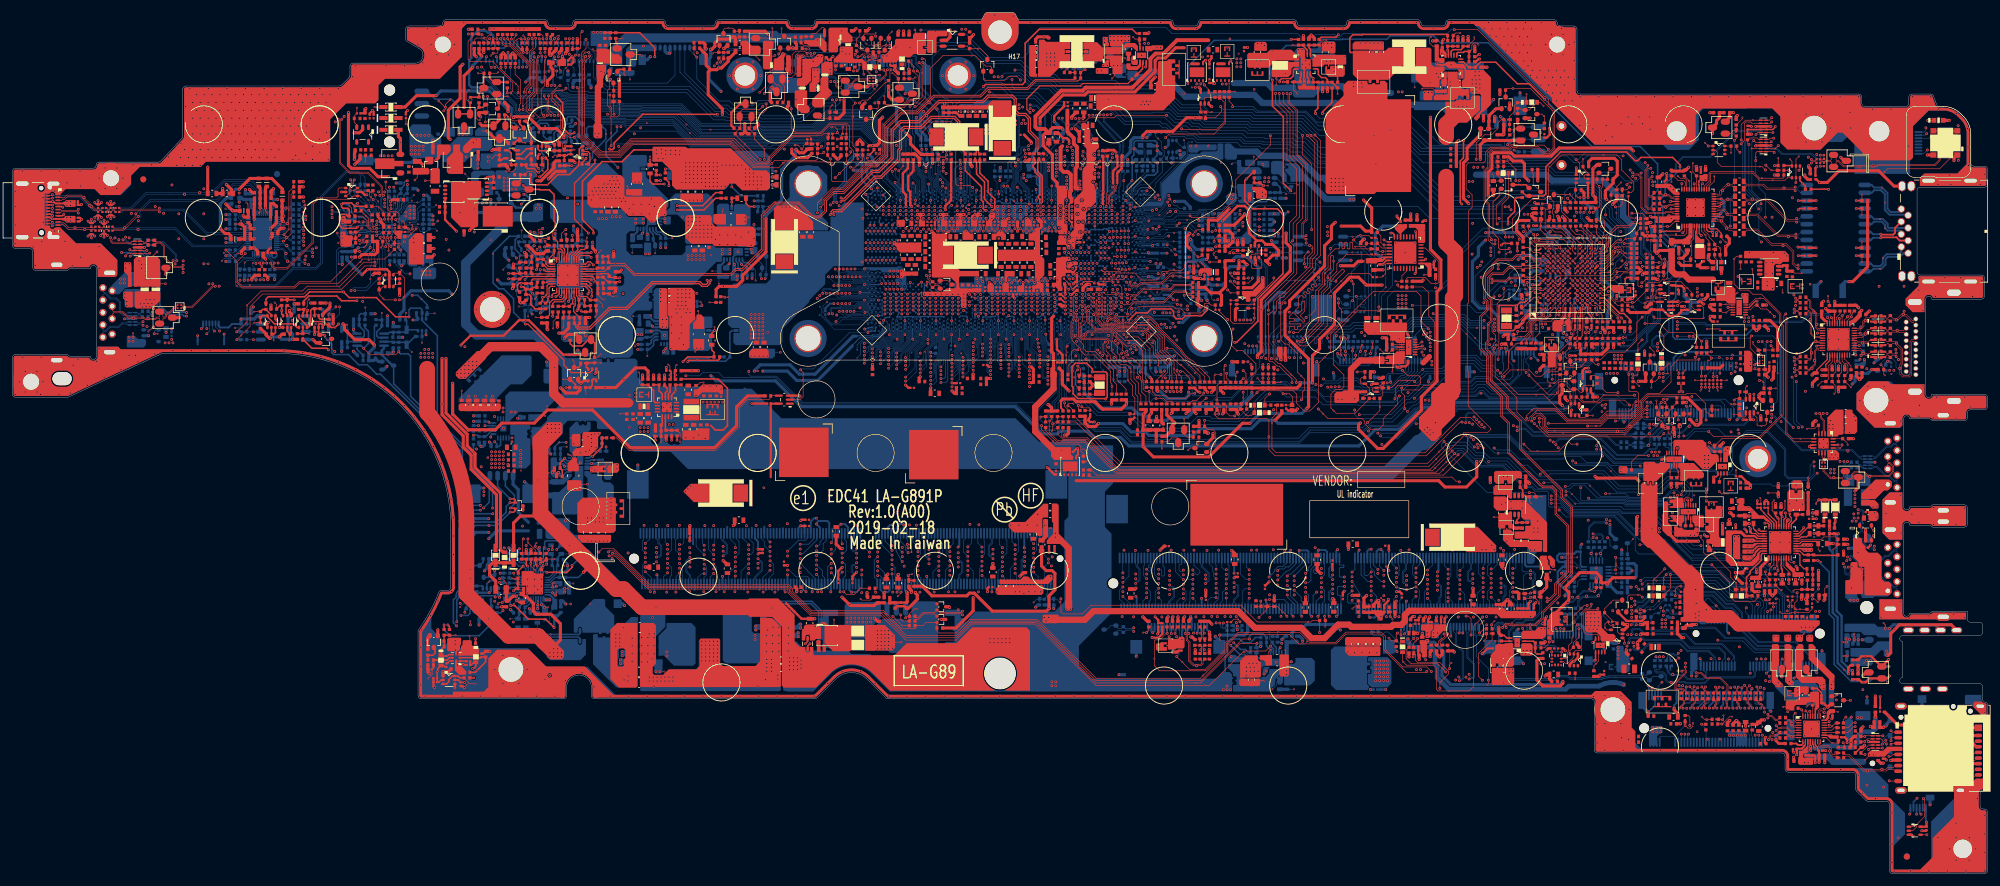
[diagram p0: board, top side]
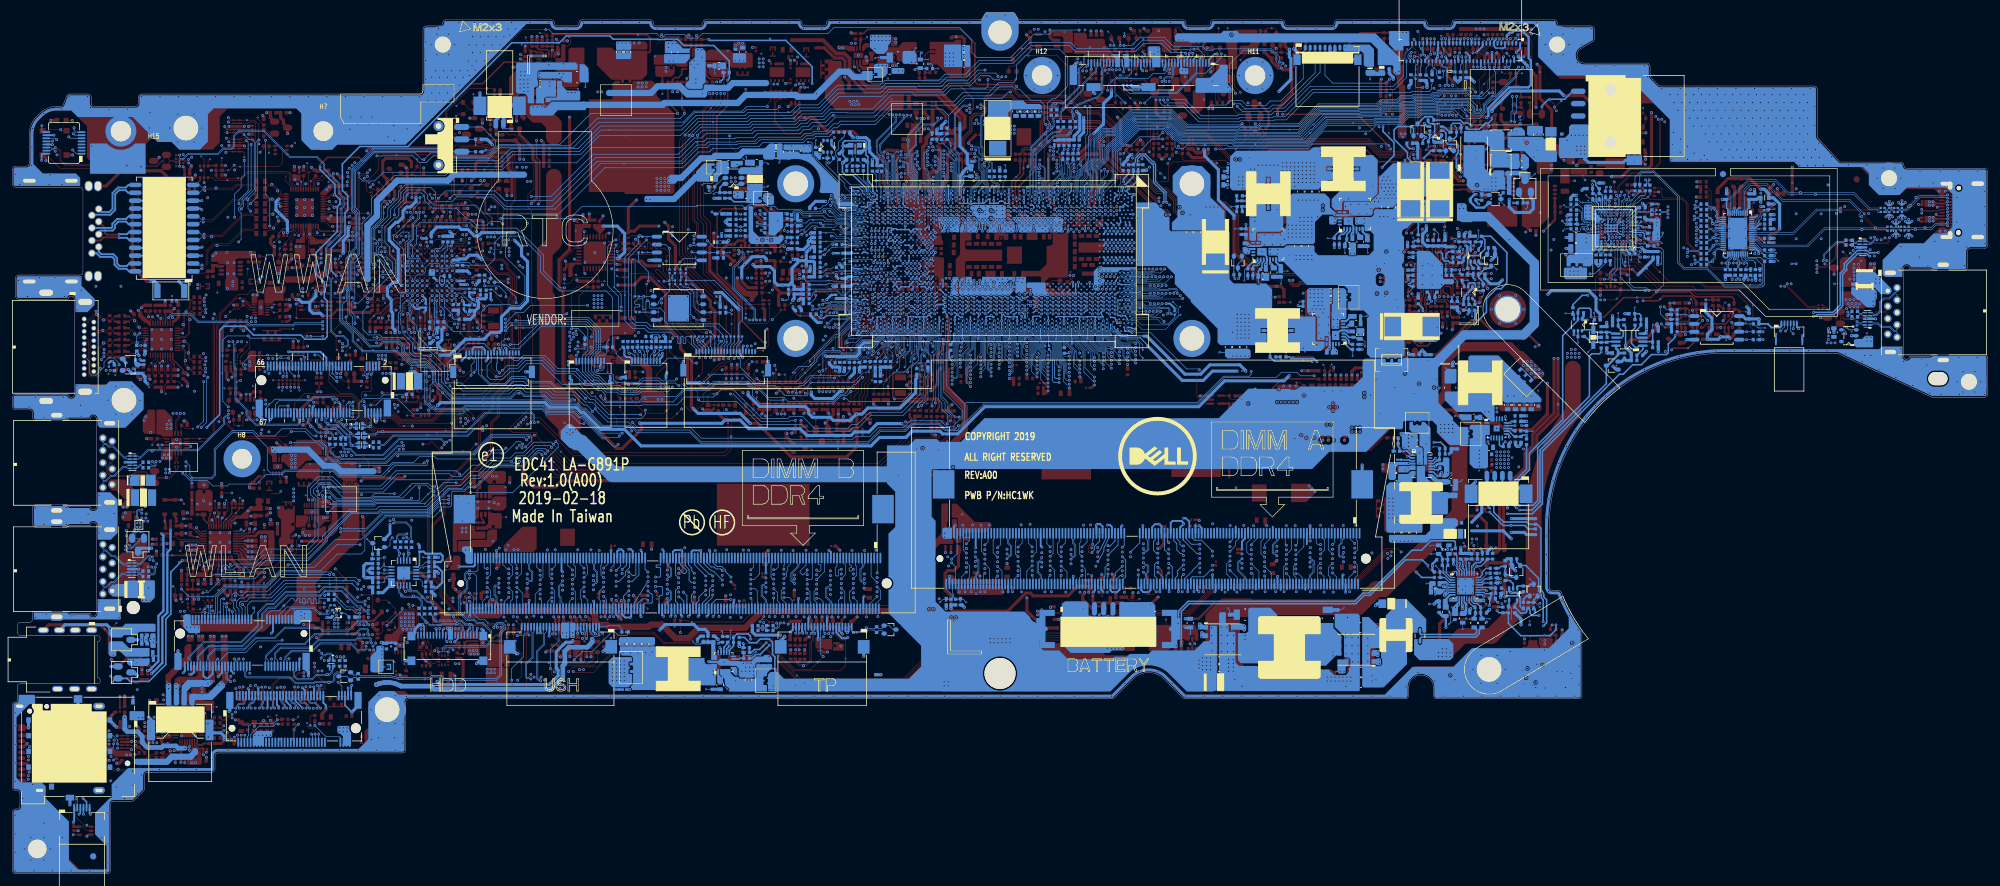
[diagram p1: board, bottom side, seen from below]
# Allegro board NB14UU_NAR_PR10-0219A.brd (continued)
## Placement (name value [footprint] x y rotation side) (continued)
RT73  0_0402_5%  [R0402_0OHM]  61.72 101.81 270 top
RT74  0_0402_5%  [R0402_0OHM]  63.38 104.47 180 top
RT75  0_0402_5%  [R_0402]  66.4 108.19 0 bottom
RT76  10K_0402_1%  [R_0402]  58.05 107.86 180 top
RT81  100K_0402_5%  [R_0402]  55.45 101.96 180 top
RT82  1M_0402_5%  [R_0402]  54.61 103.68 270 top
RT83  0_0402_5%  [R0402_0OHM]  55.44 102.77 90 top
RT84  0_0402_5%  [R_0402]  56.34 107.16 180 top
RT85  0_0402_5%  [R_0402]  58.11 105.56 90 top
RT86  100K_0201_5%  [R_0201]  63.38 103.71 180 top
RT87  0_0402_5%  [R_0402]  58.22 111.3 270 top
RT88  0_0402_5%  [R_0402]  57.46 111.3 270 top
RT89  0_0402_5%  [R0402_0OHM]  56.95 111.28 270 bottom
RT90  0_0402_5%  [R0402_0OHM]  56.19 111.28 270 bottom
RT92  0_0402_5%  [R_0402]  55.3 111.28 270 bottom
RT93  0_0402_5%  [R_0402]  54.54 111.28 270 bottom
RT95  100K_0402_5%  [R_0402]  54.23 107.28 90 bottom
RT96  100K_0402_5%  [R_0402]  54.23 106.54 270 bottom
RT97  0_0402_5%  [R_0402]  67.32 106.5 180 bottom
RT98  0_0402_5%  [R_0402]  66.4 105.74 0 bottom
RT99  0_0402_5%  [R0402_0OHM]  66.4 104.98 0 bottom
RT100  15K_0402_0.1%  [R_0402]  55.32 105.39 180 top
RT101  100K_0402_5%  [R_0402]  59.95 103.59 90 top
RT103  0_0402_5%  [R_0402]  66.4 108.95 0 bottom
RT104  0_0402_5%  [R0402_0OHM]  62.74 108.99 90 bottom
RT105  0_0402_5%  [R0402_0OHM]  63.76 108.99 90 bottom
RT106  10K_0402_5%  [R_0402]  55.32 106.27 180 top
RT107  10K_0402_5%  [R_0402]  59.83 102.18 180 top
RT108  0_0402_5%  [R0402_0OHM]  61.72 109.37 90 bottom
RT109  0_0402_5%  [R0402_0OHM]  60.9 109.37 90 bottom
RT110  0_0402_5%  [R_0402]  66.4 104.21 0 bottom
RT111  100K_0402_5%  [R_0402]  56.14 122.06 180 top
RT120  0_0402_5%  [R0402_0OHM]  22.87 101.61 180 top
RT121  0_0402_5%  [R0402_0OHM]  22.87 102.37 180 top
RT122  0_0402_5%  [R0402_0OHM]  21.95 101.61 0 bottom
RT123  0_0402_5%  [R0402_0OHM]  21.95 102.37 0 bottom
RT130  100K_0402_5%  [R_0402]  40.76 97.62 270 top
RT131  100K_0402_5%  [R_0402]  39.87 97.62 270 top
RT132  0_0402_5%  [R0402_0OHM]  38.29 97.62 270 bottom
RT133  0_0402_5%  [R0402_0OHM]  36.76 97.62 270 bottom
RT135  4.7K_0402_5%  [R_0402]  45.45 111.83 0 top
RT136  4.7K_0402_5%  [R_0402]  45.45 111.01 0 top
RT137  4.7K_0402_5%  [R_0402]  45.45 109.36 0 top
RT138  4.7K_0402_5%  [R_0402]  45.45 110.18 0 top
RT139  4.7K_0402_5%  [R_0402]  36.01 105.74 180 bottom
RT140  4.7K_0402_5%  [R_0402]  36.01 106.5 180 bottom
RT141  4.7K_0402_5%  [R_0402]  36.01 104.98 180 bottom
RT142  4.7K_0402_5%  [R_0402]  36.01 104.21 180 bottom
RT190  2.2_0201_1%  [R_0201]  16.17 103.92 180 top
RT191  2.2_0201_1%  [R_0201]  16.17 104.56 180 top
RT192  2.2_0201_1%  [R_0201]  16.17 103.92 180 bottom
RT193  2.2_0201_1%  [R_0201]  16.17 104.56 180 bottom
RT194  2.2_0201_1%  [R_0201]  17.25 107.58 180 bottom
RT195  2.2_0201_1%  [R_0201]  17.25 106.95 180 bottom
RT196  2.2_0201_1%  [R_0201]  17.25 107.58 180 top
RT197  2.2_0201_1%  [R_0201]  17.25 106.95 180 top
RT219  221K_0201_1%  [R_0201]  12.76 103.93 270 top
RT220  221K_0201_1%  [R_0201]  12.76 104.56 90 top
RT221  221K_0201_1%  [R_0201]  13.84 107.58 90 bottom
RT222  221K_0201_1%  [R_0201]  13.84 106.96 270 bottom
RT246  10K_0402_5%  [R_0402]  35.1 102.69 0 bottom
RT300  4.99K_0402_1%  [R_0402]  36.01 99.88 180 bottom
RT303  0_0402_5%  [R0402_0OHM]  35.43 108.23 270 bottom
RT304  4.7K_0402_5%  [R_0402]  41.59 97.62 270 bottom
RT305  4.7K_0402_5%  [R_0402]  42.35 97.62 270 bottom
RT308  4.7K_0402_5%  [R_0402]  36.01 98.96 180 bottom
RT339  0_0402_5%  [R_0402]  60.84 103.59 90 top
RT377  43K_0402_1%  [R_0402]  59.96 106.53 180 top
RT378  10K_0402_5%  [R_0402]  57.26 102.18 0 top
RT379  10K_0402_5%  [R_0402]  57.26 103.01 0 top
RT380  0_0402_5%  [R0402_0OHM]  35.1 100.8 0 bottom
RT393  100K_0402_5%  [R_0402]  56.95 122.04 90 top
RT397  0_0603_5%  [R_0603]  31.55 109.93 0 top
RT398  0_0603_5%  [R0603_0OHM]  35.36 109.93 180 top
RT399  0_0402_5%  [R_0402]  56.18 116.1 180 top
RT414  2M_0402_5%  [R_0402]  39.05 97.62 270 bottom
RT415  2M_0402_5%  [R_0402]  37.52 97.62 270 bottom
RT420  0_0402_5%  [R_0402]  56.27 116.98 180 top
RT482  0_0402_5%  [R_0402]  54.03 99.63 90 bottom
RT483  0_0402_5%  [R_0402]  53.27 99.63 90 bottom
RT488  221K_0201_1%  [R_0201]  12.76 103.93 270 bottom
RT489  221K_0201_1%  [R_0201]  12.76 104.56 90 bottom
RT490  221K_0201_1%  [R_0201]  13.84 106.96 270 top
RT491  221K_0201_1%  [R_0201]  13.84 107.58 90 top
RV1  4.7K_0402_5%  [R_0402]  136.89 136.22 0 top
RV2  4.7K_0402_5%  [R_0402]  139.96 132.79 180 top
RV3  100K_0402_5%  [R_0402]  154.62 134.26 270 top
RV4  270K_0402_5%  [R_0402]  128.2 135.28 270 top
RV5  47K_0402_5%  [R_0402]  127.39 135.2 180 top
RV6  47K_0402_5%  [R_0402]  116.61 136.15 270 top
RV7  100K_0402_5%  [R_0402]  140.13 131.39 0 top
RV8  10K_0402_5%  [R_0402]  141.52 128.18 270 top
RV10  2.2K_0402_5%  [R_0402]  296.77 90.94 90 top
RV55  20K_0402_5%  [R_0402]  298.97 84.45 90 bottom
RV98  2.2K_0402_5%  [R_0402]  118.98 119.58 0 top
RV99  2.2K_0402_5%  [R_0402]  117.66 119.58 180 top
RV175  4.7K_0402_5%  [R_0402]  294.95 80.52 90 top
RV207  4.7K_0402_5%  [R_0402]  294.95 78.61 90 top
RV208  4.7K_0402_5%  [R_0402]  293.51 90.89 90 top
RV209  4.7K_0402_5%  [R_0402]  295.99 90.93 90 top
RV300  4.7K_0402_5%  [R_0402]  292.92 78.61 90 top
RV302  4.7K_0402_5%  [R_0402]  297.62 84.45 90 bottom
RV303  4.02K_0402_1%  [R_0402]  296.98 81.43 270 top
RV304  4.7K_0402_5%  [R_0402]  293.94 78.61 90 top
RV305  4.7K_0402_5%  [R_0402]  293.94 80.52 90 top
RV307  4.7K_0402_5%  [R_0402]  295.97 80.52 90 top
RV311  100K_0402_5%  [R_0402]  111.01 133.42 180 top
RV319  1K_0402_5%  [R_0402]  111.01 134.31 180 top
RV323  0_0402_5%  [R0402_0OHM]  114.87 131.82 90 top
RV324  0_0402_5%  [R_0402]  114.1 131.82 90 top
RV326  100K_0402_5%  [R_0402]  115.63 131.82 90 top
RV400  0_0402_5%  [R0402_0OHM]  117.44 136.15 270 top
RV623  100K_0402_5%  [R_0402]  144.76 132.23 270 top
RV624  1M_0402_5%  [R_0402]  97.14 125.68 0 top
RV625  47K_0402_5%  [R_0402]  99.7 129.99 180 top
RV626  200K_0402_5%  [R_0402]  95.69 135.91 270 top
RV627  10K_0402_5%  [R_0402]  97.47 135 90 top
RV628  0_0402_5%  [R0402_0OHM]  97.14 124.79 0 top
RV629  200K_0402_5%  [R_0402]  144.84 128.46 90 top
RV630  47K_0402_5%  [R_0402]  140.85 124.61 180 top
RV631  10K_0402_5%  [R_0402]  143.11 128.47 0 top
RV654  150_0402_5%  [R_0402]  303.33 86.26 270 top
RV683  150_0402_5%  [R_0402]  303.33 90.19 270 top
RV684  150_0402_5%  [R_0402]  303.33 87.25 90 top
RV685  150_0402_5%  [R_0402]  303.33 83.44 90 top
RV686  5.6_0402_1%  [R_0402]  300.91 89.13 0 top
RV687  5.6_0402_1%  [R_0402]  300.91 90.15 0 top
RV688  5.6_0402_1%  [R_0402]  300.91 88.24 0 top
RV689  5.6_0402_1%  [R_0402]  300.91 87.23 0 top
RV690  5.6_0402_1%  [R_0402]  300.91 85.32 0 top
RV691  5.6_0402_1%  [R_0402]  300.91 86.34 0 top
RV692  8.2_0402_1%  [R_0402]  300.91 84.43 0 top
RV693  8.2_0402_1%  [R_0402]  300.91 83.42 0 top
RV732  0_0603_5%  [R_0603]  118.2 132.9 180 top
RV733  0_0603_5%  [R0603_0OHM]  118.2 134.17 180 top
RV734  4.7K_0402_5%  [R_0402]  295.97 78.61 90 top
RV735  2.2K_0402_5%  [R_0402]  297.53 90.94 90 top
RV736  10K_0402_5%  [R_0402]  302.27 81.48 180 top
RV737  100K_0402_5%  [R_0402]  295.22 90.93 90 top
RV802  1M_0402_5%  [R_0402]  127.58 133.4 180 top
RZ8  2.2K_0402_5%  [R_0402]  231.82 36 90 top
RZ9  2.2K_0402_5%  [R_0402]  229.16 36.03 90 top
RZ10  100K_0402_5%  [R_0402]  225.59 35.66 90 top
RZ18  4.7K_0402_5%  [R_0402]  193.35 35.58 270 top
RZ19  4.7K_0402_5%  [R_0402]  191.07 35.58 270 top
RZ20  2.2K_0402_5%  [R_0402]  199.53 39.32 180 bottom
RZ21  2.2K_0402_5%  [R_0402]  199.53 40.08 180 bottom
RZ22  0_0402_5%  [R_0402]  192.59 34.67 90 top
RZ23  0_0402_5%  [R_0402]  191.83 34.67 90 top
RZ25  150_0402_5%  [R_0402]  245.47 113.8 0 top
RZ26  0_0402_5%  [R0402_0OHM]  197.11 39.32 180 bottom
RZ28  330_0402_5%  [R_0402]  243.89 109.27 90 top
RZ29  0_0402_5%  [R0402_0OHM]  197.11 40.08 180 bottom
RZ32  1K_0402_1%  [R_0402]  277.6 117.59 0 top
RZ38  100K_0402_5%  [R_0402]  268.36 72.08 180 top
RZ40  100K_0402_5%  [R_0402]  282.71 91.89 180 top
RZ43  10K_0402_5%  [R_0402]  261.54 82.5 180 top
RZ56  0_0201_5%  [R0201_0OHM]  283.84 44.28 270 top
RZ58  49.9_0201_1%  [R_0201]  219.76 96.4 0 top
RZ59  49.9_0201_1%  [R_0201]  219.57 100.09 0 top
RZ60  49.9_0201_1%  [R_0201]  219.57 102.75 0 top
RZ61  0_0402_5%  [R0402_0OHM]  219.57 100.98 0 top
RZ63  33_0402_5%  [R_0402]  219.57 101.86 0 top
RZ64  0_0402_5%  [R0402_0OHM]  226.56 86.45 270 bottom
RZ69  10K_0402_5%  [R_0402]  219.57 103.64 0 top
RZ70  0_0402_5%  [R_0402]  268.12 75.37 180 top
RZ71  0_0402_5%  [R_0402]  265.55 75.37 0 top
RZ76  0_0402_5%  [R_0402]  269.15 79.25 90 top
RZ77  0_0402_5%  [R_0402]  269.91 79.25 90 top
RZ78  0_0201_5%  [R_0201]  286.76 44.78 270 top
RZ79  0_0201_5%  [R_0201]  287.52 44.78 270 top
RZ80  0_0201_5%  [R_0201]  290.7 43.65 270 top
RZ87  0_0402_5%  [R0402_0OHM]  219.69 39.06 0 bottom
RZ89  0_0402_5%  [R_0402]  225.86 105.62 270 top
RZ96  0.01_1206_1%  [R_1206-NPM]  264.6 64.4 270 top
RZ102  0.01_1206_1%  [R_1206-NPM]  239.83 34.95 270 top
RZ112  0_0402_5%  [R0402_0OHM]  225.23 94.83 90 top
RZ114  0_0402_5%  [R0402_0OHM]  226.35 35.66 90 top
RZ116  10K_0402_5%  [R_0402]  191.83 40.79 270 top
RZ117  10K_0402_5%  [R_0402]  192.59 40.79 270 top
RZ119  0_0402_5%  [R_0402]  168.57 66.25 90 top
RZ120  0_0402_5%  [R0402_0OHM]  173.92 65.24 180 top
RZ128  0_0201_5%  [R_0201]  272.83 79.74 270 top
RZ129  0_0201_5%  [R_0201]  274.1 79.74 270 top
RZ130  0_0201_5%  [R_0201]  275.37 79.74 270 top
RZ132  10K_0402_5%  [R_0402]  263.83 79.58 0 top
RZ133  100K_0402_5%  [R_0402]  263.63 83.83 0 top
RZ148  0_0402_5%  [R_0402]  246.9 36.48 180 top
RZ151  0_0603_5%  [R_0603]  193.23 133.17 0 top
RZ320  0_0402_5%  [R_0402]  194.24 125.47 90 top
RZ326  0_0402_5%  [R_0402]  255.41 77.48 180 bottom
RZ334  51_0402_5%  [R_0402]  297.67 20.39 0 top
RZ335  15K_0402_5%  [R_0402]  298.59 23.06 180 top
RZ345  0_0402_5%  [R0402_0OHM]  274.95 69.11 270 top
RZ346  0_0402_5%  [R0402_0OHM]  191.83 37.82 270 top
RZ347  0_0402_5%  [R0402_0OHM]  192.59 37.82 270 top
RZ350  0_0201_5%  [R0201_0OHM]  292.6 115.54 90 top
RZ351  0_0201_5%  [R0201_0OHM]  292.6 114.92 270 top
RZ361  470_0402_1%  [R_0402]  243.09 101.86 180 top
RZ362  10K_0402_5%  [R_0402]  226.12 95.74 270 top
RZ372  0_0201_5%  [R_0201]  274.74 79.74 270 top
RZ373  0_0201_5%  [R_0201]  276.01 79.74 270 top
RZ374  0_0201_5%  [R_0201]  273.47 79.74 270 top
RZ377  100K_0402_5%  [R_0402]  263.76 41.48 0 bottom
RZ379  20K_0402_5%  [R_0402]  269.77 76.13 180 top
RZ380  0_0402_5%  [R0402_0OHM]  278.44 120.14 270 top
RZ388  0_0402_5%  [R0402_0OHM]  132.98 123.07 180 top
RZ400  10K_0402_5%  [R_0402]  264.02 94.31 0 top
RZ401  1K_0402_5%  [R_0402]  264.02 95.07 0 top
RZ518  100K_0402_5%  [R_0402]  270.95 73.4 90 top
RZ603  10K_0402_5%  [R_0402]  261.53 65.28 180 top
RZ752  10K_0402_5%  [R_0402]  289.87 42.73 90 top
RZ827  0_0201_5%  [R_0201]  261.04 110.09 270 top
RZ1381  22_0402_5%  [R_0402]  267.98 44.27 180 bottom
RZ1383  22_0402_5%  [R_0402]  267.98 45.16 180 bottom
RZ1385  0_0201_5%  [R0201_0OHM]  267.06 43.38 0 bottom
RZ1388  0_0201_5%  [R_0201]  292.01 115.45 180 top
RZ1389  0_0201_5%  [R_0201]  292.01 114.88 180 top
RZ1390  0_0402_5%  [R_0402]  276.46 122.98 0 top
RZ1391  0_0402_5%  [R_0402]  275.73 122.98 180 top
RZ1392  100K_0402_5%  [R_0402]  280.26 118.6 90 top
RZ1393  0_0402_5%  [R0402_0OHM]  274.51 74.95 270 top
RZ1394  0_0402_5%  [R0402_0OHM]  279.96 77.86 180 top
RZ1395  0_0402_5%  [R0402_0OHM]  278.99 74.23 90 top
RZ1396  0_0402_5%  [R_0402]  278.99 75.88 90 top
RZ1397  100K_0402_5%  [R_0402]  282.41 73.35 0 top
RZ1398  0_0402_5%  [R0402_0OHM]  283.83 78.43 180 top
RZ1399  10K_0402_5%  [R_0402]  283.83 77.67 180 top
RZ1400  100K_0402_5%  [R_0402]  272.91 81.73 0 top
RZ1401  0_0402_5%  [R0402_0OHM]  283.03 81.48 180 top
RZ1402  0_0402_5%  [R0402_0OHM]  282.11 84.62 0 top
RZ1403  0_0402_5%  [R_0402]  284.55 82.79 270 top
RZ1404  0_0402_5%  [R_0402]  285.14 83.7 90 top
RZ1405  10K_0402_5%  [R_0402]  284.37 83.7 90 top
RZ1406  2.2K_0402_5%  [R_0402]  282.11 80.66 0 top
RZ1407  0_0402_5%  [R_0402]  224.44 94.83 90 top
RZ1408  0_0402_5%  [R0402_0OHM]  218.01 98.97 0 top
RZ1409  0_0402_5%  [R_0402]  224.98 105.62 270 top
RZ1410  0_0402_5%  [R_0402]  229.88 96.78 180 top
RZ1411  0_0402_5%  [R0402_0OHM]  239.02 38.81 180 top
RZ1413  330K_0402_5%  [R_0402]  240.88 114.32 180 top
RZ1414  0_0402_5%  [R_0402]  239.02 39.57 180 top
RZ1415  0_0402_5%  [R0402_0OHM]  239.96 115.09 0 top
RZ1416  0_0402_5%  [R_0402]  196.53 125.47 90 top
RZ1417  0_0402_5%  [R_0402]  195.77 125.47 90 top
RZ1418  0_0402_5%  [R_0402]  173.92 64.42 180 top
RZ1419  0_0402_5%  [R_0402]  172.99 67.46 270 top
RZ1420  0_0402_5%  [R0402_0OHM]  192.72 122.17 90 top
RZ1422  100K_0402_5%  [R_0402]  191.96 123.09 270 top
RZ1423  0_0402_5%  [R0402_0OHM]  195 125.47 90 top
RZ1450  0_0402_5%  [R_0402]  273.68 84.14 90 top
RZ1471  0_0201_5%  [R_0201]  258.42 40.71 180 top
RZ1472  100K_0402_5%  [R_0402]  260.1 40.46 180 top
RZ1473  0_0402_5%  [R_0402]  223.53 36.7 90 top
RZ1474  100K_0402_5%  [R_0402]  257.18 42.17 180 top
RZ1475  0_0201_5%  [R0201_0OHM]  196.82 40.65 180 top
RZ1476  0_0402_5%  [R0402_0OHM]  265.23 70.32 270 bottom
RZ1477  0_0402_5%  [R0402_0OHM]  266 70.32 270 bottom
RZ1480  0_0402_5%  [R_0402]  272.03 84.14 90 top
RZ1481  0_0402_5%  [R_0402]  272.85 84.14 90 top
RZ1482  1M_0402_5%  [R_0402]  240.88 115.85 180 top
RZ1483  20K_0402_5%  [R_0402]  269.77 76.91 180 top
RZ1484  0_0603_5%  [R0603_0OHM]  130.84 126.95 180 top
RZ1485  0_0603_5%  [R0603_0OHM]  127.59 126.26 90 top
RZ1486  0_0603_5%  [R_0603-NPM]  131.22 128.37 90 top
SW1  SS3-CMFTQR9_3P  [SW_SS3-CMFTQR9_3P]  246.47 120.68 270 bottom
SW3  SKRBAAE010_4P  [SW_SKRBAAE010_4P]  314.15 116.15 180 top
T1  PAD~D  [TPC12]  154.11 106.25 0 top
T2  PAD~D  [TPC12]  154 107.63 0 top
T12  PAD~D  [TPC12]  175.13 92.66 0 top
T16  PAD~D  [TPC12]  136.46 84.66 180 bottom
T17  PAD~D  [TPC12]  136.44 83.35 180 bottom
T18  PAD~D  [TPC12]  184.81 84.62 180 bottom
T19  PAD~D  [TPC12]  190.24 82.75 180 bottom
T20  PAD~D  [TPC12]  168.75 85.63 180 bottom
T21  PAD~D  [TPC12]  171.04 99.91 270 top
T50  PAD~D  [TPC12]  143.01 44.84 270 top
T51  PAD~D  [TPC12]  145.21 51.97 270 top
T54  PAD~D  [TPC12]  221.07 44.54 0 top
T55  PAD~D  [TPC12]  221.86 49.67 0 top
T88  PAD~D  [TPC12]  271.05 113.43 0 top
T89  PAD~D  [TPC12]  269.01 112.76 0 top
T315  PAD~D  [TPC12]  274.89 112.72 0 top
T341  PAD~D  [TPC12]  248.47 95.45 180 bottom
T348  PAD~D  [TPC12]  253.26 95.43 180 bottom
T350  PAD~D  [TPC12]  145.25 84.19 180 bottom
T351  PAD~D  [TPC12]  146.36 83.51 180 bottom
T353  PAD~D  [TPC12]  146.83 93.89 0 top
T354  PAD~D  [TPC12]  147.77 91.98 0 top
T355  PAD~D  [TPC12]  158.68 114.5 180 bottom
T360  PAD~D  [TPC12]  190.55 118.23 180 bottom
T361  PAD~D  [TPC12]  170.59 85.68 180 bottom
T363  PAD~D  [TPC12]  170.47 84.25 180 bottom
T364  PAD~D  [TPC12]  130.41 91.63 180 bottom
T365  PAD~D  [TPC12]  130.36 90.31 180 bottom
T368  PAD~D  [TPC12]  147.57 95.06 0 top
T369  PAD~D  [TPC12]  146.26 95.12 0 top
T371  PAD~D  [TPC12]  159.49 112.57 0 top
T372  PAD~D  [TPC12]  164.13 95.67 0 top
T373  PAD~D  [TPC12]  159.3 110.35 0 top
T374  PAD~D  [TPC12]  162.36 95.65 0 top
T375  PAD~D  [TPC12]  175.76 84.99 180 bottom
T376  PAD~D  [TPC12]  174.44 85.41 180 bottom
T377  PAD~D  [TPC12]  173.79 84.11 180 bottom
T378  PAD~D  [TPC12]  178.06 95.15 0 top
T379  PAD~D  [TPC12]  177.6 93.93 0 top
T380  PAD~D  [TPC12]  173.02 85.22 180 bottom
T381  PAD~D  [TPC12]  185.1 82.12 0 top
T383  PAD~D  [TPC12]  183.5 84.58 180 bottom
T384  PAD~D  [TPC12]  183.74 82.12 0 top
T385  PAD~D  [TPC12]  174.94 81.85 180 bottom
T388  PAD~D  [TPC12]  176.32 93.91 0 top
T389  PAD~D  [TPC12]  178.1 91.3 0 top
T395  PAD~D  [TPC12]  174 82.73 180 bottom
T396  PAD~D  [TPC12]  175.08 83.42 180 bottom
T397  PAD~D  [TPC12]  176.14 82.66 180 bottom
T398  PAD~D  [TPC12]  176.18 81.36 180 bottom
T399  PAD~D  [TPC12]  186.47 104.07 180 bottom
T400  PAD~D  [TPC12]  185.35 103.32 180 bottom
T401  PAD~D  [TPC12]  177.44 96.51 0 top
T402  PAD~D  [TPC12]  175.94 97.52 0 top
T406  PAD~D  [TPC12]  184.97 99.26 180 bottom
T407  PAD~D  [TPC12]  177.92 99.77 0 top
T415  PAD~D  [TPC12]  176.2 95.72 0 top
T416  PAD~D  [TPC12]  178.05 97.84 0 top
T418  PAD~D  [TPC12]  302.38 113.42 0 top
T419  PAD~D  [TPC12]  154.91 93.16 0 top
T421  PAD~D  [TPC12]  280.93 117.19 0 top
T422  PAD~D  [TPC12]  284.75 117.18 0 top
T423  PAD~D  [TPC12]  193.02 80.97 180 bottom
TL1  MHPC_NS692417  [MHPC_NS692417_24P]  289.84 97.34 90 bottom
UA1  -  [ALC3204-CG_MQFN40_5X5]  283.73 50.99 90 top
UC1  WHL-U42_BGA1528  [WHL-U42_BGA_1528P-T]  138.21 110.31 270 bottom
UC5  -  [W25Q256JVEIQ_WSON8_8X6]  215.46 93.29 270 bottom
UC6  -  [W25Q128JVSIQ_SO8]  214.95 102.94 270 bottom
UC7  MC74VHC1G08DFT2G SC70  [TC7SH08FU_SSOP5]  220.36 77.87 90 top
UC9  MC74VHC1G32DFT2G_SC70-5~D  [MC74VHC1G32DFT2G_SC70-5]  198.69 92.02 270 top
UD1  -  [74AUP1G07GW_TSSOP5]  125.58 75.96 90 top
UE1  MEC5105_WFBGA169_11X11  [MEC5105_WFBGA_169P]  246.85 91.41 90 top
UE3  MC74VHC1G08DFT2G SC70  [TC7SH08FU_SSOP5]  272.41 91.12 90 top
UE4  -  [74AUP1G07GW_TSSOP5]  267.91 91.12 90 top
UE5  MC74VHC1G08DFT2G SC70  [TC7SH08FU_SSOP5]  253.66 78.24 0 top
UI1  -  [SY6288D20AAC_SOT23-5]  21.21 85.99 90 bottom
UI2  -  [SY6288D20AAC_SOT23-5]  298.38 53.87 0 top
UI3  -  [SLGC55544CVTR_TQFN16_3X3]  293.29 71.09 180 top
UL1  WGI219LM-SLKJ3-A0_QFN48_6X6~D  [WGI219LM-SLKJ3-A0_QFN48_6X6]  269.66 104.69 90 top
UN7  PI3EQX6741STZDEX_TQFN20_4X4  [PI3EQX6741STZDEX_TQFN20_4X4-S]  254.84 50.56 270 bottom
UR1  RTS5242-GR_QFN32_4X4  [RTS5242-GR_QFN32_4X4-S]  288.56 24.78 0 top
UT5  SN1804044ZBHR_NFBGA96  [TPS65982_BGA_96P]  57.83 101.8 0 bottom
UT6  GD25Q80CSIGR_SO8  [W25Q80DVSSIG_SO8]  47.37 90.12 270 bottom
UT7  AP2112K-3.3TRG1_SOT23-5  [AP2112K-3P3TRG1_SOT23-5]  57.52 120.64 180 top
UT8  AP2204R-5.0TRG1_SOT89-3  [AP2204R-5P0TRG1_SOT89-3]  62.67 113.25 90 top
UT9  -  [PS8802QFN52GTRA1_QFN52_6P5X4P5]  38.81 106.75 270 bottom
UV2  -  [AP2330W-7_SC59-3]  298.83 82.27 270 bottom
UV21  -  [PS8407ATQFN40GTR2A1_TQFN40_5X5]  292.4 88.16 270 top
UV24  -  [G524B1T11U_SOT23-5]  150.32 135.64 270 top
UZ3  EM5209VF_SON14_2X3  [TPS22966DPUR_SON14_2X3-S]  226.57 83.9 90 top
UZ5  EM5209VF_SON14_2X3  [TPS22966DPUR_SON14_2X3-S]  271.9 59.52 180 top
UZ8  AOZ1336_DFN8_2X2  [AOZ1336_DFN8_2X2-S]  276.97 66.9 180 top
UZ10  MC74VHC1G08DFT2G SC70  [TC7SH08FU_SSOP5]  306.32 7.58 270 top
UZ12  ST33HTPH2032AHC1_VQFN32_5X5  [ST33HTPH2E32AHB4_VQFN32_5X5]  227.52 98.61 180 top
UZ19  EM5201V DFN3X3  [TPS22961DNYR_WSON8]  190.37 128.18 0 top
UZ21  EM5201V DFN3X3  [TPS22961DNYR_WSON8]  194.56 128.18 0 top
UZ23  AOZ1336_DFN8_2X2  [AOZ1336_DFN8_2X2-S]  244.16 36.57 90 top
UZ27  EM5201V DFN3X3  [TPS22961DNYR_WSON8]  169.88 64.46 0 top
UZ35  MC74VHC1G08DFT2G SC70  [TC7SH08FU_SSOP5]  191.94 124.47 0 top
UZ41  MC74VHC1G08DFT2G SC70  [TC7SH08FU_SSOP5]  266.19 95.08 270 top
UZ43  EM5209VF_SON14_2X3  [TPS22966DPUR_SON14_2X3-S]  279.95 90.31 90 top
UZ47  EM5209VF_DFN14_3X2  [TPS22966DPUR_SON14_2X3]  269.61 68 180 top
UZ51  -  [SN74LVC1G3157DCKR_SC70-6]  281.29 76.68 180 top
UZ52  SN74AUP1T97YZPR_DSBGA6~D  [SN74AUP1T97YZPR_DSBGA_6P]  282.21 83.44 0 top
UZ53  AOZ1336_DFN8_2X2  [AOZ1336_DFN8_2X2-S]  257.22 38 180 top
UZ54  MC74VHC1G32DFT2G_SC70-5~D  [MC74VHC1G32DFT2G_SC70-5]  259.14 38.75 90 top
YC1  24MHZ_12PF_8Y24000034  [Y_8Y24000034_4P]  182.24 117.72 0 bottom
YC2  32.768KHZ_12.5PF_9H03200042  [Y_9H03200042_2P]  175.61 77.71 90 top
YE1  32.768KHZ_9PF_X1A000141000200  [Y_X1A000141000200_2P]  241.33 88.52 90 top
YL1  25MHZ_20PF_XRCGB25M000F2P18R0  [Y_XRCGB25M000F2P18R0_4P]  276.04 98.83 180 top

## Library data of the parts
CA1-CA4 CA9 CA10 CA12 CA13 CA19 CA22-CA25 CA27 CA28 CA31 CA33 CA35 CA41 CA43-CA48 CA51-CA61 CA69 CA73 CA74 CC1479 CD76 CD77 CN95 CZ125-CZ128 = CAP NP: room: CODEC
CA5 CA6 CA62 CA72 CN78 CZ322 = CAP NP: room: CAMERA
CA7 CV1-CV6 CV11 CV13-CV17 CV632-CV634 CV651 CV652 CZ202 CZ203 CZ207 = CAP NP: room: LCD
CA8 CA29 CA76-CA78 CC24 CC25 CC67-CC70 CC76 CC78 CC80 CC83 CC85 CC86 CC96 CC100 CC102-CC104 CC195 CC1455-CC1462 CC1465 CC1467-CC1471 CC1477 CC1478 CC1480 CE14 CE30 CE31 CE63 CI51 CN89 CR15 CR22 CT22 CT74 CT326-CT329 CT634-CT637 CZ19 CZ25 CZ100 CZ102 CZ105 CZ218 = CAP NP
CA63-CA68 CE59 CE60 CI43-CI48 CL29 CL30 CR25-CR28 CT99-CT102 CT189 CT190 CV18-CV25 CZ3 CZ41 CZ57 CZ58 CZ62 CZ63 CZ83-CZ89 CZ317 CZ320 = CAP NP: room: TBT
CA75 CC1481 CV12 CV31 CV757 CZ12 CZ13 CZ27-CZ36 = CAP NP: room: WLAN
CC9 CC10 CC316 CC318-CC320 CC1452 CC1453 CC1476 CE57 CV54 CV55 = CAP NP: room: SPI ROM
CC21-CC23 CC26-CC29 CC31-CC42 CC45 CC46 CC51 CC52 CC65 CC66 CC71 CC73 CC75 CC98 CC234-CC237 CC266 CC279 CC280 CC300-CC305 CC322 CC331-CC333 CC430 CC1454 CC1463 CC1464 CE61 CN92 CV755 CZ17 CZ318 CZ319 = CAP NP: room: CPU
CC72 CD1-CD16 CD18-CD29 CD31-CD48 CD50-CD63 CD66 CD69-CD72 = CAP NP: room: MEMORY
CC77 CC95 = CAP NP: room: SOC
CC84 CZ50-CZ56 CZ75 = CAP NP: room: TPM
CC93 = CAP NP: room: EDP
CC196 CN60 CZ64 CZ66-CZ69 CZ71-CZ73 = CAP NP: room: USH
CC269 CC288 CC299 CC306-CC308 CC326 CC334 = CAP NP: room: CPU XDP
CC340 CZ200 CZ220 = P_CAP NP: room: CAMERA
CD17 CD49 = CAP WP: room: MEMORY
CD73 CD74 CI29 CI30 CV756 CZ10 CZ11 CZ18 CZ21 CZ23 CZ26 CZ198 CZ204-CZ206 CZ315 CZ316 = CAP NP: room: WWAN
CD75 CE3 CE4 CE10-CE13 CE15-CE29 CE32 CE35-CE40 CE46 CE47 CE52-CE54 CE62 CE64-CE69 CN87 CN93 CZ80 CZ81 = CAP NP: room: KBC
CE8 = CAP NP: room: SIO
CI1 CI8 CI14 = CAP WP
CI3 CI10-CI12 CI27 CI28 = CAP NP: room: USB3
CI4-CI7 = CAP NP: room: USB2
CI13 CI16 CI17 CI19 CI31 CI33 CI34 = CAP NP: room: USB1
CI32 CI103 CI104 = CAP WP: room: USB1
CI50 CT625-CT629 CZ24 = CAP NP: room: GPU
CI52 CL1-CL14 CL16-CL22 CL28 = CAP NP: room: LAN
CMOS1 = OPEN: User Part Number: PART#; room: PCH
CN1-CN17 CZ129 CZ130 = CAP NP: room: HDD
CN61-CN72 CN77 CN79-CN82 CN84 CN86 CN91 = CAP NP: room: SATA EXPRESS
CN75 CN88 CN90 CZ311-CZ314 PC103 PC133-PC140 PC143 PC145 PC146 PC202 PC203 PC206-PC214 PC216-PC219 PC221-PC227 PC315 PC318 PC319 PC330 PC420 PC425-PC428 PC530 PC666 PC689 PC690 PC692 PC693 PC738 PC739 PC1096-PC1100 PC1146 PC1147 PC1166-PC1168 PC1170 PC3008-PC3011 = P_CAP NP: room: P_1.2V
CN94 CZ321 PC3 PC102 PC111 PC112 PC114 PC119 PC125 PC126 PC128 PC141 PC142 PC204 PC205 PC302 PC304 PC312-PC314 PC317 PC320 PC333 PC337 PC410 PC507 PC508 PC514 PC517 PC604 PC622 PC655 PC662 PC663 PC667 PC670 PC671 PC678 PC691 PC719 PC725 PC726 PC736 PC743-PC750 PC752 PC753 PC755 = P_CAP NP: room: CHARGER
CR1-CR7 CR11-CR14 CR17-CR21 = CAP NP: room: RTS5242
CT44-CT48 CT610-CT612 CT614-CT618 CV26 CV27 CV300-CV314 CV653 = CAP NP: room: HDMI
CT70 CT82 CT92 = P_CAP NP: room: PD
CT71-CT73 CT75-CT78 CT80 CT81 CT83-CT91 CT93 CT94 = CAP NP: room: PD
CT103-CT119 CT122 = CAP NP: room: PS8740
CV635 = P_CAP NP: room: TOUCH
CZ20 = CAP WP: room: WWAN
CZ37-CZ40 = CAP NP: room: SIM
CZ82 = CAP NP: room: RSMRST
CZ90-CZ92 CZ309 = CAP NP: room: KBTP
CZ93 = CAP NP: room: LED
CZ101 = CAP NP: room: +1.0V_VCCST
CZ106 = CAP NP: room: +1.0V_VCCSTG
CZ109 CZ110 CZ122 CZ310 = CAP NP: room: UZ2
CZ112-CZ115 CZ216 CZ217 = CAP NP: room: UZ3
CZ116-CZ119 CZ124 = CAP NP: room: UZ4
CZ120 CZ121 CZ197 CZ305 CZ306 = CAP NP: room: UZ8
CZ303 = CAP NP: room: +VCC_SFR_OC
DA1-DA3 DA6 DA7 = L03ESDL5V0CC3-2_SOT23-3: room: CODEC
DA4 DA5 DT1-DT3 = P_1N4148WS-7-F_SOD323-2: room: PD
DA8 DC1 DC2 DE2 = RB751S40T1G_SOD523-2: room: KBC
DC4 = P_RB521CM-30T2R_SOD923-2
DE1 = P_BZV55-B5V1_SOD80C2
DE22 = P_CEST523NC5VB_SOT-523-3
DI1 DI4 DI6 DT39-DT42 DZ13 = AZ1045-04F_DFN2510P10E-10-9
DI2 DI3 DV14 DZ10 DZ11 = AZC199-02SPR7G_SOT23-3: room: USB3
DI5 = AZC199-02SPR7G_SOT23-3: room: USB1
DT4 = L30ESD24VC3-2_SOT23-3
DT5 DT6 DT9 DT10 DT13 DT14 DT17 DT18 = ESD8011MUT5G_X3DFN2-2
DV1-DV3 DZ9 = BAT54CW_SOT323-3~D: room: LCD
DV11 = RB751S40T1G_SOD523-2
DV12 = RB751S40T1G_SOD523-2: room: GPU
DV13 = L03ESDL5V0CC3-2_SOT23-3
DZ1 DZ2 = RB751S40T1G_SOD523-2: room: WLAN
DZ5 DZ6 = RB751S40T1_SOD523-2~D: room: WWAN
DZ8 = RB751S40T1_SOD523-2~D: room: USH
DZ12 = RB751S40T1G_SOD523-2: room: PD
FD1-FD4 = FIDUCIAL MARK: room: LED
FV1 FZ1-FZ5 = 1A_65V_T0603FF1000TM
H1-H4 H7 H8 H11-H18 H20-H22 H25-H30 = HOLE: room: LED
JAPS1 = ACES_7: room: CPU
JDB1 = JXT_FP241AH-006GAAM_2: room: PD
JDEG1 = JXT_FP241AH-010GAAM_1
JDIMM1 JDIMM2 = LOTES_ADDR0206-P001A_0
JEDP1 = ACES_50398-04041-001: room: LCD
JESPI = JXT_FP241AH-010GAAM_0
JFAN1 = ACES_50271-0040N-001: room: KBC
JFPBTN1 = FOX_QT510166-L010-7H
JHDMI1 = YUQIU_HD074-F19M1BR-C
JHP1 = SINGA_2SJ3095-136111F~D
JIRTS1 = ACES_6
JKBTP1 = HRS_TF31-20S-0P5SH-800_0
JLED1 = HRS_TF31-6S-0P5SH_0
JLOM1 = SINGA_2RJ3081-1C8211F
JNGFF1 = LOTES_APCI0128-P005A_3
JNGFF2 = BELLW_7
JNGFF3 = LOTES_APCI0079-P005A_1
JRTC1 = TYCO_0
JSATA1 = FOX_GS12206-10100-7H
JSD1 = T-SOL_2
JSIM1 = JAE_SF51S006V4DR1000Q_0
JSPI1 = ACES_50506-02041-P01
JSPK1 = ACES_50278-00401-001: room: CODEC
JTAG1 = OPEN: User Part Number: PART#; room: KBC
JUSB1-JUSB3 = C-K_26230A-8K1A-02~D
JUSBC1 = JAE_DX07SD24JJ2R1300~D_1
JUSH1 = HRS_TF31C-26S-0P5SH-800
JXDP1 = JXT_FP270H-061G1AM
LA5-LA16 = L: room: CODEC
LC1-LC3 LC6-LC12 = L: room: SOC
LC4 LC5 LI12 LI13 LZ3 LZ4 = L
LED3 = LTW-C193DC-C_WHITE: room: LED
LGA1 = LNG2DMTR_LGA12_2: room: HDD
LI3 LI4 LI7 LZ1 = DLM0NSN900HY2D_4P
LI8 LI9 = MCM1012B900F06BP_4P
LI16 LI17 = HCM1012GH900BP_4P
LL1 = L: room: LAN
LT11 = L: room: CRT
LT601-LT605 = L: room: GPU
LV1 = L: room: LCD
LV3 LV6 LV9 LV12 = DLW21SN900HQ2L_0805_4P~D: room: HDMI
PBATT1 = P_DEREN_1
PC1 PC5 PC7 PC11 PC316 PC335 PC336 PC338 PC339 PC802 PC807 PC808 PC810 PC865 PC1171 PC1200 PC1201 = P_CAP NP: room: P_DCIN
PC4 PC6 PC13 PC350 PC603 PC605 PC611 PC618 PC620 PC626 PC627 PC632 PC635 PC637-PC639 PC641 PC642 PC644 PC645 PC647 PC649-PC653 PC659-PC661 PC668 PC669 PC676 PC677 PC685 PC697 PC727 PC740 PC754 PC803 PC814 PC3005 = P_CAP NP: room: CPU_CORE
PC8 PC10 PC12 PC104-PC110 PC113 PC117 PC118 PC120-PC124 PC127 PC129-PC132 PC161-PC164 PC301 PC305-PC311 PC334 PC360 PC401-PC404 PC406-PC409 PC411-PC419 PC421 PC424 PC501 PC504 PC509-PC511 PC513 PC515 PC516 PC601 PC602 PC608 PC612-PC614 PC616 PC617 PC619 PC621 PC624 PC625 PC628-PC631 PC633 PC636 PC640 PC643 PC646 PC654 PC656-PC658 PC664 PC665 PC672-PC675 PC682-PC684 PC686-PC688 PC694 PC707 PC751 PC761 PC811 PC812 PC1000-PC1009 PC1011-PC1020 PC1031-PC1090 PC1101-PC1123 PC1131-PC1141 PC1151-PC1161 PC1169 PC1202 = P_CAP NP
PC100 PC115 PC116 PC303 PC331 PC332 = P_CAP NP: room: 3_5V
PC200 PC201 PC700 PC701 PC737 PC756 PC760 PC800 PC801 PC804 PC805 PC813 PC3002 = P_CAP NP: room: Charger
PC228 PC702-PC704 PC706 PC708-PC710 PC716 PC717 PC720 PC721 PC728-PC735 PC741 PC742 PC3001 PC3003 PC3004 = P_CAP NP: room: PWR_CHARGER
PC503 PC505 PC506 = P_CAP NP: room: 1.8V
PC606 PC607 PC715 PC1091-PC1094 PC1142 PC1143 PC1627 = P_CAP WP
PC806 PC809 = P_CAP NP: room: P_USBA
PD1 PD2 PD4 = TVNST52302AB0_SOT523-3
PD3 = P_BAS40-05W_SC70-3~D
PD5 PD801 = P_PDS5100H-13_POWERDI5-3~D: room: P_Selector
PD700 PD702 = P_SDMK0340L-7-F_SOD323-2~D
PD701 = P_DFLS160-7_POWERDI123-2
PD704 PD3001 PD3002 = RB520SM-30T2R_EMD2-2
PD705 PD800 PD803 PD3000 = BAT54CW_SOT323~D
PD802 = P_SDMK0340L-7-F_SOD323-2~D: room: P_selector
PH601-PH603 PH605 = P_SL2
PH604 = P_10KB_0603_5%_ERTJ1VR103J: room: CPU_CORE
PJP1 = PAD-OPEN: room: +1.0V_VCCST
PJP2 = PAD-OPEN: room: +1.0V_VCCSTG
PJP3 = PAD-OPEN: room: +1.0V_MPHYGT
PJP8 = PAD-OPEN: room: PD
PJP12 = PAD-OPEN: room: LCD
PJP14 = PAD-OPEN: room: RTS5242
PJP15 PJP16 PJP18 = PAD-OPEN: room: CODEC
PJP17 PJP40 PJP41 = PAD-OPEN: room: UZ4
PJP19 PJP36 PJP37 = PAD-OPEN: room: UZ2
PJP20 PJP22 = PAD-OPEN: room: KBC
PJP31 = PAD-OPEN: room: SATA EXPRESS
PJP32-PJP34 = PAD-OPEN: room: HDD
PJP35 = PAD-OPEN: room: KBTP
PJP38 PJP39 = PAD-OPEN: room: UZ3
PJP42 = PAD-OPEN: room: UZ8
PJP100 PJP101 PJP202 PJP301 PJP602 = VCCPAD: room: DDR_VTT_0.75V
PJP102 PJP103 PJP401 PJP402 = P_JUMP_43X118: room: 1.5V
PJP200 = P_JUMP_43X118: room: P_1.2V
PJP201 = P_JUMP_43X39: room: P_1.2V
PJP302 = P_JUMP_43X118
PJP403 PJP404 PJP501-PJP506 PJP603 = PAD-OPEN: room: VGA_CORE
PJP601 PJP700 = PAD-OPEN: room: Charger
PJPDC1 = P_CVILU_CI0805M1HRC-NH_4
PL1-PL4 = P_L: room: P_DCIN
PL100 PL201 PL301 PL402 PL404-PL406 PL501 PL502 PL700 PL701 PL800 PL801 = P_L
PL101 = P_L: room: VDDCI
PL602 = P_L: room: CPU_CORE
PL610 PL612 PL613 = P_L_4P
PL614 = P_0.47UH_MMD05CZR47M_12A_20%
PQ1 PQ10 PQ802 PQ804 PQ806 PQ813 PQ3000 = P_DMN65D8LDW-7_SOT363-6
PQ2 = P_FDV301N_NL_SOT23-3~D: room: P_DCIN
PQ3 = MMST3904-7-F_SOT323~D: room: P_DCIN
PQ4 = P_AON7409_DFN8-5_2
PQ5 PQ11 PQ803 PQ805 = NTR4502PT1G_SOT23-3: room: P_Charger
PQ6-PQ8 PQ12 PQ13 PQ807 PQ812 PQ814 = DMN65D8LW-7_SOT323-3
PQ9 = P_AON7409_DFN8-5_3
PQ614 = P_AON7934_DFN3X3A-8-10_0
PQ700 PQ701 = P_AOE6930_DFN5X6E8-10_0
PQ702 = P_AON7409_DFN8-5_1
PQ703 = P_RHU002N06_SOT323-3~D
PQ800 = P_AON7409_DFN8-5_6
PQ801 = P_AON7409_DFN8-5_5
PQ808-PQ811 = P_DMN66D0LDW-7_SOT363-6: room: P_USBB
PR1-PR8 PR11 PR13 PR14 PR16 PR24 PR27 PR43 PR668 PR675 PR804 PR819 PR821 PR823 PR856 PR860 PR862 = P_R: room: P_DCIN
PR9 PR114 PR308 PR312 PR412 PR422 PR512 PR745 PR746 PR3001 PR3006 RC25-RC27 RC29 RC30 RC33 RC35 RC87 RC137 RC432 RC433 RC520 RC521 RC570-RC576 RC730 RC734 RE300 RE362 RE543 RE546 RE551 RI27-RI30 RI47 RI48 RN100 RN101 RN131 RT86 RT190-RT197 RT219-RT222 RT397 RT399 RT414 RT415 RT420 RT482 RT483 RT488-RT491 RV732 RV802 RZ22 RZ23 RZ58-RZ60 RZ70 RZ89 RZ128-RZ130 RZ334 RZ372-RZ374 RZ1407 RZ1409 RZ1410 = R
PR10 PR15 PR17 PR28 PR33 PR45 PR705 PR706 PR801 PR802 PR806-PR808 PR810-PR813 PR822 PR824 PR825 PR828 PR830 PR833 PR838 PR839 PR846 PR851 PR852 PR855 PR865 = P_R: room: P_Selector
PR12 PR18 PR31 PR32 PR202 PR204 PR206 PR209 PR212 PR313 PR669 PR739 PR744 = P_R: room: P_1.2V
PR19 PR20 PR22 PR25 PR41 PR42 PR44 PR46 PR47 PR49 PR100 PR104 PR105 PR111 PR119 PR120 PR203 PR208 PR210 PR304 PR314 PR315 PR402 PR423 PR427 PR429 PR504 PR513 PR602 PR603 PR606 PR614 PR616 PR620 PR625 PR659 PR662 PR664 PR671 PR679 PR687 PR692 PR709 PR713 PR715 PR719 PR721 PR722 PR727 PR729 PR731 PR736 PR737 PR740 PR741 PR743 PR814 PR816 PR818 PR820 PR826 PR827 PR829 PR834 PR836 PR840 PR844 PR853 PR854 PR857-PR859 PR861 PR866 RA3 RC153 RD10 RD26 RL8 RR20 RT398 RV733 = P_R-SHORT
PR38-PR40 PR102 PR108 PR116 PR117 PR205 PR207 PR302 PR303 PR306 PR311 PR403 PR404 PR406-PR408 PR410 PR411 PR421 PR425 PR428 PR430 PR509-PR511 PR514-PR516 PR601 PR604 PR605 PR608 PR610 PR611 PR613 PR617 PR618 PR621 PR622 PR626 PR629-PR631 PR635 PR639 PR640 PR644 PR651 PR678 PR680 PR688 PR691 PR693 PR701-PR703 PR712 PR717 PR718 PR720 PR725 PR726 PR728 PR733-PR735 PR800 PR809 PR815 PR817 PR831 PR832 PR835 PR842 PR843 PR870 PR892 PR893 PR3002-PR3005 PR3007-PR3013 RC752 RE79 RZ335 RZ1413 RZ1482 = P_R
PR103 = P_R: room: 3_5V
PR106 PR112 = P_R: room: 1.5V
PR107 PR113 PR307 PR310 = P_R: room: 1P5V
PR405 PR409 PR501 PR502 PR505 PR506 = P_R: room: 1.8V
PR413-PR420 PR424 PR708 PR710 PR716 PR724 PR805 = P_R: room: Charger
PR612 PR619 PR623 PR624 PR627 PR628 PR632 PR633 PR636 PR638 PR641-PR643 PR645-PR650 PR652 PR653 PR656-PR658 PR660 PR661 PR663 PR665-PR667 PR670 PR672-PR674 PR676 PR677 = P_R: room: CPU_CORE
PR615 PR634 = P_R: room: GPU_CORE
PR700 PR711 = P_R~D: room: CHARGER
PR704 PR707 PR714 PR723 PR738 = P_R: room: CHARGER
PR803 = P_R: room: P_selector
PR841 PR845 = P_R: room: P_USBB
PU2 = AP2204R-5.0TRG1_SOT89-3
PU3 PU801 = TC7SH08FU_SSOP5~D: room: PCH
PU100 = P_SY8288BRAC_QFN20_0
PU102 = P_SY8288CRAC_QFN20_1
PU200 = P_SY8210AQVC_QFN19_4X3: room: P_1.2V
PU301 = P_SY8288RAC_QFN20_1
PU401 PU402 = P_TLV62130ARGTR_QFN16_0
PU501 = P_RT8097ALGE_SOT23-6
PU502 = P_AP7361C-FGE-7_U-DFN3030-8_1
PU503 = P_AP7361C-FGE-7_U-DFN3030-8_2
PU602 = P_ISL62883CHRTZ-T_TQFN40_1: room: GPU_CORE
PU610 = P_FDMF3035_PQFN31_5
PU612 = P_FDMF3035_PQFN31_7
PU613 = P_FDMF3035_PQFN31_6
PU614 = P_ISL95808HRZ-TS2378_DFN8_2X2
PU700 = P_ISL88738HRTZ-T_TQFN32_4X4
PU701 = SN74AHC1G08DCKR_SC70-5
PU800 = P_LM393DGKR_VSSOP8
PU3000 = P_AZV3002RL-7_U-FLGA8_1P65X1P65
QC2 QC4 QE2 QE21 QL1 QN1 QT10 QZ7 = DMN66D0LDW-7_SOT363-6~D: room: CPU
QC6 QE11 QE12 QE17 QE20 QN6 QZ15 QZ19 QZ22 = L2N7002WT1G_SC-70-3
QC7 QE15 QZ1 QZ18 = LP2301ALT1G_SOT23-3: room: CAMERA
QC8 = L2N7002WT1G_SC-70-3: room: SIO
QE3-QE7 = MMST3904-7-F_SOT323-3: room: KBC
QR1 = L2N7002WT1G_SC-70-3: room: RTS5242
QT1 = DMN66D0LDW-7_SOT363-6~D: room: PD
QV1 = P_AO6405_TSOP6_0: room: LCD
QV2 = L2N7002WT1G_SC-70-3: room: LCD
QV7 = L2N7002WT1G_SC-70-3: room: TOUCH
QV8 = LP2301ALT1G_SOT23-3: room: TOUCH
QV18 QV20 = MMBT3906H_SOT23-3
QV19 QV21 = MMBT3904WT1G_SC70-3~D: room: KBC
QZ3 = LMUN5111T1G_SC70-3
QZ17 = PJE138K_SOT523-3
QZ21 = LMBT3904WT1G_SC70-3
RA5-RA9 RA12-RA14 RA17 RA18 RA44 RA45 RA51 RA52 RA59 RA60 RC59 = R: room: CODEC
RA35-RA37 RA48 RA53 RC28 RC32 RC121 RC128 RC157 RC159 RC165 RC215 RC216 RC221 RC239 RC240 RC243 RC297 RC328 RC337 RC403 RC404 RC425 RC426 RC429 RC430 RC440 RC442 RC445 RC526-RC528 RC531 RC532 RC559 RC566 RC631 RC632 RC727 RC735-RC739 RC845 RC848 RC850-RC853 RC864 RD5 RD7 RD9 RD12 RD21 RD22 RD25 RE30 RE32 RE59 RE90 RE275 RE290 RE318 RE361 RE548 RE552 RE560 RE565 RE600-RE603 RE608 RE703 RL3 RL7 RL20 RL34 RN77 RN78 RN81 RN82 RN99 RN125-RN129 RN227 RR5-RR10 RT54-RT60 RT63 RT69 RT70 RT73 RT74 RT83 RT89 RT90 RT99 RT104 RT105 RT108 RT109 RT120-RT123 RV323 RV400 RV628 RZ26 RZ29 RZ56 RZ61 RZ64 RZ87 RZ112 RZ114 RZ120 RZ345-RZ347 RZ350 RZ351 RZ380 RZ388 RZ1385 RZ1393-RZ1395 RZ1398 RZ1401 RZ1402 RZ1408 RZ1411 RZ1415 RZ1420 RZ1423 RZ1475-RZ1477 RZ1484 RZ1485 = R-SHORT
RA50 RA54 RA57 RA58 = R: room: UZ8
RC2 RC5-RC8 RC10-RC12 RC14 RC15 RC20 RC46-RC51 RC53 RC56-RC58 RC60 RC65-RC69 RC71-RC73 RC75 RC77 RC78 RC82 RC84 RC86 RC92 RC93 RC95 RC96 RC101 RC104 RC106-RC109 RC116 RC125 RC130 RC150 RC151 RC154-RC156 RC160 RC161 RC163 RC164 RC166 RC176 RC178 RC183 RC187 RC189 RC214 RC218-RC220 RC222 RC229-RC234 RC237 RC244 RC248 RC266 RC277-RC279 RC288 RC292 RC298 RC317-RC319 RC323 RC344 RC345 RC347 RC348 RC362 RC363 RC366-RC369 RC397 RC402 RC420 RC436-RC439 RC441 RC443 RC444 RC446 RC451 RC452 RC454 RC502-RC507 RC515 RC518 RC519 RC522 RC523 RC525 RC530 RC536 RC537 RC555 RC558 RC560-RC562 RC567-RC569 RC624 RC640 RC724-RC726 RC731-RC733 RC747-RC749 RC751 RC756-RC761 RC763-RC766 RC829-RC834 RC836-RC844 RC847 RC849 RC862 RC865 RC866 RC868 RE349 RE716-RE718 RL70 RV7 RV55 RV98 RV99 RV311 RV319 RV324 RV326 RV623-RV627 RV629-RV631 RV737 RZ20 RZ21 RZ132 RZ133 RZ603 RZ752 RZ1392 RZ1400 RZ1405 RZ1406 = R: room: CPU
RC19 RC289 RC299 RC564 RC565 RC728 RC729 RE350 RE539 = R: room: SPI ROM
RC24 RC302 RC660 RC867 RZ78-RZ80 RZ1388 RZ1389 RZ1471 = R: room: AR
RC31 RT50-RT53 RT64-RT68 RT71 RT72 RT75 RT76 RT81 RT82 RT84 RT85 RT87 RT88 RT92 RT93 RT95-RT98 RT100 RT101 RT103 RT106 RT107 RT110 RT111 RT377-RT379 RT393 = R: room: PD
RC61 RC62 RC94 = R: room: PD_1
RC63 RC158 RC400 RC401 RC743-RC745 RE31 RE33 RE37 RE43 RE48 RE51 RE55-RE58 RE60 RE63-RE65 RE67-RE75 RE77 RE86 RE280 RE292 RE302-RE304 RE306 RE312-RE314 RE342 RE343 RE526 RE536 RE706-RE709 RE714 RE715 RE719 RE720 RE826 RE828 RE829 RZ43 RZ827 = R: room: KBC
RC120 RC405-RC407 RC409-RC419 = R: room: CPU_XDP
RC122-RC124 RC126 RC129 RC131-RC136 RC138 RC139 RC217 RC235 RC236 RC241 = R: room: CPU XDP
RC173 RC175 RC422 = R: room: Other
RC431 RC710 RC711 RE8 RE10-RE12 RE20 RE21 RE25 RE26 RE35 RE83-RE85 RE91-RE94 RE274 RE288 RE340 RE365 RE505 RE507 RE508 RE532 RE541 RE547 RE549 RE550 RE561 RE605 RE606 RE704 RE721-RE730 RE821 RE822 RE825 = R: room: SIO
RC448 = P_R: room: CPU
RC723 = R: room: AUDIO_CODEC
RD4 RD6 RD8 RD11 RD14-RD20 RD23 RD24 RD27-RD31 RZ32 RZ361 = R: room: MEMORY
RI13 RI14 = R: room: USB1
RL1 RL2 RL4-RL6 RL9 RL11-RL19 RL29 RL71-RL78 RV654 RV683-RV685 = R: room: LAN
RN1-RN21 RN226 RZ102 RZ148 = R: room: HDD
RN37 = R: room: SATA EXPRESS
RR3 RR4 RR19 = R: room: RTS5242
RT130 RT131 RT135-RT142 RT246 RT300 RT304 RT305 RT308 = R: room: PS8740
RT132 RT133 RT303 RT380 = R-SHORT: room: PS8740
RT339 RZ1486 = R: room: TBT
RV1-RV5 = R: room: LCD
RV6 RV8 = R: room: TOUCH
RV10 RV175 RV207-RV209 RV300 RV302-RV305 RV307 RV686-RV693 RV734-RV736 = R: room: HDMI
RZ8-RZ10 RZ1414 RZ1473 = R: room: USH
RZ18 RZ19 RZ116 RZ117 = R: room: KBTP
RZ25 RZ28 = R: room: LED
RZ38 RZ71 RZ1422 = R: room: UZ2
RZ40 RZ1472 RZ1474 = R: room: UZ4
RZ63 RZ69 RZ362 RZ377 RZ379 RZ400 RZ518 RZ1397 RZ1483 = R: room: TPM
RZ76 RZ77 RZ326 RZ1396 RZ1403 RZ1404 RZ1450 RZ1480 RZ1481 = R: room: WWAN
RZ96 = R: room: UZ3
RZ119 RZ1416-RZ1419 = R: room: +VCC_SFR_OC
RZ151 RZ320 = R: room: +1.0V_VCCSTG
RZ401 = R: room: GPU
RZ1381 RZ1383 = R: room: WLAN
RZ1390 RZ1391 = R: room: CAMERA
RZ1399 = R: room: EC
SW1 = SS3-CMFTQR9_3P: room: CPU
SW3 = SKRBAAE010_4P: room: LED
T1 T2 = PAD_5: room: CPU
T12 T341 T348 T375-T379 T383-T385 T388 T389 T395-T402 T406 T407 T415 T416 T418 T421 T422 = PAD_0: room: CPU
T16-T21 T355 T360 T361 T363-T365 T368 T369 T371-T374 T380 T381 T419 T423 = PAD_8: room: CPU
T50 T51 T54 T55 = PAD_9: room: MEMORY
T88 T89 T315 = PAD_0: room: LAN
T350 T351 T353 T354 = PAD_6: room: CPU
TL1 = 350uH_IH-115-F~D: room: LAN
UA1 = ALC3204-CG_MQFN40_5X5
UC1 = WHL-U42_BGA1528
UC5 = W25Q256JVEIQ_WSON8_8X6
UC6 = W25Q128JVSIQ_SO8
UC7 UE3 UE5 = TC7SH08FU_SSOP5~D: room: CPU
UC9 UZ54 = MC74VHC1G32DFT2G_SC70-5~D
UD1 = 74AUP1G07GW_TSSOP5: room: MEMORY
UE1 = MEC5105_WFBGA169_0
UE4 = 74AUP1G07GW_TSSOP5
UI1 = SY6288D20AAC_SOT23-5: room: USB2
UI2 = SY6288D20AAC_SOT23-5: room: USB3
UI3 = SLGC55544CVTR_TQFN16_3X3: room: USB1
UL1 = WGI219LM-SLKJ3-A0_QFN48_6X6~D
UN7 = PI3EQX6741STZDEX_TQFN20_1: room: HDD
UR1 = RTS5242-GR_QFN32_4X4: room: RTS5242
UT5 = TPS65982_BGA96_1: room: PD
UT6 = W25Q80DVSSIG_SO8: room: PD
UT7 = AP2112K-3.3TRG1_SOT23-5: room: PD
UT8 = AP2204R-5.0TRG1_SOT89-3: room: PD
UT9 = PS8802QFN52GTRA1_QFN52_0
UV2 = AP2330W-7_SC59-3: room: HDMI
UV21 = PS8407ATQFN40GTR2A1_TQFN40_0
UV24 = G524B1T11U_SOT23-5: room: LCD
UZ3 = TPS22966DPUR_SON14_1: room: UZ3
UZ5 = TPS22966DPUR_SON14_0: room: CODEC
UZ8 UZ53 = AOZ1336_DFN8_1: room: UZ8
UZ10 = TC7SH08FU_SSOP5~D: room: LED
UZ12 = ST33HTPH2E32AHB4_VQFN32_5X5
UZ19 = TPS22961DNYR_WSON8: room: +1.0V_VCCSTG
UZ21 = TPS22961DNYR_WSON8: room: +1.0V_VCCST
UZ23 = AOZ1336_DFN8_0: room: HDD
UZ27 = TPS22961DNYR_WSON8: room: +VCC_SFR_OC
UZ35 = TC7SH08FU_SSOP5~D: room: +1.0V_VCCSTG
UZ41 = TC7SH08FU_SSOP5~D: room: RSMRST
UZ43 = TPS22966DPUR_SON14_1: room: UZ2
UZ47 = TPS22966DPUR_SON14_1: room: UZ4
UZ51 = SN74LVC1G3157DCKR_SC70-6
UZ52 = SN74AUP1T97YZPR_DSBGA6~D
YC1 = 24MHZ_12PF_8Y24000034
YC2 = 32.768KHZ_12.5PF_9H03220008: room: CPU
YE1 = 32.768KHZ_9PF_X1A000141000200
YL1 = 25MHZ_20PF_XRCGB25M000F2P18R0_0

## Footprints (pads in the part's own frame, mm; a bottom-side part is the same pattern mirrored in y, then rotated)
1N4148WS-7-F_SOD323-2
  rect 1.346x0.66 smd: 1(0,0) 2(2.4,0)
1N4148WS-L_SOD323-2
  rect 0.559x0.813 smd: 1(0,0) 2(2.3,0)
3A_Z120_0603_2P
  rect 0.559x1.041 smd: 1(0,0) 2(1.3,0)
9A_Z80_1812_2P-NPM
  rect 1.803x3.404 smd: 1(0,0) 2(3.8,0)
74AUP1G07GW_TSSOP5
  oval 0.381x1.346 smd: 1(0,0) 2(0.65,0) 3(1.3,0) 4(1.3,1.79) 5(0,1.79)
ACES_50208-01001-P03_10P
  oval 0.508x0.991 smd: 1(0,0) 2(0.8,0) 3(1.6,0) 4(2.4,0) 5(3.2,0) 6(4,0) 7(4.8,0) 8(5.6,0) 9(6.4,0) 10(7.2,0)
  rect 1.194x1.702 smd: 11(-1.3,-1.95) 12(8.5,-1.95)
ACES_50271-0020N-001_2P
  oval 0.787x1.6 smd: 1(0,0) 2(1.25,0)
  rect 2.108x2.997 smd: 3(3.8,-2.9) 4(-2.55,-2.9)
ACES_50271-0040N-001_4P
  oval 0.787x1.6 smd: 1(0,0) 2(-1.25,0) 3(-2.5,0) 4(-3.75,0)
  rect 2.108x2.997 smd: 5(2.55,-2.9) 6(-6.3,-2.9)
ACES_50278-00401-001_4P
  oval 0.787x1.905 smd: 1(0,0) 2(1.25,0) 3(2.5,0) 4(3.75,0)
  rect 1.295x3.353 smd: 5(-2.85,-4.925) 6(6.6,-4.925)
ACES_50398-04041-001_40P
  oval 0.254x1.295 smd: 1(0,0) 2(0.5,0) 3(1,0) 4(1.5,0) 5(2,0) 6(2.5,0) 7(3,0) 8(3.5,0) 9(4,0) 10(4.5,0) 11(5,0) 12(5.5,0) 13(6,0) 14(6.5,0) 15(7,0) 16(7.5,0) 17(8,0) 18(8.5,0) 19(9,0) 20(9.5,0) 21(10,0) 22(10.5,0) 23(11,0) 24(11.5,0) 25(12,0) 26(12.5,0) 27(13,0) 28(13.5,0) 29(14,0) 30(14.5,0) 31(15,0) 32(15.5,0) 33(16,0) 34(16.5,0) 35(17,0) 36(17.5,0) 37(18,0) 38(18.5,0) 39(19,0) 40(19.5,0)
  rect 1.194x3.2 smd: 41(-2.4,1.95) 45(21.9,1.95)
  rect 2.311x1.295 smd: 42(0.85,3.9) 43(9.75,3.9) 44(18.65,3.9)
ACES_50506-01841-P01_18P
  oval 0.305x0.889 smd: 1(0,0) 2(0.5,0) 3(1,0) 4(1.5,0) 5(2,0) 6(2.5,0) 7(3,0) 8(3.5,0) 9(4,0) 10(4.5,0) 11(5,0) 12(5.5,0) 13(6,0) 14(6.5,0) 15(7,0) 16(7.5,0) 17(8,0) 18(8.5,0)
  rect 0.991x2.007 smd: 19(-2.1,-3.05) 20(10.6,-3.05)
ACES_50506-02041-P01_20P
  oval 0.305x0.889 smd: 1(0,0) 2(0.5,0) 3(1,0) 4(1.5,0) 5(2,0) 6(2.5,0) 7(3,0) 8(3.5,0) 9(4,0) 10(4.5,0) 11(5,0) 12(5.5,0) 13(6,0) 14(6.5,0) 15(7,0) 16(7.5,0) 17(8,0) 18(8.5,0) 19(9,0) 20(9.5,0)
  rect 0.991x2.007 smd: 21(-2.1,-3.05) 22(11.6,-3.05)
ALC3204-CG_MQFN40_5X5
  oval 0.889x0.203 smd: 1(0,0) 2(0,-0.4) 3(0,-0.8) 4(0,-1.2) 5(0,-1.6) 6(0,-2) 7(0,-2.4) 8(0,-2.8) 9(0,-3.2) 10(0,-3.6) 21(5.1,-3.6) 22(5.1,-3.2) 23(5.1,-2.8) 24(5.1,-2.4) 25(5.1,-2) 26(5.1,-1.6) 27(5.1,-1.2) 28(5.1,-0.8) 29(5.1,-0.4) 30(5.1,0)
  oval 0.203x0.889 smd: 11(0.75,-4.35) 12(1.15,-4.35) 13(1.55,-4.35) 14(1.95,-4.35) 15(2.35,-4.35) 16(2.75,-4.35) 17(3.15,-4.35) 18(3.55,-4.35) 19(3.95,-4.35) 20(4.35,-4.35) 31(4.35,0.75) 32(3.95,0.75) 33(3.55,0.75) 34(3.15,0.75) 35(2.75,0.75) 36(2.35,0.75) 37(1.95,0.75) 38(1.55,0.75) 39(1.15,0.75) 40(0.75,0.75)
  rect 3.607x3.607 smd: 41(2.55,-1.8)
AO3409_SOT23-3
  oval 1.016x1.524 smd: 1(0,0) 2(0.965,2.083) 3(-0.965,2.083)
AO6405_TSOP6
  oval 0.508x1.473 smd: 1(0,0) 2(0.95,0) 3(1.9,0) 4(1.9,2.35) 5(0.95,2.35) 6(0,2.35)
AOE6930_DFN5X6E8-10
  rect 0.61x0.61 smd: 1(0,0) 2(1.27,0) 3(2.54,0) 4(3.81,0) 5(3.81,5.5) 6(2.54,5.5) 7(1.27,5.5)
  rect 0.61x1.676 smd: 8(0,4.96)
  rect 4.191x1.041 smd: 9(1.905,1.215)
  custom 0.617x0.617 smd: 10(1.905,3.465)
AON7934_DFN3X3A8-10
  oval 0.457x0.508 smd: 1(0,0) 2(0.65,0) 3(1.3,0) 4(1.95,0) 5(1.95,2.76) 6(1.3,2.76) 7(0.65,2.76) 8(0,2.76)
  rect 2.54x1.041 smd: 9(0.975,1.813)
  rect 2.54x0.559 smd: 10(0.975,0.708)
AOZ1336_DFN8_2X2-S
  oval 0.254x0.787 smd: 1(0,0) 2(0.5,0) 3(1,0) 4(1.5,0) 5(1.5,2.2) 6(1,2.2) 7(0.5,2.2) 8(0,2.2)
  rect 1.499x0.889 smd: 9(0.75,1.1)
AP2112K-3P3TRG1_SOT23-5
  oval 0.508x0.965 smd: 1(0,0) 2(0.95,0) 3(1.9,0) 4(1.9,2.375) 5(0,2.375)
AP2204R-5P0TRG1_SOT89-3
  oval 0.889x1.295 smd: 1(0,0) 3(3,0)
  custom 0.433x0.433 smd: 2(1.5,1.775)
AP2330W-7_SC59-3
  oval 0.787x0.991 smd: 1(0,0) 2(-0.95,-2.4) 3(0.95,-2.4)
AP7361C-FGE-7_U-DFN3030-8_3X3
  oval 0.457x0.94 smd: 1(0,0) 2(0.65,0) 3(1.3,0) 4(1.95,0) 5(1.95,3.05) 6(1.3,3.05) 7(0.65,3.05) 8(0,3.05)
  rect 2.261x1.499 smd: 9(0.975,1.525)
AZ1045-04F_DFN2510P10E-10-9
  oval 0.254x0.686 smd: 1(0,0) 2(0.5,0) 4(1.5,0) 5(2,0) 6(2,0.875) 7(1.5,0.875) 8(0.5,0.875) 9(0,0.875)
  oval 0.381x1.549 smd: 3(1,0.437)
AZC199-02SPR7G_SOT23-3
  oval 1.016x1.524 smd: 1(0,0) 2(0.965,2.083) 3(-0.965,2.083)
AZV3002RL-7_U-FLGA8_1P65X1P65
  oval 0.406x0.508 smd: 1(0,0)
  oval 0.305x0.508 smd: 2(0.55,0) 3(1.05,0) 5(1.05,1.22) 6(0.55,1.22) 7(0.05,1.22)
  oval 0.508x0.305 smd: 4(1.15,0.61) 8(-0.05,0.61)
BAT54CW_SOT323-3
  oval 0.711x0.889 smd: 1(0,0) 2(-0.65,-1.9) 3(0.65,-1.9)
BELLW_80149-3221_67P
  round 1.092 hole 1.092 unplated: (-0.75,-5.275)
  round 1.6 hole 1.6 unplated: (19.25,-5.275)
  oval 0.305x1.549 smd: 1(0,0) 2(0.25,-7.55) 3(0.5,0) 4(0.75,-7.55) 5(1,0) 6(1.25,-7.55) 7(1.5,0) 8(1.75,-7.55) 9(2,0) 10(2.25,-7.55) 11(2.5,0) 12(4.75,-7.55) 13(5,0) 14(5.25,-7.55) 15(5.5,0) 16(5.75,-7.55) 17(6,0) 18(6.25,-7.55) 19(6.5,0) 20(6.75,-7.55) 21(7,0) 22(7.25,-7.55) 23(7.5,0) 24(7.75,-7.55) 25(8,0) 26(8.25,-7.55) 27(8.5,0) 28(8.75,-7.55) 29(9,0) 30(9.25,-7.55) 31(9.5,0) 32(9.75,-7.55) 33(10,0) 34(10.25,-7.55) 35(10.5,0) 36(10.75,-7.55) 37(11,0) 38(11.25,-7.55) 39(11.5,0) 40(11.75,-7.55) 41(12,0) 42(12.25,-7.55) 43(12.5,0) 44(12.75,-7.55) 45(13,0) 46(13.25,-7.55) 47(13.5,0) 48(13.75,-7.55) 49(14,0) 50(14.25,-7.55) 51(14.5,0) 52(14.75,-7.55) 53(15,0) 54(15.25,-7.55) 55(15.5,0) 56(15.75,-7.55) 57(16,0) 58(16.25,-7.55) 59(16.5,0) 60(16.75,-7.55) 61(17,0) 62(17.25,-7.55) 63(17.5,0) 64(17.75,-7.55) 65(18,0) 66(18.25,-7.55) 67(18.5,0)
  rect 1.194x2.743 smd: 68(-1.1,-0.775) 69(19.6,-0.775)
BSS138W-7-F_SOT323-3
  oval 0.711x0.889 smd: 1(0,0) 2(-0.65,-1.9) 3(0.65,-1.9)
BZV55-B5V1_SOD80C2
  rect 0.889x1.6 smd: 1(0,0) 2(3.3,0)
C-K_26230A-8K1A-02_9P
  round 1.194 hole 0.711: 1(0,0) 2(-2.5,0) 3(-4.5,0) 4(-7,0) 5(-7.5,-1.5) 6(-5.5,-1.5) 7(-3.5,-1.5) 8(-1.5,-1.5) 9(0.5,-1.5)
  oval 1.295x2.388 hole 0.711x1.803: 10(2.9,-0.4) 11(4.2,-8.95) 12(-11.2,-8.95) 13(-9.9,-0.4)
C_0201
  rect 0.381x0.356 smd: 1(0,0) 2(0.584,0)
C_0402
  rect 0.508x0.584 smd: 1(0,0) 2(0.914,0)
C_0603
  rect 0.635x0.889 smd: 1(0,0) 2(1.397,0)
C_0603-S3
  rect 0.635x0.889 smd: 1(0,0) 2(1.397,0)
C_0805
  rect 0.813x1.397 smd: 1(0,0) 2(1.702,0)
C_1808
  rect 1.041x2.311 smd: 1(0,0) 2(4.35,0)
C_A
  rect 1.626x1.829 smd: 1(0.389,0) 2(2.989,0)
C_B2
  rect 1.346x2.692 smd: 1(0,0) 2(-2.75,0)
C_B2-NPM
  rect 1.346x2.692 smd: 1(0,0) 2(-2.75,0)
C_D
  rect 2.388x2.896 smd: 1(0,0) 2(6.1,0)
C_D2
  rect 2.388x2.794 smd: 1(0,0) 2(6.4,0)
C_D3
  rect 2.388x2.794 smd: 1(0,0) 2(6.4,0)
CEST523NC5VB_SOT-523-3
  oval 0.508x0.61 smd: 1(0,0)
  oval 0.406x0.61 smd: 2(-0.5,-1.24) 3(0.5,-1.24)
CVILU_CI0805M1HRC-NH_5P-T
  round 1.803 hole 1.803 unplated: (-0.2,5.2) (8.2,5.2)
  oval 0.889x2.388 smd: 1(0,0) 2(2,0) 3(4,0) 4(6,0) 5(8,0)
  rect 1.6x2.489 smd: 6(11.15,9.05) 7(-3.15,9.05)
CYNTE_PCMB051H-1R0MS_2P
  rect 2.159x2.794 smd: 1(0,0) 2(4.35,0)
CYNTE_PCMB063T-1R0MS_2P
  rect 2.362x3.505 smd: 1(0,0) 2(6.05,0)
CYNTE_PCMB103T-2R2MS_2P
  rect 3.81x3.988 smd: 1(0,0) 2(9.2,0)
DB3J315E0L_SMINI3-F2-B3
  oval 0.889x0.787 smd: 1(0,0) 2(-0.65,-1.9) 3(0.65,-1.9)
DEREN_40-42251-01001RHF_10P-T
  oval 0.838x2.21 smd: 1(0,0.1) 2(1.5,0.1) 3(3,0.1) 4(4.5,0.1) 5(6,0.1) 6(7.5,0.1) 7(9,0.1) 8(10.5,0.1) 9(12,0.1) 10(13.5,0.1)
  custom 0.75x0.75 smd: 11(-3.4,-3.15) 12(16.9,-3.15)
DMN65D8LDW-7_SOT363-6
  oval 0.432x0.61 smd: 1(0,0) 2(0.65,0) 3(1.3,0) 4(1.3,1.9) 5(0.65,1.9) 6(0,1.9)
DMN65D8LW-7_SOT323-3
  oval 0.711x0.889 smd: 1(0,0) 2(-0.65,-1.9) 3(0.65,-1.9)
DMN66D0LDW-7_SOT363-6
  oval 0.432x0.61 smd: 1(0,0) 2(0.65,0) 3(1.3,0) 4(1.3,1.9) 5(0.65,1.9) 6(0,1.9)
ESD8011MUT5G_X3DFN2-2
  rect 0.33x0.356 smd: 1(0,0) 2(0.43,0)
F_T0603FF1000TM
  rect 0.711x0.991 smd: 1(0,0) 2(1.5,0)
F_T0603FF1000TM-NPM
  rect 0.711x0.991 smd: 1(0,0) 2(1.5,0)
FDMC6679AZ_MLP8-5
  oval 0.432x0.711 smd: 1(0,0) 2(0.65,0) 3(1.3,0) 4(1.95,0)
  custom 0.537x0.537 smd: 5(0.975,2.075)
FDV301N-G_SOT23-3
  oval 1.016x1.524 smd: 1(0,0) 2(0.965,2.083) 3(-0.965,2.083)
FIDUCIAL_C40M80
  round 1.016 smd: 1(0,0)
FOX_ASAA821-H4RB5-7H_260P
  round 1.092 hole 1.092 unplated: (-67.775,-4.1)
  round 1.6 hole 1.6 unplated: (1.025,-4.1)
  oval 0.305x1.753 smd: 1(0,0) 2(-0.25,-8.2) 3(-0.5,0) 4(-0.75,-8.2) 5(-1,0) 6(-1.25,-8.2) 7(-1.5,0) 8(-1.75,-8.2) 9(-2,0) 10(-2.25,-8.2) 11(-2.5,0) 12(-2.75,-8.2) 13(-3,0) 14(-3.25,-8.2) 15(-3.5,0) 16(-3.75,-8.2) 17(-4,0) 18(-4.25,-8.2) 19(-4.5,0) 20(-4.75,-8.2) 21(-5,0) 22(-5.25,-8.2) 23(-5.5,0) 24(-5.75,-8.2) 25(-6,0) 26(-6.25,-8.2) 27(-6.5,0) 28(-6.75,-8.2) 29(-7,0) 30(-7.25,-8.2) 31(-7.5,0) 32(-7.75,-8.2) 33(-8,0) 34(-8.25,-8.2) 35(-8.5,0) 36(-8.75,-8.2) 37(-9,0) 38(-9.25,-8.2) 39(-9.5,0) 40(-9.75,-8.2) 41(-10,0) 42(-10.25,-8.2) 43(-10.5,0) 44(-10.75,-8.2) 45(-11,0) 46(-11.25,-8.2) 47(-11.5,0) 48(-11.75,-8.2) 49(-12,0) 50(-12.25,-8.2) 51(-12.5,0) 52(-12.75,-8.2) 53(-13,0) 54(-13.25,-8.2) 55(-13.5,0) 56(-13.75,-8.2) 57(-14,0) 58(-14.25,-8.2) 59(-14.5,0) 60(-14.75,-8.2) 61(-15,0) 62(-15.25,-8.2) 63(-15.5,0) 64(-15.75,-8.2) 65(-16,0) 66(-16.25,-8.2) 67(-16.5,0) 68(-16.75,-8.2) 69(-17,0) 70(-17.25,-8.2) 71(-17.5,0) 72(-17.75,-8.2) 73(-18,0) 74(-18.25,-8.2) 75(-18.5,0) 76(-18.75,-8.2) 77(-19,0) 78(-19.25,-8.2) 79(-19.5,0) 80(-19.75,-8.2) 81(-20,0) 82(-20.25,-8.2) 83(-20.5,0) 84(-20.75,-8.2) 85(-21,0) 86(-21.25,-8.2) 87(-21.5,0) 88(-21.75,-8.2) 89(-22,0) 90(-22.25,-8.2) 91(-22.5,0) 92(-22.75,-8.2) 93(-23,0) 94(-23.25,-8.2) 95(-23.5,0) 96(-23.75,-8.2) 97(-24,0) 98(-24.25,-8.2) 99(-24.5,0) 100(-24.75,-8.2) 101(-25,0) 102(-25.25,-8.2) 103(-25.5,0) 104(-25.75,-8.2) 105(-26,0) 106(-26.25,-8.2) 107(-26.5,0) 108(-26.75,-8.2) 109(-27,0) 110(-27.25,-8.2) 111(-27.5,0) 112(-27.75,-8.2) 113(-28,0) 114(-28.25,-8.2) 115(-28.5,0) 116(-28.75,-8.2) 117(-29,0) 118(-29.25,-8.2) 119(-29.5,0) 120(-29.75,-8.2) 121(-30,0) 122(-30.25,-8.2) 123(-30.5,0) 124(-30.75,-8.2) 125(-31,0) 126(-31.25,-8.2) 127(-31.5,0) 128(-31.75,-8.2) 129(-32,0) 130(-32.25,-8.2) 131(-32.5,0) 132(-32.75,-8.2) 133(-33,0) 134(-33.25,-8.2) 135(-33.5,0) 136(-33.75,-8.2) 137(-34,0) 138(-34.25,-8.2) 139(-34.5,0) 140(-34.75,-8.2) 141(-35,0) 142(-35.25,-8.2) 143(-35.5,0) 144(-35.75,-8.2) 145(-38,0) 146(-38.25,-8.2) 147(-38.5,0) 148(-38.75,-8.2) 149(-39,0) 150(-39.25,-8.2) 151(-39.5,0) 152(-39.75,-8.2) 153(-40,0) 154(-40.25,-8.2) 155(-40.5,0) 156(-40.75,-8.2) 157(-41,0) 158(-41.25,-8.2) 159(-41.5,0) 160(-41.75,-8.2) 161(-42,0) 162(-42.25,-8.2) 163(-42.5,0) 164(-42.75,-8.2) 165(-43,0) 166(-43.25,-8.2) 167(-43.5,0) 168(-43.75,-8.2) 169(-44,0) 170(-44.25,-8.2) 171(-44.5,0) 172(-44.75,-8.2) 173(-45,0) 174(-45.25,-8.2) 175(-45.5,0) 176(-45.75,-8.2) 177(-46,0) 178(-46.25,-8.2) 179(-46.5,0) 180(-46.75,-8.2) 181(-47,0) 182(-47.25,-8.2) 183(-47.5,0) 184(-47.75,-8.2) 185(-48,0) 186(-48.25,-8.2) 187(-48.5,0) 188(-48.75,-8.2) 189(-49,0) 190(-49.25,-8.2) 191(-49.5,0) 192(-49.75,-8.2) 193(-50,0) 194(-50.25,-8.2) 195(-50.5,0) 196(-50.75,-8.2) 197(-51,0) 198(-51.25,-8.2) 199(-51.5,0) 200(-51.75,-8.2) 201(-52,0) 202(-52.25,-8.2) 203(-52.5,0) 204(-52.75,-8.2) 205(-53,0) 206(-53.25,-8.2) 207(-53.5,0) 208(-53.75,-8.2) 209(-54,0) 210(-54.25,-8.2) 211(-54.5,0) 212(-54.75,-8.2) 213(-55,0) 214(-55.25,-8.2) 215(-55.5,0) 216(-55.75,-8.2) 217(-56,0) 218(-56.25,-8.2) 219(-56.5,0) 220(-56.75,-8.2) 221(-57,0) 222(-57.25,-8.2) 223(-57.5,0) 224(-57.75,-8.2) 225(-58,0) 226(-58.25,-8.2) 227(-58.5,0) 228(-58.75,-8.2) 229(-59,0) 230(-59.25,-8.2) 231(-59.5,0) 232(-59.75,-8.2) 233(-60,0) 234(-60.25,-8.2) 235(-60.5,0) 236(-60.75,-8.2) 237(-61,0) 238(-61.25,-8.2) 239(-61.5,0) 240(-61.75,-8.2) 241(-62,0) 242(-62.25,-8.2) 243(-62.5,0) 244(-62.75,-8.2) 245(-63,0) 246(-63.25,-8.2) 247(-63.5,0) 248(-63.75,-8.2) 249(-64,0) 250(-64.25,-8.2) 251(-64.5,0) 252(-64.75,-8.2) 253(-65,0) 254(-65.25,-8.2) 255(-65.5,0) 256(-65.75,-8.2) 257(-66,0) 258(-66.25,-8.2) 259(-66.5,0) 260(-66.75,-8.2)
  rect 3.505x4.597 smd: 261(-67.175,7.9) 262(0.425,7.9)
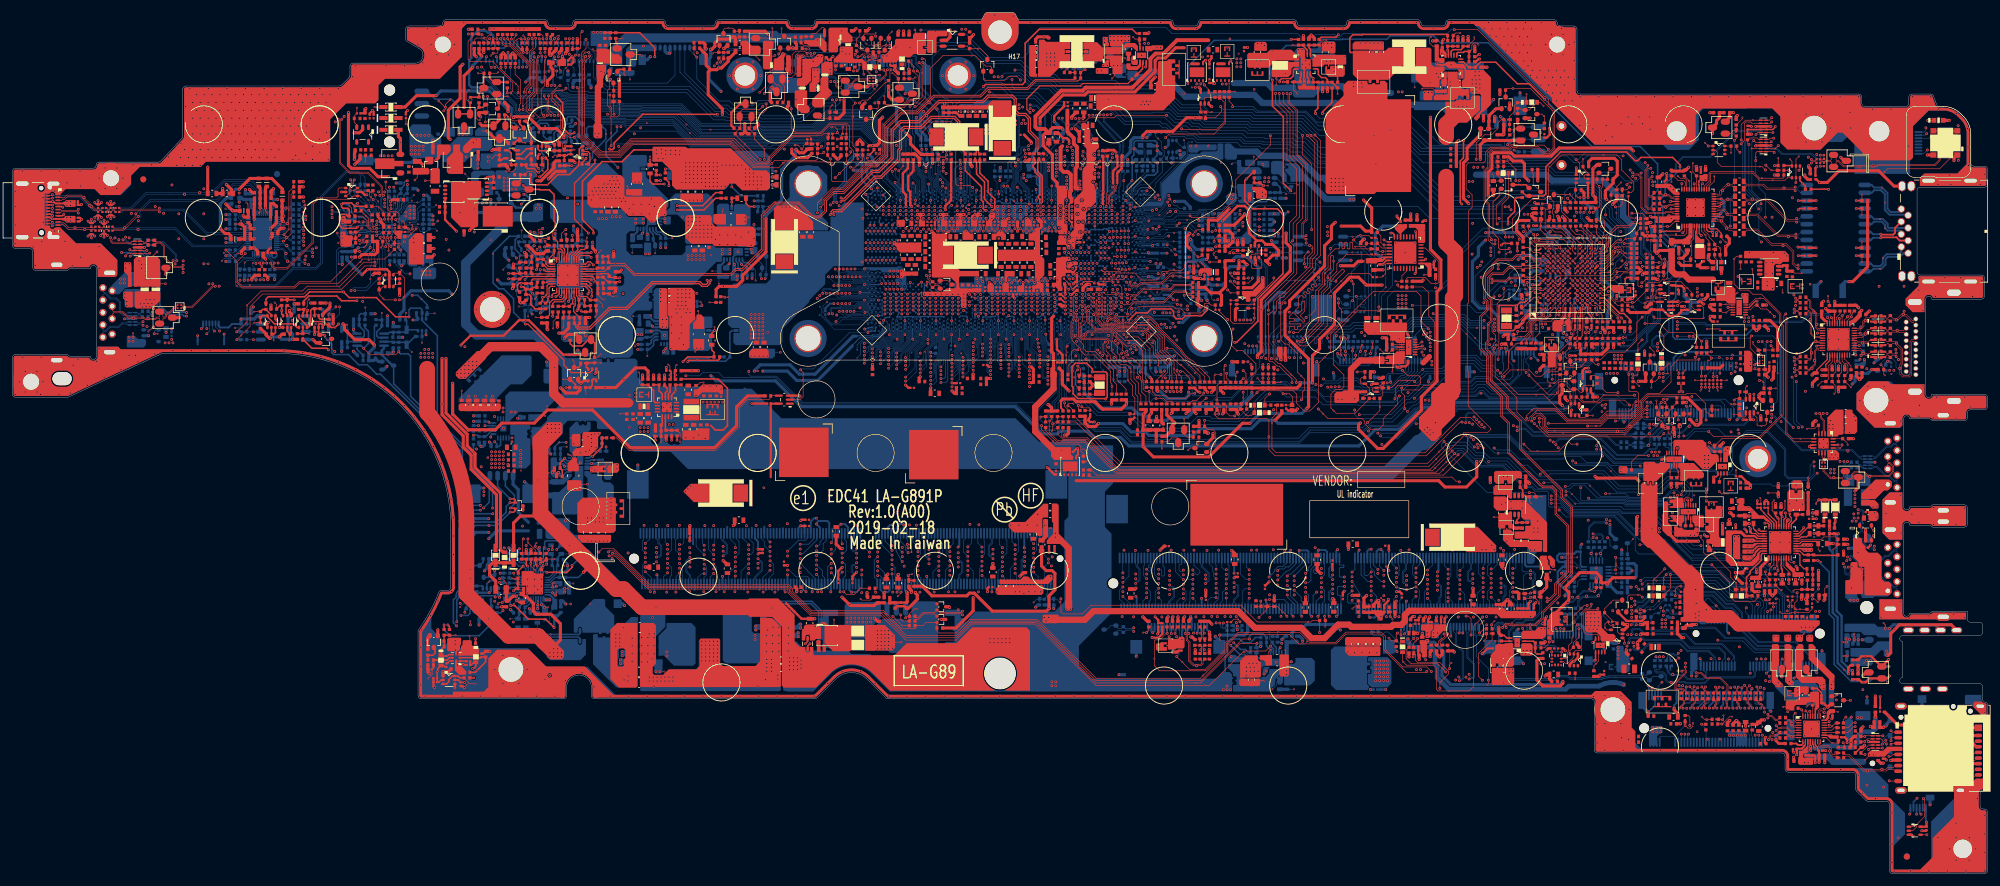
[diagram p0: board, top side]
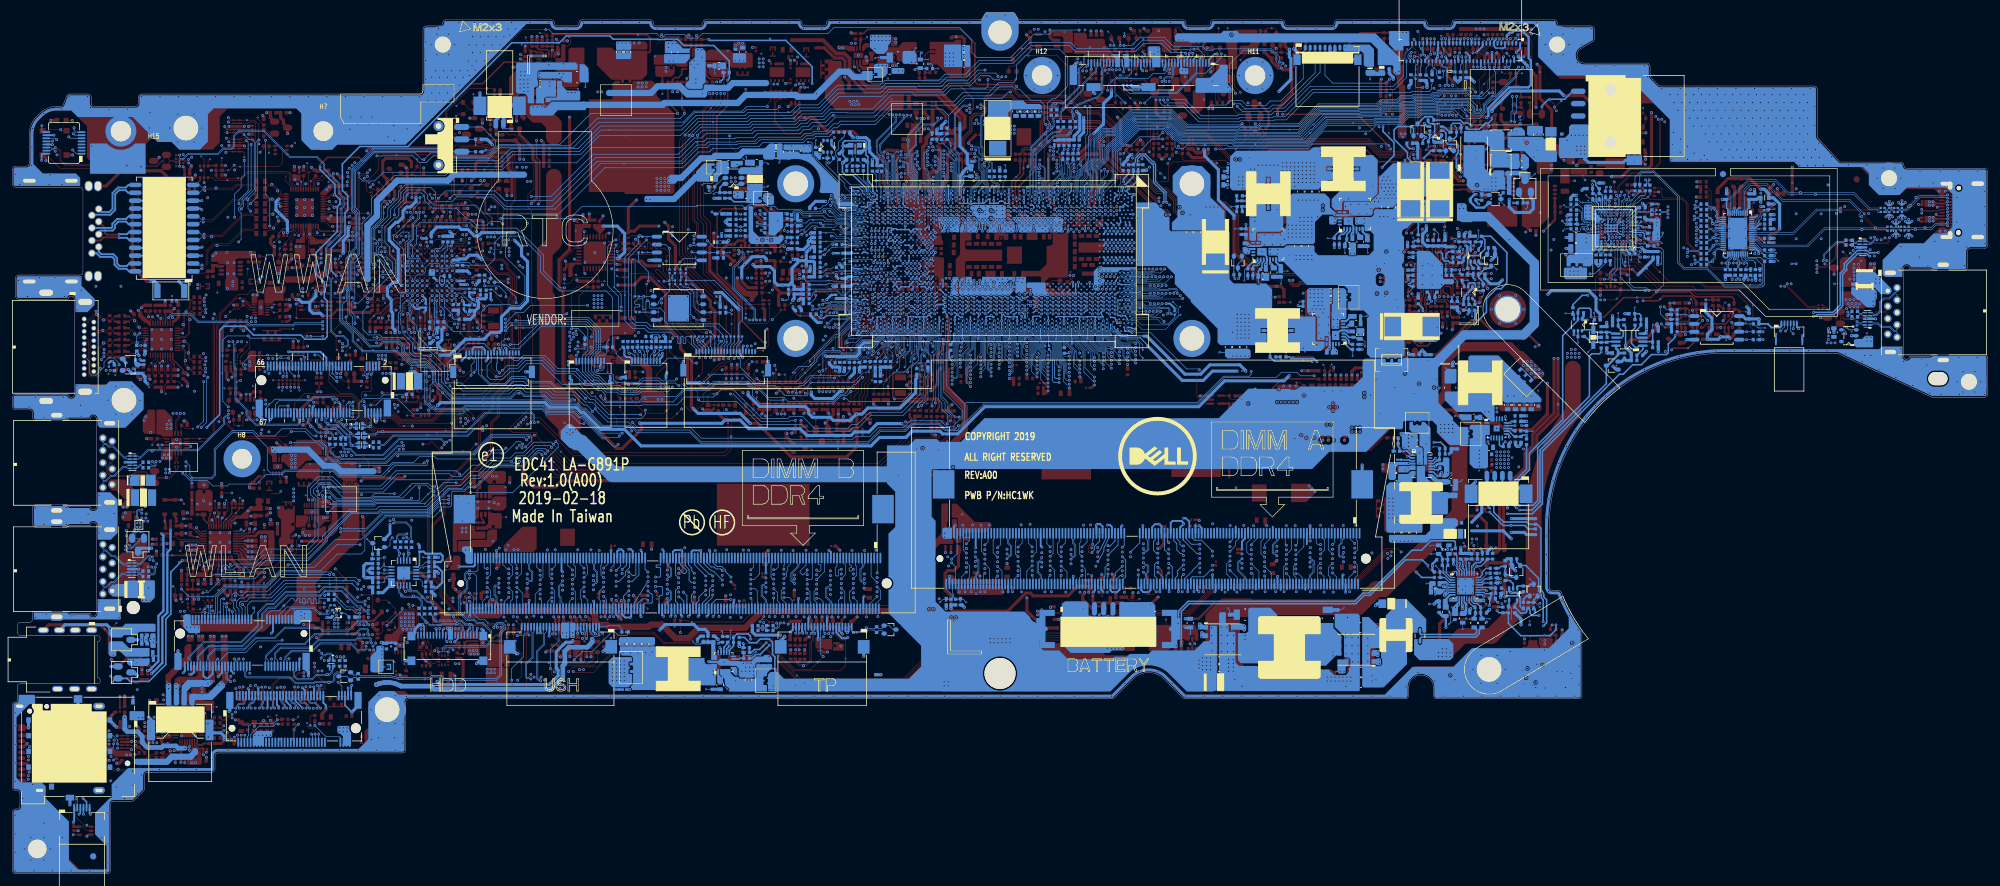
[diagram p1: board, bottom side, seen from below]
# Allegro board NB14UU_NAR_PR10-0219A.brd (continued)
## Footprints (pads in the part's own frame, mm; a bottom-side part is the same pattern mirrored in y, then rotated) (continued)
Y_8Y24000034_4P
  rect 0.889x0.787 smd: 1(0,0) 2(1.4,0) 3(1.4,1.1) 4(0,1.1)
Y_9H03200042_2P
  rect 0.991x1.803 smd: 1(0,0) 2(2.5,0)
Y_X1A000141000200_2P
  rect 0.991x1.803 smd: 1(0,0) 2(2.5,0)
Y_XRCGB25M000F2P18R0_4P
  rect 0.762x0.711 smd: 1(0,0) 2(1.35,0) 3(1.35,1) 4(0,1)
YUQIU_HD074-F19M1BR-C_19P-T
  round 0.787 hole 0.559: 1(0,0) 2(0.5,1.55) 3(1,0) 4(1.5,1.55) 5(2,0) 6(2.5,1.55) 7(3,0) 8(3.5,1.55) 9(4,0) 10(4.5,1.55) 11(5,0) 12(5.5,1.55) 13(6,0) 14(6.5,1.55) 15(7,0) 16(7.5,1.55) 17(8,0) 18(8.5,1.55) 19(9,0)
  oval 1.6x2.794 hole 0.991x2.21: 20(-2.75,0.15) 21(11.75,0.15) 22(-4.25,-6.15) 23(13.25,-6.15)

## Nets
0.6V_DDR_VTT_ON: PR210.1 RD19.1 UD1.4(Y)
0.6V_DDR_VTT_ON_R: PC222.1 PR210.2 PR212.1 PU200.2(S3)
1.0V_PRIM_PWRGD: PC350.1 PR313.1 PR314.1 PR315.2 PU301.9(PG) RE361.2
3.3V_CAM_EN#: RC834.1 RZ388.1 UC1.CC37(GPP_B11/EXT_PWR_GATE#)
3.3V_TS_EN: RE547.1 RV323.1 UE1.J7(GPIO223/SHD_IO0)
3.3V_WWAN_EN: RZ40.2 UE1.C6(GPIO165/32KHZ_IN/CTOUT0) UZ43.3(ON1)
3V5V_EN: PC128.1 PR114.2 PR116.1 PU100.12(EN1) PU102.12(EN1)
+0.6V_DDR_VTT: CD22.1 CD23.1 CD24.1 CD54.1 CD55.1 CD56.1 CD63.1 CD66.1 CD69.1 CD70.1 CD71.1 CD72.1 CD76.1 CD77.1 JDIMM1.258(VTT) JDIMM2.258(VTT) PJP201.2
+0.6VSP: PC219.1 PJP201.1 PU200.5(VTTSNS) PU200.6(VTT)
+0.9V_LAN: CL3.1 CL4.1 CL8.1 CL9.1 CL10.1 CL11.1 CL12.1 LL1.2 UL1.8(VDD0P9_8) UL1.11(VDD0P9_11) UL1.16(VDD0P9_16) UL1.22(VDD0P9_22) UL1.37(VDD0P9_37) UL1.40(VDD0P9_40) UL1.43(VDD0P9_43) UL1.46(VDD0P9_46) UL1.47(VDD0P9_47)
+1.0V_AMPHYPLL: CC69.1 CC80.1 CC102.1 CC104.1 LC3.2 RC173.2 UC1.BV2(VCCAMPHYPLL_1P05)
+1.0V_APLL: CC85.1 CC86.1 LC1.2 RC422.2 UC1.BR14(VCCAPLL_1P05_1) UC1.BR15(VCCAPLL_1P05_2) UC1.BT12(VCCAPLL_1P05_3) UC1.BU14(VCCAPLL_1P05_4)
+1.0V_CLK: CC70.1 CC83.1 CC100.1 CC103.1 LC2.2 RC175.2 UC1.CP5(VCCA_XTAL_1P05)
+1.0V_MPHYGT: CC71.1 LC3.1 PJP3.2 RC173.1 UC1.BV12(VCCPRIM_MPHY_1P05_1) UC1.BV14(VCCPRIM_MPHY_1P05_2) UC1.BW12(VCCPRIM_MPHY_1P05_3) UC1.BW14(VCCPRIM_MPHY_1P05_4) UC1.BY12(VCCPRIM_MPHY_1P05_5) UC1.BY14(VCCPRIM_MPHY_1P05_6)
+1.0V_PRIM: CC67.1 CC68.1 CZ100.1 CZ105.1 LC1.1 LC2.1 PJP3.1 PJP302.2 RC175.1 RC216.1 RC422.1 UC1.BP14(VCCA_BCLK_1P05) UC1.BP20(VCCPRIM_1P05_1) UC1.BP22(VCCPRIM_1P05_2) UC1.BR12(VCCA_19P2_1P05) UC1.BR20(VCCPRIM_1P05_3) UC1.BT18(VCCPRIM_1P05_4) UC1.BT19(VCCPRIM_1P05_5) UC1.BT22(VCCPRIM_1P05_6) UC1.BU12(VCCA_SRC_1P05) UC1.BU18(VCCPRIM_1P05_7) UC1.BU19(VCCPRIM_1P05_8) UC1.BW16(VCCPRIM_1P05_9) UC1.BW18(VCCPRIM_1P05_10) UC1.BW19(VCCPRIM_1P05_11) UC1.BY16(VCCPRIM_1P05_12) UC1.BY20(VCCPRIM_1P05_13) UC1.CA14(VCCPRIM_1P05_14) UC1.CC12(VCCDUSB_1P05) UZ19.1(VIN1) UZ19.2(VIN2) UZ19.7(VIN THERMAL) UZ21.1(VIN1) UZ21.2(VIN2) UZ21.7(VIN THERMAL)
+1.0V_PRIM_CORE: CC66.1 PJP402.2 UC1.BU15(VCCPRIM_CORE1) UC1.BU22(VCCPRIM_CORE2) UC1.BV15(VCCPRIM_CORE3) UC1.BV16(VCCPRIM_CORE4) UC1.BV18(VCCPRIM_CORE5) UC1.BV19(VCCPRIM_CORE6) UC1.BV20(VCCPRIM_CORE7) UC1.BV22(VCCPRIM_CORE8) UC1.BW20(VCCPRIM_CORE9) UC1.BW22(VCCPRIM_CORE10) UC1.CA12(VCCPRIM_CORE11) UC1.CA16(VCCPRIM_CORE12) UC1.CA18(VCCPRIM_CORE13) UC1.CA19(VCCPRIM_CORE14) UC1.CA20(VCCPRIM_CORE15) UC1.CB12(VCCPRIM_CORE16) UC1.CB14(VCCPRIM_CORE17) UC1.CB15(VCCPRIM_CORE18)
+1.0V_PRIM_COREP: PC415.1 PC424.1 PC427.1 PC428.1 PJP402.1 PL404.2 PR423.2 PU402.1(VOS)
+1.0V_PRIM_XDP: CC288.1 CC299.1 JXDP1.43 JXDP1.44 RC125.2 RC138.2 RC216.2
+1.0V_VCCST: CC28.1 CC1481.1 PC602.1 PJP1.1 PR601.1 PR604.1 PR605.1 RC71.2 RC154.1 RC156.1 RC158.1 RC218.1 RC219.1 RC235.2 RC864.2 RE59.1 RE90.1 RZ151.2 UC1.BP2(VCCST2) UC1.BP11(VCCST1)
+1.0V_VCCST_C: CZ101.1 PJP1.2 UZ21.6(VOUT)
+1.0V_VCCST_R: CC31.1 CC96.1 CC1462.1 RC864.1 UC1.BR11(VCCPLL1) UC1.BT11(VCCPLL2)
+1.0V_VCCSTG: CC29.1 PJP2.1 RC87.2 RC130.2 RC131.2 RC134.2 RC135.2 RC153.1 RC436.1 RC558.1 RC568.2 RC569.2 RZ151.1 UC1.BG1(VCCSTG1) UC1.BG2(VCCSTG2)
+1.0V_VCCSTG_C: CZ106.1 PJP2.2 UZ19.6(VOUT)
+1.0V_VCCSTG_R: RC153.2 UC1.BG3(VCCSTG1)
+1.0VS_VCCIO: CC39.1 CC40.1 CC41.1 CC42.1 CC51.1 CC52.1 CC234.1 CC235.1 CC236.1 CC237.1 CC1458.1 CC1459.1 CC1460.1 CC1461.1 PJP401.2 QE11.1(D) RC8.1 RC132.2 RC163.1 UC1.AK24(VCCIO1) UC1.AK26(VCCIO2) UC1.AL24(VCCIO3) UC1.AL25(VCCIO4) UC1.AL26(VCCIO5) UC1.AL27(VCCIO6) UC1.AM25(VCCIO7) UC1.AM27(VCCIO8) UC1.BH24(VCCIO9) UC1.BH25(VCCIO10) UC1.BH26(VCCIO11) UC1.BH27(VCCIO12) UC1.BJ24(VCCIO13) UC1.BJ26(VCCIO14) UC1.BP16(VCCIO15) UC1.BP18(VCCIO16)
+1.2V_DDRP: PC208.1 PC209.1 PC210.1 PC211.1 PC212.1 PC213.1 PC214.1 PC216.1 PC217.1 PC223.1 PC224.1 PC225.1 PJP200.1 PL201.2 PR204.1 PU200.7(VLDOIN) PU200.8(VDDQSNS)
+1.2V_LDO: CR5.1 CR6.1 CR7.1 UR1.10(AV12) UR1.14(DV12S)
+1.2V_MEM: CC32.1 CC33.1 CC34.1 CC35.1 CC36.1 CC37.1 CC38.1 CC45.1 CC46.1 CC195.1 CC1454.1 CC1455.1 CC1456.1 CC1457.1 CC1478.1 CC1479.1 CD1.1 CD2.1 CD3.1 CD4.1 CD5.1 CD6.1 CD7.1 CD8.1 CD9.1 CD10.1 CD11.1 CD12.1 CD13.1 CD14.1 CD15.1 CD16.1 CD17.1 CD32.1 CD33.1 CD34.1 CD35.1 CD36.1 CD37.1 CD38.1 CD39.1 CD40.1 CD41.1 CD42.1 CD43.1 CD44.1 CD45.1 CD46.1 CD47.1 CD48.1 CD49.1 CZ102.1 JDIMM1.12(DM0#/DBI0#) JDIMM1.33(DM1#/DBI1#) JDIMM1.54(DM2#/DBI2#) JDIMM1.75(DM3#/DBI3#) JDIMM1.96(DM8#/DBI8#) JDIMM1.111(VDD1) JDIMM1.112(VDD2) JDIMM1.117(VDD3) JDIMM1.118(VDD4) JDIMM1.123(VDD5) JDIMM1.124(VDD6) JDIMM1.129(VDD7) JDIMM1.130(VDD8) JDIMM1.135(VDD9) JDIMM1.136(VDD10) JDIMM1.141(VDD11) JDIMM1.142(VDD12) JDIMM1.147(VDD13) JDIMM1.148(VDD14) JDIMM1.153(VDD15) JDIMM1.154(VDD16) JDIMM1.159(VDD17) JDIMM1.160(VDD18) JDIMM1.163(VDD19) JDIMM1.178(DM4#/DBI4#) JDIMM1.199(DM5#/DBI5#) JDIMM1.220(DM6#/DBI6#) JDIMM1.241(DM7#/DBI7#) JDIMM2.12(DM0#/DBI0#) JDIMM2.33(DM1#/DBI1#) JDIMM2.54(DM2#/DBI2#) JDIMM2.75(DM3#/DBI3#) JDIMM2.96(DM8#/DBI8#) JDIMM2.111(VDD1) JDIMM2.112(VDD2) JDIMM2.117(VDD3) JDIMM2.118(VDD4) JDIMM2.123(VDD5) JDIMM2.124(VDD6) JDIMM2.129(VDD7) JDIMM2.130(VDD8) JDIMM2.135(VDD9) JDIMM2.136(VDD10) JDIMM2.141(VDD11) JDIMM2.142(VDD12) JDIMM2.147(VDD13) JDIMM2.148(VDD14) JDIMM2.153(VDD15) JDIMM2.154(VDD16) JDIMM2.159(VDD17) JDIMM2.160(VDD18) JDIMM2.163(VDD19) JDIMM2.178(DM4#/DBI4#) JDIMM2.199(DM5#/DBI5#) JDIMM2.220(DM6#/DBI6#) JDIMM2.241(DM7#/DBI7#) PJP200.2 RD11.1 RD15.1 RD28.1 RZ119.1 UC1.AD36(VDDQ1) UC1.AH32(VDDQ2) UC1.AH36(VDDQ3) UC1.AM36(VDDQ4) UC1.AN32(VDDQ5) UC1.AW32(VDDQ6) UC1.AY36(VDDQ7) UC1.BE32(VDDQ8) UC1.BH36(VDDQ9) UC1.R32(VDDQ10) UC1.Y36(VDDQ11) UD1.5(VCC) UZ27.1(VIN1) UZ27.2(VIN2) UZ27.7(VIN THERMAL)
+1.2V_RUN: CV310.1 CV311.1 CV312.1 CV313.1 CV314.1 LT601.1 LT602.1 LT603.1 LT604.1 LT605.1 PJP504.2 UV21.12(VDD4) UV21.19(VDD1) UV21.20(VDD2) UV21.31(VDD3) UV21.40(VDD5)
+1.2V_VDD_A1: CT611.1 CT612.1 CT627.1 LT604.2 UT9.13(VDD_A1)
+1.2V_VDD_A2: CT45.1 CT46.1 CT626.1 LT603.2 UT9.47(VDD_A2)
+1.2V_VDD_DM_D1: CT614.1 CT615.1 CT616.1 CT617.1 CT618.1 CT628.1 LT605.2 UT9.1(VDD_1) UT9.10(VDD_10) UT9.16(VDD_16) UT9.30(VDD_D1) UT9.38(VDD_38)
+1.2V_VDD_R1: CT44.1 CT48.1 CT625.1 LT602.2 UT9.6(VDD_R1)
+1.2V_VDD_R2: CT47.1 CT610.1 CT629.1 LT601.2 UT9.7(VDD_R2)
+1.05VALWP: PC307.1 PC308.1 PC309.1 PC310.1 PC311.1 PC318.1 PC319.1 PC320.1 PJP302.1 PL301.2 PR306.1
+1.8V_ALW_VTR3: CE21.1 PJP20.2 RE340.1 RE549.1 RE829.2 UE1.N5(VTR3)
+1.8V_PRIM: CC98.1 CC1464.1 CE22.1 PJP20.1 PJP502.2 QC8.2(G) QZ22.2(G) RC244.1 RC724.2 RC733.2 RC842.2 RZ132.1 RZ603.2 UC1.CC15(VCCPRIM_1P8_1) UC1.CC18(VCCPRIM_1P8_2) UC1.CC19(VCCPRIM_1P8_3) UC1.CD15(VCCPRIM_1P8_4) UC1.CD16(VCCPRIM_1P8_5) UC1.CD18(VCCPRIM_1P8_6) UC1.CD19(VCCPRIM_1P8_7) UC1.CP17(VCCPRIM_1P8_8) UC1.CP23(VCCPRIM_1P8_9) UZ8.1(VIN1) UZ8.2(VIN2)
+1.8V_RUN: CA65.1 CA66.1 PJP42.2 RA3.2
+1.8V_RUN_AUDIO: CA57.1 CA58.1 CA69.1 RA3.1 UA1.29(CPVDD) UA1.33(AVDD2)
+1.8V_RUN_CARD: CR19.2 CR20.2 JSD1.15(VDD2) UR1.13(SD_VDD2)
+1.8V_RUN_UZ46: CZ120.1 PJP42.1 UZ8.7(VOUT1) UZ8.8(VOUT2)
+1.8VALWP: PC501.1 PC503.1 PC504.1 PJP502.1 PL501.2 PR501.1
+1VS_VCCIOP: PC406.1 PC407.1 PC425.1 PC426.1 PJP401.1 PL402.2 PR421.1 PU401.1(VOS)
+2.5V_MEM: CD18.1 CD19.1 CD20.1 CD21.1 CD50.1 CD51.1 CD52.1 CD53.1 CD74.1 CD75.1 JDIMM1.257(VPP1) JDIMM1.259(VPP2) JDIMM2.257(VPP1) JDIMM2.259(VPP2) PJP506.2
+3.3V_ALW: CE16.1 CE52.1 CE53.1 CE59.1 CE60.1 CE61.1 CV17.1 CZ57.1 CZ58.1 CZ68.1 CZ73.1 CZ82.1 CZ91.1 CZ93.1 CZ314.1 CZ320.1 CZ321.1 CZ322.1 JAPS1.3 JAPS1.7 JKBTP1.6 JLED1.1 JUSH1.11 JUSH1.12 JUSH1.13 PC206.1 PC226.1 PC228.1 PC312.2 PC314.2 PJP22.1 PJP102.2 PJP404.1 PJP501.1 PJP505.1 PL406.1 PL502.1 PQ807.2(G) PR1.1 PR4.2 PR28.2 PR107.1 PR113.1 PR205.1 PR307.1 PR313.2 PR404.1 PR410.1 PR413.1 PR414.1 PR417.1 PR418.1 PR726.1 PR821.2 PR824.1 PR825.1 PR828.1 PR830.1 PR833.1 PR838.1 PR839.1 PR851.1 PR852.1 PR865.2 PU200.13(BYP) PU301.15(BYP) QC7.3(S) QZ18.3(S) RC68.2 RC214.2 RC431.2 RC432.1 RE8.2 RE10.2 RE11.2 RE12.2 RE21.2 RE25.1 RE35.2 RE37.2 RE43.2 RE63.2 RE68.2 RE69.1 RE71.1 RE72.1 RE73.1 RE74.1 RE75.1 RE79.1 RE83.2 RE84.2 RE91.2 RE92.2 RE300.1 RE302.2 RE303.2 RE343.1 RE362.2 RE365.2 RE505.2 RE526.2 RE532.2 RE561.2 RE605.2 RE606.2 RE704.2 RE714.1 RE715.1 RE719.1 RE720.1 RE721.2 RE722.2 RE723.2 RE724.2 RE725.2 RE726.2 RE727.2 RE728.2 RE729.2 RE730.2 RE821.2 RE826.1 RE828.2 RT68.2 RT398.1 RT483.1 RZ8.1 RZ9.1 RZ133.1 RZ377.1 RZ518.1 RZ1390.2 RZ1397.1 RZ1404.2 RZ1410.1 RZ1474.2 RZ1482.1 RZ1483.1 UE3.5(P) UE4.5(VCC) UE5.5(P) UV24.5(VIN) UZ3.1(VIN1_1) UZ3.2(VIN1_2) UZ3.6(VIN2_1) UZ3.7(VIN2_2) UZ10.5(P) UZ35.5(P) UZ41.5(P) UZ43.1(VIN1_1) UZ43.2(VIN1_2) UZ43.6(VIN2_1) UZ43.7(VIN2_2) UZ47.6(VIN2_1) UZ47.7(VIN2_2) UZ53.1(VIN1) UZ53.2(VIN2) UZ54.5(P)
+3.3V_ALW2: PR104.2 PR860.1 RE57.2
+3.3V_ALW_DSW: CC279.1 CC280.1 CC1463.1 RC67.2 RC72.2 RC214.1 RC241.2 RC323.2 RC439.1 RC440.1 RC555.2 UC1.BR24(VCCDSW_3P3_1) UC1.BT23(VCCDSW_3P3_2)
+3.3V_ALW_DSW_R: QC7.1(D) RC439.2
+3.3V_ALW_PCH: CC75.1 CZ216.1 DC4.2 JAPS1.1 JSPI1.16 LC4.1 PJP38.2 RC12.2 RC14.2 RC15.2 RC31.2 RC46.1 RC61.1 RC62.1 RC73.2 RC94.1 RC95.2 RC101.1 RC133.2 RC183.2 RC187.2 RC222.2 RC248.2 RC266.2 RC277.2 RC288.2 RC317.2 RC344.2 RC347.2 RC348.2 RC400.2 RC440.2 RC443.2 RC451.2 RC507.2 RC537.2 RC725.2 RC743.2 RC744.2 RC748.2 RC763.2 RC829.2 RC830.2 RC831.1 RC834.2 RC836.1 RC837.1 RC838.1 RC839.1 RC840.2 RC843.2 RC845.1 RC847.2 RC862.2 RC865.1 RC866.2 RZ69.1 RZ379.1 RZ1408.1 UC1.BP23(VCCPRIM_3P3_1) UC1.BV23(VCCSPI) UC1.BW23(VCCPRIM_3P3_2) UC1.CB16(VCCPRIM_3P3_3) UC1.CB22(VCCPRIM_3P3_4) UC1.CB23(VCCPRIM_3P3_5) UC1.CC22(VCCPRIM_3P3_6) UC1.CC23(VCCPRIM_3P3_7) UC1.CD22(VCCPRIM_3P3_8) UC1.CD23(VCCPRIM_3P3_9) UC1.CP29(VCCPRIM_3P3_10) UC7.5(P) UC9.5(P) UZ51.5(VCC)
+3.3V_ALW_PCH_U44: CZ112.1 CZ316.1 PJP38.1 UZ3.13(VOUT1_2) UZ3.14(VOUT1_1)
+3.3V_ALW_UE1: CE13.1 CE14.1 CE15.1 CE19.1 CE20.1 CE23.1 PJP22.2 RE314.2 UE1.B7(VTR_ANALOG) UE1.G8(VTR1) UE1.H1(VTR_REG) UE1.K2(VREF_ADC) UE1.M9(VTR2)
+3.3V_ALW_UZ12: CZ51.1 CZ52.1 RZ1410.2 UZ12.1(NIC_1)
+3.3V_ALWP: PC106.1 PC107.1 PC108.1 PC109.1 PC110.1 PC129.1 PC135.1 PC136.1 PC161.1 PC162.1 PJP102.1 PL100.2 PR108.2 PU100.14(OUT)
+3.3V_CAM: CV22.1 CV23.1 CV31.1 CZ202.1 FZ5.2 JEDP1.11 RZ1485.2
+3.3V_CAM_F: FZ5.1 QZ1.1(D) RZ1485.1
+3.3V_CPS: CT117.1 CT118.1 LT11.2 UT9.27(VDD33_27) UT9.52(VDD33_52)
+3.3V_EC_PLL: CE17.1 CE18.1 RE314.1 UE1.F1(VTR_PLL)
+3.3V_FPBTN: CZ309.1 DT42.2 DT42.8 JFPBTN1.14 QE20.2(G) QZ18.1(D) RE706.2 RE707.2 RE708.2 RE709.1 RZ1390.1 RZ1391.1 RZ1392.2
+3.3V_HDD: CN10.1 CN11.1 CN16.1 CN17.1 JSATA1.9 JSATA1.10 PJP34.2 RN3.1 RN6.1 RN8.2 RN10.2 RN12.1 RN14.1 RN16.1 RN18.1 RN20.1 UN7.10(VDD1) UN7.20(VDD2)
+3.3V_HDD_M2: CN60.1 CN61.1 CN62.1 CN63.1 CN64.1 CN77.1 CN79.1 CN80.1 CN81.1 CN82.1 CN84.1 CN86.1 CN87.1 CN88.1 CN89.1 JNGFF3.2(3P3VAUX1) JNGFF3.4(3P3VAUX2) JNGFF3.12(3P3VAUX3) JNGFF3.14(3P3VAUX4) JNGFF3.16(3P3VAUX5) JNGFF3.18(3P3VAUX6) JNGFF3.70(3P3VAUX7) JNGFF3.72(3P3VAUX8) JNGFF3.74(3P3VAUX9) LC9.1 PJP31.1 RN37.1 RN131.1
+3.3V_LAN: CL18.1 CL19.1 JLOM1.A1(YELLOW LED+) JLOM1.B1(GREEN LED+) LC10.2 PJP37.2 RC20.2 RC506.2 RL1.2 RL2.2 RL4.2 RL5.2 RL6.2 RL8.2 RL29.1 RL70.2
+3.3V_LAN_OUT: CL7.1 CL28.1 CL29.1 CL30.1 RL8.1 UL1.4(VDD3P3_4) UL1.5(VDD3P3_IN) UL1.15(VDD3P3_15) UL1.19(VDD3P3_19) UL1.29(VDD3P3_29)
+3.3V_LAN_UZ43: CZ310.1 LC10.1 PJP37.1 UZ43.8(VOUT2_2) UZ43.9(VOUT2_1)
+3.3V_MMI_AUX: CR1.1 CR2.1 CR27.1 CR28.1 RR3.1 RR19.2 RR20.2 UR1.27(3V3AUX)
+3.3V_MMI_IN: CR3.1 CR4.1 CR25.1 CR26.1 PJP14.2 RR20.1 UR1.11(3V3_IN)
+3.3V_PDA_VOUT: CT83.1 UT5.H2(VOUT_3V3)
+3.3V_RTC_LDO: PD3.3 PR105.2 RA53.2
+3.3V_RUN: CA7.1 CA75.1 CN1.1 CN2.1 CN3.1 CN75.1 CN90.1 CN91.1 CN92.1 CN93.1 CN94.1 CN95.1 CV308.1 CV309.1 CZ67.1 CZ72.1 CZ313.1 FZ3.2 JESPI.1 JESPI.2 LC8.2 LC9.2 LC12.2 LGA1.2(CS) LGA1.3(SDO/SA0) LGA1.9(VDD) LGA1.10(VDD_IO) LZ4.1 PJP14.1 PJP18.1 PJP31.2 PJP34.1 PJP35.1 PJP39.2 PJP503.2 PR612.1 QC2.2(G2) QC2.5(G1) QT10.2(G2) QT10.5(G1) QV20.3 RC51.2 RC58.2 RC82.1 RC104.1 RC137.2 RC176.2 RC178.2 RC189.2 RC278.2 RC279.2 RC292.2 RC318.2 RC319.2 RC345.1 RC362.2 RC363.2 RC437.2 RC438.2 RC502.2 RC503.2 RC522.2 RC523.2 RC525.2 RC567.2 RC726.1 RC731.1 RC747.2 RC749.2 RC764.1 RC765.1 RC766.1 RC841.2 RC849.2 RD4.1 RD6.1 RD8.1 RD10.1 RD19.2 RD20.1 RD22.1 RD24.1 RD26.1 RE48.1 RE51.1 RE67.2 RE547.2 RN2.1 RN4.1 RN226.1 RT397.1 RV8.2 RV98.1 RV99.1 RV207.1 RV208.1 RV300.1 RV302.1 RV304.1 RV311.1 RV326.1 RV732.2 RV734.1 RV736.2 RZ89.1 RZ362.1 RZ1391.2 RZ1403.2 RZ1409.1 RZ1422.2 RZ1486.2 UV21.11(VDD6) UV21.37(VDD7) UZ5.6(VIN2_1) UZ5.7(VIN2_2)
+3.3V_RUN_AUDIO: CA67.1 CA68.1 LA12.2 LA14.2 PJP16.2 PJP18.2 RA18.2 RA59.1
+3.3V_RUN_AUDIO_DVDD: CA10.1 CA61.1 LA14.1 UA1.1(DVDD)
+3.3V_RUN_AUDIO_IO: CA55.1 CA56.1 LA12.1 UA1.8(DVDD-IO)
+3.3V_RUN_AUDIO_UZ5: CZ128.1 PJP16.1 UZ5.8(VOUT2_1) UZ5.9(VOUT2_2)
+3.3V_RUN_CARD: CR17.2 CR18.2 JSD1.4(VDD1) UR1.12(CARD_3V3)
+3.3V_RUN_DIMM1: CD27.1 CD28.1 CD73.1 JDIMM1.255(VDDSPD) RD10.2
+3.3V_RUN_DIMM2: CD59.1 CD60.1 JDIMM2.255(VDDSPD) RD26.2
+3.3V_RUN_F: FZ3.1 FZ4.1 QZ1.3(S) RZ1484.1 RZ1486.1
+3.3V_RUN_QZ1: FZ4.2 JEDP1.10 RZ1484.2
+3.3V_RUN_UT9: LT11.1 RT131.2 RT135.2 RT137.2 RT139.2 RT141.2 RT246.1 RT303.1 RT304.2 RT305.2 RT308.2 RT397.2 RT398.2
+3.3V_RUN_UZ44: CZ115.1 CZ315.1 LC8.1 LC12.1 PJP39.1 UZ3.8(VOUT2_2) UZ3.9(VOUT2_1)
+3.3V_SPI: CC9.1 CC10.1 DC4.1 JSPI1.15 RC31.1 UC5.8(VCC) UC6.8(VCC)
+3.3V_SSD: CZ305.1 RN131.2 UZ53.7(VOUT1) UZ53.8(VOUT2)
+3.3V_TBTA_FLASH: CT70.1 CT84.1 JDB1.1 RT50.1 RT51.1 RT52.1 RT53.1 RT66.2 RT67.2 RT76.2 RT95.2 RT98.2 RT106.2 RT107.2 RT378.2 RT379.2 RT399.1 UT5.G1(LDO_3V3) UT6.8(VCC)
+3.3V_TP: CZ83.1 CZ90.1 JKBTP1.12 PJP35.2 RZ18.1 RZ19.1 RZ20.1 RZ21.1 RZ116.1 RZ117.1
+3.3V_VDD_DCI: CT119.1 RT303.2 UT9.49(VDD_DCI)
+3.3V_VDD_DCIN: PC10.1 PC12.1 PC3002.1 PD800.3(1) PD3000.2 PR17.1 PR27.2 PR33.1 PR47.1 PR806.1 PR809.1 PR832.1 PR866.1 PR3002.1 PU2.3(VOUT) PU3000.8(VCC)
+3.3V_VDD_PIC: PD800.2 PR810.1 PR813.1 PR822.1 PR859.1 QT1.2(G2) QT1.5(G1) RT399.2 RT420.2 RT482.1
+3.3V_VDD_PIC_PDA: CT74.1 RT482.2 RT483.2 UT5.B1(VDDIO) UT5.H1(VIN_3V3)
+3.3V_VDD_PIC_R: CT91.1 CT92.1 RT420.1 UT7.5(VOUT)
+3.3V_VPS_UZ12: CZ53.1 CZ54.1 CZ55.1 RZ1408.2 RZ1409.2 UZ12.14(NIC_11) UZ12.22(VPS)
+3.3V_WLAN: CZ27.1 CZ28.1 CZ29.1 CZ30.1 CZ31.1 CZ32.1 CZ33.1 CZ34.1 CZ35.1 CZ36.1 CZ204.1 CZ205.1 CZ206.1 CZ207.1 CZ317.1 CZ318.1 CZ319.1 JNGFF1.2(3.3VAUX_1) JNGFF1.4(3.3VAUX_2) JNGFF1.72(3.3VAUX_3) JNGFF1.74(3.3VAUX_4) PJP36.2 RZ96.2
+3.3V_WLAN_UZ47: CZ122.1 PJP36.1 RZ96.1 UZ47.8(VOUT2_2) UZ47.9(VOUT2_1)
+3.3V_WWAN: CZ17.1 CZ18.1 CZ19.1 CZ20.1 CZ21.1 CZ23.1 CZ24.1 CZ25.1 CZ26.1 JNGFF2.2(3.3V_2) JNGFF2.4(3.3V_4) JNGFF2.62(3.3V_62) JNGFF2.64(3.3V_64) JNGFF2.66(3.3V_66) PJP41.2 RZ43.2 RZ1400.2
+3.3V_WWAN_UZ43: CZ119.1 CZ124.1 PJP41.1 UZ43.13(VOUT1_2) UZ43.14(VOUT1_1)
+5V_ALW: CI6.1 CI7.1 CI11.1 CI12.1 CI19.1 CI31.1 CI33.1 CI34.1 CZ64.1 CZ69.1 CZ311.1 DT1.2 JLED1.6 JUSH1.9 JUSH1.10 LED3.2(ANODE) PC410.1 PC414.1 PC416.1 PC661.1 PC668.1 PC685.1 PC697.1 PJP8.1 PJP103.2 PJP403.1 PL405.1 PR7.1 PR602.2 PR615.2 PR634.2 PR680.1 PR688.1 PR691.1 PU610.15(PVCC) PU612.15(PVCC) PU613.15(PVCC) PU614.6(VCC) RI13.2 UI1.5(IN) UI2.5(IN) UI3.1(VIN) UI3.7(CTL2) UI3.8(CTL3) UZ3.4(VBIAS) UZ5.4(VBIAS) UZ8.4(VBIAS) UZ19.3(VBIAS) UZ21.3(VBIAS) UZ23.1(VIN_1) UZ23.2(VIN_2) UZ23.4(VBIAS) UZ27.3(VBIAS) UZ43.4(VBIAS) UZ47.1(VIN1_1) UZ47.2(VIN1_2) UZ47.4(VBIAS) UZ53.4(VBIAS)
+5V_ALW2: PC126.1 PU102.15(LDO)
+5V_ALW_PDA: CT22.1 CT75.1 CT76.1 CT77.1 CT78.1 PJP8.2 UT5.A11(PP1) UT5.B11(PP2) UT5.C11(PP3) UT5.D11(PP4) UT5.H10(PP_CABLE)
+5V_ALWP: PC120.1 PC121.1 PC122.1 PC123.1 PC124.1 PC130.1 PC137.1 PC138.1 PC145.1 PC163.1 PC164.1 PJP103.1 PL101.2 PR117.2 PU102.14(OUT)
+5V_HDD: CN8.1 CN9.1 CN78.1 JSATA1.15 JSATA1.16 JSATA1.17 PJP32.2 PJP33.1 RN1.1 RZ102.2
+5V_HDD_UZ23: CZ129.1 PJP32.1 RZ102.1 UZ23.7(VOUT_1) UZ23.8(VOUT_2)
+5V_PD_VDD: CT88.1 CT89.1 DT1.1 DT2.1 RT111.1 RT393.1 UT7.1(VCC)
+5V_RUN: CE32.1 CV653.1 CZ66.1 CZ71.1 CZ92.1 CZ312.1 DE1.1 JFAN1.4 JKBTP1.5 LZ3.1 PJP17.1 PJP33.2 PJP40.2 RV6.2 RV733.2 UV2.1(IN) UZ5.1(VIN1_1) UZ5.2(VIN1_2)
+5V_RUN_AUDIO: CA59.1 CA60.1 CA63.1 CA64.1 LA5.2 LA13.2 PJP15.1 PJP17.2
+5V_RUN_AUDIO_UZ5: CZ125.1 PJP15.2 UZ5.13(VOUT1_1) UZ5.14(VOUT1_2)
+5V_RUN_PVDD_L: CA45.1 CA46.1 CA47.1 CA48.1 LA13.1 UA1.34(PVDD1) UA1.39(PVDD2)
+5V_RUN_UZ47: CZ116.1 PJP40.1 UZ47.13(VOUT1_2) UZ47.14(VOUT1_1)
+5V_TBT_VBUS: CT93.1 DT2.2 DT3.1
+5V_TBTA_VBUS_D: DT3.2 UT8.3(VOUT)
+5V_USB_CHG_PWR: CI14.1 CI17.1 CI32.1 CI43.1 CI44.1 JUSB1.1(VBUS) UI3.12(VOUT)
+13.2VB_BATT: PL1.2 PL2.2 PQ702.5(D) PR738.2
+13.2VB_PBATT_C: PBATT1.1 PBATT1.2 PBATT1.3 PC1.1 PL1.1 PL2.1
+13.5VB: CV13.2 CZ3.1 FZ1.2 LC11.1 PC141.1 PC142.1 PC146.1 PC315.1 PC316.1 PC317.1 PC332.1 PC333.1 PC334.1 PC335.1 PC689.1 PC690.1 PC691.1 PC692.1 PC707.1 PC708.1 PC709.1 PC710.1 PC715.1(P) PC720.1 PC721.1 PC728.1 PC729.1 PC730.1 PC731.1 PC732.1 PC733.1 PC734.1 PC735.1 PC760.1 PC761.1 PD702.2 PD3000.3(1) PJP100.1 PJP101.1 PJP202.1 PJP301.1 PJP601.2 PJP603.2 PL602.2 PQ701.3(D1_1) PQ701.4(D1_2) PQ701.9(D1_3) PR102.2 PR711.1 PR721.2 PR3006.1 QV1.4(S) RV4.2
+13.5VB_1.05VALWP: PC301.1 PC303.1 PC305.1 PC306.1 PC330.1 PC331.1 PC336.2 PC337.2 PC338.2 PC339.2 PJP301.2 PU301.2(IN1) PU301.3(IN2) PU301.4(IN3) PU301.5(IN4)
+13.5VB_3V: PC100.1 PC103.1 PC104.1 PC105.1 PC131.1 PC133.1 PC134.1 PC143.1 PJP100.2 PU100.2(IN1) PU100.3(IN2) PU100.4(IN3) PU100.5(IN4)
+13.5VB_5V: PC115.1 PC116.1 PC117.1 PC118.1 PC132.1 PC139.1 PC140.1 PJP101.2 PU102.2(IN1) PU102.3(IN2) PU102.4(IN3) PU102.5(IN4)
+13.5VB_CPU: PC606.1(P) PC607.1(P) PC656.1 PC657.1 PC658.1 PC659.1 PC660.1 PC672.1 PC673.1 PC682.1 PC683.1 PC684.1 PC686.1 PC688.1 PC693.1 PC694.1 PC1627.1(P) PJP601.1 PJP602.2 PL602.1 PR603.2 PU610.8(VIN1) PU610.9(VIN2) PU613.8(VIN1) PU613.9(VIN2)
+13.5VB_DDR: PC200.1 PC201.1 PC202.1 PC203.1 PJP202.2 PU200.10(IN)
+13.5VB_FU: FZ1.1 LC6.2
+13.5VB_IR: JIRTS1.9 JIRTS1.10 LC6.1
+13.5VB_L: CV755.1 CV756.1 LC11.2 QV18.3
+13.5VB_VCCGT: PC664.1 PC665.1 PC666.1 PC667.1 PC674.1 PC675.1 PC687.1 PJP602.1 PU612.8(VIN1) PU612.9(VIN2)
+13.5VB_VCCSA: PC608.1 PC612.1 PJP603.1 PQ614.2(D1_1) PQ614.3(D1_2) PQ614.4(D1_3) PQ614.10(D1)
+13.5VB_VCHGR: PC741.1 PC742.1 PQ702.1(S1) PQ702.2(S2) PQ702.3(S3) PR711.4
+19.5V_AC: PD701.1 PJP700.1 PL700.1 PR700.4
+19.5V_CHARGER: PC700.1 PC701.1 PC702.1 PC703.1 PC704.1 PC706.1 PC716.1 PC717.1 PC756.1 PJP700.2 PL700.2 PQ700.3(D1_1) PQ700.4(D1_2) PQ700.9(D1_3)
+19.5V_DC_IN: PC6.1 PC7.1 PL4.2 PQ9.1(S1) PQ9.2(S2) PQ9.3(S3) PQ11.3(S) PR12.1 PR13.1 PR31.1 PR800.1 PR892.2
+19.5V_DC_IN_SS: PC8.1 PD5.2 PD5.3 PD700.2 PQ4.5(D) PQ9.5(D) PR14.1
+19.5V_DCIN_JACK: PC5.1 PJPDC1.2 PJPDC1.3 PL4.1
+19.5V_SDC_IN: PC4.1 PC802.1 PD5.1 PD801.1 PQ4.1(S1) PQ4.2(S2) PQ4.3(S3) PQ5.3(S) PQ801.1(S1) PQ801.2(S2) PQ801.3(S3) PQ805.3(S) PR10.1 PR11.1 PR700.1 PR703.1 PR705.1 PR802.1 PR804.1
+20V_LDO_INPUT: PC11.1 PD803.1(3) PU2.1(VCC)
+20V_TBTA_VBUS: CT99.1 CT100.2 CT101.1 CT102.2 CT189.1 CT190.1 DT4.2 DT4.3 JUSBC1.A4(VBUS_1) JUSBC1.A9(VBUS_2) JUSBC1.B4(VBUS_3) JUSBC1.B9(VBUS_4) PC806.1 PC807.1 PL800.1 PL801.1
+20V_TBTA_VBUS_1: CT82.1 CT94.1 PC803.1 PC808.1 PC809.1 PL800.2 PL801.2 PQ800.1(S1) PQ800.2(S2) PQ800.3(S3) PQ803.3(S) PR801.1 PR803.1 PR823.1 PR831.1 PR893.2 UT5.A10(SENSEN) UT5.B10(SENSEP) UT5.H11(VBUS1) UT5.J10(VBUS2) UT5.J11(VBUS3) UT5.K11(VBUS4) UT8.1(VCC)
+20V_VBUS_DC_SS: PD704.2 PD801.2 PD801.3 PQ800.5(D) PQ801.5(D) PR862.1 PR870.1
+DV33_18: CR22.1 UR1.18(DV33_18)
+GND_CHASSIS: CL22.2 RL15.2 RL16.2 RL17.2 RL18.2
+VCC1V8A_TBTA_LDO: CT73.1 UT5.K1(LDO_1V8A)
+VCC1V8D_TBTA_LDO: CT72.1 RT97.1 UT5.A2(LDO_1V8D)
+VCC_CORE: PC1000.1 PC1001.1 PC1002.1 PC1003.1 PC1004.1 PC1005.1 PC1006.1 PC1007.1 PC1008.1 PC1009.1 PC1011.1 PC1012.1 PC1013.1 PC1014.1 PC1015.1 PC1016.1 PC1017.1 PC1018.1 PC1019.1 PC1020.1 PC1031.1 PC1032.1 PC1033.1 PC1034.1 PC1035.1 PC1036.1 PC1037.1 PC1038.1 PC1039.1 PC1040.1 PC1041.1 PC1042.1 PC1043.1 PC1044.1 PC1045.1 PC1046.1 PC1047.1 PC1048.1 PC1049.1 PC1050.1 PC1051.1 PC1052.1 PC1053.1 PC1054.1 PC1055.1 PC1056.1 PC1057.1 PC1058.1 PC1059.1 PC1060.1 PC1061.1 PC1062.1 PC1063.1 PC1064.1 PC1065.1 PC1066.1 PC1067.1 PC1068.1 PC1069.1 PC1070.1 PC1071.1 PC1072.1 PC1073.1 PC1074.1 PC1075.1 PC1076.1 PC1077.1 PC1078.1 PC1079.1 PC1080.1 PC1081.1 PC1082.1 PC1083.1 PC1084.1 PC1085.1 PC1086.1 PC1087.1 PC1088.1 PC1089.1 PC1090.1 PC1091.1(P) PC1092.1(P) PC1093.1(P) PC1094.1(P) PC1096.1 PC1097.1 PC1098.1 PC1099.1 PC1100.1 PC1200.1 PC1201.1 PC1202.1 PL610.1 PL613.1 PR3004.1 RC150.1 UC1.AA9(VCCGT11/VCCCORE75) UC1.AB2(VCCGT13/VCCCORE76) UC1.AB8(VCCGT14/VCCCORE77) UC1.AB9(VCCGT15/VCCCORE78) UC1.AB10(VCCGT12/VCCCORE79) UC1.AC8(VCCGT16/VCCCORE80) UC1.AD9(VCCGT17/VCCCORE81) UC1.AE8(VCCGT19/VCCCORE82) UC1.AE9(VCCGT20/VCCCORE83) UC1.AE10(VCCGT18/VCCCORE84) UC1.AF2(VCCGT22/VCCCORE85) UC1.AF8(VCCGT23/VCCCORE86) UC1.AF10(VCCGT21/VCCCORE87) UC1.AG8(VCCGT24/VCCCORE88) UC1.AG9(VCCGT25/VCCCORE89) UC1.AH9(VCCGT26/VCCCORE90) UC1.AJ8(VCCGT28/VCCCORE91) UC1.AJ10(VCCGT27/VCCCORE92) UC1.AK2(VCCGT29//VCCCORE93) UC1.AK9(VCCGT30/VCCCORE94) UC1.AL8(VCCGT32/VCCCORE95) UC1.AL9(VCCGT33/VCCCORE96) UC1.AL10(VCCGT31/VCCCORE97) UC1.AM8(VCCGT34/VCCCORE98) UC1.AN9(VCCCORE5) UC1.AN10(VCCCORE1) UC1.AN24(VCCCORE2) UC1.AN26(VCCCORE3) UC1.AN27(VCCCORE4) UC1.AP2(VCCCORE6) UC1.AP9(VCCCORE9) UC1.AP24(VCCCORE7) UC1.AP26(VCCCORE8) UC1.AR5(VCCCORE13) UC1.AR6(VCCCORE14) UC1.AR7(VCCCORE15) UC1.AR8(VCCCORE16) UC1.AR10(VCCCORE10) UC1.AR25(VCCCORE11) UC1.AR27(VCCCORE12) UC1.AT9(VCCCORE19) UC1.AT24(VCCCORE17) UC1.AT26(VCCCORE18) UC1.AU5(VCCCORE24) UC1.AU6(VCCCORE25) UC1.AU7(VCCCORE26) UC1.AU8(VCCCORE27) UC1.AU9(VCCCORE28) UC1.AU24(VCCCORE20) UC1.AU25(VCCCORE21) UC1.AU26(VCCCORE22) UC1.AU27(VCCCORE23) UC1.AV2(VCCCORE30) UC1.AV5(VCCCORE32) UC1.AV7(VCCCORE33) UC1.AV10(VCCCORE29) UC1.AV27(VCCCORE31) UC1.AW5(VCCCORE39) UC1.AW6(VCCCORE40) UC1.AW7(VCCCORE41) UC1.AW8(VCCCORE42) UC1.AW9(VCCCORE43) UC1.AW10(VCCCORE34) UC1.AW24(VCCCORE35) UC1.AW25(VCCCORE36) UC1.AW26(VCCCORE37) UC1.AW27(VCCCORE38) UC1.AY24(VCCCORE44) UC1.AY26(VCCCORE45) UC1.BA5(VCCCORE48) UC1.BA7(VCCCORE49) UC1.BA8(VCCCORE50) UC1.BA25(VCCCORE46) UC1.BA27(VCCCORE47) UC1.BB2(VCCCORE51) UC1.BB26(VCCCORE52) UC1.BC5(VCCCORE56) UC1.BC6(VCCCORE57) UC1.BC7(VCCCORE58) UC1.BC9(VCCCORE59) UC1.BC10(VCCCORE53) UC1.BC26(VCCCORE54) UC1.BC27(VCCCORE55) UC1.BD5(VCCCORE63) UC1.BD8(VCCCORE64) UC1.BD10(VCCCORE60) UC1.BD25(VCCCORE61) UC1.BD27(VCCCORE62) UC1.BE9(VCCCORE69) UC1.BE24(VCCCORE65) UC1.BE25(VCCCORE66) UC1.BE26(VCCCORE67) UC1.BE27(VCCCORE68) UC1.BF2(VCCCORE70) UC1.BF9(VCCCORE73) UC1.BF24(VCCCORE71) UC1.BF26(VCCCORE72) UC1.BG27(VCCCORE74) UC1.V2(VCCGT115/VCCCORE99) UC1.Y8(VCCGT120/VCCCORE101) UC1.Y10(VCCGT119/VCCCORE100)
+VCC_CORE_G0: T371.1 UC1.BB9(RSVD3)
+VCC_CORE_G1: T372.1 UC1.BC24(RSVD4)
+VCC_CORE_G2: T373.1 UC1.AY9(RSVD1)
+VCC_CORE_G3: T374.1 UC1.BB24(RSVD2)
+VCC_GT: PC1101.1 PC1102.1 PC1103.1 PC1104.1 PC1105.1 PC1106.1 PC1107.1 PC1108.1 PC1109.1 PC1110.1 PC1111.1 PC1112.1 PC1113.1 PC1114.1 PC1115.1 PC1116.1 PC1117.1 PC1118.1 PC1119.1 PC1120.1 PC1121.1 PC1122.1 PC1123.1 PC1131.1 PC1132.1 PC1133.1 PC1134.1 PC1135.1 PC1136.1 PC1137.1 PC1138.1 PC1139.1 PC1140.1 PC1141.1 PC1142.1(P) PC1143.1(P) PC1146.1 PC1147.1 PL612.1 RC160.1 UC1.A5(VCCGT8) UC1.A6(VCCGT9) UC1.A8(VCCGT10) UC1.A11(VCCGT1) UC1.A12(VCCGT2) UC1.A14(VCCGT3) UC1.A15(VCCGT4) UC1.A17(VCCGT5) UC1.A18(VCCGT6) UC1.A20(VCCGT7) UC1.B3(VCCGT39) UC1.B4(VCCGT40) UC1.B6(VCCGT41) UC1.B8(VCCGT42) UC1.B11(VCCGT35) UC1.B14(VCCGT36) UC1.B17(VCCGT37) UC1.B20(VCCGT38) UC1.C2(VCCGT49) UC1.C3(VCCGT51) UC1.C6(VCCGT52) UC1.C7(VCCGT53) UC1.C8(VCCGT54) UC1.C11(VCCGT43) UC1.C12(VCCGT44) UC1.C14(VCCGT45) UC1.C15(VCCGT46) UC1.C17(VCCGT47) UC1.C18(VCCGT48) UC1.C20(VCCGT50) UC1.D4(VCCGT62) UC1.D7(VCCGT63) UC1.D11(VCCGT55) UC1.D12(VCCGT56) UC1.D14(VCCGT57) UC1.D15(VCCGT58) UC1.D17(VCCGT59) UC1.D18(VCCGT60) UC1.D20(VCCGT61) UC1.E4(VCCGT64) UC1.F5(VCCGT69) UC1.F6(VCCGT70) UC1.F7(VCCGT71) UC1.F8(VCCGT72) UC1.F11(VCCGT65) UC1.F14(VCCGT66) UC1.F17(VCCGT67) UC1.F20(VCCGT68) UC1.G11(VCCGT73) UC1.G12(VCCGT74) UC1.G14(VCCGT75) UC1.G15(VCCGT76) UC1.G17(VCCGT77) UC1.G18(VCCGT78) UC1.G20(VCCGT79) UC1.H5(VCCGT87) UC1.H6(VCCGT88) UC1.H7(VCCGT89) UC1.H8(VCCGT90) UC1.H11(VCCGT80) UC1.H12(VCCGT81) UC1.H14(VCCGT82) UC1.H15(VCCGT83) UC1.H17(VCCGT84) UC1.H18(VCCGT85) UC1.H20(VCCGT86) UC1.J7(VCCGT95) UC1.J8(VCCGT96) UC1.J11(VCCGT91) UC1.J14(VCCGT92) UC1.J17(VCCGT93) UC1.J20(VCCGT94) UC1.K2(VCCGT98) UC1.K11(VCCGT97) UC1.L7(VCCGT100) UC1.L8(VCCGT101) UC1.L10(VCCGT99) UC1.M9(VCCGT102) UC1.N7(VCCGT104) UC1.N8(VCCGT105) UC1.N9(VCCGT106) UC1.N10(VCCGT103) UC1.P2(VCCGT107) UC1.P8(VCCGT108) UC1.R9(VCCGT109) UC1.T8(VCCGT111) UC1.T9(VCCGT112) UC1.T10(VCCGT110) UC1.U8(VCCGT114) UC1.U10(VCCGT113) UC1.V9(VCCGT116) UC1.W8(VCCGT117) UC1.W9(VCCGT118)
+VCC_SA: PC1151.1 PC1152.1 PC1153.1 PC1154.1 PC1155.1 PC1156.1 PC1157.1 PC1158.1 PC1159.1 PC1160.1 PC1161.1 PC1166.1 PC1167.1 PC1168.1 PC1169.1 PC1170.1 PC1171.1 PL614.1 RC166.1 UC1.BG8(VCCSA2) UC1.BG10(VCCSA1) UC1.BH9(VCCSA3) UC1.BJ8(VCCSA5) UC1.BJ9(VCCSA6) UC1.BJ10(VCCSA4) UC1.BK8(VCCSA9) UC1.BK25(VCCSA7) UC1.BK27(VCCSA8) UC1.BL8(VCCSA13) UC1.BL9(VCCSA14) UC1.BL10(VCCSA10) UC1.BL24(VCCSA11) UC1.BL26(VCCSA12) UC1.BM24(VCCSA15) UC1.BN25(VCCSA16)
+VCCDPHY_1P24: CC84.1 UC1.CP25(VCCDPHY_1P24_5)
+VCCLDOSRAM_1P24: UC1.BY23(VCCDPHY_1P24_1) UC1.BY24(VCCDPHY_1P24_2) UC1.CA23(VCCDPHY_1P24_3) UC1.CA24(VCCDPHY_1P24_4)
+VCCPDSW_1P05: CC65.1 UC1.BT24(VCCDSW_1P05)
+VCCPLL_OC: CC322.1 CC430.1 CC1480.1 CZ303.2 RZ119.2 UC1.BL27(VCCPLL_OC1) UC1.BM26(VCCPLL_OC2) UZ27.6(VOUT)
+VDDA_AVDD1: CA8.1 CA9.1 LA5.1 UA1.20(AVDD1)
+VSS_PLL: CE17.2 CE18.2 UE1.G1(VSS_PLL)
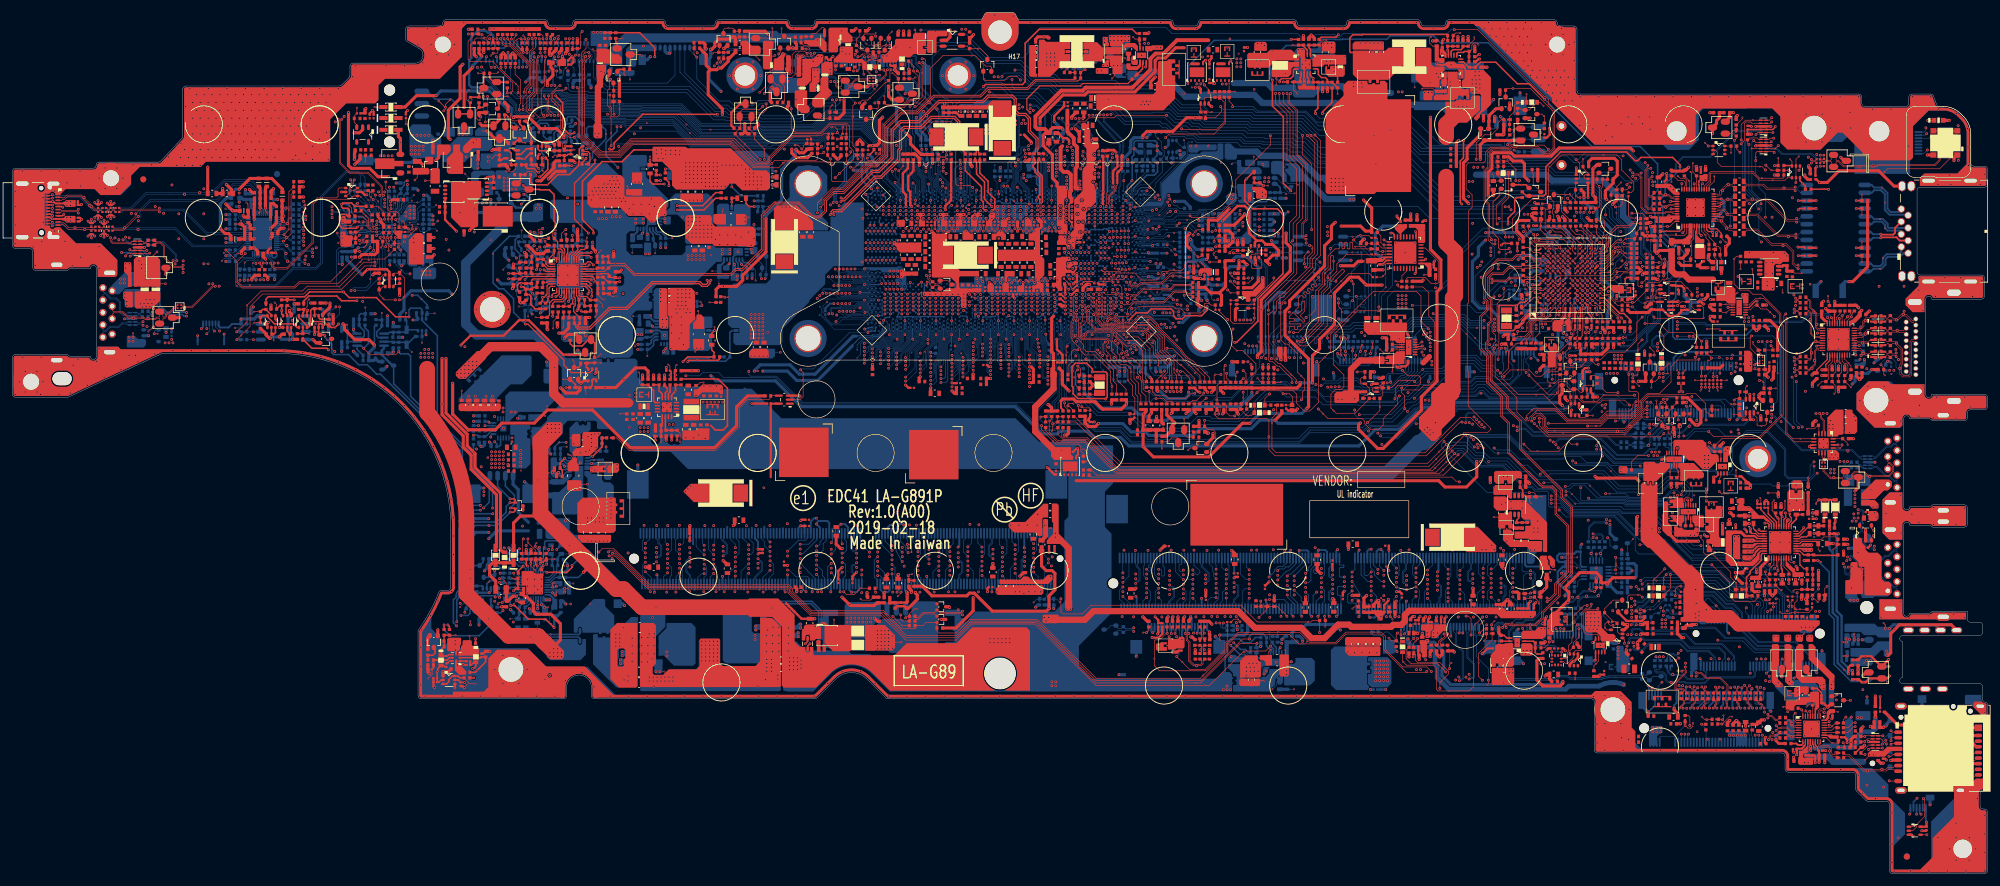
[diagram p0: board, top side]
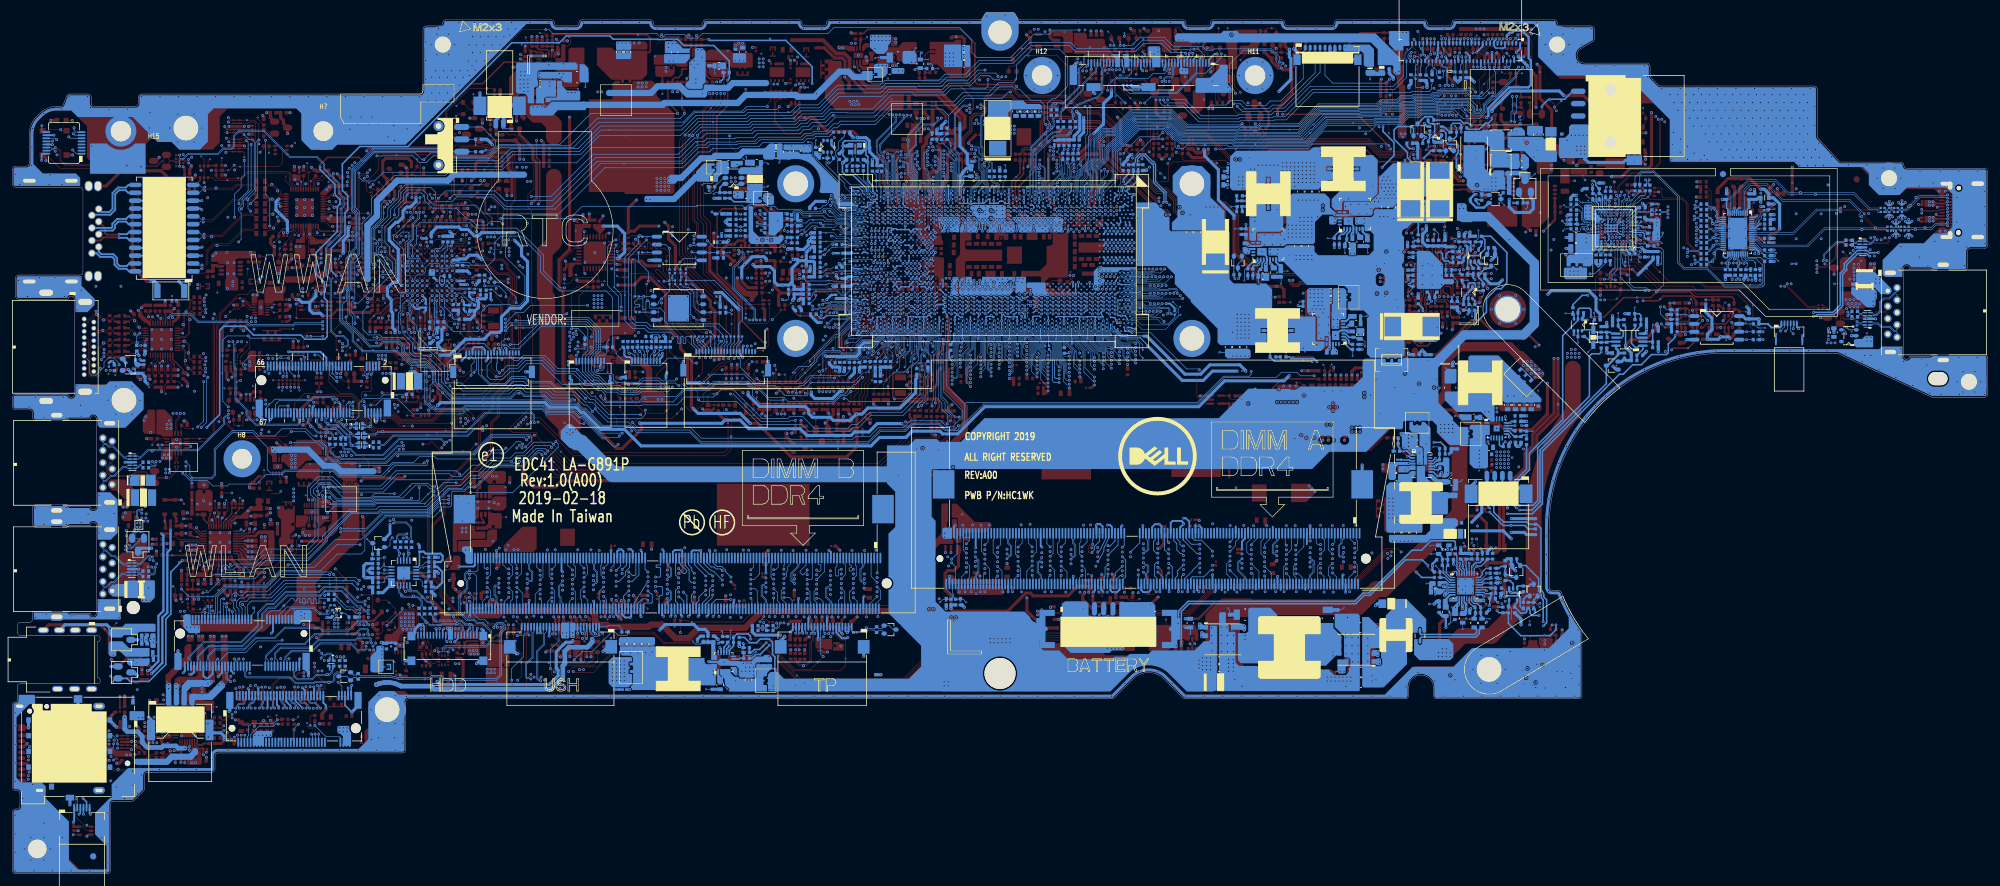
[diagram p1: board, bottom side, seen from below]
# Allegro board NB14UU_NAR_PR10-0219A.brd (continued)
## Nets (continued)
DDR_B_D29: JDIMM2.194(DQ41) UC1.AR29(DDR1_DQ_45/DDR1_DQ_29)
DDR_B_D30: JDIMM2.208(DQ43) UC1.AV32(DDR1_DQ_46/DDR1_DQ_30)
DDR_B_D31: JDIMM2.204(DQ47) UC1.AV31(DDR1_DQ_47/DDR1_DQ_31)
DDR_B_D32: JDIMM2.50(DQ16) UC1.BA35(DDR0_DQ_48/DDR1_DQ_32)
DDR_B_D33: JDIMM2.45(DQ21) UC1.BA34(DDR0_DQ_49/DDR1_DQ_33)
DDR_B_D34: JDIMM2.58(DQ22) UC1.BC35(DDR0_DQ_50/DDR1_DQ_34)
DDR_B_D35: JDIMM2.63(DQ19) UC1.BC34(DDR0_DQ_51/DDR1_DQ_35)
DDR_B_D36: JDIMM2.46(DQ20) UC1.BA37(DDR0_DQ_52/DDR1_DQ_36)
DDR_B_D37: JDIMM2.49(DQ17) UC1.BA36(DDR0_DQ_53/DDR1_DQ_37)
DDR_B_D38: JDIMM2.62(DQ18) UC1.BC36(DDR0_DQ_54/DDR1_DQ_38)
DDR_B_D39: JDIMM2.59(DQ23) UC1.BC37(DDR0_DQ_55/DDR1_DQ_39)
DDR_B_D40: JDIMM2.79(DQ30) UC1.BE35(DDR0_DQ_56/DDR1_DQ_40)
DDR_B_D41: JDIMM2.70(DQ24) UC1.BE34(DDR0_DQ_57/DDR1_DQ_41)
DDR_B_D42: JDIMM2.84(DQ27) UC1.BG35(DDR0_DQ_58/DDR1_DQ_42)
DDR_B_D43: JDIMM2.83(DQ26) UC1.BG34(DDR0_DQ_59/DDR1_DQ_43)
DDR_B_D44: JDIMM2.80(DQ31) UC1.BE37(DDR0_DQ_60/DDR1_DQ_44)
DDR_B_D45: JDIMM2.66(DQ28) UC1.BE36(DDR0_DQ_61/DDR1_DQ_45)
DDR_B_D46: JDIMM2.67(DQ29) UC1.BG36(DDR0_DQ_62/DDR1_DQ_46)
DDR_B_D47: JDIMM2.71(DQ25) UC1.BG37(DDR0_DQ_63/DDR1_DQ_47)
DDR_B_D48: JDIMM2.216(DQ48) UC1.BA32(DDR1_DQ_48/DDR1_DQ_48)
DDR_B_D49: JDIMM2.215(DQ49) UC1.BA31(DDR1_DQ_49/DDR1_DQ_49)
DDR_B_D50: JDIMM2.224(DQ54) UC1.BD31(DDR1_DQ_50/DDR1_DQ_50)
DDR_B_D51: JDIMM2.228(DQ50) UC1.BD32(DDR1_DQ_51/DDR1_DQ_51)
DDR_B_D52: JDIMM2.211(DQ52) UC1.BA30(DDR1_DQ_52/DDR1_DQ_52)
DDR_B_D53: JDIMM2.212(DQ53) UC1.BA29(DDR1_DQ_53/DDR1_DQ_53)
DDR_B_D54: JDIMM2.229(DQ51) UC1.BD29(DDR1_DQ_54/DDR1_DQ_54)
DDR_B_D55: JDIMM2.225(DQ55) UC1.BD30(DDR1_DQ_55/DDR1_DQ_55)
DDR_B_D56: JDIMM2.233(DQ61) UC1.BG31(DDR1_DQ_56/DDR1_DQ_56)
DDR_B_D57: JDIMM2.237(DQ56) UC1.BG32(DDR1_DQ_57/DDR1_DQ_57)
DDR_B_D58: JDIMM2.245(DQ62) UC1.BK32(DDR1_DQ_58/DDR1_DQ_58)
DDR_B_D59: JDIMM2.249(DQ58) UC1.BK31(DDR1_DQ_59/DDR1_DQ_59)
DDR_B_D60: JDIMM2.236(DQ57) UC1.BG29(DDR1_DQ_60/DDR1_DQ_60)
DDR_B_D61: JDIMM2.232(DQ60) UC1.BG30(DDR1_DQ_61/DDR1_DQ_61)
DDR_B_D62: JDIMM2.246(DQ63) UC1.BK30(DDR1_DQ_62/DDR1_DQ_62)
DDR_B_D63: JDIMM2.250(DQ59) UC1.BK29(DDR1_DQ_63/DDR1_DQ_63)
DDR_B_DQS0: JDIMM2.13(DQS0(T)) UC1.AP34(DDR0_DQSP_4/DDR1_DQSP_0)
DDR_B_DQS1: JDIMM2.34(DQS1(T)) UC1.AV35(DDR0_DQSP_5/DDR1_DQSP_1)
DDR_B_DQS2: JDIMM2.179(DQS4(T)) UC1.AL30(DDR1_DQSP_4/DDR1_DQSP_2)
DDR_B_DQS3: JDIMM2.200(DQS5(T)) UC1.AU30(DDR1_DQSP_5/DDR1_DQSP_3)
DDR_B_DQS4: JDIMM2.55(DQS2(T)) UC1.BB34(DDR0_DQSP_6/DDR1_DQSP_4)
DDR_B_DQS5: JDIMM2.76(DQS3(T)) UC1.BF35(DDR0_DQSP_7/DDR1_DQSP_5)
DDR_B_DQS6: JDIMM2.221(DQS6(T)) UC1.BC30(DDR1_DQSP_6/DDR1_DQSP_6)
DDR_B_DQS7: JDIMM2.242(DQS7(T)) UC1.BH30(DDR1_DQSP_7/DDR1_DQSP_7)
DDR_B_DQS#0: JDIMM2.11(DQS0#(C)) UC1.AP35(DDR0_DQSN_4/DDR1_DQSN_0)
DDR_B_DQS#1: JDIMM2.32(DQS1#(C)) UC1.AV34(DDR0_DQSN_5/DDR1_DQSN_1)
DDR_B_DQS#2: JDIMM2.177(DQS4#(C)) UC1.AL31(DDR1_DQSN_4/DDR1_DQSN_2)
DDR_B_DQS#3: JDIMM2.198(DQS5#(C)) UC1.AU31(DDR1_DQSN_5/DDR1_DQSN_3)
DDR_B_DQS#4: JDIMM2.53(DQS2#(C)) UC1.BB35(DDR0_DQSN_6/DDR1_DQSN_4)
DDR_B_DQS#5: JDIMM2.74(DQS3#(C)) UC1.BF34(DDR0_DQSN_7/DDR1_DQSN_5)
DDR_B_DQS#6: JDIMM2.219(DQS6#(C)) UC1.BC31(DDR1_DQSN_6/DDR1_DQSN_6)
DDR_B_DQS#7: JDIMM2.240(DQS7#(C)) UC1.BH31(DDR1_DQSN_7/DDR1_DQSN_7)
DDR_B_MA0: JDIMM2.144(A0) UC1.AG36(DDR1_CAB_9/DDR1_MA_0)
DDR_B_MA1: JDIMM2.133(A1) UC1.AG35(DDR1_CAB_8/DDR1_MA_1)
DDR_B_MA2: JDIMM2.132(A2) UC1.AF34(DDR1_CAB_5/DDR1_MA_2)
DDR_B_MA3: JDIMM2.131(A3) UC1.AG37(NC/DDR1_MA_3)
DDR_B_MA4: JDIMM2.128(A4) UC1.AE35(NC/DDR1_MA_4)
DDR_B_MA5: JDIMM2.126(A5) UC1.AF35(DDR1_CAA_0/DDR1_MA_5)
DDR_B_MA6: JDIMM2.127(A6) UC1.AE37(DDR1_CAA_2/DDR1_MA_6)
DDR_B_MA7: JDIMM2.122(A7) UC1.AC29(DDR1_CAA_4/DDR1_MA_7)
DDR_B_MA8: JDIMM2.125(A8) UC1.AE36(DDR1_CAA_3/DDR1_MA_8)
DDR_B_MA9: JDIMM2.121(A9) UC1.AB29(DDR1_CAA_1/DDR1_MA_9)
DDR_B_MA10: JDIMM2.146(A10_AP) UC1.AG34(DDR1_CAB_7/DDR1_MA_10)
DDR_B_MA11: JDIMM2.120(A11) UC1.AC28(DDR1_CAA_7/DDR1_MA_11)
DDR_B_MA12: JDIMM2.119(A12) UC1.AB28(DDR1_CAA_6/DDR1_MA_12)
DDR_B_MA13: JDIMM2.158(A13) UC1.AK35(DDR1_CAB_0/DDR1_MA_13)
DDR_B_MA14: JDIMM2.151(A14_WE#) UC1.AJ35(DDR1_CAB_2/DDR1_MA_14)
DDR_B_MA15: JDIMM2.156(A15_CAS#) UC1.AK34(DDR1_CAB_1/DDR1_MA_15)
DDR_B_MA16: JDIMM2.152(A16_RAS#) UC1.AJ34(DDR1_CAB_3/DDR1_MA_16)
DDR_B_ODT0: JDIMM2.155(ODT0) UC1.AL36(DDR1_ODT_0/DDR1_ODT_0)
DDR_B_ODT1: JDIMM2.161(ODT1) UC1.AL34(NC/DDR1_ODT_1)
DDR_B_PARITY: JDIMM2.143(PARITY) UC1.AE34(NC/DDR1_PAR)
DDR_CHA_EN: T406.1 UC1.CK19(GPP_F1)
DDR_CHB_EN: T407.1 UC1.CG17(GPP_F2)
DDR_DRAMRST#: RD11.2 RD12.2 UC1.BU31(DRAM_RESET#)
DDR_DRAMRST#_R: CD29.1 CD61.1 JDIMM1.108(RESET#) JDIMM2.108(RESET#) RD12.1
DDR_VTT_CTRL: UC1.C35(DDR_VTT_CTL) UD1.2(A)
DDR_XDP_WAN_SMBCLK: JDIMM1.253(SCL) JDIMM2.253(SCL) JXDP1.53 LGA1.1(SCL/SPC) QC2.1(S2) RC319.1
DDR_XDP_WAN_SMBDAT: JDIMM1.254(SDA) JDIMM2.254(SDA) JXDP1.51 LGA1.4(SDA/SDI/SDO) QC2.4(S1) RC318.1
DEBUG_TX: JDEG1.9 RE30.2 RE74.2
DEW1: RN16.2 RN17.2 UN7.16(NC2)
DEW2: RN14.2 RN15.2 UN7.6(NC1)
DGPU_PWROK: UC1.CJ25(GPP_D18/DMIC_DATA1/SNDW3_DATA) UE1.M4(GPIO013/SMB07_CLK/TOUT2)
DIMM1_SA0: JDIMM1.256(SA0) RD4.2 RD5.1
DIMM1_SA1: JDIMM1.260(SA1) RD6.2 RD7.1
DIMM1_SA2: JDIMM1.166(SA2) RD8.2 RD9.1
DIMM2_SA0: JDIMM2.256(SA0) RD20.2 RD21.1
DIMM2_SA1: JDIMM2.260(SA1) RD22.2 RD23.1
DIMM2_SA2: JDIMM2.166(SA2) RD24.2 RD25.1
DISP_ON: DV2.1 JEDP1.22 RV2.1
DMIC0: CA6.1 DV13.3 JEDP1.7 RA52.2 UA1.2(GPIO0/DMIC-DATA12)
DMIC_CLK0: CA5.1 CA54.1 DV13.2 JEDP1.9 RA14.1
DMIC_CLK_CODEC: RA14.2 UA1.3(GPIO1/DMIC-CLK)
DP2_MIC_SBU1: DT39.2 DT39.8 JUSBC1.B8(SBU2) RT108.2 RT132.2
DP2_MIC_SBU1_R: RT108.1 UT5.K8(C_SBU1)
DP2_MIC_SBU2: DT39.1 DT39.9 JUSBC1.A8(SUB1) RT109.2 RT133.2
DP2_MIC_SBU2_R: RT109.1 UT5.L8(C_SBU2)
EDP_AUXN: CV1.1 UC1.AH4(EDP_AUX_N)
EDP_AUXN_C: CV1.2 JEDP1.33
EDP_AUXP: CV2.1 UC1.AH3(EDP_AUX_P)
EDP_AUXP_C: CV2.2 JEDP1.34
EDP_BIA_PWM: DV1.3 UC1.CH11(EDP_BKLTCTL)
EDP_COMP: RC8.2 UC1.AM6(DISP_RCOMP)
EDP_HPD: JEDP1.26 RC2.2 RV7.1 UC1.CM7(GPP_E17/EDP_HPD/DISP_MISC4)
EDP_TXN0: CV4.1 UC1.AG4(EDP_TXN_0)
EDP_TXN0_C: CV4.2 JEDP1.36
EDP_TXN1: CV6.1 UC1.AG2(EDP_TXN_1)
EDP_TXN1_C: CV6.2 JEDP1.38
EDP_TXP0: CV3.1 UC1.AG3(EDP_TXP_0)
EDP_TXP0_C: CV3.2 JEDP1.35
EDP_TXP1: CV5.1 UC1.AG1(EDP_TXP_1)
EDP_TXP1_C: CV5.2 JEDP1.37
EDRAM_OPIO_RCOMP: RC108.1 UC1.L5(RSVD70)
EMMC_RCOMP: RC10.1 UC1.CK15(EMMC_RCOMP)
EN_1.2V_RUN: PC510.1 PR509.1 PR511.2 PU502.5(EN)
EN_1.05VALWP: PC360.1 PR302.1 PR312.2 PU301.11(EN)
EN_1.8VALW: PC505.1 PR504.2 PR505.1 PU501.1(EN)
EN_1V_PRIM_CORE: PC411.1 PR406.2 PR407.1 PU402.13(EN)
EN_1VS_VCCIO: PC402.1 PR402.2 PR403.1 PU401.13(EN)
EN_2.5V_MEM: PC513.1 PR513.2 PR514.1 PU503.5(EN)
EN_INVPWR: QV2.2(G) RE55.1 UE1.B2(GPIO023/GPTP-IN1)
EN_LCDPWR: DV3.1 RV3.2 UV24.4(EN)
EN_PD_HV_1: PQ813.2(G1) PR736.1 PR820.2 PR834.1 PR846.1 PR853.1 PR857.1 RT70.2
EN_PD_HV_1#: PQ802.2(G1) PQ802.3(D2) PR810.2 PR851.2
EN_PD_HV_1_R: RT70.1 UT5.C2(GPIO1)
ENABLE_DS#: RE549.2 RE550.1 UE1.L2(GPIO067/CLKRUN#)
ENLDO_3V5V: PR102.1 PR103.1 PU100.11(EN2) PU102.11(EN2)
ENVDD_PCH: DV3.3 UC1.CG11(EDP_VDDEN)
EOPIO_RCOMP: RC109.1 UC1.N5(RSVD71)
ESPI_ALERT#: RC244.2 UC1.BV28(GPP_A6/SERIRQ) UE1.H7(GPIO063/SER_IRQ/ESPI_ALERT#)
ESPI_CLK: RC19.1 UC1.BV32(GPP_A9/CLKOUT_LPC0/ESPI_CLK)
ESPI_CLK_5105: CC316.1 JESPI.10 RC19.2 RE350.1 UE1.G7(GPIO065/PCI_CLK/ESPI_CLK)
ESPI_CS#: JESPI.7 UC1.CA28(GPP_A5/LFRAME#/ESPI_CS#) UE1.H6(GPIO066/LFRAME#/ESPI_CS#)
ESPI_IO0: JESPI.3 RC366.2 UE1.K5(GPIO070/LAD0/ESPI_IO0)
ESPI_IO0_R: RC366.1 UC1.CA29(GPP_A1/LAD0/ESPI_IO0)
ESPI_IO1: JESPI.4 RC367.2 UE1.L4(GPIO071/LAD1/ESPI_IO1)
ESPI_IO1_R: RC367.1 UC1.BY29(GPP_A2/LAD1/ESPI_IO1)
ESPI_IO2: JESPI.5 RC368.2 UE1.G6(GPIO072/LAD2/ESPI_IO2)
ESPI_IO2_R: RC368.1 UC1.BY27(GPP_A3/LAD2/ESPI_IO2)
ESPI_IO3: JESPI.6 RC369.2 UE1.L5(GPIO073/LAD3/ESPI_IO3)
ESPI_IO3_R: RC369.1 UC1.BV27(GPP_A4/LAD3/ESPI_IO3)
ESPI_RESET#: RC833.1 RE560.2 UC1.CA27(GPP_A14/SUS_STAT#/ESPI_RESET#) UE1.K6(GPIO061/LPCPD#/ESPI_RESET#)
ESPI_RESET#_R: JESPI.8 RE560.1
FB_1.05VALWP: PR306.2 PR308.2 PR311.1 PU301.14(FB)
FB_1.8VALW: PC503.2 PR501.2 PR506.1 PU501.6(FB)
FB_3V: PC113.1 PU100.13(FF)
FB_5V: PC127.1 PU102.13(FF)
FB_A_GT: PR645.2 PR648.2 PR650.1 PU602.17(FB_A)
FB_B_IA: PR621.2 PR622.2 PR623.2 PU602.5(FB_B)
FB_C_SA: PR646.1 PR649.1 PR652.1 PU602.25(FB_C)
FB_DDR: PC208.2 PR204.2 PR206.1 PU200.16(FB)
FBS_1V_PRIM_CORE: PR423.1 PR424.1 PU402.5(FBS)
FBS_1VS_VCCIO: PR421.2 PR422.1 PU401.5(FBS)
FCCM1_IA: PR659.2 PU610.2(FCCM)
FCCM2_IA: PR671.2 PU613.2(FCCM)
FCCM_A_GT: PR662.1 PU602.21(FCCM_A)
FCCM_B_IA: PR659.1 PR671.1 PU602.11(FCCM_B)
FCCM_C_SA: PR679.2 PU602.29(FCCM_C)
FCCM_GT: PR662.2 PU612.2(FCCM)
FCCM_SA: PR679.1 PU614.7(FCCM)
FFS_INT2: LGA1.11(INT 2) QN1.2(G2) RC726.2 UC1.CP6(GPP_E16/DPPE_HPD3/DISP_MISC3)
FFS_INT2_Q: JSATA1.19 QN1.3(D1) RN1.2
FIVR_EN: RC217.1 RC235.1 RC236.1
FIVR_EN_R: JXDP1.45 RC126.2 RC132.1 RC217.2
FPR_DET#: DT41.1 DT41.9 JFPBTN1.1 RE606.1 UE1.D9(GPIO133/PWM9)
FPR_LOW_PWR_MODE#: DT41.4 DT41.7 JFPBTN1.11 RE708.1 UE1.K12(GPIO111/PS2_DAT2)
FPR_PWR_EN#: RE704.1 RZ380.2 UE1.M11(GPIO027/TIN2)
FPR_PWR_EN#_R: CZ200.1 QZ18.2(G) RZ380.1
FPR_RST#: DT41.5 DT41.6 JFPBTN1.12 RZ1392.1 RZ1411.1
FPR_RST#_USH: JUSH1.25 RZ1411.2
FPR_SCAN_INT#: DT42.4 DT42.7 JFPBTN1.15 QE20.3(S) RE709.2 RE825.1
FPR_SCAN_INT#_EC: QE20.1(D) RE825.2 RE826.2 RZ114.1 UE1.L8(GPIO002/PWM5)
FPR_SCAN_INT#_EC_R: JUSH1.6 RZ114.2
FPR_SSO_EN#: DT42.5 DT42.6 JFPBTN1.16 RE706.1 UE1.H9(GPIO030/TIN3)
FPR_UEFI_MGMT#: DT42.1 DT42.9 JFPBTN1.13 RE707.1 UE1.K9(GPIO032/GPTP-OUT0)
FTPBTN1.10: DT41.2 DT41.8 JFPBTN1.10 T418.1 T421.1 T422.1
GPD7: RC95.1 RC454.2 UC1.BV35(GPD7)
GPP_A7: RC841.1 UC1.CC32(GPP_A7/PIRQA#/GSPI0_CS1#)
GPP_A8: RC849.1 UC1.BY30(GPP_A8/CLKRUN#)
GPP_A13: T380.1 UC1.BV34(GPP_A13/SUSWARN#/SUSPWRDACK)
GPP_A15: T381.1 UC1.BY32(GPP_A15/SUSACK#)
GPP_B22: RC46.2 UC1.CA30(GPP_B22/GSPI1_MOSI)
GPP_B23: RC317.1 UC1.CC34(GPP_B23/SML1ALERT#/PCHHOT#)
GPP_C5: RC277.1 RC397.1 UC1.CG15(GPP_C5/SML0ALERT#)
GPP_D12: RC847.1 UC1.CP22(GPP_D12/ISH_SPI_MOSI/GSPI2_MOSI)
GPP_H17: RC101.2 UC1.CP26(GPP_H17/DDPF_CTRLDATA)
GPP_H21: RC443.1 RC444.2 UC1.CF25(GPP_H21/XTAL_FREQ_SELECT)
GPP_H23: RC446.2 RC537.1 UC1.CM26(GPP_H23)
GPS_DISABLE#: DZ6.1 RE12.1 UE1.H5(GPIO060/KBRST/48MHZ_OUT)
GPS_DISABLE#_R: DZ6.2 JNGFF2.18(GPIO_10)
H_CATERR#: RC219.2 UC1.AA4(CATERR#)
H_CPU_SVIDALRT#: RC155.1 UC1.AA3(VIDALERT#)
H_CPUPWRGD: CC300.1 RC77.2 UC1.AR2(PROCPWRGD)
H_CPUPWRGD_R: RC77.1 T355.1
H_THERMTRIP#: QE4.3(EMITTER) RC559.1 RD14.2 RD27.2
H_THERMTRIP#_R: RC218.2 RC559.2 UC1.BJ1(THRMTRIP#)
H_VCCST_PWRGD_XDP: CC307.1 JXDP1.39 RC123.2 RC124.2
HDA_BIT_CLK: RC93.2 UC1.BN37(HDA_BCLK/I2S0_SCLK)
HDA_BIT_CLK_R: CC27.1 RA17.1 RC93.1 UA1.5(BIT-CLK)
HDA_RST#: CC331.1 RC560.2 UC1.BL35(HDA_RST#/I2S1_SCLK/SNDW1_CLK)
HDA_RST#_R: RA50.1 RC560.1
HDA_SDIN0: CC332.1 RA9.1 UC1.BN35(HDA_SDI0/I2S0_RXD)
HDA_SDIN0_R: RA9.2 UA1.7(SDATA-IN)
HDA_SDOUT: CC333.1 RC187.1 RC561.2 RC562.2 UC1.BN36(HDA_SDO/I2S0_TXD)
HDA_SDOUT_R: RC561.1 UA1.4(SDATA-OUT)
HDA_SYNC: RC92.2 UC1.BN34(HDA_SYNC/I2S0_SFRM)
HDA_SYNC_R: RC92.1 UA1.9(SYNC)
HDD_A_EQ: RN10.1 RN11.2 UN7.17(A_EQ)
HDD_A_EQ2: RN20.2 RN21.1 UN7.18(TDET_EN)
HDD_A_PRE: RN6.2 RN7.2 UN7.9(A_EM)
HDD_B_EQ: RN12.2 RN13.2 UN7.19(B_EQ)
HDD_B_EQ2: RN18.2 RN19.1 UN7.13(TDET_A#)
HDD_B_PRE: RN8.1 RN9.2 UN7.8(B_EM)
HDD_DET#: JSATA1.13 QN6.2(G) RC520.1 RC765.2 UC1.CN8(GPP_E0/SATAXPCIE0/SATAGP0)
HDD_DEVSLP: JSATA1.11 RN3.2 UC1.CP8(GPP_E4/DEVSLP0)
HDD_EN: RN4.2 RN5.1 RZ148.2 UZ23.3(ON)
HDD_FALL_INT: LGA1.12(INT 1) RC58.1 UC1.CA31(GPP_B19/GSPI1_CS0#)
HDD_UN7_EN: QN6.1(D) RN226.2 RN227.1
HDD_UN7_EN_R: RN227.2 UN7.7(EN)
HDMI_BUF: RV304.2 RV305.1 UV21.14(DDCBUF/SDA_CTL)
HDMI_CEC: JHDMI1.13(CEC) RV736.1
HDMI_CLKN_C: CV307.1 UV21.10(IN_CKN)
HDMI_CLKP_C: CV306.1 UV21.9(IN_CKP)
HDMI_DP1_HPD: UC1.CN6(GPP_E13/DDPB_HPD0/DISP_MISC0) UV21.3(HPD_SRC)
HDMI_EQ: RV307.1 RV734.2 UV21.17(EQ/I2C_ADDR0)
HDMI_HPD_SINK: JHDMI1.19(HP_DET) RV55.2 UV21.28(HPD_SNK)
HDMI_ISET: RV208.2 RV209.1 UV21.34(ISET)
HDMI_PRE: RV175.1 RV207.2 UV21.16(PRE)
HDMI_SCL_SINK: JHDMI1.15(SCL) RV735.1 UV21.32(SCL_SNK)
HDMI_SDA_SINK: JHDMI1.16(SDA) RV10.1 UV21.33(SDA_SNK)
HDMI_TX_N0_C: CV305.1 UV21.2(IN_D2N)
HDMI_TX_N1_C: CV303.1 UV21.5(IN_D1N)
HDMI_TX_N2_C: CV301.1 UV21.7(IN_D0N)
HDMI_TX_P0_C: CV304.1 UV21.1(IN_D2P)
HDMI_TX_P1_C: CV302.1 UV21.4(IN_D1P)
HDMI_TX_P2_C: CV300.1 UV21.6(IN_D0P)
HOST_DEBUG_TX: JDEG1.8 RE73.2 RE306.2 UE1.G11(GPIO104/UART0_TX)
HOST_SD_WP#: QR1.2(G) RC292.1 UC1.CH35(GPP_G5/SD_CD#)
HP_OUT_L: CA43.2 CA74.1 RA7.1 UA1.25(HP-OUT-L)
HP_OUT_R: CA44.2 CA73.1 RA8.1 UA1.26(HP-OUT-R)
HV_GATE1_A: RT64.1 UT5.B9(HV_GATE1)
HV_GATE2_A: RT65.1 UT5.A9(HV_GATE2)
HW_ACAVIN_NB: PC805.1 PR25.2 PR41.1 PR42.1 PR737.1 PR746.1 PR805.2 PR806.2 PR835.1 PR844.1 PR845.1 PU800.1(O) UE1.N6(GPIO014/PWM6/GPTP-IN6)
I2C1_SCK_TP: RZ21.2 RZ29.1 UC1.CJ12(GPP_C19/I2C1_SCL)
I2C1_SCK_TP_R: JKBTP1.19 RZ29.2 RZ117.2 RZ347.1
I2C1_SDA_TP: RZ20.2 RZ26.1 UC1.CK12(GPP_C18/I2C1_SDA)
I2C1_SDA_TP_R: JKBTP1.18 RZ26.2 RZ116.2 RZ346.1
I2C2_SCL_ALS: T389.1 UC1.CF29(GPP_H5/I2C2_SCL)
I2C2_SDA_ALS: T388.1 UC1.CF27(GPP_H4/I2C2_SDA)
I2C3_ANT_SCL: T379.1 UC1.CH28(GPP_H7/I2C3_SCL)
I2C3_ANT_SDA: T378.1 UC1.CH27(GPP_H6/I2C3_SDA)
I_ADP: PR743.2 UE1.B11(VCP)
I_BATT: PR729.2 RE64.2
I_BATT_R: CE3.1 RE64.1 UE1.J4(GPIO200/ADC00)
I_SYS: PR620.1 PR731.2 RE312.2
I_SYS_R: CE4.1 RE312.1 RE313.1 UE1.J5(GPIO201/ADC01)
ILIM_SEL: RI13.1 UI3.4(ILIM_SEL)
ILMT_1.05VALWP: PR307.2 PR310.1 PU301.13(ILMT)
ILMT_DDR: PR205.2 PR207.1 PU200.17(ILMT)
IMON_A_GT: PC625.2 PR629.2 PU602.14(IMON_A)
IMON_B_IA: PC613.2 PR613.2 PU602.2(IMON_B)
IMON_C_SA: PC643.1 PR651.1 PU602.23(IMON_C)
IMVP_VR_ON: PR616.1 RE304.1 UE3.4(O) UE4.2(A)
IMVP_VR_ON_EC: RE304.2 RE717.2 UE1.N7(GPIO031/GPTP-OUT1) UE3.1(B)
INPUT3VSEL: RC451.1 RC452.2 UC1.BT27(INPUT3VSEL)
INT_SPK_L+: CA22.1 LA6.1 UA1.35(SPK-OUT-LP)
INT_SPK_L-: CA23.1 LA7.1 UA1.36(SPK-OUT-LN)
INT_SPK_R+: CA19.1 LA8.1 UA1.38(SPK-OUT-RP)
INT_SPK_R-: CA24.1 LA9.1 UA1.37(SPK-OUT-RN)
INT_SPKR_L+: DA6.2 JSPK1.1 LA6.2
INT_SPKR_L-: DA6.3 JSPK1.2 LA7.2
INT_SPKR_R+: DA7.2 JSPK1.3 LA8.2
INT_SPKR_R-: DA7.3 JSPK1.4 LA9.2
INTRUDER#: RC69.1 UC1.BR35(INTRUDER#)
IR_CAM_DET#: JIRTS1.5 RC345.2 UC1.CN22(GPP_D9/ISH_SPI_CS#/GSPI2_CS0#)
ISEN1_IA: PC635.2 PR634.1 PR668.2 PR670.2 PU602.9(ISEN1_B)
ISEN1N_IA: PL610.2 PR666.1 PR677.1
ISEN1P_IA: PL610.3 PR667.2 PR668.1
ISEN2_IA: PC638.2 PR615.1 PR675.2 PR677.2 PU602.10(ISEN2_B)
ISEN2N_IA: PL613.2 PR670.1 PR673.1
ISEN2P_IA: PL613.3 PR674.2 PR675.1
ISH_ACC1: T395.1 UC1.BW35(GPP_A18/ISH_GP0)
ISH_ACC2: T396.1 UC1.BW34(GPP_A19/ISH_GP1)
ISH_ALS: T398.1 UC1.CA36(GPP_A21/ISH_GP3)
ISH_I2C0_ACC_SCL: T416.1 UC1.CH20(GPP_D6/ISH_I2C0_SCL)
ISH_I2C0_ACC_SDA: T415.1 UC1.CK22(GPP_D5/ISH_I2C0_SDA)
ISH_I2C1_ALS_SCL: T402.1 UC1.CJ22(GPP_D8/ISH_I2C1_SCL)
ISH_I2C1_ALS_SDA: T401.1 UC1.CH22(GPP_D7/ISH_I2C1_SDA)
ISH_I2C2_SCL: RC362.1 RZ76.1 UC1.CJ29(GPP_H11/I2C5_SCL/ISH_I2C2_SCL)
ISH_I2C2_SCL_R: JNGFF2.32(GNSS_SCL) RZ76.2
ISH_I2C2_SDA: RC363.1 RZ77.1 UC1.CJ27(GPP_H10/I2C5_SDA/ISH_I2C2_SDA)
ISH_I2C2_SDA_R: JNGFF2.34(GNSS_SDA) RZ77.2
ISH_LID_CL#_NB: T376.1 UC1.CA34(GPP_A23/ISH_GP5)
ISH_LID_CL#_TAB: T377.1 UC1.BW37(GPP_A12/ISH_GP6/BM_BUSY#/SX_EXI)
ISH_NB_MODE: T375.1 UC1.CA35(GPP_A22/ISH_GP4)
ISH_P_SENSOR_INT#: T385.1 UC1.BW36(GPP_A17/SD_VDD1_PWR_EN#/ISH_GP7)
ISH_TABLE_MODE#: T397.1 UC1.CA37(GPP_A20/ISH_GP2)
ISH_UART0_CTS#_R: JNGFF1.62(ALERT) RZ80.2
ISH_UART0_RXD_R: JNGFF1.58(I2C_DATA) RZ78.2
ISH_UART0_TXD_R: JNGFF1.60(I2C_CLK) RZ79.2
ISUMN_A_GT: PC630.1 PR640.1 PU602.20(ISUMN_A)
ISUMN_B_IA: PC627.2 PR638.2 PU602.8(ISUMN_B)
ISUMN_C_SA: PC632.1 PR636.1 PU602.28(ISUMN_C)
ISUMN_GT: PC642.2 PC645.1 PC646.2 PH605.2 PL612.2 PR640.2 PR644.2 PR656.2
ISUMN_IA: PC624.2 PC626.2 PC635.1 PC638.1 PC641.1 PH602.2 PR632.1 PR633.2 PR638.1 PR666.2 PR673.2
ISUMN_SA: PC633.2 PC637.2 PC644.1 PH604.2 PL614.2 PR636.2 PR641.2 PR643.2
ISUMP_GT: PC642.1 PC646.1 PR653.2 PR656.1 PR657.1 PR661.2 PU602.19(ISUMP_A)
ISUMP_IA: PC624.1 PC626.1 PR628.1 PR633.1 PR658.2 PR667.1 PR674.1 PU602.7(ISUMP_B)
ISUMP_SA: PC633.1 PC637.1 PR624.2 PR642.1 PR643.1 PU602.27(ISUMP_C)
ITP_PMODE: JXDP1.46 RC125.1 UC1.W4(ITP_PMODE)
JDIMM1_EVENT#: JDIMM1.134(EVENT#) RD14.1
JDIMM2_EVENT#: JDIMM2.134(EVENT#) RD27.1
JTAG_CLK: JDEG1.4 RE720.2 UE1.C8(GPIO147/SMB08_DATA/JTAG_CLK)
JTAG_RST#: CE30.1 JTAG1.1 RE63.1 RE65.1 UE1.G13(JTAG_RST#)
JTAG_TDI: JDEG1.2 RE715.2 UE1.E9(GPIO145/SMB09_DATA/JTAG_TDI)
JTAG_TDO: JDEG1.5 RE719.2 UE1.F6(GPIO146/SMB09_CLK/JTAG_TDO)
JTAG_TMS: JDEG1.3 RE714.2 UE1.C5(GPIO150/SMB08_CLK/JTAG_TMS)
KB_DET#: CZ84.1 JKBTP1.1 RC288.1 UC1.CK25(GPP_D17/DMIC_CLK1/SNDW3_CLK)
LAN_ACTLED_YEL#: QL1.6(D2) RL14.1
LAN_ACTLED_YEL_R#: JLOM1.A2(YELLOW LED-) RL14.2
LAN_DISABLE#_R: RL5.1 RL7.2 RL9.1 UL1.3(LAN_DISABLE_N)
LAN_MDIN0: RL72.1 UL1.14(MDI_MINUS0)
LAN_MDIN0_L: RL72.2 TL1.2(TD1-)
LAN_MDIN1: RL74.1 UL1.18(MDI_MINUS1)
LAN_MDIN1_L: RL74.2 TL1.6(TD2-)
LAN_MDIN2: RL76.1 UL1.21(MDI_MINUS2)
LAN_MDIN2_L: RL76.2 TL1.8(TD3-)
LAN_MDIN3: RL78.1 UL1.24(MDI_MINUS3)
LAN_MDIN3_L: RL78.2 TL1.12(TD4-)
LAN_MDIP0: RL71.1 UL1.13(MDI_PLUS0)
LAN_MDIP0_L: RL71.2 TL1.1(TD1+)
LAN_MDIP1: RL73.1 UL1.17(MDI_PLUS1)
LAN_MDIP1_L: RL73.2 TL1.5(TD2+)
LAN_MDIP2: RL75.1 UL1.20(MDI_PLUS2)
LAN_MDIP2_L: RL75.2 TL1.7(TD3+)
LAN_MDIP3: RL77.1 UL1.23(MDI_PLUS3)
LAN_MDIP3_L: RL77.2 TL1.11(TD4+)
LAN_TEST_EN: RL12.1 UL1.30(TEST_EN)
LAN_WAKE#: RC323.1 RL70.1 UC1.BU32(GPD2/LAN_WAKE#) UE1.L3(GPIO217/ADC15) UL1.2(LANWAKE_N)
LCD_CBL_DET#: JEDP1.40 RC749.1 UC1.CF12(GPP_C14/UART1_RTS#/ISH_UART1_RT)
LCD_TST: JEDP1.29 RE20.1 UE1.M2(GPIO052/FAN_TACH2/LRESET#)
LCD_VCC_TEST_EN: DV3.2 UE1.E1(GPIO226/LED3)
LCDVDD_MONITOR: QV21.2(BASE) RV630.2
LDO_3V: PC111.2 PR104.1 PR105.1 PU100.16(NC3) PU100.17(LDO)
LED_GRN#: QL1.3(D1) RL19.1
LED_GRN_R#: JLOM1.B2(GREEN LED-) RL19.2
LED_MASK#: QL1.2(G2) QL1.5(G1) RE21.1 UE1.A12(GPIO140/SMB06_CLK/ICT5) UZ10.1(B)
LG1_CHG: PQ700.8(G2) PU700.9(LGATE1)
LG2_CHG: PQ701.8(G2) PU700.7(LGATE2)
LG_SA: PQ614.8(G2) PU614.5(LGATE)
LID_CL#: JLED1.2 RE26.1 UZ10.2(A)
LID_CL_SIO#: CE8.1 RE25.2 RE26.2 UE1.N11(GPIO115/PS2_DAT0A)
LINE1-VREFO: DA4.2 DA5.2 UA1.24(LINE1-VREFO-L)
LINE1_L: CA43.1 UA1.18(LINE1-L)
LINE1_R: CA44.1 UA1.17(LINE1-R)
LM393_P: PC754.2 PC801.2 PD800.1(3) PR735.2 PR866.2 PU701.5(P) PU800.8(P)
LOM_ACTLED_YEL#: QL1.1(S2) UL1.26(LED0)
LOM_CABLE_DETECT#: RE505.1 RL20.1 UE1.D2(GPIO211/ADC09)
LOM_CONNLED_GRN#: QL1.4(S1) RL20.2 RL29.2 UL1.27(LED1)
LOM_LED2: T315.1 UL1.25(LED2)
LPM_1V_PRIM_CORE: PR410.2 PR430.2 PU402.14(LPM)
LPM_1VS_VCCIO: PR404.2 PR425.2 PR429.2 PU401.14(LPM)
LX1_CHG: PC727.1 PL701.1 PQ700.2(S1/D2) PQ700.5(D2/S1_1) PQ700.6(D2/S1_2) PQ700.7(D2/S1_3) PR717.1 PU700.10(PHASE1)
LX1_IA: PL610.4 PR663.1 PU610.11(SW1) PU610.12(SW2)
LX2_CHG: PL701.2 PQ701.2(S1/D2) PQ701.5(D2/S1_1) PQ701.6(D2/S1_2) PQ701.7(D2/S1_3) PR714.2 PR718.1 PU700.6(PHASE2)
LX2_IA: PL613.4 PR676.1 PU613.11(SW1) PU613.12(SW2)
LX_1.05VALWP: PC304.2 PL301.1 PR303.1 PU301.6(LX1) PU301.19(LX2) PU301.20(LX3)
LX_1.8VALW: PL501.1 PR502.1 PU501.3(LX)
LX_1V_PRIM_CORE: PL404.1 PR409.1 PU402.2(SW1) PU402.3(SW2)
LX_1VS_VCCIO: PL402.1 PR405.1 PU401.2(SW1) PU401.3(SW2)
LX_3V: PC102.2 PL100.1 PR106.1 PU100.6(LX1) PU100.19(LX2) PU100.20(LX3)
LX_5V: PC114.2 PL101.1 PR112.1 PU102.6(LX1) PU102.19(LX2) PU102.20(LX3)
LX_DDR: PC205.2 PL201.1 PR202.1 PU200.11(LX)
LX_GT: PL612.4 PR669.1 PU612.11(SW1) PU612.12(SW2)
LX_SA: PL614.4 PQ614.9(D2/S1) PR619.2 PR627.1 PU614.8(PHASE)
M2280_DEVSLP: JNGFF3.38(DEVSLP) RN37.2 UC1.CM8(GPP_E6/DEVSLP2)
M2280_PCIE_SATA#: JNGFF3.69(PEDET(NC-PCIE/GND-SATA)) RC730.1 RC764.2 UC1.CP10(GPP_E2/SATAXPCIE2/SATAGP2)
M3042_DEVSLP: JNGFF2.30(DEVSLP) RC865.2 UC1.CR8(GPP_E5/DEVSLP1)
M3042_PCIE#_SATA: RC521.1 RC766.2 UC1.CM10(GPP_E1/SATAXPCIE1/SATAGP1) UE1.J12(GPIO043/SB-TSI_CLK)
M_BIST: RZ1415.2 UE1.N8(GPI0040/GPTP-OUT2)
M_BIST_R: CZ218.1 DZ12.2 QZ21.2(BASE) RZ1413.2 RZ1415.1 RZ1482.2
MASK_BASE_LEDS#: QZ7.2(G2) UZ10.4(O)
ME_FWP: RC221.1 SW1.1(A) UE1.G12(GPIO105/UART0_RX)
ME_FWP_PCH: RC221.2 RC562.1 SW1.3(C)
MEC_XTAL1: CE28.1 UE1.A1(XTAL1) YE1.1
MEC_XTAL2: CE29.1 RE290.2 YE1.2
MEC_XTAL2_R: RE290.1 UE1.A3(XTAL2)
MEDIACARD_IRQ#: RR19.1 UC1.CG20(GPP_D0/SPI1_CS0#/BK0/SBK0) UR1.32(WAKE#)
MEM_INTERLEAVED: RC843.1 RC844.2 UC1.CE9(GPP_E3/CPU_GP0)
MEM_SMBCLK: CC320.1 QC2.6(D2) RC12.1 UC1.CK14(GPP_C0/SMBCLK)
MEM_SMBDATA: QC2.3(D1) RC14.1 UC1.CH15(GPP_C1/SMBDATA)
MSCLK: JDEG1.6 RE30.1 RE72.2 UE1.H10(GPIO170/TFDP_CLK/UART1_TX)
MSDATA: JDEG1.7 RE75.2 RE86.1 UE1.G9(GPIO171/TFDP_DATA/UART1_RX)
MUX1_DP_SEL: RT89.1 UT9.35(CE_DP)
MUX1_FLIP_SEL: RT69.2 UT9.37(FLIP)
MUX1_FLIP_SEL_R: RT69.1 UT5.B2(GPIO0)
MUX1_USB_SEL: RT90.1 RT308.1 UT9.36(CE_USB)
NB_MODE#: T348.1 UE1.J6(GPIO202/ADC02)
NB_MUTE#: DA8.1 RA48.1 UE1.A4(GPIO022/GPTP-IN0)
NB_PSID: PD4.2 PD4.3 PJPDC1.1 PL3.2
NFC_ACTIVITY_STATUS#_R: JUSH1.2 RZ1473.2
NGFF_CONFIG_0: JNGFF2.13(CONFIG_0) RE725.1 UE1.N9(GPIO152/GPTP-OUT3)
NGFF_CONFIG_1: JNGFF2.61(CONFIG1/PEDET_OC-PCIE/GND-SATA) RE723.1 UE1.M10(GPIO151/ICT4)
NGFF_CONFIG_2: JNGFF2.67(CONFIG2/USB3.0IND/GND-OTHER) RE724.1 UE1.N10(GPIO132/SMB06_DATA)
NGFF_CONFIG_3: JNGFF2.1(CONFIG_3) RE726.1 UE1.F4(GPIO041/SYS_SHDN#)
NO_SMOKE_OVP: PC3008.1 PC3009.1 PD3001.2 PQ3000.5(G2) PR3012.2
NO_SMOKE_UVP: PC3010.1 PC3011.1 PD3002.2 PQ3000.2(G1) PR3013.2
NRB_BIT: RC831.2 UC1.CE29(GPP_B18/GSPI0_MOSI)
NTC_A_GT: PR635.2 PU602.15(NTC_A)
NTC_B_IA: PR610.2 PU602.3(NTC_B)
NVME_LED#: JNGFF3.10(DAS/DSS#) RN100.1
ONE_DIMM#: RC53.1 UC1.CE28(GPP_B16/GSPI0_CLK)
OTG_ID: RT74.1 UT5.E10(GPIO5)
OTGEN/CMIN_CHG: PR709.2 PR712.2 PR746.2 PU700.20(OTGEN/CMIN)
OTGPG/CMOUT_CHG: PR726.2 PR727.2 PR745.2 PU700.26(OTGPG/CMOUT)
P_SENSOR_PWR_SAVE#: T400.1 UC1.CP12(GPP_C21/UART2_TXD)
PANEL_BKEN_EC: DV2.2 UE1.J9(GPIO015/PWM7)
PANEL_BKLEN: DV2.3 UC1.CK11(EDP_BKLTEN)
PANEL_MONITOR: RV628.2 UE1.M8(GPIO231)
PANEL_PWRGD: CV632.1 QV19.1(COLLECTOR) QV21.1(COLLECTOR) RV623.2 RV624.1 RV628.1
PBAT_CHARGER_SMBCLK: PD2.3 PR38.2 PR715.1 RE43.1 UE1.N2(GPIO131/SMB10_CLK/TOUT0)
PBAT_CHARGER_SMBDAT: PD1.2 PR39.2 PR713.1 RE37.1 UE1.M3(GPIO130/SMB10_DATA/TOUT1)
PBAT_PRES#: PD1.3 PR1.2 PR40.2 PR724.1 UE1.F9(GPIO175)
PBAT_PRES#_C: PBATT1.6 PR40.1
PBAT_SMBCLK_C: PBATT1.4 PR38.1
PBAT_SMBDAT_C: PBATT1.5 PR39.1
PCH_3.3V_TS_EN: RC747.1 RV324.1 UC1.CC30(GPP_B21/GSPI1_MISO)
PCH_BATLOW#: RC72.1 UC1.BV36(GPD0/BATLOW#)
PCH_CL_CLK1: JNGFF1.42(CLINK_CLK) UC1.CH7(CL_CLK)
PCH_CL_DATA1: JNGFF1.40(CLINK_DATA) UC1.CH8(CL_DATA)
PCH_CL_RST1#: JNGFF1.38(CLINK_RST) UC1.CH9(CL_RST#)
PCH_DP2_HPD_R: RT73.1 UT5.C10(GPIO4)
PCH_DPWROK: CC266.1 RC215.1 RC220.1 RE536.1 UC1.BP30(DSW_PWROK)
PCH_DPWROK_EC: RE536.2 UE1.F8(GPIO020)
PCH_HDD_EN: RZ148.1 UC1.CG14(GPP_C15/UART1_CTS#/ISH_UART1_CT)
PCH_JTAG_TCK: JXDP1.55 RC86.1 UC1.W6(PCH_TCK)
PCH_JTAG_TDI: CC304.1 RC569.1 RC736.2 UC1.U5(PCH_TDI)
PCH_JTAG_TDO: CC303.1 RC568.1 RC737.2 UC1.W5(PCH_TDO)
PCH_JTAG_TMS: RC130.1 RC735.2 UC1.P5(PCH_TMS)
PCH_PCIE_WAKE#: RC67.1 RE274.2 UC1.BU30(WAKE#) UE1.L1(GPIO216/ADC14)
PCH_PLTRST#: RC60.1 RC237.1 RC739.1 UC1.BJ35(GPP_B13/PLTRST#) UC7.1(B) UC7.2(A)
PCH_PLTRST#_AND: CC196.1 JIRTS1.1 JNGFF1.52(PERST0#) JNGFF3.50(PERST#) RC65.1 RC738.1 RZ1481.2 UC7.4(O) UR1.1(PERST#) UZ52.A1(B)
PCH_POPIRCOMP: RC107.1 UC1.BW25(PCH_OPIRCOMP)
PCH_PRIM_EN: PR312.1 PR406.1 PR504.1 RC441.2 RC442.2 RZ64.1
PCH_PWROK: PR614.1 RC536.1 UC1.BP31(PCH_PWROK)
PCH_RSMRST#: RE342.1 RZ400.1 RZ1413.1 UE1.M5(GPIO055/PWM2/SHD_CS#/(RSMRST#))
PCH_RSMRST#_AND: RC75.1 RC124.1 RC215.2 UC1.BR36(RSMRST#) UZ41.4(O)
PCH_RTCRST#: CC25.1 CMOS1.1 JAPS1.9 RC57.1 RE94.2 UC1.BR34(RTCRST#)
PCH_RTCX1: RC403.1 UC1.BN31(RTCX1)
PCH_RTCX1_R: CC23.1 RC66.2 RC403.2 YC2.1
PCH_RTCX2: RC404.1 UC1.BN32(RTCX2)
PCH_RTCX2_R: RC66.1 RC404.2 RC532.1
PCH_SMB_ALERT#: RC266.1 UC1.CJ15(GPP_C2/SMBALERT#)
PCH_SPI_CLK: JSPI1.8 RC27.1 RC96.1 UC1.CH37(SPI0_CLK)
PCH_SPI_CLK_0_R: RC299.1 RC571.2 UC5.6(CLK)
PCH_SPI_CLK_1_R: RC289.1 RC575.2 UC6.6(CLK)
PCH_SPI_CLK_2_R: RZ60.2 RZ63.2 UZ12.19(SPI_CLK)
PCH_SPI_CLK_R1: JSPI1.7 RC27.2 RC571.1 RC575.1 RZ60.1
PCH_SPI_CS#0: JSPI1.10 RC28.1 UC1.CG36(SPI0_CS0#)
PCH_SPI_CS#0_R1: JSPI1.9 RC28.2 RC32.1
PCH_SPI_CS#0_R2: RC32.2 UC5.1(CS#)
PCH_SPI_CS#1: JSPI1.2 RC24.1 UC1.CG35(SPI0_CS1#)
PCH_SPI_CS#1_R1: JSPI1.1 RC24.2 RC302.1
PCH_SPI_CS#1_R2: RC302.2 UC6.1(CS#)
PCH_SPI_CS#2: RZ61.1 UC1.CH34(SPI0_CS2#)
PCH_SPI_CS#2_R: RZ61.2 UZ12.20(SPI_CS#)
PCH_SPI_D0: JSPI1.4 RC25.1 RC94.2 RC505.2 RC518.1 UC1.CF36(SPI0_MOSI)
PCH_SPI_D0_0_R: RC570.2 UC5.5(DI)
PCH_SPI_D0_1_R: RC574.2 UC6.5(DI(IO0))
PCH_SPI_D0_2_R: RZ59.2 UZ12.21(MOSI)
PCH_SPI_D0_R1: JSPI1.3 RC25.2 RC570.1 RC574.1 RZ59.1
PCH_SPI_D1: JSPI1.6 RC26.1 UC1.CF37(SPI0_MISO)
PCH_SPI_D1_0_R: RC734.2 UC5.2(DO)
PCH_SPI_D1_1_R: RC573.2 UC6.2(DO(IO1))
PCH_SPI_D1_2_R: RZ58.2 UZ12.24(MISO)
PCH_SPI_D1_R1: JSPI1.5 RC26.2 RC573.1 RC734.1 RZ58.1
PCH_SPI_D2: JSPI1.12 RC11.2 RC29.1 RC61.2 RC519.1 UC1.CF34(SPI0_IO2)
PCH_SPI_D2_0_R: RC33.2 UC5.3(IO2)
PCH_SPI_D2_1_R: RC35.2 UC6.3(IO2)
PCH_SPI_D2_R1: JSPI1.11 RC29.2 RC33.1 RC35.1
PCH_SPI_D3: JSPI1.14 RC30.1 RC62.2 RC515.1 UC1.CG34(SPI0_IO3)
PCH_SPI_D3_0_R: RC572.2 UC5.7(IO3)
PCH_SPI_D3_1_R: RC576.2 UC6.7(IO)
PCH_SPI_D3_R1: JSPI1.13 RC30.2 RC572.1 RC576.1
PCH_SPI_DO2_XDP: JXDP1.60 RC11.1
PCH_SPI_DO_XDP: RC128.1 RC133.1 RC505.1
PCIE_PRX_C_DTX_N8: CR14.2 UR1.8(HSON)
PCIE_PRX_C_DTX_N9: CL2.2 UL1.39(PETN)
PCIE_PRX_C_DTX_N12: JNGFF2.35(PERP0/SATA-B-) RZ1477.1
PCIE_PRX_C_DTX_N13: JNGFF3.5(PERN3) RN127.1
PCIE_PRX_C_DTX_N14: JNGFF3.17(PERN2) RN125.1
PCIE_PRX_C_DTX_N15: JNGFF3.29(PERN1) RN82.1
PCIE_PRX_C_DTX_N16: JNGFF3.43(PERP0/SATA-B-) RN78.1
PCIE_PRX_C_DTX_P8: CR13.2 UR1.7(HSOP)
PCIE_PRX_C_DTX_P9: CL1.2 UL1.38(PETP)
PCIE_PRX_C_DTX_P12: JNGFF2.33(PERN0/SATA-B+) RZ1476.1
PCIE_PRX_C_DTX_P13: JNGFF3.7(PERP3) RN128.1
PCIE_PRX_C_DTX_P14: JNGFF3.19(PERP2) RN126.1
PCIE_PRX_C_DTX_P15: JNGFF3.31(PERP1) RN81.1
PCIE_PRX_C_DTX_P16: JNGFF3.41(PERN0/SATA-B+) RN77.1
PCIE_PRX_DTX_N8: CR14.1 UC1.BU9(PCIE8_RXN)
PCIE_PRX_DTX_N9: CL2.1 UC1.BP5(PCIE9_RXN)
PCIE_PRX_DTX_N10: JNGFF1.43(PERN0) UC1.BN6(PCIE10_RXN)
PCIE_PRX_DTX_N12: RZ1477.2 UC1.BL6(PCIE12_RXN/SATA1A_RXN)
PCIE_PRX_DTX_N13: RN127.2 UC1.BK6(PCIE13_RXN)
PCIE_PRX_DTX_N14: RN125.2 UC1.BJ6(PCIE14_RXN)
PCIE_PRX_DTX_N15: RN82.2 UC1.BG5(PCIE15_RXN/SATA1B_RXN)
PCIE_PRX_DTX_N16: RN78.2 UC1.BE5(PCIE16_RXN/SATA2_RXN)
PCIE_PRX_DTX_P8: CR13.1 UC1.BU8(PCIE8_RXP)
PCIE_PRX_DTX_P9: CL1.1 UC1.BP6(PCIE9_RXP)
PCIE_PRX_DTX_P10: JNGFF1.41(PERP0) UC1.BN5(PCIE10_RXP)
PCIE_PRX_DTX_P12: RZ1476.2 UC1.BL5(PCIE12_RXP/SATA1A_RXP)
PCIE_PRX_DTX_P13: RN128.2 UC1.BK5(PCIE13_RXP)
PCIE_PRX_DTX_P14: RN126.2 UC1.BJ5(PCIE14_RXP)
PCIE_PRX_DTX_P15: RN81.2 UC1.BG6(PCIE15_RXP/SATA1B_RXP)
PCIE_PRX_DTX_P16: RN77.2 UC1.BE6(PCIE16_RXP/SATA2_RXP)
PCIE_PTX_C_DRX_N8: CR12.2 UR1.4(HSIN)
PCIE_PTX_C_DRX_N9: CL6.2 UL1.42(PERN)
PCIE_PTX_C_DRX_N10: CZ13.2 JNGFF1.37(PETN0)
PCIE_PTX_C_DRX_N12: CZ10.2 JNGFF2.39(PETN0/SATA-A-)
PCIE_PTX_C_DRX_N13: CN65.1 JNGFF3.11(PETN3)
PCIE_PTX_C_DRX_N14: CN67.1 JNGFF3.23(PETN2)
PCIE_PTX_C_DRX_N15: CN69.1 JNGFF3.35(PETN1)
PCIE_PTX_C_DRX_N16: CN71.1 JNGFF3.47(PETN0/SATA-A-)
PCIE_PTX_C_DRX_P8: CR11.2 UR1.3(HSIP)
PCIE_PTX_C_DRX_P9: CL5.2 UL1.41(PERP)
PCIE_PTX_C_DRX_P10: CZ12.2 JNGFF1.35(PETP0)
PCIE_PTX_C_DRX_P12: CZ11.2 JNGFF2.41(PETP0/SATA-A+)
PCIE_PTX_C_DRX_P13: CN66.1 JNGFF3.13(PETP3)
PCIE_PTX_C_DRX_P14: CN68.1 JNGFF3.25(PETP2)
PCIE_PTX_C_DRX_P15: CN70.1 JNGFF3.37(PETP1)
PCIE_PTX_C_DRX_P16: CN72.1 JNGFF3.49(PETP0/SATA-A+)
PCIE_PTX_DRX_N8: CR12.1 UC1.BT4(PCIE8_TXN)
PCIE_PTX_DRX_N9: CL6.1 UC1.BR2(PCIE9_TXN)
PCIE_PTX_DRX_N10: CZ13.1 UC1.BR4(PCIE10_TXN)
PCIE_PTX_DRX_N12: CZ10.1 UC1.BN2(PCIE12_TXN/SATA1A_TXN)
PCIE_PTX_DRX_N13: CN65.2 UC1.BM4(PCIE13_TXN)
PCIE_PTX_DRX_N14: CN67.2 UC1.BL2(PCIE14_TXN)
PCIE_PTX_DRX_N15: CN69.2 UC1.BL4(PCIE15_TXN/SATA1B_TXN)
PCIE_PTX_DRX_N16: CN71.2 UC1.BJ4(PCIE16_TXN/SATA2_TXN)
PCIE_PTX_DRX_P8: CR11.1 UC1.BT3(PCIE8_TXP)
PCIE_PTX_DRX_P9: CL5.1 UC1.BR1(PCIE9_TXP)
PCIE_PTX_DRX_P10: CZ12.1 UC1.BR3(PCIE10_TXP)
PCIE_PTX_DRX_P12: CZ11.1 UC1.BN1(PCIE12_TXP/SATA1A_TXP)
PCIE_PTX_DRX_P13: CN66.2 UC1.BM3(PCIE13_TXP)
PCIE_PTX_DRX_P14: CN68.2 UC1.BL1(PCIE14_TXP)
PCIE_PTX_DRX_P15: CN70.2 UC1.BL3(PCIE15_TXP/SATA1B_TXP)
PCIE_PTX_DRX_P16: CN72.2 UC1.BJ3(PCIE16_TXP/SATA2_TXP)
PCIE_RCOMPN: RC50.1 UC1.CE6(PCIE_RCOMP_N)
PCIE_RCOMPP: RC50.2 UC1.CE5(PCIE_RCOMP_P)
PCIE_WAKE#: JNGFF1.55(PEWAKE0#) JNGFF3.54(PEWAKE#) RE274.1 RE275.1 UZ51.1(B2)
PCIE_WAKE#_R: RE35.1 RE275.2 UE1.N13(GPIO025/TIN0/NEM_INT/UART_CLK)
PD1_GPIO2: RT71.1 UT5.D10(GPIO2)
PD1_GPIO6: RT75.1 UT5.G10(GPIO6)
PD1_GPIO7: RT339.1 UT5.D7(GPIO7)
PD1_GPIO8: RT76.1 RT377.1 UT5.H6(GPIO8)
PD#: CA31.1 DA8.2 RA18.1 RA48.2 RA50.2 UA1.40(PDB)
PECI_EC: RE60.2 UC1.AR1(PECI)
PECI_EC_R: RE60.1 UE1.K13(GPIO042/PECI_DAT/SB-TSI_DAT)
PGOOD_3V: PR107.2 PR119.1 PU100.9(PG)
PGOOD_5V: PR113.2 PR120.1 PU102.9(PG)
PLTRST_LAN#: RC739.2 UL1.36(PE_RST_N)
PLTRST_TPM#: RC60.2 RC738.2 UZ12.17(SPI_RST#)
PM_LANPHY_ENABLE: RL7.1 UC1.BU34(GPD11/LANPHYPC)
PME#: T12.1 UC1.CA32(GPP_A11/PME#/GSPI1_CS1#/SD_VDD2)
POWER_SW#_MB: CE10.1 JAPS1.11 RE33.2 RZ1414.1 SW3.2 SW3.4
POWER_SW#_MB_USH: JUSH1.26 RZ1414.2
POWER_SW_IN#: CE12.1 CE69.1 QZ21.3(EMITTER) RE31.2 RE33.1 UE1.D5(GPIO163/VCI_IN0#)
PRIM_CORE_OPT_DIS: RC862.1 RC867.1 UC1.CC27(GPP_B15/GSPI0_CS0#) UC9.1(INB)
PRIM_PWRGD: CE68.1 RE361.1 UE1.L7(GPIO227/SHD_IO2)
PRIVACY_ENABLE: JEDP1.3 RE92.1 RV802.1 UE1.F5(GPIO214/ADC12)
PROCHOT#: PC605.2 PR678.1 PR719.1 PR745.1 RC84.1 RC558.2 RE288.2
PROCHOT#_CHG: PQ812.1(D) PR719.2 PU700.23(PROCHOT#)
PROCHOT#_R: RC84.2 UC1.Y4(PROCHOT#)
PROCHOT#_R1: RE288.1 UE1.H13(GPIO160/PWM11/PROCHOT#)
PROG1_CPU_CORE: PR608.1 PU602.32(PROG1)
PROG2_CPU_CORE: PR611.1 PU602.31(PROG2)
PROG_CHG: PR725.1 PU700.27(PROG)
PROM_BIOS: RZ400.2 RZ401.2 UZ41.1(B)
PROM_BIOS_R: JSPI1.17 RZ401.1
PS8802_ADDR: RT135.1 RT136.1 UT9.19(ADDR)
PS8802_CEQ: RT139.1 RT140.1 UT9.48(CEQ)
PS8802_CSCL: QT10.1(S2) RT305.1 UT9.28(CSCL)
PS8802_CSDA: QT10.4(S1) RT304.1 UT9.29(CSDA)
PS8802_DPEQ: RT137.1 RT138.1 UT9.22(DPEQ)
PS8802_HPD: RT380.2 UT9.40(IN_HPD)
PS8802_REXT: RT300.1 UT9.39(REXT)
PS8802_RST#: CT122.1 RT246.2 UT9.43(RESET#)
PS8802_SBU1_R: RT132.1 RT414.1 UT9.33(SBU1)
PS8802_SBU2_R: RT133.1 RT415.1 UT9.34(SBU2)
PS8802_SSEQ: RT141.1 RT142.1 UT9.46(SSEQ)
PS_ID: PR4.1 PR5.2 UE1.J8(GPIO056/PWM3/SHD_CLK)
PSYS_CHG: PR731.1 PU700.30(PSYS)
PSYS_CPU_CORE: PR620.2 PR693.2 PU602.1(PSYS)
PWM1_B_IA: PR687.1 PU602.12(PWM1_B)
PWM1_IA: PR687.2 PU610.1(PWM)
PWM2_B_IA: PR692.1 PU602.13(PWM2_B)
PWM2_IA: PR692.2 PU613.1(PWM)
PWM_A_GT: PR664.1 PU602.22(PWM_A)
PWM_C_SA: PR606.2 PU602.30(PWM_C)
PWM_FAN1: DE22.2 JFAN1.2 RE48.2 UE1.L10(GPIO053/PWM0/GPWM0)
PWM_GT: PR664.2 PU612.1(PWM)
PWM_SA: PR606.1 PU614.3(PWM)
REFCLK_CNV: CC1477.1 LC5.1 RC751.2 UC1.CM3(CLKIN_XTAL)
REFCLK_CNV_L: JNGFF1.64(RSVD_1) LC5.2 RZ752.1
REM_DIODE1_N: CE24.1 CE35.1 QE3.3(EMITTER) UE1.A8(DN1_DP1A)
REM_DIODE1_P: CE24.2 CE35.2 QE3.1(COLLECTOR) QE3.2(BASE) UE1.A7(DP1_DN1A)
REM_DIODE2_N: CE26.1 CE37.2 CE46.2 QE5.3(EMITTER) QE7.1(COLLECTOR) QE7.2(BASE) UE1.A10(DN2_DP2A)
REM_DIODE2_P: CE26.2 CE37.1 CE46.1 QE5.1(COLLECTOR) QE5.2(BASE) QE7.3(EMITTER) UE1.A9(DP2_DN2A)
REM_DIODE4_N: CE27.1 CE39.1 QE6.3(EMITTER) UE1.A11(DN4_DP4A)
REM_DIODE4_P: CE27.2 CE39.2 QE6.1(COLLECTOR) QE6.2(BASE) UE1.B10(DP4_DN4A)
RES_BIAS: RL13.1 UL1.12(RBIAS)
RESET_IN#: RE362.1 UE1.C1(GPIO024/NRESETI)
RESET_OUT: RE548.2 UE1.G4(GPIO106/PWROK)
RESET_OUT#_R: CC334.1 JXDP1.47 RC128.2 RC129.2
RING2: LA10.1 RA5.2 UA1.13(MIC2-L/RING2)
RING2_R: CA4.1 CA13.2 DA3.3 JHP1.4(#4 G/M) LA10.2
RJ45_MDIN0: JLOM1.2(PR1-) TL1.23(TX1-)
RJ45_MDIN1: JLOM1.6(PR2-) TL1.19(TX2-)
RJ45_MDIN2: JLOM1.5(PR3-) TL1.17(TX3-)
RJ45_MDIN3: JLOM1.8(PR4-) TL1.13(TX4-)
RJ45_MDIP0: JLOM1.1(PR1+) TL1.24(TX1+)
RJ45_MDIP1: JLOM1.3(PR2+) TL1.20(TX2+)
RJ45_MDIP2: JLOM1.4(PR3+) TL1.18(TX3+)
RJ45_MDIP3: JLOM1.7(PR4+) TL1.14(TX4+)
RTC_DET#: PQ13.1(D) RC866.1 UC1.CF22(GPP_D3/SPI1_MOSI_IO0/BK3/SBK3)
RTCRST_ON: QE12.2(G) RE93.1 UE1.F11(GPIO122/BCM0_DAT/PVT_IO1)
RTCRST_ON_POWER: RE565.2 UE1.B13(GPIO127/A20M/UART0_CTS#)
RTCRST_ON_R: CE65.1 DE2.2 QE17.2(G) RE543.1
RTCX2: CC26.1 RC532.2 YC2.2
RUN_ON: PR402.1 PR511.1 QE2.2(G2) RE280.2 RE292.1 RZ320.1 RZ345.1 RZ1423.1 UE5.4(O) UZ3.5(ON2) UZ35.2(A) UZ47.3(ON1) UZ54.1(INB)
RUN_ON#: QE2.5(G1) QE2.6(D2) RE68.1
RUN_ON_1.8V: CZ197.1 RZ345.2 UZ8.3(ON)
RUN_ON_EC: RE292.2 RE718.2 UE1.E8(GPIO045) UE5.2(A)
RUNPWROK: QE2.3(D1) RE67.1 UE1.G3(GPIO057/VCC_PWRGD)
S1_OVP: PQ10.3(D2) PR32.2 PR46.1 PR836.2
SATA_PRX_C_DTX_N0: CN6.1 JSATA1.5
SATA_PRX_C_DTX_P0: CN7.1 JSATA1.6
SATA_PRX_C_RD_DTX_N11: CN14.2 UN7.4(BO-)
SATA_PRX_C_RD_DTX_P11: CN15.2 UN7.5(BO+)
SATA_PRX_DTX_N11: CN14.1 UC1.BN10(PCIE11_RXN/SATA0_RXN)
SATA_PRX_DTX_P11: CN15.1 UC1.BN8(PCIE11_RXP/SATA0_RXP)
SATA_PRX_RD_DTX_N0: CN6.2 UN7.12(BI-)
SATA_PRX_RD_DTX_P0: CN7.2 UN7.11(BI+)
SATA_PTX_C_DRX_N0: CN5.1 JSATA1.3
SATA_PTX_C_DRX_P0: CN4.1 JSATA1.2
SATA_PTX_C_RD_DRX_N11: CN13.2 UN7.2(AI-)
SATA_PTX_C_RD_DRX_P11: CN12.2 UN7.1(AI+)
SATA_PTX_DRX_N11: CN13.1 UC1.BN4(PCIE11_TXN/SATA0_TXN)
SATA_PTX_DRX_P11: CN12.1 UC1.BN3(PCIE11_TXP/SATA0_TXP)
SATA_PTX_RD_DRX_N0: CN5.2 UN7.14(AO-)
SATA_PTX_RD_DRX_P0: CN4.2 UN7.15(AO+)
SBIOS_TX: RE306.1 UC1.CP14(GPP_C9/UART0_TXD)
SCL_CHG: PR715.2 PU700.22(SCL)
SD/MMCCD#: JSD1.9(CD) UR1.30(SD_CD#)
SD/MMCCLK: RR5.1 UR1.17(SP3)
SD/MMCCLK_R: CR21.1 JSD1.5(CLK) RR5.2
SD/MMCCMD: RR6.1 UR1.19(SP4)
SD/MMCCMD_R: JSD1.3(CMD) RR6.2
SD/MMCDAT0/RCLK+: RR10.1 UR1.16(SP2)
SD/MMCDAT0/RCLK+_R: JSD1.7(DAT0/RCLK+) RR10.2
SD/MMCDAT1/RCLK-: RR9.1 UR1.15(SP1)
SD/MMCDAT1/RCLK-_R: JSD1.8(DAT1/RCLK-) RR9.2
SD/MMCDAT2: RR8.1 UR1.21(SP6)
SD/MMCDAT2_R: JSD1.1(DAT2) RR8.2
SD/MMCDAT3: RR7.1 UR1.20(SP5)
SD/MMCDAT3_R: JSD1.2(CD/DAT3) RR7.2
SD_GPIO: RR3.2 UR1.28(GPIO)
SD_RCOMP: RC116.1 UC1.CK33(SD_1P8_RCOMP) UC1.CM34(SD_3P3_RCOMP)
SD_UHS2_D0N: JSD1.19(D0-) UR1.25(SD_LN0_M)
SD_UHS2_D0P: JSD1.18(D0+) UR1.26(SD_LN0_P)
SD_UHS2_D1N: JSD1.21(D1-) UR1.23(SD_LN1_M)
SD_UHS2_D1P: JSD1.22(D1+) UR1.22(SD_LN1_P)
SDA_CHG: PR713.2 PU700.21(SDA)
SDWP: QR1.1(D) UR1.29(SP7)
SIM_DET: DZ13.5 DZ13.6 JNGFF2.58(SIM DETECT) JSIM1.2(DTSW)
SIO_EXT_WAKE#: RC748.1 RE703.1 UC1.CG12(GPP_C12/UART1_RXD/ISH_UART1_RXD)
SIO_EXT_WAKE#_EC: RE703.2 UE1.M12(GPIO120)
SIO_PWRBTN#: CC269.1 JXDP1.41 RC241.1 UC1.BU28(GPD3/PWRBTN#) UE1.K11(GPIO113/PS2_DAT1A)
SIO_SLP_A#: CC1469.1 JAPS1.6 RC233.1 UC1.BU37(GPD6/SLP_A#)
SIO_SLP_LAN#: CC1471.1 RC68.1 RC344.1 RC761.1 UC1.BT31(SLP_LAN#) UZ43.5(ON2)
SIO_SLP_S0#: JAPS1.15 PR425.1 RC660.1 RC763.1 RZ112.1 RZ362.2 RZ1407.1 RZ1419.1 UC1.BJ37(GPP_B12/SLP_S0#) UC9.2(INA)
SIO_SLP_S3#: CC1468.1 JAPS1.2 QE11.2(G) RC231.1 RE280.1 RZ1416.1 RZ1418.1 UC1.BU36(GPD4/SLP_S3#) UE3.2(A) UE5.1(B)
SIO_SLP_S4#: CC1467.1 JAPS1.5 PR208.1 PR513.1 RC232.1 RZ1417.1 UC1.BU27(GPD5/SLP_S4#)
SIO_SLP_S4#_R: PC221.1 PR208.2 PR209.1 PU200.1(S5)
SIO_SLP_S5#: JAPS1.4 RC230.1 UC1.BT29(GPD10/SLP_S5#)
SIO_SLP_SUS#: CC1465.1 RC229.1 RC441.1 RE349.1 UC1.BU29(SLP_SUS#)
SIO_SLP_SUS#_R: RE349.2 RE561.1 UE1.N4(GPIO230)
SIO_SLP_WLAN#: CC1470.1 QZ15.1(D) RC234.1 UC1.BT30(GPD9/SPL_WLAN#)
SKP_DET#: T384.1 UC1.CK34(GPP_G7/SD_WP)
SKTOCC#: RC565.1 UC1.E1(SKTOCC#)
SLEEVE: LA11.1 RA6.2 UA1.14(MIC2-R/SLEEVE)
SLEEVE_R: CA1.1 CA12.1 DA3.2 JHP1.3(#3 M/G) LA11.2
SLOT2_SATA_LED#: JNGFF2.10(GPIO_9/DAS/DSS#) RN101.1
SLP_WLAN#_GATE: QZ15.2(G) RE552.1 RZ518.2
SLP_WLAN#_GATE_R: RE552.2 UE1.K10(GPIO114/PS2_CLK0A/NEC_SCI)
SLP_WLAN#_M: DZ9.3 QZ15.3(S) RZ71.1
SM_RCOMP0: RC5.1 UC1.BN28(DDR_RCOMP_0)
SM_RCOMP1: RC504.1 UC1.BN27(DDR_RCOMP_1)
SM_RCOMP2: RC7.1 UC1.BN29(DDR_RCOMP_2)
SML0_SMBCLK: CC318.1 RC347.1 RC506.1 UC1.CH14(GPP_C3/SML0CLK) UL1.28(SMB_CLK)
SML0_SMBDATA: RC20.1 RC348.1 UC1.CF15(GPP_C4/SML0DATA) UL1.31(SMB_DATA)
SML0B_SMBCLK: CC1476.1 RC829.1 UC1.CN23(GPP_D14/ISH_UART0_TXD)
SML0B_SMBDATA: RC830.1 UC1.CM24(GPP_D13/ISH_UART0_RXD)
SML1_SMBCLK: CC319.1 RC15.1 UC1.CN15(GPP_C6/SML1CLK) UE1.D8(GPIO010/SMB03_CLK/PS2_DAT0B)
SML1_SMBDATA: RC507.1 UC1.CM15(GPP_C7/SML1DATA) UE1.E11(GPIO007/SMB03_DATA/PS2_CLK0B)
SNUB1_CHG: PC746.1 PR717.2
SNUB1_IA: PC662.1 PR663.2
SNUB2_CHG: PC747.1 PR718.2
SNUB2_IA: PC678.1 PR676.2
SNUB_1.05VALWP: PC302.1 PR303.2
SNUB_1.8VALW: PC506.1 PR502.2
SNUB_1V_PRIM_CORE: PC419.1 PR409.2
SNUB_1VS_VCCIO: PC401.1 PR405.2
SNUB_3V: PC112.1 PR106.2
SNUB_5V: PC125.1 PR112.2
SNUB_DDR: PC204.1 PR202.2
SNUB_GT: PC670.1 PR669.2
SNUB_SA: PC622.1 PR627.2
SPKR: RA12.2 RC183.1 UC1.CF35(GPP_B14/SPKR)
SPKR_R: CA27.1 CA72.1 RA12.1 RA51.1
SRTCRST#: CC24.1 RC56.1 UC1.BR37(SRTCRST#)
SS_1V_PRIM_CORE: PR428.1 PU402.7(SS)
SS_1VS_VCCIO: PR427.1 PU401.7(SS)
SSD_EN: RZ1471.2 UZ53.3(ON) UZ54.4(O)
SSD_SCP#: RE821.1 RN129.2 UE1.L6(GPIO224/GPTP-IN4/SHD_IO1)
SSD_SCP_PWR_EN: QZ22.3(S) UE1.M1(GPIO100/NEC_SCI)
SSD_SCP_PWR_EN_D: QZ22.1(D) RZ1471.1 RZ1472.2 RZ1474.1 UZ54.2(INA)
SUSCLK: CC93.2 RC48.1 RN99.2 RZ56.1 UC1.BT32(GPD8/SUSCLK)
SUSCLK_R: JNGFF3.68(SUSCLK(32KHZ)) RN99.1
SVID_ALERT#_PWR_CPU: PR625.2 PU602.36(ALERT#)
SVID_CLK_PWR_CPU: PR618.2 PU602.37(SCLK)
SVID_DAT_PWR_CPU: PR626.2 PU602.35(SDA)
SW_USB20_N2: LI7.1 UI3.11(DM_IN)
SW_USB20_P2: LI7.4 UI3.10(DP_IN)
SYS_PWROK: RC129.1 RE56.1 RE548.1 UC1.CR10(SYS_PWROK)
SYS_RESET#: CC302.1 JAPS1.13 RC243.2 UC1.CN10(SYS_RESET#)
SYSPWR_PRES: RE57.1 RE58.1 UE1.B1(SYSPWR_PRES)
SYSTEM_ID: CE47.1 RE300.2 UE1.J10(GPIO034/RC_ID1/SPI0_CLK)
TACH_FAN1: DE22.3 JFAN1.3 RE51.2 UE1.E3(GPIO050/FAN_TACH0/GTACH0)
TBT_DET#: RC400.1 RC401.1 UC1.CM22(GPP_D11/ISH_SPI_MISO/GSPI2_MISO)
TBTA_BOT_N: RT122.2 UT5.L7(C_USB_BN)
TBTA_BOT_N_R: DT40.2 DT40.8 JUSBC1.A7(DN1) RT122.1
TBTA_BOT_P: RT123.2 UT5.K7(C_USB_BP)
TBTA_BOT_P_R: DT40.1 DT40.9 JUSBC1.A6(DP1) RT123.1
TBTA_CC1: CT86.1 DT40.4 DT40.7 JUSBC1.B5(CC2) RT104.2 UT5.L9(C_CC1)
TBTA_CC2: CT85.1 DT40.5 DT40.6 JUSBC1.A5(CC1) RT105.2 UT5.L10(C_CC2)
TBTA_DBG_CTL1: RT106.1 UT5.E4(DEBUG_CTL1)
TBTA_DBG_CTL2: RT107.1 UT5.D5(DEBUG_CTL2)
TBTA_DEBUG1: RT92.2 UT5.L2(DEBUG1)
TBTA_DEBUG2: RT93.2 UT5.K2(DEBUG2)
TBTA_DEBUG3: RT89.2 UT5.L3(DIG_AUD_P/DEBUG3)
TBTA_DEBUG4: RT90.2 UT5.K3(DIG_AUD_N/DEBUG4)
TBTA_LSRX_R: RT88.2 UT5.K4(TBT_LSRX/P2R)
TBTA_LSTX_R: RT87.2 UT5.L4(TBT_LSTX/R2P)
TBTA_MRESET: RT86.1 UT5.E11(MRESET)
TBTA_RESET_N_EC_R: RT110.2 UT5.F11(RESET_N)
TBTA_ROM_CLK_PD: RT54.1 UT5.A3(SPI_CLK)
TBTA_ROM_CLK_PD_R: JDB1.2 RT54.2 UT6.6(CLK)
TBTA_ROM_CS#_PD: RT57.1 UT5.B3(SPI_SS_N)
TBTA_ROM_CS#_PD_R: JDB1.5 RT51.2 RT57.2 UT6.1(CS#)
TBTA_ROM_DI_PD: RT55.1 UT5.B4(SPI_MOSI)
TBTA_ROM_DI_PD_R: JDB1.3 RT55.2 UT6.5(DI(IO0))
TBTA_ROM_DO_PD: RT56.1 UT5.A4(SPI_MISO)
TBTA_ROM_DO_PD_R: JDB1.4 RT52.2 RT56.2 UT6.2(DO(IO1))
TBTA_ROM_HOLD#_PD: RT50.2 UT6.7(HOLD#(IO3))
TBTA_ROM_WP#_PD: RT53.2 UT6.3(WP#(IO2))
TBTA_ROSC: RT100.1 UT5.G2(R_OSC)
TBTA_SWD_CLK_R: RT85.1 UT5.G4(SWD_CLK)
TBTA_SWD_DATA_R: RT84.1 UT5.F4(SWD_DATA)
TBTA_TOP_N: RT121.1 UT5.L6(C_USB_TN)
TBTA_TOP_N_R: DT39.5 DT39.6 JUSBC1.B7(DN2) RT121.2
TBTA_TOP_P: RT120.1 UT5.K6(C_USB_TP)
TBTA_TOP_P_R: DT39.4 DT39.7 JUSBC1.B6(DP2) RT120.2
TDI_XDP: JXDP1.56 RC736.1 RC851.2
TDO_XDP: CC306.1 JXDP1.52 RC737.1 RC850.2
THERMTRIP2#: CE36.1 QE4.1(COLLECTOR) RE69.2 UE1.H3(GPIO103/THERMTRIP2#)
TMDSE_CON_CLK: JHDMI1.10(CK+) LV12.3 RV685.2 RV692.2
TMDSE_CON_CLK#: JHDMI1.12(CK-) LV12.2 RV685.1 RV693.2
TMDSE_CON_N0: JHDMI1.9(D0-) LV9.2 RV654.2 RV690.2
TMDSE_CON_N1: JHDMI1.6(D1-) LV6.2 RV684.1 RV689.2
TMDSE_CON_N2: JHDMI1.3(D2-) LV3.2 RV683.2 RV686.2
TMDSE_CON_P0: JHDMI1.7(D0+) LV9.3 RV654.1 RV691.2
TMDSE_CON_P1: JHDMI1.4(D1+) LV6.3 RV684.2 RV688.2
TMDSE_CON_P2: JHDMI1.1(D2+) LV3.3 RV683.1 RV687.2
TMDSE_RP_CLK: LV12.4 RV692.1 UV21.22(OUT_CKP)
TMDSE_RP_CLK#: LV12.1 RV693.1 UV21.21(OUT_CKN)
TMDSE_RP_N0: LV9.1 RV690.1 UV21.24(OUT_D0N)
TMDSE_RP_N1: LV6.1 RV689.1 UV21.26(OUT_D1N)
TMDSE_RP_N2: LV3.1 RV686.1 UV21.29(OUT_D2N)
TMDSE_RP_P0: LV9.4 RV691.1 UV21.25(OUT_D0P)
TMDSE_RP_P1: LV6.4 RV688.1 UV21.27(OUT_D1P)
TMDSE_RP_P2: LV3.4 RV687.1 UV21.30(OUT_D2P)
TOUCH_SCREEN_DET#: JEDP1.32 RV8.1 UC1.CC35(GPP_B4/CPU_GP3)
TOUCH_SCREEN_PD: QC4.5(G1) QC4.6(D2) RC104.2
TOUCH_SCREEN_PD#: QC4.2(G2) RC82.2 RC566.1 UC1.CN3(GPP_E7/CPU_GP1)
TOUCH_SCREEN_PD#_R: JEDP1.5 QC4.3(D1) RC566.2
TOUCHPAD_INTR#: JKBTP1.16 RC567.1 RE318.2 UC1.CB34(GPP_B3/CPU_GP2)
TOUCHPAD_INTR#_R: RE318.1 UE1.G2(GPIO203/ADC03)
TP_DISABLE#: RE605.1 RZ1475.1 UE1.N12(GPIO026/TIN1)
TP_DISABLE#_R: JKBTP1.11 RZ1475.2
TP_LAN_JTAG_TCK: RL2.1 UL1.35(JTAG_TCK)
TP_LAN_JTAG_TDI: T88.1 UL1.32(JTAG_TDI)
TP_LAN_JTAG_TDO: T89.1 UL1.34(JTAG_TDO)
TP_LAN_JTAG_TMS: RL1.1 UL1.33(JTAG_TMS)
TPM_GPIO0: RZ112.2 UZ12.6(GPIO)
TPM_GPIO0_NU: RZ1407.2 UZ12.29(NIC_19)
TPM_PIRQ#: RZ69.2 UC1.CC29(GPP_B20/GSPI1_CLK) UZ12.18(SPI_PIRQ#)
TRST#_XDP: JXDP1.54 RC853.2
TS_I2C_SCL: CV55.1 DZ10.2 JIRTS1.4 RV99.2 UC1.CN11(GPP_C17/I2C0_SCL)
TS_I2C_SDA: CV54.1 DZ10.3 JIRTS1.3 RV98.2 UC1.CM11(GPP_C16/I2C0_SDA)
TS_INT#: JIRTS1.2 RV311.2 RV319.2 UC1.CM12(GPP_C23/UART2_CTS#)
TYPEC_CON_SEL1: RC744.1 RC745.1 UC1.CN14(GPP_C10/UART0_RTS#)
TYPEC_CON_SEL2: RC63.1 RC743.1 UC1.CM14(GPP_C11/UART0_CTS#)
TYPEC_ID: CE62.1 RE343.2 UE1.F2(GPIO033/RC_ID0)
UART_MISO: RT82.1 RT83.2 UT5.F2(UART_RX)
UART_MOSI: RT81.1 RT83.1 UT5.E2(UART_TX)
UG1_CHG: PQ700.1(G1) PU700.11(UGATE1)
UG2_CHG: PQ701.1(G1) PU700.5(UGATE2)
UG_SA: PQ614.1(G1) PU614.1(UGATE)
UIM_CLK: CZ38.1 DZ13.2 DZ13.8 JNGFF2.24(UIM-CLK) JSIM1.C3(CLK)
UIM_DATA: CZ39.1 DZ13.1 DZ13.9 JNGFF2.26(UIM-DATA) JSIM1.C7(IO) RZ335.2
UIM_RESET: CZ40.1 DZ13.4 DZ13.7 JNGFF2.22(UIM-RESET) JSIM1.C2(RST)
UPD1_SMBCLK: QT1.1(S2) RE303.1 RT58.1 UE1.C3(GPIO144/SMB04_CLK/SPI1_CS#/UART)
UPD1_SMBCLK_Q: QT1.6(D2) QT10.6(D2) RT58.2 RT67.1 RT92.1 UT5.B5(I2C_SCL2)
UPD1_SMBDAT: QT1.4(S1) RE302.1 RT59.1 UE1.B4(GPIO143/SMB04_DATA/SPI1_MISO/UA)
UPD1_SMBDAT_Q: QT1.3(D1) QT10.3(D1) RT59.2 RT66.1 RT93.1 UT5.A5(I2C_SDA2)
UPD1_SMBINT#: RE91.1 RT60.1 UE1.F10(GPIO225/UART0_RTS#)
UPD1_SMBUS_ALERT#: RT60.2 RT68.1 UT5.B6(I2C_IRQ2_N)
UPD2_SMBCLK: RE721.1 UE1.D7(GPIO004/SMB00_CLK/SPI0_MOSI)
UPD2_SMBDAT: RE722.1 UE1.E7(GPIO003/SMB00_DATA/SPI0_CS#)
USB2_ID: RC337.1 RT74.2 UC1.CE8(USB2_ID)
USB3_DP2_MRX_C_DTX_N0: CT327.2 JUSBC1.A10(SSRXN2) RT220.1
USB3_DP2_MRX_C_DTX_N1: CT329.2 JUSBC1.B10(SSRXN1) RT222.1
USB3_DP2_MRX_C_DTX_P0: CT326.2 JUSBC1.A11(SSRXP2) RT219.1
USB3_DP2_MRX_C_DTX_P1: CT328.2 JUSBC1.B11(SSRXP1) RT221.1
USB3_DP2_MRX_DTX_N0: RT191.1 UT9.3(RX1N)
USB3_DP2_MRX_DTX_N1: RT195.1 UT9.8(RX2N)
USB3_DP2_MRX_DTX_P0: RT190.1 UT9.2(RX1P)
USB3_DP2_MRX_DTX_P1: RT194.1 UT9.9(RX2P)
USB3_DP2_MRX_R_DTX_N0: CT327.1 DT14.1 RT191.2
USB3_DP2_MRX_R_DTX_N1: CT329.1 DT10.1 RT195.2
USB3_DP2_MRX_R_DTX_P0: CT326.1 DT13.1 RT190.2
USB3_DP2_MRX_R_DTX_P1: CT328.1 DT9.1 RT194.2
USB3_DP2_MTX_C_DRX_N0: CT635.2 JUSBC1.B3(SSTXN2) RT489.1
USB3_DP2_MTX_C_DRX_N1: CT637.2 JUSBC1.A3(SSTXN1) RT490.1
USB3_DP2_MTX_C_DRX_P0: CT634.2 JUSBC1.B2(SSTXP2) RT488.1
USB3_DP2_MTX_C_DRX_P1: CT636.2 JUSBC1.A2(SSTXP1) RT491.1
USB3_DP2_MTX_DRX_N0: RT193.1 UT9.42(TX1N)
USB3_DP2_MTX_DRX_N1: RT197.1 UT9.44(TX2N)
USB3_DP2_MTX_DRX_P0: RT192.1 UT9.41(TX1P)
USB3_DP2_MTX_DRX_P1: RT196.1 UT9.45(TX2P)
USB3_DP2_MTX_R_DRX_N0: CT635.1 DT6.1 RT193.2
USB3_DP2_MTX_R_DRX_N1: CT637.1 DT18.1 RT197.2
USB3_DP2_MTX_R_DRX_P0: CT634.1 DT5.1 RT192.2
USB3_DP2_MTX_R_DRX_P1: CT636.1 DT17.1 RT196.2
USB3_PRX_C_MTX_N1: CT111.2 UT9.11(SSRXN)
USB3_PRX_C_MTX_P1: CT112.2 UT9.12(SSRXP)
USB3_PRX_DTX_N2: DI4.1 DI4.9 JUSB1.5(STDA_SSRX-) UC1.BY8(PCIE2_RXN/USB31_2_RXN/SSIC_1_RX)
USB3_PRX_DTX_N3: DI1.1 DI1.9 JUSB2.5(STDA_SSRX-) UC1.BY7(PCIE3_RXN/USB31_3_RXN)
USB3_PRX_DTX_N4: DI6.1 DI6.9 JUSB3.5(STDA_SSRX-) UC1.BW6(PCIE4_RXN/USB31_4_RXN)
USB3_PRX_DTX_N5: LI16.4 RI28.1 UC1.BW9(PCIE5_RXN/USB31_5_RXN)
USB3_PRX_DTX_P2: DI4.2 DI4.8 JUSB1.6(STDA_SSRX+) UC1.BY9(PCIE2_RXP/USB31_2_RXP/SSIC_1_RX)
USB3_PRX_DTX_P3: DI1.2 DI1.8 JUSB2.6(STDA_SSRX+) UC1.BY6(PCIE3_RXP/USB31_3_RXP)
USB3_PRX_DTX_P4: DI6.2 DI6.8 JUSB3.6(STDA_SSRX+) UC1.BW5(PCIE4_RXP/USB31_4_RXP)
USB3_PRX_DTX_P5: LI16.1 RI27.1 UC1.BW8(PCIE5_RXP/USB31_5_RXP)
USB3_PRX_L_DTX_N2: JNGFF2.21(PERN1/USB3.0-RX-/SSIC-RXN) LI16.3 RI28.2
USB3_PRX_L_DTX_P2: JNGFF2.23(PERP1/USB3.0-RX+/SSIC-RXP) LI16.2 RI27.2
USB3_PRX_MTX_N1: CT111.1 UC1.CB5(PCIE1_RXN/USB31_1_RXN)
USB3_PRX_MTX_P1: CT112.1 UC1.CB6(PCIE1_RXP/USB31_1_RXP)
USB3_PTX_C_DRX_N2: CI13.1 DI4.4 DI4.7 JUSB1.8(STDA_SSTX-)
USB3_PTX_C_DRX_N3: CI5.1 DI1.4 DI1.7 JUSB2.8(STDA_SSTX-)
USB3_PTX_C_DRX_N4: CI27.1 DI6.4 DI6.7 JUSB3.8(STDA_SSTX-)
USB3_PTX_C_DRX_N5: CI29.1 LI17.4 RI30.1
USB3_PTX_C_DRX_P2: CI16.1 DI4.5 DI4.6 JUSB1.9(STDA_SSTX+)
USB3_PTX_C_DRX_P3: CI4.1 DI1.5 DI1.6 JUSB2.9(STDA_SSTX+)
USB3_PTX_C_DRX_P4: CI28.1 DI6.5 DI6.6 JUSB3.9(STDA_SSTX+)
USB3_PTX_C_DRX_P5: CI30.1 LI17.1 RI29.1
USB3_PTX_C_MRX_N1: CT113.2 UT9.14(SSTXN)
USB3_PTX_C_MRX_P1: CT114.2 UT9.15(SSTXP)
USB3_PTX_DRX_N2: CI13.2 UC1.CA2(PCIE2_TXN/USB31_2_TXN/SSIC_1_TX)
USB3_PTX_DRX_N3: CI5.2 UC1.BY4(PCIE3_TXN/USB31_3_TXN)
USB3_PTX_DRX_N4: CI27.2 UC1.BW2(PCIE4_TXN/USB31_4_TXN)
USB3_PTX_DRX_N5: CI29.2 UC1.BW4(PCIE5_TXN/USB31_5_TXN)
USB3_PTX_DRX_P2: CI16.2 UC1.CA1(PCIE2_TXP/USB31_2_TXP/SSIC_1_TX)
USB3_PTX_DRX_P3: CI4.2 UC1.BY3(PCIE3_TXP/USB31_3_TXP)
USB3_PTX_DRX_P4: CI28.2 UC1.BW1(PCIE4_TXP/USB31_4_TXP)
USB3_PTX_DRX_P5: CI30.2 UC1.BW3(PCIE5_TXP/USB31_5_TXP)
USB3_PTX_L_DRX_N2: JNGFF2.27(PETN1/USB3.0-TX-/SSIC-TXN) LI17.3 RI30.2
USB3_PTX_L_DRX_P2: JNGFF2.29(PETP1/USB3.0-TX+/SSIC-TXP) LI17.2 RI29.2
USB3_PTX_MRX_N1: CT113.1 UC1.CA4(PCIE1_TXN/USB31_1_TXN)
USB3_PTX_MRX_P1: CT114.1 UC1.CA3(PCIE1_TXP/USB31_1_TXP)
USB20_N1: UC1.CE3(USB2_1N) UT5.K5(USB_RP_N)
USB20_N2: UC1.CE1(USB2_2N) UI3.2(DM_OUT)
USB20_N2_R: DI5.2 JUSB1.2(D-) LI7.2
USB20_N3: LI3.4 UC1.CG3(USB2_3N)
USB20_N3_R: DI2.2 JUSB2.2(D-) LI3.3
USB20_N4: LI4.1 UC1.CD3(USB2_4N)
USB20_N4_R: DI3.2 JUSB3.2(D-) LI4.2
USB20_N6: LZ1.1 UC1.CC1(USB2_6N)
USB20_N6_R: DV14.3 JEDP1.12 LZ1.2
USB20_N7: LI8.1 RI47.1 UC1.CG8(USB2_7N)
USB20_N7_L: JNGFF2.9(USB_D-) LI8.2 RI47.2
USB20_N8: JUSH1.19 UC1.CB8(USB2_8N)
USB20_N9: RZ1388.2 UC1.CH5(USB2_9N)
USB20_N9_FP: DZ11.2 JFPBTN1.6 RZ350.1 RZ1388.1
USB20_N9_USH: JUSH1.23 RZ350.2
USB20_N10: LI9.1 LI12.1 UC1.CC3(USB2_10N)
USB20_N10_R: JNGFF1.5(USB_D-) LI9.2 LI12.2
USB20_P1: UC1.CE4(USB2_1P) UT5.L5(USB_RP_P)
USB20_P2: UC1.CE2(USB2_2P) UI3.3(DP_OUT)
USB20_P2_R: DI5.3 JUSB1.3(D+) LI7.3
USB20_P3: LI3.1 UC1.CG4(USB2_3P)
USB20_P3_R: DI2.3 JUSB2.3(D+) LI3.2
USB20_P4: LI4.4 UC1.CD4(USB2_4P)
USB20_P4_R: DI3.3 JUSB3.3(D+) LI4.3
USB20_P6: LZ1.4 UC1.CC2(USB2_6P)
USB20_P6_R: DV14.2 JEDP1.13 LZ1.3
USB20_P7: LI8.4 RI48.1 UC1.CG9(USB2_7P)
USB20_P7_L: JNGFF2.7(USB_D+) LI8.3 RI48.2
USB20_P8: JUSH1.18 UC1.CB9(USB2_8P)
USB20_P9: RZ1389.2 UC1.CH6(USB2_9P)
USB20_P9_FP: DZ11.3 JFPBTN1.4 RZ351.1 RZ1389.1
USB20_P9_USH: JUSH1.22 RZ351.2
USB20_P10: LI9.4 LI13.1 UC1.CC4(USB2_10P)
USB20_P10_R: JNGFF1.3(USB_D+) LI9.3 LI13.2
USB_OC0#: RC758.1 RC837.2 UC1.CK6(GPP_E9/USB2_OC0#/GP_BSSB_CLK) UI3.13(FAULT#)
USB_OC1#: RC759.1 RC839.2 UC1.CK5(GPP_E10/USB2_OC1#/GP_BSSB_DI) UI1.3(OCB)
USB_OC2#: RC760.1 RC838.2 UC1.CK8(GPP_E11/USB2_OC2#) UI2.3(OCB)
USB_OC3#: RC757.1 RC836.2 UC1.CK9(GPP_E12/USB2_OC3#)
USB_POWERSHARE_EN#: RE728.1 UE1.J3(GPIO206/ADC06) UI3.6(CTL1)
USB_POWERSHARE_VBUS_EN: RE730.1 UE1.J2(GPIO205/ADC05) UI3.5(EN)
USB_PWR_EN1#: RE729.1 UE1.K3(GPIO207/ADC07) UI1.4(E\N\)
USB_PWR_EN2#: RE727.1 UE1.G5(GPIO213/ADC11) UI2.4(E\N\)
USBCOMP: RC47.1 UC1.CC5(USB2_COMP)
USH_DET#: RE526.1 RZ87.1 UE1.C13(GPIO125/GPTP-OUT5/PVT_CLK)
USH_DET#_R: JUSH1.1 RZ87.2
USH_EXPANDER_SMBCLK: CZ62.1 JUSH1.16 RZ8.2 UE1.B3(GPIO006/SMB01_CLK/GPTP-OUT7)
USH_EXPANDER_SMBDAT: CZ63.1 JUSH1.15 RZ9.2 UE1.E5(GPIO005/SMB01_DATA/GPTP-OUT4)
USH_PWR_STATE#: JUSH1.5 RE608.1 RZ10.2
USH_PWR_STATE#_R: RE608.2 UE1.H2(GPIO204/ADC04)
VCI_IN1#: RE507.1 UE1.B5(GPIO162/VCI_IN1#)
VCI_IN2#: RE508.1 UE1.D4(GPIO161/VCI_IN2#)
VCI_IN3#: RE822.1 UE1.E4(GPIO000/VCI_IN3#)
VCT_LAN_R1: RL3.1 UL1.6(SVR_EN_N)
VGA_IDENTIFY: RE84.1 RE85.1 UE1.L9(GPIO017/GPTP-IN5)
VID0_1V_PRIM_CORE: PR408.2 PR418.2 PR420.1 PU402.9(VID0)
VID0_1VS_VCCIO: PR414.2 PR416.1 PU401.9(VID0)
VID1_1V_PRIM_CORE: PR411.2 PR417.2 PR419.1 PU402.8(VID1)
VID1_1VS_VCCIO: PR413.2 PR415.1 PU401.8(VID1)
VIDALERT_N: PR604.2 PR625.1 RC154.2 RC155.2
VIDSCLK: PR601.2 PR618.1 RC158.2 RC159.2
VIDSCLK_R: RC159.1 UC1.AA1(VIDSCK)
VIDSOUT: PR605.2 PR626.1 RC156.2 RC157.2
VIDSOUT_R: RC157.1 UC1.AA2(VIDSOUT)
VOUT_1.2V_RUN: PC509.1 PC511.1 PJP504.1 PR512.1 PU502.1(OUT)
VOUT_2.5V_MEM: PC515.1 PC516.1 PJP506.1 PR515.1 PU503.1(OUT)
VR_ENABLE_CPU_CORE: PR616.2 PU602.40(VR_ENABLE)
VR_HOT#_CPU_CORE: PR678.2 PU602.38(VR_HOT#)
VR_LPM_R#: PR430.1 RC660.2 RC867.2 UC9.4(O)
VR_READY_CPU_CORE: PR612.2 PR614.2 PU602.39(VR_READY)
VRALERT#: RC73.1 UC1.CC36(GPP_B2/VRALERT#)
VSET_5105: CE38.1 RE77.1 UE1.C9(VSET)
VSYS_CHG: PC745.1 PR721.1 PU700.3(VSYS)
VTTREF_DDR: PC218.1 PC227.1 PU200.3(VTTREF)
WIGIG_32KHZ: JNGFF1.50(SUSCLK(32KHZ)) RZ56.2
WLAN_COEX1: JNGFF1.48(COEX1) RZ130.2
WLAN_COEX2: JNGFF1.46(COEX2) RZ129.2
WLAN_COEX3: JNGFF1.44(COEX3) RZ128.2
WLAN_PWR_EN: DZ9.1 RZ38.2 RZ70.2 RZ71.2 UZ47.5(ON2)
WLAN_WIGIG60GHZ_DIS#: DZ1.1 RE8.1 UE1.L13(GPIO112/PS2_CLK1A)
WLAN_WIGIG60GHZ_DIS#_R: DZ1.2 JNGFF1.56(W_DISABLE1#)
WWAN_ANT_CONFIG: JNGFF2.60(SUSCLK) RZ1450.1
WWAN_BB_RST#: RZ1393.2 UC1.CG23(GPP_D21/SPI1_IO2)
WWAN_BB_RST#_R: JNGFF2.59(RESET#) RZ1393.1
WWAN_COEX1: JNGFF2.56(COEX1) RZ130.1 RZ373.1
WWAN_COEX2: JNGFF2.54(COEX2) RZ129.1 RZ372.1
WWAN_COEX3: JNGFF2.52(COEX3) RZ128.1 RZ374.1
WWAN_FULL_PWR_EN: CZ198.1 JNGFF2.6(FULL_CARD_POWER_OFF#) RZ43.1 UC1.CM23(GPP_D15/ISH_UART0_RTS#/GSPI2_CS)
WWAN_GPIO_CTRL: RE340.2 RZ1398.2 UE1.K1(GPIO064/LRESET#)
WWAN_GPIO_CTRL#: QZ19.1(D) RZ1397.2 UZ51.6(S)
WWAN_GPIO_CTRL_R: QZ19.2(G) RZ1398.1 RZ1399.1
WWAN_GPIO_PERST#: RC756.1 RZ1402.2 RZ1405.2 RZ1480.2 UC1.CH23(GPP_D22/SPI1_IO3)
WWAN_GPIO_PERST#_R: RZ1402.1 UZ52.A2(C)
WWAN_GPIO_WAKE#: RC840.1 RZ1394.2 RZ1396.2 UC1.CK23(GPP_D23/I2S_MCLK)
WWAN_GPIO_WAKE#_R: RZ1394.1 UZ51.3(B1)
WWAN_PERST#: JNGFF2.42(PERST#) RZ1401.2 RZ1406.1 RZ1480.1 RZ1481.1
WWAN_PERST#_R: RZ1401.1 UZ52.C2(Y)
WWAN_PEWAKE#: JNGFF2.46(PEWAKE#) RZ1395.2 RZ1396.1 RZ1400.1
WWAN_PEWAKE#_R: RZ1395.1 UZ51.4(A)
WWAN_RADIO_DIS#: DZ5.1 RE10.1 UE1.F12(GPIO123/BCM0_CLK/PVT_IO2)
WWAN_RADIO_DIS#_R: DZ5.2 JNGFF2.8(W_DISABLE#)
WWAN_WAKE#: QC8.1(D) RZ133.2 UE1.M13(GPIO110/PS2_CLK2)
WWAN_WAKE#_D: JNGFF2.15(GPIO_11) QC8.3(S) RZ132.2
XCLK_BIASREF: RC402.1 UC1.CJ1(XCLK_BIASREF)
XDP_DBRESET#: CC78.1 CC326.1 JXDP1.48 RC137.1 RC243.1 RC248.1
XDP_JTAGX: CC305.1 RC87.1 RC328.2 UC1.P6(PCH_JTAGX)
XDP_OBS0: JXDP1.21 RC239.2
XDP_OBS0_R: RC239.1 UC1.U1(BPM#_0)
XDP_OBS1: JXDP1.23 RC240.2
XDP_OBS1_R: RC240.1 UC1.U2(BPM#_1)
XDP_PRSNT_PIN1: JXDP1.1 RC121.1 RC122.1
XDP_TMS: JXDP1.58 RC735.1 RC852.2
XTAL24_IN: CC21.1 RC59.2 RC728.2 YC1.3(CRYSTAL3)
XTAL24_IN_CPU: RC728.1 UC1.CK3(XTAL_IN)
XTAL24_OUT: RC59.1 RC531.1 RC729.2
XTAL24_OUT_CPU: RC729.1 UC1.CK2(XTAL_OUT)
XTAL24_OUT_R: CC22.1 RC531.2 YC1.1(CRYSTAL1)
XTALI: CL14.1 RL11.2 UL1.10(XTAL_IN) YL1.1
XTALO: RL11.1 RL34.2 UL1.9(XTAL_OUT)
XTALO_R: CL13.1 RL34.1 YL1.3
Z2805: RL18.1 TL1.22(TXCT1)
Z2806: RL16.1 TL1.16(TXCT3)
Z2807: RL17.1 TL1.21(TXCT2)
Z2808: RL15.1 TL1.15(TXCT4)
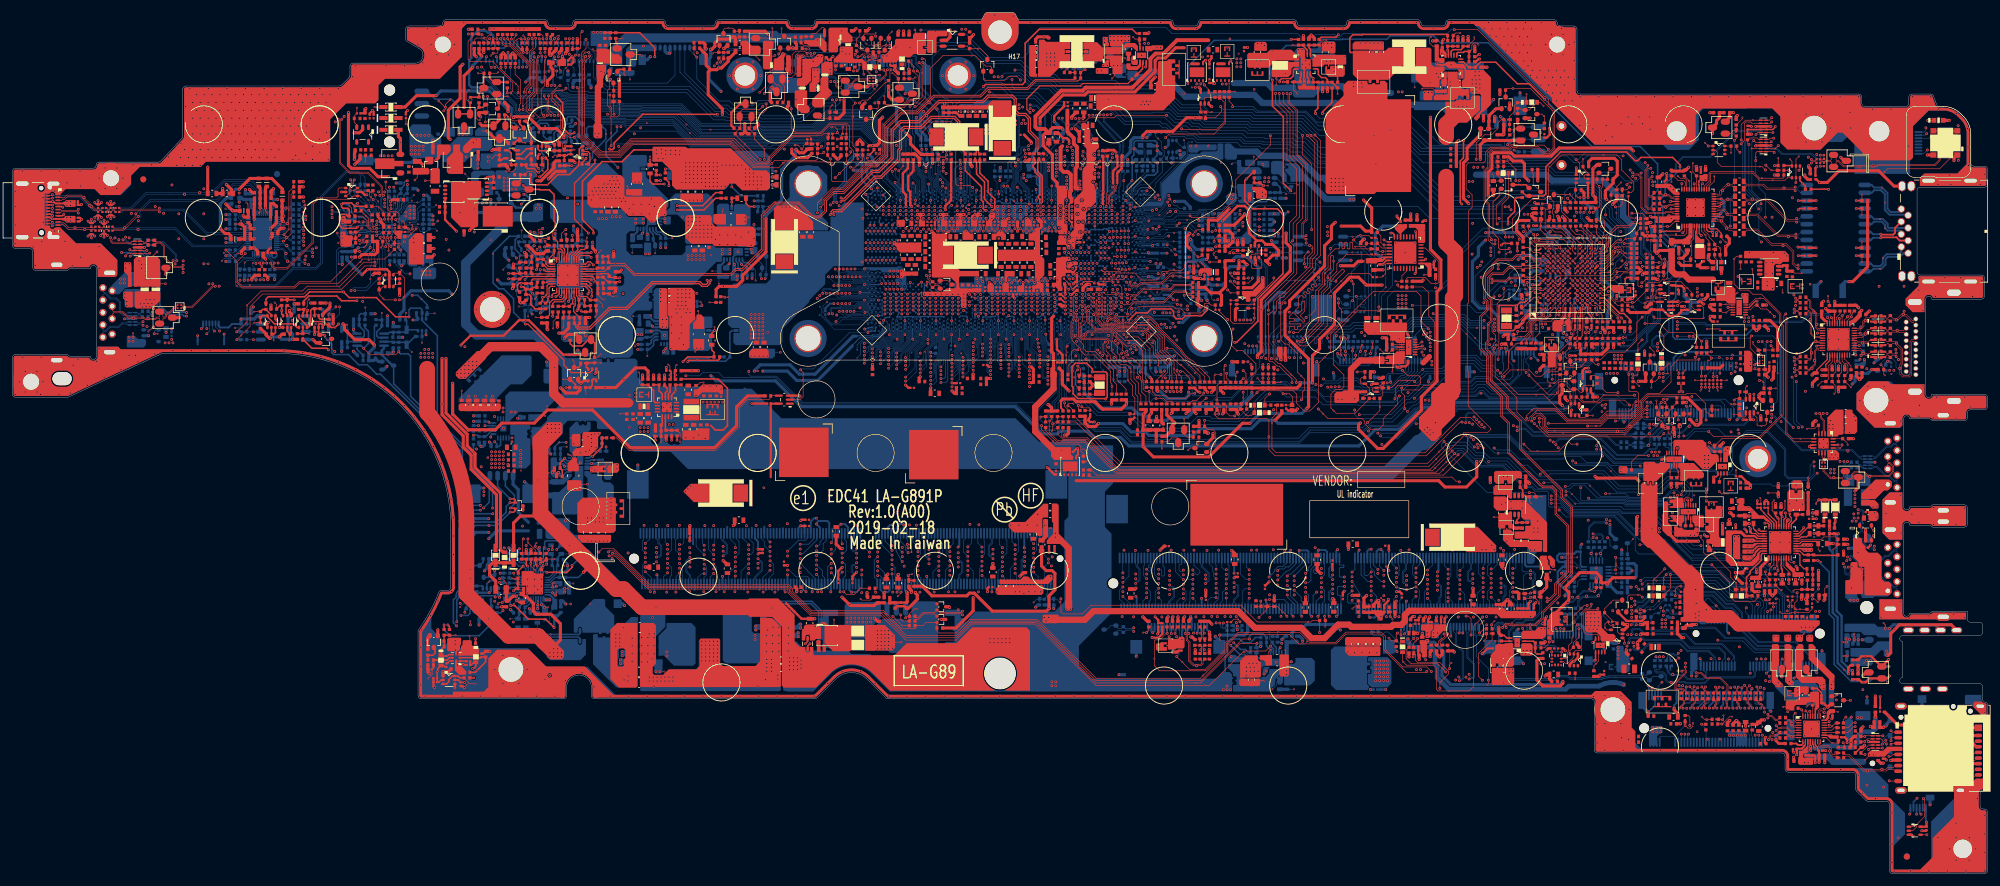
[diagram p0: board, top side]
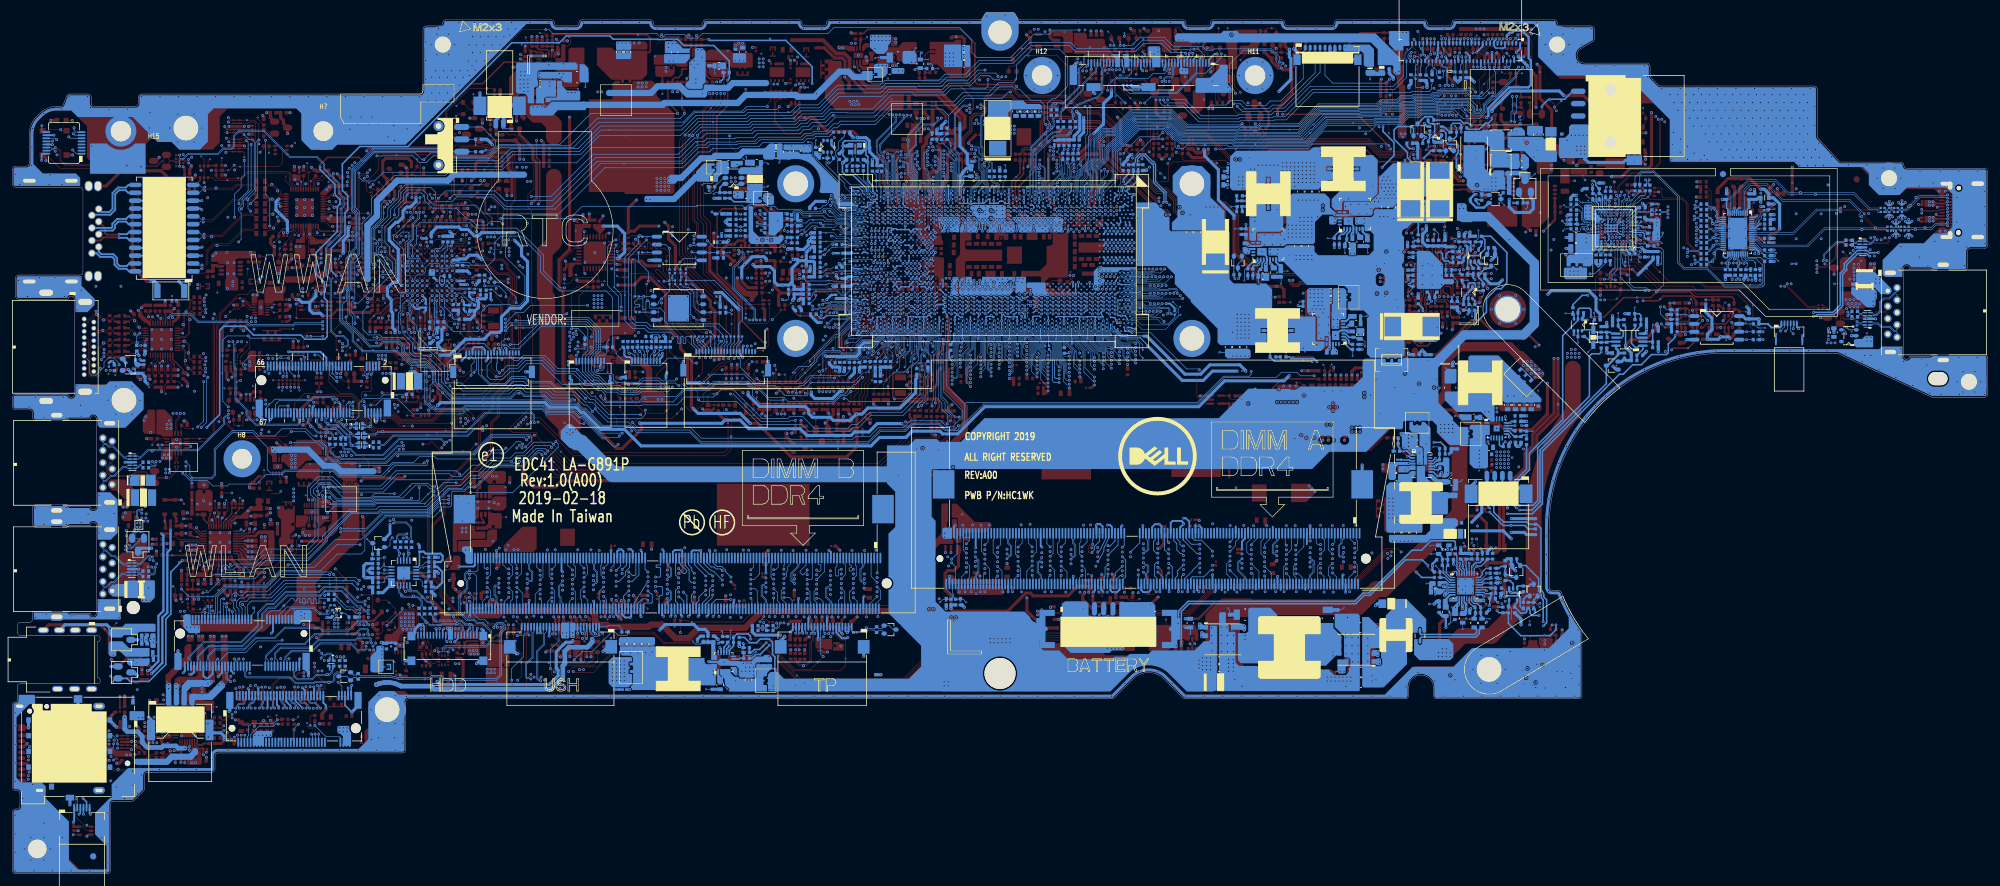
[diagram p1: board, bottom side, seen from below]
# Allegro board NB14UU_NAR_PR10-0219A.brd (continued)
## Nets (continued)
N43975: QN1.5(G1) QN1.6(D2) RN2.2
N14112977: CA33.1 RA17.2
N14113161: CZ127.1 UZ5.10(CT2)
N14113197: CZ126.1 UZ5.12(CT1)
N14123010: CA51.1 RA44.1 UA1.21(LDO1-CAP)
N14123018: CA53.1 UA1.6(LDO3-CAP)
N14123022: CA52.1 UA1.32(LDO2-CAP)
N14124153: CA25.1 UA1.15(MIC2-CAP)
N14124758: RA53.1 RA54.1 UA1.16(VD33STB)
N14124937: CA35.1 UA1.22(VREF)
N14176097: QE11.3(S) RE70.1 RE90.2
N14176137: QE4.2(BASE) RE70.2
N15644626: CZ114.1 UZ3.10(CT2)
N15647018: CZ121.1 UZ8.6(CT)
N15674340: JNGFF2.17(GPIO_12) RZ326.1
N15699868: CE64.1 DE2.1 QE15.2(G) RE541.2 RE543.2 RE565.1
N15699880: QE17.1(D) RE546.2
N15701008: CE57.1 RE350.2
N16624469: CT90.1 RT111.2 UT7.3(EN)
N16783095: PC113.2 PR108.1
N16783134: PC127.2 PR117.1
N16783222: PC119.1 PU102.16(NC2) PU102.17(VCC)
N17370862: PC4.2 PQ4.4(G) PQ5.1(D) PR11.2 PR16.1
N17370885: PQ5.2(G) PR10.2 PR15.1
N17370921: PQ1.6(D1) PR15.2
N17370927: PQ7.1(D) PR16.2
N17370961: PL3.1 PQ2.1(D) PR3.1 PR6.1
N17370983: PQ2.3(S) PR3.2 PR5.1
N17370995: PQ3.2(BASE) PR6.2 PR8.1
N17370999: PQ2.2(G) PQ3.1(COLLECTOR) PR7.2
N17371029: PC6.2 PQ9.4(G) PQ11.1(D) PR12.2 PR18.1
N17371043: PQ6.1(D) PR18.2
N17371125: PQ7.2(G) PR20.1
N17371182: PQ6.2(G) PR22.2
N17372063: PQ1.3(D2) PR17.2 PR19.2
N17372074: PQ1.5(G2) PR25.1
N17372283: PQ1.2(G1) PR19.1
N17538214: PQ11.2(G) PR31.2 PR32.1
N17539406: PQ10.5(G2) PQ10.6(D1) PR33.2
N18291828: RT97.2 RT98.1 RT99.1 UT5.F10(BUSPOWER_N)
N18292318: RT104.1 UT5.K9(RPD_G1)
N18292320: RT105.1 UT5.K10(RPD_G2)
N18292328: RT103.1 UT5.L11(GND24)
N18292515: CT87.1 UT5.H7(SS)
N18292570: RT101.1 UT5.D6(HRESET)
N18601091: RT63.1 UT5.F1(I2C_ADDR)
N19529559: RT378.1 UT5.D1(I2C_SDA1)
N19529561: RT379.1 UT5.D2(I2C_SCL1)
N21875993: RZ64.2 UZ3.3(ON1)
N21880967: JEDP1.21 LV1.1
N22005589: CZ113.1 UZ3.12(CT1)
N24654285: CZ217.1 RZ1403.1 RZ1404.1 RZ1405.1 UZ52.B2(VCC)
N24906879: PD700.1 PD702.1 PD704.1 PR708.1
N24908379: PD705.2 PR737.2
N24908381: PD705.3(1) PR735.1 PR736.2
N24908396: PR741.2 PU701.2(IN2)
N24908406: PD705.1(3) PR739.1 PU701.1(IN1)
N24908424: PR740.1 PU701.4(O)
N24908981: PC751.1 PR728.2
N25591846: PC13.2 PR47.2 PU3.5(P)
N25591872: PR43.2 PR45.1 PU3.4(O)
N25591876: PR44.2 PU3.2(A)
N25591912: PQ10.2(G1) PR41.2 PR43.1
N25591942: PQ8.1(D) PR22.1 PR27.1 PR44.1
N25591952: PR42.2 PU3.1(B)
N25840198: T353.1 UC1.V28(DDR1_CKE_2/NC)
N25840204: T354.1 UC1.V29(DDR1_CKE_3/NC)
N25845141: CC1453.1 RC299.2
N25845143: CC1452.1 RC289.2
N25890123: PC647.1 PR650.2
N25907811: PC804.1 PR800.2 PR805.1 PR817.1 PU800.3(+)
N25907823: PC800.1 PR809.2 PR815.1 PU800.2(-)
N25907922: PQ803.2(G) PR801.2 PR807.1
N25907924: PQ802.6(D1) PR807.2 PR858.1
N25907948: PR853.2 PU801.1(B)
N25907954: PC814.2 PR859.2 PR860.2 PU801.5(P)
N25907966: PQ804.2(G1) PR818.2
N25907978: PQ807.1(D) PR818.1 PR822.2 PR854.1
N25907980: PQ802.5(G2) PR856.1 PR857.2
N25907988: PR855.1 PR856.2 PU801.4(O)
N25908000: PR854.2 PU801.2(A)
N25908024: PC811.1 PD802.1 PQ813.6(D1) PR831.2 PR842.1 PR870.2 PU800.5(+)
N25908041: PC813.1 PD802.2 PR835.2 PR840.1 PU800.7(O)
N25908049: PC812.1 PR832.2 PR843.1 PU800.6(-)
N25908061: PQ813.5(G2) PR840.2
N25908120: PQ804.6(D1) PR811.2
N25908122: PC803.2 PQ800.4(G) PQ803.1(D) PR803.2 PR811.1
N25908132: PQ813.3(D2) PR836.1
N25908138: PQ805.2(G) PR802.2 PR808.1
N25908140: PQ806.3(D2) PR808.2
N25908152: PC802.2 PQ801.4(G) PQ805.1(D) PR804.2 PR812.1
N25908168: PQ806.6(D1) PR813.2 PR814.2 PR852.2
N25908188: PQ804.3(D2) PR812.2
N25908210: PQ806.5(G2) PR814.1
N25908220: PQ806.2(G1) PR820.1
N25908319: PQ804.5(G2) PR816.2
N25908329: PQ810.5(G) PR825.2 PR826.2
N25908331: PQ808.5(G) PR834.2 PR841.1
N25908337: PQ808.6(D) PQ810.1(S) PR830.2 PR841.2
N25908347: PQ808.2(G) PQ808.3(D) PR833.2
N25908367: PQ811.5(G) PR829.2
N25908379: PQ810.2(G) PR824.2 PR827.2
N25908405: PQ809.6(D) PQ810.4(S) PR838.2 PR845.2
N25908421: PQ809.5(G) PR844.2
N25908431: PQ809.2(G) PQ809.3(D) PR839.2
N25943980: T16.1 UC1.F37(RSVD_TP5)
N25943983: T17.1 UC1.F34(RSVD_TP4)
N25943986: T18.1 UC1.CP36(IST_TRIG)
N25943989: T19.1 UC1.CN36(RSVD_TP3)
N25943992: T20.1 UC1.BK34(TP_1)
N25943995: T21.1 UC1.BR18(TP_2)
N25944085: T360.1 UC1.CR4(RSVD29)
N25944133: T361.1 UC1.BP34(TP_4)
N25944139: T363.1 UC1.BP35(TP_3)
N25944172: T364.1 UC1.A34(RSVD_TP1)
N25944175: T365.1 UC1.B35(RSVD_TP2)
N25944227: RC564.1 UC1.AJ27(RSVD37)
N25944233: RC436.2 RC564.2
N26168283: PQ12.1(D) PR46.2
N26168409: PQ12.2(G) PR49.1
N26168635: PQ814.1(D) PR858.2
N26172409: PQ814.2(G) PR861.1
N26619306: PC671.2 PU613.7(PHASE)
N26619381: PC663.2 PU612.7(PHASE)
N26643986: JDIMM1.162(S2#/C0) T50.1
N26644006: JDIMM1.165(S3#/C1) T51.1
N26671961: CD31.2 RD18.1
N26693933: CD62.2 RD31.1
N26732492: JDIMM2.162(S2#/C0) T54.1
N26732518: JDIMM2.165(S3#/C1) T55.1
N26975168: PC307.2 PR308.1
N26998332: PC865.1 PQ8.2(G) PR865.1
N27109289: PR314.2 PU501.5(PG)
N27110628: PR315.1 PU402.4(PG)
N27174658: PC3003.2 PD3001.1 PR3004.2 PR3005.2 PU3000.3(IN+1)
N27174719: PC3004.2 PR3007.2 PR3008.2 PU3000.6(IN-2)
N27174755: PC3005.1 PD3002.1 PR3009.1 PR3010.1 PR3011.1 PU3000.5(IN+2)
N27174767: PD3000.1(3) PR3006.2 PR3007.1
N27174913: PQ3000.3(D2) PQ3000.6(D1) PR3001.1
N27175044: PC3001.2 PR3002.2 PR3003.2 PU3000.2(IN-1)
N27175412: PD803.2 PR892.1
N27540667: PD803.3(1) PR893.1
N27649604: QV2.1(D) RV5.2
N27697806: CZ220.1 QZ1.2(G) RZ388.2
N27698658: QV7.2(G) RV323.2 RV324.2 RV326.2
N27698700: CV635.1 QV8.2(G) RV400.2
N27698720: QV7.1(D) RV6.1 RV400.1
N27698752: QV8.3(S) RV732.1 RV733.1
N27724339: PR3012.1 PU3000.1(OUT1)
N27724613: PR3013.1 PU3000.7(OUT2)
N27950180: RV302.2 UV21.23(CFG / I2C_ADDR1)
N27950212: RV300.2 UV21.13(DCIN_EN/SCL_CTL)
N27950231: RV303.1 UV21.18(REXT)
N29168451: RC420.2 UC1.C34(RSVD68)
N29258735: CZ56.1 RZ63.1
N30493978: RZ1420.2 RZ1422.1 UZ35.1(B)
N30494637: RC425.1 UC1.BE7(VSSSA_SENSE)
N30494639: RC426.1 UC1.BG7(VCCSA_SENSE)
N30497274: CC77.1 RC845.2
N30498214: CC340.1 QC7.2(G) RC432.2 RC433.1
N30498298: QC6.1(D) RC433.2
N30686239: RC848.2 UC1.BP36(VSS_434)
N31121279: T419.1 UC1.AH26(RSVD36)
N31601664: RI14.2 UI3.16(ILIM_HI)
N31759761: CZ38.2 RZ334.1
N33426560: CZ306.1 UZ53.6(CT)
N33565250: CL16.1 TL1.3(TDCT1)
N33565254: CL17.1 TL1.4(TDCT2)
N33565258: CL20.1 TL1.9(TDCT3)
N33565262: CL21.1 TL1.10(TDCT4)
N33905695: JNGFF3.8(NC_2) RN129.1
N34195811: QE12.1(D) RE94.1
N35066834: CZ109.1 UZ43.12(CT1)
N35066846: CZ110.1 UZ43.10(CT2)
N35067480: CZ117.1 UZ47.12(CT1)
N35067619: CZ118.1 UZ47.10(CT2)
N35854159: CV633.1 DV11.1 RV626.1 RV627.2
N35854165: CV651.1 DV12.1 RV629.1 RV631.2
N35854175: QV20.1 RV630.1
N35854186: QV20.2 RV631.1
N35854224: QV18.1 RV625.1
N35854247: QV18.2 RV627.1
N35855171: RC222.1 SW1.2(B)
N36050903: QZ7.6(D2) RZ32.1
N37069772: CZ130.1 UZ23.6(CT)
N37090339: JUSH1.7 LZ3.2
N37090359: JUSH1.8 LZ4.2
N38439774: T423.1 UC1.CR35(RSVD28)
N39469818: PC631.1 PR630.2
N39470129: PC640.1 PR646.2
N39470145: PC601.1 PR652.2
N39470173: PC632.2 PR641.1
N39470189: PH604.1 PR642.2
N39685742: RV737.1 UV21.36(PD#)
N40311323: QZ3.1(C) RZ25.1
N46814682: PH601.2 PR610.1 PR631.2
N46814700: PC627.1 PR632.2
N46814728: PH602.1 PR628.2
N46814769: PC617.2 PR621.1
N46815164: PC621.2 PR623.1
N46815188: PC614.2 PR617.1
N46816463: PC629.2 PR639.1
N46816511: PH603.2 PR635.1 PR647.2
N46816817: PC630.2 PR644.1
N46816821: PH605.1 PR657.2
N46816907: PC639.2 PR645.1
N48704005: PL614.3 PR624.1
N49204882: PL612.3 PR661.1
N49223737: PC655.2 PU610.7(PHASE)

Pads without a net: FD1 1; FD2 1; FD3 1; FD4 1; JAPS1 16 17 18; JDIMM1 87 88 91 92 95 97 100 101 104 105; JDIMM2 87 88 91 92 95 97 100 101 104 105; JEDP1 2 16 20; JFPBTN1 3 5 7 9; JHDMI1 14; JIRTS1 8; JKBTP1 4; JNGFF1 6 8 12 16 20 66 68 70; JNGFF2 12 14 16 20 36 38 40 48 50 51 53 55 57; JNGFF3 6 20 22 24 26 28 30 32 34 36 40 42 44 46 48 56 58 67; JSATA1 8 20; JSD1 16; JSIM1 1 C4 C6 C8; PBATT1 11 12; PD2 2; PU100 10 15; PU102 10; PU200 18 19; PU301 10 12; PU401 4; PU502 2 6 7; PU503 2 6 7; PU610 6 13 16 17 19; PU612 6 13 16 17 19; PU613 6 13 16 17 19; PU700 13; QZ7 3 4 5; RN100 2; RN101 2; RT72 2; RT75 2; RT84 2; RT85 2; RT87 1; RT88 1; RT110 1; RT339 2; RZ78 1; RZ79 1; RZ80 1; RZ326 2; RZ1473 1; UA1 10; UC1 A35 AA24 AA26 AB25 AC6 AC7 AC24 AC25 AC26 AD24 AD26 AJ1 AJ2 AJ3 AJ4 AL1 AL2 AL3 AL4 AM3 AM4 AM7 AN1 AN2 AN3 AN4 AR3 AT3 AU3 BC28 BE1 BE2 BJ34 BJ36 BK35 BK36 BL34 BL36 BL37 BP8 BP9 BT6 BT7 BT8 BT9 BU1 BU2 BU3 BU4 BU5 BU6 BV24 BV25 BV29 BV30 BY31 CE27 CF17 CF20 CF31 CG1 CG2 CG5 CG6 CG22 CG25 CH12 CH25 CH32 CJ30 CJ31 CK17 CL35 CL36 CM16 CM18 CM19 CM20 CM27 CM28 CN7 CN12 CN16 CN18 CN19 CN20 CN24 CN26 CN28 CP3 CP7 CP16 CP18 CP24 CP28 CR3 CR14 CR16 CR18 CR20 CR22 CR24 CR26 CR28 D34 D35 D37 G1 G2 G3 G4 H3 H4 K12 K14 K15 K17 K18 K20 L25 M24 M26 P24 P26 R24 R25 R26 U3 U4 V24 W3 W25 Y3 Y24 Y25; UD1 1; UE1 B6 B8 B9 B12 D1 E12 F7 F13; UE4 1; UI3 9 15; UR1 31; UT5 C1; UT7 4; UT9 4 5 50 51; UV24 3; UZ12 3 4 5 7 10 11 12 13 15 25 26 27 28 30 31

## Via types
v1: diameter 0.457, hole 0.203, TOP to BOTTOM, 6635 vias
v2: diameter 0.305, hole 0.152, TOP to BOTTOM, 960 vias
v3: diameter 0.406, hole 0.203, TOP to BOTTOM, 128 vias
v4: diameter 0.508, hole 0.254, TOP to BOTTOM, 92 vias

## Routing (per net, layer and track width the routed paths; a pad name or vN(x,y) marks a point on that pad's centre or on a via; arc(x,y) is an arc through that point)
0.6V_DDR_VTT_ON: length 33.4
  TOP w0.107: PR210.1 97.59,70.43 99.63,68.4 113.6,68.4 117.41,72.21 117.41,75.26 118.8,76.65 v2(120.48,76.65) 122.23,76.65 122.49,76.91 RD19.1 122.53,77.26 UD1.4
0.6V_DDR_VTT_ON_R: length 5.4
  TOP w0.254: v1(93.72,67.45) v2(94.5,68.23) 95.26,68.98 PC222.1 PR212.1 PR210.2
  BOTTOM w0.254: PU200.2 93.16,67.18 93.43,67.45 v1(93.72,67.45)
1.0V_PRIM_PWRGD: length 133.1
  TOP w0.254: PU301.9 234.39,131.19 235.25,130.33 PC350.1 236.28,130.33 PR313.1 237.11,131.15 239.6,131.15 243.09,127.66 245,127.66 247.51,125.15 v1(247.51,125.15) ; RE361.2 v1(266.71,96.59) ; v1(203.53,128.27) 203.53,124.06 205.29,122.3 v2(205.29,118.62) 205.29,111.58 v1(206.5,110.37)
  BOTTOM w0.254: v1(203.53,128.27) 203.25,128.55 PR315.2 203.25,131.34 205.75,133.84 210.57,133.84 211.6,134.87 213.62,134.87 213.67,134.82 214.77,134.82 214.82,134.87 222.02,134.87 222.54,135.4 229.58,135.4 230.69,134.29 238.38,134.29 v1(247.51,125.15) 255.14,117.52 262.92,117.52 265.75,114.7 265.75,110.44 264.88,109.57 264.88,107.26 265.32,106.82 265.32,103.3 267.55,101.08 267.55,97.44 266.71,96.61 v1(266.71,96.59) ; v1(206.5,110.37) 206.51,110.39 PR314.1
3.3V_CAM_EN#: length 128.8
  TOP w0.102: 176.17,85.42 176.17,85.54 v1(176.54,85.92)
  TOP w0.107: 176.17,85.42 176.17,84.27 176.69,83.75 176.69,83.23 178.44,81.48 v2(178.44,80.54) 178.44,79.76 179.89,78.31 RC834.1 ; v1(132.44,125.07) 132.98,124.53 RZ388.1
  IN2 w0.102: v1(176.54,85.92) 176.65,86.02 176.65,87.79 175.82,88.62 174.21,88.62 173.5,89.33 172.56,89.33 172.09,89.8 171.62,89.8 171.62,89.8 170.94,89.8 170.56,90.18 170.56,93.37 170.47,93.45 170.47,93.89 170.11,94.24 170.11,95.01 169.92,95.2 169.92,96.73 170.56,97.36 170.56,97.93 170.87,98.24 171.76,98.24 171.81,98.2 175.85,98.2 176.71,99.07 177.35,99.07 177.48,99.2 180.57,99.2 180.73,99.35 180.73,100.76 181.68,101.71 181.68,102.1 181.87,102.29 181.87,113.33 184.5,115.96 184.5,118.19 188.31,122 188.31,124.69 187.43,125.58 162.06,125.58 161.52,125.04 159.94,125.04 159.64,124.74 155.16,124.74 154.93,124.51 147.85,124.51 147.58,124.78 142.56,124.78 141.7,123.92 136.16,123.92 134.56,125.52 132.9,125.52 v1(132.44,125.07)
  BOTTOM w0.076: v1(176.54,85.92) 176.5,85.96 176.5,86.07 176.38,86.19 176.38,87.58 UC1.CC37
3.3V_TS_EN: length 193.6
  TOP w0.102: UE1.J7 v1(253.65,95.81)
  TOP w0.107: v1(263.2,95.51) 263.31,95.51 RE547.1 ; RV323.1 114.87,131.69 114.38,131.2 v1(114.38,131.15)
  IN2 w0.102: v1(263.2,95.51) 262.84,95.51 261.62,96.73 261.62,98.63 260.79,99.45 257.49,99.45 255.7,101.24 255.7,102.04 255.05,102.69 255.05,104.57 256.7,106.22 256.7,107.5 255.94,108.27 252.99,108.27 250.59,110.67 250.59,111.78 242,120.38 232.49,120.38 231.91,120.96 204.66,120.96 195.95,129.67 195.95,132.53 193.18,135.3 187.14,135.3 186.11,136.32 166.14,136.32 162.1,132.28 157.8,132.28 155.4,134.69 142.52,134.69 142.48,134.73 140.05,134.73 139.51,134.2 v1(139.51,133.87)
  IN3 w0.089: 256.76,95.24 256.5,95.24 256.31,95.42 255.37,95.42 255.36,95.41 254.04,95.41 253.65,95.8 v1(253.65,95.81)
  IN3 w0.102: v1(263.2,95.51) 262.68,95.51 262.5,95.68 260.17,95.68 259.72,95.24 256.76,95.24
  BOTTOM w0.107: v1(139.51,133.87) 138.21,133.87 v2(137.94,134.14) 136.89,135.19 133.01,135.19 131.51,133.69 126.84,133.69 126.23,133.08 125.12,133.08 124.89,133.3 115.68,133.3 114.38,132 v1(114.38,131.15)
3.3V_WWAN_EN: length 48.2
  TOP w0.107: v1(284.6,90.05) v2(283.85,90.8) 283.4,91.26 282.43,91.26 RZ40.2 281.49,91.89 280.71,91.11 UZ43.3
  TOP w0.127: UE1.C6 248.1,95.06 v1(248.04,95.06)
  IN3 w0.089: 260.83,90.28 260.61,90.5 256.54,90.5 255.96,91.07 253.3,91.07 252.15,92.21 252.15,94.31 251.84,94.63 249.51,94.63 249.27,94.87 249.27,95.22 249.1,95.39 248.48,95.39 248.15,95.06 v1(248.04,95.06)
  IN3 w0.102: 260.83,90.28 261.79,89.32 267.04,89.32 267.46,89.74 272.41,89.74 273.52,88.63 283.18,88.63 v1(284.6,90.05)
3V5V_EN: length 168.1
  TOP w0.107: v1(203.23,36.79) 202.43,35.99 198.92,35.99 193.37,30.44 v2(192.57,30.44) 175,30.44 165.1,40.34 155.05,40.34 152.46,37.75 144.29,37.75 140.27,41.78 128.88,41.78 125.28,45.38 125.28,45.82 125.12,45.98 102.7,45.98 97.33,51.35 96.39,51.35 v1(96.39,51.36)
  IN1 w0.099: v1(74.48,70.86) 74.58,70.96 77.43,70.96 78.32,70.08 78.32,69.63 77.91,69.23 77.72,69.23 76.99,68.49 76.99,64.93 76.61,64.55 76.61,63.72 79.99,60.34 79.99,57.85 82.13,55.71 96.83,55.71 97.4,55.14 97.4,51.46 97.29,51.36 v1(96.39,51.36)
  BOTTOM w0.254: PU102.12 77.33,71.51 76.46,70.64 PC128.1 PR116.1 75.14,70.86 v1(74.48,70.86) PR114.2 ; PU100.12 203.69,36.33 v1(203.23,36.79)
+0.6V_DDR_VTT: length 158.8
  TOP w1.016: 238.58,42.49 225.61,42.49 224.91,41.79 224.91,40.78 224.34,40.21 223.03,40.21 222.72,39.89 216.28,39.89 215.92,40.24 214.14,40.24 211.96,38.06 209.85,38.06 208.18,39.73 200.7,39.73 198,42.43 174.62,42.43 173.23,41.04 168.51,41.04
  IN2 w1.016: 168.4,46.68 148.84,46.68 148.34,47.18 139.53,47.18 138.62,48.09 138.62,49.73 137.58,50.77 137.58,53.9 135.06,56.42 135.06,57.22 132.77,59.51 106.1,59.51 99.83,65.78 98.52,65.78
  BOTTOM w0.305: JDIMM1.258 v1(167.7,48.05) ; v1(245.23,41.58) 245.1,41.71 JDIMM2.258
  vias: v1(97.66,66.09) v1(97.66,65.45) v1(166.68,41.41) v1(167.38,41.41) v3(166.98,40.83)
+0.6VSP:
  vias: v1(93.59,65.54) v1(94.1,65.22) v2(93.57,65.01)
+0.9V_LAN: length 16.8
  TOP w0.203: UL1.22 v1(276.03,109.04) ; UL1.8 272.46,103.47 v1(272.79,103.13) ; UL1.43 v1(267.91,107.44) ; UL1.16 275.84,106.64 275.84,106.66 v1(275.85,106.66) ; UL1.11 273.66,104.07 273.96,103.77 274.46,103.77 274.58,103.64 v1(274.63,103.64) 274.66,103.62 CL11.1 ; UL1.40 v1(267.84,108.64)
  IN2 w0.508: v1(274.63,103.64) 273.3,103.64 v1(272.79,103.13)
  BOTTOM w0.508: v1(274.63,103.64) 274.63,105.44 v1(275.85,106.66) 275.85,106.66 276.47,107.28 276.47,108.6 v1(276.03,109.04)
  vias: v1(267.58,106.31) v1(267.84,111.01) v1(267.97,105.86) v1(268.28,110.56) v1(272.6,101.36) v1(273.24,101.36) v2(268.75,103.41)
+1.0V_AMPHYPLL: length 13.9
  TOP w0.635: 170.42,123.33 v2(170.42,120.94) 170.42,119.91 171.45,118.88 171.45,117.96 171.95,117.45 171.95,114.22 171.74,114.01 171.74,111.03
  BOTTOM w0.18: v1(172.42,110.78) 172.73,110.47 UC1.BV2
+1.0V_APLL:
  vias: v1(170.64,101.99) v1(171.29,101.99) v1(171.29,101.15) v1(171.93,102.76) v1(172.6,102.81) v2(171.29,102.87)
+1.0V_CLK: length 1.3
  BOTTOM w0.127: RC175.2 195.07,115.05 v2(195.21,114.91)
+1.0V_MPHYGT:
  vias: v1(173.33,103.68) v1(173.89,102.76) v1(182.3,124.29) v1(182.61,124.82) v1(182.89,124.29) v1(183.19,124.82) v1(183.47,124.29) v1(183.78,124.82) v2(177.05,125.14)
+1.0V_PRIM: length 147.4
  TOP w0.508: RC216.1 86.99,130.26 87.31,129.94 87.31,128.99 86.41,128.09 v1(86.41,127.38)
  IN2 w0.508: v1(170.69,102.8) 170.65,102.84 v1(170.65,103.61) ; v1(86.41,127.38) 86.41,127.61 87.01,128.21 90.85,128.21 98.06,135.43 114.22,135.43 115.09,136.29 124.19,136.29 125.05,135.43 127.55,135.43 129.49,133.49 131.78,133.49 133.68,135.39 138.45,135.39 139,135.95 142.52,135.95 142.89,135.58 151.74,135.58 v1(152.26,136.09)
  IN3 w0.508: v1(152.26,136.09) 153.79,134.57 155.68,134.57 157.68,132.57 162.34,132.57 166.34,136.58 185.12,136.58 188.34,133.36 195.32,133.36 196.53,132.15 197.31,132.15 v1(197.78,131.69)
  BOTTOM w0.203: UC1.BP14 170.31,102.42 v1(170.69,102.8) ; v1(175.8,102.01) 175.26,102.01 UC1.CA14 ; v1(170.65,103.61) 170.96,103.3 UC1.BR12 ; UC1.CC12 176.46,102.95 v1(176.46,102.82) ; UC1.BU12 172.26,103.45 v1(172.5,103.69)
  BOTTOM w1.016: 211.88,112.44 210.99,112.44 207.83,115.61 205.94,115.61 205.53,116.01 201.66,116.01 200.96,116.71 197.44,116.71 197.43,116.7
  vias: v1(170.64,98.63) v1(171.28,100.39) v1(171.31,99.41) v1(171.28,98.66) v1(171.93,100.39) v1(171.91,99.41) v1(173.88,100.39) v1(173.89,98.63) v1(197.78,131.05) v1(197.78,130.42) v1(198.41,131.69) v1(198.41,131.05) v1(198.41,130.42) v1(213.04,112.34) v1(213.04,111.71) v1(213.04,111.07) v1(213.04,110.44) v1(213.67,112.34) v1(213.67,111.71) v1(213.67,111.07) v1(213.67,110.44) v1(214.31,112.34) v1(214.31,111.71) v1(214.31,111.07) v1(214.31,110.44) v1(214.94,112.34) v1(214.94,111.71) v1(214.94,111.07) v1(214.94,110.44) v1(216.62,127.81) v1(216.66,127.2) v1(217.32,127.74) v1(217.36,127.14) v1(217.93,127.77) v1(217.99,127.14) v3(189.17,126.07)
+1.0V_PRIM_CORE:
  vias: v1(172.59,101.15) v1(172.65,96.97) v1(173.23,100.39) v1(173.24,98.63) v1(173.24,97.79) v1(173.24,96.97) v1(173.89,97.79) v1(173.92,96.97) v1(174.54,97.79) v1(175.19,100.31) v1(175.19,98.63) v1(175.84,102.83) v1(175.84,101.15) v3(200.59,126.76)
+1.0V_PRIM_COREP: length 7.2
  TOP w0.254: PR423.2 v1(205.29,127.96)
  IN1 w0.254: v1(200.91,131.39) 200.91,130.57 202.71,128.76 204.88,128.76 205.29,128.36 v1(205.29,127.96)
  vias: v1(201.61,131.39) v1(202.31,131.39) v2(203.49,133)
+1.0V_PRIM_XDP: length 20.6
  TOP w0.127: v2(88.55,129.83) 88.39,129.99 RC216.2
  TOP w0.508: v1(74.93,132.03) 74.61,132.35 RC138.2
  IN2 w0.508: v1(88.83,132.09) 88.83,131.81 88.32,131.3 75.43,131.3 74.93,131.81 v1(74.93,132.03)
  BOTTOM w0.305: JXDP1.43 88.77,133.24 88.83,133.17 v1(88.83,132.09) 88.83,131.96 89.07,131.73 JXDP1.44
+1.0V_VCCST: length 337.6
  TOP w0.508: v1(74.35,130.33) 72.96,128.93 v1(72.96,123.84) ; 169.12,110.75 168.74,111.14 168.74,111.67 167.99,112.42 167.99,116.18 166.49,117.68 166.49,119.31 166.8,119.62 167.33,119.62 RC864.2 167.66,119.95 167.66,120.19 168.04,120.57 169.41,120.57 v1(169.64,120.34) ; RC235.2 75.37,132.59 v1(75.81,132.15) ; v1(250,83.82) 250,83.76 249.99,83.76 RE90.1
  TOP w0.635: RC864.2 166.75,120.36 165.59,120.36 165.25,120.7 165.25,122.39 169.41,126.55 172.88,126.55 173.38,127.05 180.92,127.05 183.82,129.94 183.82,131.71 184.65,132.55 185.95,132.55 188.11,134.71 193.19,134.71
  IN1 w0.508: 181.99,104.28 182.69,104.28 183.34,104.92 183.81,104.92 184.25,105.36 186.23,105.36 187.32,104.28 v1(189.42,104.28)
  IN2 w0.508: v1(90.66,104.7) 91.31,105.34 v1(91.31,108.21) ; v1(72.96,123.84) 71.43,122.31 71.43,113.43 70.07,112.07 v1(70.07,102.5) ; v1(189.42,104.28) 189.54,104.4 190.73,104.4 191.2,103.93 193.07,103.93 193.8,104.66 195.81,104.66 197.42,106.27 197.42,107.33 197.93,107.83 200.4,107.83 200.97,107.26 204.4,107.26 205.33,106.33 221.57,106.33 222.25,107.01 224.28,107.01 225.65,105.64 226.97,105.64 232.07,110.74 238.97,110.74 239.76,109.95 239.76,109.07 237.97,107.27 v1(237.97,103.6) v1(237.97,102.4) ; v1(97.93,117.53) 99.37,118.97 101.29,118.97 102.1,119.79 102.1,121.53 103.62,123.05 110.98,123.05 111.76,123.82 120.04,123.82 121.29,125.08 122.73,125.08 123.1,124.71 131.39,124.71 132.23,123.87 135.01,123.87 135.62,123.26 147.12,123.26 v1(147.18,123.2) 147.74,123.75 157.4,123.75 157.7,124.05 161.5,124.05 162.36,124.91 164.59,124.91 165.51,123.99 165.51,123.46 168.63,120.34 v1(169.64,120.34)
  IN3 w0.508: v1(70.07,102.5) 70.48,102.09 74.37,102.09 74.77,102.5 84.83,102.5 85.99,101.35 v1(85.99,101.29) ; v1(97.93,117.53) 94.71,114.31 92.57,114.31 91.31,113.05 v1(91.31,108.21)
  BOTTOM w0.203: UC1.BP2 v1(170.29,110.82) ; UC1.BP11 v1(169.92,103.58)
  BOTTOM w0.381: CC1481.1 150.45,118.48 150.33,118.6 RC219.1
  BOTTOM w0.508: v1(85.99,101.29) 87.5,101.29 PC602.1 PR601.1 PR604.1 PR605.1 90.66,101.45 91.24,102.03 91.24,103.34 90.66,103.92 v1(90.66,104.7) ; v1(237.97,103.6) 243.27,103.6 243.8,103.07 244.41,103.07 245.45,104.11 246.55,104.11 246.95,104.51 250.46,104.51 251.39,103.58 RE59.1 ; v1(147.18,123.2) 146.64,122.65 146.64,120.1 147.56,119.19 RC156.1 RC154.1 RC158.1 RC219.1 ; v1(169.64,120.34) 169.73,120.26 RC218.1 RC71.2 ; v1(75.81,132.15) 75.81,132.05 74.35,130.6 v1(74.35,130.33) ; v1(237.97,102.4) 236.8,101.24 236.8,99.88 235.83,98.92 235.83,92.53 236.98,91.39 238.63,91.39 240.05,89.96 240.05,87.8 240.39,87.46 241.8,87.46 242.88,86.38 245.86,86.38 248.43,83.8 249.98,83.8 v1(250,83.82)
  vias: v3(196.67,134.91)
+1.0V_VCCST_C:
  vias: v2(198.08,132.53)
+1.0V_VCCST_R: length 16.1
  TOP w0.254: 171.08,108.58 170.68,108.19 170.68,105.61 170.98,105.32 CC1462.1 v1(171.13,104.64)
  TOP w0.635: 171.08,108.58 171.08,109.1 170.82,109.36 v2(170.82,110.21) 170.98,110.36 170.98,112.94 170.49,113.42 169.79,113.42 169.31,113.9 169.31,117.31 169.58,117.57
  BOTTOM w0.254: UC1.BR11 170.96,104.47 v1(171.13,104.64) 171.61,104.16 UC1.BT11
+1.0V_VCCSTG: length 127.9
  TOP w0.381: RC87.2 138.39,117.7 v1(138.94,117.7)
  TOP w0.508: 189.29,133.47 187.9,133.47 186.25,131.82 185.01,131.82 184.58,131.39 184.58,129.61 181.31,126.35 173.71,126.35 173.21,125.85 169.7,125.85 166,122.15 v1(166,121.24) ; v1(140.57,122.27) 140.05,121.74 140.05,118.11 139.65,117.7 v1(138.94,117.7) ; v1(126.59,117.07) 126.59,117.01 127.1,116.51 127.82,116.51 128.33,117.01 RC131.2 128.7,117.09 128.77,117.17 RC130.2 ; RC436.1 113.66,94.41 114.17,94.92 v3(114.85,94.92) 116.97,94.92 117.98,95.93 117.98,96.73 121.72,100.48 v1(121.72,105.86)
  IN1 w0.508: v1(138.94,117.7) 137.75,117.7 137.27,117.23 136.35,117.23 135.85,117.72 134.11,117.72 133.89,117.5 v1(133.23,117.5) 132.31,117.5 131.63,118.18 127.54,118.18 126.59,117.23 v1(126.59,117.07)
  IN2 w0.508: v1(166,121.24) 165.24,122.01 164.22,122.01 163.83,122.4 161.96,122.4 161.27,123.09 158.15,123.09 157.27,122.2 146.04,122.2 v1(146.01,122.24) 141.82,122.24 141.79,122.27 v1(140.57,122.27)
  BOTTOM w0.254: UC1.BG2 UC1.BG1 166.06,111.56 165.94,111.68
  BOTTOM w0.508: v1(166,121.24) 166,117.56 164.8,116.37 CC29.1 164.8,114.77 164.21,114.17 RC153.1 164.32,114.01 164.9,114.01 165.55,113.36 165.55,113.15 165.94,112.75 165.94,111.68 ; RC558.1 146.73,119.09 146.01,119.81 v1(146.01,122.24) ; v1(126.59,117.07) 126.49,116.96 126.49,116.02 124.25,113.79 124.25,108.9 121.72,106.37 v1(121.72,105.86)
+1.0V_VCCSTG_C:
  vias: v1(192.22,131.99)
+1.0V_VCCSTG_R: length 5.1
  BOTTOM w0.15: 165.72,111.2 165.77,111.16 165.77,109.31 UC1.BG3
  BOTTOM w0.254: RC153.2 165.24,112.72 v2(165.45,112.52) 165.45,111.51 165.72,111.23 165.72,111.2
+1.0VS_VCCIO: length 347.9
  TOP w0.254: RC8.1 153.92,116.49 151.98,118.44 151.98,120.39 v1(151.79,120.57)
  TOP w0.381: RC132.2 v1(77.66,134.94)
  TOP w0.508: v1(250.36,75.66) 249.93,76.09 249.93,77.23 250.31,77.62 QE11.1 ; RC163.1 v3(109.77,81.29) v1(110.8,81.29) ; v1(80.94,122.19) 81.09,122.34 83.35,122.34 85.28,120.41 87.94,120.41 89.08,119.27 v1(89.08,118.94)
  IN1 w0.508: v1(110.8,81.29) 108.66,81.29 107.51,82.43 98.4,82.43 90.59,90.24 88.83,90.24 88.01,89.42 86.74,89.42 86.42,89.74 86.42,90.34 84.62,92.15 84.57,92.15 83.14,93.58 80.83,93.58 79.37,95.04 79.37,99.71 79.88,100.21 81.66,100.21 82.48,99.39 85.13,99.39 87.04,101.3 87.04,104.88 89.66,107.49 v1(89.66,109.23)
  IN2 w0.254: v1(119.46,124.56) 119,125.01 116.66,125.01 114.74,126.93 112.85,126.93 110.49,124.58 103.54,124.58 97.54,118.59 96.6,118.59 93.62,115.61 93.62,113.97 89.66,110 v1(89.66,109.23)
  IN2 w0.508: v1(169.96,100.42) 169.96,97.38 169.45,96.87 169.45,95.68 168.91,95.13 167.32,95.13
  IN3 w0.254: v1(119.46,124.56) 120.49,123.53 122.17,123.53 122.96,124.32 131.2,124.32 132,123.52 146.05,123.52 147.03,122.54 148.97,122.54 150.94,120.57 v1(151.79,120.57)
  IN3 w0.508: v1(89.08,118.94) 89.08,118.3 88.59,117.81 88.59,110.3 v1(89.66,109.23)
  BOTTOM w0.102: 167.15,94.6 UC1.BJ26 167.15,94.19 ; 167.11,95.07 UC1.BH25 ; UC1.BH25 166.7,94.65 ; UC1.BH25 167.11,94.65 ; UC1.BH25 166.7,95.07 ; 166.66,95.11 UC1.BH24 166.66,95.53 ; 166.66,94.19 UC1.BH26 166.66,94.6 ; 167.15,95.53 UC1.BJ24 167.15,95.11
  BOTTOM w0.203: UC1.BP16 170.08,100.44 v1(169.96,100.42) 169.95,100.36 UC1.BP18
  BOTTOM w0.381: v1(77.66,134.94) 77.66,135.46 77.18,135.94 76.78,135.94 76.47,136.24 75.19,136.24 74.14,135.19 74.14,131.81 73.78,131.46 73.78,127.45 74.16,127.07 77.28,127.07 80.64,123.71 80.64,122.48 v1(80.94,122.19)
  BOTTOM w0.508: v1(112.83,80.46) 113.65,79.65 123.24,79.65 127.42,75.47 161.97,75.47 166.37,71.07 168.78,71.07 169.22,71.51 173.73,71.51 174.75,70.5 179,70.5 180.37,69.13 217.49,69.13 220.17,71.8 223.98,71.8 226.76,74.57 227.21,74.57 228.02,75.39 232.31,75.39 233.05,76.13 249.89,76.13 v1(250.36,75.66)
  vias: v1(111.56,76.21) v1(112.2,76.21) v1(112.83,76.21) v1(113.47,76.21) v1(114.1,76.21) v1(114.74,76.21) v1(155.8,96.15) v1(155.97,95.54) v1(156.41,96.21) v1(156.71,95.7) v1(166.4,95.79) v1(166.45,93.64) v1(166.81,96.23) v1(167.2,95.79) v1(167.36,93.64)
+1.2V_DDRP: length 27.6
  IN1 w0.254: v1(89.44,69.7) 89.44,70.28 90.78,71.61 95.59,71.61 97.18,70.03 97.18,63.25 97.19,63.23 97.19,57.1 96.93,56.84 v1(95.44,56.84)
  BOTTOM w0.254: v1(89.44,69.7) v2(88.32,69.7) 87.61,69 PR204.1 PC208.1
  vias: v1(92.9,57.48) v1(92.9,56.84) v1(93.53,57.48) v1(93.53,56.84) v1(94.17,57.48) v1(94.17,56.84) v1(94.8,57.48) v1(94.8,56.84) v1(95.44,57.48) v1(96.07,60.65) v1(96.07,60.02) v1(96.07,59.38) v1(96.07,58.75) v1(96.07,58.11) v1(96.07,57.48) v1(96.71,60.65) v1(96.71,60.02) v1(96.71,59.38) v1(96.71,58.75) v1(96.71,58.11) v1(96.71,57.48)
+1.2V_LDO: length 11.3
  TOP w0.203: UR1.10 289.61,20.83 289.44,20.66 ; UR1.14 291.21,20.9 291.25,20.86 291.25,20.77 291.57,20.45 291.57,20.05 CR7.1
  TOP w0.356: v1(288.19,19.21) 288.2,19.22 288.2,19.26 288.26,19.31 288.26,19.83 288.2,19.89 CR6.1 288.21,20.14 288.28,20.2 289.04,20.2 289.44,20.61 289.44,20.66 ; CR7.1 291.83,19.8 CR5.1
  TOP w0.508: v1(291.83,17.98) CR5.1
  IN1 w0.508: v1(291.83,17.98) 291.83,18.57 291.19,19.21 v1(288.19,19.21)
+1.2V_MEM: length 127.1
  TOP w0.356: UD1.5 122.51,75.96 CD32.1 122.5,64.07
  TOP w0.381: v1(120.44,52.43) 121.19,52.43 CD10.1
  TOP w0.508: CD9.1 109.41,56.21 v1(109.45,56.25) ; RD15.1 140.81,45.38 v1(140.93,45.5)
  BOTTOM w0.076: UC1.BH36 166.82,87.35 166.97,87.2 166.97,87.18
  BOTTOM w0.089: v1(149.2,87.11) UC1.Y36 ; UC1.AH36 v1(154.23,87.11)
  BOTTOM w0.09: v1(151.72,87.11) UC1.AD36 ; v1(161.78,87.11) UC1.AY36 ; v1(156.75,87.11) UC1.AM36
  BOTTOM w0.15: CC1457.1 151.71,85.42 151.71,87.1 v1(151.72,87.11)
  BOTTOM w0.16: v1(149.2,87.11) 149.2,85.08 CC37.1
  BOTTOM w0.2: 167.26,85.89 166.97,86.18 166.97,87.18 v1(166.92,87.18)
  BOTTOM w0.203: UC1.R32 v1(145.49,91.1) ; UC1.AH32 153.77,91.03 153.64,91.02 v1(153.64,91.02) ; UC1.AN32 v1(157.34,91.1) ; UC1.BE32 v1(164.63,91.1) ; UC1.AW32 v1(160.98,91.1) ; 167.26,85.89 167.29,85.86 167.29,85.7 CC36.1
  BOTTOM w0.305: JDIMM2.112 206.6,41.88 206.81,41.67 206.81,41.65 v1(206.88,41.59) ; v1(230.19,48.77) 230.35,48.93 JDIMM2.199 ; JDIMM2.33 186.85,51.97 187.15,52.27 v1(187.18,52.27) ; JDIMM2.141 213.85,52.18 v1(214.04,52.37) ; JDIMM2.147 217.35,51.99 217.53,52.17 v1(217.53,52.3) ; v1(158.22,45.54) 158.22,45.59 158.2,45.61 JDIMM1.220 ; JDIMM2.54 192.1,44.46 v1(192.07,44.49) ; v1(212.73,41.59) 212.6,41.72 JDIMM2.136 ; JDIMM1.130 v1(133.7,45.56) ; JDIMM2.163 221.35,52.1 v1(221.06,52.39) 220.65,52.39 220.35,52.09 JDIMM2.159 ; JDIMM1.241 v1(163.45,52.65) ; JDIMM1.96 125.2,48.29 v1(125.21,48.3) ; JDIMM2.142 214.1,41.83 v1(213.86,41.59) ; JDIMM1.12 104.2,48.2 v1(104.1,48.3) ; JDIMM1.178 147.7,48.04 v1(147.69,48.04) ; JDIMM1.153 141.45,56.03 141.76,56.34 v1(142.17,56.34) ; JDIMM2.130 211.1,41.89 211.01,41.79 211.01,41.72 v1(210.88,41.59) ; JDIMM2.111 206.35,52.14 v1(206.48,52.27) ; v1(235.6,44.18) 235.6,42.81 JDIMM2.220 ; JDIMM2.160 220.6,41.93 220.07,41.4 v1(219.26,41.4) 219.1,41.56 JDIMM2.154 ; v1(202.48,44.22) 202.53,44.17 202.53,43.78 202.6,43.7 JDIMM2.96 ; JDIMM1.159 142.95,56.09 143.39,56.52 143.82,56.52 v1(143.98,56.36) 143.98,55.92 143.95,55.89 JDIMM1.163 ; v1(139.82,56.23) 139.95,56.1 JDIMM1.147 ; v1(136.45,56.25) JDIMM1.141 ; JDIMM1.111 128.95,56.89 129.5,57.44 v1(129.88,57.44) ; v1(152.76,52.78) 152.95,52.97 JDIMM1.199 ; JDIMM1.154 141.7,45.8 141.4,45.5 v1(140.93,45.5) 140.61,45.5 140.2,45.91 JDIMM1.148 ; JDIMM2.148 217.6,41.66 217.55,41.6 v1(217.48,41.54) ; JDIMM1.33 v1(109.45,56.25) ; JDIMM1.123 131.95,56.69 131.65,57 130.2,57 129.89,56.69 v1(129.89,56.49) 130.45,55.93 JDIMM1.117 ; JDIMM2.178 225.1,43.98 v1(225.17,44.04) ; JDIMM2.129 210.85,52.16 v1(210.97,52.29) 210.99,52.3 212.07,52.3 212.35,52.02 JDIMM2.135 ; JDIMM2.12 181.6,44.67 v1(181.46,44.81) ; JDIMM1.142 136.7,45.82 136.39,45.51 135.56,45.51 v1(135.54,45.49) 135.54,45.49 135.2,45.83 JDIMM1.136 ; v1(219.5,52.43) 219.16,52.43 218.85,52.12 JDIMM2.153 ; v1(142.89,45.5) 142.89,45.61 143.2,45.92 143.2,46.81 JDIMM1.160 ; JDIMM1.118 v1(130.7,45.56) ; JDIMM2.241 v1(240.85,52.24) ; v1(197.34,48.55) 197.35,48.57 JDIMM2.75 ; JDIMM2.124 209.6,41.85 v1(209.86,41.59) ; v1(208.28,41.59) 208.1,41.77 JDIMM2.118 ; JDIMM1.54 v1(114.7,48.04) ; JDIMM1.112 v1(129.2,45.56) ; JDIMM2.117 207.85,52.02 207.85,52.02 v1(207.85,52.24) 209.15,52.24 209.35,52.04 JDIMM2.123 ; v1(120.44,52.43) 120.44,53.67 119.95,54.16 JDIMM1.75 ; JDIMM1.124 v1(132.2,45.56) ; JDIMM1.129 133.45,56.16 133.77,56.48 v1(133.85,56.48) 134.49,56.48 134.95,56.02 JDIMM1.135
  vias: v3(121.38,62.37)
+1.2V_RUN: length 346.7
  TOP w0.203: UV21.12 293.55,82.94 292.92,82.31 CV313.1
  TOP w0.254: 292.79,89.35 293.05,89.35 293.15,89.25 UV21.40
  TOP w0.508: LT604.1 43.62,110.63 41.89,112.36 LT601.1 LT602.1 38.37,112.36 v1(36.63,110.62) ; LT603.1 35.29,103.09 34.93,103.45 34.35,103.45 v1(33.59,104.21) ; CV313.1 v1(292.27,81.43) ; CV311.1 292.25,89.9 292.79,89.35
  IN1 w0.762: 36.51,111.9 36.51,112.74 37.27,113.5 41.98,113.5 57.24,128.76 68.85,128.76 74.14,134.05 99.72,134.05 100.93,135.26 119.24,135.26 120.27,134.22 128.58,134.22 129.44,133.36 132.35,133.36 133.71,134.72 137.75,134.72 139.19,136.15 142.18,136.15 142.96,135.37 151.84,135.37 157.28,129.93 160.46,129.93 161.29,129.11 164.57,129.11 167.83,125.85 197.87,125.85 198.38,125.35 227.01,125.35 230.55,121.8 235.96,121.8 237.44,123.28 271.36,123.28 273.06,121.57 273.06,117.4 273.69,116.77 276.57,116.77 285.27,108.07 285.27,98.34 288.22,95.39
  IN2 w0.762: 299,90.47 300.02,89.46 300.02,82.9 299.54,82.42 v1(299.54,81.61) 299.15,81.22 292.48,81.22 v1(292.27,81.43) 290,83.7 290,92.59 288.82,93.77
  BOTTOM w0.508: v1(36.63,110.62) 36.06,110.62 35.35,109.91 LT605.1 34.58,109.23 33.59,108.24 v1(33.59,104.21)
  vias: v1(36.63,109.99) v1(289.11,95.2) v1(289.11,94.61) v1(298.71,91.04) v3(290.38,95.26)
+1.2V_VDD_A1: length 5.4
  TOP w0.127: v2(43.21,104.91) 43.68,105.38 v1(43.77,105.38)
  TOP w0.508: v1(43.77,105.38) 43.57,105.58 CT612.1 CT627.1 CT611.1 43.57,108.78 LT604.2
  BOTTOM w0.254: v1(43.77,105.38) UT9.13
+1.2V_VDD_A2: length 6.2
  TOP w0.127: v1(36.74,104.99) v2(35.99,104.99)
  TOP w0.508: v1(36.74,104.99) 37,104.99 37.51,104.48 CT46.1 CT45.1 CT626.1 LT603.2
  BOTTOM w0.254: UT9.47 37.5,104.33 36.84,104.99 v1(36.74,104.99)
+1.2V_VDD_DM_D1: length 40
  TOP w0.127: v1(36.98,100.22) v2(36.34,100.22)
  TOP w0.508: CT616.1 36.98,100.57 v1(36.98,100.22) ; CT628.1 42.87,103.82 43.38,104.33 v1(43.87,104.33) ; CT615.1 40.52,99.71 v1(40.91,99.33)
  IN1 w0.508: v1(36.98,100.22) 36.98,99.99 37.64,99.33 v1(40.91,99.33) 42.58,99.33 43.18,99.92 43.18,103.63 v1(43.87,104.33) 43.11,105.09 43.11,108.71 v1(42.86,108.96) 41.88,109.94 38.07,109.94 v1(36.65,108.52)
  BOTTOM w0.254: UT9.38 37.6,101.18 36.98,100.56 v1(36.98,100.22) ; UT9.10 41.96,107.38 42.16,107.58 CT618.1 ; v1(40.91,99.33) UT9.30 ; 38.54,107.64 38.81,107.38 UT9.1 ; v1(43.87,104.33) UT9.16
  BOTTOM w0.508: 38.54,107.64 CT617.1 CT614.1 37.28,108.96 37.02,109.23 LT605.2 36.65,109.23 v1(36.65,108.52) ; v1(42.86,108.96) CT618.1
+1.2V_VDD_R1: length 5.6
  TOP w0.127: v1(40,107.58) 40,106.96 v2(39.81,106.77)
  TOP w0.508: v1(40,107.58) 40.01,107.59 CT625.1 CT44.1 CT48.1 40.01,110.85 LT602.2
  BOTTOM w0.254: UT9.6 40.56,107.23 40.21,107.58 v1(40,107.58)
+1.2V_VDD_R2: length 5.2
  TOP w0.127: v2(41.12,106.84) 40.89,107.07 v1(40.89,107.58)
  TOP w0.508: LT601.2 40.88,110.85 CT629.1 CT47.1 CT610.1 40.88,107.6 v1(40.89,107.58)
  BOTTOM w0.254: v1(40.89,107.58) 40.89,107.58 40.91,107.56 UT9.7
+1.05VALWP: length 20
  TOP w0.254: PC320.1 216.16,132.71 216.02,132.85 216.02,135.07 216.53,135.58 v2(217.99,135.58) 218.05,135.63 231.64,135.63 PC307.1 231.82,134.66 PR306.1
  vias: v1(219.39,132.79) v1(220.02,132.79) v1(220.66,132.79) v1(221.29,132.79)
+1.8V_ALW_VTR3: length 35.7
  TOP w0.254: v1(258.29,94.85) 257.78,94.85 257.29,94.36 256.93,94.36 256.68,94.61 UE1.N5
  TOP w0.508: v1(253.86,109.28) 253.86,110.04 RE829.2 ; RE340.1 v1(254.31,89.76) ; v1(257.24,87.42) 257.24,87.7 256.85,88.08 RE549.1
  IN3 w0.508: v1(257.24,87.42) 257.24,87.95 255.77,89.42 255.76,89.42 255.58,89.61 254.47,89.61 v1(254.31,89.76)
  BOTTOM w0.508: v1(257.24,87.42) 257.24,87.84 257.61,88.21 257.61,90.62 257.87,90.88 v2(257.87,92.78) 258.48,93.39 258.48,94.66 v1(258.29,94.85) 257.59,95.55 256.98,95.55 256.72,95.81 256.72,100.91 258.19,102.37 258.19,104.2 257.12,105.27 256.79,105.27 255.95,106.11 255.95,107.13 255.32,107.76 254.72,107.76 253.86,108.62 v1(253.86,109.28)
+1.8V_PRIM: length 229.1
  TOP w0.381: 262.31,40.84 263.2,40.84 263.58,41.22 RC733.2 ; 262.31,40.84 260.75,40.84 259.38,42.22 QZ22.2 ; 262.31,40.84 RC724.2
  TOP w0.508: RC842.2 198.13,97.91 v1(198.13,99.1) ; QC8.2 263.82,79.58 RZ132.1 v1(262.63,79.58) ; RC244.1 184.88,78.07 v1(184.97,77.98)
  IN1 w0.508: 259.58,64.34 259.02,63.78 259.02,59.56 260.56,58.02 260.56,51.88 259.62,50.94 259.62,43.61 v1(258.5,42.49) ; v1(262.63,79.58) 262.03,79.58 259.09,76.63 259.09,74.61 258.2,73.72 258.2,67.88 259.56,66.52
  IN2 w0.508: v1(190,77.84) 190,79.32 189.36,79.96 188.15,79.96 187.36,80.75 187.36,81.78 183.26,85.88 183.26,87.38 182.82,87.82 182.82,87.82 182.37,88.28 182.37,94.69 183.49,95.81 v1(183.49,96.48) ; v1(198.13,99.1) 197.89,98.86 197.89,98.82 197.54,98.47 196.51,98.47 194.69,100.29 189.49,100.29 188.53,99.32 184.52,99.32 v1(183.48,100.36)
  IN2 w1.016: 234.12,111.77 229.15,111.77 225.28,107.9 205.04,107.9 204.78,108.15 201.75,108.15 199.97,109.93 198.56,109.93 198.5,109.87 ; 274.06,94.18 274.89,94.18 275.9,93.16 275.9,83.12 276.68,82.34 276.68,80.58 277.26,80 277.26,77.3 276.5,76.54 276.5,70.72 277.3,69.92 277.3,69.61
  IN3 w1.016: 271.45,95.11 267.63,95.11 267.27,94.75 265.87,94.75 265.62,94.5 263.96,94.5
  BOTTOM w0.168: 183.33,96.48 v1(183.49,96.48)
  BOTTOM w0.18: UC1.CP23 183.33,96.48
  BOTTOM w0.203: UC1.CP17 183.39,100.26 v1(183.48,100.36)
  BOTTOM w0.508: v1(190,77.84) 190,77.33 189.45,76.78 186.56,76.78 185.36,77.98 v1(184.97,77.98) ; CC98.1 183.56,100.28 v1(183.48,100.36) ; v1(183.49,96.48) 184.07,96.48 184.34,96.21 CC1464.1
  BOTTOM w1.016: 275.8,68.53 271.32,68.53 268.71,65.92 266.9,65.92 266,65.02 260.74,65.02 ; 236.41,112.97 247.75,112.97 248.71,112.01 256.87,112.01 260.17,108.71 260.17,106.29 261.7,104.75 261.7,96.11 261.67,96.07
  vias: v1(176.49,101.15) v1(176.49,99.47) v1(177.14,101.15) v1(177.14,99.47) v1(196.53,109.61) v1(196.91,109.1) v1(197.16,109.74) v1(235.3,111.87) v1(235.89,111.87) v1(259.81,65.57) v1(259.81,64.97) v1(261.81,95.2) v1(261.81,94.57) v1(272.15,94.56) v1(272.16,93.98) v1(276.66,68.27) v1(277.05,68.72) v3(194.22,106.69)
+1.8V_RUN: length 1.7
  TOP w0.127: v3(275.7,61.78) 276.09,61.39 277.27,61.39
+1.8V_RUN_AUDIO: length 7.8
  TOP w0.203: UA1.29 284.13,56.55 283.58,57.1 283.31,57.1 ; UA1.33 282,54.54 281.56,54.98 280.94,54.98 CA57.1
  TOP w0.381: CA57.1 v1(280.74,55.73)
  IN1 w0.508: v1(280.98,58.62) 281.24,58.37 281.24,56.23 v1(280.74,55.73)
  vias: v2(280.46,59.19)
+1.8V_RUN_CARD: length 32.6
  TOP w0.203: UR1.13 290.81,20.87 290.95,20.73 290.95,20.46 v1(291.14,20.27)
  TOP w0.508: JSD1.15 307.69,22.32 306,24.01 304.54,24.01 v2(302.98,25.58) 302.45,26.11 302.32,26.11 ; CR20.2 v1(300.92,25.28)
  BOTTOM w0.762: v1(291.14,20.27) 292.26,20.27 292.64,20.65 294.7,20.65 294.95,20.39 297.28,20.39 298.06,21.18 298.06,22.17 298.83,22.93 300.48,22.93 300.92,23.38 v1(300.92,25.28)
+1.8V_RUN_UZ46: length 1
  TOP w0.127: CZ120.1 v2(278.4,65.21)
+1.8VALWP: length 6.9
  TOP w0.508: PC501.1 v1(199.83,108.85)
  BOTTOM w0.127: PL501.2 197.13,110.98 v2(196.96,111.15)
  BOTTOM w0.254: 200.4,108.72 200.53,108.6 202.5,108.6 203.06,109.15 PR501.1 PC503.1
+1VS_VCCIOP: length 17.5
  TOP w0.254: PR421.1 108.06,79.96 113.47,79.96 v2(113.52,79.91) 114.03,79.91 115.5,78.43 115.5,72.4 114.8,71.7 113.53,71.7 112.77,72.46
+2.5V_MEM: length 91.2
  TOP w1.016: 170.62,43.63 170.62,52.59 169.41,53.79
  IN2 w0.762: 171.72,42.87 214.8,42.87 214.86,42.82 242.73,42.82 244.24,44.34 244.24,50.58 245.04,51.38
  vias: v1(168.49,55.02) v1(168.49,54.38) v1(170.3,42.75) v1(170.94,42.75) v1(245.22,52.29) v1(245.86,52.29) v3(241.4,53.72)
+3.3V_ALW: length 439.1
  TOP w0.254: PR418.1 214.05,129.04
  TOP w0.356: CE53.1 269.96,91.09 269.98,91.12 UE3.5 ; CZ91.1 185.73,38.72 185.15,38.14 184.12,38.14 v1(184.08,38.17)
  TOP w0.381: v1(254.57,81.71) 254.02,81.71 253.64,81.33 CE52.1 253.64,80.82 253.66,80.8 UE5.5 ; CE53.1 269.55,90.8 v1(268.89,90.14) 267.56,90.14 266.58,91.12 UE4.5 265.3,91.12 265.23,91.18 CE61.1 ; v1(270.02,94.24) 270.02,94.6 269.64,94.98 CZ82.1 268.69,94.98 268.59,95.08 UZ41.5 ; UZ10.5 309.15,7.58 CZ93.1 v1(309.18,8.33)
  TOP w0.406: v1(191.67,127.12) 191.67,127.09 191.94,126.81 UZ35.5
  TOP w0.508: RE561.2 261.31,90.69 264.23,90.69 CE61.1 ; PR410.1 v1(208.53,135.44) ; PR838.1 v1(41.77,91.89) ; RE365.2 RE526.2 243.28,105.56 v1(243.05,105.33) 242.97,105.26 242.97,103.91 244.03,102.86 RE21.2 ; RZ8.1 232.72,36 v1(232.91,35.81) ; v1(249.61,106.25) 249.76,106.1 249.76,105.9 249.87,105.79 RE79.1 ; RE12.2 257.74,84.97 256.74,83.97 RE728.2 RE729.2 RE727.2 RE69.1 253.3,84.85 v1(253.18,84.96) 253.17,84.97 RE730.2 ; PR413.1 v1(103.56,80.59) ; PR839.1 43.56,87.2 v1(43.11,86.75) ; v1(264.66,105.23) 264.35,105.23 264.22,105.1 RE605.2 ; v1(277.99,122.98) RZ1390.2 277.36,122.97 277.36,122.21 QZ18.3 ; RE68.2 v1(253.63,74.95) ; RZ518.1 271.83,72.53 v1(272.09,72.53) 272.35,72.53 272.73,72.91 272.73,74.78 270.59,76.91 RZ1483.1 ; RC68.2 186.47,74.14 v1(187.76,72.84) 187.34,72.42 QC7.3 186.29,70.69 RC214.2 ; RZ1482.1 241.71,115.85 242.39,115.17 243.8,115.17 244.23,114.74 244.23,112.67 v1(244.92,111.98) ; RZ9.1 229,35.86 v1(229,35.09) ; PR1.1 152.42,39.7 155.19,42.47 v1(155.19,44.59) ; PR414.1 v1(102.67,80.59) 102.67,81.23 102.17,81.73 100.63,81.73 v3(98.78,79.89) 97.46,78.56 v3(95.74,78.56) PR851.1 ; v1(238.17,130.34) 238.17,130.34 PR313.2 ; v1(88.2,64.84) 87.9,64.55 PR205.1 ; v1(50.67,92.23) PR828.1 ; PR830.1 PR833.1 41,87.04 41.51,86.53 v1(41.64,86.53) ; RE43.2 RE37.2 v1(260.41,87.58) ; v1(243.01,84.91) 243.09,84.83 RE11.2 RE362.2 RE505.2 RE343.1 ; RZ1397.1 v1(282.41,73.99) ; RE83.2 248.32,105.79 v1(248.32,106.25) ; RE35.2 254.82,105.55 v1(254.35,106.02) ; PR726.1 v1(83,52.4) ; PR825.1 v1(45.52,92.1) ; RE828.2 254.61,115.06 255.15,115.61 258.76,115.61 259.23,115.14 259.23,112.9 RE826.1 258.55,111.59 257.31,110.35 RE300.1 257.31,109.2 v1(257.52,108.98) ; v1(273.2,92.8) 273.32,92.8 273.83,93.3 RE821.2 ; v1(34.56,111.39) 35.36,110.59 RT398.1 ; PR404.1 v1(105.6,70.05) ; v1(45.27,86.36) PR824.1 ; PR852.1 87.77,115.19 87.48,114.9 PR865.2 87.48,114.09 85.37,111.98 v1(84.7,111.98) ; RE63.2 v1(245.49,107.52) ; RZ1410.1 v1(229.88,96.09) ; RZ1404.2 285.14,88.19 283.9,89.42 CZ322.1 ; PR417.1 v1(211.64,126.38) ; PR307.1 v1(234.31,135.3) ; v1(191.66,73.26) RC431.2 190.8,72.29 RC432.1 ; RZ133.1 v1(263.63,84.47)
  TOP w0.889: 228.86,83.55 227.88,82.57
  IN1 w0.508: v1(213.48,130.31) 213.93,130.76 213.93,134.25 214.87,135.2 230,135.2 230.88,134.31 v1(230.88,132.53) 231.08,132.33 232.39,132.33 234.31,134.25 v1(234.31,135.3) ; v1(249.61,106.25) v1(248.32,106.25) ; v1(213.85,86.96) 214.35,87.47 v1(217.93,87.47) ; v1(265.99,68.15) 266.98,68.15 267.31,67.83 269.61,67.83 272.09,70.31 v1(272.09,72.53) 281.63,72.53 282.41,73.3 v1(282.41,73.99)
  IN2 w0.508: v1(244.92,111.98) 247.42,109.48 247.42,106.82 248,106.25 v1(248.32,106.25) ; v1(254.57,81.71) 254.57,83.13 253.18,84.52 v1(253.18,84.96) ; v1(280.2,93.53) 280.2,92.48 281.14,91.54 v1(281.14,90.07) ; v1(196.8,36.92) 192.94,33.05 185.9,33.05 184.21,34.74 184.21,38.05 v1(184.08,38.17) 183.94,38.31 167.9,38.31 163.34,42.87 163.31,42.9 156.88,42.9 v1(155.19,44.59) ; v1(279.54,93.55) 279.54,94.22 280.16,94.84 280.16,99.39 278.25,101.29 278.25,116.18 277.33,117.1 277.33,122.32 v1(277.99,122.98) ; v1(77.05,69.75) 77.76,69.03 84.01,69.03 v1(88.2,64.84)
  IN3 w0.508: v1(238.17,130.34) 238.17,132.94 236.66,134.45 234.78,134.45 234.31,134.92 v1(234.31,135.3) ; v1(248.4,103.77) 248.32,103.85 v1(248.32,106.25) ; v1(309.18,8.33) 308.67,8.84 306.34,8.84 305.84,9.34 305.84,11.47 306.39,12.02 306.39,13.88 305.88,14.39 302.78,14.39 302.24,14.93 301.27,14.93 298.22,17.98 293.94,17.98 292.79,19.12 289.61,19.12 287.81,20.92 269.22,20.92 267.52,22.62 267.52,23.74 261.49,29.77 261.49,30.38 260.5,31.38 255.71,31.38
  BOTTOM w0.254: PU200.13 89.55,64.93 88.9,64.27 PC206.1 ; PR107.1 199.61,34.81 199.02,35.41 198.28,35.41 196.8,36.88 v1(196.8,36.92)
  BOTTOM w0.305: JKBTP1.6 185.99,38.99 185.04,38.04 184.28,38.04 184.15,38.17 v1(184.08,38.17) ; v1(309.18,8.33) 309.07,8.43 JLED1.1 ; JAPS1.7 242.74,84.64 v1(243.01,84.91) 243.2,85.1 244.47,85.1 244.74,84.83 JAPS1.3
  BOTTOM w0.381: v1(60.96,98.37) RT68.2 ; v1(88.2,64.84) 88.43,64.62 PC206.1
  BOTTOM w0.508: PR4.2 PR28.2 92.04,117.94 v1(92.04,115.63) ; v1(268.89,90.14) 269.31,90.56 270.51,90.56 271.01,91.07 271.01,92.34 ; v1(213.85,86.96) 213.55,86.66 RE73.1 RE75.1 ; PR821.2 79.55,100.97 PQ807.2 79.55,99.78 v1(80.2,99.13) ; v1(247.07,90.39) 247.01,90.45 RE302.2 RE303.2 ; v1(248.4,103.77) 247.96,103.33 RE606.2 RE10.2 RE91.2 ; 271.01,92.34 270.02,93.33 v1(270.02,94.24) ; 271.01,92.34 272.28,92.34 272.74,92.8 v1(273.2,92.8) ; v1(45.52,92.1) 45.52,90.75 44.53,89.76 44.53,87.94 45.27,87.2 v1(45.27,86.36) 43.51,86.36 v1(43.11,86.75) 41.86,86.75 v1(41.64,86.53) ; RZ377.1 v1(262.95,41.48) ; RT483.1 v1(53.27,98.45) ; PR113.1 77.33,69.47 v1(77.05,69.75) ; RE92.2 249.67,87.95 249.67,86.25 250.2,85.72 RE726.2 250.38,85.42 249.55,84.59 v1(249.17,84.59)
  BOTTOM w1.016: 214.88,109.04 212.18,109.04 208.62,112.6 207.96,112.6
  vias: v1(153.35,136.47) v1(153.98,136.47) v1(213.48,129.68) v1(216.02,108.98) v1(216.66,108.98) v1(218.45,86.94) v1(220.21,34.36) v1(220.21,33.73) v1(220.21,33.09) v1(220.21,32.46) v1(220.21,31.82) v1(220.21,31.19) v1(220.85,34.36) v1(220.85,33.73) v1(220.85,33.09) v1(220.85,32.46) v1(220.85,31.82) v1(220.85,31.19) v1(221.48,34.36) v1(221.48,33.73) v1(221.48,33.09) v1(221.48,32.46) v1(221.48,31.82) v1(221.48,31.19) v1(222.12,34.36) v1(222.12,33.73) v1(222.12,33.09) v1(222.12,32.46) v1(222.12,31.82) v1(222.12,31.19) v1(227.92,87.12) v1(228.02,87.7) v1(228.47,87.32) v1(228.39,86.74) v1(228.8,86.32) v1(229.02,87.51) v1(229.02,86.87) v1(229.01,85.78) v1(229.02,85.17) v1(229.01,84.55) v1(229.57,38.9) v1(229.57,38.32) v1(230.21,38.9) v1(240.85,64.21) v1(241.49,64.21) v1(252.33,106.27) v1(254.31,41.98) v1(254.31,41.35) v1(254.31,40.71) v1(254.31,40.08) v1(254.69,39.51) v1(254.95,41.98) v1(254.95,41.35) v1(254.95,40.71) v1(254.95,40.08) v1(255.33,39.51) v1(255.58,41.98) v1(255.58,41.35) v1(255.58,40.71) v1(255.58,40.08) v1(255.96,39.51) v1(256.22,41.35) v1(256.22,40.71) v1(256.22,40.08) v1(263.01,98.78) v1(264.09,102.44) v1(264.79,68.15) v1(265.13,67.57) v1(265.38,68.13) v1(265.72,67.56) v1(279.76,89.22) v1(279.79,89.81) v1(280.46,89.84) v1(280.46,89.22) v3(227.78,81.47)
+3.3V_ALW2: length 353.1
  TOP w0.127: RE57.2 241.24,85.61 241.55,85.3 241.55,84.62 v2(241.21,84.27)
  TOP w0.508: RE57.2 240.6,85.61 v1(240.54,85.54)
  IN1 w0.508: v1(80.91,40.67) 80.22,40.67 76.26,44.64 76.26,47.19 76.96,47.89 76.96,52.97 74.99,54.94 74.99,64.53 74.58,64.94 74.58,67.76 74.96,68.15 v1(74.96,68.62)
  IN2 w0.508: v1(240.54,85.54) 240.98,85.54 240.98,85.54 240.98,85.54 241.36,85.54 241.87,85.04 241.87,79.2 244.34,76.72 245.2,76.72 251.9,70.02 251.9,69.25 256.51,64.64 256.51,63.12 260.01,59.62 260.01,53.81 258.25,52.05 258.25,48.19 258.92,47.52 258.92,46.36 258.22,45.66 258.22,44.94 256.83,43.55 256.83,39.51 256.22,38.9 254.98,38.9 254.04,37.95 254.04,36.72 252.95,35.63 251.72,35.63 251.12,35.03 248.58,35.03 248.14,35.48 247,35.48 244.44,38.04 241.35,38.04 240.23,36.91 232.75,36.91 232.22,36.38 227.59,36.38 v1(226.26,35.05) ; v1(80.91,40.67) 82.62,42.38 82.62,44.9 82.55,44.97 82.55,47.93 83.03,48.41 85.62,48.41 85.97,48.05 86.65,48.05 87.49,48.89 90.68,48.89 91.89,50.11 97.29,50.11 98.1,50.91 98.1,52.31 100.28,54.48 129.71,54.48 131.14,53.06 131.14,48.89 132.02,48.01 132.8,48.01 133.59,47.22 133.78,47.22 134.93,46.07 134.93,45.24 135.82,44.35 135.82,43.72 137.01,42.54 146.75,42.54 149.3,39.98 162.1,39.98 166.69,35.39 177.09,35.39 182.35,30.13 193.51,30.13 196.42,33.04 197.45,33.04 198.67,34.26 198.67,34.44 199.39,35.16 202.29,35.16 202.41,35.29 205.21,35.29 207.47,37.55 v1(208.41,37.55) ; v1(74.61,103.71) 74.61,95.7 72.69,93.79 72.69,86.61 73.08,86.22 v1(73.08,85.16)
  IN3 w0.508: v1(73.08,85.16) 70.67,82.75 70.67,80.78 71.75,79.7 71.75,71.96 74.96,68.74 v1(74.96,68.62) ; v1(226.26,35.05) 226.26,36.03 225.68,36.61 222.19,36.61 221.1,37.7 215.04,37.7 214.69,37.35 208.69,37.35 208.48,37.55 v1(208.41,37.55) ; v1(85.4,103.63) 84.72,104.32 74.98,104.32 74.61,103.94 v1(74.61,103.71)
  BOTTOM w0.508: PR860.1 v1(85.4,103.63) ; PR104.2 207.91,38.38 208.41,37.87 v1(208.41,37.55)
+3.3V_ALW_DSW: length 245.8
  TOP w0.381: v1(171.34,95.3) 171.67,95.63 CC1463.1 171.95,96.95 v1(171.93,96.98)
  TOP w0.508: 182.65,71.72 CC280.1 CC279.1 ; 182.65,71.72 RC323.2 ; 182.65,71.72 182.65,74.2 v1(182.72,74.27) 183.1,74.65 RC72.2 RC67.2 ; CC279.1 184.77,71.67 RC214.1 RC439.1 ; CC279.1 185.85,71.72 RC440.1 ; v1(72.77,130.82) 72.32,130.38 v2(72.32,129.54) 72.32,125.3 70.42,123.39 70.42,118.95 v1(70.7,118.66) ; RC241.2 88.7,133.11 88.32,132.73 v1(88.32,132.61)
  IN2 w0.254: 172.4,94.56 172.46,94.5 172.9,94.5 173.24,94.16 173.34,94.07 173.34,93.26 173.37,93.23 173.37,93.05 173.36,93.04 173.36,91.97 173.34,91.95 173.34,91.9 173.34,91.9 173.34,91.5 173.34,91.49 173.34,90.82 173.63,90.54 173.63,90.54 173.67,90.5 174.06,90.5 174.41,90.85 174.81,90.85 175.1,90.57 175.1,90.26 175.38,89.98 175.77,89.98 175.83,89.93 175.88,89.93 175.88,89.79 175.57,89.48 175.13,89.48 174.75,89.86 172.78,89.86 172.37,90.27 172.37,90.81 172.37,90.82 172.37,91.22 172.32,91.26 172.32,91.88 172.35,91.91 172.35,92.67 172.37,92.7 172.37,93.44 172.37,93.44 172.37,94.59
  IN2 w0.508: v1(187.7,83.7) 188.91,83.7 192.71,79.91 196.47,79.91 197.95,78.43 199.46,78.43 200.1,77.8 v1(200.21,77.8) ; v1(171.34,95.3) 171.66,95.3 172.4,94.56 ; v1(180.34,85.8) 179.52,85.86 176.21,89.17 176.21,89.55 175.96,89.79 175.88,89.79 ; v1(72.77,130.82) 75.5,133.55 87.5,133.55 88.32,132.73 v1(88.32,132.61)
  IN3 w0.254: 169.54,98.79 169.54,98.61 170.78,97.37 171.53,97.37 171.89,97.01 171.89,96.98 v1(171.93,96.98)
  IN3 w0.508: v1(70.7,118.66) 73.65,118.66 74.01,119.02 75.2,119.02 76,118.21 76,115.03 76.51,114.53 77.94,114.53 79.08,115.67 87.24,115.67 87.95,114.96 87.95,109.49 92.15,105.29 93.91,105.29 94.38,104.82 98.01,104.82 98.59,104.24 106.12,104.24 109.12,101.24 111.53,101.24 113.62,99.16 126.55,99.16 128.56,101.17 135.77,101.17 137.19,102.59 142.62,102.59 144.22,100.99 167.33,100.99 169.54,98.79
  BOTTOM w0.203: UC1.BR24 171.06,95.68 171.35,95.32 v1(171.34,95.3) ; v1(171.93,96.98) 171.89,96.98 171.89,96.97 171.9,96.91 UC1.BT23
  BOTTOM w0.508: RC555.2 172.97,80.08 173.15,79.91 173.15,77.75 175.64,75.26 180.86,75.26 181.84,74.27 v1(182.72,74.27) 183.74,73.26 186.46,73.26 186.96,73.76 189.82,73.76 190.43,74.36 190.43,74.94 191,75.51 198.37,75.51 200.21,77.35 v1(200.21,77.8) ; v1(187.7,83.7) 187.59,83.59 182.76,83.59 182.25,84.1 182.25,85.05 181.5,85.8 v1(180.34,85.8)
+3.3V_ALW_DSW_R: length 4.7
  TOP w0.107: QC7.1 188.31,70.27 188.15,70.43 187.26,70.43 186.62,69.8 RC439.2 v2(185.68,68.7)
+3.3V_ALW_PCH: length 409.6
  TOP w0.305: 169.37,76.41 169.37,75.29 169.7,74.95 RC187.2
  TOP w0.381: RC725.2 188.75,78.5 188.75,77.93 188.75,77.93 v1(188.75,77.92) ; RC46.1 RC831.1 192.7,78.43 192.7,78.18 v1(193.07,77.81) ; v1(281.23,73.35) CZ216.1 280.68,73.66 280.64,73.69 UZ51.5 ; v1(192.89,99.28) 193.08,99.47 RC277.2
  TOP w0.508: v1(60.76,112.63) 59.07,112.63 57.71,113.99 54.77,113.99 54.29,114.47 v1(54.29,123.01) ; RZ1408.1 217.38,98.97 216.66,98.24 v1(214.5,98.24) ; RC440.2 185.64,72.94 v1(185.64,74.29) RC344.2 ; RC840.2 v1(190.83,98.19) ; v1(190.18,103.45) 189.7,102.97 189.7,101.52 v1(190.3,100.91) ; RC347.2 196.5,103.91 197.12,103.29 v1(197.12,102.52) 197.12,102.13 196.43,101.44 RC348.2 RC748.2 ; RZ379.1 269.81,76.18 v1(270.39,76.18) ; 169.37,76.41 169.67,76.71 171.4,76.71 171.84,76.27 174.87,76.27 176.08,75.07 179.13,75.07 v1(179.95,75.89) 179.95,76.58 RC834.2 RC451.2 ; v1(214.63,104.66) 217.75,104.66 218.57,103.84 219.36,103.84 RZ69.1 219.57,107.55 v1(218.24,108.87) ; RC12.2 v1(198.79,102.54) ; RC133.2 v1(91.24,134.95) ; v1(199.43,98.44) 199.39,98.44 198.87,98.95 RC14.2 ; RC866.2 v1(240.27,125.89)
  TOP w1.016: 220.21,82.94 217.67,82.94 216.21,81.48 216.21,77.86 216.34,77.73
  IN1 w0.508: v1(270.39,76.18) 270.43,76.21 272.04,76.21 274.19,74.06 280.17,74.06 280.88,73.35 v1(281.23,73.35)
  IN2 w0.508: v1(91.24,134.95) 91.24,134.69 90.74,134.19 73.7,134.19 69.09,129.58 60.86,129.58 v1(54.29,123.01) ; v1(173.89,96.11) v1(175.84,96.11) ; v1(246.44,82.98) 246.3,82.98 245.79,82.46 245.02,82.46 243.9,83.58 243.9,85.61 243.27,86.24 240.53,86.24 240.05,86.72 240.05,89.96 239.71,90.31 239.71,91.82 240.81,92.92 240.81,93.8 240.29,94.31 240.29,96.23 241.12,97.06 241.12,101.98 238.88,104.21 238.88,107.13 240.44,108.7 240.44,111.29 237.98,113.75 v1(237.55,114.18) 236.41,113.04 228.96,113.04 224.8,108.87 v1(218.24,108.87)
  IN3 w0.254: v1(175.84,100.31) 175.39,99.87 175.39,99.19 175.64,98.94 175.64,97.8 v1(176.49,96.95)
  IN3 w0.508: v1(270.39,76.18) 269.33,76.18 267.86,74.71 265.83,74.71 265.25,75.29 265.25,76.42 264.74,76.93 263.62,76.93 262.62,77.94 260.3,77.94 259.65,78.58 258.25,78.58 255.69,81.15 255.69,81.46 254.5,82.65 250.34,82.65 250.01,82.98 v1(246.44,82.98) ; v1(237.55,114.18) 240.68,114.18 241.52,115.01 v1(241.52,117.82) 241.52,123.17 240.27,124.42 v1(240.27,125.89) ; v1(60.76,112.63) 64.45,112.63 69.74,107.34 81.4,107.34 82.78,105.96 90.57,105.96 91.87,104.66 93.65,104.66 94.12,104.19 97.75,104.19 99.22,102.72 106.75,102.72 108.45,101.01 108.45,98.4 109.09,97.76 126.05,97.76 128.88,100.59 136.97,100.59 137.2,100.36 167.14,100.36 170.75,96.75 v1(170.75,96.11)
  BOTTOM w0.2: v1(175.84,100.31) UC1.CB16
  BOTTOM w0.203: v1(184.19,92.86) 183.4,92.86 183.28,92.74 182.63,92.74 182.55,92.7 UC1.CP29 ; v1(170.75,96.11) 170.71,96.12 170.67,96.16 170.59,96.18 UC1.BP23 ; UC1.BW23 v1(173.89,96.11) ; UC1.BV23 v1(173.24,96.11)
  BOTTOM w0.305: JSPI1.16 201.08,85.18 v1(200.97,85.29) ; JAPS1.1 245.74,83.68 v1(246.44,82.98)
  BOTTOM w0.508: CC75.1 184.29,92.96 v1(184.19,92.86) ; RC94.1 182.07,81.87 RC61.1 182.21,81.11 v1(182.17,81.07) ; 190.81,99.01 190.87,99.07 192.02,99.07 192.21,99.26 ; 190.81,99.01 190.81,100.4 v1(190.3,100.91) 189.92,101.29 RC744.2 RC507.2 ; 190.81,99.01 190.77,98.97 189.71,98.97 RC15.2 RC266.2 RC400.2 RC847.2 RC829.2 ; 190.81,99.01 190.81,98.31 190.83,98.3 v1(190.83,98.19) ; v1(190.18,103.45) 190.05,103.58 RC743.2 ; 192.21,99.26 192.23,99.28 192.89,99.28 v1(192.89,99.28) ; 192.21,99.26 192.21,98.75 193.1,97.86 193.1,95.63 193.28,95.45 ; v1(184.75,81.1) 184.65,81.2 RC62.1 ; v1(241.52,117.82) 242.39,118.69 RC222.2 ; RC288.2 RC101.1 191.81,92.91 v1(192.11,92.62) ; DC4.2 203.65,102.05 v1(203.36,102.35) ; 193.28,95.45 192.77,94.94 RC443.2 RC537.2 RC830.2 ; 193.28,95.45 193.6,95.13 v1(194.62,95.13) 195.45,95.13 195.96,95.64 195.96,97.42 196.65,98.12 199.11,98.12 v1(199.43,98.44) ; RC73.2 RC317.2 RC183.2 v1(178.85,81.18) 178.85,81.18 RC95.2
  vias: v1(176.49,96.11) v1(177.14,96.95) v1(177.13,96.11) v1(201.94,96.28) v1(204.91,83.13) v1(214.12,76.65) v1(214.75,76.65) v3(216.81,76.77)
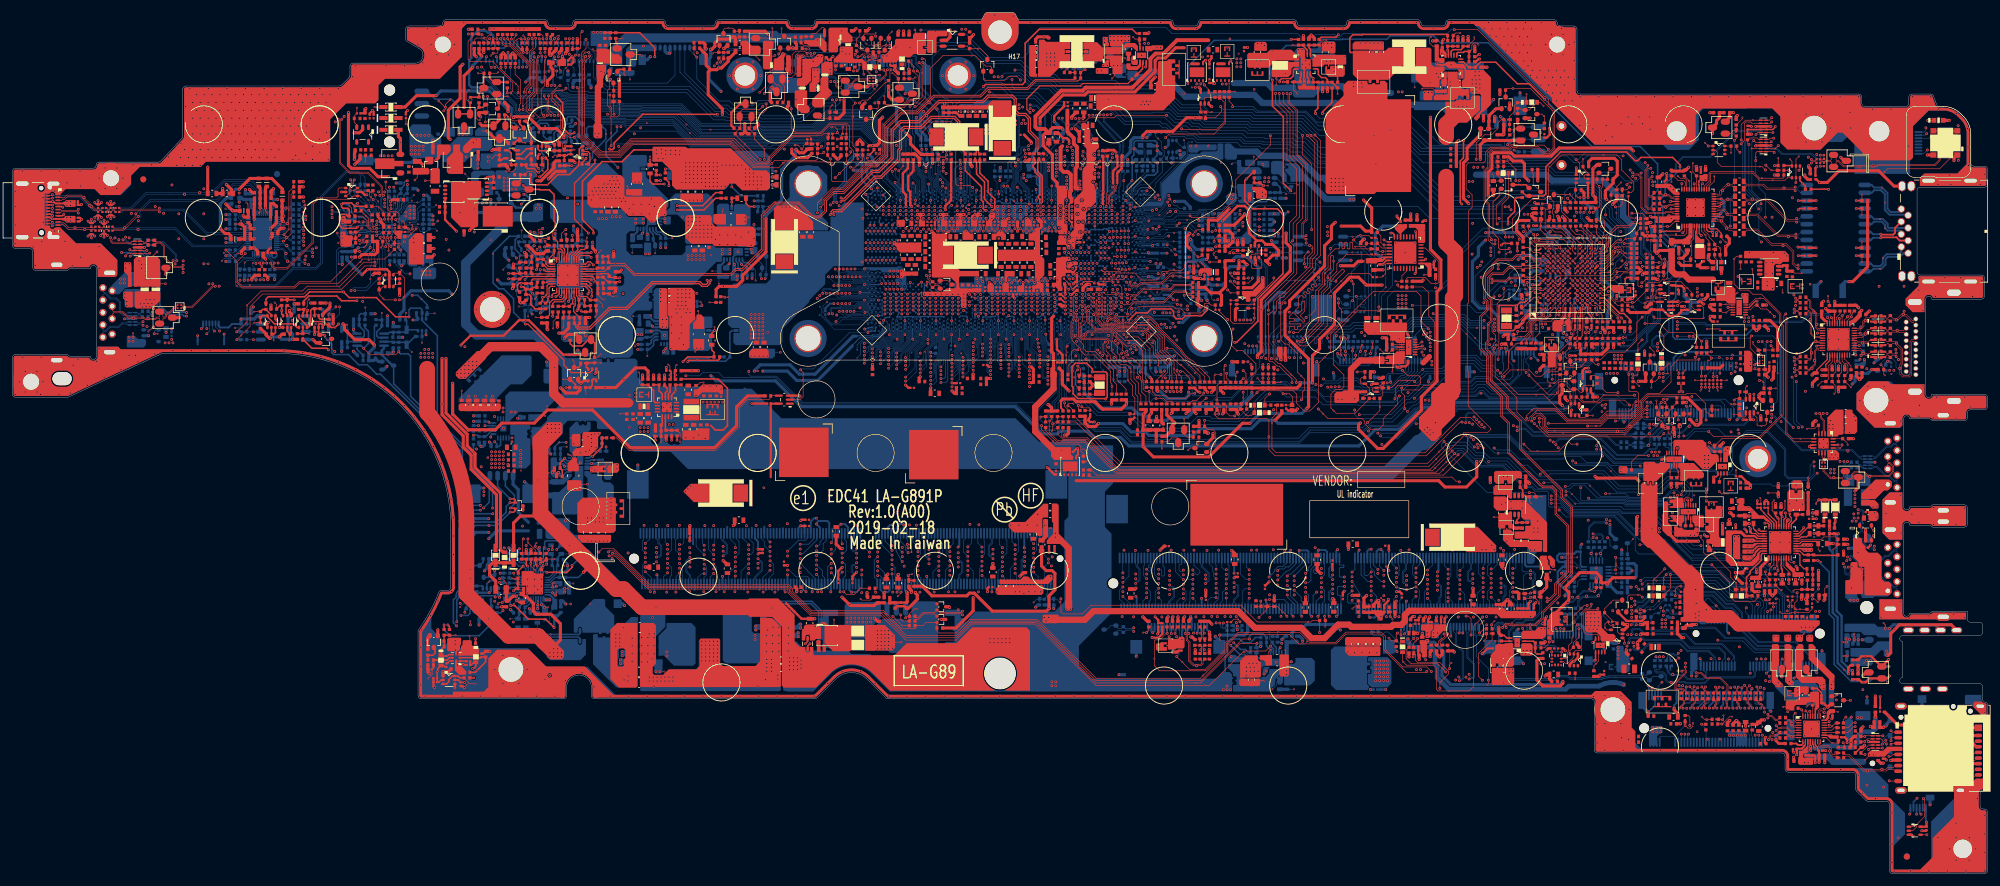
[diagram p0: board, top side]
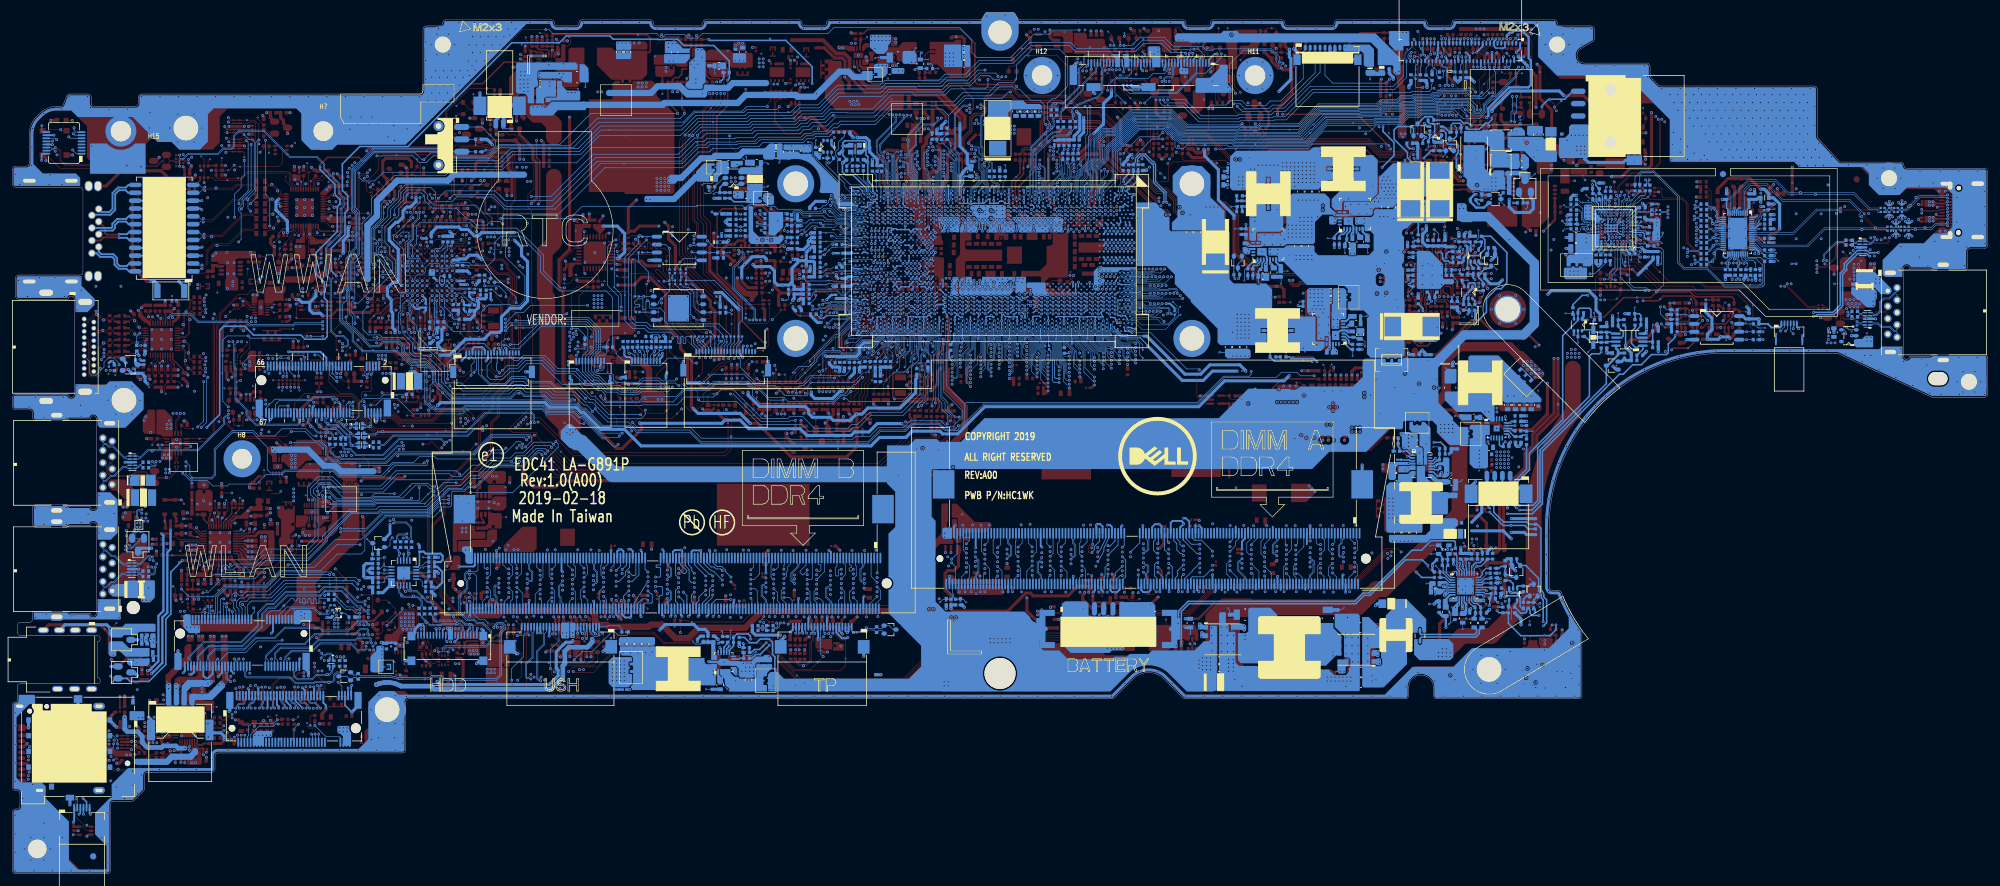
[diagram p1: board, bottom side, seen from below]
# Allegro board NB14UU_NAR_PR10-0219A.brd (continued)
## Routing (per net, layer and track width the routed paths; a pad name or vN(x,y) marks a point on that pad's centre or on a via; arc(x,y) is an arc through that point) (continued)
+3.3V_ALW_PCH_U44: length 1.6
  TOP w0.127: 222.91,82.74 v2(222.91,81.13)
+3.3V_ALW_UE1: length 35.2
  TOP w0.254: v1(252.55,90.75) 252.45,90.85 UE1.H1 ; CE23.1 255.07,89.98 254.44,90.62 254.44,91.24 254.45,91.25 254.45,91.84 v1(254.44,91.85) 254.42,91.87 254.39,91.87 UE1.K2 ; UE1.G8 251.43,97.23 251.43,97.26 v1(251.23,97.45) ; v1(247.24,95.81) UE1.B7
  TOP w0.33: v1(256.05,98.24) 256.05,98.21 UE1.M9
  TOP w0.381: CE20.1 252.41,90.61 v1(252.55,90.75)
  IN2 w0.457: 251.23,95.04 252.03,94.24
  IN2 w0.508: v1(248.79,87.13) 248.93,87.13 v1(252.55,90.75) 252.55,91.63 252.03,92.14 252.03,94.24 ; v1(251.23,97.45) 251.23,97.44 251.23,97.44 251.23,96.63 ; 251.23,96.63 251.23,95.04 ; 251.23,96.63 247.56,96.63 247.24,96.31 v1(247.24,95.81)
  IN3 w0.508: v1(256.05,98.24) 256.05,97.34 255.54,96.83 251.86,96.83 v1(251.23,97.45)
  BOTTOM w0.356: v1(252.55,90.75) 252.28,91.02 CE15.1 253.21,91.48 253.39,91.3 v2(253.89,91.3) v1(254.44,91.85)
  BOTTOM w0.381: CE14.1 246.66,95.81 CE13.1 247.23,95.8 v1(247.24,95.81)
+3.3V_ALW_UZ12: length 1
  TOP w0.127: RZ1410.2 v2(228,96.78)
+3.3V_ALWP: length 25.7
  IN3 w0.254: v1(205.04,37.22) 205.42,36.84 214.39,36.84 215.41,35.82 v1(215.7,35.82)
  IN3 w0.508: v1(216.78,35.7) 216.16,35.07 215.44,35.07 214.18,36.33 204.97,36.33 v1(204.78,36.52)
  BOTTOM w0.254: PU100.14 204.59,36.33 v1(204.78,36.52) ; v1(205.04,37.22) 204.97,37.22 204.8,37.4 PR108.2
  vias: v1(217.99,35.7) v1(219.2,35.7) v1(220.4,35.7) v2(216.07,35.35)
+3.3V_CAM:
  vias: v1(130.09,132.07) v1(130.7,132.05) v3(129.37,131.29)
+3.3V_CAM_F:
  vias: v3(126.59,125.12)
+3.3V_CPS: length 17.2
  TOP w0.127: LT11.2 38.05,108.22 v2(37.79,108.48)
  TOP w0.381: v1(42.52,100.34) 42.52,100.34 CT118.1
  TOP w0.508: LT11.2 38.1,107.09 CT117.1 38.08,106.12 37.49,106.12 v1(37.27,106.33)
  IN1 w0.508: v1(37.27,106.33) 37.27,106.05 38.45,104.87 38.45,100.87 38.98,100.34 42.52,100.34 v1(42.52,100.34)
  BOTTOM w0.254: UT9.52 37.53,106.08 v1(37.27,106.33) ; v1(42.52,100.34) 42.7,100.17 42.7,99.81 42.45,99.56 42.12,99.56 41.96,99.72 UT9.27
+3.3V_EC_PLL:
  vias: v2(249.31,89.33)
+3.3V_FPBTN: length 80.5
  TOP w0.254: RZ1392.2 280.27,119.53 CZ309.1 280.28,120.27 DT42.8 DT42.2 284.37,120.27 284.74,120.65 v1(284.74,120.75)
  TOP w0.508: QE20.2 255.95,114.58 v1(255.45,114.07) 255.29,113.92 v3(255.29,109.67) 255.75,109.22 RE709.1 RE708.2 RE707.2 RE706.2 ; RZ1392.2 v1(280.89,119.52) ; v1(274.61,119.61) QZ18.1 275.27,121.23 275.27,121.71 275.73,122.17 RZ1391.1 RZ1390.1
  IN1 w0.508: v1(280.89,119.52) 280.81,119.61 v1(274.61,119.61)
  IN2 w0.508: v1(284.74,120.75) 284.98,120.51 284.98,119.58 287.58,116.98 295.85,116.98 296.19,116.65 306.94,116.65 308.05,117.75 309.72,117.75 311.32,119.35 v1(312.33,119.35) ; v1(255.45,114.07) 258.82,117.45 265.77,117.45 266.34,116.88 270.44,116.88 273.17,119.61 v1(274.61,119.61)
  BOTTOM w0.305: v1(312.33,119.35) JFPBTN1.14
+3.3V_HDD: length 44.2
  TOP w0.508: v1(262.08,47.83) 258.5,47.83 257.61,46.94 v1(257.61,46.81) 257.42,47 256.74,47 RN18.1 256.6,47.9 255.85,48.65 v2(254.21,48.65) 253.16,48.65 v1(250.69,46.17) 251.4,45.47 251.4,44.24 250.55,43.39 250.55,43.38 250.19,43.03 250.19,43.03 249.38,42.22 249.38,42.16 248.79,41.57 248.79,41.41
  BOTTOM w0.254: UN7.20 253.55,49.59 253.3,49.84 CN17.1
  BOTTOM w0.356: CN17.1 252.62,52.04 252.29,51.71 249.91,51.71 249.55,51.36 249.55,50.68 249.87,50.37 RN12.1 RN20.1 250.43,49.6 249.61,48.79 249.61,47.06 250.5,46.17 v1(250.69,46.17) 250.73,46.17 250.87,46.31 251.33,46.31 RN16.1 RN10.2
  BOTTOM w0.508: CN16.1 259.2,45.41 258.06,46.56 ; RN6.1 RN8.2 v1(262.08,47.83) 262.29,48.03 262.29,49.75 261.93,50.11 RN14.1
  vias: v1(248.14,39.63) v1(248.72,39.63)
+3.3V_HDD_M2:
  vias: v1(264.98,23.57) v1(264.98,22.93) v1(265.62,23.57) v1(265.62,22.93) v1(266.25,23.57) v1(266.25,22.93) v1(277.36,22.36) v1(278,22.36) v1(278.63,22.36) v1(279.27,22.36) v1(279.9,22.36) v1(281.5,22.38) v1(282.09,22.38) v1(282.67,22.38) v3(272.13,22.95) v3(273.76,21.7) v3(275.83,21.7)
+3.3V_LAN: length 289.7
  TOP w0.381: CL19.1 291.38,112.23 v1(291.9,111.71)
  TOP w0.508: RC506.2 RC20.2 196.36,102.26 v1(196.49,102.39) ; v1(238.37,109.56) 238.37,113.36 238.98,113.97 238.98,116.22 239.26,116.51 242.08,116.51 242.61,115.98 248.54,115.98 249.83,117.27 261.37,117.27 v1(261.82,116.81) ; RL5.2 265.29,100.61 v1(265.62,100.28) 266.06,100.72 RL8.2 ; RL6.2 RL4.2 264.65,104.59 v1(264.63,104.58) ; RL70.2 v2(182.63,69.02) 184.31,67.35 193.26,67.35 198.69,72.78 v1(199.89,72.78) ; JLOM1.A1 303.92,111.12 301.45,113.6 295.04,113.6 293.15,111.71 v1(291.9,111.71) ; v1(289.5,112.91) 289.5,112.7 290.01,112.19 CL18.1 ; RL29.1 v1(284.62,112.91) ; v1(270.76,114.16) 270.29,113.69 RL1.2 269.92,113.55 268.09,113.55 RL2.2 ; v1(213.67,105.27) 213.05,104.64 213.05,102.57 211.95,101.48 211.95,98.25 206.31,92.6 206.31,91.67 205.56,90.92 205.56,87 209.37,83.19 209.37,75.47 v1(209.1,75.19)
  TOP w1.016: 274.7,96.02 270.82,96.02 270,96.85 268.66,96.85 268.03,97.48 268.03,99.76
  IN2 w0.508: v1(196.49,102.39) 196.49,103.92 198.56,105.99 199.32,105.99 200.16,105.15 201.75,105.15 202.18,104.72 204.27,104.72 204.47,104.53 205.1,104.53 205.75,105.18 213.58,105.18 v1(213.67,105.27) 223.9,105.27 224.78,104.38 228.06,104.38 233.78,110.09 237.83,110.09 238.36,109.56 v1(238.37,109.56) ; v1(287.52,109.24) 288.06,109.78 290.74,109.78 291.9,110.94 v1(291.9,111.71) 291.9,111.79 290.78,112.91 v1(289.5,112.91) ; v1(261.82,116.81) 265.27,116.81 268.47,113.61 270.21,113.61 v1(270.76,114.16)
  IN3 w0.254: JLOM1.B1 305.22,95.37 301.84,91.98 290.85,91.98 286.48,96.35 281.72,96.35 280.31,94.94 276.78,94.94 v1(276.07,95.65)
  IN3 w0.508: v1(264.63,104.58) 264.74,104.58 265.34,103.99 268.18,103.99 269.05,104.85 276.7,104.85 277.16,105.31 286.87,105.31 287.52,105.95 v1(287.52,109.24) ; v1(270.76,114.16) 271.79,115.19 277.69,115.19 278.29,114.59 280.32,114.59 282,112.91 v1(284.62,112.91) v1(289.5,112.91)
  BOTTOM w0.508: v1(209.1,75.19) 208.29,74.38 201.49,74.38 199.89,72.79 v1(199.89,72.78) ; v1(265.62,100.28) 265.62,102.28 264.81,103.09 264.81,104.41 v1(264.63,104.58)
+3.3V_LAN_OUT: length 20.3
  TOP w0.203: CL7.1 272.73,112.28 272.4,111.95 v2(272.4,111.8) 272.4,111.3 272.46,111.25 UL1.29 ; UL1.19 v1(275.78,107.84) ; UL1.15 275.65,106.24 275.78,106.12 v1(276.28,106.12)
  IN1 w0.508: v1(276.28,106.12) 276.53,106.37 276.53,107.09 v1(275.78,107.84) 276.64,108.71 276.64,110.4 274.89,112.15 v1(273.43,112.15)
  IN2 w0.508: v1(271.01,103.39) 272.09,103.39 272.98,104.28 274.7,104.28 276.28,105.86 v1(276.28,106.12)
+3.3V_LAN_UZ43: length 0.9
  TOP w0.127: 277.87,93.58 278.32,93.58 v2(278.65,93.91)
+3.3V_MMI_AUX: length 0.8
  TOP w0.127: 286.85,26.96 v2(286.04,26.96)
+3.3V_MMI_IN: length 12.7
  IN2 w1.27: 286.82,28.9 285.57,27.65 285.57,24.78 286.84,23.51 288.03,23.51 288.5,23.04 288.5,21.85 289.46,20.89 289.46,19.02
  vias: v1(288.41,29.92) v1(288.41,29.33) v1(289.48,17.94) v1(290.06,17.92) v2(289.94,19.99)
+3.3V_PDA_VOUT: length 2.6
  BOTTOM w0.076: UT5.H2 58.08,105.56 57.21,105.56 57.03,105.73
  BOTTOM w0.112: 57.03,105.73 57,105.77
  BOTTOM w0.254: CT83.1 56.68,106.08 57,105.77
+3.3V_RTC_LDO: length 213.7
  TOP w0.508: v1(262.72,63.46) 262.25,63.93 v2(258.08,63.93) 255.93,63.93 v1(255.64,64.21) ; PD3.3 237.15,119.48 234.97,117.3 234.97,115.47 234.37,114.87 234.37,109.16 v1(235.23,108.3) ; RA53.2 v1(296.48,53.22)
  IN1 w0.508: v1(277.62,71.39) 276.78,70.56 273.24,70.56 266.14,63.46 v1(262.72,63.46)
  IN2 w0.508: v1(277.62,71.39) 277.62,71.13 278.83,69.92 278.83,64.88 280.03,63.68 288.37,63.68 289.53,62.52 294.93,62.52 295.78,61.67 295.78,53.58 296.14,53.22 v1(296.48,53.22) ; v1(235.23,108.3) 235.23,108.3 235.23,100.68 232.86,98.32 232.86,82.42 234.37,80.91 234.37,80.49 236.6,78.27 237.88,78.27 244.56,71.59 249.11,71.59 251.04,69.66 251.04,68.89 255.64,64.29 v1(255.64,64.21) 255.64,62.21 259.37,58.47 259.37,54.11 257.59,52.32 257.59,47.95 258.25,47.3 258.25,46.58 257.59,45.92 257.59,45.21 255.03,42.65 253.76,42.65 251.96,40.85 251.96,38.2 250.55,36.79 246.59,36.79 244.7,38.68 241.09,38.68 239.96,37.55 232.49,37.55 231.96,37.02 225,37.02 224.28,37.74 223.55,37.74 221.96,39.33 216.36,39.33 216.31,39.38 v1(214.5,39.38)
  BOTTOM w0.508: v1(214.5,39.38) 213.61,40.27 208.97,40.27 208.19,39.48 207.19,39.48 206.69,38.98 PR105.2
+3.3V_RUN: length 642.8
  TOP w0.203: UV21.11 293.15,83.11 291.46,81.42 CV308.1 ; UV21.37 294.35,89.33 294.29,89.39 294.29,90.35 294.37,90.42 CV309.1
  TOP w0.381: QT10.2 v1(53.13,110.17) ; QT10.5 56.47,110.17 56.94,109.7 v1(57.26,109.7) ; RC849.2 RC841.2 190.98,78.42 191.53,77.86 191.76,77.86 v1(191.82,77.8)
  TOP w0.406: QC2.5 200.69,102.03 200.98,102.32 ; RC318.2 201.86,102.32 200.98,102.32 ; 200.98,102.32 199.77,103.53 199.77,107.2 199.07,107.9 197.86,107.9 v1(195.45,105.48) ; QC2.2 200.69,99.29 200.84,99.14 200.84,98.56 200.82,98.53 v1(200.82,98.43)
  TOP w0.457: RE547.2 265.39,96.21 265.58,96.02 v1(265.81,96.02)
  TOP w0.508: RZ1403.2 284.55,81.24 284.44,81.13 284.44,80.03 v1(284.18,79.77) ; RZ362.1 227.68,95.74 v1(227.86,95.93) ; RV98.1 118.72,119.58 118.35,119.95 ; CV308.1 291.21,80.92 291.19,80.91 291.02,80.91 v1(290.7,80.59) ; v1(251.18,76.42) 250.81,76.79 RE67.2 ; v1(223.52,44.04) 223.32,43.84 RD24.1 ; RV311.1 112.07,132.36 112.07,130.63 112.77,129.94 ; v1(292.9,91.32) 293.33,90.89 RV208.1 293.52,90.9 CV309.1 ; RV99.1 117.98,119.58 118.35,119.95 ; v1(221.24,95.12) 218.7,95.12 217.42,96.41 216.06,96.41 215.71,96.05 215.71,96.01 213.55,93.85 213.55,93.56 213.55,93.56 213.55,89.22 213.55,89.22 213.55,88.77 211.13,86.35 211.13,84.85 210.01,83.72 v1(210.01,79.32) ; RV734.1 RV207.1 v1(294.95,77.87) ; RZ1409.1 RZ89.1 v1(225.86,106.63) ; 112.77,129.94 112.39,129.56 112.39,125.89 114.69,123.6 v1(114.69,122.73) ; 112.77,129.94 113.79,129.94 v1(114.06,130.2) 114.54,130.2 115.63,131.29 RV326.1 115.84,131.82 116.8,132.78 RV732.2 ; 194.95,93.87 195.3,93.53 195.3,91.98 RC189.2 ; 194.95,93.87 195.96,94.87 195.96,97.86 195.88,97.94 RC749.2 195.99,99.08 v1(197.29,99.08) ; 194.95,93.87 193.54,93.87 192.65,94.75 RC362.2 RC363.2 ; v1(182.6,118.95) 182.6,119.31 183.26,119.96 187.45,119.96 189.66,122.17 v1(191.07,122.17) RZ1422.2 ; RC731.1 146.8,116.22 145.09,117.93 145.09,118.94 144.41,119.62 v1(144.37,119.62) ; RD19.2 118.75,77.22 116.97,75.44 116.97,72.39 113.42,68.83 99.81,68.83 93.7,74.94 86.42,74.94 84.3,72.82 79.08,72.82 78,71.74 73.64,71.74 71.12,74.26 v1(71.12,79.26) ; RN4.1 246.6,34.78 246.24,34.42 246.24,31.29 247.21,30.33 249.99,30.33 250.44,30.77 v1(250.44,31.06) ; RD26.1 247.84,46.3 v1(247.45,45.92) 247.07,45.53 247.02,45.53 246.96,45.48 RD20.1 RD22.1 ; 118.35,119.95 118.29,120 v1(118.29,121.2) ; RV304.1 RV300.1 v1(292.29,78.61) ; RC345.1 200.22,94.69 201.24,95.7 v1(201.24,96.28) ; v1(208,79.39) 208,78.99 207.49,78.48 RC522.2 RC523.2 RC51.2 RC525.2 200.19,78.5 RC278.2 RC292.2 RC279.2 RC58.2 RC747.2 195.92,78.53 RC567.2 195.13,78.14 195.64,77.63 v1(195.66,77.63) ; RC318.2 203.55,101.7 204.53,100.72 204.53,99.97 203.59,99.97 202.69,99.08 RC319.2 202.47,99.03 203.07,98.44 v1(203.07,98.43) ; v1(31.55,114.18) v2(31.55,111.67) RT397.1 ; RV8.2 141.52,126.63 v1(141.53,126.63) 141.52,126.63 141.52,125.65 142.08,125.09 QV20.3 ; v1(300.35,81.48) RV736.2 ; RZ1391.2 v1(274.19,122.98) ; RD10.1 166.24,49.73 167,48.97 167.95,48.97 168.4,48.52 168.4,45.86 167.44,44.9 v1(167.44,42.82) 167.05,42.43 158.28,42.43 155.37,45.34 154.61,45.34 154.16,44.89 148.53,44.89 146.98,46.45 RD8.1
  IN1 w0.508: v1(240.09,44.18) 239.48,43.57 233.6,43.57 232.88,42.86 227.47,42.86 225.55,44.78 224.59,44.78 223.85,44.04 v1(223.52,44.04) ; v1(84.3,101.5) 84.3,101.65 86.41,103.76 86.41,105.14 88.9,107.64 88.9,109.6 93.81,114.5 94.78,114.5 97.32,117.04 97.32,117.78 97.83,118.29 98.53,118.29 99.82,119.58 v1(100.46,119.58)
  IN1 w0.762: v1(297.75,83.84) 297.24,83.34 297.24,81.9 297.59,81.54 297.59,79.55 v1(297.18,79.13) 295.92,77.87 v1(294.95,77.87) 293.84,77.87 293.1,78.61 v1(292.29,78.61)
  IN2 w0.508: v1(71.12,79.26) 71.12,76.21 73.08,74.24 73.08,67.38 76.94,63.52 v1(76.94,57.38) ; v1(191.82,77.8) 191.82,78.31 192.33,78.81 194.48,78.81 v1(195.66,77.63) ; v1(251.18,76.42) 253.02,76.42 258.8,70.65 258.8,66.22 259.2,65.82 259.2,64.72 v1(262.65,61.26) ; v1(203.07,98.43) 206.91,98.43 208.35,99.87 214.4,99.87 219.15,95.12 v1(221.24,95.12) ; v1(118.29,121.2) 116.77,122.73 v1(114.69,122.73) ; v1(31.55,114.18) 49.5,114.18 53.13,110.55 v1(53.13,110.17) ; v1(191.07,122.17) 191.07,119.34 189.48,117.75 189.48,116.72 188.97,116.22 188.65,116.22 v1(188.64,116.2) 188.64,115.59 189.18,115.05 194.22,115.05 196.08,113.18 196.08,110.16 195.63,109.7 195.63,105.67 v1(195.45,105.48)
  IN3 w0.508: v1(76.94,57.38) 77.67,56.65 77.67,55.87 v1(76.96,55.15) ; v1(228.49,37.64) 227.54,37.64 227.15,37.25 222.46,37.25 221.36,38.34 214.78,38.34 214.43,37.98 208.97,37.98 208.49,38.47 204.59,38.47 204.08,37.96 204.08,36.33 203.58,35.82 196.65,35.82 195.25,34.41 187.57,34.41 v1(185.24,36.75) 173.41,36.75 167.44,42.72 v1(167.44,42.82) ; v1(252.01,44.67) 252.01,45.18 251.64,45.54 250.12,45.54 249.55,46.11 247.65,46.11 v1(247.45,45.92) 247.08,45.54 245.9,45.54 245.49,45.96 244.77,45.96 244.26,45.45 244.26,44.97 242.84,43.55 240.72,43.55 v1(240.09,44.18) ; v1(71.12,79.26) 68.58,81.8 68.58,85.44 70.78,87.64 78.95,87.64 83.18,91.87 83.18,94.63 83.74,95.19 83.74,96.14 83.32,96.56 83.32,99.35 83.69,99.72 83.69,100.99 84.2,101.5 v1(84.3,101.5) ; v1(53.13,110.17) 56.79,110.17 v1(57.26,109.7) ; v1(200.82,98.43) v1(203.07,98.43)
  BOTTOM w0.381: v1(84.3,101.5) 84.21,101.5 84.03,101.32 84.03,100.17 84.64,99.57 84.64,99.01 84.89,98.75 PR612.1
  BOTTOM w0.508: v1(297.75,83.84) 297.62,83.97 RV302.1 ; v1(300.35,81.48) 299.72,80.85 298.13,80.85 297.62,80.34 297.62,79.58 v1(297.18,79.13) ; v1(76.94,57.38) RE48.1 ; v1(259.95,52.33) RN226.1 ; v1(182.6,118.95) 182.55,118.95 182.54,118.95 181.16,118.95 180.65,118.44 180.65,117.5 180.58,117.43 180.58,117.28 180.57,117.27 180.57,116.65 179.38,115.47 RC502.2 RC176.2 ; v1(228.49,37.64) 228.74,37.4 229.66,37.4 231.2,35.86 231.2,33.16 230.9,32.86 230.9,31.98 232.32,30.56 249.94,30.56 v1(250.44,31.06) ; RD4.1 RD6.1 v1(167.44,42.82) ; v1(210.01,79.32) 208.06,79.32 v1(208,79.39) ; RE51.1 74.49,54.8 74.85,55.15 v1(76.96,55.15) ; v1(201.24,96.28) 201.24,98.01 v1(200.82,98.43) 199.54,99.71 197.63,99.71 197.29,99.36 v1(197.29,99.08) ; v1(141.53,126.63) 141.53,125.71 142.81,124.43 142.81,121.18 v1(144.37,119.62) ; RC137.2 v1(89.73,129.75)
  vias: v1(132.11,129.99) v1(132.13,129.37) v1(223.83,93.42) v1(223.83,92.78) v1(223.83,92.15) v1(223.83,91.51) v1(224.47,93.42) v1(224.47,92.78) v1(224.47,92.15) v1(224.47,91.51) v1(225.1,93.42) v1(225.1,92.78) v1(225.1,92.15) v1(225.1,91.51) v1(227.68,84.3) v1(227.95,83.78) v1(262.29,46.4) v1(262.68,45.96) v1(266.45,41.03) v1(266.45,40.45) v1(266.46,39.84) v1(267.04,41.03) v1(267.04,40.45) v1(267.04,39.83) v1(268.92,60.02) v1(268.92,59.38) v1(278.73,96.52) v1(279.14,96.1)
+3.3V_RUN_AUDIO: length 73.4
  TOP w0.508: LA12.2 v1(289.05,46.81) ; v1(295.79,52.14) RA59.1 ; CA67.1 267.76,54.77 268.8,53.73 v3(270.54,53.73) v1(272.35,53.73) ; LA14.2 281,46.88 RA18.2 281.35,45.57 v1(282.13,45.57)
  IN1 w0.508: v1(295.79,52.14) 295.79,54.86 295.72,54.94 295.72,62.18 294.56,63.33 292.04,63.33 290.28,65.1 285.2,65.1 283.55,63.44 278.64,63.44 276.75,61.56 276.75,56.94 276.89,56.81 276.89,53.89 275.93,52.93 275.93,52.89 v1(274.94,51.9)
  IN2 w0.508: v1(282.13,45.57) 282.79,45.57 283.27,46.05 288.29,46.05 v1(289.05,46.81)
  IN3 w0.508: v1(272.35,53.73) 273.97,53.73 274.48,53.22 274.48,52.35 v1(274.94,51.9) 275.72,51.11 275.72,48.82 278.97,45.57 v1(282.13,45.57)
+3.3V_RUN_AUDIO_DVDD:
  vias: v2(282.79,49.76)
+3.3V_RUN_AUDIO_IO:
  vias: v2(287.05,49.76)
+3.3V_RUN_AUDIO_UZ5: length 0.7
  BOTTOM w0.127: v1(268.79,57.53) v2(268.11,57.53)
+3.3V_RUN_CARD: length 11.3
  TOP w0.127: v1(299.97,19.19) 299.97,19.07 v2(299.27,18.37)
  BOTTOM w1.016: 289.56,19.82 289.56,19.63 290.29,18.89 293.28,18.89 294.1,18.08 298.92,18.08
  vias: v1(290.46,20.53) v1(290.46,19.95) v1(300.6,19.19)
+3.3V_RUN_DIMM1: length 2
  TOP w0.127: 167.1,55.87 v2(167.78,55.87)
  BOTTOM w0.305: v1(166.75,56.3) 166.95,56.09 JDIMM1.255
+3.3V_RUN_DIMM2: length 5.3
  TOP w0.127: v2(249.21,49.11) 248.61,49.11 248.31,49.41 RD26.2
  BOTTOM w0.305: JDIMM2.255 244.35,49.85 244.57,49.64 v1(246.95,49.64)
+3.3V_RUN_F:
  vias: v3(132.08,126.15)
+3.3V_RUN_QZ1:
  vias: v1(129.5,129.86) v1(130.08,129.86) v3(129.61,128.8)
+3.3V_RUN_UT9: length 12.5
  TOP w0.508: 32.95,109.93 RT398.2 v1(33.97,110.73) ; v1(47.05,109.36) RT137.2 ; v1(46.99,111.83) RT135.2 ; RT131.2 39.19,96.71 38.68,96.2 v1(38.68,95.95) ; v1(34.48,108.23) v2(35.57,107.13) LT11.1
  BOTTOM w0.508: RT304.2 RT305.2 v1(42.35,96.02) ; v1(34.48,105.74) RT139.2 RT141.2 ; v1(34.48,102.69) RT246.1 ; v1(34.48,98.96) RT308.2 ; v1(34.48,108.23) RT303.1
+3.3V_RUN_UZ44:
  vias: v2(220.1,87.4)
+3.3V_SPI: length 60.6
  TOP w0.508: v1(205.74,103.52) 205.74,101.95 206.41,101.28 v3(206.41,100.34) 206.41,97.42 201.71,92.72 v1(201.71,91.16) 201.71,84.37 201.1,83.77 v1(201.1,83.39)
  IN2 w0.508: v1(201.1,83.39) 201.1,83.54 201.13,83.56 201.13,83.64 201.48,84 205.16,84 205.67,83.49 v1(205.67,83)
  IN3 w0.508: v1(201.71,91.16) 201.71,91.13 200.98,90.41 196.93,90.41 194.41,90.41 190.71,90.41 187.88,87.58 185.73,87.58 184.41,88.9 184.41,89.53 183.57,90.37 183.57,92.02 181.57,94.03 181.57,94.5
  BOTTOM w0.305: v1(201.1,83.39) 201.1,83.52 201.58,84 JSPI1.15
  BOTTOM w0.508: 205.54,93.93 204.47,93.93 v1(201.71,91.16)
+3.3V_SSD:
  vias: v2(257.34,34.17)
+3.3V_TBTA_FLASH: length 108.5
  TOP w0.254: RT76.2 57.14,107.86 55.32,107.86 54.78,108.39 53.37,108.39 v1(53.17,108.19) 53.17,107.74 53.38,107.54 54.18,107.54 54.41,107.31 RT106.2 54.13,106.27 54.03,106.37 54.03,106.37 53.87,106.53 53.11,106.53 52.83,106.25 52.83,104.76 53.28,104.3 55.52,104.3 v1(55.74,104.52)
  TOP w0.508: RT67.2 58.49,97.05 v1(58.22,96.78) ; v1(56.07,99.64) 56.48,100.05 v2(57.5,100.05) 58.55,100.05 58.99,100.49 58.99,102.11 RT107.2 RT378.2 RT379.2 ; v1(55.3,114.63) 56.18,115.5 RT399.1 ; v1(62.54,93.47) RT66.2 ; v1(51.81,90.37) v1(51.81,88.85)
  IN2 w0.508: v1(51.81,90.37) 55.81,90.37 58.22,92.78 ; 58.22,92.78 v1(58.22,96.78) 58.22,97.48 v1(56.07,99.64) 54.94,100.77 54.94,103.71 v1(55.74,104.52) ; 58.22,92.78 58.97,92.78 59.66,93.47 v1(62.54,93.47) ; v1(51.81,88.85) 49.33,88.85 48.06,90.12 37.45,90.12 v1(36.94,89.61)
  IN3 w0.508: v1(55.3,114.63) 52,111.33 52,109.36 v1(53.17,108.19) ; v1(62.54,93.47) 63.76,94.69 66.33,94.69 68.94,97.31 68.94,105.14 68.45,105.64 v1(67.93,105.64)
  BOTTOM w0.203: CT84.1 54.66,104.52 v1(55.74,104.52) 55.97,104.75 57.23,104.75 57.28,104.81 UT5.G1
  BOTTOM w0.254: v1(53.17,108.19) RT95.2
  BOTTOM w0.305: RT50.1 35.49,88.85 34.92,88.27 33.53,88.27 33.31,88.49 JDB1.1
  BOTTOM w0.508: UT6.8 39.56,90.12 39.1,89.66 CT70.1 36.99,89.66 v1(36.94,89.61) RT50.1 ; RT53.1 RT52.1 v1(51.81,88.85) ; RT98.2 67.42,105.64 v1(67.93,105.64) ; RT51.1 v1(51.81,90.37)
+3.3V_TP: length 12
  TOP w0.127: v1(195.02,38.55) v2(195.02,37.75)
  TOP w0.508: RZ19.1 v1(191.07,36.19) ; v1(193.75,40.32) 193.28,40.79 RZ117.1 RZ116.1 ; RZ18.1 193.35,36.17 v1(193.33,36.19)
  BOTTOM w0.305: JKBTP1.12 188.99,39.22 188.91,39.14 v1(188.91,37.86)
  BOTTOM w0.508: RZ21.1 RZ20.1 199.53,39.06 199.02,38.55 v1(195.02,38.55)
+3.3V_VDD_DCI: length 5.1
  BOTTOM w0.107: UT9.49 37.61,105.03 37.42,105.22 37.42,105.55 36.76,106.21 36.76,106.59 CT119.1 36.04,107.31 RT303.2 34.58,107.31 v2(34.41,107.48)
+3.3V_VDD_DCIN: length 165
  TOP w0.508: PC12.1 68.84,115.72 v1(68.4,115.28) ; v1(88.03,118.45) 88.32,118.15 PR17.1 ; PR47.1 77.67,117.05 v1(77.47,116.85) ; v1(68.72,39.4) PD3000.2 ; v1(58.48,85.42) v2(57.59,86.31) 55.3,86.31 53.65,87.96 53.65,88.62 v1(53.41,88.86)
  IN2 w0.508: v1(72.33,43.68) 73.82,45.17 73.82,63.67 69.62,73.42 61.69,81.35 59.82,81.35 58.48,82.69 v1(58.48,85.42) 58.48,86.5 57.78,87.2 57.78,91.07 58.4,91.68 59.11,91.68 59.62,91.18 59.62,87.7 61.53,85.8 63.56,85.8 65.46,87.7 65.46,101.17 68.73,104.43 68.73,106.4 67.21,107.92 67.21,114.09 v1(68.4,115.28)
  IN3 w0.508: v1(68.4,115.28) 68.4,117.26 71.27,120.13 74.99,120.13 77.47,117.65 v1(77.47,116.85) 79.71,116.85 80.79,117.93 87.75,117.93 88.03,118.21 v1(88.03,118.45) ; v1(71.9,33.73) 70,33.73 68.72,35.01 v1(68.72,39.4) 68.72,40.7 71.49,43.48 v1(72.33,43.68)
  BOTTOM w0.254: v1(58.48,85.42) 58.48,88.39 PR832.1 ; PR33.1 89.42,118.32 89.58,118.49 89.58,119.16 89.31,119.43 89.31,120.98 89.57,121.23 90.17,121.23 90.38,121.45 PR27.2
  BOTTOM w0.508: v1(53.41,88.86) 53.41,88.61 53.2,88.39 PR809.1 ; v1(88.03,118.45) 88.27,118.21 89.33,118.21 PR33.1 ; PD800.3 59.12,82.77 PR866.1 58.35,82.93 PR806.1 57.56,84.16 58.48,85.08 v1(58.48,85.42)
+3.3V_VDD_PIC: length 181.4
  TOP w0.406: v1(56.48,96.78) v3(57.37,97.67) 60.49,97.67 60.89,97.27 QT1.5 QT1.2
  TOP w0.508: v1(88.58,78.5) 89.4,77.67 91.17,77.67 91.68,78.18 PR810.1 ; RT420.2 55.35,116.65 55.26,116.56 RT399.2 55.26,115.49 v1(55.23,115.45) ; PR813.1 90.55,115.26 v1(90.88,114.93)
  IN1 w0.508: v1(56.57,92.48) 57.91,91.15 66.01,91.15 86,111.14 88.18,111.14 91,113.96 91,114.81 v1(90.88,114.93)
  IN2 w0.508: v1(88.58,78.5) 88.58,83.39 84.37,87.59 76.5,87.59 ; 76.5,87.59 76.5,86.4 70.32,80.21 64.22,80.21 62.44,81.99 v1(60.51,81.99) ; 76.5,87.59 75.79,87.59 73.95,89.43 73.95,93.39 74.25,93.69 75.5,94.94 77.7,94.94 78.35,95.59 v1(78.35,95.96) 78.35,105.8 81.38,108.82 82.47,108.82 83,108.29 83,106.08 83.51,105.57 84.51,105.57 ; v1(90.88,114.93) 90.98,114.83 90.98,113.97 88.15,111.14 88.15,107.46 86.27,105.57 84.51,105.57 ; 84.51,105.57 84.51,103.9 v1(84.26,103.64) ; v1(55.23,115.45) 54.02,114.24 54.02,111.71 54.64,111.08 54.64,106.8 54.02,106.17 54.02,99.25 v1(56.48,96.78) 56.48,92.57 v1(56.57,92.48)
  BOTTOM w0.508: v1(60.51,81.99) 59.99,81.47 PD800.2 ; RT482.1 54.03,99.23 v1(56.48,96.78) ; PR822.1 81.21,96.21 80.32,95.32 78.99,95.32 v1(78.35,95.96) ; PR859.1 84.51,103.39 v1(84.26,103.64)
+3.3V_VDD_PIC_PDA: length 15.1
  IN2 w0.508: v1(55.87,101.15) 55.88,101.15 55.89,101.17 56.7,101.17 57.6,102.06 57.6,104.38 v1(56.64,105.34)
  BOTTOM w0.107: v2(52.73,98.52) 52.64,98.61 52.64,100.37 52.81,100.54 RT483.2
  BOTTOM w0.203: UT5.B1 57.65,102.31 57.27,101.92 57.27,101.61 56.87,101.21 55.93,101.21 55.88,101.15 v1(55.87,101.15) ; v1(56.64,105.34) 56.76,105.34 56.8,105.31 UT5.H1
  BOTTOM w0.508: RT483.2 RT482.2 54.74,100.54 54.77,100.57 CT74.1 55.37,100.65 55.87,101.15 v1(55.87,101.15)
+3.3V_VDD_PIC_R: length 1.1
  TOP w0.127: CT92.1 v2(57.04,114.99)
+3.3V_VPS_UZ12: length 8.6
  BOTTOM w0.508: v1(221.32,99.45) 221.15,99.45 220.15,100.45 v2(220.15,101.76) 220.15,103.45 221.36,104.66 v1(223.64,104.66)
+3.3V_WLAN: length 19.5
  TOP w2.032: 274.8,41.58 277.36,41.58 278.8,40.14 285.46,40.14
  TOP w2.54: 264.99,53.93 270.8,48.13
  vias: v1(271.84,41.98) v1(271.9,41.35) v1(272.41,42.3) v1(272.41,41.67) v1(272.41,40.97) v1(288.98,39.82) v1(289.62,39.82) v1(290.25,39.82) v1(290.89,39.82) v3(271.89,45.92) v3(271.98,43.66) v3(273.6,42.67)
+3.3V_WLAN_UZ47:
  vias: v2(264.18,66.2)
+3.3V_WWAN: length 2.6
  TOP w0.508: 276.28,82.18 275.84,81.73 RZ1400.2
  vias: v1(258.76,83.77) v1(258.76,83.18) v1(259.34,83.77) v1(259.34,83.18) v1(259.93,83.77) v1(259.93,83.18) v1(276.98,83.26) v1(277.63,80.85) v1(277.68,83.26) v1(278.25,81.12) v1(278.44,82.5) v1(278.44,81.86) v3(275.73,83.42) v3(277.52,82.08) v3(277.83,83.82)
+3.3V_WWAN_UZ43: length 2.2
  TOP w0.127: 275.9,88.03 v2(273.71,88.03)
+5V_ALW: length 381.7
  TOP w0.203: UZ47.4 268.41,68.72 ; UZ5.4 270.7,60.27 v1(270.57,60.4) ; UZ3.4 226.88,85.1 226.95,85.17 227.62,85.17 v1(227.74,85.29) ; v1(281.81,92.53) 281.55,92.53 280.54,91.51 UZ43.4
  TOP w0.254: UZ53.4 255.72,37.73 255.34,37.35 v1(255.27,37.35) ; UI3.7 290.51,69.29 v1(290.26,69.04) 290.51,68.79 UI3.8
  TOP w0.508: RI13.2 290.81,72.83 291.14,73.16 v1(291.33,73.16) ; 171.83,63.51 230.37,63.51 231.39,62.49 234.88,62.49 236.53,64.15 v1(236.53,66.62) ; DT1.2 63.43,123.9 65.27,125.74 v1(68.45,125.74) ; v1(312.85,121.75) LED3.2 ; PR7.1 80.07,124.04 v1(80.07,123.18)
  TOP w1.524: 99.53,76.08 88.96,76.08 87.43,77.61 87.43,83.13 85.4,85.16 77.21,85.16 75.81,83.77
  IN1 w0.508: v1(102.27,100.16) 99.23,100.16 98.17,101.23 94.52,101.23 v1(93.7,102.05) ; v1(225.42,77.73) 225.42,78.56 222.94,81.04 222.94,82.39 224.14,83.59 225.34,83.59 226.88,85.13 227.58,85.13 v1(227.74,85.29)
  IN2 w0.508: v1(281.81,92.53) 281.22,93.11 281.22,113.65 282.84,115.26 287.87,115.26 289.58,113.55 295.21,113.55 297.3,115.64 307.41,115.64 307.77,115.28 312.04,115.28 313.67,116.91 313.67,119.33 312.85,120.15 v1(312.85,121.75) ; v1(225.42,77.73) 225.71,77.44 228.93,77.44 231.41,74.96 231.41,70.9 235.69,66.62 v1(236.53,66.62) ; v1(68.45,125.74) 69.21,124.98 69.21,114.82 67.85,113.46 67.85,108.18 69.37,106.66 69.37,99.31 v1(67.44,97.38)
  IN2 w1.016: 105.37,83.39 103.68,81.7 101.35,81.7 100.76,81.1 100.76,78.99 ; 102.55,99.27 102.55,97.37 101.33,96.15 101.33,87.97 ; 101.86,86.12 102.76,85.21 104.36,85.21 ; 104.17,99.41 106.1,99.41 107.79,97.72 113.81,97.72 114.97,96.57 116.18,96.57
  IN3 w0.508: v1(285.69,73.06) 285.52,73.23 285.52,82.76 287.5,84.73 287.5,89.75 287.14,90.1 287.14,91.58 286.19,92.53 v1(281.81,92.53) ; v1(85.28,90.62) 85.91,90.62 86.8,91.51 90.36,91.51 90.99,92.15 90.99,93.93 92.07,95.01 92.07,100.43 v1(93.7,102.05)
  IN3 w1.016: 235.07,114.39 235.07,114.39 233.22,114.39 224.15,123.46 224.15,125.11
  BOTTOM w0.305: JLED1.6 306.57,9.72 v1(306.45,9.6)
  BOTTOM w0.508: v1(85.28,90.62) 85.66,91.01 PR634.2 PR615.2 ; v1(68.45,125.74) 69.21,126.5 77.04,126.5 80.07,123.47 v1(80.07,123.18) ; PR602.2 v1(93.7,102.05)
  BOTTOM w1.016: 205.86,126.99 203.47,126.99 202.69,127.77 197.29,127.77 ; 222.69,126.18 215.9,126.18 214.81,127.26 211.74,127.26
  vias: v1(24.66,85.79) v1(25.29,85.79) v1(25.72,86.33) v1(25.93,85.79) v1(66.17,97.38) v1(66.17,96.75) v1(66.8,97.38) v1(66.8,96.75) v1(67.44,96.75) v1(71.86,80.85) v1(72.45,81.48) v1(72.45,80.85) v1(72.45,80.21) v1(73.08,82.12) v1(73.08,81.48) v1(73.08,80.85) v1(73.08,80.21) v1(73.72,82.75) v1(73.72,82.12) v1(73.72,81.48) v1(73.72,80.85) v1(74.35,82.75) v1(74.35,82.12) v1(74.35,81.48) v1(74.99,82.75) v1(74.99,82.12) v1(100.69,77.67) v1(100.69,77.04) v1(100.99,87.15) v1(101.62,87.15) v1(102.88,100.16) v1(105.19,84.36) v1(105.39,105.86) v1(105.43,105.26) v1(105.53,84.85) v1(117.06,95.96) v1(117.1,96.56) v1(119.35,100.91) v1(119.5,100.34) v1(182.9,134.19) v1(183.51,134.19) v1(191.32,127.65) v1(191.96,127.65) v1(195.43,127.62) v1(196.06,127.61) v1(223.88,126.35) v1(224.49,126.35) v1(228.53,38.94) v1(228.53,38.35) v1(236.06,114.16) v1(236.67,114.16) v1(237.14,66.62) v1(243.85,35.51) v1(244.06,36.05) v1(244.43,35.51) v1(244.65,36.05) v1(245.02,35.51) v1(245.23,36.05) v1(246.95,39.6) v1(247.53,39.6) v1(273.36,67.57) v1(273.36,66.94) v1(273.36,66.3) v1(273.36,65.67) v1(273.95,67.57) v1(273.95,66.94) v1(273.95,66.3) v1(273.95,65.67) v1(293.43,72.59) v1(293.43,71.96) v1(293.68,73.23) v1(293.68,65.35) v1(293.68,64.77) v1(294.06,72.59) v1(294.06,71.96) v1(294.27,65.35) v1(294.28,64.77) v1(297.18,56.97) v1(297.49,57.48) v1(297.81,56.97) v1(298.13,57.48) v3(99.65,77.33) v3(238.44,66.6) v3(240,67.92)
+5V_ALW2: length 1.5
  BOTTOM w0.254: PU102.15 77.09,72.86 v1(76.97,72.97) 76.84,73.1 PC126.1
+5V_ALW_PDA: length 4.8
  IN1 w0.508: v1(63.3,102.12) 63.3,104.3 v1(61.91,105.7)
  BOTTOM w0.203: v1(61.91,105.7) 61.91,105.66 62.26,105.31 UT5.H10
  vias: v1(64.82,102.72) v1(64.82,102.02) v2(64.89,99.49)
+5V_ALWP: length 14
  TOP w0.127: PC137.1 v2(72.58,78.06)
  IN3 w0.254: v1(75.29,72.41) 75.29,76.67 v1(74.8,77.16)
  IN3 w0.508: v1(76.33,72.41) 75.9,72.83 75.9,76.55 v1(76.51,77.16)
  BOTTOM w0.254: PU102.14 v1(76.33,72.41) ; PR117.2 v1(75.29,72.41)
  vias: v1(73.72,77.16) v1(77.53,77.16)
+5V_HDD: length 0.8
  TOP w0.508: RN1.1 253.06,36.72 252.74,37.04 v1(252.74,37.28)
  vias: v1(241.17,33.04) v1(241.17,32.46) v1(241.75,33.04) v1(241.75,32.46) v1(242.34,33.04) v1(242.34,32.46) v2(240.84,30.83)
+5V_HDD_UZ23:
  vias: v2(241.83,35.51)
+5V_PD_VDD: length 1.5
  TOP w0.127: DT1.1 v2(58.49,123.9)
+5V_RUN: length 458.4
  TOP w0.356: CZ92.1 185.1,38.94 184.98,38.82 v1(184.98,38.72)
  TOP w0.508: RV733.2 116.8,134.84 116.78,134.87 116.78,135.07 RV6.2 116.23,135.23 115.88,134.88 114.1,134.88 113.48,134.27 113.48,133.74 112.97,133.23 v1(112.77,133.23)
  IN1 w0.508: v1(101.47,120.53) 101.15,120.85 99.36,120.85 98.02,119.51 96.95,119.51 95.23,117.79 90.56,117.79 89.85,118.5 89.85,119.14 89.34,119.64 88.01,119.64 86.74,118.37 78.1,118.37 76.2,116.47 76.2,113.98 75.55,113.33 71.64,113.33 69.46,111.16 69.46,101.84 v1(70.52,100.78)
  IN1 w0.762: 259.2,34.05 259.2,31.63 v1(260.28,30.55)
  IN1 w2.032: 272.5,58.07 269.52,55.1 269.52,48.55 271.08,46.99 271.08,43.17 269.66,41.75 269.66,40.33 267.57,38.24 265.36,38.24 261.87,34.74 260.73,34.74
  IN2 w0.508: v1(101.47,120.53) 101.47,121.79 103.54,123.87 110.5,123.87 113.06,126.43 v1(114.47,126.43)
  IN2 w0.762: v1(184.98,38.72) 184.98,38.21 186.11,37.08 186.11,34.92 186.81,34.22 193.03,34.22 196.93,38.12 197.92,38.12 199.7,39.9 204.12,39.9 204.39,40.17 216.6,40.17 216.68,40.09 224.79,40.09 225.61,39.27 225.61,38.13 v1(225.39,37.91)
  IN3 w0.508: v1(184.98,38.72) 184.98,39.78 183.86,40.89 175.82,40.89 172.97,43.74 161.58,43.74 151.8,33.96 133.52,33.96 129.24,29.68 96.92,29.68 89.21,37.39 83.88,37.39 82.9,38.36 80.26,38.36 75.37,43.25 75.37,48.97 76.26,49.86 76.26,53.44 v1(76.96,54.14) 78.42,55.6 78.42,61.96 76.74,63.64 76.74,66.9 76.09,67.55 75.14,67.55 65.26,77.43 65.26,87.4 63.46,89.2 63.46,90.33 70.52,97.39 v1(70.52,100.78) ; v1(299.14,83.07) 299.14,82.62 298.51,81.99 297.56,81.99 294.95,79.39 289.3,79.39 287.4,77.48 287.4,73.8 285.94,72.34 276.73,72.34 275.57,71.18 275.57,65.86 273.62,63.9 v1(273.62,62.18)
  BOTTOM w0.305: JKBTP1.5 185.49,39.22 185.09,38.82 185.08,38.82 v1(184.98,38.72)
  BOTTOM w0.406: CV653.1 297.81,82.27 UV2.1
  BOTTOM w0.508: 83.35,56.78 81.71,58.42 81.71,62.09 80.87,62.92 JFAN1.4 ; v1(76.96,54.14) 78.23,55.41 83.36,55.41 ; UV2.1 299.14,82.58 v1(299.14,83.07) ; v1(114.47,126.43) 112.56,128.34 112.56,131.75 112.77,131.96 v1(112.77,133.23)
  BOTTOM w0.762: v1(225.39,37.91) 225.39,37.41 226.21,36.59 229.19,36.59 229.8,35.98 229.8,33.94 230.14,33.61 230.14,31.67 232.01,29.8 250.89,29.8 251.39,30.3 256.29,30.3 256.42,30.39 257.22,30.72 258.06,30.89 258.66,30.9 258.93,30.9 259.78,30.73 260.22,30.55 v1(260.28,30.55)
  vias: v1(259.36,36.55) v1(259.36,35.97) v1(259.36,35.39) v1(259.36,34.75) v1(273.62,61.54) v1(273.62,60.91) v1(273.62,60.27) v2(271.66,61.14)
+5V_RUN_AUDIO: length 21.5
  TOP w0.127: v1(290.06,63.13) v3(290.06,63.94)
  TOP w0.508: LA5.2 v1(290.06,63.13)
  IN3 w0.508: v1(276.09,59.13) 276.88,59.92 276.88,61.5 278.82,63.44 284.35,63.44 285.5,64.59 286.63,64.59 287.14,65.1 290.25,65.1 290.76,64.59 290.76,63.83 v1(290.06,63.13)
+5V_RUN_PVDD_L:
  vias: v2(277.21,51.99)
+5V_RUN_UZ47:
  vias: v2(270.95,66.18)
+5V_TBT_VBUS: length 1
  TOP w0.127: CT93.1 63.56,121.14 v2(63.53,121.12)
+5V_TBTA_VBUS_D: length 4.1
  TOP w0.508: DT3.2 62.35,119.14 62.67,118.82 v2(62.67,118.17) UT8.3
+5V_USB_CHG_PWR:
  vias: v1(293.56,67.19) v1(293.87,67.7) v1(294.19,67.19) v1(294.51,67.7) v1(294.83,67.19) v2(300.2,62.1)
+13.2VB_BATT: length 54.6
  TOP w0.127: 132.71,40.03 v2(132.71,41.06)
  TOP w0.508: 131.57,40.02 131.17,40.41 v1(130.77,40.41)
  BOTTOM w0.254: v1(130.77,40.41) 130.68,40.51 130.68,42.46 129.12,44.02 102.2,44.02 100.86,45.35 99.91,45.35 92.99,52.27 91.44,52.27 89.91,53.79 86.16,53.79 85.98,53.61 PR738.2
+13.2VB_PBATT_C: length 1.3
  TOP w0.127: v3(143.58,37.4) 142.25,37.4
  vias: v1(139.76,39.25) v1(139.76,38.67) v1(139.76,38.09) v1(139.76,37.5) v1(139.76,36.9) v1(139.76,36.32) v1(140.34,39.25) v1(140.34,38.67) v1(140.34,38.09) v1(140.34,37.5) v1(140.34,36.9) v1(140.34,36.32) v1(140.93,39.25) v1(140.93,38.67) v1(140.93,38.09) v1(140.93,37.5) v1(140.93,36.9) v1(140.93,36.32) v1(141.51,39.25) v1(141.51,38.67) v1(141.51,38.09) v1(141.51,37.5) v1(141.51,36.9) v1(141.51,36.32) v3(142.16,36.43) v3(142.2,38.42)
+13.5VB: length 372.2
  TOP w0.508: 85.31,58.21 84.89,57.8 82.08,57.8 80.96,56.68 PD702.2 ; 93.47,50.05 93.47,49.92 v1(92.26,48.71) ; PD3000.3 67.1,38.14 v1(67.1,37.28) PR3006.1
  TOP w1.016: 94.59,120.57 94.57,120.58 94.57,127.07 94.9,127.4 94.9,128.78
  TOP w2.54: 119.58,43.06 101.66,43.06 98.74,45.98 97.53,45.98 85.31,58.21 85.31,69.32 85.66,69.67 ; 232.9,122.41 231.59,121.1 231.59,119.03 ; 231.43,76.88 232.65,78.11 232.65,93.02 233.05,93.42 233.05,100.48 231.59,101.94 231.59,112.65
  IN1 w0.508: v1(86.79,32.04) 88.62,32.04 89.34,32.76 90.51,33.54 94.41,33.54 98.26,29.69 124.96,29.69 125.45,30.17 125.45,30.87
  IN2 w0.508: v1(67.1,37.28) 67.1,36.09 67.8,35.39 74.53,35.39 76.27,37.13 81.91,37.13 86.79,32.26 v1(86.79,32.04)
  IN3 w2.54: 100.71,45.48 98.04,45.48 84.7,58.81 84.7,69.35 85.28,69.92
  BOTTOM w0.254: v1(92.26,48.71) 91.41,47.86 PR721.2 ; 195.89,32.2 195.89,35.06 196.27,35.44 196.27,37.41 196.78,37.92 198.24,37.92 198.84,37.32 199.96,37.32 200.81,38.17 PR102.2
  BOTTOM w1.016: 181.48,128.79 181.5,128.77 183.17,128.77 184.02,129.61 185.45,129.61 189.49,125.58 192.25,125.58 192.54,125.87 200.59,125.87 201.9,124.56 213.72,124.56 214.03,124.25 226.77,124.25
  BOTTOM w1.524: 88.7,82.93 84.56,87.07 74.99,87.07 73.22,88.83 73.22,98.67 80.73,106.17 84.46,106.17
  BOTTOM w2.54: 227.9,69.67 227.2,69.67 222.07,64.54 176.16,64.54
  vias: v1(84.64,107.53) v1(84.96,108.1) v1(85.28,107.53) v1(86.42,72.59) v1(86.42,71.96) v1(86.42,71.32) v1(87.05,72.59) v1(87.05,71.96) v1(87.05,71.32) v1(87.69,72.59) v1(87.69,71.96) v1(87.69,71.32) v1(88.32,72.59) v1(88.32,71.96) v1(88.32,71.32) v1(94.1,119.58) v1(94.45,119.07) v1(94.74,119.58) v1(95.08,129.65) v1(95.61,129.41) v1(125.33,39.72) v1(125.33,38.47) v1(125.33,37.23) v1(125.33,35.98) v1(125.53,34.87) v1(125.53,34.24) v1(125.53,33.6) v1(125.53,32.97) v1(126.17,34.87) v1(126.17,34.24) v1(126.17,33.6) v1(126.17,32.97) v1(126.8,34.87) v1(126.8,34.24) v1(126.8,33.6) v1(126.8,32.97) v1(127.38,34.49) v1(127.38,33.86) v1(127.38,33.22) v1(130.01,134.73) v1(130.64,134.73) v1(157.92,37.97) v1(157.92,37.34) v1(158.55,37.97) v1(158.55,37.34) v1(159.19,37.97) v1(159.19,37.34) v1(159.82,37.97) v1(159.82,37.34) v1(160.46,37.97) v1(160.46,37.34) v1(161.09,37.97) v1(161.09,37.34) v1(167.9,31.01) v1(167.9,30.38) v1(168.54,31.01) v1(168.54,30.38) v1(195.6,29.73) v1(196.19,30.31) v1(196.19,29.73) v1(196.77,29.73) v1(228.12,71.73) v1(228.56,72.12) v1(228.53,71.32) v1(228.98,71.7) v1(228.98,70.94) v1(229.48,71.26) v1(233.55,123.92) v1(234.25,123.92) v1(234.95,123.92) v3(229.87,72.87)
+13.5VB_1.05VALWP: length 0.9
  BOTTOM w0.107: v2(232.96,124.08) 233.4,124.51 233.4,124.75
  vias: v1(232.24,127.95) v1(232.24,127.32) v1(233.78,127.94) v1(233.78,127.3)
+13.5VB_3V: length 1
  TOP w0.127: PC131.1 v2(202.24,31.18)
  vias: v1(199.89,31.29) v1(200.53,31.29)
+13.5VB_5V:
  vias: v1(82.1,68.4) v1(82.1,67.76) v1(82.1,67.13) v1(82.1,66.49) v1(82.1,65.86) v2(82.16,65.15)
+13.5VB_CPU: length 2.4
  BOTTOM w0.254: 91.94,105.67 91.97,105.65 PR603.2
  vias: v1(94.67,105.86) v1(95.31,105.86) v1(95.94,105.86) v1(96.9,106.18) v1(97.53,106.18) v1(98.17,106.18) v1(100.68,105.81) v1(100.68,105.14) v1(101.9,105.81) v1(101.9,105.14) v1(109.15,99.9) v1(109.15,99.26) v1(109.79,99.9) v1(109.79,99.26) v1(110.42,99.9) v1(110.42,99.26) v1(111.06,99.9) v1(111.06,99.26) v1(111.69,99.9) v1(111.69,99.26) v1(114.66,100.86) v1(114.66,100.19) v1(115.87,100.86) v1(115.87,100.19) v2(112.8,99.98)
+13.5VB_DDR:
  vias: v1(90.67,69.48) v2(90.19,70.42)
+13.5VB_FU: length 1.2
  BOTTOM w0.107: LC6.2 v2(99.74,128.37)
+13.5VB_IR:
  vias: v1(101.93,133.75)
+13.5VB_L: length 1.2
  TOP w0.107: v2(93.73,133.23) 94,132.97 CV755.1
+13.5VB_VCCGT:
  vias: v1(104.71,94.37) v1(104.71,93.74) v1(104.71,93.1) v1(104.71,92.47) v1(105,89.56) v1(105,88.35) v1(105.67,89.56) v1(105.67,88.35) v2(105.08,88.94)
+13.5VB_VCCSA: length 1.4
  TOP w0.107: PC608.1 178.05,128.95 v2(177.61,128.51)
  vias: v1(177.86,130.59) v1(178.49,130.59) v1(179.1,130.59)
+13.5VB_VCHGR: length 2
  BOTTOM w0.127: v2(128.77,38.71) PC741.1
  BOTTOM w0.508: PC741.1 129.51,39.8 v1(129.66,39.95)
+19.5V_AC:
  vias: v2(93.34,43.62)
+19.5V_CHARGER:
  vias: v1(97.47,38.68) v1(97.47,38.05) v1(97.47,37.41) v1(97.47,36.78) v1(98.1,38.68) v1(98.1,38.05) v1(98.1,37.41) v1(98.1,36.78) v1(98.8,31.32) v1(99.44,31.95) v1(99.44,31.13) v1(100.11,38.05) v1(100.11,36.81) v1(100.11,35.56) v1(100.11,34.32) v2(98.69,39.79)
+19.5V_DC_IN: length 64.8
  TOP w0.508: PR31.1 78.6,121.77 PQ11.3 75.88,120.88 v1(75.51,121.24) ; PR892.2 65.76,115.11 v1(66.4,114.46)
  IN2 w0.508: v1(75.51,121.24) 75.51,120.1 73.27,117.87 v1(73.27,115.83) 73.27,114.37 71.13,112.23 71.13,96.8 67.88,93.55 67.88,89.01 63.91,85.04 61.02,85.04 58.61,87.45 v1(58.61,90.5)
  IN3 w0.508: v1(73.27,115.83) 70.87,115.83 68.75,113.71 67.15,113.71 v1(66.4,114.46)
  BOTTOM w0.508: v1(58.61,90.5) PR800.1
  vias: v2(72.72,116.89)
+19.5V_DC_IN_SS: length 68.4
  TOP w0.508: PD700.2 78.19,52.8 78.19,61.27 74.1,65.36 74.1,67.63 72.83,68.9 72.83,70.75 69.4,74.18 v3(69.4,75.84) v1(69.4,83.26)
  IN2 w0.508: 76.64,114.37 72.35,110.08 72.35,95.98 69.4,93.04 v1(69.4,83.26)
  vias: v1(76.89,115.83) v1(76.89,115.14)
+19.5V_DCIN_JACK: length 3.7
  TOP w0.127: v3(70.7,125.08) 69.95,124.33 v1(69.95,123.87) ; v1(69.95,123.87) 69.95,123.58 v3(69.65,123.29) ; v1(69.95,123.87) 69.87,123.87 v3(68.87,124.88)
+19.5V_SDC_IN: length 130
  TOP w0.508: 87.69,36.9 88.51,37.73 88.51,40.4 86.99,41.92 84.64,41.92 84.13,42.43 84.13,43.7 83.08,44.75 82.83,44.75 PR703.1 82.57,45.44 PR705.1
  TOP w2.54: 66.99,81.61 66.99,74.49 67.37,74.11 arc(71.8,66.05) 73.34,56.97 73.34,45.22 80.13,38.43 84.89,38.43 86.04,37.28
  IN1 w2.54: 66.99,81.61 66.99,74.49 67.37,74.11 arc(71.8,66.05) 73.34,56.97 73.34,45.22 79.64,38.92 84.4,38.92 86.04,37.28
  BOTTOM w0.508: PQ5.3 73.77,109.22 73.39,108.84 PR10.1 73.39,107.44 73.96,106.87 76.37,106.87 77.27,107.77 v1(77.27,108.98)
  vias: v1(65.97,84.08) v1(65.97,83.45) v1(66.61,84.72) v1(66.61,84.08) v1(66.61,83.45) v1(67.24,84.72) v1(67.24,84.08) v1(67.24,83.45) v1(67.88,84.08) v1(67.88,83.45) v1(79.43,112.41) v1(79.43,111.77) v1(79.43,111.14) v1(79.43,110.5) v1(80.07,112.41) v1(80.07,111.77) v1(80.07,111.14) v1(80.07,110.5) v1(80.7,110.63) v1(81.34,110.63) v1(86.8,35.7) v1(86.8,35.06) v1(87.43,36.33) v1(87.43,35.7) v1(87.43,35.06) v1(88.07,36.33) v1(88.07,35.7) v1(88.07,35.06) v1(88.7,35.7) v1(88.7,35.06) v3(77.26,102.45)
+20V_LDO_INPUT: length 9.2
  IN3 w0.508: v1(74.46,118.13) 74.05,117.73 71.86,117.73 68.56,114.42 67.45,114.42 v1(66.98,114.89)
  vias: v2(74.94,118.64)
+20V_TBTA_VBUS: length 3.4
  TOP w0.127: v3(23.35,100.49) 22.72,99.86 DT4.2 ; v3(24.74,95.34) 23.22,95.34 PL801.1
  vias: v1(6.47,105.82) v1(6.49,108.61) v1(8.81,108.6) v1(8.81,108.01) v1(8.81,106.06) v1(8.81,105.47) v1(9.39,108.6) v1(9.39,108.01) v1(9.39,106.06) v1(9.39,105.47) v1(20.85,98.47) v1(20.84,97.86) v1(21.59,98.47) v1(21.59,97.87) v1(21.58,97.29) v1(21.58,96.68) v1(21.58,96.07) v1(22.27,96.07) v3(20.46,99.06)
+20V_TBTA_VBUS_1: length 52.4
  TOP w0.508: PQ803.3 91.55,86.64 91.04,87.15 PR801.1 89.76,87.15 89.17,86.56 v1(89.17,86.52)
  IN1 w0.508: v1(63.05,86.69) 64.6,88.24 71.92,88.24 74.04,86.12 87.01,86.12 87.42,86.52 v1(89.17,86.52)
  IN2 w0.508: v1(63.05,86.69) 63.22,86.85 63.22,96.19 62.12,97.28 62.12,101.1 v1(62.33,101.31) 62.7,101.67 62.7,102.14 62.7,105.4 v1(63.57,106.27)
  BOTTOM w0.508: v1(63.05,86.69) PR831.1
  vias: v1(20.68,92.09) v1(21,91.58) v1(21.27,92.15) v1(21.61,92.78) v1(21.59,91.64) v1(21.9,92.15) v1(22.25,92.78) v1(22.22,91.64) v1(22.54,92.15) v1(22.88,92.78) v1(62.73,100.78) v1(63.57,106.91) v1(64.2,107.86) v1(64.2,107.23) v1(64.2,106.59) v1(64.2,105.96) v1(64.9,107.86) v1(64.9,107.23) v1(64.9,106.59) v1(64.9,105.96) v2(64.5,108.77)
+20V_VBUS_DC_SS: length 71.6
  TOP w0.508: PD704.2 79.26,51.95 78.82,52.38 78.82,61.53 74.73,65.62 74.73,67.89 73.46,69.16 73.46,71.01 70.04,74.44 v1(70.04,83.26) ; PD801.3 74.42,104.53 v1(73.85,103.96)
  IN2 w0.508: v1(73.85,103.96) 73.85,96.47 v1(71.03,93.65) 70.04,92.66 v1(70.04,83.26)
  BOTTOM w0.508: PR870.1 62.59,90.43 63.25,91.09 63.25,93.06 64.4,94.21 70.47,94.21 v1(71.03,93.65)
  vias: v3(72.28,106.82)
+DV33_18:
  vias: v2(293.77,22.39)
+GND_CHASSIS: length 17
  TOP w0.508: v1(296.67,95.69) 297.28,95.69 299.66,98.08 RL18.2 RL17.2 v2(299.66,104.48) RL16.2 RL15.2
  BOTTOM w0.508: CL22.2 295.63,95.26 296.06,95.69 v1(296.67,95.69)
+VCC1V8A_TBTA_LDO: length 2.2
  BOTTOM w0.203: UT5.K1 57.04,107.09
  BOTTOM w0.381: CT73.1 56.46,107.67 57.04,107.09
+VCC1V8D_TBTA_LDO: length 20.5
  IN2 w0.508: v1(58.36,100.72) 58.41,100.78 58.41,101.87 58.23,102.05 58.23,105.7 58.92,106.39 61.87,106.39 63.95,108.47 65.76,108.47 v1(67.94,106.3)
  BOTTOM w0.076: CT72.1 57.55,99.93 57.55,99.39
  BOTTOM w0.107: v2(57.55,99.15) 57.55,99.39
  BOTTOM w0.203: UT5.A2 58.36,101.78 v1(58.36,100.72)
  BOTTOM w0.381: CT72.1 58.35,100.72 v1(58.36,100.72)
  BOTTOM w0.508: RT97.1 67.73,106.5 v1(67.94,106.3)
+VCC_CORE: length 211.1
  TOP w0.254: v1(93.86,103.53) 93.86,103.9 92.08,105.68 92.08,111.91 95.25,115.07 98.48,115.07 100.37,116.96 v1(104.03,116.96) ; PR3004.1 v1(74.81,37.97)
  TOP w0.381: PC1200.1 PC1201.1 152.19,122.98 PC1202.1 152.42,123.01 152.96,122.47 PC1086.1
  IN3 w0.254: v1(93.86,103.53) 93.28,104.11 92.63,104.11 90.81,102.3 86.99,102.3 86.28,103.01 74.47,103.01 74.16,102.69 70.87,102.69 70.37,103.2 69.76,103.2 69.45,102.89 69.45,97.09 62.95,90.59 62.95,88.99 64.75,87.19 64.75,77.21 74.93,67.04 75.88,67.04 76.23,66.69 76.23,63.41 77,62.65 77,60.82 76.51,60.34 75.69,60.34 74.28,58.93 74.28,41.44 74.81,40.9 v1(74.81,37.97)
  BOTTOM w0.1: 159.39,94.63 UC1.AU25 ; UC1.AU25 159.84,95.08 ; UC1.AU25 159.84,94.63 ; UC1.AU25 159.39,95.08 ; 155.26,104.47 UC1.AJ10 ; UC1.AJ10 154.98,104.75 154.7,104.47 ; UC1.AJ10 155.21,104.98 ; UC1.AJ10 154.76,104.98 ; 157.56,95.1 UC1.AN24 157.34,95.64 ; UC1.AD9 151.52,104.99 ; UC1.AD9 151.97,105.43 ; UC1.AD9 151.97,104.99 ; UC1.AD9 151.52,105.43 ; UC1.AJ8 154.98,105.67 154.76,105.44 ; UC1.AJ8 154.76,105.89 ; UC1.AJ8 155.21,105.44 ; UC1.AJ8 155.21,105.89 ; UC1.AB10 150.59,104.98 ; UC1.AB10 150.64,104.47 ; UC1.AB10 150.08,104.47 ; UC1.AB10 150.14,104.98 ; 162.12,94.17 UC1.AY26 ; UC1.AY26 161.67,94.17 ; UC1.AY26 161.67,94.62 ; UC1.AY26 162.12,94.62 ; 161.21,95.1 UC1.AW24 ; UC1.AW24 160.76,95.1 ; UC1.AW24 161.21,95.55 ; UC1.BC9 163.53,104.99 ; UC1.BC9 163.98,104.99 ; UC1.BC9 163.98,105.43 ; UC1.BC9 163.53,105.43 ; 158.44,104.99 UC1.AP9 ; UC1.AP9 158.44,105.43 ; UC1.AP9 157.99,104.99 ; UC1.AP9 157.99,105.43 ; UC1.AT9 158.91,104.99 ; UC1.AT9 159.36,104.99 ; UC1.AT9 158.91,105.43 ; UC1.AT9 159.36,105.43 ; UC1.AT24 158.93,95.1 ; UC1.AT24 159.38,95.1 ; UC1.AT24 158.93,95.55 ; UC1.AT24 159.38,95.55 ; 154.3,105.43 UC1.AH9 ; UC1.AH9 154.74,105.43 ; UC1.AH9 154.3,104.99 ; UC1.AH9 154.74,104.99 ; 155.68,105.44 155.91,105.67 UC1.AL8 ; 159.38,94.62 UC1.AT26 ; UC1.AT26 159.38,94.17 ; UC1.AT26 158.93,94.62 ; UC1.AT26 158.93,94.17 ; 162.57,95.08 UC1.BA25 ; UC1.BA25 162.12,94.63 ; UC1.BA25 162.12,95.08 ; UC1.BA25 162.57,94.63 ; UC1.AE9 152.45,104.99 ; UC1.AE9 152.45,105.43 ; UC1.AE9 152.9,105.43 ; UC1.AE9 152.9,104.99 ; 165.31,95.1 UC1.BF24 165.31,95.55 ; 161.67,95.55 UC1.AY24 ; UC1.AY24 161.67,95.1 ; UC1.AY24 162.12,95.55 ; UC1.AY24 162.12,95.1 ; UC1.BD8 164,105.44 ; UC1.BD8 164.44,105.44 ; UC1.BD8 164.44,105.89 ; 155.63,104.47 155.91,104.75 UC1.AL10 ; UC1.BE26 164.4,94.62 ; UC1.BE26 164.85,94.62 ; UC1.BE26 164.4,94.17 ; UC1.BE26 164.85,94.17 ; UC1.AR10 158.45,104.53 ; UC1.AR10 158.9,104.98 ; UC1.AR10 158.45,104.98 ; UC1.AR10 158.9,104.53 ; UC1.BC26 163.49,94.62 ; UC1.BC26 163.94,94.17 ; UC1.BC26 163.49,94.17 ; UC1.BC26 163.94,94.62 ; 160.29,95.1 UC1.AU24 ; UC1.AU24 159.84,95.1 ; UC1.AU24 159.84,95.55 ; 160.3,104.98 UC1.AV10 ; UC1.AV10 160.75,104.53 ; UC1.AV10 160.75,104.98 ; UC1.AV10 160.3,104.53 ; 165.61,105.21 UC1.BF9 ; 165.61,105.21 165.38,104.99 ; 165.61,105.21 165.38,105.43 ; 162.6,105.89 UC1.BA8 ; UC1.BA8 162.15,105.44 ; UC1.BA8 162.15,105.89 ; UC1.BA8 162.6,105.44 ; 157.61,105.21 UC1.AN9 157.29,104.89 ; 154.28,105.44 UC1.AG8 ; UC1.AG8 154.28,105.89 ; UC1.AG8 153.83,105.89 ; UC1.AG8 153.83,105.44 ; 163.03,94.17 162.94,94.26 UC1.BB26 ; 153.82,105.43 UC1.AG9 ; UC1.AG9 153.37,104.99 ; UC1.AG9 153.82,104.99 ; UC1.AG9 153.37,105.43 ; 158.9,105.44 UC1.AR8 158.9,105.89 ; UC1.AW26 160.76,94.17 ; UC1.AW26 161.2,94.17 ; UC1.AW26 161.2,94.62 ; UC1.AW26 160.76,94.62 ; 160.29,104.99 UC1.AU9 ; UC1.AU9 159.84,105.43 ; UC1.AU9 159.84,104.99 ; UC1.AU9 160.29,105.43 ; UC1.AL9 156.14,104.99 ; UC1.AL9 156.14,105.43 ; UC1.AL9 156.59,105.43 ; UC1.AL9 156.59,104.99 ; UC1.AC8 151.06,105.44 ; UC1.AC8 151.06,105.89 ; UC1.AC8 151.51,105.44 ; UC1.AC8 151.51,105.89 ; 155.68,104.98 UC1.AL10 ; UC1.AL10 156.19,104.47 ; UC1.AL10 156.13,104.98 ; UC1.AU26 159.84,94.17 ; UC1.AU26 159.84,94.62 ; UC1.AU26 160.29,94.62 ; UC1.AU26 160.29,94.17 ; 158.47,94.17 UC1.AP26 ; UC1.AP26 158.47,94.62 ; UC1.AP26 158.02,94.17 ; UC1.AP26 158.02,94.62 ; 152.44,105.44 UC1.AE8 ; UC1.AE8 151.99,105.44 ; UC1.AE8 152.44,105.89 ; UC1.AE8 151.99,105.89 ; UC1.AP24 158.02,95.1 ; UC1.AP24 158.47,95.1 ; UC1.AP24 158.47,95.55 ; UC1.AE10 152.44,104.98 ; UC1.AE10 151.93,104.47 ; UC1.AE10 151.99,104.98 ; UC1.AE10 152.49,104.47 ; UC1.BE9 164.68,105.21 164.46,104.99 ; UC1.BE9 164.46,105.43 ; UC1.BE9 164.91,105.43 ; UC1.BE9 164.91,104.99 ; 149.66,104.98 UC1.Y10 149.66,104.53 ; UC1.AM8 157.05,105.44 ; UC1.AM8 156.61,105.44 ; UC1.AM8 156.61,105.89 ; UC1.AM8 157.05,105.89 ; UC1.AW25 161.21,94.63 ; UC1.AW25 161.66,94.63 ; UC1.AW25 161.66,95.08 ; UC1.AW25 161.21,95.08 ; 159.38,105.89 UC1.AU8 ; UC1.AU8 159.38,105.44 ; UC1.AU8 159.83,105.89 ; UC1.AU8 159.83,105.44 ; 155.67,104.99 UC1.AK9 ; UC1.AK9 155.22,105.43 ; UC1.AK9 155.67,105.43 ; UC1.AK9 155.22,104.99 ; 162.58,94.62 UC1.BB26 ; UC1.BB26 162.58,94.17 ; UC1.BB26 163.03,94.62 ; 150.6,105.43 UC1.AB9 ; UC1.AB9 150.6,104.99 ; UC1.AB9 151.05,105.43 ; UC1.AB9 151.05,104.99 ; 164.4,95.08 UC1.BD25 ; UC1.BD25 164.4,94.63 ; UC1.BD25 163.95,95.08 ; UC1.BD25 163.95,94.63 ; UC1.BD10 164.44,104.53 ; UC1.BD10 164,104.98 ; UC1.BD10 164.22,104.75 164,104.53 ; UC1.BD10 164.44,104.98 ; UC1.AR25 158.48,95.08 ; UC1.AR25 158.93,95.08 ; UC1.AR25 158.48,94.63 ; UC1.AR25 158.93,94.63 ; UC1.AL8 156.13,105.44 ; UC1.AL8 155.68,105.89 ; UC1.AL8 156.13,105.89 ; UC1.AW9 161.21,105.43 ; UC1.AW9 161.21,104.99 ; UC1.AW9 160.76,105.43 ; UC1.AW9 160.76,104.99 ; UC1.AA9 149.68,105.43 ; UC1.AA9 150.13,104.99 ; UC1.AA9 149.68,104.99 ; UC1.AA9 150.13,105.43 ; 153.36,105.89 UC1.AF8 ; UC1.AF8 153.36,105.44 ; UC1.AF8 152.91,105.89 ; UC1.AF8 152.91,105.44 ; UC1.AW10 161.64,104.95 ; UC1.AW10 161.22,104.98 ; UC1.AW10 161.22,104.53 ; UC1.AF10 152.85,104.47 ; UC1.AF10 153.36,104.98 ; UC1.AF10 153.41,104.47 ; UC1.AF10 152.91,104.98 ; UC1.AW8 161.67,105.44 ; UC1.AW8 161.22,105.44 ; UC1.AW8 161.67,105.89 ; UC1.BE25 164.86,95.08 ; UC1.BE25 165.31,94.63 ; UC1.BE25 164.86,94.63 ; UC1.BE25 165.31,95.08 ; 163.12,105.04 163.12,104.93 UC1.BC10 ; UC1.BC10 163.52,104.53 ; UC1.BC10 163.52,104.98 ; 157.53,104.98 UC1.AN10 157.53,104.53 ; 157.56,94.17 UC1.AN26 157.56,94.62
  BOTTOM w0.102: UC1.BF26 165.75,94.19 ; UC1.BF26 165.75,94.6 ; UC1.BF26 165.33,94.19 ; UC1.BF26 165.33,94.6 ; UC1.BE24 164.83,95.53 ; UC1.BE24 164.42,95.11 ; UC1.BE24 164.83,95.11 ; UC1.BE24 164.42,95.53
  BOTTOM w0.18: UC1.AB2 150.76,110.84 v1(150.76,110.84) ; v1(155.74,110.47) 155.64,110.37 UC1.AK2 ; v1(160.14,111.14) 160.15,111.14 160.52,110.76 UC1.AV2 ; UC1.BB2 162.94,110.02 162.94,110.31 162.3,110.94 v1(162.3,110.94) ; UC1.AF2 v1(153.2,110.84)
  BOTTOM w0.203: UC1.AP2 v1(158.08,110.57) ; UC1.V2 148.01,110.3 148.01,110.84 v1(148.01,111.45) ; v1(165.36,110.57) 165.41,110.53 165.41,110.3 UC1.BF2
  vias: v1(104.01,116.34) v1(104.31,115.57) v1(104.83,117.08) v1(104.83,116.44) v1(105.09,115.57) v1(105.57,116.86) v1(105.55,116.24) v1(106.35,116.91) v1(106.32,116.29) v1(107.11,116.86) v1(107.08,116.24) v1(107.81,116.81) v1(107.78,116.19) v1(108.14,111.71) v1(108.77,114.88) v1(108.77,114.25) v1(108.77,113.61) v1(108.77,112.98) v1(108.77,112.34) v1(108.77,111.71) v1(109.41,114.88) v1(109.41,114.25) v1(109.41,113.61) v1(109.41,112.98) v1(109.41,112.34) v1(109.41,111.71) v1(110.04,114.88) v1(110.04,114.25) v1(110.04,113.61) v1(110.04,112.98) v1(110.04,112.34) v1(110.04,111.71) v1(110.68,114.88) v1(110.68,114.25) v1(110.68,113.61) v1(110.68,112.98) v1(110.68,112.34) v1(110.68,111.71) v1(111.31,114.88) v1(111.31,114.25) v1(111.31,113.61) v1(111.31,112.98) v1(111.31,112.34) v1(111.31,111.71) v1(111.95,114.88) v1(111.95,114.25) v1(111.95,113.61) v1(111.95,112.98) v1(111.95,112.34) v1(111.95,111.71) v1(111.95,111.07) v1(112.58,114.88) v1(112.58,114.25) v1(112.58,113.61) v1(112.58,112.98) v1(112.58,112.34) v1(112.58,111.71) v1(112.58,111.07) v1(113.22,114.88) v1(113.22,114.25) v1(113.22,113.61) v1(113.22,112.98) v1(113.22,112.34) v1(113.22,111.71) v1(113.22,111.07) v1(113.85,114.88) v1(113.85,114.25) v1(113.85,113.61) v1(113.85,112.98) v1(113.85,112.34) v1(113.85,111.71) v1(113.85,111.07) v1(114.49,111.07) v1(114.61,114.5) v1(115.12,111.07) v1(115.25,114.5) v1(115.88,114.5) v1(116.52,114.5) v1(117.15,114.5) v1(117.79,114.5) v1(118.42,113.87) v1(118.42,113.23) v1(118.42,112.6) v1(118.42,111.96) v1(118.42,111.33) v1(119.06,113.87) v1(119.06,113.23) v1(119.06,112.6) v1(119.06,111.96) v1(119.06,111.33) v1(119.69,113.23) v1(119.69,112.6) v1(119.69,111.96) v1(119.69,111.33) v1(120.33,112.6) v1(120.33,111.96) v1(120.33,111.33) v1(120.33,110.69) v1(120.96,112.6) v1(120.96,111.96) v1(120.96,111.33) v1(149.45,103.85) v1(149.9,105.92) v1(149.96,104.23) v1(150.4,103.85) v1(150.82,105.92) v1(150.84,104.23) v1(151.75,105.92) v1(151.73,104.23) v1(152.2,103.88) v1(152.67,105.92) v1(152.67,104.23) v1(153.21,123.14) v1(153.6,105.92) v1(153.79,123.14) v1(154.38,123.14) v1(154.52,105.92) v1(154.96,123.14) v1(154.97,103.85) v1(155.44,105.92) v1(155.44,104.21) v1(155.55,123.14) v1(155.91,103.85) v1(156.13,123.14) v1(156.37,105.92) v1(156.37,104.23) v1(156.71,123.14) v1(157.21,120.83) v1(157.21,120.24) v1(157.21,119.66) v1(157.29,105.92) v1(157.29,104.22) v1(157.41,96.09) v1(157.74,103.85) v1(157.79,120.83) v1(157.79,120.24) v1(157.79,119.66) v1(158.23,104.19) v1(158.27,96.07) v1(158.25,93.64) v1(158.38,120.83) v1(158.38,120.24) v1(158.38,119.66) v1(158.7,103.85) v1(158.7,95.54) v1(159.14,107.82) v1(159.14,107.19) v1(159.14,106.55) v1(159.14,105.92) v1(159.15,104.23) v1(159.14,96.07) v1(159.16,93.64) v1(159.61,95.54) v1(159.9,96.07) v1(160.06,107.82) v1(160.06,107.19) v1(160.06,106.55) v1(160.06,105.92) v1(160.06,104.22) v1(160.07,93.64) v1(160.51,103.85) v1(160.99,107.82) v1(160.99,106.55) v1(160.98,104.21) v1(161,95.98) v1(160.98,93.64) v1(161.45,103.85) v1(161.44,95.54) v1(161.9,107.82) v1(161.9,107.19) v1(161.9,106.55) v1(161.9,105.92) v1(161.89,95.91) v1(162.83,107.82) v1(162.83,106.55) v1(162.86,105.97) v1(162.8,93.64) v1(163.29,103.85) v1(163.76,107.82) v1(163.76,107.19) v1(163.76,106.55) v1(163.76,104.21) v1(163.71,93.64) v1(164.23,103.85) v1(164.62,95.91) v1(164.63,93.64) v1(164.68,107.82) v1(164.68,105.9) v1(164.68,104.23) v1(165.08,95.54) v1(165.54,93.64) v3(161.78,108.74)
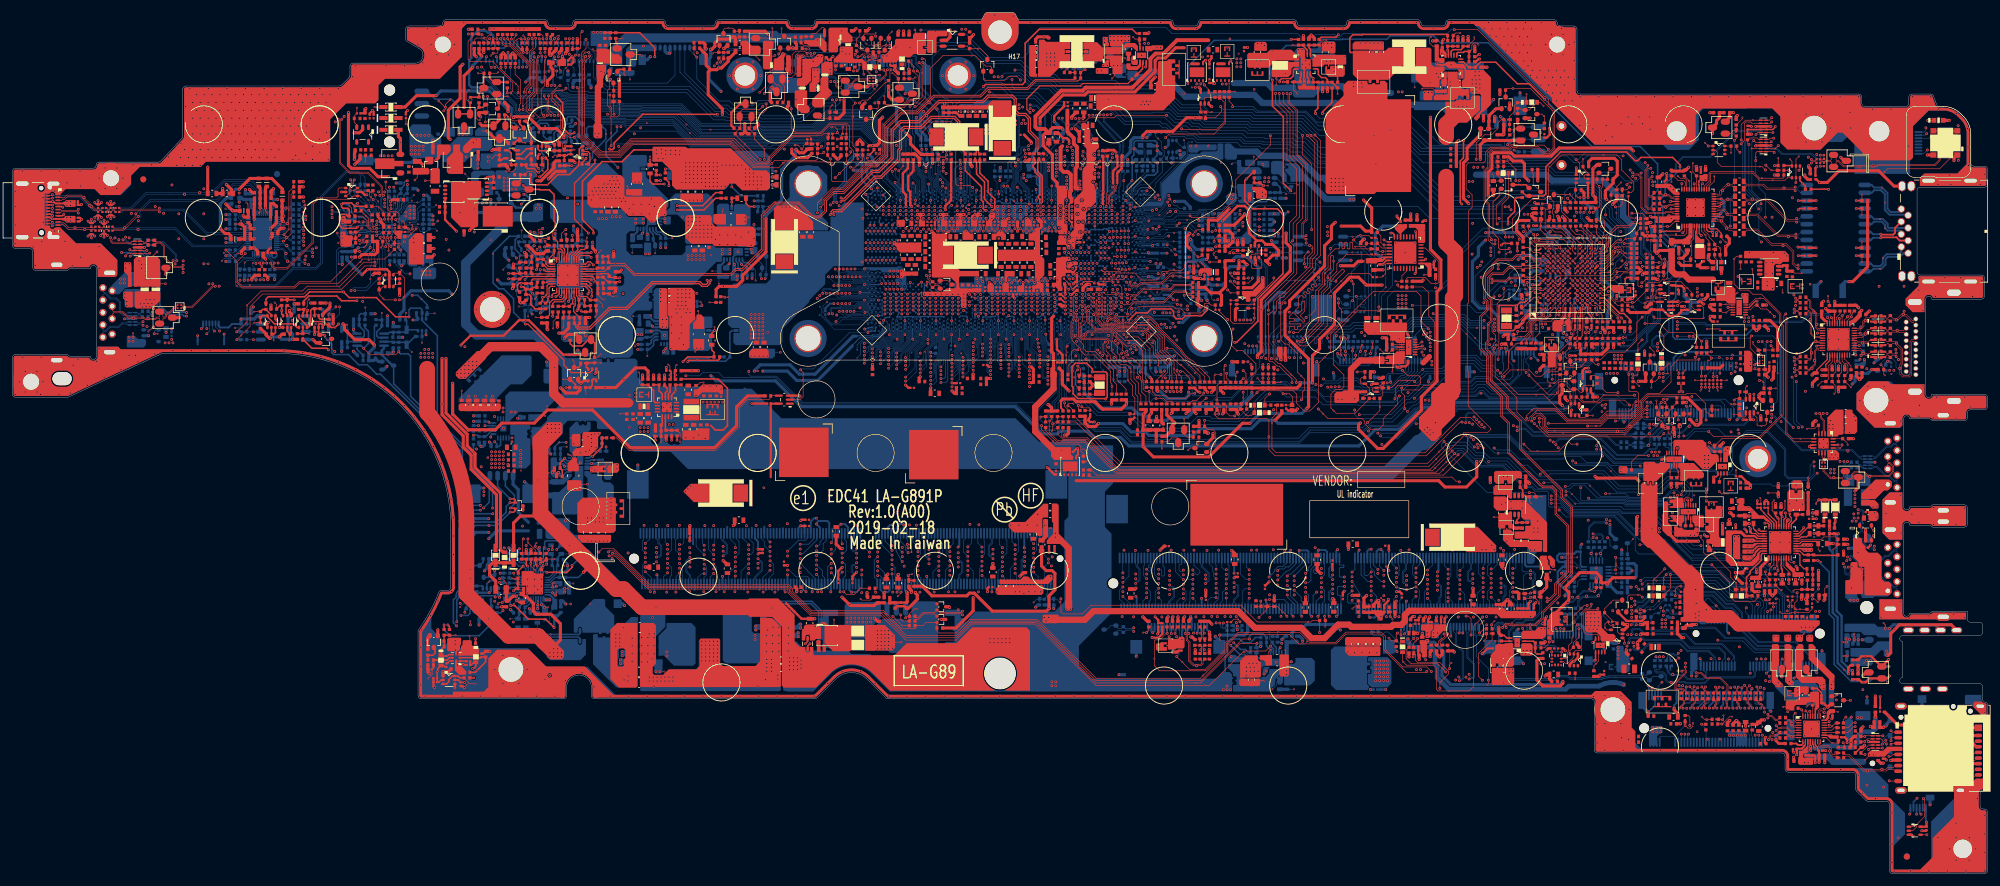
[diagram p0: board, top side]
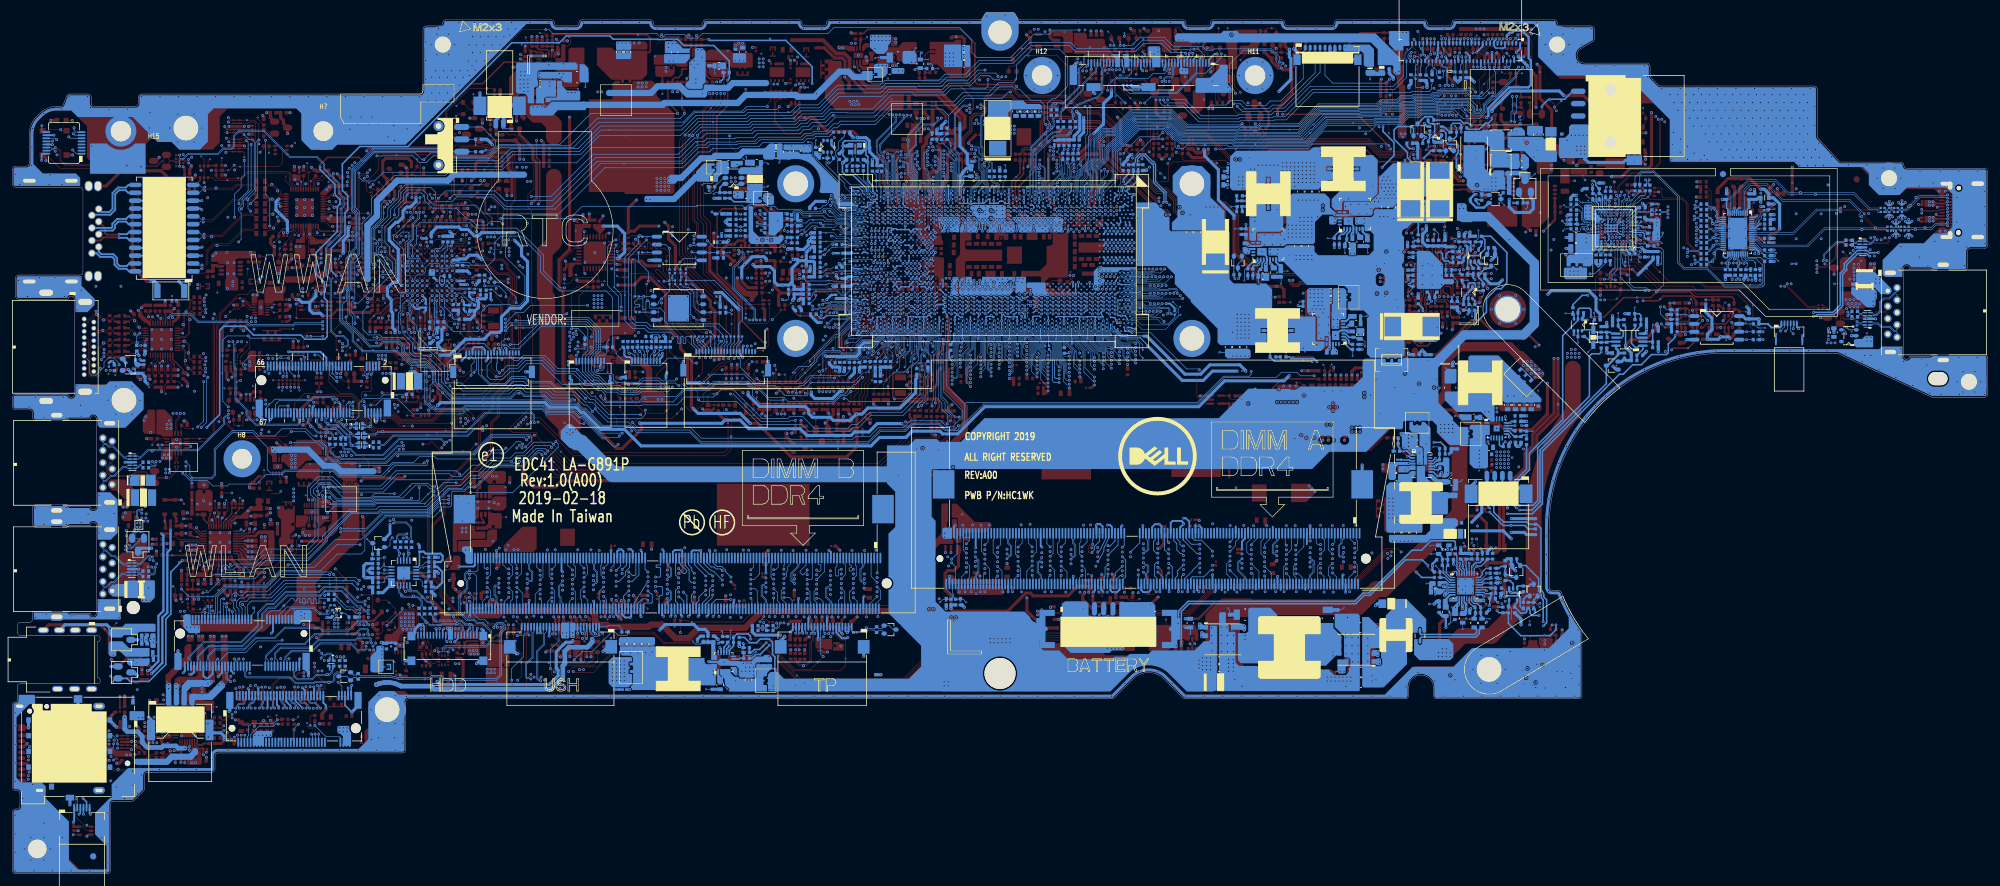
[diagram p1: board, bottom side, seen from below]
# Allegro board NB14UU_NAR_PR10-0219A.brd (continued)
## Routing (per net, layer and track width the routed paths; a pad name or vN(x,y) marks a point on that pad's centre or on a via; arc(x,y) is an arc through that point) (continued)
+VCC_CORE_G0: length 11
  TOP w0.107: T371.1 v1(159.49,112.01)
  IN3 w0.089: 159.71,111.56 159.71,110.46 161.4,108.77 161.4,105.46 161.58,105.28 162.07,105.28 162.84,104.52 v1(162.84,104.23)
  IN3 w0.102: 159.71,111.56 159.71,111.8 v1(159.49,112.01)
  BOTTOM w0.203: UC1.BB9 162.84,105.21 v1(162.84,104.23)
+VCC_CORE_G1: length 1.1
  TOP w0.203: T372.1 163.88,95.91 v1(163.71,95.91)
  BOTTOM w0.203: UC1.BC24 v1(163.71,95.91)
+VCC_CORE_G2: length 8.3
  TOP w0.102: T373.1 159.3,109.87 v1(159.32,109.85)
  IN3 w0.089: v1(159.32,109.85) 159.28,109.81 159.28,109.42 160.55,108.15 160.55,105.48 161.8,104.23 v1(161.91,104.23)
  BOTTOM w0.203: UC1.AY9 161.91,105.21 v1(161.91,104.23)
+VCC_CORE_G3: length 1.1
  TOP w0.203: T374.1 162.62,95.91 v1(162.8,95.91)
  BOTTOM w0.203: UC1.BB24 v1(162.8,95.91)
+VCC_GT: length 6.7
  BOTTOM w0.1: 139.52,109.46 UC1.C2 139.07,109.46
  BOTTOM w0.18: UC1.P2 145.88,111.21 v1(145.48,111.61)
  BOTTOM w0.203: UC1.K2 143.44,110.68 142.58,111.54 v1(142.58,111.71)
  BOTTOM w0.254: RC160.1 138.74,113.1 139.57,112.28 v1(139.57,111.83)
  vias: v1(119.31,90.37) v1(119.31,89.74) v1(119.31,89.1) v1(119.31,88.47) v1(119.31,87.83) v1(119.31,87.2) v1(119.31,86.56) v1(119.95,90.37) v1(119.95,89.74) v1(119.95,89.1) v1(119.95,88.47) v1(119.95,87.83) v1(119.95,87.2) v1(119.95,86.56) v1(120.58,90.37) v1(120.58,89.74) v1(120.58,89.1) v1(120.58,88.47) v1(120.58,87.83) v1(120.58,87.2) v1(120.58,86.56) v1(121.22,90.37) v1(121.22,89.74) v1(121.22,89.1) v1(121.22,88.47) v1(121.22,87.83) v1(121.22,87.2) v1(121.22,86.56) v1(124.46,101.42) v1(124.46,100.78) v1(125.09,101.42) v1(125.09,100.78) v1(125.73,101.42) v1(125.73,100.78) v1(126.36,101.42) v1(126.36,100.78) v1(137.25,107.42) v1(137.28,98.87) v1(137.38,105.91) v1(137.88,103.85) v1(137.88,101.97) v1(137.88,101.03) v1(137.88,99.14) v1(138.53,101.03) v1(139.18,103.85) v1(139.18,101.97) v1(139.18,101.03) v1(139.18,99.14) v1(139.83,103.85) v1(139.83,101.97) v1(139.83,101.03) v1(139.83,99.14) v1(140.48,101.97) v1(140.67,107.82) v1(140.66,107.19) v1(140.66,106.55) v1(141.13,103.85) v1(141.13,101.97) v1(141.13,101.03) v1(141.13,99.14) v1(141.59,107.82) v1(141.59,107.19) v1(141.59,106.55) v1(141.78,103.85) v1(141.78,101.97) v1(141.78,101.03) v1(141.78,99.14) v1(142.43,101.03) v1(142.5,107.84) v1(142.5,107.21) v1(142.5,106.57) v1(143.43,106.55) v1(143.9,103.79) v1(144.36,106.55) v1(144.36,105.92) v1(144.32,104.28) v1(144.82,103.88) v1(145.24,104.32) v1(145.28,106.55) v1(145.28,105.92) v1(146.21,105.92) v1(146.21,104.23) v1(146.72,103.79) v1(147.13,105.92) v1(147.16,104.17) v1(147.61,103.72) v1(148.03,104.17) v1(148.98,105.92) v1(149,104.23) v3(122,87.48)
+VCC_SA: length 10.8
  BOTTOM w0.1: UC1.BJ10 166.77,104.98 ; UC1.BJ10 167.22,104.98 ; UC1.BJ10 166.84,104.6 166.77,104.53 ; UC1.BJ10 167.22,104.53 ; 166.29,104.98 UC1.BG10 166.29,104.53 ; 168.15,104.99 UC1.BL9 ; UC1.BL9 168.15,105.43 ; UC1.BL9 168.6,105.43 ; UC1.BL9 168.6,104.99 ; UC1.BL8 168.61,105.44 ; UC1.BL8 168.61,105.89 ; UC1.BL8 169.06,105.44 ; UC1.BL8 169.06,105.89 ; 166.29,105.89 UC1.BG8 166.29,105.44 ; UC1.BH9 166.31,105.43 ; UC1.BH9 166.75,105.43 ; UC1.BH9 166.75,104.99 ; UC1.BH9 166.31,104.99 ; 167.23,105.43 UC1.BJ9 ; UC1.BJ9 167.68,104.99 ; UC1.BJ9 167.23,104.99 ; 168.61,104.53 UC1.BL10 168.61,104.98 ; 168.14,105.44 UC1.BK8 ; UC1.BK8 167.69,105.89 ; UC1.BK8 168.14,105.89 ; UC1.BK8 167.69,105.44 ; 166.77,105.89 UC1.BJ8 ; UC1.BJ8 167.22,105.89 ; UC1.BJ8 167.22,105.44 ; UC1.BJ8 166.77,105.44
  BOTTOM w0.102: UC1.BJ9 167.46,105.21 167.69,105.44
  vias: v1(166.53,105.92) v1(166.78,104.14) v1(167.06,132.6) v1(167.06,131.96) v1(167.06,131.33) v1(167.06,130.69) v1(167.3,103.87) v1(167.38,114.78) v1(167.38,114.2) v1(167.38,113.61) v1(167.45,105.92) v1(167.48,104.43) v1(167.65,96.23) v1(167.7,132.6) v1(167.7,131.96) v1(167.7,131.33) v1(167.7,130.69) v1(168.24,96.23) v1(168.33,132.6) v1(168.33,131.96) v1(168.33,131.33) v1(168.33,130.69) v1(168.33,104.4) v1(168.38,105.92) v1(168.59,103.86) v1(169.25,105.92) v3(167.99,105.08)
+VCCDPHY_1P24: length 3.9
  BOTTOM w0.076: CC84.1 185.02,94.07 v2(184.89,93.94)
  BOTTOM w0.203: 183.53,95.15 183.34,95.15 183.17,95.32 182.53,95.32 UC1.CP25
  BOTTOM w0.508: 183.53,95.15 183.74,94.94 CC84.1
+VCCPDSW_1P05: length 3.6
  TOP w0.152: CC65.1 174.47,95.71 173.13,95.71 v2(173.07,95.64) v1(172.7,95.27)
  BOTTOM w0.203: v1(172.7,95.27) 172.03,95.27 UC1.BT24
+VCCPLL_OC: length 24.8
  TOP w0.508: CC322.1 CC1480.1 168.17,84.06 167.87,84.36 167.87,89.78 168.21,90.12
  TOP w1.016: 168.17,80.63 168.17,78.39 165.21,75.43 165.21,71.46 168.3,68.37
  BOTTOM w0.203: v1(168.26,93.51) 168.31,93.51 UC1.BL27 169.18,94.39 UC1.BM26
  vias: v2(169.49,68.45)
+VDDA_AVDD1: length 3.3
  TOP w0.508: LA5.1 v2(290.06,60.41) CA9.1
+VSS_PLL:
  vias: v2(251.37,89.9)
GND: length 3315.5
  TOP w0.127: v1(148.98,106.55) 149.41,106.12 149.41,105.76 PC1146.2
  TOP w0.203: v1(291.42,85.25) 291.53,85.36 UV21.8 ; v1(295.08,89.74) 295.15,89.66 UV21.35 ; 268.41,67 v1(268.41,66.98) UZ47.11 ; UZ5.11 v1(270.7,58.49) ; v1(294.76,82.81) 294.75,82.82 UV21.15 ; UZ43.11 v1(277.11,91.51)
  TOP w0.254: v1(14.26,105.34) 14.57,105.03 DT14.2 ; DT17.2 16.11,108.05 v1(16.42,108.36) ; DT17.2 15.65,108.05 v1(15.34,108.36) ; DT17.2 v1(15.88,108.65) ; RT491.2 v1(13.84,108.76) ; RT491.2 14.07,108.16 v1(14.38,108.47) ; RT491.2 13.61,108.16 v1(13.3,108.47) ; v1(222.66,103.53) 222.97,103.53 223.22,103.27 UZ12.16 ; v1(226.67,103.77) 226.72,103.72 UZ12.9 ; v1(15.34,103.14) 15.03,103.46 DT13.2 ; v1(14.26,103.14) 14.57,103.46 DT13.2 ; PU402.6 v1(208.66,128.43) ; v1(14.38,106.06) 14.07,106.37 RT490.2 ; RT490.2 13.61,106.37 v1(13.3,106.06) ; RT490.2 v1(13.84,105.78) ; v1(183.04,130.38) 183.14,130.48 PU614.4 ; UZ3.11 v1(223.63,85.1) ; CT87.2 61.28,106.07 v1(61.28,105.78) ; DT13.2 v1(14.8,102.86) ; DT18.2 15.65,106.48 v1(15.34,106.17) ; DT18.2 16.11,106.48 v1(16.42,106.17) ; DT18.2 v1(15.88,105.88) ; v1(12.76,102.75) RT219.2 ; RT219.2 12.53,103.35 v1(12.22,103.04) ; RT219.2 12.99,103.35 v1(13.3,103.04) ; v1(249.65,95.04) 249.84,95.24 249.87,95.24 UE1.E6 ; CC1463.2 171.89,95.04 v1(171.29,94.44) ; UZ12.2 228.07,99.11 v1(228.28,99.32) ; CZ40.2 297.68,19.5 298.57,20.39 RZ334.2 ; UZ23.5 241.4,38.07 240.95,38.52 CZ130.2 ; CE28.2 242.92,88.25 242.44,87.77 240.26,87.77 240.13,87.9 240.13,91.73 240.23,91.83 242.82,91.83 v1(242.92,91.73) 243.53,92.34 244.28,92.34 244.53,92.59 v1(244.53,92.78) ; v1(226.56,96.97) 226.72,97.14 UZ12.32 ; DT14.2 15.03,105.03 v1(15.34,105.34) ; DT14.2 v1(14.8,105.63) ; UZ8.5 275.47,64.41 275.22,64.16 274.89,64.16 v1(274.81,64.08) ; v1(12.22,105.45) 12.53,105.14 RT220.2 ; v1(13.3,105.45) 12.99,105.14 RT220.2 ; UZ53.5 255.72,34.57 v1(255.65,34.49) ; RT220.2 v1(12.76,105.74) ; v1(221.41,98.47) 221.41,98.58 221.95,99.11 UZ12.23 ; v1(248.85,94.21) UE1.C4 ; UZ52.B1 UZ52.C1 281.64,82.44 v1(281.43,82.23) ; UE1.H4 v1(252.85,93.41) ; RC136.2 139.17,116.89 138.5,116.22 v1(138.22,116.22) ; 292.2,28.78 CR28.2 292.2,29.25 291.5,29.94 CR1.2 ; PC3009.2 72.92,33.73 v1(72.82,33.83) ; v1(245.52,95.17) 245.59,95.11 246.54,95.11 UE1.A6 ; UI3.14 v1(294.89,69.29) ; PR412.1 106.23,77.84 105.97,77.58 PU401.6 ; UE1.A13 246.62,100.78 246.07,100.78 v1(246.06,100.8) ; CC67.2 171.85,97.69 171.34,97.19 v1(171.34,96.92) ; CR19.1 v1(301.68,28.6) ; 176.51,76.78 v1(176.58,76.72) 176.83,76.97 176.83,80.85 176.58,81.1 v1(174.43,81.1) 174.43,81.6 173.52,82.51 171.71,82.51 171.16,81.96 v1(171.16,81.21) 171.16,78.81 171.32,78.66 171.32,77.57 172.11,76.78 176.51,76.78
  TOP w0.305: UZ19.5 192.32,131.17 192.63,131.48 v1(192.76,131.48) ; v1(196.82,131.39) 196.51,131.09 UZ21.5 ; PU3000.4 71.67,36.03 v1(71.56,36.14) ; v1(172.02,68.75) 172.13,68.64 172.13,67.77 171.83,67.46 UZ27.5 ; v1(237.4,35.55) 238.25,36.4 CZ129.2
  TOP w0.356: v1(291.21,17.92) 291.21,18.93 291.04,19.1 CR25.2 CR26.2 CR3.2 ; CE21.2 v1(259.14,92.97) ; CL9.2 267.2,112.19 v1(267.2,113.17) ; v1(261.67,92.95) 262.19,93.47 CE22.2 ; CZ309.2 280.81,120.85 v1(280.89,120.76) ; v1(80.89,117.17) 81.15,116.91 PU3.3 ; CC1455.2 151.81,79.28 v1(151.77,79.32) ; PR3003.1 76.08,35.57 PC3001.1 ; v1(184.57,41.5) 185.1,40.98 CZ92.2 CZ91.2 ; v1(288.09,49.67) 288.32,49.44 CA55.2 ; PC3008.2 72.74,30.31 v1(73,30.06) ; v1(247.81,41.51) 247.65,41.35 247.65,41.1 247.54,41 CN11.2 CN10.2 ; RC48.2 180.93,73.4 CC93.1 ; v1(287.72,19.61) 287.61,19.72 CR6.2 ; RT393.2 56.88,122.88 CT90.2 ; CZ72.2 227.1,35.42 CZ313.2 ; v1(225.53,86.72) 225.53,86.93 225.33,87.13 CZ115.2 ; v1(132.55,132.08) 132.22,131.74 CA7.2 131.81,131.53 CA75.2 ; CC299.2 89.78,131.46 90.33,132.02 v1(90.41,132.02) 90.61,131.81 90.61,131.14 90.25,130.78 CC288.2 ; v1(63.81,123.33) 63.56,123.07 CT93.2 ; 283.15,80.66 283.21,80.66 283.78,81.23 283.78,81.53 283.79,81.54 CZ217.2 ; CC1456.2 157.7,81.93 v1(158,81.93) ; CT99.2 10.85,105.42 v1(11.17,105.74) 10.92,105.99 CT102.1 ; CZ119.2 274.54,89.23 274.19,89.58 274.19,90 v1(274.25,90.06) ; v1(256.41,32.08) 256.5,32.17 CZ305.2 ; CV12.2 141.96,130.55 CV652.2 ; v1(191.91,96.2) 192.02,96.09 CC77.2 192.55,96.09 CC95.1 ; v1(273.29,54.76) 273.56,54.49 CA60.2 ; CZ303.1 171.92,68.75 v1(172.02,68.75) ; v1(85.12,116.28) 84.88,116.04 PQ1.4 ; CT101.2 CT100.1 11.09,108.09 v1(11.17,108.17) ; CZ52.2 229.59,97.97 CZ51.2 229.59,98.85 v1(229.74,99.01) ; 68,31.58 68,30.26 v1(68.18,30.08) ; CA10.2 v1(281.71,49.13) ; v1(194.16,127.72) 193.91,127.72 193.84,127.8 CZ100.2 ; CE30.2 v1(245.68,104.72) ; CE20.2 v1(252.41,87.96) ; CC25.2 206.05,74.84 CMOS1.2 ; CR7.2 v1(292.92,19.89) ; CE36.2 252.47,83.74 v1(251.48,83.74) ; RC848.1 CC1480.2 ; CZ83.2 188.31,36.04 CZ90.2 ; v1(171.15,106.55) 171.13,106.53 CC1462.2 ; CZ116.2 268.86,63.08 CZ117.2 ; CE52.2 v1(254.82,81.1) ; CZ216.2 v1(279.52,73.35) ; CT89.2 57.72,122.88 v1(58.16,123.33) 58.35,123.14 CT88.2 ; CE23.2 255.07,88.11 v1(254.92,87.96) ; CL7.2 v1(272.73,114.18) ; v1(119.44,75.97) CD32.2 ; CZ105.2 v1(193.35,131.43)
  TOP w0.381: v1(157.5,45.56) 157.5,46.09 CD14.2 ; v1(117.56,124.53) 117.56,124.43 116.14,123 116.14,120.9 CV55.2 ; CA45.2 v1(278.35,56.41) ; v1(144.28,78.97) 144.74,78.51 CC195.2 ; v1(127.34,57.06) 127.48,57.2 CD15.2 ; v1(293.21,26.9) 292.55,27.56 CR2.2 CR27.2 292.2,28.78 ; v1(59.4,105.78) 59.04,106.13 RT377.2 ; 268.41,67 266.47,67 CZ122.2 ; PR302.2 236.39,131.23 236.84,131.67 v1(237.02,131.67) ; v1(120.44,51.66) 120.61,51.83 CD10.2 ; v1(86.95,134.93) 86.95,135.29 RC411.1 ; v1(250.85,36.03) 250.48,36.4 CN3.2 ; v1(176.49,95.27) 176.43,95.22 175.54,95.22 CC65.2 ; v1(109.44,53.76) 109.41,53.79 CD9.2 ; v1(293.87,25.03) 293.99,25.14 CR15.2 ; PC741.2 127.47,41.2 PC728.2 PC730.2 PC732.2 PC734.2 ; v1(134.03,49.5) 133.98,49.5 133.41,48.93 CD11.2 ; CN2.2 248.09,36.4 v1(247.85,36.16) ; v1(41.7,101.13) 41.23,100.66 CT118.2 ; v1(223.56,45.57) 224.1,45.57 CD43.2 ; v1(281.57,117.61) 281.64,117.69 DT41.3 v1(284.08,117.69) ; CC1458.2 v1(114.49,78.31) ; CZ312.2 CZ66.2 227.17,41.32 v1(227.39,41.54) ; v1(248.3,120.49) 248.3,119.41 247.84,118.95 CE63.2 ; PQ806.4 89.35,117.56 v1(89.31,117.6) ; v1(161.89,93) 161.63,93.27 PC1041.2 ; CZ82.2 269.15,94.29 v1(269.15,93.67) ; QE21.1 v1(252.61,114.07) ; CE31.2 253.17,88.02 253.2,87.99 v1(253.2,87.96) ; v1(284.06,120.77) DT42.3 v1(281.58,120.77) ; v1(91.84,79.22) 92.26,79.64 PQ802.1 ; CC96.2 168.92,119.7 CC31.2 170.33,118.88 170.68,118.53 v1(170.68,118.03) ; CA46.2 279.99,49.31 CA47.2 ; v1(231.61,41.5) 231.35,41.25 CZ314.2 ; v1(42.73,89.35) 42.49,89.59 PQ808.4 ; v1(222.25,44.33) 222.25,44.08 221.59,43.43 CD57.2 ; v1(228.3,105.55) 227.99,105.55 CZ50.2 ; v1(193.35,131.43) 193.68,131.76 CZ106.2 ; CA78.2 283.6,60.01 v1(283.26,60.35) 283,60.09 CA77.2 ; CZ53.2 224.21,105.55 223.64,106.12 v1(223.64,106.31) ; v1(274.3,92.78) CZ310.2 ; v1(92.79,116.2) 92.73,116.26 PQ806.1 ; CL11.2 v1(275.24,103.6) ; CZ112.2 223.72,81.81 224.08,81.81 v1(224.11,81.78) 224.14,81.81 224.23,81.81 224.4,81.99 225.05,81.99 225.43,82.37 CZ316.2 ; v1(168.28,121.55) 168.28,122.44 CC80.2 CC69.2 ; CD16.2 127.39,56.18 v1(127.34,56.24) ; v1(300.15,53.11) 300.15,53.11 CI10.2 ; CD72.2 245.77,43.51 v1(246.08,43.83) ; v1(269.04,92.53) 268.93,92.42 UE4.3 ; PQ1.1 86.65,117.55 86.89,117.31 v1(86.89,117.32) ; v1(291.45,114.25) 291.24,114.03 CL19.2 ; CZ311.2 CZ64.2 228.67,41.09 228.91,41.33 v1(228.91,41.51) ; v1(183.76,80.21) 184.06,79.92 CC316.2 ; CL21.2 v1(291.35,108.77) ; CD46.2 214.9,45.41 v1(215.15,45.66) ; v1(221.41,98.47) 220.83,98.47 CZ54.2 ; CZ102.2 168.29,64.53 v1(167.12,65.7) ; CL20.2 v1(291.35,107.5) ; CD47.2 202.43,46.61 v1(202.99,47.17) ; DT39.3 v1(21.33,101.22) ; RD16.2 144.08,43.23 CD25.2 142.9,43.23 CD26.2 ; CC66.2 171.98,102.04 v1(171.94,101.99) ; CE53.2 v1(270.09,91.68) ; CZ313.2 CZ67.2 ; v1(168.72,86.39) 168.72,84.74 169.63,83.83 RC848.1 ; CZ101.2 v1(199.51,133.53) ; CD13.2 125.2,49.83 v1(125.21,49.82) ; v1(48.81,87.13) PQ811.1 ; CD42.2 222.33,52.27 v1(222.35,52.25) ; CD24.2 CD23.2 CD71.2 244.88,43.68 v1(245.23,44.03) ; v1(283.21,22.04) 283.07,21.91 283.07,21.19 CN82.2 ; v1(296.35,21.16) 296.35,21.66 295.97,22.04 CR22.2 ; CD48.2 213.23,49.08 v1(213.26,49.05) ; CC24.2 174.09,73.77 173.85,73.53 CC73.2 174.07,73 v1(174.77,73) ; v1(230.82,41.5) 230.75,41.44 CZ68.2 ; CL17.2 v1(291.35,101.15) ; CD45.2 197.5,47.95 v1(197.34,47.79) ; v1(308.41,6.93) 309.09,6.93 CZ93.2 ; 300.92,21.28 299.86,21.28 v1(299.78,21.36) ; RC165.2 v1(105.62,81.82) ; QN1.1 252.87,34.92 v1(252.28,34.34) ; CZ120.2 279.27,64.21 280.04,63.43 CA66.2 ; v1(302.7,18.36) 302.48,18.58 CR17.1 ; CZ73.2 229.99,41.44 v1(230.06,41.5) ; CD12.2 135.69,48.06 v1(136.37,48.73) ; RE93.2 246.08,108.28 245.9,108.46 v1(245.89,108.46) ; PC1147.2 PC1146.2 ; CL8.2 CL10.2 265.49,106.08 264.77,106.08 v1(264.6,106.25) ; v1(193.86,100.91) 193.75,100.8 RC397.2 ; PQ808.1 41.19,88.96 v1(41.33,89.1) ; QE21.4 v1(254.51,109.28) ; CL4.2 273.02,98.97 CL3.2 ; CD18.2 v1(168.33,51.89) ; v1(127.22,77.19) 127.16,77.19 127.09,77.26 UD1.3 ; CL16.2 v1(291.35,99.88) ; v1(43.11,88.28) PQ809.1 ; CD19.2 v1(167.44,51.89)
  TOP w0.406: QN1.4 251.57,33.82 252.09,34.34 v1(252.28,34.34) ; v1(231.2,134.86) 230.94,134.6 PC312.1 ; v1(307.02,6.04) 306.78,6.28 UZ10.3 ; QE2.4 251.76,74.85 v1(251.85,74.94) ; v1(219.51,79) 219.69,79.17 UC7.3 ; UZ51.2 v1(280.64,77.48) ; UZ35.3 193.24,124.38 193.65,123.97 v1(193.74,123.97) ; PQ3000.4 v1(71.47,30) ; v1(266.94,93.78) UZ41.3 ; RE718.1 255.28,77.47 254.96,77.78 UE5.3 ; v1(273.21,92.06) 273.1,92.06 272.75,92.42 UE3.3 ; v1(253.09,75.29) 253.06,75.33 QE2.1 ; v1(94.12,80.82) 94.31,81.01 PQ802.4
  TOP w0.457: v1(226.46,41.54) 226.17,41.54 225.84,41.21 CZ71.2 ; v1(164.29,81.9) 164.6,81.9 164.93,81.56 CC38.2 CC35.2 164.82,79.36 v1(164.29,79.36) ; CN88.2 262.56,36.99 262.45,37.09 v1(262.45,37.36) 262.88,37.79 CN89.2 ; PC1099.2 164.58,118.25 v1(164.58,118.02) ; CC85.2 CC86.2 172.33,119.75 v1(171.7,120.38) ; RR4.2 285.31,21.03 284.86,21.49 v1(284.86,21.7) ; CR4.2 287.76,18.3 287.72,18.34 v1(287.72,18.82) ; v1(316.35,16.4) 316.35,17.47 316.65,17.77 JSD1.20 ; v1(61.07,108.65) 61.34,108.91 CT82.2 ; QV2.3 126.01,133.44 v1(126.06,133.48) 126.14,133.4 RV802.2 126.67,134.12 CV14.2 ; RC49.2 176.18,116.82 176.82,116.82 RC47.2 176.93,116.93 177.94,116.93 v1(178.26,116.61) ; RC107.2 175.82,94.45 v1(175.84,94.44) ; CA61.2 v1(282,47.14)
  TOP w0.508: CC280.2 183.61,74.06 v1(183.85,74.29) 183.99,74.44 CC1471.2 RC761.2 ; RE717.1 262.59,97.99 v1(263.07,97.51) 262.67,97.1 CE66.2 ; JSD1.6 303.68,18.36 303.61,18.3 v1(303.4,18.3) ; v1(256.41,32.08) 256.21,31.87 CZ306.2 ; v1(190.34,38.25) 190.57,38.25 CZ81.2 ; CZ124.2 274.86,90.06 v1(274.25,90.06) ; CC234.2 v1(112.71,78.81) ; v1(192.72,45.84) 192.76,45.79 CD44.2 ; v1(151.37,43.02) 151.26,43.13 PD2.1 ; v1(296.82,79.88) 296.98,80.05 RV303.2 ; CN93.2 263.1,38.75 v1(262.97,38.62) ; DA6.1 289.75,32.71 290.25,32.2 v1(290.41,32.2) ; UV24.2 150.93,134.69 151.44,135.2 v1(151.44,136.34) ; PQ809.4 45.03,90.51 44.76,90.78 v1(44.76,91.01) ; RC86.2 128.44,115.71 126.66,115.71 125.89,116.47 v1(125.89,117.1) ; v1(89.34,132.52) 89.34,132.67 89.59,132.92 CC334.2 ; RT101.2 59.95,104.91 59.51,105.34 59.51,105.67 v1(59.4,105.78) ; CZ320.2 281.24,88.25 v1(281.72,87.77) 282.18,88.22 CZ321.2 ; RZ1450.2 v1(273.68,86.05) ; v1(196.53,107.45) 194.69,105.61 193.18,105.61 RC2.1 ; CZ113.2 CZ114.2 CZ315.2 221.82,86.6 v1(221.26,86.6) ; RA45.2 289.05,44.65 288.98,44.59 v1(288.98,44.35) ; CR20.1 v1(300.92,28.71) ; DI2.1 v1(26.98,89.86) ; CMOS1.2 207.28,74.84 v1(207.54,75.1) ; v1(143.09,48.36) 143.06,48.32 CD7.2 ; v1(137.73,124.56) 137.25,124.09 QV21.3 ; CZ319.2 CZ318.2 CZ317.2 262.36,57.58 v1(262.5,57.72) ; CE61.2 264.55,92.1 264.03,91.58 v1(263.71,91.58) ; v1(278.32,48.65) CA46.2 ; CZ80.2 193.42,38.61 193.35,38.67 v1(193.35,39.05) ; CC332.2 CC333.2 ; CC332.2 167.86,75.29 167.35,75.8 v1(167.27,75.8) ; CC332.2 CC331.2 ; v1(277.39,24.76) 277.03,24.41 CN80.2 ; RD23.2 RD21.2 243.07,45.5 v1(242.36,45.5) ; v1(53.24,101.73) 54.31,101.73 RT81.2 ; v1(302.19,17.85) 301.8,17.85 CR18.1 ; CV313.2 v1(292.27,80.52) ; CE47.2 259.14,108.86 v1(258.47,108.18) ; CZ27.2 270.43,40.13 CZ28.2 271.34,40.27 v1(272,40.27) ; v1(158.39,50.14) 158.36,50.11 CD2.2 ; v1(239.15,109.59) 239.2,109.64 CZ218.2 ; 274.12,52.27 274.12,52.72 v1(273.87,52.97) ; v1(184.61,128.75) 183.89,128.03 CC71.2 ; v1(195.47,74.31) 195.68,74.51 RC230.2 ; PC360.2 v1(236.22,133.75) ; RE58.2 RE55.2 241.07,87.13 v1(240.79,86.85) ; RC237.2 221.26,80.06 v1(220.76,80.06) ; CL30.2 v1(269.17,100.15) ; QE12.3 249.63,107.21 v1(249.36,106.94) ; RC234.2 CC1470.2 190.91,74.65 v1(191.19,74.37) ; PC13.1 78.81,114.56 PR45.2 79.94,114.29 79.94,114.13 v1(80.2,113.87) ; v1(266.6,113.1) 266.02,112.53 CL12.2 ; RZ334.2 298.83,20.39 v1(299.19,20.75) ; PC1170.2 167.22,135.24 v1(166.61,135.24) 165.66,135.24 165.28,134.87 PC1169.2 ; PC618.1 v1(80.92,98.52) ; RZ1399.2 282.44,77.67 v1(282.13,77.35) 282.13,76.93 282.6,76.46 QZ19.3 ; CE28.2 243.23,88.36 243.96,89.1 v1(243.96,89.16) 243.96,89.35 244.97,90.35 v1(245.41,90.35) ; CT45.2 CT626.2 38.95,102.56 v1(39.06,102.68) ; CR5.2 v1(292.74,17.93) ; v1(187.45,41.5) 187.38,41.44 CZ86.2 ; CC1454.2 146.46,80.11 v1(146.64,80.29) ; v1(218.39,102.54) 218.3,102.54 217.79,102.04 CZ56.2 ; CC1465.2 RC229.2 197.82,74.83 197.82,74.47 v1(198.02,74.27) ; CC34.2 CC33.2 157.98,80.04 v1(158,80.03) ; CD5.2 102.25,49.54 v1(102.23,49.56) ; v1(87.22,64.87) 87.56,65.21 PR207.2 ; v1(258.69,87.45) 258.63,87.51 RE20.2 RE550.2 ; v1(97.91,128.41) 98.05,128.27 CV632.2 RV624.2 ; PD4.1 72.96,120.03 72.77,119.83 v1(72.77,119.52) ; v1(193.93,71.14) 193.93,70.46 QC6.3 ; RC151.2 154.74,114.63 155,114.37 v1(155,114.25) ; RC452.1 RC536.2 177.54,76.52 v1(177.54,75.89) ; CC305.2 137.35,118.06 v1(136.84,118.57) 136.46,118.18 RC139.2 ; PQ13.3 v1(241.85,124.56) ; v1(295.33,115.77) 295.91,115.2 DZ11.1 ; v1(213.26,44.47) 213.45,44.28 CD37.2 ; v1(263.29,96.8) 263.54,97.06 263.97,97.06 CE68.2 ; CC51.2 v1(113.72,78.81) ; CZ39.2 297.47,22.17 296.98,21.68 v1(296.98,21.18) 296.98,20.57 CR21.2 ; SW3.1 313.62,115.62 v1(313.62,115.24) ; CC320.2 v1(197.9,102.41) ; v1(191.91,96.2) 190.97,96.2 RC756.2 ; v1(72.96,103.2) PR862.2 ; PC425.2 PC426.2 111.18,71.19 v1(110.87,70.88) ; v1(138.92,82.27) 138.92,81.57 CC1478.2 ; v1(139.38,132.15) 139.05,132.48 RV2.2 ; CC32.2 148.3,78.45 v1(148.34,78.49) ; CA56.2 v1(288.03,47.57) ; CV21.2 v1(143.95,136.19) ; PC407.2 v1(108.77,70.43) ; v1(291.73,49.02) CA72.2 RA51.2 ; PR3003.1 v1(77.11,35.93) ; PC11.2 75.24,115.39 v1(75.18,115.33) ; RL12.2 272.04,114.23 v1(271.97,114.31) ; CL14.2 276.74,100.39 276.74,100.4 v1(276.74,101.36) 276.81,101.36 277.33,101.87 277.33,102.61 RL13.2 ; QR1.3 293.67,27.36 v1(293.21,26.9) ; CN92.2 264.09,39.66 CN94.2 263.74,40.56 263.42,40.24 v1(262.92,40.24) ; PR725.2 v1(83.77,52.4) ; CN63.2 v1(279.96,23.84) ; v1(316.67,21.03) 316.68,21.03 317.2,20.5 JSD1.17 ; v1(134.34,125.07) 134.34,122.96 133.46,122.08 CZ220.2 ; RE541.1 CE64.2 v1(240.9,119.5) 240.81,119.42 PC3.2 ; v1(120.42,121.2) 120.42,120.99 CV54.2 ; RD9.2 144.8,46.13 145.2,45.73 v1(145.2,45.47) ; RC122.2 v1(73.66,136.47) ; v1(276.23,56.6) CA63.2 CA64.2 ; v1(277.36,58.3) 277.54,58.3 RA36.2 ; CV16.2 v1(144.84,136.19) ; v1(82.74,100.39) 83,100.12 PC621.1 ; CT117.2 38.43,104.89 CT46.2 38.54,104.23 v1(39.06,104.23) ; QV19.3 96.44,129.17 96.02,128.75 v1(96.02,128.42) ; RV305.2 v1(293.94,82.05) ; CN60.2 278.87,24.33 v1(278.46,24.74) 277.93,24.22 CN62.2 ; CZ117.2 v1(268.85,62.46) ; DA7.1 v1(285.81,31.82) ; CE65.2 v1(243.14,121.28) ; v1(134.03,52.55) 133.76,52.55 133.06,53.25 CD4.2 ; v1(245.06,63.05) 244.77,63.34 PR514.2 ; CV310.2 297.87,80.37 v1(298.38,79.86) 298.76,80.24 CV314.2 ; CV20.2 143.06,136.06 v1(143.19,136.19) ; CD3.2 116.67,56.48 v1(116.45,56.25) ; PC1006.2 v1(122.74,112.6) ; v1(41.7,104.23) 42.65,105.18 CT612.2 CT627.2 ; v1(138.43,136.58) 138.07,136.22 RV1.2 ; v1(129.6,41.2) PC741.2 ; CV652.2 142.55,129.89 v1(142.54,129.87) 143.04,129.36 CV651.2 ; CA66.2 280.37,63.19 280.75,62.81 v1(280.75,62.43) 280.62,62.3 CA65.2 ; v1(240.83,49.35) 240.6,49.59 CD34.2 ; CZ110.2 274.32,91.96 v1(274.19,91.83) 274.19,91.58 274.7,91.07 CZ109.2 ; CD39.2 235.94,46.09 v1(235.89,46.14) ; v1(41.7,105.78) 41.7,108.19 CT610.2 42.21,108.28 CT611.2 ; RA35.2 v1(291.83,44.4) ; PC604.2 93.71,101.12 94.19,100.63 v1(94.19,100.47) ; PR311.2 v1(233.48,135.27) ; PC315.2 PC316.2 PC317.2 PC334.2 233.24,118.12 v1(233.61,118.49) ; v1(292.53,92.5) 292.25,92.23 CV311.2 ; RE718.1 v1(256.03,77.04) ; RD18.2 138.06,44.78 v1(138.06,45.41) ; DA1.1 299.4,32.52 v1(298.89,32.01) ; v1(97.15,93.86) 97.43,94.14 PC652.2 97.4,94.61 PC601.2 ; PC3002.2 70.42,32.64 v1(69.57,32.64) PQ3000.1 ; CZ75.2 v1(226.88,106.51) ; CE8.2 263.66,103.07 v1(264.1,103.07) RL9.2 ; SW3.3 v1(309.32,116.15) ; v1(170.68,78.02) 169.59,79.11 RC231.2 CC1468.2 169.59,81.16 CC322.2 ; CT22.2 67.75,99.64 v1(68.12,100.02) ; v1(170.09,91.73) 169.47,91.73 RC7.2 ; v1(278.34,47.95) 279.36,46.94 CA31.2 ; v1(122.41,126.44) 122.41,124.86 CA6.2 ; CE29.2 v1(242.92,91.73) ; v1(197.36,97.08) 197.41,97.03 RC832.2 ; CV308.2 290.75,79.3 v1(290.75,78.76) ; RC413.1 79.69,132.22 v1(79.28,132.63) 78.93,132.28 RC412.1 ; PR416.2 v1(101.79,80.59) ; PC401.2 v1(110.42,77.29) ; RC732.1 v1(148.64,114.82) ; PR420.2 v1(212.4,126.39) ; DV14.1 138.15,127.2 v1(138.35,127.4) ; CD58.2 v1(220.7,44.14) 220.56,44.14 219.88,43.46 RD29.2 ; RD31.2 216.45,44.98 v1(216.39,44.93) ; v1(41.7,102.68) 41.96,102.93 CT628.2 ; CL18.2 290.41,113.9 290.15,114.16 v1(290.15,114.41) ; CN77.2 269.02,25.87 268.41,26.48 v1(268.41,26.74) ; CD36.2 v1(215.8,52.41) ; CD22.2 242.02,43.72 241.49,44.26 v1(241.47,44.26) 240.82,43.61 CD66.2 239.7,43.49 CD77.2 ; PC411.2 209.42,135.14 v1(209.81,135.53) 210.31,135.03 PR407.2 ; v1(227.22,34.59) CZ72.2 ; RZ10.1 225.59,35.05 v1(225.6,35.04) ; v1(294.37,92.5) CV309.2 294.39,91.84 RV737.2 RV209.2 ; UZ54.3 260.35,39.4 260.85,39.9 v1(260.85,40.27) 260.29,40.27 RZ1472.1 ; RT138.2 RT136.2 v1(46.99,111.01) ; CA62.2 289.94,44.63 v1(289.66,44.35) 289.87,44.13 RZ752.2 ; v1(187.38,35.81) CZ83.2 ; v1(75.62,122.31) 75.37,122.57 PR8.2 75.43,122.99 PQ3.3 ; PC313.2 230,134.59 v1(229.39,134.59) ; YL1.4 v1(276.04,96.97) ; v1(247.67,85.43) 247.67,85.43 247.67,85.39 247.12,84.83 CE62.2 ; v1(155.25,135.59) 154.79,135.13 CV17.2 RV3.1 ; CC1469.2 RC233.2 187.36,74.55 v1(187.18,74.37) ; v1(297.62,61.86) 298.15,62.39 DI5.1 ; CC102.2 173.07,122.21 v1(172.93,122.07) ; PR3008.1 67.1,33.03 PC3004.1 67.14,32.56 v1(67.33,32.37) ; PC406.2 v1(110.04,70.43) ; PR514.2 PC513.2 ; PR514.2 CZ58.2 ; PC1.2 139.75,40.79 v1(139.25,41.29) ; v1(41.26,96.01) 41.26,96.35 40.9,96.71 RT130.2 ; v1(199.03,106.63) 199.03,106.46 197.37,104.8 CC318.2 ; v1(221.39,97.59) 219.96,97.59 CZ55.2 ; CC41.2 v1(111.69,78.81) ; RE716.1 266.9,98.18 v1(266.9,98.69) ; RL3.2 269.63,98.3 v1(269.17,98.75) ; v1(125.15,123.62) 125.15,123.95 125.37,124.17 CA5.2 ; v1(185.39,52.28) 186.05,52.94 CD41.2 ; v1(146.49,114.5) 146.49,115.63 145.83,116.29 RC109.2 RC108.2 RC419.1 ; CZ84.2 183.32,40.79 v1(182.6,41.5) ; CD35.2 181.32,45.98 v1(181.48,46.14) ; v1(196.96,52.23) 197.45,51.74 CD33.2 ; v1(163.56,115.19) 164.02,115.19 RC164.2 ; YL1.2 274.43,98.83 v1(273.93,99.32) 273.93,99.91 CL13.2 ; CC23.2 174.03,78.4 v1(174.59,78.96) 174.03,79.52 CC26.2 ; CC303.2 133.23,115.52 v1(133.41,115.52) 133.84,115.95 CC304.2 ; CD76.2 163.32,48.65 v1(162.75,48.08) ; v1(260.69,36.17) 260.69,35.67 CN87.2 ; v1(189.57,74.37) 190.02,74.82 CC1467.2 RC232.2 ; CD6.2 141.16,48.14 v1(141.41,48.4) ; v1(151.77,78.03) 152.18,77.62 CC46.2 CC45.2 ; PD1.1 v1(150.05,41.09) ; CE60.2 CE16.2 246.76,83.89 v1(246.73,83.92) ; v1(261.67,92.95) 261.08,92.95 RE342.2 ; v1(98.36,97.56) 98.08,97.28 PC649.2 ; RZ40.1 v1(283.32,91.89) ; CL29.2 v1(273.49,114.3) ; PR9.2 v1(237.61,121.65) ; CV635.2 121.58,136.15 v1(122.14,135.59) ; v1(112.07,133.3) 111.88,133.49 111.88,134.06 111.63,134.31 RV319.1 ; CA48.2 277.3,57.16 v1(277.36,57.22) ; PR658.1 81.94,92.44 v1(82.1,92.28) 82.55,92.28 PC641.2 ; CZ87.2 v1(188.27,41.5) ; RV175.2 v1(294.95,82.04) ; CN75.2 248.28,31.43 CN1.2 247.84,32.2 v1(247.58,31.95) ; PC654.1 92.55,89.84 PC645.2 v1(93.25,89.89) ; v1(39.06,105.78) 39.06,108.24 CT625.2 CT44.2 ; v1(269.95,38.14) 269.63,38.14 CN90.2 268.94,38.82 CN95.2 268.96,39.73 CN91.2 ; CZ200.2 278.44,122.36 v1(278.61,122.53) ; v1(196.98,82.8) 197.07,82.71 RC868.1 ; PQ814.3 91.39,79.67 v1(91.84,79.22) ; UT7.2 56.57,120.24 56.07,119.74 v1(55.21,119.74) ; RC48.2 v1(180.52,72.78) ; v1(228.26,41.5) 227.94,41.18 CZ69.2 ; v1(144.77,130.02) 144.84,129.96 RV629.2 ; CZ130.2 240.44,38.52 240.1,38.86 v1(240.1,39.84) ; v1(211.43,48.55) 211.26,48.55 210.75,49.06 CD40.2 ; CA54.2 283.84,45.35 v1(284.28,44.9) 284.79,45.41 CA33.2 ; v1(136.26,136.58) 135.9,136.22 CV15.2 ; v1(42.16,110.69) 41.79,110.32 CT629.2 CT47.2 ; CZ85.2 186.49,41.31 v1(186.69,41.5) ; v1(189.35,41.5) 189.16,41.31 CZ88.2 ; PC603.2 91.33,103.11 91.3,103.15 v1(91.3,104.18) ; RC752.2 RC640.1 191.57,93.21 191.57,92.9 191.5,92.83 191.5,91.97 191.85,91.62 v1(191.99,91.62) ; PC605.1 83.62,102.99 v1(83.62,103.71) ; CL28.2 270.57,100.28 269.77,99.48 v1(269.17,99.48) ; v1(67.93,118.5) PC10.2 PC12.2 ; v1(283.65,87.79) 283.65,87.95 CZ322.2 ; PC644.2 v1(97.13,100.53) ; CC269.2 87.82,133.15 87.6,132.94 87.01,132.34 86.99,132.34 86.94,132.29 v1(86.88,132.29) 86.75,132.42 86.75,133.17 CC307.2 ; DT4.1 v1(24.8,96.86) ; v1(173.95,95.25) 173.95,95.25 173.5,95.25 172.92,94.67 RC106.2 ; v1(68.09,102.82) CT76.2 ; CE3.2 v1(258.63,84.99) ; v1(126.7,45.57) 126.7,46.08 CD61.2 ; PQ812.3 49.09,85.78 v1(48.57,86.31) ; CC279.2 v1(184.82,73.89) ; CZ63.2 230.04,35.52 v1(230.54,35.02) 230.93,35.42 CZ62.2 ; PQ6.3 80.87,120.51 v1(80.58,120.8) ; v1(300.11,23.79) 300.25,23.79 300.41,23.63 CZ37.2 CZ41.2 ; PC619.1 80.92,94.78 80.77,94.63 v1(80.77,94.56) ; RE65.2 245.61,106.75 v1(245.41,106.55) 245.41,106.28 JTAG1.2 ; CC104.2 171.12,122.32 v1(171.12,122.08) ; CZ121.2 v1(274.81,64.08) ; PC651.1 89.86,88.19 89.04,87.36 v1(88.27,87.36) ; v1(86.48,87.91) 86.38,88.01 PC625.1 PR629.1 ; RC414.1 80.45,132.22 v1(80.83,132.6) 81.21,132.22 RC415.1 ; RI14.1 v1(297.37,70.3) ; RC236.2 v1(76.13,132.73) ; PR310.2 v1(235.14,135.3) ; DZ10.1 117.66,124.43 v1(117.56,124.53) ; CA53.2 v1(285.87,47.57) ; v1(276.36,69.64) CZ197.2 ; CN86.2 281.78,24.13 CN64.2 282.5,24.84 v1(283.03,24.84) ; v1(193.19,71.19) 193.04,71.19 192.83,71.4 CC340.2 ; CT615.2 39.61,100.58 v1(39.06,101.13) 38.45,101.13 CT616.2 ; v1(220.01,81.07) 219.98,81.1 CC196.2 219.35,81.05 RC65.2 ; v1(169.93,70.88) 170.31,70.88 170.59,71.17 CC27.2 ; RE85.2 250.76,107.33 v1(251.14,106.94) ; v1(255.31,84.97) 255.07,85.2 CE4.2 RE313.2 ; PC402.2 PR403.2 ; RC53.2 RC833.2 194.11,78.23 v1(193.68,77.8) ; v1(197.54,89.48) 197.54,91.16 UC9.3 ; PC1003.2 v1(122.74,111.33) ; v1(57.08,123.64) 56.95,123.52 RT393.2 ; v1(299.94,90.94) CV312.2 ; QV7.3 115.02,133.37 v1(114.89,133.37) ; v1(183.57,135.92) 183.44,135.79 PC685.2 ; CT48.2 38.79,110.06 v1(38.29,110.56) ; CE59.2 247.26,82.12 246.76,81.61 v1(246.76,81.29) ; CZ57.2 v1(238.73,63.19) ; RC220.2 CC266.2 v1(192.82,74.37) ; RV307.2 v1(295.97,82.05) ; PR427.2 v1(105.34,80.59) ; v1(299.33,55.53) 299.33,55.53 UI2.2 ; CD38.2 208.89,43.75 v1(208.89,44.73) ; v1(114.81,50.6) 115.43,49.98 CD8.2 ; v1(190.3,41.5) 190.3,41.22 190.05,40.97 CZ89.2 ; v1(86.57,112.28) 87.81,113.52 PC865.2 ; v1(48.18,92.23) PC810.2 ; CE40.2 250.76,105.8 v1(250.39,106.16) ; v1(268.46,70.67) 268.46,71.4 268.36,71.5 RZ38.1 ; RD25.2 v1(223.32,41.53) ; PQ811.4 50.11,90.39 51.3,91.58 v1(51.3,92.21) ; CL4.2 272.71,97.93 v1(273.87,97.93) ; v1(122.68,127.11) DV13.1 ; PC743.2 131.14,36.76 v1(131.06,36.84) ; v1(82.99,101.47) 83.31,101.47 84.58,100.2 PR613.1 PC613.1 86.2,100.66 PR693.1 ; CN84.2 v1(264.22,26.11) ; JSD1.14 v1(316.41,23.57) ; v1(155.2,80.72) 155.18,80.7 CC1479.2 ; RA52.1 v1(283.01,44.9) ; CN61.2 v1(269.44,24.22) ; v1(68.09,101.04) CT75.2 ; v1(277.38,59) 277.92,59 CA69.2 ; RD16.2 144.73,42.9 146.16,44.33 146.16,45.04 145.85,45.34 v1(145.85,45.47) ; v1(247.61,37.48) 247.4,37.27 RN5.2 ; RN19.2 v1(255.84,47.76) ; RA37.2 v1(285.24,63.07) ; RZ25.2 v1(246.39,111.96) ; CZ118.2 v1(267.94,62.44) ; v1(283.6,80.21) 283.15,80.66 RZ1406.2 ; v1(82.46,58.76) DE22.1 ; PC647.2 v1(88.03,88.34) ; CD29.2 v1(203.83,44.9) ; PC737.1 v1(79.01,43.13) ; QE17.3 v1(245.17,122.11) ; PR415.2 v1(104.45,80.59)
  GND1 w0.203: JSD1.12 317.85,27.79 ; JSD1.12 316.72,27.06 ; JSD1.12 317.85,26.34 ; JSD1.12 316.72,27.79 ; JHDMI1.22 313.6,94.88 ; JHDMI1.22 315.18,94.88 ; JHDMI1.22 315.18,93.9 ; JHDMI1.22 312.02,93.9 ; JHDMI1.22 312.02,94.88 ; 313.52,13.46 JSD1.13 ; JSD1.13 314.65,12.74 ; JSD1.13 314.65,14.19 ; JSD1.13 313.52,12.74 ; JSD1.13 315.79,14.19 ; JSD1.13 313.52,14.19 ; JSD1.13 315.79,12.74 ; JSD1.13 315.79,13.46 ; JLOM1.12 309.5,112.67 ; JLOM1.12 308.13,112 ; JLOM1.12 310.88,112 ; JLOM1.12 308.13,112.67 ; JLOM1.12 310.88,112.67 ; JLOM1.12 308.13,111.33 ; JLOM1.12 309.5,111.33 ; JLOM1.12 310.88,111.33 ; 14.35,97.1 JUSB2.10 ; JUSB2.10 14.35,97.93 ; JUSB2.10 17.09,97.93 ; JUSB2.10 14.35,96.27 ; JUSB2.10 15.72,96.27 ; JUSB2.10 17.09,97.1 ; JUSB2.10 15.72,97.93 ; H8.1 283.98,67.05 ; H8.1 280.46,65.56 ; H8.1 283.44,65.56 ; H8.1 280.46,68.54 ; H8.1 281.95,69.08 ; H8.1 279.92,67.05 ; H8.1 281.95,65.02 ; H8.1 283.44,68.54 ; 305.44,85.69 JHDMI1.8 ; JHDMI1.8 306.36,85.69 ; JHDMI1.8 305.44,86.6 ; JHDMI1.8 306.47,86.15 ; JHDMI1.8 305.33,86.15 ; JHDMI1.8 306.36,86.6 ; 314.93,112 JLOM1.11 ; JLOM1.11 317.68,112 ; JLOM1.11 317.68,111.33 ; JLOM1.11 316.3,112.67 ; JLOM1.11 317.68,112.67 ; JLOM1.11 314.93,111.33 ; JLOM1.11 314.93,112.67 ; JLOM1.11 316.3,111.33 ; 249.46,121.59 SW1.4 ; SW1.4 250.98,121.59 ; SW1.4 251.22,120.83 ; SW1.4 250.22,119.82 ; SW1.4 250.22,121.83 ; SW1.4 249.22,120.83 ; SW1.4 250.98,120.07 ; SW1.4 249.46,120.07 ; 150.64,129 H12.1 ; H12.1 154.25,130.52 ; H12.1 151.2,130.52 ; H12.1 152.72,126.92 ; H12.1 151.2,127.48 ; H12.1 152.72,131.08 ; H12.1 154.81,129 ; H12.1 154.25,127.48 ; H4.1 194.29,88.27 ; H4.1 190.1,86.5 ; H4.1 190.76,84.73 ; H4.1 190.76,88.27 ; H4.1 192.52,88.93 ; H4.1 194.29,84.73 ; H4.1 192.52,84.07 ; H4.1 194.95,86.5 ; SW1.5 250.22,115.53 ; SW1.5 250.98,113.77 ; SW1.5 250.98,115.29 ; SW1.5 249.22,114.53 ; SW1.5 251.22,114.53 ; SW1.5 249.46,115.29 ; SW1.5 249.46,113.77 ; SW1.5 250.22,113.52 ; 5.33,102.1 JUSBC1.6 ; JUSBC1.6 6.77,104.11 ; JUSBC1.6 6.77,102.1 ; JUSBC1.6 6.05,102.1 ; JUSBC1.6 6.05,104.11 ; JUSBC1.6 5.33,104.11 ; JUSBC1.2 7.98,111.52 ; JUSBC1.2 7.98,110.74 ; JUSBC1.2 5.32,112.29 ; JUSBC1.2 5.32,111.52 ; JUSBC1.2 7.98,112.29 ; JUSBC1.2 6.65,112.29 ; JUSB2.4 16.72,87.8 ; JUSB2.4 16.12,86.42 ; JUSB2.4 15.52,86.6 ; JUSB2.4 16.9,87.2 ; JUSB2.4 15.34,87.2 ; JUSB2.4 15.52,87.8 ; JUSB2.4 16.72,86.6 ; JUSB2.4 16.12,87.98 ; 5.8,99.23 JUSB2.11 ; JUSB2.11 8.54,99.23 ; JUSB2.11 8.54,98.4 ; JUSB2.11 5.8,98.4 ; JUSB2.11 7.17,99.23 ; H15.1 301.52,122.08 ; H15.1 303.61,120 ; H15.1 300,121.52 ; H15.1 301.52,117.92 ; H15.1 300,118.48 ; H15.1 299.44,120 ; H15.1 303.05,118.48 ; H15.1 303.05,121.52 ; 306.99,81.19 JHDMI1.17 ; JHDMI1.17 307.91,82.1 ; JHDMI1.17 306.99,82.1 ; JHDMI1.17 307.91,81.19 ; JHDMI1.17 308.02,81.65 ; JHDMI1.17 306.88,81.65 ; 313.61,5.42 H13.1 ; H13.1 316.44,5.42 ; H13.1 316.96,4 ; H13.1 316.44,2.58 ; H13.1 315.03,5.93 ; H13.1 313.09,4 ; H13.1 315.03,2.07 ; H13.1 313.61,2.58 ; 303.92,27.79 JSD1.11 ; JSD1.11 306.19,26.34 ; JSD1.11 306.19,27.79 ; JSD1.11 305.06,27.79 ; JSD1.11 306.19,27.06 ; JSD1.11 303.92,27.06 ; JSD1.11 303.92,26.34 ; JSD1.11 305.06,26.34 ; 307.3,76.92 JHDMI1.21 ; JHDMI1.21 308.88,76.92 ; JHDMI1.21 305.72,78.88 ; JHDMI1.21 305.72,77.9 ; JHDMI1.21 305.72,76.92 ; JHDMI1.21 307.3,78.88 ; H29.1 291.02,122.93 ; H29.1 292.79,122.27 ; H29.1 291.02,118.07 ; H29.1 292.79,118.73 ; H29.1 289.26,118.73 ; H29.1 288.6,120.5 ; H29.1 293.45,120.5 ; H29.1 289.26,122.27 ; 301.96,42.8 JUSB3.10 ; JUSB3.10 303.33,43.63 ; JUSB3.10 301.96,41.97 ; JUSB3.10 304.7,42.8 ; JUSB3.10 301.96,43.63 ; JUSB3.10 304.7,43.63 ; JUSB3.10 303.33,41.97 ; JUSB3.10 304.7,41.97 ; JUSB1.10 304.7,59.17 ; JUSB1.10 303.33,60.83 ; JUSB1.10 301.96,60.83 ; JUSB1.10 304.7,60 ; JUSB1.10 303.33,59.17 ; JUSB1.10 301.96,59.17 ; JUSB1.10 304.7,60.83 ; JUSB1.10 301.96,60 ; 157.82,137.7 H17.1 ; H17.1 161.86,136 ; H17.1 159.52,138.34 ; H17.1 161.23,134.3 ; H17.1 161.23,137.7 ; H17.1 157.82,134.3 ; H17.1 159.52,133.66 ; H17.1 157.19,136 ; 305.72,92.4 JHDMI1.20 ; JHDMI1.20 307.3,93.38 ; JHDMI1.20 305.72,91.42 ; JHDMI1.20 308.88,93.38 ; JHDMI1.20 307.3,91.42 ; JHDMI1.20 305.72,93.38 ; 6.65,102.1 JUSBC1.4 ; JUSBC1.4 5.32,102.1 ; JUSBC1.4 5.32,102.88 ; JUSBC1.4 7.98,102.88 ; JUSBC1.4 7.98,102.1 ; JUSBC1.4 7.98,103.65 ; JHDMI1.2 306.36,89.6 ; JHDMI1.2 306.47,89.15 ; JHDMI1.2 306.36,88.69 ; JHDMI1.2 305.9,89.72 ; JHDMI1.2 305.33,89.15 ; JHDMI1.2 305.44,89.6 ; JHDMI1.2 305.44,88.69 ; JUSB1.12 313.25,74.93 ; JUSB1.12 310.51,74.93 ; JUSB1.12 310.51,74.1 ; JUSB1.12 313.25,74.1 ; JUSB1.12 311.88,74.93 ; JLOM1.9 310.88,95.03 ; JLOM1.9 309.5,96.37 ; JLOM1.9 308.13,96.37 ; JLOM1.9 309.5,95.03 ; JLOM1.9 308.13,95.7 ; JLOM1.9 310.88,95.7 ; JLOM1.9 310.88,96.37 ; JLOM1.9 308.13,95.03 ; JUSB3.12 313.25,56.9 ; JUSB3.12 310.51,56.9 ; JUSB3.12 311.88,57.73 ; JUSB3.12 313.25,57.73 ; JUSB3.12 310.51,57.73 ; H1.1 130.95,111.5 ; H1.1 126.76,113.27 ; H1.1 126.76,109.73 ; H1.1 126.1,111.5 ; H1.1 130.29,113.27 ; H1.1 128.53,113.93 ; H1.1 128.53,109.07 ; H1.1 130.29,109.73 ; H18.1 69.52,135.73 ; H18.1 69.52,132.27 ; H18.1 67.8,134 ; H18.1 70.8,135.27 ; H18.1 68.25,135.27 ; H18.1 68.25,132.73 ; H18.1 70.8,132.73 ; H18.1 71.25,134 ; 1.75,80.77 H30.1 ; H30.1 4.3,78.23 ; H30.1 3.02,81.23 ; H30.1 1.3,79.5 ; H30.1 4.75,79.5 ; H30.1 1.75,78.23 ; H30.1 3.02,77.77 ; H30.1 4.3,80.77 ; 314.93,95.7 JLOM1.10 ; JLOM1.10 314.93,96.37 ; JLOM1.10 314.93,95.03 ; JLOM1.10 316.3,96.37 ; JLOM1.10 316.3,95.03 ; JLOM1.10 317.68,96.37 ; JLOM1.10 317.68,95.7 ; JLOM1.10 317.68,95.03 ; 14.35,84.3 JUSB2.13 ; JUSB2.13 14.35,85.13 ; JUSB2.13 15.72,85.13 ; JUSB2.13 17.09,85.13 ; JUSB2.13 17.09,84.3 ; JUSB2.13 14.35,83.47 ; JUSB2.13 17.09,83.47 ; JUSB2.13 15.72,83.47 ; JUSB2.7 15.22,90.1 ; JUSB2.7 14.62,89.92 ; JUSB2.7 15.22,91.3 ; JUSB2.7 15.39,90.7 ; JUSB2.7 14.02,90.1 ; JUSB2.7 14.62,91.48 ; JUSB2.7 14.02,91.3 ; H11.1 119.85,127.48 ; H11.1 119.85,130.52 ; H11.1 118.32,131.08 ; H11.1 118.32,126.92 ; H11.1 120.41,129 ; H11.1 116.8,127.48 ; H11.1 116.24,129 ; H11.1 116.8,130.52 ; JHDMI1.11 307.91,85.1 ; JHDMI1.11 306.88,84.65 ; JHDMI1.11 306.99,85.1 ; JHDMI1.11 306.99,84.19 ; JHDMI1.11 307.91,84.19 ; JHDMI1.11 308.02,84.65 ; 258.53,24.07 H28.1 ; H28.1 256.1,26.5 ; H28.1 260.95,26.5 ; H28.1 256.76,24.73 ; H28.1 258.53,28.93 ; H28.1 260.29,28.27 ; H28.1 260.29,24.73 ; H28.1 256.76,28.27 ; JUSB1.11 313.25,58.7 ; JUSB1.11 313.25,57.87 ; JUSB1.11 310.51,58.7 ; JUSB1.11 311.88,57.87 ; JUSB1.11 310.51,57.87 ; 299.26,74.73 H14.1 ; H14.1 302.79,78.27 ; H14.1 298.6,76.5 ; H14.1 301.03,74.07 ; H14.1 301.03,78.93 ; H14.1 303.45,76.5 ; H14.1 302.79,74.73 ; H14.1 299.26,78.27 ; 78.76,34.77 H25.1 ; H25.1 80.52,35.43 ; H25.1 82.29,31.23 ; H25.1 78.1,33 ; H25.1 80.52,30.57 ; H25.1 82.29,34.77 ; H25.1 78.76,31.23 ; H25.1 82.95,33 ; JUSB1.7 305.03,65.8 ; JUSB1.7 304.43,65.62 ; JUSB1.7 305.03,67 ; JUSB1.7 303.83,65.8 ; JUSB1.7 304.43,67.18 ; JUSB1.7 303.83,67 ; JUSB1.7 303.65,66.4 ; JUSB3.13 304.7,54.77 ; JUSB3.13 304.7,56.43 ; JUSB3.13 301.96,55.6 ; JUSB3.13 303.33,54.77 ; JUSB3.13 303.33,56.43 ; JUSB3.13 301.96,56.43 ; JUSB3.13 301.96,54.77 ; JUSB3.13 304.7,55.6 ; 302.33,69.3 JUSB1.4 ; JUSB1.4 302.15,69.9 ; JUSB1.4 302.93,69.12 ; JUSB1.4 303.53,70.5 ; JUSB1.4 302.33,70.5 ; JUSB1.4 303.71,69.9 ; JUSB1.4 303.53,69.3 ; JUSB1.4 302.93,70.67 ; H3.1 130.95,86.5 ; H3.1 126.1,86.5 ; H3.1 128.53,88.93 ; H3.1 126.76,84.73 ; H3.1 130.29,84.73 ; H3.1 126.76,88.27 ; H3.1 130.29,88.27 ; H3.1 128.53,84.07 ; JUSB1.13 304.7,71.97 ; JUSB1.13 304.7,72.8 ; JUSB1.13 303.33,71.97 ; JUSB1.13 301.96,71.97 ; JUSB1.13 304.7,73.63 ; JUSB1.13 301.96,72.8 ; JUSB1.13 301.96,73.63 ; JUSB1.13 303.33,73.63 ; H16.1 251.25,134 ; H16.1 249.53,132.27 ; H16.1 249.53,135.73 ; H16.1 247.8,134 ; H16.1 250.8,135.27 ; H16.1 248.25,135.27 ; H16.1 250.8,132.73 ; H16.1 248.25,132.73 ; 302.33,53.3 JUSB3.4 ; JUSB3.4 302.93,53.48 ; JUSB3.4 303.53,52.1 ; JUSB3.4 302.93,51.92 ; JUSB3.4 302.33,52.1 ; JUSB3.4 303.53,53.3 ; JUSB3.4 303.71,52.7 ; JUSB3.4 302.15,52.7 ; 190.76,113.27 H2.1 ; H2.1 190.76,109.73 ; H2.1 192.52,113.93 ; H2.1 194.29,113.27 ; H2.1 190.1,111.5 ; H2.1 194.29,109.73 ; H2.1 194.95,111.5 ; H2.1 192.52,109.07 ; 312.02,76.4 JHDMI1.23 ; JHDMI1.23 315.18,76.4 ; JHDMI1.23 313.6,75.42 ; JHDMI1.23 312.02,75.42 ; JHDMI1.23 315.18,75.42 ; JUSBC1.1 3.07,112.35 ; JUSBC1.1 3.07,111.52 ; JUSBC1.1 3.07,110.69 ; JUSBC1.1 1.6,112.35 ; JUSBC1.1 1.6,110.69 ; 6.05,110.29 JUSBC1.5 ; JUSBC1.5 6.77,110.29 ; JUSBC1.5 6.77,112.3 ; JUSBC1.5 5.33,111.19 ; JUSBC1.5 6.05,112.3 ; JUSBC1.5 5.33,112.3 ; JUSBC1.5 5.33,110.29 ; H26.1 79.95,91.2 ; H26.1 79.29,92.97 ; H26.1 75.1,91.2 ; H26.1 79.29,89.43 ; H26.1 75.76,89.43 ; H26.1 75.76,92.97 ; H26.1 77.52,88.77 ; H26.1 77.52,93.63 ; H7.1 270.31,118.51 ; H7.1 267.34,121.49 ; H7.1 268.82,122.03 ; H7.1 267.34,118.51 ; H7.1 270.31,121.49 ; H7.1 270.86,120 ; H7.1 266.79,120 ; H7.1 268.82,117.97 ; 14.65,111.13 H20.1 ; H20.1 17.2,111.13 ; H20.1 17.2,113.67 ; H20.1 15.93,110.67 ; H20.1 14.2,112.4 ; H20.1 14.65,113.67 ; H20.1 17.65,112.4 ; H20.1 15.93,114.13 ; JHDMI1.5 308.02,87.65 ; JHDMI1.5 306.99,87.19 ; JHDMI1.5 307.91,87.19 ; JHDMI1.5 306.99,88.1 ; JHDMI1.5 307.91,88.1 ; JHDMI1.5 306.88,87.65 ; JUSBC1.3 3.07,102.05 ; JUSBC1.3 1.6,103.71 ; JUSBC1.3 3.07,103.71 ; JUSBC1.3 3.07,102.88 ; JUSBC1.3 1.6,102.05 ; JSD1.10 305.06,14.19 ; JSD1.10 306.19,13.46 ; JSD1.10 306.19,14.19 ; JSD1.10 303.92,14.19 ; JSD1.10 303.92,12.74 ; JSD1.10 305.06,12.74 ; JSD1.10 306.19,12.74 ; JSD1.10 303.92,13.46 ; 303.65,49.2 JUSB3.7 ; JUSB3.7 305.03,49.8 ; JUSB3.7 303.83,48.6 ; JUSB3.7 305.03,48.6 ; JUSB3.7 303.83,49.8 ; JUSB3.7 304.43,49.98 ; JUSB3.7 304.43,48.42 ; 310.51,41.5 JUSB3.11 ; JUSB3.11 313.25,41.5 ; JUSB3.11 313.25,41.91 ; 5.8,83 JUSB2.12 ; JUSB2.12 7.17,82.17 ; JUSB2.12 8.54,83 ; JUSB2.12 5.8,82.17 ; JUSB2.12 8.54,82.17
  IN1 w0.089: v1(169.33,87.11) 169.33,86.39 170.47,84.24 170.47,83.71 171.49,81.63 171.7,81.42 171.7,81.27 171.95,81.01 172.3,81.01 172.49,81.2 172.49,82.38 172.28,82.59 171.97,82.59 171.81,82.75 171.28,83.77 171.31,83.95 171.31,85.91 171.09,86.13 171.09,89.22 170.45,89.86 170.45,90.95 170.46,90.95 170.46,91.35 170.09,91.71 v1(170.09,91.73) 169.44,91.08 169.44,89.58 v1(169.22,89.35)
  IN1 w0.127: v1(169.33,87.11) 169.22,87.23 v1(169.22,89.35)
  VCC w0.203: 302.33,52.1 JUSB3.4 ; JUSB3.4 302.93,51.92 ; JUSB3.4 303.53,52.1 ; JUSB3.4 302.33,53.3 ; JUSB3.4 303.71,52.7 ; JUSB3.4 303.53,53.3 ; JUSB3.4 302.93,53.48 ; JUSB3.4 302.15,52.7 ; H14.1 303.45,76.5 ; H14.1 301.03,78.93 ; H14.1 299.26,78.27 ; H14.1 301.03,74.07 ; H14.1 299.26,74.73 ; H14.1 302.79,74.73 ; H14.1 302.79,78.27 ; H14.1 298.6,76.5 ; JHDMI1.2 306.36,88.69 ; JHDMI1.2 306.36,89.6 ; JHDMI1.2 305.44,88.69 ; JHDMI1.2 305.33,89.15 ; JHDMI1.2 306.47,89.15 ; JHDMI1.2 305.44,89.6 ; JHDMI1.2 305.9,89.72 ; JHDMI1.8 306.36,86.6 ; JHDMI1.8 306.36,85.69 ; JHDMI1.8 305.44,85.69 ; JHDMI1.8 305.33,86.15 ; JHDMI1.8 306.47,86.15 ; JHDMI1.8 305.44,86.6 ; 304.43,48.42 JUSB3.7 ; JUSB3.7 304.43,49.98 ; JUSB3.7 303.83,48.6 ; JUSB3.7 305.03,48.6 ; JUSB3.7 303.65,49.2 ; JUSB3.7 305.03,49.8 ; JUSB3.7 303.83,49.8 ; 6.05,102.1 JUSBC1.6 ; JUSBC1.6 6.05,104.11 ; JUSBC1.6 5.33,102.1 ; JUSBC1.6 6.77,102.1 ; JUSBC1.6 5.33,104.11 ; 5.8,99.23 JUSB2.11 ; JUSB2.11 8.54,99.23 ; JUSB2.11 8.54,98.4 ; JUSB2.11 7.17,99.23 ; JUSB2.11 5.8,98.4 ; JUSBC1.3 1.6,103.71 ; JUSBC1.3 3.07,102.05 ; JUSBC1.3 1.6,102.05 ; JUSBC1.3 3.07,102.88 ; JUSBC1.3 3.07,103.71 ; JLOM1.11 316.3,112.67 ; JLOM1.11 317.68,111.33 ; JLOM1.11 314.93,111.33 ; JLOM1.11 317.68,112.67 ; JLOM1.11 314.93,112 ; JLOM1.11 316.3,111.33 ; JLOM1.11 317.68,112 ; JLOM1.11 314.93,112.67 ; JLOM1.12 310.88,112 ; JLOM1.12 308.13,111.33 ; JLOM1.12 308.13,112 ; JLOM1.12 310.88,111.33 ; JLOM1.12 309.5,112.67 ; JLOM1.12 309.5,111.33 ; JLOM1.12 308.13,112.67 ; JLOM1.12 310.88,112.67 ; JHDMI1.22 315.18,94.88 ; JHDMI1.22 312.02,93.9 ; JHDMI1.22 313.6,94.88 ; JHDMI1.22 315.18,93.9 ; JHDMI1.22 312.02,94.88 ; JUSB3.12 313.25,56.9 ; JUSB3.12 313.25,57.73 ; JUSB3.12 310.51,56.9 ; JUSB3.12 310.51,57.73 ; JUSB3.12 311.88,57.73 ; 310.51,74.1 JUSB1.12 ; JUSB1.12 313.25,74.93 ; JUSB1.12 313.25,74.1 ; JUSB1.12 310.51,74.93 ; JUSB1.12 311.88,74.93 ; JLOM1.9 310.88,95.03 ; JLOM1.9 308.13,96.37 ; JLOM1.9 308.13,95.7 ; JLOM1.9 310.88,96.37 ; JLOM1.9 309.5,95.03 ; JLOM1.9 309.5,96.37 ; JLOM1.9 310.88,95.7 ; JLOM1.9 308.13,95.03 ; 305.72,78.88 JHDMI1.21 ; JHDMI1.21 305.72,76.92 ; JHDMI1.21 308.88,76.92 ; JHDMI1.21 307.3,78.88 ; JHDMI1.21 305.72,77.9 ; JHDMI1.21 307.3,76.92 ; JUSB3.13 303.33,56.43 ; JUSB3.13 301.96,55.6 ; JUSB3.13 301.96,56.43 ; JUSB3.13 304.7,56.43 ; JUSB3.13 303.33,54.77 ; JUSB3.13 304.7,54.77 ; JUSB3.13 301.96,54.77 ; JUSB3.13 304.7,55.6 ; 302.93,69.12 JUSB1.4 ; JUSB1.4 302.33,69.3 ; JUSB1.4 302.15,69.9 ; JUSB1.4 303.53,69.3 ; JUSB1.4 303.53,70.5 ; JUSB1.4 302.33,70.5 ; JUSB1.4 303.71,69.9 ; JUSB1.4 302.93,70.67 ; 301.96,72.8 JUSB1.13 ; JUSB1.13 301.96,71.97 ; JUSB1.13 303.33,73.63 ; JUSB1.13 304.7,73.63 ; JUSB1.13 304.7,71.97 ; JUSB1.13 301.96,73.63 ; JUSB1.13 304.7,72.8 ; JUSB1.13 303.33,71.97 ; JHDMI1.11 308.02,84.65 ; JHDMI1.11 307.91,85.1 ; JHDMI1.11 307.91,84.19 ; JHDMI1.11 306.99,85.1 ; JHDMI1.11 306.99,84.19 ; JHDMI1.11 306.88,84.65 ; 15.52,86.6 JUSB2.4 ; JUSB2.4 16.72,86.6 ; JUSB2.4 16.12,87.98 ; JUSB2.4 16.9,87.2 ; JUSB2.4 16.72,87.8 ; JUSB2.4 15.34,87.2 ; JUSB2.4 16.12,86.42 ; JUSB2.4 15.52,87.8 ; JLOM1.10 317.68,96.37 ; JLOM1.10 314.93,96.37 ; JLOM1.10 314.93,95.03 ; JLOM1.10 314.93,95.7 ; JLOM1.10 317.68,95.03 ; JLOM1.10 317.68,95.7 ; JLOM1.10 316.3,95.03 ; JLOM1.10 316.3,96.37 ; JUSB3.10 304.7,43.63 ; JUSB3.10 304.7,42.8 ; JUSB3.10 301.96,41.97 ; JUSB3.10 301.96,43.63 ; JUSB3.10 304.7,41.97 ; JUSB3.10 303.33,43.63 ; JUSB3.10 301.96,42.8 ; JUSB3.10 303.33,41.97 ; JHDMI1.5 307.91,87.19 ; JHDMI1.5 308.02,87.65 ; JHDMI1.5 306.99,87.19 ; JHDMI1.5 306.99,88.1 ; JHDMI1.5 306.88,87.65 ; JHDMI1.5 307.91,88.1 ; JUSB1.10 303.33,60.83 ; JUSB1.10 304.7,60.83 ; JUSB1.10 304.7,59.17 ; JUSB1.10 303.33,59.17 ; JUSB1.10 301.96,60.83 ; JUSB1.10 301.96,59.17 ; JUSB1.10 301.96,60 ; JUSB1.10 304.7,60 ; 1.75,80.77 H30.1 ; H30.1 4.3,80.77 ; H30.1 1.3,79.5 ; H30.1 4.75,79.5 ; H30.1 3.02,81.23 ; H30.1 4.3,78.23 ; H30.1 3.02,77.77 ; H30.1 1.75,78.23 ; H20.1 17.65,112.4 ; H20.1 17.2,113.67 ; H20.1 14.65,113.67 ; H20.1 17.2,111.13 ; H20.1 14.2,112.4 ; H20.1 15.93,114.13 ; H20.1 14.65,111.13 ; H20.1 15.93,110.67 ; 310.51,58.7 JUSB1.11 ; JUSB1.11 313.25,57.87 ; JUSB1.11 310.51,57.87 ; JUSB1.11 313.25,58.7 ; JUSB1.11 311.88,57.87 ; 5.33,110.29 JUSBC1.5 ; JUSBC1.5 6.05,112.3 ; JUSBC1.5 6.05,110.29 ; JUSBC1.5 5.33,112.3 ; JUSBC1.5 6.77,112.3 ; JUSBC1.5 5.33,111.19 ; 304.43,65.62 JUSB1.7 ; JUSB1.7 303.65,66.4 ; JUSB1.7 304.43,67.18 ; JUSB1.7 303.83,67 ; JUSB1.7 305.03,65.8 ; JUSB1.7 303.83,65.8 ; JUSB1.7 305.03,67 ; 14.35,97.1 JUSB2.10 ; JUSB2.10 14.35,96.27 ; JUSB2.10 17.09,97.93 ; JUSB2.10 17.09,97.1 ; JUSB2.10 15.72,97.93 ; JUSB2.10 14.35,97.93 ; JUSB2.10 15.72,96.27 ; 5.32,111.52 JUSBC1.2 ; JUSBC1.2 7.98,112.29 ; JUSBC1.2 7.98,110.74 ; JUSBC1.2 7.98,111.52 ; JUSBC1.2 6.65,112.29 ; JUSBC1.2 5.32,112.29 ; H29.1 292.79,118.73 ; H29.1 293.45,120.5 ; H29.1 292.79,122.27 ; H29.1 288.6,120.5 ; H29.1 291.02,122.93 ; H29.1 291.02,118.07 ; H29.1 289.26,118.73 ; H29.1 289.26,122.27 ; 7.17,82.17 JUSB2.12 ; JUSB2.12 8.54,83 ; JUSB2.12 8.54,82.17 ; JUSB2.12 5.8,83 ; JUSB2.12 5.8,82.17 ; 15.72,83.47 JUSB2.13 ; JUSB2.13 14.35,83.47 ; JUSB2.13 17.09,85.13 ; JUSB2.13 14.35,84.3 ; JUSB2.13 17.09,83.47 ; JUSB2.13 14.35,85.13 ; JUSB2.13 15.72,85.13 ; JUSB2.13 17.09,84.3 ; JUSBC1.1 3.07,110.69 ; JUSBC1.1 1.6,112.35 ; JUSBC1.1 3.07,112.35 ; JUSBC1.1 3.07,111.52 ; JUSBC1.1 1.6,110.69 ; JHDMI1.17 307.91,81.19 ; JHDMI1.17 307.91,82.1 ; JHDMI1.17 306.88,81.65 ; JHDMI1.17 306.99,81.19 ; JHDMI1.17 308.02,81.65 ; JHDMI1.17 306.99,82.1 ; JUSB3.11 313.25,41.5 ; JUSB3.11 313.25,41.91 ; JUSB3.11 310.51,41.5 ; 300,118.48 H15.1 ; H15.1 303.61,120 ; H15.1 301.52,117.92 ; H15.1 300,121.52 ; H15.1 303.05,118.48 ; H15.1 303.05,121.52 ; H15.1 301.52,122.08 ; H15.1 299.44,120 ; 305.72,91.42 JHDMI1.20 ; JHDMI1.20 305.72,93.38 ; JHDMI1.20 305.72,92.4 ; JHDMI1.20 307.3,91.42 ; JHDMI1.20 307.3,93.38 ; JHDMI1.20 308.88,93.38 ; JHDMI1.23 315.18,76.4 ; JHDMI1.23 313.6,75.42 ; JHDMI1.23 312.02,75.42 ; JHDMI1.23 312.02,76.4 ; JHDMI1.23 315.18,75.42 ; 126.1,86.5 H3.1 ; H3.1 130.29,84.73 ; H3.1 128.53,88.93 ; H3.1 130.29,88.27 ; H3.1 128.53,84.07 ; H3.1 126.76,88.27 ; H3.1 126.76,84.73 ; H3.1 130.95,86.5 ; JUSB2.7 14.62,91.48 ; JUSB2.7 14.02,90.1 ; JUSB2.7 14.62,89.92 ; JUSB2.7 15.22,91.3 ; JUSB2.7 14.02,91.3 ; JUSB2.7 15.39,90.7 ; JUSB2.7 15.22,90.1 ; JUSBC1.4 7.98,102.1 ; JUSBC1.4 7.98,102.88 ; JUSBC1.4 5.32,102.1 ; JUSBC1.4 5.32,102.88 ; JUSBC1.4 6.65,102.1
  IN3 w0.508: v1(298.89,29.73) v1(298.89,32.01) 298.89,37.69 v1(298.79,37.79) v1(298.15,37.79)
  GND2 w0.203: JHDMI1.22 315.18,93.9 ; JHDMI1.22 312.02,94.88 ; JHDMI1.22 312.02,93.9 ; JHDMI1.22 313.6,94.88 ; JHDMI1.22 315.18,94.88 ; 15.34,87.2 JUSB2.4 ; JUSB2.4 16.12,87.98 ; JUSB2.4 16.72,87.8 ; JUSB2.4 16.9,87.2 ; JUSB2.4 15.52,86.6 ; JUSB2.4 15.52,87.8 ; JUSB2.4 16.12,86.42 ; JUSB2.4 16.72,86.6 ; 78.76,34.77 H25.1 ; H25.1 82.95,33 ; H25.1 82.29,31.23 ; H25.1 80.52,35.43 ; H25.1 78.1,33 ; H25.1 82.29,34.77 ; H25.1 80.52,30.57 ; H25.1 78.76,31.23 ; 118.32,126.92 H11.1 ; H11.1 118.32,131.08 ; H11.1 116.24,129 ; H11.1 116.8,130.52 ; H11.1 116.8,127.48 ; H11.1 120.41,129 ; H11.1 119.85,130.52 ; H11.1 119.85,127.48 ; 311.88,57.87 JUSB1.11 ; JUSB1.11 310.51,57.87 ; JUSB1.11 313.25,58.7 ; JUSB1.11 310.51,58.7 ; JUSB1.11 313.25,57.87 ; 305.72,91.42 JHDMI1.20 ; JHDMI1.20 307.3,93.38 ; JHDMI1.20 308.88,93.38 ; JHDMI1.20 305.72,92.4 ; JHDMI1.20 305.72,93.38 ; JHDMI1.20 307.3,91.42 ; 247.8,134 H16.1 ; H16.1 249.53,135.73 ; H16.1 250.8,132.73 ; H16.1 248.25,132.73 ; H16.1 250.8,135.27 ; H16.1 249.53,132.27 ; H16.1 248.25,135.27 ; H16.1 251.25,134 ; SW1.5 250.22,115.53 ; SW1.5 250.98,115.29 ; SW1.5 249.46,113.77 ; SW1.5 249.46,115.29 ; SW1.5 249.22,114.53 ; SW1.5 251.22,114.53 ; SW1.5 250.22,113.52 ; SW1.5 250.98,113.77 ; JSD1.13 315.79,13.46 ; JSD1.13 313.52,12.74 ; JSD1.13 313.52,14.19 ; JSD1.13 315.79,14.19 ; JSD1.13 314.65,12.74 ; JSD1.13 315.79,12.74 ; JSD1.13 314.65,14.19 ; JSD1.13 313.52,13.46 ; H18.1 70.8,132.73 ; H18.1 69.52,132.27 ; H18.1 70.8,135.27 ; H18.1 69.52,135.73 ; H18.1 68.25,132.73 ; H18.1 68.25,135.27 ; H18.1 67.8,134 ; H18.1 71.25,134 ; H20.1 17.2,113.67 ; H20.1 14.65,111.13 ; H20.1 14.2,112.4 ; H20.1 14.65,113.67 ; H20.1 15.93,114.13 ; H20.1 15.93,110.67 ; H20.1 17.65,112.4 ; H20.1 17.2,111.13 ; H2.1 194.29,109.73 ; H2.1 190.1,111.5 ; H2.1 194.95,111.5 ; H2.1 194.29,113.27 ; H2.1 192.52,109.07 ; H2.1 192.52,113.93 ; H2.1 190.76,109.73 ; H2.1 190.76,113.27 ; 317.85,26.34 JSD1.12 ; JSD1.12 316.72,27.06 ; JSD1.12 316.72,27.79 ; JSD1.12 317.85,27.79 ; JUSB3.10 304.7,43.63 ; JUSB3.10 303.33,43.63 ; JUSB3.10 301.96,41.97 ; JUSB3.10 301.96,43.63 ; JUSB3.10 301.96,42.8 ; JUSB3.10 304.7,42.8 ; JUSB3.10 303.33,41.97 ; JUSB3.10 304.7,41.97 ; JUSBC1.6 6.77,102.1 ; JUSBC1.6 6.05,104.11 ; JUSBC1.6 6.77,104.11 ; JUSBC1.6 6.05,102.1 ; JUSBC1.6 5.33,104.11 ; JUSBC1.6 5.33,102.1 ; 306.99,88.1 JHDMI1.5 ; JHDMI1.5 306.99,87.19 ; JHDMI1.5 307.91,88.1 ; JHDMI1.5 306.88,87.65 ; JHDMI1.5 308.02,87.65 ; JHDMI1.5 307.91,87.19 ; 304.43,65.62 JUSB1.7 ; JUSB1.7 305.03,65.8 ; JUSB1.7 304.43,67.18 ; JUSB1.7 305.03,67 ; JUSB1.7 303.83,67 ; JUSB1.7 303.65,66.4 ; JUSB1.7 303.83,65.8 ; 301.96,71.97 JUSB1.13 ; JUSB1.13 304.7,73.63 ; JUSB1.13 301.96,73.63 ; JUSB1.13 303.33,71.97 ; JUSB1.13 301.96,72.8 ; JUSB1.13 303.33,73.63 ; JUSB1.13 304.7,72.8 ; JUSB1.13 304.7,71.97 ; 305.72,76.92 JHDMI1.21 ; JHDMI1.21 308.88,76.92 ; JHDMI1.21 305.72,77.9 ; JHDMI1.21 307.3,78.88 ; JHDMI1.21 305.72,78.88 ; JHDMI1.21 307.3,76.92 ; JUSB2.13 17.09,85.13 ; JUSB2.13 14.35,84.3 ; JUSB2.13 17.09,84.3 ; JUSB2.13 17.09,83.47 ; JUSB2.13 14.35,83.47 ; JUSB2.13 14.35,85.13 ; JUSB2.13 15.72,85.13 ; JUSB2.13 15.72,83.47 ; H26.1 79.95,91.2 ; H26.1 79.29,92.97 ; H26.1 79.29,89.43 ; H26.1 77.52,93.63 ; H26.1 75.76,92.97 ; H26.1 75.76,89.43 ; H26.1 77.52,88.77 ; H26.1 75.1,91.2 ; 310.51,74.93 JUSB1.12 ; JUSB1.12 313.25,74.93 ; JUSB1.12 311.88,74.93 ; JUSB1.12 310.51,74.1 ; JUSB1.12 313.25,74.1 ; 289.26,122.27 H29.1 ; H29.1 293.45,120.5 ; H29.1 291.02,122.93 ; H29.1 292.79,122.27 ; H29.1 291.02,118.07 ; H29.1 288.6,120.5 ; H29.1 292.79,118.73 ; H29.1 289.26,118.73 ; JSD1.11 306.19,26.34 ; JSD1.11 303.92,27.06 ; JSD1.11 305.06,26.34 ; JSD1.11 306.19,27.79 ; JSD1.11 305.06,27.79 ; JSD1.11 303.92,26.34 ; JSD1.11 306.19,27.06 ; JSD1.11 303.92,27.79 ; H14.1 302.79,78.27 ; H14.1 301.03,74.07 ; H14.1 298.6,76.5 ; H14.1 302.79,74.73 ; H14.1 301.03,78.93 ; H14.1 299.26,78.27 ; H14.1 299.26,74.73 ; H14.1 303.45,76.5 ; JUSB1.10 304.7,60.83 ; JUSB1.10 304.7,59.17 ; JUSB1.10 301.96,59.17 ; JUSB1.10 301.96,60 ; JUSB1.10 303.33,60.83 ; JUSB1.10 303.33,59.17 ; JUSB1.10 301.96,60.83 ; JUSB1.10 304.7,60 ; 128.53,84.07 H3.1 ; H3.1 126.1,86.5 ; H3.1 126.76,88.27 ; H3.1 128.53,88.93 ; H3.1 130.29,84.73 ; H3.1 130.95,86.5 ; H3.1 126.76,84.73 ; H3.1 130.29,88.27 ; JUSBC1.5 6.77,110.29 ; JUSBC1.5 5.33,112.3 ; JUSBC1.5 6.77,112.3 ; JUSBC1.5 5.33,110.29 ; JUSBC1.5 5.33,111.19 ; JUSBC1.5 6.05,112.3 ; JUSBC1.5 6.05,110.29 ; JUSB3.11 313.25,41.91 ; JUSB3.11 313.25,41.5 ; JUSB3.11 310.51,41.5 ; 258.53,24.07 H28.1 ; H28.1 258.53,28.93 ; H28.1 260.95,26.5 ; H28.1 256.76,28.27 ; H28.1 256.76,24.73 ; H28.1 256.1,26.5 ; H28.1 260.29,28.27 ; H28.1 260.29,24.73 ; JLOM1.9 310.88,96.37 ; JLOM1.9 309.5,95.03 ; JLOM1.9 308.13,95.7 ; JLOM1.9 309.5,96.37 ; JLOM1.9 310.88,95.7 ; JLOM1.9 308.13,96.37 ; JLOM1.9 308.13,95.03 ; JLOM1.9 310.88,95.03 ; 5.8,98.4 JUSB2.11 ; JUSB2.11 8.54,98.4 ; JUSB2.11 5.8,99.23 ; JUSB2.11 7.17,99.23 ; JUSB2.11 8.54,99.23 ; JUSBC1.1 3.07,110.69 ; JUSBC1.1 3.07,112.35 ; JUSBC1.1 1.6,110.69 ; JUSBC1.1 1.6,112.35 ; JUSBC1.1 3.07,111.52 ; JLOM1.12 310.88,112.67 ; JLOM1.12 308.13,111.33 ; JLOM1.12 309.5,112.67 ; JLOM1.12 308.13,112 ; JLOM1.12 310.88,111.33 ; JLOM1.12 310.88,112 ; JLOM1.12 308.13,112.67 ; JLOM1.12 309.5,111.33 ; H4.1 192.52,88.93 ; H4.1 194.95,86.5 ; H4.1 194.29,88.27 ; H4.1 190.76,84.73 ; H4.1 192.52,84.07 ; H4.1 190.1,86.5 ; H4.1 194.29,84.73 ; H4.1 190.76,88.27 ; 301.96,56.43 JUSB3.13 ; JUSB3.13 303.33,56.43 ; JUSB3.13 301.96,55.6 ; JUSB3.13 303.33,54.77 ; JUSB3.13 301.96,54.77 ; JUSB3.13 304.7,55.6 ; JUSB3.13 304.7,56.43 ; JUSB3.13 304.7,54.77 ; JUSB2.10 15.72,97.93 ; JUSB2.10 15.72,96.27 ; JUSB2.10 14.35,96.27 ; JUSB2.10 17.09,97.93 ; JUSB2.10 14.35,97.1 ; JUSB2.10 17.09,97.1 ; JUSB2.10 14.35,97.93 ; H7.1 270.31,118.51 ; H7.1 268.82,122.03 ; H7.1 270.31,121.49 ; H7.1 267.34,121.49 ; H7.1 266.79,120 ; H7.1 270.86,120 ; H7.1 268.82,117.97 ; H7.1 267.34,118.51 ; JHDMI1.11 308.02,84.65 ; JHDMI1.11 306.99,85.1 ; JHDMI1.11 307.91,84.19 ; JHDMI1.11 306.88,84.65 ; JHDMI1.11 306.99,84.19 ; JHDMI1.11 307.91,85.1 ; JUSB1.4 303.71,69.9 ; JUSB1.4 302.33,69.3 ; JUSB1.4 303.53,69.3 ; JUSB1.4 302.33,70.5 ; JUSB1.4 303.53,70.5 ; JUSB1.4 302.15,69.9 ; JUSB1.4 302.93,69.12 ; JUSB1.4 302.93,70.67 ; H13.1 316.44,5.42 ; H13.1 315.03,5.93 ; H13.1 313.61,2.58 ; H13.1 316.44,2.58 ; H13.1 313.09,4 ; H13.1 316.96,4 ; H13.1 313.61,5.42 ; H13.1 315.03,2.07 ; JHDMI1.23 315.18,75.42 ; JHDMI1.23 313.6,75.42 ; JHDMI1.23 315.18,76.4 ; JHDMI1.23 312.02,75.42 ; JHDMI1.23 312.02,76.4 ; JUSBC1.3 3.07,102.88 ; JUSBC1.3 1.6,103.71 ; JUSBC1.3 3.07,103.71 ; JUSBC1.3 1.6,102.05 ; JUSBC1.3 3.07,102.05 ; 14.02,90.1 JUSB2.7 ; JUSB2.7 14.02,91.3 ; JUSB2.7 14.62,91.48 ; JUSB2.7 15.22,91.3 ; JUSB2.7 15.22,90.1 ; JUSB2.7 15.39,90.7 ; JUSB2.7 14.62,89.92 ; JHDMI1.8 306.36,85.69 ; JHDMI1.8 305.44,86.6 ; JHDMI1.8 306.36,86.6 ; JHDMI1.8 306.47,86.15 ; JHDMI1.8 305.44,85.69 ; JHDMI1.8 305.33,86.15 ; 151.2,127.48 H12.1 ; H12.1 152.72,131.08 ; H12.1 151.2,130.52 ; H12.1 152.72,126.92 ; H12.1 154.81,129 ; H12.1 150.64,129 ; H12.1 154.25,127.48 ; H12.1 154.25,130.52 ; 314.93,112 JLOM1.11 ; JLOM1.11 317.68,112 ; JLOM1.11 316.3,111.33 ; JLOM1.11 316.3,112.67 ; JLOM1.11 317.68,111.33 ; JLOM1.11 314.93,111.33 ; JLOM1.11 317.68,112.67 ; JLOM1.11 314.93,112.67 ; 157.82,134.3 H17.1 ; H17.1 161.86,136 ; H17.1 159.52,138.34 ; H17.1 161.23,134.3 ; H17.1 159.52,133.66 ; H17.1 157.19,136 ; H17.1 161.23,137.7 ; H17.1 157.82,137.7 ; H30.1 4.3,80.77 ; H30.1 1.3,79.5 ; H30.1 3.02,77.77 ; H30.1 1.75,78.23 ; H30.1 4.75,79.5 ; H30.1 1.75,80.77 ; H30.1 3.02,81.23 ; H30.1 4.3,78.23 ; JUSBC1.2 7.98,111.52 ; JUSBC1.2 6.65,112.29 ; JUSBC1.2 5.32,111.52 ; JUSBC1.2 7.98,112.29 ; JUSBC1.2 5.32,112.29 ; JUSBC1.2 7.98,110.74 ; 299.44,120 H15.1 ; H15.1 301.52,122.08 ; H15.1 303.61,120 ; H15.1 301.52,117.92 ; H15.1 300,121.52 ; H15.1 303.05,121.52 ; H15.1 303.05,118.48 ; H15.1 300,118.48 ; 305.44,88.69 JHDMI1.2 ; JHDMI1.2 305.33,89.15 ; JHDMI1.2 306.47,89.15 ; JHDMI1.2 305.9,89.72 ; JHDMI1.2 306.36,88.69 ; JHDMI1.2 306.36,89.6 ; JHDMI1.2 305.44,89.6 ; H8.1 283.98,67.05 ; H8.1 280.46,65.56 ; H8.1 280.46,68.54 ; H8.1 283.44,65.56 ; H8.1 281.95,69.08 ; H8.1 283.44,68.54 ; H8.1 281.95,65.02 ; H8.1 279.92,67.05 ; JUSB3.12 313.25,56.9 ; JUSB3.12 311.88,57.73 ; JUSB3.12 310.51,57.73 ; JUSB3.12 313.25,57.73 ; JUSB3.12 310.51,56.9 ; 316.3,95.03 JLOM1.10 ; JLOM1.10 317.68,95.7 ; JLOM1.10 314.93,95.7 ; JLOM1.10 314.93,96.37 ; JLOM1.10 317.68,95.03 ; JLOM1.10 317.68,96.37 ; JLOM1.10 316.3,96.37 ; JLOM1.10 314.93,95.03 ; JUSB3.7 305.03,49.8 ; JUSB3.7 303.83,48.6 ; JUSB3.7 304.43,48.42 ; JUSB3.7 305.03,48.6 ; JUSB3.7 303.83,49.8 ; JUSB3.7 304.43,49.98 ; JUSB3.7 303.65,49.2 ; SW1.4 250.98,121.59 ; SW1.4 250.22,119.82 ; SW1.4 250.22,121.83 ; SW1.4 249.46,120.07 ; SW1.4 250.98,120.07 ; SW1.4 249.22,120.83 ; SW1.4 249.46,121.59 ; SW1.4 251.22,120.83 ; H1.1 130.29,113.27 ; H1.1 130.29,109.73 ; H1.1 126.76,109.73 ; H1.1 126.76,113.27 ; H1.1 126.1,111.5 ; H1.1 130.95,111.5 ; H1.1 128.53,113.93 ; H1.1 128.53,109.07 ; 303.92,14.19 JSD1.10 ; JSD1.10 305.06,12.74 ; JSD1.10 305.06,14.19 ; JSD1.10 303.92,13.46 ; JSD1.10 303.92,12.74 ; JSD1.10 306.19,12.74 ; JSD1.10 306.19,13.46 ; JSD1.10 306.19,14.19 ; 306.99,81.19 JHDMI1.17 ; JHDMI1.17 306.99,82.1 ; JHDMI1.17 306.88,81.65 ; JHDMI1.17 307.91,81.19 ; JHDMI1.17 308.02,81.65 ; JHDMI1.17 307.91,82.1 ; JUSB2.12 8.54,82.17 ; JUSB2.12 5.8,82.17 ; JUSB2.12 8.54,83 ; JUSB2.12 7.17,82.17 ; JUSB2.12 5.8,83 ; JUSB3.4 303.53,53.3 ; JUSB3.4 302.33,52.1 ; JUSB3.4 302.93,51.92 ; JUSB3.4 302.93,53.48 ; JUSB3.4 302.15,52.7 ; JUSB3.4 303.71,52.7 ; JUSB3.4 302.33,53.3 ; JUSB3.4 303.53,52.1 ; 5.32,102.88 JUSBC1.4 ; JUSBC1.4 7.98,102.88 ; JUSBC1.4 6.65,102.1 ; JUSBC1.4 5.32,102.1 ; JUSBC1.4 7.98,102.1 ; JUSBC1.4 7.98,103.65
  BOTTOM w0.089: v1(146.68,87.11) UC1.T36 ; UC1.G36 v1(141.65,87.11)
  BOTTOM w0.09: v1(137.63,95.21) UC1.B25 ; v1(144.16,87.11) UC1.L36 ; v1(183.42,102.78) UC1.CP13 ; UC1.CP9 182.45,105.33 183.41,105.33 v1(183.57,105.5) ; v1(169.33,87.11) UC1.BM36 ; v1(137.63,92.69) UC1.B29
  BOTTOM w0.1: UC1.K22 143.63,97.17 ; UC1.K22 143.63,96.72 ; UC1.K22 143.19,97.17 ; UC1.K21 143.14,97.59 ; UC1.K21 143.68,97.59 ; UC1.K21 143.14,98.12 ; UC1.K25 143.19,95.13 ; UC1.K25 143.63,95.13 ; UC1.K25 143.63,94.68 ; 143.63,96.04 UC1.K24 ; UC1.K24 143.19,96.04 ; UC1.K24 143.19,95.59 ; UC1.K24 143.63,95.59
  BOTTOM w0.102: v1(177.06,86.99) 176.89,87.16 UC1.CE36 ; v1(179.54,87.14) 179.54,87.14 179.4,87.28 UC1.CJ36 ; v1(159.27,87.11) UC1.AT36 ; v1(179.86,108.8) 179.86,108.83 180.37,109.34 180.37,109.58 180.58,109.79 UC1.CL2 ; v1(164.3,87.11) UC1.BD36
  BOTTOM w0.127: v1(30.92,98.57) 30.93,98.56 v3(31.64,98.56) ; v1(174.42,87.11) 174.37,87.15 174.37,88.1 UC1.BY36 ; v3(68.72,105.5) 68.19,104.98 v1(68,104.98) ; v3(52.48,103.54) 52.48,103.21 52.98,102.72 v1(53.28,102.72) ; v3(90.18,43.57) v1(89.39,43.57) ; v1(171.69,86.96) 171.85,87.13 UC1.BT36 ; v3(124.05,84.25) 122.79,84.25 PC1103.2
  BOTTOM w0.15: v1(180.79,91.34) 180.56,90.93 180.56,90.72 180.59,90.42 UC1.CM33 ; v1(151.77,82.49) 151.31,83 151.31,84.45 CC1457.2
  BOTTOM w0.152: UC1.E29 UC1.E31 UC1.E33 ; v1(180.28,87.25) 180.28,87.3 UC1.CK37 ; UC1.CP15 v1(184.16,101.52) ; UC1.CN2 181.73,110.08 UC1.CN1 ; v1(136.9,91.43) UC1.B31 ; 183.02,109.67 UC1.CR2 182.67,109.69 UC1.CP2 ; CE67.2 249.24,96.52 249.24,95.45 v1(249.65,95.04) 250.05,95.45 250.05,96.41 249.87,96.59 CE67.2
  BOTTOM w0.16: v1(183.7,110.88) 182.29,110.88 UC1.CN1 ; UC1.CP1 182.43,110.36 183.26,110.36 183.26,110.37 v1(183.26,110.37) ; 183.02,109.67 v1(185.04,109.67)
  BOTTOM w0.178: UC1.P36 v1(145.42,86.38) ; UC1.AN25 v1(157.79,95.54) ; UC1.AK36 v1(155.49,86.38) ; UC1.BB36 v1(163.04,86.38) ; UC1.AB36 v1(150.46,86.38) ; UC1.B23 v1(136.9,96.47)
  BOTTOM w0.18: UC1.B7 v1(138.01,106.57) ; v1(163.26,95.54) UC1.BC25 ; UC1.AV8 v1(160.99,105.92) ; v1(136.9,93.95) UC1.B27 ; v1(160.52,95.54) UC1.AV25 ; v1(163.76,105.92) UC1.BC8 ; UC1.BK10 v1(167.92,103.85) ; v1(162.83,107.19) UC1.BA6 ; v1(165.56,86.38) UC1.BF36 ; v1(177.72,110.95) 177.61,110.84 UC1.CF2 UC1.CF3 ; v1(160.99,107.19) 160.89,107.14 UC1.AV6 ; v1(158.01,86.38) UC1.AP36 ; v1(147.89,86.34) 147.94,86.39 UC1.V36 ; v1(165.61,105.92) UC1.BE8 ; UC1.CP19 183.45,99 183.49,98.96 v1(183.8,98.96) ; v1(142.91,86.36) UC1.J36 ; UC1.CP11 182.52,104.05 183.33,104.05 183.41,104.13 v1(183.42,104.13) ; v1(145.03,95.54) UC1.N25 ; v1(167.9,111.15) 167.9,111.02 167.85,110.96 UC1.BK2 UC1.BK3 ; v1(160.52,86.38) UC1.AV36 ; v1(152.96,86.36) 152.97,86.38 UC1.AF36
  BOTTOM w0.2: UC1.H9 142.15,104.89 v1(142.15,104.85) ; v1(159.16,93) UC1.AU28 ; UC1.AH31 153.72,91.71 v1(153.64,91.7) UC1.AH30 ; v1(139.88,92.69) UC1.E29 ; UC1.BH35 v1(166.82,89.48) UC1.BH33 ; v1(183.43,88.07) 182.92,88.07 UC1.CR36 ; UC1.CE7 v1(177.62,106.55) ; UC1.L33 v1(144.16,89.36) UC1.L35 UC1.L36 ; v1(153.69,93) UC1.AH28 ; UC1.BK3 v1(167.85,108.83) ; UC1.BM33 169.33,89.47 v1(169.22,89.35) 169.33,89.24 UC1.BM35 UC1.BM36 ; UC1.L27 v1(144.58,93.64) UC1.N27 ; v1(160.07,93) UC1.AV28 ; UC1.AB3 v1(150.76,108.83) UC1.AB4 ; v1(172.05,106.63) 172.22,106.63 UC1.BU7 ; v1(150.04,93.64) UC1.AB27 ; UC1.R30 v1(145.49,91.73) UC1.R31 ; v1(148.22,91.73) UC1.W30 ; UC1.CJ11 179.73,103.93 v1(179.7,103.86) ; UC1.BY5 174.84,107.82 v1(174.87,107.84) ; 140.15,106 UC1.D9 140.31,104.85 v1(140.32,104.85) 140.32,104.88 UC1.E9 ; v1(141.72,97.4) UC1.G21 ; UC1.B25 UC1.C25 UC1.D25 v1(140.41,95.37) ; UC1.CM9 181.34,105.56 v1(181.37,105.55) ; UC1.CC14 176.16,102.35 176.52,101.99 v1(176.59,101.99) ; v1(171.87,92.97) 171.48,93.28 UC1.BT28 ; UC1.AK3 155.64,108.86 v1(155.7,108.8) 155.64,108.74 UC1.AK4 ; UC1.BY15 v1(173.89,101.15) ; UC1.CC16 v1(176.49,100.31) ; UC1.CC31 v1(176.47,91.1) ; UC1.CM21 v1(181.33,97.98) ; UC1.CC7 v1(176.69,106.55) ; v1(141.13,104.79) UC1.G9 ; UC1.AD35 v1(151.72,89.36) UC1.AD33 ; UC1.BK7 v1(168.38,106.55) ; UC1.AJ28 v1(155.51,93) ; v1(181.36,103.02) 181.34,103.03 UC1.CM13 ; UC1.BW7 173.86,106.52 v1(173.92,106.5) ; v1(153.69,92.37) UC1.AH29 ; UC1.B29 UC1.C29 ; UC1.BL7 v1(169.3,106.55) ; UC1.BC29 162.94,92.45 v1(162.8,92.37) ; UC1.CF4 v1(177.61,108.83) UC1.CF3 ; v1(149.13,91.73) UC1.Y30 ; UC1.CC28 v1(176.47,93) ; UC1.CE33 v1(176.89,89.36) UC1.CE35 UC1.CE36 ; UC1.CJ14 179.73,101.9 v1(179.7,101.83) ; UC1.BV4 v1(172.73,108.83) UC1.BV3 ; UC1.W27 v1(148.22,93.64) ; UC1.BT5 171.93,107.76 v1(171.98,107.9) ; UC1.J15 142.49,101.89 v1(142.43,101.97) ; v1(163.71,93) UC1.BD28 ; UC1.CD24 v1(176.49,95.27) UC1.CC24 ; v1(178.49,106.61) 178.46,106.51 UC1.CG7 ; UC1.P4 v1(145.88,108.83) UC1.P3 ; UC1.C36 UC1.C37 UC1.B37 v1(138.19,87.45) ; v1(164.63,92.37) UC1.BE29 ; v1(181.36,100.49) 181.33,100.5 UC1.CM17 ; UC1.BE31 v1(164.63,91.73) UC1.BE30 ; v1(181.33,92.94) UC1.CM29 ; UC1.CN9 UC1.CP9 ; UC1.D1 v1(139.71,110.83) ; v1(158.25,93) UC1.AR28 ; UC1.CM37 UC1.CN37 181.75,87.68 182.32,87.12 v1(182.61,87.12) 182.61,87.39 182.59,87.41 UC1.CP37 ; v1(142.36,97.4) UC1.H21 ; UC1.BP7 v1(171.15,106.55) ; UC1.CB19 v1(175.84,99.47) ; UC1.CB7 v1(175.77,106.55) ; UC1.K9 v1(143.08,104.79) ; UC1.CN21 UC1.CP21 ; v1(179.92,98.75) 179.81,99.11 UC1.CJ19 ; v1(150.04,91.73) UC1.AB30 ; UC1.F4 UC1.F3 v1(140.61,109.66) ; UC1.CB20 UC1.CC20 176.24,98.12 v1(176.49,97.79) 176.73,98.12 UC1.CD20 ; UC1.B36 138.79,88.27 138.33,88.27 UC1.A36 v1(137.67,88.02) ; UC1.AM35 v1(156.75,89.36) UC1.AM33 ; UC1.C9 v1(139.18,104.79) ; v1(145.49,93) UC1.R28 ; UC1.F24 v1(141.09,95.36) ; v1(159.16,92.37) UC1.AU29 ; v1(170.09,91.73) UC1.BN30 ; v1(164.63,93) UC1.BE28 ; UC1.Y27 v1(149.13,93.64) ; UC1.BN7 v1(170.22,106.55) ; UC1.B9 v1(138.53,104.79) ; UC1.AY35 v1(161.78,89.36) UC1.AY33 ; UC1.CP13 UC1.CN13 ; v1(145.49,93.64) UC1.R27 ; v1(145.49,92.37) UC1.R29
  BOTTOM w0.203: UT5.B8 61.15,102.48 v1(61.15,102.83) 61.15,103.13 UT5.D8 UT5.E8 ; UC1.CH31 179.01,91.07 v1(179.26,91.07) ; UC1.AW29 v1(160.98,92.37) ; UC1.BB4 v1(162.97,108.83) UC1.BB3 ; UC1.BB4 162.93,108.36 UC1.BA4 ; UC1.BB4 163.58,108.32 UC1.BC4 v1(164.25,108.22) ; UT5.B7 UT5.A7 61.04,101.59 61.04,101.46 v1(61.14,101.36) 61.33,101.55 UT5.A8 ; v1(59.4,105.78) 59.4,105.73 UT5.H5 ; UC1.AC5 151.38,107.85 v1(151.73,108) ; UC1.G33 UC1.F33 v1(140.74,89.43) UC1.E35 v1(140.09,89.06) ; v1(181.36,100.49) 181.54,100.49 UC1.CN17 ; UC1.CF19 177.7,99.06 v1(177.54,98.69) ; UC1.J5 143.12,107.68 v1(143.43,107.82) ; v1(160.74,111.12) 161.18,110.68 UC1.AW1 ; UC1.B34 UC1.C33 v1(139.88,90.17) UC1.E33 ; UC1.CN25 v1(181.33,95.46) UC1.CM25 ; UC1.P7 v1(146.21,106.55) ; UT5.F5 UT5.F6 ; UT5.F5 UT5.G5 ; UT5.F5 UT5.E5 ; UT5.F6 UT5.G6 ; UT5.F6 UT5.E6 ; UT5.F6 UT5.F7 ; UC1.BT16 171.69,100.81 172.18,100.81 UC1.BU16 v1(172.55,100.36) ; UC1.BC32 v1(162.81,90.46) 162.94,90.19 163.03,89.99 UC1.BB33 ; UT5.L1 57.83,106.97 v1(57.57,107.23) ; UC1.AV4 160.22,108.32 160.18,108.36 UC1.AU4 159.54,108.69 UC1.AT4 159.07,108.69 UC1.AR4 158.7,108.32 UC1.AP4 v1(158.08,108.83) UC1.AP3 ; UC1.AV4 161.14,108.32 UC1.AW4 UC1.AW3 161.42,109.01 UC1.AY4 162.07,108.36 UC1.BA4 ; UC1.AV4 v1(160.52,108.83) UC1.AV3 ; UC1.CF23 177.67,96.07 177.67,95.71 v1(177.78,95.6) ; UC1.AF7 v1(153.6,106.55) ; UC1.BU23 172.31,96.53 v1(172.65,96.09) 172.36,95.71 UC1.BU24 ; UC1.BL28 v1(168.37,92.94) UC1.BL29 v1(168.39,92.31) 168.39,92.27 UC1.BL30 ; UC1.BR16 v1(170.64,101.15) 170.31,101.48 UC1.BP15 ; v1(168.39,91.01) 168.38,91 168.38,90.68 168.08,90.37 UC1.BK33 ; v1(168.39,91.01) 168.39,90.99 UC1.BL32 ; v1(168.39,91.01) UC1.BL31 v1(168.32,91.69) UC1.BL30 ; UC1.Y26 UC1.Y27 ; UC1.BH33 166.79,89.99 v1(166.43,90.42) ; UT5.G5 UT5.G6 ; UT5.G5 UT5.H4 59.03,105.31 v1(58.86,105.47) ; UC1.U24 UC1.U26 147.31,93.64 v1(147.31,93.64) UC1.V27 ; UC1.BY36 174.37,88.14 174.4,88.17 174.4,88.72 UC1.BY35 v1(174.37,89.36) 174.37,89.48 UC1.BY33 174.32,90.01 173.16,90.01 UC1.BV33 172.57,89.96 172.55,89.98 171.87,89.98 UC1.BT33 ; v1(154.53,108.1) 154.29,108.1 154.06,107.88 UC1.AG5 ; UC1.AW30 v1(160.98,91.73) UC1.AW31 ; UC1.K3 v1(143.44,108.83) UC1.K4 ; UC1.T7 v1(147.13,106.55) ; v1(179.86,108.8) 180.04,108.62 UC1.CK4 180.16,108.32 180.33,108.5 UC1.CM4 180.94,108.42 180.94,107.84 UC1.CM5 181.01,107.67 181.29,107.67 v1(181.37,107.74) 181.42,107.79 UC1.CN5 ; v1(179.86,108.8) 179.43,108.36 UC1.CJ4 ; v1(179.86,108.8) 179.65,109.01 UC1.CJ3 UC1.CJ2 180.04,110.31 UC1.CK1 ; v1(173.82,91.7) 173.65,91.7 UC1.BV31 ; v1(184.16,101.52) 184.33,101.69 184.56,101.69 184.58,101.67 RC10.2 ; v1(165.14,103.85) 165.14,103.85 165.14,104.75 UC1.BE10 ; UC1.CD25 v1(176.49,95.27) UC1.CC25 v1(175.84,94.44) UC1.CB25 UC1.CA25 UC1.BY25 174.13,94.95 174.13,95.07 173.95,95.25 v1(173.95,95.25) 173.95,95.25 173.95,95.29 173.61,95.63 UC1.BW24 ; v1(176.59,101.99) 176.59,102.1 176.81,102.32 UC1.CD14 176.92,102.28 177.5,102.22 UC1.CF14 177.22,102.75 177.22,102.79 177.22,102.79 v1(177.22,102.78) ; UC1.BL25 168.73,95.84 v1(168.84,95.96) ; v1(183.31,97.87) 183.23,97.79 182.47,97.79 UC1.CP21 ; UC1.BP33 170.98,90.35 v1(170.98,90.37) ; UC1.AC10 v1(151.29,103.85) ; UC1.BF4 166.02,108.32 UC1.BG4 ; UC1.BF4 164.79,108.32 UC1.BE4 ; UC1.BF4 v1(165.41,108.83) UC1.BF3 ; UC1.AH35 v1(154.23,89.36) 154.23,89.48 UC1.AH33 154.08,90.11 153.12,90.11 UC1.AF33 ; UC1.V26 UC1.W27 ; UC1.BU25 UC1.BT25 v1(171.29,94.44) UC1.BR25 v1(170.64,94.44) 170.31,94.76 UC1.BP25 ; UC1.AL32 155.58,90.5 v1(155.56,90.43) 155.51,90.38 155.49,89.99 UC1.AK33 ; UC1.T33 v1(146.68,89.36) UC1.T35 UC1.T36 ; UC1.T33 146.66,89.98 145.44,89.98 UC1.P33 145.36,90.02 144.23,90.02 UC1.L33 144.15,89.98 143.32,89.98 143.3,89.96 UC1.J33 142.92,89.99 143.12,90.48 UC1.K32 143.12,90.76 v1(142.75,91.1) UC1.K31 ; UC1.T33 146.77,90.04 147.85,90.04 UC1.V33 148.01,90.03 149.13,90.03 UC1.Y33 ; UC1.BA28 v1(161.89,93) ; UC1.BE4 v1(164.25,108.22) ; UC1.BE4 UC1.BE3 ; UC1.BU11 172.34,104.17 172.7,104.17 172.77,104.09 UC1.BV11 173.05,104.23 173.42,104.23 UC1.BW11 173.76,103.83 173.86,103.71 v1(173.91,103.7) 173.91,103.71 174.01,103.83 UC1.BY11 UC1.CA11 ; UC1.AM5 v1(157.29,107.82) ; UC1.CD11 177,104.07 v1(177.22,103.78) UC1.CD12 ; UC1.CD11 177.09,104.37 UC1.CF11 177.82,103.92 v1(177.82,103.82) ; UC1.CD11 176.67,104.24 176.31,104.24 UC1.CC11 UC1.CB11 UC1.CA11 ; UC1.T30 v1(146.4,91.73) ; UC1.J24 v1(142.99,95.36) ; UC1.BT15 v1(171.94,101.99) UC1.BT14 ; UC1.P10 v1(145.74,103.88) ; UC1.Y33 149.2,89.48 v1(149.2,89.36) UC1.Y35 ; UC1.Y33 149.26,90.02 150.4,90.02 UC1.AB33 ; UC1.CP35 182.26,88.96 182.74,89.44 UC1.CR34 183.42,89.44 v1(183.44,89.42) ; v1(175.16,110.81) 175.17,110.8 UC1.CB2 UC1.CB3 UC1.CB4 175.17,108.15 v1(174.87,107.84) ; UC1.B5 UC1.C4 v1(139.66,107.78) UC1.D5 140.16,107.13 UC1.D6 ; UC1.AM10 v1(156.83,103.85) ; UT5.G6 UT5.G7 ; UC1.AM28 v1(156.42,93) 156.39,92.87 UC1.AL29 ; v1(174.54,98.63) UC1.BY19 UC1.BY18 ; v1(162.37,103.85) 162.37,104.75 UC1.BA10 ; v1(166.43,90.42) 165.97,89.96 UC1.BF33 ; v1(166.43,90.42) UC1.BH32 ; UC1.T27 v1(146.4,93.64) ; UC1.AY33 161.68,90.06 161.08,90.06 v1(160.94,90.2) 160.7,89.96 UC1.AV33 ; UC1.L6 v1(144.36,107.19) ; UC1.AE7 v1(152.67,106.55) ; v1(137.71,90.68) 137.8,90.77 UC1.A32 ; UC1.Y7 v1(149.9,106.55) ; CC37.2 148.5,84.1 v1(148.33,84.27) ; v1(142.75,93.64) 142.49,93.81 UC1.H27 ; UC1.AG10 154.06,103.85 v1(154.06,103.85) ; UT5.E8 UT5.E7 ; UT5.E8 61.7,103.81 v1(61.79,103.72) ; UT5.E8 UT5.F8 ; UT5.E7 UT5.E6 ; UT5.E7 UT5.F7 ; UC1.B12 138.55,103.83 v1(138.53,103.85) ; UC1.AJ7 155.05,106.29 155.46,106.5 v1(155.46,106.5) ; v1(142.75,92.37) 143.12,92.58 UC1.K29 ; UT5.F8 UT5.F7 ; UT5.F8 v1(61.79,104.31) ; UT5.F8 UT5.G8 ; UT5.F7 UT5.G7 ; UC1.AN31 v1(157.34,91.73) UC1.AN30 ; UC1.CA11 174.86,104.68 v1(174.84,104.7) ; UC1.BL30 UC1.BN30 ; UC1.V4 v1(148.32,108.83) UC1.V3 ; UC1.K30 v1(142.75,91.73) ; UC1.BP3 v1(170.29,108.8) UC1.BP4 ; UC1.G35 UC1.G36 ; UT5.E6 UT5.E5 ; UT5.E5 59.36,103.34 59.04,103.34 v1(58.84,103.14) ; UC1.BH29 v1(166.45,92.37) ; UC1.BK28 v1(167.36,93) ; UC1.CB24 UC1.CC24 ; UC1.CK7 180.14,106.53 v1(180.47,106.53) ; UC1.AL28 155.91,93.05 155.75,92.95 v1(155.51,93) ; v1(60.28,101.33) 60.33,101.38 UT5.A6 ; v1(179.29,96.56) 179.3,96.55 179.3,96.39 UC1.CJ23 ; UT5.G8 UT5.H8 61.28,105.35 v1(61.28,105.78) ; UT5.G8 61.7,104.81 v1(61.79,104.89) ; UT5.G8 UT5.G7 ; UC1.CR6 184.11,107.23 v1(184.15,107.19) ; UC1.BA4 UC1.BA3 ; UT5.A1 57.8,101.78 v1(57.8,101.2) ; UC1.BD33 164.3,89.48 v1(164.3,89.36) UC1.BD35 UC1.BD36 ; v1(140.61,109.66) UC1.F2 ; UC1.BH28 v1(166.45,93) ; UC1.AC27 151.16,93.77 v1(150.96,93.64) ; UC1.A4 UC1.A3 138.21,109.4 v1(137.84,109.77) 137.92,109.85 UC1.B2 UC1.C1 v1(138.75,110.69) ; UC1.BR22 171.31,96.92 v1(171.34,96.92) ; v1(170.98,90.37) 170.94,90.37 170.63,90.68 UC1.BP32 ; v1(170.98,90.37) 171.39,89.96 UC1.BT33 ; UC1.CM31 v1(180.79,91.34) ; UC1.V30 v1(147.31,91.73) ; UC1.E23 UC1.F24 ; UC1.BG28 v1(165.54,93) ; UC1.CB33 175.66,89.99 176.85,89.99 UC1.CE33 ; UC1.CJ36 UC1.CJ35 v1(179.4,89.46) 179.4,89.48 UC1.CJ33 179.34,89.98 178.7,89.98 178.68,89.96 UC1.CG33 ; v1(172.59,97.79) UC1.BU20 v1(172.59,98.63) ; UC1.AW28 v1(160.98,93) ; v1(159.15,90.51) 159.55,90.7 UC1.AU32 ; v1(159.15,90.51) 159.26,89.99 UC1.AT33 159.27,89.48 v1(159.27,89.36) UC1.AT35 UC1.AT36 ; v1(159.15,90.51) 158.66,90.02 158.07,90.02 UC1.AP33 157.98,89.98 156.77,89.98 UC1.AM33 ; UC1.AN8 v1(158.22,105.9) ; UC1.CA15 UC1.BY15 ; UC1.J12 142.49,103.77 v1(142.43,103.85) ; v1(142.75,93) 143.12,93.23 UC1.K28 ; UC1.BT33 171.85,89.48 v1(171.85,89.36) UC1.BT35 UC1.BT36 ; UC1.W7 v1(148.98,106.55) ; UC1.D8 140.15,106 ; UC1.N6 v1(145.28,107.19) ; UC1.CJ28 v1(180.12,93) ; UC1.CA22 v1(174.54,96.95) UC1.BY22 ; v1(143.43,107.19) UC1.J6 ; v1(142.43,99.14) 142.63,99.42 UC1.J18 ; UC1.F15 v1(140.48,101.03) ; UC1.BP12 170.31,103.16 v1(169.99,102.83) ; UC1.AL7 v1(156.37,106.55) ; v1(150.96,91.73) 151.16,91.85 UC1.AC30 ; v1(183.06,93.96) UC1.CP27 ; UC1.AU10 v1(159.6,103.85) ; UC1.G27 v1(141.84,93.64) ; UC1.AE30 v1(151.87,91.73) ; UC1.CN29 v1(181.33,92.94) ; UC1.B18 v1(138.53,99.14) ; UC1.BM9 169.3,104.57 169.28,104.55 169.28,104.52 v1(169.1,104.34) ; UC1.AF30 v1(152.78,91.73) ; v1(164.25,108.22) 164.25,108.63 UC1.BD4 ; UC1.CF28 v1(178.3,93) ; UC1.B15 v1(138.53,101.97) ; UC1.BK4 v1(167.85,108.83) ; UC1.E27 v1(140.93,93.64) ; UC1.K27 v1(143.66,93.64) ; UC1.AN28 v1(157.34,93) ; UC1.AB7 v1(150.82,106.55) ; UC1.AN29 v1(157.34,92.37) ; UC1.U7 v1(148.05,106.55) ; UC1.BD6 v1(164.68,107.19) ; UC1.W10 v1(148.52,103.84) ; UC1.BD7 v1(164.68,106.55) ; UC1.AN7 v1(158.22,106.55) ; UC1.F18 v1(140.48,99.14) ; UC1.B21 UC1.C21 ; UC1.BR19 170.68,99.42 v1(170.61,99.42) 170.6,99.42 UC1.BP19 ; v1(175.84,99.47) UC1.CB18 ; v1(173.89,101.15) UC1.BW15 ; UC1.BY28 v1(174.65,93) ; UC1.AF3 v1(153.2,108.83) UC1.AF4
  BOTTOM w0.25: UC1.BJ7 v1(167.45,106.55)
  BOTTOM w0.254: v1(245.16,39.64) 245.54,39.26 JSATA1.4 ; DT13.2 15.03,103.46 v1(15.34,103.14) ; DT13.2 14.57,103.46 v1(14.26,103.14) ; DT13.2 v1(14.8,102.86) ; v1(13.3,106.06) 13.61,106.37 RT490.2 ; v1(14.26,105.34) 14.57,105.03 DT14.2 ; DT14.2 15.03,105.03 v1(15.34,105.34) ; DT14.2 v1(14.8,105.63) ; JSATA1.7 247.04,38.52 247.04,38.04 v1(247.61,37.48) ; UC1.F12 v1(140.48,103.85) ; JEDP1.8 129.28,131.8 128.96,132.11 v1(128.96,132.57) ; v1(15.88,108.65) DT17.2 ; DT17.2 15.65,108.05 v1(15.34,108.36) ; DT17.2 16.11,108.05 v1(16.42,108.36) ; CC21.2 184.28,115.47 184.91,116.09 v1(184.91,116.85) v1(184.91,117.6) 184.91,118.12 184.59,118.44 181.41,118.44 181.16,118.18 v1(181.16,117.17) 181.16,116.15 180.86,115.85 180.86,114.9 v1(180.88,114.88) 180.88,112.06 v1(180.84,112.02) 180.65,111.83 180.65,111.71 180.09,111.14 UC1.CK1 ; v1(15.34,106.17) 15.65,106.48 DT18.2 ; RT219.2 12.53,103.35 v1(12.22,103.04) ; RT219.2 12.99,103.35 v1(13.3,103.04) ; RT219.2 v1(12.76,102.75) ; v1(14.38,108.47) 14.07,108.16 RT491.2 ; JNGFF3.73 v1(264.82,30.02) ; JEDP1.23 136.77,130.09 v1(136.45,129.76) ; v1(264.22,26.11) 265.32,27.21 JNGFF3.71 ; JEDP1.4 127.28,131.62 126.93,131.96 v1(126.93,132.04) ; RT490.2 14.07,106.37 v1(14.38,106.06) ; RT490.2 v1(13.84,105.78) ; v1(272.21,26.75) 272.21,26.8 273.32,27.91 JNGFF3.39 ; JSATA1.1 244.04,39.53 v1(243.93,39.64) ; RT220.2 12.53,105.14 v1(12.22,105.45) ; RT220.2 v1(12.76,105.74) ; RT220.2 12.99,105.14 v1(13.3,105.45) ; RT491.2 v1(13.84,108.76) ; RT491.2 13.61,108.16 v1(13.3,108.47) ; v1(308.29,9.6) 308.07,9.81 JLED1.3 ; JSATA1.14 250.54,39.5 v1(250.63,39.59) ; JEDP1.6 128.28,131.62 127.86,132.04 v1(127.55,132.04) ; v1(79.01,43.13) 78.96,43.08 PR744.2 ; JEDP1.15 132.77,130.44 132.96,130.25 v1(132.96,129.92) ; DT18.2 v1(15.88,105.88) ; DT18.2 16.11,106.48 v1(16.42,106.17) ; v1(249.34,39.59) 249.54,39.38 JSATA1.12 ; v1(252.79,40.21) 252.54,39.96 252.54,39.48 JSATA1.18 ; JFPBTN1.2 314.19,116.35 314.33,116.2 v1(314.33,115.29) ; v1(264.22,30.43) 264.32,30.32 JNGFF3.75 ; JXDP1.13 79.77,133.76 79.43,133.42 78.16,133.42 77.97,133.62 JXDP1.7 ; v1(184.97,114.88) 184.97,113.41 184.47,112.9 183.25,112.9 181.08,110.74 UC1.CM1 ; JEDP1.25 137.77,131.84 137.61,132 v1(137.61,132.03) 137.53,132.03 137.28,131.78 JEDP1.24 ; JEDP1.39 v1(144.77,130.02) ; v1(255.84,51.66) UN7.3
  BOTTOM w0.305: JXDP1.19 81.57,133.71 v1(82.54,132.73) ; JXDP1.13 79.77,134.47 79.42,134.81 v1(79.42,134.95) ; v1(312.56,117.8) 312.61,117.85 JFPBTN1.8 ; JNGFF3.51 270.32,30.13 v1(270.37,30.17) ; JKBTP1.17 191.49,39.19 191.39,39.1 191.39,38.97 191.36,38.94 v1(191.36,38.86) ; JKBTP1.3 184.49,39.23 v1(184.2,38.94) 183.99,39.14 JKBTP1.2 ; JNGFF3.27 276.32,27.29 276.02,26.99 v1(276.02,26.75) ; JNGFF3.33 274.82,27.82 274.12,27.12 v1(274.12,26.75) ; JDIMM1.90 123.7,45.78 ; JNGFF3.15 279.32,30.01 v1(279.36,30.05) ; v1(272.6,34.74) 272.7,34.65 JNGFF1.1 ; JAPS1.12 240.24,84.64 v1(240.52,84.92) ; v1(232.34,38.39) 232.34,39.06 232.27,39.13 JUSH1.17 ; v1(273.57,73.31) 273.58,73.31 JNGFF2.49 ; JNGFF2.3 260.08,73.22 v1(260.32,72.97) 260.58,73.23 JNGFF2.5 ; v1(85.53,132.14) 85.53,131.72 85.47,131.65 JXDP1.32 ; v1(167.23,82.96) 167.33,82.96 167.73,83.36 167.73,84.35 CC36.2 ; JXDP1.8 78.27,131.92 v1(78.16,132.03) ; JESPI.9 223.99,82.27 224.11,82.15 v1(224.11,81.78) ; JNGFF2.25 v1(267.58,73.27) ; JDIMM1.73 119.45,55.88 ; JNGFF1.69 289.7,32.57 290.06,32.2 v1(290.41,32.2) ; v1(277.23,38.86) 276.95,39.15 JNGFF1.18 ; v1(272.22,30.05) 271.82,29.65 JNGFF3.45 ; v1(76.58,132.03) 76.47,131.92 JXDP1.2 ; v1(285.81,31.82) 285.2,32.43 JNGFF1.51 ; v1(277.93,26.75) 277.82,26.85 JNGFF3.21 ; v1(84.26,132.67) 84.19,132.67 83.67,132.15 JXDP1.26 ; JDIMM1.68 118.2,45.91 ; v1(124.84,45.54) 124.7,45.68 JDIMM1.94 ; v1(280.98,29.9) 280.82,29.74 JNGFF3.9 ; JAPS1.8 242.24,83.16 242.54,82.85 v1(242.54,82.85) ; v1(239.39,84.93) 239.24,84.77 JAPS1.14 ; v1(85.11,134.93) 85.17,134.87 JXDP1.31 ; v1(262.27,75.68) 262.08,75.49 JNGFF2.11 ; JKBTP1.15 190.49,41.32 v1(190.3,41.5) ; v1(214.05,84.08) 214.05,83.58 214.47,83.16 JDEG1.10 ; JNGFF2.37 270.58,75.37 v1(270.38,75.57) ; v1(127.4,45.57) 127.7,45.87 JDIMM1.106 ; 114.2,45.86 JDIMM1.52 ; JDIMM1.78 120.7,45.82 ; v1(241.11,84.93) 241.24,84.8 JAPS1.10 ; RC420.1 131.31,91.39 132.06,92.13 v1(132.7,92.13) ; JXDP1.50 90.87,131.57 90.42,132.02 v1(90.41,132.02) ; JDIMM1.107 127.95,56.45 ; JUSH1.21 v1(234.27,38.9) ; JXDP1.62 75.52,133.34 v1(76.13,132.73) ; v1(86.95,134.93) 86.97,134.92 JXDP1.37 ; JNGFF1.63 288.2,31.98 v1(287.82,31.59) 287.41,31.59 286.7,32.3 JNGFF1.57 ; JNGFF1.45 283.7,32.76 v1(283.33,32.4) ; JXDP1.20 81.87,130.4 81.78,130.31 v1(81.8,130.31) ; JNGFF2.65 277.58,73.6 v1(277.36,73.39) 277.08,73.68 JNGFF2.63 ; v1(193.35,39.05) 192.99,39.42 JKBTP1.20 ; v1(291.45,32.46) 291.2,32.72 JNGFF1.75 ; JDIMM1.81 121.45,56.1 ; JNGFF3.57 268.82,27.6 268.41,27.19 v1(268.41,26.74) ; JXDP1.25 83.37,134.94 v1(83.36,134.95) ; JUSH1.3 225.27,39.17 v1(224.86,38.76) ; JDIMM1.86 122.7,45.81 ; JDIMM1.103 126.95,55.85 v1(127.34,56.24) ; v1(266.34,76.15) 266.08,75.88 JNGFF2.19 ; JNGFF2.43 v1(272.08,73.24) ; v1(233.68,38.9) 233.77,39 JUSH1.20 ; JDIMM1.10 v1(103.7,45.47) ; JXDP1.14 v1(80.07,132.73) ; JNGFF2.31 v1(269.08,73.34) ; JDIMM1.48 113.2,45.97 ; v1(187.45,41.5) 187.49,41.46 JKBTP1.9 ; 121.7,45.81 JDIMM1.82 ; JDIMM1.93 124.45,55.82 ; JDIMM1.56 115.2,46.06 ; JDIMM2.167 v1(222.35,52.25) ; JXDP1.49 v1(90.57,134.97) ; JXDP1.38 87.27,131.54 87.43,131.71 87.43,131.86 87.55,131.98 v1(87.55,132.02) ; JDB1.7 v1(34.2,87.2) ; JDIMM1.57 115.45,56.06 ; JDB1.6 30.81,88.36 v1(30.54,88.08) ; 109.95,53.24 JDIMM1.35 ; JDIMM1.36 110.2,45.87 ; JDB1.8 v1(29.93,86.94)
  BOTTOM w0.356: CE13.2 246.66,95.22 CE14.2 245.58,95.22 v1(245.52,95.17) ; CI7.2 v1(25.71,88.08) ; CE15.2 252.28,92.85 v1(252.85,93.41) ; CN78.2 257.23,37.32 CN9.2 258.42,37.32 258.5,37.23 ; CV26.2 303.18,82.81 v1(302.89,82.81) 302.57,82.5 CV27.2 ; v1(298.45,83.13) 298.23,82.92 CV653.2 ; CC10.2 v1(204.49,103.48) ; v1(54.73,99.66) CT74.2
  BOTTOM w0.381: PQ7.3 80.59,108.39 81.34,107.64 82.61,107.64 83.57,108.61 PR24.2 83.57,109.09 82.86,109.8 v1(82.61,109.8) ; v1(36.66,107.85) 36.62,107.81 CT119.2 ; v1(253,102.76) 252.9,102.66 CE25.2 ; v1(228.73,79.47) 228.73,79.77 228.99,80.03 JESPI.11 ; v1(187.54,92.76) 186.75,93.55 CC75.2 ; v1(250.46,95.83) 250.93,96.3 CE19.2 ; PC753.2 v1(86.29,50) ; v1(80.92,98.52) 81.94,98.52 82.21,98.8 PU801.3 ; PU800.4 55.48,87.28 55.1,87.66 v1(55.1,87.96) ; PR819.2 84.64,92.86 PQ804.4 84.53,93.28 v1(84.01,93.8) 83.23,94.58 PQ804.1 ; v1(245.8,90.79) 246.12,91.11 CE11.2 ; v1(64.7,89.48) 65.35,89.48 PQ813.1 65.52,89.81 65.26,90.07 PR846.2 ; CT72.2 56.95,100.32 57.6,100.96 57.6,101 v1(57.8,101.2) ; CC29.2 163.66,115.09 v1(163.56,115.19) ; PC1098.2 PC1100.2 v1(123.34,113.52) ; v1(244.53,92.78) 244.71,92.78 245.26,93.33 CE69.2 CE12.2 ; PR739.2 75.18,45.4 77.01,45.4 v1(77.02,45.41) 77.29,45.68 PU701.3 ; v1(150.87,117.36) 150.75,117.48 CC1481.2 ; PC314.1 PC228.2 v1(221.84,29.75) ; DT39.3 v1(21.33,101.22) ; CC9.2 204.74,92.28 v1(204.73,92.26) ; PQ10.1 88.21,119.13 v1(88.46,118.88) ; PQ10.4 90.48,120.74 v1(90.99,121.25) ; v1(186.2,117.36) 186.35,117.36 186.73,117.74 QC4.4 ; CN17.2 253.3,53.05 v1(253.5,53.26) ; CC98.2 v1(186.51,100.28) ; v1(34.48,101.99) CT122.2 ; PC748.2 89.68,50.04 v1(89.68,49.77) 89.68,49.07 PC745.2 ; v1(222.63,79.41) 222.63,79.63 222.49,79.78 JESPI.12 ; v1(241.66,92.7) 241.79,92.82 CE10.2 ; PC226.2 v1(219.35,29.75) ; PQ813.4 v1(66.82,87.08) ; DI1.3 v1(18.09,89.67)
  BOTTOM w0.406: 299.65,66.49 v1(300.86,66.49) ; v1(268.27,41.38) 267.55,41.38 QZ17.3 ; QC4.1 188.26,116.83 v1(188.62,116.83) ; JDEG1.12 213.47,80.67 213.36,80.78 v1(213.36,80.97) ; DI6.3 v1(298.64,49.22)
  BOTTOM w0.457: v1(250.23,48.55) 250.52,48.84 RN21.2 RN11.1 ; QN6.3 258.05,54.96 v1(258.05,56.42) ; CC1464.2 185.99,96.52 v1(185.99,96.85) ; v1(55.75,108.34) 55.3,107.89 CT73.2
  BOTTOM w0.508: PR855.2 PC814.1 v1(83.62,103.71) ; RC417.1 85.15,128.37 v1(85.57,127.95) 86.04,128.42 RC418.1 ; DI3.1 298.29,52.59 v1(296.54,52.59) ; YC1.2 184.1,117.72 184.22,117.6 v1(184.91,117.6) ; JAPS1.20 v1(236.15,81.1) ; RC116.2 191.63,91.26 v1(191.99,91.62) ; PC125.2 86.42,82.56 v1(86.29,82.69) ; v1(62,111.62) CT86.2 ; PR631.1 PH601.1 v1(119.79,102.66) ; PC126.2 v1(74.48,73.1) ; JIRTS1.12 102.55,131.55 v1(103.05,132.05) ; v1(34.49,99.88) 35.09,99.88 RT300.2 ; v1(82.91,127.95) 83.61,128.65 RC416.1 ; v1(239.25,125.13) 238.22,124.1 JRTC1.4 ; PJPDC1.6 58.47,115.3 58.83,114.94 64.47,114.94 65.08,115.55 v1(65.08,116.28) ; RN9.1 261.23,48.59 v1(261.62,48.97) 261.23,49.35 RN15.1 ; PC801.1 61.4,84.15 v1(61.53,84.27) PC813.2 ; JKBTP1.21 194.94,37.64 194.3,38.28 v1(194.3,38.36) ; CI6.2 v1(24.82,87.48) ; JDEG1.11 220.6,80.22 v1(220.76,80.06) ; v1(82.71,63.33) 83.42,62.62 JFAN1.6 ; JDIMM1.262 v1(101.02,66.04) ; PC692.2 PC691.2 90.85,84.12 v1(91.32,84.59) 91.8,84.11 PC689.2 ; v1(168.28,121.55) 168.98,120.85 CC301.2 ; PR103.2 201.66,36.77 v1(201.6,36.71) ; CE54.2 250.47,88.14 250.47,87.4 v1(250.55,87.32) ; v1(89.39,43.57) 88.91,44.05 PC738.2 88.59,44.04 PC739.1 ; v1(298.89,32.01) 299.4,32.52 DA2.1 ; v1(184.97,114.88) 184.89,114.88 184.38,115.39 CC21.2 ; PC754.1 75.37,41.15 v1(75.37,40.21) ; JEDP1.45 147.67,130.5 v1(147.07,131.1) ; JEDP1.44 144.42,126.28 v1(144.2,126.06) ; CC22.2 181.39,115.39 v1(180.88,114.88) ; RD5.2 165.65,43.43 v1(165.29,43.06) ; v1(38.92,91.6) 38.54,91.22 CT70.2 ; v1(193.86,100.91) 193.75,101.03 CC78.2 ; v1(185.52,81.11) 185.42,81.22 RC515.2 185.56,81.87 186.57,81.87 187.08,82.37 RC96.2 ; RC758.2 v1(203.77,103.96) ; UC5.4 214.43,89.48 v1(214.24,89.67) ; CA13.1 v1(298.15,37.79) CA12.2 ; v1(240.34,122.37) 240.97,121.74 JRTC1.2 ; v1(39.37,95.96) 39.37,96.13 39.05,96.45 RT414.2 ; CN16.2 RN7.1 v1(261.48,46.3) ; CZ3.2 96.66,129.35 96.02,128.71 v1(96.02,128.42) ; v1(243.22,39.51) 242.99,39.28 242.99,38.4 JSATA1.24 ; CC1452.2 v1(205.8,99.51) ; DA3.1 v1(298.79,37.79) ; RC730.2 192.24,104.72 v1(191.65,104.72) ; v1(252.79,40.21) 253.32,40.21 254.05,39.48 254.05,38.95 254.59,38.41 JSATA1.21 ; v1(298.6,83.75) 298.97,84.12 RV55.1 ; v1(251.01,86.18) 251.47,85.72 RE56.2 ; UC6.4 v1(216.24,99.13) ; JLED1.7 v1(311.02,5.85) ; PC800.2 PR815.2 v1(53.2,84.4) ; CE38.2 RE77.2 245.6,97.41 v1(245.17,96.97) ; v1(60.59,90.17) PR843.2 PC812.2 ; UV2.2 301.23,83.08 v1(300.71,82.56) ; RT65.2 63.25,98.63 v1(62.86,98.24) 62.49,98.62 RT64.2 ; RC446.1 RC444.1 192.77,92.98 192.97,92.77 v1(192.97,92.62) ; v1(186.51,94.97) 186.48,94.94 CC84.2 ; v1(187.7,108.66) 189.33,108.66 190.25,107.73 RC6.1 ; JNGFF3.76 283.93,26.34 v1(284.03,26.24) ; CL22.1 291.28,94.83 v1(292.14,95.69) ; v1(184.91,116.85) 184.98,116.85 RC751.1 ; RD7.2 v1(168.21,42.82) ; CC1477.2 183.75,119.54 183.25,119.03 v1(183.25,118.95) ; RC337.2 204.02,106.63 204,106.65 v1(203.82,106.65) 203.6,106.65 203.58,106.63 RC844.1 ; v1(190.3,102.5) 189.86,102.05 RC745.2 ; v1(190.3,102.5) 190.5,102.31 190.5,101.62 191.23,100.88 192.13,100.88 CC302.2 ; v1(190.3,102.5) 189.99,102.82 RC63.2 ; v1(66.42,109.65) 66.94,109.65 67.32,109.27 RT103.2 ; v1(191.65,105.59) 192.16,105.59 RC521.2 RC520.2 ; RC448.1 190.13,90.19 189.03,89.1 v1(188.4,89.1) ; RC519.2 183.04,80.93 v1(183.76,80.21) ; RC760.2 v1(203.89,103.07) ; v1(42.16,110.69) CT618.2 ; v1(316.41,23.57) 316.43,23.6 JSIM1.C5 ; CI45.2 v1(19.87,83.77) ; JNGFF3.77 263.23,27.1 v1(264.22,26.11) ; RN17.1 250.79,45.01 v1(250.79,44.91) ; UI1.2 v1(22,86.94) ; v1(254.82,81.1) 254.08,81.1 253.51,80.53 CZ20.2 ; v1(244.22,95.15) 243.64,95.72 CE57.2 ; CI46.2 v1(18.85,83.77) ; PC128.2 76.26,69.3 76,69.05 v1(75.69,69.05) 75.37,69.37 PR116.2 ; JRTC1.3 v1(243.53,126.19) ; JSPI1.21 v1(210.68,82.75) ; v1(34.49,104.21) RT142.2 ; v1(86.97,67.83) 86.62,68.17 PC146.2 86.61,68.64 PC142.2 ; v1(91.98,93.74) 91.98,93.16 91.97,93.15 PR653.1 ; PC111.1 205.59,38.38 205.08,37.87 v1(205.08,37.83) ; RC454.1 179.68,81.18 v1(179.67,81.18) RC518.2 ; JNGFF1.76 271.6,32.99 271.23,32.63 v1(271.23,31.95) ; v1(244.06,33.93) 243.59,34.4 243,34.4 JSATA1.23 ; PC741.2 v1(129.6,41.2) ; PC141.2 v1(178.75,32.15) ; PC1003.2 v1(122.74,111.33) ; CC308.2 93.15,127.65 93.47,127.33 v1(93.47,127.01) ; v1(80.44,42.68) 80.45,42.68 80.96,42.17 PC725.2 ; v1(78.67,44.65) 78.67,44.86 78.55,44.99 PR709.1 ; CT85.2 65.26,110.72 v1(65.52,110.45) ; PC602.2 v1(87.65,103.45) ; RC759.2 203.39,104.85 v1(203.89,105.36) 203.51,105.74 RC757.2 ; v1(204.73,92.26) CC1453.2 ; JUSH1.28 222.89,36.65 v1(223.64,35.9) ; RC75.2 v1(171.16,81.21) ; YC1.4 181.84,116.62 181.29,117.17 v1(181.16,117.17) ; v1(55.1,87.96) PC804.2 PR817.2 ; v1(255.65,34.49) 255.56,34.4 JSATA1.22 ; JSPI1.22 v1(196.98,82.8) ; JKBTP1.22 v1(181.54,35.13) ; v1(138.22,116.22) 138.4,116.22 138.91,115.71 138.91,115.43 139.63,114.71 RC565.2 ; v1(190.18,98.17) 190.18,97.53 CC1476.2 ; CC306.2 90.78,128.2 CC326.2 90.71,127.94 90.57,127.79 90.57,127.09 v1(90.56,127.08) ; PD701.2 98.55,43.63 v1(98.86,43.32) ; v1(297.04,25.28) 296.66,24.91 JSPK1.5 ; v1(86.89,117.32) 86.42,116.85 PQ12.3 ; v1(112.07,133.3) 111.52,132.75 JIRTS1.11 ; v1(135.82,113.74) 135.9,113.66 RC161.2 ; JSIM1.4 v1(308.45,27.1) ; v1(185.48,98.57) 185.48,98.55 185.02,98.1 RC401.2 ; JSPK1.6 286.74,22.74 285.36,22.74 284.86,22.24 v1(284.86,21.7) ; v1(85.1,52.73) PC750.2 PC749.2 83.41,51.75 PC751.2 ; PC690.2 93.3,83.87 v1(93.56,84.12) ; v1(68,104.98) RT99.2 ; JLED1.8 v1(304.62,5.79) ; v1(138.35,127.4) 138.07,127.12 JEDP1.43 ; v1(76.16,62.33) 75.5,62.33 JFAN1.5 ; JNGFF2.69 279.17,73.96 v1(278.57,73.35) ; v1(68.09,102.82) CT76.2 ; v1(80.2,52.65) 80.78,52.07 PR723.2 ; 47.37,86.31 v1(48.57,86.31) ; JNGFF1.77 v1(292.3,36.03) ; JIRTS1.7 105.42,132.91 105.73,132.6 v1(106.17,132.6) 106.22,132.66 JIRTS1.6 ; v1(37.65,110.56) CT614.2 CT617.2 ; v1(76.23,48.94) 76.78,49.49 PQ703.3 76.97,49.98 PR720.2 77.61,50.87 PR716.2 ; RC402.2 v1(180.14,115.39) ; PC1006.2 v1(122.74,112.6) ; PR506.2 v1(205.74,109.15) ; JUSH1.27 237.62,35.55 v1(237.4,35.55) ; CC300.2 v1(159.57,114.13) ; v1(68.09,101.04) CT75.2 ; v1(37.46,95.9) 37.46,96.14 37.52,96.21 RT415.2 ; RE86.2 215.07,86.57 v1(215.12,86.61) ; 258.5,37.23 CN8.2 259.17,37.23 259.3,37.36 v1(259.47,37.36) ; v1(61.53,89.1) PC811.2 PR842.2 ; PC726.2 83.65,42.65 v1(83.5,42.81) ; v1(55.08,84.43) PC805.2 ; CC319.2 v1(190.11,99.64) ; RN13.1 v1(250.25,51.13) ; JSIM1.8 v1(309.75,11.12) ; v1(34.49,106.5) RT140.2 ; PC119.2 v1(74.48,73.99)
  vias: v1(0.43,110.26) v1(0.43,107.82) v1(0.43,104.82) v1(0.43,101.83) v1(0.46,77.45) v1(1.12,79.5) v1(1.62,113.57) v1(1.65,83.47) v1(2.07,81.15) v1(2.07,77.85) v1(3.35,101.28) v1(3.7,98.31) v1(3.98,81.15) v1(3.98,77.85) v1(4.55,77.43) v1(4.62,113.57) v1(4.65,83.47) v1(4.76,102.18) v1(4.97,109.29) v1(4.93,79.5) v1(4.98,105.3) v1(6.82,110.3) v1(6.83,103.85) v1(7.55,77.43) v1(7.62,113.57) v1(7.68,103.83) v1(7.81,110.31) v1(8.5,102.18) v1(8.82,111.64) v1(9.4,77.66) v1(9.66,98.23) v1(9.83,82.19) v1(10.63,83.17) v1(10.92,113.57) v1(11.04,111.14) v1(11.03,99.63) v1(12.11,78.93) v1(13.57,82.81) v1(14.02,112.4) v1(14,97.83) v1(14,84.83) v1(14.83,80.19) v1(14.97,114.05) v1(14.97,110.75) v1(16.88,114.05) v1(16.88,110.75) v1(17.19,102.46) v1(17.55,81.46) v1(17.83,112.4) v1(18.16,93.72) v1(18.16,93.09) v1(18.28,98.56) v1(18.28,97.86) v1(18.47,92.47) v1(18.47,91.83) v1(18.87,102.75) v1(18.92,98.56) v1(19.23,106.7) v1(19.49,114.57) v1(20.26,82.73) v1(20.35,105.52) v1(21.75,88.42) v1(22.49,114.57) v1(22.79,91.32) v1(23.07,107.81) v1(22.98,83.99) v1(24.42,106.73) v1(25.2,115.85) v1(25.78,111.31) v1(25.93,84.53) v1(26.28,98.55) v1(26.54,114.47) v1(26.88,106.64) v1(26.88,102.61) v1(27.17,115.74) v1(27.23,118.05) v1(27.59,99.03) v1(27.58,97.16) v1(27.81,117.01) v1(27.81,114.47) v1(27.96,123.96) v1(27.96,120.96) v1(28.44,115.74) v1(28.66,126.87) v1(28.92,84.53) v1(29.08,124.63) v1(29.08,122.09) v1(29.08,119.55) v1(29.08,117.01) v1(29.08,114.47) v1(29.71,125.9) v1(29.71,123.36) v1(29.71,120.82) v1(29.71,118.28) v1(29.71,115.74) v1(30.35,124.63) v1(30.35,122.09) v1(30.35,119.55) v1(30.35,117.01) v1(30.35,114.47) v1(30.92,110.68) v1(30.92,106.64) v1(30.92,102.61) v1(30.98,125.9) v1(30.98,123.36) v1(30.98,120.82) v1(30.98,118.28) v1(30.98,115.74) v1(31.66,126.87) v1(31.62,124.63) v1(31.62,122.09) v1(31.62,119.55) v1(31.62,117.01) v1(31.75,95.32) v1(31.92,84.53) v1(32.25,125.9) v1(32.25,123.36) v1(32.25,120.82) v1(32.25,118.28) v1(32.25,115.74) v1(32.89,124.63) v1(32.89,122.09) v1(32.89,119.55) v1(32.89,117.01) v1(33.4,94.94) v1(33.52,125.9) v1(33.52,123.36) v1(33.52,120.82) v1(33.52,118.28) v1(33.52,115.74) v1(34.16,124.63) v1(34.16,122.09) v1(34.16,119.55) v1(34.16,117.01) v1(34.66,126.87) v1(34.79,125.9) v1(34.79,123.36) v1(34.79,120.82) v1(34.79,118.28) v1(34.79,115.74) v1(34.92,84.53) v1(35.43,124.63) v1(35.43,122.09) v1(35.43,119.55) v1(35.43,117.01) v1(36.06,125.9) v1(36.06,123.36) v1(36.06,120.82) v1(36.06,118.28) v1(36.06,115.74) v1(36.7,124.63) v1(36.7,122.09) v1(36.7,119.55) v1(36.7,117.01) v1(37.33,125.9) v1(37.33,123.36) v1(37.33,120.82) v1(37.33,118.28) v1(37.33,115.74) v1(37.66,126.87) v1(37.97,124.63) v1(37.97,122.09) v1(37.97,119.55) v1(37.97,117.01) v1(37.92,84.53) v1(38.6,125.9) v1(38.6,123.36) v1(38.6,120.82) v1(38.6,118.28) v1(38.6,115.74) v1(39.24,124.63) v1(39.24,122.09) v1(39.24,119.55) v1(39.24,117.01) v1(39.35,98.62) v1(39.87,125.9) v1(39.87,123.36) v1(39.87,120.82) v1(39.87,118.28) v1(39.87,115.74) v1(40.51,124.63) v1(40.51,122.09) v1(40.51,119.55) v1(40.51,117.01) v1(40.65,126.87) v1(40.91,84.53) v1(41.14,125.9) v1(41.14,123.36) v1(41.14,120.82) v1(41.14,118.28) v1(41.14,115.74) v1(41.09,98.69) v1(41.78,124.63) v1(41.78,122.09) v1(41.78,119.55) v1(41.78,117.01) v1(42.41,125.9) v1(42.41,123.36) v1(42.41,120.82) v1(42.41,118.28) v1(42.41,115.74) v1(42.91,98.69) v1(43.05,124.63) v1(43.05,122.09) v1(43.05,119.55) v1(43.05,117.01) v1(43.65,126.87) v1(43.68,125.9) v1(43.68,123.36) v1(43.68,120.82) v1(43.68,118.28) v1(43.91,84.5) v1(44.32,124.63) v1(44.32,122.09) v1(44.32,119.55) v1(44.95,125.9) v1(44.95,123.36) v1(44.95,120.82) v1(44.95,118.28) v1(45.59,124.63) v1(45.59,122.09) v1(45.59,119.55) v1(46.22,125.9) v1(46.22,123.36) v1(46.22,120.82) v1(46.31,115.35) v1(46.65,126.87) v1(46.86,124.63) v1(46.86,122.09) v1(46.89,84.2) v1(47.05,108.65) v1(47.05,106.88) v1(47.06,105.12) v1(47.05,103.32) v1(47.05,101.55) v1(47.39,116.43) v1(47.4,99.79) v1(47.49,125.9) v1(47.49,123.36) v1(47.49,120.82) v1(47.84,98.42) v1(48.13,124.63) v1(48.13,122.09) v1(48.5,117.55) v1(48.48,115.43) v1(48.5,99.77) v1(48.76,125.9) v1(48.76,123.36) v1(49.08,101.15) v1(49.4,124.63) v1(49.64,126.87) v1(49.59,118.72) v1(49.67,116.61) v1(49.83,83.59) v1(50.03,125.9) v1(50.03,123.36) v1(50.67,124.63) v1(50.76,119.81) v1(50.94,117.88) v1(51.05,115.36) v1(51.3,125.9) v1(51.62,107.79) v1(51.65,106.03) v1(52.16,121.5) v1(52.64,126.87) v1(52.68,82.68) v1(53.28,103.35) v1(53.41,105.89) v1(53.41,105.26) v1(53.59,122.38) v1(54.93,128.8) v1(55.4,130.57) v1(55.43,81.47) v1(58.03,79.99) v1(59.15,110.18) v1(59.43,116.02) v1(60.07,116.02) v1(60.04,78.57) v1(60.15,110.18) v1(60.15,108.97) v1(60.35,130.57) v1(60.7,116.02) v1(61.34,116.02) v1(61.73,77.17) v1(63.35,130.57) v1(63.33,75.62) v1(64.04,136.57) v1(64.45,117.55) v1(64.45,116.91) v1(64.45,116.28) v1(64.7,119.33) v1(64.92,73.8) v1(65.08,117.55) v1(65.08,116.91) v1(65.34,119.33) v1(65.52,133.96) v1(65.72,117.55) v1(65.72,116.91) v1(65.72,116.28) v1(65.97,119.33) v1(65.96,36.5) v1(65.96,33.51) v1(65.96,30.51) v1(66.12,39.41) v1(66.3,131.07) v1(66.35,117.55) v1(66.35,116.91) v1(66.51,71.62) v1(66.61,119.33) v1(66.66,28.68) v1(67.03,136.57) v1(67.24,119.33) v1(67.54,41.67) v1(67.62,134) v1(68.02,69.04) v1(68.57,135.65) v1(68.57,132.35) v1(68.75,44.07) v1(69.26,66.31) v1(69.65,28.68) v1(70.21,63.47) v1(70.48,135.65) v1(70.48,132.35) v1(70.48,114.5) v1(70.48,113.87) v1(70.86,60.54) v1(70.93,45.59) v1(71.2,57.57) v1(71.26,54.57) v1(71.26,51.57) v1(71.26,48.57) v1(71.43,134) v1(71.52,37.67) v1(71.52,37.08) v1(72.13,119.52) v1(72.65,28.68) v1(72.92,137.57) v1(73.4,119.52) v1(73.72,75.77) v1(74.8,75.77) v1(74.92,91.2) v1(75.2,114.69) v1(75.18,114.06) v1(75.65,28.68) v1(75.92,137.57) v1(76.22,93.45) v1(76.22,88.95) v1(76.51,75.77) v1(77.15,136.54) v1(77.4,68.17) v1(77.4,67.54) v1(77.4,66.9) v1(77.4,66.27) v1(77.4,65.63) v1(77.53,75.77) v1(77.78,136.54) v1(77.92,33) v1(78.04,68.17) v1(78.04,67.54) v1(78.04,66.9) v1(78.04,66.27) v1(78.04,65.63) v1(78.67,68.17) v1(78.67,67.54) v1(78.67,66.9) v1(78.67,66.27) v1(78.67,65.63) v1(78.65,28.68) v1(78.83,93.45) v1(78.83,88.95) v1(78.92,137.57) v1(79.26,75.26) v1(79.26,74.62) v1(79.22,35.25) v1(79.22,30.75) v1(79.31,71.96) v1(79.31,68.17) v1(79.31,67.54) v1(79.31,66.9) v1(79.31,66.27) v1(79.31,65.63) v1(80.13,91.2) v1(81.34,136.54) v1(81.64,28.68) v1(81.83,35.25) v1(81.83,30.75) v1(81.92,137.57) v1(81.97,136.54) v1(82.61,136.54) v1(83.13,33) v1(83.22,47.58) v1(83.22,46.47) v1(83.22,45.35) v1(84.34,47.58) v1(84.34,46.47) v1(84.34,45.35) v1(84.64,28.68) v1(84.91,137.57) v1(85.46,47.58) v1(85.46,46.47) v1(85.46,45.35) v1(86.04,31.33) v1(87.64,28.68) v1(87.74,136.57) v1(88.2,98.24) v1(88.2,96.72) v1(88.2,95.2) v1(89.19,65.86) v1(89.33,57.06) v1(89.33,31.15) v1(89.72,98.24) v1(89.72,96.72) v1(89.72,95.2) v1(90.72,136.88) v1(91.24,98.24) v1(91.24,96.72) v1(91.24,95.2) v1(91.73,87.48) v1(91.73,68) v1(91.73,66.38) v1(92.02,32.48) v1(92.31,87.48) v1(92.57,86.92) v1(92.64,68.21) v1(92.96,70.62) v1(92.96,53.73) v1(93.15,109.67) v1(93.21,68.46) v1(93.53,70.94) v1(93.53,70.3) v1(93.53,69.67) v1(93.53,69.03) v1(93.57,66.28) v1(93.64,137.57) v1(93.66,110.31) v1(93.59,53.73) v1(93.85,109.67) v1(93.89,135.96) v1(93.96,30.19) v1(94.08,110.88) v1(94.1,71.07) v1(94.23,53.73) v1(94.29,110.31) v1(94.28,68.83) v1(94.47,135.96) v1(94.61,109.74) v1(94.71,110.88) v1(94.7,71.07) v1(94.86,53.73) v1(94.93,110.31) v1(94.93,109.17) v1(95.05,135.96) v1(95.25,109.74) v1(95.35,110.88) v1(95.56,111.45) v1(95.56,110.31) v1(95.56,109.17) v1(95.5,53.73) v1(95.88,109.74) v1(95.93,66.32) v1(95.98,110.88) v1(96.13,53.73) v1(96.2,111.45) v1(96.2,110.31) v1(96.2,109.17) v1(96.52,112.02) v1(96.52,109.74) v1(96.52,66.32) v1(96.54,28.68) v1(96.63,137.57) v1(96.62,110.88) v1(96.83,111.45) v1(96.83,110.31) v1(96.83,109.17) v1(96.9,112.6) v1(97.15,112.02) v1(97.15,109.74) v1(97.25,110.88) v1(97.47,111.45) v1(97.47,110.28) v1(97.47,109.17) v1(97.53,112.6) v1(97.79,112.02) v1(97.89,110.88) v1(98.1,111.45) v1(98.1,109.17) v1(98.29,120.73) v1(98.36,108.63) v1(98.74,109.17) v1(98.99,108.63) v1(99.54,28.68) v1(99.63,137.57) v1(99.62,107.47) v1(100.27,108.18) v1(100.27,106.62) v1(101.4,72.08) v1(101.4,71.45) v1(101.57,108.18) v1(101.57,106.62) v1(101.65,38.16) v1(101.65,36.84) v1(101.65,35.53) v1(101.65,34.21) v1(102.04,72.08) v1(102.04,71.45) v1(102.04,56.3) v1(102.23,52.61) v1(102.23,51.08) v1(102.55,103.32) v1(102.54,28.68) v1(102.63,137.57) v1(102.66,38.16) v1(102.66,36.84) v1(102.66,35.53) v1(102.58,34.21) v1(102.67,72.08) v1(102.67,71.45) v1(102.87,108.18) v1(102.87,106.62) v1(102.87,38.75) v1(102.87,31.76) v1(102.87,31.13) v1(103.04,45.57) v1(103.24,105.47) v1(103.19,87.69) v1(103.5,31.76) v1(103.5,31.13) v1(103.66,38.16) v1(103.66,36.84) v1(103.66,35.53) v1(103.72,107.83) v1(103.69,38.75) v1(104.04,52.68) v1(104.04,50.4) v1(104.08,56.28) v1(104.14,31.76) v1(104.14,31.13) v1(104.77,31.76) v1(104.77,31.13) v1(105.15,75.38) v1(105.35,106.5) v1(105.33,87) v1(105.41,31.76) v1(105.41,31.13) v1(105.5,136.73) v1(105.54,28.68) v1(105.72,75.96) v1(105.72,74.81) v1(105.69,45.49) v1(105.85,56.25) v1(105.82,52.43) v1(105.82,50.9) v1(105.82,49.38) v1(106.04,31.76) v1(106.04,31.13) v1(106.1,94.37) v1(106.1,93.74) v1(106.1,93.1) v1(106.1,92.47) v1(106.1,72.59) v1(106.36,84.88) v1(106.29,75.38) v1(106.48,89.97) v1(106.48,88.67) v1(106.48,87.38) v1(106.74,72.59) v1(106.68,31.76) v1(106.68,31.13) v1(107.17,45.5) v1(107.18,91.26) v1(107.33,90.62) v1(107.5,94.37) v1(107.5,93.74) v1(107.5,93.1) v1(107.5,92.47) v1(107.5,91.83) v1(107.69,86.53) v1(107.73,56.3) v1(107.76,52.42) v1(107.76,50.89) v1(107.76,49.37) v1(107.82,91.26) v1(108.04,89.97) v1(108.04,88.67) v1(108.04,87.38) v1(108.14,108.85) v1(108.14,94.37) v1(108.14,93.74) v1(108.14,93.1) v1(108.14,92.47) v1(108.14,91.83) v1(108.45,91.26) v1(108.5,136.57) v1(108.53,28.68) v1(108.67,61.75) v1(108.77,108.85) v1(108.77,94.37) v1(108.77,93.74) v1(108.77,93.1) v1(108.77,92.47) v1(108.77,91.83) v1(108.83,90.69) v1(109.15,106.06) v1(109.15,105.42) v1(109.15,104.79) v1(109.15,104.15) v1(109.15,103.52) v1(109.15,102.88) v1(109.09,91.26) v1(109.12,62.19) v1(109.41,108.85) v1(109.41,94.37) v1(109.41,93.74) v1(109.41,93.1) v1(109.47,90.69) v1(109.39,52.68) v1(109.44,51.85) v1(109.44,49.56) v1(109.39,45.57) v1(109.56,62.64) v1(109.79,106.06) v1(109.79,105.42) v1(109.79,104.79) v1(109.79,104.15) v1(109.79,103.52) v1(109.79,102.88) v1(110.04,108.85) v1(110.42,106.06) v1(110.42,105.42) v1(110.42,104.79) v1(110.42,104.15) v1(110.42,103.52) v1(110.42,102.88) v1(110.68,108.85) v1(111.06,106.06) v1(111.06,105.42) v1(111.06,104.79) v1(111.06,104.15) v1(111.06,103.52) v1(111.06,102.88) v1(111.31,108.85) v1(111.35,37.56) v1(111.35,36.93) v1(111.35,36.29) v1(111.35,35.66) v1(111.35,35.02) v1(111.35,34.39) v1(111.49,136.57) v1(111.53,28.68) v1(111.69,104.79) v1(111.69,104.15) v1(111.69,103.52) v1(111.69,102.88) v1(111.74,52.3) v1(111.74,50.77) v1(111.74,49.25) v1(111.68,45.57) v1(111.85,56.25) v1(111.98,37.56) v1(111.98,36.93) v1(111.98,36.29) v1(111.98,35.66) v1(111.98,35.02) v1(111.98,34.39) v1(112.33,104.79) v1(112.33,104.15) v1(112.33,103.52) v1(112.33,102.88) v1(112.62,37.56) v1(112.62,36.93) v1(112.62,36.29) v1(112.62,35.66) v1(112.62,35.02) v1(112.62,34.39) v1(112.96,104.79) v1(112.96,104.15) v1(112.96,103.52) v1(112.96,102.88) v1(113.27,56.25) v1(113.25,37.56) v1(113.25,36.93) v1(113.25,36.29) v1(113.25,35.66) v1(113.25,35.02) v1(113.25,34.39) v1(113.28,52.32) v1(113.28,50.8) v1(113.28,49.27) v1(113.39,130.55) v1(113.6,102.52) v1(113.65,45.57) v1(113.89,37.56) v1(113.89,36.93) v1(113.89,36.29) v1(113.89,35.66) v1(113.89,35.02) v1(113.89,34.39) v1(114.25,103.23) v1(114.25,101.67) v1(114.32,137.57) v1(114.53,28.68) v1(114.81,52.89) v1(114.98,45.57) v1(115.55,103.23) v1(115.55,101.67) v1(115.85,128.99) v1(116.61,98.46) v1(116.7,45.57) v1(116.84,103.23) v1(116.84,101.67) v1(116.78,51.92) v1(116.78,50.39) v1(116.78,48.87) v1(117.11,131.17) v1(117.11,126.81) v1(117.22,100.52) v1(117.32,137.57) v1(117.52,28.68) v1(117.69,102.88) v1(118.58,56.24) v1(118.79,45.5) v1(118.93,52.36) v1(118.93,50.84) v1(118.93,49.31) v1(119.33,101.55) v1(119.31,83.64) v1(119.62,131.17) v1(119.62,126.81) v1(119.95,83.64) v1(120.15,56.29) v1(120.31,137.57) v1(120.44,49.38) v1(120.52,28.68) v1(120.65,83.64) v1(120.88,128.99) v1(121.27,45.5) v1(121.28,83.64) v1(121.78,38.51) v1(121.78,37.19) v1(121.78,35.88) v1(121.85,34.62) v1(121.85,33.98) v1(121.85,33.35) v1(121.85,32.71) v1(121.92,83.64) v1(122.35,56.27) v1(122.38,52.84) v1(122.38,51.32) v1(122.38,49.79) v1(122.61,34.62) v1(122.61,33.98) v1(122.61,33.35) v1(122.61,32.71) v1(122.86,39.82) v1(122.79,38.51) v1(122.79,37.19) v1(122.79,35.88) v1(123.17,45.5) v1(123.31,137.57) v1(123.52,28.68) v1(123.63,32.08) v1(123.63,31.44) v1(123.8,39.82) v1(123.8,38.51) v1(123.8,37.19) v1(123.8,35.88) v1(124.32,107.73) v1(124.95,107.73) v1(125.27,128.08) v1(125.18,56.55) v1(125.21,51.35) v1(125.48,129.58) v1(125.59,107.73) v1(126.14,136.57) v1(126.22,107.73) v1(126.52,28.68) v1(127.25,52.47) v1(127.25,50.95) v1(127.25,49.42) v1(127.25,48.66) v1(129.13,136.57) v1(129.51,28.68) v1(129.89,52.18) v1(129.89,50.66) v1(129.89,49.14) v1(130.09,45.56) v1(130.41,93.42) v1(131.7,30.73) v1(131.96,137.57) v1(132.06,93.79) v1(132.14,108.09) v1(132.19,128.04) v1(132.27,52.43) v1(132.27,50.9) v1(132.27,49.38) v1(132.46,96.47) v1(132.7,95.05) v1(133.15,90.28) v1(133.57,128.68) v1(133.54,107.96) v1(133.56,97.72) v1(134.03,51.03) v1(134.02,32.63) v1(134.6,95.05) v1(134.6,93.79) v1(134.6,92.13) v1(134.78,90.88) v1(134.81,41.29) v1(134.81,40.65) v1(134.96,137.57) v1(135,96.47) v1(135.46,97.72) v1(135.44,41.29) v1(135.44,40.65) v1(135.86,129.75) v1(136.08,41.29) v1(136.08,40.65) v1(136.08,39.76) v1(136.08,39.13) v1(136.08,38.49) v1(136.37,53.3) v1(136.37,51.01) v1(136.71,41.29) v1(136.71,40.65) v1(136.71,39.76) v1(136.71,39.13) v1(136.71,38.49) v1(137.01,32.64) v1(137.2,49.07) v1(137.19,45.41) v1(137.35,41.29) v1(137.35,40.65) v1(137.35,39.76) v1(137.35,39.13) v1(137.35,38.49) v1(137.63,97.72) v1(137.61,85.05) v1(137.61,83.15) v1(137.96,137.57) v1(137.98,41.29) v1(137.98,40.65) v1(138.44,51.22) v1(138.62,41.29) v1(138.62,40.65) v1(138.92,84.18) v1(139.34,30.75) v1(139.76,51.98) v1(139.76,50.45) v1(139.76,48.93) v1(140.17,129.94) v1(140.23,83.05) v1(140.95,137.57) v1(141.53,84.23) v1(141.53,82.32) v1(141.51,28.68) v1(142.08,52.24) v1(142.08,50.72) v1(142.08,49.2) v1(142.2,45.49) v1(142.84,83.51) v1(142.84,81.6) v1(142.99,97.4) v1(143.63,97.4) v1(143.63,96.49) v1(143.63,94.45) v1(143.74,52.72) v1(143.74,51.22) v1(143.95,137.57) v1(144.05,49.7) v1(144.28,82.15) v1(144.51,28.68) v1(144.69,52.65) v1(144.91,56.36) v1(146.04,56.31) v1(146.28,52.03) v1(146.28,50.51) v1(146.28,48.98) v1(146.64,82.2) v1(146.6,45.49) v1(146.95,137.57) v1(147.51,28.68) v1(148.05,105.92) v1(148.05,52.36) v1(148.05,50.08) v1(148.33,81.73) v1(148.89,45.5) v1(149.65,52.01) v1(149.65,50.48) v1(149.65,48.96) v1(149.95,137.57) v1(149.91,112.17) v1(149.98,80.64) v1(150.23,128.98) v1(150.36,115.3) v1(150.35,114.7) v1(150.5,28.68) v1(150.87,116.77) v1(150.82,113.17) v1(151.22,45.56) v1(151.44,117.49) v1(151.44,116.9) v1(151.43,52.04) v1(151.43,50.52) v1(151.43,49) v1(151.49,131.15) v1(151.49,126.8) v1(151.87,93.64) v1(152.25,45.54) v1(152.86,137.57) v1(152.78,93.64) v1(152.78,51.85) v1(152.78,49.57) v1(153.09,115.33) v1(153.22,113.36) v1(153.23,111.61) v1(153.54,82.18) v1(153.5,28.68) v1(153.69,93.64) v1(154,131.15) v1(154,126.8) v1(154.33,52.04) v1(154.33,50.52) v1(154.33,49) v1(154.66,56.46) v1(155.26,128.98) v1(155.21,83.9) v1(155.94,137.57) v1(156.03,45.54) v1(156.11,56.39) v1(156.37,93.61) v1(156.5,28.68) v1(156.61,52.01) v1(156.61,50.48) v1(156.61,48.96) v1(156.69,84.93) v1(158,83.84) v1(158.4,122.07) v1(158.39,52.43) v1(158.58,128.79) v1(158.69,138.77) v1(158.71,121.54) v1(158.99,122.07) v1(159.06,45.54) v1(159.32,121.54) v1(159.57,122.07) v1(159.49,28.68) v1(159.66,84.19) v1(159.69,81.66) v1(159.9,121.54) v1(159.92,51.92) v1(159.92,50.39) v1(159.92,48.87) v1(160.16,122.07) v1(160.29,120.88) v1(160.49,121.54) v1(160.74,122.07) v1(160.88,120.88) v1(160.96,84.24) v1(160.96,82.33) v1(160.96,80.42) v1(161.27,56.33) v1(161.32,122.07) v1(161.68,138.6) v1(161.97,52.36) v1(161.97,50.84) v1(161.97,49.31) v1(162.03,121.67) v1(161.98,45.54) v1(162.47,115.41) v1(162.49,28.68) v1(162.63,82.86) v1(162.63,80.32) v1(162.6,56.3) v1(162.7,45.56) v1(163.19,123.9) v1(163.33,121.79) v1(163.46,116.94) v1(163.51,51.98) v1(163.51,49.7) v1(163.77,112.01) v1(163.95,56.33) v1(164.18,45.57) v1(164.29,83.8) v1(164.49,137.57) v1(164.9,123.36) v1(164.96,52.55) v1(164.96,51.03) v1(164.96,49.5) v1(165.19,45.56) v1(165.34,96.1) v1(165.41,133.68) v1(165.41,133.04) v1(165.41,132.41) v1(165.41,131.77) v1(165.53,56.3) v1(165.49,28.68) v1(165.81,95.75) v1(165.95,83.78) v1(165.93,81.87) v1(166.09,45.54) v1(167.26,81.01) v1(167.26,79.11) v1(167.49,137.57) v1(167.83,49.73) v1(167.95,51.19) v1(168.49,28.68) v1(168.62,115.66) v1(168.62,113.91) v1(169.99,114.5) v1(170.29,111.43) v1(170.49,137.57) v1(171,117.42) v1(171.24,115.66) v1(171.48,28.68) v1(172.58,113.91) v1(173.2,115.51) v1(173.48,137.57) v1(173.92,122.57) v1(174.48,28.68) v1(174.78,116.23) v1(174.86,113.17) v1(175.26,129.74) v1(175.65,115.19) v1(175.65,114.2) v1(175.69,122.65) v1(175.89,129.74) v1(176.48,137.57) v1(177.34,135.28) v1(177.34,134.65) v1(177.45,122.71) v1(177.44,115.18) v1(177.48,28.68) v1(177.92,135.28) v1(177.92,134.65) v1(178.56,135.28) v1(178.56,134.65) v1(179.14,135.28) v1(179.14,134.65) v1(179.26,41.55) v1(179.38,47.85) v1(179.38,45.56) v1(179.48,137.57) v1(179.56,52.27) v1(179.73,135.28) v1(179.73,134.65) v1(180.31,135.28) v1(180.31,134.65) v1(180.48,28.68) v1(181.1,41.5) v1(181.4,52.24) v1(181.44,48.43) v1(182.39,132.26) v1(182.48,137.57) v1(183.22,48.43) v1(183.22,46.9) v1(183.22,45.38) v1(183.43,52.24) v1(183.47,28.68) v1(184.46,90.72) v1(185.16,48.42) v1(185.16,46.89) v1(185.16,45.37) v1(185.47,137.57) v1(185.67,41.48) v1(186.44,88.27) v1(186.47,28.68) v1(186.85,38.28) v1(186.92,48.94) v1(186.92,48.17) v1(186.92,47.41) v1(186.92,45.13) v1(187,90.62) v1(187.79,88.37) v1(188.06,38.29) v1(188.3,136.57) v1(188.75,91.89) v1(189.14,48.3) v1(189.14,46.77) v1(189.14,45.25) v1(189.21,52.27) v1(189.47,28.68) v1(190.3,117.6) v1(190.68,48.32) v1(190.68,46.8) v1(190.68,45.27) v1(190.86,52.27) v1(191.17,41.5) v1(191.19,117.61) v1(191.3,136.61) v1(192.46,41.53) v1(192.46,28.68) v1(192.72,48.25) v1(192.96,52.24) v1(193.16,117.61) v1(193.63,137.57) v1(193.73,41.57) v1(194.43,48.43) v1(194.43,46.9) v1(194.43,45.38) v1(194.43,40.52) v1(194.62,41.54) v1(194.85,52.28) v1(195.46,28.68) v1(195.86,41.55) v1(196.08,48.36) v1(196.08,46.84) v1(196.08,45.31) v1(196.62,137.57) v1(196.78,41.54) v1(196.85,35.06) v1(197.34,45.5) v1(197.67,41.54) v1(197.7,40.58) v1(198.27,89.48) v1(198.46,28.68) v1(199.07,85.65) v1(199.32,33.35) v1(199.32,32.71) v1(199.32,32.08) v1(199.62,137.57) v1(199.7,85.29) v1(199.74,34) v1(199.78,48.33) v1(199.78,46.81) v1(199.78,45.28) v1(199.96,33.35) v1(199.96,32.71) v1(200.02,89.48) v1(200.13,52.27) v1(200.38,34) v1(200.59,33.35) v1(200.59,32.71) v1(200.99,52.29) v1(201.01,34) v1(201.1,134.19) v1(201.23,32.71) v1(201.46,28.68) v1(201.73,134.19) v1(201.92,110.12) v1(201.92,109.48) v1(201.99,114.63) v1(202.24,133.87) v1(202.24,111.83) v1(202.31,112.47) v1(202.42,109.8) v1(202.62,137.57) v1(202.94,112.47) v1(202.94,111.83) v1(203.06,45.06) v1(203.1,41.41) v1(203.67,52.35) v1(204.14,34.2) v1(204.33,46.66) v1(204.38,48.22) v1(204.45,28.68) v1(204.65,137.57) v1(204.91,41.59) v1(205.53,52.24) v1(205.92,47.34) v1(205.92,45.81) v1(206.56,34.24) v1(207.01,137.57) v1(207.05,47.34) v1(207.05,46.57) v1(207.05,45.05) v1(207.45,28.68) v1(207.7,133.17) v1(208.34,133.17) v1(208.34,130.82) v1(208.66,127.77) v1(208.95,136.57) v1(208.91,131.39) v1(208.91,130.25) v1(208.97,101.93) v1(208.89,47.78) v1(208.89,46.25) v1(209.48,130.82) v1(209.99,93.3) v1(209.99,89.47) v1(210.43,52.67) v1(210.45,28.68) v1(211.43,47.03) v1(211.43,45.5) v1(211.83,134.19) v1(211.95,136.57) v1(212.47,134.19) v1(212.94,93.3) v1(212.94,89.47) v1(213.1,134.19) v1(213.1,133.55) v1(213.26,46.76) v1(213.44,28.68) v1(214.94,136.57) v1(215.15,47.19) v1(216.39,47.98) v1(216.39,46.45) v1(216.4,37.09) v1(216.44,28.68) v1(217.04,37.09) v1(217.67,37.09) v1(217.77,137.57) v1(217.8,134.25) v1(218.31,37.09) v1(218.63,134.25) v1(218.94,37.09) v1(219.32,134.25) v1(219.44,28.68) v1(219.48,47.99) v1(219.48,46.47) v1(219.48,44.94) v1(219.58,37.09) v1(219.96,134.25) v1(220.21,37.09) v1(220.56,48.53) v1(220.59,134.25) v1(220.77,137.57) v1(220.85,37.09) v1(221.23,134.25) v1(221.52,48.23) v1(221.52,46.45) v1(221.52,44.93) v1(221.93,41.53) v1(222.44,28.68) v1(223.4,101.94) v1(223.4,98.79) v1(223.56,48.62) v1(223.56,47.09) v1(223.76,137.57) v1(223.96,41.53) v1(224.26,52.24) v1(224.97,100.36) v1(225.2,48.16) v1(225.2,45.87) v1(225.43,28.68) v1(225.55,85.1) v1(225.59,52.33) v1(226.55,101.94) v1(226.55,98.79) v1(226.76,137.57) v1(226.72,48.62) v1(226.72,47.09) v1(226.72,45.57) v1(227.74,52.35) v1(228.14,126.25) v1(228.43,28.68) v1(228.58,48.3) v1(228.58,46.77) v1(228.58,45.25) v1(228.72,126.25) v1(229.31,126.25) v1(229.59,136.57) v1(230.06,130.88) v1(230.18,48.11) v1(230.18,45.82) v1(231.36,52.35) v1(231.43,28.68) v1(231.91,48.43) v1(231.91,46.9) v1(231.91,45.38) v1(232.41,137.57) v1(232.4,130.74) v1(232.64,52.3) v1(233.12,31.29) v1(233.55,41.48) v1(233.81,48.24) v1(233.81,46.71) v1(233.81,45.19) v1(234.42,28.68) v1(234.79,31.76) v1(235.41,137.57) v1(235.77,127.07) v1(235.77,126.44) v1(235.8,128.29) v1(235.8,127.66) v1(235.86,72.64) v1(235.89,48.43) v1(236,41.48) v1(236.28,129.6) v1(236.28,128.97) v1(236.43,128.29) v1(236.43,127.66) v1(236.41,127.07) v1(236.41,126.44) v1(236.72,68.83) v1(236.91,129.6) v1(236.91,128.97) v1(237.04,128.32) v1(237.04,127.61) v1(237.04,126.97) v1(237.39,52.36) v1(237.42,28.68) v1(237.57,48.55) v1(237.57,47.03) v1(237.57,45.5) v1(237.75,136.54) v1(238.04,52.36) v1(238.12,41.54) v1(238.41,137.57) v1(238.68,135.52) v1(238.86,48.49) v1(238.86,46.97) v1(238.86,45.44) v1(239.02,136.54) v1(239.36,52.37) v1(239.66,135.27) v1(239.64,41.48) v1(240.29,136.54) v1(240.29,133.94) v1(240.39,52.61) v1(240.45,47.73) v1(240.45,45.44) v1(240.42,28.68) v1(240.56,59.7) v1(240.93,135.27) v1(241.23,132.99) v1(241.23,59.95) v1(241.4,137.57) v1(241.56,136.54) v1(241.56,133.94) v1(242.06,107.3) v1(242.07,60.11) v1(242.07,59.07) v1(242.2,135.27) v1(242.2,132.67) v1(242.36,48.55) v1(242.36,47.03) v1(242.45,72.4) v1(242.65,52.4) v1(242.83,136.54) v1(242.83,133.94) v1(242.83,131.34) v1(243.06,37.32) v1(243.47,135.27) v1(243.47,132.67) v1(243.42,28.68) v1(243.88,60.11) v1(243.88,59.07) v1(244.1,136.54) v1(244.1,133.94) v1(244.1,131.34) v1(244.28,129.88) v1(244.4,137.57) v1(244.74,135.27) v1(244.74,132.67) v1(245.27,133.94) v1(245.23,128.98) v1(245.37,136.54) v1(245.37,131.34) v1(245.5,129.78) v1(245.77,55.84) v1(245.77,55.21) v1(246.24,128.71) v1(246.19,81.04) v1(246.41,55.84) v1(246.41,55.21) v1(246.41,28.68) v1(246.77,129.78) v1(246.87,127.44) v1(246.94,137.57) v1(246.9,33.93) v1(247.18,88.3) v1(247.51,128.71) v1(247.48,33.93) v1(247.62,134) v1(247.8,126.45) v1(248.13,129.75) v1(248.14,127.44) v1(248.39,70.04) v1(248.47,47.39) v1(248.57,135.65) v1(248.57,132.35) v1(248.78,128.71) v1(248.78,126.17) v1(248.88,49.69) v1(249.4,129.75) v1(249.41,127.44) v1(249.41,124.9) v1(249.41,28.68) v1(249.64,43.75) v1(249.69,68.83) v1(250.05,128.71) v1(250.05,126.17) v1(250.22,136.57) v1(250.48,135.65) v1(250.48,132.35) v1(250.67,129.75) v1(250.68,127.44) v1(250.68,124.9) v1(251.32,128.71) v1(251.32,126.17) v1(251.43,134) v1(251.95,124.9) v1(252.29,134.4) v1(252.29,131.4) v1(252.29,128.41) v1(252.41,28.68) v1(253.25,125.57) v1(253.18,120.93) v1(255.29,120.37) v1(255.4,28.6) v1(255.84,49.41) v1(255.91,54.25) v1(255.96,24.13) v1(255.96,21.13) v1(256.15,69.72) v1(256.25,125.57) v1(256.47,36.9) v1(256.57,68.58) v1(256.79,75.7) v1(257.23,75.26) v1(257.22,28.75) v1(257.22,24.25) v1(257.2,19.93) v1(257.36,75.83) v1(257.31,21.95) v1(257.45,120.93) v1(257.49,80.85) v1(258.07,80.85) v1(258.05,57.02) v1(258.66,80.85) v1(259.25,125.57) v1(259.24,80.85) v1(259.86,121.19) v1(259.83,28.75) v1(259.83,24.25) v1(259.91,21.95) v1(260.2,19.93) v1(260.8,36.78) v1(260.9,38.62) v1(261.01,122.29) v1(261.03,21.7) v1(261.13,26.5) v1(261.31,113.73) v1(261.51,44.48) v1(261.5,43.16) v1(261.55,41.41) v1(261.59,121.19) v1(262.25,125.57) v1(262.2,112.38) v1(262.73,122.29) v1(263.2,19.93) v1(263.32,121.19) v1(263.74,114.92) v1(264.46,122.29) v1(264.55,120.3) v1(264.92,113.3) v1(264.98,111.21) v1(265.06,72.6) v1(265.24,125.57) v1(265.74,84.5) v1(266.25,86.05) v1(266.19,19.93) v1(266.67,35.06) v1(268.24,125.57) v1(268.66,34.45) v1(268.68,43.74) v1(268.7,43.06) v1(268.92,88.03) v1(269.04,32.78) v1(269.19,19.93) v1(269.51,36.07) v1(270.25,34.01) v1(270.44,26.72) v1(270.59,108.91) v1(270.59,107.64) v1(270.59,106.37) v1(271.08,54.68) v1(271.24,125.57) v1(271.71,54.68) v1(271.86,108.91) v1(271.86,107.64) v1(271.86,106.37) v1(272.16,55.13) v1(272.19,19.93) v1(273.13,108.91) v1(273.13,107.64) v1(273.13,106.37) v1(274.24,125.57) v1(274.38,34.74) v1(275.18,19.93) v1(275.7,34.74) v1(276.22,65.8) v1(276.28,30.05) v1(277.23,125.57) v1(277.2,34.68) v1(277.55,30.05) v1(278.19,54.46) v1(278.19,53.79) v1(278.18,19.93) v1(278.82,54.46) v1(278.92,91.51) v1(279.83,26.75) v1(280.58,100.42) v1(280.69,125.57) v1(280.73,82.75) v1(280.73,82.12) v1(280.7,32.39) v1(281.18,19.93) v1(281.74,34.68) v1(281.74,26.75) v1(282.04,85.99) v1(282.95,29.91) v1(283.01,26.11) v1(283.23,125.57) v1(283.25,98.75) v1(283.25,96.95) v1(283.21,31.19) v1(283.45,95.67) v1(283.45,95.05) v1(283.97,73.04) v1(283.96,55.12) v1(283.96,53.54) v1(283.96,51.97) v1(284.07,85.99) v1(284.13,74.83) v1(284.18,19.93) v1(284.29,98.75) v1(284.29,96.95) v1(284.32,94.56) v1(284.35,22.81) v1(285.53,55.12) v1(285.53,53.54) v1(285.53,51.97) v1(286.22,125.57) v1(286.2,100.28) v1(286.63,99.85) v1(286.67,42.46) v1(286.76,18.41) v1(287.11,55.12) v1(287.11,53.54) v1(287.11,51.97) v1(287.76,93.53) v1(287.97,82.24) v1(288.03,91.83) v1(288.09,80.48) v1(288.09,62.81) v1(288.2,89.99) v1(288.2,84.05) v1(288.42,120.5) v1(289.22,125.57) v1(289.31,16.83) v1(289.49,24.5) v1(289.49,22.26) v1(289.72,122.75) v1(289.72,118.25) v1(290.09,115.79) v1(290.61,23.38) v1(291.26,42.39) v1(291.32,74.37) v1(291.45,116.22) v1(291.73,24.5) v1(291.73,22.26) v1(291.92,69.54) v1(291.89,42.39) v1(292.22,125.57) v1(292.33,122.75) v1(292.33,118.25) v1(292.3,16.83) v1(292.54,70.17) v1(292.54,68.92) v1(292.67,25.41) v1(293.11,74.37) v1(293.16,69.54) v1(293.38,87.93) v1(293.38,86.36) v1(293.38,84.78) v1(293.63,120.5) v1(294.95,87.93) v1(294.95,86.36) v1(294.95,84.78) v1(295.22,125.57) v1(295.21,66.62) v1(295.3,16.83) v1(295.74,50.08) v1(296.29,50.58) v1(296.53,87.93) v1(296.53,86.36) v1(296.53,84.78) v1(296.73,71.32) v1(296.82,123.03) v1(296.82,44.18) v1(296.91,120.52) v1(297.13,49.6) v1(297.43,58.14) v1(297.43,44.18) v1(297.49,73.86) v1(297.62,61.22) v1(297.62,60.59) v1(297.62,59.95) v1(297.62,59.32) v1(297.75,73.23) v1(298.04,44.18) v1(298.06,25.22) v1(298.16,15.92) v1(298.21,125.57) v1(298.42,76.5) v1(298.65,25.22) v1(298.83,13) v1(299.56,14.29) v1(299.72,78.75) v1(299.72,74.25) v1(300.45,123.57) v1(300.54,59.26) v1(300.79,58.3) v1(300.94,12.13) v1(301.18,59.26) v1(301.18,57.6) v1(301.52,94.93) v1(301.82,41.37) v1(302.26,13.98) v1(302.33,78.75) v1(302.33,74.25) v1(302.62,58.19) v1(302.61,21.56) v1(303.44,123.57) v1(303.63,76.5) v1(303.61,9.82) v1(303.61,4.8) v1(303.61,1.8) v1(303.96,0.43) v1(304.22,84.73) v1(304.65,83.08) v1(305.05,73.13) v1(305.05,61.14) v1(305.05,55.04) v1(305.05,43.94) v1(305.56,94.93) v1(305.56,90.89) v1(306.26,117.59) v1(306.43,123.79) v1(306.46,41.3) v1(306.58,0.43) v1(306.81,58.1) v1(306.9,125.56) v1(307.92,94.28) v1(307.94,73.93) v1(307.94,56.73) v1(308.05,75.7) v1(308.12,96.32) v1(308.62,91.06) v1(308.62,78.86) v1(309.43,41.67) v1(309.58,0.43) v1(309.88,125.55) v1(310.3,73.63) v1(310.35,59.17) v1(310.31,56.43) v1(310.62,93.28) v1(310.81,77.02) v1(311.01,111.38) v1(311.09,123.59) v1(311.84,116.18) v1(312.16,96.32) v1(312.57,0.43) v1(312.92,112.93) v1(312.92,4) v1(313.12,111.38) v1(313.56,41.97) v1(313.92,73.63) v1(313.92,56.43) v1(313.95,8.16) v1(313.97,5.83) v1(313.97,2.17) v1(314,122.86) v1(314.7,96.32) v1(315.33,77.02) v1(315.35,59.07) v1(315.35,41.36) v1(315.57,0.43) v1(315.78,120.45) v1(315.78,14.44) v1(315.89,117.45) v1(315.98,114.45) v1(316.08,5.83) v1(316.08,2.17) v1(316.33,75.41) v1(316.62,93.28) v1(317.13,4) v1(317.39,12.16) v1(317.86,111.38) v1(318.12,95.88) v1(318.57,0.43) v1(318.62,113.03) v1(318.62,26) v1(318.62,23.89) v1(318.62,20.89) v1(318.62,17.89) v1(318.62,14.9) v1(318.62,9.43) v1(318.62,6.43) v1(318.62,3.43) v3(14,101.34) v3(45.3,115.39) v3(45.77,116.09) v3(76.79,67.23) v3(80.03,66.18) v3(84.86,45.9) v3(90.41,98.56) v3(93.54,108.89) v3(99.65,72.12) v3(103.22,109.05) v3(103.35,34.71) v3(103.4,41.4) v3(103.65,30.26) v3(108.22,106.14) v3(108.39,85.51) v3(111.91,70.33) v3(118.89,103.69) v3(120.44,30.29) v3(121.62,31.34) v3(121.98,39.36) v3(128.8,106.5) v3(163.38,45.26) v3(165.62,58.06) v3(179.73,133.36) v3(207.63,131.94) v3(238.96,53.07) v3(244.81,130.55) v3(246.36,56.98) v3(256.75,74.67) v3(257.32,118.48) v3(258.4,119.09) v3(268.24,42.49) v3(284.42,100.39) v3(297.06,46.14)
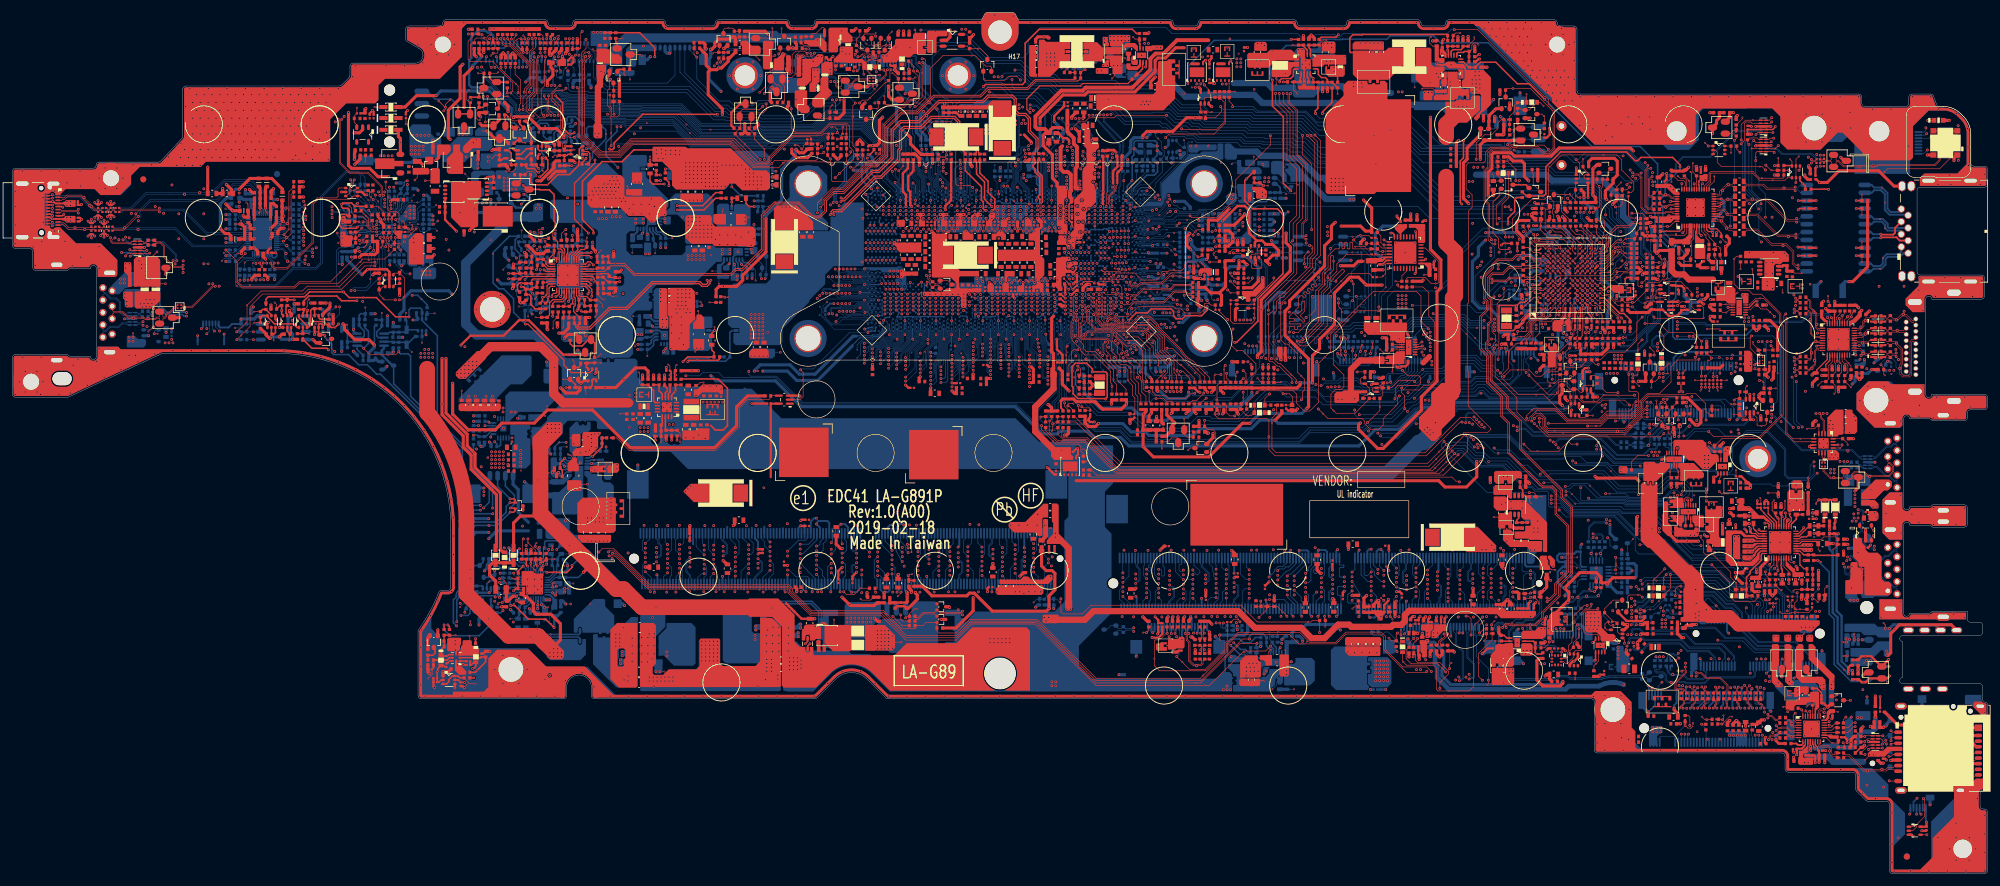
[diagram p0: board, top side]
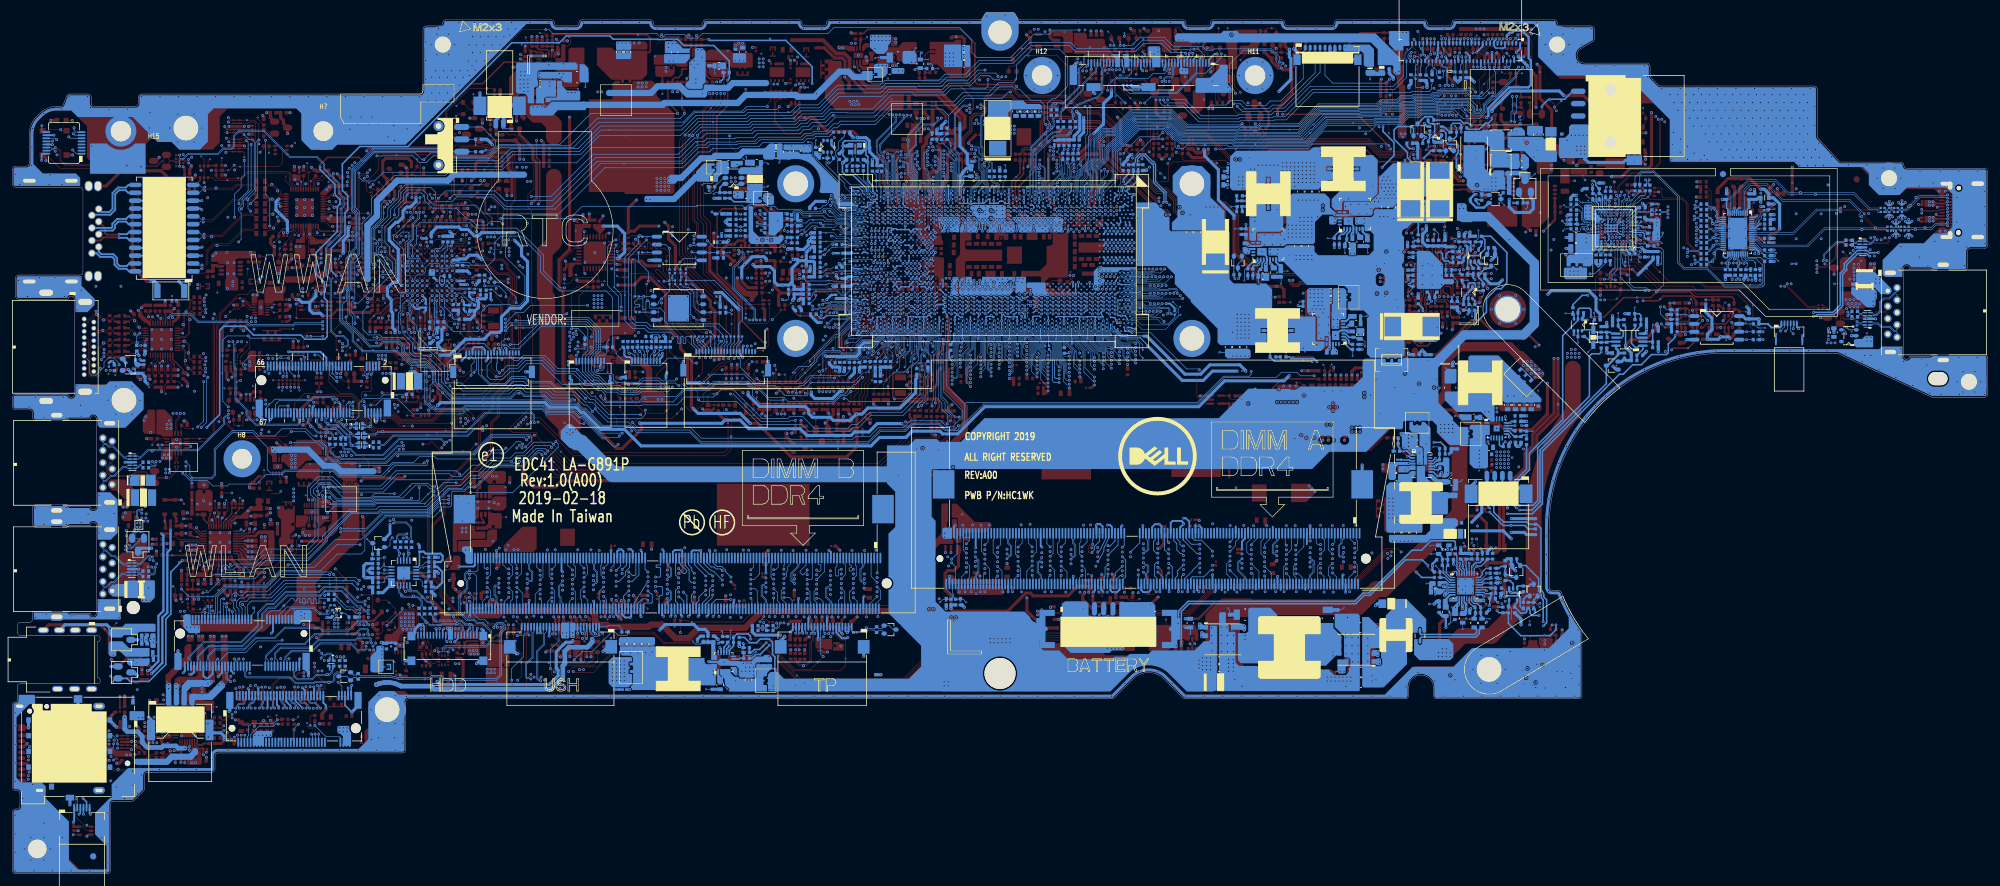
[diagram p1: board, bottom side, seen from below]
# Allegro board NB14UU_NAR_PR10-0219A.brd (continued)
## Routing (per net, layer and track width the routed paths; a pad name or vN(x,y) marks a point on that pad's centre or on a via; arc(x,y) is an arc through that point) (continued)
GNDA: length 50.3
  TOP w0.107: v3(293.11,46.43) 292.74,46.06 RA35.1 ; v1(297.49,37.79) v3(297.49,38.72) ; RA37.1 v3(283.59,61.53)
  TOP w0.203: UA1.19 288.49,54.94 289.32,55.77 v1(289.32,55.92) ; UA1.31 282.35,55.34 v1(282.11,55.58)
  TOP w0.356: v1(279.84,55.71) 279.84,55.7 280.15,55.39 CA57.2 ; CA8.2 v1(291.4,57.35)
  TOP w0.381: CA35.2 v1(287.08,59.76)
  TOP w0.508: CA25.2 v1(294.11,53.35) ; CA41.2 v1(289.42,50.61) ; v1(285.24,60.91) RA37.1 ; RA44.2 v1(289.17,59.7) ; CA3.1 v1(298.13,32.97) CA2.1 ; CA51.2 v1(288.16,60.27) ; v1(292.6,44.14) 292.74,44.28 RA35.1 ; v1(280.54,56.59) 279.84,56.59 CA52.2 ; RA36.1 279.78,57.86 CA58.2 279.84,57.79 v1(280.54,57.79) ; CA73.2 v1(284.79,59.82) ; CA9.2 v1(290.76,58.3) ; CA74.2 v1(285.68,59.82)
  GND1 w0.203: 307.82,39.35 JHP1.7 ; JHP1.7 308.9,40.02 ; JHP1.7 307.82,40.02 ; JHP1.7 309.98,39.35 ; JHP1.7 309.98,40.02 ; JHP1.5 307.33,29.18 ; JHP1.5 305.17,29.18 ; JHP1.5 305.17,29.85 ; JHP1.5 307.33,29.85 ; JHP1.5 306.25,29.18
  VCC w0.203: 305.17,29.18 JHP1.5 ; JHP1.5 307.33,29.18 ; JHP1.5 306.25,29.18 ; 307.82,40.02 JHP1.7 ; JHP1.7 308.9,40.02 ; JHP1.7 309.98,40.02
  GND2 w0.203: 305.17,29.85 JHP1.5 ; JHP1.5 307.33,29.85 ; JHP1.5 305.17,29.18 ; JHP1.5 307.33,29.18 ; JHP1.5 306.25,29.18 ; JHP1.7 309.98,40.02 ; JHP1.7 307.82,40.02 ; JHP1.7 309.98,39.35 ; JHP1.7 308.9,40.02 ; JHP1.7 307.82,39.35
  BOTTOM w0.508: CA1.2 297.26,38.48 297.48,38.26 297.48,38.07 297.49,38.05 v1(297.49,37.79) 297.49,37.54 297.26,37.31 CA4.2 ; v1(303.11,33.49) DA2.2
VBAT1_CHG: length 4.2
  TOP w0.254: v1(85.73,49.78) 85.42,49.47 PC755.1
  BOTTOM w0.203: PR738.1 85.73,51.42 v1(85.73,49.78) 85.73,49.32 85.34,48.93 PU700.31
VBUS1_ECOK: length 6.6
  TOP w0.254: RE602.2 261.3,89.53 v2(260.67,90.16) 260.29,90.54 259.63,90.54 257.16,93.01 UE1.N3
VBUS1_ECOK_R: length 349
  TOP w0.107: RE602.1 v1(261.3,87.58)
  TOP w0.203: PR861.2 v1(89.4,78.56)
  TOP w0.254: PR826.1 47.05,92.53 47.87,93.36 52.4,93.36 v2(52.88,92.87) 53.16,92.59 v1(55.65,92.59)
  IN1 w0.254: v1(82.21,108.21) 65.77,91.77 59.43,91.77 58.21,92.99 56.04,92.99 v1(55.65,92.59)
  IN2 w0.102: v1(89.4,78.56) 89.4,84.02 82.55,90.88 82.09,90.88 81.01,91.96 81.01,92.61 78.78,94.83 78.78,104.78 v1(82.21,108.21) ; v1(152.78,42.64) 152.96,42.82 153.76,42.82 155.94,40.64 162.38,40.64 166.96,36.05 177.36,36.05 182.63,30.79 193.24,30.79 196.42,33.97 197.4,33.97 198.01,34.58 198.01,35.26 198.57,35.82 202.01,35.82 202.14,35.95 204.94,35.95 207.2,38.21 208.78,38.21 209.41,37.58 215.57,37.58 215.64,37.5 221.24,37.5 223.01,35.73 223.01,35.49 223.74,34.76 223.74,33.22 224.86,32.09 225.87,31.08 231.96,31.08 233.73,32.85 238.4,32.85 240.4,30.85 249.66,30.85 250.27,31.47 256.37,31.47 257.47,32.56 258.61,32.56 264.5,38.45 264.5,41.54 264.22,41.81 264.22,42.95 264.07,43.09 264.07,44.59 264.89,45.41 264.89,49 264.43,49.46 264.43,59.15 264.8,59.51 264.8,62.38 261.87,65.31 261.87,74.81 261.61,75.07 261.61,76.41 260.92,77.1 260.92,78.37 260.45,78.84 260.45,82.53 261.3,83.38 v1(261.3,87.58)
  IN3 w0.102: v1(89.4,78.56) 96.26,78.56 97.7,77.12 97.7,71.87 101.84,67.73 121.57,67.73 132.63,56.67 132.63,55.91 133.28,55.26 134.18,55.26 135.36,54.08 135.36,48.59 136.03,47.92 136.05,47.92 138.14,45.82 138.3,45.82 140.65,43.47 152.43,43.47 152.78,43.12 v1(152.78,42.64)
  BOTTOM w0.254: PR20.2 81.8,108.91 PR24.1 82.66,108.66 v1(82.21,108.21)
VBUS2_ECOK: length 8.6
  TOP w0.107: UE1.M6 256.01,95.04 v1(256.07,95.04)
  TOP w0.254: RE603.2 261.34,96.35 260.77,96.35 v2(260.51,96.1) 260.51,95.45 v1(260.77,95.2)
  IN3 w0.254: v1(260.77,95.2) 260.34,95.2 258.8,93.66 257.45,93.66 v1(256.07,95.04)
VBUS2_ECOK_R: length 450.2
  TOP w0.107: RE603.1 262.57,96.04 262.57,95.04 262.68,94.93 v1(263.14,94.93)
  TOP w0.254: PR827.1 v2(48.37,84.91) 50.8,84.91 v1(51.05,84.66)
  IN1 w0.254: v1(91.07,115.64) 91.07,116.45 90.74,116.78 88.14,116.78 87.05,117.87 79.35,117.87 77.38,115.9 77.38,113.97 76.23,112.82 73.8,112.82 72.32,111.34 72.32,99.13 65.35,92.16 59.58,92.16 58.32,93.42 55.6,93.42 53.21,91.03 51.33,91.03 51.05,90.75 v1(51.05,84.66)
  IN2 w0.102: v1(91.07,115.64) 91.45,115.27 91.45,113.73 88.58,110.86 88.58,107.28 86.66,105.36 86.66,103.73 84.86,101.93 83.92,101.93 83.62,101.64 83.62,100.47 80.89,97.74 79.69,97.74 79.52,97.57 79.52,94.77 81.47,92.83 81.47,92.15 81.85,91.77 82.62,91.77 v1(83.96,90.43) ; v1(263.14,94.93) 262.47,94.25 262.47,89.23 264.12,87.58 264.12,77.95 263.36,77.2 263.36,71.74 266.71,68.39 266.71,65 265.88,64.17 265.88,59.3 265.35,58.77 265.35,50.48 266.26,49.57 266.26,44.25 265.24,43.22 265.24,36.86 260.25,31.87 257.75,31.87 256.04,30.17 240.12,30.17 238.35,31.94 236.93,31.94 235.04,30.05 232.07,30.05 231.75,30.37 224.72,30.37 222.52,32.56 222.52,34.53 221.86,35.2 221.86,35.89 221.65,36.1 216.07,36.1 215.28,36.89 207.75,36.89 206.05,35.2 205.49,34.63 202.69,34.63 202.56,34.5 199.67,34.5 199.33,34.17 199.33,33.99 197.73,32.38 196.69,32.38 193.78,29.47 171.68,29.47 171.54,29.6 171.54,29.6 161.83,39.32 146.49,39.32 142.55,35.38 135.12,35.38 129.21,29.47 96.84,29.47 92.9,33.41 87.14,33.41 82.16,38.39 71.22,38.39 70.77,38.83 70.77,44.03 72.47,45.73 72.47,62.57 68.11,72.7 60.81,80.01 59.86,80.01 55.89,83.98 51.73,83.98 v1(51.05,84.66)
  BOTTOM w0.254: v1(83.96,90.43) 83.75,90.64 PR816.1 PR819.1 ; PR49.2 89.87,116.85 v1(91.07,115.64)
VBUSSENSE: length 9.7
  TOP w0.102: v1(176.69,107.19) 176.54,107.19 176.21,107.52 176.21,108.21
  TOP w0.381: RC49.1 176.21,115.88 v2(176.21,110.21) 176.21,109.92 176.12,109.83 176.12,108.3 176.21,108.21
  BOTTOM w0.089: v1(176.69,107.19) UC1.CC6
VCC1_IA: length 4.2
  BOTTOM w0.107: v2(117.79,95.37) PR688.2
  BOTTOM w0.254: PR688.2 117.79,97.35 PC676.1 117.22,97.93 117.22,98.63 116.92,98.93 PU610.3
VCC2_IA: length 4.3
  BOTTOM w0.107: v2(103.82,100.28) PR691.2
  BOTTOM w0.254: PR691.2 103.82,101.93 103.51,102.23 PC677.1 103.51,103.31 102.94,103.88 PU613.3
VCC_1.05VALWP: length 2.4
  TOP w0.107: v2(229.1,135.21) 228.93,135.04 228.93,134.24 229.43,133.73 PC313.1
VCC_CPU_CORE: length 4.7
  TOP w0.203: PU602.34 90.32,99.82 91.33,100.83 PC603.1
  TOP w0.254: PC603.1 v1(92.02,101.45)
  BOTTOM w0.107: v1(92.02,101.45) 91.5,101.45 v2(91.46,101.41)
  BOTTOM w0.254: PR602.1 92.07,101.39 v1(92.02,101.45)
VCC_DDR: length 1.7
  BOTTOM w0.254: PU200.14 89.43,65.38 89.34,65.29 88.72,65.29 PC207.1
VCC_GT: length 4.8
  BOTTOM w0.107: PR680.2 101.01,86.42 100.57,85.98 v2(100.57,85.21)
  BOTTOM w0.254: PR680.2 101.84,86.42 102.1,86.69 PC669.1 103.13,86.69 103.74,87.3 PU612.3
VCC_SENSE_GT: length 73.2
  TOP w0.203: PR648.1 89.94,89.89 PC639.1 PC653.1 90.78,89.81 PC651.2 91.02,88.71 91.02,88.33 91.34,88.01 93.38,88.01 96.57,91.2 99.29,91.2 103.44,95.35 110.95,95.35 111.38,94.92 112.24,94.92 112.67,95.35 112.67,95.76 v1(112.81,95.9)
  IN1 w0.203: v1(132.58,108.47) 132.71,108.34 132.71,107.14 133.21,106.64 133.21,105.01 131.36,103.16 123.35,103.16 122.22,102.03 122.22,98.87 120.16,96.81 120.16,96.05 119.57,95.45 112.83,95.45 112.67,95.61 112.67,95.76 v1(112.81,95.9)
  BOTTOM w0.203: v1(132.58,108.47) 132.71,108.6 132.71,110.17 134.4,111.86 134.4,114.65 136.07,116.32 136.95,116.32 137.65,115.62 137.65,115.05 137.98,114.72 RC632.2 RC160.2
VCC_SENSE_IA: length 101.4
  TOP w0.203: PR622.1 82.82,97.03 PC620.1 ; PC617.1 PC620.1 ; PC620.1 81.91,97 PC618.2 v1(80.16,97) ; v1(132.1,106.5) 132.25,106.65 132.25,107.02 132.54,107.3 133.84,107.3 139.28,112.74 140.24,112.74 142.97,115.46 142.97,116.91 143.28,117.22 143.28,120.09 143.96,120.77 146.71,120.77 148.32,122.39 152.21,122.39 153.02,121.58 153.02,118.75 154.44,117.33 155.64,117.33 156.01,116.96 156.01,116.55 RC430.2 RC150.2
  IN1 w0.203: v1(132.1,106.5) 132.22,106.39 132.22,105.34 130.95,104.07 122.85,104.07 121.31,102.53 121.31,99.31 119.99,97.99 101.22,97.99 100.85,98.36 96.14,98.36 95.32,97.53 87.3,97.53 86.57,96.81 80.36,96.81 80.36,96.8 v1(80.16,97)
VCC_SENSE_SA: length 103.7
  TOP w0.203: v1(133.85,109.21) 133.99,109.07 134.28,109.07 138.87,113.66 139.88,113.66 141.94,115.73 141.94,120.24 143.41,121.7 146.34,121.7 149.6,124.97 156.68,124.97 157.54,125.83 161.56,125.83 162.14,125.26 162.14,123.34 162.61,122.87 163.67,122.87 164.42,122.12 164.42,120.08 165.67,118.83 165.67,117.09 165.58,117.01 165.58,116.57 RC426.2 RC166.2 ; v1(98.1,95.68) 97.61,95.68 PC652.1 97.33,95.6 PC650.2 96.24,95.6 95.45,96.39 PC640.2 PR649.2
  IN1 w0.203: v1(133.85,109.21) 133.97,109.08 134.39,109.08 134.74,108.72 134.74,104.71 131.92,101.89 123.93,101.89 123.52,101.47 123.52,96.97 120.76,94.21 112.21,94.21 110.47,95.95 100.03,95.95 99.96,95.87 98.29,95.87 v1(98.1,95.68)
VCCDSW_EN: length 91.1
  TOP w0.107: RC445.1 204.2,74.35 203.45,73.61 v2(203.45,72.78) 203.45,68.72 204.14,68.02 228.19,68.02 233.9,73.73 235.52,73.73 237.17,72.08 237.69,72.08 v1(237.75,72.14) ; CE66.1 260.22,97.1 259.51,96.4 v1(259.18,96.4) 258.64,95.86 256.8,95.86 256.75,95.81 256.05,95.81 UE1.M7
  IN1 w0.102: v1(237.75,72.14) 238.18,72.58 238.18,79.52 239.39,80.72 239.39,81.61 239.52,81.74 242.13,81.74 243.88,83.49 243.88,83.77 244.69,84.58 244.69,86.38 245.54,87.24 245.54,88.9 246.61,89.97 248.12,89.97 248.22,89.87 249.91,89.87 251.47,91.43 253.77,91.43 254.02,91.67 254.02,92 254.25,92.23 255.09,92.23 255.1,92.22 255.41,92.22 255.42,92.23 255.45,92.23 256.8,93.58 258.13,93.58 258.88,94.34 258.88,96.1 v1(259.18,96.4)
VCCDSW_EN_GPIO: length 22.5
  TOP w0.107: v1(203.07,77.53) 202.3,76.77 DC1.2 RC445.2 ; QC6.2 194.37,69.59 194.37,71.32 193.92,71.77 v2(193.82,71.77) 193.1,71.77 RC431.1 v1(192.58,73.26)
  BOTTOM w0.107: v1(203.07,77.53) 202.6,77.53 198.15,73.09 193.56,73.09 193.38,73.26 v1(192.58,73.26)
VCCDSW_EN_Q: length 4
  TOP w0.107: DC1.1 200.6,74.51 DC2.2 200.17,74.08 v2(199.32,74.08) 198.46,74.95 RC442.1
VCCEOPIO_SENSE: length 1.4
  TOP w0.102: v1(147.77,95.6) 147.77,95.25 T368.1
  BOTTOM w0.203: v1(147.77,95.6) UC1.V25
VCCGT_SENSE_R: length 5.9
  BOTTOM w0.076: 139.41,111.4 139.81,111.24 140.09,110.96 140.09,110.25 140.14,110.2 140.14,110.19 140.24,110.1 140.24,109.82 140.24,109.5 140.24,109.5 140.24,109.21 UC1.E3
  BOTTOM w0.254: 139.41,111.4 139.24,111.4 137.98,112.66 RC632.1
VCCHDA: length 17.9
  TOP w0.127: v2(191.89,98.8) 192.59,98.11 192.59,97.52
  IN1 w0.254: v1(191.91,96.87) 191.76,96.72 189.68,96.72 188.61,97.79 183.86,97.79 183.49,97.43 180.76,97.43 180.43,97.1 178.68,97.1 178.15,97.63 177.07,97.63
  BOTTOM w0.203: UC1.BT20 171.31,97.82 171.29,97.82 v1(171.28,97.81)
VCCIO_SENSE: length 102.1
  TOP w0.107: v2(107.3,82.26) 107.11,82.07 RC163.2
  TOP w0.254: RC163.2 106.94,81.13 106.94,80.77 v1(107.12,80.59) 106.96,80.43 106.96,80.07 PR422.2
  IN3 w0.127: v1(171.01,93) 171.28,93.28 171.28,93.89 171.69,94.3 171.69,94.69 171.48,94.9 170.46,94.9 170.24,95.13
  IN3 w0.254: 170.24,95.13 170.24,95.6 170.09,95.75 170.09,96.3 166.92,99.47 144.18,99.47 143.24,98.53 138.16,98.53 137.95,98.33 136.99,98.33 135.51,99.8 129.35,99.8 123.85,94.31 111.59,94.31 110.44,95.46 102.47,95.46 100.26,93.25 100.26,84.02 101.28,83 105.85,83 106.85,82.01 106.85,80.86 v1(107.12,80.59)
  BOTTOM w0.089: v1(171.01,93) UC1.BP28
VCCPLL_EN: length 2.8
  TOP w0.107: RZ1419.2 173.36,66.55 173.63,66.81 173.63,68.02 v2(172.99,68.65)
VCCSENSE_R: length 10
  TOP w0.254: RC430.1 156.27,113.23 v2(156.89,112.61) 157.6,111.9 157.6,110.12 158.68,109.05 158.68,107.46 158.4,107.19 v1(158.22,107.19)
  BOTTOM w0.203: UC1.AN6 v1(158.22,107.19)
VCCST_EN: length 4.3
  TOP w0.107: RZ1416.2 196.53,127.7 196.51,127.71 UZ21.4 ; RZ1416.2 RZ1417.2 RZ1423.2 ; RZ1416.2 v2(197.53,126.39)
VCCST_PWRGD: length 222.8
  TOP w0.107: v1(263.71,92.21) 264.03,92.53 265.09,92.53 265.21,92.42 UE4.4 ; RC123.1 v1(86.04,132.74)
  IN3 w0.102: v1(157.83,126.32) 157.13,126.32 156.33,125.52 151.23,125.52 148.06,128.69 134.87,128.69 133.7,127.52 124.29,127.52 122.5,129.31 122.5,130.04 119.82,132.72 116.68,132.72 114.8,130.84 114.46,130.02 113.68,129.24 105.37,129.24 104.95,129.65 102.94,129.65 101.54,131.05 100.14,131.05 97.35,133.84 92.08,133.84 91.7,133.46 91.12,133.46 90.68,133.02 87.02,133.02 86.75,132.74 v1(86.04,132.74)
  BOTTOM w0.107: RC71.1 168.08,119.57 RC78.1 168.07,119.61 CC301.1 167.85,120.69 167.85,122.53 ; v1(157.83,126.32) 157.83,126.32 158.17,126.32 159.19,125.3 165.08,125.3 167.85,122.53 ; 167.85,122.53 168.89,123.57 177.16,123.57 179.65,121.08 185.28,121.08 185.82,120.54 186.45,120.54 187.41,119.58 189.46,119.58 189.79,119.25 190.83,119.25 191.46,118.61 198.27,118.61 198.92,117.97 201.8,117.97 201.94,117.83 206.34,117.83 206.82,117.36 208.25,117.36 210.86,114.74 v2(220.24,114.74) 224.06,114.74 231.39,107.41 239.5,107.41 241.46,109.37 247.28,109.37 248.05,108.6 250.4,108.6 250.71,108.9 250.71,110.14 251.47,110.91 255.44,110.91 256.28,110.07 256.28,109.05 258,107.33 258,106.06 259.36,104.69 259.36,101.57 259.87,101.06 259.87,100.21 259.32,99.65 258.59,99.65 257.62,98.68 257.62,97.11 257.85,96.88 259.35,96.88 259.81,96.42 259.81,95.57 263.17,92.21 v1(263.71,92.21)
VCCST_PWRGD_CPU: length 10
  BOTTOM w0.076: UC1.BJ2 166.88,109.97 166.88,110.3 166.64,110.54 166.64,113.12 166.49,113.27 166.49,115.91 166.56,115.97
  BOTTOM w0.107: 166.56,115.97 167.46,116.88 v2(167.46,117.59) 167.46,118.06 RC78.2
VCCSTG_EN: length 163.9
  TOP w0.107: UZ19.4 192.32,127.83 192.53,127.62 v1(192.53,127.45) 193.24,126.74 UZ35.4 193.24,126.29 193.35,126.18 194.14,126.18 194.24,126.29 RZ320.2 ; v1(234.75,70.87) 235.01,70.61 235.01,68.25 231.17,64.42 v2(175.94,64.42) 175.15,64.42 174.32,65.24 RZ120.1
  IN2 w0.102: v1(192.53,127.45) 192.83,127.15 192.83,124.87 190.41,122.45 190.41,119.61 187.98,117.19 187.98,116.44 187.87,116.32 187.87,116.1 186.82,115.05 186.82,111.17 190.63,107.36 190.63,105.05 190.53,104.95 189.26,104.95 188.91,104.59 188.91,104.02 189.16,103.77 189.92,103.77 190.01,103.86 190.62,103.86 191.13,103.35 191.13,103.02 191.23,102.92 193.07,102.92 193.49,103.33 194.55,103.33 196.34,101.55 197.79,101.55 199.96,99.38 199.96,97.65 199.24,96.94 199.24,95.26 200.48,94.03 201.51,94.03 205.8,89.74 205.89,89.74 209.92,85.71 210.66,85.71 212.3,84.07 213.46,84.07 214.3,83.23 215.26,83.23 215.51,82.98 219.04,82.98 220.45,81.57 222.92,81.57 223.95,80.54 225.11,80.54 225.71,79.93 229.17,79.93 233.16,75.94 233.16,72.67 234.75,71.08 v1(234.75,70.87)
VDD_CHG: length 15.8
  TOP w0.254: v1(80.5,43.34) 80.51,43.34 81.12,43.34 83.33,41.13 v2(83.59,41.13) 86.13,41.13 v1(87.49,39.77)
  BOTTOM w0.203: PR712.1 81.16,45.25 81.38,45.47 PU700.18
  BOTTOM w0.254: PR712.1 80.22,44.69 PR710.2 80.41,43.43 80.5,43.34 v1(80.5,43.34)
  BOTTOM w0.381: v1(87.49,39.77) 87.51,39.8 87.51,41.64 PR707.2
  BOTTOM w0.508: PR707.2 88.02,41.64 PC739.2
VDDP_CHG: length 3.1
  BOTTOM w0.107: PR707.1 87.51,42.91 86.72,42.12 86.72,40.65 v2(87.03,40.35)
VIN_1.2V_RUN: length 1.1
  TOP w0.107: 281.05,96.7 v2(281.05,97.75)
VIN_1.8VALW: length 2.7
  BOTTOM w0.107: PL502.2 205.47,112.12 206.07,111.52 207.44,111.52 v2(207.62,111.34)
VIN_1V_PRIM_CORE:
  vias: v1(212.28,131.33) v1(212.91,131.33) v2(215.26,132.09)
VIN_1VS_VCCIO: length 1.1
  TOP w0.107: PC408.1 v2(98.14,74.32)
VIN_2.5V_MEM:
  vias: v2(239.42,62.49)
VIN_CPU_CORE: length 5.7
  TOP w0.107: v1(92.79,102.05) v2(92.79,102.8)
  TOP w0.203: PC604.1 92.41,100.89 91.86,100.89 90.72,99.75 PU602.33
  TOP w0.254: PC604.1 v1(92.79,102.05)
  BOTTOM w0.254: v1(92.79,102.05) 92.51,102.33 PR603.1
VSS_SENSE_GT: length 75.3
  TOP w0.203: v1(112.23,95.9) 112.34,95.78 112.34,95.49 112.1,95.25 111.51,95.25 111.08,95.68 103.3,95.68 99.15,91.53 96.43,91.53 93.24,88.34 91.48,88.34 91.35,88.47 91.35,88.66 PC654.2 91.66,88.97 PC653.2 90.66,90.84 90.66,91.59 90.91,91.84 90.91,93 90.72,93.19 PU602.18
  IN1 w0.203: v1(112.23,95.9) 112.34,95.78 112.34,95.48 112.7,95.12 119.7,95.12 120.49,95.91 120.49,96.67 122.55,98.73 122.55,101.89 123.49,102.83 131.5,102.83 133.54,104.87 133.54,106.78 133.04,107.27 133.04,108.34 v1(133.17,108.47)
  BOTTOM w0.203: RC161.1 RC631.2 137.33,114.69 137.33,115.47 136.81,115.99 136.21,115.99 134.73,114.51 134.73,111.72 133.04,110.03 133.04,108.6 v1(133.17,108.47)
VSS_SENSE_IA: length 104.5
  TOP w0.203: v1(132.69,106.5) 132.58,106.6 132.58,106.88 132.67,106.97 133.98,106.97 139.42,112.41 140.38,112.41 143.3,115.33 143.3,116.77 143.61,117.08 143.61,119.95 144.1,120.44 146.85,120.44 148.46,122.06 152.08,122.06 152.69,121.44 152.69,118.61 154.3,117 155.5,117 155.68,116.82 155.68,116.47 RC429.2 RC151.1 ; v1(80.16,96.14) PC619.2 80.95,96.11 PC620.2 82.06,96.11 82.47,96.52 PU602.6
  IN1 w0.203: v1(132.69,106.5) 132.55,106.36 132.55,105.2 131.09,103.74 122.98,103.74 121.64,102.4 121.64,99.17 120.12,97.66 101.08,97.66 100.72,98.03 96.28,98.03 95.45,97.2 87.43,97.2 86.71,96.48 80.5,96.48 v1(80.16,96.14)
VSS_SENSE_SA: length 104.4
  TOP w0.203: RC164.1 RC425.2 165.25,116.58 165.25,117.14 165.34,117.23 165.34,118.69 164.09,119.94 164.09,121.98 163.54,122.54 162.47,122.54 161.81,123.2 161.81,125.12 161.43,125.5 157.68,125.5 156.82,124.64 149.74,124.64 146.48,121.37 143.54,121.37 142.27,120.1 142.27,115.59 140.01,113.33 139.01,113.33 134.41,108.74 133.96,108.74 v1(133.85,108.62) ; v1(98.1,96.31) 97.97,96.18 97.61,96.18 PC649.1 96.57,96.37 PC650.1 96.41,96.77 96.21,96.97 95.05,96.97 95,96.92 PU602.26
  IN1 w0.203: v1(98.1,96.31) 98.22,96.2 99.82,96.2 99.9,96.28 110.61,96.28 112.35,94.54 120.62,94.54 123.19,97.1 123.19,101.61 123.8,102.22 131.79,102.22 134.41,104.85 134.41,108.59 134.25,108.75 133.97,108.75 v1(133.85,108.62)
VSSEOPIO_SENSE: length 1.5
  TOP w0.102: v1(146.85,95.6) 146.74,95.6 T369.1
  BOTTOM w0.203: UC1.T25 146.85,95.35 v1(146.85,95.6)
VSSGT_SENSE_R: length 5.7
  BOTTOM w0.076: 139.04,111.12 139.33,110.83 139.33,110.61 139.48,110.46 139.48,110.19 139.95,109.72 UC1.D2
  BOTTOM w0.254: RC631.1 137.22,112.09 138.17,111.13 139.03,111.13 139.04,111.12
VSSIO_SENSE: length 104.4
  TOP w0.107: v2(105.94,82.28) 106.21,82.01 RC165.1
  TOP w0.254: PR412.2 106.39,80.07 106.39,80.43 v1(106.23,80.59) 106.39,80.75 106.39,81.11 RC165.1
  IN3 w0.127: v1(171.01,92.37) 171.1,92.28 171.36,92.28 171.47,92.39 171.47,92.53 171.49,92.54 171.49,93.81 171.66,93.98 172.12,93.98 172.21,94.08 172.21,94.99 172.09,95.12 172.09,95.59 171.96,95.72 170.5,95.72 170.36,95.86 170.36,96.5 169.9,96.95
  IN3 w0.254: 169.9,96.95 167,99.85 137.35,99.85 137.15,99.65 136.2,99.65 135.72,100.13 129.14,100.13 123.69,94.69 111.75,94.69 110.59,95.84 102.31,95.84 99.88,93.41 99.88,83.86 101.12,82.62 105.69,82.62 106.47,81.85 106.47,80.83 v1(106.23,80.59)
  BOTTOM w0.089: v1(171.01,92.37) UC1.BP29
VSSSENSE_R: length 9.2
  TOP w0.254: v1(158.21,107.82) 157.03,109 157.03,111.77 155.73,113.07 v2(155.73,114.01) 155.73,115.15 RC429.1
  BOTTOM w0.203: UC1.AN5 v1(158.21,107.82)
3MM_CAM_DET#: length 3.9
  BOTTOM w0.076: T399.1 185.59,104.07 185.11,103.6 184.48,103.6 184.27,103.39 UC1.CR12
32KHZ_OUT: length 4
  TOP w0.127: UE1.F3 250.5,92.66 v1(250.5,92.61)
  BOTTOM w0.107: v1(250.5,92.61) v2(250.5,90.76) 250.5,89.33 CE54.1
+BL_PWR_SRC: length 6
  TOP w0.127: v3(140.09,129.06) 138.81,129.06 137.64,130.22 DV11.2 ; DV11.2 137.64,130.85 138.31,131.52 v3(138.5,131.52) ; DV11.2 137.45,130.18 137.45,129.28 v3(137.54,129.19)
  vias: v1(134.02,133.44) v1(134.02,132.84) v1(134.64,132.48) v1(135.25,132.48)
+BL_PWR_SRC_P:
  vias: v1(133.89,136.23)
+COINCELL: length 4.1
  TOP w0.508: PR2.1 239.4,122.32 v1(239.45,122.37)
  BOTTOM w0.127: JRTC1.1 239.72,120.69 239.42,120.38 v2(238.3,120.38)
  BOTTOM w0.508: JRTC1.1 239.72,122.1 v1(239.45,122.37)
+DDR_VREF_A_CA: length 6.7
  TOP w0.381: RD16.1 CD25.1 CD26.1
  TOP w0.508: CD26.1 142.54,43.78 RD17.1 RD15.2 ; RD16.1 144.53,43.93 v2(144.53,44.92) 144.53,45.42 v1(144.42,45.53)
  BOTTOM w0.305: JDIMM1.164 144.2,45.76 v1(144.42,45.53)
+DDR_VREF_B_CA: length 1.6
  BOTTOM w0.254: v1(221.04,41.53) 221.22,41.53 221.6,41.91 JDIMM2.164
  vias: v2(220.7,41.09)
+DDR_VREF_B_DQ: length 213.8
  TOP w0.127: v1(119.84,81.22) v2(120.46,81.22)
  TOP w0.508: v1(218.75,44.97) 218.3,44.52 CD62.1 219.04,43.13 RD30.2
  IN1 w0.508: v1(119.84,81.22) 119.84,78.67 108.87,67.71 107.05,67.71 98.89,59.54 98.89,56.03 98.44,55.58 98.44,48.42 100.11,46.75 127.12,46.75 127.16,46.79 154.87,46.79 155.63,47.55 155.63,53.03 156.59,53.99 165.98,53.99 167.25,52.72 170.18,52.72 170.68,52.21 170.68,49.23 176.85,43.06 199.43,43.06 201.8,45.42 201.8,48.91 202.87,49.97 217.37,49.97 218.75,48.59 v1(218.75,44.97)
  BOTTOM w0.18: 136.28,86.87 136.33,86.92 138.81,86.92 138.92,87.04 138.93,87.04 138.95,87.06 139.84,87.06 140.51,87.72 UC1.E36
  BOTTOM w0.508: v1(119.84,81.22) 119.84,81.28 120.8,82.23 125.61,82.23 127.11,80.73 129.66,80.73 135.8,86.87 136.28,86.87
+DDR_VREF_CA: length 112.8
  TOP w0.508: v1(134,44.68) 135.2,43.48 v2(135.25,43.48) 135.4,43.33 139.2,43.33 139.63,43.76 CD31.1 139.94,43.78 RD17.2
  IN1 w0.508: v1(99.45,51.83) 99.45,55.16 99.9,55.61 99.9,59.12 107.47,66.69 109.29,66.69 121.22,78.61 v1(121.22,81.22)
  IN2 w0.508: v1(134,44.68) 133.71,44.68 133.09,45.3 133.09,46.28 132.38,46.99 131.6,46.99 131.09,47.5 116.48,47.5 115.32,48.65 114.35,48.65 113.38,47.69 103.12,47.69 103.01,47.8 99.63,47.8 99.12,48.31 99.12,51.46 99.45,51.79 v1(99.45,51.83)
  BOTTOM w0.18: UC1.F36 141.06,88.12 140.77,87.84 140.77,87.61 139.96,86.79 139.06,86.79 138.86,86.59 136.87,86.59 135.66,85.38 135.66,85.29
  BOTTOM w0.508: 135.66,85.29 130.08,79.71 126.69,79.71 125.19,81.22 v1(121.22,81.22)
+EC_DEBUG_VCC: length 3.2
  BOTTOM w0.305: JDEG1.1 218.97,83.2 219.28,83.5 219.9,83.5 220.2,83.8 v2(220.2,84.08) 220.2,84.88 RE71.2
+EDP_VDD:
  vias: v2(149.11,136.07)
+LCDVDD: length 1.2
  TOP w0.127: 145.85,135.23 145.85,136.31 v3(145.79,136.37)
  vias: v1(140.65,132.15) v1(141.28,132.15) v3(142.71,133.46) v3(144.97,133.49)
+LINE1-VREFO-L: length 1.2
  TOP w0.381: RA57.1 292.59,57.47 292.79,57.67 DA4.1
+LINE1-VREFO-R: length 2.3
  TOP w0.381: DA5.1 v2(294.44,57) 294.44,56.75 294.32,56.63 RA58.1
+MIC2-VREFO: length 29.9
  TOP w0.127: v1(296.38,35.19) v2(295.79,35.19)
  IN3 w0.508: v1(296.38,35.19) 294.38,37.18 294.38,40.08 293.24,41.22 293.24,49.82 291.68,51.38 289.17,51.38 288.67,51.89 288.67,56.21 287.71,57.16 v1(286.82,57.16)
  BOTTOM w0.508: RA5.1 296.27,35.09 v1(296.38,35.19) RA6.1
+PECI_VREF: length 0.6
  TOP w0.254: v1(253.61,99.81) 253.64,99.81 UE1.J11
  vias: v2(253,100.07)
+REGCTL_PNP10:
  vias: v2(272,103.31)
+RREF: length 2.5
  TOP w0.203: UR1.9 289.21,20.99 289.01,20.78
  TOP w0.305: RR4.1 288.16,21.03 288.4,20.78 289.01,20.78
+RSVD_VCC3P3_1: length 4.1
  TOP w0.203: UL1.1 269.66,104.19 269.3,103.83 v2(267.17,103.83) RL6.1
+RTC_CELL: length 129.9
  TOP w0.508: QE15.3 RE551.2 240.45,118.49 239.85,118.49 PC3.1 237.81,118.5 PD3.1 237.1,117.81 v2(237.1,116.96) v1(237.1,115.45) ; RE507.2 243.84,93.5 243.84,92.96 v1(243.94,92.96) ; RA54.2 v1(296.41,54.05)
  IN1 w0.508: v1(280.13,75.27) 279.55,74.7 274.45,74.7 272.05,77.1 v1(271.27,77.1)
  IN2 w0.508: v1(296.41,54.05) 296.41,62.13 295.16,63.38 291.56,63.38 289.75,65.19 289.75,66.88 289.17,67.45 285.97,67.45 282.8,70.62 280.58,70.62 280.07,71.13 280.07,72.97 280.13,73.03 280.13,73.1 280.13,73.1 280.13,73.61 280.13,73.61 v1(280.13,75.27) ; v1(237.1,115.45) 237.82,115.45 242.67,110.61 242.67,109.59 243.12,109.13 243.12,106.12 244.74,104.5 244.74,103.03 244.46,102.75 244.46,101.41 244.28,101.24 244.28,100.34 243.96,100.02 243.96,97.46 243.38,96.88 243.38,94.49 243.94,93.93 v1(243.94,92.96) 243.94,92.56 244.55,91.94 244.55,84.92 245.3,84.17 245.3,83.29 v1(245.29,83.29)
  IN3 w0.508: v1(245.29,83.29) 245.29,83.95 245.87,84.53 247.84,84.53 248.6,85.29 250.03,85.29 250.46,84.86 250.68,84.86 251.19,84.35 252.97,84.35 253.45,83.87 255.46,83.87 257.64,81.68 259.59,81.68 260.33,80.94 260.33,79.88 261.42,78.8 264.93,78.8 266.1,77.62 267.74,77.62 268.26,77.1 v1(271.27,77.1)
  BOTTOM w0.508: RE508.2 244.29,90.99 243.77,91.51 243.77,92.38 243.94,92.54 v1(243.94,92.96) 243.87,92.9 242.72,92.9 242.53,93.09 RE31.1 ; RE508.2 244.41,90.27 245.07,89.61 RE822.2 ; RE508.2 RE32.1
+RTC_CELL_PCH: length 181.4
  TOP w0.508: v1(229.05,122.26) 229.05,100.89 230.75,99.19 230.75,94.71 230.11,94.07 230.11,79.59 227.58,77.06 227.58,74.88 v2(224.56,71.85) 221.42,68.72 220.53,68.72 217.43,71.82 217.43,72.54 v1(217.74,72.84) ; RC69.2 RC56.2 173.26,73.23 CC73.1 173.26,72.83 173.83,72.26 174.93,72.26 v1(175.4,72.73) ; v1(203.96,73.29) 205.04,74.36 RC57.2
  IN2 w0.508: v1(217.74,72.84) 216.85,72.84 213.86,75.83 207.77,75.83 207.31,76.29 198.55,76.29 198.11,76.72 195.45,76.72 195.02,77.14 193.99,77.14 193.08,76.24 190.62,76.24 189.36,77.49 189.36,78.18 188.86,78.69 188.52,78.69 186.72,80.48 186.72,81.51 181.35,86.89 181.35,89.04 ; v1(229.05,122.26) 236.44,122.26 237.17,122.98 242.6,122.98 245.82,119.77 v1(246.82,119.77)
  BOTTOM w0.203: v1(171.34,96.15) 171.05,96.52 UC1.BR23
  BOTTOM w0.508: v1(175.4,72.73) 179.36,72.73 180.7,71.39 183,71.39 183.57,70.82 190.71,70.82 191.81,71.91 200.1,71.91 201.48,73.29 v1(203.96,73.29) 204.46,72.78 217.68,72.78 v1(217.74,72.84)
+RTC_CELL_VBAT: length 3.1
  TOP w0.254: v1(246.38,92.64) 246.38,92.47 246.63,92.21 UE1.A2
  BOTTOM w0.089: v2(246.52,93.16) 246.38,93.03 v1(246.38,92.64)
  BOTTOM w0.356: CE11.1 246.12,92.38 v1(246.38,92.64)
  BOTTOM w0.381: RE32.2 245.21,91.87 246.06,91.87 CE11.1
+SDREG2: length 0.9
  TOP w0.102: CR15.1 v2(294.85,26.15)
+SIM_PWR: length 94.4
  TOP w0.127: v1(302.24,23.7) 302.7,23.7 302.87,23.86 v2(302.87,24.1)
  TOP w0.508: CZ41.1 CZ37.1 302.18,23.63 v1(302.24,23.7) ; v1(298.91,23.72) 298.59,23.39 RZ335.1
  IN2 w0.508: v1(302.24,23.7) 301.73,23.18 299.4,23.18 298.91,23.67 v1(298.91,23.72) 298.91,24.48 299.26,24.83 299.26,26.91 294.35,31.81 293.29,31.81 288.69,36.41 282.82,36.41 279.4,39.84 279.4,48.49 277,50.88 277,51.78 275.8,52.98 275.8,54.41 273.69,56.52 273.69,57.02 272.73,57.99 272.73,62.9 271.99,63.64 271.99,70.05 272.97,71.02 272.97,74.13 272.73,74.37 272.73,77.84 272.04,78.52 272.04,81.36 273.36,82.67 273.36,83.26 v1(274.44,84.34)
  BOTTOM w0.305: v1(274.44,84.34) 269.29,84.34 268.33,83.38 JNGFF2.28
  BOTTOM w0.508: v1(302.24,23.7) 303.28,24.74 JSIM1.C1
+TBTA_LDO_BMC: length 6.4
  BOTTOM w0.107: CT71.1 54.82,102.57 54.33,102.08 53.53,102.08 53.46,102.14 52.88,102.14 v2(52.64,101.9)
  BOTTOM w0.203: UT5.E1 57.79,103.77 57.3,103.77 57.18,103.65 55.75,103.65 55.43,103.33 55.43,102.79 55.23,102.59 CT71.1
+TS_PWR_QV8: length 0.9
  TOP w0.107: v3(123.17,132.26) 123.03,132.12 122.3,132.12
+TS_PWR_SRC: length 7.3
  TOP w0.107: 123.13,130.06 122.94,130.06 122.63,129.74 122.42,129.74 121.67,128.99 121.67,127.25 v3(120.7,126.27)
  BOTTOM w0.254: JEDP1.1 125.77,131.57 124.86,132.48 v1(124.46,132.48)
+USB_EX2_PWR: length 0.6
  TOP w0.127: v1(19.49,86.69) v2(19.49,87.34)
  vias: v1(17.46,96.09) v1(17.46,95.45) v1(18.09,96.09) v1(18.09,95.45) v1(18.85,86.69) v1(18.85,86.05) v1(19.49,86.05)
+USB_EX3_PWR:
  vias: v3(298.12,51.86)
+UZ12_TPM:
  vias: v2(228.06,103.92)
+VHDMI_VCC: length 14.2
  TOP w0.508: RV10.2 RV735.2 297.81,91.86 v1(298.22,91.45)
  IN1 w0.508: v1(303.91,81.34) 303.91,82.66 302.79,83.77 302.79,85.26 298.05,90 298.05,91.29 v1(298.22,91.45)
  vias: v1(303.22,81.34) v2(303.51,80.77)
+VR_CAP: length 32.3
  TOP w0.254: UE1.J1 253.25,91.12 253.3,91.07 253.3,89.99 v1(253.17,89.86) ; UE1.C10 248.08,98.98 v1(248.03,98.98)
  TOP w0.381: CE31.1 v1(253.17,89.86)
  IN2 w0.508: v1(243.23,99.24) 243.23,97.62 241.51,95.91 241.51,95.15 242.4,94.26 242.4,92.53 242.6,92.33 243.15,92.33 243.64,91.83 243.64,90.43 243.08,89.87 243.08,89.04 243.91,88.22 v1(243.91,88.22)
  IN3 w0.508: v1(253.17,89.86) 252.75,89.44 249.26,89.44 247.31,87.5 244.63,87.5 v1(243.91,88.22)
  BOTTOM w0.508: v1(243.23,99.24) 243.95,99.96 v2(245.26,99.96) 245.87,99.35 246.84,99.35 247,99.18 247.83,99.18 v1(248.03,98.98)
+Z4012: length 4.6
  TOP w0.508: PQ13.2 239.64,123.63 v2(239.37,123.36) PR9.1 238.53,121.65 PR2.2 238.49,120.44 PD3.2
AC1_DISC#: length 5.3
  BOTTOM w0.076: UT5.G11 63.35,104.81 63.76,105.23 v2(64.19,105.23) 64.57,105.23
  BOTTOM w0.107: RT72.1 65.97,107.26 65.62,106.92 65.62,105.7 65.15,105.23 64.57,105.23
AC_DIS: length 323.9
  TOP w0.102: 252.03,100.77 252.03,100.63 UE1.H12
  TOP w0.107: 252.03,100.77 v1(252.03,101.42) 252.03,101.89 250.22,103.71 249.13,103.71 248.19,104.65 RE83.1
  IN2 w0.089: 260.83,88.68 260.28,89.23 258.63,89.23 258.25,89.61 257.66,89.61 256.22,91.05 256.22,92.02 256.47,92.28 256.47,95.26 255.47,96.26 253.83,96.26 253.43,96.66 252.5,96.66 252.03,97.13 252.03,98.5 251.69,98.84 251.69,99.31 252.03,99.64 252.03,100.73
  IN2 w0.102: v1(71.79,40.71) 73.44,39.06 78.69,39.06 82.19,42.56 82.19,44.62 82.06,44.74 82.06,48.71 82.26,48.91 85.07,48.91 85.29,49.13 86.54,49.13 86.73,49.32 90.5,49.32 91.71,50.54 97.11,50.54 97.67,51.09 97.67,52.49 100.1,54.92 131.42,54.92 133.14,53.2 133.14,48.27 133.77,47.65 133.96,47.65 135.97,45.64 135.97,45.07 136.74,44.3 136.74,43.71 136.76,43.68 136.76,43.39 137.19,42.97 146.93,42.97 149.48,40.41 162.28,40.41 166.87,35.82 177.27,35.82 182.53,30.56 193.33,30.56 196.51,33.74 197.54,33.74 198.24,34.44 198.24,35.17 198.67,35.6 202.11,35.6 202.24,35.72 205.03,35.72 207.29,37.98 208.66,37.98 209.3,37.35 215.47,37.35 216.26,36.56 221.86,36.56 222.78,35.64 222.78,35.4 223.44,34.73 223.44,32.94 225.53,30.85 232.05,30.85 233.82,32.63 238.31,32.63 240.31,30.63 255.85,30.63 257.56,32.33 258.71,32.33 264.72,38.35 264.72,41.63 264.45,41.91 264.45,43.2 264.34,43.31 264.34,44.54 265.12,45.32 265.12,49.09 264.66,49.55 264.66,59.05 265.03,59.42 265.03,62.47 262.3,65.21 262.3,75.01 261.84,75.47 261.84,76.62 261.61,76.85 261.61,78 260.68,78.93 260.68,82.43 261.81,83.56 261.81,87.7 260.83,88.68 ; 252.03,100.73 v1(252.03,101.42)
  BOTTOM w0.254: v1(71.79,40.71) 71.79,44.26 72.07,44.53 72.07,44.96 arc(72.11,45.19) 72.24,45.39 72.53,45.67 72.53,47.72 v2(73.95,49.15) 74.59,49.79 PQ703.2 76.06,50.37 PR720.1
AC_DISC#: length 360.1
  TOP w0.102: v1(246.59,102.5) 248.98,102.5 249.6,101.88
  TOP w0.107: UE1.E13 250.05,101.43 249.6,101.88
  TOP w0.254: 48.19,89.23 48.19,88.66 47.81,88.28 PQ810.3 47.57,88.58 46.27,89.88 PQ810.6 ; 48.19,89.23 48.19,91.06 48.45,91.31 PC810.1 ; 48.19,89.23 50.29,89.23 50.87,88.64 PR829.1 51.48,88.28 v2(52.13,88.28) v1(52.7,88.85) ; PC810.1 48.83,91.18 48.81,91.17 PQ811.6 ; PC810.1 PR828.2
  IN1 w0.099: v1(227.45,32.96) 227.04,33.37 224.01,33.37 221.05,36.33 216.16,36.33 215.37,37.12 207.65,37.12 206.17,35.64 203.97,35.64 202.99,34.65 198.85,34.65 197.45,33.26 194.9,33.26 192.27,30.63 172.08,30.63 162.45,40.27 152.78,40.27 149.6,43.44 136.39,43.44 136.25,43.3 132.49,43.3 132.35,43.44 100.94,43.44 90.84,53.54 84.19,53.54 84.09,53.44 82.66,53.44 82.38,53.16 82.38,52.04 81.49,51.15 81.49,46.96 79.56,45.03 79.56,44.97 79.08,44.49 79.08,44.48 78.84,44.25 78.84,44.25 78.61,44.02 v1(77.91,44.02)
  IN2 w0.102: v1(52.7,88.85) 52.7,87.86 59.64,80.92 61.51,80.92 69.24,73.19 72.67,65.22 73.39,63.55 73.39,45.35 71.69,43.65 71.69,41.92 72.28,41.32 73.75,41.32 76.44,44.02 v1(77.91,44.02) ; v1(246.59,102.5) 245.58,101.48 245.58,96.72 245.09,96.23 245.09,95.29 245.06,95.26 245.06,94.59 245.09,94.56 245.09,94.2 245.58,93.71 245.58,92.89 246.39,92.07 246.39,90.16 245.53,89.3 245.53,87.69 245.89,87.33 245.89,85.66 247.39,84.16 247.39,80.94 246.2,79.74 246.2,77.53 249.72,74.01 250.17,74.01 253.6,70.59 253.6,69.24 256.51,66.33 256.51,65.9 257.44,64.97 257.44,63.62 260.9,60.16 260.9,51.7 259.93,50.73 259.93,46.1 259.48,45.66 259.48,44.94 257.72,43.18 257.72,39.14 253.32,34.74 252.09,34.74 251.33,33.98 248.38,33.98 247.77,34.59 240.22,34.59 239.68,35.14 231.58,35.14 230.05,33.61 228.09,33.61 v1(227.45,32.96)
AC_PRESENT: length 152.7
  TOP w0.127: v1(254.45,97.42) 254.45,97.42 UE1.K8
  IN1 w0.089: 180.14,80.68 180.14,81.22 179.76,81.61 177.84,81.61 176.52,82.93 174.67,82.93 172.46,85.13 172.46,85.46 171.89,86.03 v1(171.89,86.03)
  IN1 w0.099: v1(239.35,68.78) 239.35,67.98 236.31,64.94 230.91,64.94 226.94,68.92 222.56,68.92 221.47,70 220.9,70 219.45,71.45 219.45,71.7 219.21,71.94 197.65,71.94 196.33,73.26 196.33,74.66 195.76,75.23 188.5,75.23 187.62,76.11 183.34,76.11 181.61,77.85 181.61,78.42 180.23,79.8 180.23,79.81 180.14,79.89 180.14,80.68
  IN2 w0.102: v1(262.95,65.89) 262.95,67.68 264.03,68.76 264.03,70.43 262.9,71.55 262.9,77.38 263.66,78.14 263.66,82.14 262.44,83.36 262.44,88.28 260.35,90.38 260.35,94.49 259.51,95.33 258.5,95.33 256.79,97.04 254.83,97.04 v1(254.45,97.42)
  BOTTOM w0.076: RC555.1 172.97,82.13 v2(172.51,82.59) 172.32,82.78 172.32,83.88 171.74,84.47 171.74,85.04 171.89,85.19 v1(171.89,86.03) 171.89,86.03 171.89,86.43 172.04,86.59 172.04,87.86 172.14,88.04 172.14,88.67 UC1.BU35
  BOTTOM w0.107: v1(239.35,68.78) 239.66,68.47 241.93,68.47 243.38,67.02 250.45,67.02 250.89,67.45 253.24,67.45 254.25,66.45 257.68,66.45 258.15,65.98 262.86,65.98 v1(262.95,65.89)
ACAV_IN: length 321.7
  TOP w0.107: v1(241.17,102.89) 241.17,103.48 v3(241.09,103.56) 240.62,104.02 240.62,108.17 241.65,109.2 DZ12.1 ; v1(248.05,95.86) 248.1,95.86 UE1.C7
  TOP w0.254: PR3010.2 v1(69.73,40.19)
  IN2 w0.089: 250.25,90.4 250.25,91.12 249.28,92.09 249.28,94.88 249.27,94.89 249.27,95.22 249.07,95.42 248.66,95.42 248.22,95.86 v1(248.05,95.86)
  IN2 w0.102: v1(79.24,42.52) 79.8,43.08 79.8,49.64 81.67,51.5 89.98,51.5 94.41,55.94 96.45,55.94 98.38,57.87 130.86,57.87 133.79,54.94 134.6,54.94 135.5,54.04 135.5,48.37 136.43,47.45 137.31,47.45 139.03,45.72 139.03,44.92 139.31,44.64 154.2,44.64 156.6,42.24 163.04,42.24 163.07,42.21 167.63,37.65 178.03,37.65 183.29,32.39 193.21,32.39 197.07,36.26 197.39,36.26 198.69,37.55 198.69,37.78 200.02,39.11 204.45,39.11 204.71,39.38 212.59,39.38 213.25,38.72 216.04,38.72 216.09,38.67 221.69,38.67 223.27,37.08 224.01,37.08 224.94,36.15 224.94,33.63 226.34,32.24 229.97,32.24 231.96,34.23 239.3,34.23 239.84,33.68 242.6,33.68 243.21,33.07 254.88,33.07 257.67,35.86 257.67,37.8 259.99,40.12 259.99,40.94 260.4,41.35 260.4,45.28 260.84,45.72 260.84,50.35 261.81,51.32 261.81,60.97 258.45,64.33 258.45,65.31 257.88,65.88 257.88,70.16 254.35,73.7 253.67,73.7 251.71,75.66 250.94,75.66 250.22,76.37 249.96,76.37 247.95,78.38 247.95,79.89 248.53,80.46 248.53,85.52 247.43,86.62 247.43,87.69 249.52,89.78 249.83,89.78 250.25,90.2 250.25,90.4
  IN3 w0.089: 246.6,96.18 247.39,96.18 247.71,95.86 v1(248.05,95.86)
  IN3 w0.102: 246.6,96.18 246.54,96.18 243.84,98.88 243.84,99.27 242.58,100.53 242.58,100.99 241.17,102.4 v1(241.17,102.89)
  BOTTOM w0.089: CE67.1 248.39,96.21 v1(248.05,95.86)
  BOTTOM w0.254: v1(69.73,40.19) 69.73,39.39 70.67,38.45 75.4,38.45 77.4,40.46 PR740.2 PR744.1 78.89,42.16 v1(79.24,42.52)
ACAV_IN1: length 51.4
  TOP w0.107: v1(79.12,43.83) 78.66,43.83 v3(78.46,43.62)
  TOP w0.254: v1(70.34,40.19) 70.59,39.94 PR3009.2
  IN1 w0.254: v1(70.34,40.19) 70.34,39.04 71.1,38.28 72.69,38.28 73.6,37.36 83.75,37.36 86.88,34.24 88.7,34.24 89.45,34.98 89.45,36.04 85.05,40.45 82.67,40.45 81.94,41.18 80.43,41.18 79.75,41.86 79.75,43.44 79.37,43.83 v1(79.12,43.83)
  IN2 w0.254: v1(79.12,43.83) 79.5,44.21 79.5,45.22 77.91,46.81 v1(77.91,48.97)
  BOTTOM w0.254: v1(79.12,43.83) 79.5,44.21 PR710.1 ; PR722.1 78.91,49.35 78.61,49.65 PR716.1 v1(77.91,48.97) PR741.1 77.27,48.28 76.88,47.89 PQ703.1
ACIN_CHG: length 43.9
  TOP w0.107: PR706.1 v2(80.67,47.74)
  TOP w0.254: PR3001.2 v1(74.54,31.65) ; PR706.1 PC736.1 PR705.2 81.33,46.09 v1(80.96,45.72)
  IN1 w0.254: v1(74.54,31.65) 73.78,32.41 73.78,35.04 75.73,36.98 83.59,36.98 86.72,33.86 88.86,33.86 89.83,34.83 89.83,36.2 85.21,40.83 82.83,40.83 81.29,42.37 81.29,43.34 80.91,43.72 80.91,45.69 80.93,45.72 v1(80.96,45.72)
  BOTTOM w0.203: v1(80.96,45.72) 80.96,45.75 81.07,45.87 PU700.19
ACOK_CHG: length 2.8
  BOTTOM w0.203: PU700.24 82.07,47.87 81.61,48.33 81.61,48.76 v2(81.28,49.1) 81.02,49.35 PR722.2
ADJ_1.2V_RUN: length 4.8
  TOP w0.107: PR512.2 287.84,97.05 v2(289.01,97.05)
  TOP w0.457: PU502.3 285.93,98.18 286.05,98.3 PR510.1
  TOP w0.508: PR512.2 286.7,97.37 PC509.2 PR510.1
ADJ_2.5V_MEM: length 3.2
  TOP w0.254: PU503.3 243.3,57.44 242.98,57.11 PC515.2 PR515.2 PR516.1
ADP_CHG: length 1.8
  TOP w0.254: v1(81.48,44.18) 81.83,43.83 PR703.2
  BOTTOM w0.107: v1(81.48,44.18) 81.48,44.08 v2(80.98,43.58)
ALW_PWRGD_3V_5V: length 210.5
  TOP w0.107: DC2.1 203.25,74.51 v1(203.73,74.99) ; UZ41.2 265.81,94.43 265.49,94.12 265.49,93.62 264.81,92.94 264.29,92.94 v1(264.16,93.08) ; v1(234.81,41.63) 235.17,41.63 235.61,41.19 v1(235.61,38.57)
  IN1 w0.099: v1(264.16,93.08) 264.45,92.78 264.45,91.42 264.12,91.09 264.12,88.02 262.47,86.37 262.47,84.11 260.18,81.82 260.18,79.9 257.93,77.65 257.93,75.09 257.04,74.21 257.04,67.74 v1(256.82,67.53) ; v1(236,70.13) 235.66,69.8 233.29,69.8 232.57,70.52 231.02,70.52 229.44,68.94 228.23,68.94 224.04,73.13 221.61,73.13 218.51,76.24 215.59,76.24 214.04,74.69 204.03,74.69 v1(203.73,74.99) ; v1(245.23,47.76) 245.08,47.76 244.04,46.73 244.04,44.66 241.57,42.18 235.37,42.18 v1(234.81,41.63)
  IN3 w0.102: v1(197.27,37.32) 197.29,37.31 200.55,37.31 201.16,37.92 203.07,37.92 204.15,39 208.67,39 209.18,38.49 214.22,38.49 214.57,38.85 216.83,38.85 217.42,39.44 235.36,39.44 235.61,39.19 v1(235.61,38.57)
  IN3 w0.107: v1(203.73,74.99) 204.14,75.4 206.96,75.4 207.3,75.74 213.56,75.74 216.06,73.25 217.91,73.25 223.9,67.26 224.49,67.26 226.67,65.08 228.19,65.08 230.63,62.64 231.9,62.64 237.48,57.06 238.78,57.06 243.58,52.25 243.58,51.46 243.9,51.14 243.9,48.59 244.72,47.76 v1(245.23,47.76)
  BOTTOM w0.107: v1(236,70.13) 236.35,70.48 241.59,70.48 244.39,67.69 256.67,67.69 v1(256.82,67.53)
  BOTTOM w0.254: PR120.2 PR119.2 200.01,35.72 199.69,35.72 199.18,36.23 198.37,36.23 v2(197.79,36.81) v1(197.27,37.32)
ALWON: length 283.5
  TOP w0.127: UE1.A5 246.77,94.69 245.01,94.69 244.68,95.01 v1(244.68,95.55)
  IN1 w0.099: v1(82.99,53.03) 84.01,53.03 84.29,53.31 90.75,53.31 100.84,43.22 132.25,43.22 132.4,43.08 136.34,43.08 136.48,43.22 149.51,43.22 152.68,40.04 162.35,40.04 171.99,30.4 192.37,30.4 194.99,33.03 197.61,33.03 199,34.43 203.08,34.43 204.06,35.41 206.27,35.41 207.75,36.89 215.28,36.89 216.07,36.1 220.95,36.1 224.09,32.96 v1(226.8,32.96)
  IN2 w0.102: v1(244.68,95.55) 244.68,95.5 244.77,95.41 244.77,95.32 244.83,95.26 244.83,93.94 245.14,93.63 245.14,93.04 246.18,91.99 246.18,90.24 245.33,89.39 245.33,87.6 245.66,87.27 245.66,85.56 247.16,84.07 247.16,82.58 245.72,81.13 245.72,77.69 249.7,73.71 249.97,73.71 253.37,70.31 253.37,69.15 256.14,66.37 256.14,65.94 257.17,64.92 257.17,63.39 260.67,59.89 260.67,51.8 259.7,50.83 259.7,46.2 259.25,45.75 259.25,45.04 257.49,43.27 257.49,39.23 256.49,38.24 255.26,38.24 254.7,37.68 254.7,36.44 253.23,34.97 251.99,34.97 251.23,34.21 248.47,34.21 247.86,34.82 240.32,34.82 238.89,36.25 234.06,36.25 233.18,35.37 231.49,35.37 229.95,33.83 227.67,33.83 v1(226.8,32.96)
  IN2 w0.254: v1(77.57,59.08) 79.1,57.54 79.1,55.26 81.33,53.03 v1(82.99,53.03)
  BOTTOM w0.254: PR114.1 v2(74.48,68.16) 74.48,65.37 77.57,62.29 v1(77.57,59.08)
AMON/BMON_CHG: length 6.9
  TOP w0.107: v2(85.86,52.75) 85.76,52.65 85.76,51.04 85.56,50.84 PR743.1
  TOP w0.254: PR743.1 PR729.1 84.53,49.96 v1(84.78,49.71)
  BOTTOM w0.203: PU700.29 84.54,49.14 84.78,49.39 v1(84.78,49.71) 84.78,50.52 PC750.1
AUD_HP_NB_SENSE: length 36.7
  TOP w0.127: v1(291.59,50.61) 291.85,50.61 v2(292.13,50.33)
  TOP w0.254: v1(291.59,50.61) RA60.2
  IN3 w0.254: v1(302.92,30.87) 303.02,30.87 304.86,29.03 307.91,29.03 308.73,29.85 JHP1.6
  BOTTOM w0.254: v1(291.59,50.61) 293.45,48.74 293.45,41.96 294.25,41.16 294.25,33.82 297.01,31.06 300.03,31.06 300.53,31.56 DA2.3 302.33,31.56 302.92,30.97 v1(302.92,30.87)
AUD_HP_OUT_L: length 27.8
  TOP w0.381: v1(296.58,32.31) 296.54,32.36 296.54,33.3 296.92,33.68 LA16.1 ; v1(293.51,55.57) RA7.2 RA57.2
  BOTTOM w0.381: v1(293.51,55.57) 293.51,52.45 294.02,51.93 294.02,42.2 294.83,41.39 294.83,34.05 v2(295.9,32.98) 296.57,32.31 v1(296.58,32.31)
AUD_HP_OUT_L1: length 14.6
  TOP w0.381: LA16.2 298.09,34.53 298.12,34.57 CA2.2 298.69,35.13 v2(299.33,35.13) 300.23,35.13 301.87,33.49 DA1.3 302.76,34.29 302.76,34.3 v1(303.08,34.62)
  IN2 w0.381: v1(303.08,34.62) 303.49,35.03 303.49,38.84 304,39.35 JHP1.1
AUD_HP_OUT_R: length 25.5
  TOP w0.381: LA15.1 v1(297.24,32.84) ; v1(294.95,54.93) RA58.2 294.31,54.94 RA8.2
  BOTTOM w0.381: v1(297.24,32.84) 296.94,32.84 295.46,34.32 295.46,41.66 294.66,42.46 294.66,54.63 v1(294.95,54.93)
AUD_HP_OUT_R1: length 17.4
  TOP w0.381: LA15.2 298.1,31.4 CA3.2 298.28,31.37 298.72,30.92 v2(299.07,30.92) 299.33,30.92 299.97,31.56 DA1.2 302.81,31.56 v1(303.21,31.95)
  IN1 w0.381: v1(303.21,31.95) 303.46,31.7 303.46,30.43 304.86,29.03 310.83,29.03 311.65,29.85 JHP1.2
AUD_PC_BEEP: length 4.7
  TOP w0.203: UA1.11 288.5,51.74 288.73,51.51 v2(288.73,49.92) 289.36,49.29 CA27.2 289.86,48.42 CA28.2
AUD_PWR_EN: length 112.6
  TOP w0.107: RC279.1 v2(197.61,80.44) 197.61,80.84 v1(197.83,81.06) ; UZ5.5 270.3,59.97 270.12,60.14 270.12,60.65 270.31,60.84 270.76,60.84 v1(271.2,60.4) 271.1,60.29 UZ5.3
  IN1 w0.099: v1(184.2,85.8) 184.27,85.8 184.52,85.55 186.36,85.55 186.86,85.06 186.86,85.05 187.66,84.25 187.8,84.25 190.61,81.45 197.45,81.45 v1(197.83,81.06)
  IN2 w0.102: v1(197.83,81.06) 198.51,81.73 199.58,81.73 200.76,80.55 204.34,80.55 205,79.89 208.05,79.89 208.21,79.73 210.97,79.73 211.42,79.28 212.07,79.28 212.15,79.36 214.84,79.36 216.81,77.39 220.21,77.39 225.81,71.8 225.81,70.73 228.1,68.44 230.44,68.44 233.95,64.92 245.55,64.92 245.92,64.55 v1(246.78,64.55)
  BOTTOM w0.076: UC1.CK36 180.07,88.31 180.07,88 181.16,86.9 181.71,86.9 182.75,85.86 183.96,85.8 v1(184.2,85.8)
  BOTTOM w0.107: v1(246.78,64.55) 247.34,65.11 257.08,65.11 259.55,62.65 265.79,62.65 267.28,64.13 269.71,64.13 271.36,62.48 271.36,60.56 v1(271.2,60.4)
AUD_SENSE_A: length 7.1
  TOP w0.203: 289.26,51.61 288.73,52.14 UA1.12
  TOP w0.254: 289.26,51.61 289.35,51.52 CA41.1 RA60.1 291.03,51.45 v2(293.24,51.45) 294.81,51.45 RA59.2
AUX_EN_WOWL: length 48.5
  TOP w0.107: DZ9.2 268.12,75.27 RZ70.1 268.12,75.4 RZ379.2 268.85,76.91 RZ1483.2 268.61,77.15 264.3,77.15 263.38,76.23 263.38,75.22 261.73,73.57 257.73,73.57 256.51,72.35 v2(255.8,72.35) v1(254.44,72.35)
  TOP w0.127: UE1.D3 v1(248.85,92.61)
  IN2 w0.089: v1(248.85,92.61) 248.85,92.23 249.39,91.69 249.39,90.46 248.62,89.68 247.37,89.68 246.68,89 246.68,88.67 246.76,88.59 246.76,86.98
  IN2 w0.102: 246.76,86.98 246.76,85.76 248.08,84.45 248.08,80.65 246.88,79.46 246.88,78.17 250.12,74.94 250.84,74.94 253.43,72.35 v1(254.44,72.35)
BAT1_LED#: length 17.5
  TOP w0.127: UE1.D10 v1(248.85,99.01)
  TOP w0.254: RZ28.1 242.94,109.27 v2(242.89,109.22) 242.67,109 242.67,107.03 241.59,105.96 v1(241.59,104.98)
  IN3 w0.089: 246.6,99.12 246.81,98.92 247.41,98.92 247.88,99.39 248.46,99.39 v1(248.85,99.01)
  IN3 w0.254: v1(241.59,104.98) 242.63,103.93 243.19,103.93 244.03,103.1 244.03,102.08 244.37,101.74 244.37,100.95 246.2,99.12 246.6,99.12
BAT1_LED#_R: length 2.8
  TOP w0.254: QZ3.2 244.46,111.34 v2(243.73,111.34) QZ21.1
BAT2_LED#: length 9.7
  TOP w0.127: v1(248.85,99.81) UE1.D11
  TOP w0.254: RZ361.1 243.09,101.12 243.09,101.12 v1(243.09,100.63)
  IN1 w0.254: v1(248.85,99.81) 248.48,99.44 247.57,99.44 247.44,99.31 247.06,99.31 246.69,99.67 246.69,100.85 246.08,101.46 243.92,101.46 v1(243.09,100.63)
BATGONE_CHG: length 5.9
  TOP w0.254: v1(82.5,49.71) 81.71,48.92 PC744.1
  BOTTOM w0.203: PU700.25 82.94,49.26 v1(82.5,49.71) 81.8,49.71 80.78,50.72 PR723.1 PR724.2
BATT_WHITE#: length 139.9
  TOP w0.254: v1(240.51,101.59) 240.79,101.86 v2(241.12,101.86) RZ361.2
  IN3 w0.254: v1(307.57,9.6) 307.08,10.09 307.08,15.1 306.62,15.57 301.53,15.57 298.64,18.47 298.64,19.12 297.37,20.39 295.33,20.39 294.67,21.05 288.58,21.05 285.81,23.82 285.81,29.54 286.29,30.02 286.29,30.58 285.21,31.66 285.21,32.13 283.73,33.61 283.73,36.84 283.22,37.35 283.22,41.37 282.44,42.15 282.44,43.74 282.19,43.99 278.78,43.99 274.02,48.75 274.02,50.91 269.34,55.59 269.34,57.79 266.74,60.38 266.74,68.59 262.89,72.45 262.89,73.05 255.42,80.52 254.62,80.52 253.13,82.01 250.08,82.01 249.75,82.34 245.34,82.34 244.37,83.31 244.37,84.66 241.29,87.74 240.28,87.74 240.09,87.94 240.09,92.3 240.86,93.08 240.86,93.72 240.1,94.49 240.1,96.47 239.34,97.22 239.34,98.38 240.67,99.71 240.67,101.42 v1(240.51,101.59)
  BOTTOM w0.254: v1(307.57,9.6) JLED1.4
BATT_YELLOW#: length 188.7
  TOP w0.254: RZ28.2 244.54,109.53 QZ3.3 247.36,109.53 247.7,109.87 v2(247.7,112) 247.7,114.24 250.09,116.63 260.73,116.63 262.13,115.23 262.51,115.23 263.05,115.76 268.16,115.76 269.36,114.56 v1(269.36,114.22)
  IN3 w0.254: v1(307.65,12.18) 307.65,15.25 306.83,16.08 302.32,16.08 301.56,16.84 301.56,19.63 300.63,20.56 300.63,24.27 300.13,24.77 300.13,26.2 288.45,37.88 288.15,37.88 287.87,38.16 287.87,38.56 288.48,39.17 288.48,43.89 284.72,47.65 284.72,48.32 282.78,50.26 280.02,50.26 278.86,51.41 278.86,52.36 277.58,53.64 277.58,54.51 274.58,57.51 274.58,61.38 274.86,61.66 274.86,62.69 277.99,65.82 277.99,68.71 280.29,71.01 286.55,71.01 v1(287.65,72.12)
  BOTTOM w0.254: JLED1.5 307.07,11.6 v1(307.65,12.18) ; v1(269.36,114.22) 269.36,114.18 269.37,114.18 269.37,113.82 266.95,111.4 266.95,109.74 266.13,108.92 266.13,108.28 266.58,107.82 266.58,103.78 270,100.37 270,96.91 268.67,95.59 268.67,93.05 268.2,92.57 268.2,86.8 268.63,86.37 271.77,86.37 272.44,87.04 280.08,87.04 281.5,88.47 284.93,88.47 285.55,87.84 285.55,74.21 v1(287.65,72.12)
BC_CLK_ECE1117: length 170.8
  TOP w0.107: v1(187.79,38.8) 187.79,39.39 CZ87.1 ; UE1.D13 249.63,101.01 249.74,101.12 249.74,101.38 249.63,101.48 249.19,101.48 249.08,101.59 249.08,101.76 248.72,102.12 246.37,102.12 246.12,102.36 246.12,103.13 246.26,103.28 v1(246.33,103.28)
  IN1 w0.099: v1(246.33,103.28) 246.16,103.45 246.16,103.93 247.08,104.85 250.06,104.85 250.82,105.61 253.51,105.61 254.29,104.84 255.47,104.84 256.62,103.68 256.95,103.68 259.84,100.8 259.84,99.92 261.17,98.59 261.17,94.44 255.93,89.2 250.85,89.2 250.28,88.63 249.59,88.63 249.24,88.28 249.24,85.68 248.3,84.74 248.3,81.77 246.63,80.1 246.63,77.5 253.14,70.99 253.14,66.44 252.7,66 252.7,58.48 252.84,58.34 252.84,44.93 251.96,44.05 251.96,42.21 250.15,40.4 246.73,40.4 246.27,39.94 246.27,38.92 244.72,37.37 243.97,37.37 242.9,36.29 233.4,36.29 232.72,36.97 225.3,36.97 224.67,37.6 223.59,37.6 221.7,39.49 215.38,39.49 214.46,40.41 210.64,40.41 209.83,39.6 204.43,39.6 202,37.18 202,36.55 201.75,36.29 194.3,36.29 193.62,35.61 190.21,35.61 188.91,36.91 188.55,36.91 187.6,37.86 187.6,38.62 v1(187.79,38.8)
  BOTTOM w0.107: JKBTP1.10 187.99,39 v1(187.79,38.8)
BC_DAT_ECE1117: length 173.8
  TOP w0.102: v1(245.74,103.28) 244.91,104.11 244.91,104.53
  TOP w0.107: CZ86.1 187.2,39.69 v1(187.2,38.8) ; v1(245.74,103.28) 245.89,103.13 245.89,102.26 246.27,101.88 248.63,101.88 248.85,101.66 248.85,100.92 249.25,100.52 UE1.D12 ; RE365.1 244.91,104.53
  IN1 w0.099: v1(187.2,38.8) 187.37,38.63 187.37,37.77 188.46,36.68 188.81,36.68 190.11,35.38 193.71,35.38 194.4,36.07 201.84,36.07 202.23,36.45 202.23,37.08 204.52,39.37 209.92,39.37 210.73,40.18 214.37,40.18 215.28,39.26 221.61,39.26 223.5,37.38 224.58,37.38 225.21,36.75 232.62,36.75 233.3,36.07 242.99,36.07 244.07,37.15 244.82,37.15 246.5,38.83 246.5,39.84 246.83,40.17 250.25,40.17 252.19,42.11 252.19,43.96 253.07,44.83 253.07,58.43 252.92,58.58 252.92,65.9 253.37,66.35 253.37,71.08 246.86,77.59 246.86,80 248.53,81.67 248.53,84.65 249.47,85.59 249.47,88.19 249.68,88.4 250.38,88.4 250.95,88.97 256.03,88.97 261.4,94.34 261.4,98.68 260.06,100.02 260.06,100.89 257.04,103.91 256.72,103.91 255.56,105.06 254.38,105.06 253.6,105.84 250.73,105.84 249.96,105.07 246.98,105.07 245.93,104.02 245.93,103.46 v1(245.74,103.28)
  BOTTOM w0.107: v1(187.2,38.8) 186.99,39.02 JKBTP1.8
BC_INT#_ECE1117: length 160.5
  TOP w0.107: UE1.E2 249.65,91.81 249.65,91.35 249.42,91.13 249.42,90.5 249.61,90.31 v1(249.81,90.31) ; CZ85.1 186.49,39.34 186.53,39.3 v1(186.53,38.83) 186.35,38.83 185.3,37.78 184.56,37.78 184.46,37.68 v2(184.46,34.74) 184.46,33.6 185.28,32.78 192.76,32.78 196.1,36.13 196.1,37.13 197.98,39 207.94,39 209.56,37.37 213.72,37.37 215.38,39.03 221.1,39.03 221.79,38.35 221.79,36.23 224.61,33.41 228.44,33.41 v1(229.19,32.66)
  IN2 w0.089: 247.2,86.98 247.2,87.78 249.72,90.31 249.81,90.31 v1(249.81,90.31)
  IN2 w0.102: v1(229.19,32.66) 230.08,32.66 231.87,34.45 239.39,34.45 239.94,33.91 242.69,33.91 243.3,33.3 253.4,33.3 255.9,35.8 256.82,35.8 257.44,36.42 257.44,37.9 259.76,40.21 259.76,41.04 260.17,41.44 260.17,45.37 260.61,45.82 260.61,50.45 261.58,51.42 261.58,60.88 258.17,64.29 258.17,65.26 257.61,65.82 257.61,70.1 254.25,73.47 252.64,73.47 250.93,75.17 250.21,75.17 247.11,78.27 247.11,79.37 248.31,80.56 248.31,85.42 247.2,86.53 247.2,86.98
  BOTTOM w0.107: v1(186.53,38.83) 186.49,38.88 JKBTP1.7
BCM5882_ALERT#: length 121.8
  TOP w0.107: RE532.1 264.93,99.73 264.51,100.15 v1(263.84,100.15) ; UE1.G10 251.65,98.65 251.25,99.05 v1(251.24,99.05) ; v2(232.43,34.07) 232.14,33.78 v1(232.14,33.13)
  IN1 w0.099: v1(232.14,33.13) 232.35,32.92 239.27,32.92 240.32,31.87 245.39,31.87 246.96,33.44 250.78,33.44 253.27,35.93 253.27,36.16 255.14,38.02 256.56,38.02 257.12,38.59 257.12,42.1 258.5,43.48 258.5,53.68 258.94,54.12 258.94,58.03 258.34,58.63 258.34,62.99 257.52,63.82 257.52,74.01 258.41,74.9 258.41,77.45 260.66,79.7 260.66,81.62 262.95,83.91 262.95,85.1 263.85,86 263.85,87.08 264.6,87.82 264.6,90.89 265.92,92.22 265.92,93.24 265.61,93.55 265.17,93.55 264.18,94.55 264.18,98.86 263.84,99.2 v1(263.84,100.15)
  IN3 w0.089: v1(251.24,99.05) 251.28,99.05 251.77,98.56 252.27,98.56 252.73,99.01 252.73,99.71 252.89,99.87
  IN3 w0.102: v1(263.84,100.15) 262.19,100.15 261.43,99.39 261,99.39 260.25,98.64 259.31,98.64 258.99,98.96 257.43,98.96 255.86,100.53 254.61,100.53 254.29,100.21 253.23,100.21 252.89,99.87
  BOTTOM w0.107: v1(232.14,33.13) 232.14,36.27 230.78,37.63 JUSH1.14
BEEP: length 119
  TOP w0.107: v2(291.6,43.89) 291.09,44.4 v1(290.76,44.4) RA13.2 ; v1(253.13,101.59) 252.99,101.59 252.88,101.48 252.88,99.85 UE1.H11
  IN3 w0.102: v1(288.16,79.51) 287.63,79.51 286.76,80.38 286.76,83.38 288.87,85.49 288.87,93.53 288.31,94.09 276.22,94.09 270.54,99.77 270.54,103.67 270.16,104.05 269.18,104.05 266.51,101.38 260.07,101.38 259.86,101.59 256.16,101.59 255.43,102.31 253.52,102.31 253.19,101.98 253.19,101.81 253.13,101.75 v1(253.13,101.59) ; v1(289.11,72.2) 289.11,71.64 287.01,69.54 285.61,69.54 285.18,69.97 280.72,69.97 279.03,68.28 279.03,65.39 275.9,62.26 275.9,60.81 275.62,60.53 275.62,58.56 276.45,57.73 277.55,57.73 277.87,57.41 277.87,56.31 278.8,55.38 279.15,55.38 280.17,54.37 281.17,54.37 283.01,52.52 283.01,51.49 284.4,50.11 286.95,50.11 290.76,46.3 v1(290.76,44.4)
  BOTTOM w0.107: v1(288.16,79.51) 288.16,73.16 v1(289.11,72.2)
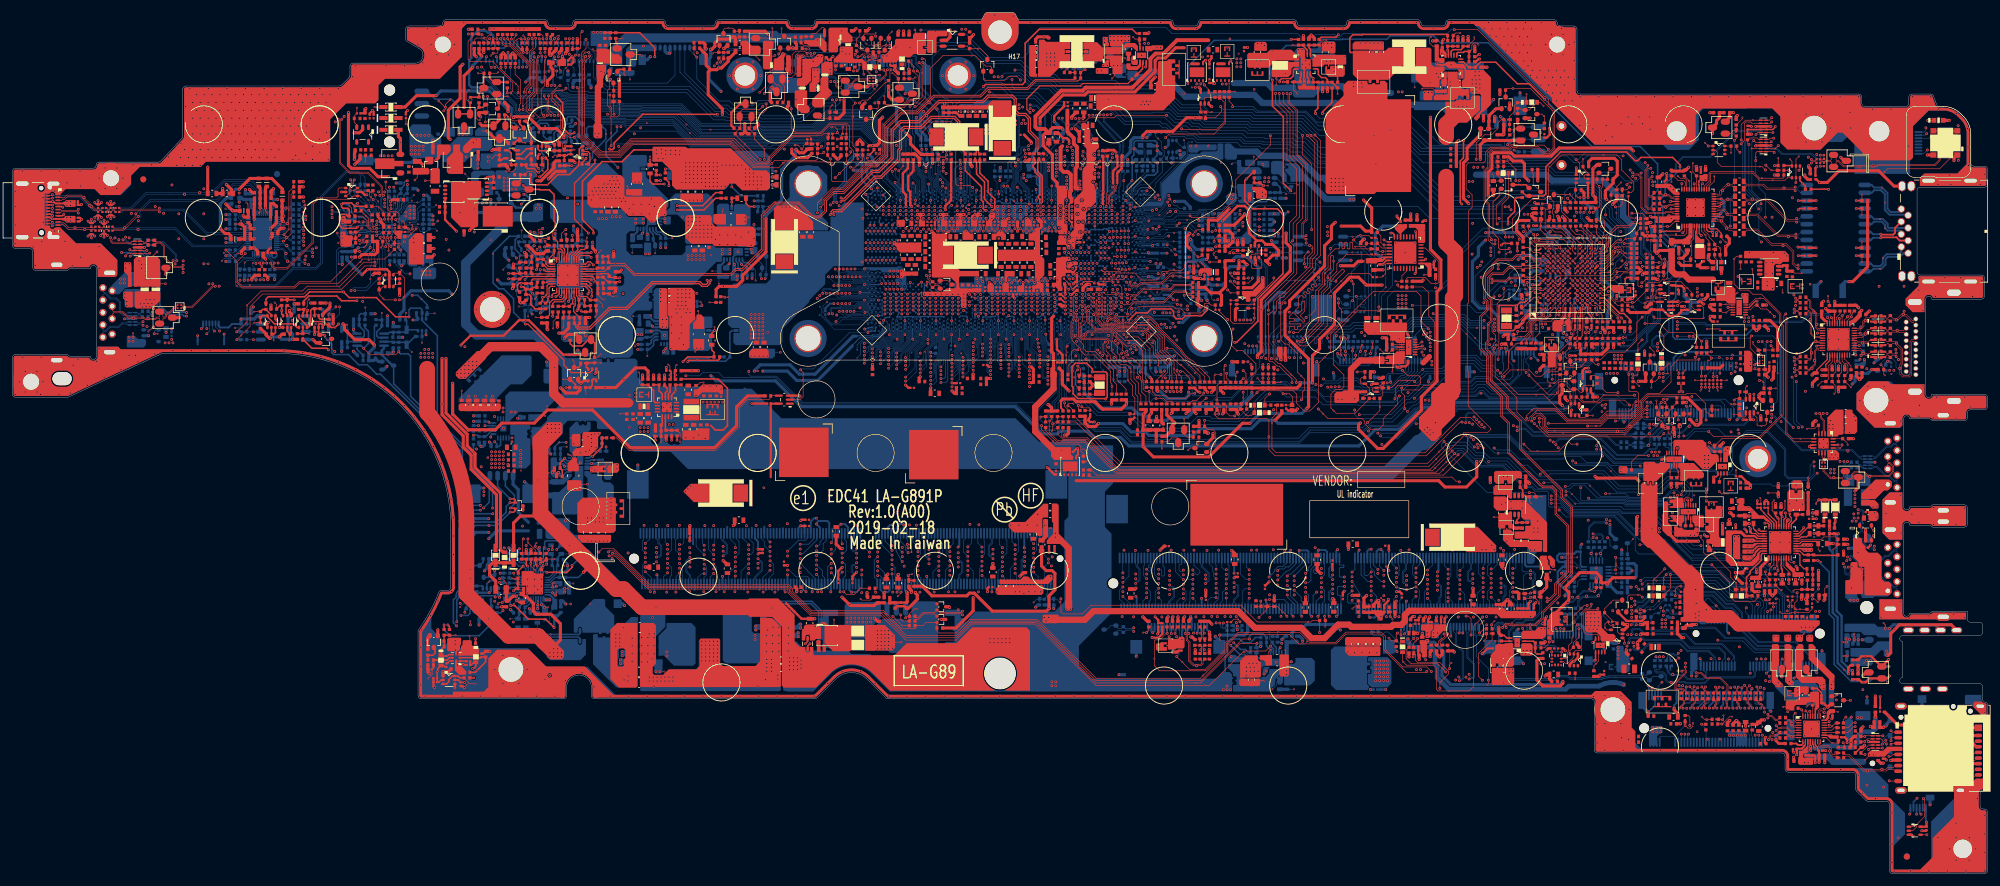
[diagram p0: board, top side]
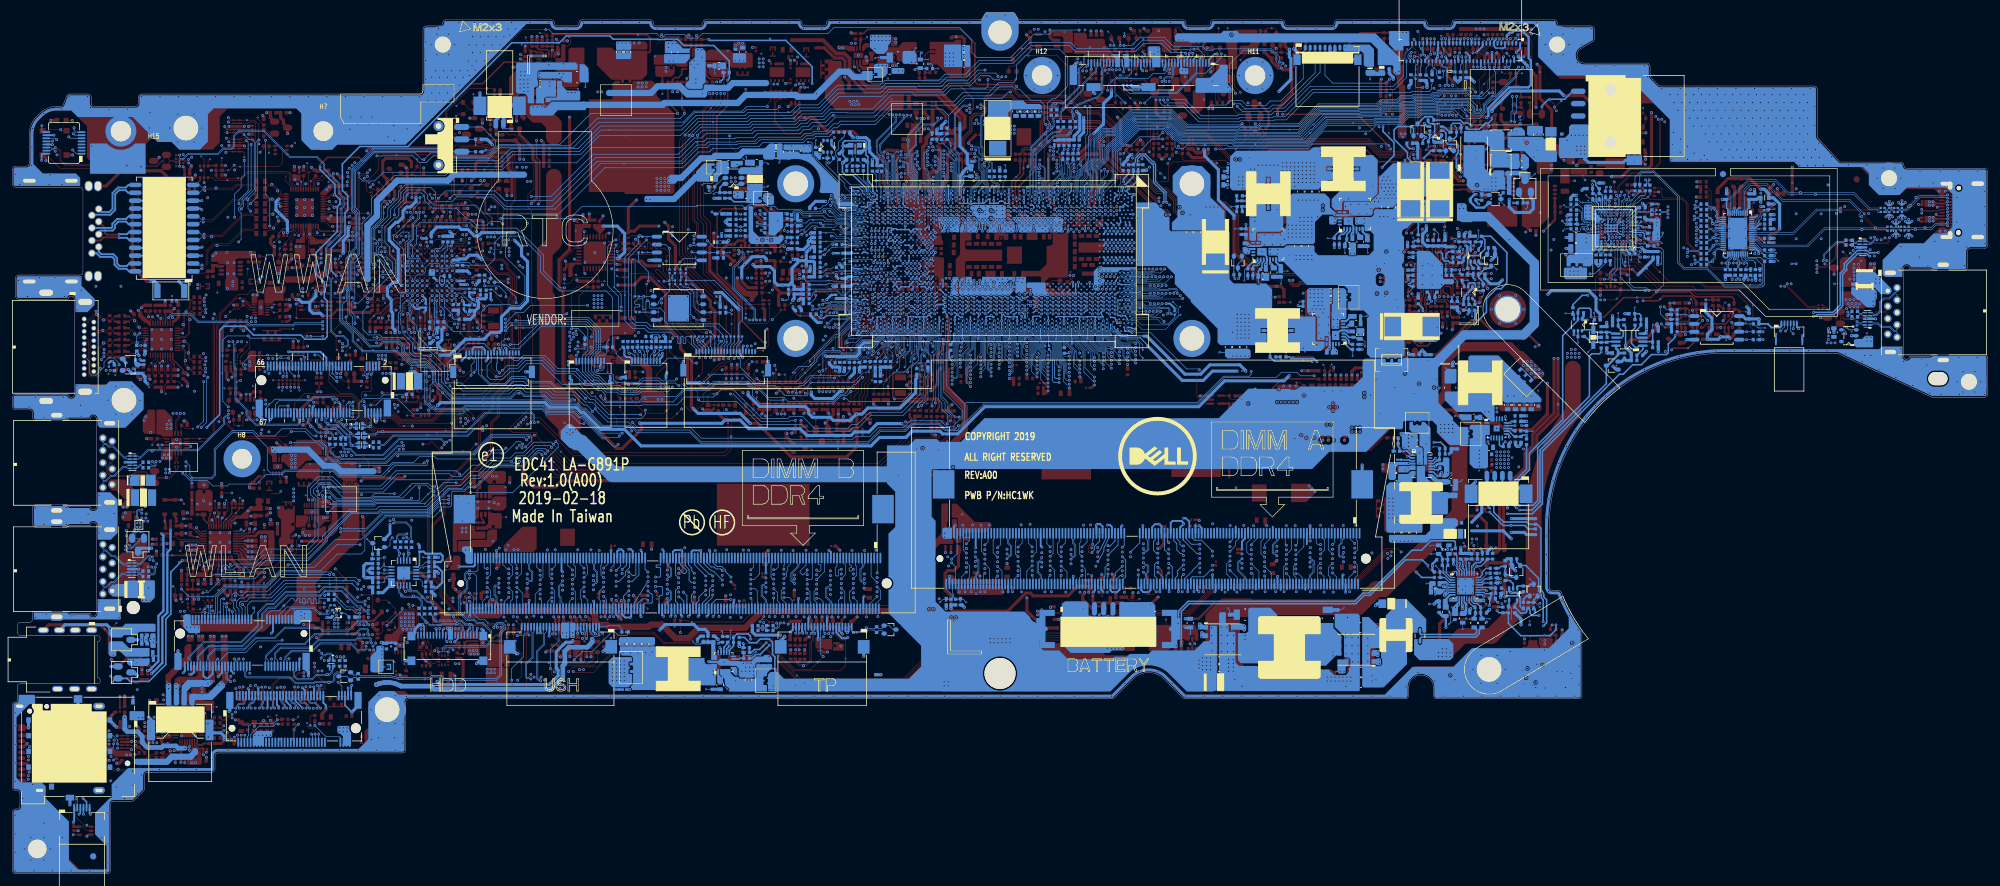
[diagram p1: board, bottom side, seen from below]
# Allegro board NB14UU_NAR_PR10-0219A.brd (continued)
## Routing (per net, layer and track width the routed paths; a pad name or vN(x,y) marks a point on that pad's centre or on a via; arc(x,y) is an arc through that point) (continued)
BEEP_R: length 4.7
  TOP w0.107: v2(287.68,45.71) 287.9,45.93 RA45.1
  TOP w0.203: CA62.1 RA13.1 ; CA62.1 CA28.1 ; CA62.1 RA45.1
BGATE_CHG: length 54.8
  TOP w0.254: v1(90.4,49.8) 90.4,49.5 89.59,48.69 v2(87.74,48.69) v1(86.31,48.69)
  BOTTOM w0.203: v1(86.31,48.69) 86.17,48.84 85.88,48.84 85.74,48.69 PU700.32
  BOTTOM w0.254: v1(90.4,49.8) 91.32,50.72 94.01,50.72 99.75,44.97 100.71,44.97 102.04,43.63 128.96,43.63 130.23,42.36 v1(130.23,36.84)
BGPO0: length 1.1
  TOP w0.107: UE1.D6 249.21,95.41 v1(248.82,95.8)
  BOTTOM w0.089: T341.1 v1(248.82,95.8)
BIA_PWM: length 4.7
  TOP w0.107: RV1.1 136.89,135.44 v2(136.36,134.91) 136.33,134.88 LV1.2 137.07,133.11 DV1.1
BIA_PWM_EC: length 159.2
  TOP w0.107: v1(257.09,91.06) 256.79,91.06 256.45,91.4 UE1.N1 ; v1(141.14,133.87) 140.68,133.87 140.11,133.3 139.5,133.3 138.76,134.04 DV1.2
  IN2 w0.102: v1(141.14,133.87) 141.54,134.27 142.29,134.27 142.38,134.18 155.26,134.18 157.62,131.82 162.29,131.82 166.33,135.87 182.26,135.87 182.84,135.28 183.86,135.28 184.44,135.87 185.92,135.87 186.95,134.84 192.99,134.84 195.5,132.34 195.5,129.48 204.47,120.51 231.72,120.51 232.3,119.92 241.81,119.92 250.12,111.61 250.12,110.34 250.74,109.71 250.74,108.87 252.04,107.58 255.65,107.58 256.01,107.22 256.01,106.51 254.33,104.83 254.33,102.44 255.02,101.75 255.02,99.84 254.61,99.43 254.32,99.43 254.05,99.16 254.05,98.84 254.06,98.83 254.06,98.38 254.07,98.38 254.07,98.06 254.06,98.05 254.06,97.04 254.26,96.84 255.98,96.84 257.59,95.23 257.59,94.77 257.36,94.54 257.36,93.4 257.59,93.17 257.59,91.56 v1(257.09,91.06)
  BOTTOM w0.107: v2(141.51,134.71) 141.14,134.33 v1(141.14,133.87)
BL_PWR_MONITOR: length 2.2
  TOP w0.127: v2(98.93,129.03) 98.79,129.17 RV625.2
  TOP w0.254: QV19.2 98.06,129.99 RV625.2
BL_PWR_SRC_ON: length 8.2
  TOP w0.107: QV1.3 131.19,136.6 131.06,136.73 130.74,136.73 129.79,135.77 129.28,135.77 129.09,135.58 CV13.1 RV4.1 127.47,135.28 RV5.1 CV14.1 127.83,133.87 128.3,133.87 128.74,133.43 v2(128.74,133.23)
BOARD_ID: length 5.9
  TOP w0.107: UE1.J13 253.54,101.31 253.54,101.79 253.28,102.04 253.04,102.04 v2(252.2,102.89) 250.76,104.33 CE40.1 RE79.2
BOOT1_CHG:
  vias: v2(84.22,43.22)
BOOT2_CHG:
  vias: v2(87.54,46.95)
BREATH_LED#: length 54.6
  TOP w0.107: 273.93,117.6 v2(273.41,118.12) ; 273.93,117.6 QZ7.1 ; 273.93,117.6 v1(273.92,117.6)
  TOP w0.127: v1(248.04,99.9) 248.04,99.82 UE1.C11
  IN2 w0.089: v1(248.04,99.9) 247.14,100.8 247.14,100.82
  IN2 w0.102: 247.14,100.82 247.14,103.96 245.23,105.86 244.31,105.86 243.8,106.38 243.8,109.4 243.43,109.76 v1(243.43,112.01)
  IN3 w0.102: v1(243.43,112.01) 247.42,116 257.28,116 260.55,112.73 260.8,112.73 261.56,111.97 263.37,111.97 263.47,111.87 264.54,110.8 265.41,110.8 268.6,113.99 268.6,115.26 270.94,117.6 v1(273.92,117.6)
BREATH_WHITE_LED_SNIFF#: length 38.1
  TOP w0.107: v1(279.04,116.58) 278.52,117.1 RZ32.2 ; LED3.1 v1(309.37,121.75)
  IN1 w0.099: v1(309.37,121.75) 308.38,120.76 308.38,118.34 305.05,115.01 294.32,115.01 292.48,116.85 286.51,116.85 285.71,116.05 279.57,116.05 v1(279.04,116.58)
BS_DDR: length 1.8
  BOTTOM w0.107: v2(86.62,64.77) 86.62,64.36 87.37,63.61 PR203.1
BS_DDR_R: length 1.2
  BOTTOM w0.107: v2(84.87,63.62) 85.17,63.32 PR203.2
BST1_CHG_R: length 1
  BOTTOM w0.107: PR704.1 v2(84.78,39.52)
BST1_IA:
  vias: v1(115.78,98.55)
BST1_IA_R: length 2.3
  BOTTOM w0.107: v2(114.11,95.36) PC655.1
  BOTTOM w0.635: PC655.1 PR660.1
BST2_CHG_R: length 0.6
  BOTTOM w0.107: 89.99,46.9 v2(90.62,46.9)
BST2_IA:
  vias: v1(101.79,103.5)
BST2_IA_R: length 2.3
  BOTTOM w0.107: v2(100.13,100.35) PC671.1
  BOTTOM w0.635: PC671.1 PR672.1
BST_1.05VALWP_R: length 3.7
  TOP w0.107: v2(227.72,126.86) 229.48,126.86 229.9,126.44 PC304.1
  TOP w0.508: PC304.1 PR304.2
BST_3V: length 2
  BOTTOM w0.107: PR100.1 204.5,31.19 204.17,30.86 204.17,30.44 v2(203.53,29.79)
BST_3V_R: length 2.3
  BOTTOM w0.107: v2(207.02,29.79) PC102.1
  BOTTOM w0.508: PC102.1 PR100.2
BST_5V:
  vias: v1(81.59,73.59)
BST_5V_R: length 1
  BOTTOM w0.107: PC114.1 v2(86.04,73.98)
BST_GT:
  vias: v1(103.36,88.48)
BST_GT_R: length 2.2
  BOTTOM w0.107: v2(100.27,90.11) PC663.1
  BOTTOM w0.508: PC663.1 PR665.1
BST_SA_R: length 1
  TOP w0.508: PR619.1 PC611.1
BT_RADIO_DIS#: length 77.8
  TOP w0.107: DZ2.1 265.03,44.14 v1(264.86,43.97) ; UE1.C2 247.97,91.74 247.97,91.28 247.52,90.82 247.52,90.11 247.41,90.01 246.54,90.01 246.36,89.82 246.05,89.82 245.19,88.96 245.19,87.38 243.77,85.96 RE11.1 243.09,85.75 241.68,84.34 241.68,81.68 240.5,80.51 240.5,80.17 243.26,77.42 v2(246.13,77.42) 247.34,77.42 251.29,73.46 256.3,73.46 257.6,74.76 261.18,74.76 261.74,75.32 261.74,75.76 v1(262.25,76.27)
  IN2 w0.102: v1(262.25,76.27) 262.68,75.85 262.68,71.68 262.53,71.53 262.53,65.3 265.26,62.57 265.26,59.33 264.89,58.96 264.89,49.97 265.58,49.28 265.58,45.13 264.86,44.4 v1(264.86,43.97)
BT_RADIO_DIS#_R: length 27.2
  TOP w0.107: v1(267.8,48.35) v2(267.8,46.75) 267.8,46.07 266.73,45 DZ2.2
  BOTTOM w0.107: v1(267.8,48.35) 267.81,48.34 275.83,48.34 277.98,46.19 284.46,46.19 285.95,44.7 JNGFF1.54
CAM_MIC_CBL_DET#: length 132.6
  TOP w0.107: v1(188.12,81.33) 188.12,81 v2(188.47,80.65) 188.82,80.3 RC725.1
  IN2 w0.102: v1(188.12,81.33) 188.12,81.63 185.05,84.7 185.05,95.69 183.83,96.91 182.93,96.91 182.37,97.47 182.37,101.82 182.55,102 182.55,113.04 185.19,115.68 185.19,115.91 185.8,116.52 185.8,117.85 187.74,119.79 187.74,120.49 188.77,121.52 188.77,124.88 187.49,126.16 161.95,126.16 161.31,125.52 159.73,125.52 159.4,125.19 154.93,125.19 154.75,125.02 147.99,125.02 147.36,125.65 140.41,125.65 v1(139.31,124.56)
  BOTTOM w0.076: 185.71,84.3 185.5,84.3 185.17,83.97 182.91,83.97 182.63,84.26 182.63,85.3 181.74,86.19 179.76,86.19 178.96,87 178.96,87.44 179.01,87.5 179.05,87.59 179.05,87.7 179.06,87.78 179.06,87.79 179.05,87.82 179.05,87.82 179.03,87.85 179.03,87.86 178.79,88.28 UC1.CH36
  BOTTOM w0.107: JEDP1.14 132.28,130.42 132.55,130.15 132.55,129.74 132.99,129.3 134.81,129.3 135.61,128.5 140.67,128.5 140.97,128.2 140.97,126.21 v1(139.31,124.56) ; 185.71,84.3 187.74,84.3 188.14,83.9 188.14,81.34 v1(188.12,81.33)
CBN: length 4.5
  TOP w0.203: UA1.28 284.53,56.65 282.97,58.21 v2(282.97,58.28) 282.42,58.84 CA76.2 CA29.2
CBP: length 7.4
  TOP w0.107: v2(282.32,60.72) 282.42,60.61 CA76.1
  TOP w0.203: v1(283.07,56.65) 283.08,56.65 283.08,56.65 283.53,56.65 283.73,56.45 UA1.30
  TOP w0.254: CA76.1 CA29.1 v1(281.85,60.27)
  IN1 w0.254: v1(281.85,60.27) 282.06,60.06 282.06,57.67 283.08,56.65 283.08,56.65 283.08,56.65 v1(283.07,56.65)
CFG0: length 92.7
  TOP w0.107: v1(82.67,126.3) 82.67,126.81 83.48,127.61 83.48,130.55 81.66,132.37 81.66,132.45 80.36,133.75 v2(79.8,133.75) 79.54,133.75 79.03,134.26 RC126.1 78.42,134.41 78.25,134.58 v1(78.25,134.94) 78.25,135.47 RC120.2
  BOTTOM w0.076: UC1.T4 147.1,108.92 147.37,109.19 147.37,109.49 147.18,109.68 147.18,112.42 146.82,112.78
  BOTTOM w0.107: v1(78.25,134.94) 78.57,134.63 JXDP1.9 ; 146.82,112.78 146.57,113.03 146.57,113.63 144.84,115.36 144.84,118.53 142.95,120.42 141.43,120.42 138.35,123.5 131.7,123.5 129.22,121.02 120.81,121.02 120.59,120.8 118.03,120.8 117.63,121.2 111.34,121.2 108.12,124.41 98.73,124.41 98.03,125.11 95.44,125.11 94.79,125.76 92.97,125.76 92.83,125.9 90.01,125.9 89.67,126.24 88.95,126.24 88.37,126.83 83.2,126.83 v1(82.67,126.3)
CFG1: length 94.4
  TOP w0.107: RC405.2 79.18,135.28 v1(78.84,134.94) 78.84,134.84 79.56,134.12 80.32,134.12 81.89,132.55 81.89,132.47 83.71,130.65 83.71,127.46 83.08,126.84 83.08,126.01 82.47,125.4 v2(82.47,124.09) v1(82.47,123.48)
  BOTTOM w0.076: 143.48,117.5 143.48,115.55 145.4,113.63 145.4,112.48 146.11,111.77 146.11,110.19 146.14,110.1 146.14,109.88 146.11,109.78 146.11,109.53 146.26,109.19 146.26,108.88 146.54,108.6 UC1.R4
  BOTTOM w0.107: v1(78.84,134.94) 78.84,134.72 79.17,134.39 JXDP1.11 ; v1(82.47,123.48) 82.47,124.05 83.49,125.07 89.19,125.07 89.53,124.73 92.35,124.73 92.74,124.35 94.38,124.35 94.79,123.94 97.54,123.94 98.24,123.24 101.38,123.24 101.49,123.13 107.75,123.13 111.29,119.58 121.03,119.58 121.3,119.85 129.7,119.85 132.18,122.33 137.86,122.33 140.94,119.25 142.39,119.25 143.48,118.16 143.48,117.5
CFG2: length 89
  TOP w0.107: v1(83.5,126.31) 83.5,126.74 v2(83.76,127) 83.94,127.19 83.94,130.75 82.13,132.57 82.13,132.7 80.01,134.82 v1(80.01,134.95) 79.94,135.01 RC406.2
  BOTTOM w0.076: 144.48,117.5 144.48,115.47 146.36,113.58 146.36,112.99 146.99,112.36 146.99,109.45 UC1.T3
  BOTTOM w0.107: v1(80.01,134.95) 80.01,134.88 80.37,134.52 JXDP1.15 ; v1(83.5,126.31) 83.78,126.59 88.27,126.59 88.86,126.01 89.57,126.01 89.91,125.67 92.74,125.67 92.88,125.53 94.69,125.53 95.34,124.88 97.93,124.88 98.63,124.18 108.02,124.18 111.24,120.96 117.54,120.96 117.94,120.56 120.69,120.56 120.91,120.78 129.31,120.78 131.8,123.27 138.25,123.27 141.33,120.19 142.85,120.19 144.48,118.56 144.48,117.5
CFG3: length 104.1
  TOP w0.107: v1(80.51,126.18) 80.83,126.5 80.83,127.81 78.35,130.29 78.35,130.5 77.6,131.25 v2(75.69,131.25) 74.01,131.25 73.6,131.66 73.6,134.52 74.28,135.19 RC121.2 v1(73.66,135.71) ; RC407.2 80.61,135.54 80.61,134.88 v1(80.6,134.88)
  IN1 w0.099: v1(73.66,135.71) 73.93,135.99 79.75,135.99 80.6,135.14 v1(80.6,134.88)
  BOTTOM w0.076: 143.71,117.5 143.71,115.55 145.63,113.63 145.63,112.57 146.27,111.94 146.27,110.22 146.31,110.13 146.31,109.85 146.27,109.76 146.27,109.57 146.49,109.06 UC1.R3
  BOTTOM w0.107: v1(80.51,126.18) 81.39,125.31 89.28,125.31 89.62,124.97 92.45,124.97 92.83,124.58 94.48,124.58 94.89,124.18 97.64,124.18 98.34,123.48 101.48,123.48 101.59,123.36 107.85,123.36 111.39,119.82 120.93,119.82 121.2,120.08 129.6,120.08 132.09,122.57 137.96,122.57 141.04,119.49 142.49,119.49 143.71,118.26 143.71,117.5 ; JXDP1.17 80.97,134.51 v1(80.6,134.88)
CFG4: length 88.1
  TOP w0.107: v1(84.11,122.44) 84.08,122.42 83.89,122.42 83.1,123.2 83.1,125.34 84.18,126.41 84.18,130.88 83.55,131.51 83.55,132.91 84.09,133.45 v2(84.09,134.22) 84.09,134.8 v1(83.94,134.95) 83.94,135.07 83.5,135.52 RC723.2
  BOTTOM w0.076: UC1.J4 142.78,108.6 143.06,108.88 143.06,109.19 143.21,109.53 143.21,109.78 143.17,109.88 143.17,110.1 143.21,110.2 143.21,110.58 141.42,112.37 141.42,115.19 141.41,115.2
  BOTTOM w0.107: JXDP1.27 83.97,134.93 v1(83.94,134.95) ; 141.41,115.2 141.41,116.8 137.28,120.93 132.77,120.93 130.28,118.45 121.88,118.45 121.61,118.17 110.1,118.17 106.65,121.63 99.07,121.63 98.86,121.84 94.91,121.84 93.8,122.94 92.15,122.94 91.77,123.33 88.94,123.33 88.6,123.67 85.15,123.67 84.18,122.71 84.18,122.52 v1(84.11,122.44)
CFG5: length 88.2
  TOP w0.107: RC409.2 84.26,135.27 v1(84.53,135.01) 84.53,133.51 83.79,132.77 83.79,131.78 v2(84.13,131.43) 84.41,131.15 84.41,126.32 83.52,125.43 v1(83.52,123.46)
  BOTTOM w0.076: UC1.M4 144.66,108.92 144.92,109.19 144.92,109.49 144.76,109.66 144.76,110.84 144.16,111.45 144.16,113.72 142.38,115.49 142.38,116.83 141.7,117.5
  BOTTOM w0.107: v1(83.52,123.46) 83.52,123.86 84.04,124.37 88.89,124.37 89.23,124.03 92.06,124.03 92.45,123.65 94.09,123.65 94.54,123.2 97.29,123.2 97.95,122.54 101.09,122.54 101.2,122.43 107.03,122.43 109.17,120.29 109.32,120.29 110.73,118.88 121.32,118.88 121.59,119.15 129.99,119.15 132.47,121.63 137.57,121.63 141.7,117.5 ; v1(84.53,135.01) 84.53,134.91 84.57,134.87 JXDP1.29
CFG6: length 105.2
  TOP w0.107: RC410.2 85.48,135.63 85.69,135.43 85.69,134.94 v1(85.7,134.93)
  IN3 w0.102: v1(85.7,134.93) 85.69,134.92 85.69,134.87 85.11,134.29 82.09,134.29 81.23,135.15 81.23,135.15 80.75,135.63 76.73,135.63 76.1,136.26 75.65,136.26 73.74,134.35 73.74,131.52 74.95,130.31 v1(75.09,130.31)
  BOTTOM w0.076: 140.38,117.5 141.16,116.73 141.16,112.4 143.05,110.51 143.05,110.22 143.01,110.13 143.01,109.85 143.05,109.76 143.05,109.57 142.83,109.06 UC1.J3
  BOTTOM w0.107: 140.38,117.5 137.18,120.7 132.86,120.7 130.38,118.21 121.98,118.21 121.7,117.94 110.01,117.94 106.66,121.28 v2(102.47,121.28) 99.09,121.28 98.76,121.61 94.81,121.61 93.71,122.71 92.06,122.71 91.67,123.1 88.85,123.1 88.51,123.44 86.11,123.44 84.68,122.01 82.1,122.01 81.01,123.1 81.01,124.14 80.01,125.14 79.74,125.14 76.03,128.85 76.03,129.38 v1(75.09,130.31) ; v1(85.7,134.93) 85.77,134.86 JXDP1.33
CFG7: length 106.3
  TOP w0.107: RC411.2 86.34,135.03 86.3,134.98 v1(86.3,134.93)
  IN3 w0.102: v1(75.78,130.38) 75.21,130.95 74.93,130.95 73.97,131.9 73.97,134.25 75.75,136.03 76.01,136.03 76.64,135.4 80.66,135.4 82,134.06 85.2,134.06 85.48,134.34 86.08,134.34 86.27,134.53 86.27,134.91 v1(86.3,134.93)
  BOTTOM w0.076: UC1.M3 144.56,109.44 144.56,110.81 143.92,111.45 143.92,113.72 142.22,115.43 142.22,116.66 141.37,117.5
  BOTTOM w0.107: 141.37,117.5 137.48,121.4 132.57,121.4 130.09,118.91 121.69,118.91 121.41,118.64 110.48,118.64 v2(109.46,119.67) 106.93,122.19 101.01,122.19 100.9,122.31 95.1,122.31 94,123.41 92.35,123.41 91.96,123.8 89.14,123.8 88.8,124.14 84.15,124.14 83.93,123.92 83.93,123.15 83.82,123.05 83.6,123.05 83.16,122.61 81.84,122.61 81.24,123.2 81.24,124.24 79.94,125.54 79.66,125.54 76.26,128.95 76.26,129.9 v1(75.78,130.38) ; v1(86.3,134.93) 86.37,134.86 JXDP1.35
CFG8: length 85.3
  TOP w0.107: RC412.2 v1(78.93,130.31) 78.93,130.05 v2(81.33,127.65) 81.69,127.28 v1(81.69,126.22)
  BOTTOM w0.076: UC1.R2 146.54,109.9 146.8,110.16 146.8,112.32 146.2,112.92 146.2,113.52 144.24,115.47 144.24,117.5
  BOTTOM w0.107: v1(81.69,126.22) 82.14,125.78 83.54,125.78 84.12,126.36 88.18,126.36 88.76,125.78 89.48,125.78 89.82,125.44 92.64,125.44 92.78,125.3 94.59,125.3 95.25,124.64 97.84,124.64 98.54,123.94 101.67,123.94 101.78,123.83 108.04,123.83 111.14,120.73 117.44,120.73 117.84,120.33 120.78,120.33 121.01,120.55 129.41,120.55 131.89,123.03 138.16,123.03 141.24,119.95 142.75,119.95 144.24,118.47 144.24,117.5 ; JXDP1.10 78.87,130.37 v1(78.93,130.31)
CFG9: length 86.1
  TOP w0.107: RC413.2 v1(79.69,130.31)
  BOTTOM w0.076: UC1.N2 145.22,109.9 144.96,110.16 144.96,110.87 144.39,111.44 144.39,113.73 142.55,115.56 142.55,116.98 142.03,117.5
  BOTTOM w0.107: 142.03,117.5 137.67,121.87 132.38,121.87 129.9,119.38 121.49,119.38 121.23,119.12 110.96,119.12 109,121.08 v2(108.87,121.08) 107.29,122.66 101.3,122.66 101.18,122.78 98.05,122.78 97.39,123.43 94.64,123.43 94.19,123.88 92.54,123.88 92.15,124.27 89.33,124.27 88.99,124.61 83.94,124.61 83.11,123.78 83.11,122.98 82.97,122.84 81.93,122.84 81.48,123.3 81.48,124.33 80.03,125.78 79.76,125.78 79.52,126.02 79.52,129.57 79.69,129.74 v1(79.69,130.31) 79.47,130.53 JXDP1.12
CFG10: length 84.1
  TOP w0.107: RC414.2 v1(80.45,130.31)
  BOTTOM w0.076: UC1.R1 146.54,112.09 145.93,112.7 145.93,113.56 144.01,115.48 144.01,117.5
  BOTTOM w0.107: 144.01,117.5 144.01,118.37 142.66,119.72 141.14,119.72 138.06,122.8 131.99,122.8 129.51,120.32 121.1,120.32 120.88,120.1 117.74,120.1 117.6,120.24 v2(112.76,120.24) 111.3,120.24 107.94,123.6 101.69,123.6 101.57,123.71 98.44,123.71 97.74,124.41 94.98,124.41 94.58,124.81 92.93,124.81 92.54,125.2 89.72,125.2 89.38,125.54 88.66,125.54 88.08,126.13 84.22,126.13 83.64,125.54 81.79,125.54 80.45,126.88 v1(80.45,130.31) 80.67,130.53 JXDP1.16
CFG11: length 84.6
  TOP w0.107: RC415.2 v1(81.21,130.31) 81.21,129.2 82.1,128.31 v2(82.1,125.6) 82.1,124.46 81.89,124.24 v1(81.89,123.47)
  BOTTOM w0.076: 142.36,117.5 142.71,117.15 142.71,115.63 144.62,113.72 144.62,111.49 145.22,110.89 UC1.N1
  BOTTOM w0.107: JXDP1.18 81.27,130.37 v1(81.21,130.31) ; 142.36,117.5 137.77,122.1 132.28,122.1 129.8,119.62 121.39,119.62 121.13,119.35 111.19,119.35 107.65,122.9 101.4,122.9 101.28,123.01 98.15,123.01 97.45,123.71 94.69,123.71 94.29,124.11 92.64,124.11 92.25,124.5 89.43,124.5 89.09,124.84 83.84,124.84 82.88,123.88 82.88,123.18 82.77,123.07 82.03,123.07 81.89,123.22 v1(81.89,123.47)
CFG12: length 82.9
  TOP w0.107: v1(86.4,122.57) 85.98,122.15 85.11,122.15 83.93,123.33 83.93,125.33 v2(84.33,125.73) 84.65,126.05 84.65,131.65 v1(84.27,132.03)
  BOTTOM w0.076: 140.59,114.12 140.59,112.1 142.78,109.91 UC1.J2
  BOTTOM w0.107: v1(86.4,122.57) 86.8,122.97 88.31,122.97 88.65,122.63 91.48,122.63 91.86,122.24 93.51,122.24 94.62,121.14 98.57,121.14 99.71,120 107.28,120 109.81,117.47 122.54,117.47 122.82,117.75 129.34,117.75 129.93,117.16 130.93,117.16 131.26,117.49 131.26,118.43 133.06,120.23 136.99,120.23 140.59,116.63 140.59,114.12 ; RC416.2 84.27,129.57 JXDP1.28 v1(84.27,132.03)
CFG13: length 82.6
  TOP w0.107: v1(84.37,123.47) 84.88,123.98 v2(84.88,124.33) 84.88,131.96 v1(84.96,132.04)
  BOTTOM w0.076: UC1.L2 144.1,109.9 144.36,110.16 144.36,110.77 143.72,111.41 143.72,113.69 142.06,115.36 142.06,116.49 141.04,117.5
  BOTTOM w0.107: v1(84.96,132.04) 84.87,131.95 JXDP1.30 84.87,130.98 85.15,130.69 RC417.2 ; 141.04,117.5 137.38,121.16 132.67,121.16 130.19,118.68 121.78,118.68 121.51,118.41 110.2,118.41 106.73,121.87 99.16,121.87 98.96,122.07 95,122.07 93.9,123.18 92.25,123.18 91.86,123.57 89.04,123.57 88.7,123.91 84.81,123.91 v1(84.37,123.47)
CFG14: length 79.9
  TOP w0.107: v1(86.11,132.03) 86.11,131.65 85.97,131.51 v2(85.97,128.92) 85.97,127.33 85.42,126.77 85.42,122.96 v1(85.81,122.56)
  BOTTOM w0.076: UC1.J1 142.78,110.55 140.84,112.49 140.84,114.62 140.84,114.63
  BOTTOM w0.107: 140.84,114.63 140.84,116.71 137.09,120.46 132.96,120.46 130.48,117.98 122.07,117.98 121.8,117.71 109.91,117.71 106.67,120.94 99.1,120.94 98.67,121.37 94.71,121.37 93.61,122.48 91.96,122.48 91.57,122.87 88.75,122.87 88.41,123.21 86.46,123.21 v1(85.81,122.56) ; RC418.2 86.04,130.95 86.07,130.98 JXDP1.34 86.07,131.61 86.11,131.65 v1(86.11,132.03)
CFG15: length 72.2
  TOP w0.107: RC419.2 v2(143.86,114.35) 143.86,114.3 v1(143.17,113.61)
  IN3 w0.102: v1(86.67,129.7) 87.16,129.21 88.81,129.21 89.12,128.89 94,128.89 95.84,127.05 96.79,127.05 97.9,125.94 112.77,125.94 116.64,122.07 137.52,122.07 142.42,117.17 142.42,114.65 143.17,113.89 v1(143.17,113.61)
  BOTTOM w0.076: v1(143.17,113.61) 143.31,113.48 143.31,111.58 144.1,110.8 UC1.L1
  BOTTOM w0.107: v1(86.67,129.7) 86.67,129.75 86.67,129.76 JXDP1.36
CFG16: length 79.7
  IN3 w0.102: v1(142.63,113.85) 142.63,114.02 141.97,114.68 141.97,117.3 137.42,121.84 116.54,121.84 112.67,125.71 97.8,125.71 96.69,126.82 95.74,126.82 93.9,128.66 89.03,128.66 88.71,128.98 86.7,128.98 86.08,129.6 78.66,129.6 v1(77.95,130.31)
  BOTTOM w0.076: v1(142.63,113.85) 142.63,112.8 143.15,112.28 143.15,111.52 143.83,110.83 143.83,110.22 143.87,110.13 143.87,109.85 143.83,109.76 143.83,109.57 144.05,109.06 UC1.L3
  BOTTOM w0.107: v1(77.95,130.31) 77.67,130.59 JXDP1.6
CFG17: length 80.7
  IN3 w0.102: v1(142.15,113.51) 141.73,113.93 141.73,117.21 137.33,121.61 116.45,121.61 112.58,125.48 97.71,125.48 96.75,126.44 95.8,126.44 93.81,128.43 88.93,128.43 88.62,128.75 86.6,128.75 85.98,129.37 78.3,129.37 v1(77.36,130.31)
  BOTTOM w0.076: UC1.L4 144.1,108.6 143.82,108.88 143.82,109.19 143.67,109.53 143.67,109.78 143.7,109.88 143.7,110.1 143.67,110.2 143.67,110.76 143.67,110.77 142.98,111.45 142.98,112.15 142.15,112.99 v1(142.15,113.51)
  BOTTOM w0.107: v1(77.36,130.31) 77.07,130.61 JXDP1.4
CFG18: length 76
  IN3 w0.102: v1(83.05,130.37) 83.2,130.52 88.25,130.52 89.42,129.35 94.19,129.35 95.91,127.62 96.86,127.62 98.09,126.4 112.96,126.4 116.83,122.53 137.96,122.53 142.78,117.71 v1(142.78,117.71)
  BOTTOM w0.076: UC1.N3 145.27,109.06 145.49,109.57 145.49,109.76 145.45,109.85 145.45,110.13 145.49,110.22 145.49,110.85 144.86,111.48 144.86,112.93 v2(144.95,113.02) 144.95,113.62 142.93,115.64 142.93,117.5
  BOTTOM w0.107: v1(142.78,117.71) 142.93,117.55 142.93,117.5 ; JXDP1.24 83.07,130.39 v1(83.05,130.37)
CFG19: length 78
  IN3 w0.102: v1(82.42,130.37) 82.82,130.78 88.03,130.78 88.07,130.74 89.09,130.74 89.49,130.35 89.65,130.19 90.49,130.19 91.11,129.57 94.28,129.57 95.87,127.99 96.82,127.99 98.18,126.62 113.05,126.62 116.92,122.75 138.31,122.75 v1(142.73,118.33)
  BOTTOM w0.076: UC1.N4 145.22,108.6 145.5,108.88 145.5,109.19 145.65,109.53 145.65,109.78 145.62,109.88 145.62,110.1 145.65,110.2 145.65,110.54 145.65,110.92 145.12,111.45 145.12,112.75 145.24,112.86 145.24,113.56 143.22,115.59 143.22,117.5
  BOTTOM w0.107: 143.22,117.5 143.22,117.85 v1(142.73,118.33) ; v1(82.42,130.37) 82.47,130.42 JXDP1.22
CFG_RCOMP: length 9
  TOP w0.381: RC624.1 v2(151.63,110.06) 151.63,108.85 150.71,107.92 v1(150.71,107.29)
  BOTTOM w0.203: UC1.AB5 150.7,107.28 150.7,107.29 v1(150.71,107.29)
CLK_CNV_PRX_DTX_N: length 135
  IN3 w0.089: v1(188.4,90.83) 189.14,90.83 189.23,90.92 189.23,91.98 189.57,92.32 191.84,92.32 191.94,92.22 193.32,92.22 193.76,91.78 200.22,91.78 201.08,92.64 203.68,92.64 204.5,91.82 206.38,91.82 210.29,87.91 210.29,85.4 213.57,82.12 214.78,82.12 216.73,80.17 216.73,77.78 227.48,67.03 229.1,67.03 231.53,64.59 233.27,64.59 238.49,59.37 240.29,59.37 241.31,58.36 242.5,58.36 242.58,58.45 242.58,59.51 242.78,59.7 243.19,59.7 243.39,59.51 243.39,58.45 243.48,58.36 245.8,58.36 247.56,56.6 247.56,52.12 254.08,45.6 254.74,45.6 255.15,45.19 256.23,45.19 257.65,43.77 257.65,42.66 259.88,40.43 259.88,39.8 260.47,39.21 261.86,39.21 262.05,39.01 262.05,38.72 262.14,38.63 v1(262.31,38.63)
  BOTTOM w0.076: UC1.CN31 182.63,91.66 182.87,91.66 183.04,91.66 183.1,91.59 187.09,91.59 187.86,90.83 v1(188.4,90.83)
  BOTTOM w0.097: v1(262.31,38.63) 261.96,38.63 261.89,38.7 261.89,38.79 261.67,39.01 261.67,39.31 261.77,39.41 262.85,39.41 263.66,38.6 270.19,38.6 271.78,37.02 276.1,37.02 278.01,35.11 278.01,34.76 277.7,34.45 JNGFF1.21
CLK_CNV_PRX_DTX_P: length 135
  IN3 w0.089: v1(261.48,38.63) 261.76,38.63 261.87,38.73 261.87,38.94 261.78,39.03 260.4,39.03 259.7,39.73 259.7,40.35 257.47,42.58 257.47,43.69 256.15,45.01 255.08,45.01 254.67,45.42 254.01,45.42 247.38,52.05 247.38,56.52 245.73,58.18 243.4,58.18 243.21,58.37 243.21,59.43 243.12,59.52 242.85,59.52 242.76,59.43 242.76,58.37 242.57,58.18 241.23,58.18 240.22,59.19 238.42,59.19 233.2,64.41 231.46,64.41 229.02,66.85 227.41,66.85 216.55,77.7 216.55,80.09 214.7,81.94 213.49,81.94 210.11,85.32 210.11,87.83 206.31,91.64 204.43,91.64 203.61,92.46 201.16,92.46 200.3,91.6 193.68,91.6 193.25,92.04 191.86,92.04 191.76,92.14 189.65,92.14 189.41,91.91 189.41,90.84 189.22,90.65 188.78,90.65 188.6,90.46 188.6,90.44 v1(188.4,90.24)
  BOTTOM w0.076: UC1.CP31 182.78,91.46 183,91.46 183.03,91.43 183.32,91.43 183.4,91.35 183.4,91.27 183.48,91.2 183.63,91.2 183.7,91.27 183.7,91.35 183.78,91.43 186.32,91.43 186.39,91.35 186.39,91.27 186.46,91.21 186.65,91.21 186.72,91.29 186.72,91.35 186.8,91.43 187.02,91.43 187.79,90.66 188.06,90.66 188.4,90.32 v1(188.4,90.24)
  BOTTOM w0.097: JNGFF1.23 278.2,35.19 276.18,37.21 271.85,37.21 270.27,38.79 263.74,38.79 262.93,39.6 261.69,39.6 261.48,39.39 v1(261.48,38.63)
CLK_CNV_PTX_DRX_N: length 156
  IN3 w0.089: v1(262.08,43.46) 261.8,43.74 260.95,43.74 259.85,44.84 259.85,45.28 256.41,48.71 255.39,48.71 249.68,54.43 249.68,57.72 246.03,61.36 246.03,63.46 245.46,64.03 243.02,64.03 242.62,63.63 237.23,63.63 234.15,66.71 232.41,66.71 229.98,69.14 228.36,69.14 218.85,78.65 218.85,81.62 217.37,83.1 217.37,83.94 216.87,84.44 216.87,84.64 215.52,85.99 215.52,86.93 214.87,87.58 213.67,87.58 212.42,88.83 212.42,88.88 212.29,89.01 212.29,90.19 207.72,94.76 195.56,94.76 194.78,95.53 193.69,95.53 192.92,94.76 191.11,94.76 190.16,95.71 190.16,95.72 190.09,95.79 189.62,95.79 189.62,95.78 189.16,95.78 189.16,95.78 186.57,95.78 186.45,95.66 185.35,94.56 185.35,90.12 185.74,89.73 185.74,89.18 185.96,88.96 185.98,88.96 v1(186.15,88.79)
  BOTTOM w0.076: UC1.CP34 182.06,89.6 181.98,89.52 181.98,89.41 182.06,89.32 182.24,89.32 182.43,89.51 182.43,89.61 182.46,89.64 182.64,89.69 182.83,89.78 183.71,89.78 185.38,88.1 185.93,88.1 186.09,88.26 186.09,88.74 v1(186.15,88.79)
  BOTTOM w0.097: v1(262.08,43.46) 262.47,43.86 263.34,43.86 265.69,46.2 268.73,46.2 269.47,45.45 274.84,45.45 276.81,43.49 277.91,43.49 279.31,42.09 279.31,40.04 282.03,37.32 288.08,37.32 290.51,34.88 290.51,34.7 290.42,34.6 290.3,34.6 290.2,34.51 JNGFF1.71
CLK_CNV_PTX_DRX_P: length 156
  IN3 w0.089: v1(185.56,88.79) 185.56,89.65 185.17,90.04 185.17,94.64 185.22,94.69 185.22,94.69 186.43,95.9 186.44,95.9 186.5,95.96 190.16,95.96 190.21,95.91 190.21,95.91 190.34,95.79 190.34,95.79 191.18,94.94 192.84,94.94 193.61,95.71 194.86,95.71 195.63,94.94 207.79,94.94 212.47,90.26 212.47,89.09 212.6,88.96 212.6,88.91 213.75,87.76 214.95,87.76 215.7,87 215.7,86.07 217.05,84.72 217.05,84.51 217.55,84.01 217.55,83.17 219.03,81.7 219.03,78.73 228.43,69.32 230.05,69.32 232.49,66.89 234.22,66.89 237.3,63.81 242.55,63.81 242.94,64.21 245.54,64.21 246.21,63.53 246.21,61.44 249.86,57.8 249.86,54.51 255.47,48.9 256.48,48.9 260.03,45.35 260.03,44.92 261.03,43.92 261.93,43.92 v1(262.06,44.04)
  BOTTOM w0.076: UC1.CN34 181.7,89.6 181.82,89.72 181.99,89.89 182.23,89.89 182.29,89.83 182.53,89.83 182.58,89.84 182.62,89.86 182.79,89.94 183.78,89.94 185.45,88.27 185.86,88.27 185.92,88.33 185.92,88.43 v1(185.56,88.79)
  BOTTOM w0.097: JNGFF1.73 290.7,34.96 288.16,37.5 282.11,37.5 279.49,40.12 279.49,42.16 277.99,43.67 276.89,43.67 274.92,45.64 269.55,45.64 268.8,46.39 265.61,46.39 263.26,44.04 v1(262.06,44.04)
CLK_ITPXDP_N: length 4.2
  BOTTOM w0.076: UC1.AU1 159.87,110.18 159.94,110.11 160.14,110.11 160.22,110.18 160.22,110.51 159.99,110.74 159.91,110.74 159.76,110.89 159.76,111.29 160.01,111.54 160.55,111.54 160.97,111.96 160.97,112.39 RC530.1
CLK_ITPXDP_N_R: length 106.9
  IN3 w0.089: v1(162.61,123.68) 162.41,123.88 162.14,123.88 161.98,123.72 160.38,123.72 159.29,122.63 158.38,122.63 157.35,121.6 153.27,121.6 152.94,121.27 152.94,120.88 149.73,117.66 149.73,116.53 149.22,116.02 149.22,114.31 147.81,112.9 141.61,112.9 140.94,113.57 140.94,116.68 137,120.62 115.03,120.62 110.83,124.82 96.49,124.82 93.84,127.47 90.67,127.47 90.36,127.78 88.49,127.78 88.35,127.91 87.52,127.91 87.42,127.81 87.42,127.58 v1(87.62,127.38)
  BOTTOM w0.076: 162.63,117.5 162.63,117.45 162.55,117.37 162.54,117.37 162.44,117.27 162.44,116.35 160.92,114.83 160.92,113.86 RC530.2
  BOTTOM w0.097: 162.63,117.5 162.63,122.34 162.09,122.88 162.09,123.71 162.09,123.71 162.09,123.78 162.25,123.94 162.35,123.94 v1(162.61,123.68) ; v1(87.62,127.38) 87.43,127.58 87.43,130.12 87.63,130.31 88.01,130.31 88.26,130.56 88.26,130.82 88.47,131.03 JXDP1.42
CLK_ITPXDP_P: length 4.1
  BOTTOM w0.076: UC1.AU2 159.87,109.85 159.61,110.1 159.61,110.46 159.72,110.57 159.72,110.7 159.6,110.83 159.6,111.36 159.95,111.71 160.48,111.71 160.8,112.03 160.8,112.3 RC298.1
CLK_ITPXDP_P_R: length 107.5
  IN3 w0.089: v1(162.61,124.26) 162.41,124.06 162.06,124.06 161.9,123.9 160.31,123.9 159.22,122.81 158.31,122.81 157.28,121.78 153.2,121.78 152.76,121.34 152.76,120.95 149.55,117.74 149.55,116.61 149.04,116.1 149.04,114.39 147.74,113.08 141.68,113.08 141.12,113.64 141.12,116.76 137.07,120.8 115.1,120.8 110.9,125.01 96.56,125.01 93.92,127.65 90.74,127.65 90.44,127.96 88.56,127.96 88.43,128.09 87.45,128.09 87.24,127.89 87.24,127.59 v1(87.04,127.38)
  BOTTOM w0.076: RC298.2 160.76,113.86 160.76,114.9 162.27,116.42 162.27,117.35 162.42,117.5
  BOTTOM w0.097: v1(87.04,127.38) 87.24,127.59 87.24,130.19 87.55,130.5 87.93,130.5 88.07,130.64 88.07,130.82 87.87,131.02 JXDP1.40 ; v1(162.61,124.26) 162.47,124.12 162.17,124.12 161.91,123.85 161.91,123.63 161.91,123.63 161.91,122.81 162.45,122.27 162.45,117.53 162.42,117.5
CLK_PCIE_N0: length 180.1
  IN1 w0.089: v1(164.13,117.65) 164.33,117.45 169.28,117.45 170.57,118.74 175.46,118.74 181.71,121.33 186.02,121.33 186.89,122.2 189.59,122.2 190.05,121.75 224.5,121.75 228.36,117.88 239.98,117.88 240.55,118.45 245.32,118.45 245.74,118.03 255.9,118.03 258.17,115.75 258.62,115.75 258.84,115.53 264.02,115.53 265.67,113.89 265.67,112.99 266.39,112.27 269.82,112.27 271.15,110.93 274.01,110.93 275.07,109.88 275.07,105.94 277.8,103.21 277.8,94.95 278.94,93.81 278.94,93.21 283.19,88.97 283.19,86.25 v1(283.44,85.99)
  BOTTOM w0.076: UC1.AW2 161.36,109.66 161.44,109.74 161.44,111.58 161.63,111.78 161.63,113.87 161.22,114.28 161.22,114.9 162.83,116.51 162.83,117.28 163.02,117.46 163.95,117.46 163.98,117.5
  BOTTOM w0.097: 163.98,117.5 v1(164.13,117.65) ; JNGFF2.45 272.58,73.58 272.66,73.5 272.66,72.72 272.9,72.47 279.77,72.47 281.17,73.87 281.17,74.81 283.1,76.74 283.1,81.72 283.29,81.91 283.29,85.84 v1(283.44,85.99)
CLK_PCIE_N1: length 198.2
  IN3 w0.089: v1(283.8,31.04) 283.8,31.29 283.38,31.72 282.93,31.72 274.44,40.21 274.44,44.29 271.3,47.42 271.3,49.82 266.64,54.48 266.64,55.74 261.53,60.85 261.53,65.47 260.77,66.23 260.77,70.45 257.41,73.81 256.6,73.81 255.33,75.08 255.33,75.89 252.77,78.45 250.58,78.45 250.28,78.76 249.11,78.76 248.58,78.23 244.04,78.23 241.96,80.3 241.96,80.77 240.35,82.38 239.88,82.38 239.39,82.88 238.7,82.88 235.39,86.19 235.39,90.64 234.91,91.12 234.91,94.13 232.93,96.11 232.93,105.7 232.34,106.29 232.34,106.41 217.03,121.72 202.99,121.72 199.55,125.16 193.26,125.16 193.24,125.18 189.35,125.18 189.03,125.5 182.72,125.5 181.67,124.45 168.35,124.45 166.72,122.82 166.72,122.41 166.58,122.27 166.58,120.66 165.99,120.08 162.87,116.96 162.87,116.19 163.08,115.98 163.24,115.98 163.63,116.37 v1(163.63,116.39)
  BOTTOM w0.076: UC1.BC1 163.62,110.3 163.56,110.24 163.41,110.24 163.35,110.29 163.35,110.57 163.43,110.65 163.43,110.75 162.36,111.81 162.36,113.46 162.82,113.92 162.82,115.65 163.13,115.97 163.28,115.97 163.36,116.04 163.36,116.11 v1(163.63,116.39)
  BOTTOM w0.097: JNGFF1.49 284.7,32.6 284.54,32.45 284.54,31.55 284.23,31.23 284,31.23 v1(283.8,31.04)
CLK_PCIE_N2: length 192.7
  IN3 w0.089: v1(269.79,30.39) 269.79,30.91 270.13,31.25 272.13,31.25 273.27,32.4 273.27,43.87 270.18,46.96 270.18,49.35 260.3,59.23 260.3,62.64 259.2,63.74 259.2,70.37 256.98,72.59 256.23,72.59 254.21,74.62 254.21,75.36 253.23,76.34 252.08,76.34 251.42,77 250.45,77 250.35,77.11 243.58,77.11 238.93,81.76 238.23,81.76 234.27,85.72 234.27,90.18 233.71,90.73 233.71,93.74 231.81,95.64 231.81,103.44 231.22,104.03 231.22,105.95 216.57,120.6 202.52,120.6 199.55,123.57 192.67,123.57 192.18,124.06 188.89,124.06 188.57,124.38 185.09,124.38 183.95,123.24 180.6,123.24 180.5,123.33 168.81,123.33 167.84,122.36 167.84,121.94 167.7,121.81 167.7,120.14 166.1,118.55 166.1,114.75 164.36,113.01 v1(163.35,113.01)
  BOTTOM w0.076: UC1.BD3 164.19,109.26 164.11,109.18 163.86,109.18 163.76,109.28 163.76,109.4 163.88,109.51 163.88,109.64 163.95,109.71 164.09,109.71 164.16,109.78 164.16,110.55 162.81,111.9 162.81,112.61 162.98,112.78 163.27,112.78 163.35,112.87 v1(163.35,113.01)
  BOTTOM w0.097: v1(269.79,30.39) 269.75,30.39 269.75,30.39 269.55,30.19 269.55,29.66 269.82,29.39 JNGFF3.53
CLK_PCIE_N3: length 139.8
  TOP w0.097: UL1.45 268.4,106.64 268.29,106.75 268.1,106.75 268.03,106.82 267.08,106.82 266.96,106.7 263.95,106.7 263.04,107.61 263.04,112.44 262.57,112.9 261.91,112.9 v1(261.71,112.69)
  IN3 w0.089: v1(261.71,112.69) 261.53,112.87 261.34,112.87 261,113.21 260.75,113.21 257.48,116.48 245.62,116.48 241.84,112.7 232.53,112.7 220.45,124.78 202.58,124.78 200.33,127.03 194.94,127.03 194.72,127.25 194.72,127.99 194.59,128.12 189.71,128.12 188.96,127.37 181.94,127.37 180.9,126.33 167.57,126.33 165.17,123.93 164.67,123.93 v1(164.4,123.66)
  BOTTOM w0.076: 166.73,117.5 166.73,117.02 166.1,116.38 166.1,113.15 166.32,112.93 166.32,110.33 166.55,110.09 166.55,109.69 166.35,109.48 166.35,109.05 166.44,108.96 166.55,108.96 166.63,109.04 UC1.BH3
  BOTTOM w0.097: v1(164.4,123.66) 164.77,124.03 165.4,124.03 166.73,122.7 166.73,117.5
CLK_PCIE_N4: length 210.9
  TOP w0.097: UR1.6 287.97,22.78 287.86,22.89 287.21,22.89 286.59,23.51 285.81,23.51 285.74,23.44 285.19,23.44 284.89,23.14 v1(284.89,23.14)
  IN3 w0.089: v1(162.01,114.94) 162.01,114.94 161.62,114.54 161.52,114.54 161.43,114.63 161.43,116.33 165.47,120.37 165.47,121.98 166.14,122.65 166.14,123.06 168.11,125.03 181.43,125.03 182.48,126.07 189.27,126.07 189.5,125.84 193.38,125.84 193.49,125.73 199.79,125.73 202.04,123.48 211.55,123.48 212.73,122.29 217.85,122.29 226.78,113.36 226.78,112.78 232.92,106.65 232.92,106.53 233.51,105.94 233.51,96.35 235.48,94.37 235.48,91.36 235.96,90.88 235.96,86.43 238.88,83.51 240.15,83.51 242.54,81.12 242.54,80.54 244.28,78.8 247.76,78.8 248.3,79.33 250.51,79.33 250.82,79.03 253.08,79.03 255.9,76.21 255.9,75.57 256.84,74.63 258.3,74.63 259.59,73.34 259.59,72.44 261.34,70.69 261.34,66.47 262.45,65.36 262.45,64.54 263.12,63.87 263.12,60.08 267.22,55.98 267.22,54.71 271.87,50.06 271.87,47.66 278.19,41.35 278.19,38.11 281.11,35.19 281.11,34.35 282.1,33.36 282.94,33.36 284.23,32.07 284.23,27.37 284.68,26.92 284.68,25.68 284.23,25.23 284.23,24.06 284.55,23.75 284.55,23.68 284.89,23.34 284.89,23.15 284.89,23.14 v1(284.89,23.14)
  BOTTOM w0.076: v1(162.01,114.94) 162.22,114.73 162.42,114.73 162.59,114.57 162.59,114.09 162.2,113.7 162.2,111.54 161.93,111.27 161.93,110.17 162.02,110.08 162.23,110.08 162.31,110.16 UC1.BA1
CLK_PCIE_P0: length 179.7
  IN1 w0.089: v1(164.13,117.06) 164.33,117.27 169.35,117.27 170.65,118.56 175.49,118.56 181.75,121.15 186.1,121.15 186.97,122.02 189.52,122.02 189.97,121.57 224.42,121.57 228.29,117.7 240.05,117.7 240.62,118.27 245.24,118.27 245.67,117.85 255.82,117.85 258.1,115.57 258.54,115.57 258.77,115.35 263.95,115.35 265.49,113.81 265.49,112.91 266.31,112.09 269.74,112.09 271.08,110.75 273.93,110.75 274.89,109.8 274.89,105.86 277.62,103.13 277.62,94.88 278.76,93.74 278.76,93.14 283.01,88.89 283.01,86 282.92,85.91 282.71,85.91 v1(282.63,85.99)
  BOTTOM w0.076: UC1.AY3 161.68,109.34 161.6,109.42 161.6,111.52 161.79,111.71 161.79,113.94 161.38,114.35 161.38,114.83 163,116.45 163,117.22 163.08,117.3 163.95,117.3 164.13,117.12 v1(164.13,117.06)
  BOTTOM w0.097: v1(282.63,85.99) 283.11,85.52 283.11,81.99 282.92,81.8 282.92,76.81 280.99,74.88 280.99,73.95 279.69,72.65 272.98,72.65 272.84,72.79 272.84,73.47 273.08,73.7 JNGFF2.47
CLK_PCIE_P1: length 198.2
  IN3 w0.089: v1(283.78,31.9) 283.01,31.9 274.62,40.28 274.62,44.36 271.48,47.5 271.48,49.89 266.82,54.55 266.82,55.81 261.71,60.92 261.71,65.54 260.95,66.3 260.95,70.53 257.49,73.99 256.68,73.99 255.51,75.16 255.51,75.97 252.85,78.63 250.66,78.63 250.35,78.94 249.03,78.94 248.5,78.41 244.12,78.41 242.14,80.38 242.14,80.85 240.43,82.56 239.96,82.56 239.47,83.06 238.77,83.06 235.57,86.26 235.57,90.72 235.09,91.2 235.09,94.21 233.11,96.18 233.11,105.77 232.52,106.36 232.52,106.48 217.11,121.9 203.06,121.9 199.63,125.34 193.34,125.34 193.31,125.36 189.42,125.36 189.11,125.68 182.64,125.68 181.6,124.63 168.27,124.63 166.54,122.9 166.54,122.48 166.4,122.35 166.4,120.74 165.81,120.16 162.69,117.03 162.69,116.12 163.01,115.8 v1(163.63,115.8)
  BOTTOM w0.076: v1(163.63,115.8) 163.2,115.8 162.99,115.58 162.99,113.85 162.53,113.4 162.53,111.88 163.7,110.71 163.77,110.71 163.89,110.59 163.89,110.14 163.62,109.88 UC1.BC2
  BOTTOM w0.097: v1(283.78,31.9) 283.78,31.61 283.98,31.42 284.15,31.42 284.36,31.63 284.36,32.45 284.2,32.6 JNGFF1.47
CLK_PCIE_P2: length 192.6
  IN3 w0.089: v1(269.2,30.42) 269.42,30.64 269.48,30.64 269.61,30.77 269.61,30.99 270.05,31.44 272.05,31.44 273.09,32.48 273.09,43.79 270,46.89 270,49.28 260.12,59.16 260.12,62.57 259.02,63.66 259.02,70.29 256.9,72.41 256.16,72.41 254.03,74.54 254.03,75.29 253.15,76.16 252.01,76.16 251.35,76.82 250.38,76.82 250.27,76.93 243.5,76.93 238.85,81.58 238.16,81.58 234.09,85.65 234.09,90.1 233.53,90.66 233.53,93.67 231.63,95.57 231.63,103.37 231.04,103.96 231.04,105.87 216.49,120.42 202.45,120.42 199.48,123.39 192.59,123.39 192.1,123.88 188.81,123.88 188.49,124.2 185.16,124.2 184.03,123.06 180.52,123.06 180.43,123.15 168.89,123.15 168.02,122.28 168.02,121.87 167.88,121.73 167.88,120.07 166.28,118.47 166.28,114.67 164.44,112.83 163.76,112.83 v1(163.35,112.42)
  BOTTOM w0.076: v1(163.35,112.42) 163.35,112.54 163.28,112.61 163.05,112.61 162.97,112.54 162.97,111.97 164.32,110.62 164.32,109.74 164.47,109.6 164.47,109.11 164.37,109.01 UC1.BC3
  BOTTOM w0.097: JNGFF3.55 269.32,29.44 269.37,29.48 269.37,30.26 v1(269.2,30.42)
CLK_PCIE_P3: length 139.8
  TOP w0.097: v1(261.71,113.28) 261.89,113.09 262.65,113.09 263.22,112.51 263.22,107.69 264.03,106.88 266.89,106.88 267.01,107 268.11,107 268.17,106.93 268.34,106.93 268.44,107.04 268.81,107.04 UL1.44
  IN3 w0.089: v1(261.71,113.28) 261.71,113.24 261.53,113.06 261.4,113.06 261.07,113.39 260.82,113.39 257.56,116.66 245.55,116.66 241.77,112.88 232.6,112.88 220.52,124.96 202.66,124.96 200.41,127.21 195.01,127.21 194.9,127.32 194.9,128.07 194.67,128.3 189.64,128.3 188.89,127.55 181.86,127.55 180.82,126.51 167.49,126.51 165.1,124.11 164.53,124.11 v1(164.4,124.24)
  BOTTOM w0.076: UC1.BH4 166.91,108.97 166.91,109.57 166.76,109.72 166.76,109.73 166.72,109.76 166.72,110.16 166.48,110.4 166.48,113 166.26,113.22 166.26,116.31 166.9,116.95 166.9,117.42 166.91,117.43 166.91,117.48 166.92,117.49 166.92,117.5
  BOTTOM w0.097: 166.92,117.5 166.92,122.78 165.48,124.22 164.42,124.22 v1(164.4,124.24)
CLK_PCIE_P4: length 211
  TOP w0.097: v1(284.92,23.9) 285.19,23.63 285.66,23.63 285.73,23.7 286.66,23.7 287.29,23.07 287.86,23.07 287.97,23.18 UR1.5
  IN3 w0.089: v1(162.01,114.36) 161.44,114.36 161.25,114.55 161.25,116.4 165.29,120.44 165.29,122.05 165.96,122.72 165.96,123.14 168.03,125.21 181.36,125.21 182.4,126.25 189.35,126.25 189.57,126.03 193.45,126.03 193.56,125.91 199.87,125.91 202.12,123.66 211.62,123.66 212.81,122.47 217.92,122.47 226.96,113.43 226.96,112.86 233.1,106.72 233.1,106.6 233.69,106.01 233.69,96.42 235.66,94.44 235.66,91.44 236.14,90.96 236.14,86.5 238.96,83.69 240.22,83.69 242.72,81.19 242.72,80.62 244.35,78.98 247.69,78.98 248.22,79.51 250.59,79.51 250.89,79.21 253.16,79.21 256.08,76.28 256.08,75.65 256.92,74.81 258.38,74.81 259.77,73.42 259.77,72.52 261.52,70.76 261.52,66.54 262.63,65.44 262.63,64.61 263.3,63.94 263.3,60.15 267.4,56.05 267.4,54.79 272.06,50.13 272.06,47.74 278.37,41.42 278.37,38.19 281.29,35.26 281.29,34.42 282.18,33.54 283.02,33.54 284.41,32.14 284.41,27.44 284.86,27 284.86,25.6 284.41,25.16 284.41,24.14 284.66,23.9 v1(284.92,23.9)
  BOTTOM w0.076: UC1.BA2 162.31,109.8 162.19,109.92 161.95,109.92 161.76,110.1 161.76,111.34 162.04,111.61 162.04,113.77 162.43,114.16 162.43,114.5 162.36,114.57 162.22,114.57 v1(162.01,114.36)
CLK_TP_SIO_I2C_DAT: length 157.5
  TOP w0.107: RZ23.2 192.12,35.87 192.12,36.03 v1(191.96,36.19) 192.08,36.32 192.08,36.7 191.88,36.9 RZ346.2 CZ81.1
  TOP w0.127: v1(249.65,99.05) 250.05,98.65 UE1.E10
  IN1 w0.089: 260.07,95.11 260.07,95.09 260.07,95.09 260.07,95.02 260.08,95.01 260.08,94.97 256.67,91.57 255.13,91.57 254.47,90.9 253.32,90.9 252.18,89.76 250.66,89.76 250.06,89.16 249.54,89.16 247.86,87.49 247.86,87.01 247.86,87 247.86,86.98 ; v1(249.65,99.05) 249.65,99.16 249.23,99.58 249.23,100.66 249.17,100.72 249.17,100.82
  IN1 w0.099: 249.17,100.82 249.17,102.82 250.03,103.68 250.03,103.68 251.14,104.79 253.28,104.79 253.94,104.13 255.18,104.13 256.23,103.07 256.23,102.79 258.03,100.99 258.03,100.25 259.35,98.92 259.35,98.62 260.07,97.9 260.07,95.11 ; 247.86,86.98 247.86,86.55 247.04,85.74 247.04,84.5 247.48,84.05 247.48,83.29 245.49,81.29 245.49,77.64 252,71.13 252,68.5 251.39,67.89 251.39,65.54 251.93,65 251.93,58.1 251.78,57.95 251.78,50.3 252.12,49.95 252.12,45.89 251.26,45.03 251.26,43.2 249.16,41.11 246.44,41.11 245.57,40.23 245.57,39.22 244.56,38.2 243.05,38.2 241.86,37.02 233.67,37.02 233.01,37.68 229.47,37.68 229.16,37.99 229.16,39.26 228.81,39.61 222.59,39.61 222,40.19 215.67,40.19 214.75,41.11 204.94,41.11 202.15,38.32 201.18,38.32 200.37,37.51 198.91,37.51 198.46,37.96 196.86,37.96 195.98,37.08 192.53,37.08 192.15,36.7 192.15,36.38 v1(191.96,36.19)
CLK_TP_SIO_R: length 10.8
  TOP w0.107: CZ89.1 189.78,39.6 189.78,39.07 v1(190.03,38.82) 189.84,38.64 189.84,37.81 190.22,37.43 190.22,34.45 190.83,33.84 191.92,33.84 192.09,34.01 192.09,34.4 RZ23.1 RZ19.2
  BOTTOM w0.107: v1(190.03,38.82) 189.83,39.02 189.83,39.17 189.99,39.33 JKBTP1.14
CLKREQ_CNV#: length 136.3
  TOP w0.102: 183.93,92.46 180.96,92.46 180.45,91.95 179.51,91.95 v1(179.13,92.32)
  TOP w0.107: 183.93,92.46 184.36,92.46 185.9,92.46 187.63,94.18 189.56,94.18 190.02,93.72 190.4,93.72 RC752.1
  IN1 w0.089: v1(179.13,92.32) 179.13,92.22 178.72,91.81 178.72,91.07 179.19,90.6 179.5,90.6 179.83,90.93 180.2,90.93 181.18,89.95 183.66,89.95 184.22,89.39 184.22,89.16 185.89,87.49 187.09,87.49 v1(187.7,86.88)
  IN1 w0.099: v1(266.67,42.43) 266.89,42.64 266.89,43.61 266.27,44.22 266.27,54.96 v1(266.02,55.21)
  IN2 w0.102: v1(187.7,86.88) 187.7,86.69 187.68,86.66 187.68,85.52 187.04,84.88 187.04,83.62 187.04,83.62 187.04,83.43 187.63,82.84 188.84,82.84 192.43,79.25 196.2,79.25 198.72,76.72 206.18,76.72 206.69,77.23 209.8,77.23 210.37,76.65 213.39,76.65 213.8,77.06 214.92,77.06 215.96,76.02 217.93,76.02 223.17,70.78 223.17,69.43 226.65,65.95 228.63,65.95 230.89,63.69 232.35,63.69 234.06,61.98 246.45,61.98 v1(248.56,59.87)
  BOTTOM w0.089: UC1.CH29 178.78,92.52 v1(179.13,92.32)
  BOTTOM w0.107: v1(266.02,55.21) 265.86,55.37 v2(263,55.37) 262.01,55.37 259.26,58.12 251.74,58.12 249.99,59.87 v1(248.56,59.87) ; v1(266.67,42.43) 266.67,42.99 RZ1385.1
CLKREQ_CNV#_R: length 10.9
  BOTTOM w0.107: RZ1385.2 267.9,43.13 267.9,42.5 v2(268.22,42.19) 268.31,42.1 269.34,42.1 270.34,43.11 274.65,43.11 275.95,41.81 JNGFF1.14
CLKREQ_PCIE#0: length 105.5
  TOP w0.107: v1(272.42,83.15) 272.29,83.02 268.97,83.02 267.91,81.96 267.91,79.46 266.08,77.62 264.1,77.62 262.91,76.43 262.91,75.42 261.54,74.04 257.54,74.04 256.49,72.99 251.1,72.99 249.18,74.91 246.26,74.91 245,73.65 245,73.31 244.86,73.17 244.42,73.17 243.01,74.58 v2(243.01,76.3) 243.01,76.91 239.51,80.41 239.51,84.23 238.98,84.76 238.98,85.09 239.26,85.38 239.26,85.67 239.57,85.98 239.57,87.02 239,87.6 239,88.56 v1(239.41,88.97) ; v1(196.3,89.56) 194.92,90.94 RC297.1
  IN1 w0.099: v1(226.13,91.86) 226.13,91.58 225.38,90.83 223.15,90.83 221.38,92.6 219.56,92.6 217.52,90.55 207.44,90.55 205.74,88.85 197.01,88.85 v1(196.3,89.56)
  BOTTOM w0.107: v1(239.41,88.97) 237.72,90.66 236.52,90.66 235.33,91.86 v1(226.13,91.86) ; JNGFF2.44 272.33,83.05 v1(272.42,83.15)
CLKREQ_PCIE#0_R: length 19.8
  TOP w0.102: 183.93,91.7 181.89,91.7 180.28,90.08 178.65,90.08 v1(178.36,90.38)
  TOP w0.107: 183.93,91.7 187.52,91.7 187.96,91.26 188.78,91.26 189.43,90.61 191.9,90.61 192.54,91.25 192.54,92.07 192.66,92.19 v2(193.3,92.19) 193.59,91.89 RC189.1 194.33,91.86 RC297.2
  BOTTOM w0.076: v1(178.36,90.38) 178.06,90.68 UC1.CF32
CLKREQ_PCIE#1: length 114.1
  TOP w0.107: v1(204.4,81.42) 204.2,81.42 203.93,81.68 RC526.1
  IN2 w0.102: v1(204.4,81.42) 209.93,81.42 210.75,80.6 212.03,80.6 212.56,80.07 215.1,80.07 217.09,78.08 220.38,78.08 226.52,71.93 226.52,71.59 228.66,69.45 230.07,69.45 234.07,65.45 247.11,65.45 250.8,61.76 v1(250.94,61.76) ; v1(275.46,37.74) 275.79,38.07 275.79,43.47 271.65,47.61 271.65,49.92 269.45,52.12 269.45,60.64 v1(268.95,61.14)
  BOTTOM w0.107: v1(250.94,61.76) 251.47,61.76 v2(251.89,61.34) 253.2,60.03 260.32,60.03 260.71,59.64 267.84,59.64 268.95,60.75 v1(268.95,61.14) ; v1(275.46,37.74) 275.59,37.61 279.5,37.61 281.38,35.74 284.22,35.74 285.7,34.26 JNGFF1.53
CLKREQ_PCIE#1_R: length 36
  TOP w0.107: RC526.2 v1(203.77,80.02) RC522.1 204.82,79.4 v2(204.91,79.49)
  IN1 w0.099: v1(177.38,90.51) 177.39,90.21 177.86,89.73 177.86,89.05 178.26,88.65 181.84,88.65 182.01,88.49 183.61,88.49 184.59,87.51 185.67,86.43 186.56,86.43 187.83,85.16 188.18,85.16 190.98,82.36 195.06,82.36 195.92,83.22 197.79,83.22 199.89,81.11 199.89,80.4 200.84,79.45 203.2,79.45 v1(203.77,80.02)
  BOTTOM w0.089: UC1.CE32 176.99,90.7 v1(177.38,90.51)
CLKREQ_PCIE#2: length 122.1
  TOP w0.107: RC727.1 200.21,82.16 v1(200.06,82.31)
  IN2 w0.102: v1(268.14,58.3) 268.14,56.58 268.44,56.28 268.44,51.42 270.47,49.38 270.47,47.08 273.49,44.06 273.49,38.05 268.56,33.13 268.56,31.22 267.64,30.29 267.64,25.08 v1(270.16,22.55) ; v1(250.94,61.18) 250.74,61.18 246.69,65.22 233.97,65.22 230.18,69.02 228.15,69.02 226.06,71.11 226.06,71.97 220.42,77.62 216.9,77.62 214.93,79.59 212.05,79.59 211.98,79.51 211.64,79.51 211.02,80.14 210.44,80.14 209.8,80.78 201.58,80.78 v1(200.06,82.31)
  BOTTOM w0.107: v1(268.14,58.3) 267.04,59.4 260.61,59.4 260.22,59.8 v2(252.43,59.8) 251.06,61.18 v1(250.94,61.18) ; JNGFF3.52 270.07,22.47 v1(270.16,22.55)
CLKREQ_PCIE#2_R: length 34.8
  TOP w0.107: v1(197.16,88.02) 196.97,87.83 196.97,85.33 v2(197.78,84.52) 198.75,84.52 200.86,82.41 200.86,80.97 200.66,80.77 RC727.2 RC525.1
  IN1 w0.099: v1(178.35,91.74) 178.35,91.87 178.75,92.26 178.75,92.56 178.87,92.69 179.48,92.69 179.57,92.59 179.57,92.04 179.84,91.77 180.93,91.77 182.27,90.43 183.84,90.43 184.69,89.58 187.49,89.58 187.92,89.15 187.92,88.89 188.11,88.7 189.6,88.7 190.26,89.36 190.79,89.88 195.3,89.88 v1(197.16,88.02)
  BOTTOM w0.089: v1(178.35,91.74) 178.31,91.73 UC1.CF30
CLKREQ_PCIE#3: length 95.3
  TOP w0.107: v2(261.51,111.66) 261.09,111.66 v1(260.79,111.35) ; RC527.1 v1(202.88,82.29) ; RL4.1 v1(267.33,104.59) 267.71,104.59 268.56,105.44 UL1.48
  IN1 w0.099: v1(237.25,96.39) 235.24,96.39 232.48,93.63 228.51,93.63 225.48,90.6 223.05,90.6 221.28,92.37 219.66,92.37 217.59,90.31 207.52,90.31 202.88,85.67 v1(202.88,82.29)
  IN2 w0.102: v1(267.33,104.59) 267.33,105.28 263.23,109.38 262.14,109.38 260.79,110.73 v1(260.79,111.35)
  IN3 w0.102: v1(237.25,96.39) 236.2,97.44 236.2,103.57 239.48,106.84 242.63,106.84 243.15,107.37 243.15,107.88 248.21,112.95 258.79,112.95 260.38,111.35 v1(260.79,111.35)
CLKREQ_PCIE#3_R: length 34.1
  TOP w0.107: RC523.1 v1(202.88,80.02) RC527.2
  IN1 w0.089: v1(177.39,91.1) 177.75,90.74 177.75,90.16 177.84,90.07
  IN1 w0.099: v1(202.88,80.02) 202.54,79.68 200.93,79.68 200.12,80.49 200.12,81.21 197.88,83.44 195.83,83.44 194.97,82.58 191.08,82.58 188.27,85.39 187.91,85.39 186.6,86.69 185.75,86.69 183.77,88.67 182.08,88.67 181.92,88.83 178.44,88.83 178.16,89.11 178.16,89.74 177.84,90.07
  BOTTOM w0.089: UC1.CE31 v1(177.39,91.1)
CLKREQ_PCIE#4: length 132.4
  TOP w0.107: RC528.1 v1(201.99,82.29) ; v1(287.97,25.92) 287.65,25.6 287.65,24.9 288.17,24.38 UR1.2
  IN2 w0.102: v1(269.57,61.25) 269.68,61.14 269.68,52.78 272.35,50.11 272.35,47.7 276.09,43.95 276.09,36.4 277.38,35.11 287.09,35.11 289.43,32.78 289.43,27.76 287.97,26.3 v1(287.97,25.92) ; v1(201.99,82.29) 202.51,81.77 203.42,81.77 203.7,82.05 211.65,82.05 212.03,81.67 212.03,81.67 212.4,81.3 212.4,81.3 213.17,80.53 215.29,80.53 217.28,78.53 220.57,78.53 223.15,75.96 224.95,75.96 226,74.91 227.62,74.91 230.52,72.01 230.52,69.33 234.11,65.73 247.15,65.73 250.3,62.58 v1(250.84,62.58)
  BOTTOM w0.107: v1(269.57,61.25) 268.84,61.97 267.94,61.97 266.54,60.57 261.1,60.57 260.71,60.96 256.56,60.96 v2(254.83,62.7) 254.5,63.03 251.84,63.03 251.39,62.58 v1(250.84,62.58)
CLKREQ_PCIE#4_R: length 33.3
  TOP w0.107: v2(201.1,80.06) 201.76,79.4 RC51.1 v1(201.99,80.08) RC528.2
  IN1 w0.089: v1(177.39,91.73) 177.82,91.3 178.09,91.3 179.57,89.81
  IN1 w0.099: 179.57,89.81 180.47,89.81 181.27,89.02 183.72,89.02 185.77,86.97 186.67,86.97 187.92,85.72 188.26,85.72 191.17,82.81 194.87,82.81 195.81,83.74 197.9,83.74 201.56,80.08 v1(201.99,80.08)
  BOTTOM w0.089: UC1.CE30 v1(177.39,91.73)
CMOUT: length 57.4
  TOP w0.254: v1(50.47,86.95) 50.34,87.08 PQ812.2 49.46,87.28 PQ811.2 49.46,88.74 49.57,88.85 49.93,88.85 50.11,88.67 PQ811.3
  IN2 w0.254: v1(77.58,58.16) 78.61,57.14 78.61,55.17 81.28,52.5 v1(81.9,52.5)
  BOTTOM w0.254: v1(50.47,86.95) 50.47,86.69 v2(50.88,86.29) 51.58,85.58 51.58,84.18 51.87,83.89 54.29,83.89 55.94,82.24 57.34,82.24 58.86,80.72 59.46,80.72 71.92,68.26 71.92,59.78 73.53,58.16 v1(77.58,58.16) ; v1(81.9,52.5) 81.61,52.21 PR727.1
CNV_BRI_PRX_DTX: length 125.2
  TOP w0.107: RC724.1 262.66,42.09 v1(262.95,42.09)
  IN3 w0.102: v1(262.95,42.09) 262.54,42.5 262.54,44.13 261.67,45.01 260.94,45.01 256.26,49.68 256.26,49.69 255.9,50.05 254.87,50.05 250.26,54.67 250.26,58.99 248.98,60.27 248.98,63.37 247.33,65.02 237.31,65.02 234.06,68.27 233.94,68.27 229.05,73.16 228.07,73.16 227.06,72.15 226.75,72.15 220.33,78.57 220.33,79.34 219.93,79.73 219.93,80.39 220.42,80.87 220.42,81.45 218.96,82.91 218.96,84.61 216.51,87.05 216.51,87.34 215.28,88.56 214.08,88.56 213.75,88.89 213.75,91.15 213.12,91.78 213.12,91.78 212.56,92.34 212.56,92.34 209.16,95.74 206.5,95.74 206.4,95.85 206.4,96.23 206.3,96.33 206.1,96.33 205.99,96.23 205.99,95.85 205.89,95.74 205.69,95.74 205.59,95.85 205.59,96.35 205.49,96.45 205.28,96.45 205.18,96.35 205.18,95.85 205.08,95.74 198.65,95.74 197.74,96.66 196.34,96.66 195.78,97.22 192.24,97.22 192.16,97.29 191.26,97.29 191.15,97.18 189.47,97.18 188.95,97.69 183.99,97.69 183.8,97.5 180.98,97.5 180.77,97.71 v1(180.42,97.71)
  BOTTOM w0.089: v1(180.42,97.71) 180.53,97.91 180.48,98.09 180.3,98.2 UC1.CK20
  BOTTOM w0.107: v1(262.95,42.09) 263.56,42.09 264.17,42.7 v2(264.51,42.7) 265.18,42.7 266.76,44.27 RZ1381.2
CNV_BRI_PRX_DTX_R: length 17.4
  BOTTOM w0.107: JNGFF1.22 277.95,41.84 277.3,42.49 275.99,42.49 v1(275.2,43.29) 274.02,44.46 273.64,44.46 273.53,44.35 273.53,44.16 273.43,44.05 273.21,44.05 273.11,44.16 273.11,44.34 272.99,44.46 272.71,44.46 272.61,44.35 272.61,43.88 272.5,43.77 272.29,43.77 272.18,43.88 272.18,44.35 272.07,44.46 271.86,44.46 271.75,44.35 271.75,43.88 271.65,43.77 271.43,43.77 271.33,43.88 271.33,44.35 271.22,44.46 270.93,44.46 270.83,44.35 270.83,43.77 270.72,43.66 270.51,43.66 270.4,43.77 270.4,44.35 270.29,44.46 270.08,44.46 269.97,44.35 269.97,43.77 269.87,43.66 269.65,43.66 269.55,43.77 269.55,44.35 269.44,44.46 268.17,44.46 RZ1381.1
CNV_BRI_PTX_DRX: length 21.6
  TOP w0.107: v1(197.36,95.74) 197.65,95.46 RC711.2
  IN3 w0.102: v1(179.85,97.59) 180.12,97.32 183.93,97.32 184.12,97.52 188.62,97.52 189.37,96.77 190.49,96.77 191.52,95.75 192.51,95.75 193.57,96.81 195.55,96.81 196.11,96.25 197.57,96.25 197.67,96.15 197.67,95.84 197.58,95.74 v1(197.36,95.74)
  BOTTOM w0.089: v1(179.85,97.59) 179.9,97.68 179.77,98.08 UC1.CJ20
CNV_BRI_PTX_DRX_R: length 134.7
  TOP w0.107: v1(264.27,67.57) 262.56,67.57 261.53,66.55 RZ603.1 ; v1(200.29,96.28) 200.29,96.1 199.65,95.46 RC711.1
  IN1 w0.099: v1(238.81,101.1) 236.24,101.1 235.76,100.62 228.43,100.62 227.41,99.6 226.21,99.6 224.67,98.06 223.25,98.06 221.98,96.79 220.63,96.79 220.36,97.05 214.32,97.05 213.01,95.74 200.61,95.74 200.29,96.06 v1(200.29,96.28)
  IN3 w0.102: v1(281.87,43.51) 278.58,43.51 273.51,48.58 273.51,50.73 273.3,50.95 268.85,55.39 268.85,56.65 266.26,59.25 266.26,64.7 264.27,66.69 v1(264.27,67.57) 264.27,70.38 262.4,72.25 262.4,72.85 255.22,80.04 254.42,80.04 252.93,81.53 249.88,81.53 249.55,81.86 246.75,81.86 246.33,81.44 245.32,81.44 243.84,82.92 243.84,83.39 242.44,84.79 242.44,85.91 241.1,87.25 239.35,87.25 239,87.6 239,92.21 238.16,93.05 238.16,95.61 237.85,95.92 237.85,100.14 v1(238.81,101.1)
  BOTTOM w0.107: v1(281.87,43.51) 281.45,43.09 JNGFF1.36
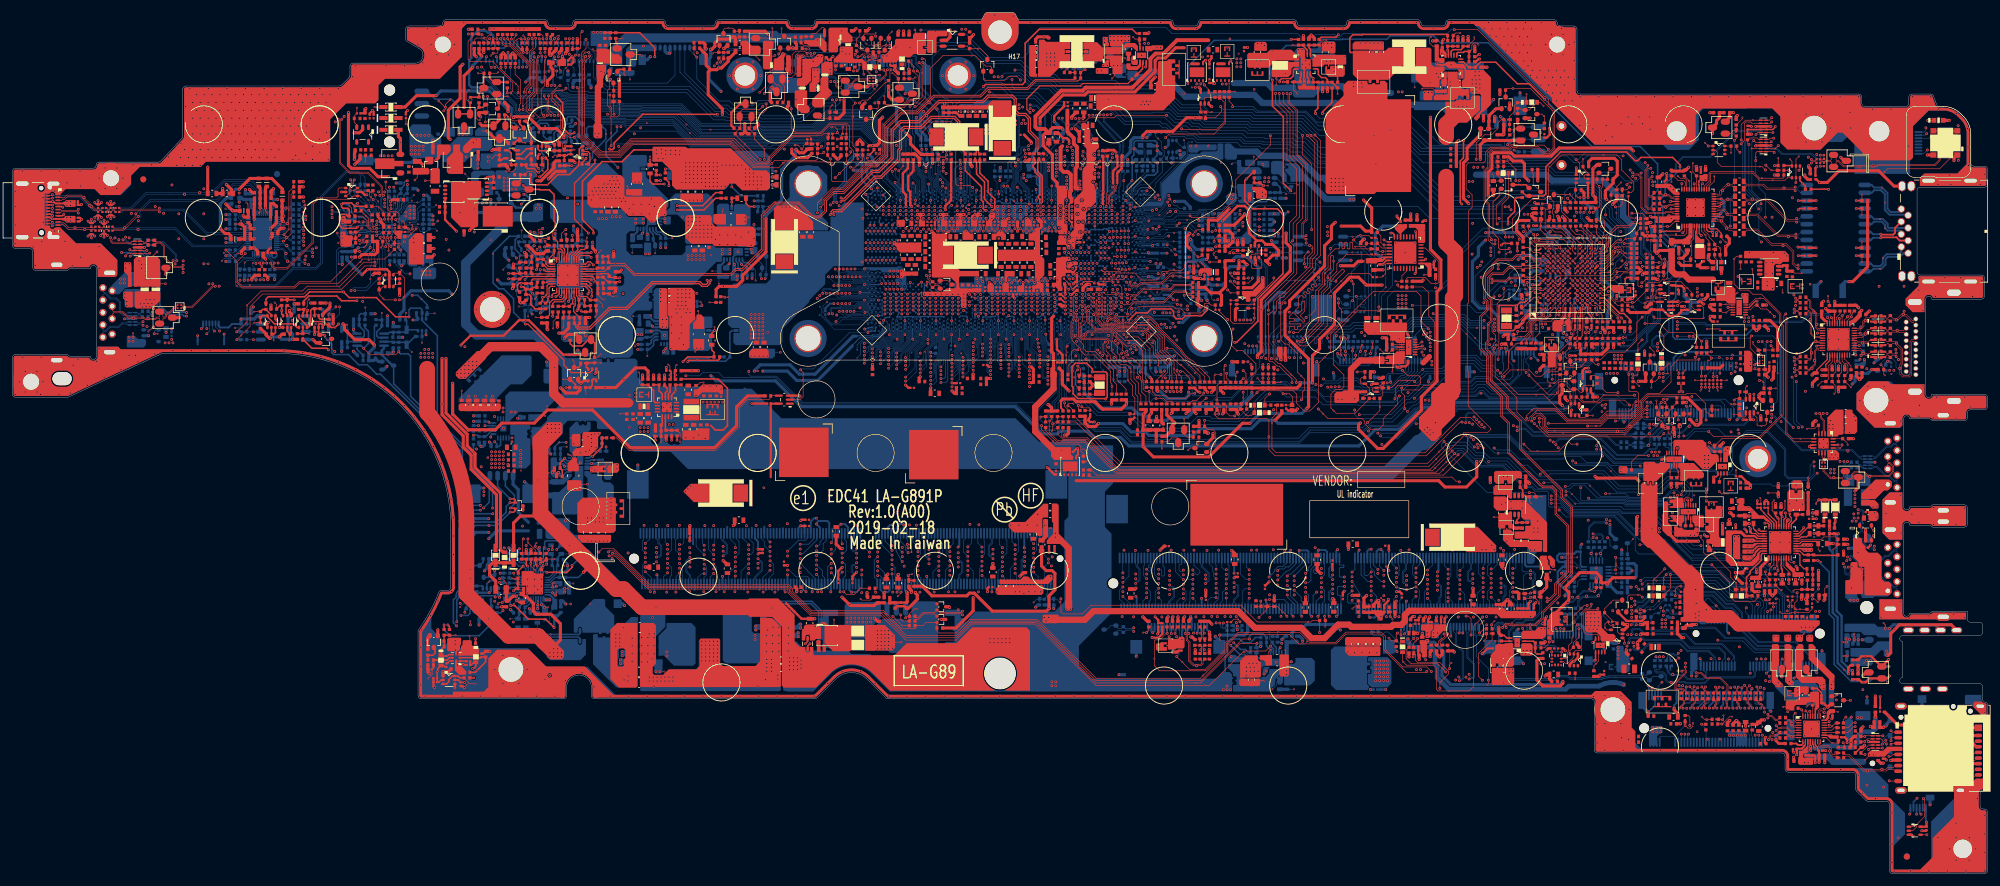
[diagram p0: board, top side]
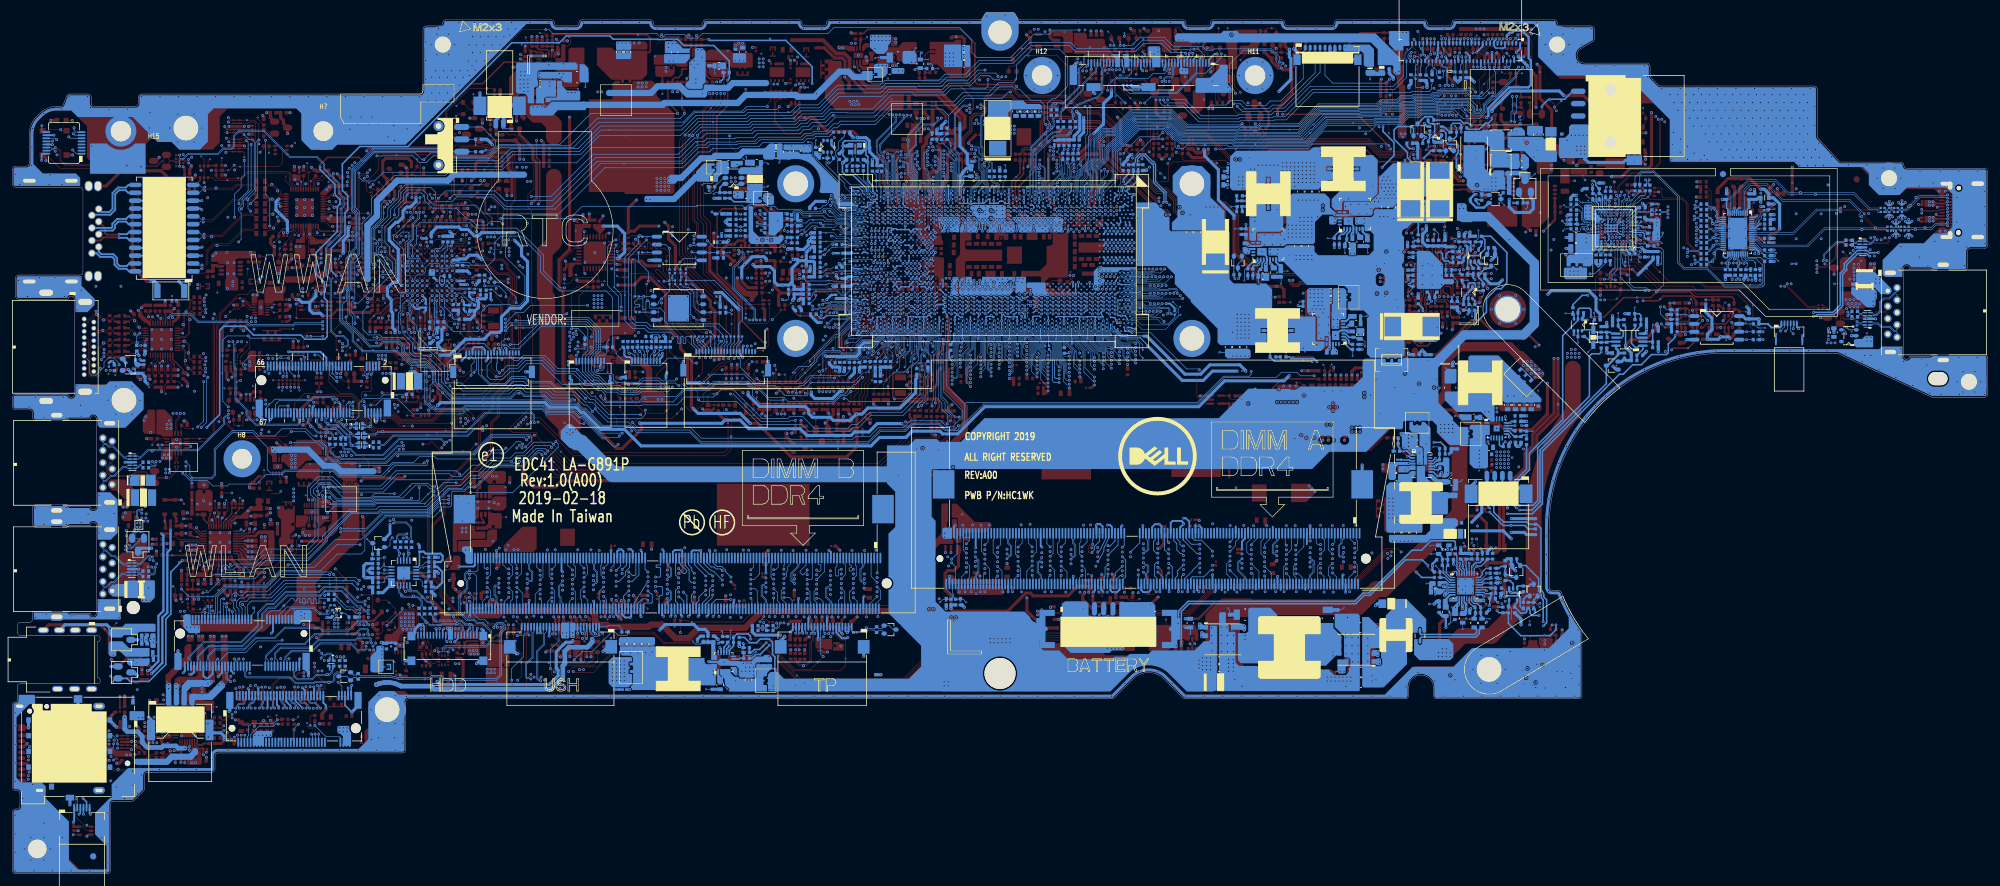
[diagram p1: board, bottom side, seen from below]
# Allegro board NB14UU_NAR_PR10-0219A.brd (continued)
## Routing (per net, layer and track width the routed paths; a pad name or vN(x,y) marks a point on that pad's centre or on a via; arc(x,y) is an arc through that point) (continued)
CNV_COEX1: length 136.3
  TOP w0.107: RZ373.2 v1(276.01,78.61) ; v1(264.07,73.82) 263.3,73.82 260.41,70.93 v2(252,70.93) 248.12,70.93 247.05,71.99 247.05,72 246.65,72.4 v1(246.65,72.99)
  IN1 w0.089: 191.11,97.73 189.96,97.73 189.23,98.46 188.46,98.46 187.59,99.33 179.52,99.33 v1(179.12,99.74)
  IN1 w0.099: v1(264.07,73.82) 264.73,73.82 265.93,75.02 265.93,76.53 268.21,78.81 271.59,78.81 272.65,77.74 275.14,77.74 v1(276.01,78.61) ; 191.11,97.73 192.52,97.73 192.76,97.49 198.1,97.49 198.79,96.8 209.24,96.8 209.67,97.23 210.13,97.68 213.17,97.68 215.07,99.58 218.44,99.58 219.96,98.05 221.62,98.05 222.76,99.19 225.24,99.19 226.05,100 227.24,100 228.26,101.02 235.56,101.02 236.09,101.55 239.04,101.55 v1(240.14,100.44)
  IN2 w0.102: v1(246.65,72.99) 247.05,73.4 247.05,73.75 245.28,75.51 244.11,75.51 238.82,80.81 238.82,80.9 238.43,81.28 238.43,81.87 237.04,83.26 237.04,94.46 238.48,95.9 238.48,96.31 239.04,96.87 239.04,98.16 239.73,98.85 239.73,100.03 v1(240.14,100.44)
  BOTTOM w0.076: UC1.CH17 v1(179.12,99.74)
CNV_COEX2: length 134.1
  TOP w0.107: RZ372.2 v1(274.74,78.61) ; v1(246.64,73.58) 247.11,73.58 247.22,73.47 247.22,72.16 248.1,71.27 v2(250.45,71.27) 260.42,71.27 263.55,74.4 v1(264.05,74.4)
  IN1 w0.089: 191.11,99.05 188.35,99.05 187.91,99.5 179.99,99.5 v1(179.75,99.74)
  IN1 w0.099: 191.11,99.05 191.96,99.05 193.05,97.96 198.29,97.96 198.93,97.32 209.01,97.32 209.89,98.2 212.98,98.2 214.94,100.16 223.88,100.16 224.71,100.99 225.24,100.99 225.4,100.83 227.1,100.83 227.78,101.51 235.27,101.51 235.76,102 239.13,102 v1(239.51,102.38) ; v1(274.74,78.61) 274.09,77.97 272.75,77.97 271.68,79.03 268.11,79.03 265.71,76.63 265.71,75.11 265,74.4 v1(264.05,74.4)
  IN2 w0.102: v1(246.64,73.58) 246.64,73.65 245.29,75 244.15,75 238.5,80.65 238.5,80.9 236.39,83 236.39,90.89 236.57,91.07 236.57,94.31 238.25,95.99 238.25,96.4 238.81,96.96 238.81,98.25 239.47,98.91 239.47,101.01 239.03,101.45 239.03,101.9 v1(239.51,102.38)
  BOTTOM w0.076: UC1.CJ17 v1(179.75,99.74)
CNV_COEX3: length 129.1
  TOP w0.107: v1(245.83,73.57) 246.25,73.99 247.03,73.99 247.45,73.57 247.45,72.26 248.1,71.61 v2(249.1,71.61) 260.43,71.61 263.81,74.99 v1(264.07,74.99) ; RZ374.2 v1(273.47,78.61)
  IN1 w0.089: 191.11,97.47 189.92,97.47 189.12,98.27 188.38,98.27 187.51,99.13 185.22,99.13 v1(184.72,98.63)
  IN1 w0.099: v1(273.47,78.61) 272.82,79.26 268.02,79.26 265.48,76.72 265.48,75.55 264.92,74.99 v1(264.07,74.99) ; v1(238.82,100.51) 237.82,99.51 235.08,99.51 234.13,98.56 227.52,98.56 226.87,97.91 226.13,97.91 225.47,97.25 223.58,97.25 222.31,95.98 220.3,95.98 220.07,96.2 215.76,96.2 214.5,94.93 199.57,94.93 197.88,96.63 193.3,96.63 192.43,97.5 191.14,97.5 191.11,97.47
  IN2 w0.102: v1(245.83,73.57) 245.18,73.57 244.46,74.29 244.05,74.29 237.82,80.52 237.82,80.7 235.16,83.36 235.16,91.09 235.33,91.26 235.33,93.72 237.65,96.04 237.65,96.62 237.88,96.85 237.88,99.57 v1(238.82,100.51)
  BOTTOM w0.076: UC1.CP20 182.47,98.07 182.93,98.07 183.55,98.5 184.59,98.5 v1(184.72,98.63)
CNV_DET#_EC: length 87.6
  TOP w0.107: v1(256.41,102.01) 256.01,101.61 256.01,100.88 255.78,100.65 255.5,100.65 255.25,100.39 255.25,99.82 UE1.L11 ; RZ827.2 261.04,106.31 261.39,105.97 v1(262.31,105.97)
  IN2 w0.102: v1(262.31,105.97) 262.87,105.41 262.87,102.33 263.55,101.65 265.7,101.65 267.53,99.82 267.53,97.76 268.03,97.27 268.03,78.44 268.21,78.26 268.21,72.17 267.91,71.87 267.91,64.91 267.18,64.17 267.18,50.97 267.57,50.58 267.57,49.16 268.21,48.52 268.21,47.5 267.2,46.49 267.2,43.91 v1(266.25,42.96)
  IN3 w0.102: v1(256.41,102.01) 258.61,102.01 261.11,104.51 261.11,104.76 v1(262.31,105.97)
  BOTTOM w0.107: v2(264.68,40.49) RZ377.2 265.3,42.1 QZ17.1 265.96,42.1 266.25,42.39 v1(266.25,42.96)
CNV_PRX_DTX_N0: length 134.4
  IN3 w0.089: v1(261.82,37.34) 261.77,37.39 261.77,37.94 261.57,38.14 260.73,38.14 259.31,39.56 259.31,40.19 257.08,42.42 257.08,43.53 255.99,44.62 254.91,44.62 254.51,45.02 253.84,45.02 251.19,47.68 250.08,47.68 246.99,50.78 246.99,56.36 245.62,57.72 243.78,57.72 243.58,57.53 243.58,56.58 243.5,56.49 243.23,56.49 243.14,56.58 243.14,57.53 242.95,57.72 242.53,57.72 242.34,57.53 242.34,56.58 242.25,56.49 241.98,56.49 241.89,56.58 241.89,57.53 241.7,57.72 240.8,57.72 239.9,58.62 237.86,58.62 232.46,64.02 231.29,64.02 228.86,66.45 227.24,66.45 216.16,77.54 216.16,79.78 214.39,81.55 213.33,81.55 209.72,85.16 209.72,87.67 207.09,90.3 205.03,90.3 203.26,92.07 201.4,92.07 200.53,91.2 191.13,91.2 190.82,91.5 190.05,91.5 v1(189.81,91.74)
  BOTTOM w0.076: UC1.CR30 183.03,92.09 183.13,91.99 183.49,91.99 183.63,92.13 183.8,92.13 183.94,91.99 184.1,91.99 184.24,92.13 184.41,92.13 184.54,91.99 184.71,91.99 184.85,92.13 185.02,92.13 185.15,91.99 185.39,91.99 185.53,92.13 185.7,92.13 185.84,91.99 187.23,91.99 187.73,91.49 188.76,91.49 188.93,91.32 189.39,91.32 v1(189.81,91.74)
  BOTTOM w0.097: JNGFF1.15 276.2,34.45 276.51,34.76 276.51,35.56 275.64,36.43 270.82,36.43 269.56,37.7 263.55,37.7 263.22,38.03 261.36,38.03 261.26,37.93 261.26,37.68 261.48,37.46 261.48,37.35 261.58,37.25 261.74,37.25 v1(261.82,37.34)
CNV_PRX_DTX_N1: length 135
  IN3 w0.089: v1(188.14,92.68) 188.68,92.68 188.96,92.96 191.25,92.96 191.5,93.22 193.3,93.22 194.15,92.36 199.99,92.36 200.85,93.22 207.07,93.22 210.57,89.71 210.57,88.44 210.87,88.15 210.87,85.63 213.8,82.7 214.54,82.7 214.54,82.7 215.02,82.7 217.31,80.41 217.31,78.01 227.72,67.6 229.33,67.6 231.77,65.17 233.51,65.17 237.98,60.69 244.28,60.69 248.13,56.84 248.13,52.46 254.42,46.17 256.06,46.17 257.01,45.22 257.29,45.22 259.7,42.81 259.7,41.46 260.45,40.7 260.45,40.04 260.71,39.78 263.15,39.78 263.55,39.37 263.55,37.57 262.13,36.14 261.72,36.14 261.59,36.27 261.44,36.27 v1(261.3,36.13)
  BOTTOM w0.076: 186.72,92.45 183.12,92.45 183.06,92.51 182.69,92.51 182.57,92.45 182.53,92.43 182.35,92.43 182.28,92.44 182.13,92.44 182.13,92.45 181.93,92.45 181.84,92.35 181.2,92.35 UC1.CM30
  BOTTOM w0.097: v1(188.14,92.68) 187.81,92.35 186.99,92.35 186.89,92.45 186.72,92.45 ; JNGFF1.9 274.7,34.45 274.86,34.6 274.86,34.96 273.98,35.85 270.58,35.85 269.31,37.11 264.44,37.11 263.33,36 262.08,36 261.78,36.29 261.46,36.29 v1(261.3,36.13)
CNV_PRX_DTX_P0: length 134.4
  IN3 w0.089: v1(261.08,37.29) 261.21,37.29 261.59,37.67 261.59,37.87 261.5,37.96 260.66,37.96 259.12,39.49 259.12,40.11 256.9,42.34 256.9,43.46 255.92,44.44 254.84,44.44 254.43,44.84 253.77,44.84 251.11,47.5 250.01,47.5 246.81,50.7 246.81,56.29 245.55,57.54 243.85,57.54 243.77,57.45 243.77,56.5 243.57,56.31 243.15,56.31 242.96,56.5 242.96,57.45 242.87,57.54 242.6,57.54 242.52,57.45 242.52,56.5 242.32,56.31 241.9,56.31 241.71,56.5 241.71,57.45 241.62,57.54 240.72,57.54 239.83,58.44 237.78,58.44 232.38,63.84 231.22,63.84 228.78,66.27 227.17,66.27 215.98,77.46 215.98,79.71 214.32,81.37 213.25,81.37 209.54,85.08 209.54,87.6 207.02,90.12 204.95,90.12 203.18,91.89 201.47,91.89 200.6,91.02 191.05,91.02 190.75,91.32 189.98,91.32 v1(189.81,91.16)
  BOTTOM w0.076: UC1.CP30 182.76,91.82 187.16,91.82 187.66,91.32 188.69,91.32 188.86,91.16 v1(189.81,91.16)
  BOTTOM w0.097: JNGFF1.17 276.7,35.64 275.72,36.62 270.9,36.62 269.63,37.88 263.63,37.88 263.3,38.21 261.28,38.21 261.08,38.01 v1(261.08,37.29)
CNV_PRX_DTX_P1: length 134.9
  IN3 w0.089: v1(261.92,36.76) 261.86,36.82 261.7,36.82 261.58,36.7 261.58,36.54 261.8,36.32 262.05,36.32 263.37,37.64 263.37,39.3 263.07,39.6 260.64,39.6 260.27,39.96 260.27,40.63 259.51,41.39 259.51,42.74 257.21,45.04 256.94,45.04 255.99,45.99 254.35,45.99 247.95,52.39 247.95,56.76 244.21,60.51 237.91,60.51 233.43,64.99 231.7,64.99 229.26,67.42 227.64,67.42 217.13,77.94 217.13,80.33 214.94,82.52 214.78,82.52 214.61,82.52 213.73,82.52 210.69,85.56 210.69,88.07 210.39,88.37 210.39,89.64 206.99,93.04 200.92,93.04 200.07,92.18 194.08,92.18 193.23,93.04 191.58,93.04 191.32,92.78 189.03,92.78 188.75,92.5 188.53,92.5 188.18,92.15 v1(188.18,92.01)
  BOTTOM w0.076: 186.72,92.27 186.71,92.27 186.7,92.28 186.65,92.28 186.64,92.29 183.06,92.29 182.99,92.35 182.73,92.35 182.65,92.31 182.65,92.31 182.57,92.27 182.33,92.27 182.26,92.28 182,92.28 181.85,92.13 181.85,91.98 181.69,91.82 181.43,91.82 181.34,91.9 181.34,92.01 181.42,92.09 UC1.CN30
  BOTTOM w0.097: 186.72,92.27 186.81,92.27 186.91,92.17 188.02,92.17 v1(188.18,92.01) ; JNGFF1.11 275.2,34.45 275.04,34.6 275.04,35.04 274.05,36.03 270.66,36.03 269.39,37.3 264.36,37.3 263.25,36.19 262.15,36.19 261.92,36.42 261.92,36.76 v1(261.92,36.76)
CNV_PTX_DRX_N0: length 157
  IN3 w0.089: v1(186.42,90.64) 186.22,90.84 186.2,90.84 186.01,91.02 186.01,93.18 187.29,94.46 190.6,94.46 190.87,94.19 195.44,94.19 195.87,93.76 199.88,93.76 200.3,94.18 207.47,94.18 211.64,90.01 211.64,88.85 211.84,88.64 211.84,88.14 213.87,86.11 214.17,86.11 215.78,84.51 215.78,83.88 218.27,81.38 218.27,78.42 228.12,68.57 229.74,68.57 232.17,66.13 233.91,66.13 238.39,61.66 239.19,61.66 239.43,61.9 239.43,62.97 239.51,63.05 239.78,63.05 239.87,62.97 239.87,61.85 240.06,61.66 240.48,61.66 240.67,61.85 240.67,62.97 240.76,63.05 241.03,63.05 241.12,62.97 241.12,61.85 241.31,61.66 241.73,61.66 241.92,61.85 241.92,62.97 242.01,63.05 243.03,63.05 243.42,63.45 245.23,63.45 245.46,63.22 245.46,61.12 249.1,57.48 249.1,53.99 253.39,49.7 253.39,49.39 255.6,47.18 256.42,47.18 257.37,46.23 257.65,46.23 260.66,43.22 260.66,42.68 260.98,42.36 261.19,42.36 v1(261.56,42)
  BOTTOM w0.076: v1(186.42,90.64) 186.33,90.64 186.2,90.77 186.2,91.05 186.02,91.24 184.18,91.24 183.93,90.99 183.25,90.99 183.18,91.01 183.03,91.11 182.93,91.13 182.92,91.13 182.86,91.13 182.8,91.13 182.65,91.11 182.5,91.11 182.42,91.12 182.38,91.12 182.3,91.14 182.07,91.13 181.98,91.13 181.71,91.13 181.42,91.11 181.33,91.01 181.34,90.87 181.44,90.78 UC1.CN32
  BOTTOM w0.097: v1(261.56,42) 261.8,42.23 261.8,42.25 261.95,42.39 262.1,42.39 262.78,43.08 263.4,43.08 265.93,45.61 268.48,45.61 269.23,44.87 274.6,44.87 276.57,42.9 277.65,42.9 278.64,41.9 278.64,39.87 281.79,36.73 287.32,36.73 289.01,35.04 289.01,34.76 288.7,34.45 JNGFF1.65
CNV_PTX_DRX_N1: length 157
  IN3 w0.089: v1(262.3,40.23) 262.17,40.36 262.17,40.75 261.98,40.95 261.7,40.95 261.69,40.94 261.03,40.94 260.27,41.7 260.27,43.05 257.53,45.79 257.25,45.79 256.3,46.75 255.47,46.75 251.84,50.38 251.84,50.43 250.52,51.74 250.08,51.74 248.71,53.12 248.71,57.08 244.62,61.16 244.62,62.86 244.43,63.06 243.9,63.06 243.66,62.81 243.66,61.35 243.57,61.26 243.25,61.26 243.16,61.35 243.16,62.47 242.96,62.66 242.55,62.66 242.35,62.47 242.35,61.35 242.26,61.26 238.22,61.26 233.75,65.74 232.01,65.74 229.57,68.18 227.96,68.18 217.88,78.25 217.88,81.22 215.78,83.32 214,83.32 213.28,84.03 213.28,84.16 213.59,84.46 213.59,84.74 213.29,85.03 213.02,85.03 212.71,84.73 212.59,84.73 212.4,84.92 212.4,85.04 212.7,85.35 212.7,85.62 212.41,85.92 212.13,85.92 211.83,85.61 211.7,85.61 211.44,85.88 211.44,88.39 211.19,88.63 211.19,89.9 207.3,93.79 200.61,93.79 200.18,93.36 195.7,93.36 195.27,93.79 190.57,93.79 190.3,94.06 187.45,94.06 186.7,93.3 186.7,92.21 187.46,91.45 187.46,90.07 186.61,89.22 186.61,88.68 v1(187.03,88.26)
  BOTTOM w0.076: v1(187.03,88.26) 187.35,88.26 187.43,88.34 187.43,88.49 187.11,88.81 187.11,88.98 186.5,89.58 184.37,89.58 183.73,90.21 182.58,90.21 UC1.CP33
  BOTTOM w0.097: v1(262.3,40.23) 262.3,40.18 262.17,40.04 261.98,40.04 261.89,40.14 261.89,40.38 261.87,40.4 261.87,40.56 261.97,40.66 263.26,40.66 264.73,39.19 268.99,39.19 269.46,39.66 274.98,39.66 276.62,38.02 279.67,38.02 281.54,36.14 286.34,36.14 287.36,35.12 287.36,34.6 287.2,34.45 JNGFF1.59
CNV_PTX_DRX_P0: length 157
  IN3 w0.089: v1(261.56,42.58) 261.52,42.54 261.06,42.54 260.84,42.76 260.84,43.29 257.72,46.41 257.45,46.41 256.5,47.36 255.67,47.36 253.57,49.47 253.57,49.78 249.28,54.06 249.28,57.56 245.64,61.2 245.64,63.29 245.3,63.63 243.35,63.63 242.95,63.23 241.94,63.23 241.74,63.04 241.74,61.93 241.66,61.84 241.39,61.84 241.3,61.93 241.3,63.04 241.11,63.23 240.69,63.23 240.49,63.04 240.49,61.93 240.41,61.84 240.14,61.84 240.05,61.93 240.05,63.04 239.86,63.23 239.44,63.23 239.24,63.04 239.24,61.97 239.11,61.84 238.46,61.84 233.99,66.31 232.25,66.31 229.81,68.75 228.2,68.75 218.45,78.49 218.45,81.46 215.96,83.95 215.96,84.58 214.25,86.29 213.94,86.29 212.02,88.22 212.02,88.72 211.82,88.92 211.82,90.09 207.54,94.36 200.23,94.36 199.8,93.94 195.94,93.94 195.51,94.37 190.94,94.37 190.67,94.64 187.22,94.64 185.83,93.25 v1(185.83,90.64)
  BOTTOM w0.076: UC1.CM32 181.2,90.52 181.56,90.52 181.7,90.54 181.8,90.61 181.89,90.83 181.98,90.93 182.08,90.97 182.09,90.97 182.27,90.98 182.35,90.95 182.41,90.95 182.49,90.94 182.67,90.94 182.81,90.97 182.91,90.97 182.96,90.95 183.11,90.85 183.24,90.83 183.99,90.83 184,90.83 184.25,91.07 185.95,91.07 186.04,90.98 186.04,90.83 185.85,90.64 v1(185.83,90.64)
  BOTTOM w0.097: v1(261.56,42.58) 262.02,42.58 262.71,43.27 263.32,43.27 265.85,45.8 268.56,45.8 269.31,45.05 274.68,45.05 276.64,43.08 277.72,43.08 278.83,41.98 278.83,39.95 281.87,36.91 287.4,36.91 289.2,35.11 JNGFF1.67
CNV_PTX_DRX_P1: length 157
  IN3 w0.089: v1(261.48,40.21) 261.52,40.17 261.81,40.17 261.9,40.26 261.9,40.4 261.99,40.49 261.99,40.68 261.9,40.77 261.77,40.77 261.77,40.76 260.95,40.76 260.09,41.62 260.09,42.98 257.45,45.61 257.18,45.61 256.23,46.57 255.4,46.57 251.66,50.31 251.66,50.35 250.45,51.56 250.01,51.56 248.53,53.04 248.53,57 244.44,61.09 244.44,62.79 244.35,62.88 243.98,62.88 243.84,62.74 243.84,61.28 243.64,61.08 243.17,61.08 242.98,61.28 242.98,62.39 242.89,62.48 242.62,62.48 242.53,62.39 242.53,61.28 242.34,61.08 238.15,61.08 233.67,65.56 231.94,65.56 229.5,67.99 227.88,67.99 217.7,78.18 217.7,81.14 215.7,83.14 213.92,83.14 213.1,83.96 213.1,84.23 213.41,84.54 213.41,84.66 213.22,84.85 213.09,84.85 212.79,84.55 212.51,84.55 212.22,84.84 212.22,85.12 212.52,85.42 212.52,85.55 212.33,85.74 212.21,85.74 211.9,85.43 211.63,85.43 211.26,85.8 211.26,88.31 211.01,88.56 211.01,89.82 207.23,93.61 200.68,93.61 200.26,93.18 195.63,93.18 195.2,93.61 190.49,93.61 190.22,93.88 187.53,93.88 186.88,93.23 186.88,92.29 187.64,91.53 187.64,89.99 186.79,89.14 186.79,88.91 186.79,88.75 186.88,88.66 187.17,88.66 v1(187.47,88.96)
  BOTTOM w0.076: UC1.CN33 182.44,90.41 182.61,90.41 182.64,90.38 183.8,90.38 184.43,89.75 186.57,89.75 187.36,88.96 v1(187.47,88.96)
  BOTTOM w0.097: v1(261.48,40.21) 261.68,40.41 261.68,40.64 261.89,40.84 263.34,40.84 264.8,39.38 268.91,39.38 269.38,39.85 275.05,39.85 276.69,38.2 279.75,38.2 281.62,36.33 286.41,36.33 287.54,35.2 287.54,34.6 287.7,34.45 JNGFF1.61
CNV_RF_RESET#: length 143.4
  TOP w0.102: 183.93,92.22 181.13,92.22 180.12,91.21 v1(180.12,90.46)
  TOP w0.107: 183.93,92.22 184.38,92.22 184.38,92.22 186,92.22 187.73,93.95 189.46,93.95 189.92,93.48 190.42,93.48 RC640.2
  IN1 w0.089: v1(180.12,90.46) 180.8,89.79 183.59,89.79 184.02,89.36 184.02,89.08 185.86,87.23 186.82,87.23 187.81,86.25
  IN1 w0.099: v1(266.67,41.76) 265.62,42.81 265.62,55.38 v1(266.02,55.79) ; 187.81,86.25 187.82,86.24 v1(188.08,86.24)
  IN2 w0.102: v1(188.08,86.24) 188.08,85.29 187.27,84.48 187.27,83.52 187.73,83.07 188.93,83.07 192.53,79.47 196.29,79.47 198.82,76.95 205.86,76.95 206.59,77.67 210.15,77.67 210.53,77.29 215.29,77.29 216.33,76.25 218.56,76.25 223.77,71.04 223.77,69.35 226.94,66.18 228.73,66.18 230.99,63.92 232.45,63.92 232.66,63.7 234.15,62.21 246.8,62.21 v1(248.57,60.45)
  BOTTOM w0.089: UC1.CJ32 179.83,90.6 v1(180.12,90.46)
  BOTTOM w0.107: v1(248.57,60.45) 249.74,60.45 251.84,58.35 259.36,58.35 261.92,55.79 v2(264.85,55.79) v1(266.02,55.79) ; JNGFF1.10 274.95,41.92 274,42.87 270.44,42.87 269.41,41.84 268.09,41.84 QZ17.2 267.08,42.34 267.08,42.16 v1(266.67,41.76)
CNV_RGI_PRX_DTX: length 123.7
  TOP w0.107: RC733.1 263.35,42.67 v1(262.95,42.67)
  IN3 w0.102: v1(262.95,42.67) 262.95,44.3 261.83,45.41 261.11,45.41 256.67,49.85 256.67,49.86 255.9,50.63 254.88,50.63 250.66,54.84 250.66,59.16 249.39,60.44 249.39,63.6 247.43,65.56 238.78,65.56 237.31,67.03 235.88,67.03 234.23,68.68 234.1,68.68 229.21,73.57 225.9,73.57 220.73,78.74 220.73,79.51 220.34,79.9 220.34,80.22 220.82,80.71 220.82,81.62 219.77,82.67 219.77,84.37 216.92,87.22 216.92,87.5 215.01,89.42 215.01,89.49 214.16,90.34 214.16,91.32 207.45,98.03 205.23,98.03 204.74,97.55 199.96,97.55 199.47,98.03 192.58,98.03 191.91,98.69 188.93,98.69 188.29,98.05 184.77,98.05 184.24,98.58 180.82,98.58 180.61,98.36 179.67,98.36 v1(179.34,98.7)
  BOTTOM w0.076: UC1.CH19 v1(179.34,98.7)
  BOTTOM w0.107: RZ1383.2 v2(265.93,44.02) 265.01,43.11 264,43.11 263.57,42.67 v1(262.95,42.67)
CNV_RGI_PRX_DTX_R: length 18.1
  TOP w0.107: v1(268.6,44.92) v2(268.6,45.67) 268.6,45.97 269.09,46.47 v1(269.51,46.47)
  BOTTOM w0.107: v1(269.51,46.47) 269.64,46.34 274.79,46.34 277.06,44.08 280.4,44.08 281.03,43.44 281.03,41.92 280.95,41.84 JNGFF1.34 ; RZ1383.1 268.36,45.16 v1(268.6,44.92)
CNV_RGI_PTX_DRX: length 21.4
  TOP w0.107: RC710.2 197.33,96.24 v2(196.99,96.58) 196.73,96.84 v1(196.73,97.08)
  IN3 w0.102: v1(178.76,98.7) 179.27,98.19 180.75,98.19 180.92,98.35 184.22,98.35 184.7,97.87 189.28,97.87 189.57,97.58 190.98,97.58 191.11,97.71 192.32,97.71 192.41,97.62 196.19,97.62 v1(196.73,97.08)
  BOTTOM w0.076: UC1.CG19 178.29,99.16 v1(178.76,98.7)
CNV_RGI_PTX_DRX_R: length 126.5
  TOP w0.107: v1(199.65,96.28) 199.62,96.24 RC710.1 198.92,96.24 RC832.1 RC842.1
  IN1 w0.099: v1(199.65,96.28) 199.65,95.86 200.17,95.34 214.33,95.34 215.64,96.65 220.2,96.65 220.46,96.38 222.15,96.38 223.42,97.65 224.84,97.65 226.38,99.19 227.57,99.19 228.51,100.12 v1(235.78,100.12)
  IN3 w0.102: v1(235.78,100.12) 235.78,97.28 237.75,95.31 237.75,92.88 238.6,92.04 238.6,87.43 239.59,86.44 241.34,86.44 242.03,85.74 242.03,84.62 243.43,83.22 243.43,82.75 245.6,80.59 247.02,80.59 247.88,81.45 249.38,81.45 249.71,81.12 252.76,81.12 254.25,79.63 255.05,79.63 262,72.68 262,72.08 263.86,70.21 263.86,66.53 265.74,64.65 265.74,59.19 268.45,56.49 268.45,55.22 272.73,50.94 273.11,50.57 273.11,48.41 278.56,42.96 v1(280.07,42.96)
  BOTTOM w0.107: v1(280.07,42.96) 279.98,42.87 279.98,42.21 280.45,41.74 JNGFF1.32
CNV_WT_RCOMP: length 7.7
  BOTTOM w0.2: RC448.2 188.58,89.8 188.02,89.8 v2(187.64,90.18) 184.32,90.18 183.89,90.6 182.92,90.6 UC1.CR32 182.81,90.7 UC1.CP32
CNVI_EN#: length 119.3
  TOP w0.107: RC868.2 199.56,82.71 v1(199.59,82.74) ; v1(243.4,102.54) 243.4,102.83 242.34,103.9 242.34,105.88 245.46,109 247.48,109 248.15,109.67 248.15,114.08 250.24,116.17 v2(257.01,116.17) 259.15,116.17 259.95,115.37 259.95,113.71 261.89,111.77 261.89,110.49 261.5,110.09 RZ827.1
  IN1 w0.089: 187.81,87.74 185.97,87.74 184.45,89.27 184.45,89.43 183.76,90.12 181.36,90.12 180.16,91.32 179.75,91.32 179.42,91.65 v1(179.12,91.65)
  IN1 w0.099: 187.81,87.74 188.31,87.74 188.92,87.13 188.92,85.38 191.27,83.03 194.78,83.03 195.71,83.97 198.36,83.97 v1(199.59,82.74) 200.27,82.74 201.58,81.43 203.56,81.43 204.29,82.15 207.17,82.15 207.67,82.65 207.67,83.63 208.34,84.3 208.34,84.87 211.09,87.62 212.52,89.05 213.23,89.05 213.42,89.24 216.85,89.24 219.75,92.15 221.19,92.15 222.96,90.37 225.57,90.37 228.6,93.4 232.57,93.4 235.15,95.99 237.57,95.99 238.63,97.05 239.92,97.05 241.46,98.59 241.46,99.05 242.18,99.77 242.46,100.05 242.46,101.59 v1(243.4,102.54)
  BOTTOM w0.076: v1(179.12,91.65) 178.79,91.98 UC1.CH30
COMP_A_GT: length 4.5
  TOP w0.203: PU602.16 89.92,92.62 89.81,92.5 89.81,92.5 v1(89.82,92.5)
  BOTTOM w0.107: v1(89.82,92.5) 90.25,92.06 v2(90.62,92.06)
  BOTTOM w0.254: PC636.2 90.18,93.67 PR639.2 90.18,92.86 v1(89.82,92.5)
COMP_B_IA: length 5.2
  TOP w0.203: PU602.4 86.14,97.32 v1(85.87,97.59)
  BOTTOM w0.107: PC616.2 85.67,95.79 v2(85.67,95.02)
  BOTTOM w0.254: PC616.2 86.6,96.72 PR617.2 85.89,97.61 v1(85.87,97.59)
COMP_C_SA: length 3.5
  TOP w0.203: PU602.24 93.31,96.12 v1(93.49,95.93)
  BOTTOM w0.107: v2(93.91,95.58) 93.85,95.58 v1(93.49,95.93)
  BOTTOM w0.254: v1(93.49,95.93) 93.62,96.06 PR630.1 93.54,96.7 PC628.1
COMP_CHG: length 3.2
  BOTTOM w0.203: PC749.1 84.23,50.81 v2(84.23,49.76) 84.23,49.35 84.14,49.25 PU700.28
  BOTTOM w0.254: PC749.1 84.2,50.85 PR728.1
CONTACTLESS_DET#: length 144.4
  TOP w0.107: v1(198.81,81.29) 199.26,80.85 RC278.1 ; DZ8.2 224.54,34.32 v2(224.68,34.18) 225.18,33.69 229.51,33.69 230.04,33.15 230.04,29.77 230.28,29.53 235.33,29.53 236.02,30.22 236.02,40.02 v1(237.49,41.48)
  IN1 w0.099: v1(198.81,81.29) 198.44,81.67 190.7,81.67 187.9,84.48 187.68,84.48 187.03,85.13 187.03,85.13 186.38,85.78 185.05,85.78 v1(183.89,86.94)
  IN2 w0.102: v1(237.49,41.48) 237.49,41.48 237.95,41.95 243.72,41.95 244.25,42.47 247.29,42.47 247.37,42.38 248.7,42.38 249.04,42.72 249.04,46.34 249.61,46.91 249.61,50.67 249.44,50.84 249.44,61.66 247.44,63.66 245.94,63.66 245.5,64.11 242.98,64.11 242.6,63.73 237.66,63.73 237.05,64.34 233.31,64.34 230.36,67.28 227.62,67.28 225.35,69.55 225.35,71.45 219.87,76.93 216.62,76.93 215.44,78.12 210.67,78.12 209.84,78.95 206.31,78.95 205.88,79.39 201.16,79.39 199.25,81.29 v1(198.81,81.29)
  BOTTOM w0.076: v1(183.89,86.94) 183.89,87.51 183.69,87.71 183.28,87.71 183.23,87.77 182.79,87.77 182.54,88.01 181.45,88.01 181.26,88.21 181.26,88.44 181.56,88.74 UC1.CN35
CONTACTLESS_DET#_R: length 4.7
  TOP w0.107: v2(224.29,39.33) v1(224.29,38.62) 224.29,37.75 DZ8.1
  BOTTOM w0.107: JUSH1.4 225.78,39.09 225.03,38.34 224.57,38.34 v1(224.29,38.62)
CORE_VID0: length 204.5
  TOP w0.254: PR408.1 v2(213.16,124.86) 213.16,124.66 211.64,123.14 211.64,122.89 v1(211.6,122.86)
  IN1 w0.089: 180.68,80.68 180.68,81.15 179.9,81.94 177.97,81.94 176.65,83.26 176.09,83.26 175.69,83.66 v1(175.69,84.17)
  IN1 w0.099: v1(220.98,70.75) 220.98,72.8 219.02,74.77 217.22,74.77 216.67,74.21 214.52,74.21 214.32,74.01 202.78,74.01 202.34,73.58 197.28,73.58 197.04,73.82 197.04,75 196.05,75.99 189.27,75.99 188.45,76.81 185.58,76.81 185.04,77.35 182.74,77.35 182.06,78.03 182.06,78.61 180.68,79.98 180.68,80.68
  BOTTOM w0.076: UC1.CB36 175.7,87.94 175.7,87.34 175.86,87.18 175.86,85.59 176.21,85.24 176.21,84.69 v1(175.69,84.17)
  BOTTOM w0.107: v1(211.6,122.86) 225.62,122.86 230.6,117.88 240.4,117.88 242.28,116 247.91,116 249.13,117.21 260.84,117.21 264.32,113.74 264.32,107.22 263.68,106.59 263.68,101.21 264.48,100.42 264.48,99.75 264.91,99.31 264.91,94.78 265.99,93.71 265.99,89.46 263.93,87.4 263.93,86.12 262.38,84.57 256.86,84.57 254.65,82.36 253.74,82.36 253.48,82.1 252.47,82.1 252.09,81.72 252.09,76.1 251.32,75.32 250.97,75.32 250.64,74.99 246.31,74.99 245.84,75.46 233.32,75.46 232.58,74.72 228.3,74.72 227.49,73.91 227.03,73.91 223.63,70.5 221.24,70.5 v1(220.98,70.75)
CORE_VID1: length 204.3
  TOP w0.254: v1(210.51,122.86) 210.45,122.92 210.45,123.28 210.88,123.71 v2(210.88,125.3) PR411.1
  IN1 w0.089: 180.45,80.68 180.45,80.77 180.46,80.78 180.46,81.14 179.83,81.77 177.91,81.77 176.59,83.09 176.02,83.09 175.31,83.8 v1(175.31,84.62)
  IN1 w0.099: v1(220.55,71.19) 220.55,71.37 219.75,72.17 197.74,72.17 196.56,73.36 196.56,74.75 195.86,75.45 188.59,75.45 187.71,76.34 183.44,76.34 181.83,77.94 181.83,78.51 180.45,79.89 180.45,80.68
  BOTTOM w0.076: UC1.CB35 175.4,88.44 175.4,88.21 175.36,88.1 175.36,87.95 175.54,87.46 175.54,87.27 175.7,87.11 175.7,85.52 176.05,85.17 176.05,84.88 175.79,84.62 v1(175.31,84.62)
  BOTTOM w0.107: v1(220.55,71.19) 223.99,71.19 226.94,74.14 227.39,74.14 228.2,74.96 232.49,74.96 233.23,75.69 245.94,75.69 246.41,75.22 250.54,75.22 250.9,75.58 251.24,75.58 251.59,75.92 251.59,78.88 251.19,79.27 251.19,81.15 252.37,82.33 253.38,82.33 253.64,82.59 254.55,82.59 256.18,84.22 256.18,85.17 256.8,85.78 259.17,85.78 259.82,85.13 261.33,85.13 265.76,89.56 265.76,91.97 265.11,92.62 265.11,94.26 264.68,94.69 264.68,99.22 264.25,99.65 264.25,100.32 263.45,101.12 263.45,106.68 264.08,107.31 264.08,113.64 260.77,116.96 249.2,116.96 248.01,115.77 242.18,115.77 240.31,117.64 228.98,117.64 224.54,122.08 211.17,122.08 210.51,122.75 v1(210.51,122.86)
CPU_C10_GATE: length 4.6
  TOP w0.107: v2(253.69,115.49) RE828.1 253.69,114.04 254.51,113.23 QE21.6 254.04,112.97 253.87,112.8 253.87,112.49 254.05,112.32 QE21.5
CPU_C10_GATE#: length 361.5
  TOP w0.107: v1(252.57,115.4) 253.17,114.81 253.17,112.46 253.03,112.32 QE21.2 ; RZ1420.1 194.33,122.17 195.33,123.17 195.33,123.76 195.17,123.92 v1(195.17,123.97)
  TOP w0.254: PR429.1 v1(106.48,70.05)
  IN1 w0.089: 187.81,94.39 186.72,94.39 185.69,93.36 v1(183.76,93.36)
  IN1 w0.099: v1(215.9,94.24) 215.4,94.24 214.96,93.8 196.94,93.8 196.7,94.05 196.7,94.64 196.52,94.82 195.7,94.82 195.28,94.39 187.81,94.39
  IN2 w0.102: v1(215.9,94.24) 216.82,94.24 220.51,90.56 221.17,90.56 221.71,91.11 230.53,91.11 231.33,90.31 231.33,90.26 232.43,89.15 232.43,81.96 233.48,80.91 233.48,80.59 236.42,77.66 v1(237.22,77.66)
  IN3 w0.102: v1(108.77,80.46) 108.77,79.07 107.69,77.99 107.69,71.26 v1(106.48,70.05)
  BOTTOM w0.076: v1(183.76,93.36) 183.38,93.36 183.08,93.05 181.97,93.05 181.87,93.16 UC1.CN27
  BOTTOM w0.107: v1(195.17,123.97) 195.17,123.92 195.6,123.49 200.43,123.49 200.91,123 208.83,123 210.99,120.84 224.02,120.84 227.69,117.17 238.6,117.17 240.47,115.3 v2(241.5,115.3) 248.2,115.3 249.4,116.49 251.48,116.49 v1(252.57,115.4) 252.92,115.4 254.01,116.49 260.57,116.49 263.61,113.45 263.61,107.65 262.98,107.02 262.98,100.1 264.21,98.86 264.21,94.49 264.62,94.08 264.62,90.51 264.12,90.01 264.12,88.59 261.79,86.25 256.61,86.25 255.72,85.36 255.72,84.42 254.36,83.06 253.41,83.06 253.15,82.8 252.18,82.8 250.69,81.31 250.69,79.43 248.06,76.8 238.49,76.8 237.63,77.66 v1(237.22,77.66) 236.98,77.66 236.43,77.11 233.08,77.11 232.03,76.06 227.75,76.06 226.93,75.24 226.48,75.24 223.71,72.47 219.39,72.47 218.18,71.26 209.57,71.26 207.88,69.56 180.75,69.56 178.83,71.48 174.8,71.48 173.72,72.56 169.38,72.56 168.41,71.6 166.46,71.6 162.15,75.9 127.6,75.9 123.33,80.17 114.91,80.17 114.04,81.04 111.56,81.04 110.99,80.46 v1(108.77,80.46)
CPU_C10_GATE#_Q: length 20.3
  TOP w0.089: UE1.K7 v1(254.45,95.81)
  TOP w0.107: QE21.3 252.48,111.54 RE829.1 252.48,109.64 v2(252.64,109.48) 252.85,109.27 v1(253.21,109.27)
  BOTTOM w0.089: v1(254.45,95.81) 254.45,96.24 254.86,96.64 255.28,96.64 255.66,97.03 255.66,98.5 255.81,98.65 255.81,99.24 255.83,99.25 255.83,99.68
  BOTTOM w0.107: v1(253.21,109.27) 253.21,108.5 254.31,107.4 254.31,106.63 254.82,106.12 254.82,105.68 257.48,103.02 257.48,102.51 255.83,100.85 255.83,99.68
CPU_DDPD_CTRL_CLK: length 21.2
  IN3 w0.102: v1(198.75,105.27) 198.59,105.1 196.79,105.1 195.67,106.23 190.71,106.23 190.29,105.81 190.15,105.81 189.68,106.28 186.84,106.28 185.31,107.82 v1(185.31,108.94)
  BOTTOM w0.089: UC1.CP4 182.29,108.25 182.94,108.25 183.42,108.74 185.11,108.74 v1(185.31,108.94)
  BOTTOM w0.107: v1(198.75,105.27) 198.75,105.23 198.6,105.08 198.15,105.08 197.91,104.85 197.75,104.85 RC438.1
CPU_DDPD_CTRL_DATA: length 22.1
  IN3 w0.102: v1(198.75,104.66) 198.53,104.87 196.69,104.87 195.57,106 190.8,106 190.39,105.58 190.06,105.58 189.58,106.06 186.75,106.06 184.97,107.83 184.97,108.4 184.58,108.8 v1(184.58,109.28)
  BOTTOM w0.089: v1(184.58,109.28) 183.33,109.28 182.94,108.88 182.61,108.88 182.44,108.71 181.86,108.71 UC1.CN4
  BOTTOM w0.107: v1(198.75,104.66) 198.56,104.85 198.24,104.85 198.01,104.62 197.77,104.62 RC437.1
CPU_DP1_CTRL_CLK: length 142.6
  TOP w0.107: UV21.38 293.95,89.72 v1(293.81,89.86)
  IN1 w0.099: v1(198.31,107.19) 198.42,107.07 198.58,107.07 198.84,107.33 201.99,107.33 203.1,106.22 216.05,106.22 216.43,105.84 227.36,105.84 228.07,106.55 242,106.55 244.11,108.67 244.92,108.67 245.39,109.14 246.34,109.14 247.37,108.11 256.08,108.11 257.1,107.1 258.05,107.1 262.95,102.2 262.95,102.08 263.73,101.3 264.66,101.3 265.11,100.85 265.11,100.21 265.4,99.92 265.4,95.85 265.87,95.39 266.23,95.39 267.93,93.69 267.93,89.38 268.27,89.04 268.74,89.04 v1(268.92,89.21)
  IN3 w0.089: 179.15,108.99 179.15,108.87 178.74,108.46 177.34,108.46 177.05,108.17 177.05,107.94 177.05,107.94 177.05,107.26 177.05,107.26 177.05,105.78 176.96,105.69 176.78,105.69 176.69,105.78 v1(176.69,105.92)
  IN3 w0.102: v1(198.31,107.19) 198.04,106.93 197.45,106.93 197.12,106.6 196.31,106.6 195.96,106.95 190.34,106.95 186.94,110.35 184.75,110.35 183.61,109.21 181.44,109.21 181.07,109.57 179.63,109.57 179.15,109.09 179.15,108.99
  BOTTOM w0.089: v1(176.69,105.92) UC1.CC8
  BOTTOM w0.107: v1(198.31,107.19) 197.74,106.63 RC503.1 ; v1(293.81,89.86) 293.61,90.06 293.61,90.26 293.37,90.51 290.18,90.51 288.98,89.3 281.18,89.3 280.64,88.76 273.72,88.76 273.44,89.04 269.09,89.04 v1(268.92,89.21)
CPU_DP1_CTRL_DATA: length 142.4
  TOP w0.107: v1(293.17,89.86) 293.55,89.48 UV21.39
  IN1 w0.099: v1(198.29,106.58) 198.29,106.69 198.39,106.78 198.47,106.78 198.53,106.85 198.68,106.85 198.93,107.1 201.9,107.1 203,105.99 215.96,105.99 216.34,105.61 227.45,105.61 228.17,106.33 242.09,106.33 244.21,108.44 245.01,108.44 245.49,108.91 246.25,108.91 247.28,107.88 255.99,107.88 257,106.87 257.95,106.87 262.72,102.1 262.72,101.99 263.64,101.07 264.56,101.07 264.88,100.75 264.88,100.12 265.18,99.82 265.18,95.76 265.77,95.16 266.14,95.16 267.7,93.6 267.7,89.29 268.18,88.81 268.74,88.81 v1(268.92,88.63)
  IN3 w0.089: v1(176.69,105.28) 176.69,105.42 176.78,105.51 177.03,105.51 177.23,105.71 177.23,107.34 177.23,107.34 177.23,108.02 177.23,108.09 177.41,108.28 178.81,108.28 179.37,108.84 179.37,108.98 179.38,108.98 179.38,108.99
  IN3 w0.102: 179.38,108.99 179.73,109.34 180.98,109.34 181.35,108.98 183.7,108.98 184.84,110.12 186.84,110.12 190.24,106.72 195.86,106.72 196.21,106.37 197.22,106.37 197.54,106.7 198.17,106.7 v1(198.29,106.58)
  BOTTOM w0.089: v1(176.69,105.28) UC1.CC9
  BOTTOM w0.107: v1(293.17,89.86) 293.38,90.06 293.38,90.17 293.27,90.27 290.28,90.27 289.07,89.06 281.28,89.06 280.73,88.52 273.62,88.52 273.34,88.81 269.09,88.81 v1(268.92,88.63) ; RC178.1 197.59,105.86 198.29,106.56 v1(198.29,106.58)
CPU_DP1_N0: length 167.4
  TOP w0.097: CV305.2 288.43,92.63 288.24,92.63 v1(288.04,92.43)
  IN1 w0.089: v1(288.04,92.43) 287.84,92.63 287.48,92.63 284.02,96.1 283.19,96.1 281.41,97.88 281.41,110.65 276.2,115.86 267.75,115.86 263.39,120.22 259.16,120.22 257.56,121.82 245.95,121.82 245.43,121.31 244.46,121.31 244.08,121.68 240.11,121.68 239.31,120.88 228.55,120.88 225.02,124.4 198.04,124.4 197.5,124.94 185.38,124.94 184.02,123.58 181.25,123.58 176.02,121.37 168.92,121.37 167.96,120.41 163.46,120.41 163.27,120.6 163.27,121.01 v1(163.04,121.24)
  IN3 w0.089: v1(163.04,121.24) 163.24,121.04 163.24,120.95 159.45,117.16 159.45,115.02 158.82,114.39 158.82,111.56 158.82,111.55 158.82,110.64 156.75,108.57 156.75,107.59 156.72,107.57 156.62,107.57 v1(156.37,107.82)
  BOTTOM w0.089: UC1.AL5 v1(156.37,107.82)
CPU_DP1_N1: length 169.6
  TOP w0.097: v1(287.81,90.65) 288.01,90.85 288.43,90.85 CV303.2
  IN1 w0.089: v1(161.46,121.07) 161.66,120.87 161.66,120.03 161.86,119.83 168.2,119.83 168.28,119.91 169.15,120.79 176.16,120.79 178.81,121.88 181.39,122.95 184.28,122.95 185.7,124.37 197.26,124.37 197.8,123.83 224.71,123.83 228.23,120.31 239.55,120.31 240.16,120.92 242.29,120.92 242.81,120.41 247.13,120.41 247.89,119.65 263.15,119.65 267.51,115.28 275.96,115.28 279.96,111.28 279.96,97.68 286.79,90.85 287.61,90.85 v1(287.81,90.65)
  IN3 w0.089: v1(155.45,107.81) 155.45,107.57 155.56,107.47 155.68,107.47 155.83,107.61 155.83,108.41 157.42,110 157.42,110.67 157.42,110.67 158.19,111.44 158.19,114.59 158.67,115.07 158.67,115.07 158.81,115.21 158.81,117.42 161.66,120.28 161.66,120.87 v1(161.46,121.07)
  BOTTOM w0.089: UC1.AJ5 155.42,107.82 v1(155.45,107.81)
CPU_DP1_N2: length 176.2
  TOP w0.097: CV301.2 288.43,83.04 288.01,83.04 v1(287.81,82.84)
  IN1 w0.089: v1(287.81,82.84) 287.61,83.04 287.11,83.04 285.81,84.34 285.81,91.02 279.38,97.44 279.38,111.04 275.72,114.71 267.27,114.71 262.91,119.07 246.39,119.07 245.76,119.71 242.5,119.71 241.86,120.35 240.4,120.35 239.78,119.73 227.99,119.73 224.47,123.26 191.36,123.26 191.08,123.54 185.83,123.54 184.67,122.38 181.5,122.38 175.25,119.79 170,119.79 169.47,119.26 161.49,119.26 160.92,119.82 160.64,119.82 v1(160.5,119.68)
  IN3 w0.089: v1(153.57,107.14) 153.55,107.43 153.73,107.64 153.87,107.64 154.16,107.95 154.16,108.25 155.07,109.16 155.89,109.16 156.89,110.16 156.89,110.93 157.78,111.82 157.78,113.45 157.78,114.74 158.35,115.31 158.35,117.54 160.03,119.21 160.03,119.8 160.12,119.89 160.3,119.89 v1(160.5,119.68)
  BOTTOM w0.089: UC1.AF6 153.18,106.95 v1(153.57,107.14)
CPU_DP1_N3: length 181.2
  TOP w0.097: CV307.2 288.42,81.27 288.04,81.27 v1(287.84,81.07)
  IN1 w0.089: v1(287.84,81.07) 287.67,81.25 287.2,81.25 285.23,83.21 285.23,88.28 281.23,92.29 281.23,94.79 278.81,97.2 278.81,110.58 275.8,113.58 268.95,113.58 268.44,114.09 267.08,114.09 262.67,118.5 245.97,118.5 245.54,118.92 240.66,118.92 240.43,119.16 227.75,119.16 224.69,122.22 191.59,122.22 190.84,122.97 186.07,122.97 184.91,121.8 181.62,121.8 175.36,119.21 170.38,119.21 169.85,118.68 160.06,118.68 159.01,119.73 159.01,120.4 v1(159.47,120.87)
  IN3 w0.089: v1(152.59,107.9) 152.6,107.67 152.7,107.58 152.84,107.58 152.96,107.7 152.96,108.16 152.66,108.46 152.66,109.05 153.18,109.57 153.81,109.57 154.5,110.26 154.5,111.21 154.8,111.5 156.32,111.5 156.78,111.96 156.78,111.96 156.98,112.16 156.98,115.11 157.59,115.72 157.59,117.84 159.01,119.26 159.01,120.4 v1(159.47,120.87)
  BOTTOM w0.089: UC1.AE5 152.26,107.75 v1(152.59,107.9)
CPU_DP1_P0: length 167.4
  TOP w0.097: CV304.2 288.43,92.81 288.24,92.81 v1(288.04,93.01)
  IN1 w0.089: v1(163.62,121.24) 163.58,121.24 163.45,121.1 163.45,120.68 163.54,120.59 167.89,120.59 168.85,121.55 175.99,121.55 181.22,123.76 183.94,123.76 185.31,125.12 197.57,125.12 198.11,124.58 225.1,124.58 228.62,121.06 239.23,121.06 240.03,121.86 244.16,121.86 244.53,121.49 245.36,121.49 245.88,122 257.64,122 259.24,120.4 263.46,120.4 267.82,116.04 276.27,116.04 281.59,110.72 281.59,97.96 283.27,96.28 284.09,96.28 287.56,92.81 287.84,92.81 v1(288.04,93.01)
  IN3 w0.089: v1(156.37,107.13) 156.62,107.39 156.8,107.39 156.93,107.52 156.93,108.49 159,110.57 159,114.31 159.63,114.94 159.63,117.09 163.42,120.87 163.42,120.95 163.42,121.04 v1(163.62,121.24)
  BOTTOM w0.089: v1(156.37,107.13) 155.97,106.95 UC1.AL6
CPU_DP1_P1: length 169.4
  TOP w0.097: CV302.2 288.43,91.04 288.01,91.04 v1(287.81,91.23)
  IN1 w0.089: v1(287.81,91.23) 287.61,91.03 286.86,91.03 280.14,97.76 280.14,111.36 276.03,115.46 267.59,115.46 263.22,119.83 247.97,119.83 247.21,120.59 242.88,120.59 242.37,121.1 240.09,121.1 239.47,120.49 228.3,120.49 224.78,124.01 197.87,124.01 197.33,124.55 185.62,124.55 184.2,123.13 181.35,123.13 176.13,120.97 169.08,120.97 168.2,120.09 168.12,120.01 161.93,120.01 161.84,120.1 161.84,120.87 v1(162.04,121.07)
  IN3 w0.089: v1(155.45,107.08) 155.66,107.29 155.76,107.29 156,107.54 156,108.34 157.59,109.93 157.59,110.59 158.37,111.36 158.37,114.52 158.79,114.94 158.8,114.94 158.99,115.13 158.99,117.35 161.84,120.2 161.84,120.87 v1(162.04,121.07)
  BOTTOM w0.089: v1(155.45,107.08) 155.43,107.09 155.09,106.93 UC1.AJ6
CPU_DP1_P2: length 176.1
  TOP w0.097: v1(287.81,83.42) 288.01,83.22 288.43,83.22 CV300.2
  IN1 w0.089: v1(287.81,83.42) 287.61,83.22 287.18,83.22 285.99,84.41 285.99,91.09 279.56,97.52 279.56,111.12 275.79,114.89 267.35,114.89 262.98,119.26 246.46,119.26 245.83,119.89 242.58,119.89 241.93,120.53 240.33,120.53 239.71,119.91 228.07,119.91 224.54,123.44 191.44,123.44 191.15,123.72 185.76,123.72 184.59,122.56 181.47,122.56 175.21,119.97 169.93,119.97 169.4,119.44 161.56,119.44 161,120 160.77,120 v1(160.5,120.27)
  IN3 w0.089: v1(153.5,107.91) 153.63,107.81 153.79,107.82 153.98,108.02 153.98,108.32 155,109.34 155.82,109.34 156.71,110.23 156.71,111.01 157.6,111.9 157.6,113.45 157.6,113.45 157.6,114.82 158.17,115.39 158.17,117.61 159.85,119.29 159.85,119.87 160.04,120.07 160.3,120.07 v1(160.5,120.27)
  BOTTOM w0.089: v1(153.5,107.91) 153.4,107.95 153.16,107.84 153.1,107.69 UC1.AF5
CPU_DP1_P3: length 181.1
  TOP w0.097: CV306.2 288.44,81.46 288.04,81.46 v1(287.84,81.66)
  IN1 w0.089: v1(159.89,120.46) 159.87,120.47 159.33,120.47 159.19,120.33 159.19,119.81 160.13,118.86 169.77,118.86 170.3,119.39 175.33,119.39 181.58,121.98 184.83,121.98 185.99,123.15 190.91,123.15 191.66,122.4 224.77,122.4 227.83,119.34 240.5,119.34 240.74,119.1 245.62,119.1 246.04,118.68 262.75,118.68 267.16,114.27 268.52,114.27 269.02,113.76 275.88,113.76 278.99,110.65 278.99,97.28 281.41,94.86 281.41,92.36 285.42,88.36 285.42,83.29 287.28,81.43 287.61,81.43 v1(287.84,81.66)
  IN3 w0.089: v1(159.89,120.46) 159.32,120.46 159.19,120.33 159.19,119.19 157.77,117.77 157.77,115.65 157.16,115.03 157.16,112.09 156.9,111.83 156.9,111.83 156.4,111.33 154.87,111.33 154.68,111.14 154.68,110.18 153.89,109.39 153.25,109.39 152.84,108.98 152.84,108.53 153.14,108.23 153.14,107.63 152.91,107.4 152.71,107.4 152.63,107.31 v1(152.64,107.17)
  BOTTOM w0.089: UC1.AE6 v1(152.64,107.17)
CPU_DP2_AUXN: length 147
  TOP w0.097: RC731.2 149.87,115.9 150.74,115.9 150.89,116.05 v1(150.89,116.19)
  IN1 w0.089: v1(150.89,116.19) 150.64,115.89 150.55,115.89 150.31,115.89 149.92,116.28 149.92,117.42 148.98,118.36 146.44,118.36 144.28,120.52 140.73,120.52 139.56,121.7 135.15,121.7 134.99,121.85 134.99,121.85 134.51,122.33 123.53,122.33 122.01,120.8 118.13,120.8 117.44,121.49 101.62,121.49 99.77,123.34 85.77,123.34 83.83,121.4 79.05,121.4 74.94,117.28 68.12,117.28 64.38,113.55 54.08,113.55 52.2,111.67 52.2,107.08 52.12,107 51.82,107 v1(51.62,107.2)
  IN3 w0.089: v1(40.03,95.98) 40.03,96.68 40.35,97.01 44.26,97.01 45.16,97.9 48.34,97.9 50.86,100.42 50.86,106.93 51.08,107.14 51.56,107.14 v1(51.62,107.2)
  BOTTOM w0.076: UC1.AD4 151.97,108.72 152.24,109.23 152.24,109.5 152.11,109.87 152.11,111.82 151.82,112.11 151.82,115.83 151.64,116 150.97,116 150.89,116.07 v1(150.89,116.19)
  BOTTOM w0.097: CT81.1 52.7,107 51.82,107 v1(51.62,107.2) ; CT116.1 40.23,96.36 40.23,96.18 v1(40.03,95.98)
CPU_DP2_AUXN_C: length 5.6
  BOTTOM w0.076: UT5.J2 58.08,106.06 57.55,106.06 56.61,106.99 56.09,106.99 56.08,107 56.07,107
  BOTTOM w0.097: CT81.2 53.71,107.02 53.98,107.02 RT95.1 54.51,107 56.07,107
CPU_DP2_AUXN_C_MUX: length 4.3
  TOP w0.097: v1(39.92,98.7) 40.12,98.5 40.12,98.25 40.23,98.15 40.23,97.97 RT131.1
  BOTTOM w0.097: RT131.1 40.23,97.97 40.23,98.14 40.12,98.24 40.12,98.5 v1(39.92,98.7) 40.12,98.9 40.12,99.13 40.29,99.3 40.29,99.54 40.21,99.63 UT9.32
CPU_DP2_AUXP: length 147
  TOP w0.097: v1(150.94,115.46) 150.69,115.71 149.81,115.71 149.55,115.45 RC732.2
  IN1 w0.089: v1(150.94,115.46) 150.65,115.71 150.55,115.71 150.24,115.71 149.74,116.2 149.74,117.35 148.9,118.18 146.37,118.18 144.21,120.34 140.66,120.34 139.48,121.52 135.07,121.52 134.92,121.67 134.91,121.67 134.44,122.15 123.61,122.15 122.08,120.62 118.05,120.62 117.37,121.31 101.55,121.31 99.7,123.16 85.84,123.16 83.91,121.22 79.13,121.22 75.01,117.1 68.19,117.1 64.46,113.37 54.16,113.37 52.38,111.59 52.38,107.01 52.19,106.82 51.82,106.82 v1(51.62,106.62)
  IN3 w0.089: v1(51.62,106.62) 51.62,106.64 51.3,106.96 51.15,106.96 51.04,106.85 51.04,100.34 48.42,97.72 45.23,97.72 44.34,96.83 40.43,96.83 40.21,96.61 40.21,96.38 v1(40.61,95.98)
  BOTTOM w0.076: UC1.AD3 151.93,109.29 151.79,109.29 151.69,109.39 151.69,109.65 151.73,109.69 151.87,109.69 151.95,109.77 151.95,111.75 151.65,112.04 151.65,115.76 151.58,115.83 150.82,115.83 150.72,115.73 150.72,115.53 150.79,115.46 v1(150.94,115.46)
  BOTTOM w0.097: v1(51.62,106.62) 51.82,106.82 52.7,106.82 CT80.1 ; CT115.1 40.41,96.36 40.41,96.18 v1(40.61,95.98)
CPU_DP2_AUXP_C: length 5
  BOTTOM w0.076: UT5.J1 57.47,105.81 56.46,106.82 56.09,106.82 56.08,106.81 56.07,106.81
  BOTTOM w0.097: 56.07,106.81 54.5,106.81 RT96.1 53.98,106.79 53.71,106.79 CT80.2
CPU_DP2_AUXP_C_MUX: length 4.3
  TOP w0.097: v1(40.51,98.7) 40.31,98.5 40.31,98.33 40.41,98.22 40.41,97.97 RT130.1
  BOTTOM w0.097: UT9.31 40.56,99.63 40.47,99.54 40.47,99.22 40.31,99.05 40.31,98.9 v1(40.51,98.7) 40.31,98.5 40.31,98.32 40.41,98.22 40.41,97.97 RT130.1
CPU_DP2_CTRL_CLK: length 5.2
  BOTTOM w0.076: UC1.CH4 178.83,108.94 178.58,109.19 178.58,109.36 178.53,109.41 178.58,109.46 178.58,109.49 178.62,109.53 178.62,110.19 178.62,110.2 178.62,110.95 178.9,111.23 178.9,113.26 RC176.1
CPU_DP2_CTRL_DATA: length 4.5
  BOTTOM w0.076: UC1.CH3 178.83,109.34 178.76,109.41 178.78,109.43 178.78,110.12 178.79,110.13 178.79,110.88 179.07,111.16 179.07,113.22 RC502.1
CPU_DP2_HPD: length 258.1
  TOP w0.107: RT73.2 60.14,99.32 56.58,99.32 v2(55.01,97.75) 52.69,95.43 46.4,95.43 45.62,94.65 37.1,94.65 36.12,95.63 36.12,99.16 v1(34.48,100.8)
  IN2 w0.102: v1(186.94,109.04) 186.05,109.04 185.61,109.48 185.61,112.85 186.36,113.61 186.36,115.24 187.41,116.29 187.41,116.51 187.52,116.63 187.52,117.63 189.95,120.05 189.95,122.64 190.51,123.19 190.51,127.98 190.09,128.39 186.29,128.39 184.74,126.85 161.66,126.85 161.02,126.21 159.41,126.21 159.12,125.91 154.47,125.91 154.26,125.7 148.72,125.7 147.17,127.25 140.69,127.25 140.09,126.65 124.8,126.65 123.9,127.56 121.74,127.56 119.76,125.58 116.84,125.58 114.58,127.85 112.83,127.85 110.36,125.37 103.57,125.37 98.25,120.04 97.77,120.04 97.25,120.56 97.25,120.83 93.33,124.75 75.48,124.75 73.83,126.4 63.97,126.4 53.28,115.7 53.28,111.21 53.82,110.66 53.82,107.75 52.49,106.42 52.49,101.34 46.58,95.44 43.86,95.44 43.37,95.93 43.37,96.85 42,98.21 39.18,98.21 38.76,98.63 36.83,98.63 34.65,100.8 v1(34.48,100.8)
  BOTTOM w0.076: 186.72,109.04 186.61,109.04 186.26,108.69 186.26,108.08 184.97,106.78 183.18,106.78 182.6,106.99 182.4,106.99 182.4,106.99 182.28,106.95 182.1,106.95 181.98,106.99 181.75,106.99 181.63,106.95 181.08,106.95 UC1.CM6
  BOTTOM w0.107: 186.72,109.04 v1(186.94,109.04) 187.19,108.79 187.19,108.47 187.67,107.99 188.05,107.99 188.53,107.52 RC6.2 ; RT380.1 v1(34.48,100.8)
CPU_DP2_N0: length 128.1
  IN3 w0.089: v1(150.24,111.1) 150.04,111.3 149.7,111.3 148.6,110.2 142.16,110.2 141.53,110.83 140.26,110.83 139.89,111.2 137.54,111.2 135.22,113.52 135.22,113.52 134.62,114.12 134.62,114.94 133.6,115.96 133.29,115.96 133.29,115.96 133.14,115.96 131.01,118.09 124.31,118.09 123.86,117.64 112.17,117.64 108.73,121.08 101.49,121.08 100.45,122.12 95.83,122.12 93.62,124.34 67.23,124.34 64.5,121.6 58.21,121.6 49.32,112.7 49.32,105.85 47.6,104.12 47.24,104.12 v1(47.04,103.92)
  BOTTOM w0.076: v1(150.24,111.1) 150.24,111.18 150.51,111.45 150.76,111.45 151.12,111.1 151.12,110.69 150.99,110.57 150.99,110.19 151.02,110.12 151.03,110.09 151.03,109.88 150.99,109.78 150.99,109.53 151.14,109.19 151.14,108.89 151.42,108.61 UC1.AC4
  BOTTOM w0.097: v1(47.04,103.92) 46.84,104.12 46.65,104.12 CT104.1
CPU_DP2_N0_C: length 3.1
  BOTTOM w0.097: UT9.18 43.3,103.63 43.38,103.71 44.2,103.71 44.61,104.12 45.03,104.12 CT104.2
CPU_DP2_N1: length 137.5
  IN3 w0.089: v1(150.36,114.12) 149.73,114.12 148.04,112.43 141.41,112.43 139.42,114.42 139.42,115.92 137.98,117.36 137.98,118.56 137.24,119.3 133.03,119.3 132.18,120.15 114.83,120.15 110.63,124.36 96.29,124.36 94.14,126.5 84.83,126.5 83.8,127.53 63.95,127.53 61.87,125.45 57.62,125.45 45.92,113.75 45.92,102.34 46.11,102.14 v1(47.05,102.14)
  BOTTOM w0.076: v1(150.36,114.12) 150.36,114.04 150.02,113.7 149.89,113.7 149.72,113.53 149.72,112.97 151.62,111.07 151.62,110.93 151.53,110.84 151.53,110.73 151.62,110.64 151.62,110.37 151.54,110.3 151.44,110.3 UC1.AC1
  BOTTOM w0.097: CT106.1 46.65,102.34 46.85,102.34 v1(47.05,102.14)
CPU_DP2_N1_C: length 3
  BOTTOM w0.097: UT9.21 43.3,102.58 43.38,102.66 43.88,102.66 43.91,102.62 44.45,102.62 44.73,102.34 45.03,102.34 CT106.2
CPU_DP2_N2: length 135.7
  IN3 w0.089: v1(48.5,100.37) 48.7,100.57 49.37,100.57 50.47,101.66 50.47,111.26 59.51,120.3 64.82,120.3 67.17,122.65 75.01,122.65 75.32,122.96 79.47,122.96 79.83,122.6 81.09,122.6 81.44,122.25 83.35,122.25 83.74,121.86 84.51,121.86 85.72,123.07 93.2,123.07 95.35,120.93 96.45,120.93 97.8,119.58 99.5,119.58 100.08,119 108.84,119 111.43,116.41 127.21,116.41 130.38,116.41 133.3,113.49 133.31,113.49 137.87,108.93 141.11,108.93 141.37,109.19 150.64,109.19 152.79,111.34 152.79,112.26 152.88,112.35 153.03,112.35 v1(153.19,112.19)
  BOTTOM w0.076: UC1.AE4 152.82,108.88 152.82,109.19 152.97,109.53 152.97,109.78 152.94,109.88 152.94,110.09 152.98,110.21 152.98,110.53 152.81,110.69 152.81,112.04 152.7,112.16 152.7,112.27 152.77,112.34 153.11,112.34 153.19,112.27 v1(153.19,112.19)
  BOTTOM w0.097: CT108.1 46.65,100.57 48.3,100.57 v1(48.5,100.37)
CPU_DP2_N2_C: length 3.4
  BOTTOM w0.097: UT9.24 43.22,101.53 43.31,101.62 43.91,101.62 44.37,101.15 44.42,101.15 44.64,100.94 44.64,100.82 44.87,100.59 45.01,100.59 CT108.2
CPU_DP2_N3: length 139.6
  IN3 w0.089: v1(47.26,98.61) 47.47,98.82 47.7,98.82 48.04,99.16 48.04,103.43 49.89,105.28 49.89,111.49 59.42,121.02 64.73,121.02 66.93,123.22 74.77,123.22 75.13,123.58 80.92,123.58 81.65,122.84 84.64,122.84 85.56,123.76 93.32,123.76 95.58,121.51 99.48,121.51 101.29,119.7 109.11,119.7 111.74,117.07 124.1,117.07 124.55,117.52 129.89,117.52 130.41,116.99 131.23,116.99 132.83,115.39 132.83,115.02 134.33,113.52 134.33,113.52 137.28,110.56 137.92,110.56 138.42,110.07 141.21,110.07 141.59,109.69 150.37,109.69 152.11,111.43 152.12,111.43 152.21,111.53 152.21,113.62 152.78,114.18 152.89,114.18 v1(153.14,113.94)
  BOTTOM w0.076: UC1.AE1 152.52,110.31 152.44,110.39 152.44,111.95 152.36,112.03 152.36,113.96 152.7,114.3 153.4,114.3 153.49,114.2 153.49,113.94 153.41,113.86 153.22,113.86 v1(153.14,113.94)
  BOTTOM w0.097: CT110.1 46.65,98.79 47.09,98.79 v1(47.26,98.61)
CPU_DP2_N3_C: length 4.4
  BOTTOM w0.097: UT9.26 43.15,100.83 43.24,100.91 43.59,100.91 43.97,100.52 43.97,99.95 44.01,99.91 44.01,99.41 v4(44.44,98.98) 44.63,98.79 45.03,98.79 CT110.2
CPU_DP2_P0: length 128.1
  IN3 w0.089: v1(150.24,111.68) 150.03,111.48 149.63,111.48 148.52,110.37 142.24,110.37 141.6,111.01 140.33,111.01 139.96,111.38 137.61,111.38 134.8,114.19 134.8,115.02 133.67,116.14 133.22,116.14 131.09,118.27 124.23,118.27 123.79,117.82 112.24,117.82 108.8,121.26 101.57,121.26 100.53,122.3 95.91,122.3 93.69,124.52 67.16,124.52 64.42,121.78 58.14,121.78 49.14,112.78 49.14,105.92 47.52,104.3 47.24,104.3 v1(47.04,104.51)
  BOTTOM w0.076: v1(150.24,111.68) 150.3,111.62 150.41,111.62 150.83,111.62 151.28,111.17 151.28,110.63 151.15,110.5 151.15,110.22 151.19,110.12 151.19,109.85 151.16,109.76 151.16,109.57 151.22,109.42 151.22,109.41 151.31,109.33 151.52,109.33 151.7,109.16 151.7,109 151.62,108.92 151.51,108.92 UC1.AC3
  BOTTOM w0.097: v1(47.04,104.51) 46.84,104.31 46.65,104.31 CT103.1
CPU_DP2_P0_C: length 3.1
  BOTTOM w0.097: CT103.2 45.03,104.31 44.54,104.31 44.12,103.89 43.38,103.89 43.3,103.98 UT9.17
CPU_DP2_P1: length 137.6
  IN3 w0.089: v1(47.05,102.73) 46.71,102.73 46.65,102.67 46.65,102.41 46.56,102.32 46.19,102.32 46.1,102.41 46.1,113.67 57.69,125.27 61.95,125.27 64.03,127.35 83.73,127.35 84.76,126.32 94.07,126.32 96.22,124.17 110.56,124.17 114.76,119.97 132.11,119.97 132.96,119.12 137.17,119.12 137.8,118.49 137.8,117.28 139.24,115.84 139.24,114.34 141.34,112.25 148.11,112.25 149.8,113.94 149.96,113.94 150.04,113.86 150.04,113.62 150.12,113.54 v1(150.36,113.54)
  BOTTOM w0.076: v1(150.36,113.54) 149.96,113.54 149.88,113.46 149.88,113.04 151.79,111.14 151.79,110.28 151.42,109.91 UC1.AC2
  BOTTOM w0.097: CT105.1 46.65,102.53 46.85,102.53 v1(47.05,102.73)
CPU_DP2_P1_C: length 3
  BOTTOM w0.097: CT105.2 45.03,102.53 44.81,102.53 44.49,102.84 v4(44.23,102.84) 43.38,102.84 43.3,102.93 UT9.20
CPU_DP2_P2: length 135.7
  IN3 w0.089: v1(48.5,100.95) 48.7,100.75 49.3,100.75 50.29,101.74 50.29,111.33 59.44,120.48 64.75,120.48 67.09,122.83 74.93,122.83 75.24,123.14 79.54,123.14 79.9,122.78 81.16,122.78 81.51,122.43 83.43,122.43 83.81,122.04 84.44,122.04 85.65,123.25 93.27,123.25 95.42,121.11 96.53,121.11 97.88,119.76 99.58,119.76 100.16,119.18 108.92,119.18 111.5,116.59 127.21,116.59 130.46,116.59 133.28,113.77 133.28,113.77 133.43,113.61 133.43,113.62 137.94,109.1 141.03,109.1 141.3,109.37 150.57,109.37 152.61,111.41 152.61,111.55 152.61,111.56 152.61,112.34 152.8,112.53 152.94,112.53 v1(153.19,112.78)
  BOTTOM w0.076: UC1.AE3 152.45,109.01 152.4,109.07 152.4,109.26 152.46,109.32 152.64,109.32 152.75,109.43 152.81,109.57 152.81,109.76 152.77,109.85 152.77,110.13 152.81,110.24 152.81,110.46 152.65,110.63 152.65,111.97 152.52,112.1 152.52,112.33 152.7,112.51 152.99,112.51 153.19,112.7 v1(153.19,112.78)
  BOTTOM w0.097: CT107.1 46.65,100.75 48.3,100.75 v1(48.5,100.95)
CPU_DP2_P2_C: length 3.4
  BOTTOM w0.097: CT107.2 45.05,100.77 44.95,100.77 44.82,100.9 44.82,101.02 v4(44.32,101.51) 44.04,101.8 43.3,101.8 43.23,101.88 UT9.23
CPU_DP2_P3: length 139.6
  IN3 w0.089: v1(153.14,114.65) 152.85,114.36 152.7,114.36 152.03,113.69 152.03,111.6 150.3,109.87 141.66,109.87 141.28,110.25 138.49,110.25 137.99,110.74 137.36,110.74 133.01,115.09 133.01,115.47 131.31,117.17 130.49,117.17 129.96,117.7 124.47,117.7 124.02,117.25 111.82,117.25 109.19,119.88 101.36,119.88 99.55,121.69 95.65,121.69 93.4,123.94 85.48,123.94 84.57,123.03 81.73,123.03 81,123.76 75.05,123.76 74.69,123.4 66.86,123.4 64.66,121.21 59.35,121.21 49.71,111.57 49.71,105.36 47.86,103.5 47.86,99.24 47.62,99 47.47,99 v1(47.26,99.2)
  BOTTOM w0.076: v1(153.14,114.65) 153.14,114.54 153.06,114.46 152.63,114.46 152.2,114.03 152.2,111.96 152.28,111.88 152.28,110.35 152.28,110.21 UC1.AE2
  BOTTOM w0.097: CT109.1 46.65,98.97 47.04,98.97 v1(47.26,99.2)
CPU_DP2_P3_C: length 4.4
  BOTTOM w0.097: UT9.25 43.16,101.18 43.25,101.09 43.66,101.09 44.19,100.57 v4(44.19,100.24) 44.19,99.54 44.76,98.97 45.03,98.97 CT109.2
CPU_DP3_AUXN: length 1.3
  TOP w0.102: T1.1 v1(154.53,106.71)
  BOTTOM w0.076: v1(154.53,106.71) 154.14,106.32 UC1.AG7
CPU_DP3_AUXP: length 1.1
  TOP w0.102: v1(154.46,107.34) 154.28,107.34 T2.1
  BOTTOM w0.076: UC1.AG6 154.09,106.97 v1(154.46,107.34)
CPU_GC6_FB_EN: length 7.3
  BOTTOM w0.076: UC1.CM35 180.96,87.99 180.79,87.82 180.79,87.58 181.07,87.3 181.81,87.3 182.61,86.5 184.03,86.5 184.56,85.96 184.56,85.65 T383.1
CPU_POPIRCOMP: length 1.9
  TOP w0.33: RC106.1 171.84,94.29 171.15,93.6 v1(170.9,93.6)
  BOTTOM w0.2: UC1.BP27 170.87,93.72 v1(170.9,93.6)
CPU_XDP_PRDY#: length 87.3
  IN3 w0.102: v1(147.56,114.66) 139.01,123.21 117.11,123.21 113.24,127.08 98.61,127.08 97.26,128.43 97.26,129.81 96.06,131.01 94.43,131.01 94.06,130.65 89.84,130.65 89.68,130.81 89.28,131.2 88.46,131.2 88.34,131.33 78.17,131.33 77.21,132.29 77.21,132.29 77.07,132.43 v1(77.07,134.95)
  BOTTOM w0.076: v1(147.56,114.66) 148.07,114.15 148.07,112.76 148.75,112.08 148.75,110.54 UC1.W1
  BOTTOM w0.107: v1(77.07,134.95) 77.07,134.87 77.37,134.58 JXDP1.5
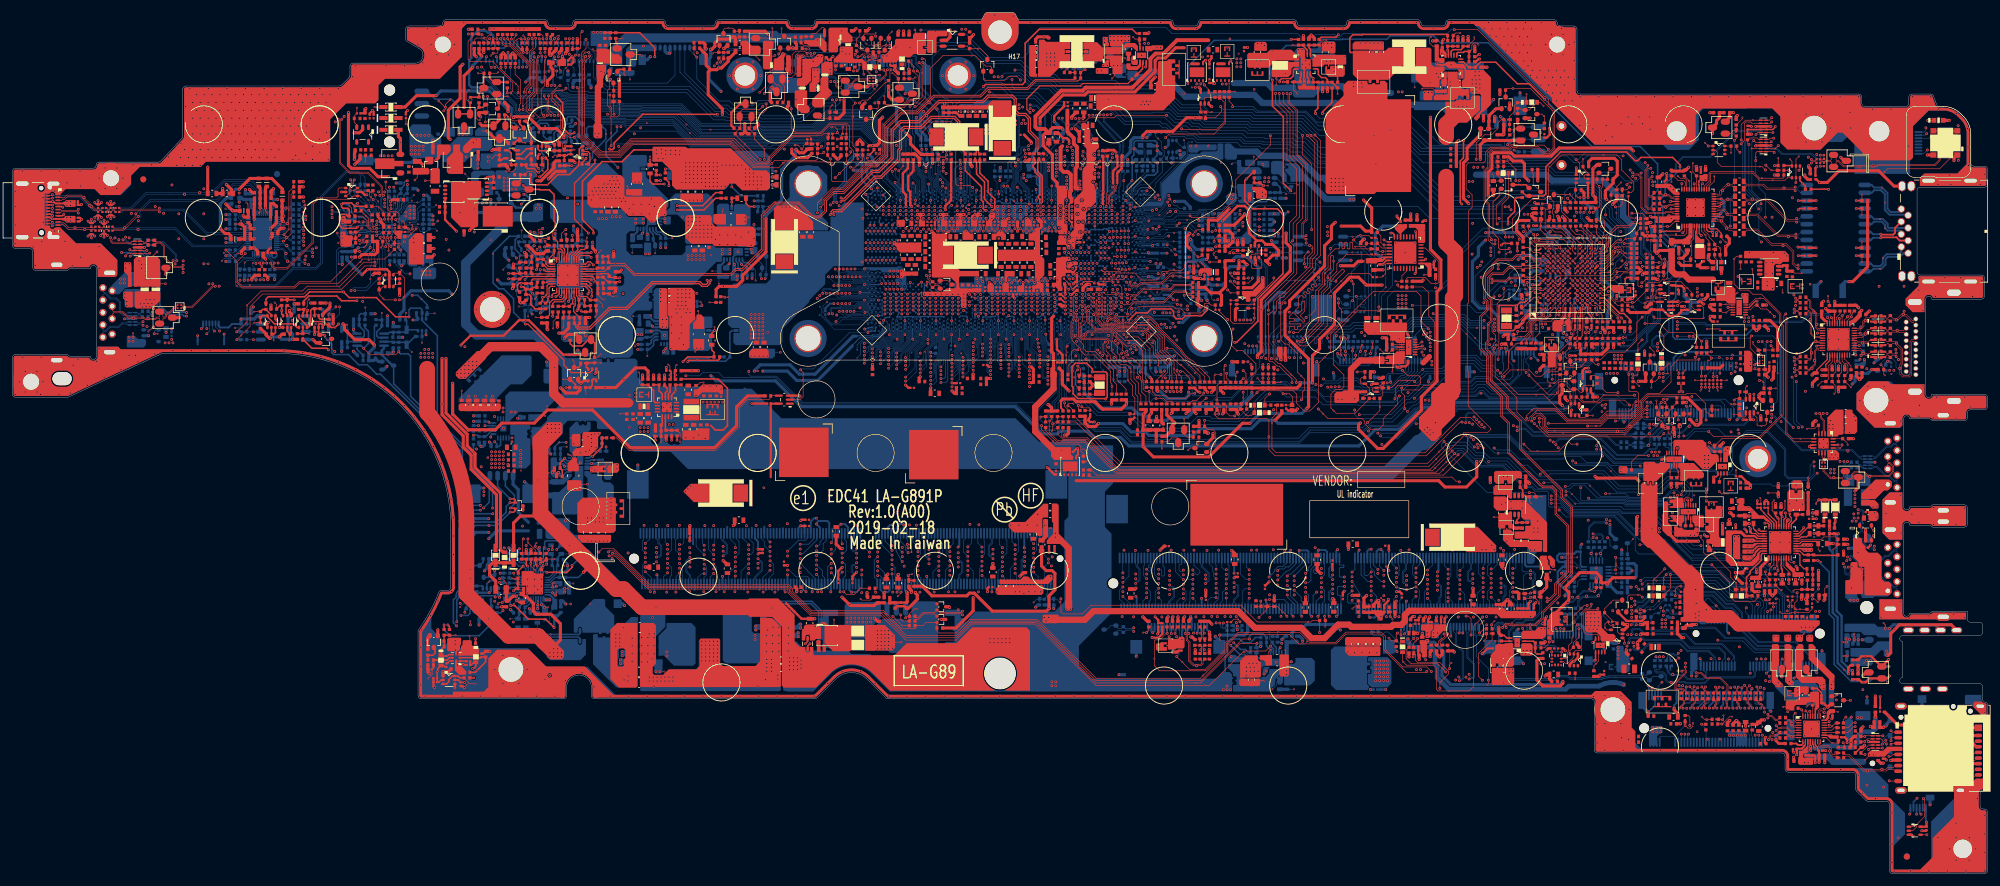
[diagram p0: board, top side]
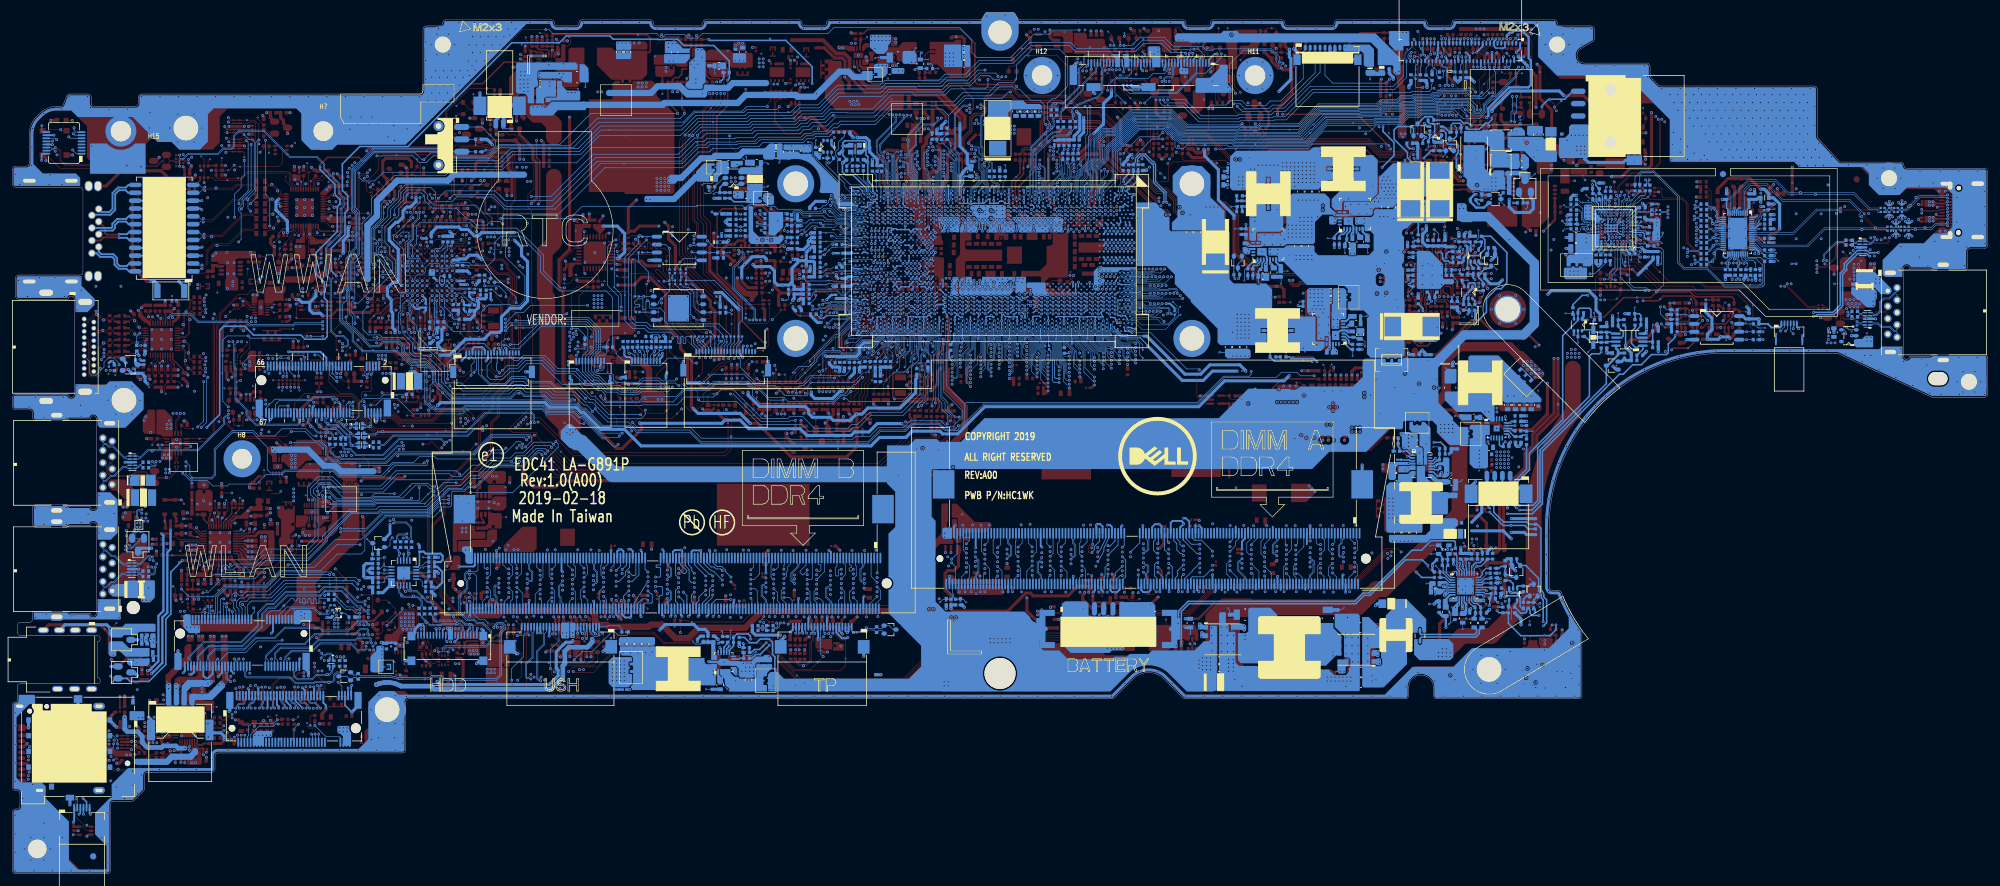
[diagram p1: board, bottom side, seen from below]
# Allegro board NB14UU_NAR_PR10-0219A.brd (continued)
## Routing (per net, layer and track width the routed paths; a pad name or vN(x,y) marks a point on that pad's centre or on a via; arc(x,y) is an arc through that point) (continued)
CPU_XDP_PREQ#: length 93.3
  TOP w0.107: v1(76.2,135.05) 74.92,135.05 74.61,134.73 RC138.1 74.3,134.26 74,133.96 v2(74,132.01)
  IN3 w0.102: v1(147.56,114.08) 147.56,114.08 138.66,122.98 117.02,122.98 113.15,126.85 98.51,126.85 97.03,128.34 97.03,129.72 95.97,130.78 94.52,130.78 94.16,130.42 89.74,130.42 89.58,130.58 89.19,130.97 88.16,130.97 88.11,131.02 78.15,131.02 76.98,132.19 76.98,132.2 76.74,132.43 76.74,132.43 76.64,132.53 76.64,134.24 76.2,134.69 v1(76.2,135.05)
  BOTTOM w0.076: v1(147.56,114.08) 147.91,113.73 147.91,112.69 148.53,112.07 148.53,110.67 148.75,110.08 148.75,109.88 148.96,109.66 UC1.W2
  BOTTOM w0.107: JXDP1.3 76.77,134.48 v1(76.2,135.05)
CPU_XDP_TCLK: length 77.1
  TOP w0.107: v1(136.16,124.55) 135.76,124.14 v3(135.76,122.34) 135.76,117.66 RC139.1 136.44,116.95 RC328.1 136.44,115.66 v1(136.58,115.52)
  IN1 w0.089: v1(147.13,107.19) 147.52,107.58 147.52,107.94 146.27,109.19 144.53,109.19 142.14,111.58
  IN1 w0.099: 142.14,111.58 138.55,115.17 138,115.17 137.65,115.52 v1(136.58,115.52)
  BOTTOM w0.089: UC1.T6 v1(147.13,107.19)
  BOTTOM w0.107: v1(136.16,124.55) 135.17,125.54 132.16,125.54 131.73,125.11 129.63,125.11 127.01,122.48 121.22,122.48 121.04,122.66 115.7,122.66 115.16,123.2 113.47,123.2 109.42,127.25 95.99,127.25 94.35,128.89 94.35,131.51 94.11,131.76 94.11,132.53 93.24,133.39 93.18,133.39 92.97,133.61 JXDP1.57
CPU_XDP_TDI: length 23
  TOP w0.107: v1(133.24,118.72) 133.74,118.72 RC134.1 133.92,119.36 RC851.1 v3(134.13,120.69)
  IN1 w0.089: v1(148.05,107.19) 147.69,107.55 147.69,108 146.34,109.36 146.05,109.36 143.82,111.58
  IN1 w0.099: 143.82,111.58 142.81,112.6 141.8,112.6 138.75,115.65 v1(138.09,115.65)
  BOTTOM w0.076: 136.84,116.9 v1(138.09,115.65)
  BOTTOM w0.089: UC1.U6 v1(148.05,107.19)
  BOTTOM w0.107: 136.84,116.9 135.01,118.72 v1(133.24,118.72)
CPU_XDP_TDO: length 25.9
  TOP w0.107: v3(132.34,120.67) 132.89,120.67 133.25,120.31 v1(133.25,119.78) 133.05,119.58 RC850.1 132.43,119.29 132.52,119.2 RC135.1
  IN1 w0.089: v1(149.9,107.82) 149.9,108 149.9,108.42 146.74,111.58
  IN1 w0.099: 146.74,111.58 143.06,115.26 140.45,115.26 139.51,116.19 v1(139.51,116.42)
  BOTTOM w0.076: v1(139.51,116.42) 139.51,116.57 138.58,117.5
  BOTTOM w0.089: UC1.Y5 v1(149.9,107.82)
  BOTTOM w0.107: 138.58,117.5 137,119.09 133.95,119.09 v1(133.25,119.78)
CPU_XDP_TMS: length 28.5
  TOP w0.107: v3(126.41,117.75) 126.88,117.75 v1(127.51,117.12) 127.77,117.37 127.77,117.69 128.09,118.01 RC131.1 128.42,118.1 RC852.1
  IN1 w0.089: 141.14,111.58 141.25,111.47 141.31,111.47 144.26,108.52 145.33,108.52 145.85,107.99 145.85,107.64 145.98,107.52 146.82,107.52 v1(147.13,107.82)
  IN1 w0.099: v1(127.51,117.12) 129.98,117.12 130.44,116.66 130.44,116.2 130.44,116.01 131.78,114.66 134.08,114.66 134.33,114.91 135.97,114.91 136.52,114.36 138.36,114.36 141.14,111.58
  BOTTOM w0.089: UC1.T5 v1(147.13,107.82)
CPU_XDP_TRST#: length 85.7
  TOP w0.107: v1(91.22,127.07) 91.4,126.88 91.4,119.08 94.7,115.78 98.18,115.78 100.24,117.84 115.91,117.84 119.67,114.08 123.76,114.08 v3(124.51,114.84) 124.71,115.04 131.57,115.04 132.33,114.28 132.33,112.02 132.49,111.87 134.83,111.87 138.21,115.25 139,115.25 v1(140.1,116.36) 140.2,116.46 140.2,116.93 RC136.1
  IN1 w0.089: v1(149.92,107.13) 150.3,107.52 150.3,108.34 147.06,111.58
  IN1 w0.099: v1(140.1,116.36) 140.25,116.36 141.03,115.58 143.06,115.58 147.06,111.58
  BOTTOM w0.089: UC1.AB6 150.2,107.13 v1(149.92,107.13) 149.61,107.13 UC1.Y6
  BOTTOM w0.107: CC308.1 93.05,129.12 92.43,128.5 RC853.1 92.39,127.17 92.28,127.07 v1(91.22,127.07)
CPVEE: length 4.2
  TOP w0.203: CA77.1 CA78.1 283.6,58.16 v2(284.51,57.26) 284.93,56.83 UA1.27
CSIN_CHG: length 3.8
  BOTTOM w0.203: PC719.2 83,43.25 83.18,43.25 83.74,43.81 PU700.14
  BOTTOM w0.254: PR702.2 82.94,41.59 82.74,41.79 PC726.1 82.74,42.99 PC719.2
CSIN_CHG_R: length 10.8
  BOTTOM w0.254: 91.69,39.32 91.69,38.81 91.54,38.66 v2(86.94,38.66) 82.87,38.66 82.55,38.98 82.55,39.4 PR702.1
CSIP_CHG: length 5.5
  BOTTOM w0.107: v2(80.42,41.2) PR701.2
  BOTTOM w0.203: PU700.15 83.34,44 83,43.66 82.46,43.66 81.9,43.1 PC719.1
  BOTTOM w0.254: PC719.1 81.87,43.04 PC725.1 81.87,41.76 81.67,41.55 PR701.2
CSIP_CHG_R: length 11.5
  BOTTOM w0.254: PR701.1 82.1,39.37 82.1,38.81 82.67,38.24 v2(83.73,38.24) 91.44,38.24 91.69,37.98 PR700.2
CSON_CHG: length 4.6
  BOTTOM w0.203: PU700.1 86.73,47.87 87.42,48.56 v2(87.42,48.77) 87.42,49.59 PC752.2
  BOTTOM w0.254: PC752.2 87.21,49.86 PC753.1 87.21,51.47 PR734.1
CSON_CHG_R: length 52.7
  TOP w0.107: v1(87.21,52.37) v2(87.21,52.98)
  TOP w0.254: v1(128.07,37.16) 128.46,37.54 PR711.3
  IN1 w0.254: v1(128.07,37.16) 128.27,37.35 128.27,41.48 127.38,42.36 100.73,42.36 91.56,51.53 87.47,51.53 87.21,51.79 v1(87.21,52.37)
  BOTTOM w0.254: PR734.2 87.21,52.86 v1(87.21,52.37)
CSOP_CHG: length 6.7
  BOTTOM w0.107: v2(89.91,51.67) PR733.1
  BOTTOM w0.203: PU700.2 86.81,47.47 87.93,48.59 87.93,49.67 PC752.1
  BOTTOM w0.254: PR733.1 88.07,51.09 PC748.1 88.07,49.86 PC752.1
CSOP_CHG_R: length 53.2
  TOP w0.254: v1(128.84,37.16) 128.46,36.78 PR711.2
  IN1 w0.254: v1(87.93,52.39) 88.3,52.02 91.62,52.02 100.89,42.75 127.53,42.75 128.65,41.63 128.65,37.35 v1(128.84,37.16)
  BOTTOM w0.107: v2(90.01,53.01) 89.95,53.07 PR733.2
  BOTTOM w0.254: v1(87.93,52.39) 88.29,52.75 88.29,52.82 88.55,53.07 PR733.2
CV2_ON: length 108.6
  TOP w0.107: v1(238.4,31.27) 238.4,30.68 v2(238.23,30.52) ; v1(263.29,98.15) 263.86,98.15 RE539.2
  IN2 w0.102: v1(238.4,31.27) 238.7,31.27 240.03,29.94 256.14,29.94 257.85,31.65 260.35,31.65 265.54,36.84 265.54,43.18 266.49,44.13 266.49,49.66 265.58,50.58 265.58,58.67 266.11,59.21 266.11,64.08 266.94,64.9 266.94,68.49 263.59,71.83 263.59,77.1 264.49,78 264.49,80.59 266.66,82.76 266.66,89.69 264.79,91.55 264.79,94.65 264.08,95.36 264.08,97.36 v1(263.29,98.15)
  BOTTOM w0.107: v1(238.4,31.27) 238.4,33.14 236.47,35.08 236.47,38.29 235.77,38.98 JUSH1.24
CV2_ON_R: length 19.8
  TOP w0.107: RE539.1 RE716.2 266.05,98.24 266.17,98.24 266.44,98.51 266.44,99.29 v2(266.33,99.4) 266.06,99.67 v1(266.06,99.83)
  TOP w0.127: UE1.H8 v1(252.85,97.41)
  IN3 w0.089: 256.76,98.09 256.17,98.69 255.45,98.69 255.36,98.6 253.39,98.6 253.23,98.44 253.23,97.8 v1(252.85,97.41)
  IN3 w0.102: v1(266.06,99.83) 265.87,99.64 262.36,99.64 261.3,98.58 261.3,97.86 260.89,97.44 259.9,97.44 259.65,97.69 258.11,97.69 257.92,97.88 256.98,97.88 256.76,98.09
DAT_TP_SIO_I2C_CLK: length 157.2
  TOP w0.089: v1(248.09,100.66) 248.45,100.3 UE1.C12
  TOP w0.107: RZ22.2 192.35,35.82 192.35,36 v1(192.54,36.19) 192.32,36.42 192.32,36.68 192.54,36.9 RZ347.2 CZ80.1
  IN1 w0.089: 248.92,100.82 248.76,100.66 v1(248.09,100.66) ; 248.08,86.98 248.08,87 248.08,87.01 248.08,87.4 249.63,88.95 250.15,88.95 250.74,89.55 252.27,89.55 253.41,90.69 254.55,90.69 255.22,91.35 256.76,91.35 260.29,94.88 260.29,95.11
  IN1 w0.099: v1(192.54,36.19) 192.37,36.36 192.37,36.61 192.62,36.86 196.08,36.86 196.95,37.73 198.37,37.73 198.81,37.28 200.46,37.28 201.27,38.09 202.24,38.09 205.04,40.89 214.66,40.89 215.58,39.97 221.9,39.97 222.49,39.38 228.72,39.38 228.94,39.16 228.94,37.9 229.38,37.45 232.92,37.45 233.58,36.79 241.96,36.79 243.14,37.98 244.65,37.98 245.79,39.12 245.79,40.14 246.54,40.88 249.26,40.88 251.48,43.11 251.48,44.93 252.34,45.79 252.34,50.05 252,50.39 252,57.86 252.15,58.01 252.15,65.1 251.62,65.64 251.62,67.8 252.22,68.4 252.22,71.23 245.71,77.74 245.71,81.2 247.71,83.2 247.71,84.15 247.27,84.59 247.27,85.64 248.08,86.46 248.08,86.98 ; 260.29,95.11 260.29,98 259.58,98.71 259.58,99.02 258.25,100.34 258.25,101.09 256.46,102.88 256.46,103.17 255.27,104.35 254.03,104.35 253.38,105.01 251.04,105.01 249.8,103.77 249.8,103.77 248.94,102.91 248.94,100.85 248.92,100.82
DAT_TP_SIO_R: length 11.5
  TOP w0.107: CZ88.1 189.54,39.49 189.54,38.92 v1(189.44,38.82) 189.61,38.66 189.61,37.71 189.98,37.34 189.98,34.36 190.74,33.6 v4(191.27,33.6) 192.02,33.6 192.33,33.91 192.33,34.4 RZ22.1 RZ18.2
  BOTTOM w0.107: JKBTP1.13 189.49,39.4 189.59,39.29 189.59,38.97 v1(189.44,38.82)
DCIN1_EN: length 5.5
  TOP w0.107: RE600.2 253.32,104.59 v2(254.9,103.02) 254.9,102.52 255.27,102.15 255.27,100.93 254.85,100.51 UE1.L12
DCIN1_EN_R: length 211.7
  TOP w0.107: RE600.1 254.24,104.26 v1(255.49,103.01) ; v1(90.74,119.01) 89.96,119.01 88.57,120.4 88.57,124 87.25,125.31 87.25,126.01 87.84,126.59 v2(88.78,126.59) 89.08,126.59 v1(89.43,126.94)
  IN2 w0.102: v1(255.49,103.01) 255.49,104.69 256.93,106.13 256.93,107.6 256.03,108.49 253.09,108.49 250.82,110.76 250.82,111.94 242.15,120.61 232.7,120.61 232.11,121.19 204.75,121.19 196.18,129.76 196.18,132.62 193.25,135.55 187.22,135.55 186.22,136.55 166.05,136.55 162,132.51 157.9,132.51 155.49,134.92 142.61,134.92 142.57,134.96 139.95,134.96 139.27,134.27 133.82,134.27 130.81,131.26 126.54,131.26 123.27,134.54 109.39,134.54 103.66,128.81 99.54,128.81 97.33,126.6 89.77,126.6 v1(89.43,126.94)
  BOTTOM w0.254: PQ8.3 90.99,119.27 v1(90.74,119.01) 91.24,118.5 PR28.1
DCIN2_EN: length 8.2
  TOP w0.107: RE601.2 254.19,87.32 v1(254.06,87.45)
  TOP w0.127: v1(254.44,93.43) 254.06,93.81 UE1.K4
  BOTTOM w0.089: v1(254.44,93.43) 254.44,93.36 254.82,92.97 254.82,92.39 255,92.21 255,91 254.84,90.84 254.84,90.38 254.88,90.34 254.88,89.42 254.19,88.72 v2(254.19,88.1) 254.19,87.58 v1(254.06,87.45)
DCIN2_EN_R: length 365
  TOP w0.107: RE601.1 254.19,85.16 v1(254,84.97) ; v1(73.97,40.21) v2(73.97,40.8)
  IN2 w0.102: v1(73.97,40.21) 74.66,39.52 78.5,39.52 81.37,42.38 81.37,43.7 80.93,44.13 80.93,45.08 81.61,45.76 81.61,50.15 82.04,50.58 90.35,50.58 92.41,52.64 96.85,52.64 99.81,55.6 131.71,55.6 133.29,54.02 134.22,54.02 134.59,53.66 134.59,47.99 136.66,45.92 136.66,45.35 137.42,44.59 137.42,43.99 137.76,43.65 153.9,43.65 156.22,41.33 162.66,41.33 162.69,41.3 167.25,36.74 177.65,36.74 182.91,31.48 192.95,31.48 196.13,34.66 197.09,34.66 197.33,34.89 197.33,35.55 198.29,36.51 199.64,36.51 201.79,38.66 204.64,38.66 204.9,38.92 209.04,38.92 209.7,38.26 215.85,38.26 215.93,38.19 221.52,38.19 223.08,36.63 223.82,36.63 224.48,35.96 224.48,33.44 226.16,31.77 231.67,31.77 233.45,33.54 238.69,33.54 240.69,31.54 249.37,31.54 249.99,32.15 255.26,32.15 258.75,35.64 258.75,37.58 260.2,39.03 263.43,39.03 263.81,39.41 263.81,41.25 263.54,41.53 263.54,42.66 262.63,43.56 262.63,45.1 262.86,45.33 263.51,45.33 263.98,45.79 263.98,48.62 263.52,49.08 263.52,59.64 263.67,59.79 263.67,61.18 260.46,64.39 260.46,71.33 259.58,72.2 259.58,75.37 256.34,78.61 256.34,80.34 255.75,80.93 255.75,83.23 v1(254,84.97) ; v1(75.73,65.76) 76.2,66.23 76.2,69.1 76.31,69.21 76.31,70.86 78.38,72.93 83.65,72.93 85.47,74.75 89.72,74.75 91.43,76.46 91.43,82.32 82.49,91.26 82.03,91.26 81.24,92.05 81.24,92.73 79.18,94.79 79.18,99.13 79.81,99.77 81.16,99.77 v1(81.44,99.49)
  IN3 w0.102: v1(75.73,65.76) 75.73,63.49 76.69,62.52 76.69,60.95 76.39,60.64 75.56,60.64 73.97,59.05 v1(73.97,40.21)
  BOTTOM w0.254: PR821.1 80.65,100.28 PQ807.3 v1(81.44,99.49)
DCIN_CHG: length 6.4
  TOP w0.107: v2(79.37,47.37) 79.78,46.96 PR708.2
  TOP w0.508: PR708.2 79.78,44.08 PC737.2 80.03,44.04 80.83,44.84 v1(81.4,44.84)
  BOTTOM w0.203: PU700.17 81.63,45.07 v1(81.4,44.84)
DCPRTC: length 2.4
  TOP w0.102: CC76.1 169.86,96.16 v1(170.73,95.28) 170.73,95.2 v2(171.05,94.88)
  BOTTOM w0.203: UC1.BP24 170.62,95.3 170.73,95.28 v1(170.73,95.28)
DDR_A_ACT#: length 56.6
  IN1 w0.122: v1(127.25,50.19) 126.57,50.19 126.45,50.31 126.45,53.94 126.57,54.06 127.74,54.06 127.86,54.18 127.86,55.09 127.74,55.21 126.55,55.21 126.42,55.33 126.42,58.23 126.55,58.35 127.79,58.35 127.91,58.48 127.91,58.81 127.79,58.93 127.43,58.93 127.31,59.05 127.31,59.29 127.43,59.42 127.79,59.42 127.91,59.54 127.91,60.62 142.06,74.77 142.06,75.93 145.07,78.94 145.07,82.55 v1(146.64,84.12)
  BOTTOM w0.076: v1(146.64,84.12) 146.79,84.71 147.41,85.33 147.41,86.38 147.72,86.69 147.72,87.8 147.68,87.92 147.68,88.1 147.84,88.56 UC1.V35
  BOTTOM w0.135: JDIMM1.114 129.7,47.65 128.43,48.93 128.43,49.01 v1(127.25,50.19)
DDR_A_ALERT#: length 49.6
  IN1 w0.089: v1(146.64,81.56) 146.03,80.95 146.03,78.39 143.23,75.58
  IN1 w0.122: v1(129.89,48.36) 129.07,49.18 129.07,60.14 143.23,74.29 143.23,75.58
  BOTTOM w0.076: 147.46,84.3 v2(147.46,84.36) 147.46,84.54 148.65,85.73 148.65,86.66 148.49,86.82 148.49,87.59 UC1.W37
  BOTTOM w0.089: v1(146.64,81.56) 147.46,82.38 147.46,84.3
  BOTTOM w0.135: JDIMM1.116 130.2,48.05 v1(129.89,48.36)
DDR_A_BA0: length 53.1
  IN1 w0.089: v1(148.22,90.46) 148.22,89.99 148.22,89.48 148.22,89.22 150.78,86.66 151.59,84.68 152.18,84.1 152.18,77.9 151.95,77.67 151.92,77.67 151.92,77.67 151.51,77.67 150.33,76.48
  IN1 w0.122: 150.33,76.48 150.2,76.36 150.2,69.02 140.44,59.25 140.44,58.07 138.01,55.64 138.01,49.92 v1(139.76,48.17)
  BOTTOM w0.089: UC1.W32 v1(148.22,90.46)
  BOTTOM w0.135: JDIMM1.150 140.7,47.58 140.11,48.17 v1(139.76,48.17)
DDR_A_BA1: length 56.4
  IN1 w0.089: 152.14,76.71 152.14,76.74 153.15,77.75 153.15,77.88 153.15,79.37 153.96,80.18 153.96,86.22 151.8,88.38 151.46,88.38 149.67,90.16 149.67,90.73 v1(150.04,91.1)
  IN1 w0.122: 152.14,76.71 152.14,76.55 151.97,76.37 151.97,69.11 151.96,69.11 151.96,68.57 142,58.61 142,57.38 141.19,56.57 141.19,55 140.75,54.57 140.75,49.47 140.63,49.35 140.31,49.35 140.18,49.48 140.18,52.62 140.06,52.74 v1(139.76,52.74)
  BOTTOM w0.089: v1(150.04,91.1) UC1.AB31
  BOTTOM w0.135: v1(139.76,52.74) 139.45,53.05 JDIMM1.145
DDR_A_BG0: length 55.4
  IN1 w0.089: v1(147.89,85.71) 147.19,85.71 147.1,85.63 147.1,83.98 145.44,82.32 145.44,78.84 142.45,75.84 142.45,74.79
  IN1 w0.122: 142.45,74.79 142.45,74.61 128.3,60.46 128.3,58.09 128.17,57.97 126.93,57.97 126.81,57.84 126.81,57.6 126.93,57.48 128.17,57.48 128.3,57.36 128.3,53.8 128.17,53.67 126.96,53.67 126.84,53.55 126.84,52.13 v1(127.25,51.71)
  BOTTOM w0.076: v1(147.89,85.71) 147.89,85.82 148.32,86.25 148.32,86.53 148.16,86.69 148.16,87.8 148.2,87.92 148.2,88.1 148.16,88.21 148.16,88.45 148.2,88.57 148.2,89.05 148.14,89.11 UC1.V34
  BOTTOM w0.135: JDIMM1.115 129.95,54 129.95,54 129.95,53.94 127.72,51.71 v1(127.25,51.71)
DDR_A_BG1: length 55.5
  IN1 w0.089: 142.84,75.63 145.8,78.59 145.8,81.99 v1(146.64,82.83)
  IN1 w0.122: 142.84,75.63 142.84,74.45 128.69,60.3 128.69,49.98 128.56,49.86 127.87,49.86 127.74,49.98 127.74,53.11 127.62,53.23 v1(127.25,53.23)
  BOTTOM w0.076: 147.14,84.28 147.14,84.46 148.48,85.8 148.48,86.6 148.33,86.75 148.33,87.78 148.37,87.89 148.37,88.13 148.33,88.24 148.33,88.43 148.49,88.89 UC1.W35
  BOTTOM w0.089: 147.14,84.28 147.14,83.33 v1(146.64,82.83)
  BOTTOM w0.135: JDIMM1.113 129.45,54.1 128.59,53.24 127.26,53.24 v1(127.25,53.23)
DDR_A_CKE0: length 58.4
  IN1 w0.122: v1(144.28,80.24) 142.74,78.71 142.74,77.29 141.28,75.83 141.28,75.09 125.65,59.46 125.65,53.03 125.52,52.91 124.04,52.91 123.91,52.78 123.91,49.47 124.04,49.35 124.67,49.35 124.79,49.47 124.79,51.99 124.91,52.11 v1(125.21,52.11)
  BOTTOM w0.076: 145.79,84.63 146.92,85.75 146.92,86.58 147.22,86.88 147.22,87.33 147.02,87.53 147.02,87.8 147.29,88.28 UC1.U36
  BOTTOM w0.089: v1(144.28,80.24) 145.79,81.75 145.79,84.63
  BOTTOM w0.135: JDIMM1.109 128.45,54.27 128.06,53.89 126.98,53.89 v1(125.21,52.11)
DDR_A_CKE1: length 57.4
  IN1 w0.122: v1(125.21,49.06) 125.59,49.06 125.71,48.94 125.71,47.82 125.83,47.7 126.72,47.7 126.84,47.82 126.84,49.61 126.65,49.8 126.16,49.8 126.04,49.92 126.04,59.3 141.67,74.93 141.67,75.83 143.12,77.28 143.12,78.45 v1(144.28,79.61)
  BOTTOM w0.076: 145.98,84.54 147.08,85.63 147.08,86.51 147.39,86.82 147.39,87.59 UC1.U37
  BOTTOM w0.089: v1(144.28,79.61) 144.3,79.63 144.52,79.63 145.98,81.09 145.98,84.54
  BOTTOM w0.135: v1(125.21,49.06) 125.51,49.06 126.59,47.97 128.46,47.97 128.7,47.73 JDIMM1.110
DDR_A_CKE2: length 6.8
  BOTTOM w0.076: UC1.U34 147.44,89.48 147.55,89.37 147.55,88.24 147.51,88.13 147.51,87.89 147.55,87.78 147.55,86.75 147.25,86.45 147.25,85.49 146.24,84.48 146.24,83.64 T351.1
DDR_A_CKE3: length 5.8
  BOTTOM w0.076: UC1.U35 146.97,88.67 146.97,88.04 146.86,87.84 146.86,87.46 147.06,87.27 147.06,86.95 146.75,86.64 146.75,85.85 145.6,84.7
  BOTTOM w0.089: 145.6,84.7 145.25,84.34 T350.1
DDR_A_CLK0: length 54.7
  IN1 w0.089: v1(136.37,51.78) 136.37,51.78 137.2,51.78 137.4,51.97 137.4,57.08 137.86,57.54 137.98,57.54 138.37,57.14 138.65,57.14 138.94,57.44 138.94,57.71 138.55,58.11 138.55,58.23 138.74,58.42 138.87,58.42 139.26,58.03 139.53,58.03 139.83,58.32 139.83,58.6 139.44,58.99 139.44,59.12 149.59,69.27 149.59,75.77 149.59,75.77 149.59,75.84 149.59,75.84 149.59,76.13 151.28,77.81 151.28,84.37 151.28,84.37 151.28,84.44 147.89,87.84 147.89,90.29 147.86,90.31 147.86,90.73 147.67,90.92 147.49,90.92 v1(147.31,91.1)
  BOTTOM w0.089: UC1.V31 v1(147.31,91.1)
  BOTTOM w0.097: v1(136.37,51.78) 136.15,51.99 135.84,51.99 135.49,52.35 135.49,54.18 135.45,54.21 JDIMM1.137
DDR_A_CLK1: length 54.6
  IN1 w0.089: v1(136.37,50.25) 136.28,50.17 135.84,50.17 135.75,50.25 135.75,53.65 136.05,53.95 136.05,56.83 148.78,69.56 148.78,74.46 148.78,75.19 148.77,75.2 148.77,75.8 150.93,77.96 150.93,84.27 147.43,87.78 147.43,89.84 146.95,90.31 146.95,90.75 146.83,90.87 146.63,90.87 v1(146.4,91.1)
  BOTTOM w0.089: UC1.T31 v1(146.4,91.1)
  BOTTOM w0.097: JDIMM1.138 135.7,47.66 135.86,47.81 135.86,48.41 135.48,48.78 135.48,49.73 135.71,49.96 136.08,49.96 v1(136.37,50.25)
DDR_A_CLK#0: length 54.7
  IN1 w0.089: v1(147.31,90.46) 147.31,90.65 147.4,90.74 147.49,90.74 147.59,90.74 147.68,90.65 147.68,90.24 147.71,90.22 147.71,87.76 151.1,84.37 151.1,77.89 149.41,76.2 149.41,75.84 149.41,75.84 149.41,69.35 139.26,59.19 139.26,58.92 139.65,58.52 139.65,58.4 139.46,58.21 139.33,58.21 138.94,58.6 138.67,58.6 138.37,58.31 138.37,58.03 138.76,57.64 138.76,57.51 138.57,57.32 138.45,57.32 138.06,57.72 137.78,57.72 137.22,57.15 137.22,52.04 137.13,51.96 136.75,51.96 136.54,52.17 136.44,52.17 136.35,52.27 136.35,52.52 v1(136.37,52.54)
  BOTTOM w0.089: UC1.V32 v1(147.31,90.46)
  BOTTOM w0.097: v1(136.37,52.54) 136.37,52.24 136.31,52.18 135.92,52.18 135.67,52.43 135.67,53.85 135.95,54.13 JDIMM1.139
DDR_A_CLK#1: length 54.5
  IN1 w0.089: v1(146.4,90.46) 146.63,90.69 146.75,90.69 146.77,90.68 146.77,90.24 147.25,89.76 147.25,87.71 150.76,84.2 150.76,78.03 148.6,75.87 148.6,75.25 148.59,75.25 148.59,75.12 148.6,75.12 148.6,74.54 148.6,74.53 148.6,69.63 135.87,56.9 135.87,54.03 135.57,53.73 135.57,50.18 135.76,49.98 136,49.98 136.37,49.61 v1(136.37,49.49)
  BOTTOM w0.089: UC1.T32 v1(146.4,90.46)
  BOTTOM w0.097: v1(136.37,49.49) 136.08,49.78 135.79,49.78 135.67,49.66 135.67,48.86 136.04,48.48 136.04,47.78 136.2,47.62 JDIMM1.140
DDR_A_CS#0: length 59.5
  IN1 w0.089: v1(151.87,90.46) 152.03,90.46 155.04,87.46 155.04,86.57 154.81,86.35 154.81,79.83 154.83,79.81
  IN1 w0.122: v1(142.08,51.48) 142.6,52 142.6,53.39 142.81,53.6 142.81,53.77 142.57,54.02 142.57,54.19 142.74,54.36 142.91,54.36 143.16,54.12 143.33,54.12 143.87,54.66 143.87,55.88 143.57,56.18 143.57,56.67 144.16,57.26 144.33,57.26 144.8,56.78 144.98,56.78 145.15,56.95 145.15,57.12 144.67,57.6 144.67,57.77 144.85,57.95 145.02,57.95 145.69,57.28 145.86,57.28 146.03,57.45 146.03,57.62 145.36,58.29 145.36,58.46 145.53,58.63 145.71,58.63 146.38,57.97 146.55,57.97 146.72,58.14 146.72,58.31 146.05,58.98 146.05,59.15 146.22,59.32 146.4,59.32 147.07,58.66 147.24,58.66 147.41,58.83 147.41,59 146.74,59.67 146.74,59.84 153.75,66.85 153.75,76.98 153.94,77.17 153.94,78.74 154.83,79.63 154.83,79.81
  BOTTOM w0.076: UC1.AE32 v1(151.87,90.46)
  BOTTOM w0.135: v1(142.08,51.48) 140.45,53.12 JDIMM1.149
DDR_A_CS#1: length 58.3
  IN1 w0.089: v1(152.78,90.46) 152.78,90.27 156.02,87.03 156.02,86.06 155.83,85.86 155.83,79.64 154.54,78.36 154.54,77.32
  IN1 w0.122: 154.54,77.32 154.54,76.41 154.53,76.39 154.53,66.53 148.88,60.88 148.88,60.71 149.87,59.72 149.87,59.55 149.7,59.38 149.52,59.38 148.54,60.37 148.36,60.37 148.19,60.19 148.19,60.02 149.18,59.03 149.18,58.86 147.53,57.21 147.36,57.21 147.21,57.36 147.04,57.36 146.86,57.18 146.86,57.01 147.01,56.86 147.01,56.69 145.56,55.24 145.56,55.07 146.28,54.35 146.28,54.18 146.1,54 145.93,54 145.21,54.72 145.04,54.72 144.87,54.55 144.87,54.38 145.66,53.58 145.66,53.41 145.49,53.24 145.32,53.24 144.52,54.03 144.35,54.03 143.77,53.45 143.77,53.28 144.16,52.89 144.16,52.39 v1(143.73,51.96)
  BOTTOM w0.076: UC1.AF32 v1(152.78,90.46)
  BOTTOM w0.135: JDIMM1.157 142.45,54.15 143.29,52.4 v1(143.73,51.96)
DDR_A_D0: length 71.6
  IN1 w0.099: v1(102.23,50.32) 101.82,50.73 101.82,51.76 101.34,52.24 101.34,59.23 107.86,65.75 110.06,65.75 122.43,78.12 122.43,89.07 127.99,94.64 132.92,94.64 v1(133.33,95.05)
  BOTTOM w0.076: UC1.A26 138.11,94.5 137.34,94.5 137.19,94.66 136.61,94.66 136.45,94.5 133.88,94.5 133.79,94.59
  BOTTOM w0.089: 133.79,94.59 v1(133.33,95.05)
  BOTTOM w0.107: JDIMM1.4 102.2,47.79 101.82,48.17 101.82,49.91 v1(102.23,50.32)
DDR_A_D1: length 72.7
  IN1 w0.099: v1(135.24,93.79) 135.24,93.17 134.62,92.55 132.39,92.55 131.86,92.02 131.44,92.02 130.38,90.96 130.38,89.4 131.86,87.92 131.86,85.13 125.5,78.78 125.5,76.46 125.5,76.46 125.5,76.16 109.3,59.95 108.39,59.95 108.15,59.71 108.15,59.57 108.46,59.26 108.46,59.12 108.32,58.98 108.18,58.98 107.87,59.29 107.73,59.29 107.43,58.99 107.43,58.25 107.33,58.15 106.66,58.15 106.56,58.05 106.56,57.85 106.66,57.75 107.33,57.75 107.43,57.65 107.43,57.45 107.33,57.35 106.71,57.35 106.61,57.25 106.61,54.8 106.51,54.7 106.22,54.7 106.12,54.6 106.12,54.4 106.22,54.3 106.51,54.3 106.61,54.2 106.61,53.97 106.24,53.6 106.24,50.24 106.14,50.14 v1(105.82,50.14)
  BOTTOM w0.076: 136.66,93.64 136.74,93.57 137.06,93.57 137.21,93.73 138.33,93.73 138.33,93.72 138.44,93.68 138.63,93.68 138.74,93.73 138.98,93.73 139.17,93.66 139.95,93.66 140.16,93.86 UC1.D26
  BOTTOM w0.089: v1(135.24,93.79) 136.51,93.79 136.66,93.64
  BOTTOM w0.107: v1(105.82,50.14) 106.46,49.5 106.46,48.17 106.2,47.91 JDIMM1.20
DDR_A_D2: length 73.9
  IN1 w0.099: v1(102.23,48.8) 102.64,49.2 102.64,49.43 102.74,49.53 103.77,49.53 103.86,49.63 103.86,49.83 103.77,49.92 102.74,49.92 102.64,50.02 102.64,55.89 102.75,56.01 102.75,59.36 108.24,64.84 111.24,64.84 123.34,76.95 123.34,88.64 127.66,92.97 v1(130,92.97)
  BOTTOM w0.076: UC1.D28 139.5,92.98 139.4,92.98 138.56,92.98 138.36,92.87 137.99,92.87 137.79,93.07 137.48,93.07 137.28,92.87
  BOTTOM w0.089: 137.28,92.87 130.14,92.87
  BOTTOM w0.107: JDIMM1.8 103.2,47.83 v1(102.23,48.8) ; v1(130,92.97) 130.1,92.87 130.14,92.87
DDR_A_D3: length 72.1
  IN1 w0.099: v1(105.82,53.19) 105.82,55.49 106.26,55.94 106.26,58.26 106.47,58.46 106.47,58.6 106,59.07 106,59.21 106.14,59.35 106.28,59.35 106.75,58.88 106.89,58.88 107.03,59.02 107.03,59.16 106.56,59.63 106.56,59.78 106.7,59.92 106.84,59.92 107.31,59.44 107.45,59.44 107.59,59.58 107.59,59.72 107.12,60.2 107.12,60.34 107.26,60.48 107.4,60.48 107.87,60 108.01,60 108.15,60.14 108.15,60.28 107.68,60.76 107.68,60.9 107.82,61.04 107.96,61.04 108.74,60.26 109.18,60.26 109.34,60.42 109.34,60.56 108.76,61.13 108.76,61.27 108.9,61.41 109.04,61.41 109.62,60.84 109.76,60.84 109.9,60.98 109.9,61.12 109.33,61.69 109.33,61.83 109.47,61.97 109.61,61.97 110.18,61.4 110.32,61.4 125.2,76.28 125.2,87.91 127.23,89.94 129.11,89.94 131.44,92.28 131.76,92.28 132.42,92.94 133.12,92.94 v1(133.97,93.79)
  BOTTOM w0.076: UC1.C28 139.42,93.39 138.93,93.56 138.77,93.56 138.65,93.52 138.42,93.52 138.3,93.56 137.28,93.56 137.12,93.41 136.69,93.41
  BOTTOM w0.089: v1(133.97,93.79) 134.36,93.41 136.69,93.41
  BOTTOM w0.107: v1(105.82,53.19) 105.45,53.56 JDIMM1.17
DDR_A_D4: length 70.7
  IN1 w0.099: v1(102.23,51.85) 101.64,52.44 101.64,56.93 101.74,57.03 102.05,57.03 102.15,57.13 102.15,57.32 102.05,57.42 101.74,57.42 101.64,57.52 101.64,59.1 107.82,65.29 107.99,65.45 110.18,65.45 122.73,78 122.73,88.93 128.13,94.33 130.33,94.33 130.43,94.43 133.36,94.43 v1(133.97,95.05)
  BOTTOM w0.076: UC1.B26 138.81,94.6 138.33,94.86 138.32,94.86 138.06,94.86 137.86,94.67 137.41,94.67 137.25,94.82 136.54,94.82 136.39,94.67 134.35,94.67 134.28,94.74
  BOTTOM w0.089: 134.28,94.74 v1(133.97,95.05)
  BOTTOM w0.107: JDIMM1.3 101.95,53.95 101.76,53.75 101.76,52.32 v1(102.23,51.85)
DDR_A_D5: length 71.6
  IN1 w0.099: v1(135.24,95.05) 134.63,94.43 134.4,94.2 130.61,94.2 130.43,94.03 128.28,94.03 123.03,88.79 123.03,77.07 122.5,76.54 122.36,76.54 122.1,76.8 121.96,76.8 121.82,76.66 121.82,76.52 122.08,76.26 122.08,76.12 121.94,75.98 121.8,75.98 121.54,76.24 121.4,76.24 121.26,76.1 121.26,75.96 121.52,75.7 121.52,75.56 121.38,75.42 121.24,75.42 120.98,75.68 120.84,75.68 120.7,75.54 120.7,75.4 120.96,75.14 120.96,75 120.82,74.86 120.68,74.86 120.42,75.12 120.28,75.12 120.14,74.98 120.14,74.84 120.4,74.58 120.4,74.44 120.26,74.3 120.12,74.3 119.86,74.56 119.72,74.56 119.58,74.42 119.58,74.28 119.84,74.02 119.84,73.88 111.11,65.15 108.11,65.15 107.91,64.95 107.91,64.95 102.45,59.49 102.45,56.13 102.23,55.91 v1(102.23,53.37)
  BOTTOM w0.076: 135.29,94.99 137.31,94.99 137.48,94.83 137.79,94.83 137.99,95.03 138.36,95.03 138.56,94.92 139.19,94.92 UC1.C26
  BOTTOM w0.089: 135.29,94.99 v1(135.24,95.05)
  BOTTOM w0.107: JDIMM1.7 102.95,54.09 v1(102.23,53.37)
DDR_A_D6: length 72.1
  IN1 w0.099: v1(105.82,48.62) 104.75,48.62 104.63,48.75 104.63,49.42 104.73,49.52 105.31,49.52 105.41,49.62 105.41,49.82 105.31,49.92 104.73,49.92 104.63,50.02 104.63,50.21 104.73,50.31 105.31,50.31 105.41,50.41 105.41,50.61 105.31,50.71 104.73,50.71 104.63,50.81 104.63,58.7 109.37,63.44 111.51,63.44 124.6,76.53 124.6,88.16 126.98,90.54 128.85,90.54 130.97,92.66 131.56,92.66 v1(132.7,93.79)
  BOTTOM w0.076: UC1.B28 138.81,93.3 138.33,93.04 138.32,93.03 138.06,93.03 137.86,93.23 137.41,93.23 137.23,93.05 137.13,93.05
  BOTTOM w0.089: 137.13,93.05 133.44,93.05 v1(132.7,93.79)
  BOTTOM w0.107: v1(105.82,48.62) 105.2,48 JDIMM1.16
DDR_A_D7: length 71.8
  IN1 w0.099: v1(133.33,93.79) 132.77,93.23 132.66,93.12 132.35,93.12 131.68,92.45 131.19,92.45 128.98,90.24 127.1,90.24 124.9,88.04 124.9,76.41 111.63,63.14 109.49,63.14 104.93,58.58 104.93,58.35 105.03,58.25 105.86,58.25 105.96,58.15 105.96,57.95 105.86,57.86 105.03,57.86 104.93,57.76 104.93,57.56 105.03,57.46 105.86,57.46 105.96,57.36 105.96,57.16 105.86,57.06 105.03,57.06 104.93,56.96 104.93,56.48 105.03,56.38 105.35,56.38 105.45,56.28 105.45,56.09 105.35,55.99 105.03,55.99 104.93,55.89 104.93,55.69 105.03,55.59 105.42,55.59 105.52,55.49 105.52,55.29 105.42,55.19 105.03,55.19 104.93,55.1 104.93,51.77 105.03,51.67 v1(105.82,51.67)
  BOTTOM w0.076: UC1.A28 138.11,93.39 137.34,93.39 137.18,93.23 137.08,93.23
  BOTTOM w0.089: v1(133.33,93.79) 133.9,93.23 137.08,93.23
  BOTTOM w0.107: v1(105.82,51.67) 106.45,52.3 JDIMM1.21
DDR_A_D8: length 64.6
  IN1 w0.099: v1(107.76,50.13) 107.32,50.13 107.23,50.23 107.23,53.23 107.52,53.53 107.52,55.13 108.34,55.95 108.34,57.7 127.63,76.99 127.63,78.36 128.49,79.22 128.49,80.38 132.58,84.48 132.58,87.89 131.34,89.14 131.34,90.71 132.13,91.51 133.87,91.51 133.97,91.6 v1(133.97,92.13)
  BOTTOM w0.076: 134.28,91.82 134.3,91.82 134.35,91.78 135.99,91.78 136.52,92.31 137.25,92.31 137.41,92.15 137.86,92.15 138.06,92.35 138.32,92.35 138.33,92.34 138.81,92.08 UC1.B30
  BOTTOM w0.089: 134.28,91.82 v1(133.97,92.13)
  BOTTOM w0.107: JDIMM1.28 108.2,49.69 v1(107.76,50.13)
DDR_A_D9: length 65.8
  IN1 w0.099: v1(111.74,48.49) 111.34,48.49 111.24,48.39 111.24,47.99 111.34,47.89 112.65,47.89 112.74,47.99 112.74,48.8 112.65,48.9 112.25,48.9 112.15,49 112.15,49.2 112.25,49.3 112.65,49.3 112.74,49.4 112.74,49.78 112.65,49.88 112.25,49.88 112.15,49.98 112.15,50.17 112.25,50.27 112.65,50.27 112.74,50.37 112.74,50.71 112.65,50.81 112.36,50.81 112.26,50.91 112.26,57.33 112.42,57.5 112.56,57.5 112.7,57.35 112.88,57.35 113,57.47 113,57.61 112.84,57.78 112.84,57.92 132.74,77.82 132.74,79.88 136.08,83.22 136.08,90.75 v1(135.95,90.88)
  BOTTOM w0.076: v1(135.95,90.88) 137.06,90.88 137.4,91.22 138.31,91.22 138.43,91.17 138.63,91.17 138.74,91.21 138.99,91.21 139.17,91.14 139.71,91.14 139.97,91.14 140.16,91.33 UC1.D30
  BOTTOM w0.107: JDIMM1.38 110.7,47.84 111.34,48.49 v1(111.74,48.49)
DDR_A_D10: length 65.2
  IN1 w0.099: v1(107.76,51.66) 108.08,51.66 108.18,51.56 108.18,48.35 108.28,48.26 108.84,48.26 108.94,48.35 108.94,56.32 109.41,56.78 109.41,57.92 128.23,76.74 128.23,78.11 129.09,78.97 129.09,80.13 133.22,84.26 133.22,89.03 v1(133.03,89.23)
  BOTTOM w0.076: UC1.B33 138.41,89.99 138.34,89.92 135.48,89.92 135.4,90 135.08,90 134.99,89.92
  BOTTOM w0.089: 134.99,89.92 133.72,89.92 v1(133.03,89.23)
  BOTTOM w0.107: v1(107.76,51.66) 107.11,52.3 107.11,53.95 107.45,54.29 JDIMM1.25
DDR_A_D11: length 64.8
  IN1 w0.099: v1(133.56,90.88) 133.56,89.84 134.67,88.73 134.67,84 130.35,79.68 130.35,78.48 129.52,77.64 129.52,76.36 110.6,57.44 110.6,50.21 110.5,50.11 110.26,50.11 110.04,49.9 110.04,49.54 110.17,49.41 111.14,49.41 v1(111.74,50.01)
  BOTTOM w0.076: v1(133.56,90.88) 134.34,90.1 134.81,90.1 134.88,90.17 137.44,90.17 137.49,90.12 137.89,90.12 138.63,90.46 139.51,90.46 UC1.D32
  BOTTOM w0.107: JDIMM1.42 111.7,47.85 112.15,48.3 112.15,49.6 v1(111.74,50.01)
DDR_A_D12: length 63.7
  IN1 w0.099: v1(107.76,48.61) 106.84,49.52 106.84,53.35 106.96,53.46 106.96,53.47 107.22,53.72 107.22,56.36 108.03,57.17 108.03,57.83 126.82,76.61 126.82,79.23 132.24,84.66 132.24,87.92 131.17,88.99 131.17,90.78 132.12,91.74 132.86,91.74 132.86,91.75 132.95,91.75 v1(133.33,92.13)
  BOTTOM w0.076: 133.81,91.66 133.88,91.59 136.05,91.59 136.61,92.14 137.19,92.14 137.34,91.99 138.11,91.99 UC1.A30
  BOTTOM w0.089: 133.81,91.66 v1(133.33,92.13)
  BOTTOM w0.107: JDIMM1.24 107.2,48.05 v1(107.76,48.61)
DDR_A_D13: length 64.6
  IN1 w0.099: v1(135.24,92.13) 135.24,91.37 135.14,91.27 132.14,91.27 131.52,90.64 131.52,89.47 132.9,88.08 132.9,84.37 128.79,80.26 128.79,79.09 127.93,78.24 127.93,76.87 108.7,57.64 108.7,57.5 108.8,57.4 109,57.4 109.1,57.3 109.1,57.1 109,57.01 108.74,57.01 108.64,56.91 108.64,55.21 108.54,55.11 107.92,55.11 107.82,55.01 107.82,54.81 107.92,54.71 108.54,54.71 108.64,54.61 108.64,54.41 108.54,54.32 107.92,54.32 107.82,54.22 107.82,54.02 107.92,53.92 108.54,53.92 108.64,53.82 108.64,53 108.54,52.91 108.03,52.91 v1(107.76,53.18)
  BOTTOM w0.076: v1(135.24,92.13) 135.31,92.21 135.58,92.48 137.31,92.48 137.48,92.31 137.79,92.31 137.99,92.51 138.36,92.51 138.56,92.4 139.19,92.4 UC1.C30
  BOTTOM w0.107: v1(107.76,53.18) 108.17,53.18 108.45,53.46 JDIMM1.29
DDR_A_D14: length 63.4
  IN1 w0.099: v1(111.74,51.54) 111.08,51.54 110.9,51.71 110.9,52.38 111,52.48 111.35,52.48 111.45,52.58 111.45,52.77 111.35,52.87 111.06,52.87 110.96,52.97 110.96,57.37 130.19,76.6 130.19,76.74 129.82,77.12 129.82,77.25 129.96,77.4 130.1,77.4 130.47,77.02 130.61,77.02 131.23,77.64 131.23,77.78 130.65,78.36 130.65,78.65 131.3,79.29 131.3,79.43 131,79.73 131,79.87 131.14,80.01 131.28,80.01 131.58,79.71 131.72,79.71 135.39,83.39 135.39,89.09 134.14,90.34 v1(134.14,90.9)
  BOTTOM w0.076: v1(134.14,90.9) 134.71,90.33 137.53,90.33 137.58,90.28 137.8,90.28 138.23,90.48 138.28,90.48 138.41,90.54 138.8,90.73 UC1.B32
  BOTTOM w0.107: v1(111.74,51.54) 110.45,52.83 110.45,52.94 110.45,52.94 110.45,54.07 110.45,54.07 JDIMM1.37
DDR_A_D15: length 63.5
  IN1 w0.099: v1(135.36,90.88) 134.87,90.38 134.87,89.86 135,89.74 135.67,89.74 135.77,89.64 135.77,83.34 132.44,80 132.44,79.55 132.34,79.45 131.89,79.45 131.79,79.36 131.79,79.16 131.89,79.06 132.34,79.06 132.44,78.96 132.44,78.76 132.34,78.66 131.17,78.66 131.07,78.56 131.07,78.36 131.17,78.27 132.34,78.27 132.44,78.17 132.44,77.94 132.29,77.8 131.73,77.8 131.63,77.7 131.63,77.62 111.37,57.35 111.37,57.2 111.47,57.1 111.86,57.1 111.95,57 111.95,56.76 111.86,56.66 111.36,56.66 111.26,56.56 111.26,55.67 111.36,55.57 111.86,55.57 111.95,55.47 111.95,54.88 111.86,54.79 111.38,54.79 111.28,54.69 111.28,54.49 111.38,54.39 111.86,54.39 111.95,54.29 111.95,54.09 111.86,53.99 111.38,53.99 111.28,53.89 111.28,53.7 111.38,53.6 111.86,53.6 111.95,53.5 111.95,53.16 111.86,53.06 v1(111.74,53.06)
  BOTTOM w0.076: UC1.C32 139.41,90.88 138.96,91.05 138.77,91.05 138.62,90.99 138.42,90.99 138.28,91.06 137.52,91.06 136.97,90.51 135.74,90.51 v1(135.36,90.88)
  BOTTOM w0.107: v1(111.74,53.06) 111.45,53.35 JDIMM1.41
DDR_A_D16: length 68.4
  IN3 w0.089: v1(142.99,96.49) 142.45,97.03 141.56,97.03 141.36,97.23
  IN3 w0.097: v1(151.43,48.23) 151.43,48.24 151.26,48.41 150.25,50.43 150.25,52.86 141.28,61.84 139.13,61.84 131.15,69.82 131.15,73.7 131.15,73.71 131.15,82.73 133.09,84.67 133.09,88.77 134.4,90.08 134.93,90.08 136.24,90.46 136.36,90.58 136.36,93.6 136.54,94.1 136.87,94.44 137.81,94.86 138.41,95.47 138.41,95.58 140.06,97.23 141.36,97.23
  BOTTOM w0.089: UC1.J22 v1(142.99,96.49)
  BOTTOM w0.107: JDIMM1.194 151.7,47.97 v1(151.43,48.23)
DDR_A_D17: length 70.5
  IN3 w0.089: v1(142.36,94.45) 142.36,94.9 142.26,95 140.05,95
  IN3 w0.097: v1(154.33,51.28) 154.03,51.28 153.93,51.18 153.93,48.98 153.83,48.89 153.06,48.89 152.96,48.98 152.96,49.17 153.28,49.5 153.28,51.27 153.22,51.33 153.22,52.89 142.2,63.91 140.62,63.91 134.42,70.11 134.42,70.6 134.33,70.7 134.18,70.7 134.09,70.8 134.09,70.99 134.18,71.08 134.33,71.08 134.42,71.18 134.42,71.37 134.33,71.47 134.18,71.47 134.09,71.57 134.09,71.76 134.18,71.86 134.33,71.86 134.42,71.95 134.42,72.15 134.33,72.24 134.18,72.24 134.09,72.34 134.09,72.53 134.18,72.63 134.33,72.63 134.42,72.73 134.42,83.02 135.33,83.92 135.33,87.86 137.44,89.97 138.56,89.97 138.65,90.07 138.65,93.6 139.36,94.31 139.67,94.31 139.88,94.52 139.88,94.83 140.05,95
  BOTTOM w0.089: UC1.H25 v1(142.36,94.45)
  BOTTOM w0.107: JDIMM1.203 153.95,54.19 153.64,53.88 153.64,51.98 v1(154.33,51.28)
DDR_A_D18: length 67.6
  IN3 w0.089: v1(141.72,96.49) 141.72,96.49 141.62,96.49 141.23,96.87 140.93,96.87 140.93,96.87
  IN3 w0.097: v1(151.43,51.28) 150.95,51.28 150.85,51.38 150.85,53.11 141.53,62.44 139.7,62.44 131.76,70.38 131.76,80.8 131.85,80.9 132.51,80.9 132.61,81 132.61,81.28 132.51,81.38 131.85,81.38 131.76,81.48 131.76,81.67 131.85,81.77 132.51,81.77 132.61,81.86 132.61,83.35 133.69,84.42 133.69,88.7 134.72,89.74 136,89.74 137.68,91.41 137.68,91.88 137.27,92.29 137.27,93.39 139.01,95.13 139.01,95.48 140.4,96.87 140.93,96.87
  BOTTOM w0.089: v1(141.72,96.49) 141.72,96.49 UC1.G22
  BOTTOM w0.107: JDIMM1.191 150.95,51.76 v1(151.43,51.28)
DDR_A_D19: length 67.4
  IN3 w0.089: v1(142.36,96.49) 141.99,96.85 141.48,96.85 141.3,97.04 141.29,97.04 141.28,97.05
  IN3 w0.097: v1(151.43,49.76) 150.55,50.64 150.55,52.99 146.74,56.8 141.4,62.14 139.26,62.14 131.45,69.94 131.45,82.61 133.39,84.55 133.39,88.74 134.55,89.91 135.93,89.91 136.54,90.51 136.54,92.91 138.7,95.07 138.7,95.52 140.24,97.05 141.28,97.05
  BOTTOM w0.089: UC1.H22 v1(142.36,96.49)
  BOTTOM w0.107: JDIMM1.190 150.7,49.03 v1(151.43,49.76)
DDR_A_D20: length 71.2
  IN3 w0.097: v1(154.33,49.76) 154.73,50.16 154.73,52.97 154.42,53.29 153.67,53.29 139.02,67.94 138.88,67.94 138.25,67.3 138.11,67.3 137.97,67.44 137.97,67.57 138.61,68.21 138.61,68.35 138.47,68.48 138.34,68.48 137.7,67.85 137.56,67.85 137.43,67.98 137.43,68.12 138.06,68.76 138.06,68.89 137.93,69.03 137.79,69.03 137.15,68.39 137.02,68.39 136.88,68.53 136.88,68.67 137.52,69.3 137.52,69.44 137.38,69.58 137.24,69.58 136.61,68.94 136.47,68.94 136.33,69.08 136.33,69.21 136.97,69.85 136.97,69.99 136.84,70.12 136.7,70.12 136.06,69.48 135.92,69.48 135.79,69.62 135.79,69.76 136.43,70.4 136.43,70.53 136.29,70.67 136.15,70.67 135.68,70.2 135.55,70.2 135.41,70.34 135.41,70.47 135.63,70.69 135.63,78.88 135.64,78.88 135.64,82.95 136.3,83.61 136.3,87.9 137.3,88.9 138.06,88.9 139,89.84 139,93.01 140.44,94.45 v1(141.09,94.45)
  BOTTOM w0.089: UC1.F25 v1(141.09,94.45)
  BOTTOM w0.107: v1(154.33,49.76) 155.2,48.89 155.2,46.81 JDIMM1.208
DDR_A_D21: length 69.4
  IN3 w0.097: v1(142.99,94.45) 142.99,94.12 142.9,94.03 140.26,94.03 139.17,92.94 139.17,89.76 138.13,88.73 137.37,88.73 136.6,87.95 136.6,83.34 136.04,82.78 136.04,73.87 136.71,73.2 136.71,73.06 135.93,72.28 135.93,72.15 136.07,72.01 136.2,72.01 136.98,72.79 137.12,72.79 137.47,72.44 137.47,72.3 136.72,71.55 136.72,71.42 149.86,58.27 149.86,57.52 153.8,53.59 154.55,53.59 155.03,53.1 155.03,48.43 155.13,48.33 155.62,48.33 155.72,48.24 155.72,47.67 155.62,47.57 153.47,47.57 153.35,47.7 153.35,48.14 153.44,48.23 v1(154.33,48.23)
  BOTTOM w0.089: UC1.J25 v1(142.99,94.45)
  BOTTOM w0.107: JDIMM1.204 154.2,48.1 v1(154.33,48.23)
DDR_A_D22: length 68.1
  IN3 w0.097: v1(154.33,52.81) 153.73,52.81 141.94,64.6 141.8,64.6 141.41,64.21 141.28,64.21 141.11,64.38 141.11,64.52 141.5,64.9 141.5,65.04 141.36,65.17 141.22,65.17 140.57,64.53 140.44,64.53 140.3,64.66 140.3,64.8 140.95,65.45 140.95,65.58 140.81,65.72 140.68,65.72 140.03,65.07 139.89,65.07 139.75,65.21 139.75,65.35 140.4,65.99 140.4,66.13 140.27,66.27 140.13,66.27 139.48,65.62 139.34,65.62 139.21,65.75 139.21,65.89 139.86,66.54 139.86,66.68 139.72,66.81 139.58,66.81 138.93,66.16 138.8,66.16 138.66,66.3 138.66,66.44 139.31,67.09 139.31,67.22 139.17,67.36 139.04,67.36 138.39,66.71 138.25,66.71 135.11,69.85 135.11,83.18 135.82,83.89 135.82,87.66 137.23,89.07 137.37,89.07 137.37,89.07 137.99,89.07 138.83,89.91 138.83,93.22 140.44,94.83 141.35,94.83 v1(141.72,94.45)
  BOTTOM w0.089: UC1.G25 v1(141.72,94.45)
  BOTTOM w0.107: JDIMM1.207 154.95,53.43 v1(154.33,52.81)
DDR_A_D23: length 67.5
  IN3 w0.097: v1(151.43,52.81) 151.43,52.95 141.65,62.74 140.14,62.74 132.06,70.82 132.06,76.36 132.15,76.46 132.81,76.46 132.91,76.56 132.91,76.93 132.81,77.03 132.15,77.03 132.06,77.13 132.06,77.32 132.15,77.42 132.81,77.42 132.91,77.51 132.91,77.71 132.81,77.8 132.15,77.8 132.06,77.9 132.06,78.09 132.15,78.19 132.81,78.19 132.91,78.28 132.91,78.48 132.81,78.57 132.15,78.57 132.06,78.67 132.06,78.86 132.15,78.96 132.81,78.96 132.91,79.06 132.91,79.25 132.81,79.35 132.15,79.35 132.06,79.44 132.06,79.64 132.15,79.73 132.81,79.73 132.91,79.83 132.91,80.02 132.81,80.12 132.15,80.12 132.06,80.21 132.06,80.41 132.15,80.5 132.81,80.5 132.91,80.6 132.91,80.85 132.91,83.22 133.99,84.3 133.99,87.47 138.14,91.62 138.14,93.9 139.35,95.12 139.35,95.5 140.34,96.49
  IN3 w0.102: v1(141.09,96.49) 140.34,96.49
  BOTTOM w0.076: UC1.F22 v1(141.09,96.49)
  BOTTOM w0.107: JDIMM1.195 151.95,53.33 v1(151.43,52.81)
DDR_A_D24: length 76.4
  IN3 w0.097: v1(136.1,97.72) 135.7,97.33 130.68,97.33 127.05,93.7 127.05,91.76 124.02,88.73 124.02,84.62 126.82,81.82 126.82,79.81 127.74,78.89 127.74,76.65 127.64,76.55 126.92,76.55 126.82,76.46 126.82,76.27 126.92,76.17 127.64,76.17 127.74,76.07 127.74,75.88 127.64,75.78 126.92,75.78 126.82,75.69 126.82,75.49 126.92,75.4 127.64,75.4 127.74,75.3 127.74,75.11 127.64,75.01 126.92,75.01 126.82,74.91 126.82,74.72 126.92,74.62 127.64,74.62 127.74,74.53 127.74,67.64 141.07,54.31 142.62,54.31 143.31,53.62 144.72,53.62 145.85,52.49 146.19,52.49 146.28,52.59 v1(146.28,52.79)
  BOTTOM w0.076: UC1.D22 139.5,97.44 139.4,97.44 139.4,97.43 139.16,97.43 139.16,97.44 138.56,97.44 138.36,97.54 137.99,97.54 137.79,97.35 137.48,97.35 137.25,97.57
  BOTTOM w0.089: v1(136.1,97.72) 137.1,97.72 137.25,97.57
  BOTTOM w0.107: v1(146.28,52.79) 145.45,53.63 JDIMM1.169
DDR_A_D25: length 76.4
  IN3 w0.097: v1(132.92,97.72) 130.65,97.72 126.74,93.81 126.74,91.87 123.72,88.85 123.72,84.49 126.52,81.69 126.52,74.15 126.62,74.05 127.34,74.05 127.44,73.96 127.44,73.77 127.34,73.67 126.62,73.67 126.52,73.57 126.52,73.38 126.62,73.28 127.34,73.28 127.44,73.19 127.44,67.43 140.86,54.01 142.5,54.01 143.29,53.22 143.81,53.22 144.25,52.78 144.25,51.48 144.35,51.38 144.38,51.38 144.49,51.27 v1(146.28,51.27)
  BOTTOM w0.076: 134.97,97.09 135.04,97.02 137.12,97.02 137.28,96.85 138.3,96.85 138.42,96.89 138.65,96.89 138.77,96.85 138.95,96.85 139.35,97 139.47,97.12 UC1.C22
  BOTTOM w0.089: v1(132.92,97.72) 133.55,97.09 134.96,97.09 134.97,97.09
  BOTTOM w0.107: v1(146.28,51.27) 146.69,51.68 146.69,53.38 146.45,53.63 JDIMM1.173
DDR_A_D26: length 75.8
  IN3 w0.097: v1(149.65,48.2) 148.71,48.2 148.57,48.33 148.57,49.09 148.47,49.19 147.4,49.19 147.3,49.29 147.3,49.48 147.4,49.58 148.47,49.58 148.57,49.67 148.57,52.42 146.19,54.8 143.8,54.8 143.11,55.49 142.43,55.49 140.31,57.6 140.31,57.61 128.92,69 128.92,81.39 125.2,85.1 125.2,88.07 128.3,91.17 128.3,93.22 131.55,96.47 v1(131.82,96.47)
  BOTTOM w0.076: UC1.C24 139.19,95.5 138.56,95.5 138.36,95.39 137.99,95.39 137.79,95.59 137.48,95.59 137.32,95.43 135.79,95.43 135.78,95.43
  BOTTOM w0.089: 135.78,95.43 132.86,95.43 v1(131.82,96.47)
  BOTTOM w0.107: JDIMM1.186 149.7,48.14 v1(149.65,48.2)
DDR_A_D27: length 76.4
  IN3 w0.097: v1(149.65,52.77) 149.49,52.77 146.35,55.91 145.62,55.91 145.52,56.01 145.52,56.6 143.72,58.4 143.58,58.4 142.64,57.46 142.5,57.46 142.36,57.59 142.36,57.73 143.31,58.67 143.31,58.81 143.17,58.95 143.03,58.95 142.09,58 141.95,58 141.82,58.14 141.82,58.28 142.76,59.22 142.76,59.36 142.62,59.49 142.49,59.49 141.54,58.55 141.41,58.55 141.27,58.68 141.27,58.82 142.21,59.77 142.21,59.9 140.88,61.23 138.72,61.23 130.54,69.41 130.54,82.98 132.45,84.89 132.45,88.4 129.22,91.63 129.22,92.84 131.88,95.5 133.39,95.5 v1(134.36,96.47)
  BOTTOM w0.076: UC1.D24 140.16,96.55 139.96,96.76 139.71,96.76 139.16,96.76 138.98,96.69 138.74,96.69 138.63,96.73 138.44,96.73 138.33,96.69 138.33,96.69 137.21,96.69 137.05,96.85 134.74,96.85
  BOTTOM w0.089: 134.74,96.85 v1(134.36,96.47)
  BOTTOM w0.107: JDIMM1.183 148.95,53.46 v1(149.65,52.77)
DDR_A_D28: length 75.6
  IN3 w0.097: v1(146.28,49.75) 145.97,50.06 145.47,50.06 144.63,49.22 143.74,49.22 143.11,49.86 143.11,52.98 142.37,53.71 140.56,53.71 126.85,67.43 126.85,72.29 126.22,72.92 126.22,81.57 123.42,84.37 123.42,88.98 126.43,91.99 126.43,93.94 130.59,98.09 133.83,98.09 v1(134.19,97.72)
  BOTTOM w0.076: UC1.A22 138.11,97.02 137.34,97.02 137.18,97.18 135.13,97.18 135.06,97.25
  BOTTOM w0.089: 135.06,97.25 134.97,97.34 134.58,97.34 134.42,97.49 v1(134.19,97.72)
  BOTTOM w0.107: JDIMM1.170 145.7,49.16 v1(146.28,49.75)
DDR_A_D29: length 75.7
  IN3 w0.097: v1(134.83,97.72) 134.26,98.29 130.35,98.29 126.13,94.06 126.13,92.1 123.12,89.1 123.12,84.24 125.92,81.44 125.92,72.71 126.55,72.09 126.55,67.3 140.44,53.41 142.25,53.41 142.73,52.93 142.73,49.6 143.42,48.91 145.59,48.91 v1(146.28,48.22)
  BOTTOM w0.076: v1(134.83,97.72) 135.21,97.34 137.25,97.34 137.41,97.18 137.86,97.18 138.06,97.38 138.31,97.38 138.79,97.12 UC1.B22
  BOTTOM w0.107: JDIMM1.174 146.7,47.81 v1(146.28,48.22)
DDR_A_D30: length 75.4
  IN3 w0.097: v1(133.73,96.47) 133.73,96.08 133.43,95.78 131.72,95.78 128.9,92.95 128.9,91.53 132.15,88.28 132.15,85.01 130.23,83.1 130.23,82.62 130.14,82.53 129.73,82.53 129.63,82.43 129.63,82.24 129.73,82.14 130.14,82.14 130.23,82.04 130.23,81.85 130.14,81.75 129.73,81.75 129.63,81.66 129.63,81.46 129.73,81.37 130.14,81.37 130.23,81.27 130.23,81.08 130.14,80.98 129.73,80.98 129.63,80.88 129.63,80.69 129.73,80.6 130.14,80.6 130.23,80.5 130.23,80.31 130.14,80.21 129.73,80.21 129.63,80.11 129.63,79.92 129.73,79.82 130.14,79.82 130.23,79.73 130.23,79.53 130.14,79.44 129.73,79.44 129.63,79.34 129.63,79.15 129.73,79.05 130.14,79.05 130.23,78.95 130.23,78.76 130.14,78.66 129.73,78.66 129.63,78.57 129.63,78.38 129.73,78.28 130.14,78.28 130.23,78.18 130.23,69.3 143.92,55.61 144.1,55.61 144.2,55.71 144.2,56 144.3,56.1 144.49,56.1 144.59,56 144.59,55.71 144.68,55.61 146.22,55.61 149.24,52.59 149.24,51.65 v1(149.65,51.24)
  BOTTOM w0.076: UC1.A24 138.11,95.91 137.34,95.91 137.19,95.76 135.96,95.76 135.89,95.83
  BOTTOM w0.089: v1(133.73,96.47) 134.11,96.08 135.63,96.08 135.89,95.83
  BOTTOM w0.107: JDIMM1.187 149.95,53.63 150.27,53.31 150.27,51.87 v1(149.65,51.24)
DDR_A_D31: length 76.6
  IN3 w0.089: 130.09,89.91 130.97,89.03
  IN3 w0.097: v1(133.09,96.47) 132.6,95.98 131.5,95.98 128.6,93.08 128.6,91.4 130.09,89.91 ; v1(149.65,49.72) 148.87,50.5 148.87,52.54 146.1,55.31 143.77,55.31 142.34,56.74 141.81,56.74 129.93,68.62 129.93,74.36 129.84,74.46 129.31,74.46 129.22,74.55 129.22,74.75 129.31,74.84 129.84,74.84 129.93,74.94 129.93,75.13 129.84,75.23 129.31,75.23 129.22,75.33 129.22,75.52 129.31,75.62 129.84,75.62 129.93,75.71 129.93,75.91 129.84,76 129.31,76 129.22,76.1 129.22,76.29 129.31,76.39 129.84,76.39 129.93,76.48 129.93,76.68 129.84,76.77 129.31,76.77 129.22,76.87 129.22,77.06 129.31,77.16 129.84,77.16 129.93,77.26 129.93,77.45 129.84,77.55 129.31,77.55 129.22,77.64 129.22,82.51 131.85,85.13 131.85,88.15 130.97,89.03
  BOTTOM w0.076: UC1.B24 138.81,95.82 138.32,95.55 138.06,95.55 137.86,95.75 137.41,95.75 137.25,95.59 135.87,95.59 135.8,95.66
  BOTTOM w0.089: 135.8,95.66 135.31,95.66 135.23,95.66 135.14,95.76 133.8,95.76 v1(133.09,96.47)
  BOTTOM w0.107: v1(149.65,49.72) 148.7,48.77 JDIMM1.182
DDR_A_D32: length 54.8
  IN1 w0.099: v1(113.28,50.04) 113.9,50.04 114,50.13 114,53.08 114.55,53.63 114.55,57.91 133.95,77.31 133.95,79.28 137.19,82.52 137.19,83.36 v1(137.61,83.78)
  BOTTOM w0.076: 139.78,85.41 139.88,85.41 140.7,86.23 140.87,86.4 141.94,86.4 142.28,86.74 142.35,86.81 142.35,87.59 UC1.H37
  BOTTOM w0.089: v1(137.61,83.78) 138.27,84.44 138.27,84.96 138.72,85.41 139.78,85.41
  BOTTOM w0.107: JDIMM1.50 113.7,49.61 v1(113.28,50.04)
DDR_A_D33: length 56.4
  IN1 w0.099: v1(113.28,51.56) 112.86,51.97 112.86,56.42 113.94,57.5 113.94,58.16 133.34,77.56 133.34,79.53 136.66,82.84 136.66,85.11 137.23,85.69 v1(137.61,85.69)
  BOTTOM w0.076: UC1.H34 142.18,89.48 141.98,89.06 141.98,88.11 141.83,87.84 141.83,87.46 142.03,87.27 142.03,86.95 141.9,86.83 141.8,86.73 140.73,86.73 139.77,85.77 139.67,85.77
  BOTTOM w0.089: v1(137.61,85.69) 137.69,85.77 139.67,85.77
  BOTTOM w0.107: JDIMM1.45 112.45,52.39 v1(113.28,51.56)
DDR_A_D34: length 57.6
  IN1 w0.099: v1(138.92,84.81) 139.36,84.37 139.36,82.12 135.43,78.19 135.43,76.59 134.3,75.46 116.03,57.2 116.03,51.54 115.55,51.05 115.55,48.21 115.65,48.11 v1(116.78,48.11)
  BOTTOM w0.076: UC1.K34 142.82,89.63 142.79,89.6 142.61,89.42 142.61,88.65 142.68,88.45 142.68,88.21 142.64,88.1 142.64,87.92 142.68,87.8 142.68,86.68 142.61,86.61 142.49,86.48 142.08,86.07 141.01,86.07 140.93,85.99 139.99,85.05 139.16,85.05 v1(138.92,84.81)
  BOTTOM w0.107: JDIMM1.62 116.7,48.03 v1(116.78,48.11)
DDR_A_D35: length 56.6
  IN1 w0.099: v1(140.23,82.41) 140.23,81.82 136.77,78.36 136.77,76.65 127.54,67.42 118.53,58.41 118.53,57.03 117.84,56.33 117.55,56.33 117.46,56.24 117.46,55.92 117.55,55.82 117.63,55.82 117.72,55.72 117.72,55.52 117.63,55.42 117.55,55.42 117.46,55.33 117.46,51.85 117.36,51.75 117.28,51.75 117.18,51.65 117.18,51.45 117.28,51.35 117.36,51.35 117.46,51.25 117.46,50.88 117.36,50.78 116.91,50.78 116.78,50.91 v1(116.78,51.16)
  BOTTOM w0.076: UC1.K35 143.87,88.67 143.87,88.04 143.98,87.84 143.98,87.46 143.79,87.27 143.79,86.95 143.94,86.79 143.94,85.93 143.26,85.24 141.37,85.24 141.14,85.01 141.14,84.91
  BOTTOM w0.089: v1(140.23,82.41) 141.14,83.33 141.14,84.91
  BOTTOM w0.107: JDIMM1.63 116.95,54.12 117.38,53.69 117.38,51.75 v1(116.78,51.16)
DDR_A_D36: length 55.1
  IN1 w0.099: v1(137.61,84.42) 136.91,83.72 136.91,82.67 133.65,79.4 133.65,77.44 114.25,58.04 114.25,55.41 114.15,55.31 113.27,55.31 113.17,55.21 113.17,55.02 113.27,54.92 114.15,54.92 114.25,54.82 114.25,54.62 114.15,54.52 113.27,54.52 113.17,54.42 113.17,54.22 113.27,54.12 114.15,54.12 114.25,54.03 114.25,53.75 114.12,53.62 113.27,53.62 113.17,53.52 113.17,53.19 v1(113.28,53.08)
  BOTTOM w0.076: UC1.H36 142.26,88.28 141.99,87.8 141.99,87.53 142.19,87.33 142.19,86.88 141.87,86.56 140.8,86.56 139.83,85.59 139.73,85.59
  BOTTOM w0.089: 139.73,85.59 138.64,85.59 138,84.94 138,84.8 v1(137.61,84.42)
  BOTTOM w0.107: v1(113.28,53.08) 113.45,53.26 JDIMM1.49
DDR_A_D37: length 55.9
  IN1 w0.099: v1(137.61,82.51) 134.25,79.15 134.25,77.08 114.85,57.69 114.85,53.5 114.3,52.96 114.3,49.54 v1(113.28,48.51)
  BOTTOM w0.076: UC1.H35 142.35,88.89 142.52,88.43 142.52,88.24 142.48,88.13 142.48,87.89 142.52,87.78 142.52,86.75 142.01,86.23 140.94,86.23 139.94,85.23 139.84,85.23
  BOTTOM w0.089: 139.84,85.23 138.79,85.23 138.53,84.97 138.53,83.43 v1(137.61,82.51)
  BOTTOM w0.107: JDIMM1.46 112.7,47.93 v1(113.28,48.51)
DDR_A_D38: length 55.9
  IN1 w0.099: v1(140.23,83.68) 139.81,83.27 139.81,81.78 136.46,78.44 136.46,77.63 136.36,77.53 136.08,77.53 135.98,77.43 135.98,77.24 136.08,77.14 136.36,77.14 136.46,77.04 136.46,76.77 127.24,67.55 118.23,58.53 118.23,57.7 118.13,57.6 117.3,57.6 117.15,57.46 117.15,57.23 117.25,57.14 117.81,57.14 117.91,57.04 117.91,56.84 117.81,56.74 117.25,56.74 117.15,56.64 117.15,55.46 117.05,55.36 116.74,55.36 116.64,55.26 116.64,55.06 116.74,54.96 117.05,54.96 117.15,54.87 117.15,54.67 117.05,54.57 116.74,54.57 116.64,54.47 116.64,54.27 116.74,54.17 117.05,54.17 117.15,54.07 117.15,53.87 117.05,53.78 116.74,53.78 116.64,53.68 116.64,53.48 116.74,53.38 117.05,53.38 117.15,53.28 117.15,52.78 117.05,52.68 v1(116.78,52.68)
  BOTTOM w0.076: 140.97,84.97 140.97,85.07 141.31,85.41 143.19,85.41 143.78,86 143.78,86.73 143.62,86.88 143.62,87.33 143.82,87.53 143.82,87.8 143.56,88.28 UC1.K36
  BOTTOM w0.089: v1(140.23,83.68) 140.97,84.42 140.97,84.97
  BOTTOM w0.107: JDIMM1.59 115.95,54.08 116.78,53.25 v1(116.78,52.68)
DDR_A_D39: length 55.8
  IN1 w0.099: v1(140.23,84.32) 139.67,84.32 139.57,84.22 139.57,81.81 135.73,77.97 135.73,76.47 126.94,67.67 126.94,67.67 124.33,65.06 116.85,57.59 116.85,55.9 116.34,55.39 116.34,51.33 115.85,50.84 115.85,49.32 115.95,49.22 116.37,49.22 v1(116.78,49.63)
  BOTTOM w0.076: v1(140.23,84.32) 140.23,84.56 141.24,85.57 143.12,85.57 143.61,86.07 143.61,86.66 143.46,86.82 143.46,87.59 UC1.K37
  BOTTOM w0.107: JDIMM1.58 115.7,48.55 v1(116.78,49.63)
DDR_A_D40: length 55.9
  IN1 w0.099: v1(141.53,83.59) 140.98,83.59 140.88,83.5 140.88,81.33 137.68,78.13 137.68,76.17 120.49,58.98 120.49,58.21 120.39,58.11 119.54,58.11 119.44,58.01 119.44,55.95 118.36,54.88 118.36,52.3 118.53,52.13 118.53,51.9 118.36,51.74 118.36,51.5 118.53,51.34 118.53,51.11 118.36,50.95 118.36,50.71 118.53,50.55 118.53,50.32 118.36,50.15 118.36,49.85 118.46,49.75 118.76,49.75 118.93,49.92 v1(118.93,50.08)
  BOTTOM w0.076: UC1.N36 144.77,88.28 144.51,87.8 144.51,87.53 144.71,87.33 144.71,86.88 144.55,86.73 144.55,85.98 143.42,84.85 142.5,84.85 142.43,84.78
  BOTTOM w0.089: 142.43,84.78 141.92,84.27 141.92,83.98 v1(141.53,83.59)
  BOTTOM w0.107: v1(118.93,50.08) 117.7,48.84 JDIMM1.66
DDR_A_D41: length 55.6
  IN1 w0.099: v1(118.93,48.55) 118.06,49.42 118.06,55 119.14,56.08 119.14,58.16 124.83,63.85 137.37,76.39 137.37,78.33 140.61,81.57 140.61,83.95 v1(141.53,84.86)
  BOTTOM w0.076: UC1.N34 144.7,89.48 144.45,88.98 144.45,88.88 144.45,88.87 144.45,88.63 144.45,88.04 144.34,87.84 144.34,87.46 144.54,87.27 144.54,86.95 144.38,86.79 144.38,86.05 143.35,85.02 142.4,85.02 142.33,84.95
  BOTTOM w0.102: v1(141.53,84.86) 142.25,84.86 142.33,84.95
  BOTTOM w0.107: v1(118.93,48.55) 118.75,48.55 118.64,48.45 118.64,47.79 118.7,47.73 JDIMM1.70
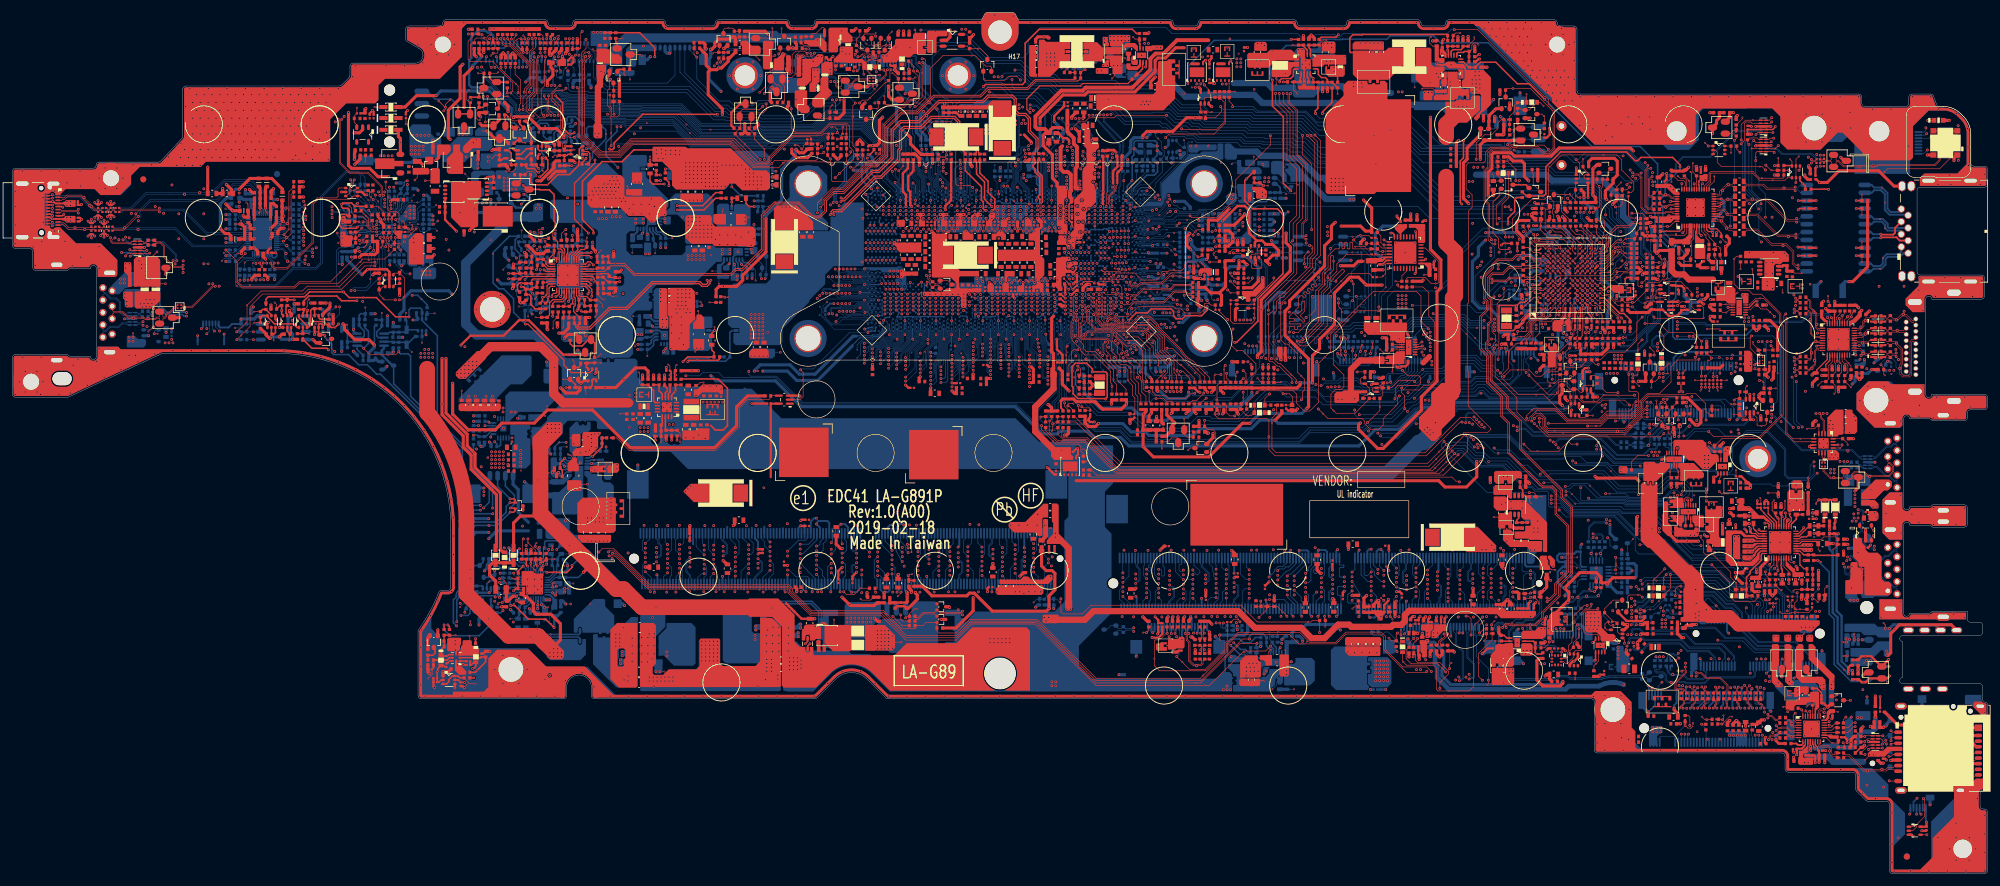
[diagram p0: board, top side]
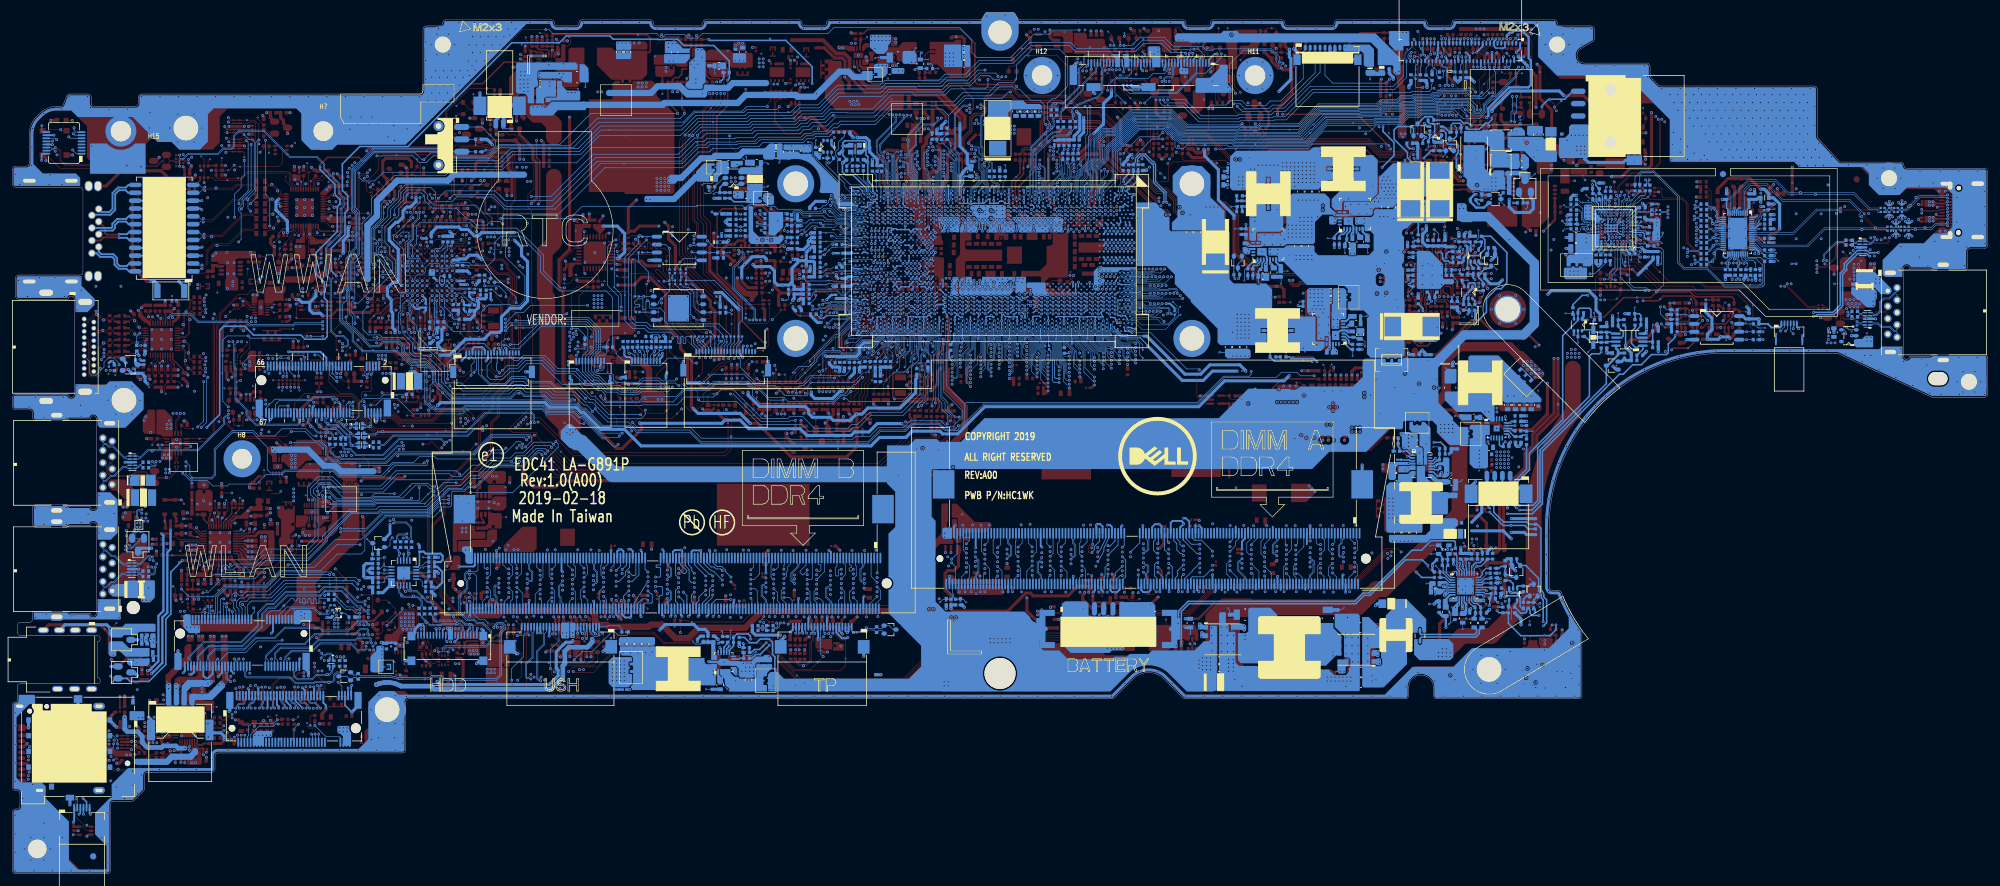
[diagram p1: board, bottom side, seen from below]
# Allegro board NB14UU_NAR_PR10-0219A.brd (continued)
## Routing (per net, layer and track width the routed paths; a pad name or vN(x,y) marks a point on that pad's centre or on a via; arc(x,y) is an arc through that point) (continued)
DDR_A_D42: length 55
  IN1 w0.099: v1(122.38,52.08) 122.06,52.08 121.96,52.18 121.96,53.75 122.33,54.13 123.07,54.13 123.22,54.27 123.22,54.5 123.22,54.5 123.22,56.75 123.12,56.85 122.77,56.85 122.67,56.95 122.67,57.15 122.77,57.25 123.12,57.25 123.22,57.35 123.22,57.54 123.05,57.71 122.67,57.71 122.57,57.81 122.57,58 122.67,58.1 123.28,58.1 123.38,58.2 123.38,58.92 123.48,59.02 123.74,59.02 123.84,58.92 123.84,58.02 124.01,57.86 124.21,57.86 124.37,58.02 124.37,59.91 139.85,75.39 139.85,75.79 141.79,77.73 141.79,79.2 143.52,80.92 143.52,83.32 143.62,83.42 v1(144.28,83.42)
  BOTTOM w0.076: v1(144.28,83.42) 144.28,84.23 146.13,86.08 146.13,86.66 145.98,86.82 145.98,87.59 UC1.R37
  BOTTOM w0.107: JDIMM1.79 120.95,54.17 121.5,53.62 121.5,52.95 v1(122.38,52.08)
DDR_A_D43: length 55.8
  IN1 w0.099: v1(122.38,50.55) 121.85,50.55 121.65,50.76 121.65,53.67 121.64,53.67 121.64,53.87 122.91,55.14 122.91,56.28 122.27,56.92 122.27,58.24 139.46,75.43 139.46,77.37 143.26,81.17 143.26,83.72 143.12,83.85 v1(142.84,84.14)
  BOTTOM w0.076: 143.52,84.35 143.62,84.35 145.04,85.78 145.04,86.53 145.2,86.69 145.2,87.8 145.16,87.92 145.16,88.1 145.2,88.21 145.2,88.45 145.12,88.68 145.12,89.41 145.13,89.43 145.34,89.63 UC1.R34
  BOTTOM w0.089: 143.52,84.35 143.05,84.35 v1(142.84,84.14)
  BOTTOM w0.107: v1(122.38,50.55) 122.9,50.03 122.9,48.42 122.2,47.72 JDIMM1.84
DDR_A_D44: length 54.9
  IN1 w0.099: v1(118.93,53.12) 118.77,53.12 118.67,53.22 118.67,53.51 118.77,53.6 119.4,53.6 119.5,53.7 119.5,53.95 119.4,54.05 118.89,54.05 118.67,54.27 118.67,54.75 118.85,54.94 118.99,54.94 119.38,54.56 119.57,54.56 119.7,54.69 119.7,54.83 119.49,55.04 119.49,55.18 119.63,55.32 119.77,55.32 120.08,55.02 120.22,55.02 120.46,55.26 120.46,55.4 119.74,56.12 119.74,56.69 119.84,56.79 120.69,56.79 120.79,56.89 120.79,57.09 120.69,57.19 119.84,57.19 119.74,57.29 119.74,57.71 119.84,57.81 120.65,57.81 120.79,57.95 120.79,58.86 137.98,76.05 137.98,77.48 141.16,80.66 141.16,82.91 141.21,82.96 v1(141.53,82.96)
  BOTTOM w0.076: 142.51,84.62 142.58,84.69 143.49,84.69 144.71,85.91 144.71,86.66 144.87,86.82 144.87,87.59 UC1.N37
  BOTTOM w0.089: 142.51,84.62 142.18,84.29 142.18,83.61 v1(141.53,82.96)
  BOTTOM w0.107: JDIMM1.67 117.95,54.22 118.93,53.24 v1(118.93,53.12)
DDR_A_D45: length 54.9
  IN1 w0.099: v1(141.53,81.69) 141.53,80.48 138.28,77.23 138.28,75.92 121.09,58.73 121.09,54.99 120.46,54.35 120.46,53.12 119.99,52.66 119.99,50.97 119.82,50.81 119.6,50.81 119.44,50.97 119.44,51.45 119.28,51.6 v1(118.93,51.6)
  BOTTOM w0.076: UC1.N35 144.87,88.89 145.04,88.43 145.04,88.24 145,88.13 145,87.89 145.04,87.78 145.04,86.75 144.88,86.6 144.88,85.84 143.56,84.52 142.67,84.52 142.6,84.45
  BOTTOM w0.089: 142.6,84.45 142.54,84.39 142.45,84.3 142.45,82.61 v1(141.53,81.69)
  BOTTOM w0.107: JDIMM1.71 118.95,54.15 119.66,53.44 119.66,51.98 119.29,51.6 v1(118.93,51.6)
DDR_A_D46: length 55.7
  IN1 w0.099: v1(122.38,53.6) 122.38,53.4 122.59,53.18 122.79,53.18 122.99,53.39 122.99,53.73 123.09,53.83 124.47,53.83 124.73,54.08 124.73,54.52 124.63,54.62 123.62,54.62 123.52,54.72 123.52,54.92 123.62,55.02 124.63,55.02 124.73,55.12 124.73,55.32 124.63,55.41 123.62,55.41 123.52,55.51 123.52,55.71 123.62,55.81 124.29,55.81 124.39,55.91 124.39,56.11 124.29,56.21 123.62,56.21 123.52,56.31 123.52,56.5 123.62,56.6 124.29,56.6 124.39,56.7 124.39,56.9 124.29,57 123.62,57 123.52,57.1 123.52,57.3 123.62,57.4 124.5,57.4 124.73,57.62 124.73,59.84 140.2,75.32 140.2,75.64 142.11,77.54 142.11,79.07 143.82,80.78 143.82,82.68 143.92,82.78 v1(144.28,82.78)
  BOTTOM w0.076: 144.64,84.02 144.64,84.36 146.3,86.01 146.3,86.73 146.14,86.88 146.14,87.33 146.34,87.53 146.34,87.8 146.07,88.28 UC1.R36
  BOTTOM w0.089: 144.64,84.02 144.64,83.14 v1(144.28,82.78)
  BOTTOM w0.107: JDIMM1.83 121.95,54.03 v1(122.38,53.6)
DDR_A_D47: length 55.2
  IN1 w0.099: v1(122.38,49.03) 122.38,48.63 122.55,48.46 123.2,48.46 123.3,48.56 123.3,53.04 123.78,53.52 124.6,53.52 125.03,53.96 125.03,55.57 124.69,55.91 124.69,56.89 125.03,57.23 125.03,59.72 140.66,75.35 140.66,75.65 142.37,77.36 142.37,78.85 144.28,80.76 v1(144.28,81.51)
  BOTTOM w0.076: 144.86,83.81 144.86,84.35 146.46,85.95 146.46,86.79 146.3,86.95 146.3,87.27 146.5,87.46 146.5,87.84 146.39,88.04 146.39,88.67 UC1.R35
  BOTTOM w0.089: v1(144.28,81.51) 144.86,82.1 144.86,83.81
  BOTTOM w0.107: JDIMM1.80 121.2,47.85 v1(122.38,49.03)
DDR_A_D48: length 59.1
  IN3 w0.097: v1(156.61,52.77) 156.61,53.22 155.05,54.79 154.29,54.79 151.87,57.22 151.87,57.97 140.72,69.11 140.72,69.25 141.48,70 141.48,70.14 141.34,70.27 141.2,70.27 140.45,69.52 140.32,69.52 140.18,69.66 140.18,69.79 140.93,70.55 140.93,70.68 140.79,70.82 140.66,70.82 139.91,70.07 139.77,70.07 139.63,70.2 139.63,70.34 140.38,71.09 140.38,71.23 140.25,71.36 140.11,71.36 139.36,70.61 139.22,70.61 139.09,70.75 139.09,70.89 139.84,71.64 139.84,71.77 137.25,74.36 137.25,86.29 137.53,86.57 137.93,86.57 138.74,87.38 138.74,88.47 140.44,90.17 140.44,90.61 v1(140.93,91.1)
  BOTTOM w0.089: UC1.G31 v1(140.93,91.1)
  BOTTOM w0.107: JDIMM1.211 155.95,53.43 v1(156.61,52.77)
DDR_A_D49: length 61.6
  IN3 w0.097: v1(140.93,90.46) 141.12,90.27 141.12,89.96 140.96,89.8 140.58,89.8 140.31,89.52 140.04,89.52 138.99,88.47 138.99,87.35 137.98,86.35 137.98,74.06 141.97,70.07 141.97,69.93 141.22,69.18 141.22,69.04 141.35,68.91 141.49,68.91 142.24,69.66 142.38,69.66 142.52,69.52 142.52,69.38 141.76,68.63 141.76,68.5 141.9,68.36 142.04,68.36 142.49,68.81 142.79,69.11 142.93,69.11 143.06,68.97 143.06,68.84 142.49,68.27 142.31,68.09 142.31,67.95 142.45,67.81 142.58,67.81 143.12,68.35 143.33,68.57 143.47,68.57 143.61,68.43 143.61,68.29 143.12,67.81 142.86,67.54 142.86,67.4 152.17,58.09 152.17,57.34 154.42,55.09 155.17,55.09 157.02,53.24 157.02,51.34 156.92,51.24 v1(156.61,51.24)
  BOTTOM w0.089: UC1.G32 v1(140.93,90.46)
  BOTTOM w0.107: JDIMM1.215 156.95,53.74 157.04,53.65 157.04,51.67 v1(156.61,51.24)
DDR_A_D50: length 60
  IN3 w0.089: 142.13,89.95 142.41,90.23 142.41,90.7 142.23,90.88 142.23,90.88 142.21,90.89 142.21,92.4 142.13,92.49 141.96,92.49 v1(141.84,92.37)
  IN3 w0.097: 142.13,89.95 142.13,89.06 139.86,86.79 139.86,74.69 148.37,66.18 148.37,66.05 147.62,65.29 147.62,65.16 147.75,65.02 147.89,65.02 148.64,65.77 148.78,65.77 148.97,65.58 148.97,65.44 148.22,64.69 148.22,64.56 148.36,64.42 148.49,64.42 149.24,65.17 149.38,65.17 149.52,65.03 149.52,64.9 148.77,64.15 148.77,64.01 148.9,63.87 149.04,63.87 149.37,64.2 149.5,64.2 149.64,64.06 149.64,63.93 149.31,63.6 149.31,63.46 155.69,57.09 156.4,57.09 157,56.5 157,56.08 159.49,53.59 159.49,52.49 159.59,52.4 159.76,52.4 159.92,52.55 v1(159.92,52.68)
  BOTTOM w0.089: UC1.H29 v1(141.84,92.37)
  BOTTOM w0.107: v1(159.92,52.68) 159.45,53.14 159.45,55.01 JDIMM1.225
DDR_A_D51: length 60.8
  IN3 w0.089: v1(141.84,93) 142.38,92.47 142.38,90.96 142.39,90.95 142.39,90.95 142.59,90.75 142.59,90.16 142.42,89.99 142.32,89.89
  IN3 w0.097: 142.32,89.89 142.32,88.95 140.62,87.25 140.62,81.84 140.22,81.43 140.22,74.76 150.01,64.97 150.01,64.83 149.72,64.54 149.72,64.41 149.86,64.27 150,64.27 150.28,64.56 150.42,64.56 150.56,64.42 150.56,64.28 149.81,63.53 149.81,63.4 149.94,63.26 150.08,63.26 150.83,64.01 150.97,64.01 151.12,63.85 151.12,63.64 150.41,62.92 150.41,62.79 155.81,57.39 156.53,57.39 157.3,56.62 157.3,56.2 160.32,53.18 160.32,51.25 160.22,51.16 v1(159.92,51.16)
  BOTTOM w0.089: UC1.H28 v1(141.84,93)
  BOTTOM w0.107: JDIMM1.229 160.45,54.11 160.63,53.92 160.63,51.87 v1(159.92,51.16)
DDR_A_D52: length 59.4
  IN3 w0.097: v1(156.61,48.2) 155.64,49.17 155.64,53.35 154.8,54.19 154.05,54.19 151.27,56.97 151.27,57.72 151.11,57.88 150.97,57.88 150.74,57.64 150.6,57.64 150.46,57.78 150.46,57.91 150.7,58.15 150.7,58.29 137.57,71.42 137.57,71.55 138.32,72.3 138.32,72.44 136.65,74.12 136.65,82.37 136.77,82.5 136.77,87.88 137.45,88.55 138.21,88.55 139.34,89.69 139.34,90.45 140.14,91.25 140.14,92.21 v1(140.93,93)
  BOTTOM w0.089: UC1.G28 v1(140.93,93)
  BOTTOM w0.107: JDIMM1.216 157.2,47.61 v1(156.61,48.2)
DDR_A_D53: length 60.8
  IN3 w0.097: v1(156.61,49.72) 156.37,49.48 156.04,49.48 155.94,49.57 155.94,53.47 154.92,54.49 154.17,54.49 151.57,57.09 151.57,57.84 138.61,70.8 138.61,70.94 139.36,71.69 139.36,71.83 139.23,71.96 139.09,71.96 138.34,71.21 138.2,71.21 138.06,71.35 138.06,71.48 138.82,72.24 138.82,72.37 136.95,74.24 136.95,87.81 137.52,88.38 138.28,88.38 139.52,89.62 139.52,90.38 140.31,91.18 140.31,92.14 140.54,92.37 v1(140.93,92.37)
  BOTTOM w0.089: UC1.G29 v1(140.93,92.37)
  BOTTOM w0.107: JDIMM1.212 156.2,49.31 v1(156.61,49.72)
DDR_A_D54: length 60.8
  IN3 w0.089: 141.94,90.01 142.22,90.3 142.22,90.64 141.94,90.92 141.94,91 v1(141.84,91.1)
  IN3 w0.097: 141.94,90.01 141.94,89.15 139.69,86.9 139.69,81.98 139.56,81.85 139.56,74.57 146.79,67.34 146.79,67.21 146.03,66.45 146.03,66.32 146.17,66.18 146.31,66.18 147.06,66.93 147.19,66.93 147.33,66.8 147.33,66.66 146.58,65.91 146.58,65.77 146.72,65.64 146.85,65.64 147.6,66.39 147.74,66.39 147.88,66.25 147.88,66.11 147.13,65.36 147.13,65.23 155.56,56.79 156.28,56.79 156.7,56.37 156.7,55.95 159.19,53.46 159.19,49.73 159.29,49.63 v1(159.92,49.63)
  BOTTOM w0.089: UC1.H31 v1(141.84,91.1)
  BOTTOM w0.107: v1(159.92,49.63) 159.2,48.92 JDIMM1.224
DDR_A_D55: length 62
  IN3 w0.089: 139.51,87 141.74,89.23 141.74,90.36 v1(141.84,90.46)
  IN3 w0.097: 139.51,87 139.51,82.19 139.24,81.92 139.24,74.46 146.29,67.41 146.29,67.27 145.54,66.52 145.54,66.39 157.96,53.97 158.89,53.04 158.89,49.78 158.79,49.68 157.25,49.68 157.16,49.59 157.16,49.39 157.25,49.3 158.97,49.3 159.06,49.2 159.06,49.01 158.97,48.91 157.25,48.91 157.16,48.81 157.16,48.2 157.25,48.11 v1(159.92,48.11)
  BOTTOM w0.089: UC1.H32 v1(141.84,90.46)
  BOTTOM w0.107: v1(159.92,48.11) 160.2,47.82 JDIMM1.228
DDR_A_D56: length 60.7
  IN3 w0.097: v1(161.97,53.12) 161.97,53.23 158.5,56.7 158.5,57.12 156.73,58.9 156.59,58.9 156.37,58.67 156.23,58.67 156.09,58.81 156.09,58.95 156.32,59.17 156.32,59.31 156.18,59.44 156.04,59.44 155.82,59.22 155.68,59.22 155.55,59.36 155.55,59.49 155.77,59.72 155.77,59.85 155.63,59.99 155.5,59.99 155.27,59.77 155.14,59.77 155,59.9 155,60.04 155.22,60.26 155.22,60.4 154.93,60.7 154.79,60.7 154.58,60.49 154.44,60.49 154.2,60.73 154.2,60.87 154.93,61.6 154.93,61.75 154.78,61.9 154.64,61.9 153.89,61.15 153.75,61.15 153.61,61.29 153.61,61.43 154.37,62.18 154.37,62.31 154.23,62.45 154.09,62.45 153.34,61.7 153.2,61.7 153.07,61.84 153.07,61.97 153.82,62.72 153.82,62.86 153.68,63 153.55,63 152.79,62.24 152.66,62.24 152.52,62.38 152.52,62.52 153.27,63.27 153.27,63.41 141.54,75.14 141.54,81.1 141.17,81.47 141.17,85.98 142.96,87.77 142.96,89.61 143.12,89.78 143.28,89.93 143.28,90.62 143.66,91 v1(143.66,91.1)
  BOTTOM w0.089: UC1.L31 v1(143.66,91.1)
  BOTTOM w0.107: JDIMM1.233 161.45,53.65 v1(161.97,53.12)
DDR_A_D57: length 61.4
  IN3 w0.097: v1(143.66,90.46) 143.66,90.01 143.19,89.54 143.19,87.73 141.9,86.44 141.9,75.21 155.23,61.87 155.23,60.81 158.8,57.25 158.8,56.87 162.38,53.29 162.38,52.81 162.54,52.65 162.79,52.65 162.92,52.52 162.92,49.39 163.02,49.29 163.97,49.29 164.06,49.19 164.06,48.81 163.97,48.71 162.51,48.71 162.41,48.81 162.41,51.5 162.32,51.6 v1(161.97,51.6)
  BOTTOM w0.089: UC1.L32 v1(143.67,90.46)
  BOTTOM w0.107: JDIMM1.237 162.45,54.01 162.54,53.92 162.54,52.17 v1(161.97,51.6)
DDR_A_D58: length 59.4
  IN3 w0.089: 144.71,75.31 144.71,86.57 145.14,87 145.14,90.68 144.94,90.88 144.94,92.01 v1(144.58,92.37)
  IN3 w0.097: v1(164.96,50.27) 165.37,49.86 165.8,49.86 165.9,49.95 165.9,50.26 166,50.36 166.31,50.36 166.43,50.48 166.43,50.79 166.33,50.89 165.56,50.89 165.46,50.98 165.46,51.17 165.56,51.27 166.33,51.27 166.43,51.37 166.43,52.84 163,56.27 163,56.84 144.71,75.13 144.71,75.31
  BOTTOM w0.089: UC1.N29 v1(144.58,92.37)
  BOTTOM w0.107: v1(164.96,50.27) 164.43,49.74 164.43,47.91 164.7,47.64 JDIMM1.246
DDR_A_D59: length 59.2
  IN3 w0.089: 145.06,75.31 145.06,86.65 145.32,86.91 145.32,90.74 145.12,90.94 145.12,92.46 v1(144.58,93)
  IN3 w0.097: v1(164.96,48.74) 166.63,48.74 166.73,48.84 166.73,49.34 166.63,49.44 166.19,49.44 166.09,49.53 166.09,49.72 166.19,49.82 166.63,49.82 166.73,49.92 166.73,52.96 163.3,56.39 163.3,56.96 145.06,75.2 145.06,75.31
  BOTTOM w0.089: UC1.N28 v1(144.58,93)
  BOTTOM w0.107: JDIMM1.250 165.7,48 v1(164.96,48.74)
DDR_A_D60: length 57.2
  IN3 w0.097: v1(161.97,48.55) 160.92,49.6 160.92,53.43 157.9,56.45 157.9,56.87 156.78,57.99 156.06,57.99 151.73,62.33 151.73,64.1 140.82,75.01 140.82,87.14 142.54,88.86 142.54,89.86 142.56,89.88 142.91,90.23 142.91,90.74 143.12,90.95 143.12,90.96 143.12,90.97 143.12,92.46 v1(143.66,93)
  BOTTOM w0.089: UC1.L28 v1(143.66,93)
  BOTTOM w0.107: v1(161.97,48.55) 162.2,48.33 JDIMM1.236
DDR_A_D61: length 58.5
  IN3 w0.097: v1(143.66,92.37) 143.29,92 143.29,90.89 143.29,90.89 143.29,90.88 143.1,90.68 143.1,90.07 142.99,89.96 142.71,89.68 142.71,88.75 140.99,87.03 140.99,81.33 141.22,81.1 141.22,75.04 152.78,63.47 152.78,63.34 152.03,62.59 152.03,62.45 156.19,58.29 156.9,58.29 158.2,57 158.2,56.58 161.57,53.21 161.57,51.81 161.47,51.71 161.32,51.71 161.22,51.62 161.22,51.12 161.32,51.02 161.47,51.02 161.57,50.93 161.57,50.73 161.47,50.64 161.32,50.64 161.22,50.54 161.22,50.17 161.32,50.08 v1(161.97,50.08)
  BOTTOM w0.089: UC1.L29 v1(143.66,92.37)
  BOTTOM w0.107: JDIMM1.232 161.2,49.3 v1(161.97,50.08)
DDR_A_D62: length 59.6
  IN3 w0.089: v1(144.58,91.1) 144.58,91.01 144.96,90.62 144.96,90.6 144.96,87.1 143.4,85.54 143.4,79.33
  IN3 w0.097: 143.4,79.33 143.68,79.05 143.68,75.52 147.21,71.99 162.19,57.01 162.19,55.92 162.29,55.83 163.02,55.83 163.18,55.67 163.18,55.53 162.77,55.13 162.77,54.99 162.91,54.85 163.04,54.85 163.45,55.26 163.59,55.26 163.72,55.12 163.72,54.99 163.32,54.58 163.32,54.44 163.45,54.31 163.59,54.31 164,54.71 164.13,54.71 165.36,53.48 165.36,52.88 165.46,52.78 166.03,52.78 166.13,52.68 166.13,52.49 166.03,52.39 165.43,52.39 165.33,52.3 165.33,52.1 165.43,52.01 166.03,52.01 166.13,51.91 166.13,51.67 166.03,51.57 165.18,51.57 v1(164.96,51.79)
  BOTTOM w0.089: UC1.N31 v1(144.58,91.1)
  BOTTOM w0.107: JDIMM1.249 165.45,52.28 v1(164.96,51.79)
DDR_A_D63: length 60.9
  IN3 w0.089: v1(144.58,90.46) 144.58,89.99 144.58,89.48 144.58,86.96 143.22,85.61 143.22,81.48
  IN3 w0.097: 143.22,81.48 143.22,75.56 144.49,74.29 157.89,60.9 157.89,60.76 157.49,60.36 157.49,60.22 157.62,60.09 157.76,60.09 158.16,60.49 158.3,60.49 158.43,60.35 158.43,60.21 158.03,59.82 158.03,59.68 158.17,59.54 158.31,59.54 158.71,59.94 158.84,59.94 158.98,59.8 158.98,59.67 158.58,59.27 158.58,59.13 158.72,59 158.85,59 159.25,59.39 159.39,59.39 159.52,59.26 159.52,59.12 159.13,58.72 159.13,58.59 159.26,58.45 159.4,58.45 159.8,58.85 159.93,58.85 160.07,58.71 160.07,58.58 159.67,58.18 159.67,58.04 159.81,57.9 159.95,57.9 160.34,58.3 160.48,58.3 160.62,58.17 160.62,58.03 160.03,57.44 160.03,57.31 160.17,57.17 160.3,57.17 160.89,57.76 161.03,57.76 161.16,57.62 161.16,57.48 160.58,56.9 160.58,56.76 160.71,56.62 160.85,56.62 161.44,57.21 161.57,57.21 161.89,56.89 161.89,56.39 161.48,55.97 161.48,55.86 161.81,55.53 162.26,55.53 162.47,55.32 162.47,54.86 163.48,53.86 163.62,53.86 164.02,54.26 164.16,54.26 164.4,54.02 164.4,53.66 164.74,53.31 v1(164.96,53.31)
  BOTTOM w0.089: UC1.N32 v1(144.58,90.46)
  BOTTOM w0.107: v1(164.96,53.31) 164.45,53.82 JDIMM1.245
DDR_A_DQS0: length 73.1
  IN1 w0.089: v1(104.04,51.16) 103.81,51.38 103.34,51.38 103.14,51.58 103.14,55.68 103.25,55.8 103.25,58.29 104.11,59.15 104.11,59.27 103.88,59.5 103.88,59.78 104.17,60.07 104.45,60.07 104.68,59.84 104.8,59.84 109.16,64.2 111.3,64.2 123.84,76.73 123.84,88.44 127.87,92.47 130.05,92.47 130.17,92.47 130.89,93.19 v1(130.89,93.79)
  BOTTOM w0.076: 133.55,94.42 133.65,94.42 133.73,94.34 136.52,94.34 136.62,94.43 136.68,94.49 137.12,94.49 137.28,94.34 138.3,94.34 138.42,94.38 138.65,94.38 138.77,94.34 138.95,94.34 139.07,94.38 139.3,94.38 139.51,94.3 139.61,94.09 139.75,93.95 UC1.D27
  BOTTOM w0.089: v1(130.89,93.79) 130.89,94.42 131.09,94.61 132.21,94.61 132.4,94.42 132.87,94.42 133.55,94.42
  BOTTOM w0.097: JDIMM1.13 104.45,53.46 104.88,53.03 104.88,51.37 104.66,51.16 v1(104.04,51.16)
DDR_A_DQS1: length 65.5
  IN1 w0.089: v1(132.47,90.49) 132.33,90.49 132.24,90.4 132.24,90.14 132.46,89.92 133.1,89.92 134.04,88.97 134.04,86.85 134.04,86.85 134.04,86.69 134.17,86.56 134.17,85.58 134.17,85.58 134.17,84.21 129.85,79.89 129.85,78.69 129.02,77.85 129.02,76.56 110.09,57.64 110.09,50.92 109.89,50.72 109.61,50.72 109.44,50.55 v1(109.44,50.32)
  BOTTOM w0.076: 133.63,91.33 133.67,91.33 133.74,91.26 136.19,91.26 136.74,91.81 137.06,91.81 137.21,91.66 138.33,91.66 138.33,91.66 138.44,91.7 138.63,91.7 138.74,91.66 138.98,91.66 139.09,91.7 139.28,91.7 139.39,91.66 139.44,91.56 139.39,91.44 139.3,91.39 UC1.C31
  BOTTOM w0.089: v1(132.47,90.49) 132.26,90.69 132.26,91.24 132.35,91.33 133.63,91.33
  BOTTOM w0.097: JDIMM1.34 109.7,47.71 109.54,47.86 109.54,48.24 108.97,48.82 108.97,50.01 108.94,50.03 108.94,50.46 109.09,50.61 109.33,50.61 109.44,50.51 v1(109.44,50.32)
DDR_A_DQS2: length 68.4
  IN3 w0.089: v1(141.72,95.36) 141.88,95.36 142.03,95.51 142.03,95.74 141.94,95.83 140.36,95.83 139.76,95.23 139.76,94.94 138.48,93.67 138.48,90.49 138.13,90.14 137.37,90.14 134.83,87.6 134.83,86.97 134.83,86.97 134.83,86.77 134.83,86.77 134.83,86.52 134.83,86.52 134.83,84.17 133.59,82.93 133.59,78.47 133.59,75.97 133.39,75.78 132.82,75.78 132.74,75.69 132.74,75.42 132.82,75.34 133.39,75.34 133.59,75.14 133.59,74.72 133.39,74.53 132.82,74.53 132.74,74.44 132.74,74.17 132.82,74.09 133.39,74.09 133.59,73.89 133.59,70.25 140.42,63.42 141.93,63.42 152.12,53.22 152.12,50.76 152.21,50.67 152.56,50.67 152.78,50.9 v1(152.78,51.09)
  BOTTOM w0.089: UC1.G24 v1(141.72,95.36)
  BOTTOM w0.097: v1(152.78,51.09) 152.78,50.9 153.17,50.52 153.32,50.52 153.52,50.31 153.52,48.71 153.04,48.24 153.04,47.67 153.2,47.51 JDIMM1.200
DDR_A_DQS3: length 75.7
  IN3 w0.089: v1(135.63,96.47) 135.75,96.47 136,96.71 136,96.84 135.91,96.92 131.23,96.92 129.89,95.58 129.89,95.58 127.8,93.49 127.8,91.54 124.7,88.45 124.7,84.9 128.42,81.18 128.42,68.74 142.16,54.99 142.9,54.99 143.12,54.77 143.6,54.3 145,54.3 145.83,53.47 146.57,53.47 147.04,52.99 147.04,51.29 147.31,51.02 147.67,51.02 148.05,51.4 v1(148.05,51.6)
  BOTTOM w0.076: v1(135.63,96.47) 135.79,96.47 135.87,96.39 135.87,96.1 136.04,95.92 137.12,95.92 137.28,96.08 138.3,96.08 138.42,96.04 138.65,96.04 138.77,96.08 138.95,96.08 139.07,96.04 139.3,96.04 139.51,96.11 139.61,96.33 139.75,96.47 UC1.D23
  BOTTOM w0.097: JDIMM1.179 147.95,54.19 147.79,54.03 147.79,53.4 147.46,53.07 147.46,51.47 147.68,51.25 147.9,51.25 148.05,51.41 v1(148.05,51.6)
DDR_A_DQS4: length 56.5
  IN1 w0.089: v1(138.92,82.91) 138.32,82.91 138.23,82.82 138.23,81.78 135.39,78.94 135.39,78.94 134.93,78.48 134.93,76.8 115.53,57.4 115.53,51.74 115.34,51.55 114.99,51.55 v1(114.81,51.36)
  BOTTOM w0.076: UC1.J34 143.2,89.01 143.26,88.98 143.29,88.92 143.38,88.66 143.29,88.43 143.29,88.24 143.34,88.13 143.34,87.89 143.29,87.78 143.29,86.75 143.45,86.6 143.45,86.14 143.05,85.74 141.16,85.74 140.12,84.7 140.02,84.7
  BOTTOM w0.089: 140.02,84.7 139.82,84.7 139.66,84.54 139.66,83.51 139.23,83.08 139.09,83.08 v1(138.92,82.91)
  BOTTOM w0.097: v1(114.81,51.36) 115.08,51.64 115.34,51.64 115.55,51.84 115.55,53.17 114.79,53.92 114.79,54.05 114.95,54.21 JDIMM1.55
DDR_A_DQS5: length 55.6
  IN1 w0.089: v1(142.84,82.87) 142.61,82.64 142.11,82.64 141.92,82.45 141.92,80.46 138.78,77.33 138.78,77.18 138.78,77.18 138.78,75.71 121.59,58.52 121.59,54.78 120.96,54.14 120.96,50.69 120.88,50.62 120.73,50.62 v1(120.44,50.9)
  BOTTOM w0.076: UC1.P35 145.38,88.77 145.43,88.87 145.55,88.91 145.65,88.87 145.69,88.75 145.69,88.57 145.65,88.45 145.65,88.21 145.69,88.1 145.69,87.92 145.65,87.8 145.65,86.69 145.8,86.53 145.8,86.22 143.41,83.83 143.41,82.88 143.12,82.59 143,82.59 142.84,82.76 v1(142.84,82.87)
  BOTTOM w0.097: JDIMM1.76 120.2,47.49 120.04,47.65 120.04,47.87 121.14,48.96 121.14,50.37 120.88,50.62 120.73,50.62 v1(120.44,50.9)
DDR_A_DQS6: length 60.7
  IN3 w0.089: v1(158.39,51.66) 158.39,51.47 158.11,51.19 157.79,51.19 157.7,51.28 157.7,52.3 158.11,52.71 158.11,53.11 155.45,55.77 154.7,55.77 153.87,56.6 153.87,56.73 154.04,56.9 154.04,57.18 153.61,57.61 153.34,57.61 153.16,57.43 153.04,57.43 152.85,57.62 152.85,57.75 153.02,57.92 153.02,58.2 144.77,66.46 144.77,66.58 145.45,67.27 145.45,67.54 145.16,67.84 144.88,67.84 144.2,67.15 144.07,67.15 143.88,67.34 143.88,67.47 144.57,68.15 144.57,68.43 138.74,74.26 138.74,75.04 138.74,75.04 138.74,81.55 138.36,81.93 138.36,85.91 138.5,86.05 138.74,86.05 139.12,86.43 139.12,87 141.47,89.35 141.47,91.64 141.56,91.73 v1(141.84,91.73)
  BOTTOM w0.089: UC1.H30 v1(141.84,91.73)
  BOTTOM w0.097: JDIMM1.221 158.45,54.15 158.29,53.99 158.29,53.36 157.81,52.88 157.81,51.58 158.01,51.38 158.11,51.38 v1(158.39,51.66)
DDR_A_DQS7: length 59.2
  IN3 w0.089: v1(163.51,50.46) 163.8,50.75 164.27,50.75 164.5,50.97 164.5,52.68 163.84,53.34 163.29,53.34 159.48,57.15 159.48,57.53 156.71,60.29 156.71,60.42 157.05,60.75 157.05,61.03 156.75,61.32 156.48,61.32 156.23,61.08 156.1,61.08 155.91,61.26 155.91,61.39 156.16,61.63 156.16,61.91 144.49,73.57 143.62,74.44 143.62,74.46 142.62,75.46 142.62,75.85 142.62,75.85 142.62,80.72 142.24,81.09 142.24,85.24 142.63,85.62 143,85.62 143.69,86.32 143.69,89.48 144.21,90 144.21,91.64 144.3,91.73 v1(144.58,91.73)
  BOTTOM w0.089: UC1.N30 v1(144.58,91.73)
  BOTTOM w0.097: JDIMM1.242 163.7,47.68 163.54,47.84 163.54,48.35 163.11,48.78 163.11,50.59 163.2,50.69 163.36,50.69 163.51,50.54 v1(163.51,50.46)
DDR_A_DQS#0: length 73.2
  IN1 w0.089: v1(131.48,93.79) 131.07,93.39 131.07,93.11 130.25,92.29 130.12,92.29 130.12,92.29 127.94,92.29 124.02,88.36 124.02,76.66 111.38,64.02 109.24,64.02 104.88,59.66 104.6,59.66 104.37,59.89 104.25,59.89 104.06,59.7 104.06,59.58 104.29,59.35 104.29,59.07 103.43,58.21 103.43,55.72 103.32,55.61 103.32,51.66 103.41,51.56 103.68,51.56 v1(104.04,51.92)
  BOTTOM w0.076: UC1.C27 139.3,93.91 139.39,93.95 139.44,94.08 139.39,94.17 139.28,94.21 139.09,94.21 138.98,94.17 138.74,94.17 138.63,94.21 138.44,94.21 138.33,94.17 138.33,94.17 137.21,94.17 137.06,94.33 136.74,94.33 136.59,94.17 133.67,94.17 133.59,94.24 133.49,94.24
  BOTTOM w0.089: v1(131.48,93.79) 131.48,93.97 131.39,94.05 131.16,94.05 131.07,94.14 131.07,94.35 131.16,94.43 132.14,94.43 132.33,94.24 133.49,94.24
  BOTTOM w0.097: JDIMM1.11 103.95,54.15 104.05,54.05 104.17,54.05 104.26,53.95 104.26,53.39 104.7,52.96 104.7,51.45 104.59,51.34 104.43,51.34 104.21,51.56 104.14,51.56 104.04,51.66 v1(104.04,51.92)
DDR_A_DQS#1: length 65.6
  IN1 w0.089: v1(131.88,90.49) 132.07,90.3 132.07,90.06 132.39,89.74 133.02,89.74 133.87,88.9 133.87,86.85 133.86,86.85 133.86,86.61 133.99,86.49 133.99,85.58 133.99,84.28 132.15,82.44 132.15,82.44 129.67,79.97 129.67,78.76 128.84,77.93 128.84,76.64 109.91,57.71 109.91,50.99 109.82,50.91 109.62,50.91 v1(109.44,51.09)
  BOTTOM w0.076: 133.63,91.51 133.73,91.51 133.81,91.42 136.12,91.42 136.68,91.98 137.12,91.98 137.28,91.82 138.3,91.82 138.42,91.86 138.65,91.86 138.77,91.82 138.95,91.82 139.07,91.86 139.3,91.86 139.51,91.79 139.61,91.57 139.75,91.43 UC1.D31
  BOTTOM w0.089: 133.63,91.51 132.28,91.51 132.09,91.31 132.09,90.69 v1(131.88,90.49)
  BOTTOM w0.097: v1(109.44,51.09) 109.44,50.99 109.25,50.8 109.02,50.8 108.76,50.54 108.76,49.95 108.78,49.93 108.78,48.74 109.36,48.17 109.36,47.86 109.2,47.7 JDIMM1.32
DDR_A_DQS#2: length 68.2
  IN3 w0.089: v1(142.36,95.36) 142.21,95.51 142.21,95.82 142.02,96.01 140.28,96.01 139.58,95.31 139.58,95.02 138.31,93.74 138.31,90.57 138.06,90.32 137.3,90.32 134.65,87.67 134.65,86.97 134.65,86.97 134.65,86.6 134.65,86.59 134.65,84.25 133.41,83 133.41,78.55 133.41,76.05 133.32,75.96 132.75,75.96 132.56,75.77 132.56,75.35 132.75,75.16 133.32,75.16 133.41,75.07 133.41,74.8 133.32,74.71 132.75,74.71 132.56,74.52 132.56,74.1 132.75,73.91 133.32,73.91 133.41,73.82 133.41,70.17 140.34,63.23 141.86,63.23 151.94,53.15 151.94,50.69 152.14,50.49 152.62,50.49 v1(152.78,50.33)
  BOTTOM w0.089: UC1.H24 v1(142.36,95.36)
  BOTTOM w0.097: JDIMM1.198 152.7,47.51 152.86,47.67 152.86,48.31 153.34,48.79 153.34,50.23 153.24,50.33 v1(152.78,50.33)
DDR_A_DQS#3: length 75.8
  IN3 w0.089: v1(148.05,50.84) 147.24,50.84 146.86,51.21 146.86,52.92 146.49,53.29 145.75,53.29 144.93,54.12 143.52,54.12 142.83,54.81 142.09,54.81 128.24,68.66 128.24,81.1 124.52,84.82 124.52,88.52 127.62,91.62 127.62,93.56 131.16,97.1 135.98,97.1 136.17,96.91 136.17,96.56 v1(136.27,96.47)
  BOTTOM w0.076: UC1.C23 139.3,96.51 139.39,96.46 139.44,96.34 139.39,96.24 139.28,96.2 139.09,96.2 138.98,96.24 138.74,96.24 138.63,96.2 138.45,96.2 138.33,96.24 137.21,96.24 137.06,96.09 136.11,96.09 136.03,96.16 136.03,96.39 136.11,96.47 v1(136.27,96.47)
  BOTTOM w0.097: v1(148.05,50.84) 147.82,51.07 147.6,51.07 147.28,51.4 147.28,53.15 147.61,53.48 147.61,53.99 147.45,54.15 JDIMM1.177
DDR_A_DQS#4: length 56.4
  IN1 w0.089: v1(114.81,52.13) 114.81,51.89 114.97,51.73 115.26,51.73 115.35,51.82 115.35,57.48 134.75,76.88 134.75,78.56 135.26,79.07 138.05,81.86 138.05,82.9 138.25,83.09 138.59,83.09 138.92,83.42 v1(138.92,83.54)
  BOTTOM w0.076: 139.96,84.88 140.06,84.88 141.09,85.9 142.98,85.9 143.28,86.21 143.28,86.53 143.13,86.68 143.13,87.8 143.17,87.92 143.17,88.1 143.13,88.21 143.13,88.45 143.2,88.66 143.13,88.86 143.13,88.87 143.12,88.87 143.03,88.91 142.91,88.87 142.87,88.77 UC1.J35
  BOTTOM w0.089: 139.96,84.88 139.74,84.88 139.48,84.62 139.48,84.54 139.48,83.58 139.16,83.26 139.02,83.26 138.92,83.36 v1(138.92,83.54)
  BOTTOM w0.097: v1(114.81,52.13) 115.11,51.82 115.27,51.82 115.36,51.92 115.36,53.09 114.61,53.85 114.61,53.97 114.45,54.13 JDIMM1.53
DDR_A_DQS#5: length 55.6
  IN1 w0.089: v1(120.44,50.14) 120.74,50.44 120.96,50.44 121.14,50.62 121.14,54.07 121.77,54.7 121.77,58.45 138.96,75.64 138.96,77.26 142.09,80.39 142.09,82.38 142.18,82.47 142.61,82.47 v1(142.84,82.24)
  BOTTOM w0.076: UC1.P34 145.42,89.22 145.56,89.08 145.78,88.98 145.85,88.78 145.85,88.54 145.81,88.43 145.81,88.24 145.85,88.13 145.85,87.89 145.81,87.78 145.81,86.75 145.97,86.6 145.97,86.22 145.97,86.15 143.57,83.76 143.57,82.81 143.19,82.43 143.06,82.43 143.03,82.39 142.99,82.39 v1(142.84,82.24)
  BOTTOM w0.097: v1(120.44,50.14) 120.74,50.43 120.81,50.43 120.95,50.29 120.95,49.04 119.86,47.94 119.86,47.69 119.7,47.53 JDIMM1.74
DDR_A_DQS#6: length 60.8
  IN3 w0.089: v1(140.93,91.73) 141.29,91.37 141.29,89.42 138.95,87.08 138.95,86.51 138.67,86.23 138.43,86.23 138.18,85.99 138.18,81.85 138.56,81.47 138.56,74.18 144.39,68.35 144.39,68.23 143.7,67.54 143.7,67.27 143.99,66.97 144.27,66.97 144.96,67.66 145.08,67.66 145.27,67.47 145.27,67.34 144.58,66.66 144.58,66.38 152.84,58.12 152.84,58 152.67,57.82 152.67,57.55 152.96,57.25 153.24,57.25 153.41,57.43 153.54,57.43 153.86,57.1 153.86,56.98 153.69,56.8 153.69,56.53 154.63,55.59 155.38,55.59 157.93,53.04 157.93,52.79 157.52,52.38 157.52,51.2 157.71,51.01 158.29,51.01 158.39,50.9 v1(158.39,50.9)
  BOTTOM w0.089: UC1.G30 v1(140.93,91.73)
  BOTTOM w0.097: JDIMM1.219 157.95,54.19 158.11,54.04 158.11,53.44 157.63,52.95 157.63,51.5 157.93,51.2 158.1,51.2 v1(158.39,50.9)
DDR_A_DQS#7: length 59.3
  IN3 w0.089: v1(143.66,91.73) 143.94,91.73 144.03,91.64 144.03,90.07 143.52,89.56 143.52,86.39 142.93,85.8 142.55,85.8 142.07,85.31 142.07,81.02 142.44,80.65 142.44,75.38 143.44,74.38 143.44,74.37 144.37,73.44 144.37,73.44 155.98,61.83 155.98,61.71 155.73,61.46 155.73,61.19 156.03,60.89 156.3,60.89 156.55,61.14 156.68,61.14 156.87,60.95 156.87,60.83 156.53,60.49 156.53,60.22 159.3,57.45 159.3,57.07 163.21,53.16 163.76,53.16 164.32,52.6 164.32,51.05 164.2,50.93 163.8,50.93 v1(163.51,51.22)
  BOTTOM w0.089: UC1.L30 v1(143.66,91.73)
  BOTTOM w0.097: v1(163.51,51.22) 163.51,51.08 163.3,50.87 163.12,50.87 162.92,50.67 162.92,48.71 163.36,48.27 163.36,47.76 163.2,47.6 JDIMM1.240
DDR_A_MA0: length 55.9
  IN1 w0.089: 147.98,76.01 150.55,78.58 150.55,81.82 150.46,81.91 v1(149.98,81.91)
  IN1 w0.122: 147.98,76.01 147.98,74.87 147.98,74.87 147.98,71.58 147.32,70.92 147.32,70.74 147.98,70.08 147.98,69.89 147.81,69.71 147.63,69.71 146.96,70.38 146.79,70.38 146.62,70.21 146.62,70.04 147.29,69.36 147.29,69.19 135.13,57.03 135.13,54.16 134.96,53.98 134.96,50.64 134.47,50.16 134.47,49.6 134.59,49.47 135.42,49.47 135.55,49.35 135.55,49.11 135.42,48.99 134.57,48.99 134.45,48.86 134.45,48.43 134.57,48.31 v1(137.2,48.31)
  BOTTOM w0.076: v1(149.98,81.91) 150.4,82.34 150.4,83.01 150.75,83.36 150.75,83.92 150.75,83.92 150.75,85.69 151.15,86.09 151.15,86.68 151.01,86.82 151.01,87.59 UC1.AC37
  BOTTOM w0.135: v1(137.2,48.31) JDIMM1.144
DDR_A_MA1: length 56.6
  IN1 w0.089: 146.8,74.43 146.8,75.7 149.28,78.18 149.28,79.92 149.37,80.01 v1(149.98,80.01)
  IN1 w0.122: v1(134.03,51.79) 134.03,51.6 133.91,51.48 133.59,51.48 133.47,51.6 133.47,56.27 133.43,56.3 133.43,56.65 133.43,56.99 137.11,60.66 137.11,60.66 138.02,61.58 138.36,61.91 138.36,62.08 137.68,62.76 137.68,62.93 137.85,63.11 138.03,63.11 138.7,62.43 138.88,62.43 139.05,62.6 139.05,62.77 138.37,63.45 138.37,63.62 138.54,63.8 138.71,63.8 139.39,63.12 139.57,63.12 139.74,63.29 139.74,63.46 139.06,64.14 139.06,64.31 139.23,64.49 139.4,64.49 140.08,63.81 140.26,63.81 140.51,64.07 140.51,64.24 139.84,64.92 139.84,65.09 146.81,72.06 146.8,74.37 146.8,74.43
  BOTTOM w0.076: UC1.AC36 151.11,88.28 151.16,88.18 151.37,87.8 151.37,87.53 151.17,87.33 151.17,86.89 151.33,86.73 151.33,86.03 150.91,85.62 150.91,83.24 150.73,83.06
  BOTTOM w0.135: v1(134.03,51.79) 134.29,51.79 134.73,52.24 134.73,53.69 134.45,53.97 JDIMM1.133 ; 150.73,83.06 150.73,80.24 150.5,80.01 149.99,80.01 v1(149.98,80.01)
DDR_A_MA2: length 56
  IN1 w0.089: v1(149.98,81.28) 150.37,80.88 150.37,78.65 147.58,75.86 147.58,74.72 147.58,74.43
  IN1 w0.122: 147.58,74.43 147.58,74.37 147.58,71.73 146.07,70.21 146.07,70.04 146.74,69.36 146.74,69.19 146.54,69 146.37,69 145.7,69.67 145.53,69.67 145.35,69.5 145.35,69.32 146.03,68.65 146.03,68.48 145.85,68.31 145.68,68.31 145.01,68.98 144.84,68.98 144.66,68.81 144.66,68.63 145.34,67.96 145.34,67.79 134.74,57.19 134.74,54.32 134.57,54.14 134.57,50.8 v1(134.03,50.27)
  BOTTOM w0.076: UC1.AC34 150.84,89.37 150.84,88.24 150.88,88.13 150.88,87.89 150.84,87.78 150.84,86.75 150.99,86.61 150.99,86.17 150.58,85.76 150.58,83.43 149.91,82.76 149.91,82.44 149.59,82.12 149.59,81.66 v1(149.98,81.28)
  BOTTOM w0.135: JDIMM1.132 134.2,47.74 134.58,48.12 134.58,49.95 134.27,50.27 v1(134.03,50.27)
DDR_A_MA3: length 56.7
  IN1 w0.089: v1(149.98,79.37) 150.21,79.14 150.21,78.72 147.19,75.71 147.19,74.43
  IN1 w0.122: 147.19,74.43 147.19,74.37 147.2,71.89 143.94,68.63 143.94,68.46 144.61,67.78 144.61,67.61 144.44,67.44 144.26,67.44 143.59,68.11 143.42,68.11 143.25,67.94 143.25,67.77 143.92,67.09 143.92,66.92 143.75,66.75 143.57,66.75 142.9,67.42 142.73,67.42 142.56,67.25 142.56,67.08 143.23,66.4 143.23,66.23 143.06,66.06 142.88,66.06 142.21,66.73 142.04,66.73 141.87,66.56 141.87,66.39 142.54,65.72 142.54,65.54 142.37,65.37 142.19,65.37 141.52,66.04 141.35,66.04 141.18,65.87 141.18,65.7 141.85,65.03 141.85,64.85 141.58,64.58 141.41,64.58 140.73,65.26 140.56,65.26 140.39,65.09 140.39,64.92 141.06,64.24 141.06,64.07 138.19,61.19 138.19,61.19 137.5,60.5 137.5,60.5 134.31,57.31 134.31,54.43 134.03,54.16 v1(134.03,53.31)
  BOTTOM w0.076: 151.08,83.14 151.08,85.55 151.48,85.95 151.48,85.95 151.49,85.96 151.49,85.97 151.5,85.98 151.5,86.79 151.34,86.95 151.34,87.27 151.54,87.46 151.54,87.84 151.43,88.04 151.43,88.67 151.16,88.93 UC1.AC35
  BOTTOM w0.135: v1(149.98,79.37) 150.77,79.37 151.08,79.67 151.08,83.14 ; JDIMM1.131 133.95,53.4 v1(134.03,53.31)
DDR_A_MA4: length 55.3
  IN1 w0.089: v1(148.33,80.38) 149.03,80.38 149.12,80.29 149.12,78.27 146.41,75.56 146.41,74.59 146.41,74.43
  IN1 w0.122: 146.41,74.43 146.41,74.37 146.42,72.22 137.12,62.92 137.12,62.77 137.8,62.09 137.8,61.91 136.72,60.82 136.72,60.82 133.04,57.15 133.04,56.81 133.04,56.14 133.08,56.11 133.08,51.09 133.2,50.97 133.54,50.97 133.66,50.84 133.66,50.6 133.54,50.48 133.2,50.48 133.08,50.36 133.08,50.11 133.2,49.99 133.51,49.99 133.63,49.87 133.63,49.63 133.33,49.32 133.33,47.95 133.45,47.83 133.91,47.83 134.03,47.95 v1(134.03,48.74)
  BOTTOM w0.076: UC1.AA35 149.9,88.89 150.07,88.43 150.07,88.24 150.03,88.13 150.03,87.89 150.07,87.78 150.07,86.75 149.91,86.6 149.91,86.15 150.09,85.98 150.09,83.64 149.37,82.92 149.37,82.66 148.9,82.19 148.9,80.89 148.39,80.38 v1(148.33,80.38)
  BOTTOM w0.135: v1(134.03,48.74) 133.2,47.91 JDIMM1.128
DDR_A_MA5: length 56.7
  IN1 w0.089: v1(148.33,79.11) 148.75,79.11 148.84,79.02 148.84,78.37 146.02,75.55 146.02,74.59 146.02,74.43
  IN1 w0.122: 146.02,74.43 146.02,74.37 146.03,72.38 136.58,62.93 136.58,62.76 137.26,62.08 137.26,61.91 136.33,60.98 136.33,60.98 132.66,57.31 132.66,56.97 132.66,55.98 132.66,56.07 132.66,55.5 132.69,55.47 132.69,49.95 132.94,49.7 132.94,47.95 132.82,47.83 131.16,47.83 131.04,47.95 131.04,48.97 131.16,49.1 131.79,49.1 v1(132.27,48.62)
  BOTTOM w0.076: 148.88,79.15 148.83,79.11 v1(148.33,79.11) ; 149.74,82.54 149.74,82.82 150.42,83.5 150.42,85.83 150.82,86.23 150.82,86.55 150.68,86.69 150.68,87.8 150.72,87.92 150.72,88.1 150.55,88.56 UC1.AB35
  BOTTOM w0.089: 149.74,82.54 149.26,82.06 149.26,79.53 148.88,79.15
  BOTTOM w0.135: v1(132.27,48.62) 132.7,48.19 JDIMM1.126
DDR_A_MA6: length 56.3
  IN1 w0.089: v1(148.33,81.01) 147.7,80.39 147.7,78 145.98,76.27
  IN1 w0.122: 145.98,76.27 145.25,75.54 145.25,74.59 145.25,74.37 145.25,73.67 145.25,73.56 144.99,73.31 144.99,73.14 145.25,72.88 145.25,72.7 145.07,72.53 144.9,72.53 144.64,72.78 144.47,72.78 144.3,72.61 144.3,72.44 144.56,72.18 144.56,72.01 144.38,71.84 144.21,71.84 143.95,72.09 143.78,72.09 143.61,71.92 143.61,71.75 143.87,71.49 143.87,71.32 143.69,71.15 143.52,71.15 143.26,71.4 143.09,71.4 142.92,71.23 142.92,71.06 143.18,70.8 143.18,70.63 143,70.46 142.83,70.46 142.57,70.72 142.4,70.72 142.23,70.54 142.23,70.37 142.49,70.11 142.49,69.94 142.31,69.77 142.14,69.77 141.88,70.03 141.71,70.03 141.54,69.85 141.54,69.68 141.8,69.42 141.8,69.25 132.55,60 132.55,59.83 133.23,59.15 133.23,58.98 133.05,58.81 132.88,58.81 132.2,59.48 132.03,59.48 131.77,59.22 131.77,59.05 132.45,58.37 132.45,58.2 131.69,57.44 131.69,51.42 131.82,51.29 132.13,51.29 132.27,51.44 v1(132.27,51.66)
  BOTTOM w0.076: UC1.AA37 149.9,87.59 149.9,86.82 149.75,86.66 149.75,86.08 149.92,85.91 149.92,83.7 149.21,82.98 149.21,82.73 148.74,82.26 148.74,81.1 148.65,81.01 v1(148.33,81.01)
  BOTTOM w0.135: v1(132.27,51.66) 132.95,52.34 JDIMM1.127
DDR_A_MA7: length 57.4
  IN1 w0.089: 145.66,76.34 147.48,78.15 147.48,80.55 147.9,80.97 147.9,82.24 148.03,82.37 v1(148.33,82.37)
  IN1 w0.122: 145.66,76.34 144.86,75.53 144.86,74.75 144.86,74.37 144.86,73.72 140.89,69.76 140.89,69.59 141.15,69.33 141.15,69.16 140.98,68.98 140.81,68.98 140.55,69.24 140.38,69.24 140.2,69.07 140.2,68.9 140.46,68.64 140.46,68.47 140.29,68.29 140.12,68.29 139.86,68.55 139.69,68.55 139.51,68.38 139.51,68.21 139.77,67.95 139.77,67.78 139.6,67.6 139.43,67.6 139.17,67.86 139,67.86 138.82,67.69 138.82,67.52 139.08,67.26 139.08,67.09 138.91,66.91 138.74,66.91 138.48,67.17 138.31,67.17 138.13,67 138.13,66.83 138.39,66.57 138.39,66.4 138.22,66.22 138.05,66.22 137.79,66.48 137.62,66.48 137.44,66.31 137.44,66.14 137.7,65.88 137.7,65.71 137.53,65.53 137.36,65.53 137.1,65.79 136.93,65.79 136.75,65.62 136.75,65.45 137.01,65.19 137.01,65.01 131.3,59.31 131.3,49.86 131.39,49.78 132.15,49.78 132.27,49.9 v1(132.27,50.14)
  BOTTOM w0.076: UC1.AA36 149.65,87.94 149.54,87.81 149.54,87.8 149.54,87.53 149.74,87.33 149.74,86.88 149.58,86.73 149.58,86.01 149.76,85.84 149.76,83.76 149.03,83.04 149.03,82.79 148.61,82.37 v1(148.33,82.37)
  BOTTOM w0.135: v1(132.27,50.14) 131.7,49.57 JDIMM1.122
DDR_A_MA8: length 54.7
  IN1 w0.089: v1(148.33,79.74) 148.02,79.74 147.93,79.65 147.93,77.84 145.63,75.55 145.63,74.59 145.63,74.43
  IN1 w0.122: 145.63,74.43 145.63,74.37 145.64,72.54 135.94,62.85 135.94,62.68 136.62,62 136.62,61.82 136.45,61.65 136.28,61.65 135.6,62.33 135.43,62.33 135.25,62.16 135.25,61.99 135.93,61.31 135.93,61.13 135.76,60.96 135.59,60.96 134.91,61.64 134.74,61.64 134.56,61.47 134.56,61.3 135.24,60.62 135.24,60.44 135.07,60.27 134.9,60.27 134.22,60.95 134.05,60.95 133.87,60.78 133.87,60.61 134.55,59.93 134.55,59.75 134.38,59.58 134.21,59.58 133.53,60.26 133.36,60.26 133.18,60.09 133.18,59.92 133.86,59.24 133.86,59.06 133.69,58.89 133.69,58.89 132.19,57.39 132.19,57.15 132.19,53.58 v1(132.27,53.49)
  BOTTOM w0.076: 149.55,82.86 150.25,83.56 150.25,86.05 150.08,86.22 150.08,86.53 150.23,86.69 150.23,87.8 150.19,87.92 150.19,88.1 150.23,88.21 150.23,88.45 150.19,88.57 150.19,89.05 UC1.AB34
  BOTTOM w0.089: 149.55,82.86 149.55,82.6 149.07,82.12 149.07,80.08 148.73,79.74 v1(148.33,79.74)
  BOTTOM w0.135: JDIMM1.125 132.45,53.9 132.45,53.63 132.31,53.49 v1(132.27,53.49)
DDR_A_MA9: length 55
  IN1 w0.089: 143.61,75.43 146.26,78.07 146.26,80.55 v1(146.64,80.93)
  IN1 w0.122: v1(129.89,51.42) 129.86,51.39 129.58,51.39 129.46,51.51 129.46,55.35 129.58,55.47 130.02,55.47 130.14,55.59 130.14,55.95 130.02,56.07 129.58,56.07 129.46,56.2 129.46,58.02 129.58,58.14 130.02,58.14 130.14,58.26 130.14,58.51 130.02,58.63 129.58,58.63 129.46,58.75 129.46,59 129.58,59.12 130.02,59.12 130.14,59.24 130.14,59.48 130.02,59.61 129.58,59.61 129.46,59.73 129.46,59.98 130.07,60.59 130.24,60.59 130.5,60.33 130.67,60.33 130.85,60.5 130.85,60.67 130.59,60.93 130.59,61.1 130.76,61.28 130.93,61.28 131.19,61.02 131.36,61.02 131.54,61.19 131.54,61.36 131.28,61.62 131.28,61.79 143.61,74.13 143.61,75.43
  BOTTOM w0.076: UC1.W36 148.59,88.28 148.59,88.28 148.86,87.8 148.86,87.53 148.66,87.33 148.66,86.88 148.81,86.73 148.81,85.67 147.77,84.63 147.77,84.15 147.69,84.07 147.69,83.62
  BOTTOM w0.089: 147.69,83.62 147.69,81.97 v1(146.64,80.93)
  BOTTOM w0.135: v1(129.89,51.42) 130.2,51.73 130.4,51.73 130.97,52.29 130.97,53.31 131.45,53.79 JDIMM1.121
DDR_A_MA10: length 54.7
  IN1 w0.089: 151.75,76.71 152.99,77.94 152.99,85.55 152.35,86.18 152.35,87.15 149.51,90 149.51,91.01 149.42,91.1 v1(149.13,91.1)
  IN1 w0.122: v1(139.76,51.22) 139.76,51.12 139.64,51 139.41,51 139.29,51.12 139.29,53.66 139.78,54.15 139.78,54.32 139.5,54.6 139.5,54.78 139.78,55.06 139.95,55.06 140.23,54.78 140.41,54.78 140.58,54.95 140.58,55.12 140.3,55.4 140.3,55.57 140.63,55.91 140.63,56.61 141.61,57.59 141.61,58.77 151.57,68.73 151.57,76.32 151.57,76.32 151.57,76.53 151.75,76.71
  BOTTOM w0.089: v1(149.13,91.1) UC1.Y31
  BOTTOM w0.135: JDIMM1.146 139.7,47.5 139.22,47.97 139.22,50.68 v1(139.76,51.22)
DDR_A_MA11: length 52.9
  IN1 w0.089: 144.46,75.52 147.26,78.31 147.26,80.65 147.73,81.13 147.73,82.81 147.93,83 v1(148.33,83)
  IN1 w0.122: v1(129.89,49.9) 130.79,49.9 130.92,50.02 130.92,59.47 136.38,64.94 136.38,65.11 136.13,65.37 136.13,65.54 144.46,73.88 144.46,75.52
  BOTTOM w0.076: UC1.W34 148.66,89.48 148.9,89.01 148.9,88.06 149.02,87.84 149.02,87.46 148.82,87.27 148.82,86.95 148.98,86.79 148.98,85.6 147.96,84.58 147.96,83.98 147.9,83.92 147.9,83.43 v1(148.33,83)
  BOTTOM w0.135: v1(129.89,49.9) 130.84,48.95 130.84,48.15 131.2,47.78 JDIMM1.120
DDR_A_MA12: length 56.2
  IN1 w0.089: v1(148.33,83.64) 147.59,83.64 147.5,83.55 147.5,81.23 147.03,80.76 147.03,78.47 144.08,75.51
  IN1 w0.122: v1(129.89,52.95) 130.41,52.95 130.53,53.07 130.53,53.5 130.41,53.62 129.97,53.62 129.85,53.74 129.85,53.98 129.97,54.11 130.41,54.11 130.53,54.23 130.53,54.47 130.41,54.59 129.97,54.59 129.85,54.72 129.85,54.96 129.97,55.08 130.41,55.08 130.53,55.2 130.53,59.63 132.28,61.38 132.28,61.55 132.02,61.81 132.02,61.98 132.19,62.15 132.36,62.15 132.62,61.9 132.79,61.9 132.96,62.07 132.96,62.24 132.71,62.5 132.71,62.67 132.88,62.84 133.05,62.84 133.31,62.59 133.48,62.59 133.65,62.76 133.65,62.93 133.4,63.19 133.4,63.36 133.57,63.53 133.74,63.53 134,63.27 134.17,63.27 134.34,63.45 134.34,63.62 134.09,63.88 134.09,64.05 134.26,64.22 134.43,64.22 134.69,63.96 134.86,63.96 135.03,64.14 135.03,64.31 134.78,64.57 134.78,64.74 134.95,64.91 135.12,64.91 135.38,64.65 135.55,64.65 135.72,64.83 135.72,65 135.47,65.26 135.47,65.43 144.08,74.04 144.08,75.51
  BOTTOM w0.076: v1(148.33,83.64) 149.4,83.64 149.59,83.83 149.59,85.77 149.42,85.95 149.42,86.79 149.58,86.95 149.58,87.27 149.38,87.46 149.38,87.86 149.49,88.06 149.49,88.98 149.73,89.48 UC1.AA34
  BOTTOM w0.135: JDIMM1.119 130.95,54.12 130.46,53.63 130.46,53.25 130.16,52.95 v1(129.89,52.95)
DDR_A_MA13: length 56.6
  IN1 w0.089: v1(150.96,90.46) 150.96,89.61 151.59,88.97 151.75,88.97 154.32,86.4 154.32,79.89 153.55,79.12
  IN1 w0.122: 153.55,79.12 153.55,77.5 153.55,77.34 153.55,77.33 152.92,76.71 152.92,68.43 152.66,68.17 144.85,60.36 144.85,60.19 145.01,60.03 145.3,59.73 145.3,59.56 145.13,59.39 144.96,59.39 144.5,59.84 144.33,59.84 144.16,59.67 144.16,59.5 144.61,59.04 144.61,58.87 144.44,58.7 144.27,58.7 143.81,59.15 143.64,59.15 143.47,58.98 143.47,58.81 143.92,58.35 143.92,58.18 143.75,58.01 143.58,58.01 143.12,58.46 142.95,58.46 142.77,58.29 142.77,57.03 142.6,56.85 142.6,55.32 141.53,54.25 141.53,49.79 141.61,49.7 141.83,49.7 v1(142.08,49.96)
  BOTTOM w0.076: v1(150.96,90.46) UC1.AC32
  BOTTOM w0.135: JDIMM1.158 142.7,47.98 142.56,48.12 142.56,49.49 v1(142.08,49.96)
DDR_A_MA14: length 56.6
  IN1 w0.089: v1(150.96,91.1) 151.39,90.66 151.39,90.23 154.09,87.52 154.33,87.52 154.76,87.09 154.76,86.62 154.64,86.5 154.64,79.78
  IN1 w0.122: v1(142.08,53.01) 142.08,54.25 142.99,55.16 142.99,56.69 145.85,59.56 145.85,59.73 145.4,60.19 145.4,60.36 145.72,60.68 145.89,60.68 146.38,60.2 146.55,60.2 146.72,60.37 146.72,60.54 146.24,61.03 146.24,61.2 146.41,61.37 146.58,61.37 147.07,60.89 147.24,60.89 147.41,61.06 147.41,61.23 146.93,61.72 146.93,61.89 147.1,62.06 147.27,62.06 147.76,61.58 147.93,61.58 148.1,61.75 148.1,61.92 147.62,62.41 147.62,62.58 147.79,62.75 147.96,62.75 148.45,62.27 148.62,62.27 148.79,62.44 148.79,62.61 148.31,63.1 148.31,63.27 148.48,63.44 148.65,63.44 149.14,62.96 149.31,62.96 149.48,63.13 149.48,63.3 149,63.79 149,63.96 150.94,65.91 153.36,68.33 153.36,76.87 153.74,77.25 153.74,77.58 153.74,78.89 154.64,79.78
  BOTTOM w0.076: UC1.AC31 151.16,91.2 v1(150.96,91.1)
  BOTTOM w0.135: v1(142.08,53.01) 142,52.92 141.77,52.92 140.95,53.74 JDIMM1.151
DDR_A_MA15: length 56
  IN1 w0.089: 153.35,79.31 154.13,80.1 154.13,86.36 151.81,88.68 151.6,88.68 150.49,89.79 150.49,90.02 v1(150.05,90.46)
  IN1 w0.122: v1(142.08,48.43) 142.08,47.95 141.96,47.83 140.31,47.83 140.19,47.95 140.19,48.84 140.31,48.96 141.02,48.96 141.14,49.08 141.14,54.41 141.57,54.84 141.57,55.15 141.7,55.27 142,55.27 142.12,55.39 142.12,55.64 142,55.76 141.7,55.76 141.57,55.88 141.57,56.4 142.38,57.21 142.38,58.45 150.62,66.68 152.53,68.59 152.53,76.82 153.35,77.64 153.35,79.31
  BOTTOM w0.089: UC1.AB32 v1(150.05,90.46)
  BOTTOM w0.135: v1(142.08,48.43) 142.08,48.05 142.2,47.93 JDIMM1.156
DDR_A_MA16: length 52.4
  IN1 w0.089: 151.18,76.48 152.04,77.34 152.09,77.34 152.72,77.98 152.72,84.24 151.87,85.09 151.87,86.28 149.69,88.46 149.69,89.41 149.62,89.48 149.13,89.97 149.13,89.99 v1(149.14,90.46)
  IN1 w0.122: 151.18,76.48 151.1,76.4 151.1,76.32 151.1,76.32 151.1,68.82 141.22,58.93 141.22,57.75 140.25,56.77 140.25,56.07 138.9,54.72 138.9,50.56 v1(139.76,49.69)
  BOTTOM w0.089: UC1.Y32 v1(149.14,90.46)
  BOTTOM w0.135: v1(139.76,49.69) 140.85,48.6 140.85,48.24 141.2,47.89 141.2,46.81 JDIMM1.152
DDR_A_ODT0: length 59.2
  IN1 w0.089: v1(151.87,91.1) 152.32,90.64 152.32,90.41 155.85,86.88 155.85,86.14 155.66,85.95 155.66,79.9 155.21,79.45
  IN1 w0.122: v1(143.73,50.45) 143.51,50.23 143.51,48.06 143.39,47.94 142.72,47.94 142.6,48.06 142.6,51.25 142.99,51.64 142.99,53.23 145.25,55.49 145.25,56.11 147.8,58.67 147.8,60.35 154.14,66.69 154.14,78.38 155.21,79.45
  BOTTOM w0.076: UC1.AE31 v1(151.87,91.1)
  BOTTOM w0.135: v1(143.73,50.45) 143.64,50.48 142.74,52.17 142.74,52.61 141.95,54.26 JDIMM1.155
DDR_A_ODT1: length 58.1
  IN1 w0.089: 154.92,78.48 156.1,79.66 156.1,85.76 156.18,85.84 156.18,87.95 153.04,91.1 v1(152.78,91.1)
  IN1 w0.122: v1(144.69,51.88) 144.69,51.38 144.81,51.25 145.75,51.25 145.87,51.38 145.87,53.07 146.9,54.1 146.9,54.27 146.11,55.07 146.11,55.24 146.43,55.56 146.6,55.56 147.43,54.73 147.6,54.73 147.78,54.91 147.78,55.08 146.95,55.91 146.95,56.08 147.12,56.25 147.29,56.25 148.12,55.42 148.29,55.42 148.47,55.6 148.47,55.77 147.64,56.6 147.64,56.77 150.42,59.55 150.42,59.72 149.43,60.71 149.43,60.88 154.92,66.37 154.92,78.48
  BOTTOM w0.076: UC1.AF31 v1(152.78,91.1)
  BOTTOM w0.135: v1(144.69,51.88) 144.69,51.91 144.25,52.35 144.25,52.91 143.45,53.71 JDIMM1.161
DDR_A_PARITY: length 51
  IN1 w0.089: v1(148.22,91.1) 148.69,90.63 148.69,89.11 151.69,86.1 151.69,84.98 152.46,84.22 152.46,77.94 152.02,77.5 151.74,77.5 150.71,76.48
  IN1 w0.122: 150.71,76.48 150.71,68.98 140.83,59.09 140.83,57.91 138.44,55.52 v1(138.44,51.96)
  BOTTOM w0.089: UC1.W31 148.59,91.29 v1(148.22,91.1)
  BOTTOM w0.135: v1(138.44,51.96) 136.95,53.45 JDIMM1.143
DDR_B_ACT#: length 94.3
  IN3 w0.089: 147.18,75.31 146.49,76 146.49,79.27 145.93,79.83 145.93,84.35 146.58,85 146.58,86.22 147.68,87.32 147.68,92.46 v1(148.22,93)
  IN3 w0.122: 147.18,75.31 147.18,75.28 165.95,56.51 165.95,55.87 168.22,53.59 169.43,53.59 172.56,50.47 199.85,50.47 202.09,49.43 203.43,48.08 203.43,47.96 203.93,46.43 204.11,46.24 v1(205.92,45.05)
  BOTTOM w0.089: UC1.W28 148.59,93.23 v1(148.22,93)
  BOTTOM w0.135: v1(205.92,45.05) 206.02,44.95 206.02,44.6 206.84,43.78 206.85,43.78 207.1,43.53 JDIMM2.114
DDR_B_ALERT#: length 93.3
  IN3 w0.089: 147.59,78.08 147.6,78.1 147.6,84.92 148.76,86.08 148.76,92 v1(149.13,92.37)
  IN3 w0.122: v1(205.92,46.57) 205.51,46.99 205.51,49.01 202.88,51.64 179.26,51.64 178.57,52.32 173.79,52.32 171.8,54.32 170.58,54.81 167.65,57.75 166.39,57.75 147.59,76.55 147.59,78.08
  BOTTOM w0.089: UC1.Y29 v1(149.13,92.37)
  BOTTOM w0.135: JDIMM2.116 207.6,43.72 206.44,44.89 206.44,46.06 v1(205.92,46.57)
DDR_B_BA0: length 94
  IN3 w0.089: v1(153.54,80.28) 156.21,77.61 158.24,77.61 158.47,77.38
  IN3 w0.122: v1(216.39,44.17) 216.16,44.4 215.49,44.4 215.37,44.52 215.37,45.03 215.49,45.15 215.85,45.15 215.98,45.27 215.98,48.63 215.35,49.25 215.35,50.3 215.35,50.3 215.35,50.38 214.93,50.8 214.93,52.62 208,59.56 190.31,59.56 181.64,59.56 181.64,59.56 177.91,59.56 176.54,60.92 171.91,65.56 170.29,65.56 158.47,77.38
  BOTTOM w0.076: UC1.AJ37 154.94,87.59 154.94,86.82 154.5,86.38 154.5,83.88 154.48,83.86
  BOTTOM w0.089: 154.48,83.86 154.48,81.21 v1(153.54,80.28)
  BOTTOM w0.135: v1(216.39,44.17) 216.65,44.42 217.28,44.42 218.1,43.6 JDIMM2.150
DDR_B_BA1: length 94.9
  IN3 w0.089: v1(153.54,81.55) 153.84,81.55 153.93,81.46 153.93,80.26 156.33,77.86 158.54,77.86 159.02,77.38
  IN3 w0.122: v1(216.39,48.74) 216.37,48.77 216.37,48.79 215.74,49.42 215.74,50.54 215.38,50.9 215.38,52.89 215.67,53.18 215.67,53.36 215.5,53.53 215.33,53.53 215.04,53.24 214.86,53.24 214.69,53.41 214.69,53.58 214.98,53.87 214.98,54.05 214.81,54.22 214.64,54.22 214.35,53.93 214.17,53.93 214,54.1 214,54.27 214.29,54.56 214.29,54.74 214.12,54.91 213.95,54.91 213.66,54.62 213.48,54.62 213.31,54.79 213.31,54.96 213.6,55.25 213.6,55.43 213.43,55.6 213.26,55.6 212.97,55.31 212.79,55.31 212.62,55.48 212.62,55.65 212.91,55.94 212.91,56.12 212.74,56.29 212.57,56.29 212.28,56 212.1,56 211.93,56.17 211.93,56.34 212.22,56.63 212.22,56.81 212.05,56.98 211.88,56.98 211.59,56.69 211.42,56.69 208.16,59.95 190.15,59.95 190.15,59.95 181.8,59.95 178.07,59.95 176.93,61.08 172.07,65.95 170.45,65.95 159.02,77.38
  BOTTOM w0.076: UC1.AJ36 154.84,88.28 154.58,87.8 154.58,87.53 154.77,87.33 154.77,86.88 154.33,86.44 154.33,83.96 154.29,83.91
  BOTTOM w0.089: v1(153.54,81.55) 154.29,82.29 154.29,83.91
  BOTTOM w0.135: v1(216.39,48.74) 216.85,49.19 JDIMM2.145
DDR_B_BG0: length 92.7
  IN3 w0.089: 147.73,75.31 146.74,76.3 146.74,79.58 146.21,80.11 146.21,84.37 146.74,84.91 146.74,86.15 147.86,87.27 147.86,92.01 v1(148.22,92.37)
  IN3 w0.122: v1(204.38,47.46) 203.82,48.02 203.82,48.05 203.82,48.24 201.21,50.86 172.72,50.86 171.96,51.62 171.96,52.34 167.33,56.97 166.07,56.97 147.73,75.31
  BOTTOM w0.089: UC1.W29 v1(148.22,92.37)
  BOTTOM w0.135: v1(204.38,47.46) 205.73,48.8 206.38,49.13 207.35,50.11 JDIMM2.115
DDR_B_BG1: length 93.9
  IN3 w0.089: 147,79.16 147,86 148.59,87.59 148.59,92.85 148.74,93 v1(149.13,93)
  IN3 w0.122: v1(204.38,48.98) 204.38,49.59 202.72,51.25 174.94,51.25 174.82,51.37 174.82,51.81 174.7,51.93 174.45,51.93 174.33,51.81 174.33,51.37 174.21,51.25 173.85,51.25 173.18,51.92 173,51.92 172.69,51.61 172.52,51.61 172.35,51.78 172.35,51.95 172.66,52.27 172.66,52.44 172.48,52.62 172.23,52.62 171.85,52.99 171.85,53.17 172.04,53.35 172.04,53.53 171.87,53.7 171.69,53.7 171.51,53.51 171.33,53.51 167.49,57.36 166.23,57.36 147,76.59 147,79.16
  BOTTOM w0.089: UC1.Y28 v1(149.13,93)
  BOTTOM w0.135: v1(204.38,48.98) 204.4,48.98 204.66,49.25 205.37,49.25 205.69,49.57 206.17,49.57 206.85,50.24 JDIMM2.113
DDR_B_CKE0: length 91.1
  IN3 w0.089: v1(146.4,93) 146.76,92.64 146.76,90.31 146.59,90.14 146.53,89.99 146.32,89.48 146.32,86.44
  IN3 w0.122: 146.32,86.44 146.25,86.2 145.92,85.37 145.66,84.47 145.66,79.13 146.36,75.65 146.63,75.31 146.79,75.11 146.91,74.99 164.91,56.99 165.11,56.13 168.06,53.18 170.62,51.85 172.4,50.08 199.77,50.08 199.84,50.05 200.88,49.56 v1(202.99,47.93)
  BOTTOM w0.089: UC1.T28 v1(146.4,93)
  BOTTOM w0.135: JDIMM2.109 205.85,50.27 205.21,49.64 204.44,49.64 203.9,49.09 203.9,48.84 v1(202.99,47.93)
DDR_B_CKE1: length 92.8
  IN3 w0.089: v1(146.4,92.37) 146.15,92.12 146.04,91.85 146.04,87.83
  IN3 w0.122: v1(203.06,44.3) 202.89,44.35 200.86,48.15 200.12,49.49 199.68,49.69 171.99,49.69 170.11,51.35 167.92,52.82 167.87,52.82 164.52,56.16 164.52,56.72 146.32,74.92 146.23,75.31 146.19,75.47 146.09,75.96 145.34,79.32 145.34,84.44 145.77,86.14 146.04,87.83
  BOTTOM w0.089: UC1.T29 v1(146.4,92.37)
  BOTTOM w0.135: v1(203.06,44.3) 205.4,44.3 206.1,43.6 JDIMM2.110
DDR_B_CLK0: length 98.5
  IN3 w0.089: v1(213.26,47.52) 213.46,47.72 213.76,47.72 213.96,47.91 213.96,49.54 213.76,49.73 213.08,49.73 212.99,49.82 212.99,52.19 207.01,58.17 190.89,58.17 176.22,58.17 170.41,63.98 170.13,63.98 169.8,63.64 169.67,63.64 169.25,64.06 169.25,64.19 169.34,64.27 169.34,64.55 169.04,64.84 168.77,64.84 168.65,64.72 168.52,64.72 168.33,64.91 168.33,65.55 165.35,68.53 164.71,68.53 164.54,68.7 164.54,68.83 164.66,68.95 164.66,69.22 164.36,69.52 164.09,69.52 163.97,69.4 163.84,69.4 156.87,76.37 156.36,76.37 152.76,79.97 152.76,84.28 151.91,85.13 151.91,86.47 152,86.56 152.64,86.56 153.02,86.93 153.02,87.9 152.41,88.51 152.41,90.24 152.41,90.24 152.41,92.41 152.5,92.5 152.64,92.5 v1(152.78,92.37)
  BOTTOM w0.076: UC1.AF29 v1(152.78,92.37)
  BOTTOM w0.097: v1(213.26,47.52) 213.26,47.73 213.16,47.83 212.82,47.83 212.56,48.08 212.56,49.35 213.01,49.79 213.01,50.06 212.85,50.22 JDIMM2.137
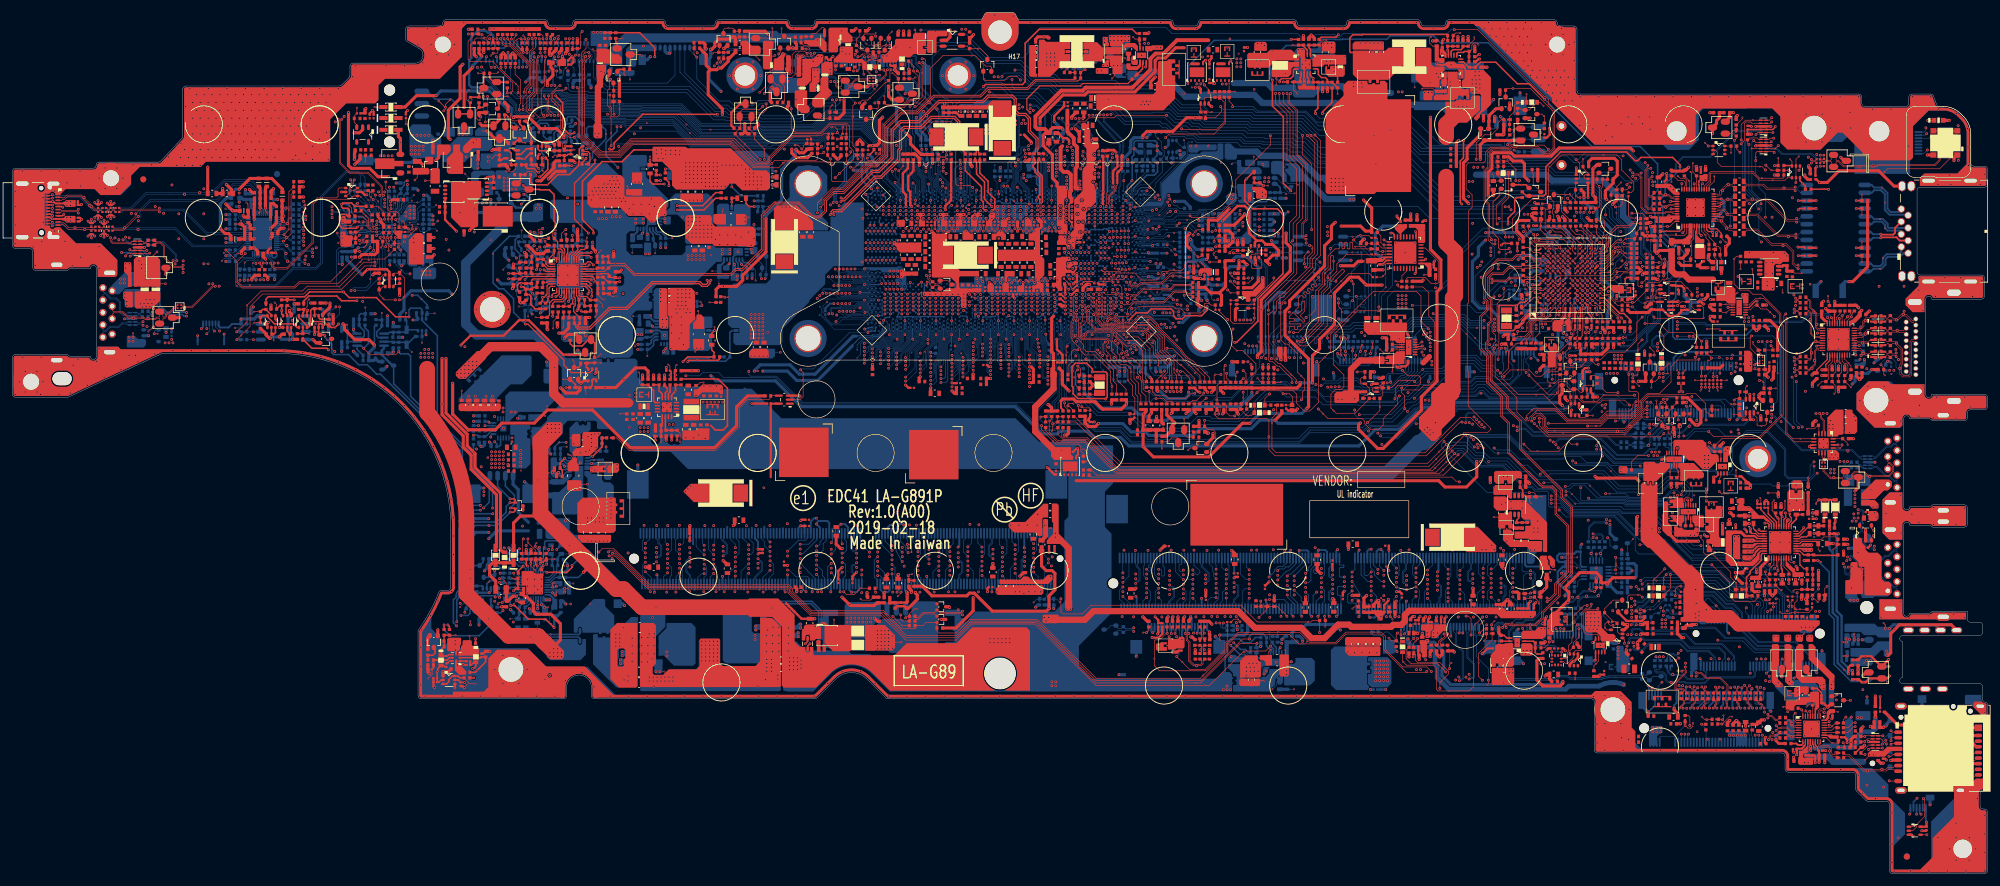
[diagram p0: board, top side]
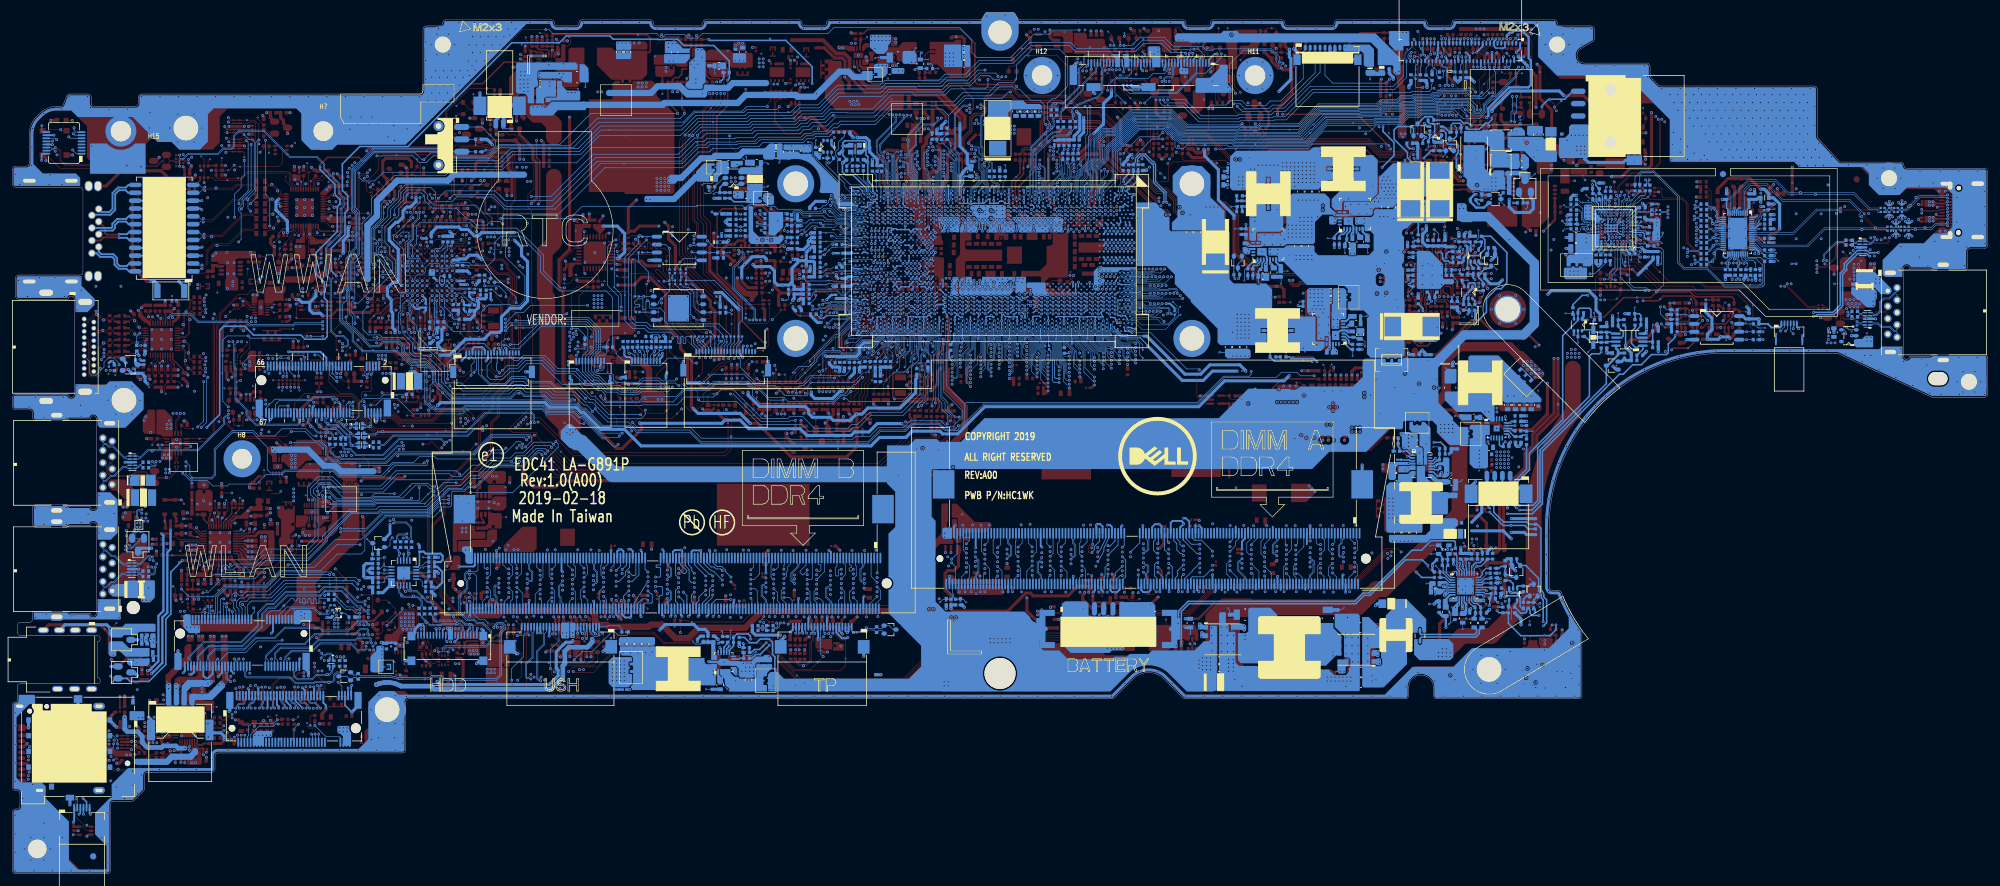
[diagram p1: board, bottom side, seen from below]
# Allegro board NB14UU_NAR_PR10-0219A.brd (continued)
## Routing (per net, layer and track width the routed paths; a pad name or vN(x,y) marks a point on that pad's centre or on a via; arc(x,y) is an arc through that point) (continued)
DDR_B_CLK1: length 97.8
  IN3 w0.089: v1(213.26,46) 213.26,45.78 213.17,45.69 212.94,45.69 212.71,45.91 212.58,46.07 212.21,49.21 212.21,50.33 211.97,51.51 211.81,52.27 206.69,57.39 191.21,57.39 175.89,57.39 175.54,57.74 170.42,62.87 169.28,62.87 166.28,65.86 166.28,65.99 166.4,66.11 166.4,66.38 166.1,66.68 165.83,66.68 165.71,66.56 165.58,66.56 165.39,66.75 165.39,66.87 165.51,66.99 165.51,67.27 165.22,67.56 164.94,67.56 164.82,67.44 164.7,67.44 152.31,79.83 152.31,84.11 151.58,84.83 151.35,85.39 151.35,89.73 151.41,89.99 151.5,90.36 151.5,92.53 151.62,92.65 151.78,92.65 151.87,92.56 v1(151.87,92.37)
  BOTTOM w0.076: UC1.AE29 v1(151.87,92.37)
  BOTTOM w0.097: v1(213.26,46) 212.97,45.71 212.74,45.71 212.55,45.52 212.55,44.35 213.02,43.89 213.18,43.89 213.28,43.79 213.28,43.7 213.1,43.52 JDIMM2.138
DDR_B_CLK#0: length 98.5
  IN3 w0.089: v1(152.78,93) 152.78,92.86 152.6,92.68 152.42,92.68 152.23,92.49 152.23,90.31 152.23,90.31 152.23,88.44 152.84,87.83 152.84,87.01 152.57,86.74 151.93,86.74 151.74,86.55 151.74,85.05 152.59,84.2 152.59,79.89 156.29,76.19 156.55,76.19 156.55,76.19 156.8,76.19 163.77,69.22 164.04,69.22 164.16,69.34 164.29,69.34 164.48,69.15 164.48,69.02 164.36,68.9 164.36,68.63 164.64,68.35 165.28,68.35 167.83,65.8 168.15,65.47 168.15,64.84 168.45,64.54 168.72,64.54 168.84,64.66 168.97,64.66 169.16,64.47 169.16,64.34 169.07,64.26 169.07,63.99 169.6,63.46 169.87,63.46 170.21,63.8 170.33,63.8 176.14,57.99 180.99,57.99 206.94,57.99 212.81,52.12 212.81,49.74 213,49.55 213.69,49.55 213.78,49.46 213.78,47.99 213.69,47.9 213.39,47.9 213.26,48.03 v1(213.26,48.28)
  BOTTOM w0.076: UC1.AF28 v1(152.78,93)
  BOTTOM w0.097: v1(213.26,48.28) 213.26,48.13 213.14,48.01 212.9,48.01 212.75,48.16 212.75,49.27 213.19,49.71 213.19,50.09 213.35,50.25 JDIMM2.139
DDR_B_CLK#1: length 97.7
  IN3 w0.089: v1(151.87,93) 151.69,92.83 151.54,92.83 151.32,92.61 151.32,90.38 151.23,89.99 151.18,89.75 151.18,85.35 151.43,84.73 152.13,84.03 152.13,79.76 156.42,75.47 156.42,75.46 164.62,67.26 164.9,67.26 165.02,67.38 165.14,67.38 165.33,67.19 165.33,67.07 165.21,66.95 165.21,66.67 165.51,66.38 165.78,66.38 165.9,66.5 166.03,66.5 166.22,66.31 166.22,66.18 166.1,66.06 166.1,65.79 169.2,62.68 170.34,62.68 175.36,57.66 175.82,57.21 180.67,57.21 206.62,57.21 211.65,52.18 211.78,51.51 212.03,50.31 212.03,49.2 212.41,46 212.58,45.79 212.86,45.51 212.99,45.51 v1(213.26,45.24)
  BOTTOM w0.076: UC1.AE28 v1(151.87,93)
  BOTTOM w0.097: JDIMM2.140 213.6,43.5 213.47,43.63 213.47,43.87 213.26,44.07 213.09,44.07 212.73,44.43 212.73,45.44 212.82,45.52 212.97,45.52 v1(213.26,45.24)
DDR_B_CS#0: length 94.4
  IN3 w0.089: v1(155.21,84.54) 154.77,84.1 154.77,80.64 156.73,78.69 159.91,78.69 161.22,77.38
  IN3 w0.122: v1(219.48,47.23) 219.1,47.23 217.98,48.35 217.98,53.32 217.43,53.87 217.43,53.89 212.78,58.53 211.77,58.53 208.8,61.5 189.51,61.5 178.71,61.5 178.49,61.73 172.71,67.5 171.09,67.5 167.06,71.53 167.06,72.27 166.49,72.84 165.75,72.84 161.22,77.38
  BOTTOM w0.076: 155.77,85.55 155.77,85.65 156.2,86.08 156.2,86.66 156.05,86.82 156.05,87.59 UC1.AL37
  BOTTOM w0.089: 155.77,85.55 155.77,85.1 v1(155.21,84.54)
  BOTTOM w0.135: v1(219.48,47.23) 218.92,47.23 217.85,48.3 JDIMM2.149
DDR_B_CS#1: length 95.3
  IN3 w0.089: v1(155.21,82.63) 155.21,82.81 155.32,82.93 155.79,82.93 156.08,82.64 156.08,80.78 157.56,79.3 161.25,79.3 163.17,77.38
  IN3 w0.122: v1(220.56,49.16) 220.21,49.16 219.77,49.61 219.77,49.86 219.94,50.03 219.94,50.3 219.82,50.42 219.31,50.42 219.19,50.55 219.19,50.79 219.31,50.91 219.82,50.91 219.94,51.03 219.94,51.28 219.82,51.4 219.31,51.4 219.19,51.52 219.19,51.77 219.31,51.89 219.82,51.89 219.99,52.06 219.99,52.91 219.87,53.03 219.31,53.03 219.19,53.15 219.19,53.86 212.28,60.77 211.18,60.77 209.28,62.67 189.02,62.67 189.02,62.67 182.93,62.67 182.93,62.67 179.4,62.67 168.37,73.69 168.31,73.69 167.47,74.53 167.11,74.53 166.89,74.32 166.72,74.32 166.24,74.8 165.75,74.8 163.17,77.38
  BOTTOM w0.076: UC1.AL35 156.46,88.67 156.46,88.04 156.57,87.84 156.57,87.46 156.37,87.27 156.37,86.95 156.53,86.79 156.53,85.95 156.13,85.54 156.13,85.44
  BOTTOM w0.089: v1(155.21,82.63) 156.13,83.55 156.13,85.44
  BOTTOM w0.135: JDIMM2.157 219.85,49.87 v1(220.56,49.16)
DDR_B_D0: length 66.3
  IN1 w0.099: v1(156.69,85.57) 157.28,84.98 157.28,79.57 156.14,78.43 156.14,63.53 160.84,58.83 160.84,58.69 160.53,58.37 160.53,58.23 160.67,58.09 160.81,58.09 161.12,58.4 161.26,58.4 161.41,58.26 161.41,58.12 161.09,57.81 161.09,57.67 161.23,57.53 161.37,57.53 161.69,57.84 161.83,57.84 161.97,57.7 161.97,57.56 161.65,57.25 161.65,57.11 161.79,56.97 161.93,56.97 162.25,57.28 162.39,57.28 162.93,56.74 170.58,56.74 176.49,50.83 177.38,50.83 179.2,49.01 179.55,49.01 179.82,48.74 179.82,46.76 v1(179.38,46.32)
  BOTTOM w0.076: UC1.AN35 157.04,88.67 157.04,88.04 156.93,87.84 156.93,87.46 157.13,87.27 157.13,86.95 156.91,86.74 156.91,85.79 v1(156.69,85.57)
  BOTTOM w0.107: v1(179.38,46.32) 178.81,45.76 178.81,44.38 179.6,43.59 JDIMM2.4
DDR_B_D1: length 63.8
  IN1 w0.099: v1(158,85.74) 157.56,85.31 157.56,79.47 156.44,78.35 156.44,64.78 163.93,57.29 164.18,57.04 170.7,57.04 176.61,51.13 177.51,51.13 179.33,49.32 179.67,49.32 180.17,48.81 180.17,45.6 v1(179.38,44.8)
  BOTTOM w0.076: v1(158,85.74) 158,85.83 158.39,86.22 158.39,86.53 158.23,86.69 158.23,87.8 158.27,87.92 158.27,88.1 158.23,88.21 158.23,88.45 158.31,88.67 158.31,89.42 158.3,89.43 158.25,89.48 158.13,89.6 158.13,89.6 158.09,89.63 UC1.AN34
  BOTTOM w0.107: v1(179.38,44.8) 180.6,43.58 JDIMM2.8
DDR_B_D2: length 66.5
  IN1 w0.089: v1(158,85.11) 158.98,84.12 158.98,81.5 159.29,81.2 159.29,78.15 158.53,77.39 158.53,74.01
  IN1 w0.099: v1(183.22,47.67) 183.63,48.08 183.63,49.35 176.65,56.33 175.67,56.33 175.09,55.75 174.95,55.75 174.65,56.05 174.65,56.19 174.95,56.5 174.95,56.64 174.81,56.78 174.67,56.78 174.37,56.47 174.23,56.47 174.09,56.61 174.09,56.75 174.39,57.06 174.39,57.2 174.25,57.34 174.11,57.34 173.81,57.03 173.67,57.03 173.53,57.17 173.53,57.31 173.83,57.62 173.83,57.76 173.69,57.9 173.55,57.9 173.25,57.59 173.1,57.59 172.96,57.73 172.96,57.87 173.27,58.18 173.27,58.32 173.13,58.46 172.99,58.46 172.68,58.15 172.54,58.15 171.45,59.25 164.93,59.25 158.53,65.65 158.53,74.01
  BOTTOM w0.076: UC1.AR35 158.56,88.89 158.39,88.43 158.39,88.24 158.44,88.13 158.44,87.89 158.39,87.77 158.39,86.75 158.55,86.6 158.55,86.15 158.38,85.97 158.38,85.49 158.3,85.41
  BOTTOM w0.089: 158.3,85.41 v1(158,85.11)
  BOTTOM w0.107: v1(183.22,47.67) 182.74,48.15 182.74,49.7 182.85,49.82 JDIMM2.17
DDR_B_D3: length 66.5
  IN1 w0.089: 157.62,76.04 157.62,77.48 158.74,78.6 158.74,80.97 158.38,81.33 158.38,82.49 158.3,82.57 v1(158,82.57)
  IN1 w0.099: 157.62,76.04 157.62,65.27 164.55,58.34 171.07,58.34 175.58,53.83 176.48,53.83 176.85,53.47 178.06,53.47 178.85,52.68 178.85,51.87 182.05,48.66 182.05,45.89 182.15,45.79 182.63,45.79 182.73,45.7 182.73,45.5 182.63,45.4 181.96,45.4 181.87,45.3 181.87,44.76 182,44.62 v1(183.22,44.62)
  BOTTOM w0.076: 158.8,85.15 158.87,85.22 158.87,85.77 159.05,85.95 159.05,86.79 158.89,86.95 158.89,87.27 159.09,87.46 159.09,87.84 158.96,88.07 158.96,89.01 158.73,89.48 UC1.AR34
  BOTTOM w0.089: v1(158,82.57) 158.74,83.31 158.74,85.09 158.8,85.15
  BOTTOM w0.107: JDIMM2.16 182.6,44.03 183.19,44.62 v1(183.22,44.62)
DDR_B_D4: length 65.6
  IN1 w0.089: v1(156.69,83.66) 156.58,83.55 156.58,79.38
  IN1 w0.099: v1(179.38,47.08) 170.51,55.95 167.67,55.95 167.27,55.55 161.48,55.55 160.02,57.01 160.02,57.15 160.32,57.44 160.32,57.58 160.18,57.72 160.04,57.72 159.74,57.43 159.6,57.43 159.46,57.57 159.46,57.71 159.76,58 159.76,58.14 159.62,58.28 159.47,58.28 159.18,57.99 159.04,57.99 158.9,58.13 158.9,58.27 159.19,58.56 159.19,58.7 159.05,58.84 158.91,58.84 158.62,58.55 158.48,58.55 156.48,60.55 156.48,60.69 156.84,61.04 156.84,61.18 156.7,61.32 156.56,61.32 156.2,60.97 156.06,60.97 155.54,61.5 155.54,78.34 156.58,79.38
  BOTTOM w0.076: UC1.AN37 157.45,87.59 157.45,86.82 157.25,86.61 157.25,86.4
  BOTTOM w0.089: 157.25,86.4 157.25,84.22 v1(156.69,83.66)
  BOTTOM w0.107: JDIMM2.7 180.35,48.06 v1(179.38,47.08)
DDR_B_D5: length 65.7
  IN1 w0.099: v1(156.69,84.3) 157.1,83.88 157.1,83.38 156.88,83.16 156.88,79.43 155.84,78.38 155.84,62.61 156.2,62.25 156.2,62.11 155.96,61.87 155.96,61.73 156.1,61.59 156.24,61.59 156.48,61.83 156.62,61.83 157.36,61.09 157.36,60.95 157.01,60.59 157.01,60.45 157.15,60.31 157.29,60.31 157.58,60.61 157.72,60.61 157.86,60.47 157.86,60.33 157.57,60.03 157.57,59.89 157.71,59.75 157.85,59.75 158.14,60.04 158.28,60.04 158.42,59.9 158.42,59.76 158.13,59.47 158.13,59.33 158.27,59.19 158.41,59.19 158.7,59.48 158.84,59.48 162.47,55.86 167.14,55.86 167.54,56.26 170.63,56.26 176.67,50.22 176.81,50.22 177.12,50.53 177.26,50.53 177.4,50.39 177.4,50.25 177.09,49.94 177.09,49.8 177.23,49.66 177.37,49.66 177.68,49.97 177.82,49.97 177.96,49.83 177.96,49.69 177.71,49.43 177.71,49.29 177.85,49.15 177.99,49.15 178.24,49.41 178.38,49.41 178.52,49.27 178.52,49.13 178.33,48.94 178.33,48.8 178.47,48.66 178.61,48.66 178.8,48.85 178.94,48.85 179.18,48.61 v1(179.38,48.61)
  BOTTOM w0.076: 157,84.61 157.08,84.68 157.08,86.67 157.29,86.88 157.29,87.33 157.09,87.53 157.09,87.8 157.36,88.28 UC1.AN36
  BOTTOM w0.089: 157,84.61 v1(156.69,84.3)
  BOTTOM w0.107: v1(179.38,48.61) 179.35,48.64 JDIMM2.3
DDR_B_D6: length 66.7
  IN1 w0.089: 158.8,78.41 158.92,78.53 158.92,81.04 158.91,81.05 158.56,81.4 158.56,82.94 158.3,83.2 v1(158,83.2)
  IN1 w0.099: 158.8,78.41 157.93,77.54 157.93,65.4 164.68,58.65 171.2,58.65 175.71,54.13 176.61,54.13 176.97,53.77 178.19,53.77 179.15,52.8 179.15,51.99 179.77,51.37 179.91,51.37 180.24,51.7 180.38,51.7 180.52,51.56 180.52,51.42 180.19,51.09 180.19,50.95 180.33,50.81 180.47,50.81 180.8,51.14 180.94,51.14 181.08,51 181.08,50.86 180.75,50.53 180.75,50.39 180.89,50.25 181.03,50.25 181.36,50.58 181.5,50.58 181.64,50.44 181.64,50.3 181.31,49.97 181.31,49.83 182.35,48.79 182.35,46.24 182.45,46.14 v1(183.22,46.14)
  BOTTOM w0.076: UC1.AR36 158.66,88.28 158.92,87.8 158.92,87.53 158.73,87.33 158.73,86.88 158.88,86.73 158.88,86.01 158.71,85.84 158.71,85.31 158.63,85.24
  BOTTOM w0.089: 158.63,85.24 158.56,85.17 158.56,83.76 v1(158,83.2)
  BOTTOM w0.107: JDIMM2.20 183.6,43.96 183.81,44.17 183.81,45.55 v1(183.22,46.14)
DDR_B_D7: length 66.4
  IN1 w0.089: v1(158,84.47) 158.03,84.47 158.76,83.74 158.76,81.45 159.11,81.09 159.11,78.49 158.76,78.13
  IN1 w0.099: 158.76,78.13 158.23,77.6 158.23,65.52 164.8,58.95 171.32,58.95 174.95,55.32 175.09,55.32 175.7,55.94 175.84,55.94 175.98,55.8 175.98,55.66 175.37,55.04 175.37,54.9 175.51,54.76 175.65,54.76 176.65,55.76 176.79,55.76 176.93,55.62 176.93,55.48 176.16,54.72 176.16,54.58 176.3,54.44 176.44,54.44 177.21,55.2 177.35,55.2 177.49,55.06 177.49,54.92 176.94,54.37 176.94,54.23 177.1,54.07 177.29,54.07 177.8,54.57 177.94,54.57 182.56,49.95 182.56,49.81 182.23,49.48 182.23,49.34 182.37,49.2 182.51,49.2 182.84,49.53 182.98,49.53 183.22,49.29 v1(183.22,49.19)
  BOTTOM w0.076: UC1.AR37 158.56,87.59 158.56,86.82 158.72,86.66 158.72,86.08 158.54,85.91 158.54,85.4 158.47,85.33
  BOTTOM w0.089: v1(158,84.47) 158.38,84.86 158.38,85.24 158.47,85.33
  BOTTOM w0.107: v1(183.22,49.19) 183.51,48.9 183.78,48.9 183.9,49.02 183.9,49.32 183.77,49.45 183.61,49.45 183.5,49.55 183.5,49.77 183.61,49.87 183.74,49.87 183.85,49.98 JDIMM2.21
DDR_B_D8: length 67.6
  IN1 w0.089: 160.31,76.76 160.31,79.07 160.22,79.15 160.22,79.16 160.15,79.23 160.15,81.1 160.43,81.38 160.43,83.13 160.2,83.36 160.2,84.29 v1(159.66,84.83)
  IN1 w0.099: v1(185.16,47.66) 185.53,47.66 185.65,47.53 185.65,45.79 185.78,45.67 186.29,45.67 186.41,45.79 186.41,49.11 183.87,51.65 183.87,52.38 181.31,54.94 180.58,54.94 176.35,59.17 174.57,59.17 172.97,60.77 165.55,60.77 160.35,65.97 160.35,73.81 160.31,73.86 160.31,76.76
  BOTTOM w0.076: 159.97,85.14 160.04,85.21 160.04,85.62 159.98,85.68 159.98,86.6 160.14,86.75 160.14,87.78 160.1,87.89 160.1,88.13 160.14,88.24 160.14,88.43 159.97,88.89 UC1.AU35
  BOTTOM w0.089: 159.97,85.14 v1(159.66,84.83)
  BOTTOM w0.107: v1(185.16,47.66) 184.51,48.3 184.51,49.95 184.85,50.29 JDIMM2.25
DDR_B_D9: length 67.2
  IN1 w0.089: 159.75,81.13 159.75,81.2 160.08,81.53 160.08,81.87 v1(159.66,82.29)
  IN1 w0.099: 159.75,81.13 159.75,65.72 165.3,60.16 172.72,60.16 175.39,57.49 175.53,57.49 176.29,58.24 176.43,58.24 184.7,49.97 184.7,47.86 184.05,47.21 184.05,46.93 184.15,46.83 184.66,46.83 184.76,46.73 184.76,46.53 184.66,46.43 184.15,46.43 184.05,46.33 184.05,46 184.15,45.9 184.92,45.9 v1(185.16,46.13)
  BOTTOM w0.076: UC1.AU34 159.8,89.48 159.58,89.03 159.58,88.08 159.45,87.84 159.45,87.46 159.64,87.27 159.64,86.95 159.49,86.79 159.49,86.06 159.11,85.69 159.11,85.15 159.09,85.13 159.09,85.03
  BOTTOM w0.089: 159.09,85.03 159.09,82.85 v1(159.66,82.29)
  BOTTOM w0.107: JDIMM2.24 184.6,45.58 v1(185.16,46.13)
DDR_B_D10: length 68.7
  IN1 w0.099: 161.62,78.05 161.62,74.05 161.71,73.97 161.71,73.94 161.84,73.81 161.84,66.58 166.17,62.25 173.59,62.25 175.17,60.66 176.95,60.66 180.62,57 180.76,57 181.18,57.42 181.32,57.42 181.46,57.28 181.46,57.14 181.04,56.72 181.04,56.58 181.18,56.44 181.32,56.44 181.73,56.86 181.87,56.86 186.13,52.61 186.13,51.74 188.45,49.42 188.45,46.06 188.14,45.74 188.14,45.6 188.46,45.28 188.6,45.28 189.15,45.83 189.15,46.01 v1(189.14,46.01)
  IN1 w0.102: 161.62,78.05 161.62,83.5 161.52,83.6 v1(160.96,83.6)
  BOTTOM w0.076: 161.6,86.66 161.6,86.76 161.41,86.95 161.41,87.27 161.6,87.46 161.6,87.84 161.49,88.04 161.49,88.67 UC1.AW35
  BOTTOM w0.089: 161.6,86.66 161.6,84.24 v1(160.96,83.6)
  BOTTOM w0.107: v1(189.14,46.01) 189.57,45.58 189.57,44.25 189.1,43.78 JDIMM2.42
DDR_B_D11: length 67.3
  IN1 w0.089: v1(159.66,83.56) 160.26,82.96 160.26,81.46 159.95,81.15 159.95,80.99
  IN1 w0.099: 159.95,80.99 159.98,80.96 159.98,79.15 160.05,79.08 160.05,65.84 165.43,60.46 172.85,60.46 174.69,58.62 174.83,58.62 175.07,58.86 175.21,58.86 175.35,58.72 175.35,58.58 175.11,58.34 175.11,58.2 175.39,57.91 175.53,57.91 176.29,58.67 176.43,58.67 180.68,54.41 180.82,54.41 181.05,54.63 181.19,54.63 181.33,54.49 181.33,54.35 181.1,54.13 181.1,53.99 181.26,53.83 181.4,53.83 181.63,54.05 181.77,54.05 181.91,53.91 181.91,53.77 181.68,53.55 181.68,53.41 181.82,53.27 181.96,53.27 182.19,53.49 182.33,53.49 182.47,53.35 182.47,53.21 182.25,52.99 182.25,52.85 182.39,52.71 182.53,52.71 182.75,52.93 182.89,52.93 183.03,52.79 183.03,52.65 182.81,52.43 182.81,52.29 185.16,49.94 v1(185.16,49.18)
  BOTTOM w0.076: 160.22,85.72 160.15,85.79 160.15,86.53 160.3,86.69 160.3,87.8 160.26,87.92 160.26,88.1 160.3,88.21 160.3,88.45 160.22,88.69 160.22,89.41 160.24,89.43 160.44,89.63 UC1.AW34
  BOTTOM w0.089: 160.22,85.72 160.22,84.12 v1(159.66,83.56)
  BOTTOM w0.107: JDIMM2.29 185.85,49.69 186.1,49.44 186.1,48.23 185.98,48.1 185.7,48.1 185.6,48.21 185.6,49.07 185.49,49.18 v1(185.16,49.18)
DDR_B_D12: length 66.8
  IN1 w0.099: v1(189.14,44.49) 188.41,44.49 188.32,44.59 188.32,44.93 188.22,45.03 188.02,45.03 187.92,44.93 187.92,44.59 187.82,44.49 187.42,44.49 187.33,44.59 187.33,45.36 188.15,46.18 188.15,49.3 185.83,51.62 185.83,52.48 182.19,56.12 181.07,56.12 176.83,60.36 175.05,60.36 173.46,61.95 166.05,61.95 161.53,66.46 161.53,73.9 161.4,74.03 161.4,77.85
  IN1 w0.102: 161.4,77.85 161.4,82.79 161.06,83.12 160.74,83.12 160.51,83.35 160.51,84.61 v1(159.66,85.46)
  BOTTOM w0.076: UC1.AU37 159.97,87.59 159.97,86.82 159.82,86.66 159.82,85.62 v1(159.66,85.46)
  BOTTOM w0.107: v1(189.14,44.49) 188.64,44.49 188.1,43.95 JDIMM2.38
DDR_B_D13: length 66.6
  IN1 w0.089: 159.14,73.69 159.14,77.36 159.52,77.75 159.52,81.27 159.19,81.6 159.19,82.45 v1(159.66,82.92)
  IN1 w0.099: 159.14,73.69 159.14,65.9 165.18,59.86 172.6,59.86 175.39,57.06 175.54,57.06 176.29,57.81 176.43,57.81 184.39,49.85 184.39,47.98 183.75,47.34 183.75,45.69 183.85,45.59 184.65,45.59 184.75,45.5 184.75,45.3 184.65,45.2 183.85,45.2 183.75,45.1 183.75,44.71 183.85,44.61 v1(185.16,44.61)
  BOTTOM w0.076: 159.27,84.97 159.27,85.07 159.28,85.08 159.28,85.62 159.65,85.99 159.65,86.73 159.81,86.88 159.81,87.33 159.61,87.53 159.61,87.8 159.87,88.28 UC1.AU36
  BOTTOM w0.089: 159.27,84.97 159.27,83.31 v1(159.66,82.92)
  BOTTOM w0.107: JDIMM2.28 185.6,42.81 185.6,44.17 v1(185.16,44.61)
DDR_B_D14: length 67.5
  IN1 w0.099: 161.88,78.23 161.88,74.07 162.14,73.81 162.14,66.71 166.3,62.55 173.72,62.55 175.3,60.97 177.08,60.97 178.87,59.18 179.01,59.18 179.64,59.81 179.78,59.81 179.92,59.67 179.92,59.53 179.29,58.9 179.29,58.76 179.43,58.62 179.57,58.62 180.2,59.25 180.34,59.25 180.48,59.11 180.48,58.97 179.85,58.34 179.85,58.2 179.99,58.06 180.13,58.06 180.76,58.69 180.9,58.69 181.04,58.55 181.04,58.41 180.41,57.78 180.41,57.64 180.62,57.43 180.76,57.43 181.18,57.85 181.32,57.85 186.54,52.62 186.54,51.76 186.74,51.57 186.88,51.57 187.01,51.7 187.15,51.7 187.29,51.56 187.29,51.42 187.16,51.29 187.16,51.15 189.14,49.16 v1(189.14,49.06)
  IN1 w0.102: 161.88,78.23 161.88,80.97 161.88,83.46 161.88,84.34 161.35,84.87 v1(160.96,84.87)
  BOTTOM w0.076: 161.42,86.61 161.42,86.71 161.24,86.88 161.24,87.33 161.44,87.53 161.44,87.8 161.18,88.28 UC1.AW36
  BOTTOM w0.089: 161.42,86.61 161.42,85.33 v1(160.96,84.87)
  BOTTOM w0.107: v1(189.14,49.06) 188.89,48.8 188.71,48.8 188.71,48.8 188.45,49.06 188.45,49.85 188.55,49.95 188.75,49.95 188.85,50.05 JDIMM2.41
DDR_B_D15: length 67.3
  IN1 w0.099: 162.14,74.09 162.44,73.78 162.44,66.83 166.42,62.85 173.85,62.85 175.43,61.27 177.2,61.27 178.87,59.61 179.01,59.61 179.64,60.24 179.78,60.24 187.77,52.25 187.77,51.01 187.93,50.85 188.07,50.85 188.31,51.08 188.45,51.08 188.59,50.94 188.59,50.8 188.35,50.57 188.35,50.43 188.49,50.29 188.63,50.29 188.87,50.52 189.01,50.52 189.15,50.38 189.15,50.24 188.91,50.01 188.91,49.87 189.6,49.18 189.6,47.87 190.1,47.38 190.1,47.04 190,46.94 189.69,46.94 189.59,47.04 189.59,47.09 v1(189.14,47.54)
  IN1 w0.102: v1(160.96,85.51) 162.03,85.51 162.14,85.41 162.14,74.09
  BOTTOM w0.076: UC1.AW37 161.08,87.59 161.08,86.82 161.24,86.66 161.24,86.56
  BOTTOM w0.089: 161.24,86.56 161.24,85.79 v1(160.96,85.51)
  BOTTOM w0.107: JDIMM2.37 187.85,50.09 187.85,50.09 187.85,48.83 188.46,48.22 188.47,48.22 v1(189.14,47.54)
DDR_B_D16: length 100
  IN3 w0.097: v1(154.58,92.42) 154.22,92.06 154.22,91.68 154.26,91.64 154.26,90.37 154.63,89.44 156.5,87.58 157.32,87.58 158.55,86.35 158.55,82.27 160.87,79.96 161.82,79.96 163.93,77.85 164.67,77.85 166.32,76.21 167.83,76.21 179.98,64.06 183.51,64.06 183.51,64.06 188.45,64.06 209.86,64.06 211.76,62.16 213.01,62.16 222.75,52.42 222.75,48.27 222.44,47.95 222.44,45.93 v1(223.56,44.81)
  BOTTOM w0.089: UC1.AJ29 154.98,92.65 v1(154.58,92.42)
  BOTTOM w0.107: v1(223.56,44.81) 223.1,44.35 JDIMM2.170
DDR_B_D17: length 100.5
  IN3 w0.089: 165.57,77.38 164.93,78.02 164,78.02 163.48,78.53 163.48,78.54 163.1,78.92
  IN3 w0.097: 165.57,77.38 166.44,76.51 167.96,76.51 180.1,64.36 183.63,64.36 209.99,64.36 211.89,62.46 213.13,62.46 223.09,52.51 223.09,48.18 222.74,47.83 222.74,46.64 223.04,46.33 v1(223.56,46.33) ; v1(154.59,91.83) 154.76,91.66 154.43,91.33 154.43,90.4 154.78,89.54 156.49,87.83 157.41,87.83 159.23,86.01 161.01,86.01 162.26,84.76 162.26,79.76 163.1,78.92
  BOTTOM w0.089: v1(154.59,91.83) 154.93,92.02 UC1.AJ30
  BOTTOM w0.107: v1(223.56,46.33) 224.27,45.61 224.27,44.32 224.1,44.14 JDIMM2.174
DDR_B_D18: length 100.6
  IN3 w0.097: v1(226.72,44.81) 227.35,44.81 227.61,45.06 227.61,45.23 227.71,45.32 228.08,45.32 228.17,45.42 228.17,45.61 228.08,45.71 227.71,45.71 227.61,45.81 227.61,46 227.71,46.09 228.08,46.09 228.17,46.19 228.17,46.38 228.08,46.48 227.71,46.48 227.61,46.58 227.61,50.72 227.12,51.21 227.12,53.17 223.35,56.94 222.47,56.94 214.27,65.14 212.99,65.14 211.1,67.04 187.21,67.04 183.7,67.04 176.8,73.93 176.27,74.12 175.06,75.32 174.33,75.32 169.22,80.43 169.22,82.94 166.56,85.61 166.56,86.3 165.93,86.93 165.76,86.93 165.67,87.02 164.43,87.51 162.99,87.51 161.6,88.39 161.58,88.38 160.81,88.61 159.51,89.91 158.17,89.91 v1(157.26,90.4)
  BOTTOM w0.089: UC1.AM32 157.16,90.4 v1(157.26,90.4)
  BOTTOM w0.107: JDIMM2.182 226.1,44.19 v1(226.72,44.81)
DDR_B_D19: length 101.3
  IN3 w0.097: v1(226.72,46.33) 227.2,46.82 227.2,50.7 226.72,51.19 226.72,53.15 224.55,55.31 224.16,55.31 223.97,55.12 223.84,55.12 223.49,55.47 223.49,55.61 223.77,55.88 223.77,56.02 223.63,56.16 223.49,56.16 223.22,55.88 223.08,55.88 222.94,56.02 222.94,56.15 223.16,56.37 223.16,56.5 223.02,56.64 222.88,56.64 222.67,56.43 222.53,56.43 214.12,64.84 212.87,64.84 210.97,66.74 187.34,66.74 183.46,66.74 176.48,73.72 175,74.23 168.97,80.26 168.97,82.75 166.3,85.42 166.3,86.31 165.87,86.74 164.09,86.74 163.66,87.17 163.2,87.17 161.57,88.2 160.69,88.47 160.67,88.51 159.44,89.74 157.79,89.74 157.1,89.94 156.81,90.23 156.81,90.78 v1(156.45,91.15)
  BOTTOM w0.089: UC1.AM31 156.49,91.13 v1(156.45,91.15)
  BOTTOM w0.107: JDIMM2.186 227.1,44.28 227.25,44.44 227.25,45.79 v1(226.72,46.33)
DDR_B_D20: length 101.6
  IN3 w0.089: 163.89,78.61 164.14,78.36 165.49,78.36 166.34,77.51
  IN3 w0.097: 163.89,78.61 163.89,83.74 163.89,83.74 163.89,83.88 163.89,83.88 163.89,84 160.96,86.93 159.44,87.47 158.27,87.47 157.48,88.26 156.55,88.26 155.07,89.74 154.78,90.47 154.78,91.19 155.15,91.56 155.15,91.89 155.25,91.99 155.37,92.11 156.05,92.11 v1(156.42,91.73) ; v1(223.56,47.85) 224.13,48.43 224.13,51.79 223.69,52.23 223.69,52.75 213.38,63.06 212.13,63.06 210.23,64.96 188.07,64.96 181.81,64.96 179.27,67.5 179.13,67.5 178.54,66.91 178.4,66.91 178.27,67.05 178.27,67.18 178.58,67.5 178.58,67.64 178.45,67.77 178.31,67.77 178.05,67.51 177.91,67.51 168.32,77.1 166.74,77.1 166.34,77.51
  BOTTOM w0.089: UC1.AM30 v1(156.42,91.73)
  BOTTOM w0.107: JDIMM2.173 223.85,49.92 224.01,49.76 224.01,49.07 223.97,49.03 223.97,48.26 v1(223.56,47.85)
DDR_B_D21: length 101.7
  IN3 w0.097: v1(223.56,49.38) 223.39,49.54 223.39,49.91 223.49,50.01 223.74,50.01 223.83,50.1 223.83,50.3 223.74,50.39 223.49,50.39 223.39,50.49 223.39,52.63 213.26,62.76 212.01,62.76 210.11,64.66 188.2,64.66 188.2,64.66 183.76,64.66 183.76,64.66 180.23,64.66 180.07,64.82 180.07,64.96 180.66,65.55 180.66,65.68 180.52,65.82 180.39,65.82 179.8,65.23 179.66,65.23 179.52,65.37 179.52,65.5 180.11,66.09 180.11,66.23 179.98,66.37 179.84,66.37 179.25,65.77 179.11,65.77 178.89,66 178.89,66.13 178.99,66.24 178.99,66.38 178.79,66.58 178.65,66.58 178.55,66.48 178.41,66.48 168.08,76.81 166.56,76.81 165.18,78.19 164.07,78.19 163.82,78.44 163.82,78.44 163.72,78.54 163.72,83.81 160.71,86.81 159.95,86.81 159.82,86.69 158.81,86.69 157.41,88.08 156.62,88.08 156.48,88.08 154.92,89.64 154.61,90.43 154.61,91.26 154.98,91.64 154.98,91.96 155.08,92.06 155.39,92.37 v1(156.42,92.37)
  BOTTOM w0.089: UC1.AM29 v1(156.42,92.37)
  BOTTOM w0.107: v1(223.56,49.38) 222.85,50.09 JDIMM2.169
DDR_B_D22: length 98.7
  IN3 w0.097: v1(156.42,90.56) 156.61,90.08 156.82,89.87 158.18,89.04 161.5,88.05 163.23,86.95 163.8,86.38 163.8,86.37 163.87,86.3 165.44,84.35 165.54,84.15 165.54,80.97 166.81,79.7 166.81,79.04 167.79,78.05 170.04,78.05 171.43,76.65 172.1,76.65 172.76,76 173.46,75.34 174.83,73.97 176.29,73.47 183.32,66.44 184.49,66.44 184.49,66.44 187.46,66.44 187.46,66.44 210.85,66.44 212.75,64.54 214,64.54 223.84,54.7 223.97,54.7 224.29,55.01 224.42,55.01 224.56,54.88 224.56,54.74 224.25,54.42 224.25,54.29 224.38,54.15 224.52,54.15 224.83,54.47 224.97,54.47 225.11,54.33 225.11,54.19 224.79,53.88 224.79,53.74 224.93,53.61 225.07,53.61 225.38,53.92 225.52,53.92 225.65,53.78 225.65,53.65 225.34,53.33 225.34,53.2 225.5,53.04 225.89,53.04 226.42,52.51 226.42,50.77 226.51,50.67 226.81,50.67 226.9,50.58 226.9,50.38 226.81,50.29 226.51,50.29 226.42,50.19 226.42,49.95 226.72,49.65 v1(226.72,49.38)
  BOTTOM w0.089: UC1.AJ31 155.06,91.08 155.35,90.79 155.66,90.79 155.83,90.97 156.12,90.97 156.42,90.66 v1(156.42,90.56)
  BOTTOM w0.107: v1(226.72,49.38) 227.35,50.01 JDIMM2.187
DDR_B_D23: length 99
  IN3 w0.097: v1(226.72,47.85) 226.31,48.26 226.31,49.46 226.11,49.66 226.11,51.3 226.01,51.39 225.71,51.39 225.58,51.52 225.58,51.65 225.71,51.78 226.01,51.78 226.11,51.88 226.11,52.39 225.76,52.74 225.37,52.74 213.87,64.24 212.62,64.24 210.72,66.14 187.59,66.14 183.2,66.14 176.25,73.08 172.71,74.44 171.63,75.52 171.63,76.04 169.8,77.86 167.74,77.86 166.64,78.97 166.64,79.63 165.37,80.9 165.37,84.02 165.14,84.43 163.73,86.18 163.63,86.3 163.12,86.81 161.43,87.89 157.79,88.97 156.56,88.97 156.04,89.5 v1(156.04,90.09)
  BOTTOM w0.089: UC1.AJ32 155.06,89.99 155.37,89.67 155.62,89.67 v1(156.04,90.09)
  BOTTOM w0.107: JDIMM2.183 226.35,49.88 226.15,49.68 226.15,48.42 v1(226.72,47.85)
DDR_B_D24: length 101.3
  IN1 w0.089: v1(158.27,91.15) 158.21,91.1 158.07,91.1 157.8,90.83 157.8,89.97 160.07,87.7 164.98,87.7 166.33,86.36
  IN1 w0.099: 166.33,86.36 166.33,85.99 168.53,83.79 168.53,80.89 169.5,79.92 169.5,75.16 170.19,74.47 170.46,74.47 172.19,72.73 172.95,72.73 174.08,71.6 176.2,71.6 176.8,71 180.42,71 181.58,69.84 182.96,69.84 192.45,60.35 192.59,60.35 193.15,60.91 193.33,60.91 193.43,60.81 193.43,60.63 192.87,60.07 192.87,59.93 193.03,59.77 194.56,59.77 203.11,51.21 226.13,51.21 228.1,49.24 228.1,48.01 v1(228.58,47.54)
  BOTTOM w0.089: UC1.AR31 158.32,91.13 v1(158.27,91.15)
  BOTTOM w0.107: JDIMM2.191 228.35,49.85 228.1,49.61 228.1,48.01 v1(228.58,47.54)
DDR_B_D25: length 100
  IN1 w0.089: 166.55,86.42 165.06,87.91 160.11,87.91 158.02,89.99 158.02,90.24 v1(158.25,90.46)
  IN1 w0.099: 166.55,86.42 166.55,86.02 168.71,83.86 168.71,80.96 169.81,79.86 169.81,77.02 170.32,76.51 170.32,75.95 170.11,75.74 170.11,75.06 171.18,73.99 171.36,73.99 172.32,73.04 173.08,73.04 174.21,71.9 176.32,71.9 176.93,71.3 180.54,71.3 181.1,70.74 182.51,70.74 190.27,62.98 190.27,62.96 190.58,62.64 190.8,62.64 191.02,62.42 191.16,62.42 191.68,62.93 191.82,62.93 191.96,62.79 191.96,62.65 191.33,62.03 191.33,61.89 191.47,61.75 191.61,61.75 192.24,62.37 192.38,62.37 192.52,62.23 192.52,62.09 191.89,61.47 191.89,61.33 192.22,61 192.36,61 192.99,61.62 193.13,61.62 203.24,51.52 226.29,51.52 228.58,49.23 v1(228.58,49.06)
  BOTTOM w0.089: UC1.AR32 v1(158.25,90.46)
  BOTTOM w0.107: JDIMM2.195 229.35,49.83 v1(228.58,49.06)
DDR_B_D26: length 103.6
  IN1 w0.076: v1(160.07,91.73) 160.44,91.36 160.44,90.86 160.74,90.57
  IN1 w0.089: 169.75,83.77 169.74,83.77 169.74,84.27 168.13,85.88 168.13,87.66 167.16,88.62 166.45,88.62 165.29,89.79 161.86,89.79 161.37,90.27 161.37,90.29 161.08,90.57 160.74,90.57
  IN1 w0.099: 169.75,83.77 169.75,83.76 169.75,81.59 172.88,78.47 172.88,77.26 174.17,75.96 174.82,75.96 175.58,75.19 176.08,75.19 177.48,73.79 181.01,73.79 181.97,72.83 183.37,72.83 186.41,69.8 186.55,69.8 186.83,70.08 186.97,70.08 187.11,69.94 187.11,69.8 186.83,69.52 186.83,69.38 187.06,69.15 187.2,69.15 187.81,69.76 187.95,69.76 188.09,69.61 188.09,69.47 187.48,68.86 187.48,68.72 187.62,68.58 187.76,68.58 188.37,69.19 188.51,69.19 188.65,69.05 188.65,68.91 188.04,68.3 188.04,68.16 188.18,68.02 188.32,68.02 188.93,68.63 189.07,68.63 189.21,68.49 189.21,68.35 188.6,67.74 188.6,67.6 188.74,67.46 188.88,67.46 189.49,68.07 189.63,68.07 203.02,54.68 227.73,54.68 229.47,52.95 229.47,51.63 v1(231.91,49.19)
  BOTTOM w0.089: UC1.AV30 v1(160.07,91.73)
  BOTTOM w0.107: v1(231.91,49.19) 231.35,49.75 JDIMM2.203
DDR_B_D27: length 104.2
  IN1 w0.076: v1(160.07,92.37) 160.61,91.83 160.61,90.96
  IN1 w0.089: 169.93,83.57 169.93,84.31 168.36,85.88 168.36,87.76 167.27,88.85 166.53,88.85 165.39,89.99 161.89,89.99 161.53,90.34 161.53,90.35 161.15,90.74 160.83,90.74 160.61,90.96
  IN1 w0.099: v1(231.91,47.66) 232.42,48.18 232.42,49.25 229.98,51.69 229.98,52.9 227.66,55.22 202.91,55.22 187.05,71.08 186.91,71.08 186.35,70.52 186.21,70.52 186.07,70.66 186.07,70.8 186.63,71.36 186.63,71.5 186.49,71.64 186.35,71.64 185.74,71.03 185.6,71.03 185.46,71.17 185.46,71.31 185.67,71.52 186.07,71.92 186.07,72.06 185.54,72.59 184.5,72.59 183.96,73.13 182.09,73.13 181.13,74.09 177.6,74.09 176.2,75.49 175.71,75.49 174.9,76.3 174.26,76.3 173.31,77.24 173.31,78.46 169.93,81.84 169.93,83.57
  BOTTOM w0.089: UC1.AV29 v1(160.07,92.37)
  BOTTOM w0.107: JDIMM2.207 232.35,48.11 v1(231.91,47.66)
DDR_B_D28: length 102
  IN1 w0.089: v1(158.25,91.73) 158.7,91.28 158.7,90.45 159.41,89.74 159.43,89.74 159.69,89.48 159.76,89.41 159.76,89.06 160.74,88.08 165.16,88.08 166.76,86.49
  IN1 w0.099: 166.76,86.49 166.76,86.05 168.88,83.93 168.88,81.03 170.09,79.83 170.09,77.06 170.9,76.25 170.9,74.88 172.37,73.41 175.32,73.41 177.13,71.6 180.67,71.6 181.22,71.05 182.63,71.05 190,63.68 190.47,63.68 190.52,63.73 190.66,63.73 190.8,63.59 190.8,63.45 190.57,63.22 190.57,63.08 190.71,62.94 190.85,62.94 191.47,63.57 191.61,63.57 203.36,51.82 226.47,51.82 229.02,49.27 229.02,46.45 v1(228.58,46.01)
  BOTTOM w0.089: UC1.AR30 v1(158.25,91.73)
  BOTTOM w0.107: v1(228.58,46.01) 228.1,45.54 JDIMM2.190
DDR_B_D29: length 102.5
  IN1 w0.089: 166.15,86.29 164.95,87.5 160,87.5 157.92,89.58 157.92,89.62 157.64,89.9 157.64,90.9 157.81,91.08 157.81,91.94 v1(158.25,92.37)
  IN1 w0.099: v1(228.58,44.49) 227.61,44.49 227.52,44.59 227.52,49.4 226,50.91 202.94,50.91 194.39,59.46 192.9,59.46 182.83,69.53 181.31,69.53 180.15,70.69 176.68,70.69 176.07,71.3 173.96,71.3 172.83,72.43 172.05,72.43 170.86,73.62 170.86,73.75 170.31,74.3 170.12,74.3 169.22,75.2 169.22,79.96 168.36,80.82 168.36,83.71 166.16,85.91 166.15,85.91 166.15,86.29
  BOTTOM w0.089: UC1.AR29 v1(158.25,92.37)
  BOTTOM w0.107: v1(228.58,44.49) 229.1,43.97 JDIMM2.194
DDR_B_D30: length 102
  IN1 w0.089: 169.4,83.46 169.4,83.46 169.4,84.14 167.65,85.89 167.65,87.48 167.01,88.12 166.33,88.12 165.7,88.74 161.2,88.74 160.52,89.42 160.52,89.7 160.23,89.99 160.07,90.15 v1(160.07,90.46)
  IN1 w0.099: 169.4,83.46 169.4,81.32 170.87,79.85 170.87,79.61 172.27,78.22 172.27,76.71 174.25,74.72 174.64,74.59 175.81,74.59 177.22,73.19 180.76,73.19 181.71,72.23 183.12,72.23 189.8,65.55 189.94,65.55 190.55,66.16 190.69,66.16 190.83,66.02 190.83,65.88 190.22,65.27 190.22,65.13 190.38,64.97 191.88,64.97 203.06,53.79 226.92,53.79 228.46,52.25 228.46,51.67 230.77,49.36 230.77,45.21 231.36,44.62 v1(231.91,44.62)
  BOTTOM w0.089: UC1.AV32 v1(160.07,90.46)
  BOTTOM w0.107: JDIMM2.208 232.6,42.81 232.6,43.92 v1(231.91,44.62)
DDR_B_D31: length 102.5
  IN1 w0.076: v1(160.07,91.1) 160.07,91.01 160.5,90.58 160.5,89.94 160.7,89.74
  IN1 w0.089: 169.58,83.41 169.58,84.2 167.88,85.9 167.88,87.51 167.06,88.32 166.4,88.32 165.77,88.95 161.25,88.95 160.7,89.49 160.7,89.74
  IN1 w0.099: 169.58,83.41 169.58,81.39 171.12,79.85 171.12,79.8 172.57,78.34 172.57,76.83 174.42,74.99 174.69,74.89 175.94,74.89 177.34,73.49 180.88,73.49 181.84,72.53 183.25,72.53 188.95,66.82 189.09,66.82 189.62,67.35 189.76,67.35 189.9,67.21 189.9,67.07 189.41,66.58 189.41,66.44 189.55,66.3 189.69,66.3 190.27,66.87 190.41,66.87 203.18,54.1 227.12,54.1 228.84,52.38 228.84,51.72 231.07,49.49 231.07,46.97 v1(231.91,46.14)
  BOTTOM w0.089: UC1.AV31 v1(160.07,91.1)
  BOTTOM w0.107: v1(231.91,46.14) 231.45,45.69 231.45,43.81 231.6,43.66 JDIMM2.204
DDR_B_D32: length 68.3
  IN1 w0.089: v1(162.63,83.49) 163.55,82.57 163.55,78.65
  IN1 w0.099: v1(190.68,44.51) 191.48,44.51 191.57,44.61 191.57,44.89 191.67,44.99 192.16,44.99 192.26,45.09 192.26,45.29 192.16,45.39 191.67,45.39 191.57,45.49 191.57,45.69 191.67,45.79 192.22,45.79 192.31,45.88 192.31,46.08 192.22,46.18 191.67,46.18 191.57,46.28 191.57,50.91 179.33,63.15 175.69,63.15 174.48,64.37 174.1,64.37 173.47,65 166.42,65 163.95,67.46 163.95,73.92 163.55,74.32 163.55,78.65
  BOTTOM w0.076: 162.42,86.42 162.42,86.52 162.66,86.75 162.66,87.78 162.61,87.89 162.61,88.13 162.66,88.24 162.66,88.43 162.49,88.89 UC1.BA35
  BOTTOM w0.089: 162.42,86.42 162.42,83.7 v1(162.63,83.49)
  BOTTOM w0.107: v1(190.68,44.51) 191.1,44.09 JDIMM2.50
DDR_B_D33: length 68.7
  IN1 w0.089: v1(162.63,80.95) 162.99,80.59 162.99,80.16
  IN1 w0.099: v1(190.68,47.56) 190.68,47.66 190.21,48.13 190.21,49.43 189.75,49.88 189.75,50.02 189.99,50.26 189.99,50.4 188.38,52.01 188.38,52.5 179.78,61.1 179.64,61.1 179.01,60.47 178.87,60.47 177.45,61.88 175.68,61.88 174.1,63.46 167.78,63.46 167.68,63.56 167.68,63.93 167.58,64.03 167.39,64.03 167.29,63.93 167.29,63.56 167.19,63.46 166.67,63.46 163.05,67.09 163.05,73.94 163.01,73.97 163.01,74.27 162.91,74.37 162.41,74.37 162.31,74.46 162.31,74.66 162.41,74.76 162.91,74.76 163.01,74.86 163.01,75.06 162.91,75.16 162.41,75.16 162.31,75.26 162.31,75.45 162.41,75.55 162.89,75.55 162.99,75.65 162.99,80.16
  BOTTOM w0.076: 161.88,86.57 161.88,86.67 162.16,86.95 162.16,87.27 161.96,87.46 161.96,87.84 162.08,88.04 162.08,88.99 162.32,89.48 UC1.BA34
  BOTTOM w0.089: 161.88,86.57 161.88,81.69 v1(162.63,80.95)
  BOTTOM w0.107: JDIMM2.45 189.85,47.67 189.96,47.56 v1(190.68,47.56)
DDR_B_D34: length 69.1
  IN1 w0.099: v1(164.29,78.72) 164.29,74.6 165.13,73.76 165.13,67.95 166.16,66.92 169.73,66.92 170.48,66.18 173.96,66.18 174.59,65.55 174.97,65.55 176.18,64.33 179.82,64.33 190.8,53.35 191.44,53.35 192.18,52.6 192.18,51.98 192.76,51.4 192.76,49.83 192.86,49.73 193.21,49.73 193.3,49.63 193.3,49.43 193.21,49.33 192.86,49.33 192.76,49.23 192.76,49.01 193.3,48.46 193.3,44.71 193.4,44.62 v1(194.43,44.62)
  BOTTOM w0.076: v1(164.29,78.72) 164.95,79.38 164.95,80.48 165.03,80.57 165.03,84.06 164.09,85 164.09,86.78 163.92,86.95 163.92,87.27 164.12,87.46 164.12,87.84 164.01,88.04 164.01,88.67 UC1.BC35
  BOTTOM w0.107: v1(194.43,44.62) 193.53,44.62 193.1,44.19 JDIMM2.58
DDR_B_D35: length 69.1
  IN1 w0.099: v1(164.29,81.26) 165.21,80.34 165.21,78.71 ; v1(194.43,49.19) 194.43,51.22 193.78,51.87 193.78,52.44 190.57,55.65 189.78,55.65 180.2,65.24 176.58,65.24 175.95,65.86 175.94,65.86 175.34,66.45 174.96,66.45 174.33,67.09 171.21,67.09 171.04,67.26 170.07,68.22 168.73,68.22 168.39,68.56 168.25,68.56 167.52,67.83 167.38,67.83 167.24,67.97 167.24,68.11 167.97,68.84 167.97,68.98 167.83,69.12 167.69,69.12 166.71,68.14 166.57,68.14 166.43,68.28 166.43,68.42 167.41,69.4 167.41,69.54 167.27,69.68 167.13,69.68 166.46,69.01 166.32,69.01 166.18,69.16 166.18,69.29 166.85,69.96 166.85,70.1 166.62,70.34 166.62,73.72
  IN1 w0.102: 165.21,78.71 165.21,75.6 166.62,74.19 166.62,73.72
  BOTTOM w0.076: UC1.BC34 162.96,89.63 162.8,89.48 162.73,89.41 162.73,88.7 162.82,88.45 162.82,88.21 162.78,88.1 162.78,87.93 162.82,87.82 162.82,86.69 162.6,86.46 162.6,86.36
  BOTTOM w0.089: v1(164.29,81.26) 163.13,82.42 163.13,83.64 162.6,84.17 162.6,86.36
  BOTTOM w0.107: JDIMM2.63 194.35,49.98 194.43,49.9 v1(194.43,49.19)
DDR_B_D36: length 67.4
  IN1 w0.089: v1(162.63,82.22) 163.37,81.48 163.37,78.29
  IN1 w0.099: 163.37,78.29 163.37,74.25 163.65,73.97 163.65,67.34 166.29,64.7 173.34,64.7 173.97,64.06 174.35,64.06 175.57,62.85 178.06,62.85 178.48,62.43 178.62,62.43 179.04,62.85 179.21,62.85 179.43,62.62 179.43,62.48 178.82,61.86 178.82,61.72 179.04,61.5 179.18,61.5 179.8,62.11 179.94,62.11 190.7,51.35 190.7,50.88 190.8,50.79 191.01,50.79 191.11,50.69 191.11,50.49 191.01,50.39 190.8,50.39 190.7,50.29 190.7,49.96 190.8,49.86 191.17,49.86 191.27,49.76 191.27,46.13 191.17,46.04 v1(190.68,46.04)
  BOTTOM w0.076: 162.24,86.47 162.24,86.57 162.49,86.82 162.49,87.59 UC1.BA37
  BOTTOM w0.089: 162.24,86.47 162.24,82.61 v1(162.63,82.22)
  BOTTOM w0.107: JDIMM2.46 190.1,43.81 190.21,43.92 190.21,45.57 v1(190.68,46.04)
DDR_B_D37: length 68
  IN1 w0.099: v1(162.63,81.59) 163.02,81.59 163.19,81.42 163.19,74.05 163.35,73.89 163.35,67.21 166.22,64.34 167.98,64.34 168.08,64.24 168.08,63.86 168.18,63.76 168.38,63.76 168.48,63.86 168.48,64.24 168.58,64.34 168.78,64.34 168.88,64.24 168.88,63.86 168.97,63.76 169.17,63.76 169.27,63.86 169.27,64.24 169.37,64.34 169.57,64.34 169.67,64.24 169.67,63.86 169.77,63.76 169.96,63.76 170.06,63.86 170.06,64.24 170.16,64.34 170.36,64.34 170.46,64.24 170.46,63.86 170.56,63.76 170.76,63.76 170.86,63.86 170.86,64.24 170.96,64.34 172.45,64.34 172.55,64.24 172.55,63.86 172.65,63.76 172.85,63.76 172.95,63.86 172.95,64.24 173.05,64.34 173.27,64.34 173.85,63.76 174.22,63.76 175.44,62.54 177.94,62.54 178.49,61.99 178.49,61.62 179.04,61.07 179.18,61.07 179.64,61.53 179.78,61.53 188.7,52.61 188.7,52.12 189.75,51.07 189.89,51.07 189.99,51.18 190.13,51.18 190.27,51.04 190.27,50.9 190.17,50.79 190.17,50.65 190.29,50.52 190.29,49.79 190.68,49.41 v1(190.68,49.08)
  BOTTOM w0.076: 162.06,86.52 162.06,86.62 162.32,86.88 162.32,87.33 162.13,87.53 162.13,87.8 162.39,88.28 UC1.BA36
  BOTTOM w0.089: 162.06,86.52 162.06,82.15 v1(162.63,81.59)
  BOTTOM w0.107: JDIMM2.49 190.85,49.86 191.82,48.89 191.82,48.67 191.44,48.3 191.29,48.3 190.68,48.91 v1(190.68,49.08)
DDR_B_D38: length 68
  IN1 w0.099: v1(164.29,79.99) 164.75,79.52 164.75,74.59 165.44,73.91 165.44,68.12 166.33,67.22 169.86,67.22 170.6,66.48 174.08,66.48 174.71,65.85 175.09,65.85 176.31,64.63 179.95,64.63 190.93,53.65 191.56,53.65 192.49,52.73 192.49,52.1 193.06,51.53 193.06,50.36 193.61,49.81 193.61,47.03 193.71,46.93 193.93,46.93 194.03,46.83 194.03,46.63 193.93,46.53 193.71,46.53 193.61,46.43 193.61,45.73 193.68,45.66 194.14,45.66 194.43,45.95 v1(194.43,46.14)
  BOTTOM w0.076: v1(164.29,79.99) 164.72,80.42 164.72,80.66 164.85,80.79 164.85,84.01 163.93,84.93 163.93,86.72 163.76,86.88 163.76,87.33 163.96,87.53 163.96,87.8 163.69,88.28 UC1.BC36
  BOTTOM w0.107: JDIMM2.62 194.1,43.67 194.86,44.43 194.86,45.72 v1(194.43,46.14)
DDR_B_D39: length 67.1
  IN1 w0.099: v1(164.29,80.63) 164.98,79.93 164.98,74.67 165.74,73.91 165.74,68.25 166.46,67.53 169.98,67.53 170.73,66.78 174.21,66.78 174.84,66.15 175.22,66.15 176.43,64.93 180.07,64.93 189.91,55.1 190.05,55.1 190.3,55.35 190.44,55.35 190.58,55.21 190.58,55.07 190.33,54.82 190.33,54.68 190.47,54.54 190.61,54.54 190.86,54.79 191,54.79 191.14,54.65 191.14,54.51 190.89,54.26 190.89,54.12 191.05,53.96 191.84,53.96 193.36,52.43 193.36,51.31 193.46,51.21 194.02,51.21 194.12,51.11 194.12,50.91 194.02,50.81 193.46,50.81 193.36,50.71 193.36,50.49 193.5,50.34 193.84,50.34 193.94,50.24 193.94,48.15 v1(194.43,47.66)
  BOTTOM w0.076: v1(164.29,80.63) 164.67,81.01 164.67,83.95 163.76,84.86 163.76,86.65 163.6,86.82 163.6,87.59 UC1.BC37
  BOTTOM w0.107: JDIMM2.59 193.35,50.06 193.84,49.57 193.84,48.94 194.02,48.76 194.02,48.07 v1(194.43,47.66)
DDR_B_D40: length 66.9
  IN1 w0.099: v1(199.78,47.57) 199.2,48.15 199.2,52.64 196.61,55.23 196.47,55.23 196.23,54.99 196.09,54.99 195.95,55.13 195.95,55.27 196.19,55.51 196.19,55.65 196.05,55.79 195.91,55.79 195.67,55.55 195.53,55.55 182.46,68.62 180.43,68.62 179.27,69.78 176.3,69.78 175.7,70.39 173.58,70.39 172.45,71.52 171.67,71.52 170.32,72.88 170.32,73.45 168.74,75.03 168.74,79.94 168.01,80.67 168.01,83.57 166.48,85.1 v1(165.77,85.1)
  BOTTOM w0.076: UC1.BE35 165.01,88.89 165.17,88.43 165.17,88.24 165.13,88.13 165.13,87.89 165.17,87.78 165.17,86.75 165.02,86.6 165.02,85.8 165.66,85.16 v1(165.77,85.1)
  BOTTOM w0.107: v1(199.78,47.57) 199.21,47.57 198.35,48.43 JDIMM2.79
DDR_B_D41: length 66.9
  IN1 w0.099: v1(196.08,44.55) 196.07,44.54 195.14,44.54 195.04,44.64 195.04,44.92 195.14,45.01 195.29,45.01 195.38,45.11 195.38,45.31 195.29,45.41 195.14,45.41 195.04,45.51 195.04,51.47 194.39,52.12 194.39,52.69 190.82,56.26 190.03,56.26 180.45,65.84 177,65.84 175.78,67.06 175.22,67.06 174.58,67.69 171.46,67.69 170.32,68.83 168.98,68.83 167.25,70.56 167.25,72.46 166.94,72.78 166.94,74.24 165.54,75.63 165.54,82.1 v1(165.95,82.51)
  BOTTOM w0.076: UC1.BE34 164.83,89.48 164.62,89.03 164.62,88.09 164.48,87.84 164.48,87.46 164.68,87.27 164.68,86.95 164.52,86.79 164.52,84.89 165.39,84.03 165.39,83.18 v1(165.95,82.51)
  BOTTOM w0.107: v1(196.08,44.55) 196.1,44.53 JDIMM2.70
DDR_B_D42: length 67.7
  IN1 w0.099: v1(167.26,83.55) 167.66,83.15 167.66,80.53 168.36,79.82 168.36,74.85 169.92,73.29 169.92,72.42 171.42,70.92 172.2,70.92 173.33,69.79 175.45,69.79 176.05,69.18 177.97,69.18 179.22,67.93 182.29,67.93 196.35,53.87 197.11,53.87 198.59,52.39 198.59,46.47 197.97,45.85 197.97,44.62 198.07,44.52 198.46,44.52 198.56,44.62 198.56,44.93 198.66,45.03 198.86,45.03 198.96,44.93 198.96,44.62 199.06,44.52 v1(199.78,44.52)
  BOTTOM w0.076: v1(167.26,83.55) 166.98,83.83 166.98,85.77 166.74,86.01 166.74,86.65 166.44,86.95 166.44,87.27 166.64,87.46 166.64,87.84 166.53,88.04 166.53,88.67 UC1.BG35
  BOTTOM w0.107: JDIMM2.84 199.6,44.34 v1(199.78,44.52)
DDR_B_D43: length 67.7
  IN1 w0.099: v1(199.78,49.09) 199.5,49.37 199.5,52.9 195.79,56.61 195.65,56.61 195.34,56.31 195.2,56.31 195.06,56.45 195.06,56.59 195.37,56.89 195.37,57.04 195.23,57.18 195.09,57.18 194.78,56.87 194.64,56.87 194.5,57.01 194.5,57.15 194.81,57.46 194.81,57.6 194.67,57.74 194.53,57.74 194.22,57.43 194.08,57.43 193.94,57.57 193.94,57.71 194.25,58.02 194.25,58.16 194.11,58.3 193.97,58.3 193.66,57.99 193.52,57.99 193.38,58.13 193.38,58.27 193.69,58.58 193.69,58.72 193.55,58.86 193.41,58.86 193.1,58.55 192.96,58.55 182.58,68.93 181.06,68.93 179.9,70.09 176.43,70.09 175.82,70.69 173.71,70.69 172.58,71.82 171.8,71.82 170.49,73.13 170.49,73.61 168.94,75.16 168.94,79.99 168.18,80.74 168.18,83.64 166.09,85.74 v1(165.7,85.74)
  BOTTOM w0.076: UC1.BG34 165.47,89.63 165.44,89.6 165.26,89.42 165.26,88.66 165.34,88.45 165.34,88.21 165.29,88.1 165.29,87.92 165.34,87.8 165.34,86.69 165.18,86.53 165.18,86.22 165.33,86.07 165.64,85.76 v1(165.7,85.74)
  BOTTOM w0.107: JDIMM2.83 199.35,49.52 v1(199.78,49.09)
DDR_B_D44: length 66
  IN1 w0.099: v1(199.78,46.05) 198.9,46.93 198.9,52.51 197.24,54.17 196.48,54.17 182.33,68.32 179.72,68.32 178.55,69.48 176.18,69.48 175.57,70.09 173.46,70.09 172.33,71.22 171.55,71.22 170.14,72.63 170.14,73.32 169.47,73.99 169.47,73.99 168.56,74.89 168.56,79.87 167.83,80.6 167.83,83.49 166.87,84.46 v1(165.93,84.46)
  BOTTOM w0.076: v1(165.93,84.46) 164.85,85.33 164.85,86.66 165,86.82 165,87.59 UC1.BE37
  BOTTOM w0.107: JDIMM2.80 198.6,43.72 198.73,43.85 198.73,45.7 199.08,46.05 v1(199.78,46.05)
DDR_B_D45: length 66.2
  IN1 w0.099: v1(165.95,83.14) 166.38,82.72 166.38,75.18 167.19,74.36 167.19,72.97 167.7,72.46 167.7,70.54 169.11,69.13 170.45,69.13 171.58,68 174.71,68 175.34,67.36 175.9,67.36 177.12,66.14 180.58,66.14 189.58,57.14 189.72,57.14 190.07,57.49 190.21,57.49 190.35,57.35 190.35,57.21 190,56.86 190,56.72 190.16,56.56 191.14,56.56 195.34,52.36 195.34,46.18 195.44,46.08 v1(196.08,46.08)
  BOTTOM w0.076: UC1.BE36 164.91,88.28 164.64,87.8 164.64,87.53 164.84,87.33 164.84,86.88 164.69,86.73 164.69,84.96 165.56,84.08 165.56,83.64 v1(165.95,83.14)
  BOTTOM w0.107: v1(196.08,46.08) 195.49,45.49 195.49,44.1 195.1,43.71 JDIMM2.66
DDR_B_D46: length 66.9
  IN1 w0.099: v1(167.26,82.28) 166.63,81.66 166.63,75.17 168.46,73.34 168.46,70.7 168.66,70.5 168.66,70.5 169.73,69.43 170.57,69.43 171.71,68.3 174.84,68.3 175.47,67.67 176.03,67.67 177.25,66.45 180.7,66.45 188.21,58.94 188.35,58.94 188.7,59.28 188.84,59.28 188.98,59.14 188.98,59 188.63,58.65 188.63,58.52 188.77,58.37 188.91,58.37 189.26,58.72 189.4,58.72 189.54,58.58 189.54,58.44 189.19,58.09 189.19,57.95 189.35,57.79 190.33,57.79 195.64,52.48 195.64,51.83 195.74,51.73 196.4,51.73 196.5,51.63 196.5,51.43 196.4,51.33 195.74,51.33 195.64,51.23 195.64,51.03 195.74,50.93 196.43,50.93 196.53,50.83 196.53,50.64 196.43,50.54 195.74,50.54 195.64,50.44 195.64,50.24 195.74,50.14 196.43,50.14 196.53,50.04 196.53,49.84 196.43,49.75 195.74,49.75 195.64,49.65 195.64,49.22 195.74,49.12 v1(196.08,49.12)
  BOTTOM w0.076: v1(167.26,82.28) 166.81,82.73 166.81,85.7 166.57,85.93 166.57,86.59 166.28,86.88 166.28,87.33 166.47,87.53 166.47,87.8 166.21,88.28 UC1.BG36
  BOTTOM w0.107: JDIMM2.67 195.35,49.52 195.75,49.12 v1(196.08,49.12)
DDR_B_D47: length 66.3
  IN1 w0.099: v1(167.26,81.65) 166.88,81.28 166.88,75.34 168.78,73.45 168.78,70.81 169.86,69.74 171.71,69.74 172.84,68.6 174.96,68.6 175.56,68 176.16,68 177.41,66.75 181.8,66.75 187.02,61.53 187.02,61.39 186.67,61.04 186.67,60.9 186.81,60.76 186.95,60.76 187.3,61.11 187.44,61.11 187.58,60.97 187.58,60.83 187.23,60.48 187.23,60.34 187.38,60.2 187.52,60.2 187.86,60.55 188,60.55 188.14,60.41 188.14,60.27 187.8,59.92 187.8,59.78 187.94,59.64 188.08,59.64 188.42,59.99 188.56,59.99 196.83,51.73 196.83,47.7 196.73,47.6 v1(196.08,47.6)
  BOTTOM w0.076: v1(167.26,81.65) 166.64,82.26 166.64,85.62 166.41,85.85 166.41,86.52 166.11,86.82 166.11,87.59 UC1.BG37
  BOTTOM w0.107: v1(196.08,47.6) 196.26,47.6 196.51,47.85 196.51,49.89 196.35,50.05 JDIMM2.71
DDR_B_D48: length 99.7
  IN3 w0.097: v1(233.81,45.95) 233.97,45.79 234.41,45.79 234.5,45.89 234.5,46.63 234.21,46.92 234.21,49.16 233.98,49.4 233.24,49.4 230.65,51.99 230.65,52.75 229.09,54.31 228.95,54.31 228.64,54.01 228.51,54.01 224.28,58.24 222.87,58.24 214.77,66.34 213.49,66.34 211.59,68.24 186.71,68.24 184.41,68.24 177.51,75.15 177.03,75.62 176.62,75.62 175.72,76.53 174.83,76.53 169.98,81.37 169.98,82.9 167.14,85.74 167.14,86.44 166.14,87.44 165.97,87.44 164.95,88.47 163.74,88.47 161.89,90.31 v1(161.89,90.51)
  BOTTOM w0.089: v1(161.89,90.51) 161.96,90.49 UC1.BA32
  BOTTOM w0.107: JDIMM2.216 234.6,42.81 234.6,45.16 v1(233.81,45.95)
DDR_B_D49: length 100
  IN3 w0.089: 162.19,89.62 161.51,90.3 161.51,90.71 v1(161.89,91.1)
  IN3 w0.097: 162.19,89.62 162.34,89.62 163.67,88.29 164.87,88.29 165.9,87.27 166.07,87.27 166.97,86.37 166.97,85.67 169.73,82.91 169.73,81.2 174.7,76.23 175.44,76.23 176.34,75.32 176.78,75.32 184.16,67.94 185.12,67.94 211.47,67.94 213.37,66.04 214.64,66.04 222.76,57.92 224.17,57.92 228.51,53.58 228.64,53.58 228.95,53.89 229.09,53.89 229.22,53.75 229.22,53.62 228.92,53.31 228.92,53.17 229.05,53.04 229.19,53.04 229.5,53.34 229.63,53.34 229.77,53.21 229.77,53.07 229.46,52.77 229.46,52.63 229.6,52.49 229.74,52.49 230.04,52.8 230.18,52.8 230.32,52.66 230.32,52.53 230.01,52.22 230.01,52.08 232.69,49.4 232.69,47.9 232.77,47.83 233.18,47.83 233.28,47.92 233.28,48.9 233.37,49 v1(233.81,49)
  BOTTOM w0.089: UC1.BA31 v1(161.89,91.1)
  BOTTOM w0.107: v1(233.81,49) 234.35,49.54 JDIMM2.215
DDR_B_D50: length 102.5
  IN3 w0.089: 179.93,77 177.5,79.43 177.5,80.77 176.15,82.12 176.15,82.12 175.97,82.31 173.31,82.31 172.53,83.09 171.03,83.09 168,86.12 168,87.68 167.39,88.29 166.32,88.29 165.28,89.33 165.19,89.33 164.14,90.38 164.14,90.57 163.92,90.79 163.92,90.89 v1(163.71,91.1)
  IN3 w0.097: v1(237.57,46.27) 237.26,46.27 237.17,46.17 237.17,45.51 237.07,45.41 236.8,45.41 236.69,45.53 236.69,49.07 236.69,49.32 229.92,56.09 228.94,56.09 225,60.03 223.59,60.03 215.5,68.12 214.23,68.12 212.33,70.02 185.98,70.02 180.85,75.15 180.66,75.34 180.66,76.27 179.93,77
  BOTTOM w0.089: UC1.BD31 v1(163.71,91.1)
  BOTTOM w0.107: JDIMM2.224 236.6,42.81 236.6,45.3 v1(237.57,46.27)
DDR_B_D51: length 102.2
  IN3 w0.089: v1(163.72,90.46) 163.82,90.46 165.12,89.16 165.22,89.16 166.25,88.13 167.32,88.13 167.84,87.62 167.84,86.06 171.02,82.88 172.51,82.88 173.33,82.05 175.99,82.05 175.99,82.05 177.33,80.71 177.33,79.15 179.49,77 179.51,77
  IN3 w0.097: v1(237.57,44.74) 237.57,44.49 237.47,44.4 235.96,44.4 235.52,44.84 235.52,45.44 235.61,45.54 236.29,45.54 236.39,45.64 236.39,49.19 229.79,55.79 228.81,55.79 224.88,59.73 223.47,59.73 215.38,67.82 214.11,67.82 212.21,69.72 186.1,69.72 185.85,69.72 180.72,74.85 180.72,74.85 180.36,75.22 180.36,76.15 179.51,77
  BOTTOM w0.089: UC1.BD32 v1(163.72,90.46)
  BOTTOM w0.107: JDIMM2.228 237.6,42.81 237.6,44.71 v1(237.57,44.74)
DDR_B_D52: length 101.2
  IN3 w0.089: 173.51,77 169.48,81.03 169.48,82.93 166.75,85.66 166.75,86.35 166,87.1 165.83,87.1 164.8,88.12 162.45,88.12 161.33,89.25 161.33,90.91 161.42,91.01 161.42,91.27 v1(161.89,91.73)
  IN3 w0.097: 173.51,77 174.58,75.93 175.32,75.93 176.24,75 176.59,75 183.95,67.64 184.99,67.64 184.99,67.64 186.96,67.64 186.96,67.64 211.35,67.64 213.25,65.74 214.52,65.74 222.66,57.6 224.06,57.6 232.39,49.28 232.39,46.4 232.49,46.3 233.05,46.3 233.15,46.4 233.15,46.81 v1(233.81,47.47)
  BOTTOM w0.089: UC1.BA30 v1(161.89,91.73)
  BOTTOM w0.107: v1(233.81,47.47) 233.35,47.93 JDIMM2.211
DDR_B_D53: length 101.8
  IN3 w0.097: v1(233.81,44.43) 234.71,44.43 234.8,44.52 234.8,46.75 234.51,47.04 234.51,49.35 234.1,49.76 233.37,49.76 230.95,52.18 230.95,52.87 229.21,54.61 228.33,54.61 224.39,58.55 223.39,58.55 222.98,58.55 214.89,66.64 213.62,66.64 211.72,68.54 186.59,68.54 186.59,68.54 185.36,68.54 181.68,72.22 180.23,73.67 179.16,74.75 179.16,74.85 177.71,76.3 176.37,76.3 175.67,77 174.6,77 170.24,81.36 170.24,82.89 167.32,85.82 167.32,87.32 167.02,87.62 166.04,87.62 165.01,88.65 164.01,88.65 162.34,90.32 162.34,91.92 v1(161.89,92.37)
  BOTTOM w0.089: UC1.BA29 v1(161.89,92.37)
  BOTTOM w0.107: v1(233.81,44.43) 233.6,44.22 JDIMM2.212
DDR_B_D54: length 103.3
  IN3 w0.089: 180.5,77.32 177.83,79.99 177.83,80.95 176.14,82.64 173.45,82.64 171.98,84.11 170.48,84.11 168.33,86.26 168.33,87.83 167.54,88.62 166.46,88.62 165.42,89.66 165.33,89.66 164.83,90.16 164.83,90.39 164.26,90.95 164.26,91.82 v1(163.71,92.37)
  IN3 w0.097: v1(237.57,49.31) 227.92,58.96 227.78,58.96 227.42,58.6 227.28,58.6 227.15,58.73 227.15,58.93 227.55,59.34 227.55,59.48 227.41,59.61 227.28,59.61 226.84,59.18 226.7,59.18 226.6,59.28 226.6,59.42 226.88,59.69 226.88,59.83 226.66,60.04 226.53,60.04 226.35,59.87 226.21,59.87 225.32,60.76 225.11,60.76 224.98,60.63 224.48,60.63 224.38,60.73 224.38,60.86 224.47,60.95 224.47,61.1 224.33,61.24 224.19,61.24 223.87,60.92 223.74,60.92 223.64,61.01 223.64,61.15 223.94,61.45 223.94,61.62 223.84,61.72 223.67,61.72 223.38,61.43 223.19,61.43 223.17,61.44 223.01,61.6 223.01,61.74 223.38,62.11 223.38,62.24 223.25,62.38 223.11,62.38 222.74,62.01 222.6,62.01 222.47,62.15 222.47,62.28 222.84,62.65 222.84,62.79 222.7,62.93 222.56,62.93 222.19,62.56 222.06,62.56 215.89,68.72 214.48,68.72 212.58,70.62 186.31,70.62 183.19,73.74 183.19,74.5 181.29,76.4 181.29,76.53 180.5,77.32
  BOTTOM w0.089: UC1.BD29 v1(163.71,92.37)
  BOTTOM w0.107: v1(237.57,49.31) 237.57,49.83 237.85,50.11 JDIMM2.229
DDR_B_D55: length 103.1
  IN3 w0.089: v1(163.71,91.73) 164.09,91.36 164.09,90.86 164.31,90.64 164.31,90.45 165.26,89.49 165.35,89.49 166.39,88.46 167.46,88.46 168.17,87.75 168.17,86.19 171.1,83.26 172.6,83.26 173.38,82.47 176.04,82.47 176.32,82.19 176.32,82.19 177.66,80.84 177.66,79.69 180.35,77
  IN3 w0.097: 180.35,77 180.97,76.38 180.97,75.45 186.1,70.32 212.46,70.32 214.35,68.42 215.63,68.42 223.72,60.33 225.12,60.33 227.4,58.05 227.54,58.05 227.9,58.42 228.04,58.42 228.18,58.28 228.18,58.14 227.81,57.78 227.81,57.64 227.95,57.51 228.09,57.51 228.45,57.87 228.59,57.87 228.72,57.74 228.72,57.6 228.36,57.23 228.36,57.1 228.5,56.96 228.63,56.96 229,57.33 229.13,57.33 229.27,57.19 229.27,57.05 228.91,56.69 228.91,56.55 229.06,56.39 230.04,56.39 237.09,49.35 237.09,47.89 237.18,47.79 v1(237.57,47.79)
  BOTTOM w0.089: UC1.BD30 v1(163.71,91.73)
  BOTTOM w0.107: v1(237.57,47.79) 236.83,48.53 236.83,50.11 236.85,50.13 JDIMM2.225
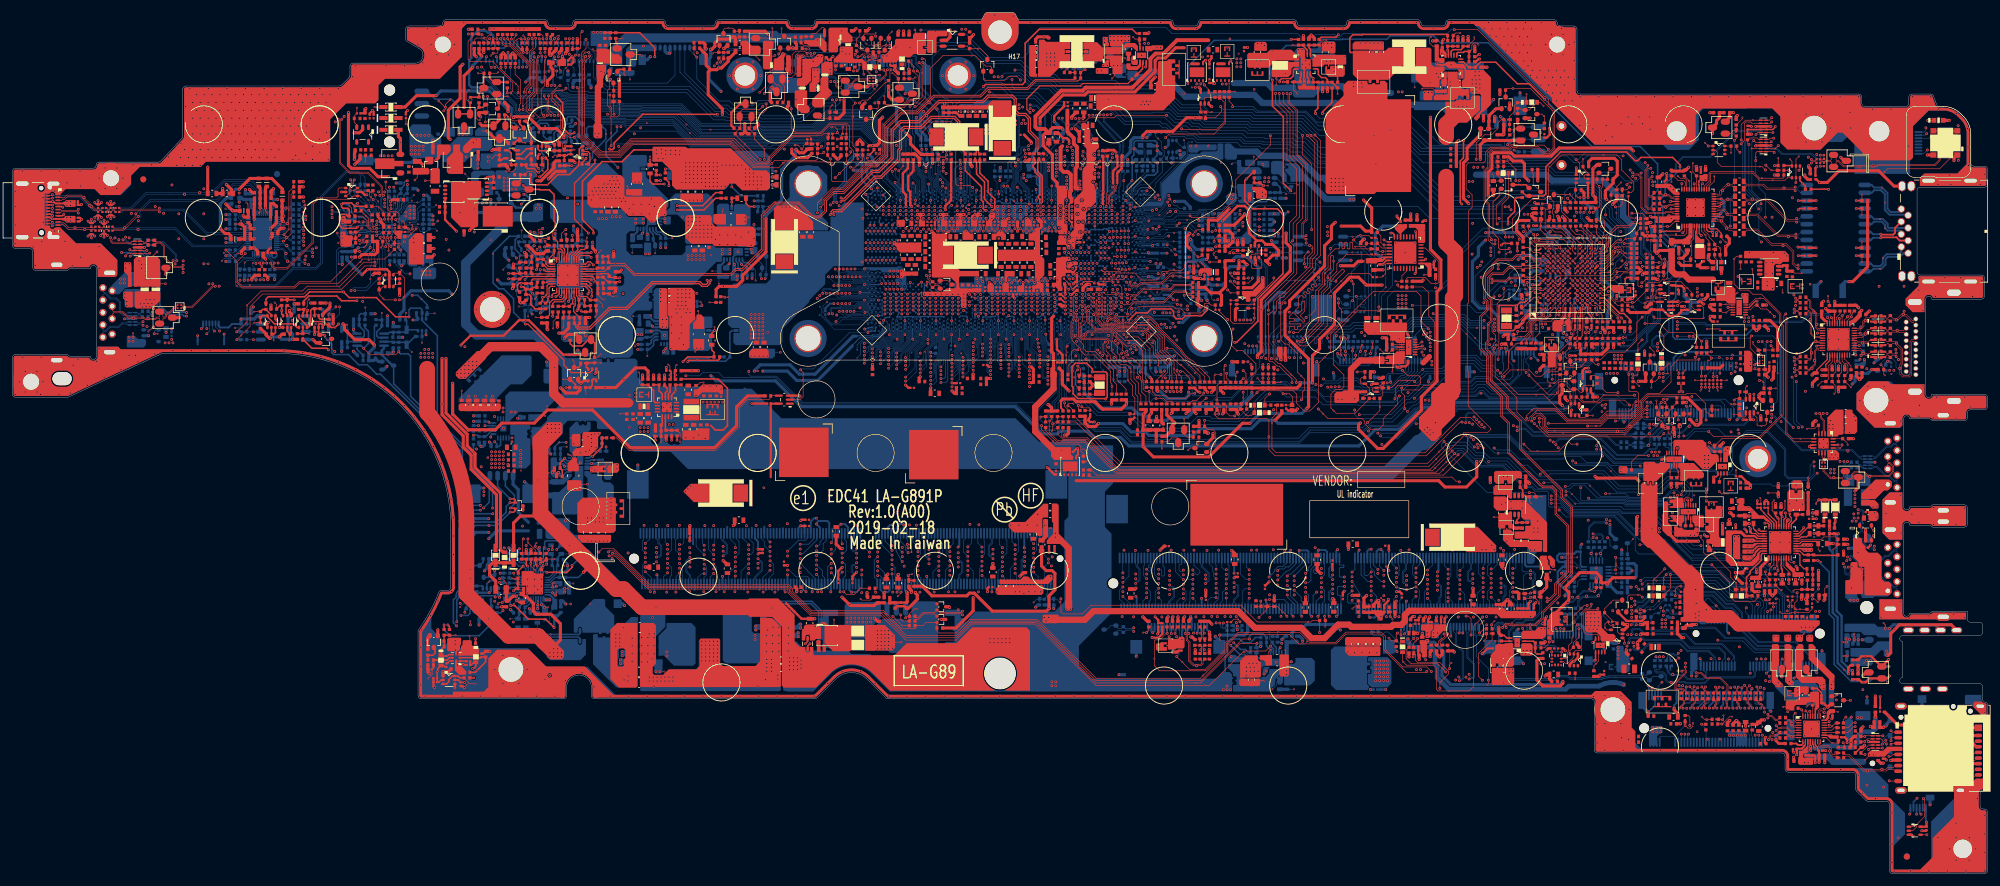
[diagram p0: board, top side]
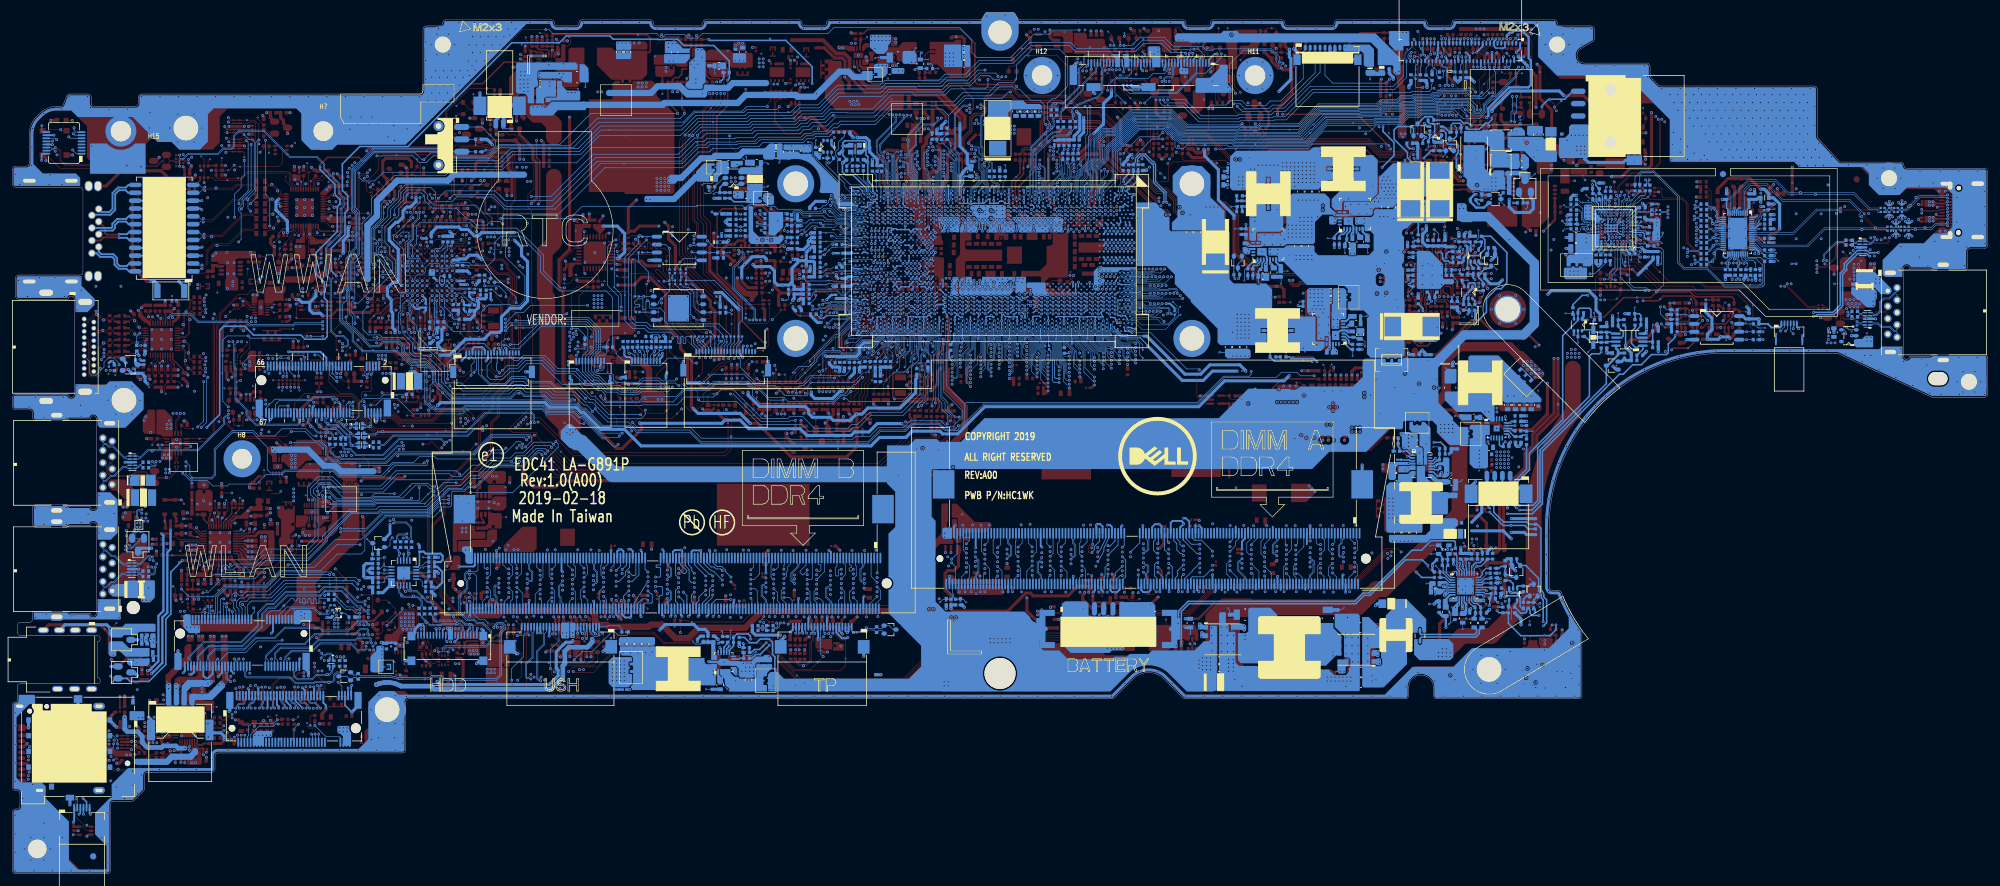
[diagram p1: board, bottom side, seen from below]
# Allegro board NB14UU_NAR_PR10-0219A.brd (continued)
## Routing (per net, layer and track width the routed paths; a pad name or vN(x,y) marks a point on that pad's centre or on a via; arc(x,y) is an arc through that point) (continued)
DDR_B_D56: length 103.1
  IN3 w0.089: v1(165.54,91.1) 165.16,90.72 165.16,90.3 165.47,89.99 165.56,89.99 166.59,88.95 167.72,88.95 168.66,88.01 169.19,88.01 169.86,87.34 169.86,86.79 171.2,85.45 171.96,85.45 174.45,82.97 176.27,82.97 178.16,81.09 178.16,80.55 180.94,77.77 181.37,77.77 182.14,77
  IN3 w0.097: 182.14,77 184.71,74.43 184.85,74.43 187.05,72.23 194.36,72.23 195.01,71.58 212.9,71.58 214.85,69.62 216.33,69.62 222.12,63.83 223.08,63.83 225.24,61.67 226.67,61.67 226.82,61.52 226.82,61.38 226.65,61.21 226.65,61.05 226.74,60.95 226.93,60.95 227.09,61.11 227.23,61.11 232.21,56.12 233.44,54.9 233.57,54.9 234.03,55.36 234.17,55.36 234.31,55.22 234.31,55.08 233.85,54.63 233.85,54.49 233.98,54.35 234.12,54.35 234.58,54.81 234.72,54.81 234.85,54.68 234.85,54.54 234.39,54.08 234.39,53.94 234.53,53.81 234.67,53.81 235.13,54.27 235.26,54.27 236.39,53.14 236.39,51.95 238.36,49.98 238.36,47.82 238.45,47.73 v1(238.86,47.73)
  BOTTOM w0.089: UC1.BG31 v1(165.54,91.1)
  BOTTOM w0.107: JDIMM2.233 238.85,50.28 238.27,49.7 238.27,48.32 v1(238.86,47.73)
DDR_B_D57: length 102.8
  IN3 w0.089: v1(165.55,90.47) 165.54,90.24 166.66,89.12 167.81,89.12 168.75,88.17 169.26,88.17 171,86.43 171.02,86.43 171.06,86.4 172.06,86.4 172.76,85.69 172.76,84.89 174.52,83.13 176.34,83.13 178.32,81.15 178.32,80.77 181.03,78.05 181.51,78.05 182.56,77
  IN3 w0.097: v1(238.86,49.25) 238.86,49.89 238.66,50.1 238.66,50.11 237.11,51.66 237.1,51.66 236.69,52.07 236.69,53.26 233.98,55.97 233.85,55.97 233.39,55.51 233.25,55.51 233.11,55.65 233.11,55.78 233.57,56.24 233.57,56.38 233.44,56.51 233.3,56.51 232.84,56.06 232.7,56.06 232.57,56.19 232.57,56.33 233.03,56.79 233.03,56.92 232.89,57.06 232.75,57.06 232.29,56.6 232.16,56.6 232.02,56.74 232.02,56.87 232.48,57.33 232.48,57.47 232.34,57.61 232.21,57.61 231.75,57.15 231.61,57.15 231.48,57.28 231.48,57.42 231.93,57.88 231.93,58.02 231.8,58.15 231.66,58.15 231.2,57.69 231.07,57.69 230.93,57.83 230.93,57.97 231.39,58.43 231.39,58.56 231.25,58.7 231.12,58.7 230.66,58.24 230.52,58.24 226.79,61.97 225.36,61.97 223.2,64.13 222.25,64.13 216.46,69.92 214.98,69.92 213.02,71.88 195.13,71.88 194.46,72.56 189.34,72.56 188.58,73.31 187.24,73.31 185.82,74.73 184.83,74.73 182.56,77
  BOTTOM w0.089: UC1.BG32 v1(165.55,90.47)
  BOTTOM w0.107: JDIMM2.237 239.85,49.98 239.13,49.25 v1(238.86,49.25)
DDR_B_D58: length 102.8
  IN3 w0.089: 185.07,77 184.81,77.26 184.75,77.26 184.08,77.93 184.08,78.12 183.29,78.91 182.27,78.91 181.06,80.12 181.06,80.93 180,81.99 178.44,81.99 177.27,83.16 177.27,83.59 176,84.85 176,85 175.6,85.4 175.6,86.71 174.55,87.77 173.86,87.77 173.15,88.48 170.86,88.48 170.46,88.89 169.17,88.89 167.61,90.46 v1(167.36,90.46)
  IN3 w0.097: 185.07,77 185.81,76.26 186.4,76.26 187.17,75.49 187.58,75.49 188.28,74.79 189.1,74.79 189.12,74.77 200.63,74.77 201.72,73.69 213.3,73.69 215.59,71.4 217.34,71.4 223.11,65.63 223.79,65.63 225.98,63.45 227.4,63.45 229.85,61 231.22,61 239.45,52.77 239.52,52.77 241.25,51.04 241.25,46.53 241.35,46.43 241.82,46.43 241.91,46.53 241.91,47.69 242.01,47.79 v1(242.36,47.79)
  BOTTOM w0.089: UC1.BK32 v1(167.36,90.46)
  BOTTOM w0.107: JDIMM2.245 241.85,48.3 v1(242.36,47.79)
DDR_B_D59: length 103.6
  IN3 w0.089: 184.33,78.1 183.36,79.07 182.33,79.07 181.22,80.18 181.22,80.99 180.06,82.16 178.51,82.16 177.44,83.22 177.44,83.26 177.43,83.26 177.43,83.66 176.17,84.92 176.17,85.07 175.76,85.47 175.76,86.78 174.61,87.93 173.93,87.93 173.22,88.64 170.93,88.64 170.53,89.05 170.03,89.05 169.37,89.72 168.66,89.72 167.36,91.02 v1(167.36,91.1)
  IN3 w0.097: v1(242.36,49.31) 242.14,49.1 241.97,49.1 241.65,49.41 241.65,52.19 240.82,53.02 239.7,53.02 239.54,53.17 239.54,53.31 239.89,53.66 239.89,53.8 239.76,53.94 239.62,53.94 239.27,53.58 239.13,53.58 239,53.72 239,53.86 239.42,54.28 239.42,54.42 239.29,54.55 239.15,54.55 238.72,54.13 238.59,54.13 238.45,54.27 238.45,54.4 238.88,54.83 238.88,54.96 238.74,55.1 238.6,55.1 238.18,54.68 238.04,54.68 237.91,54.81 237.91,54.95 238.33,55.37 238.33,55.51 238.19,55.65 238.06,55.65 237.63,55.22 237.42,55.22 231.34,61.3 229.97,61.3 227.53,63.75 226.1,63.75 223.92,65.93 223.23,65.93 217.46,71.7 215.72,71.7 213.43,73.99 201.84,73.99 200.76,75.07 189.34,75.07 189.32,75.09 188.41,75.09 187.71,75.79 187.29,75.79 186.52,76.56 185.93,76.56 184.88,77.61 184.82,77.61 184.33,78.1 184.33,78.1
  BOTTOM w0.089: UC1.BK31 v1(167.36,91.1)
  BOTTOM w0.107: v1(242.36,49.31) 242.75,49.31 242.85,49.42 JDIMM2.249
DDR_B_D60: length 103.6
  IN3 w0.089: 182.99,77 181.55,78.43 181.08,78.43 178.49,81.03 178.49,81.22 176.33,83.37 176.33,83.39 175.95,83.39 174.94,84.4 174.94,84.91 173.29,86.56 171.13,86.56 169.35,88.34 168.82,88.34 167.41,89.76 167.07,89.76 166.77,90.06 166.22,90.06 165.99,90.29 165.99,91.91 v1(165.54,92.37)
  IN3 w0.097: v1(238.86,44.68) 239.33,45.14 239.33,49.85 238.96,50.23 238.96,50.23 237.23,51.96 237.22,51.96 236.99,52.2 236.99,53.39 231.25,59.12 231.12,59.12 230.66,58.66 230.52,58.66 230.32,58.87 230.32,59 230.87,59.55 230.87,59.69 230.73,59.82 230.59,59.82 230.05,59.27 229.91,59.27 226.92,62.27 225.49,62.27 223.31,64.45 222.35,64.45 216.58,70.22 215.1,70.22 213.15,72.18 195.26,72.18 194.58,72.86 189.46,72.86 188.7,73.61 187.36,73.61 185.89,75.09 184.9,75.09 182.99,77
  BOTTOM w0.089: UC1.BG29 v1(165.54,92.37)
  BOTTOM w0.107: JDIMM2.236 239.6,42.81 239.6,43.94 v1(238.86,44.68)
DDR_B_D61: length 103.5
  IN3 w0.089: 181.72,77 181.3,77.42 180.91,77.42 177.99,80.33 177.99,81.02 176.21,82.8 174.38,82.8 172.88,84.3 171.78,84.3 171.25,84.83 171.25,85.16 170.33,86.08 169.7,86.08 168.59,87.2 168.59,87.83 167.63,88.79 166.53,88.79 165.49,89.82 165.4,89.82 164.99,90.23 164.99,90.66 164.97,90.68 164.97,90.9 165.12,91.04 165.12,91.31 v1(165.54,91.73)
  IN3 w0.097: 181.72,77 184.34,74.38 184.34,73.61 186.02,71.93 194.24,71.93 194.88,71.28 212.77,71.28 214.73,69.32 216.18,69.32 221.97,63.53 222.95,63.53 225.11,61.37 225.67,61.37 226.39,60.65 227.26,60.65 234.67,53.25 234.8,53.25 235.13,53.58 235.27,53.58 235.4,53.44 235.4,53.3 235.07,52.97 235.07,52.84 235.21,52.7 235.35,52.7 235.68,53.03 235.81,53.03 235.95,52.89 235.95,52.76 235.62,52.43 235.62,52.29 238.01,49.91 238.01,47.06 v1(238.86,46.2)
  BOTTOM w0.089: UC1.BG30 v1(165.54,91.73)
  BOTTOM w0.107: v1(238.86,46.2) 238.23,45.57 238.23,44.4 238.6,44.03 JDIMM2.232
DDR_B_D62: length 104.8
  IN3 w0.089: v1(167.36,91.73) 167.8,91.3 167.8,90.85 168.76,89.88 169.44,89.88 170.1,89.22 170.6,89.22 171,88.81 173.28,88.81 174,88.1 174.68,88.1 175.93,86.85 175.93,85.54 176.33,85.13 176.33,84.99 177.6,83.72 177.6,83.3 177.61,83.29 177.61,83.28 177.83,83.07 177.83,83.07 178.58,82.32
  IN3 w0.097: v1(242.36,46.27) 242.68,46.27 242.78,46.36 242.78,49.7 242.68,49.79 242.05,49.79 241.95,49.89 241.95,52.31 238.32,55.95 237.12,55.95 231.47,61.6 230.1,61.6 227.65,64.05 226.22,64.05 224.04,66.23 223.36,66.23 217.58,72 215.84,72 213.55,74.29 201.96,74.29 200.88,75.37 189.46,75.37 189.44,75.39 188.53,75.39 187.83,76.09 187.5,76.09 186.73,76.86 186.05,76.86 185.34,77.58 185.34,78.66 184.32,79.67 183.39,79.67 182.81,80.25 182.81,81.04 181.52,82.32 178.58,82.32
  BOTTOM w0.089: UC1.BK30 v1(167.36,91.73)
  BOTTOM w0.107: v1(242.36,46.27) 241.85,45.75 241.85,44.42 242.1,44.17 JDIMM2.246
DDR_B_D63: length 105.2
  IN3 w0.089: v1(167.32,92.37) 167.79,91.91 167.79,91.71 167.99,91.5 167.99,90.89 168.83,90.05 169.5,90.05 170.17,89.38 170.66,89.38 171.07,88.97 173.35,88.97 174.06,88.26 174.75,88.26 176.09,86.92 176.09,85.61 176.5,85.2 176.5,85.06 177.67,83.89 178.03,83.89 178.14,83.79
  IN3 w0.097: 178.14,83.79 178.39,83.53 178.39,83.11 179.01,82.5 181.6,82.5 182.98,81.11 182.98,80.47 183.61,79.85 184.57,79.85 185.64,78.78 185.64,77.7 186.18,77.16 186.92,77.16 187.69,76.39 187.95,76.39 188.66,75.69 189.57,75.69 189.58,75.67 201.01,75.67 202.09,74.59 213.68,74.59 215.96,72.3 217.71,72.3 223.48,66.53 224.19,66.53 226.37,64.35 227.78,64.35 230.22,61.9 231.59,61.9 237.25,56.25 238.44,56.25 242.25,52.44 242.25,50.69 243.08,49.86 243.08,45.46 v1(242.36,44.74)
  BOTTOM w0.089: UC1.BK29 167.79,92.64 v1(167.32,92.37)
  BOTTOM w0.107: JDIMM2.250 243.1,44 v1(242.36,44.74)
DDR_B_DQS0: length 66.7
  IN1 w0.089: v1(158,80.66) 158.13,80.8 158.29,80.8 158.38,80.71 158.38,79.64 156.95,78.21 156.95,76.12 156.94,76.11 156.94,64.99 164.27,57.66 170.79,57.66 175.55,52.9 175.82,52.9 176.07,53.15 176.2,53.15 176.39,52.96 176.39,52.84 176.14,52.59 176.14,52.31 176.52,51.93 176.8,51.93 177.56,52.69 177.69,52.69 177.88,52.5 177.88,52.38 177.56,52.06 177.56,51.79 177.84,51.51 178.28,51.07 178.56,51.07 178.69,51.07 179,50.76 179,50.35 179.42,49.93 179.82,49.93 180.68,49.08 180.68,47.18 180.87,46.99 181.36,46.99 v1(181.44,46.9)
  BOTTOM w0.076: UC1.AP34 158.01,89.22 157.87,89.08 157.65,88.98 157.58,88.78 157.58,88.54 157.62,88.43 157.62,88.24 157.58,88.13 157.58,87.89 157.62,87.78 157.62,86.75 157.43,86.56 157.43,86.46
  BOTTOM w0.089: v1(158,80.66) 158,80.8 157.91,80.89 157.63,80.89 157.43,81.09 157.43,86.46
  BOTTOM w0.097: v1(181.44,46.9) 181.67,47.14 181.92,47.14 182.15,47.37 182.15,49.23 181.69,49.69 181.69,49.96 181.85,50.12 JDIMM2.13
DDR_B_DQS1: length 67.3
  IN1 w0.089: v1(186.92,46.65) 186.92,46.48 187.05,46.36 187.36,46.36 187.47,46.47 187.47,48.96 187.09,49.34 186.93,49.34 184.71,51.56 184.71,52.32 181.6,55.44 180.79,55.44 176.55,59.68 174.77,59.68 173.18,61.27 165.76,61.27 160.85,66.18 160.85,73.9 160.66,74.09 160.66,79.38 160.34,79.69 160.34,81.06 160.84,81.55 160.84,81.57 v1(160.96,81.69)
  BOTTOM w0.076: 160.39,85.61 160.39,85.71 160.9,86.22 160.9,86.53 160.75,86.69 160.75,87.8 160.79,87.92 160.79,88.1 160.75,88.21 160.75,88.45 160.79,88.57 160.79,88.75 160.75,88.87 160.65,88.91 160.53,88.87 160.49,88.77 UC1.AV35
  BOTTOM w0.089: v1(160.96,81.69) 161.16,81.5 161.3,81.5 161.38,81.58 161.38,82.58 161.11,82.85 160.81,82.85 160.39,83.27 160.39,85.61
  BOTTOM w0.097: v1(186.92,46.65) 187.21,46.36 187.48,46.36 187.68,46.16 187.68,44.65 186.94,43.91 186.94,43.74 187.1,43.59 JDIMM2.34
DDR_B_DQS2: length 100.1
  IN3 w0.089: v1(225.2,47.4) 225.53,47.06 225.64,47.06 225.73,47.15 225.73,47.88 225.63,47.98 225.63,48.61 224.59,52.56 213.59,63.56 212.34,63.56 210.44,65.46 187.87,65.46 182.62,65.46 181.34,66.21 178.31,69.24 175.36,70.78 170.95,75.18 170.95,75.76 169.45,77.25 169.45,77.25 169.33,77.38 169.32,77.38 169.29,77.42 167.69,77.42 166.03,79.07 166.03,79.08 164.95,80.91 164.73,81.67 164.73,83.87 162.9,85.7 161.89,86.24 160.69,87.44 157.2,88.63 156.42,88.63 155.21,89.83 154.95,90.5 154.95,91.12 155.52,91.69 v1(155.52,91.74)
  BOTTOM w0.089: UC1.AL30 155.76,91.98 v1(155.52,91.74)
  BOTTOM w0.097: JDIMM2.179 225.35,50.18 225.19,50.03 225.19,49.17 224.74,48.71 224.74,47.94 224.7,47.91 224.7,47.16 224.8,47.06 224.87,47.06 v1(225.2,47.4)
DDR_B_DQS3: length 101.6
  IN1 w0.089: v1(230.18,47.35) 230.01,47.18 229.79,47.18 229.7,47.27 229.7,49.55 226.5,52.75 226.13,52.82 223.89,53.25 202.89,53.25 191.73,64.41 190.23,64.41 182.91,71.73 181.51,71.73 180.9,72.34 177.36,72.34 175.61,74.09 173.77,74.09 171.87,75.2 171.77,75.43 171.77,78.01 170.49,79.29 170.49,79.92 169.23,81.18 169.23,84.08 167.46,85.85 167.46,87.43 167.06,87.83 166.3,87.83 165.7,88.43 160.88,88.43 160.13,89.18 160.13,89.81 159.71,90.23 159.71,90.61 159.71,90.62 159.71,91.31 159.51,91.51 159.39,91.51 v1(159.16,91.73)
  BOTTOM w0.089: UC1.AU30 v1(159.16,91.73)
  BOTTOM w0.097: v1(230.18,47.35) 230.18,47.15 230.35,46.99 230.87,46.47 230.87,44.83 230.6,44.56 JDIMM2.200
DDR_B_DQS4: length 68.1
  IN1 w0.089: v1(164.29,83.17) 164.22,83.1 164.22,83.1 164.15,83.04 163.91,83.04 163.72,82.84 163.72,74.54 164.45,73.81 164.45,67.67 165.88,66.24 169.45,66.24 170.19,65.5 173.67,65.5 174.3,64.87 174.68,64.87 175.9,63.65 179.54,63.65 190.52,52.67 191.15,52.67 191.5,52.32 191.5,51.7 192.08,51.12 192.08,47.22 192.27,47.02 192.58,47.02 v1(192.72,46.88)
  BOTTOM w0.076: v1(164.29,83.17) 164.29,83.03 164.2,82.94 163.83,82.94 163.6,83.17 163.6,84.87 163.6,84.87 163.6,86.59 163.43,86.76 163.43,87.78 163.47,87.89 163.47,88.13 163.43,88.24 163.43,88.43 163.47,88.54 163.47,88.78 163.4,88.99 163.18,89.09 163.04,89.22 UC1.BB34
  BOTTOM w0.097: v1(192.72,46.88) 192.93,47.1 193.06,47.1 193.31,47.34 193.31,48.58 192.19,49.69 192.19,50.05 192.35,50.21 JDIMM2.55
DDR_B_DQS5: length 67.8
  IN1 w0.089: v1(197.34,47.03) 197.34,46.81 197.48,46.67 197.83,46.67 197.91,46.76 197.91,52.1 197.11,52.91 196.36,52.91 182.01,67.25 178.5,67.25 177.25,68.5 175.77,68.5 175.16,69.1 173.05,69.1 171.92,70.24 171.14,70.24 169.3,72.08 169.3,72.27 169.3,72.27 169.3,73.26 167.82,74.73 167.82,79.71 167.5,80.03 167.35,80.03 167.26,79.93 v1(167.26,79.74)
  BOTTOM w0.076: UC1.BF35 165.52,88.77 165.56,88.87 165.69,88.91 165.78,88.87 165.82,88.75 165.82,88.57 165.78,88.45 165.78,88.21 165.82,88.1 165.82,87.92 165.78,87.8 165.78,86.69 166.08,86.39 166.08,85.7 166.31,85.46 166.31,80.27 166.58,80 167,80 v1(167.26,79.74)
  BOTTOM w0.097: v1(197.34,47.03) 197.34,47.02 197.61,46.74 197.89,46.74 198.1,46.54 198.1,44.9 197.44,44.25 197.44,43.78 197.6,43.63 JDIMM2.76
DDR_B_DQS6: length 101.9
  IN3 w0.089: v1(162.8,91.73) 162.8,91.59 162.99,91.41 163.16,91.41 163.35,91.22 163.35,89.79 164.15,89 165.15,89 166.18,87.96 167.18,87.96 167.67,87.48 167.67,85.99 170.97,82.69 172.4,82.69 173.22,81.86 174.84,81.86 176.56,81.23 177.1,80.69 177.1,78.56 177.36,77.85 178.03,77.18 178.04,77.18 178.1,77.12 178.1,77.13 179.84,75.38 179.84,75.03 179.87,75 182.36,72.51 185.65,69.22 212,69.22 213.9,67.32 215.17,67.32 223.26,59.23 224.67,59.23 228.61,55.29 229.49,55.29 232.24,52.55 232.24,52.13 233.93,50.44 234.44,50.44 235.19,49.69 235.19,47.32 235.28,47.23 235.67,47.23 235.89,47.46 v1(235.89,47.66)
  BOTTOM w0.089: v1(162.8,91.73) UC1.BC30
  BOTTOM w0.097: v1(235.89,47.66) 235.6,47.38 235.28,47.38 235.18,47.47 235.18,48.71 235.69,49.22 235.69,49.99 235.85,50.14 JDIMM2.221
DDR_B_DQS7: length 103.6
  IN3 w0.089: v1(240.45,46.97) 240.25,46.76 240.1,46.76 240.01,46.85 240.01,50.14 239.83,50.32 239.83,50.45 240.12,50.74 240.12,51.02 239.83,51.31 239.55,51.31 239.29,51.05 239.1,51.05 238.62,51.53 238.62,52.9 231.01,60.5 229.64,60.5 227.2,62.95 225.77,62.95 223.59,65.13 222.64,65.13 216.86,70.9 215.38,70.9 213.4,72.89 201.81,72.89 201.16,73.53 193.55,73.53 193.15,73.93 189.34,73.93 188.99,74.29 188.08,74.29 187.42,74.95 186.99,74.95 186.17,75.76 185.18,75.76 183.77,77.18 183.76,77.18 180.89,80.05 180.89,80.86 179.93,81.83 178.37,81.83 176.71,83.48 176.71,83.91 175.84,84.79 175.84,84.93 173.99,86.78 173.99,87.07 173.1,87.96 170.62,87.96 169.86,88.72 168.97,88.72 167.58,90.1 167.21,90.1 167,90.32 167,91.37 166.81,91.57 166.62,91.57 v1(166.45,91.73)
  BOTTOM w0.089: UC1.BH30 v1(166.45,91.73)
  BOTTOM w0.097: JDIMM2.242 241.1,43.56 240.94,43.72 240.94,44.68 241.26,45 241.26,46.45 241.06,46.65 240.55,46.65 240.45,46.75 v1(240.45,46.97)
DDR_B_DQS#0: length 66.6
  IN1 w0.089: v1(181.44,47.67) 181.44,47.47 181.13,47.17 180.94,47.17 180.86,47.25 180.86,49.15 179.9,50.11 179.49,50.11 179.18,50.43 179.18,50.83 178.76,51.25 178.49,51.25 178.36,51.25 178.1,51.51 177.74,51.86 177.74,51.99 178.06,52.31 178.06,52.58 177.76,52.87 177.49,52.87 176.72,52.11 176.6,52.11 176.32,52.39 176.32,52.51 176.57,52.76 176.57,53.04 176.27,53.33 176,53.33 175.75,53.08 175.62,53.08 170.86,57.84 164.34,57.84 157.12,65.06 157.12,78.13 158.55,79.57 158.55,80.78 158.36,80.97 158.2,80.97 158.15,81.02 158.09,81.02 158,81.11 v1(158,81.3)
  BOTTOM w0.076: 157.6,86.41 157.6,86.51 157.79,86.69 157.79,87.8 157.74,87.92 157.74,88.1 157.79,88.21 157.79,88.45 157.74,88.57 157.74,88.75 157.79,88.87 157.88,88.91 158,88.87 158.05,88.77 UC1.AP35
  BOTTOM w0.089: 157.6,86.41 157.6,81.16 157.7,81.07 157.91,81.07 158,81.16 v1(158,81.3)
  BOTTOM w0.097: JDIMM2.11 181.35,50.1 181.51,49.94 181.51,49.62 181.97,49.15 181.97,47.44 181.85,47.32 181.54,47.32 181.44,47.42 v1(181.44,47.67)
DDR_B_DQS#1: length 67.4
  IN1 w0.089: v1(160.96,81.06) 160.84,81.18 160.72,81.18 160.52,80.98 160.52,79.77 160.84,79.45 160.84,74.16 161.03,73.97 161.03,73.69 161.03,73.69 161.03,66.25 165.84,61.45 173.25,61.45 174.84,59.86 176.62,59.86 180.87,55.62 181.67,55.62 184.89,52.4 184.89,51.64 187.01,49.52 187.16,49.52 187.65,49.03 187.65,46.39 187.43,46.17 187.05,46.17 186.92,46.05 v1(186.92,45.89)
  BOTTOM w0.076: UC1.AV34 160.52,89.22 160.67,89.08 160.88,88.98 160.95,88.78 160.95,88.54 160.91,88.43 160.91,88.24 160.95,88.13 160.95,87.89 160.91,87.78 160.91,86.75 161.07,86.6 161.07,86.15 160.57,85.65 160.57,85.55
  BOTTOM w0.089: v1(160.96,81.06) 161.2,81.3 161.39,81.3 161.56,81.47 161.56,82.65 161.19,83.02 160.89,83.02 160.57,83.34 160.57,85.55
  BOTTOM w0.097: v1(186.92,45.89) 187.21,46.17 187.4,46.17 187.5,46.08 187.5,44.73 186.76,43.99 186.76,43.72 186.6,43.57 JDIMM2.32
DDR_B_DQS#2: length 100.1
  IN3 w0.089: v1(225.2,46.64) 225.45,46.88 225.72,46.88 225.91,47.08 225.91,47.95 225.81,48.05 225.81,48.64 224.75,52.65 213.67,63.74 212.42,63.74 210.52,65.64 187.79,65.64 182.67,65.64 181.45,66.35 178.42,69.39 175.46,70.92 171.13,75.26 171.13,75.83 169.45,77.51 169.45,77.51 169.36,77.59 167.77,77.59 166.17,79.19 165.12,80.98 164.9,81.69 164.9,83.95 163.01,85.84 162,86.38 160.78,87.6 157.23,88.81 156.49,88.81 155.37,89.93 155.12,90.53 155.12,91.04 155.24,91.16 v1(155.5,91.16)
  BOTTOM w0.089: UC1.AL31 155.67,91.33 v1(155.5,91.16)
  BOTTOM w0.097: JDIMM2.177 224.85,50.16 225.01,50 225.01,49.25 224.55,48.79 224.55,48.02 224.51,47.99 224.51,47.08 224.72,46.88 224.96,46.88 v1(225.2,46.64)
DDR_B_DQS#3: length 101.4
  IN1 w0.089: v1(159.16,91.1) 159.16,91.24 159.25,91.33 159.44,91.33 159.53,91.24 159.53,90.54 159.53,90.54 159.53,90.15 159.95,89.74 159.95,89.1 160.81,88.25 165.63,88.25 166.22,87.65 166.99,87.65 167.28,87.36 167.28,85.77 169.06,84 169.06,81.11 170.31,79.85 170.31,79.21 171.16,78.36 171.16,78.36 171.16,78.36 171.59,77.93 171.59,75.39 171.73,75.07 173.72,73.91 175.53,73.91 177.28,72.15 180.82,72.15 181.43,71.55 182.84,71.55 190.16,64.23 191.66,64.23 202.81,53.07 223.87,53.07 225.14,52.83 226.09,52.64 226.41,52.58 229.52,49.47 229.52,47.19 229.71,47 229.99,47 230.18,46.8 v1(230.18,46.58)
  BOTTOM w0.089: v1(159.16,91.1) UC1.AU31
  BOTTOM w0.097: v1(230.18,46.58) 230.27,46.67 230.4,46.67 230.68,46.39 230.68,44.9 230.41,44.63 230.41,43.95 230.1,43.63 JDIMM2.198
DDR_B_DQS#4: length 68
  IN1 w0.089: v1(192.72,47.64) 192.78,47.58 192.78,47.45 192.61,47.28 192.55,47.28 192.47,47.2 192.35,47.2 192.26,47.29 192.26,51.2 191.68,51.77 191.68,52.4 191.23,52.85 190.59,52.85 179.62,63.83 175.98,63.83 174.76,65.05 174.38,65.05 173.75,65.68 170.27,65.68 169.53,66.42 165.96,66.42 164.63,67.74 164.63,73.69 164.63,73.69 164.63,73.88 163.89,74.62 163.89,82.77 163.98,82.86 164.08,82.86 164.14,82.8 164.21,82.8 164.29,82.73 v1(164.29,82.53)
  BOTTOM w0.076: UC1.BB35 163,88.77 163.05,88.87 163.17,88.91 163.27,88.87 163.31,88.75 163.31,88.57 163.27,88.45 163.27,88.21 163.31,88.1 163.31,87.92 163.27,87.8 163.27,86.69 163.27,86.68 163.43,86.52 163.43,84.8 163.43,83.1 163.76,82.77 164.19,82.77 164.29,82.67 v1(164.29,82.53)
  BOTTOM w0.097: v1(192.72,47.64) 192.72,47.41 192.85,47.28 192.99,47.28 193.12,47.41 193.12,48.5 192.01,49.62 192.01,49.98 191.85,50.14 JDIMM2.53
DDR_B_DQS#5: length 67.6
  IN1 w0.089: v1(167.26,80.38) 167.43,80.21 167.57,80.21 168,79.78 168,74.81 169.48,73.33 169.48,72.16 171.22,70.42 171.99,70.42 173.12,69.29 175.24,69.29 175.84,68.68 177.33,68.68 178.58,67.43 182.09,67.43 196.43,53.09 197.19,53.09 198.09,52.18 198.09,46.68 197.9,46.49 197.56,46.49 v1(197.34,46.27)
  BOTTOM w0.076: UC1.BF34 165.56,89.22 165.7,89.08 165.91,88.98 165.99,88.78 165.99,88.54 165.95,88.43 165.95,88.24 165.99,88.13 165.99,87.89 165.95,87.78 165.95,86.75 166.24,86.46 166.24,85.77 166.48,85.53 166.48,80.34 166.65,80.16 167.04,80.16 v1(167.26,80.38)
  BOTTOM w0.097: v1(197.34,46.27) 197.62,46.56 197.82,46.56 197.91,46.46 197.91,44.98 197.26,44.33 197.26,43.81 197.1,43.65 JDIMM2.74
DDR_B_DQS#6: length 101.9
  IN3 w0.089: v1(235.89,46.9) 235.74,47.05 235.21,47.05 235.01,47.25 235.01,49.61 234.36,50.26 233.86,50.26 232.06,52.06 232.06,52.47 229.42,55.11 228.53,55.11 224.59,59.05 223.19,59.05 215.1,67.14 213.82,67.14 211.93,69.04 186.38,69.04 185.57,69.04 182.18,72.43 180.44,74.17 179.65,74.96 179.65,75.3 177.21,77.75 176.92,78.53 176.92,80.61 176.46,81.07 174.81,81.68 173.15,81.68 172.32,82.51 170.9,82.51 167.49,85.91 167.49,87.4 167.11,87.79 166.11,87.79 165.08,88.82 164.08,88.82 163.18,89.72 163.18,91.14 163.09,91.23 162.89,91.23 162.8,91.14 v1(162.8,91.1)
  BOTTOM w0.089: v1(162.8,91.1) UC1.BC31
  BOTTOM w0.097: v1(235.89,46.9) 235.6,47.19 235.2,47.19 235,47.4 235,48.78 235.51,49.29 235.51,50.04 235.35,50.2 JDIMM2.219
DDR_B_DQS#7: length 103.6
  IN3 w0.089: v1(166.45,91.1) 166.42,91.13 166.42,91.25 166.56,91.39 166.73,91.39 166.82,91.3 166.82,90.24 167.14,89.92 167.51,89.92 168.89,88.54 169.78,88.54 170.55,87.78 173.02,87.78 173.81,87 173.81,86.71 175.66,84.86 175.66,84.71 176.54,83.84 176.54,83.4 178.29,81.65 179.85,81.65 180.72,80.78 180.72,79.97 185.11,75.58 186.1,75.58 186.91,74.77 187.34,74.77 188,74.11 188.91,74.11 189.27,73.75 193.08,73.75 193.48,73.35 201.09,73.35 201.74,72.71 213.33,72.71 215.31,70.72 216.79,70.72 222.56,64.95 223.51,64.95 225.69,62.77 227.12,62.77 229.57,60.32 230.94,60.32 238.44,52.82 238.44,51.46 239.02,50.87 239.37,50.87 239.63,51.13 239.75,51.13 239.94,50.94 239.94,50.82 239.65,50.52 239.65,50.25 239.83,50.07 239.83,46.78 240.02,46.58 240.34,46.58 240.45,46.47 v1(240.45,46.2)
  BOTTOM w0.089: UC1.BH31 v1(166.45,91.1)
  BOTTOM w0.097: v1(240.45,46.2) 240.45,46.36 240.55,46.47 240.98,46.47 241.08,46.37 241.08,45.08 240.76,44.76 240.76,43.75 240.6,43.59 JDIMM2.240
DDR_B_MA0: length 93.6
  IN3 w0.089: 156.55,77.37 155.94,77.37 153.18,80.13 153.18,80.62 153.47,80.91 v1(153.54,80.91)
  IN3 w0.122: 156.55,77.37 157.93,77.37 158.19,77.1 170.13,65.17 171.75,65.17 176.15,60.76 177.75,59.17 181.48,59.17 190.47,59.17 190.47,59.17 207.83,59.17 214.54,52.46 214.54,50.64 214.96,50.22 214.96,50.14 214.96,50.14 214.96,48.72 215.57,48.11 215.57,46.83 v1(215.15,46.41)
  BOTTOM w0.076: UC1.AG36 153.62,88.28 153.89,87.8 153.89,87.53 153.69,87.33 153.69,86.88 153.84,86.74 153.84,84.25 153.17,83.59 153.17,82.77 153.13,82.73 153.13,82.63
  BOTTOM w0.089: 153.13,82.63 153.13,81.32 v1(153.54,80.91)
  BOTTOM w0.135: JDIMM2.144 214.6,44.76 214.43,44.93 214.19,44.93 214.02,45.09 214.02,46.26 214.18,46.41 v1(215.15,46.41)
DDR_B_MA1: length 96.1
  IN3 w0.089: 151.7,77.54 151.41,77.83 151.41,79.59 v1(151.77,79.95)
  IN3 w0.122: 151.7,77.54 152.16,77.54 156.16,73.55 156.33,73.55 156.54,73.75 156.71,73.75 156.89,73.58 156.89,73.41 156.68,73.2 156.68,73.03 156.85,72.86 157.02,72.86 157.23,73.06 157.4,73.06 157.58,72.89 157.58,72.72 157.37,72.51 157.37,72.34 157.54,72.17 157.71,72.17 157.92,72.38 158.09,72.38 158.27,72.2 158.27,72.03 158.06,71.82 158.06,71.65 158.23,71.48 158.4,71.48 158.61,71.69 158.78,71.69 158.96,71.51 158.96,71.34 158.75,71.13 158.75,70.96 158.92,70.79 159.09,70.79 159.3,71 159.47,71 159.65,70.82 159.65,70.65 159.44,70.44 159.44,70.27 159.61,70.1 159.78,70.1 159.99,70.31 160.16,70.31 160.33,70.13 160.33,69.96 160.13,69.75 160.13,69.58 160.32,69.39 161.08,69.39 168.83,61.63 169.98,61.63 174.36,57.25 175.4,56.21 180.25,56.21 206.2,56.21 208.14,54.27 208.14,54.1 208.05,54.01 208.05,53.84 208.22,53.66 208.39,53.66 208.48,53.75 208.65,53.75 208.83,53.58 208.83,53.41 208.74,53.32 208.74,53.15 208.91,52.97 209.08,52.97 209.17,53.06 209.34,53.06 209.52,52.89 209.52,52.14 209.13,51.74 209.13,51.56 211.02,49.67 211.02,47.95 211.18,47.79 v1(211.43,47.79)
  BOTTOM w0.076: 152.78,82.74 152.78,82.84 152.83,82.89 152.83,84.13 153.51,84.81 153.51,86.61 153.36,86.75 153.36,87.78 153.4,87.89 153.4,88.13 153.36,88.24 153.36,88.43 153.53,88.89 UC1.AG35
  BOTTOM w0.089: v1(151.77,79.95) 152.78,80.96 152.78,82.74
  BOTTOM w0.135: v1(211.43,47.79) 211.94,48.3 211.94,50.08 211.85,50.17 JDIMM2.133
DDR_B_MA2: length 96.3
  IN3 w0.122: v1(211.43,46.27) 211.15,45.99 210.73,45.99 210.48,46.24 210.48,46.61 210.6,46.73 210.89,46.73 211.02,46.85 211.02,47.1 210.89,47.22 210.6,47.22 210.48,47.34 210.48,49.66 208.66,51.48 208.66,52.68 205.51,55.82 191.86,55.82 180.09,55.82 180.09,55.82 175.24,55.82 173.97,57.09 169.82,61.24 168.67,61.24 163.21,66.71 162.44,66.71 162.26,66.89 162.26,67.07 162.47,67.28 162.47,67.45 162.3,67.62 162.13,67.62 161.92,67.41 161.74,67.41 161.57,67.58 161.57,67.76 161.78,67.97 161.78,68.14 161.61,68.31 161.44,68.31 161.23,68.1 161.05,68.1 160.88,68.27 160.88,68.45 161.09,68.66 161.09,68.83 160.92,69 160.75,69 160.54,68.79 160.36,68.79 153.9,75.26 153.7,75.26 151.06,77.9 151.06,80.47 151.18,80.59 v1(151.77,80.59)
  BOTTOM w0.076: UC1.AF34 153.24,89.05 153.24,88.57 153.2,88.45 153.2,88.21 153.24,88.1 153.24,87.93 153.2,87.82 153.2,86.69 153.34,86.54 153.34,84.88 152.66,84.2 152.66,82.96 152.6,82.89 152.6,82.79
  BOTTOM w0.089: 152.6,82.79 152.6,81.42 v1(151.77,80.59)
  BOTTOM w0.135: v1(211.43,46.27) 211.92,45.77 211.92,44.02 211.6,43.7 JDIMM2.132
DDR_B_MA3: length 95.3
  IN3 w0.122: v1(151.77,78.68) 152.33,78.68 153.16,77.86 153.16,77.69 152.81,77.35 152.81,77.17 152.99,77 153.16,77 153.5,77.34 153.67,77.34 153.85,77.17 153.85,77 153.5,76.66 153.5,76.48 153.68,76.31 153.85,76.31 154.19,76.65 154.36,76.65 154.54,76.48 154.54,76.31 154.19,75.97 154.19,75.79 154.36,75.62 154.54,75.62 154.88,75.97 155.05,75.97 155.23,75.79 155.23,75.62 154.88,75.28 154.88,75.1 155.05,74.93 155.23,74.93 155.57,75.28 155.74,75.28 155.92,75.1 155.92,74.93 155.6,74.61 155.6,74.44 155.77,74.27 155.94,74.27 156.26,74.59 156.43,74.59 158.79,72.22 158.79,72.22 169,62.02 170.14,62.02 174.75,57.41 175.56,56.6 180.41,56.6 180.41,56.6 191.54,56.6 206.36,56.6 209.91,53.05 209.91,52.52 210.27,52.17 210.27,51.99 209.84,51.57 209.84,51.4 210.09,51.15 210.26,51.15 210.68,51.57 210.85,51.57 211.03,51.4 211.03,51.23 210.6,50.81 210.6,50.63 210.87,50.37 211.29,50.37 211.42,50.24 211.42,49.33 v1(211.43,49.31)
  BOTTOM w0.076: 152.95,82.68 152.95,82.78 153,82.83 153,83.83 v2(153.27,84.09) 153.67,84.5 153.67,86.68 153.53,86.82 153.53,87.59 UC1.AG37
  BOTTOM w0.089: 152.95,82.68 152.95,79.87 v1(151.77,78.68)
  BOTTOM w0.135: JDIMM2.131 211.35,50.22 210.13,49 210.13,48.79 210.42,48.49 210.61,48.49 v1(211.43,49.31)
DDR_B_MA4: length 94.5
  IN3 w0.089: 151.99,76.06 150.4,77.66 150.4,81.77 150.48,81.86 v1(151.77,81.86)
  IN3 w0.122: v1(211.43,44.74) 210.91,44.22 209.94,44.22 209.7,44.46 209.7,49.34 207.37,51.67 207.37,52.69 205.02,55.04 192.19,55.04 179.77,55.04 179.77,55.04 174.92,55.04 173.2,56.77 169.49,60.47 168.35,60.47 163.79,65.03 163.02,65.03 151.99,76.06
  BOTTOM w0.076: 152.24,82.9 152.24,83 152.33,83.09 152.33,84.34 152.99,84.99 152.99,85.57 152.42,86.14 152.42,86.59 152.59,86.75 152.59,87.78 152.55,87.89 152.55,88.13 152.59,88.24 152.59,88.72 UC1.AE35
  BOTTOM w0.089: 152.24,82.9 152.24,82.33 v1(151.77,81.86)
  BOTTOM w0.135: JDIMM2.128 210.6,44.04 211.31,44.74 v1(211.43,44.74)
DDR_B_MA5: length 93.9
  IN3 w0.089: v1(151.77,81.22) 150.72,81.22 150.63,81.14 150.63,77.72 150.66,77.69
  IN3 w0.122: 150.66,77.69 151.57,76.78 151.82,76.78 162.49,66.12 162.66,66.12 162.87,66.32 163.04,66.32 163.22,66.15 163.22,65.98 163.01,65.77 163.01,65.6 163.18,65.42 163.95,65.42 168.51,60.86 169.66,60.86 173.58,56.93 175.08,55.43 179.93,55.43 192.02,55.43 192.02,55.43 205.35,55.43 208.27,52.52 208.27,52.07 208,51.81 208,51.58 210.09,49.5 210.09,45.28 210.21,45.16 210.55,45.16 210.67,45.28 v1(210.67,45.49)
  BOTTOM w0.076: UC1.AF35 152.88,88.56 152.71,88.1 152.71,87.92 152.75,87.8 152.75,86.69 152.58,86.52 152.58,86.21 153.15,85.64 153.15,84.92 152.5,84.26 152.5,83.03 152.42,82.95 152.42,82.85
  BOTTOM w0.089: v1(151.77,81.22) 152.42,81.88 152.42,82.85
  BOTTOM w0.135: JDIMM2.126 210.1,44.92 v1(210.67,45.49)
DDR_B_MA6: length 94.9
  IN3 w0.089: v1(151.77,83.13) 150.44,83.13 149.54,82.23 149.54,79.19
  IN3 w0.122: 149.54,79.19 149.54,77.97 163.07,64.44 163.24,64.44 163.45,64.64 163.62,64.64 163.8,64.47 163.8,64.3 163.59,64.09 163.59,63.92 163.76,63.74 164.53,63.74 168.19,60.08 169.33,60.08 169.6,59.81 169.6,59.64 169.42,59.45 169.42,59.28 169.59,59.1 169.76,59.1 169.95,59.29 170.12,59.29 170.29,59.12 170.29,58.95 170.11,58.76 170.11,58.59 170.28,58.41 170.45,58.41 170.64,58.6 170.81,58.6 170.98,58.43 170.98,58.26 170.8,58.07 170.8,57.9 170.97,57.72 171.14,57.72 171.33,57.91 171.5,57.91 172.81,56.61 174.76,54.65 179.61,54.65 192.35,54.65 192.35,54.65 204.86,54.65 206.98,52.53 206.98,51.51 207.5,50.99 209.31,49.18 209.31,47.14 209.19,47.01 v1(208.89,47.01)
  BOTTOM w0.076: v1(151.77,83.13) 152.17,83.53 152.17,84.41 152.82,85.06 152.82,85.5 152.25,86.07 152.25,86.65 152.42,86.82 152.42,87.59 UC1.AE37
  BOTTOM w0.135: JDIMM2.127 210.35,49.77 209.74,49.16 209.74,47.4 209.36,47.01 v1(208.89,47.01)
DDR_B_MA7: length 94.4
  IN3 w0.089: 150.32,76.09 149.13,77.28 149.13,82.89 150.1,83.86 150.1,86.56 150.59,87.06 150.59,92 v1(150.96,92.37)
  IN3 w0.122: 150.32,76.09 167.11,59.3 168.29,59.3 170.96,56.63 171.68,56.63 172.03,56.28 174.44,53.88 179.29,53.88 192.67,53.88 192.67,53.88 203.83,53.88 204.93,52.78 204.93,52.25 208.34,48.83 208.34,45.79 208.64,45.49 v1(208.89,45.49)
  BOTTOM w0.076: v1(150.96,92.37) UC1.AC29
  BOTTOM w0.135: v1(208.89,45.49) 209.36,45.03 209.36,44.03 209.1,43.77 JDIMM2.122
DDR_B_MA8: length 93.7
  IN3 w0.085: v1(151.77,83.76) 150.28,83.76
  IN3 w0.089: 150.28,83.76 149.33,82.81 149.33,77.63
  IN3 w0.122: v1(208.89,48.54) 208.89,49.05 207.63,50.31 207.63,50.31 206.06,51.88 206.06,52.9 205.31,53.65 205.14,53.65 204.96,53.47 204.79,53.47 204.61,53.65 204.61,53.82 204.79,54 204.79,54.17 204.7,54.26 192.51,54.26 179.45,54.26 179.45,54.26 174.6,54.26 172.42,56.44 171.84,57.02 171.12,57.02 169.03,59.11 169.03,59.57 168.91,59.69 167.27,59.69 167.09,59.87 167.09,60.04 167.3,60.25 167.3,60.42 167.13,60.59 166.95,60.59 166.74,60.38 166.57,60.38 166.4,60.56 166.4,60.73 166.61,60.94 166.61,61.11 166.44,61.28 166.26,61.28 166.05,61.07 165.88,61.07 165.71,61.25 165.71,61.42 165.92,61.63 165.92,61.8 165.75,61.97 165.57,61.97 165.36,61.76 165.19,61.76 165.02,61.94 165.02,62.11 165.23,62.32 165.23,62.49 165.06,62.66 164.88,62.66 164.68,62.45 164.5,62.45 164.33,62.63 164.33,62.8 164.54,63.01 164.54,63.18 164.37,63.35 164.19,63.35 163.99,63.14 163.81,63.14 149.33,77.63
  BOTTOM w0.076: UC1.AE36 152.32,88.28 152.06,87.8 152.06,87.53 152.26,87.33 152.26,86.88 152.09,86.72 152.09,86 152.66,85.43 152.66,85.13 151.77,84.24 v1(151.77,83.76)
  BOTTOM w0.135: v1(208.89,48.54) 209.31,48.95 209.31,49.4 209.85,49.94 JDIMM2.125
DDR_B_MA9: length 91.7
  IN3 w0.089: v1(150.04,92.37) 149.68,92.01 149.68,90.2 149.76,90.12 149.76,86.57 147.97,84.77 147.97,78.48 148.45,76.86 149.64,75.67
  IN3 w0.122: v1(207.05,48.1) 206.73,49.34 204.18,51.9 204.06,52.55 203.89,52.72 202.8,53.1 192.99,53.1 192.99,53.1 178.96,53.1 178.96,53.1 174.11,53.1 172.2,55.01 170.99,55.5 167.97,58.52 166.78,58.52 149.64,75.67
  BOTTOM w0.089: UC1.AB29 v1(150.04,92.37)
  BOTTOM w0.135: JDIMM2.121 208.85,49.9 207.05,48.11 v1(207.05,48.1)
DDR_B_MA10: length 96.1
  IN3 w0.089: v1(153.54,83.45) 154.36,82.63 154.36,80.58 156.64,78.31 159.19,78.31 160.12,77.38
  IN3 w0.122: 160.12,77.38 170.77,66.73 172.39,66.73 177.71,61.41 178.39,60.72 182.12,60.72 189.83,60.72 189.83,60.72 208.48,60.72 211.45,57.76 212.37,57.76 216.65,53.48 216.65,50.81 217.2,50.26 217.2,46.49 v1(216.39,45.69)
  BOTTOM w0.076: 153.93,84.04 154,84.11 154,86.81 153.85,86.95 153.85,87.27 154.05,87.46 154.05,87.84 153.93,88.07 153.93,89.01 153.7,89.48 UC1.AG34
  BOTTOM w0.089: v1(153.54,83.45) 153.93,83.84 153.93,84.04
  BOTTOM w0.135: v1(216.39,45.69) 215.96,45.25 215.87,45.25 215.69,45.08 215.69,43.89 215.86,43.72 216.9,43.72 217.1,43.52 JDIMM2.146
DDR_B_MA11: length 95.3
  IN3 w0.089: 148.7,77.15 148.7,82.81 149.93,84.03 149.93,86.65 150.41,87.13 150.41,92.46 v1(150.96,93)
  IN3 w0.122: v1(207.05,45.81) 207.62,46.38 207.62,49 204.54,52.09 204.54,52.62 203.67,53.49 192.83,53.49 174.28,53.49 171.52,56.24 170.8,56.24 168.13,58.91 166.94,58.91 148.7,77.15
  BOTTOM w0.076: v1(150.96,93) 151.16,93.13 UC1.AC28
  BOTTOM w0.135: JDIMM2.120 208.6,43.68 208.17,44.11 208.17,44.7 v1(207.05,45.81)
DDR_B_MA12: length 94.2
  IN3 w0.089: 147.79,78.26 147.79,84.82 149.58,86.62 149.58,90.05 149.5,90.13 149.5,92.46 v1(150.04,93)
  IN3 w0.122: v1(205.92,48.1) 206.29,48.1 206.41,48.22 206.41,49.02 202.72,52.71 202.47,52.71 202.35,52.59 202.35,52.15 202.23,52.02 201.98,52.02 201.86,52.15 201.86,52.59 201.74,52.71 193.15,52.71 173.95,52.71 171.98,54.68 170.77,55.17 167.81,58.14 166.62,58.14 147.79,76.97 147.79,78.26
  BOTTOM w0.089: UC1.AB28 v1(150.04,93)
  BOTTOM w0.135: v1(205.92,48.1) 206.22,48.4 206.5,48.4 208.35,50.25 JDIMM2.119
DDR_B_MA13: length 94.9
  IN3 w0.089: v1(155.21,85.81) 154.57,85.17 154.57,80.61 156.68,78.5 159.55,78.5 160.67,77.38
  IN3 w0.122: 160.67,77.38 170.93,67.11 172.55,67.11 178.1,61.57 178.55,61.11 182.29,61.11 182.29,61.11 189.67,61.11 208.64,61.11 211.61,58.14 212.62,58.14 217.04,53.73 217.04,53.64 217.04,50.97 217.59,50.42 217.59,47.6 v1(219.48,45.7)
  BOTTOM w0.076: v1(155.21,85.81) 155.46,85.81 155.87,86.22 155.87,86.53 155.71,86.69 155.71,87.8 155.76,87.92 155.76,88.1 155.59,88.56 UC1.AK35
  BOTTOM w0.135: v1(219.48,45.7) 220.35,44.83 220.35,44.43 220.1,44.17 JDIMM2.158
DDR_B_MA14: length 96
  IN3 w0.089: v1(155.21,81.36) 155.21,81.47 155.29,81.56 155.51,81.56 155.6,81.47 155.6,80.56 157.28,78.88 160.26,78.88 161.77,77.38
  IN3 w0.122: v1(219.48,48.75) 219.48,48.58 219.06,48.16 218.72,48.16 218.36,48.51 218.36,53.48 217.81,54.03 217.81,54.05 213.17,58.69 212.94,58.92 211.93,58.92 211.75,59.1 211.75,59.27 212.13,59.65 212.13,59.82 211.95,59.99 211.78,59.99 211.41,59.62 211.24,59.62 208.96,61.89 189.35,61.89 178.87,61.89 172.87,67.89 171.25,67.89 167.76,71.38 167.76,72.15 166.56,73.35 165.79,73.35 161.77,77.38
  BOTTOM w0.076: UC1.AJ35 154.94,88.89 155.11,88.43 155.11,88.24 155.06,88.13 155.06,87.89 155.11,87.78 155.11,86.75 154.66,86.31 154.66,83.75
  BOTTOM w0.089: 154.66,83.75 154.66,81.91 v1(155.21,81.36)
  BOTTOM w0.135: v1(219.48,48.75) 218.89,48.16 218.54,48.16 218.35,48.35 JDIMM2.151
DDR_B_MA15: length 97
  IN3 w0.089: 162.32,77.38 160.63,79.07 157.48,79.07 155.89,80.66 155.89,82.12 155.71,82.3 155.35,82.3 155.21,82.16 v1(155.21,82)
  IN3 w0.122: v1(219.48,44.18) 220.07,44.77 220.07,48.76 218.8,50.03 218.8,53.7 212.12,60.38 211.02,60.38 209.12,62.28 189.19,62.28 179.24,62.28 173.23,68.29 173.22,68.28 171.42,68.28 168.52,71.17 168.52,72.84 167.51,73.86 166.63,73.86 166.19,74.31 165.39,74.31 162.32,77.38
  BOTTOM w0.076: UC1.AK34 155.23,89.05 155.23,88.57 155.27,88.45 155.27,88.21 155.23,88.1 155.23,87.92 155.27,87.8 155.27,86.69 154.83,86.25 154.83,82.37 v1(155.21,82)
  BOTTOM w0.135: v1(219.48,44.18) 219.6,44.06 JDIMM2.156
DDR_B_MA16: length 94.7
  IN3 w0.089: 159.57,77.38 158.83,78.12 156.6,78.12 154.16,80.55 154.16,81.37 153.81,82.55 v1(153.54,82.82)
  IN3 w0.122: 159.57,77.38 170.61,66.34 172.23,66.34 177.32,61.25 178.23,60.34 181.96,60.34 181.96,60.34 189.99,60.34 208.32,60.34 211.29,57.37 212.21,57.37 216.26,53.32 216.26,50.75 216.48,50.05 216.81,48.97 216.81,47.63 v1(216.39,47.21)
  BOTTOM w0.076: UC1.AJ34 154.77,89.48 154.54,89.02 154.54,88.07 154.41,87.84 154.41,87.46 154.61,87.27 154.61,86.95 154.17,86.51 154.17,84.03 154.11,83.97
  BOTTOM w0.089: 154.11,83.97 154.11,83.38 v1(153.54,82.82)
  BOTTOM w0.135: v1(216.39,47.21) 216.42,47.21 218.6,43.74 JDIMM2.152
DDR_B_ODT0: length 95.9
  IN3 w0.089: 157.38,79.8 156.33,80.84 156.33,82.71 155.77,83.27 v1(155.21,83.27)
  IN3 w0.122: v1(221.52,47.22) 221.11,47.63 221.11,49.2 220.38,49.93 220.38,53.22 212.44,61.16 211.34,61.16 209.44,63.06 188.86,63.06 179.56,63.06 169.76,72.86 167.62,75 166.94,75 166.75,75.19 165.91,75.19 161.62,79.48 157.7,79.48 157.38,79.8
  BOTTOM w0.076: 155.95,85.5 155.95,85.6 156.36,86.01 156.36,86.73 156.21,86.88 156.21,87.33 156.41,87.53 156.41,87.8 156.14,88.28 UC1.AL36
  BOTTOM w0.089: v1(155.21,83.27) 155.95,84.01 155.95,85.5
  BOTTOM w0.135: v1(221.52,47.22) 221.06,47.22 219.99,48.29 219.99,48.84 219.35,49.48 JDIMM2.155
DDR_B_ODT1: length 97.6
  IN3 w0.089: 164.27,77.38 164.16,77.38 161.87,79.66 157.85,79.66 157.81,79.7 156.52,80.99 156.52,83 155.9,83.63 155.9,84.48 v1(155.21,85.17)
  IN3 w0.122: 164.27,77.38 166.07,75.58 166.91,75.58 167.1,75.39 167.78,75.39 179.72,63.44 183.25,63.44 209.61,63.44 211.51,61.54 212.75,61.54 221.93,52.37 221.93,51.82 221.81,51.7 220.89,51.7 220.77,51.58 220.77,51.33 220.89,51.21 222.01,51.21 222.14,51.09 222.14,50.84 222.01,50.72 220.89,50.72 220.77,50.6 220.77,50.36 220.89,50.24 222.01,50.24 222.14,50.11 222.14,49.61 v1(221.52,48.99)
  BOTTOM w0.076: 155.59,85.61 155.59,85.71 156.03,86.15 156.03,86.6 155.88,86.75 155.88,87.78 155.92,87.89 155.92,88.13 155.88,88.24 155.88,89.37 UC1.AL34
  BOTTOM w0.089: v1(155.21,85.17) 155.59,85.56 155.59,85.61
  BOTTOM w0.135: JDIMM2.161 220.85,49.67 v1(221.52,48.99)
DDR_B_PARITY: length 92.5
  IN3 w0.089: v1(152.28,85.28) 153.02,84.54 153.02,80.06 156.09,76.98 156.55,76.98
  IN3 w0.122: 156.55,76.98 157.77,76.98 158.03,76.71 158.03,76.71 170.03,64.72 171.54,64.72 177.48,58.78 181.32,58.78 181.32,58.78 190.63,58.78 190.64,58.78 207.27,58.78 213.6,52.45 213.6,50.76 214.57,49.79 214.57,48.52 v1(215.15,47.94)
  BOTTOM w0.076: v1(152.28,85.28) 152.28,85.58 151.92,85.93 151.92,86.78 152.09,86.95 152.09,87.27 151.9,87.46 151.9,87.84 152.01,88.05 152.01,89.12 152.32,89.43 152.32,89.48 UC1.AE34
  BOTTOM w0.135: v1(215.15,47.94) 214.49,47.94 214.35,48.08 214.35,49.36 214.45,49.47 214.97,49.47 215.07,49.57 215.07,49.77 214.97,49.87 214.45,49.87 214.35,49.97 JDIMM2.143
DDR_CHA_EN: length 4.9
  BOTTOM w0.076: T406.1 184.84,99.39 183.32,99.39 183.21,99.28 181.05,99.28 180.99,99.22 UC1.CK19
DDR_CHB_EN: length 1.1
  TOP w0.102: v1(178.47,99.74) 178.43,99.77 T407.1
  BOTTOM w0.076: UC1.CG17 v1(178.47,99.74)
DDR_DRAMRST#: length 133.6
  TOP w0.107: RD11.2 200.89,43.21 RD12.2 201.69,43.99 v1(201.64,44.04)
  IN1 w0.089: v1(172.86,91.06) 172.82,91.06 172.28,91.6 172.28,93.7 171.98,94 169.91,94 169.61,93.7 168.85,89.39 168.85,86.87 168.94,86.78 170.3,84.2 170.3,83.35 171.04,81.85 171.53,81.35 171.53,81.18 172.18,80.53 172.28,80.53 172.28,80.53
  IN1 w0.099: v1(231.9,44) 232.32,44.42 233.16,48.09 233.16,49.55 231.43,51.28 230.72,52.73 230.72,53.2 227.97,55.95 203.22,55.95 185.85,73.32 184.81,73.32 184.26,73.87 182.39,73.87 181.44,74.83 177.91,74.83 176.51,76.23 176.01,76.23 175.21,77.04 174.56,77.04 174.05,77.55 174.05,78.76 172.28,80.53
  IN3 w0.102: v1(201.64,44.04) 203.07,43.47 224.53,43.47 v1(231.9,44)
  BOTTOM w0.076: v1(172.86,91.06) 172.84,91.06 172.84,91.06 UC1.BU31
DDR_DRAMRST#_R: length 84.3
  TOP w0.107: v1(201.35,41.4) 202.6,42.65 RD12.1 203.8,43.21 CD29.1 204.32,43.18 v2(205.15,42.35) 205.86,41.63 v1(205.86,41.59) ; CD61.1 128.12,45.57 v1(128.2,45.57)
  IN1 w0.099: v1(201.35,41.4) 197.58,41.07 176.9,41.07 168.98,45.07 147.78,45.07 147.72,45.01 135.22,45.01 135.08,45.15 129.09,45.15 v1(128.2,45.57)
  BOTTOM w0.107: JDIMM1.108 v1(128.2,45.57) ; JDIMM2.108 205.6,41.83 205.84,41.59 v1(205.86,41.59)
DDR_VTT_CTRL: length 22.4
  TOP w0.107: UD1.2 127.22,76.61 127.73,77.12 v2(127.73,79.79) 127.73,81.01 v1(127.31,81.43)
  BOTTOM w0.076: UC1.C35 139.49,88.91 139.17,88.59 139.17,88.22 139.14,88.19 138.96,88.01 138.96,88.01 138.53,88.01 138.36,87.84 138.35,87.84 138.34,87.83 138.03,87.83 137.67,87.47 135.25,87.47
  BOTTOM w0.107: 135.25,87.47 129.35,81.57 127.45,81.57 v1(127.31,81.43)
DDR_XDP_WAN_SMBCLK: length 372.5
  TOP w0.107: QC2.1 200,99.84 200.14,100.05 200.81,100.17 v1(201.73,100.17) 202.29,100.17 RC319.1 ; v1(208.95,102.53) 208.78,102.71 208.52,102.71 208.28,102.95 208.28,105.12 208.9,105.74 208.9,114.62 207.34,116.18 207.34,123.29 206.05,124.59 206.05,125.93 v1(205.88,126.1) ; LGA1.1 250.17,35.62 250.26,35.71 v1(250.26,35.85)
  IN1 w0.099: v1(245.21,48.95) 245.03,48.77 244.59,48.77 243.04,47.22 243.04,44.76 241.17,42.89 234.35,42.89 233.63,42.17 225.21,42.17 224.41,42.97 215.92,42.97 215.14,43.76 203.1,43.76 201.58,42.25 176.52,42.25 168.12,50.65 167.53,50.65 v1(167.35,50.83)
  IN3 w0.102: v1(199.43,89.48) 199.23,89.28 199.23,88.82 199.33,88.72 207.64,88.72 209.06,87.3 209.06,84.88 209.93,84.02 209.93,82.24 210.4,81.77 212.09,81.77 212.82,81.04 212.82,80.62 213.13,80.31 214.69,80.31 215.5,79.5 215.5,77.27 226.97,65.8 228.59,65.8 231.02,63.36 232.19,63.36 237.59,57.96 238.99,57.96 244.47,52.48 244.47,51.69 244.8,51.36 244.8,48.88 244.93,48.76 245.01,48.76 v1(245.21,48.95) ; v1(91.52,132.27) 91.32,132.47 91.32,132.65 91.42,132.75 91.99,132.75 92.37,133.13 97.05,133.13 99.85,130.34 101.24,130.34 102.64,128.94 104.66,128.94 105.07,128.53 114.05,128.53 115.51,129.99 115.51,130.44 117.05,131.98 119.56,131.98 121.78,129.76 121.78,129.02 123.99,126.81 134.6,126.81 135.77,127.98 147.76,127.98 150.93,124.81 156.62,124.81 157.36,125.55 158.55,125.55 160.99,127.99 160.99,128.62 161.13,128.76 162.73,128.76 162.97,129.01 179.78,129.01 181.58,130.8 196.5,130.8 197.52,129.78 204.36,129.78 205.99,128.15 205.99,126.2 v1(205.88,126.1) ; v1(201.73,100.17) 201.91,100.34 202.44,100.34 204.85,102.75 206.4,102.75 206.72,103.07 207.67,103.07 207.99,102.75 208.73,102.75 v1(208.95,102.53)
  BOTTOM w0.107: v1(199.43,89.48) 199.26,89.66 199.26,91.12 202.69,94.55 202.69,98 201.1,99.59 201.1,100.25 201.21,100.36 201.54,100.36 v1(201.73,100.17) ; JDIMM2.253 243.85,49.06 244.14,48.78 245.03,48.78 v1(245.21,48.95) 245.34,48.82 245.69,48.82 246.06,48.46 246.06,47.56 245.72,47.22 245.72,46.14 246.95,44.92 246.95,42.17 245.66,40.89 244.49,40.89 243.99,40.38 243.12,40.38 241.85,39.11 241.85,37.6 242.61,36.84 249.17,36.84 249.55,36.46 249.55,35.95 249.66,35.85 v1(250.26,35.85) ; JDIMM1.253 166.45,53.99 166.45,53.99 166.45,51.72 v1(167.35,50.83) ; JXDP1.53 91.77,133.64 91.58,133.46 91.58,133.25 91.33,133 91.33,132.46 v1(91.52,132.27)
DDR_XDP_WAN_SMBDAT: length 375
  TOP w0.107: LGA1.4 248.67,35.82 v1(248.64,35.85) ; v1(206.47,126.1) 206.28,125.91 206.28,124.69 207.58,123.39 207.58,116.27 209.14,114.71 209.14,105.65 208.51,105.02 208.51,103.05 208.62,102.94 208.78,102.94 v1(208.95,103.12) ; QC2.4 201.37,101.35 201.06,100.9 201.06,100.89 201.06,100.74 201.14,100.66 201.64,100.66 v1(201.73,100.75) 201.83,100.66 202.34,100.66 RC318.1
  IN1 w0.099: v1(245.21,48.37) 245.03,48.55 244.68,48.55 243.26,47.13 243.26,44.67 241.26,42.66 234.44,42.66 233.72,41.94 225.11,41.94 224.31,42.75 215.83,42.75 215.04,43.53 203.19,43.53 201.67,42.02 176.42,42.02 168.02,50.42 167.53,50.42 v1(167.35,50.24)
  IN3 w0.102: v1(201.73,100.75) 201.92,100.57 202.34,100.57 204.76,102.98 206.31,102.98 206.62,103.3 207.77,103.3 208.08,102.98 208.82,102.98 v1(208.95,103.12) ; v1(90.93,132.27) 91.09,132.43 91.09,132.74 91.32,132.98 91.9,132.98 92.28,133.36 97.15,133.36 99.94,130.57 101.34,130.57 102.74,129.17 104.75,129.17 105.17,128.76 113.95,128.76 115.29,130.09 115.29,130.53 116.96,132.2 119.65,132.2 122,129.86 122,129.12 124.09,127.04 134.51,127.04 135.68,128.2 147.86,128.2 151.03,125.04 156.53,125.04 157.26,125.78 158.46,125.78 160.76,128.08 160.76,128.71 161.04,128.99 162.63,128.99 162.87,129.23 179.69,129.23 181.48,131.03 196.59,131.03 197.61,130.01 204.45,130.01 206.22,128.24 206.22,126.35 v1(206.47,126.1) ; v1(198.85,89.48) 199,89.33 199,88.73 199.24,88.49 207.55,88.49 208.83,87.2 208.83,84.79 209.7,83.93 209.7,82.15 210.3,81.54 211.99,81.54 212.59,80.94 212.59,80.53 213.04,80.08 214.59,80.08 215.27,79.41 215.27,77.17 226.88,65.57 228.49,65.57 230.93,63.13 232.09,63.13 237.49,57.73 238.89,57.73 244.24,52.38 244.24,51.59 244.57,51.26 244.57,48.79 244.83,48.53 245.05,48.53 v1(245.21,48.37)
  BOTTOM w0.107: JDIMM2.254 244.1,48.15 244.49,48.54 245.03,48.54 v1(245.21,48.37) 245.42,48.59 245.6,48.59 245.82,48.36 245.82,47.66 245.49,47.32 245.49,46.05 246.71,44.82 246.71,42.27 245.57,41.12 244.4,41.12 243.89,40.62 243.02,40.62 241.61,39.21 241.61,37.51 242.51,36.61 249.07,36.61 249.32,36.36 249.32,35.96 249.21,35.85 v1(248.64,35.85) ; v1(90.93,132.27) 91.09,132.44 91.09,133.1 91.35,133.35 91.35,133.46 91.17,133.64 JXDP1.51 ; v1(167.35,50.24) 166.7,49.59 JDIMM1.254 ; v1(201.73,100.75) 201.57,100.59 201.11,100.59 200.87,100.35 200.87,99.49 202.45,97.91 202.45,94.65 199.02,91.22 199.02,89.66 v1(198.85,89.48)
DEBUG_TX: length 6.6
  TOP w0.107: v1(214.48,86.74) 214.48,86.64 214.57,86.55 v2(214.57,84.67) v1(214.57,83.81)
  BOTTOM w0.107: RE30.2 215.82,86.01 RE74.2 215.82,86.97 215.71,87.08 214.7,87.08 214.48,86.86 v1(214.48,86.74) ; JDEG1.9 214.97,83.42 v1(214.57,83.81)
DEW1: length 3.3
  BOTTOM w0.107: UN7.16 253.24,47.59 252.85,47.2 252.85,46.48 252.73,46.37 RN16.2 RN17.2
DEW2: length 3.2
  BOTTOM w0.107: UN7.6 258.77,49.59 v2(258.99,49.81) 259.09,49.81 259.55,49.35 RN15.2 RN14.2
DGPU_PWROK: length 89.8
  TOP w0.107: v2(241.28,100.15) 241.51,100.38 241.88,100.38 v1(241.97,100.47)
  TOP w0.127: UE1.M4 256,93.46 v1(256,93.38)
  IN1 w0.099: v1(241.97,100.47) 241.07,99.57 239.68,99.57 238.83,98.71 238.09,98.71 236.96,97.58 234.75,97.58 233.8,96.63 227.99,96.63 227.48,96.12 224.05,96.12 222.2,94.26 216.89,94.26 216.21,93.58 213.94,93.58 213.22,92.86 206.45,92.86 205.93,93.38 196.25,93.38 195.99,93.64 195.14,93.64 194.89,93.89 186.7,93.89 184.8,91.99 183.74,91.99 180.95,94.77 180.27,94.77 179.94,94.44 v1(179.84,94.44)
  IN3 w0.089: v1(256,93.38) 255.66,93.04 253.42,93.04 253.22,93.24 253.22,95.24 253.03,95.42 249.5,95.42 249.23,95.7 249.23,96.09 249.12,96.2 248.62,96.2 248.45,96.02 248.45,95.7 248.18,95.44 247.4,95.44 247.39,95.43 246.97,95.43 246.6,95.79
  IN3 w0.102: v1(241.97,100.47) 242.49,99.95 242.49,99.08 245.74,95.83 246.57,95.83 246.6,95.79
  BOTTOM w0.089: UC1.CJ25 179.76,94.52 v1(179.84,94.44)
DIMM1_SA0: length 4.6
  BOTTOM w0.107: v2(164.96,43.85) 165.45,44.35 RD5.1 RD4.2 166.99,44.66 166.99,45.12 167.2,45.32 JDIMM1.256
DIMM1_SA1: length 4.9
  BOTTOM w0.102: JDIMM1.260 168.2,45.99 167.23,45.02
  BOTTOM w0.107: 167.23,45.02 167.23,44.56 RD6.2 RD7.1 168.69,44.35 v2(169.18,43.85)
DIMM1_SA2: length 3.7
  TOP w0.107: RD8.2 RD9.1 144.8,48.05 v1(144.7,48.15) 144.93,48.38 v2(145.31,48.38)
  BOTTOM w0.107: JDIMM1.166 v1(144.7,48.15)
DIMM2_SA0: length 8.3
  TOP w0.107: RD20.2 245.36,45.48 v1(245.23,45.35) 245.14,45.26 RD21.1
  BOTTOM w0.107: v1(245.23,45.35) 244.6,44.72 244.6,42.81 JDIMM2.256 244.6,42.02 243.69,41.11 242.82,41.11 v2(242.25,40.54)
DIMM2_SA1: length 5.3
  TOP w0.107: RD23.1 245.06,44.5 v1(245.23,44.67) 245.28,44.71 RD22.2 245.85,44.64 246.58,43.91 v2(246.58,43.63)
  BOTTOM w0.107: JDIMM2.260 245.6,43.64 245.65,43.69 245.65,44.47 245.45,44.67 v1(245.23,44.67)
DIMM2_SA2: length 3.7
  TOP w0.107: RD24.2 RD25.1 222.56,42.15 v1(222.56,41.53) 222.92,41.17 v2(222.92,41.08)
  BOTTOM w0.102: JDIMM2.166 222.1,41.99 v1(222.56,41.53)
DISP_ON: length 7
  TOP w0.107: DV2.1 140.58,132.79 RV2.1 139.96,132.07 139.61,131.72 139.2,131.72 138.43,132.48 137.37,132.48 v2(137.14,132.25) 136.93,132.04 v1(136.57,132.04)
  BOTTOM w0.107: v1(136.57,132.04) 136.28,131.74 JEDP1.22
DMIC0: length 265.4
  TOP w0.107: CA6.1 124.19,125.27 124.19,127.09 123.83,127.44 123.46,127.44 DV13.3 122.46,128.84 123.02,129.4 124.73,129.4 124.99,129.15 125.68,129.15 125.95,129.42 125.95,132.36 126.53,132.94 127.94,132.94 128.14,132.74 128.21,132.74 v1(128.38,132.57) ; v1(283.84,49.98) 284.13,50.28 UA1.2 ; RA52.2 283.01,47.26 v1(283.08,47.33)
  IN1 w0.099: v1(287.47,80.24) 287.47,80.31 284.76,83.02 284.76,88.09 280.75,92.09 280.75,93.76 280.23,94.28 279.19,94.28 278.29,95.18 278.29,110.42 275.61,113.11 268.75,113.11 268.24,113.61 266.89,113.61 264.49,116.01 v1(260.17,116.01) ; v1(283.08,47.33) 283.08,47.76 282.63,48.21 282.63,49.29 283.33,49.98 v1(283.84,49.98)
  IN3 w0.102: v1(283.84,49.98) 282.53,51.29 282.53,52.27 281.41,53.39 279.87,53.39 279.71,53.54 279.71,54.14 278.95,54.9 278.51,54.9 275.14,58.27 275.14,61.15 275.42,61.43 275.42,62.46 278.55,65.59 278.55,68.48 280.52,70.45 285.38,70.45 285.62,70.22 286.64,70.22 v1(288.52,72.1)
  BOTTOM w0.107: v1(288.52,72.1) 287.67,72.95 287.67,80.04 v1(287.47,80.24) ; v1(260.17,116.01) 254.37,116.01 253.27,114.91 252.19,114.91 251.09,116.01 249.6,116.01 248.4,114.81 240.27,114.81 238.39,116.69 227.49,116.69 223.98,120.19 v2(222.6,120.19) 210.95,120.19 209.15,121.99 208.63,122.51 200.71,122.51 200.22,123 193.41,123 192.16,124.25 188.94,124.25 185.75,127.44 178.92,127.44 178.15,128.22 169.39,128.22 168.39,129.21 165.12,129.21 162.94,131.4 157.64,131.4 154.73,134.31 148.08,134.31 147.13,133.37 137.84,133.37 136.5,134.7 133.21,134.7 131.71,133.2 129.01,133.2 v1(128.38,132.57) 128.38,132.15 128.77,131.76 JEDP1.7
DMIC_CLK0: length 258.1
  TOP w0.107: v1(129.56,132.61) 129.56,132.53 129.15,132.13 128.06,132.13 127.74,132.45 126.73,132.45 126.45,132.17 126.45,129.22 125.88,128.66 124.57,128.66 124.39,128.48 DV13.2 124.39,127.59 124.7,127.29 124.7,124.89 CA5.1 ; v1(283.14,48.78) 283.14,48.31 283.84,47.61 RA14.1 CA54.1
  IN1 w0.099: v1(289.62,77.96) 288.47,79.11 287.99,79.11 286.36,80.74 286.33,80.74 279.61,87.46 278.04,91.25 278.04,93.57 277.14,94.47 277.14,102.85 274.23,105.76 274.23,109.36 273.42,110.16 269.76,110.16 268.34,111.58 266.15,111.58 265.52,112.21 264.09,112.21 v1(263.08,113.23)
  IN3 w0.102: v1(289.62,77.96) 289.62,74.87 286.4,71.65 280.14,71.65 278.35,69.86 277.62,69.86 276.26,68.51 276.26,66.65 276.66,66.24 276.66,65.28 274.3,62.92 274.3,61.89 274.02,61.61 274.02,57.28 277.02,54.28 277.02,53.41 278.3,52.12 278.3,51.18 280.86,48.63 282.99,48.63 v1(283.14,48.78)
  BOTTOM w0.107: JEDP1.9 129.77,131.81 129.46,132.12 129.46,132.51 v1(129.56,132.61) 129.66,132.71 131.91,132.71 133.38,134.19 136.33,134.19 137.64,132.88 147.33,132.88 148.28,133.83 154.52,133.83 157.44,130.91 162.73,130.91 164.92,128.72 168.19,128.72 169.21,127.71 177.97,127.71 178.87,126.81 185.69,126.81 188.74,123.77 191.88,123.77 193.13,122.51 200.02,122.51 200.51,122.03 208.43,122.03 209.16,121.3 211.15,119.3 v2(219.95,119.3) 224.18,119.3 227.28,116.2 238.19,116.2 240.07,114.32 248.31,114.32 249.27,113.36 259.13,113.36 260.55,111.95 262.43,111.95 263.08,112.6 v1(263.08,113.23)
DMIC_CLK_CODEC: length 2.9
  TOP w0.107: UA1.3 284.53,49.99 v2(284.05,49.5) 283.84,49.3 RA14.2
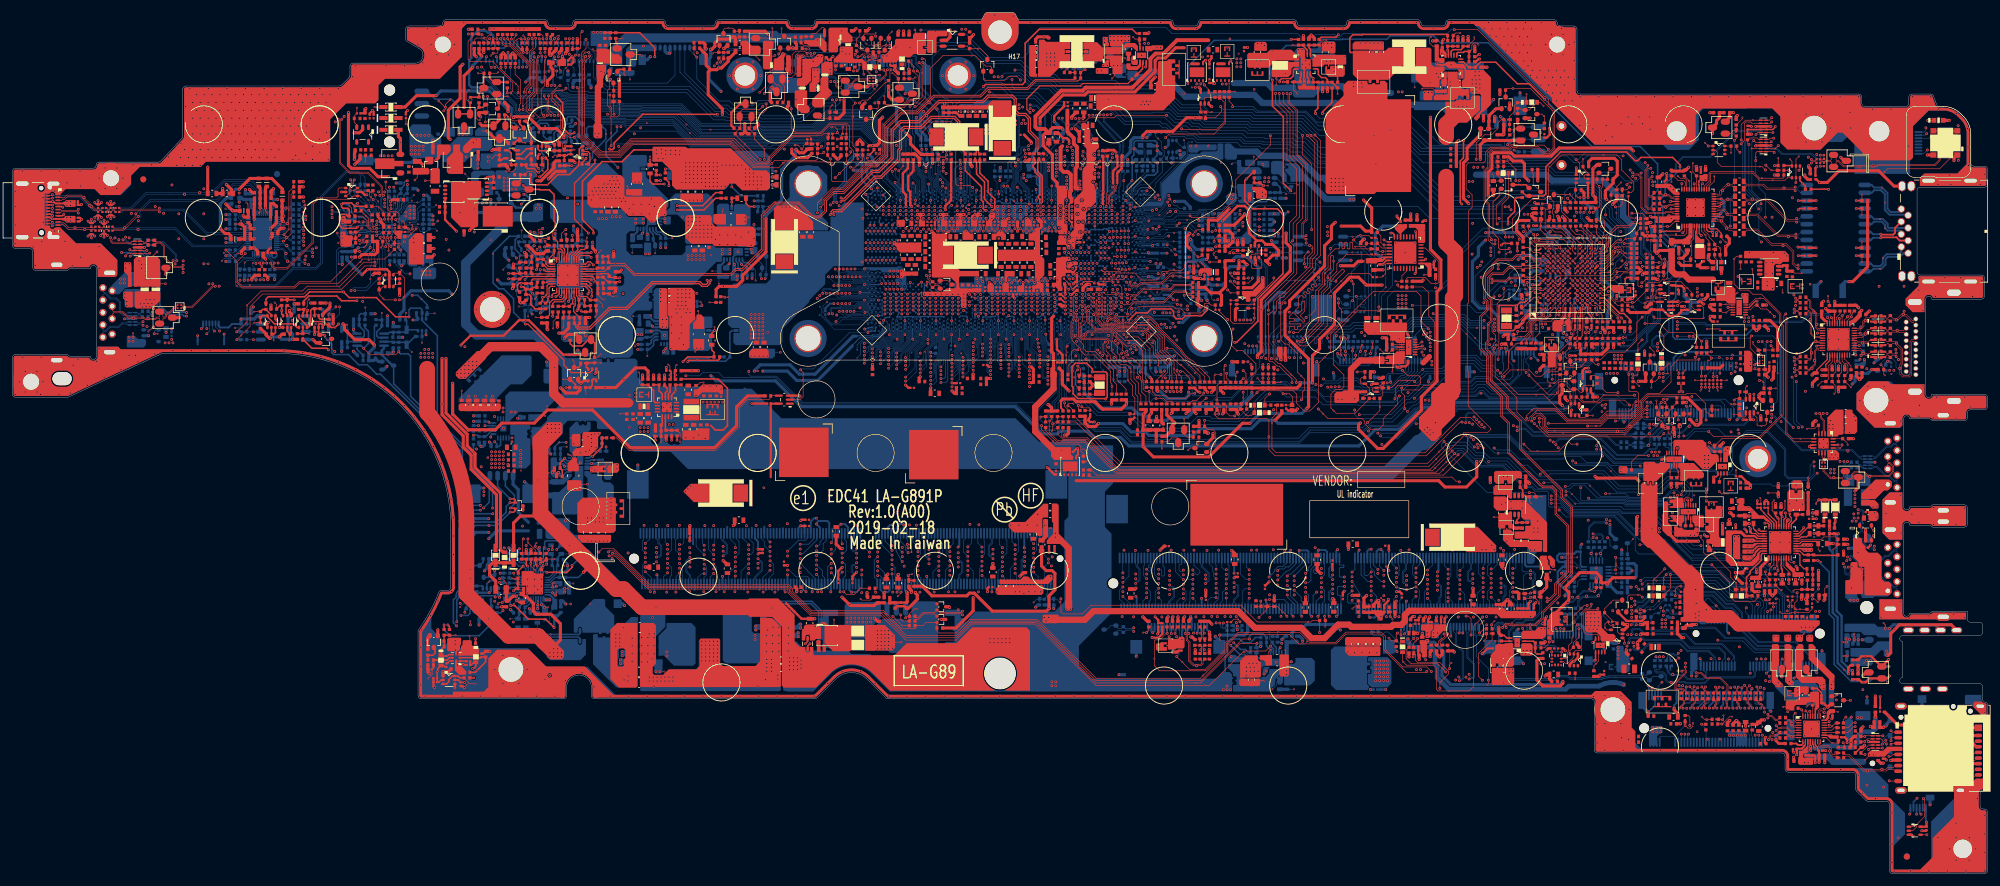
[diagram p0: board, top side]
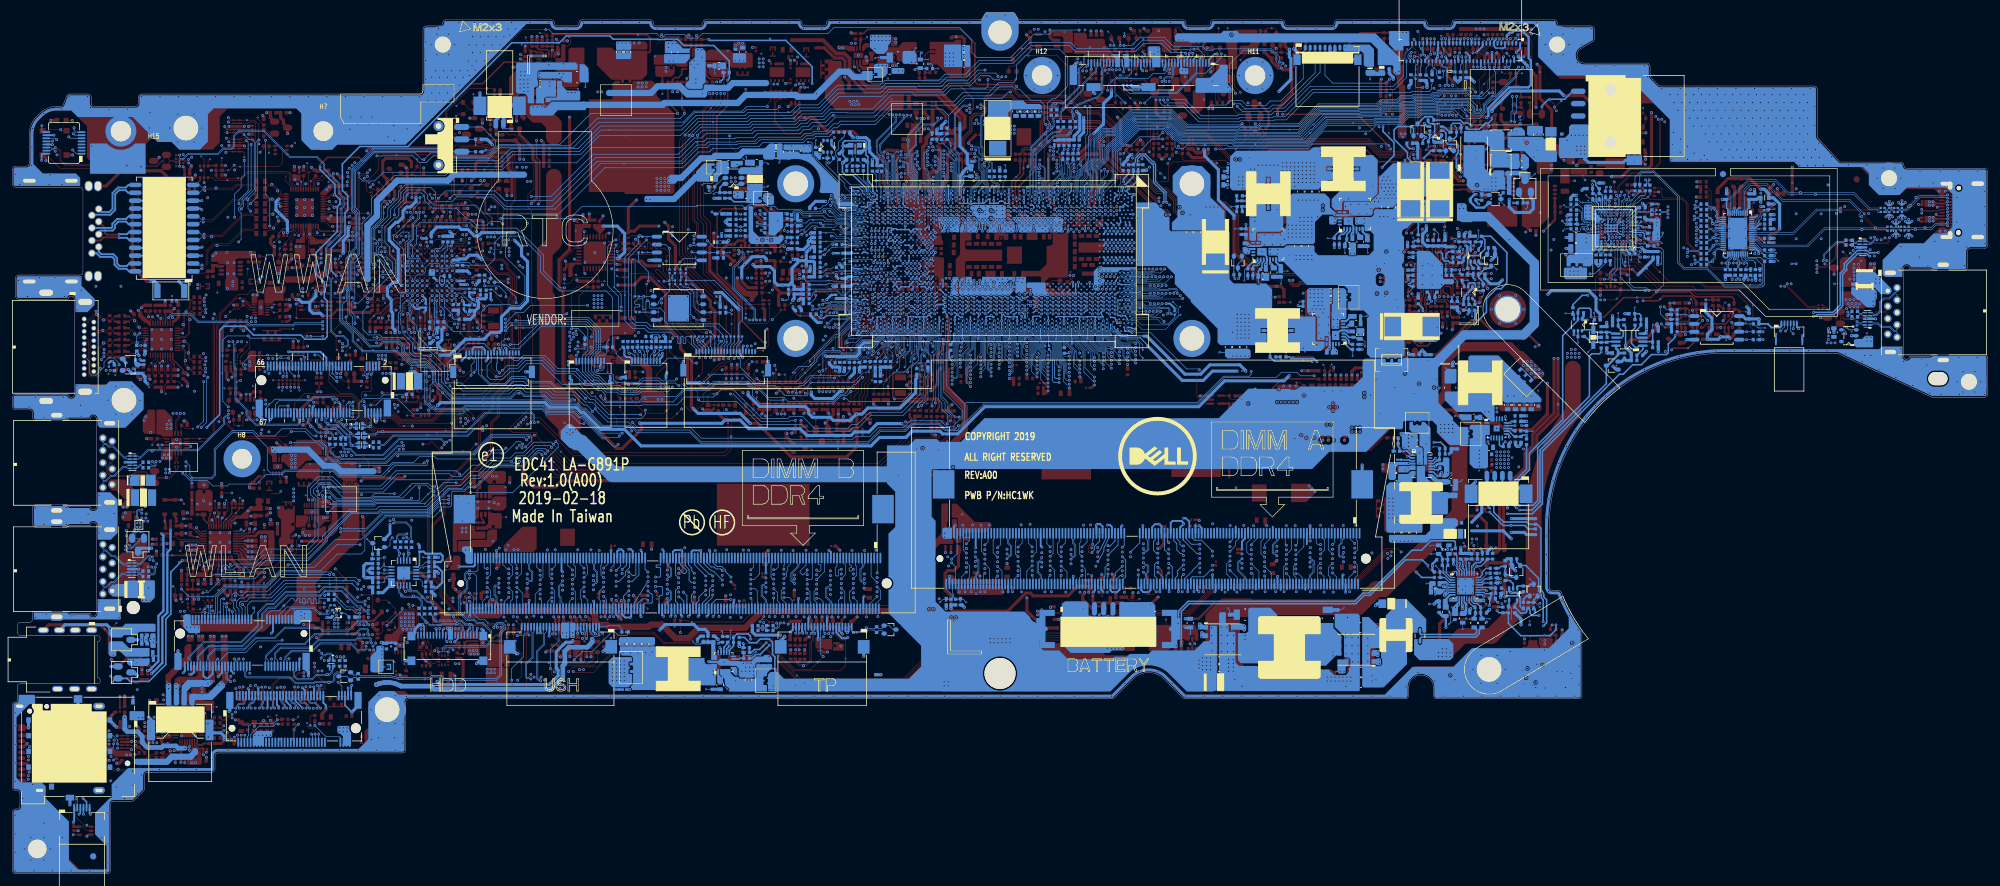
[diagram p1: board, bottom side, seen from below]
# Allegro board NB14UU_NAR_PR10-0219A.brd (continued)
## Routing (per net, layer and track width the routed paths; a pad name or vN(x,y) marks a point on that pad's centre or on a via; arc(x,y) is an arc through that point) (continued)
DP2_MIC_SBU1: length 81.1
  TOP w0.107: v1(18.97,100.85) 19.1,100.72 DT39.8 DT39.2 v1(21.71,100.72)
  TOP w0.254: v1(6.49,108.06) 6.47,108.06 6.45,108.07 JUSBC1.B8
  IN2 w0.102: v1(38.07,95.93) 37.66,96.34 26.95,96.34 22.57,100.72 v1(21.71,100.72) ; v1(6.49,108.06) 7.33,108.06 8.66,109.38 15.97,109.38 19.88,105.47 19.88,101.94 18.97,101.03 v1(18.97,100.85)
  IN3 w0.102: v1(38.07,95.93) 38.46,95.54 47.27,95.54 52.13,100.4 52.13,106.52 53.63,108.02 53.63,108.56 52.43,109.75 52.43,110.46 53.32,111.34 61.19,111.34 v1(61.59,110.94)
  BOTTOM w0.107: RT132.2 38.07,96.49 v1(38.07,95.93) ; v1(61.59,110.94) 61.72,110.81 RT108.2
DP2_MIC_SBU1_R: length 3.3
  BOTTOM w0.076: 61.84,107.9 61.84,107.51 61.67,107.34 61.67,107.03 61.58,106.94 61.58,106.56 UT5.K8
  BOTTOM w0.107: RT108.1 61.84,109.26 v2(61.84,108.37) 61.84,107.9
DP2_MIC_SBU2: length 80
  TOP w0.107: v1(22.18,100.29) 22.11,100.22 DT39.1 DT39.9 18.67,100.22 v1(18.28,99.83)
  TOP w0.254: JUSBC1.A8 8.08,106.32 v1(8.31,106.56)
  IN2 w0.102: v1(8.31,106.56) 9.57,106.56 10.11,107.1 10.11,107.37 10.49,107.76 11.7,107.76 11.95,107.5 16.76,107.5 19.27,104.98 19.27,104.05 19.17,103.94 18.77,103.94 18.67,103.84 18.67,103.64 18.77,103.54 19.17,103.54 19.27,103.44 19.27,102.58 18.05,101.37 18.05,100.06 v1(18.28,99.83) ; v1(36.76,95.9) 27.07,95.9 22.68,100.29 v1(22.18,100.29)
  IN3 w0.102: v1(36.76,95.9) 37.34,95.32 47.37,95.32 52.36,100.31 52.36,106.42 53.86,107.92 53.86,108.65 52.7,109.81 52.7,110.41 53.23,110.94 v1(60.9,110.94)
  BOTTOM w0.107: v1(36.76,95.9) RT133.2 ; RT109.2 v1(60.9,110.94)
DP2_MIC_SBU2_R: length 2.9
  BOTTOM w0.076: 61.53,107.9 61.53,107.46 61.49,107.42 61.49,107.11 61.33,106.94 UT5.L8
  BOTTOM w0.107: RT109.1 61.53,108.74 61.53,107.9
EDP_AUXN: length 15.8
  BOTTOM w0.076: 154.51,117.5 154.62,117.39 154.62,113.72 154.73,113.6 154.73,109.23 UC1.AH4
  BOTTOM w0.097: 154.51,117.5 154.46,117.55 154.46,117.59 152.59,119.46 152.59,119.51 152.14,119.96 151.58,120.21 v4(151.17,120.63) 150.95,120.85 150.95,121.68 151.06,121.79 151.06,122.36 CV1.1
EDP_AUXN_C: length 17.1
  BOTTOM w0.097: CV1.2 151.25,124.32 150.93,124.64 150.27,124.64 150.24,124.61 149.35,124.61 146.87,127.09 146.87,130.1 146,130.97 146,132.1 145.8,132.3 142.17,132.3 141.89,132.02 141.89,131.74 141.77,131.63 JEDP1.33
EDP_AUXP: length 15.8
  BOTTOM w0.076: UC1.AH3 154.4,109.31 154.25,109.31 154.15,109.41 154.15,109.55 154.25,109.65 154.51,109.65 154.57,109.71 154.57,113.54 154.45,113.65 154.45,117.32 154.27,117.5
  BOTTOM w0.097: 154.27,117.5 154.27,117.51 v4(152.22,119.56) 151.94,119.84 151.39,120.1 150.76,120.72 150.76,121.75 150.88,121.87 150.88,122.04 CV2.1
EDP_AUXP_C: length 17
  BOTTOM w0.097: CV2.2 150.36,123.71 150.57,123.91 150.94,123.91 151.07,124.04 151.07,124.24 150.89,124.42 v4(150.57,124.42) 149.27,124.42 146.68,127.01 146.68,130.03 145.82,130.89 145.82,132.03 145.73,132.12 142.24,132.12 142.08,131.95 142.08,131.77 142.28,131.57 JEDP1.34
EDP_BIA_PWM: length 196.2
  TOP w0.107: DV1.3 137.46,135.5 137.66,135.71 139.06,135.71 v1(139.43,135.34)
  IN2 w0.102: v1(139.43,135.34) 139,135.34 138.63,134.96 133.86,134.96 131.96,133.06 129.31,133.06 127.37,135 109.14,135 103.41,129.27 99.35,129.27 97.86,127.78 88.21,127.78 88.07,127.65 88.07,127.25 87.77,126.95 79.79,126.95 78.9,126.06 76.5,126.06 v1(76.07,125.63)
  IN3 w0.089: 144.76,101.55 167.54,101.55 170.04,99.05 172.26,99.05 172.37,99.16 173.84,99.16 174.66,99.98 174.66,100.72 175.38,101.45 175.38,102.1 175.65,102.37 176.59,102.37 176.84,102.63 176.84,103.02 177.03,103.21 178.44,103.21 v1(179.12,103.89)
  IN3 w0.102: 144.76,101.55 143.15,103.15 134.23,103.15 130.2,107.19 123.4,107.19 121.98,108.61 121.98,112.83 119.52,115.29 111.18,115.29 108.67,117.8 99.45,117.8 99.1,118.15 96.64,118.15 95.47,116.98 94.42,116.98 90.79,120.61 88.44,120.61 88.05,120.22 83.88,120.22 83.88,120.22 83.75,120.09 79.12,120.09 78.01,121.19 76.69,121.19 v1(76.39,121.49)
  BOTTOM w0.089: v1(179.12,103.89) UC1.CH11
  BOTTOM w0.107: v1(76.39,121.49) 76.39,122.78 76.07,123.11 v1(76.07,125.63) ; v1(139.43,135.34) v2(139.43,135.84)
EDP_COMP: length 10.2
  TOP w0.254: v1(157.29,107.19) 157.1,107.19 156.83,107.46 156.83,108.54 156.52,108.84 156.52,111.02 153.92,113.62 v2(153.92,114.22) RC8.2
  BOTTOM w0.089: UC1.AM6 v1(157.29,107.19)
EDP_HPD: length 102.1
  TOP w0.107: v1(190.72,103.18) 190.72,103.42 v2(191.11,103.81) 191.38,104.09 RC2.2 ; RV7.1 139.19,131.39 138.56,132.03 v1(138.22,132.03)
  IN2 w0.102: v1(142.14,126.62) 142.54,127.02 147.08,127.02 148.63,125.47 154.36,125.47 154.53,125.65 159.18,125.65 159.5,125.98 161.12,125.98 161.76,126.62 184.83,126.62 186.38,128.17 190,128.17 190.28,127.89 190.28,123.29 189.72,122.73 189.72,120.18 187.3,117.75 187.3,116.72 187.18,116.61 187.18,116.38 186.14,115.33 186.14,113.7 184.72,112.29 184.72,109.99 184.11,109.38 184.11,108.76 184.46,108.4 186.46,108.4 186.59,108.54 v1(186.62,108.54) 187.15,108.54 188.3,107.39 188.3,105.51 188.08,105.29 188.08,104.4 189.54,102.94 190.49,102.94 v1(190.72,103.18)
  BOTTOM w0.076: UC1.CM7 181.44,106.79 181.66,106.79 181.77,106.83 181.96,106.83 182.07,106.79 182.31,106.79 182.42,106.83 182.58,106.83 183.19,106.61 185.03,106.61 186.54,108.12 186.54,108.47 v1(186.62,108.54)
  BOTTOM w0.107: v1(142.14,126.62) 142.14,126.62 142.14,127.36 140.76,128.74 138.91,128.74 138.28,129.37 JEDP1.26 138.28,131.86 138.22,131.92 v1(138.22,132.03)
EDP_TXN0: length 16.5
  BOTTOM w0.076: UC1.AG4 154.13,108.64 154.13,109.15 153.95,109.32 153.74,109.32 153.67,109.39 153.6,109.57 153.6,109.76 153.63,109.85 153.63,110.13 153.6,110.22 153.6,110.46 153.82,110.68 153.82,116.29 152.64,117.48 152.64,117.49 152.63,117.5
  BOTTOM w0.097: 152.63,117.5 v4(151.78,118.35) 150.94,119.19 150.47,119.39 148.72,119.39 148.54,119.57 148.54,119.61 148.12,120.03 148.07,120.03 148.01,120.09 148.01,120.46 CV4.1
EDP_TXN0_C: length 12.6
  BOTTOM w0.097: JEDP1.36 143.28,130.46 143.12,130.31 143.12,129.16 143.09,129.13 143.09,126.31 143.89,125.51 144.35,125.39 145.26,125.07 147.05,124.31 147.76,123.75 147.92,123.54 148.01,123.12 147.89,122.82 147.89,122.23 147.85,122.2 147.85,121.91 CV4.2
EDP_TXN1: length 13.9
  BOTTOM w0.076: UC1.AG2 153.86,109.76 153.91,109.81 154.1,109.81 154.28,109.99 154.28,116.53
  BOTTOM w0.097: 154.28,116.53 154.28,116.74 v4(154.02,117) 153.33,117.68 153.33,117.73 152.92,118.15 152.87,118.15 151.34,119.68 150.62,119.97 149.94,119.97 149.79,120.13 149.79,120.27 CV6.1
EDP_TXN1_C: length 12.1
  BOTTOM w0.097: JEDP1.38 144.28,130.45 144.12,130.29 144.12,129.75 146.24,127.63 146.24,126.69 147.96,124.97 148.01,124.97 148.42,124.55 148.42,124.51 v4(149.34,123.59) 149.82,123.11 149.82,121.91 CV6.2
EDP_TXP0: length 16.6
  BOTTOM w0.076: UC1.AG3 153.93,108.94 153.93,108.74 153.85,108.66 153.72,108.66 153.58,108.8 153.58,109.19 153.43,109.53 153.43,109.79 153.46,109.88 153.46,110.1 153.43,110.19 153.43,110.52 153.66,110.75 153.66,116.23 152.52,117.36 152.51,117.36 152.5,117.37
  BOTTOM w0.097: CV3.1 147.83,120.13 147.83,120.01 v4(148.17,119.67) 148.64,119.2 150.43,119.2 150.83,119.03 151.42,118.45 151.42,118.4 151.84,117.98 151.88,117.98 152.5,117.37
EDP_TXP0_C: length 12.6
  BOTTOM w0.097: JEDP1.35 142.77,130.41 142.94,130.24 142.94,129.24 142.91,129.21 142.91,126.23 143.79,125.35 144.29,125.21 145.19,124.9 146.95,124.15 147.62,123.62 147.75,123.46 147.82,123.14 147.67,122.78 v4(147.67,122.53) 147.67,121.91 CV3.2
EDP_TXP1: length 13.9
  BOTTOM w0.076: UC1.AG1 153.79,110.25 153.79,110.04 153.86,109.98 154.03,109.98 154.11,110.06 154.11,116.53 154.06,116.59
  BOTTOM w0.097: 154.06,116.59 154.06,116.65 153.59,117.12 153.59,117.17 v4(152.97,117.78) 151.24,119.52 150.59,119.79 149.87,119.79 149.61,120.05 149.61,120.32 CV5.1
EDP_TXP1_C: length 12.1
  BOTTOM w0.097: JEDP1.37 143.77,130.42 143.93,130.27 143.93,129.67 146.05,127.55 146.05,126.62 v4(148.06,124.61) 148.98,123.69 148.98,123.64 149.39,123.23 149.44,123.23 149.63,123.03 149.63,121.91 CV5.2
EDRAM_OPIO_RCOMP: length 8.6
  TOP w0.381: v1(144.36,107.82) 144.33,107.85 144.33,109.74 143.82,110.25 v2(143.82,112.46) 143.82,113.17 144.65,113.99 RC108.1
  BOTTOM w0.203: UC1.L5 v1(144.36,107.82)
EMMC_RCOMP: length 8.7
  IN1 w0.203: v1(180.28,100.77) 180.83,100.77 181.1,101.04 181.8,101.04 182.9,99.94 184.85,99.94 v1(186.53,101.62)
  BOTTOM w0.203: v1(180.28,100.77) 180.35,100.9 UC1.CK15 ; RC10.1 185.95,101.69 186.46,101.69 v1(186.53,101.62)
EN_1.2V_RUN: length 1.1
  TOP w0.107: PR511.2 v2(279.14,97.74)
EN_1.05VALWP: length 6.6
  TOP w0.107: v2(236.79,134.01) 236.56,134.24 236.06,134.24 235.75,133.92 235.75,133.2 235.44,132.89 PC360.1
  TOP w0.254: PR302.1 PR312.2 235.28,132.5 235.31,132.53 PC360.1 234.54,132.89 234.37,132.72 233.48,132.72 233.3,132.54 PU301.11
EN_1.8VALW: length 4.2
  TOP w0.107: v1(202.12,111.2) v2(202.79,111.2)
  TOP w0.254: PR504.2 PR505.1 PC505.1 201.56,111.66 201.89,111.33 201.99,111.2 v1(202.12,111.2)
  BOTTOM w0.254: PU501.1 201.7,111.49 201.99,111.2 v1(202.12,111.2)
EN_1V_PRIM_CORE: length 4.9
  TOP w0.107: v2(212.24,134.74) 211.79,134.74 211.07,134.02 PR406.2
  TOP w0.254: PU402.13 209.66,133.25 209.42,133.49 PC411.1 PR407.1 PR406.2
EN_1VS_VCCIO: length 4.2
  TOP w0.107: PR402.2 v2(104.78,69.72)
  TOP w0.254: PU401.13 104.97,72.65 PC402.1 PR403.1 PR402.2
EN_2.5V_MEM: length 4.8
  TOP w0.107: v2(245.32,59.85) 245.09,60.08 PR513.2
  TOP w0.254: PR513.2 244.65,60.91 244.44,61.11 PU503.5 243.95,62.03 PC513.1 PR514.1
EN_INVPWR: length 174.4
  TOP w0.107: RE55.1 243.04,87.13 243.14,87.24 v1(243.14,87.64) 244.48,87.64 244.62,87.78 v2(244.62,88.25) 244.62,88.98 245.88,90.24 246.02,90.24 246.77,90.98 246.88,90.98 247.25,91.35 247.25,91.81 UE1.B2 ; QV2.2 124.02,132.73 v1(123.78,132.49)
  IN2 w0.089: 242.54,88.24 v1(243.14,87.64)
  IN2 w0.102: 242.54,88.24 242.5,88.28 242.5,91.8 242.41,91.89 241.56,91.89 241.24,92.22 241.24,94.24 241.31,94.31 241.31,94.74 240.98,95.07 240.98,95.98 242.69,97.69 242.69,101.91 242.97,102.2 242.97,104.44 242.55,104.86 242.55,105.98 242.69,106.12 242.69,108.96 242.16,109.49 242.16,110.51 237.7,114.97 202.84,114.97 194.52,123.29 194.52,124.86 193.52,125.87 193.52,127.93 192.21,129.23 185.78,129.23 184.45,127.9 164.2,127.9 163.41,128.69 162.68,128.69 160.95,126.96 157.17,126.96 157.01,126.79 156.42,126.79 155.81,127.4 155.81,130.18 153.99,132 150.05,132 145.77,127.71 139.9,127.71 v1(139.64,127.44)
  BOTTOM w0.107: v1(139.64,127.44) 139.64,127.14 138.56,126.06 130.93,126.06 127.62,129.37 126.32,129.37 123.78,131.91 v1(123.78,132.49)
EN_LCDPWR: length 5.4
  TOP w0.107: UV24.4 154.22,133.74 RV3.2 v2(155.99,133.35) 156.35,133.35 157.48,132.22 DV3.1
EN_PD_HV_1: length 159.4
  TOP w0.254: v1(92.65,115.63) 92.65,115.55 91.99,114.89 PR820.2 ; PR834.1 40.95,92.85 41.35,93.24 47.22,93.24 48,94.02 v1(53.5,94.02) 54.41,93.11 v2(56.66,93.11) 58.79,93.11 61.91,89.99 v1(64.07,89.99)
  IN1 w0.254: v1(64.07,89.99) 68.11,89.99 83.93,105.81 85.54,105.81 87.81,108.09 87.81,110.05 91.97,114.21 91.97,114.68 92.65,115.36 v1(92.65,115.63)
  IN2 w0.254: v1(73.08,42.24) 73.08,42.89 74.76,44.56 74.76,55.34 75.99,56.58 75.99,58.44 76.1,58.55 v1(76.1,59.1)
  IN3 w0.254: v1(82.8,96.02) 81.08,96.02 80.26,95.2 69.27,95.2 v1(64.07,89.99)
  BOTTOM w0.107: RT70.2 53.61,101.15 52.78,101.15 52.36,100.73 52.36,95.16 v1(53.5,94.02)
  BOTTOM w0.254: v1(76.1,59.1) 77.02,60.03 77.02,62.25 74.01,65.26 74.01,68 68.64,73.37 68.64,86.94 66.17,89.41 PQ813.2 66.17,90.62 PR846.1 66.18,91.13 65.92,91.39 64.32,91.39 64.07,91.13 v1(64.07,89.99) ; v1(82.8,96.02) 83.12,96.34 PR853.1 PR857.1 ; v1(73.08,42.24) 73.08,42.7 PR736.1
EN_PD_HV_1#: length 4
  TOP w0.107: v2(92.59,77.59) PR810.2
  TOP w0.254: PR810.2 PR851.2 93.66,78.89 PQ802.2 93.66,79.78 93.84,79.96 94.18,79.96 94.31,79.83 94.31,79.65 PQ802.3
EN_PD_HV_1_R: length 4.1
  BOTTOM w0.076: UT5.C2 58.08,102.56 57.71,102.56 57.67,102.52 57.56,102.52 56.84,101.8 56.4,101.8
  BOTTOM w0.112: 56.4,101.8 v2(56.12,101.8) 55.17,101.8 RT70.1
ENABLE_DS#: length 5
  TOP w0.089: RE550.1 RE549.2 256.85,90.24 256.75,90.35
  TOP w0.102: 256.75,90.35 256.05,91.05 256.05,91.48 255.72,91.81 255.25,91.81 UE1.L2
ENLDO_3V5V: length 160.4
  TOP w0.107: v1(199.83,37.92) 198.7,37.92 191.98,31.2 v2(189.53,31.2) 175.03,31.2 165.42,40.81 154.86,40.81 152.56,38.51 144.37,38.51 140.64,42.24 129.08,42.24 125.75,45.58 125.75,46.01 125.31,46.45 102.9,46.45 97.17,52.17 96.45,52.17 96.3,52.01 v1(96.3,52)
  IN1 w0.099: v1(96.3,52) 96.54,52.24 96.54,55.16 96.44,55.26 81.94,55.26 79.53,57.67 79.53,60.16 76.16,63.53 76.16,64.74 76.53,65.12 76.53,69.83 v1(77.26,70.56)
  BOTTOM w0.254: PU102.11 77.52,71.06 77.26,70.8 v1(77.26,70.56) ; v1(199.83,37.92) 199.83,38.36 200.21,38.75 202,38.75 PR102.1 PR103.1 202.57,36.76 203.24,36.1 PU100.11
ENVDD_PCH: length 100
  TOP w0.107: v1(130.55,107.71) 130.96,108.12 130.96,108.94 132.6,110.58 134.21,110.58 138.41,114.78 139.44,114.78 140.85,116.19 140.85,120.93 143.26,123.34 145.96,123.34 148.27,125.65 148.27,130.17 150.3,132.2 v2(154.92,132.2) 155.52,132.2 157.21,130.52 157.97,130.52 158.13,130.36 DV3.3
  IN3 w0.089: v1(178.41,103.82) 177.97,103.39 176.97,103.39 176.79,103.2 175.64,103.2 175.22,102.78 175.22,101.51 174.49,100.79 174.49,100.09 174.19,99.79 169.54,99.79 167.57,101.75 144.81,101.75
  IN3 w0.102: v1(130.55,107.71) 130.55,107.08 134.3,103.33 143.22,103.33 144.81,101.75
  BOTTOM w0.089: UC1.CG11 178.45,103.92 v1(178.41,103.82)
EOPIO_RCOMP: length 8.6
  TOP w0.381: RC109.1 v2(145.54,113.55) 144.71,112.72 144.71,110.5 145.03,110.18 145.03,108.07 v1(145.28,107.82)
  BOTTOM w0.203: UC1.N5 v1(145.28,107.82)
ESPI_ALERT#: length 102.5
  TOP w0.102: UE1.H7 v1(252.85,95.81)
  TOP w0.107: RC244.2 184.88,79.85 v2(185.5,80.46) 186.11,81.08 v1(186.11,81.26)
  IN1 w0.089: 246.6,96.57 246.8,96.57 246.93,96.44 248.38,96.44 248.53,96.59 251.81,96.59 252.31,96.09 252.57,96.09 v1(252.85,95.81)
  IN1 w0.099: v1(237.71,89.42) 237.85,89.56 237.85,90.58 239.9,92.63 240.96,92.63 241.99,93.66 241.99,94.83 242.68,95.51 243.05,95.51 244,96.46 244.76,96.46 244.87,96.57 246.6,96.57 ; v1(229.5,90.51) 226.68,87.69 223.43,87.69 220.28,84.54 220.28,83.32 220.05,83.09 217.95,83.09 215.35,80.49 207.22,80.49 204.71,77.98 202.31,77.98 201.61,77.29 199.92,77.29 198.94,78.27 198.41,78.27 197.24,79.44 194.51,79.44 194.23,79.72 187.72,79.72 187.02,80.42 187.02,80.45 186.21,81.26 v1(186.11,81.26) 185.19,82.18 184.78,82.18 181.41,85.55 180.85,85.55 180.6,85.3 178.41,85.3 177.56,86.15 177.56,87.06 174.62,90 174.46,90 174.25,90.22 174.25,90.52 174.28,90.56 174.28,92.54 173.86,92.96 v1(173.85,92.96)
  BOTTOM w0.076: v1(173.85,92.96) 173.78,92.96 UC1.BV28
  BOTTOM w0.107: v1(237.71,89.42) 235.46,89.42 234.55,90.34 229.67,90.34 v1(229.5,90.51)
ESPI_CLK: length 18.8
  TOP w0.102: v1(173.83,91.02) 173.99,90.86 173.99,89.16 175.02,88.13 177.69,88.13 179.62,86.19 181.55,86.19
  TOP w0.107: RC19.1 183.17,79.92 183.05,80.04 v2(183.05,80.75) 183.06,80.77 183.06,84.68 181.55,86.19
  BOTTOM w0.089: UC1.BV32 173.63,91.02 173.83,91.02 173.83,91.02 v1(173.83,91.02)
ESPI_CLK_5105: length 99.3
  TOP w0.102: UE1.G7 v1(252.05,95.81)
  TOP w0.107: RC19.2 CC316.1 184.1,78.55 184.1,78.29 184.19,78.2 184.19,77.79 184.7,77.28 186.33,77.28 186.76,76.85 189.61,76.85 190.4,77.64 v1(190.97,77.64) ; v1(210.94,75.1) v2(211.67,74.36) 212.51,73.53 218.02,73.53 218.44,73.11 218.44,72.72 219.33,71.83 220.74,71.83 221.42,72.51 221.42,73.54 223.77,75.89 223.77,76.9 223.45,77.21 223.45,78.57 223.79,78.91 227.06,78.91 227.45,79.29 227.45,80.21 227.2,80.46 225.41,80.46 v1(224.52,81.35)
  IN1 w0.099: v1(252.05,95.81) 251.51,95.81 250.93,96.4 249.29,96.4 249.29,96.4 248.61,96.4 248.46,96.24 246.85,96.24 246.7,96.09 245.07,96.09 244.93,95.95 244.17,95.95 243.25,95.03 v1(242.77,95.03) ; v1(190.97,77.64) 191.29,77.64 191.66,77.27 192.6,77.27 192.68,77.35 193.81,77.35 194.1,77.64 195.08,77.64 195.62,77.1 197.02,77.1 198.67,75.44 207.04,75.44 207.1,75.5 208.84,75.5 208.93,75.6 210.44,75.6 v1(210.94,75.1) ; v1(239.32,93.23) 238.76,92.67 236.64,92.67 233.39,89.42 230.56,89.42 229.42,88.28 229.42,84.3 227.86,82.74 225.91,82.74 v1(224.52,81.35)
  BOTTOM w0.107: v1(224.52,81.35) 223.77,81.35 223.49,81.64 JESPI.10 ; v1(239.32,93.23) 239.32,93.79 240.5,94.98 242.72,94.98 v1(242.77,95.03) 242.81,95.07 242.81,95.77 RE350.1
ESPI_CS#: length 107.2
  TOP w0.127: UE1.H6 252.84,95.02 v1(252.84,95.02)
  IN1 w0.099: v1(239.41,88.35) 239.41,88.34 239.84,87.91 239.84,87.51 240.1,87.25 242.46,87.25 242.47,87.25 243.4,87.25 243.58,87.42 243.58,87.89 243.34,88.13 243.34,90.29 245.29,92.23 251.4,92.23 251.82,92.65 251.82,93.78 252.84,94.8 v1(252.84,95.02)
  IN3 w0.089: 175.94,89.94 175.94,92.63 175.61,92.95 v1(175.55,92.95)
  IN3 w0.102: 175.94,89.94 175.94,89.53 176.67,88.8 177.37,88.8 179.59,86.58 179.59,85.36 178.59,84.37 178.59,83.83 178.75,83.68 178.75,83.3 179.19,82.86 182.7,82.86 183.83,81.73 186.98,81.73 188.62,80.1 198.29,80.1 198.68,80.49 211.24,80.49 v1(211.77,79.96)
  BOTTOM w0.089: UC1.CA28 175.53,93.02 v1(175.55,92.95)
  BOTTOM w0.107: v1(211.77,79.96) 212.08,79.65 214.12,79.65 214.58,80.1 217.26,80.1 217.96,79.41 221.51,79.41 221.99,79.89 221.99,80.57 222.28,80.86 224.61,80.86 224.99,81.24 JESPI.7 224.99,83.54 224.04,84.49 v2(224.04,86.48) 224.04,87.98 225.97,89.91 234.46,89.91 235.36,89.01 238.75,89.01 v1(239.41,88.35)
ESPI_IO0: length 87.4
  TOP w0.102: UE1.K5 254.42,94.23 v1(254.42,94.22)
  TOP w0.107: RC366.2 187.29,78.18 v1(187.59,77.89)
  IN1 w0.089: v1(254.42,94.22) 254.41,94.22 254,93.81 ; 243.78,86.98 243.79,87
  IN1 w0.099: 243.79,87 244.64,87.85 244.64,91.01 245.47,91.83 252.56,91.83 253.23,92.49 253.23,93.56 253.48,93.81 254,93.81 ; v1(239.68,85.43) 239.86,85.43 240.37,85.95 242.97,85.95 243.78,86.76 243.78,86.98
  IN3 w0.102: v1(212.45,78.64) 211.67,77.86 205.94,77.86 205.39,78.41 187.76,78.41 187.59,78.23 v1(187.59,77.89)
  BOTTOM w0.107: v1(212.45,78.64) 213.17,77.92 217.41,77.92 217.88,77.45 220.95,77.45 221.32,77.82 223.15,77.82 224.75,79.42 225.21,79.42 226.99,81.2 JESPI.3 226.99,83.65 226.1,84.53 226.1,88 226.57,88.47 233.61,88.47 v2(234.88,87.2) 237.17,84.91 238.64,84.91 239.16,85.43 v1(239.68,85.43)
ESPI_IO0_R: length 22.4
  TOP w0.089: 176.06,89.42 175.94,89.53 175.94,90.61 175.93,90.62 175.93,92 v1(175.56,92.37)
  TOP w0.102: 176.06,89.42 176.5,88.97 178.07,88.97 178.81,88.24 181.44,88.24 181.77,88.57 183.47,88.57 183.57,88.47 183.81,88.23 183.81,88.07 183.93,87.95
  TOP w0.107: 183.93,87.95 185.36,86.52 185.36,84.42 v2(186.74,83.04) 187.28,82.5 187.28,80.82 187.29,80.81 RC366.1
  BOTTOM w0.089: UC1.CA29 175.19,92.58 v1(175.56,92.37)
ESPI_IO1: length 90.1
  TOP w0.107: v1(187,77.9) 186.53,78.37 RC367.2
  TOP w0.127: v1(255.24,93.42) UE1.L4
  IN1 w0.099: v1(238.63,85.5) 238.63,84.72 239.39,83.96 241.48,83.96 244.13,86.6 244.13,86.92 244.84,87.63 244.84,90.92 245.55,91.63 252.65,91.63 253.25,92.24 253.78,92.24 254.05,92.5 254.05,92.79 254.27,93.01 254.84,93.01 v1(255.24,93.42)
  IN3 w0.102: v1(213.03,78.68) 212.64,79.07 212.3,79.07 211.52,78.29 206.02,78.29 205.54,78.76 187.59,78.76 187,78.18 v1(187,77.9)
  BOTTOM w0.107: v1(213.03,78.68) 213.43,78.28 217.56,78.28 218.03,77.81 220.8,77.81 221.17,78.18 223,78.18 224.6,79.78 225.06,79.78 226.49,81.21 JESPI.4 226.49,83.57 225.13,84.94 225.13,87.53 226.42,88.83 234.02,88.83 v2(236.29,86.56) 237.34,85.5 v1(238.63,85.5)
ESPI_IO1_R: length 22.5
  TOP w0.102: 183.83,87.32 183.46,87.69 183.27,87.69 182.77,88.19 181.68,88.19 181.53,88.04 178.72,88.04 178.01,88.75 176.18,88.75 175.38,89.55 175.38,90.14 175.21,90.31 175.21,90.58 175.02,90.77 175.02,92 v1(174.65,92.37)
  TOP w0.107: 183.83,87.32 184.05,87.32 185,86.37 185,84.27 186.92,82.35 v2(186.92,80.48) 186.92,79.89 186.83,79.81 186.83,79.81 RC367.1
  BOTTOM w0.089: UC1.BY29 v1(174.65,92.37)
ESPI_IO2: length 82.8
  TOP w0.107: v1(188.17,77.89) 188.06,78.01 RC368.2
  TOP w0.127: v1(252.08,95.02) 252.05,95.05 252.01,95.05 UE1.G6
  IN1 w0.099: v1(237.71,88.21) 238.2,88.7 238.2,90.43 240.04,92.28 241.89,92.28 243.54,93.92 244.2,93.92 245.06,94.78 245.06,95.4 245.27,95.61 246.47,95.61 246.65,95.43 247.87,95.43 247.88,95.44 248.2,95.44 248.22,95.42 248.98,95.42 248.98,95.42 251.29,95.42 251.69,95.02 v1(252.08,95.02)
  IN3 w0.102: v1(214.31,78.69) 214.31,78.43 212.91,77.04 206.75,77.04 206.12,76.41 195.26,76.41 194.73,76.94 194.39,76.94 193.88,76.42 189.64,76.42 v1(188.17,77.89)
  BOTTOM w0.107: v1(214.31,78.69) 217.66,78.69 218.18,78.17 220.65,78.17 221.03,78.54 222.85,78.54 224.45,80.14 224.91,80.14 225.99,81.22 JESPI.5 225.99,83.56 224.77,84.79 224.77,87.68 226.27,89.19 234.17,89.19 235.14,88.21 v2(236.55,88.21) v1(237.71,88.21)
ESPI_IO2_R: length 25.3
  TOP w0.089: 176,92.55 176,92.31 176.11,92.2 176.11,90.69 176.11,90.68 176.11,90.09 176.45,89.75 177.05,89.75 177.26,89.54
  TOP w0.102: 177.26,89.54 177.31,89.48 177.85,89.48 178.89,88.44 181.26,88.44 181.59,88.77 183.62,88.77 ; 176,92.55 176,93.75 175.77,93.98 175,93.98 v1(174.65,93.64)
  TOP w0.107: 183.62,88.77 185.72,86.67 185.72,84.57 187.64,82.65 v2(187.64,81.62) 187.64,80.97 188.06,80.55 RC368.1
  BOTTOM w0.089: UC1.BY27 v1(174.65,93.64)
ESPI_IO3: length 90.1
  TOP w0.102: v1(255.24,94.22) UE1.L5
  TOP w0.107: v1(186.37,77.95) 186.03,77.95 185.71,78.27 RC369.2
  IN1 w0.099: v1(255.24,94.22) 254.86,94.6 253.5,94.6 253.27,94.38 253.27,94.13 252.93,93.79 252.69,93.79 252.34,93.45 252.34,92.59 251.78,92.03 245.38,92.03 244.44,91.09 244.44,88 242.75,86.31 240.53,86.31 239.41,87.43 v1(239.41,87.77)
  IN3 w0.102: v1(211.38,78.88) 211.26,78.88 211.02,78.64 206.16,78.64 205.68,79.12 186.86,79.12 186.37,78.63 v1(186.37,77.95)
  BOTTOM w0.107: v1(239.41,87.77) 238.53,88.65 v2(238.34,88.65) 235.21,88.65 234.31,89.55 226.12,89.55 224.4,87.83 224.4,84.64 225.49,83.55 JESPI.6 225.49,81.23 224.76,80.5 224.3,80.5 222.7,78.9 220.88,78.9 220.5,78.53 218.33,78.53 217.15,79.7 214.69,79.7 214.27,79.28 211.95,79.28 211.54,78.88 v1(211.38,78.88)
ESPI_IO3_R: length 24.3
  TOP w0.089: 175.2,89.47 175.2,90.06 175.03,90.23 175.03,90.47 174.24,91.26 174.24,93.17 v1(173.83,93.58)
  TOP w0.102: 175.2,89.47 175.2,89.42 176.08,88.54 177.91,88.54 178.62,87.83 182.84,87.83 183.51,87.16
  TOP w0.107: 183.51,87.16 183.51,86.46 183.73,86.23 184.41,86.23 184.64,86.01 184.64,84.12 v2(184.99,83.76) 186.55,82.2 186.55,81.01 185.71,80.16 RC369.1
  BOTTOM w0.089: v1(173.83,93.58) 173.81,93.59 UC1.BV27
ESPI_RESET#: length 118.8
  TOP w0.102: v1(254.44,95.01) 254.44,95.02 UE1.K6
  TOP w0.107: v1(195.21,80.67) v2(194.29,80.67) 194.11,80.5 RC833.1
  IN3 w0.089: v1(175.55,93.56) 175.64,93.56 176.11,93.09 176.11,90.13
  IN3 w0.102: v1(208.53,82.53) 206.85,80.85 198.53,80.85 198.14,80.45 195.78,80.45 195.56,80.67 v1(195.21,80.67) 189.78,80.67 188.36,82.09 183.72,82.09 182.78,83.04 179.27,83.04 178.92,83.38 178.92,83.75 178.77,83.91 178.77,84.29 179.76,85.28 179.76,85.75 180.72,86.7 180.72,87.4 179.13,88.99 176.73,88.99 176.21,89.51 176.21,90.04 176.11,90.13
  BOTTOM w0.089: UC1.CA27 175.52,93.66 v1(175.55,93.56) ; v1(254.44,95.01) 254.02,95.43 254.02,96.42 253.59,96.85 252.79,96.85 252.28,97.36 252.28,97.99 251.65,98.63 251.46,98.63 251.45,98.62 250.24,98.62 250.06,98.44 250.06,98.1 249.79,97.82 249.48,97.82 249.47,97.83 248.7,97.83 248.35,98.17 248.35,98.34 248.22,98.48 248.22,98.48 248.13,98.57 247.7,98.57 247.52,98.75 246.67,98.75 246.67,98.76 246.6,98.76
  BOTTOM w0.107: v1(208.53,82.53) 209,82.53 209.79,83.31 213.16,83.31 214.39,82.08 219.05,82.08 219.91,82.94 220.44,82.94 221.55,84.04 221.55,84.51 222.11,85.08 RE560.2 222.11,93.14 223.15,94.18 230.69,94.18 233.78,97.27 233.78,99.83 236.99,103.04 240.15,103.04 241.12,102.07 241.12,99.37 242.14,98.35 244.91,98.35 245.31,98.76 246.6,98.76
ESPI_RESET#_R: length 4.5
  BOTTOM w0.107: JESPI.8 224.49,83.49 224.18,83.8 223.41,83.8 223.03,84.19 RE560.1 223.03,85.91 v2(222.73,86.21)
FB_1.05VALWP: length 3.1
  TOP w0.254: PR311.1 PR308.2 PR306.2 v1(231.83,133.08) 231.95,132.96 PU301.14
FB_1.8VALW: length 4.7
  BOTTOM w0.107: PR506.1 205.52,110.07 v2(205.77,109.81)
  BOTTOM w0.254: PR501.2 PC503.2 PR506.1 204.78,110.88 204.18,111.49 PU501.6
FB_3V: length 4
  BOTTOM w0.107: v2(203.02,39.29) 203.02,37.93 203.51,37.44 PC113.1
  BOTTOM w0.254: PC113.1 203.51,37.19 204.14,36.57 PU100.13
FB_5V: length 1.6
  BOTTOM w0.254: PU102.13 77.01,71.96 76.63,71.57 PC127.1
FB_A_GT: length 4.6
  TOP w0.203: PU602.17 90.32,93.06 90.51,92.88 v2(90.51,92.73) 90.51,92.26 PR648.2 PR645.2 PR650.1
FB_B_IA: length 5.2
  TOP w0.203: PU602.5 v2(85.33,96.92) 83.95,96.92 PR622.2
  TOP w0.254: PR622.2 83.79,97.84 PR623.2 PR621.2
FB_C_SA: length 6.2
  TOP w0.107: v2(95.64,92.8) 95.35,92.8 94.56,93.58 PR652.1
  TOP w0.203: PR649.1 94.48,95.48 93.96,96 93.96,96.23 93.67,96.52 PU602.25
  TOP w0.254: PR652.1 PR646.1 94.56,95.43 PR649.1
FB_DDR: length 4.7
  BOTTOM w0.107: PR204.2 88.79,68.98 v2(89.52,68.98)
  BOTTOM w0.254: PU200.16 89.5,66.28 89.12,66.65 88.98,66.65 88.69,66.94 PR206.1 PC208.2 PR204.2
FBS_1V_PRIM_CORE: length 4.7
  TOP w0.107: v2(207.55,126.08) 206.9,126.73 206.9,127.9 206.97,127.96
  TOP w0.254: PU402.5 208.16,128.8 208.02,128.66 PR424.1 208.01,127.96 PR423.1
FBS_1VS_VCCIO: length 3.2
  TOP w0.254: PR421.2 PR422.1 107.12,77.98 v2(107.1,77.96) 106.47,77.33 PU401.5
FCCM1_IA: length 2.4
  BOTTOM w0.254: PR659.2 118.68,98.12 118.51,98.3 117.93,98.3 v1(117.78,98.45) 117.78,98.62 117.42,98.97 PU610.2
FCCM2_IA: length 2.3
  BOTTOM w0.254: PU613.2 103.44,103.92 104.04,103.32 104.45,103.32 104.71,103.07 PR671.2
FCCM_A_GT: length 15
  TOP w0.203: v1(92.97,93.69) 92.96,93.69 92.96,93.67 93.13,93.84 93.13,94.32 92.53,94.92 PU602.21
  IN1 w0.254: v1(92.97,93.69) 93.08,93.8 93.85,93.8 94.1,93.55 94.1,91.91 97.16,88.86 100.48,85.54 v1(101.03,85.54)
  BOTTOM w0.254: PR662.1 v1(101.03,85.54)
FCCM_B_IA: length 46.2
  TOP w0.203: PU602.11 87.92,93.98 87.72,93.77 87.4,93.77 87.14,93.52 v1(87.14,93.27)
  IN3 w0.254: v1(87.14,93.27) 87.14,98.5 90.22,101.57 90.88,101.57 92.33,103.02 97.74,103.02 99.59,101.17 v1(104.71,101.17) 105.41,101.86 106.8,101.86 107.88,100.78 107.88,98.25 108.89,97.24 117.66,97.24 v1(118.68,96.22)
  BOTTOM w0.254: PR659.1 v1(118.68,96.22) ; PR671.1 v1(104.71,101.17)
FCCM_C_SA: length 141.6
  TOP w0.203: v1(93.15,98.37) 92.9,98.12 PU602.29
  TOP w0.254: PR679.2 181.57,135.79 180.89,136.47 165.86,136.47 163.58,134.19 163.58,127.98 163.14,127.54 v2(159.93,127.54) 157.18,127.54 v1(156.84,127.2)
  IN2 w0.254: v1(156.84,127.2) 156.12,127.92 156.12,130.3 154.12,132.3 149.93,132.3 146.54,128.92 143.9,128.92 143.25,128.27 138.35,128.27 138.12,128.5 134.96,128.5 133.73,127.26 124.86,127.26 124.26,127.86 121.61,127.86 119.64,125.89 116.97,125.89 114.7,128.15 112.71,128.15 111.21,126.65 103.53,126.65 97.66,120.78 v1(97.66,120.73) ; v1(97.8,114.14) 98.52,113.42 101.66,113.42 104.58,110.5 104.58,104.47 102.61,102.5 100.13,102.5 95.12,97.48 93.4,97.48 93.15,97.74 v1(93.15,98.37)
  BOTTOM w0.254: v1(97.66,120.73) 97.66,119.96 95.89,118.19 95.89,116.06 v1(97.8,114.14)
FCCM_GT: length 2.3
  BOTTOM w0.254: PR662.2 102.93,85.54 103.19,85.79 103.19,86.2 103.78,86.8 PU612.2
FCCM_SA: length 2.7
  TOP w0.107: PR679.1 181.35,134.87 v2(181.02,135.2)
  TOP w0.254: PU614.7 182.14,134.1 182.05,134.19 PR679.1
FFS_INT2: length 139.9
  TOP w0.107: LGA1.11 250.57,34.24 250.84,33.97 251.18,33.97 252.22,35.01 QN1.2 252.22,35.78 252.5,36.06 253.38,36.06 253.49,36.17 253.49,42.19 254.2,42.91 254.77,42.91 v2(254.88,43.03) 255.02,43.17 v1(255.02,43.53)
  IN1 w0.089: v1(184.8,107.35) 185.48,107.35 186.94,105.89 188.48,105.89 189.24,105.13 191.11,105.13
  IN1 w0.099: v1(198.1,103.99) 196.05,103.99 194.36,105.67 192.78,105.67 192.23,105.13 191.11,105.13
  IN2 w0.102: v1(255.02,43.53) 255.02,43.83 257.16,45.97 257.16,52.5 258.94,54.29 258.94,58.3 255.21,62.03 255.21,64.11 253.34,65.98 252.18,65.98 250.1,68.07 250.1,69.13 248.73,70.5 241.93,70.5 232.41,80.01 232.41,80.46 231.75,81.12 231.75,88.49 231.21,89.02 225.36,89.02 222.06,85.73 212.37,85.73 211.39,86.71 210.55,86.71 207.22,90.04 207.22,91.5 202.85,95.88 202.85,97.3 201.96,98.18 201.96,99.37 199.32,102.01 199.32,102.77 v1(198.1,103.99)
  BOTTOM w0.076: UC1.CP6 182.63,107.43 182.68,107.48 182.86,107.54 184.61,107.54 v1(184.8,107.35)
  BOTTOM w0.107: RC726.2 197.7,103.58 v1(198.1,103.99)
FFS_INT2_Q: length 5.8
  TOP w0.107: v1(253.04,39.6) v2(253.04,38.58) 253.04,38.21 252.14,37.3 RN1.2 251.57,36.01 QN1.3
  BOTTOM w0.107: v1(253.04,39.6) 253.04,39.45 JSATA1.19
FIVR_EN: length 3.4
  TOP w0.107: RC235.1 RC236.1 RC217.1 76.89,134.47 76.65,134.71 76.65,135.2 77.01,135.56 v2(77.33,135.56)
FIVR_EN_R: length 16.9
  TOP w0.107: v2(77.27,132.21) v1(77.66,132.6) 78.31,132.6 78.42,132.71 RC126.2 RC132.1 RC217.2
  IN3 w0.102: v1(89.37,134.94) 89.35,134.94 88.8,134.39 86.46,134.39 86.18,134.11 85.58,134.11 85.11,133.64 78.7,133.64 v1(77.66,132.6)
  BOTTOM w0.107: JXDP1.45 v1(89.37,134.94)
FPR_DET#: length 86
  TOP w0.107: v1(284.58,116.56) 284.45,116.69 DT41.1 DT41.9 281.8,116.69 281.59,116.48 v2(281.59,115.78) v1(281.59,115.26)
  TOP w0.127: v1(248.85,98.2) 248.86,98.2 UE1.D9
  IN3 w0.102: v1(283.15,106.08) 283,106.23 277.48,106.23 276.52,105.28 268.87,105.28 268.59,105 266.58,105 265.82,105.76 264.33,105.76 263.61,106.49 262.23,106.49 261.85,106.11 260.97,106.11 259.96,105.1 256.27,105.1 255.66,104.49 251.03,104.49 248.2,101.66 v1(248.2,101.46) ; v1(309.32,116.96) 305.04,116.96 303.16,115.09 299.74,115.09 297.9,116.93 284.95,116.93 v1(284.58,116.56)
  BOTTOM w0.089: v1(248.85,98.2) 249.23,98.58 249.23,100.32 248.72,100.82
  BOTTOM w0.107: v1(281.59,115.26) 281.59,112.86 282.1,112.35 282.1,110.89 283.15,109.84 v1(283.15,106.08) ; RE606.1 247.96,101.61 248.12,101.46 v1(248.2,101.46) 248.56,101.46 248.72,101.29 248.72,100.82 ; JFPBTN1.1 308.7,116.35 v1(309.32,116.96)
FPR_LOW_PWR_MODE#: length 88.6
  TOP w0.107: v1(281.28,118.49) 281.58,118.19 DT41.7 DT41.4 283.98,118.19 v1(284.09,118.3) ; v1(254.61,101.59) 254.44,101.42 254.44,100.61 UE1.K12 ; RE708.1 254.75,107.37 v1(254.75,106.88)
  IN2 w0.102: v1(254.75,106.88) 254.75,105.57 254.11,104.92 254.11,102.34 254.61,101.84 v1(254.61,101.59)
  IN3 w0.102: v1(284.09,118.3) 284.54,118.3 285.9,119.66 285.9,121.35 288.38,123.84 293.82,123.84 295.18,122.48 295.18,120.29 299.93,115.54 302.93,115.54 305.98,118.59 309.44,118.59 v1(309.94,119.09) ; v1(254.75,106.88) 255.24,107.36 259.42,107.36 260.07,108.02 262.71,108.02 263.08,107.64 267.45,107.64 268.17,108.35 273.47,108.35 273.66,108.54 279.88,108.54 280.14,108.81 281.92,108.81 v1(282.46,108.28)
  BOTTOM w0.107: v1(282.46,108.28) 282.46,108.88 280.97,110.36 280.97,118.19 v1(281.28,118.49) ; v1(309.94,119.09) 309.7,118.85 JFPBTN1.11
FPR_PWR_EN#: length 41.1
  TOP w0.107: RE704.1 261.46,101.82 260.39,101.82 v1(260.36,101.85) ; UE1.M11 255.68,99.41 256.1,99.83 257.52,99.83 257.96,100.27 257.96,101.14 259.25,102.44 v1(259.77,102.44) ; RZ380.2 278.44,118.81 v1(278.16,118.53)
  IN3 w0.102: v1(259.77,102.44) v1(260.36,101.85) 260.39,101.82 266.63,101.82 269.17,104.37 277.17,104.37 v1(277.48,104.67)
  BOTTOM w0.107: v1(278.16,118.53) v2(278.16,110.79) 278.16,109.8 277.48,109.12 v1(277.48,104.67)
FPR_PWR_EN#_R: length 4.5
  TOP w0.107: v2(279.43,122.21) 279.43,121.99 CZ200.1 RZ380.1 278.01,120.14 277.48,119.61 QZ18.2
FPR_RST#: length 185.3
  TOP w0.107: v1(237.45,31.25) 236.84,31.86 v2(236.84,34.11) 236.84,35.61 239.02,37.79 RZ1411.1 ; v1(280.49,117.83) 280.26,118.07 RZ1392.1 280.56,118.91 281.8,118.91 282.02,118.69 DT41.6 DT41.5 283.73,118.69 283.91,118.86 v1(284.49,118.86)
  IN2 w0.102: v1(237.45,31.25) 239.22,29.48 256.33,29.48 258.03,31.19 265.74,31.19 267.32,32.76 267.32,37.18 269.63,39.49 269.63,44.9 268.58,45.96 268.58,48.47 267.8,49.25 267.8,50.67 267.41,51.06 267.41,63.84 270.31,66.75 270.31,70.3 270.72,70.71 270.72,74.54 271.44,75.26 271.44,76.03 270.61,76.86 270.61,84 270.29,84.32 270.29,89.45 270.71,89.87 271.75,90.91 271.75,96.62 271.27,97.1 271.27,98.81 274.55,102.09 v1(275.92,102.09)
  IN3 w0.102: v1(284.49,118.86) 285.67,120.04 285.67,121.45 288.29,124.06 293.92,124.06 295.41,122.57 295.41,120.4 300.04,115.77 302.84,115.77 306.06,119 309.22,119 309.72,119.5 311.03,119.5 v1(311.9,118.63) ; v1(275.92,102.09) v1(282.52,102.09)
  BOTTOM w0.107: v1(282.52,102.09) 282.1,102.51 282.1,106.78 282.53,107.21 282.53,107.58 281.96,108.15 281.96,109.04 280.49,110.51 280.49,117.83 v1(280.49,117.83) ; JFPBTN1.12 312.12,118.85 v1(311.9,118.63)
FPR_RST#_USH: length 4.5
  TOP w0.107: v1(237.5,38.47) 237.84,38.81 RZ1411.2 238.11,38.05 v2(237.71,37.65)
  BOTTOM w0.107: JUSH1.25 236.27,38.81 236.62,38.47 v1(237.5,38.47)
FPR_SCAN_INT#: length 86.6
  TOP w0.107: v1(284.16,121.5) 283.93,121.27 DT42.4 DT42.7 280.99,121.27 280.78,121.49 279.99,121.49 279.76,121.26 279.76,118.48 v1(279.24,117.96) ; v1(255.34,106.88) 255.75,107.29 RE709.2 256.1,107.55 256.33,107.78 v3(256.33,111.07) 255.95,111.45 RE825.1 255.95,112.95 QE20.3
  IN3 w0.102: v1(284.16,121.5) 284.96,121.5 287.98,124.52 294.11,124.52 295.87,122.76 295.87,120.59 300.23,116.23 302.65,116.23 306.63,120.21 308.76,120.21 v1(309.09,120.53) ; v1(255.34,106.88) 255.57,107.11 259.58,107.11 260.24,107.77 262.63,107.77 262.99,107.41 267.37,107.41 267.74,107.04 269.06,107.04 270.15,108.13 273.57,108.13 273.76,108.32 280.54,108.32 v1(280.58,108.28)
  BOTTOM w0.107: JFPBTN1.15 308.82,119.85 309.09,120.11 v1(309.09,120.53) ; v1(279.24,117.96) 279.5,117.7 279.5,109.36 v1(280.58,108.28)
FPR_SCAN_INT#_EC: length 149.5
  TOP w0.089: v1(255.24,97.42) 254.85,97.03 UE1.L8
  TOP w0.107: v1(230.57,29.94) 230.57,30.88 v2(230.68,30.99) 231.96,32.27 231.96,32.73 230.54,34.16 226.94,34.16 226.66,34.43 226.66,35.34 RZ114.1 ; QE20.1 257.64,113.39 RE826.2 RE825.2 256.87,110.98 256.61,110.73 256.61,106.06 257.18,105.48 257.18,103.81 256.98,103.6 v1(256.98,102.94)
  IN2 w0.102: v1(230.57,29.94) 231.04,29.47 234.78,29.47 236.97,31.66 237.71,31.66 237.95,31.42 237.95,31.07 239.31,29.71 256.23,29.71 257.94,31.42 260.96,31.42 265.77,36.23 265.77,43.08 266.73,44.04 266.73,48.52 267.34,49.13 267.34,50.48 266.95,50.87 266.95,64.27 267.68,65 267.68,71.97 267.98,72.27 267.98,78.17 267.8,78.35 267.8,96.19 264.41,99.58 264.41,100.27 260.4,104.29 258.33,104.29 v1(256.98,102.94)
  BOTTOM w0.089: v1(255.24,97.42) 254.86,97.8 254.86,98.42 255.03,98.6 255.36,98.6 255.58,98.82 255.58,99.46 255.6,99.48 255.6,99.68
  BOTTOM w0.107: 255.6,99.68 255.6,101.96 255,102.56 255,103.55 255.14,103.69 256.12,103.69 256.87,102.94 v1(256.98,102.94)
FPR_SCAN_INT#_EC_R: length 3.9
  TOP w0.107: v1(226.98,38) 226.98,37.88 v2(226.64,37.54) 226.35,37.25 RZ114.2
  BOTTOM w0.107: v1(226.98,38) 226.52,38.45 226.52,39.12 226.78,39.38 JUSH1.6
FPR_SSO_EN#: length 102.4
  TOP w0.107: RE706.1 253.34,106.97 v1(253.26,106.89) ; v1(284.17,122.18) 283.76,121.77 DT42.5 DT42.6 v2(281.14,121.77) 279.95,121.77 279.24,121.07 v1(279.24,118.58)
  TOP w0.127: UE1.H9 v1(252.85,98.21)
  IN3 w0.102: v1(284.17,122.18) 285.28,122.18 287.84,124.75 294.2,124.75 296.1,122.86 296.1,120.69 300.32,116.46 302.55,116.46 307.23,121.13 314.05,121.13 v1(314.3,120.89) ; v1(253.26,106.89) 253.26,106.42 254.15,105.53 255.47,105.53 255.76,105.83 259.69,105.83 261.01,107.15 262.29,107.15 262.5,106.95 265.58,106.95 267.08,105.46 268.13,105.46 269.56,106.88 275.22,106.88 275.41,107.07 v1(280.56,107.07)
  BOTTOM w0.089: 254.92,99.68 254.63,99.39 253.49,99.39 252.85,98.75 252.85,98.22 v1(252.85,98.21)
  BOTTOM w0.107: v1(280.56,107.07) 281,107.5 281,108.99 279.75,110.24 279.75,118.16 279.33,118.58 v1(279.24,118.58) ; v1(253.26,106.89) 253.26,105.92 254.24,104.93 254.24,102.53 255.02,101.75 255.02,99.78 254.92,99.68 ; JFPBTN1.16 314.21,119.85 314.3,119.94 v1(314.3,120.89)
FPR_UEFI_MGMT#: length 92.9
  TOP w0.107: v1(284.36,119.77) DT42.1 DT42.9 281.94,119.77 v1(281.63,119.47) ; UE1.K9 v1(254.45,98.21) ; v1(253.84,106.88) 254.12,107.16 RE707.1
  IN3 w0.102: v1(309.2,119.59) 306.33,119.59 302.74,116 300.13,116 295.64,120.5 295.64,122.67 294.01,124.29 288.08,124.29 285.26,121.47 285.26,120.06 284.97,119.77 v1(284.36,119.77) ; v1(253.84,106.88) 253.84,106.88 254.25,106.47 254.48,106.47 254.89,106.06 259.59,106.06 260.92,107.38 262.39,107.38 262.59,107.18 267.28,107.18 267.65,106.81 269.16,106.81 269.46,107.11 275.12,107.11 275.31,107.3 280.09,107.3 280.32,107.53 282,107.53 v1(282.1,107.43)
  BOTTOM w0.089: v1(254.45,98.21) 254.45,98.48 254.83,98.87 254.83,99.19 255.25,99.62 255.25,99.68
  BOTTOM w0.107: v1(309.2,119.59) 308.96,119.35 JFPBTN1.13 ; v1(253.84,106.88) 253.55,106.59 253.55,105.95 254.48,105.03 254.48,102.63 255.25,101.85 255.25,99.68 ; v1(282.1,107.43) 281.71,107.82 281.71,108.82 279.98,110.55 279.98,118.39 280.25,118.65 280.82,118.65 v1(281.63,119.47)
FTPBTN1.10: length 50.1
  TOP w0.107: T418.1 302.89,113.93 311.3,113.93 313.33,115.96 313.33,117.93 312.85,118.41 v1(312.54,118.41) ; T421.1 280.94,117.19 DT41.8 DT41.2 284.75,117.19 T422.1 v1(285.24,117.66)
  IN3 w0.102: v1(285.24,117.66) 285.73,117.17 297.97,117.17 299.83,115.31 303.03,115.31 305.92,118.21 312.34,118.21 v1(312.54,118.41)
  BOTTOM w0.107: v1(312.54,118.41) 312.6,118.35 JFPBTN1.10
GPD7: length 14.2
  BOTTOM w0.076: UC1.BV35 172.89,88.44 172.89,88.21 172.85,88.1 172.85,87.92 172.87,87.84 172.87,87.47 172.69,87.28 172.69,86.65 172.73,86.61 172.73,85.12 173,84.84 173,84.1 173.76,83.34 173.76,82.96 173.68,82.88 173.68,82.23 174.44,81.46 174.59,81.46 175.13,80.92 176.76,80.92 v2(177.85,79.84) 178.16,79.52 RC95.1 RC454.2
GPP_A7: length 21.5
  TOP w0.089: v1(176.49,90.46) 177,89.95 177.14,89.95 177.26,89.84
  TOP w0.102: 183.93,88.97 183.86,89.04 181.36,89.04 180.96,88.65 178.97,88.65 177.94,89.69 177.41,89.69 177.26,89.84
  TOP w0.107: 183.93,88.97 186.08,86.82 186.08,84.73 188.58,82.23 v2(188.79,82.23) 190.98,80.05 RC841.1
  BOTTOM w0.089: v1(176.49,90.46) 176.48,90.46 UC1.CC32
GPP_A8: length 22.4
  TOP w0.107: v1(188.68,81.17) 189.08,81.17 v2(189.77,80.48) 190.15,80.1 RC849.1
  IN1 w0.099: v1(174.65,91.72) 175.04,91.33 175.04,89.99 177.26,87.77 177.45,87.77 177.45,87.77 178.02,87.77 178.02,87.77 181.18,87.77 182.82,86.13 182.85,86.13 184.01,84.97 185.05,84.97 188.68,81.34 v1(188.68,81.17)
  BOTTOM w0.089: UC1.BY30 v1(174.65,91.72)
GPP_A13: length 4.4
  BOTTOM w0.076: T380.1 173.01,85.23 173.01,86.42 173.42,86.83 173.42,87.4 173.35,87.47 173.35,87.78 173.34,87.85 173.36,87.9 173.36,88.13 173.33,88.21 173.33,88.45 173.37,88.57 173.37,89.05 UC1.BV34
GPP_A15: length 16.7
  TOP w0.102: v1(174.61,90.37) 174.94,90.05 174.94,89.36 175.97,88.33 177.84,88.33 178.54,87.63 182.75,87.63 183.23,87.16 183.23,86.15
  TOP w0.107: 183.23,86.15 184.28,85.1 184.28,83.97 185.1,83.15 T381.1
  BOTTOM w0.076: UC1.BY32 174.6,90.37 174.62,90.37 174.62,90.37 v1(174.61,90.37)
GPP_B22: length 24
  TOP w0.107: RC46.2 191.83,80.46 v2(190.09,82.2) 187.39,84.9 v1(186.49,84.9)
  IN1 w0.089: v1(175.56,91.73) 176.11,91.18 176.11,90.01 176.17,89.96
  IN1 w0.102: v1(186.49,84.9) 186.49,84.91 186.03,85.37 184.1,85.37 183.47,86.01 183.47,87.01 182.81,87.67 182.08,87.67 181.62,88.13 177.87,88.13 177.87,88.12 177.6,88.12 176.49,89.23 176.49,89.63 176.17,89.96
  BOTTOM w0.089: v1(175.56,91.73) 175.19,91.94 UC1.CA30
GPP_B23: length 7.6
  BOTTOM w0.076: RC317.1 177.62,83.18 177.62,84.09 177.76,84.22 v2(177.76,84.71) 177.76,85.13 177.08,85.81 177.08,86.46 176.7,86.84 176.7,87.46 176.71,87.46 176.71,87.84 176.58,88.08 176.58,89.02 176.35,89.48 UC1.CC34
GPP_C5: length 16.9
  TOP w0.107: RC397.1 RC277.1 191.84,99.64 191.54,99.64 v1(191.5,99.68) 190.94,100.24 v2(190.89,100.24)
  IN1 w0.089: 191.11,99.3 191.04,99.22 188.42,99.22 187.98,99.66 180.34,99.66 179.64,100.36 178.91,100.36 178.5,100.77 v1(178.48,100.77)
  IN1 w0.099: v1(191.5,99.68) 191.11,99.3
  BOTTOM w0.089: UC1.CG15 v1(178.48,100.77)
GPP_D12: length 6.8
  BOTTOM w0.076: 186.72,97.06 v2(186.47,97.06) 186.42,97.06 186.13,97.35 183.02,97.35 182.97,97.38 182.7,97.38 UC1.CP22
  BOTTOM w0.107: RC847.1 188.15,96.47 187.55,97.06 186.72,97.06
GPP_H17: length 9.5
  BOTTOM w0.076: 186.72,94.13 185.87,94.13 185.22,93.48 184.4,93.48 183.53,94.35 182.44,94.35 UC1.CP26
  BOTTOM w0.107: RC101.2 190.33,92.91 189.8,93.44 189.8,93.67 189.34,94.13 v2(189.25,94.13) 186.72,94.13
GPP_H21: length 22.2
  IN1 w0.089: v1(178.51,94.42) 178.55,94.42 178.55,94.43 178.79,94.18 179.52,94.18 179.66,94.04 180.79,94.04 183.19,91.64 184.94,91.64 186.53,93.23 187.81,93.23
  IN1 w0.099: 187.81,93.23 188.59,93.23 188.78,93.04 190.37,93.04 190.56,93.23 194.24,93.23 v1(194.69,92.78)
  BOTTOM w0.089: v1(178.51,94.42) 178.55,94.42 178.55,94.43 178.5,94.43 178.04,94.89 UC1.CF25
  BOTTOM w0.107: RC443.1 RC444.2 193.68,92.94 193.95,92.67 v2(194.14,92.67) 194.57,92.67 v1(194.69,92.78)
GPP_H23: length 11.3
  BOTTOM w0.076: 186.72,94.47 185.99,94.47 185.16,93.65 184.5,93.65 183.19,94.96 181.91,94.96 181.76,94.82 181.19,94.82 UC1.CM26
  BOTTOM w0.107: 186.72,94.47 v2(187.07,94.47) 190.32,94.47 RC537.1 RC446.2
GPS_DISABLE#: length 24.6
  TOP w0.107: v1(266.12,87.51) 266.76,86.88 266.76,84.82 v2(266.63,84.69) 266.38,84.44 DZ6.1 ; RE12.1 257.74,87.34 257.85,87.45 v1(257.93,87.45)
  TOP w0.127: v1(252.81,94.21) 252.45,94.57 UE1.H5
  IN2 w0.089: v1(252.81,94.21) 253.25,93.77 253.25,91.37 254.71,89.91
  IN2 w0.102: 254.71,89.91 256.82,87.8 257.58,87.8 v1(257.93,87.45)
  IN3 w0.102: v1(266.12,87.51) 265.55,88.08 262.57,88.08 262.06,88.59 259.08,88.59 v1(257.93,87.45)
GPS_DISABLE#_R: length 3.8
  TOP w0.107: v2(267.56,82.43) 266.77,81.65 DZ6.2 266.05,81.32 v1(266.05,80.82)
  BOTTOM w0.107: JNGFF2.18 265.82,81.04 v1(266.05,80.82)
H_CATERR#: length 10.3
  BOTTOM w0.076: UC1.AA4 150.1,108.6 150.38,108.88 150.38,109.19 150.53,109.53 150.53,109.78 150.5,109.88 150.5,110.1 150.53,110.2 150.53,110.29 149.56,111.27 149.56,113.82 149.87,114.13 149.87,116.19 v2(150.34,116.66)
  BOTTOM w0.107: v2(150.34,116.66) 150.03,116.96 RC219.2
H_CPU_SVIDALRT#: length 7.4
  BOTTOM w0.076: UC1.AA3 150.15,109.06 150.36,109.54 150.36,109.79 150.31,109.93 150.22,109.99 150.01,109.99 149.73,110.27 149.73,110.58 149.23,111.07 149.23,112.99 v2(149.12,113.11) 149.06,113.17 149.06,115.02 RC155.1
H_CPUPWRGD: length 4.1
  BOTTOM w0.076: CC300.1 RC77.2 158.68,112.09 159.04,111.73 159.04,110.14 158.74,109.85 UC1.AR2
H_CPUPWRGD_R: length 0.9
  BOTTOM w0.076: RC77.1 T355.1
H_THERMTRIP#: length 288.3
  TOP w0.107: v1(186.43,122.57) 178.35,122.57 177.95,122.16 173.89,122.16 173.36,121.63 172.35,121.63 v1(171.1,120.38) ; v1(139.44,45.47) 139.33,45.59 139.33,46.1 RD14.2 ; QE4.3 252.3,80.55 252.09,80.35 v1(251.68,80.35) ; v1(169.36,44.42) 169.36,42.3 169.67,41.98 172.84,41.98 174.23,43.37 198.39,43.37 201.09,40.67 v2(209.29,40.67) 209.74,40.67 209.98,40.92 RD27.2 v1(211.15,38.97)
  IN1 w0.099: v1(251.68,80.35) 251.68,79.37 254.91,76.14 254.91,63.45 256.8,61.56 256.8,53.16 257.54,52.42 257.54,47.78 257.21,47.44 257.21,45.46 255.64,43.9 255.64,43.02 255.16,42.54 254.29,42.54 253.86,42.11 253.86,39.05 251.8,37 250.6,37 248.72,35.11 246.72,35.11 245.08,33.47 243.44,33.47 242.62,34.29 232.76,34.29 231.49,35.56 225.27,35.56 225.18,35.47 223.26,35.47 221.73,37 221.73,37.46 221.12,38.08 213.45,38.08 212.56,38.97 v1(211.15,38.97)
  IN3 w0.102: v1(139.44,45.47) 139.44,45.37 140.85,43.95 155.57,43.95 156.04,44.42 v1(169.36,44.42) ; v1(251.68,80.35) 251.35,80.35 251.06,80.64 249.51,80.64 249.18,80.97 248.08,80.97 247.22,80.11 244.82,80.11 243.84,81.08 243.84,81.66 242.95,82.55 242.95,83.02 242.71,83.26 242.24,83.26 241.55,83.95 241.55,85.54 241.14,85.96 238.28,85.96 237.27,86.97 237.27,91.43 236.79,91.9 236.79,94.91 234.81,96.89 234.81,109.03 v1(235.22,109.45)
  BOTTOM w0.107: v1(186.43,122.57) 186.6,122.57 187.76,121.4 189.88,121.4 190.49,120.79 191.46,120.79 192.1,120.15 199.04,120.15 199.53,119.66 206.95,119.66 207.71,118.9 208.88,118.9 211.5,116.28 225.24,116.28 232.07,109.45 v1(235.22,109.45) ; RC559.1 170.49,119.77 v1(171.1,120.38)
H_THERMTRIP#_R: length 11
  BOTTOM w0.076: 167.25,116.2 v2(167.14,116.09) 166.65,115.6 166.65,113.36 166.81,113.21 166.81,110.7 UC1.BJ1
  BOTTOM w0.107: 167.25,116.2 167.79,116.74 167.79,117.12 168.61,117.94 169.29,117.94 169.73,118.39 RC218.2 RC559.2
H_VCCST_PWRGD_XDP: length 4.3
  TOP w0.107: RC124.2 RC123.2 CC307.1 86.93,134.32 v1(87.56,134.96) 88.03,135.43 v2(88.29,135.43)
  BOTTOM w0.107: JXDP1.39 87.57,134.95 v1(87.56,134.96)
HDA_BIT_CLK: length 13.3
  TOP w0.107: v1(169.96,76.1) 169.96,75.53 170.4,75.08 170.4,74.97 RC93.2
  BOTTOM w0.076: UC1.BN37 170.01,87.61 170.01,86.74 169.65,86.17 169.65,84.91 169.95,76.15
  BOTTOM w0.107: 169.95,76.15 v1(169.96,76.1)
HDA_BIT_CLK_R: length 131.9
  TOP w0.107: UA1.5 285.33,50.75 285.21,50.63 285.21,50.53 285.17,50.49 285.17,49.07 285.17,49.06 v1(285.17,49) 285.17,48.79 RA17.1 ; RC93.1 CC27.1 171.79,73 178.95,65.84 228.82,65.84 v2(229.97,66.99) 231.89,68.9 v1(231.98,68.9)
  BOTTOM w0.107: v1(231.98,68.9) 231.98,68.97 232.24,69.23 234.62,69.23 236.33,67.52 237.59,67.52 238.43,66.69 241.44,66.69 243.8,64.32 245.06,64.32 246.62,62.76 248.79,62.76 252.23,59.31 259.84,59.31 260.23,58.92 264.56,58.92 268.98,54.5 268.98,53.97 271.46,51.49 278.57,51.49 280.03,50.03 283.22,50.03 283.67,49.58 284.13,49.58 284.41,49.86 284.92,49.86 285.17,49.6 v1(285.17,49)
HDA_RST#: length 18.6
  TOP w0.107: v1(166.12,73.79) 166.21,73.88 166.9,73.88 CC331.1 RC560.2
  BOTTOM w0.076: UC1.BL35 168.98,88.46 168.98,87.29 168.96,87.27 168.96,86.95 169.08,86.83 169.08,85.27 168.91,85.1 v2(168.91,83.93) 168.91,77.1
  BOTTOM w0.107: 168.91,77.1 167.95,76.15 167.95,75 166.73,73.79 v1(166.12,73.79)
HDA_RST#_R: length 132.9
  TOP w0.107: v1(274.51,49.92) 277.39,47.04 277.39,44.85 278.29,43.95 281.3,43.95 281.95,44.6 RA50.1 ; RC560.1 166.91,71.57 168.75,69.73 173.21,69.73 178.29,64.65 230.46,64.65 v2(231.11,65.29) v1(233.51,67.7)
  BOTTOM w0.107: v1(233.51,67.7) 233.83,68.02 234.23,68.02 236.51,65.73 240.79,65.73 244.12,62.4 245.36,62.4 245.96,61.8 247.9,61.8 248.09,61.61 248.09,59.51 248.34,59.26 250.27,59.26 251.64,57.89 258.84,57.89 262.7,54.03 266.87,54.03 270.98,49.92 v1(274.51,49.92)
HDA_SDIN0: length 153.8
  TOP w0.107: CC332.1 167.86,73.45 v1(167.57,73.16) 167.47,73.06 167.47,71.37 168.88,69.96 173.37,69.96 178.45,64.88 229.96,64.88 v2(231.61,66.53) v1(232.95,67.88) ; RA9.1 v1(286.95,46.87)
  BOTTOM w0.076: UC1.BN35 169.62,88.67 169.62,88.04 169.51,87.84 169.51,87.46 169.69,87.29 169.69,86.96 169.29,86.56 169.29,83.68 169.16,83.55 169.16,76.91 168.4,76.15
  BOTTOM w0.107: v1(286.95,46.87) 286.95,47.89 286.47,48.37 282.34,48.37 281.99,48.73 280.06,48.73 278.14,50.65 271.28,50.65 268.19,53.73 268.19,54.26 264.26,58.19 259.93,58.19 259.54,58.59 251.93,58.59 248.49,62.03 246.06,62.03 245.46,62.63 244.22,62.63 240.88,65.97 236.61,65.97 234.18,68.4 233.49,68.4 232.97,67.88 232.96,67.88 v1(232.95,67.88) ; 168.4,76.15 168.4,75.07 167.43,74.1 167.43,73.31 v1(167.57,73.16)
HDA_SDIN0_R: length 2.9
  TOP w0.107: UA1.7 286.13,49.6 286.95,48.78 RA9.2
HDA_SDOUT: length 21.3
  TOP w0.107: v2(167.89,71.56) 168.04,71.72 v1(168.04,72.72) 168.24,72.72 168.53,73 RC561.2 168.88,73.19 168.82,73.25 CC333.1 RC187.1 RC562.2
  BOTTOM w0.076: 169.03,76.15 169.49,76.6 169.49,86.53 169.85,86.89 169.85,87.36 169.68,87.53 169.68,87.8 169.94,88.28 UC1.BN36
  BOTTOM w0.107: 169.03,76.15 168.91,76.02 168.91,75.07 168.04,74.21 v1(168.04,72.72)
HDA_SDOUT_R: length 131.1
  TOP w0.107: UA1.4 284.93,49.62 v1(284.67,49.35) ; v1(232.56,68.31) v2(229.83,65.58) 229.37,65.12 178.65,65.12 173.57,70.2 169.67,70.2 168.88,70.99 RC561.1
  BOTTOM w0.107: v1(284.67,49.35) 284.4,49.09 283.47,49.09 283.01,49.54 279.83,49.54 278.37,51 271.26,51 268.43,53.83 268.43,54.36 264.36,58.43 260.03,58.43 259.63,58.82 252.03,58.82 248.58,62.27 246.42,62.27 244.85,63.84 243.6,63.84 241.24,66.2 238.22,66.2 237.39,67.03 236.13,67.03 234.45,68.71 232.96,68.71 v1(232.56,68.31)
HDA_SYNC: length 17
  TOP w0.107: v2(171.37,75.97) 170.66,75.97 170.49,75.8 v1(170.49,75.59) 170.66,75.59 171.42,74.83 RC92.2
  BOTTOM w0.076: 170.49,76.15 170.49,76.43 170.24,76.69 170.24,83.73 169.85,84.12 169.85,86.11 170.2,86.45 170.2,87.8 170.17,87.89 170.17,88.13 170.21,88.25 170.21,88.5 170.21,88.51 170.21,89.37 UC1.BN34
  BOTTOM w0.107: 170.49,76.15 v1(170.49,75.59)
HDA_SYNC_R: length 137.3
  TOP w0.107: RC92.1 171.61,73.87 179.15,66.33 228.59,66.33 v2(230.47,68.21) v1(231.64,69.38) ; v1(287.78,50.3) 287.18,50.3 286.93,50.55 UA1.9
  BOTTOM w0.107: v1(287.78,50.3) 287.36,50.72 280.03,50.72 278.29,52.46 271.2,52.46 269.67,53.99 269.67,60.77 270.39,61.48 270.39,62.07 269.3,63.16 267.68,63.16 266.2,61.67 259.14,61.67 257.16,63.65 246.42,63.65 245.07,65 243.82,65 241.64,67.18 238.63,67.18 237.8,68.01 236.53,68.01 234.81,69.73 231.99,69.73 v1(231.64,69.38)
HDD_A_EQ: length 3.3
  BOTTOM w0.107: UN7.17 v2(252.69,48.09) 251.78,48.09 RN11.2 251.77,47.65 RN10.1
HDD_A_EQ2: length 3.9
  BOTTOM w0.107: v2(252.69,49.45) 252.53,49.6 RN20.2 RN21.1 252.03,48.59 UN7.18
HDD_A_PRE: length 3.6
  BOTTOM w0.107: RN7.2 RN6.2 259.05,47.06 v2(258.96,47.15) 258.96,47.64 258.51,48.09 UN7.9
HDD_B_EQ: length 4.4
  BOTTOM w0.107: UN7.19 253.47,49.09 253.2,49.36 253.2,49.44 252.27,50.37 RN12.2 RN13.2 v2(252.76,51.13)
HDD_B_EQ2: length 3.7
  TOP w0.107: v2(254.67,45.98) 255.06,45.59 v1(255.55,45.59) 255.84,45.87 RN19.1 RN18.2
  BOTTOM w0.107: v1(255.55,45.59) 255.84,45.87 UN7.13
HDD_B_PRE: length 3
  BOTTOM w0.107: RN8.1 RN9.2 259.1,48.59 v2(259.01,48.5) 258.75,48.5 258.66,48.59 UN7.8
HDD_DET#: length 139.3
  IN2 w0.102: v1(187.89,107.04) 187.31,106.46 187.31,104.79 190.05,102.05 190.54,102.05 190.95,102.47 191.18,102.69 193.17,102.69 193.52,103.05 194.47,103.05 196.28,101.24 197.61,101.24 199.02,99.83 199.02,95.17 202.42,91.77 203.14,91.77 205.5,89.41 205.89,89.41 209.58,85.72 209.58,85.72 209.82,85.48 210.57,85.48 212.21,83.84 212.9,83.84 213.79,82.95 215.22,82.95 215.42,82.75 218.94,82.75 220.35,81.34 222.55,81.34 223.58,80.31 224.79,80.31 226.5,78.6 230.09,78.6 232.93,75.75 232.93,72.58 234.34,71.17 234.34,70.53 235.51,69.35 235.9,69.35 236.79,70.24 238.82,70.24 240.61,68.45 248.42,68.45 251.93,64.94 252.85,64.94 254.19,63.61 254.19,58.04 257.68,54.55 v1(257.68,54.29) 257.68,54.29 255.07,51.68 255.07,45.33 250.04,40.3 v1(250.04,39.63)
  BOTTOM w0.076: UC1.CN8 181.89,105.65 182.39,105.65 182.66,105.5 183.07,105.5 183.47,105.9 183.67,105.9 183.71,105.85 183.72,105.85 183.9,105.67 185.87,105.67 186.4,106.21 186.72,106.21
  BOTTOM w0.107: JSATA1.13 250.04,39.4 v1(250.04,39.63) ; RC765.2 193.35,106.63 RC520.1 193.08,106.45 192.97,106.56 192.97,106.94 192.77,107.14 191.83,107.14 191.41,106.72 188.21,106.72 v1(187.89,107.04) 187.05,106.21 186.72,106.21 ; v1(257.68,54.29) 258.05,53.92 258.05,53.11 258.39,52.76 QN6.2
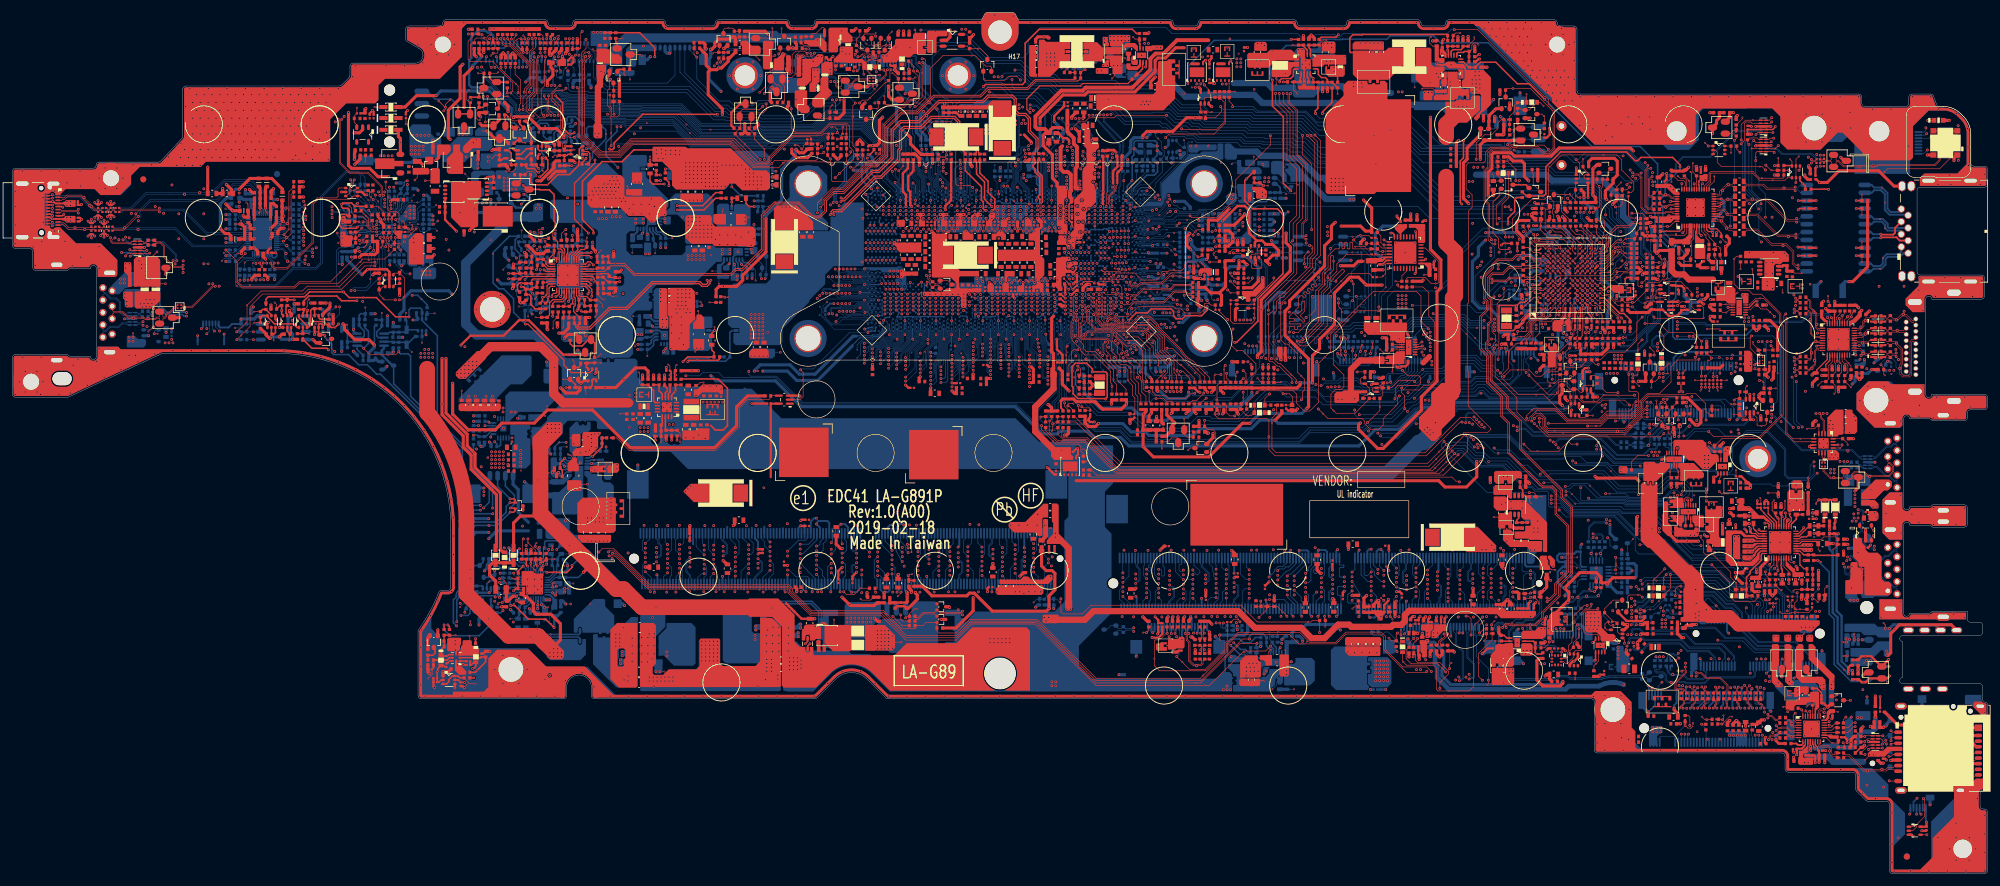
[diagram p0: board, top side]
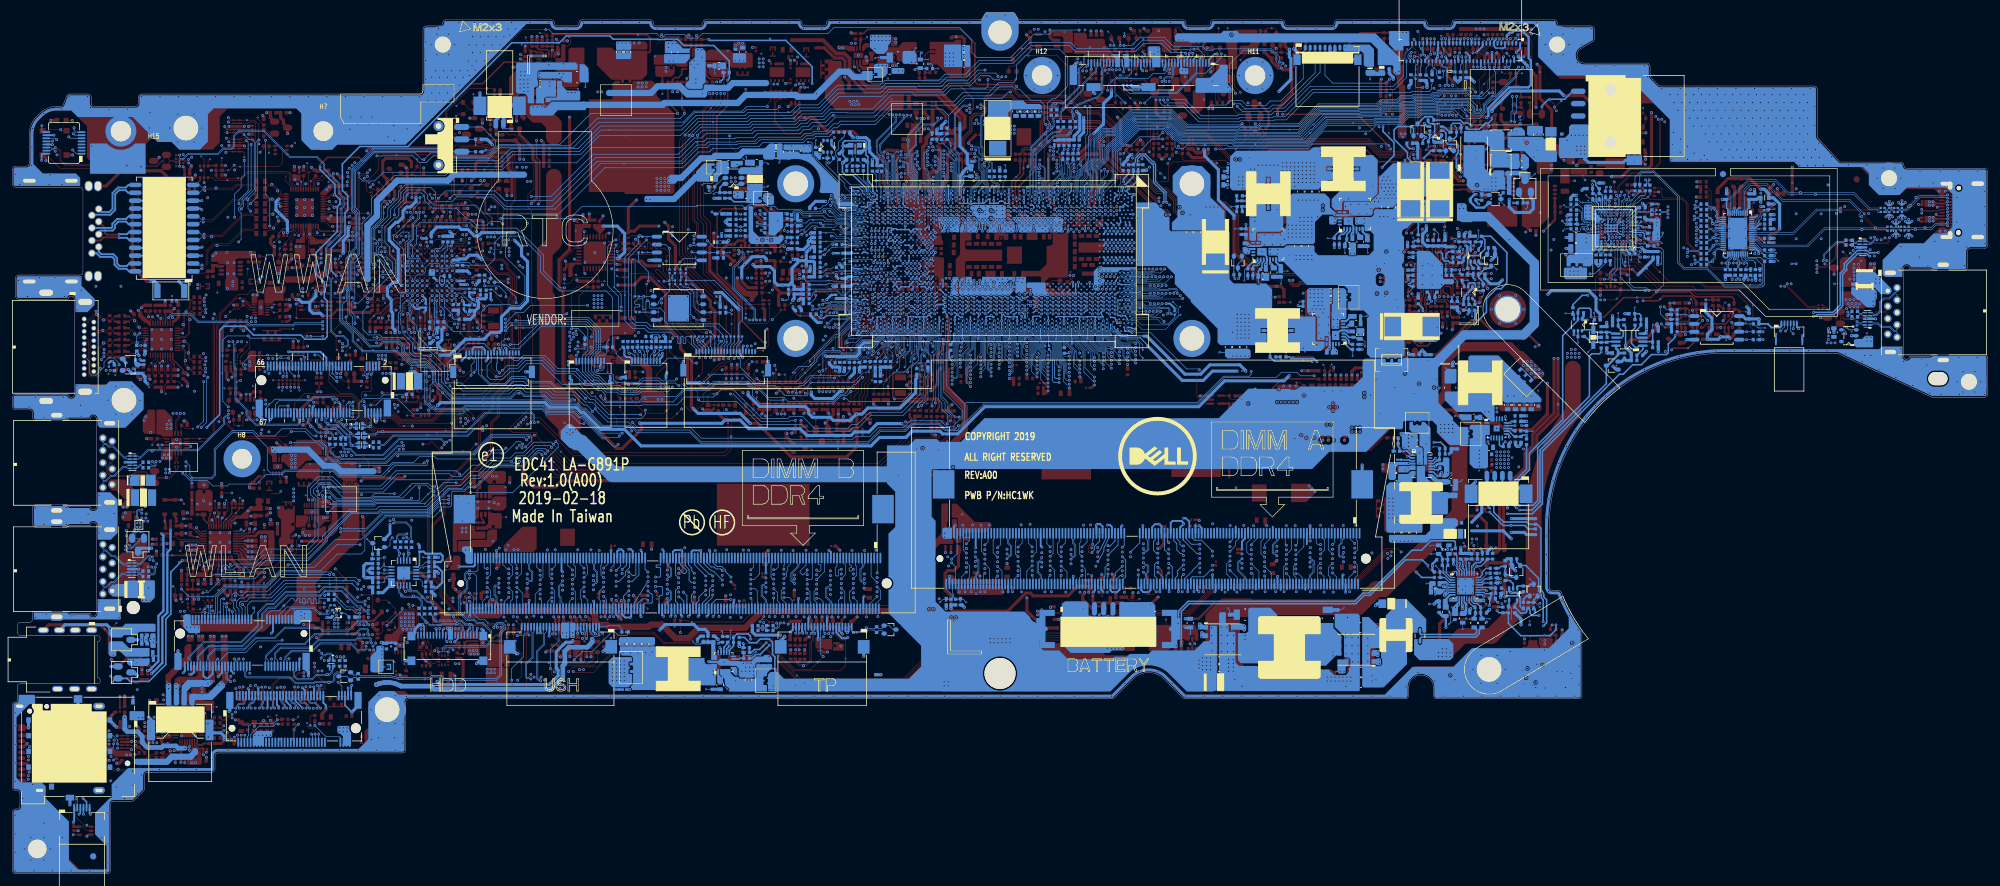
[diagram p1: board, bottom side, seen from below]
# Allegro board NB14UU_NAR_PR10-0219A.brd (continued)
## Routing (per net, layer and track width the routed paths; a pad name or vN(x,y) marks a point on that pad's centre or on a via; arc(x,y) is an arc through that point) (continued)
HDD_DEVSLP: length 133.2
  TOP w0.107: RN3.2 248.23,38.1 248.85,37.48 v1(248.85,37.48)
  IN1 w0.099: v1(248.85,37.48) 251.27,37.48 252.16,38.37 252.16,40.29 253.38,41.51 253.38,43.46 254.92,45.01 254.92,56.73 v1(254.54,57.11)
  IN2 w0.102: v1(254.54,57.11) 253.96,57.7 253.96,63.51 252.76,64.71 251.84,64.71 248.33,68.22 236.01,68.22 235.58,68.65 232.7,71.53 232.7,75.66 229.99,78.37 226.27,78.37 224.56,80.08 223.36,80.08 222.33,81.11 220.66,81.11 220.22,80.68 220.17,80.68 220.12,80.63 216.96,80.63 214.98,82.61 213.77,82.61 212.77,83.61 210.85,83.61 208.94,85.52 204.49,85.52 202.47,87.54 202.47,91.39 198.79,95.07 198.79,99.42 198.27,99.93 198.27,99.93 197.42,100.78 196.09,100.78 194.28,102.59 193.71,102.59 193.36,102.23 191.37,102.23 190.68,101.55 189.87,101.55 186.91,104.5 186.91,106.87 187.03,107 v1(187.03,107.04)
  BOTTOM w0.076: 184.22,105.85 184.03,105.85 183.81,106.07 183.4,106.07 182.99,105.66 182.71,105.66 182.24,105.91 UC1.CP8
  BOTTOM w0.102: 184.22,105.85 185.65,105.85 v2(186.58,106.78) 186.85,107.04 v1(187.03,107.04)
  BOTTOM w0.107: JSATA1.11 249.04,38.52 249.04,37.67 v1(248.85,37.48)
HDD_EN: length 4.9
  TOP w0.254: RN4.2 247,35.49 v2(246.22,35.49) 245.98,35.74 RZ148.2 RN5.1 245.68,37.57 UZ23.3
HDD_FALL_INT: length 126.1
  TOP w0.107: v1(196.13,80.86) 196.13,80.08 196.78,79.43 RC58.1 ; v1(254.37,43.34) 253.89,43.34 v2(253.44,42.89) 252.22,41.67 252.22,40.71 252.13,40.63 252.13,38.41 251.91,38.18 251.91,37.41 251.33,36.84 251.33,35.92 251.17,35.76 251.17,34.97 250.95,34.74 LGA1.12
  IN1 w0.089: v1(175.56,91.1) 175.95,90.71 175.95,89.92 176.01,89.86
  IN1 w0.099: 189.28,81.18 185.26,85.2 184.03,85.2 182.78,86.45 182.76,86.45
  IN1 w0.102: 189.28,81.18 195.81,81.18 v1(196.13,80.86) ; 176.01,89.86 176.26,89.61 176.26,89.15 177.47,87.95 177.52,87.95 177.52,87.95 177.94,87.95 177.95,87.95 181.26,87.95 182.76,86.45
  IN2 w0.102: v1(248.53,42.79) 248.66,42.92 248.66,46.28 249.39,47.01 249.39,50.57 248.99,50.97 248.99,61.47 248.02,62.44 237.74,62.44 236.35,63.83 232.96,63.83 230.23,66.56 227.03,66.56 224.34,69.25 224.34,71.19 219.06,76.48 216.43,76.48 215.39,77.52 210.62,77.52 210,78.14 205.9,78.14 205.48,78.56 200.97,78.56 199.93,79.6 198.53,79.6 197.28,80.86 v1(196.13,80.86)
  IN3 w0.102: v1(248.53,42.79) 248.64,42.79 248.72,42.87 249.17,42.87 249.36,43.06 254.09,43.06 v1(254.37,43.34)
  BOTTOM w0.089: v1(175.56,91.1) 175.19,91.29 UC1.CA31
HDD_UN7_EN: length 3.7
  BOTTOM w0.107: RN227.1 RN226.2 260.87,52.54 260.85,52.55 QN6.1 261.1,53.41 v2(261.77,54.08)
HDD_UN7_EN_R: length 4.3
  TOP w0.107: v1(258.94,49.09) 259.01,49.16 v2(259.01,50.11) 259.01,51.07 v1(258.96,51.13)
  BOTTOM w0.107: v1(258.96,51.13) 259.08,51 259.83,51 RN227.2 ; UN7.7 v1(258.94,49.09)
HDMI_BUF: length 6.8
  TOP w0.107: UV21.14 294.35,83.42 294.32,83.39 294.32,82.62 294.44,82.5 294.44,81.02 RV305.1 RV304.2 293.94,79.42 294.42,78.94 294.42,77.7 v2(294.29,77.57)
HDMI_CEC: length 12.2
  TOP w0.107: v1(301.81,82.24) 302.27,81.79 RV736.1 302.27,80.72 v2(302.45,80.54)
  BOTTOM w0.102: JHDMI1.13 306.64,82.84 306.64,80.97 306.24,80.58 305.56,80.58 304.25,81.89 304.25,82.66 303.55,83.36 302.69,83.36 301.81,82.48 v1(301.81,82.24)
HDMI_CLKN_C: length 5.6
  TOP w0.097: UV21.10 291.81,84.56 291.7,84.66 291.47,84.66 291.27,84.46 291.27,83.27 291.3,83.23 291.3,82.65 291.27,82.61 291.27,82.27 v4(290.67,81.67) 290.26,81.26 290.05,81.26 CV307.1
HDMI_CLKP_C: length 5.6
  TOP w0.097: UV21.9 291.81,84.96 291.7,84.85 291.4,84.85 291.08,84.54 v4(291.08,82.94) 291.08,82.35 290.77,82.03 290.72,82.03 290.31,81.62 290.31,81.57 290.19,81.45 290.05,81.45 CV306.1
HDMI_DP1_HPD: length 156.4
  TOP w0.107: UV21.3 v1(291.56,87.36)
  IN1 w0.099: v1(191.09,127.08) 191.66,126.5 207.2,126.5 207.79,125.91 227.25,125.91 230.79,122.36 235.07,122.36 236.55,123.84 271.59,123.84 273.62,121.81 273.62,118.96 274.87,117.7 276.89,117.7 287.55,107.05 287.55,97.84 291.56,93.83 v1(291.56,87.36)
  IN2 w0.102: v1(186.78,109.61) 186.59,109.8 186.59,115.15 187.64,116.19 187.64,116.42 187.75,116.53 187.75,117.53 190.18,119.96 190.18,122.54 190.74,123.1 190.74,126.73 v1(191.09,127.08)
  BOTTOM w0.076: 186.72,109.41 186.1,108.79 186.1,108.2 185.61,107.71 182.81,107.71 182.25,107.48 182.01,107.48 181.74,107.22 UC1.CN6
  BOTTOM w0.107: 186.72,109.41 186.78,109.46 v1(186.78,109.61) ; v1(191.09,127.08) v2(190.52,127.08)
HDMI_EQ: length 6.4
  TOP w0.107: v2(296.95,78.62) 296.05,79.53 RV734.2 RV307.1 296.48,81.02 296.48,82.16 296.15,82.49 295.87,82.49 295.55,82.8 UV21.17
HDMI_HPD_SINK: length 17.7
  TOP w0.107: UV21.28 v1(298.48,87.36)
  IN1 w0.099: JHDMI1.19 307.11,80.31 301.84,80.31 301.11,81.04 301.11,82.81 299.95,83.98 299.95,86.55 299.14,87.36 v1(298.48,87.36)
  BOTTOM w0.107: v1(298.48,87.36) 298.97,86.87 RV55.2
HDMI_ISET: length 7.4
  TOP w0.107: RV208.2 293.51,92.26 v1(293.28,92.49) v2(293.28,93.37) ; UV21.34 v1(295.55,90.16) 295.99,90.6 RV209.1
  IN1 w0.099: v1(295.55,90.16) 295.19,90.16 293.28,92.07 v1(293.28,92.49)
HDMI_PRE: length 4.6
  TOP w0.107: UV21.16 295.15,83.19 295.17,83.17 295.17,82.61 v2(295.25,82.53) 295.46,82.32 295.46,81.02 RV175.1 RV207.2
HDMI_SCL_SINK: length 21.2
  TOP w0.107: RV735.1 297.23,90.64 297.23,90.45 297.04,90.26 v1(297.04,89.99) 296.35,89.3 UV21.32
  IN3 w0.102: v1(297.04,89.99) 296.82,90.21 296.82,90.33 296.97,90.47 297.41,90.47 297.61,90.28 297.61,89.03 304.62,82.02 304.62,80.85 305.18,80.29 306.46,80.29 306.82,80.65 306.82,82.31 306.9,82.47 JHDMI1.15
HDMI_SDA_SINK: length 21.1
  TOP w0.107: RV10.1 296.96,90.75 296.96,90.54 v1(296.41,89.99) 295.95,89.53 UV21.33
  IN3 w0.102: v1(296.41,89.99) 296.59,90.17 296.59,90.42 296.87,90.7 297.51,90.7 297.84,90.37 297.84,89.13 304.85,82.12 304.85,80.95 305.28,80.52 306.37,80.52 306.59,80.74 306.59,82.25 306.45,82.33 JHDMI1.16
HDMI_TX_N0_C: length 6.8
  TOP w0.097: UV21.2 291.98,87.76 291.87,87.86 291.62,87.86 291.28,88.21 291.28,88.43 291.24,88.46 291.24,89.05 291.28,89.09 291.28,90.49 v4(290.99,90.77) 290.32,91.45 290.32,92.46 290.18,92.6 290.02,92.6 CV305.1
HDMI_TX_N1_C: length 6.5
  TOP w0.097: CV303.1 290.01,90.82 290.12,90.82 290.39,90.55 v4(290.39,89.53) 290.39,87.31 291.07,86.63 292,86.63 292.07,86.56 UV21.5
HDMI_TX_N2_C: length 5.3
  TOP w0.097: CV301.1 290.01,83 290.39,83 290.63,83.25 v4(290.63,84.16) 290.63,85.42 291.05,85.83 291.6,85.83 291.64,85.87 291.84,85.87 291.95,85.76 UV21.7
HDMI_TX_P0_C: length 6.8
  TOP w0.097: UV21.1 291.98,88.16 291.87,88.05 291.7,88.05 291.46,88.28 v4(291.46,88.76) 291.46,90.57 291.36,90.67 291.36,90.72 290.94,91.13 290.89,91.13 290.5,91.52 290.5,92.53 290.25,92.78 290.08,92.78 CV304.1
HDMI_TX_P1_C: length 6.6
  TOP w0.097: UV21.4 292.09,86.96 291.95,86.81 291.14,86.81 290.57,87.39 290.57,89.21 290.61,89.24 290.61,89.83 290.57,89.86 290.57,90.62 290.2,91 290.08,91 CV302.1
HDMI_TX_P2_C: length 5.4
  TOP w0.097: UV21.6 292.05,86.16 291.91,86.05 v4(291.3,86.05) 291.01,86.05 290.45,85.49 290.45,84.49 290.42,84.45 290.42,83.87 290.45,83.83 290.45,83.33 290.31,83.19 290.08,83.19 CV300.1
HOST_DEBUG_TX: length 60.2
  TOP w0.107: UE1.G11 251.26,99.8 v1(251.26,99.81) ; v2(215.03,82.97) 215.31,83.24 v1(215.31,83.81)
  IN1 w0.099: v1(248.34,106.92) 247.12,106.92 245.04,104.85 245.04,103.39 242.69,101.03 242.69,99.96 241.8,99.07 241.8,98.59 239.97,96.76 239.97,95.78 239.29,95.1 238.47,95.1 237.97,94.59 235.85,94.59 233.41,92.16 229.12,92.16 226.09,89.13 221.45,89.13 218.86,86.54 217.52,86.54 215.73,84.74 215.73,84.23 215.31,83.81 v1(215.31,83.81)
  IN2 w0.089: 251.71,100.82 251.71,100.15 251.37,99.81 v1(251.26,99.81)
  IN2 w0.102: v1(248.34,106.92) 248.48,106.92 248.98,106.43 248.98,105.98 249.43,105.53 250.26,105.53 251.62,104.17 251.62,100.94 251.71,100.85 251.71,100.82
  BOTTOM w0.107: JDEG1.8 215.47,83.71 215.36,83.81 v1(215.31,83.81) 215.15,83.81 214.44,84.53 214.05,84.53 213.55,85.04 RE73.2 RE306.2
HOST_SD_WP#: length 163.2
  TOP w0.107: RC292.1 198.43,79.67 198.77,80.01 v1(198.82,80.01) ; QR1.2 294.46,28.66 v1(294.7,28.9)
  IN2 w0.102: v1(198.82,80.01) 199.84,80.01 200.97,78.88 205.61,78.88 205.76,78.73 209.74,78.73 210.72,77.75 215.48,77.75 216.52,76.71 219.78,76.71 225.04,71.44 225.04,69.1 227.19,66.95 230.37,66.95 233.24,64.08 236.43,64.08 237.84,62.67 244.01,62.67 244.8,63.46 245.23,63.46 246.02,62.67 246.87,62.67 v1(247.37,63.16) ; v1(294.7,28.9) 290.23,28.9 289.91,29.22 289.91,33.12 287.28,35.75 277.39,35.75 276.55,36.59 276.55,44.7 273.36,47.89 273.36,50.74 270.14,53.97 270.14,60.93 270.37,61.16 270.37,61.77 269.93,62.21 269.46,62.21 268.79,61.54 v1(268.4,61.54)
  BOTTOM w0.076: 182.99,84.15 182.79,84.35 182.79,85.38 182.62,85.55 182.61,85.55 181.8,86.35 179.83,86.35 179.12,87.06 179.12,87.38 179.22,87.48 179.22,87.84 179.2,87.88 179.16,87.95 179.11,88.04 179.11,88.67 UC1.CH35
  BOTTOM w0.107: v1(247.37,63.16) 247.44,63.24 249.31,63.24 250.38,62.17 251.56,62.17 252.19,62.79 253.92,62.79 255.98,60.73 260.61,60.73 261,60.34 266.63,60.34 267.84,61.54 v1(268.4,61.54) ; v1(198.82,80.01) 198.77,80.01 198.34,79.58 192.34,79.58 v2(191,80.92) 189.09,82.83 189.09,83.29 187.84,84.53 185.42,84.53 185.03,84.15 182.99,84.15
HP_OUT_L: length 12.8
  TOP w0.127: v2(286.32,60.26) 286.32,58.98 285.68,58.34 CA74.1
  TOP w0.203: v1(285.87,57.68) 285.73,57.55 UA1.25
  TOP w0.254: v1(285.87,57.68) 285.87,57.74 285.68,57.92 CA74.1
  TOP w0.381: RA7.1 CA43.2 v1(291.02,56.21)
  IN1 w0.381: v1(285.87,57.68) 286.19,57.36 286.19,56.97 286.57,56.59 287.7,56.59 288.28,57.16 290.38,57.16 291.02,56.53 v1(291.02,56.21)
HP_OUT_R: length 14.4
  TOP w0.127: v2(284.55,60.32) 284.25,60.02 284.25,58.7 284.65,58.29 CA73.1
  TOP w0.203: UA1.26 285.33,57.32 v1(285.17,57.48)
  TOP w0.254: v1(285.17,57.48) 284.79,57.86 CA73.1
  TOP w0.381: v1(291.02,55) 291.65,55 CA44.2 RA8.1
  IN1 w0.381: v1(285.17,57.48) 285.55,57.1 285.55,56.59 286.19,55.95 287.97,55.95 288.54,56.53 289.87,56.53 291.02,55.38 v1(291.02,55)
HV_GATE1_A: length 2.9
  BOTTOM w0.076: UT5.B9 61.58,102.06 61.58,100.79 62,100.37 62.07,100.37
  BOTTOM w0.107: 62.07,100.37 62.44,100 RT64.1
HV_GATE2_A: length 2.8
  BOTTOM w0.076: 62.05,100.55 61.83,100.78 UT5.A9
  BOTTOM w0.107: 62.05,100.55 62.15,100.55 62.32,100.38 62.92,100.38 63.25,100.05 RT65.1
HW_ACAVIN_NB: length 358
  TOP w0.107: v1(56.74,84.91) 57.78,83.87 v2(60.73,83.87) 61.93,83.87 v1(62.42,84.35) ; v1(257.12,94.84) 256.55,95.41 UE1.N6 ; v1(86.61,125.72) 86.61,123.52 87.57,122.57 v1(87.57,122.56)
  TOP w0.254: v1(85.02,113.96) 84.63,114.35 PR25.2 PR41.1 83.82,114.64 PR42.1 ; PR845.1 PR844.1 v1(45.52,92.73)
  IN2 w0.089: 252.66,100.1 252.73,100.03 252.73,98.63 252.41,98.3 252.41,97.29 252.66,97.04 253.66,97.04 254.06,96.64 255.67,96.64 256.76,95.54 ; 257.12,95.11 v1(257.12,94.84)
  IN2 w0.102: v1(78,44.7) 78,45.2 76.67,46.53 76.67,52.77 76.3,53.13 76.3,58.25 76.51,58.47 76.51,59.31 76.3,59.52 v1(75.61,59.52) ; v1(45.52,92.73) 46.6,92.73 49.95,89.38 54.45,89.38 56.66,87.16 56.66,84.99 v1(56.74,84.91) ; 256.76,95.54 257.12,95.18 257.12,95.11 ; v1(62.42,84.35) 62.42,82.62 64.4,80.64 70.14,80.64 73.52,84.02 73.52,93.57 75.39,95.45 77.6,95.45 77.92,95.77 77.92,106.25 81.97,110.31 82.1,110.31 84.28,112.49 84.28,113.22 v1(85.02,113.96) 84.28,114.7 84.28,118.51 87.57,121.79 v1(87.57,122.56) ; v1(86.61,125.72) 87.11,125.22 94.68,125.22 94.69,125.21 97.23,125.21 99.92,127.9 108.88,127.9 110.8,129.82 111.44,129.82 113.84,132.22 115.28,132.22 115.89,132.83 121.32,132.83 123.07,131.07 125.31,131.07 126.11,130.27 131.12,130.27 131.74,130.9 141.43,130.9 144.03,133.49 154.97,133.49 157.33,131.14 163.88,131.14 166.14,128.88 177.19,128.88 177.78,129.47 183.64,129.47 184.36,130.2 192.93,130.2 195.03,128.1 195.03,126.65 203.73,117.95 239.17,117.95 239.51,118.29 242.15,118.29 249.16,111.28 249.16,108.03 250.82,106.36 250.82,105.61 252.08,104.36 252.08,102.33 252.66,101.74 252.66,100.1
  BOTTOM w0.107: v1(78,44.7) 78,45.9 78.25,46.15 PR746.1
  BOTTOM w0.254: PR835.1 v1(62.42,84.35) 62.42,84.27 62.67,84.02 63.94,84.02 64.32,83.64 64.32,77.15 72.68,68.8 72.68,60.27 73.43,59.52 v1(75.61,59.52) ; PR737.1 75.24,42.92 75.52,43.2 75.52,44.71 75.71,44.9 77.8,44.9 v1(78,44.7) ; PR806.2 PC805.1 55.67,84.75 PU800.1 56.32,85.33 v1(56.74,84.91) 57.51,85.68 57.51,87.65 56.95,88.21 PR805.2
I2C1_SCK_TP: length 173.8
  IN1 w0.089: 191.11,102.88 191.08,102.88 190.89,102.69 190.81,102.6 190.67,102.46 190.67,102.35 190.48,102.16 190.44,102.12 190.05,102.12 188.58,103.59 181.17,103.59 181.08,103.5 180.14,103.5 179.9,103.26 179.9,103.06 v1(179.7,102.86)
  IN1 w0.099: v1(212.44,103.69) 212.26,103.52 209.8,103.52 208.98,104.34 207.51,104.34 206.15,102.98 205.42,102.98 203.89,101.46 200.12,101.46 199.7,101.04 198.94,101.04 198.31,101.67 196.39,101.67 195.17,102.89 191.79,102.89 191.78,102.88 191.16,102.88 191.16,102.88 191.11,102.88 ; v1(197.86,40.02) 198.05,39.82 198.24,39.82 198.66,40.24 201.7,40.24 202.47,41.01 202.47,42.13 203.39,43.05 214.83,43.05 215.71,42.17 224.21,42.17 225.31,41.07 239.81,41.07 240.34,41.6 241.67,41.6 244.6,44.53 244.6,46.49 245.68,47.57 245.68,49.29 246.81,50.42 246.81,56.01 245.56,57.26 245.56,63.12 245.23,63.45 245.23,68.91 244.24,69.9 238.42,69.9 237.58,69.05 v1(237.58,68.8)
  IN3 w0.102: v1(237.58,68.8) 237.58,69.07 237.79,69.28 237.79,69.65 237.42,70.03 237,70.03 235.78,71.24 235.27,71.24 235.01,71.5 233.65,71.5 229.9,75.26 227.09,75.26 224.36,77.99 224.09,77.99 223.27,78.81 223.27,79.67 222.02,80.92 222.02,82.11 220.96,83.17 220.96,84.86 219.32,86.5 219.32,86.97 215.4,90.89 215.4,93.26 214.42,94.24 214.42,96.01 214.08,96.35 214.08,102.67 213.23,103.52 212.62,103.52 v1(212.44,103.69)
  BOTTOM w0.089: UC1.CJ12 179.73,102.92 v1(179.7,102.86)
  BOTTOM w0.107: RZ29.1 197.38,39.81 197.66,39.81 v1(197.86,40.02) 198.06,39.81 198.35,39.81 RZ21.2
I2C1_SCK_TP_R: length 9.7
  TOP w0.107: RZ347.1 192.32,38.09 192.32,38.67 v1(192.53,38.87) 192.33,39.07 192.33,39.61 RZ117.2
  IN1 w0.099: v1(192.53,38.87) 192.34,39.06 192.34,39.25 192.56,39.47 195.08,39.47 195.45,39.83 195.45,40.34 v1(195.61,40.5)
  BOTTOM w0.107: JKBTP1.19 192.49,39.28 192.4,39.19 192.4,39 v1(192.53,38.87) ; v1(195.61,40.5) 195.42,40.31 195.42,39.98 195.59,39.81 195.93,39.81 RZ29.2
I2C1_SDA_TP: length 173.8
  IN1 w0.089: v1(180.28,102.85) 180.28,102.86 180.08,103.06 180.08,103.19 180.22,103.32 181.15,103.32 181.24,103.41 188.5,103.41 189.97,101.94 190.51,101.94 190.84,102.27 190.84,102.39 191.11,102.65 191.11,102.65
  IN1 w0.099: v1(197.86,39.43) 198.03,39.6 198.34,39.6 198.75,40.02 201.8,40.02 202.69,40.91 202.69,42.04 203.48,42.83 214.73,42.83 215.62,41.94 224.12,41.94 225.22,40.84 239.9,40.84 240.44,41.38 241.76,41.38 244.83,44.44 244.83,46.4 245.9,47.48 245.9,49.19 247.04,50.33 247.04,56.1 245.79,57.35 245.79,63.22 245.46,63.54 245.46,69 244.34,70.12 238.33,70.12 237.42,69.21 v1(237.17,69.21) ; 191.11,102.65 191.88,102.65 191.88,102.66 195.08,102.66 196.29,101.44 198.21,101.44 198.85,100.81 199.8,100.81 200.21,101.23 203.99,101.23 205.51,102.75 206.25,102.75 207.61,104.11 208.88,104.11 209.71,103.29 212.26,103.29 v1(212.44,103.11)
  IN3 w0.102: v1(212.44,103.11) 212.62,103.29 213.14,103.29 213.85,102.57 213.85,96.25 214.19,95.91 214.19,94.14 215.17,93.17 215.17,90.8 219.1,86.87 219.1,86.41 220.73,84.77 220.73,83.07 221.79,82.02 221.79,80.83 223.04,79.58 223.04,78.71 223.99,77.76 224.26,77.76 226.99,75.03 229.8,75.03 233.56,71.27 234.92,71.27 235.17,71.02 235.69,71.02 236.9,69.8 237.32,69.8 237.57,69.56 237.57,69.37 237.4,69.21 v1(237.17,69.21)
  BOTTOM w0.089: UC1.CK12 180.35,102.97 v1(180.28,102.85)
  BOTTOM w0.107: RZ20.2 198.35,39.58 198.01,39.58 v1(197.86,39.43) 197.71,39.58 197.38,39.58 RZ26.1
I2C1_SDA_TP_R: length 10
  TOP w0.107: RZ346.1 192.09,38.08 192.09,38.73 v1(191.94,38.87) 192.09,39.02 192.09,39.61 RZ116.2
  IN1 w0.099: v1(195.02,40.5) 195.22,40.3 195.22,39.93 194.99,39.7 192.46,39.7 192.11,39.34 192.11,39.04 v1(191.94,38.87)
  BOTTOM w0.107: v1(191.94,38.87) 192.08,39.01 192.08,39.16 191.99,39.26 JKBTP1.18 ; v1(195.02,40.5) 195.19,40.34 195.19,39.88 195.49,39.58 195.93,39.58 RZ26.2
I2C2_SCL_ALS: length 1.9
  TOP w0.102: v1(178.34,92.4) 177.97,92.03 177.97,91.43 T389.1
  BOTTOM w0.089: UC1.CF29 178.28,92.38 v1(178.34,92.4)
I2C2_SDA_ALS: length 2.6
  TOP w0.102: T388.1 176.61,93.62 178.28,93.62 v1(178.3,93.64)
  BOTTOM w0.089: UC1.CF27 v1(178.3,93.64)
I2C3_ANT_SCL: length 2.7
  TOP w0.102: T379.1 178.05,93.93 178.14,94.02 178.46,94.02 178.75,93.73 178.75,93.52 v1(179.21,93.05)
  BOTTOM w0.089: v1(179.21,93.05) 178.81,93.29 UC1.CH28
I2C3_ANT_SDA: length 3
  TOP w0.102: T378.1 178.82,95.15 179.21,94.76 v1(179.21,93.64)
  BOTTOM w0.089: UC1.CH27 v1(179.21,93.64)
I_ADP: length 275.9
  TOP w0.107: v2(84.65,53.45) 84.45,53.25 v1(84.45,52.91) 84.45,52.8 85.29,51.96 PR743.2 ; UE1.B11 247.6,99.41 v1(247.25,99.77)
  IN2 w0.089: v1(247.25,99.77) 246.6,99.12
  IN2 w0.102: v1(84.45,52.91) 84.45,52.8 85.52,51.73 89.89,51.73 94.32,56.16 96.29,56.16 98.22,58.1 130.96,58.1 133.54,55.51 134.35,55.51 135.73,54.13 135.73,48.46 136.52,47.68 137.4,47.68 139.04,46.04 147.14,46.04 148.3,44.87 154.3,44.87 156.7,42.47 163.13,42.47 163.16,42.44 167.72,37.88 178.12,37.88 183.39,32.62 193.11,32.62 196.98,36.48 197.29,36.48 198.46,37.65 198.46,37.87 199.93,39.34 204.35,39.34 204.62,39.61 212.69,39.61 213.35,38.95 216.13,38.95 216.18,38.9 221.78,38.9 223.37,37.31 224.1,37.31 225.17,36.25 225.17,33.73 226.41,32.48 227.58,32.48 228.47,33.38 230.14,33.38 231.68,34.91 239.58,34.91 240.13,34.36 247.67,34.36 248.28,33.75 253.21,33.75 255.71,36.26 256.63,36.26 256.99,36.61 256.99,38.08 257.95,39.04 257.95,43.08 259.71,44.85 259.71,45.56 260.15,46.01 260.15,50.64 261.13,51.61 261.13,60.44 257.67,63.9 257.67,65.06 256.74,65.99 256.74,66.58 253.83,69.49 253.83,71.02 250.57,74.28 249.97,74.28 246.43,77.82 246.43,79.65 247.62,80.84 247.62,84.26 246.12,85.75 246.12,87.39 245.74,87.77 245.74,89.22 246.59,90.07 246.59,91.07 246.76,91.24 246.76,93.22 246.45,93.53 246.45,98.97 246.6,99.12
I_BATT: length 251.3
  TOP w0.107: v1(83.27,54.1) v2(83.27,53.52) 84.53,52.26 PR729.2 ; v1(260.22,85.77) 259.7,85.77 RE64.2
  IN1 w0.099: v1(260.22,85.77) 256.68,85.77 252.57,81.66 252.57,79.16 255.39,76.34 255.39,65.26 257.86,62.8 257.86,58.43 258.46,57.83 258.46,54.32 258.02,53.88 258.02,43.74 256.62,42.34 256.62,39.59 255.81,38.78 255.21,38.78 252.26,35.82 251.88,35.82 250.69,34.63 246.92,34.63 245.28,32.99 243.24,32.99 242.53,33.7 224.35,33.7 221.25,36.8 221.25,37.26 220.92,37.6 210.75,37.6 210.16,38.19 208.09,38.19 205.77,35.86 203.88,35.86 202.89,34.88 198.69,34.88 197.29,33.48 194.81,33.48 192.18,30.86 172.18,30.86 162.54,40.5 152.87,40.5 149.7,43.67 136.29,43.67 136.15,43.53 132.58,43.53 132.44,43.67 101.03,43.67 95.14,49.57 95.14,52.48 95.04,52.58 92.45,52.58 91.03,53.99 83.38,53.99 v1(83.27,54.1)
I_BATT_R: length 13.3
  TOP w0.107: v2(260.69,86.66) v1(260.17,86.66) 259.67,86.66 RE64.1 CE3.1
  TOP w0.127: v1(253.63,93.42) 253.63,93.43 UE1.J4
  IN2 w0.089: v1(253.63,93.42) 254.04,93.01 254.04,90.86 255.76,89.13 255.77,89.13
  IN2 w0.102: 255.77,89.13 256.9,88.01 258.82,88.01 v1(260.17,86.66)
I_SYS: length 315.5
  TOP w0.107: v1(86.98,122.56) 86.38,123.16 86.38,125.02 v2(86.19,125.21) 85.91,125.49 v1(85.91,125.72) ; PR731.2 86.63,52.15 v1(86.63,52.39) ; RE312.2 256.85,84.98 v1(256.85,84.98) ; v1(86.04,102.21) 86.11,102.15 86.11,101.99 86.55,101.55 PR620.1
  IN2 w0.089: 256.43,86.98 256.15,87.26 256.15,88.08 255.46,88.78 254.44,88.78 253.61,89.61 253.61,90.43 252.98,91.07 252.98,91.89 252.43,92.44 252.43,94.59 252.46,94.61 252.46,96.43 251.77,97.12 251.77,98.44 251.58,98.63 251.13,98.63 250.84,98.92 250.84,100.82
  IN2 w0.102: v1(85.91,125.72) 86.65,124.98 97.32,124.98 100.01,127.67 109.61,127.67 113.93,131.99 115.37,131.99 115.95,132.57 121.16,132.57 122.98,130.76 125.31,130.76 126.63,129.44 130.6,129.44 131.84,130.67 137.03,130.67 138.66,129.04 142.76,129.04 146.75,133.04 154.14,133.04 157.37,129.81 161.34,129.81 161.73,129.42 164.08,129.42 165.1,128.41 183.22,128.41 184.5,129.69 192.8,129.69 194.57,127.92 194.57,125.46 203.31,116.72 239.99,116.72 244.15,112.57 244.15,111.59 246.76,108.98 246.76,106.55 248.26,105.05 249.26,105.05 250.53,103.79 250.53,101.13 250.84,100.82 ; 256.43,86.98 256.85,86.56 v1(256.85,84.98) ; v1(86.98,122.56) 86.98,123.17 87.43,123.62 93.29,123.62 96.32,120.58 96.32,118.74 93.32,115.74 93.32,114.92 89.04,110.64 89.04,107.09 88.58,106.63 87.12,105.17 87.12,103.29 v1(86.04,102.21) 86.05,102.21 86.05,102.06 85.58,101.6 85.58,100.84 84.18,99.44 82.91,99.44 80.96,97.48 79.85,97.48 79.75,97.38 79.75,94.87 81.69,92.92 81.69,92.91 82.05,92.91 93.03,81.93 93.03,73.87 88.07,68.91 88.07,66.24 89.34,64.97 89.34,64.21 88.97,63.83 87.19,63.83 86.52,63.17 86.52,52.55 86.63,52.44 v1(86.63,52.39)
I_SYS_R: length 12.7
  TOP w0.089: v1(256.54,87.45) 256.85,87.13 256.85,86.98
  TOP w0.107: 256.85,86.98 RE312.1 RE313.1 CE4.1
  TOP w0.127: UE1.J5 253.58,94.28 253.59,94.28 v1(253.65,94.22)
  BOTTOM w0.089: v1(253.65,94.22) 254.03,93.84 256.13,93.84 256.4,93.57 256.4,92.83
  BOTTOM w0.102: 256.4,92.83 v2(256.4,91.56) 256.4,90.91
  BOTTOM w0.107: v1(256.54,87.45) 256.7,87.62 256.7,90.6 256.4,90.91
ILIM_SEL: length 3.5
  TOP w0.107: UI3.4 291.79,72.4 RI13.1 291.65,72.46 291.09,71.91 v2(289.89,71.91)
ILMT_1.05VALWP: length 5.7
  TOP w0.107: PR310.1 235.14,133.8 236.13,134.8 v2(236.13,135.15)
  TOP w0.254: PU301.13 232.4,132.91 232.66,133.17 233.99,133.17 234.31,133.49 PR307.2 PR310.1
ILMT_DDR: length 4.4
  TOP w0.254: PR205.2 88.82,65.2 PR207.1 88.48,66.39 v2(88.79,66.7) v1(89.21,67.13)
  BOTTOM w0.254: v1(89.21,67.13) 89.62,66.73 PU200.17
IMON_A_GT: length 8.2
  TOP w0.107: v2(84.51,89.91) PR629.2
  TOP w0.203: PU602.14 89.12,93.16 88.72,92.76 87.27,92.76 86.76,92.25 86.76,90.29 PC625.2
  TOP w0.254: PC625.2 PR629.2
IMON_B_IA: length 3.1
  TOP w0.203: PU602.2 86.61,98.12 86.18,98.55 86.18,98.89 85.78,99.29 PC613.2
  TOP w0.254: PC613.2 PR613.2
IMON_C_SA: length 4.5
  TOP w0.203: v1(93.47,95.21) 93.47,95.31 93.06,95.72 PU602.23
  BOTTOM w0.107: PR651.1 92.81,94.69 v2(93.53,93.97)
  BOTTOM w0.254: PC643.1 92.87,95.81 v1(93.47,95.21) 93.18,94.92 PR651.1
IMVP_VR_ON: length 261.1
  TOP w0.107: RE304.1 270.95,92.96 270.95,92.52 270.84,92.42 UE3.4 269.56,92.42 v1(268.98,91.84) 268.91,91.77 UE4.2 ; v1(88.48,127.38) 88.29,127.38 87.02,126.1 87.02,125.04 v2(87.63,124.43) 88.15,123.91 v1(88.15,122.55)
  IN2 w0.102: v1(88.48,127.38) 88.65,127.55 97.95,127.55 99.45,129.04 103.51,129.04 109.23,134.77 123.36,134.77 126.62,131.51 130.73,131.51 133.74,134.52 139.19,134.52 139.86,135.19 142.67,135.19 142.71,135.15 155.59,135.15 157.99,132.74 161.91,132.74 165.95,136.78 186.31,136.78 187.31,135.78 193.35,135.78 196.41,132.72 196.41,129.86 204.85,121.42 232.32,121.42 232.9,120.84 242.24,120.84 251.05,112.03 251.05,110.86 253.18,108.72 256.13,108.72 257.66,107.19 262.09,107.19 263.27,106 263.27,102.25 263.64,101.88 265.83,101.88 267.84,99.87 267.84,97.79 268.42,97.2 268.42,92.4 v1(268.98,91.84) ; v1(85.17,101.3) 85.17,101.77 85.63,102.22 85.63,102.38 86.89,103.64 86.89,105.26 88.81,107.18 88.81,110.74 93.09,115.02 93.09,115.83 96.1,118.84 96.1,119.91 92.62,123.38 88.28,123.38 88.15,123.26 v1(88.15,122.55)
  BOTTOM w0.254: PR616.1 85.33,100.66 85.33,101.13 85.17,101.28 v1(85.17,101.3)
IMVP_VR_ON_EC: length 29
  TOP w0.107: UE3.1 271.79,91.12 271.28,91.63 RE304.2 271.28,93.91 v2(270.56,94.63) 269.49,95.7 266.89,95.7 v1(266.82,95.64) ; RE717.2 260.82,97.34 259.23,97.34 v1(259.18,97.28) 259.18,96.99 258.3,96.11 256.55,96.11 UE1.N7
  IN3 w0.102: v1(259.18,97.28) 259.74,97.28 259.81,97.22 260.98,97.22 261.53,97.76 261.53,98.49 262.46,99.41 266.22,99.41 266.7,99.9 267.08,99.9 267.39,99.58 267.39,96.09 266.94,95.64 v1(266.82,95.64)
INPUT3VSEL: length 21.9
  TOP w0.089: v1(171.87,93.6) 171.83,93.6 171.83,93.61 171.37,93.15 171.37,92.85 171.3,92.79 171.3,92.58 171.37,92.52 171.37,92.22 171.3,92.16 171.3,91.95 171.37,91.88 171.37,91.58 171.36,91.58 171.36,90.95 171.52,90.8 171.52,89.53 171.48,89.45
  TOP w0.102: 173,85.32 173,85.45 172.16,86.46 ; 171.48,89.45 171.47,89.42 171.3,88.81 171.3,87.12 171.3,87.12 171.3,86.8 171.53,86.58 171.99,86.58
  TOP w0.107: RC451.1 RC452.2 178.37,79.07 177.86,79.58 177.86,81.02 177.86,81.02 177.86,81.42 177.86,81.42 v2(177.1,82.18) 175.07,84.21 174.91,84.37 173.48,84.37 173,84.85 173,85.32 ; 172.16,86.46 171.99,86.58
  BOTTOM w0.089: v1(171.87,93.6) 171.83,93.6 171.83,93.61 171.48,93.83 UC1.BT27
INT_SPK_L+: length 29.8
  IN1 w1.016: 277.68,52.84 275.9,51.06 275.9,45.01 276.09,44.82 276.09,41.23 281.75,35.57 288.45,35.57 290.37,37.49
  vias: v1(280.35,53.79) v1(280.98,53.79) v1(290,38.36) v1(290.63,38.36) v2(281.52,53.79)
INT_SPK_L-: length 21.7
  TOP w0.127: v1(288.98,38.36) 288.98,38.39 v2(289.4,38.81)
  IN1 w1.016: 277.43,50.18 277.43,45.64 277.62,45.45 277.62,41.86 282.38,37.09 287.77,37.09 288.18,37.5
  vias: v1(280.35,52.91) v1(280.98,52.91) v1(288.35,38.36)
INT_SPK_R+: length 13.8
  IN1 w1.016: 280.73,50.24 280.73,45.02 281.01,44.74 281.01,43.1 282.61,41.5 284.77,41.5 286.29,39.98
  vias: v1(280.35,51.19) v1(280.98,51.19) v1(286.47,38.36) v1(287.08,38.36) v2(280.68,50.76)
INT_SPK_R-: length 13.9
  IN1 w1.016: 284.09,39.57 283.69,39.98 281.66,39.98 279.2,42.43 279.2,50.14 279.15,50.19 279.2,50.24
  vias: v1(280.35,52.02) v1(280.98,52.02) v1(284.54,38.36) v1(285.17,38.36) v2(281.39,52.44)
INT_SPKR_L+: length 3.1
  TOP w1.016: 293.81,31.82 291.65,33.98
  vias: v1(293.81,30.55) v1(293.81,29.92) v2(294.1,31.04)
INT_SPKR_L-: length 4.7
  TOP w1.016: 291.65,31.32 289.24,31.32 288.6,31.95 288.6,33.35
  vias: v1(292.6,30.55) v1(292.6,29.92) v2(291.99,30.4)
INT_SPKR_R+: length 1.8
  TOP w1.016: 286.95,31.89 286.95,33.69
  vias: v1(287.02,31.06) v1(287.46,30.68) v2(286.48,31.09)
INT_SPKR_R-: length 1.8
  TOP w1.016: 284.73,33.69 284.67,33.63 284.67,31.89
  vias: v1(285.25,30.85) v1(285.68,30.44) v2(284.88,30.47)
INTRUDER#: length 15.4
  TOP w0.107: RC69.1 172.43,74.9 172.18,75.16 v1(172.18,75.66)
  BOTTOM w0.076: UC1.BR35 171.02,88.76 171.02,88.54 170.98,88.43 170.98,88.24 171.02,88.13 171.02,87.89 170.86,87.45 170.84,87.43 170.84,85.87 171.02,85.69 171.02,85.54 171.09,85.47 171.09,84.22 170.58,83.71 170.58,80.67 171.17,80.08 v2(171.17,78.84) 171.17,76.68 171.7,76.15
  BOTTOM w0.107: 171.7,76.15 v1(172.18,75.66)
IR_CAM_DET#: length 149.5
  TOP w0.107: RC345.2 197.8,94.69 v1(196.72,95.77) ; v1(96.71,117.64) v2(96.71,119.67) 96.71,122.05 96.54,122.22 96.54,123.7 96.12,124.12 96.12,126.57 96.41,126.87 96.41,127.93 96.63,128.14 v1(96.63,128.41)
  IN1 w0.089: 189.94,95.6 188.16,97.38 185.49,97.38 v1(185.08,96.97) 184.18,96.97 184.15,97.01 182.13,97.01 181.21,96.09 177.87,96.09 177.43,96.53 175.76,96.53 174.94,97.36 170.18,97.36 168.71,98.82 168.71,100.09 165.92,102.88 165.92,105.04 166.17,105.29 166.17,108.05 165.75,108.47 165.14,108.47 164.85,108.76 163.57,108.76 163.24,108.44 155.32,108.44 154.82,108.94 154.82,108.98 154.81,108.99
  IN1 w0.099: 154.81,108.99 154.31,109.49 151.06,109.49 148.26,112.29 146.99,112.29 143.16,116.12 141.45,116.12 139.41,118.16 139.41,118.16 139.21,118.36 137.47,118.36 137,117.88 136.62,117.88 136.13,118.38 133.84,118.38 133.62,118.16 132.58,118.16 131.91,118.84 126.25,118.84 124.7,117.29 v1(124.7,117.1) ; 189.94,95.6 190.02,95.52 193.59,95.52 193.87,95.8 196.68,95.8 v1(196.72,95.77)
  BOTTOM w0.076: UC1.CN22 181.87,97.04 182,96.91 182.09,96.87 182.29,96.87 182.38,96.92 182.39,96.92 182.64,96.92 182.66,96.9 182.76,96.87 183.09,96.87 183.19,96.97 v1(185.08,96.97)
  BOTTOM w0.107: JIRTS1.5 107.02,129.02 105.77,127.77 97.16,127.77 96.66,128.26 96.66,128.37 v1(96.63,128.41) ; v1(96.71,117.64) 97,117.94 109.02,117.94 109.72,117.24 123.05,117.24 123.19,117.1 v1(124.7,117.1)
ISEN1_IA: length 46.4
  TOP w0.203: PU602.9 86.66,95.32 86.36,95.02 86.36,93.63 85.86,93.14 v1(85.62,93.14) 85.62,92.58 PC635.2
  TOP w0.254: v1(107.37,107.26) 111.69,107.26 v2(112.54,108.11) 113.58,109.15 PR670.2 114.5,109.17 PR668.2
  IN2 w0.254: v1(107.37,107.26) 107.25,107.13 107.25,104.48 103.61,100.85 100.96,100.85 96.32,96.21 96.32,93.42 94.37,91.46 86.57,91.46 85.91,92.12 85.91,92.85 v1(85.62,93.14)
  BOTTOM w0.254: v1(85.62,93.14) 85.66,93.1 PR634.1
ISEN1N_IA: length 19
  TOP w0.254: PR677.1 v1(104.69,112.01)
  IN1 w0.254: v1(104.69,112.01) 106.05,112.01 107.56,110.5 115.82,110.5 116.2,110.88 v1(116.2,111.01)
  BOTTOM w0.254: PL610.2 v1(116.2,111.01) 117.66,109.55 PR666.1
ISEN1P_IA: length 3
  TOP w0.107: v1(116.2,108.53) v2(116.2,107.93)
  TOP w0.254: PR667.2 PR668.1 116.21,108.55 v1(116.2,108.53)
  BOTTOM w0.254: PL610.3 v1(116.2,108.53)
ISEN2_IA: length 44.4
  TOP w0.203: PU602.10 86.97,94.92 86.69,94.64 86.69,93.32 v1(86.51,93.14) 86.51,92.58 PC638.2
  TOP w0.254: PR675.2 PR677.2 v1(104.66,112.93)
  IN2 w0.254: v1(86.51,93.14) 86.29,92.92 86.29,92.28 86.72,91.84 94.21,91.84 95.94,93.58 95.94,96.4 100.77,101.23 103.46,101.23 106.8,104.58 106.8,111.77 105.65,112.93 v1(104.66,112.93)
  BOTTOM w0.107: v2(86.16,93.56) 86.51,93.22 v1(86.51,93.14)
  BOTTOM w0.254: v1(86.51,93.14) 86.55,93.1 PR615.1
ISEN2N_IA: length 16.5
  TOP w0.254: PR670.1 113.62,110.07 v2(113.15,109.6) 111.51,107.96 v1(107.37,107.96) ; v1(105.49,113.9) 105.47,113.88 PR673.1
  IN2 w0.254: v1(105.49,113.9) 105.88,113.9 107.44,112.34 107.44,108.02 v1(107.37,107.96)
  BOTTOM w0.254: PL613.2 v1(105.49,113.9)
ISEN2P_IA: length 4.6
  TOP w0.107: v1(102.99,115.26) v2(102.99,115.9)
  TOP w0.254: PR675.1 104,114.56 PR674.2 v1(102.99,115.26)
  BOTTOM w0.254: v1(102.99,115.26) 102.99,114.31 102.59,113.9 PL613.3
ISH_ACC1: length 6.8
  BOTTOM w0.076: UC1.BW35 173.76,88.96 173.54,88.74 173.54,88.54 173.49,88.43 173.49,88.24 173.53,88.16 173.53,87.86 173.52,87.85 173.52,87.85 173.52,87.84 173.51,87.83 173.51,87.54 173.58,87.46 173.58,87.46 173.58,86.76 173.35,86.53 173.35,84.07 174,83.43 T395.1
ISH_ACC2: length 6.8
  BOTTOM w0.076: T396.1 175.08,83.69 174.12,84.64 174.12,86.9 174.06,86.96 174.06,87.26 174.18,87.37 174.18,87.8 174.09,88.03 174.01,88.11 174.01,89.19 173.76,89.44 UC1.BW34
ISH_ALS: length 7.9
  BOTTOM w0.076: UC1.CA36 174.98,88.17 174.84,88.03 174.72,87.82 174.72,87.53 175.06,87.2 175.06,86.66 174.98,86.58 174.98,85.02 174.79,84.83 174.79,84.27 175.73,83.33 175.73,81.81 T398.1
ISH_I2C0_ACC_SCL: length 1.2
  TOP w0.102: T416.1 178.17,97.72 v1(178.69,97.72)
  BOTTOM w0.076: v1(178.69,97.72) 178.94,97.97 UC1.CH20
ISH_I2C0_ACC_SDA: length 4.8
  TOP w0.102: T415.1 177.36,95.72 177.63,95.98 178.3,95.98 178.37,96.05 179.45,96.05 v1(179.87,96.48)
  BOTTOM w0.076: v1(179.87,96.48) 180.24,96.84 UC1.CK22
ISH_I2C1_ALS_SCL: length 4.3
  TOP w0.102: T402.1 176.13,97.34 178.9,97.34 v1(179.28,97.71)
  BOTTOM w0.076: v1(179.28,97.71) 179.28,97.67 179.31,97.64 179.31,97.63 179.59,97.35 UC1.CJ22
ISH_I2C1_ALS_SDA: length 2.1
  TOP w0.102: T401.1 177.67,96.28 178.41,96.28 v1(178.69,96.56)
  BOTTOM w0.076: UC1.CH22 178.94,96.81 v1(178.69,96.56)
ISH_I2C2_SCL: length 123.2
  TOP w0.102: 183.93,94.41 183.83,94.41 183.82,94.41 182.73,94.41 181.68,93.36 180.71,93.36 180.6,93.26 180.6,92.81 180.12,92.33 v1(180.11,92.33)
  TOP w0.107: RZ76.1 269.41,78.98 269.41,78.06 v1(269.22,77.87) ; 183.93,94.41 185.56,94.41 185.64,94.33 187.09,94.33 187.76,95.01 190.42,95.01 RC362.1
  IN1 w0.089: 187.81,91.38 187.79,91.38 187.76,91.4 187.27,91.4 187.13,91.26 182.24,91.26 180.78,92.72 180.5,92.72 v1(180.11,92.33)
  IN1 w0.099: 187.81,91.38 188.38,91.38 188.49,91.26 188.58,91.26 189.32,90.52 190.07,90.52 190.39,90.84 199.54,90.84 200.47,91.77 203.51,91.77 203.68,91.6 217.05,91.6 219,93.56 222.49,93.56 223.33,94.4 224.11,94.4 224.92,95.21 233.38,95.21 235.04,96.87 237.25,96.87 238.38,98.01 239.75,98.01 v1(240,97.76)
  IN3 w0.102: v1(240,97.76) 240.24,98 241.05,98 241.31,97.74 241.31,95.24 242.74,93.81 242.74,92.99 243.42,92.31 243.42,90.53 242.53,89.65 242.53,87.29 243.47,86.36 247.33,86.36 247.71,85.98 250.32,85.98 250.75,85.54 255.65,85.54 256.09,85.1 256.09,84.53 258.25,82.37 260.66,82.37 263.14,79.89 264.8,79.89 266.3,78.39 269.22,78.39 269.41,78.2 269.41,78.07 v1(269.22,77.87)
  BOTTOM w0.089: UC1.CJ29 179.83,92.53 180.1,92.35 v1(180.11,92.33)
ISH_I2C2_SCL_R: length 2.5
  TOP w0.107: RZ76.2 269.15,80.82 v1(269.17,80.85) 269.17,81.06 v2(268.89,81.34)
  BOTTOM w0.107: v1(269.17,80.85) 269.33,81 JNGFF2.32
ISH_I2C2_SDA: length 123
  TOP w0.102: 183.93,94.64 183.91,94.64 183.9,94.64 182.63,94.64 181.58,93.59 v1(180.11,93.59)
  TOP w0.107: 183.93,94.64 185.65,94.64 185.73,94.56 186.99,94.56 187.67,95.24 190.4,95.24 RC363.1 ; v1(269.81,77.87) 269.65,78.04 269.65,78.98 RZ77.1
  IN1 w0.089: 187.81,91.6 187.79,91.6 187.76,91.58 187.19,91.58 187.05,91.44 182.32,91.44 180.86,92.9 180.8,92.9 v1(180.11,93.59)
  IN1 w0.099: 187.81,91.6 188.47,91.6 188.58,91.49 188.68,91.49 189.42,90.75 189.98,90.75 190.29,91.07 199.45,91.07 200.37,91.99 203.61,91.99 203.77,91.83 216.95,91.83 218.91,93.78 222.4,93.78 223.24,94.63 224.01,94.63 224.83,95.44 233.29,95.44 234.95,97.1 237.16,97.1 238.29,98.23 239.88,98.23 v1(240,98.35)
  IN3 w0.102: v1(240,98.35) 240.11,98.23 241.14,98.23 241.54,97.84 241.54,95.34 242.97,93.9 242.97,93.08 243.64,92.41 243.64,90.43 242.76,89.55 242.76,87.39 243.56,86.59 247.43,86.59 247.81,86.21 250.41,86.21 250.84,85.77 255.74,85.77 256.32,85.2 256.32,84.62 258.34,82.6 260.76,82.6 263.23,80.12 264.9,80.12 266.39,78.62 269.32,78.62 269.64,78.3 269.64,78.04 v1(269.81,77.87)
  BOTTOM w0.089: v1(180.11,93.59) 179.68,93.86 UC1.CJ27
ISH_I2C2_SDA_R: length 2.5
  TOP w0.107: RZ77.2 269.82,80.25 v1(269.82,80.89) 269.82,80.95 v2(270.21,81.34)
  BOTTOM w0.107: JNGFF2.34 v1(269.82,80.89)
ISH_LID_CL#_NB: length 4.6
  BOTTOM w0.076: UC1.CA34 174.9,89.48 174.68,89.03 174.68,88.08 174.56,87.86 174.56,87.47 174.86,87.16 174.86,86.7 174.44,86.27 T376.1
ISH_LID_CL#_TAB: length 3.6
  BOTTOM w0.076: UC1.BW37 173.76,87.41 173.74,87.39 173.74,84.17 T377.1
ISH_NB_MODE: length 4.3
  BOTTOM w0.076: T375.1 175.38,85.37 175.38,87.4 175.2,87.89 175.2,88.13 175.24,88.24 175.24,88.72 UC1.CA35
ISH_P_SENSOR_INT#: length 7.1
  BOTTOM w0.076: T385.1 174.73,82.05 174.73,83.81 173.96,84.58 173.96,86.83 173.9,86.89 173.9,87.32 174.01,87.44 174.01,87.78 173.98,87.87 173.76,88.09 UC1.BW36
ISH_TABLE_MODE#: length 5.7
  BOTTOM w0.076: UC1.CA37 174.98,87.61 175.22,87.37 175.22,86.59 175.14,86.52 175.14,84.95 174.96,84.77 174.96,84.33 176.14,83.15 T397.1
ISH_UART0_CTS#_R: length 7
  TOP w0.107: RZ80.2 290.7,42.73 290.17,42.21 v1(287.95,42.21) 287.36,42.21 287.21,42.05 285.77,42.05 v2(285.57,42.25)
  BOTTOM w0.107: JNGFF1.62 v1(287.95,42.21)
ISH_UART0_RXD_R: length 3.4
  TOP w0.107: v1(286.9,43.2) 286.99,43.28 287.07,43.37 287.07,43.89 RZ78.2
  BOTTOM w0.107: JNGFF1.58 286.95,41.98 287.08,42.11 287.08,43.02 v1(286.9,43.2)
ISH_UART0_TXD_R: length 3.4
  TOP w0.107: RZ79.2 287.31,43.98 287.31,43.38 v1(287.49,43.2)
  BOTTOM w0.107: v1(287.49,43.2) 287.31,43.02 287.31,42.11 287.45,41.97 JNGFF1.60
ISUMN_A_GT: length 5.7
  TOP w0.107: v2(95.33,91.54) 95.33,92.01 94.64,92.71 PC630.1
  TOP w0.203: PR640.1 93.35,92.71 92.78,93.28 91.72,93.28 91.52,93.48 PU602.20
  TOP w0.254: PC630.1 PR640.1
ISUMN_B_IA: length 2.5
  TOP w0.203: PR638.2 86.33,95.55 86.5,95.72 PU602.8
  TOP w0.254: PR638.2 85.7,94.82 PC627.2
ISUMN_C_SA: length 3.3
  TOP w0.203: PU602.28 v2(93.45,97.72) 94.34,97.72 PC632.1
  TOP w0.254: PC632.1 PR636.1
ISUMN_GT: length 43.4
  TOP w0.254: PC642.2 PC646.2 93.32,91.74 PR640.2 93.37,91.03 PR644.2 93.24,90.8 PC645.1 92.02,90.8 v1(91.87,90.96) ; v1(109.09,82.75) 109.32,82.98 v2(110.6,82.98) 113.99,82.98 114.24,83.23 PR656.2
  IN1 w0.254: v1(91.87,90.96) 91.87,90.26 98.8,83.32 108.52,83.32 v1(109.09,82.75)
  BOTTOM w0.254: v1(109.09,82.75) 109.15,82.81 115.2,82.81 PH605.2 115.9,87.46 116.2,87.77 PL612.2
ISUMN_IA: length 63.8
  TOP w0.254: PR673.2 106.04,111.76 v1(106.04,111.2) ; PC626.2 PC624.2 84.12,94.74 PR632.1 84.73,95.5 PR638.1 ; PC626.2 82.57,94.84 v1(82.19,94.84) ; PC626.2 PC641.1 83.5,93.6 83.74,93.36 83.74,92 v2(84.24,91.49) 84.45,91.29 PC635.1 PC638.1
  IN1 w0.254: v1(106.04,111.2) 107.12,110.12 117.5,110.12 118.89,108.74 v1(119.82,108.74)
  IN2 w0.254: v1(106.04,111.2) 106.36,110.88 106.36,104.85 103.12,101.61 100.58,101.61 95.56,96.59 95.56,95.58 94.2,94.22 84.92,94.22 84.2,94.94 82.29,94.94 v1(82.19,94.84)
  BOTTOM w0.254: v1(119.82,108.74) PR633.2 PH602.2 121.29,108.81 PR666.2
ISUMN_SA: length 106.6
  TOP w0.152: PC633.2 171.64,132.28 171.06,132.85 PL614.2 ; PC633.2 171.62,129.49 PH604.2 ; PC633.2 PR643.2 171.42,128.37 165.23,128.37 163.9,127.04 157.54,127.04 156.31,125.8 148.79,125.8 146.07,123.08 143.59,123.08 141.11,120.6 141.11,116.09 139.53,114.51 138.5,114.51 134.23,110.25 132.63,110.25 131.22,108.83 131.22,107.17 130.32,106.27 129.31,106.27 127.05,108.53 123.29,108.53 123.29,108.53 123.06,108.53 120.98,106.45 120.98,100.91 117.85,97.79 116.8,97.79 116,96.99 100.51,96.99 98.88,98.63 v2(97.44,98.63) 96.46,98.63 PC637.2 96.29,99.67 PC644.1 PR641.2 95.4,99.69 PR636.2
ISUMP_GT: length 38.7
  TOP w0.203: PU602.19 91.12,93.42 91.51,93.02 PC642.1
  TOP w0.254: PC642.1 PC646.1 91.51,91.29 v1(91.21,90.98) ; PR661.2 112.96,84.63 113.33,84.26 PR656.1 v2(112.16,83.51) 109.09,83.51 v1(108.33,82.75)
  IN1 w0.254: v1(108.33,82.75) 108.14,82.94 98.61,82.94 91.21,90.35 v1(91.21,90.98)
  BOTTOM w0.254: PR656.1 112.77,83.51 112.52,83.26 108.83,83.26 v1(108.33,82.75) ; PR653.2 91.21,91.35 v1(91.21,90.98)
ISUMP_IA: length 67.3
  TOP w0.203: PC624.1 83.84,95.86 84.1,96.12 PU602.7
  TOP w0.254: PC624.1 PC626.1 82.9,95.43 v1(82.19,95.43) 81.85,95.43 81.59,95.17 81.59,94.32 PR658.2 ; PR667.1 118.49,108.34 v2(119.01,107.82) v1(119.82,107.82) ; PR674.1 102.99,111.9 103.44,111.45 v1(105.28,111.45)
  IN1 w0.254: v1(105.28,111.45) 105.28,111.14 106.74,109.67 112.54,109.67 112.54,109.68 112.94,109.68 112.95,109.67 117.41,109.67 119.26,107.82 v1(119.82,107.82)
  IN2 w0.254: v1(82.19,95.43) 82.29,95.32 84.35,95.32 85.08,94.6 94.05,94.6 95.18,95.74 95.18,96.91 100.26,101.99 102.96,101.99 105.91,104.94 105.91,110.56 105.28,111.2 v1(105.28,111.45)
  BOTTOM w0.254: v1(119.82,107.82) PR633.1 120.45,107.45 120.38,107.38 PR628.1
ISUMP_SA: length 107.2
  TOP w0.152: v1(173.29,129.93) 173.05,129.93 172.59,129.47 PC633.1 PR643.1 172.55,128.56 172.08,128.09 165.35,128.09 164.02,126.76 157.65,126.76 156.42,125.52 148.9,125.52 146.18,122.8 143.7,122.8 141.38,120.48 141.38,115.97 139.65,114.23 138.62,114.23 134.32,109.94 132.72,109.94 131.5,108.72 131.5,107.05 130.44,105.99 129.19,105.99 126.93,108.25 123.17,108.25 121.26,106.33 121.26,100.77 117.99,97.51 116.91,97.51 116.12,96.71 100.4,96.71 98.86,98.24 v2(98.69,98.24) 96.64,98.24 PC637.1 96.22,97.89 95.65,97.32 PU602.27
  BOTTOM w0.107: 173.03,130.19 v1(173.29,129.93)
  BOTTOM w0.152: PR642.1 172.33,130.12 PR624.2 173.03,130.19
ITP_PMODE: length 76.8
  IN3 w0.102: v1(147.55,113.49) 146.95,114.09 145.82,114.09 137.61,122.3 116.73,122.3 112.86,126.17 97.99,126.17 96.88,127.28 95.93,127.28 94.09,129.12 89.22,129.12 88.6,129.74 v1(87.92,129.74)
  BOTTOM w0.076: UC1.W4 148.98,108.6 148.7,108.88 148.7,109.19 148.55,109.53 148.55,109.78 148.59,109.88 148.59,110.05 148.37,110.64 148.37,111.94 147.56,112.75 147.56,113.49 v1(147.55,113.49)
  BOTTOM w0.107: JXDP1.46 89.67,130.47 v2(89.43,130.24) 89.01,129.82 89.01,129.11 RC125.1 88.05,128.65 87.92,128.78 v1(87.92,129.74)
JDIMM1_EVENT#: length 6.2
  TOP w0.107: v1(134.28,45.56) 134.76,45.08 135.94,45.08 v2(136.98,46.13) RD14.1
  BOTTOM w0.107: v1(134.28,45.56) 134.7,45.97 JDIMM1.134
JDIMM2_EVENT#: length 3
  TOP w0.107: v2(212.06,39.94) RD27.1 212.06,41.12 211.94,41.24 v1(211.94,41.59)
  BOTTOM w0.107: JDIMM2.134 212.1,42 211.94,41.84 v1(211.94,41.59)
JTAG_CLK: length 42.7
  TOP w0.102: v1(247.98,97.44) 248.4,97.01 UE1.C8
  TOP w0.107: v1(217.74,84.4) 217.74,85.15 v2(218.04,85.46)
  IN1 w0.089: 246.6,98.8 247.97,97.44 v1(247.98,97.44)
  IN1 w0.099: v1(217.74,84.4) 217.74,84.85 218.47,85.58 219.26,85.58 221.85,88.17 226.48,88.17 229.51,91.2 233.81,91.2 236.24,93.63 238.37,93.63 238.87,94.14 239.69,94.14 240.93,95.39 240.93,96.37 244.3,99.73 245.67,99.73 245.92,99.48 245.93,99.48 246.6,98.8
  BOTTOM w0.107: RE720.2 218.12,84.77 217.75,84.4 v1(217.74,84.4) 217.74,84.39 217.47,84.12 JDEG1.4
JTAG_RST#: length 9.8
  TOP w0.102: 246.86,104.51 246.86,104.04 v2(247.49,103.41) 248.15,102.74 249.64,102.74 249.84,102.54
  TOP w0.107: 246.86,104.51 CE30.1 246.86,105.14 246.92,105.2 JTAG1.1 246.92,106.28 247.02,106.39 RE65.1 RE63.1 ; 249.84,102.54 249.86,102.52 250.57,102.52 251.21,101.88 251.21,101.45 UE1.G13
JTAG_TDI: length 66.3
  TOP w0.107: v1(219.36,84.07) 219.36,84.55 219.68,84.87 v2(219.68,85.82)
  TOP w0.127: v1(249.63,98.2) 249.63,98.2 249.66,98.2 UE1.E9
  IN1 w0.089: v1(249.63,98.2) 249.23,97.8 249.23,97.18 249.04,96.99 248.37,96.99 248.22,96.83 247.3,96.83 246.6,97.53
  IN1 w0.099: 246.6,97.53 246.29,97.84 246.21,97.84 246.19,97.86 244.8,97.86 244.36,97.42 243.6,97.42 242.65,96.47 242.23,96.47 241.64,95.88 241.64,93.81 240.81,92.98 239.75,92.98 237.74,90.97 237.23,90.97 234.83,88.56 234.83,76.33 235.47,75.68 235.47,73.54 235.86,73.15 236.15,73.15 236.33,72.97 v1(236.92,72.97)
  IN2 w0.102: v1(236.92,72.97) 236.92,73.74 229.81,80.84 227.61,80.84 224.56,83.89 219.54,83.89 v1(219.36,84.07)
  BOTTOM w0.107: JDEG1.2 218.47,83.57 218.98,84.07 v1(219.36,84.07) 219.56,84.07 219.64,84.16 RE715.2
JTAG_TDO: length 61.1
  TOP w0.102: UE1.F6 v1(250.45,95.01)
  TOP w0.107: v1(216.97,83.77) 216.97,83.43 v2(216.72,83.18)
  IN1 w0.089: 245.21,94.24 244.69,93.72 243.84,93.72 243.83,93.72
  IN1 w0.099: 243.83,93.72 242.04,91.92 240.19,91.92 238.55,90.29 238.55,87.5 235.05,84 235.05,76.42 235.7,75.78 235.7,73.64 235.95,73.38 v1(236.5,73.38) ; v1(250.45,95.01) 250.03,94.59 248.2,94.59 248.11,94.68 246.61,94.68 246.61,94.69 245.65,94.69 245.21,94.24
  IN2 w0.102: v1(236.5,73.38) 235.95,73.38 235.58,73.75 235.58,74.43 229.63,80.39 227.15,80.39 225.2,82.33 220.62,82.33 219.51,83.44 219.23,83.44 217.89,83.44 217.56,83.77 v1(216.97,83.77)
  BOTTOM w0.107: JDEG1.5 v1(216.97,83.77) 216.97,84.35 217.36,84.73 RE719.2
JTAG_TMS: length 55.7
  TOP w0.107: v1(218.55,84.44) v2(218.55,83.79)
  TOP w0.127: UE1.C5 v1(248.05,94.21)
  IN1 w0.089: 244.9,93.61 244.81,93.53 243.96,93.53
  IN1 w0.099: 244.9,93.61 245.75,94.46 247.8,94.46 v1(248.05,94.21) ; v1(236.1,73.81) 236.1,75.69 235.28,76.51 235.28,83.91 238.78,87.41 238.78,90.19 240.28,91.7 242.13,91.7 243.96,93.53
  IN2 w0.102: v1(218.55,84.44) 218.55,83.78 218.66,83.67 218.94,83.67 219.63,83.67 220.73,82.56 225.3,82.56 227.24,80.62 229.72,80.62 236.1,74.24 v1(236.1,73.81)
  BOTTOM w0.107: RE714.2 218.88,84.77 v1(218.55,84.44) 217.97,83.86 JDEG1.3
KB_DET#: length 200.3
  TOP w0.107: v2(182.66,38.95) v1(183.19,38.95) 183.57,39.34 CZ84.1
  IN1 w0.099: v1(205.56,92.25) 204.68,93.13 196.18,93.13 195.9,93.41 195.04,93.41 194.84,93.61 189.42,93.61 v1(189.29,93.48) 186.54,93.48 184.87,91.81 183.26,91.81 180.67,94.4 v1(180.43,94.4)
  IN2 w0.102: v1(205.56,92.25) 206.7,91.11 206.7,89.91 210.44,86.17 211.04,86.17 211.94,85.28 221.09,85.28 221.33,85.03 221.33,85.03 222.01,84.35 224.75,84.35 227.8,81.3 230.37,81.3 240.88,70.8 241.75,69.92 247.6,69.92 252,65.52 253.15,65.52 254.75,63.92 254.75,61.72 257.53,58.94 257.53,58.5 258.48,57.55 258.48,54.48 258.25,54.24 258.25,54.24 256.7,52.69 256.7,46.16 255.72,45.19 255.25,45.19 251.04,40.97 251.04,39.42 250.73,39.11 239.79,39.11 239.18,39.72 231.99,39.72 231.3,40.41 225.52,40.41 225.26,40.66 217.14,40.66 217.07,40.73 203.63,40.73 203.57,40.66 202.26,40.66 202.08,40.49 199.49,40.49 197.94,38.94 196.9,38.94 192.75,34.78 188.66,34.78 188.49,34.95 188.49,39.61 187.96,40.14 184.38,40.14 v1(183.19,38.95)
  BOTTOM w0.089: v1(180.43,94.4) 180.43,94.4 UC1.CK25
  BOTTOM w0.107: v1(189.29,93.48) 189.29,93.04 190.18,92.15 RC288.1 ; JKBTP1.1 183.49,39.25 v1(183.19,38.95)
LAN_ACTLED_YEL#: length 2.6
  TOP w0.107: QL1.6 287.44,115.11 v2(287.1,115.45)
  TOP w0.254: QL1.6 287.38,114.44 RL14.1
LAN_ACTLED_YEL_R#: length 26.1
  TOP w0.107: RL14.2 v2(285.22,115.66)
  TOP w0.254: v1(284.62,114.44) RL14.2
  IN1 w0.254: JLOM1.A2 306.72,112.51 305.49,113.74 289.58,113.74 288.88,114.44 v1(284.62,114.44)
LAN_DISABLE#_R: length 7.2
  TOP w0.107: UL1.3 270.46,103.53 270.06,103.13 268.79,103.13 v2(268.71,103.21) 266.34,103.21 RL9.1 RL7.2 RL5.1
LAN_MDIN0: length 4.3
  TOP w0.089: RL72.1 277.82,104.23 277.35,104.23 v4(276.09,105.49) 275.82,105.75 275.38,105.75 275.29,105.84 UL1.14
LAN_MDIN0_L: length 14.3
  TOP w0.089: RL72.2 280.12,104.19 281.83,104.19 284.22,101.8 286.57,101.8 287.75,100.62 287.75,98.67 288.17,98.25 288.31,98.25 v1(288.42,98.36)
  BOTTOM w0.089: v1(288.42,98.36) 288.6,98.19 288.73,98.19 289.15,98.61 TL1.2
LAN_MDIN1: length 4
  TOP w0.089: UL1.18 275.34,107.44 275.38,107.4 276.52,107.4 277.28,106.64 277.82,106.64 RL74.1
LAN_MDIN1_L: length 12.1
  TOP w0.089: v1(288.08,103.35) 287.95,103.21 285.29,103.21 281.9,106.6 280.12,106.6 RL74.2
  BOTTOM w0.089: TL1.6 288.93,103.69 288.43,103.19 288.24,103.19 v1(288.08,103.35)
LAN_MDIN2: length 3.9
  TOP w0.089: RL76.1 277.78,109.02 v4(277.1,109.02) 276.7,109.02 276.24,108.55 275.42,108.55 275.33,108.64 UL1.21
LAN_MDIN2_L: length 12.1
  TOP w0.089: RL76.2 280.12,109.02 v4(281.06,109.02) 283.46,109.02 286.74,105.73 288.05,105.73 v1(288.21,105.89)
  BOTTOM w0.089: TL1.8 289.05,106.23 288.55,105.73 288.37,105.73 v1(288.21,105.89)
LAN_MDIN3: length 4.6
  TOP w0.089: RL78.1 277.76,111.4 v4(277.15,111.4) 276.87,111.4 275.76,110.29 275.76,109.89 275.67,109.8 275.39,109.8 275.36,109.84 UL1.24
LAN_MDIN3_L: length 11
  TOP w0.089: v1(287.96,110.97) 287.8,110.81 v4(286.15,110.81) 283.52,110.81 282.9,111.43 280.12,111.43 RL78.2
  BOTTOM w0.089: TL1.12 288.84,111.31 288.34,110.81 288.11,110.81 v1(287.96,110.97)
LAN_MDIP0: length 4.3
  TOP w0.089: RL71.1 277.74,103.96 277.24,103.96 v4(276.86,104.33) 275.71,105.48 275.4,105.48 275.35,105.44 UL1.13
LAN_MDIP0_L: length 14.3
  TOP w0.089: v1(288.42,97.78) 288.22,97.98 288.06,97.98 287.48,98.56 287.48,100.51 286.46,101.53 v4(286,101.53) 284.11,101.53 281.72,103.92 280.12,103.92 RL71.2
  BOTTOM w0.089: TL1.1 289,97.34 288.78,97.56 288.78,97.69 288.66,97.8 288.44,97.8 v1(288.42,97.78)
LAN_MDIP1: length 4
  TOP w0.089: RL73.1 277.74,106.37 277.17,106.37 v4(276.96,106.58) 276.41,107.13 275.39,107.13 275.3,107.04 UL1.17
LAN_MDIP1_L: length 12.1
  TOP w0.089: RL73.2 280.12,106.33 281.78,106.33 285.17,102.94 v4(286.86,102.94) 287.9,102.94 288.05,102.79 288.06,102.79 v1(288.08,102.76)
  BOTTOM w0.089: TL1.5 288.92,102.42 288.42,102.92 288.24,102.92 v1(288.08,102.76)
LAN_MDIP2: length 3.8
  TOP w0.089: RL75.1 277.78,108.75 276.82,108.75 276.35,108.28 v4(276.02,108.28) 275.39,108.28 275.36,108.24 UL1.20
LAN_MDIP2_L: length 12.1
  TOP w0.089: v1(288.21,105.3) 288.05,105.46 286.63,105.46 283.35,108.75 280.12,108.75 RL75.2
  BOTTOM w0.089: TL1.7 289.09,104.96 288.59,105.46 288.37,105.46 v1(288.21,105.3)
LAN_MDIP3: length 4.6
  TOP w0.089: UL1.23 275.33,109.44 275.42,109.53 275.78,109.53 276.03,109.78 276.03,110.18 v4(276.23,110.38) 276.98,111.14 277.81,111.14 RL77.1
LAN_MDIP3_L: length 11
  TOP w0.089: RL77.2 280.12,111.16 282.79,111.16 283.41,110.54 287.8,110.54 v1(287.96,110.38)
  BOTTOM w0.089: v1(287.96,110.38) 288.11,110.54 288.35,110.54 288.85,110.04 TL1.11
LAN_TEST_EN: length 4.5
  TOP w0.107: v2(271.43,114.82) 271.43,113.38 RL12.1 272.04,111.82 272.07,111.8 272.07,111.32 272.06,111.31 UL1.30
LAN_WAKE#: length 165.2
  TOP w0.102: v1(255.25,92.6) UE1.L3 ; 173.21,86.55 173.21,86.55 172.81,86.55 172.47,86.89 172.47,86.99 172.47,88.84 172.85,89.22 v1(172.85,90.47)
  TOP w0.107: v1(269.81,103.58) 270.06,103.83 UL1.2 ; 173.21,86.55 176.91,86.55 177.52,85.94 177.52,84.47 178.39,83.59 178.39,82.91 179.04,82.26 179.99,82.26 180.67,81.57 v2(180.67,81.04) 180.67,79.84 181.44,79.07 181.44,77.44 181.79,77.09 181.79,71.77 RC323.1 RL70.1
  IN1 w0.089: v1(172.85,90.47) 172.85,90.45 172.81,90.41 172.81,90.17 178.76,84.21 178.76,83.5 179.22,83.04 181.7,83.04 182.86,81.88 182.86,81.69 183.86,80.68
  IN1 w0.099: 183.86,80.68 184.55,79.99 185.68,79.99 186.04,79.63 186.61,79.63 187.17,79.07 187.19,79.07 187.38,78.88 193.88,78.88 194.16,78.6 196.87,78.6 199.07,76.4 205.74,76.4 207.01,77.68 219.11,77.68 221.23,75.55 226.42,75.55 227.33,76.46 228.15,76.46 v1(228.23,76.53)
  IN3 w0.102: v1(255.25,92.6) 256.14,92.6 256.72,92.03 260.41,92.03 262.01,90.43 264.04,90.43 264.87,91.26 270.95,91.26 273.17,93.48 273.17,96.46 269.95,99.68 269.95,103.44 v1(269.81,103.58)
  BOTTOM w0.089: v1(172.85,90.47) 172.82,90.47 UC1.BU32 ; v1(255.25,92.6) 255.51,92.6 255.96,92.15 255.96,90.88 256.34,90.5 256.34,88.78 256.1,88.54 256.1,87.47 255.61,86.98
  BOTTOM w0.107: 255.61,86.98 254.41,85.78 254.41,84.49 253.95,84.03 253.01,84.03 252.75,83.77 252.13,83.77 249.72,81.35 249.72,79.48 247.76,77.52 238.79,77.52 237.76,78.55 236.85,78.55 236.13,77.83 232.78,77.83 231.83,76.88 228.57,76.88 v1(228.23,76.53)
LCD_CBL_DET#: length 107.9
  TOP w0.107: v1(146.17,129.74) 146.55,129.36 146.55,125.68 145.83,124.96 145.15,124.96 144.06,123.86 143.45,123.86 140.61,121.02 140.61,116.29 139.34,115.02 138.31,115.02 134.11,110.82 132.46,110.82 130.04,108.4 v1(130.04,106.82) ; RC749.1 194.86,98.85 v1(193.38,98.85)
  IN3 w0.089: 144.38,101.37 167.48,101.37 169.92,98.94 169.92,98.58 170.25,98.24 171.68,98.24 172.44,99 173.91,99 174.82,99.91 174.82,100.65 175.8,101.63 176.8,101.63 177.85,102.68 v1(177.85,102.85)
  IN3 w0.102: v1(193.38,98.85) 193.38,99.88 193.11,100.15 189.8,100.15 187.79,102.16 180.91,102.16 180.86,102.22 178.48,102.22 v1(177.85,102.85) ; 144.38,101.37 142.77,102.97 133.89,102.97 v1(130.04,106.82)
  BOTTOM w0.089: UC1.CF12 v1(177.85,102.85)
  BOTTOM w0.107: JEDP1.40 145.28,130.86 146.17,129.96 v1(146.17,129.74)
LCD_TST: length 157.6
  TOP w0.089: RE20.1 258.63,89.3 258.25,89.69 v1(258.25,90.12)
  TOP w0.107: UE1.M2 255.8,92.21 256.21,91.81 256.89,91.81 257.7,90.99 257.7,90.66 v1(258.25,90.12)
  IN2 w0.089: v1(258.25,90.12) 257.42,90.12 256.47,91.07 256.47,91.89 256.66,92.09 256.66,95.34 255.55,96.45 253.9,96.45 253.5,96.85 252.58,96.85 252.22,97.21 252.22,98.5 252.44,98.72 252.44,100.32 252.43,100.33
  IN2 w0.102: 252.43,100.33 252.43,101.65 251.85,102.23 251.85,104.26 250.35,105.76 249.53,105.76 249.21,106.08 249.21,106.52 248.95,106.78 248.95,107.88 248.93,107.91 248.93,111.18 242.74,117.38 203.07,117.38 194.8,125.65 194.8,128.01 192.84,129.97 184.45,129.97 183.32,128.83 177.49,128.83 177.31,128.65 166.04,128.65 163.78,130.91 156.83,130.91 154.47,133.27 144.3,133.27 141.64,130.6 139.82,130.6 139.56,130.34 v1(139.56,129.6)
  BOTTOM w0.089: v1(258.25,90.12) v2(258.25,89.51)
  BOTTOM w0.107: v1(139.56,129.6) 139.56,130.27 139.77,130.49 JEDP1.29
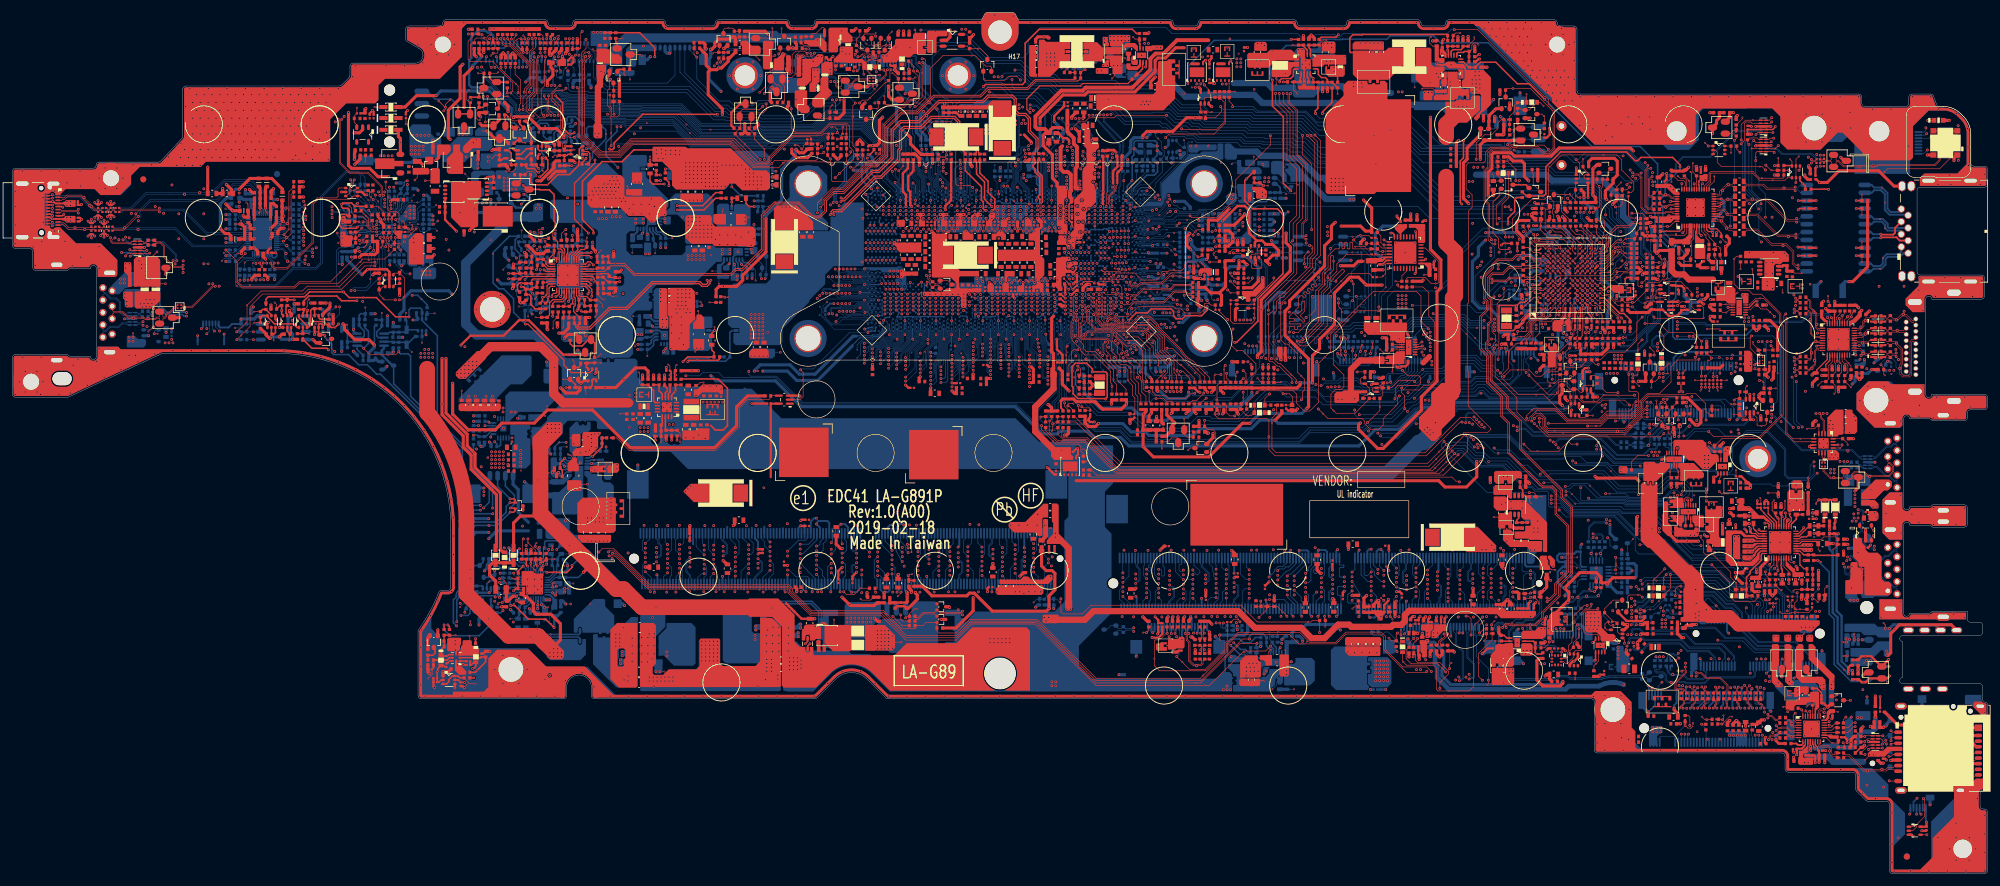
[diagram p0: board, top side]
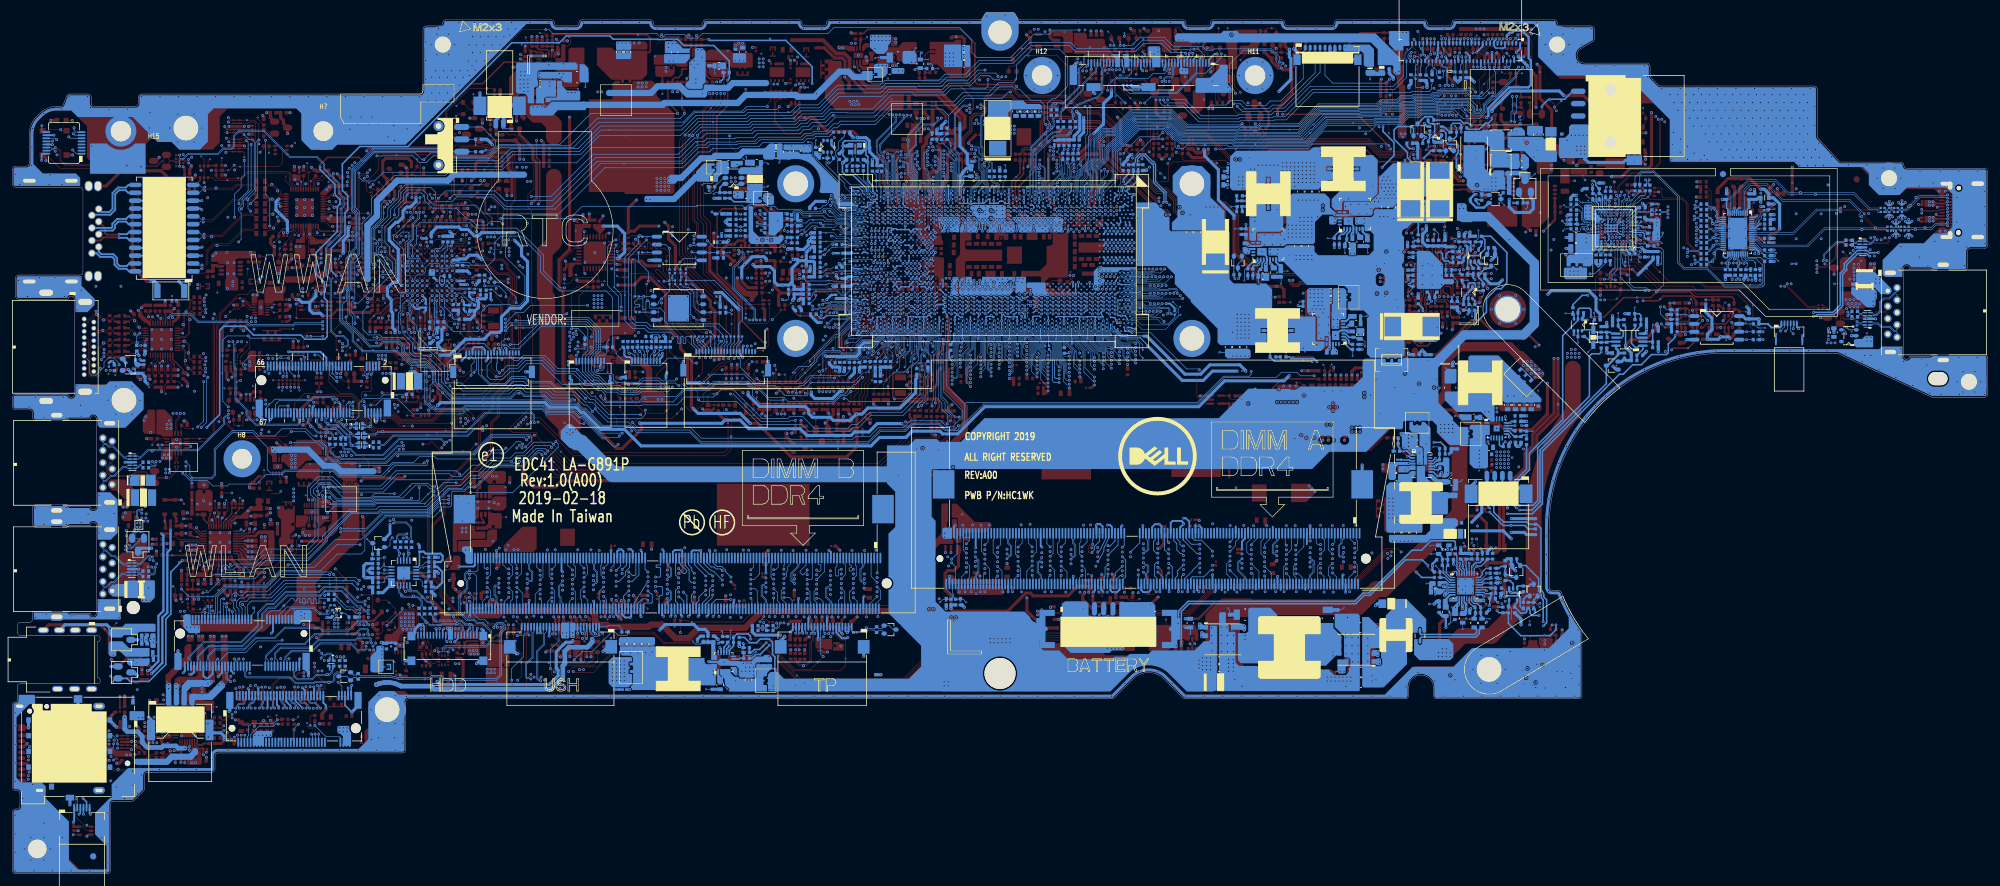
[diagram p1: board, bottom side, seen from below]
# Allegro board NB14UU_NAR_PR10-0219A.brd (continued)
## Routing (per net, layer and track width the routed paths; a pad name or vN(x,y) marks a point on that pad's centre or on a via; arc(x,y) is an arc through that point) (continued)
LCD_VCC_TEST_EN: length 142.9
  TOP w0.107: UE1.E1 250.05,91.06 249.87,90.88 v1(249.87,90.88) ; v1(162.84,128.27) 162.26,128.85 160.89,128.85 160.23,128.19 157.18,128.19 v2(156.99,128.38) 156.83,128.55 DV3.2 ; v1(240.9,94.57) 240.93,94.54 240.93,93.24 239.82,92.13 239.82,87.77 240.1,87.49 240.1,84.99 239.98,84.87 v1(239.98,83.11)
  IN1 w0.089: v1(249.87,90.88) 249.31,91.43 247.59,91.43 245.04,88.88 245.04,87.41 244.6,86.98
  IN1 w0.099: v1(239.98,83.11) 242.22,83.11 244.46,85.34 244.46,86.47 244.57,86.58 244.57,86.94 244.6,86.98
  IN2 w0.102: v1(240.9,94.57) 240.75,94.72 240.75,96.08 242.46,97.79 242.46,102.01 242.74,102.29 242.74,104.34 242.32,104.76 242.32,106.07 242.46,106.21 242.46,108.86 241.93,109.39 241.93,110.41 237.6,114.74 202.45,114.74 194.18,123.01 194.18,124.88 193.29,125.77 193.29,127.83 192.12,129 186.01,129 184.68,127.67 163.44,127.67 v1(162.84,128.27)
LCDVDD_MONITOR: length 2.3
  TOP w0.107: RV630.2 139.94,123.87 v2(139.7,123.63) 138.73,123.63 QV21.2
LDO_3V: length 2
  BOTTOM w0.107: v2(209.14,37.53) 208.71,37.09 207.92,37.09 207.55,37.46 PR104.1
LED_GRN#: length 2.2
  TOP w0.254: RL19.1 289.61,111.14 v2(289.16,111.58) 288.74,112 QL1.3
LED_GRN_R#: length 37
  TOP w0.254: RL19.2 v2(292.6,110.63) 293.34,110.63 v1(293.37,110.6)
  IN1 w0.254: v1(293.37,110.6) 293.37,93.23 293.87,92.72 293.87,92.21 294.09,92 303.37,92 306.72,95.35 JLOM1.B2
LED_MASK#: length 215.5
  TOP w0.107: UZ10.1 306.78,7.58 v1(307.02,7.82) ; v2(288.55,115.92) 288.09,115.47 QL1.5 QL1.2 288.09,111.72 v1(288.07,111.7)
  TOP w0.127: RE21.1 244.86,101.22 v1(245.16,100.93) 245.68,100.4 246.65,100.4 UE1.A12
  IN1 w0.099: v1(278.75,71.73) 278.32,71.29 278.32,70.24 277.87,69.8 277.17,69.8 275.81,68.44 271.87,68.44 264.23,60.79 264.23,40.09 263.68,39.54 260.57,39.54 258.18,37.15 258.18,31.07 259.55,29.69 262.91,29.69 263.01,29.59 263.01,28.97 267.27,24.71 267.27,22.68 268.91,21.03 286.77,21.03 286.85,21.12 293.02,21.12 296.52,17.62 297.94,17.62 300.05,15.5 301.3,15.5 302.89,13.92 302.89,13.51 304.48,11.93 304.48,8.46 305.11,7.82 v1(307.02,7.82)
  IN2 w0.102: v1(278.75,71.73) 278.99,71.96 278.99,77.13 285.55,83.7 285.55,93.04 286.7,94.18 286.7,98.24 284.03,100.91 284.03,105.89 v1(284.23,106.09) 284.23,111.55 284.38,111.7 v1(288.07,111.7)
  IN3 w0.102: v1(284.23,106.09) 283.83,106.5 277.42,106.5 276.43,105.51 268.77,105.51 268.49,105.23 266.91,105.23 265.42,106.72 262.14,106.72 261.75,106.34 260.88,106.34 259.87,105.33 256.18,105.33 255.57,104.72 250.94,104.72 248.08,101.86 246.25,101.86 245.31,100.93 v1(245.16,100.93)
LG1_CHG: length 21.8
  IN1 w1.016: 102.99,32.84 97.26,32.84 94.81,35.3 93.3,35.3 87.7,40.89 87.7,43.3
  BOTTOM w0.107: v1(104.58,32.65) v2(105.32,32.65)
  vias: v1(86.22,44.27) v1(86.8,44.27) v1(103.94,32.65)
LG2_CHG: length 33.3
  TOP w0.107: v1(87.73,45.01) 87.84,45.12 v2(87.84,45.53)
  IN1 w1.016: 88.58,44.84 88.98,44.44 90.01,44.44 94.75,39.7 119.18,39.7
  vias: v1(87.27,45.39) v1(120.07,40.02) v1(120.07,39.38)
LG_SA:
  vias: v1(176.4,134.92) v1(176.4,134.34) v1(184.88,133.49) v1(185.47,133.49)
LID_CL#: length 134.7
  TOP w0.107: v1(308.7,12.14) 308.86,11.98 v2(308.86,10.36) 308.86,9.22 307.53,7.88 307.53,7.5 306.95,6.93 UZ10.2 ; RE26.1 263.91,103.89 v1(264.12,103.69)
  IN2 w0.102: v1(268.92,86.85) 269.57,87.5 269.57,89.7 270.72,90.85 270.72,96.44 270.31,96.84 270.31,96.84 268.19,98.96 268.19,100.23 264.73,103.69 v1(264.12,103.69) ; v1(308.7,12.14) 308.54,12.14 308.27,12.41 308.27,17.54 305.93,19.88 300.19,19.88 299.97,19.65 299.33,19.65 298.7,20.28 298.7,20.65 295.17,24.18 295.17,29.77 293.56,31.38 293.11,31.38 288.51,35.98 277.48,35.98 276.78,36.68 276.78,44.98 273.81,47.95 273.81,50.62 270.67,53.76 270.67,57.83 271.74,58.9 271.74,61.64 270.82,62.56 270.82,69.99 271.1,70.27 271.1,74.6 271.84,75.33 271.84,77.47 270.86,78.45 v1(270.86,86.85)
  BOTTOM w0.107: v1(308.7,12.14) 308.57,12.02 JLED1.2 ; v1(270.86,86.85) v1(268.92,86.85)
LID_CL_SIO#: length 9.5
  TOP w0.102: UE1.N11 256.76,99.41
  TOP w0.107: RE26.2 262.36,103.71 CE8.1 262.36,102.94 RE25.2 v2(260.68,102.63) 260.55,102.63 259.88,101.95 259.1,101.95 258.19,101.05 258.19,100.18 257.43,99.41 256.76,99.41
LINE1-VREFO: length 12.5
  TOP w0.127: v2(291.35,59.76) 291.35,59.97 v1(291.78,60.4)
  TOP w0.203: UA1.24 286.13,57.23 286.44,57.54 286.44,58.24 v1(286.38,58.3)
  TOP w0.381: v1(291.78,60.4) 291.78,60.41 DA4.2 DA5.2
  IN1 w0.381: v1(291.78,60.4) 289.24,57.86 286.82,57.86 v1(286.38,58.3)
LINE1_L: length 2.9
  TOP w0.203: UA1.18 288.59,54.54 290.25,56.21 CA43.1
LINE1_R: length 2.6
  TOP w0.203: CA44.1 289.82,54.44 v2(289.23,54.44) 288.97,54.44 288.67,54.14 UA1.17
LM393_P: length 60.9
  IN2 w0.254: v1(75.61,58.76) 75.61,56.73 74.38,55.5 74.38,44.8 72.45,42.87 v1(72.45,41.73)
  BOTTOM w0.254: v1(75.61,58.76) 73.62,58.76 72.3,60.08 72.3,68.48 v2(67.45,73.33) 61.59,79.18 PD800.1 ; v1(72.45,41.73) 73.57,41.73 73.92,42.09 73.92,42.64 PR735.2 74.44,42.68 74.44,42.34 74.67,42.11 75.42,42.11 PC754.2 76.39,43.42 75.99,43.81 PU701.5
  BOTTOM w0.381: PD800.1 61.4,82.12 59.67,83.84 PC801.2 ; PC801.2 59.67,84.54 60.02,84.89 PU800.8 ; PC801.2 PR866.2
LOM_ACTLED_YEL#: length 16.6
  TOP w0.107: QL1.1 286.71,112.47 286.3,112.06 v2(284.34,112.06) 282.21,112.06 281.06,113.22 274.43,113.22 274.32,113.1 274.32,111.71 273.66,111.05 UL1.26
LOM_CABLE_DETECT#: length 73.5
  TOP w0.107: v1(283.22,114.5) 284.05,113.68 v2(284.16,113.68) RL20.1 ; RE505.1 245.6,86.05 245.6,86.08 245.61,86.09 245.61,88.79 246.23,89.41 246.53,89.41 246.67,89.55 247.68,89.55 v1(248.38,90.25) 248.38,90.82 248.85,91.28 248.85,91.81 UE1.D2
  IN2 w0.102: v1(283.22,114.5) 281.68,112.96 281.68,93.74 282.25,93.16 282.25,89.62 280.64,88.01 v1(280.02,88.01)
  IN3 w0.102: 255.93,89.83 256.85,88.91 262.25,88.91 262.82,88.34 267.77,88.34 268.77,87.35 279.36,87.35 v1(280.02,88.01) ; 248.78,89.85 v1(248.38,90.25)
  IN3 w0.107: 255.93,89.83 255.71,90.05 255.01,90.05 254.57,90.5 252.98,90.5 252.33,89.85 248.78,89.85
LOM_CONNLED_GRN#: length 20
  TOP w0.107: v1(288.59,113.68) 288.74,113.83 QL1.4 ; UL1.27 273.26,111.09 274.06,111.9 274.06,113.21 274.32,113.47 281.16,113.47 282.24,112.4 v2(282.57,112.4) 286.01,112.4 286.14,112.52 RL29.2 RL20.2 v1(286.91,113.68)
  IN2 w0.102: v1(288.59,113.68) v1(286.91,113.68)
LOM_LED2: length 2.5
  TOP w0.107: UL1.25 274.06,111.07 274.89,111.9 T315.1
LPM_1V_PRIM_CORE: length 3.6
  TOP w0.107: v2(206.78,133.92) PR430.2
  TOP w0.254: PU402.14 209.16,133.11 208.53,133.74 PR410.2 PR430.2
LPM_1VS_VCCIO: length 6.1
  TOP w0.107: PR425.2 107.84,71.18 v2(107.84,69.78)
  TOP w0.254: PU401.14 105.47,71.77 PR404.2 PR429.2 PR425.2
LX1_CHG: length 21.5
  TOP w0.107: v1(85.93,43.04) v2(86.51,43.04)
  IN3 w1.016: 97.59,35.63 96.11,35.63 88.51,43.23 87.32,43.23 ; 104.8,35.03 102.99,33.22 99.88,33.22 99.25,33.86 99.25,34.81
  vias: v1(85.48,43.48) v1(98.48,35.89) v1(98.48,35.25) v1(105.72,35.82) v1(105.72,35.19)
LX1_IA: length 0.6
  TOP w0.107: v1(118.36,106.06) v2(118.96,106.06)
  vias: v1(118.36,105.42)
LX2_CHG: length 39
  TOP w0.107: v1(89.2,46.1) v2(89.76,46.1)
  IN3 w1.016: 120.94,39.16 122.86,41.08 125.42,41.08 126.23,40.27 ; 119.03,38.21 117.31,38.21 114.61,40.9 95.56,40.9 90.29,46.17
  vias: v1(89.2,45.51) v1(119.95,38.49) v1(119.95,37.86) v1(126.93,38.94) v1(126.93,38.3)
LX2_IA:
  vias: v1(100.58,111.77) v1(101.21,111.77) v2(105.75,108.2)
LX_1.05VALWP:
  vias: v1(230.06,129.3) v1(230.35,128.72) v1(230.69,129.3) v1(233.86,129.33) v1(233.86,128.75) v2(228.99,127.86)
LX_1.8VALW: length 1.2
  BOTTOM w0.107: PR502.1 197.14,114.88 v2(196.95,114.69)
LX_1V_PRIM_CORE: length 2.1
  TOP w0.107: PL404.1 204.14,128.68 v2(204.14,127.45)
  vias: v1(204.91,130.88) v1(204.91,130.25)
LX_3V: length 1.7
  TOP w0.107: PR106.1 v2(205.61,36.17)
  vias: v1(202.18,32.27) v1(202.5,32.78) v1(205.8,32.78) v1(205.8,32.17)
LX_5V:
  vias: v1(80.58,74.62) v1(80.7,70.43) v1(80.71,69.8) v1(81.21,74.62) v2(86.37,75.54)
LX_DDR: length 1
  TOP w0.107: 91.87,62.94 v3(92.9,62.94)
  vias: v1(90.93,62.13) v1(91.64,62.15)
LX_GT: length 0.6
  TOP w0.107: v1(110.55,84.91) 110.55,84.64 v2(110.28,84.38)
  vias: v1(111.18,84.91)
LX_SA: length 0.9
  BOTTOM w0.107: v2(173.1,133.46) 173.36,133.2 173.36,132.67
  vias: v1(173.21,131.1) v1(173.79,131.1)
M2280_DEVSLP: length 171.8
  TOP w0.107: RN37.2 v1(272.85,24.14)
  IN2 w0.102: v1(272.85,24.14) 272.85,24.2 272.26,24.8 268.51,24.8 267.89,25.42 267.89,30.07 271.84,34.02 271.84,36.08 274.19,38.43 274.19,44.19 271.14,47.23 271.14,49.6 269.22,51.52 269.22,58.19 268.41,59 268.41,60.9 v1(268.41,60.9) ; v1(253.33,62.38) 253.63,62.68 253.63,63.52 252.66,64.48 251.74,64.48 248.3,67.93 235.89,67.93 232.47,71.35 232.47,75.41 229.74,78.14 225.88,78.14 224.17,79.85 223.27,79.85 222.23,80.88 220.75,80.88 220.32,80.45 220.26,80.45 220.21,80.4 216.81,80.4 214.92,82.29 213.7,82.29 212.61,83.39 210.75,83.39 208.85,85.29 204.39,85.29 202.24,87.44 202.24,91.2 198.56,94.88 198.56,99.33 198.18,99.71 196.53,99.71 194.46,101.78 193.31,101.78 193.16,101.93 191.38,101.93 190.77,101.32 189.77,101.32 186.49,104.59 186.49,107.6 v1(186.9,108)
  BOTTOM w0.076: UC1.CM8 181.16,106.26 182.05,106.26 182.4,106.14 182.63,106.14 182.72,106.17 182.98,106.43 v2(185.28,106.43) 185.33,106.43 186.72,107.82
  BOTTOM w0.107: 186.72,107.82 v1(186.9,108) ; v1(268.41,60.9) 268.41,60.54 267.74,59.87 260.81,59.87 260.41,60.26 253.5,60.26 253.33,60.43 v1(253.33,62.38) ; v1(272.85,24.14) 273.58,23.42 JNGFF3.38
M2280_PCIE_SATA#: length 145.8
  IN2 w0.102: v1(194.35,103.96) 194.35,103.91 196.34,101.93 197.99,101.93 201.51,98.41 201.51,97.99 202.39,97.11 202.39,95.69 204.22,93.85 204.22,91.97 210.25,85.94 210.94,85.94 212,84.88 221.15,84.88 221.91,84.12 224.66,84.12 227.71,81.07 229.91,81.07 242.18,68.81 248.39,68.81 251.93,65.27 252.85,65.27 254.43,63.69 254.43,60.84 v1(254.59,60.67) ; v1(267.81,60.83) 267.64,60.65 267.64,56.75 268.21,56.18 268.21,50.76 269.81,49.16 269.81,46.74 270.76,45.79 270.76,37.67 270.25,37.15 270.25,35.33 268.33,33.42 268.33,31.31 267.95,30.93 v1(266.44,30.93)
  BOTTOM w0.076: 186.72,105.46 186.25,105.46 186.03,105.23 184.24,105.23 183.99,104.98 182.76,104.98 182.24,104.69 UC1.CP10
  BOTTOM w0.107: v1(266.44,30.93) 265.82,30.32 JNGFF3.69 ; 186.72,105.46 187.87,105.46 188.07,105.66 v2(189.73,105.66) 190.35,105.66 190.86,105.16 192.59,105.16 193.05,104.7 RC730.1 193.45,104.7 193.61,104.85 RC764.2 194.35,104.4 v1(194.35,103.96) ; v1(267.81,60.83) 267.09,60.1 260.9,60.1 260.51,60.5 254.77,60.5 v1(254.59,60.67)
M3042_DEVSLP: length 120.9
  IN2 w0.102: v1(270.2,83.83) 270.19,83.83 270.06,83.96 270.06,89.55 271.18,90.66 271.18,96.63 269.81,98 269.81,101.48 268.51,102.78 268.51,106.14 266.79,107.87 v1(266.79,108.6)
  IN3 w0.102: v1(266.79,108.6) 266.76,108.63 263.53,108.63 263.15,109.01 260.22,109.01 258.32,110.91 248.47,110.91 246.59,109.03 246.59,106.93 245.68,106.02 240.27,106.02 v1(240.15,105.9)
  BOTTOM w0.076: UC1.CR8 182.86,105.91 183.19,106.25 184.08,106.25 184.21,106.12 185.48,106.12 186.72,107.36
  BOTTOM w0.107: 186.72,107.36 186.81,107.45 188.06,107.45 188.56,106.96 191.32,106.96 191.74,107.38 195.44,107.38 195.92,107.86 197.13,107.86 197.47,108.2 199.98,108.2 RC865.2 201.18,108.02 208.35,108.02 v2(208.52,107.86) 226.99,107.86 228.95,105.9 v1(240.15,105.9) ; v1(270.2,83.83) 269.61,83.83 268.82,83.04 JNGFF2.30
M3042_PCIE#_SATA: length 99.5
  TOP w0.107: v1(190.22,106.31) 190.49,106.05 194.51,106.05 197.61,109.15 197.61,112.15 v2(200.95,115.49) 203.2,117.74 v1(203.2,119.26) ; UE1.J12 253.25,100.26 v1(253.65,100.66)
  IN2 w0.102: v1(253.65,100.66) 253.65,101.64 253.3,101.99 252.87,101.99 252.31,102.55 252.31,104.45 251.19,105.57 251.19,106.32 250.97,106.54 250.97,106.54 250.5,107 250.5,107.51 249.39,108.63 249.39,111.37 242.24,118.52 236.6,118.52 236.19,118.92 233.09,118.92 232.69,118.52 203.93,118.52 v1(203.2,119.26)
  BOTTOM w0.076: UC1.CM10 181.3,105.01 182.49,105.01 182.72,105.14 183.92,105.14 184.26,105.48 186.05,105.48 186.26,105.69 186.72,105.69
  BOTTOM w0.107: RC766.2 193.35,105.86 RC521.1 192.77,105.69 192.69,105.76 192.69,106.84 192.62,106.91 191.93,106.91 191.34,106.31 v1(190.22,106.31) 188.09,106.31 187.46,105.69 186.72,105.69
M_BIST: length 36.4
  TOP w0.107: v1(258.03,97.29) 257.87,97.14 256.57,97.14 UE1.N8 ; v1(242.84,112.01) v2(242.84,113.8) 241.56,115.09 RZ1415.2
  BOTTOM w0.107: v1(242.84,112.01) 243.54,111.32 255.61,111.32 256.69,110.24 256.69,109.22 258.41,107.5 258.41,106.23 260.51,104.12 260.51,102.59 259.93,102 259.93,101.59 260.28,101.23 260.28,100.04 258.97,98.73 258.97,98.24 v1(258.03,97.29)
M_BIST_R: length 6.7
  TOP w0.107: RZ1482.2 RZ1415.1 RZ1413.2 239.95,114.31 DZ12.2 239.95,112.8 240.49,112.26 QZ21.2 240.43,111.94 CZ218.1 239.2,112.88 v2(238.92,113.15)
MASK_BASE_LEDS#: length 178
  TOP w0.107: UZ10.4 v1(309.23,6.28) ; v1(283.16,113.73) 282.63,114.26 v2(282.26,114.26) 276.06,114.26 275.38,114.95 275.38,116.62 275.05,116.95 QZ7.2
  IN1 w0.099: v1(309.23,6.28) 309.23,7.07 308.07,8.23 305.14,8.23 304.7,8.67 304.7,12.02 303.12,13.61 303.12,14.01 301.4,15.73 300.14,15.73 298.03,17.84 296.61,17.84 293.11,21.35 286.76,21.35 286.67,21.26 269.01,21.26 267.49,22.77 267.49,24.81 263.24,29.06 263.24,29.69 263.01,29.92 259.65,29.92 258.4,31.16 258.4,37.06 260.66,39.32 263.77,39.32 264.45,39.99 264.45,60.69 271.97,68.21 275.91,68.21 277.27,69.57 277.96,69.57 278.63,70.24 278.63,70.9 v1(278.89,71.16)
  IN2 w0.102: v1(283.16,113.73) 283.8,113.09 283.8,100.82 286.47,98.15 286.47,94.28 285.33,93.13 285.33,83.79 278.76,77.23 278.76,74.69 278.16,74.09 278.16,71.74 278.75,71.16 v1(278.89,71.16)
ME_FWP: length 31.6
  TOP w0.107: v1(251.23,100.63) 251.23,100.63 UE1.G12
  IN2 w0.089: 251.23,100.82 v1(251.23,100.63)
  IN2 w0.102: 251.23,100.82 251.23,101.43 251.37,101.57 251.37,104.09 250.19,105.28 248.35,105.28 246.99,106.65 246.99,109.08 244.38,111.69 244.38,115.16 v1(242.59,116.95)
  BOTTOM w0.107: SW1.1 v2(243.92,120.68) 243.22,120.68 241.03,118.49 241.03,117.58 241.67,116.95 v1(242.59,116.95) 242.88,116.66 RC221.1
ME_FWP_PCH: length 140.8
  TOP w0.107: v1(248.09,117.06) 247.41,117.74 243.16,117.74 243.07,117.82 242.1,117.82 241.69,117.41 238.74,117.41 237.94,116.61 237.94,115.21 237.61,114.88 235.21,114.88 234.82,114.49 234.82,110.68 235.78,109.71 235.78,107.68 235.17,107.07 235.17,92.23 234.99,92.05 234.99,81.31 235.16,81.14 v2(235.16,76.26) 235.16,75.59 238.79,71.95 238.79,71.8 238.27,71.28 234.45,71.28 234.34,71.17 234.34,70.67 229.02,65.35 178.75,65.35 173.67,70.43 169.77,70.43 169.49,70.7 169.49,71.46 169.7,71.67 RC562.1
  BOTTOM w0.107: RC221.2 245.11,116.66 245.12,116.68 SW1.3 247.71,116.68 v1(248.09,117.06)
MEC_XTAL1: length 7.2
  TOP w0.107: UE1.A1 245.23,91.41 v2(244.76,90.94) 244.76,90.73 243.31,89.28 CE28.1 241.54,89.28 241.33,89.08 YE1.1
MEC_XTAL2: length 3.3
  TOP w0.107: YE1.2 241.33,90.4 241.52,90.21 CE29.1 243.37,90.21 RE290.2
MEC_XTAL2_R: length 3.7
  TOP w0.127: UE1.A3 246.78,93.08 245.65,93.08 v2(244.85,92.27) 244.1,91.53 RE290.1
MEDIACARD_IRQ#: length 181.8
  TOP w0.107: RR19.1 288.73,26.74 v1(289.01,26.46) 289.21,26.26 UR1.32
  IN1 w0.089: v1(178.18,98.64) 178.18,98.44 178.37,98.24 180.53,98.24 180.78,98.5 183.19,98.5 183.65,98.04 188.95,98.04 189.78,97.21 191.11,97.21
  IN1 w0.099: 191.11,97.21 191.3,97.21 191.37,97.27 192.33,97.27 193.21,96.4 197.79,96.4 199.48,94.71 214.59,94.71 215.21,95.33 220.12,95.33 220.54,95.75 222.41,95.75 223.68,97.02 225.56,97.02 226.23,97.69 226.96,97.69 227.61,98.34 234.23,98.34 235.17,99.29 238.17,99.29 v1(238.8,99.92)
  IN2 w0.102: v1(269.74,61.8) 269.98,61.57 269.98,61.09 269.91,61.02 269.91,53.5 272.98,50.43 272.98,47.44 276.32,44.1 276.32,36.49 277.47,35.34 287.19,35.34 289.66,32.87 289.66,27.67 289.01,27.02 v1(289.01,26.46) ; v1(257.35,61.41) 256.07,62.69 256.07,64.46 251.47,69.07 251.47,69.84 249.29,72.02 247,72.02 246.24,72.78 246.24,73.74 245.32,74.65 244.18,74.65 238.27,80.56 238.27,80.8 235.77,83.3 235.77,90.98 235.94,91.15 235.94,94 237.88,95.95 237.88,96.47 238.36,96.95 238.36,99.48 v1(238.8,99.92)
  BOTTOM w0.076: v1(178.18,98.64) 178.29,98.52 UC1.CG20
  BOTTOM w0.107: v1(269.74,61.8) 269.74,62.38 269.2,62.92 267.78,62.92 265.66,60.81 261.2,60.81 260.59,61.41 v2(257.98,61.41) v1(257.35,61.41)
MEM_INTERLEAVED: length 33.2
  IN1 w0.089: 180.38,108.44 180.16,108.23 180.16,106.98 179.92,106.74 179.92,105.07 179.61,104.75 179.17,104.75 179.12,104.8 178.12,104.8 177.64,105.28 v1(177.62,105.28)
  IN1 w0.099: 180.38,108.44 183.1,108.44 184.74,110.08 187.26,110.08 190.53,106.81 195.34,106.81 196.21,105.94 198.19,105.94 198.38,106.13 199.57,106.13 199.65,106.06 200.9,106.06 v1(201.42,106.58)
  BOTTOM w0.089: v1(177.62,105.28) UC1.CE9
  BOTTOM w0.107: v2(202.28,107.68) 202.17,107.57 RC844.2 202.12,106.58 v1(201.42,106.58) 200.72,106.58 RC843.1
MEM_SMBCLK: length 24.5
  TOP w0.107: v1(196.64,100.33) 196.64,100.42 197.13,100.91 197.71,100.91 CC320.1 RC12.1 199.64,100.73 200.04,101.12 QC2.6
  IN1 w0.089: 191.03,101.01 191.01,101.01 191.01,101.01 190.96,101.01 190.85,100.9 190.85,100.89 190.5,100.54 189.72,100.54 188.03,102.23 186.17,102.23 185.04,101.1 183.51,101.1 183.14,101.47 180.83,101.47 180.71,101.34 180.15,101.34 180.04,101.45 180.04,101.57 v1(180.28,101.82)
  IN1 w0.099: 191.03,101.01 191.11,101.01 191.11,101.05 193.1,101.05 193.68,100.47 195.2,100.47 195.72,99.95 196.58,99.95 196.73,100.09 196.73,100.23 v1(196.64,100.33)
  BOTTOM w0.089: UC1.CK14 180.35,101.94 v1(180.28,101.82)
MEM_SMBDATA: length 29
  TOP w0.107: QC2.3 201.73,99.21 v2(201.73,97.97) 201.56,97.8 200.27,97.8 200.15,97.93 200.15,98.69 198.97,99.86 RC14.1 198.37,100.28 197.38,100.28 197.32,100.33 v1(197.22,100.33)
  IN1 w0.089: 191.03,100.83 190.57,100.37 189.64,100.37 187.96,102.05 186.24,102.05 185.11,100.92 183.43,100.92 183.07,101.29 180.91,101.29 180.78,101.17 179.51,101.17 v1(179.12,100.77)
  IN1 w0.099: 191.03,100.83 193.01,100.83 193.59,100.24 195.1,100.24 195.62,99.72 196.68,99.72 196.96,100 196.96,100.07 v1(197.22,100.33)
  BOTTOM w0.089: UC1.CH15 v1(179.12,100.77)
MSCLK: length 49.1
  TOP w0.107: v1(216.47,84.48) 216.47,84.97 v2(216.43,85.01) ; v1(252.07,99.03) 252.07,98.99 UE1.H10
  IN1 w0.099: v1(246.12,99.96) 245.87,100.21 243.62,100.21 242.28,98.87 242.28,98.39 240.45,96.57 240.45,95.59 239.49,94.62 238.67,94.62 238.17,94.11 236.04,94.11 233.61,91.68 229.31,91.68 226.28,88.65 221.65,88.65 219.06,86.06 218.05,86.06 v1(216.47,84.48)
  IN3 w0.089: 246.6,99.86 247.2,99.26 247.41,99.26 247.62,99.48 247.62,100.13 247.77,100.27 249.94,100.27 250.09,100.12 250.09,99.69 250.35,99.43 251.67,99.43 v1(252.07,99.03)
  IN3 w0.102: 246.6,99.86 246.5,99.96 v1(246.12,99.96)
  BOTTOM w0.107: JDEG1.6 v1(216.47,84.48) 216.47,84.53 216.59,84.66 RE72.2 RE30.1
MSDATA: length 79.8
  TOP w0.107: v1(215.32,84.4) 215.32,86.18 v2(215.67,86.52)
  TOP w0.127: UE1.G9 251.26,98.19 v1(251.26,98.24)
  IN1 w0.089: v1(251.26,98.24) 253.17,96.34 253.17,96.02 253.22,95.97 253.22,95.66 253.17,95.61 253.17,95.54 253.02,95.39 253,95.39 253,95.39 252.68,95.39 252.68,95.39 252.6,95.39 252.47,95.26 252.47,95.18 252.47,95.17 252.47,94.86 252.47,94.85 252.47,94.71 251.56,93.8 247.65,93.8 247.45,93.99 246.76,93.99 246.1,93.33 245.72,93.33 242.82,90.43 242.82,88.11 242.54,87.83
  IN1 w0.099: v1(237.34,72.56) 237.34,74.77 235.5,76.61 235.5,83.81 239.01,87.31 239.01,89.78 239.28,90.05 239.77,90.05 240.19,89.64 240.19,87.95 240.53,87.6 242.32,87.6 242.54,87.83
  IN2 w0.102: v1(237.34,72.56) 236.87,72.1 234.06,72.1 233.46,72.7 233.46,75.96 229.26,80.16 225.81,80.16 225.2,80.76 224.05,80.76 223.01,81.8 220.83,81.8 219.42,83.21 216.96,83.21 215.77,84.4 v1(215.32,84.4)
  BOTTOM w0.107: JDEG1.7 215.97,83.75 v1(215.32,84.4) 215.07,84.65 RE86.1 RE75.2
MUX1_DP_SEL: length 43.1
  BOTTOM w0.107: RT89.1 56.95,112.55 55.96,113.54 53.86,113.54 49.78,109.45 49.78,98.74 48.98,97.94 45.3,97.94 42.49,95.14 v2(38.35,95.14) 36.67,95.14 36.3,95.5 36.3,98.29 37.38,99.37 38.86,99.37 39.16,99.67 UT9.35
MUX1_FLIP_SEL: length 27.5
  TOP w0.107: v1(37.62,100.22) 36.35,98.95 36.35,95.73 37.19,94.88 45.52,94.88 46.3,95.66 51.38,95.66 v2(52.98,97.26) RT69.2
  BOTTOM w0.107: v1(37.62,100.22) 37.52,100.31 37.52,100.67 37.68,100.83 UT9.37
MUX1_FLIP_SEL_R: length 5.8
  TOP w0.107: v1(56.07,100.56) 55.39,100.56 RT69.1
  BOTTOM w0.076: UT5.B2 58.08,102.06 57.71,102.06 57.53,101.87 57.53,101.55 56.54,100.56 v1(56.07,100.56) 56.07,100.37 56.43,100.01 56.43,99.39
  BOTTOM w0.107: v2(56.23,98.84) 56.43,99.05 56.43,99.39
MUX1_USB_SEL: length 43.3
  BOTTOM w0.107: UT9.36 38.81,99.74 38.67,99.6 36.66,99.6 RT308.1 36.01,95.24 v2(36.23,95.02) 36.45,94.8 42.49,94.8 45.39,97.71 49.07,97.71 50.1,98.73 50.1,109.44 53.96,113.3 55.8,113.3 56.19,112.91 RT90.1
NB_MODE#: length 1.2
  TOP w0.127: v1(253.67,95) 253.61,95.05 253.61,95.05 UE1.J6
  BOTTOM w0.089: v1(253.67,95) 253.26,95.4 T348.1
NB_MUTE#: length 82
  TOP w0.107: v1(272.73,54.54) 272.73,54.2 273.17,53.76 273.17,51.9 273.5,51.57 274.69,51.57 277.55,48.71 277.55,47.88 v2(278.43,47) RA48.1 278.42,45.91 DA8.1
  TOP w0.127: UE1.A4 246.06,93.81 v1(245.97,93.9)
  IN2 w0.102: v1(272.73,54.54) 272.56,54.7 272.56,55.3 271.97,55.89 271.97,62.05 271.33,62.68 271.33,73.4 272.07,74.14 272.07,77.57 271.38,78.25 271.38,85.21 v1(271.36,85.24)
  IN3 w0.089: 247.72,86.98 247.6,87.1 244.22,87.1 243.37,87.94 243.37,89.88 243.84,90.35 243.84,91.43 245.97,93.55 v1(245.97,93.9)
  IN3 w0.102: v1(271.36,85.24) 268.33,85.24 267.11,86.46 264.51,86.46 264.27,86.7 262.64,86.7 262.2,86.25 259.45,86.25 259.44,86.26 255,86.26 254.57,86.69 248.01,86.69 247.72,86.98
NB_PSID: length 14.4
  TOP w0.107: PL3.2 73.84,124.62 73.39,125.07 73.39,126.25 v2(73.78,126.64)
  TOP w0.254: v1(71.99,123.9) PD4.3 PD4.2 73.92,124.57 PL3.2
  BOTTOM w0.254: PJPDC1.1 67.02,126.45 68.3,125.17 70.91,125.17 71.99,124.09 v1(71.99,123.9)
NFC_ACTIVITY_STATUS#_R: length 4.5
  TOP w0.107: v3(222.35,38.06) 222.79,37.62 RZ1473.2 223.53,38.69 v1(223.72,38.87)
  BOTTOM w0.107: v1(223.72,38.87) 223.89,39.05 224.53,39.05 224.78,39.29 JUSH1.2
NGFF_CONFIG_0: length 38.9
  TOP w0.107: UE1.N9 256.46,97.83 257.09,97.83 v2(258.52,99.25) 259.43,100.16 v1(259.43,100.49) 259.77,100.49 260.74,99.51 RE725.1
  IN2 w0.102: v1(264.03,76.21) 264.22,76.4 264.22,77.41 264.94,78.13 264.94,80.72 266.89,82.66 266.89,90.1 265.02,91.97 265.02,94.76 264.3,95.48 264.3,98.1 261.66,100.75 260.23,100.75 259.97,100.49 v1(259.43,100.49)
  BOTTOM w0.107: JNGFF2.13 264.58,75.66 v1(264.03,76.21)
NGFF_CONFIG_1: length 48.4
  TOP w0.107: RE723.1 261.21,101.31 v2(259.42,101.31) 259.04,101.31 v1(258.89,101.15) 258.42,100.69 258.42,100.08 257.45,99.11 256.78,99.11 256.65,98.98 256.01,98.98 UE1.M10
  IN2 w0.102: v1(267.27,76.67) 267.34,76.74 267.34,92.46 265.72,94.09 265.72,94.71 264.76,95.67 264.76,98.29 261.85,101.2 258.94,101.2 v1(258.89,101.15)
  BOTTOM w0.107: JNGFF2.61 276.58,75.79 275.92,76.45 270.7,76.45 270.23,76.91 267.51,76.91 v1(267.27,76.67)
NGFF_CONFIG_2: length 49.4
  TOP w0.107: RE724.1 v2(260.54,100.28) 260.45,100.28 259.8,100.92 259.24,100.92 v1(258.85,100.53) 258.85,100.16 257.3,98.61 UE1.N10
  IN2 w0.102: v1(258.85,100.53) 258.85,100.53 259.29,100.98 261.75,100.98 264.53,98.19 264.53,95.57 265.49,94.62 265.49,93.99 267.11,92.37 267.11,77.12 v1(266.66,76.67)
  BOTTOM w0.107: JNGFF2.67 278.08,75.24 276.64,76.68 270.8,76.68 270.33,77.15 267.14,77.15 v1(266.66,76.67)
NGFF_CONFIG_3: length 27.3
  TOP w0.127: v1(250.47,93.39) 250.47,93.44 UE1.F4
  IN2 w0.089: v1(251.07,87.07) 251.07,87.01 251.1,86.98
  IN2 w0.102: 251.1,86.98 252.15,85.93 252.15,81.48 254.29,79.35 254.64,79.35 258.95,75.04 v1(258.95,73.16)
  BOTTOM w0.107: RE726.1 250.71,86.64 251.07,87.01 v1(251.07,87.07) 251.07,87.64 250.88,87.83 v2(250.88,92.11) 250.88,92.98 v1(250.47,93.39) ; JNGFF2.1 259.58,73.34 259.39,73.16 v1(258.95,73.16)
NO_SMOKE_OVP: length 8.2
  TOP w0.107: v1(73.01,30.9) v2(73.48,30.43)
  TOP w0.254: v1(73.01,30.9) PC3008.1 71.99,31.3 PQ3000.5 ; PR3012.2 PC3009.1 74.11,33.73 74.57,34.19 PD3001.2 74.86,33.51 74.52,33.17 v1(74.33,33.17)
  IN2 w0.254: v1(74.33,33.17) 74.33,32.22 v1(73.01,30.9)
NO_SMOKE_UVP: length 5.1
  TOP w0.254: PR3013.2 69.86,33.4 69.61,33.65 PD3002.2 68.69,33.11 v2(68.69,32.69) 68.59,32.59 PC3010.1 PC3011.1 68.89,30.95 69.25,31.3 PQ3000.2
NRB_BIT: length 24.5
  TOP w0.089: 177.26,92.24 176.92,91.9 176.92,90.37 177.13,90.16 177.24,90.16 177.26,90.13
  TOP w0.102: v1(177.39,92.37) 177.26,92.24 ; 183.93,89.51 183.57,89.86 181.89,89.86 180.88,88.85 179.06,88.85 177.96,89.95 177.44,89.95 177.26,90.13
  TOP w0.107: RC831.2 192.59,80.35 v2(191.44,81.5) 189.19,83.74 188.72,84.44 188.66,84.57 184.84,88.39 184.84,88.59 183.93,89.51
  BOTTOM w0.089: UC1.CE29 v1(177.39,92.37)
NTC_A_GT: length 4.3
  TOP w0.203: PU602.15 89.52,93.02 v2(89.16,92.66) 88.93,92.43 87.57,92.43 87.27,92.12 PR635.2
NTC_B_IA: length 1.8
  TOP w0.203: PR610.2 85.87,98.35 86.5,97.72 PU602.3
NVME_LED#: length 9.2
  TOP w0.107: RN100.1 276.1,24.18 v1(276.11,24.18) 276.19,24.18 277.38,25.37 v2(277.76,25.37)
  BOTTOM w0.107: v1(276.11,24.18) 276.56,24.18 276.92,23.82 279.2,23.82 280.58,22.45 JNGFF3.10
ONE_DIMM#: length 24.9
  TOP w0.102: v1(177.39,93) 177.39,92.91 177.77,92.53 177.77,90.43 179.14,89.05 180.73,89.05 181.79,90.12 183.7,90.12 183.93,89.89
  TOP w0.107: 183.93,89.89 185.1,88.72 185.1,88.47 188.86,84.7 188.92,84.55 189.37,83.89 189.94,83.33 190.61,82.88 190.73,82.84 v2(192.61,80.95) 193.35,80.21 RC53.1
  BOTTOM w0.089: UC1.CE28 v1(177.39,93)
OTG_ID: length 3.7
  TOP w0.107: v1(64,104.21) 63.74,104.47 RT74.1 63.38,105.13 v2(63.01,105.5)
  BOTTOM w0.076: UT5.E10 62.58,104.06 63.06,104.06 63.14,104.13 63.92,104.13
  BOTTOM w0.107: 63.92,104.13 v1(64,104.21)
OTGEN/CMIN_CHG: length 3.7
  BOTTOM w0.203: PU700.20 v2(81.2,46.27) 80.51,46.27 80.4,46.16 PR712.2 79.47,46.16 PR746.2 PR709.2
OTGPG/CMOUT_CHG: length 5.4
  TOP w0.254: PR745.2 PR726.2 83,49.9 v1(83.2,49.71)
  BOTTOM w0.203: v1(83.2,49.71) 83.34,49.56 PU700.26
  BOTTOM w0.254: PR727.2 81.61,50.66 81.99,50.28 82.62,50.28 v1(83.2,49.71)
P_SENSOR_PWR_SAVE#: length 3.5
  BOTTOM w0.076: T400.1 185.07,103.32 184.99,103.41 184.51,103.41 184.34,103.23 183.17,103.23 183.02,103.09 182.72,103.09 182.42,103.39 UC1.CP12
PANEL_BKEN_EC: length 137.9
  TOP w0.107: v2(142.06,136.09) 141.55,135.59 DV2.2 141.55,134.43 141.72,134.26 v1(141.72,133.87)
  TOP w0.127: v1(253.68,98.22) 253.65,98.22 UE1.J9
  IN2 w0.089: 254.02,99.68 253.73,99.39 253.49,99.39 253.27,99.16 253.27,98.64 v1(253.68,98.22)
  IN2 w0.102: 254.02,99.68 254.02,99.7 254.03,99.72 254.03,100 254.29,100.26 254.29,101.01 254.11,101.19 254.11,101.83 253.4,102.54 253.4,104.48 251.9,105.98 251.9,107.26 250.88,108.28 250.38,108.28 249.84,108.81 249.84,111.56 242.43,118.98 236.79,118.98 236.33,119.43 232.47,119.43 231.62,120.28 204.37,120.28 193.97,130.68 184.2,130.68 183.48,129.97 177.52,129.97 176.88,129.33 166.33,129.33 164.07,131.6 157.52,131.6 155.16,133.95 141.81,133.95 v1(141.72,133.87)
PANEL_BKLEN: length 196.3
  TOP w0.107: DV2.3 140.25,134.02 v1(140.1,133.87)
  IN2 w0.102: v1(76.77,125.61) 78.78,125.61 79.89,126.72 88.23,126.72 88.78,126.17 96.09,126.17 96.17,126.25 97.31,126.25 99.64,128.59 103.76,128.59 109.29,134.12 121.04,134.12 123.4,131.76 125.64,131.76 126.36,131.04 130.91,131.04 131.49,131.62 138.71,131.62 138.97,131.88 138.97,132.74 v1(140.1,133.87)
  IN3 w0.089: v1(180.28,103.89) 180.27,103.89 179.81,104.35 177.27,104.35 176.29,103.36 175.57,103.36 175.05,102.85 175.05,101.58 174.33,100.86 174.33,100.15 174.12,99.95 169.6,99.95 167.6,101.95 144.86,101.95
  IN3 w0.102: 144.86,101.95 142.59,104.22 135.49,104.22 132.84,106.87 131.91,106.87 130.63,108.15 130.09,108.15 129.6,107.66 126.89,107.66 126.3,108.25 122.66,108.25 122.21,108.7 122.21,112.92 119.62,115.52 111.28,115.52 108.77,118.03 99.55,118.03 99.19,118.38 96.55,118.38 95.38,117.21 94.51,117.21 90.88,120.84 88.34,120.84 87.95,120.45 83.76,120.45 83.65,120.34 79.37,120.34 78.11,121.6 v1(76.98,121.6)
  BOTTOM w0.089: UC1.CK11 180.35,104.01 v1(180.28,103.89)
  BOTTOM w0.107: v1(76.77,125.61) 76.77,123.31 76.98,123.1 v1(76.98,121.6) ; v1(140.1,133.87) v2(140.1,134.39)
PANEL_MONITOR: length 205.9
  TOP w0.107: v1(96.53,125.84) 96.53,124.05 96.77,123.8 96.77,122.44 96.9,122.31 97.69,122.31 98.05,122.67 v2(98.05,123.59) RV628.2 ; v1(258.47,98.55) 258.24,98.55 257.14,97.46 256.09,97.46 UE1.M8
  IN2 w0.102: v1(258.47,98.55) 258.07,98.55 255.47,101.15 255.47,101.94 254.81,102.61 254.81,104.65 256.47,106.32 256.47,107.41 255.84,108.04 252.9,108.04 250.36,110.57 250.36,111.69 241.9,120.15 232.4,120.15 231.81,120.74 204.56,120.74 195.72,129.57 195.72,132.43 193.09,135.07 187.04,135.07 186.02,136.09 184.35,136.09 183.76,135.51 182.94,135.51 182.35,136.09 166.24,136.09 162.19,132.05 157.71,132.05 155.35,134.41 142.47,134.41 142.38,134.5 141.2,134.5 140.5,133.81 140.5,133.15 139.78,132.43 139.78,131.99 139.55,131.75 139.16,131.75 138.77,131.36 131.55,131.36 130.93,130.73 126.3,130.73 125.5,131.53 123.26,131.53 121.01,133.78 109.28,133.78 103.85,128.36 99.73,128.36 97.22,125.84 v1(96.53,125.84)
PANEL_PWRGD: length 76.3
  TOP w0.107: QV21.1 138.97,121.91 141.16,124.1 143.96,124.1 145.06,125.19 145.73,125.19 146.31,125.77 146.31,128.91 145.55,129.68 v1(145.55,129.74) v2(145.55,130.38) 145.55,130.53 RV623.2 ; v1(97.18,122.74) 97.14,122.78 RV628.1 RV624.1 CV632.1 97.14,126.83 97.09,126.88 QV19.1
  IN2 w0.102: v1(97.18,122.74) 97.18,122.8 101.34,126.96 110.05,126.96 111.74,128.65 113.53,128.65 115.04,130.15 115.04,130.66 116.48,132.1 120.85,132.1 124.2,128.75 132.72,128.75 133.29,129.32 137.73,129.32 138.48,128.57 143.12,128.57 143.96,129.41 145.22,129.41 v1(145.55,129.74)
PBAT_CHARGER_SMBCLK: length 280.4
  TOP w0.089: v1(259.33,89.8) 259.52,89.6 RE43.1
  TOP w0.102: UE1.N2 256.57,92.34 256.94,92.34 259.13,90.14 259.24,90.14 259.38,90 259.38,89.85 v1(259.33,89.8)
  TOP w0.107: PR38.2 146.07,41.34 146.24,41.34 147.12,42.22 148.94,42.22 PD2.3 149.74,42.23 153.3,42.23 v1(153.47,42.4)
  IN1 w0.089: 249.95,87.78 250.16,87.99 250.55,87.99 251.11,88.55 259.18,88.55 259.51,88.89 259.51,89.61 v1(259.33,89.8)
  IN1 w0.099: v1(153.47,42.4) 153.65,42.22 161.81,42.22 172.47,31.56 191.89,31.56 194.6,34.27 197.07,34.27 198.38,35.59 202.6,35.59 203.96,36.94 203.96,37.92 204.93,38.89 210.12,38.89 210.91,39.68 212.86,39.68 213.77,38.78 221.41,38.78 223.37,36.83 223.97,36.83 224.53,36.27 231.79,36.27 232.96,35.1 243.18,35.1 243.52,34.76 245.03,34.76 246.53,36.26 246.53,37.35 247.65,38.47 251.26,38.47 251.46,38.66 251.46,40.59 252.67,41.8 252.67,43.76 253.91,44.99 253.91,71.22 247.34,77.79 247.34,79.8 249.01,81.48 249.01,83.86 249.95,84.8 249.95,87.78
  IN3 w0.102: v1(78.68,47.67) 78.88,47.48 81.43,47.48 82.35,46.56 82.35,40.21 84.26,38.3 89.59,38.3 97.3,30.59 128.86,30.59 133.14,34.87 141.18,34.87 148.53,42.23 153.3,42.23 v1(153.47,42.4)
  BOTTOM w0.107: PR715.1 79.04,47.53 78.81,47.53 78.67,47.67 v1(78.68,47.67)
PBAT_CHARGER_SMBDAT: length 282.3
  TOP w0.089: RE37.1 260.41,89.3 v1(259.91,89.8)
  TOP w0.102: UE1.M3 256.09,92.57 257.03,92.57 259.23,90.37 259.34,90.37 v1(259.91,89.8)
  TOP w0.107: v1(153.47,41.82) 153.3,41.99 149.74,41.99 PD1.2 148.96,41.98 147.22,41.98 146.34,41.11 146.07,41.11 PR39.2
  IN1 w0.089: v1(259.91,89.8) 259.73,89.61 259.73,88.8 259.27,88.34 251.2,88.34 250.64,87.78 250.25,87.78 250.17,87.7 250.17,86.98
  IN1 w0.099: 250.17,86.98 250.17,84.7 249.23,83.76 249.23,81.38 247.56,79.71 247.56,77.88 254.13,71.31 254.13,44.9 252.9,43.66 252.9,41.71 251.68,40.49 251.68,38.57 251.36,38.25 247.74,38.25 246.75,37.26 246.75,36.16 245.12,34.53 243.42,34.53 243.08,34.87 232.86,34.87 231.69,36.04 224.44,36.04 223.88,36.6 223.27,36.6 221.32,38.56 213.67,38.56 212.77,39.46 211.01,39.46 210.21,38.67 205.02,38.67 204.18,37.83 204.18,36.85 202.69,35.36 198.48,35.36 197.17,34.05 194.69,34.05 191.98,31.34 172.38,31.34 161.72,42 153.65,42 v1(153.47,41.82)
  IN3 w0.102: v1(153.47,41.82) 153.3,42 148.62,42 141.27,34.64 133.24,34.64 128.96,30.36 97.21,30.36 89.5,38.07 84.17,38.07 82.13,40.11 82.13,46.46 81.33,47.25 78.88,47.25 v1(78.68,47.06)
  BOTTOM w0.107: v1(78.68,47.06) 78.92,47.3 78.98,47.3 PR713.1
PBAT_PRES#: length 281.8
  TOP w0.107: v1(228.46,32.68) 228.28,32.5 225.2,32.5 221.48,36.21 221.48,38.22 220.98,38.72 215.4,38.72 213.82,37.14 207.79,37.14 206.31,38.62 197.92,38.62 196.34,37.03 196.34,36.03 v2(192.33,32.03) 191.88,31.58 175.06,31.58 165.6,41.04 154.61,41.04 152.45,38.89 149.71,38.89 149.33,39.27 PR1.2 149.35,39.71 PD1.3 147.58,40.59 147.06,40.08 PR40.2 145.8,39.68 145.7,39.57 143.64,39.57 140.71,42.5 129.15,42.5 125.98,45.67 125.98,46.11 125.41,46.68 102.99,46.68 97.16,52.51 95.26,52.51 v1(94.73,51.98)
  TOP w0.127: v1(250.46,98.2) UE1.F9
  IN1 w0.099: v1(94.73,51.98) 92.72,51.98 90.94,53.77 84.1,53.77 84,53.66 80.12,53.66 79.43,52.98 v1(79.43,52.65)
  IN2 w0.089: v1(250.46,98.2) 250.42,98.2 250.03,97.81 247.82,97.81 246.84,96.83 246.84,95.56 247.77,94.63 248.22,94.63 248.44,94.41 248.44,92.38 249.2,91.61 249.2,90.54 248.54,89.87 247.29,89.87 246.49,89.08 246.49,86.98
  IN2 w0.102: v1(228.46,32.68) 228.93,33.15 230.24,33.15 231.77,34.68 239.49,34.68 240.03,34.14 242.79,34.14 243.4,33.53 253.3,33.53 255.8,36.03 256.73,36.03 257.21,36.51 257.21,37.99 259.53,40.31 259.53,41.2 259.94,41.61 259.94,45.47 260.38,45.91 260.38,50.54 261.36,51.51 261.36,60.53 257.89,63.99 257.89,65.22 257.04,66.07 257.04,66.6 254.06,69.58 254.06,71.23 250.71,74.58 249.98,74.58 246.65,77.91 246.65,79.56 247.85,80.75 247.85,84.35 246.49,85.71 246.49,86.98
  BOTTOM w0.107: PR724.1 79.96,52.28 79.58,52.65 v1(79.43,52.65)
PBAT_PRES#_C: length 5.1
  TOP w0.107: PR40.1 v2(143.72,40.08) v1(142.25,41.55)
  BOTTOM w0.107: v1(142.25,41.55) 142,41.79 141.63,41.79 141.27,42.14 PBATT1.6
PBAT_SMBCLK_C: length 4.1
  TOP w0.107: v2(146.09,42.8) 145.71,42.8 144.89,41.98 PR38.1 144.55,41.6 v1(144.28,41.33)
  BOTTOM w0.107: v1(144.28,41.33) 144.27,41.34 PBATT1.4
PBAT_SMBDAT_C: length 3.5
  TOP w0.107: v1(143.49,41.82) 143.49,41.05 143.7,40.84 PR39.1
  BOTTOM w0.107: v1(143.49,41.82) 142.77,42.54 PBATT1.5
PCH_3.3V_TS_EN: length 170.7
  TOP w0.107: v1(113.82,130.97) 113.82,131.18 114.1,131.46 RV324.1 ; RC747.1 195.72,79.65 v2(195.72,81.47) 195.72,81.95 v1(195.91,82.14)
  IN1 w0.089: 176.92,90.07 176.85,90.14 176.85,91.35 v1(176.47,91.73)
  IN1 w0.099: 187.21,85.2 186.4,86.01 185.52,86.01 184.01,87.53 183.21,87.53 182.89,87.85 182.15,87.85 181.7,88.3 177.8,88.3 ; 177.28,89.71 177.28,88.82
  IN1 w0.102: 187.21,85.2 187.7,84.7 187.99,84.7 190.79,81.9 195.67,81.9 v1(195.91,82.14) ; 176.92,90.07 177.28,89.71 ; 177.28,88.82 177.8,88.3
  IN2 w0.102: v1(121.48,126.11) 121.74,125.84 131.36,125.84 131.67,126.15 143.7,126.15 144.34,126.79 146.98,126.79 148.53,125.25 154.45,125.25 154.63,125.42 159.3,125.42 159.63,125.75 161.21,125.75 161.85,126.39 187.59,126.39 189,124.98 189,121.43 187.96,120.4 187.96,119.69 186.61,118.34 186.61,117.07 186.49,116.95 186.49,116.68 185.45,115.63 185.45,113.99 182.78,111.32 182.78,101.91 182.59,101.72 182.59,97.57 183.02,97.14 183.92,97.14 185.09,95.98 189.33,95.98 190.14,95.17 190.14,92.25 191.87,90.52 194.31,90.52 195.91,88.92 v1(195.91,82.14)
  BOTTOM w0.089: UC1.CC30 v1(176.47,91.73)
  BOTTOM w0.107: v1(113.82,130.97) 113.83,130.97 114.13,130.66 114.54,130.66 114.93,131.24 114.93,132.22 115.78,133.07 120.19,133.07 122.42,130.83 122.42,127.83 v1(121.48,126.11)
PCH_BATLOW#: length 20.5
  TOP w0.102: 177.86,87.36 177.5,87.72 173.64,87.72 v1(173.06,87.13)
  TOP w0.107: 177.86,87.36 177.86,87.04 179.34,85.56 179.34,84.54 179.56,84.33 179.56,84.24 179.72,84.08 179.72,83.71 180.12,83.31 180.95,83.31 v2(182.13,82.13) 181.73,81.73 181.73,80.79 182.21,80.32 182.21,79.86 182.42,79.65 182.42,77.84 183.1,77.16 RC72.1
  BOTTOM w0.076: v1(173.06,87.13) 173.11,87.18 UC1.BV36
PCH_CL_CLK1: length 153.7
  IN3 w0.089: 180.88,108.44 180.37,108.44 179.94,108 179.94,107.13 v1(179.39,106.58) ; 190.6,104.21 190.56,104.21 190.5,104.28
  IN3 w0.102: 190.5,104.28 190.05,104.28 189.67,103.9 189.03,103.9 188.46,104.47 186.87,104.47 184.59,106.75 184.01,106.75 183.13,107.64 182.3,107.64 181.51,108.44 180.88,108.44 ; 190.6,104.21 192.02,104.21 193.24,105.43 194.92,105.43 195.06,105.29 195.06,105.29 195.97,104.39 198.32,104.39 198.73,103.98 198.96,103.98 201.15,106.17 202.42,106.17 202.5,106.25 212.1,106.25 215.13,103.21 215.13,98.87 215.39,98.61 215.39,95.58 216.37,94.6 216.37,93.27 216.87,92.76 216.87,90.79 220.29,87.37 220.29,86.9 221.93,85.26 221.93,83.57 222.98,82.51 222.98,81.32 225.69,78.62 225.85,78.62 226.77,77.7 226.84,77.7 227.6,76.94 229.58,76.94 234.05,72.47 235.41,72.47 235.67,72.21 236.18,72.21 237.35,71.05 237.77,71.05 241.81,67.01 248.36,67.01 251.67,63.7 251.67,60.21 252.11,59.76 252.11,55.91 255.27,52.74 256.24,52.74 257.73,51.25 257.73,50.85 258.51,50.07 259.97,50.07 260.56,49.48 260.56,48.53 261.7,47.39 v1(263.01,47.39)
  BOTTOM w0.089: v1(179.39,106.58) 179.37,106.5 UC1.CH7
  BOTTOM w0.107: v1(263.01,47.39) 263.13,47.39 263.58,47.84 268.72,47.84 268.72,47.85 275.63,47.85 277.93,45.54 281.34,45.54 281.87,45.01 282.49,45.01 282.86,45.38 283.24,45.38 283.58,45.03 283.58,44.13 283.31,43.86 283.31,42.88 282.95,42.52 JNGFF1.42
PCH_CL_DATA1: length 155.7
  IN3 w0.102: v1(179.39,105.92) 179.86,106.39 179.86,106.66 180.17,106.96 181.47,106.96 181.57,106.86 181.57,105.97 181.68,105.86 181.88,105.86 181.98,105.97 181.98,106.86 182.08,106.96 182.29,106.96 182.39,106.86 182.39,105.59 182.49,105.48 182.69,105.48 182.79,105.59 182.79,106.86 182.89,106.96 183.12,106.96 184.09,105.99 184.59,105.99 186.57,104.02 188.41,104.02 188.97,103.45 189.66,103.45 190.1,103.9 190.25,103.9 190.42,103.73 192.22,103.73 193.44,104.95 194.72,104.95 194.95,104.72 194.95,104.72 196.25,103.42 199.34,103.42 200.89,104.98 201.99,104.98 202.78,105.76 211.89,105.76 214.65,103.01 214.65,98.67 214.9,98.41 214.9,94.44 215.88,93.46 215.88,91.09 219.81,87.17 219.81,86.7 221.45,85.06 221.45,83.37 222.5,82.31 222.5,81.12 225.49,78.14 225.65,78.14 226.57,77.22 226.64,77.22 227.01,76.85 227.01,76.08 227.35,75.74 230.1,75.74 233.85,71.98 235.21,71.98 235.47,71.73 235.98,71.73 237.15,70.56 237.57,70.56 238.94,69.19 238.94,68.61 239.41,68.15 239.99,68.15 241.61,66.53 247.83,66.53 250.35,64 250.35,60.84 251.63,59.56 251.63,55.71 255.07,52.26 256.04,52.26 257.25,51.05 257.25,50.65 258.31,49.59 259.25,49.59 260.08,48.76 260.08,48.33 261.6,46.81 v1(263.24,46.81)
  BOTTOM w0.089: UC1.CH8 179.38,105.87 v1(179.39,105.92)
  BOTTOM w0.107: v1(263.24,46.81) 263.79,47.36 v2(265.55,47.36) 268.91,47.36 268.91,47.36 275.15,47.36 277.46,45.05 281.08,45.05 281.61,44.52 282.32,44.52 282.73,44.11 282.73,44.1 282.82,44.01 282.82,43.08 282.45,42.71 JNGFF1.40
PCH_CL_RST1#: length 155.5
  IN3 w0.089: v1(179.39,105.28) 179.83,105.28 180.23,104.89 184.18,104.89
  IN3 w0.102: v1(263.27,45.98) 262.68,45.39 262.54,45.39 262.04,45.9 261.31,45.9 260.46,46.74 260.46,46.88 260.58,47 260.58,47.15 260.43,47.29 260.29,47.29 260.17,47.17 260.03,47.17 259.89,47.32 259.89,47.46 260,47.58 260,47.72 259.86,47.86 259.72,47.86 259.6,47.75 259.46,47.75 259.31,47.89 259.31,48.03 259.59,48.32 259.59,48.46 259.45,48.6 259.31,48.6 259.02,48.32 258.88,48.32 257.23,49.97 257.23,49.98 255.96,51.25 254.93,51.25 251.15,55.04 251.15,59.36 249.87,60.64 249.87,63.8 247.63,66.04 241.41,66.04 241.03,66.42 240.88,66.42 240.5,66.04 240.36,66.04 240.22,66.19 240.22,66.33 240.6,66.71 240.6,66.85 240.45,67 240.31,67 239.35,66.04 239.21,66.04 239.07,66.19 239.07,66.33 240.02,67.28 240.02,67.43 239.79,67.66 239.61,67.66 238.56,66.62 238.42,66.62 236.59,68.44 235.15,68.44 234.43,69.16 234.3,69.16 229.41,74.05 226.6,74.05 222.73,77.92 222.23,77.92 221.31,78.85 221.31,81.82 220.25,82.87 220.25,84.57 217.4,87.42 217.4,87.77 214.69,90.49 214.69,92.97 213.37,94.28 213.37,101.59 212.85,102.12 210.56,102.12 208.69,103.99 204.39,103.99 203.92,103.52 203.66,103.52 201.64,101.5 196.05,101.5 194.48,103.07 193.75,103.07 193.36,102.69 190.64,102.69 190.46,102.87 189.11,102.87 188.14,103.84 186.49,103.84 185.3,105.03 184.32,105.03 184.18,104.89
  BOTTOM w0.089: UC1.CH9 179.38,105.23 v1(179.39,105.28)
  BOTTOM w0.107: JNGFF1.38 281.95,42.9 282.34,43.28 282.34,43.81 282.25,43.9 282.25,43.91 282.13,44.02 281.26,44.02 280.71,44.56 277.26,44.56 274.95,46.87 269.1,46.87 269.1,46.87 v2(264.16,46.87) v1(263.27,45.98)
PCH_DP2_HPD_R: length 2.5
  TOP w0.107: v1(61.85,102.81) 61.85,102.44 61.72,102.31 RT73.1 v2(62.71,101.81)
  BOTTOM w0.102: UT5.C10 v1(61.85,102.81)
PCH_DPWROK: length 114.3
  TOP w0.107: v1(234.16,72.99) 233.84,72.99 228.39,67.54 203.94,67.54 202.95,68.52 v3(202.95,70.62) 202.95,73.24 202.61,73.58 198.15,73.58 198.07,73.5 194.86,73.5 194.28,74.08 v1(194.28,74.31) 194.28,74.69 RC215.1 194.38,75.22 194.31,75.22 194.13,75.4 194.13,75.5 RC220.1 CC266.1
  IN1 w0.089: v1(171.01,91.73) 170.62,91.35 170.62,90.88 170.62,90.88 170.62,89.93 171.32,89.22 171.32,86.49
  IN1 w0.099: v1(237.68,92.27) 233.87,88.45 233.87,77.8 234.16,77.5 v1(234.16,72.99) ; v1(194.28,74.31) 192.75,72.78 190.67,72.78 189.59,73.86 189.23,73.86 188.79,74.29 187.83,74.29 186.94,75.18 182.64,75.18 181.34,76.47 180.63,76.47 177.32,79.78 177.32,80.68
  IN1 w0.102: 171.32,86.49 171.52,86.3 171.52,84.55 173.83,82.24 175.76,82.24 177.32,80.68
  BOTTOM w0.089: UC1.BP30 v1(171.01,91.73)
  BOTTOM w0.107: RE536.1 240.13,95.56 237.68,93.11 v1(237.68,92.27)
PCH_DPWROK_EC: length 13
  TOP w0.127: UE1.F8 250.46,97.4 v1(250.46,97.45)
  IN1 w0.099: v1(250.46,97.45) 249.8,96.79 248.45,96.79 248.3,96.64 247.08,96.64 246.67,97.05 245.84,97.05 245.51,97.38 245,97.38 244.56,96.94 243.8,96.94 242.85,95.99 242.43,95.99 242.12,95.68 v1(242.12,95.58)
  BOTTOM w0.107: v2(242.62,97.76) 241.8,96.94 RE536.2 242.12,95.88 v1(242.12,95.58)
PCH_HDD_EN: length 133.2
  TOP w0.107: RZ148.1 247.45,36.48 248.26,37.28 v1(248.26,37.48)
  IN2 w0.102: v1(200.23,100.5) 200.51,100.5 201.73,99.27 201.73,98.09 202.62,97.2 202.62,95.78 206.99,91.41 206.99,89.94 210.45,86.48 211.29,86.48 212.27,85.5 221.18,85.5 222.1,84.58 224.85,84.58 227.74,81.68 230.32,81.68 241.73,70.27 247.58,70.27 252.09,65.75 253.24,65.75 254.98,64.01 254.98,61.81 258.09,58.7 258.09,58.46 258.71,57.84 258.71,54.38 258.34,54.01 256.93,52.6 256.93,46.07 255.82,44.96 255.35,44.96 251.53,41.14 251.53,38.9 250.72,38.09 248.86,38.09 v1(248.26,37.48)
  IN3 w0.089: 190.66,99.11 186.04,99.11 183.71,101.45 179.36,101.45 178.96,101.84 v1(178.61,101.84)
  IN3 w0.102: 190.66,99.11 192.11,99.11 192.78,98.44 198.29,98.44 200.23,100.37 v1(200.23,100.5)
  BOTTOM w0.076: v1(178.61,101.84) 178.29,102.16 UC1.CG14
  BOTTOM w0.107: v1(200.23,100.5) v2(199.57,100.5)
PCH_JTAG_TCK: length 87.3
  TOP w0.107: v1(131.07,116.59) 130.88,116.41 RC86.1 130.06,115.53 129.8,115.27 123.15,115.27 v3(122.65,114.77) 122.19,114.31 119.77,114.31 116.01,118.08 100.15,118.08 98.08,116.01 94.8,116.01 91.63,119.18 91.63,131.34 91.94,131.65 91.94,132.66 92.66,133.38 v1(92.66,134.84)
  IN1 w0.089: 144.8,111.58 148.61,107.77 148.61,107.55 v1(148.98,107.19)
  IN1 w0.099: 144.8,111.58 144.67,111.72 144.67,113.02 142.87,114.81 140.23,114.81 138.88,116.15 138.88,116.45 138.29,117.04 138.02,117.04 137.48,116.5 136.14,116.5 135.58,117.07 134.38,117.07 132.43,115.11 131.97,115.11 131.73,115.35 131.07,116.02 v1(131.07,116.59)
  BOTTOM w0.089: UC1.W6 v1(148.98,107.19)
  BOTTOM w0.107: JXDP1.55 92.37,134.57 92.63,134.84 v1(92.66,134.84)
PCH_JTAG_TDI: length 22.4
  TOP w0.107: CC304.1 RC569.1 134.75,117.47 134.68,117.55 RC736.2 ; CC304.1 134.75,115.05 v3(134.65,114.95) ; CC304.1 135.19,116.15 135.41,116.38 v1(135.41,116.66)
  IN1 w0.089: v1(148.05,107.82) 148.05,107.88 144.35,111.58
  IN1 w0.099: v1(135.41,116.66) 135.79,116.28 137.57,116.28 138.05,116.76 138.25,116.76 138.66,116.35 138.66,116.06 140.13,114.58 142.78,114.58 144.33,113.03 144.33,111.6 144.35,111.58
  BOTTOM w0.089: UC1.U5 v1(148.05,107.82)
PCH_JTAG_TDO: length 26.9
  TOP w0.107: RC737.2 131.68,117.9 RC568.1 CC303.1 131.68,115.98 v1(132.14,115.52) 132.14,115.09 v3(132.43,114.79)
  IN1 w0.089: 146.42,111.58 148.97,109.03 148.97,108.9 148.97,107.82 v1(148.97,107.82)
  IN1 w0.099: 146.42,111.58 142.97,115.04 140.32,115.04 139.11,116.25 139.11,116.54 138.38,117.27 137.93,117.27 137.39,116.73 136.23,116.73 135.67,117.29 134.29,117.29 132.52,115.52 v1(132.14,115.52)
  BOTTOM w0.089: UC1.W5 v1(148.97,107.82)
PCH_JTAG_TMS: length 23.8
  TOP w0.102: v3(145.77,108.25) 146.09,107.93 v1(146.31,107.93)
  TOP w0.107: RC735.2 RC130.1 130.31,117.17 v1(130.71,117.57)
  IN1 w0.089: v1(146.31,107.93) 146.31,108.2 146.05,108.47 145.62,108.47 145.39,108.69 144.35,108.69 141.46,111.58
  IN1 w0.099: v1(130.71,117.57) 130.66,117.52 130.66,116.1 131.88,114.89 133.98,114.89 134.23,115.14 136.06,115.14 136.57,114.63 138.41,114.63 141.46,111.58
  BOTTOM w0.089: v1(146.31,107.93) 145.77,107.69 UC1.P5
PCH_PCIE_WAKE#: length 138.3
  TOP w0.089: RE274.2 255.96,89.48 255.22,90.23 v1(255.22,90.54)
  TOP w0.102: v1(172.81,91.68) 173.05,91.68 173.25,91.49 173.27,91.32 173.27,90.79 173.48,90.58 173.48,89.26 172.68,88.46 172.68,86.97 172.9,86.75 173.22,86.75 173.54,87.07 173.54,87.32 173.73,87.51 177.41,87.51 177.63,87.3 177.63,86.12 178.33,85.42
  TOP w0.107: 178.33,85.42 178.52,85.23 178.52,84.16 178.88,83.79 178.88,83.11 179.24,82.75 180.35,82.75 v2(180.55,82.55) 181.16,81.94 181.16,80.04 181.93,79.27 181.93,77.64 182.28,77.3 RC67.1 ; v1(255.22,90.54) 254.85,90.91 UE1.L1
  IN3 w0.089: 176.62,88.61 175.76,89.46 175.76,89.67 175.06,90.37 175.06,90.69 174.87,90.88 174.3,90.88 174.05,90.62 173.67,90.62 173.41,90.88 173.41,91.37 173.1,91.68 v1(172.81,91.68)
  IN3 w0.102: 176.62,88.61 177.3,88.61 179.41,86.5 179.41,85.46 178.41,84.46 178.41,83.76 178.57,83.6 178.57,83.23 179.12,82.68 182.5,82.68 183.45,81.73 183.45,81.35 184.28,80.52 187.27,80.52 188.18,79.6 206.08,79.6 206.48,80.01 210.89,80.01 211.34,79.56 214.27,79.56 214.79,79.03 214.79,77.99 214.75,77.99 213.61,76.85 213.61,76.38 215.07,74.93 v1(216.81,74.93)
  BOTTOM w0.076: UC1.BU30 v1(172.81,91.68)
  BOTTOM w0.089: 254.92,86.98 255.29,87.35 255.29,90.46 v1(255.22,90.54)
  BOTTOM w0.107: v1(216.81,74.93) 216.81,74.22 217.5,73.53 222.71,73.53 225.36,76.18 225.86,76.18 225.89,76.22 226.53,76.22 228.16,77.85 231.42,77.85 232.38,78.81 235.73,78.81 236.45,79.53 238.16,79.53 239.2,78.49 245.74,78.49 246.56,79.32 248.87,79.32 249.23,79.68 249.23,82.08 251.62,84.47 252.52,84.47 252.61,84.55 253.48,84.55 253.59,84.66 253.59,85.65 254.92,86.98
PCH_PLTRST#: length 84.3
  TOP w0.107: UC7.1 219.86,77.87 219.71,78.03 219.71,78.43 219.8,78.52 UC7.2 220.75,78.52 220.91,78.69 220.91,78.86 221.36,79.31 RC237.1 221.42,78.58 RC739.1 221.36,77.29 RC60.1 v2(220.88,75.4) 220.88,74.87 218.93,72.92 v1(218.88,72.92)
  BOTTOM w0.076: UC1.BJ35 167.65,88.76 167.65,88.54 167.69,88.43 167.69,88.24 167.65,88.13 167.65,87.89 167.95,87.05 167.95,86.24 168.43,85.76 168.43,85.55 168.61,85.37 168.61,77.82
  BOTTOM w0.107: v1(218.88,72.92) 218.88,72.87 218.12,72.11 209.51,72.11 207.77,70.37 193.52,70.37 193.35,70.21 183.32,70.21 182.88,70.65 180.57,70.65 179.1,72.12 175.07,72.12 173.97,73.23 169.13,73.23 168.21,72.31 167.09,72.31 166.05,73.35 165.92,73.35 165.64,73.63 165.64,74.85 168.61,77.82
PCH_PLTRST#_AND: length 417.5
  TOP w0.107: v1(288.16,25.28) 288.16,25.22 288.02,25.08 288.02,24.93 288.17,24.78 UR1.1 ; UZ52.A1 280.7,84.94 280.7,86.68 v1(280.93,86.9) ; v1(209.16,119.31) 210.37,118.1 210.37,100.24 209.59,99.47 209.59,98.13 205,93.54 204.7,93.54 203.67,92.51 203.67,91.04 202.88,90.24 v2(202.88,88.81) 202.88,83.01 203.14,82.75 203.55,82.75 204.27,82.03 204.61,82.03 206.68,79.96 v1(206.68,79.36) ; RZ1481.2 v1(272.85,86.05) 271.46,87.45 267.52,87.45 266.06,88.91 v1(263.71,88.91) ; v1(217.2,81.08) 217.22,81.1 CC196.1 218.49,80.7 218.44,80.66 RC65.1 217.95,80.17 217.74,79.96 217.74,79.32 217.89,79.17 UC7.4 219.22,78.41 219.22,77.65 218.82,77.26 218.41,77.26 218.25,77.1 RC738.1
  IN1 w0.099: v1(217.2,81.08) 216.7,81.08 215.58,79.96 212.34,79.96 211.94,79.56 211.6,79.56 211.2,79.96 207.28,79.96 v1(206.68,79.36) ; v1(286.76,26.17) 286.76,26.62 293.17,33.03 293.17,39.82 292.1,40.9 290.7,40.9 287.18,44.42 v1(284.89,44.42) ; v1(288.16,25.28) 288.09,25.22 287.85,25.22 284.81,22.17 283.65,22.17 282.83,22.99 271.18,22.99 v1(270.74,22.55) 270.74,22.35 270.38,21.98 268.86,21.98 267.9,22.94 267.9,25.33 263.69,29.54 263.69,31.71 264.22,32.24 264.22,35.14 265.84,36.77 268.04,36.77 268.95,37.68 272.8,37.68 272.92,37.8 272.92,48.07 272.34,48.66 272.34,52.54 271.9,52.97 271.9,53.99 272.16,54.24 272.16,54.54 274.54,56.92 274.54,62.76 277.41,65.63 277.41,68.26 280.26,71.12 282.75,71.12 284.68,73.04 284.68,74.95 v1(284.17,75.45)
  IN2 w0.102: v1(288.16,25.28) 287.52,25.28 286.76,26.05 v1(286.76,26.17)
  IN3 w0.102: v1(110.61,132.66) 112.85,134.9 120.73,134.9 124.24,131.39 134.35,131.39 134.58,131.62 142.37,131.62 143.65,132.9 155.11,132.9 v1(159.23,128.79)
  BOTTOM w0.107: v1(270.74,22.55) 270.58,22.38 JNGFF3.50 ; v1(110.61,132.66) 110.61,132.8 110.22,133.19 JIRTS1.1 ; v1(272.85,86.05) 273.34,86.54 280.56,86.54 v1(280.93,86.9) 284.37,86.9 285.07,86.21 285.07,76.35 v1(284.17,75.45) ; v1(263.71,88.91) 263.71,90.18 264.21,90.68 264.21,92.42 263.75,92.89 263.75,98.75 262.57,99.93 262.57,105.11 261.06,106.63 261.06,109.1 257.29,112.87 249.07,112.87 248.11,113.84 239.86,113.84 238.82,114.88 227.91,114.88 225.42,117.37 211.1,117.37 v1(209.16,119.31) 207.83,120.64 199.93,120.64 199.45,121.12 192.55,121.12 192.42,121.26 192.37,121.26 191.87,121.76 190.9,121.76 190.28,122.38 188.16,122.38 186.97,123.58 180.14,123.58 177.4,126.32 168.63,126.32 167.62,127.34 164.35,127.34 162.71,128.98 161.28,128.98 160.71,128.4 159.62,128.4 v1(159.23,128.79) ; v1(284.89,44.42) 285.34,44.42 285.45,44.31 JNGFF1.52
PCH_POPIRCOMP: length 2.4
  TOP w0.089: v2(173.33,93.3) 173.33,93.67
  TOP w0.102: v1(173.72,94.36) 173.72,94.34 173.33,93.94 173.33,93.67
  TOP w0.457: v1(173.72,94.36) 173.81,94.45 RC107.1
  BOTTOM w0.203: UC1.BW25 173.56,94.58 173.72,94.42 v1(173.72,94.36)
PCH_PRIM_EN: length 198.3
  TOP w0.107: v1(228.72,88.06) 227.52,89.26 227.52,93.36 226.75,94.12 219.84,94.12 212.95,87.22 212.95,84.44 v2(211.96,83.45) 210.97,82.46 210.97,76.18 209.56,74.76 208.69,74.76 207.45,76 207.45,77.48 206.88,78.05 201.35,78.05 v1(201.04,77.73) 199.37,76.07 RC441.2 RC442.2
  TOP w0.254: PR312.1 236.42,132.03 236.8,132.41 v1(236.98,132.41) ; PR406.1 211.44,135.2 213.8,135.2 v1(214.18,135.58) ; PR504.1 200.41,113.37 v1(199.32,112.28) 199.07,112.02 199.07,108.72 200.34,107.45 204.34,107.45 205.23,106.56 205.23,96.96 201.2,92.93 201.2,89.31 197.75,85.86 v1(197.42,85.86) ; v1(234.11,108.23) 233.86,108.47 233.86,115.17 234.39,115.69 v1(234.39,118.49)
  IN1 w0.254: v1(236.98,132.41) 237.13,132.56 237.13,134.36 235.53,135.96 233.23,135.96 232.97,135.7 214.3,135.7 v1(214.18,135.58) ; v1(234.11,108.23) 234.03,108.3 210.47,108.3 205.54,113.23 200.27,113.23 v1(199.32,112.28)
  IN2 w0.102: v1(197.42,85.86) 197.42,82.09 197.32,81.99 196.53,81.99 195.7,81.16 195.7,80.66 196.02,80.34 196.97,80.34 198.37,78.94 199.83,78.94 v1(201.04,77.73)
  IN3 w0.254: v1(236.98,132.41) 237.04,132.41 237.59,131.86 237.59,129.98 238.21,129.36 238.21,122.93 234.39,119.11 v1(234.39,118.49)
  BOTTOM w0.107: RZ64.1 226.56,87.01 227.66,88.11 228.67,88.11 v1(228.72,88.06)
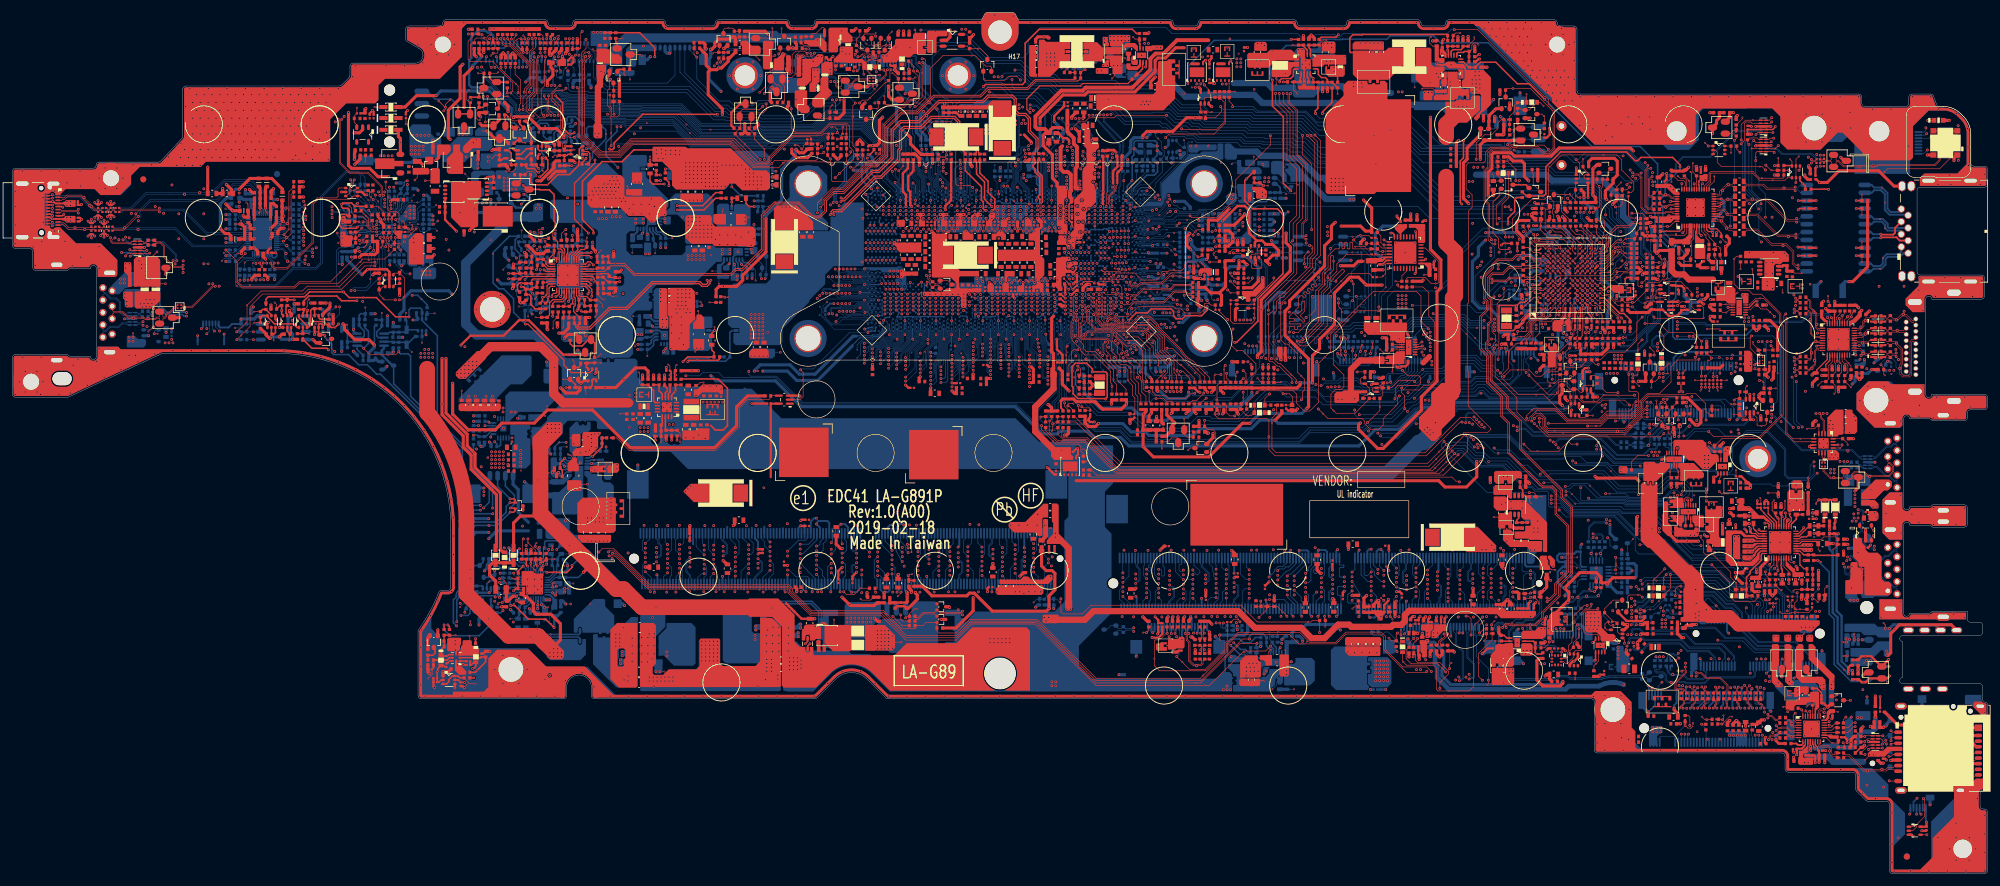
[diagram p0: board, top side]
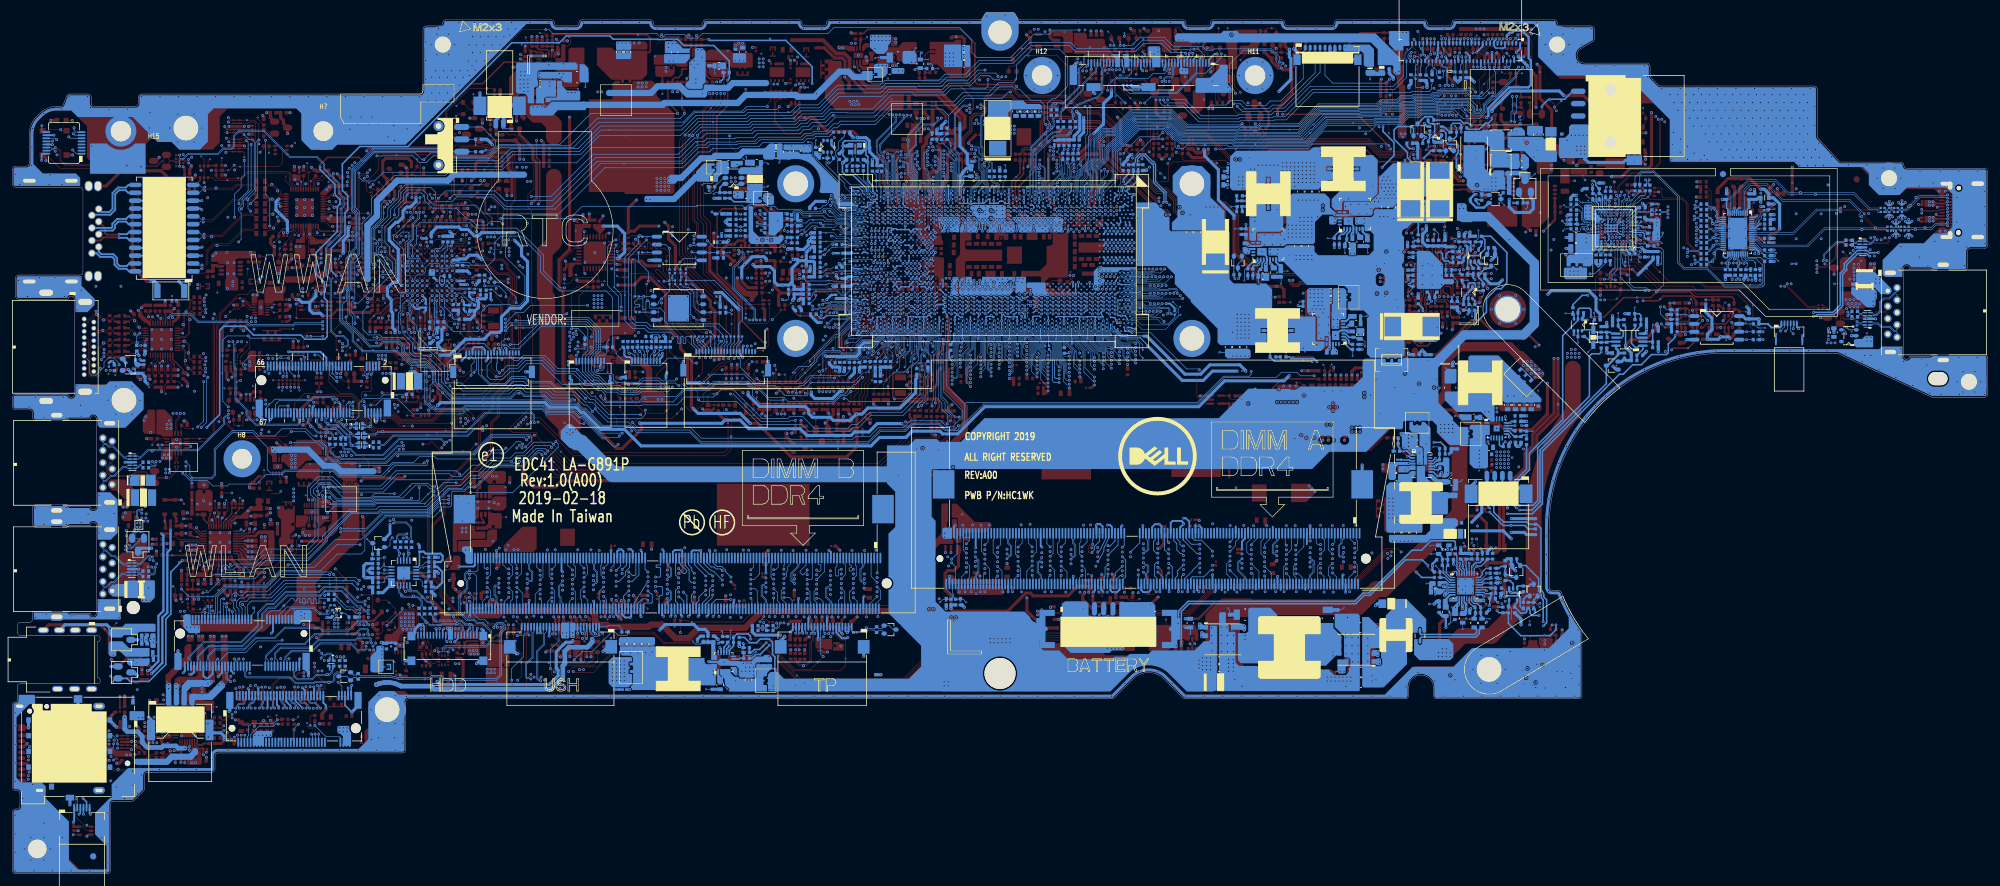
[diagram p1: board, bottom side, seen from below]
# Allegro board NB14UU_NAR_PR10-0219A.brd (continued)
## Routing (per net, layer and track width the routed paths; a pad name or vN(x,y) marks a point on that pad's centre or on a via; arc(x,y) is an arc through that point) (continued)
PCH_PWROK: length 130.2
  TOP w0.089: 171.19,89.42 171.24,89.48 171.34,89.63 171.34,90.65 v1(170.98,91.01)
  TOP w0.102: 171.17,86.45 171.17,86.46 171,86.62 171,89.15 171.19,89.42
  TOP w0.107: RC536.1 v3(177.6,78.74) 177.6,79.13 177.37,79.37 177.37,81.22 174.76,83.83 173.22,83.83 172.52,84.54 172.52,84.83 171.17,86.18 171.17,86.45
  IN1 w0.099: v1(98.63,93.74) 99.75,93.74 100.78,94.78 109.57,94.78 v1(110.55,93.8)
  IN3 w0.089: 127.97,97.63 129.89,99.56 135.21,99.56 137.41,97.36 137.98,97.36 138.87,98.24 143.7,98.24 144.33,98.88 146.11,98.88 146.62,98.37 167.66,98.37 169.84,96.19 169.84,94.58 169.98,94.43 170.11,94.43 170.49,94.05 170.49,91.58 170.78,91.29 170.78,91.22 v1(170.98,91.01)
  IN3 w0.102: v1(110.55,93.8) 110.7,93.65 123.99,93.65 127.97,97.63 ; v1(84.76,100.89) 84.63,100.77 84.63,99.7 84.01,99.07 84.01,96.85 85.15,95.7 85.15,92.02 84.59,91.46 84.59,90.1 85.02,89.67 91.88,89.67 93.28,91.07 95.96,91.07 v1(98.63,93.74)
  BOTTOM w0.076: UC1.BP31 170.67,91.33 v1(170.98,91.01)
  BOTTOM w0.107: PR614.1 84.76,100.34 v1(84.76,100.89)
PCH_RSMRST#: length 61.2
  TOP w0.089: RE342.1 260.32,92.47
  TOP w0.102: UE1.M5 256.05,94.21 256.57,94.21 257.18,93.6 257.92,93.6 257.92,93.59
  TOP w0.107: 257.92,93.59 258.98,92.53 259.75,92.53 RE342.1 ; RZ400.1 262.02,92.31 v1(261.67,92.31) 260.47,92.31 260.32,92.47 ; RZ1413.1 240.88,112.7 241.15,112.42 241.15,109.39 239.68,107.92 239.68,105.15 v1(239.83,105)
  BOTTOM w0.107: v1(239.83,105) 240.22,105.38 241.84,105.38 242.4,104.83 244.08,104.83 245.01,105.76 245.57,105.76 v2(247.37,107.56) 251.2,107.56 252.49,108.85 252.49,109.52 252.98,110.01 255.06,110.01 255.37,109.7 255.37,108.69 256.64,107.42 256.64,106.4 257.05,105.98 257.38,105.98 258.87,104.49 258.87,102.08 258.12,101.33 258.12,100.11 257.13,99.12 257.13,96.77 257.53,96.37 258.33,96.37 260.69,94.01 260.69,93.29 v1(261.67,92.31)
PCH_RSMRST#_AND: length 346.1
  TOP w0.107: v1(208.21,76.59) 208.36,76.74 208.36,77.82 208.68,78.15 208.68,79.93 v2(208.19,80.42) 207.58,81.04 207.58,84.01 206,85.58 205.56,85.58 204.87,86.27 204.87,91.79 205.14,92.06 205.14,92.41 210.49,97.76 210.49,99.1 211.27,99.87 211.27,118.5 v1(210.4,119.37) ; RC215.2 194.9,75.92 195.08,75.74 195.08,74.71 194.86,74.49 v1(194.86,74.29) ; UZ41.4 267.7,93.78 266.98,93.07 v1(265.52,93.07) ; RC124.1 v1(85.28,132.66)
  IN1 w0.089: v1(171.77,83.67) 172.15,83.67 173.76,82.07 175.46,82.07 176.84,80.69 176.84,80.68
  IN1 w0.099: v1(208.21,76.59) 208.82,77.2 218.91,77.2 221.57,74.53 225.24,74.53 225.34,74.63 v1(225.34,74.71) ; 176.84,80.68 176.84,79.58 180.43,75.99 181.13,75.99 182.42,74.7 185.81,74.7 187.13,73.38 189.39,73.38 190.5,72.27 193.04,72.27 194.86,74.1 v1(194.86,74.29) ; v1(248.36,78.83) 249.89,78.83 250.82,79.77 250.82,81.22 255.86,86.25 261.67,86.25 262.84,87.42 262.84,90.26 263.24,90.66 263.24,92.99 263.77,93.52 264.52,93.52 264.97,93.07 v1(265.52,93.07)
  IN3 w0.102: v1(161.94,129.87) 161.54,129.47 160.84,129.47 160.79,129.42 160.28,128.91 160.28,128.58 159.6,127.9 156.3,127.9 154.4,126 151.43,126 148.26,129.17 134.68,129.17 134.59,129.08 133.39,129.08 132.79,128.48 124.74,128.48 120.02,133.2 116,133.2 115.26,132.46 114.41,132.46 112.22,130.26 110.44,130.26 109.9,129.72 105.57,129.72 105.15,130.13 103.14,130.13 101.74,131.53 100.34,131.53 97.55,134.33 91.88,134.33 91.5,133.94 90.92,133.94 90.48,133.5 86.82,133.5 86.55,133.22 85.95,133.22 85.39,132.66 v1(85.28,132.66)
  BOTTOM w0.076: 172.88,76.36 171.89,77.35 171.89,80.28 171.63,80.53 171.63,82.31 RC75.1 171.16,83.06 v1(171.77,83.67) 171.77,83.79 171.41,84.15 171.41,85.6 171.35,85.67 171.35,85.82 171.16,86.01 171.16,87.2 171.5,87.54 171.5,87.82 171.24,88.28 UC1.BR36
  BOTTOM w0.107: v1(248.36,78.83) 247.96,78.43 246.76,78.43 246.33,78.01 238.99,78.01 237.96,79.04 236.65,79.04 235.93,78.32 232.58,78.32 231.63,77.36 228.36,77.36 226.73,75.73 226.28,75.73 225.34,74.79 v1(225.34,74.71) ; v1(208.21,76.59) 207.96,76.34 202.09,76.34 198.36,72.6 191.52,72.6 190.43,71.51 183.86,71.51 183.29,72.08 182.37,72.08 180.37,74.08 175.16,74.08 172.88,76.36 ; v1(210.4,119.37) 208.23,121.54 200.3,121.54 199.82,122.02 192.93,122.02 191.67,123.28 188.54,123.28 185.65,126.16 178.83,126.16 177.77,127.22 169,127.22 167.99,128.24 164.72,128.24 163.08,129.87 v1(161.94,129.87)
PCH_RTCRST#: length 158.7
  TOP w0.107: RE94.2 252.53,107.02 v1(252.67,106.88) ; RC57.1 205.71,75.72 CC25.1 206.62,75.74 CMOS1.1 206.75,75.87 206.75,77.1 206.29,77.56 v2(205.77,77.56) v1(205.26,77.56)
  IN1 w0.089: 260.83,88.76 259.08,87.01 252.84,87.01 252.21,87.64 251.55,87.64 251.46,87.55 251.46,86.98
  IN1 w0.099: v1(248.74,79.91) 249.26,79.91 249.98,80.64 249.98,83.09 251.11,84.23 251.11,85.41 251.46,85.76 251.46,86.98 ; 260.83,88.76 261.54,89.47 261.54,90.43 262.25,91.15 262.25,93.77 262.69,94.21 262.69,95.58 262.41,95.86 262.41,99.02 261.02,100.41 261.02,101.76 259.94,102.85 259.46,102.85 255.84,106.48 253.08,106.48 v1(252.67,106.88)
  BOTTOM w0.076: UC1.BR34 171.32,89.48 171.55,89.01 171.55,88.06 171.66,87.86 171.66,87.47 171.33,87.13 171.33,86.07 171.51,85.89 171.51,85.74 171.57,85.67 171.57,84.4 172.16,83.82 172.16,82.55 172.45,82.26 172.45,79
  BOTTOM w0.107: v1(248.74,79.91) 248.74,82.52 245.59,85.67 244.73,85.67 244.71,85.69 242.96,85.69 242.94,85.67 242.82,85.67 241.74,84.59 JAPS1.9 241.74,82.75 242.37,82.12 242.37,80.41 241.82,79.85 239.88,79.85 238.54,81.19 237.19,81.19 235.93,82.46 233.63,82.46 230.24,79.06 227.41,79.06 225.51,77.16 224.96,77.16 223.44,75.64 217.5,75.64 217.38,75.76 211.71,75.76 210.43,77.04 205.78,77.04 v1(205.26,77.56) 204.58,78.24 202.62,78.24 197.95,73.57 193.76,73.57 193.47,73.86 191.39,73.86 189.52,72 184.06,72 183.49,72.57 182.57,72.57 180.57,74.57 175.36,74.57 172.45,77.48 172.45,79
PCH_RTCX1: length 14.5
  TOP w0.107: v1(172.07,81.43) 171.69,81.06 171.69,79.01 RC403.1
  IN1 w0.102: v1(170.09,91.1) 169.72,90.73 169.72,87.07 170.75,85.48 170.75,83.94 171.78,81.6 171.96,81.43 v1(172.07,81.43)
  BOTTOM w0.089: UC1.BN31 v1(170.09,91.1)
PCH_RTCX1_R: length 3.4
  TOP w0.107: RC403.2 RC66.2 CC23.1 175.39,77.49 YC2.1
PCH_RTCX2: length 13.9
  TOP w0.107: v1(172.09,82.03) 172.5,81.62 172.5,80.62 RC404.1
  IN1 w0.102: v1(172.09,82.03) 171.96,82.07 171.06,83.82 171.06,85.56 170.09,87.07 170.09,87.71 170.19,87.81 170.77,87.81 170.87,87.91 170.87,88.12 170.77,88.22 170.19,88.22 170.09,88.32 170.09,88.63 170.19,88.73 170.71,88.73 170.81,88.83 170.81,89.04 170.71,89.14 170.19,89.14 170.09,89.24 v1(170.09,90.46)
  BOTTOM w0.089: UC1.BN32 v1(170.09,90.46)
PCH_RTCX2_R: length 1.9
  TOP w0.107: RC404.2 RC532.1 RC66.1
PCH_SMB_ALERT#: length 11
  IN3 w0.089: 186.42,98.5 183.69,101.23 180.14,101.23 179.7,100.78 v1(179.7,100.74)
  IN3 w0.102: v1(187.64,98.5) 186.42,98.5
  BOTTOM w0.089: v1(179.7,100.74) 179.74,100.81 UC1.CJ15
  BOTTOM w0.107: v1(187.64,98.5) 188.14,97.99 RC266.1
PCH_SPI_CLK: length 47.4
  IN3 w0.089: 185.28,85.84 185.22,85.84 184.56,85.18 v1(181.26,85.18)
  IN3 w0.102: v1(204.53,86.05) 204.53,86.39 204.43,86.49 203.63,86.49 203.53,86.39 203.53,85.47 203.43,85.37 203.23,85.37 203.12,85.47 203.12,86.39 203.02,86.49 202.82,86.49 202.72,86.39 202.72,85.47 202.62,85.37 202.41,85.37 202.31,85.47 202.31,86.39 202.21,86.49 202.01,86.49 201.9,86.39 201.9,85.47 201.8,85.37 201.6,85.37 201.5,85.47 201.5,86.39 201.4,86.49 197.93,86.49 194.7,89.73 191,89.73 188.84,87.57 188.84,86.31 188.37,85.84 185.28,85.84
  BOTTOM w0.076: RC96.1 186.16,82.97 185.92,83.22 182.6,83.22 181.87,83.95 181.87,84.8 181.66,85.01 181.43,85.01 v1(181.26,85.18) 180.99,85.18 180.84,85.33 180.27,85.33 179.87,85.72 179.87,85.85 178.79,86.93 UC1.CH37
  BOTTOM w0.107: RC27.1 205,86.16 204.89,86.05 v1(204.53,86.05) 205.08,85.5 JSPI1.8
PCH_SPI_CLK_0_R: length 9.7
  BOTTOM w0.107: RC571.2 210.64,94.8 209.84,94.8 208.97,93.93 208.97,91.64 208.08,90.75 UC5.6 v1(206.26,90.75) 204.83,90.75 RC299.1
PCH_SPI_CLK_1_R: length 9.4
  TOP w0.107: v1(209.31,100.48) 208.7,99.87 v2(208.7,99.58) v1(208.7,98.57)
  BOTTOM w0.107: v1(208.7,98.57) 210.61,98.57 211.13,98.05 RC575.2 ; RC289.1 UC6.6 209.23,100.4 v1(209.31,100.48)
PCH_SPI_CLK_2_R: length 3.4
  TOP w0.107: RZ60.2 220.37,102.75 220.48,102.65 RZ63.2 221.23,101.11 UZ12.19
PCH_SPI_CLK_R1: length 66
  TOP w0.107: v1(216.63,102.41) 217.38,103.16 v3(217.72,103.16) 219.08,103.16 219.48,102.75 RZ60.1 ; v1(210.99,96.42) 210.99,96.29 210.4,95.69 210.4,95.54 210.71,95.23 210.71,95.08 210.55,94.93 210.4,94.93 210.09,95.24 209.94,95.24 209.79,95.09 209.79,94.94 210.1,94.63 210.1,94.48 209.95,94.32 209.8,94.32 209.49,94.63 209.34,94.63 209.19,94.48 209.19,94.33 209.5,94.02 209.5,93.87 209.35,93.72 209.2,93.72 208.89,94.03 208.74,94.03 208.59,93.88 208.59,93.73 208.89,93.42 208.89,93.27 208.74,93.12 208.59,93.12 208.28,93.43 208.13,93.43 207.71,93.01 207.71,91.54 207.25,91.08 207.25,90.93 207.62,90.56 207.77,90.56 208.26,91.06 208.26,92.42 208.37,92.52 208.68,92.52 208.75,92.45 208.75,90.94 208.07,90.26 208.07,90.11 208.75,89.43 208.75,89.28 208.6,89.13 208.45,89.13 206.95,90.63 206.8,90.63 206.25,90.08 206.25,89.81 206.36,89.7 206.99,89.7 207.09,89.59 207.09,89.38 206.99,89.27 206.36,89.27 206.25,89.17 206.25,88.95 206.36,88.85 207.97,88.85 208.07,88.74 208.07,88.53 207.97,88.42 207.67,88.42 207.56,88.31 207.56,88.04 207.45,87.94 207.24,87.94 207.13,88.04 207.13,88.31 207.03,88.42 206.36,88.42 206.25,88.31 206.25,87.59 v1(206.3,87.54)
  BOTTOM w0.107: JSPI1.7 205.58,85.26 205.58,85.27 RC27.2 205.58,86.82 v1(206.3,87.54) 206.71,87.95 211.84,87.95 211.89,88.01 216.18,88.01 216.76,88.59 218.42,88.59 219.52,89.69 219.52,99.52 v1(216.63,102.41) ; RC571.1 211.13,96.28 v1(210.99,96.42) 211.13,96.56 RC575.1
PCH_SPI_CS#0: length 34.8
  IN3 w0.089: v1(180.94,84.21) 180.94,84.17 181.04,84.06 182.35,84.06 182.43,84.14 184.34,84.14 184.62,83.87 185.28,83.87
  IN3 w0.102: v1(204.24,83.23) 203.29,84.17 196.02,84.17 194.29,82.45 190.52,82.45 188.42,84.54 187.2,84.54 186.53,83.87 185.28,83.87
  BOTTOM w0.076: UC1.CG36 178.22,87.94 178.22,87.35 178.31,87.25 178.31,86.73 179.39,85.65 179.39,85.52 180.17,84.74 180.7,84.21 v1(180.94,84.21)
  BOTTOM w0.107: v1(204.24,83.23) 204.08,83.39 JSPI1.10 204.08,85.3 203.64,85.74 v2(203.64,85.95) 203.64,86.73 RC28.1
PCH_SPI_CS#0_R1: length 34.8
  BOTTOM w0.107: RC32.1 v3(218.47,95.21) 218.47,99.27 218.52,99.32 218.77,99.32 219.03,99.07 219.03,89.89 218.22,89.08 216.56,89.08 215.98,88.5 205.7,88.5 204.31,87.11 RC28.2 204.31,86.6 204.02,86.31 204.02,85.87 204.58,85.31 JSPI1.9
PCH_SPI_CS#0_R2: length 2.4
  BOTTOM w0.107: RC32.2 v1(217.08,93.29) UC5.1
PCH_SPI_CS#1: length 39.2
  IN3 w0.089: 185.28,84.22 184.89,84.22 184.62,84.5 181.89,84.5 181.69,84.29 181.37,84.29 180.87,84.79 v1(180.64,84.79)
  IN3 w0.102: 185.28,84.22 186.38,84.22 187.06,84.9 188.57,84.9 190.66,82.8 194.15,82.8 195.87,84.53 204.02,84.53 204.66,83.89 207.57,83.89 v1(208.08,83.39)
  BOTTOM w0.076: v1(180.64,84.79) 180.35,84.79 179.55,85.58 179.55,85.72 178.47,86.8 178.47,87.32 178.38,87.41 178.38,87.84 178.41,87.92 178.41,88.1 178.37,88.21 178.37,88.44 UC1.CG35
  BOTTOM w0.107: RC24.1 209.03,86.6 209.03,85.72 208.08,84.78 JSPI1.2 v1(208.08,83.39)
PCH_SPI_CS#1_R1: length 33.1
  BOTTOM w0.107: JSPI1.1 208.58,84.77 209.39,85.58 RC24.2 210.18,86.81 210.28,86.71 210.28,85.78 210.39,85.67 210.6,85.67 210.71,85.78 210.71,86.71 210.82,86.81 211.03,86.81 211.14,86.71 211.14,85.78 211.24,85.67 211.46,85.67 211.56,85.78 211.56,86.71 211.67,86.81 212.04,86.81 212.75,87.52 216.38,87.52 216.96,88.1 218.86,88.1 220.11,89.36 v2(220.11,93.5) 220.11,99.62 217.9,101.83 RC302.1
PCH_SPI_CS#1_R2: length 2.4
  BOTTOM w0.107: UC6.1 v2(216.48,102.94) RC302.2
PCH_SPI_CS#2: length 64.8
  TOP w0.107: RZ61.1 216.58,100.98 216.47,101.08 216.47,101.95 216.36,102.05 216.15,102.05 216.04,101.95 216.04,101.08 215.94,100.98 215.72,100.98 215.62,101.08 215.62,101.95 215.51,102.05 215.3,102.05 215.19,101.95 v2(215.19,101.52) 215.19,101.08 215.08,100.98 214.87,100.98 214.76,101.08 214.76,101.95 214.66,102.05 214.44,102.05 214.34,101.95 214.34,101.08 214.23,100.98 213.65,100.98 212.52,99.84 212.52,98.02 212.25,97.75 211.57,97.07 211.57,95.26 210.5,94.18 210.5,91.12 209.52,90.14 209.52,89.28 207.69,87.45 207.04,87.45 206.99,87.5 v1(206.94,87.45)
  IN3 w0.089: v1(181.52,84.66) 181.88,85.02 185.08,85.02 185.28,85.22
  IN3 w0.102: 185.28,85.22 185.42,85.35 188.61,85.35 190.78,83.18 194.02,83.18 195.73,84.88 206.28,84.88 206.94,85.54 v1(206.94,87.45)
  BOTTOM w0.076: UC1.CH34 178.53,89.37 178.53,88.24 178.57,88.13 178.57,87.89 178.54,87.81 178.54,87.48 178.63,87.39 178.63,86.86 179.71,85.78 179.71,85.65 180.2,85.16 180.77,85.16 181,84.94 181,84.82 181.16,84.66 v1(181.52,84.66)
PCH_SPI_CS#2_R: length 2.1
  TOP w0.107: RZ61.2 220.89,100.56 v1(221.34,100.56) 221.39,100.61 UZ12.20
PCH_SPI_D0: length 49.1
  IN3 w0.089: 185.28,82.45 183.88,82.45 183.1,83.22 179.93,83.22 179.74,83.4 v1(179.42,83.4)
  IN3 w0.102: 185.28,82.45 188.5,82.45 189.93,81.02 194.98,81.02 195.33,81.38 196.74,81.38 197.07,81.7 198.98,81.7 199.39,81.29 203.7,81.29 203.83,81.42 203.83,82.12 203.96,82.24 204.71,82.24 204.81,82.14 204.81,81.3 204.91,81.2 205.11,81.2 205.21,81.3 205.21,82.14 205.32,82.24 205.52,82.24 205.62,82.14 205.62,81.3 205.72,81.2 205.93,81.2 206.03,81.3 206.03,82.28 206.13,82.38 206.37,82.38 206.5,82.26 206.5,81.48 206.58,81.4 206.9,81.4 207.01,81.51 207.01,83.31 v1(207.08,83.39)
  BOTTOM w0.076: UC1.CF36 177.49,88.28 177.23,87.8 177.23,87.55 177.57,87.2 177.57,86.77 177.4,86.6 177.4,85.95 178.3,85.04 178.3,84.24 179.14,83.4 v1(179.42,83.4) 179.42,83.04 RC518.1 RC505.2 RC94.2
  BOTTOM w0.107: RC25.1 207.54,86.78 207.99,86.32 v2(207.99,85.89) 207.08,84.98 JSPI1.4 v1(207.08,83.39)
PCH_SPI_D0_0_R: length 8.9
  BOTTOM w0.107: UC5.5 208.57,89.48 v1(208.97,89.89) 209.48,90.4 209.48,93.67 210.12,94.31 211.04,94.31 RC570.2
PCH_SPI_D0_1_R: length 5.4
  BOTTOM w0.107: RC574.2 212.02,98.03 v1(211.21,98.84) 210.6,99.45 208.77,99.45 208.45,99.13 UC6.5
PCH_SPI_D0_2_R: length 2.3
  TOP w0.107: RZ59.2 220.21,100.02 v2(221.23,100.02) 221.32,100.11 UZ12.21
PCH_SPI_D0_R1: length 45.4
  TOP w0.107: RZ59.1 215.49,100.09 213.94,98.53 213.94,97.34 212.97,96.38 212.97,96.23 212.39,95.64 212.39,94.93 211.41,93.95 211.41,89.05 208.66,86.3 v1(208.43,86.3) 208.43,86.65 210.94,89.16 210.94,94.12 211.93,95.11 211.93,96.92 212.61,97.6 212.61,97.6 212.88,97.87 212.88,99.69 213.12,99.93 213.27,99.93 213.42,99.78 v3(213.42,98.98) 213.42,97.61 212.48,96.67 v1(212.48,96.31)
  BOTTOM w0.107: JSPI1.3 207.58,84.94 208.43,85.79 v1(208.43,86.3) 208.43,86.51 RC25.2 ; RC574.1 212.48,96.6 v1(212.48,96.31) 212.48,95.98 212.37,95.87 RC570.1
PCH_SPI_D1: length 37.5
  IN3 w0.089: v1(179.17,84.09) 179.3,84.09 180,83.39 183.32,83.39 183.9,82.8 185.28,82.8
  IN3 w0.102: 185.28,82.8 188.65,82.8 190.07,81.38 194.8,81.38 195.15,81.73 196.59,81.73 196.92,82.06 199.13,82.06 199.3,81.89 203.05,81.89 203.76,82.6 205.84,82.6 206.31,83.07 v1(206.31,83.39)
  BOTTOM w0.076: v1(179.17,84.09) 179.17,84.4 177.56,86.01 177.56,86.53 177.73,86.71 177.73,87.37 177.49,87.61 UC1.CF37
  BOTTOM w0.107: RC26.1 v2(206.27,85.88) 206.27,85.2 206.08,85.01 JSPI1.6 206.08,83.61 v1(206.31,83.39)
PCH_SPI_D1_0_R: length 4.7
  BOTTOM w0.107: UC5.2 214.82,92.02 214.69,92.15 214.69,92.39 v1(214.18,92.9) 212.91,94.17 RC734.2
PCH_SPI_D1_1_R: length 5.7
  BOTTOM w0.107: UC6.2 213.55,101.67 v1(212.91,101.04) RC573.2
PCH_SPI_D1_2_R: length 3.9
  TOP w0.107: RZ58.2 221.2,96.4 v2(221.39,96.59) 221.83,97.03 221.83,98.51 221.94,98.61 UZ12.24
PCH_SPI_D1_R1: length 44.3
  TOP w0.107: v1(213.79,95.74) 213.79,95.94 215.13,97.28 215.13,97.49 214.94,97.68 214.79,97.68 213.34,96.23 213.34,96.08 212.75,95.49 212.75,94.78 211.77,93.8 211.77,88.9 208.76,85.89 208.26,85.89 208.05,86.1 v1(207.52,86.1) 207.52,85.83 208.05,85.3 209.18,85.3 212.37,88.5 212.37,93.51 v2(214.65,95.79) 215.83,96.97 219.19,96.97 RZ58.1
  BOTTOM w0.107: v1(213.79,95.74) 213.04,95.74 RC734.1 RC573.1 ; JSPI1.5 206.58,85 207.52,85.95 v1(207.52,86.1) 207.52,86.15 RC26.2
PCH_SPI_D2: length 40.4
  IN3 w0.089: 185.28,83.16 183.93,83.16 183.48,83.61 180.42,83.61 v1(180.18,83.85)
  IN3 w0.102: v1(203.36,83.26) 202.95,82.85 200.83,82.85 200.48,83.21 196.06,83.21 194.59,81.73 190.22,81.73 188.8,83.16 185.28,83.16
  BOTTOM w0.076: UC1.CF34 177.76,89.37 177.76,88.89 177.72,88.78 177.72,88.54 177.76,88.43 177.76,88.24 177.72,88.13 177.72,87.89 177.87,87.46 177.88,87.45 177.9,87.4 177.9,86.64 177.73,86.47 177.73,86.08 178.77,85.04 178.8,85.04 179.99,83.85 v1(180.18,83.85) 180.25,83.85 180.75,83.34 181.59,83.34 181.84,83.09 181.84,82.98 182.19,82.64 RC61.2 RC519.1 RC11.2
  BOTTOM w0.107: v1(203.36,83.26) 203.39,83.26 203.08,83.56 JSPI1.12 203.08,85.24 202.46,85.86 RC29.1
PCH_SPI_D2_0_R: length 2.3
  BOTTOM w0.107: RC33.2 v2(216.8,90.75) UC5.3
PCH_SPI_D2_1_R: length 2.4
  BOTTOM w0.107: RC35.2 v2(216.45,100.4) UC6.3
PCH_SPI_D2_R1: length 36.9
  TOP w0.107: v1(216.47,92.59) 216.59,92.72 v3(216.59,95.29) 216.59,95.52 v1(216.32,95.8)
  BOTTOM w0.107: v1(216.32,95.8) 216.32,97.26 216.75,97.69 216.75,97.7 217.9,98.86 RC35.1 ; JSPI1.11 203.58,85.29 203.04,85.83 RC29.2 203.04,86.98 204.92,88.86 213.19,88.86 213.72,89.39 213.72,90.73 214.4,91.4 216.04,91.4 216.15,91.51 216.15,92.49 216.26,92.59 v1(216.47,92.59) 216.61,92.59 216.72,92.49 216.72,91.28 216.89,91.11 217.1,91.11 217.21,91.22 217.21,92.8 217.31,92.91 218.05,92.91 218.52,92.45 218.52,92.11 218.41,92.01 217.83,92.01 217.72,91.9 217.72,91.69 217.83,91.58 218.41,91.58 218.52,91.47 218.52,90.92 RC33.1
PCH_SPI_D3: length 41.1
  IN3 w0.089: v1(179.98,84.41) 180.13,84.41 180.7,83.84 184.01,83.84 184.34,83.51 185.28,83.51
  IN3 w0.102: v1(202.47,83.26) 201.91,83.82 196.17,83.82 194.44,82.09 190.37,82.09 188.27,84.19 187.49,84.19 186.81,83.51 185.28,83.51
  BOTTOM w0.076: UC1.CG34 177.92,89.09 177.92,88.86 177.88,88.75 177.88,88.57 177.92,88.45 177.92,88.21 177.88,88.1 177.88,87.92 178.06,87.43 178.06,87.28 178.15,87.19 178.15,86.66 179.23,85.58 179.23,85.45 179.98,84.7 v1(179.98,84.41) 180.24,84.41 181.11,83.53 181.86,83.53 182.33,83.05 184.24,83.05 RC62.2 RC515.1
  BOTTOM w0.107: v1(202.47,83.26) 202.5,83.26 202.08,83.68 JSPI1.14 202.08,85.22 v2(201.4,85.9) 201.19,86.11 RC30.1
PCH_SPI_D3_0_R: length 5.4
  BOTTOM w0.107: UC5.7 208.21,92.02 208.47,92.28 208.47,94.45 v2(209.16,95.15) 209.3,95.29 RC572.2
PCH_SPI_D3_1_R: length 7.9
  TOP w0.107: v1(208.88,98.02) 208.9,98.02 209.18,98.31 209.18,99.64 209.96,100.41 v2(209.96,101.03) 209.96,101.41 209.85,101.52 v1(209.54,101.52)
  BOTTOM w0.107: UC6.7 208.59,101.67 208.75,101.52 v1(209.54,101.52) ; RC576.2 210.24,97.99 210.22,98.02 v1(208.88,98.02)
PCH_SPI_D3_R1: length 19.8
  BOTTOM w0.107: JSPI1.13 202.58,85.23 201.77,86.03 RC30.2 201.77,88.81 201.1,89.48 201.1,91.35 205.62,95.87 v2(207.17,95.87) RC572.1 RC576.1
PCH_SPI_DO2_XDP: length 192.1
  TOP w0.107: v1(201.73,83.39) 202.37,84.02 202.37,84.23 202.37,92.59 206.97,97.19 206.97,101.51 206.31,102.17 206.31,105.22 207.44,106.35 207.44,113.88 205.88,115.44 v2(205.88,121.45) 205.88,122.69 204.03,124.53 v1(204.03,126.1)
  IN3 w0.102: v1(133.11,125.07) 133.11,124.67 133.6,124.18 135.02,124.18 135.81,124.97 140.49,124.97 141.04,124.41 148.6,124.41 150.75,122.26 157.08,122.26 158.11,123.28 159.02,123.28 160.16,124.42 161.75,124.42 164.89,127.56 180.38,127.56 181.5,128.67 183.65,128.67 184.33,129.35 195.9,129.35 196.92,128.33 201.96,128.33 204.03,126.26 v1(204.03,126.1)
  BOTTOM w0.107: v1(201.73,83.39) 201.49,83.14 201.49,81.87 198.83,79.22 191.46,79.22 190.13,80.54 184.5,80.54 183.86,81.18 RC11.1 ; v1(133.11,125.07) 133.11,124.84 132.83,124.56 129.78,124.56 127.21,121.99 121.02,121.99 120.84,122.17 115.5,122.17 115.36,122.32 113.5,122.32 109.05,126.76 95.79,126.76 93.87,128.69 JXDP1.60
PCH_SPI_DO_XDP: length 211.5
  TOP w0.107: v1(209.75,119.33) 210.78,118.3 210.78,100.07 210.01,99.3 210.01,97.96 205.17,93.13 204.87,93.13 204.2,92.46 204.2,90.99 203.77,90.55 203.77,83.12 204.44,82.44 204.78,82.44 v2(206.57,80.65) 207.39,79.84 v1(207.39,79.39) ; RC128.1 RC133.1 91.7,133.35 91.81,133.45 91.81,135.89 v1(92.04,136.12)
  IN3 w0.102: v1(92.04,136.12) 92.29,136.37 100.75,136.37 106.1,131.02 109.36,131.02 109.9,131.56 111.68,131.56 114.62,134.5 120.56,134.5 124.15,130.91 134.45,130.91 134.75,131.21 142.54,131.21 143.82,132.5 154.94,132.5 158.05,129.39 158.05,128.75 158.42,128.38 159.4,128.38 v1(159.85,128.84)
  BOTTOM w0.076: RC505.1 180.5,81.51 181.07,80.94 181.63,80.94 183.2,79.37 183.55,79.37
  BOTTOM w0.107: v1(159.85,128.84) 159.85,128.97 160.26,129.39 162.88,129.39 164.52,127.75 167.79,127.75 168.8,126.73 177.57,126.73 178.71,125.59 185.53,125.59 188.33,122.79 191.42,122.79 192.54,121.67 192.59,121.67 192.73,121.54 199.62,121.54 200.1,121.05 208.02,121.05 v1(209.75,119.33) ; v1(207.39,79.39) 206.05,80.72 200.85,80.72 198.98,78.85 195.82,78.85 194.22,77.26 191.74,77.26 191.71,77.23 190.67,77.23 190.56,77.34 190.56,78.81 190.01,79.37 183.55,79.37
PCIE_PRX_C_DTX_N8: length 2.4
  TOP w0.097: CR14.2 286.76,22.28 286.91,22.28 287.1,22.09 v4(287.42,22.09) 287.86,22.09 287.97,21.98 UR1.8
PCIE_PRX_C_DTX_N9: length 3.2
  TOP w0.097: UL1.39 268.81,109.04 268.41,109.04 268.3,109.15 267.92,109.15 267.52,109.55 267.37,109.55 267.33,109.51 266.74,109.51 266.71,109.55 266.45,109.55 CL2.2
PCIE_PRX_C_DTX_N12: length 7.3
  BOTTOM w0.097: JNGFF2.35 270.08,73.75 269.91,73.58 269.91,72.76 v4(269.4,72.25) 268.94,71.79 267.32,71.79 267.28,71.75 266.77,71.75 265.74,70.72 265.74,70.58 RZ1477.1
PCIE_PRX_C_DTX_N13: length 5.2
  TOP w0.097: RN127.1 282.11,27.98 282.11,27.73 282.33,27.51 282.51,27.51 282.76,27.25 282.76,26.95 v1(282.96,26.75)
  BOTTOM w0.097: JNGFF3.5 281.82,28.09 281.65,27.92 281.65,27.63 281.75,27.54 282.48,27.54 282.76,27.25 282.76,26.95 v1(282.96,26.75)
PCIE_PRX_C_DTX_N14: length 4.1
  TOP w0.097: RN125.1 278.68,27.98 278.68,27.78 278.94,27.52 278.94,26.96 v1(279.14,26.76)
  BOTTOM w0.097: v1(279.14,26.76) 278.87,27.02 278.87,27.4 278.67,27.6 278.67,27.86 278.82,28.01 JNGFF3.17
PCIE_PRX_C_DTX_N15: length 4.2
  TOP w0.097: RN82.1 275.24,27.97 275.24,27.34 275.11,27.22 275.11,26.96 v1(275.31,26.76)
  BOTTOM w0.097: JNGFF3.29 275.82,28.19 275.67,28.03 275.67,27.65 275.11,27.1 275.11,26.96 v1(275.31,26.76)
PCIE_PRX_C_DTX_N16: length 5
  TOP w0.097: v1(271.03,26.74) 271.27,26.98 271.27,27.33 271.65,27.71 271.65,27.96 RN78.1
  BOTTOM w0.097: JNGFF3.43 272.32,28.16 272.48,28.01 272.48,27.82 272.39,27.72 271.79,27.72 271.29,27.22 271.29,27.01 v1(271.03,26.74)
PCIE_PRX_C_DTX_P8: length 2.4
  TOP w0.097: UR1.7 287.97,22.38 287.89,22.31 287.14,22.31 286.98,22.47 286.76,22.47 CR13.2
PCIE_PRX_C_DTX_P9: length 3.2
  TOP w0.097: UL1.38 268.43,109.44 268.32,109.33 268,109.33 267.6,109.73 v4(267.04,109.73) 266.4,109.73 CL1.2
PCIE_PRX_C_DTX_P12: length 7.4
  BOTTOM w0.097: JNGFF2.33 269.58,73.71 269.72,73.56 269.72,72.83 269.5,72.61 269.45,72.61 269.04,72.2 269.04,72.15 268.86,71.97 v4(266.99,71.97) 266.73,71.97 265.55,70.8 265.55,70.64 RZ1476.1
PCIE_PRX_C_DTX_P13: length 5.1
  TOP w0.097: RN128.1 281.92,27.98 281.92,27.65 282.25,27.32 282.43,27.32 282.58,27.17 282.58,26.95 v1(282.38,26.75)
  BOTTOM w0.097: v1(282.38,26.75) 282.58,26.95 282.58,27.18 282.4,27.35 281.67,27.35 281.47,27.56 281.47,27.91 281.32,28.05 JNGFF3.7
PCIE_PRX_C_DTX_P14: length 4
  TOP w0.097: v1(278.56,26.76) 278.76,26.96 278.76,27.44 278.49,27.7 278.49,27.98 RN126.1
  BOTTOM w0.097: v1(278.56,26.76) 278.69,26.89 278.69,27.32 278.48,27.53 278.48,27.85 278.32,28.01 JNGFF3.19
PCIE_PRX_C_DTX_P15: length 4.2
  TOP w0.097: v1(274.73,26.76) 274.93,26.96 274.93,27.29 275.05,27.42 275.05,27.99 RN81.1
  BOTTOM w0.097: v1(274.73,26.76) 274.93,26.96 274.93,27.17 275.48,27.73 275.48,28.05 275.32,28.21 JNGFF3.31
PCIE_PRX_C_DTX_P16: length 4.9
  TOP w0.097: v1(271.62,26.74) 271.46,26.9 271.46,27.25 271.84,27.63 271.84,28 RN77.1
  BOTTOM w0.097: JNGFF3.41 272.82,28.11 272.67,27.95 272.67,27.74 272.46,27.54 271.87,27.54 271.48,27.15 271.48,26.88 v1(271.62,26.74)
PCIE_PRX_DTX_N8: length 184.6
  TOP w0.097: v1(284.23,21.67) 283.93,21.96 283.93,22.1 284.05,22.22 284.63,22.22 284.72,22.3 285.12,22.3 CR14.1
  IN3 w0.089: v1(284.23,21.67) 284.23,22.35 283.93,22.66 283.22,22.66 282.81,23.06 281.74,23.06 281.04,23.77 281.04,24.41 279.98,25.46 267.59,25.46 262.68,30.37 262.68,35.88 264.13,37.33 264.13,42.85 263.85,43.13 263.85,47.37 262.65,48.57 261.45,48.57 261.22,48.8 261.22,49.75 260.24,50.73 258.78,50.73 258.39,51.12 258.39,51.52 256.51,53.4 255.55,53.4 252.77,56.18 252.77,61.41 252.32,61.85 252.32,64.34 249,67.66 242.08,67.66 238.04,71.7 237.62,71.7 235.15,74.17 234.09,74.17 230.02,78.24 228.04,78.24 227.09,79.19 227.09,79.76 224.21,82.64 224.21,83.02 223.16,84.08 223.16,87.15 218.37,91.94 218.37,94.03 217.89,94.51 217.89,101.58 217.28,102.18 217.28,105.51 214.61,108.18 199.55,108.18 199.02,108.7 194.86,108.7 194.33,108.18 191.12,108.18 187.71,111.58 182.3,111.58 181.73,111.01 180.03,111.01 179.76,111.27 178.98,111.27 178.97,111.27 178.57,111.27 176.26,108.96 173.38,108.96 172.88,108.47 172.59,108.47 172.41,108.29 172.41,106.26 172.19,106.03 v1(172.19,105.34)
  BOTTOM w0.107: v1(172.19,105.34) 172.19,105.33 172.48,105.19 UC1.BU9
PCIE_PRX_DTX_N9: length 153.5
  TOP w0.097: v1(264.85,112.66) 264.7,112.66 264.29,112.25 264.29,109.55 264.49,109.34 264.98,109.34 CL2.1
  IN3 w0.089: v1(171.15,107.82) 171.38,107.59 171.55,107.59 171.69,107.46 171.69,105.98 170.45,104.74 169.77,104.74 169.72,104.79 163.06,104.79 162.29,105.56 162.29,108.24 161.49,109.05 161.49,111.48 161.35,111.61 161.35,111.61 160.02,112.94 160.02,116.92 164.07,120.97 164.07,122.07 163.63,122.51 163.63,125.73 165.05,127.16 180.55,127.16 181.67,128.27 185.41,128.27 186.09,128.95 195.6,128.95 196.62,127.93 200.6,127.93 202.93,125.61 220.79,125.61 232.87,113.53 241.34,113.53 245.45,117.64 259.57,117.64 262.64,114.56 262.76,114.56 264.16,113.17 264.16,112.62 264.24,112.53 264.73,112.53 v1(264.85,112.66)
  BOTTOM w0.089: v1(171.15,107.82) UC1.BP5
PCIE_PRX_DTX_N10: length 207.6
  IN3 w0.089: v1(170.22,107.19) 169.86,106.82 169.86,105.76 169.46,105.36 163.55,105.36 163.22,105.69 163.22,108.24 163.33,108.35 163.33,108.95 162.77,111.07 162.72,111.16 162.45,111.43 162.45,111.43 162.19,111.69 160.6,114.37 160.6,116.67 164.64,120.71 164.64,122.32 165.31,122.99 165.31,123.41 167.76,125.86 181.09,125.86 182.13,126.9 190.69,126.9 190.92,126.68 193.72,126.68 193.83,126.56 200.14,126.56 202.39,124.31 211.68,124.31 218.09,123.2 218.19,123.11 218.2,123.11 230.82,110.49 234.34,106.25 234.34,96.69 236.31,94.71 236.31,91.71 236.79,91.23 236.79,86.77 239.23,84.34 240.49,84.34 243.37,81.46 243.37,80.89 244.62,79.63 247.42,79.63 248.28,80.49 248.98,80.49 249.31,80.16 250.86,80.16 251.16,79.86 253.46,79.86 254.41,78.91 257.2,76.91 260.83,73.29 262.18,70.92 262.19,70.91 262.19,70.15 263.98,64.96 263.98,60.39 268.05,56.32 268.05,55.06 272.71,50.4 272.71,48.25 279.04,41.92 279.04,40.94 283.21,35.55 v1(283.21,34.71)
  BOTTOM w0.089: v1(170.22,107.19) UC1.BN6
  BOTTOM w0.097: v1(283.21,34.71) 283.19,34.71 282.99,34.51 282.99,34.39 283.2,34.18 JNGFF1.43
PCIE_PRX_DTX_N12: length 134.5
  IN3 w0.089: v1(169.3,107.19) 169.49,107.37 169.54,107.37 169.84,107.67 169.84,107.68 169.86,107.7 169.86,108.92 170.13,109.19 171.32,109.19 171.88,109.75 175.84,109.75 176.64,110.55 176.64,111.38 176.64,111.38 178.42,113.15 188.04,113.15 190.76,115.87 196.03,115.87 198.38,113.53 198.38,112.08 199.63,110.83 201.41,110.83 201.66,110.57 202.8,110.57 203.82,109.56 207.76,109.56 208.07,109.24 214.93,109.24 218.88,105.29 218.88,95.04 221.53,92.39 221.53,90.56 224.61,87.48 224.61,84 225.18,83.42 225.18,83.04 228.36,79.87 229.76,79.87 234.44,75.19 235.51,75.19 235.91,74.78 236.5,74.78 242.56,68.72 248.29,68.72 248.9,69.34 v1(249.31,69.34)
  BOTTOM w0.076: UC1.BL6 v1(169.3,107.19)
  BOTTOM w0.097: v1(249.31,69.34) 249.31,69.62 249.81,70.12 256.59,70.12 259.13,67.57 263.53,67.57 264.51,68.55 265.47,68.55 265.68,68.75 265.68,69.09 RZ1477.2
PCIE_PRX_DTX_N13: length 190.2
  TOP w0.097: RN127.2 282.11,29.47 282.11,29.88 282.35,30.13 v1(282.37,30.13)
  IN3 w0.089: v1(168.38,107.19) 168.38,107.26 168.48,107.37 168.76,107.37 168.93,107.54 168.93,108.18 169.1,108.34 169.1,109.17 169.65,109.73 170.85,109.73 171.71,110.59 171.71,112.04 172.28,112.61 173.3,112.61 174.3,113.61 176.72,113.61 177.41,114.3 187.56,114.3 190.28,117.02 196.51,117.02 200.09,113.44 215.22,113.44 220.03,108.64 220.03,95.51 222.68,92.86 222.68,91.03 224.22,89.49 224.78,89.49 226.52,87.74 226.52,83.33 228.83,81.02 230.24,81.02 234.92,76.33 235.98,76.33 236.39,75.93 236.98,75.93 242.52,70.39 247.3,70.39 247.97,71.06 249.22,71.06 250.78,69.5 250.78,68.85 251.94,67.69 252.59,67.69 253.86,66.41 253.86,63.26 254.31,62.82 254.31,61.52 255.02,60.81 255.02,56.59 256.92,54.69 257.84,54.69 258.25,54.28 258.25,53.85 259.34,52.76 259.34,52.12 259.71,51.75 260.84,51.75 264.82,47.78 264.82,45.77 265.26,45.33 265.26,43.8 265.1,43.64 265.1,36.93 263.65,35.48 263.65,31.84 268.33,27.16 280.89,27.16 282.37,28.64 v1(282.37,30.13)
  BOTTOM w0.076: UC1.BK6 v1(168.38,107.19)
PCIE_PRX_DTX_N14: length 190.2
  TOP w0.097: RN125.2 278.66,29.49 278.66,30.03 v1(278.77,30.15)
  IN3 w0.089: v1(278.77,30.15) 278.77,28.85 277.66,27.73 268.57,27.73 264.23,32.08 264.23,35.24 265.67,36.69 265.67,43.4 265.86,43.6 265.86,45.53 265.39,46.01 265.39,48.01 258.14,55.26 257.16,55.26 255.6,56.83 255.6,61.05 254.88,61.76 254.88,63.05 254.44,63.5 254.44,66.65 252.83,68.26 252.18,68.26 251.35,69.09 251.35,69.74 249.46,71.63 247.73,71.63 247.06,70.96 242.76,70.96 237.22,76.5 236.63,76.5 236.22,76.91 235.16,76.91 230.48,81.59 229.07,81.59 227.1,83.57 227.1,88.19 225.22,90.06 224.46,90.06 223.25,91.27 223.25,93.78 220.6,96.43 220.6,108.87 215.46,114.02 200.32,114.02 196.33,118.01 188.62,118.01 185.91,115.3 181.33,115.3 179.39,117.24 174.7,117.24 174.35,116.9 174.35,114.49 173.1,113.23 172.08,113.23 171.04,112.19 171.04,110.77 170.54,110.27 169.25,110.27 168.46,109.48 168.46,108.56 168,108.1 168,107.57 167.77,107.34 167.54,107.34 167.45,107.25 v1(167.45,107.19)
  BOTTOM w0.076: UC1.BJ6 v1(167.45,107.19)
PCIE_PRX_DTX_N15: length 185.7
  TOP w0.097: RN82.2 275.27,29.46 275.27,29.53 275.44,29.7 275.44,29.89 v1(275.68,30.14)
  IN3 w0.089: v1(275.68,30.14) 275.47,30.34 275.47,30.55 275.31,30.72 274.78,30.72 274.52,30.46 274.52,29.42 273.58,28.49 268.88,28.49 267.47,29.9 267.47,35.75 267.85,36.12 267.85,42.42 266.62,43.65 266.62,45.85 266.15,46.32 266.15,48.33 258.45,56.02 257.47,56.02 256.35,57.14 256.35,61.36 255.64,62.07 255.64,63.37 255.19,63.81 255.19,66.97 253.14,69.02 252.49,69.02 252.1,69.4 252.1,70.06 249.78,72.39 247.42,72.39 246.75,71.72 245.07,71.72 243.78,73.01 241.79,73.01 237.55,77.26 237.06,77.26 236.65,77.66 235.7,77.66 233.35,80.01 233.35,80.78 230.17,83.96 230.17,88.46 228.4,90.23 228.4,92.15 226.32,94.24 226.32,94.77 225,96.09 225,98.29 223,100.29 223,103.04 223.24,103.28 223.24,108.12 215.37,115.99 200.24,115.99 196.8,119.42 187.8,119.42 187.52,119.7 186.21,119.7 185.06,118.55 182.32,118.55 182.15,118.72 174.12,118.72 172.27,116.88 172.27,114.8 171.48,114.01 170.64,114.01 168.32,111.7 168.32,111.52 168.33,111.52 168.33,110.56 168.21,110.44 167.57,110.44 166.89,109.75 166.89,107.92 166.8,107.84 v1(166.53,107.84)
  BOTTOM w0.076: UC1.BG5 v1(166.53,107.84)
PCIE_PRX_DTX_N16: length 195.8
  TOP w0.097: RN78.2 271.61,29.45 271.61,29.5 271.29,29.82 271.29,29.86 v1(270.95,30.2)
  IN3 w0.089: v1(270.95,30.2) 270.86,30.2 270.74,30.32 270.74,30.71 270.82,30.78 271.2,30.78 271.38,30.6 271.78,30.6 271.97,30.79 272.32,30.79 273.74,32.21 273.74,44.06 270.65,47.16 270.65,49.55 262.95,57.25 262.95,58.25 260.77,60.43 260.77,65.31 260.12,65.96 260.12,70.11 257.14,73.1 256.39,73.1 254.68,74.81 254.68,75.62 252.83,77.47 250.64,77.47 250.01,78.11 249.38,78.11 248.85,77.58 243.77,77.58 241.31,80.03 241.31,80.5 240.08,81.73 239.61,81.73 239.12,82.23 238.43,82.23 234.74,85.92 234.74,90.37 234.18,90.93 234.18,93.94 232.28,95.84 232.28,103.64 231.69,104.23 231.69,106.14 216.76,121.07 202.72,121.07 199.28,124.51 192.99,124.51 192.97,124.53 189.08,124.53 188.76,124.85 184.89,124.85 183.76,123.71 180.79,123.71 180.7,123.8 168.62,123.8 167.37,122.55 167.37,122.14 167.23,122 167.23,120.34 165.63,118.74 165.63,115.03 164.21,113.61 163.25,113.61 162.87,113.23 162.87,112.14 163.44,111.57 163.44,111.57 165.03,109.98 165.03,108.53 165.4,108.16 165.4,108.07 v1(165.59,107.89)
  BOTTOM w0.076: v1(165.59,107.89) UC1.BE5
PCIE_PRX_DTX_P8: length 184.7
  TOP w0.097: v1(283.65,21.67) 283.75,21.76 283.75,22.18 283.97,22.4 284.56,22.4 284.64,22.49 285.17,22.49 CR13.1
  IN3 w0.089: v1(283.65,21.67) 284.05,22.07 284.05,22.28 283.86,22.47 283.14,22.47 282.74,22.88 281.67,22.88 280.86,23.69 280.86,24.33 279.9,25.28 267.52,25.28 262.5,30.3 262.5,35.96 263.95,37.4 263.95,42.77 263.67,43.05 263.67,47.3 262.58,48.39 261.37,48.39 261.04,48.73 261.04,49.68 260.17,50.55 258.7,50.55 258.21,51.04 258.21,51.45 256.43,53.22 255.47,53.22 252.59,56.1 252.59,61.33 252.14,61.78 252.14,64.27 248.93,67.48 242,67.48 237.97,71.52 237.55,71.52 235.08,73.99 234.02,73.99 229.94,78.06 227.96,78.06 226.91,79.12 226.91,79.69 224.03,82.57 224.03,82.95 222.98,84 222.98,87.08 218.19,91.87 218.19,93.96 217.71,94.44 217.71,101.5 217.1,102.11 217.1,105.43 214.53,108 199.47,108 198.95,108.52 194.93,108.52 194.41,108 191.04,108 187.64,111.4 182.38,111.4 181.8,110.83 179.95,110.83 179.69,111.09 178.64,111.09 176.34,108.79 173.45,108.79 172.95,108.29 172.66,108.29 172.59,108.22 172.59,106.18 172.37,105.96 172.37,105.68 172.68,105.37 v1(172.9,105.37)
  BOTTOM w0.107: UC1.BU8 172.83,105.37 v1(172.9,105.37)
PCIE_PRX_DTX_P9: length 153.5
  TOP w0.097: CL1.1 265.16,109.97 264.71,109.53 264.57,109.53 264.47,109.62 264.47,112.17 264.57,112.27 264.76,112.27 264.97,112.06 v1(264.97,111.79)
  IN3 w0.089: v1(264.97,111.79) 265.27,111.79 265.36,111.88 265.36,112.09 265.23,112.21 264.66,112.21 264.53,112.35 264.17,112.35 263.98,112.55 263.98,113.09 262.68,114.38 262.57,114.38 259.5,117.46 245.52,117.46 241.41,113.35 232.79,113.35 220.72,125.43 202.85,125.43 200.53,127.75 196.55,127.75 195.53,128.77 186.17,128.77 185.49,128.09 181.74,128.09 180.63,126.98 165.13,126.98 163.81,125.66 163.81,122.58 164.25,122.15 164.25,120.89 160.2,116.85 160.2,113.01 161.54,111.68 161.54,111.68 161.66,111.55 161.66,109.12 162.47,108.32 162.47,105.64 163.13,104.97 169.79,104.97 169.84,104.92 170.37,104.92 171.51,106.05 171.51,107.39 171.48,107.42 171.38,107.41 v1(171.15,107.19)
  BOTTOM w0.089: v1(171.15,107.19) UC1.BP6
PCIE_PRX_DTX_P10: length 207.7
  IN3 w0.089: v1(170.22,107.84) 170.23,107.7 170.09,107.57 170.09,107.57 169.86,107.34 169.86,107.07 169.68,106.9 169.68,105.84 169.39,105.54 163.62,105.54 163.4,105.77 163.4,108.17 163.51,108.28 163.51,108.98 162.94,111.14 162.87,111.27 162.33,111.81 160.78,114.42 160.78,116.6 164.82,120.64 164.82,122.25 165.49,122.92 165.49,123.33 167.84,125.68 181.17,125.68 182.21,126.72 190.62,126.72 190.85,126.5 193.65,126.5 193.76,126.38 200.06,126.38 202.31,124.13 211.67,124.13 218.01,123.03 218.14,122.92 230.69,110.37 234.16,106.18 234.16,96.62 236.13,94.64 236.13,91.63 236.61,91.15 236.61,86.7 239.15,84.16 240.42,84.16 243.19,81.39 243.19,80.81 244.55,79.45 247.49,79.45 248.36,80.31 248.91,80.31 249.24,79.98 250.78,79.98 251.09,79.68 253.39,79.68 254.29,78.77 257.09,76.77 260.68,73.18 262.01,70.87 262.01,70.12 263.8,64.93 263.8,60.31 267.87,56.25 267.87,54.98 272.52,50.32 272.52,48.17 278.86,41.84 278.86,40.88 283.03,35.48 283.03,35.15 282.84,34.96 282.84,34.92 282.79,34.87 282.79,34.74 282.7,34.66 282.52,34.66 v1(282.47,34.71)
  BOTTOM w0.089: UC1.BN5 170.26,107.84 v1(170.22,107.84)
  BOTTOM w0.097: v1(282.47,34.71) 282.54,34.71 282.79,34.46 282.79,34.33 282.7,34.24 JNGFF1.41
PCIE_PRX_DTX_P12: length 134.5
  IN3 w0.089: v1(169.3,107.9) 169.23,107.82 169.23,107.64 169.33,107.55 169.47,107.55 169.67,107.75 169.67,107.76 169.68,107.77 169.68,108.99 170.06,109.37 171.24,109.37 171.8,109.93 175.77,109.93 176.46,110.62 176.46,111.45 178.34,113.33 187.96,113.33 190.68,116.05 196.11,116.05 198.56,113.6 198.56,112.15 199.7,111.01 201.48,111.01 201.73,110.75 202.88,110.75 203.89,109.74 207.83,109.74 208.15,109.42 215.01,109.42 219.06,105.37 219.06,95.11 221.71,92.46 221.71,90.63 224.79,87.55 224.79,84.07 225.36,83.5 225.36,83.12 228.43,80.05 229.84,80.05 234.52,75.37 235.58,75.37 235.99,74.96 236.58,74.96 242.64,68.9 248.21,68.9 248.9,69.59 v1(248.9,69.75)
  BOTTOM w0.076: v1(169.3,107.9) 168.87,107.69 UC1.BL5
  BOTTOM w0.097: RZ1476.2 265.49,69.14 265.49,68.83 265.4,68.73 264.43,68.73 263.46,67.76 259.21,67.76 256.66,70.3 249.73,70.3 249.18,69.75 v1(248.9,69.75)
PCIE_PRX_DTX_P13: length 190.1
  TOP w0.097: v1(281.78,30.17) 281.79,30.17 281.79,30.12 281.92,29.99 281.92,29.47 RN128.2
  IN3 w0.089: v1(168.37,107.77) 168.38,107.77 168.38,107.63 168.46,107.55 168.69,107.55 168.75,107.61 168.75,108.25 168.92,108.42 168.92,109.24 169.58,109.9 170.77,109.9 171.53,110.66 171.53,111.56 171.53,111.56 171.53,112.11 172.21,112.79 173.22,112.79 174.23,113.79 176.64,113.79 177.33,114.48 187.49,114.48 190.2,117.2 196.58,117.2 200.16,113.62 215.29,113.62 220.21,108.71 220.21,95.59 222.86,92.94 222.86,91.11 224.17,89.8 224.3,89.67 224.85,89.67 226.7,87.82 226.7,83.4 228.91,81.2 230.31,81.2 235,76.51 236.06,76.51 236.46,76.11 237.06,76.11 242.59,70.57 247.23,70.57 247.89,71.24 249.3,71.24 250.96,69.58 250.96,68.93 252.01,67.87 252.67,67.87 254.04,66.49 254.04,63.34 254.49,62.89 254.49,61.6 255.2,60.88 255.2,56.67 257,54.87 257.92,54.87 258.43,54.36 258.43,53.92 259.52,52.84 259.52,52.2 259.78,51.93 260.91,51.93 265,47.85 265,45.84 265.44,45.4 265.44,43.73 265.28,43.57 265.28,36.85 263.83,35.41 263.83,31.92 268.41,27.34 280.82,27.34 282.19,28.71 282.19,29.72 281.79,30.12 281.79,30.17 v1(281.78,30.17)
  BOTTOM w0.076: UC1.BK5 168.3,107.8 v1(168.37,107.77)
PCIE_PRX_DTX_P14: length 190.3
  TOP w0.097: RN126.2 278.47,29.46 278.47,29.86 v1(278.19,30.15)
  IN3 w0.089: v1(167.45,107.84) 167.45,107.66 167.6,107.52 167.7,107.52 167.82,107.64 167.82,108.18 168.28,108.64 168.28,109.56 169.17,110.45 170.47,110.45 170.86,110.84 170.86,111.56 170.86,111.56 170.86,112.26 172.01,113.41 173.02,113.41 174.17,114.56 174.17,116.97 174.62,117.42 179.47,117.42 181.41,115.48 185.83,115.48 188.55,118.19 196.4,118.19 200.4,114.2 215.53,114.2 220.78,108.95 220.78,96.5 223.43,93.85 223.43,91.35 224.54,90.24 225.29,90.24 227.28,88.26 227.28,83.64 229.15,81.77 230.55,81.77 235.23,77.09 236.3,77.09 236.7,76.68 237.29,76.68 242.83,71.14 246.99,71.14 247.65,71.81 249.54,71.81 251.53,69.82 251.53,69.16 252.25,68.44 252.91,68.44 254.62,66.73 254.62,63.57 255.06,63.13 255.06,61.84 255.78,61.12 255.78,56.9 257.24,55.44 258.22,55.44 265.57,48.09 265.57,46.08 266.04,45.61 266.04,43.52 265.85,43.33 265.85,36.61 264.41,35.17 264.41,32.15 268.65,27.92 277.58,27.92 278.59,28.93 278.59,29.74 v1(278.19,30.15)
  BOTTOM w0.076: UC1.BJ5 v1(167.45,107.84)
PCIE_PRX_DTX_P15: length 185.7
  TOP w0.097: v1(275.1,30.14) 275.25,29.98 275.25,29.78 275.08,29.61 275.08,29.49 RN81.2
  IN3 w0.089: v1(275.1,30.14) 275.29,30.33 275.29,30.48 275.23,30.54 274.86,30.54 274.7,30.38 274.7,29.35 273.66,28.31 268.81,28.31 267.29,29.83 267.29,35.82 267.67,36.2 267.67,42.35 266.44,43.57 266.44,45.77 265.97,46.24 265.97,48.25 258.38,55.84 257.4,55.84 256.17,57.07 256.17,61.29 255.46,62 255.46,63.29 255.01,63.74 255.01,66.89 253.07,68.84 252.42,68.84 251.92,69.33 251.92,69.98 249.7,72.21 247.49,72.21 246.82,71.54 245,71.54 243.71,72.83 241.72,72.83 237.47,77.08 236.98,77.08 236.58,77.48 235.62,77.48 233.17,79.93 233.17,80.7 229.99,83.88 229.99,88.38 228.22,90.15 228.22,92.07 226.14,94.16 226.14,94.7 224.82,96.01 224.82,98.21 222.82,100.21 222.82,103.12 223.06,103.36 223.06,108.04 215.3,115.8 200.16,115.8 196.72,119.24 187.72,119.24 187.45,119.52 186.28,119.52 185.14,118.37 182.24,118.37 182.07,118.54 174.19,118.54 172.45,116.8 172.45,114.72 171.56,113.83 170.71,113.83 168.5,111.62 168.5,111.59 168.51,111.59 168.51,111.56 168.5,111.56 168.5,110.48 168.28,110.26 167.65,110.26 167.07,109.68 167.07,107.85 166.88,107.66 166.88,107.66 166.68,107.47 166.6,107.47 166.53,107.39 v1(166.53,107.19)
  BOTTOM w0.076: UC1.BG6 166.15,107.01 v1(166.53,107.19)
PCIE_PRX_DTX_P16: length 195.8
  TOP w0.097: v1(271.64,30.2) 271.48,30.04 271.48,29.9 271.8,29.58 271.8,29.5 RN77.2
  IN3 w0.089: v1(271.64,30.2) 272.04,30.6 272.4,30.6 273.92,32.13 273.92,44.14 270.83,47.23 270.83,49.62 263.13,57.33 263.13,58.33 260.95,60.51 260.95,65.38 260.3,66.03 260.3,70.19 257.21,73.28 256.47,73.28 254.86,74.89 254.86,75.7 252.91,77.65 250.72,77.65 250.08,78.29 249.3,78.29 248.77,77.76 243.85,77.76 241.49,80.11 241.49,80.58 240.16,81.91 239.69,81.91 239.2,82.41 238.5,82.41 234.92,85.99 234.92,90.45 234.36,91 234.36,94.01 232.46,95.91 232.46,103.71 231.87,104.3 231.87,106.22 216.84,121.25 202.79,121.25 199.36,124.69 193.07,124.69 193.04,124.71 189.15,124.71 188.84,125.03 184.82,125.03 183.68,123.89 180.87,123.89 180.77,123.98 168.54,123.98 167.19,122.63 167.19,122.21 167.05,122.08 167.05,120.41 165.45,118.81 165.45,115.11 164.13,113.79 163.18,113.79 162.69,113.31 162.69,112.06 163.31,111.44 163.31,111.44 163.32,111.43 163.33,111.43 164.85,109.9 164.85,108.46 165.23,108.09 165.23,107.74 165.59,107.37 v1(165.59,107.25)
  BOTTOM w0.076: v1(165.59,107.25) UC1.BE6
PCIE_PTX_C_DRX_N8: length 3.1
  TOP w0.097: UR1.4 288.12,23.58 288.02,23.69 287.48,23.69 287.24,23.93 287.24,24.51 287.06,24.69 286.76,24.69 CR12.2
PCIE_PTX_C_DRX_N9: length 3.1
  TOP w0.097: CL6.2 266.4,107.71 v4(267.06,107.71) 267.34,107.71 267.58,107.95 268.36,107.95 268.47,107.84 UL1.42
PCIE_PTX_C_DRX_N10: length 20.5
  BOTTOM w0.097: JNGFF1.37 281.7,32.77 281.53,32.6 281.53,31.91 281.24,31.63 274.28,31.63 273.34,30.69 270.28,30.69 270.08,30.88 v4(267.93,30.88) 267.36,30.88 266.95,31.29 266.95,32.08 266.62,32.42 265.58,32.42 265.3,32.7 CZ13.2
PCIE_PTX_C_DRX_N12: length 7.3
  BOTTOM w0.097: JNGFF2.39 271.08,73.68 271.22,73.54 271.22,72.93 270.96,72.66 270.91,72.66 270.5,72.25 270.5,72.2 269.68,71.38 v4(268.13,71.38) 267.6,71.38 267.22,71.01 267.22,70.65 CZ10.2
PCIE_PTX_C_DRX_N13: length 4.6
  TOP w0.097: v1(281.08,26.76) 280.85,26.99 280.85,27.14 280.39,27.6 280.39,27.92 CN65.1
  BOTTOM w0.097: JNGFF3.11 280.32,28.12 280.17,27.96 280.17,27.79 280.26,27.69 280.54,27.69 280.88,27.35 280.88,26.96 v1(281.08,26.76)
PCIE_PTX_C_DRX_N14: length 4
  TOP w0.097: CN67.1 276.96,27.92 276.96,27.6 277.03,27.53 277.03,26.98 v1(277.26,26.76)
  BOTTOM w0.097: v1(277.26,26.76) 277.06,26.96 277.06,27.9 277.32,28.17 JNGFF3.23
PCIE_PTX_C_DRX_N15: length 4.5
  TOP w0.097: CN69.1 273.55,27.93 273.55,27.43 273.27,27.15 273.27,26.96 v1(273.47,26.76)
  BOTTOM w0.097: v1(273.47,26.76) 273.29,26.94 273.29,27.15 273.65,27.51 273.87,27.51 274.17,27.8 274.17,28.06 274.32,28.21 JNGFF3.35
PCIE_PTX_C_DRX_N16: length 5.1
  TOP w0.097: v1(269.85,26.75) 269.65,26.95 269.65,27.01 270.12,27.48 270.12,27.94 CN71.1
  BOTTOM w0.097: JNGFF3.47 271.32,28.13 271.17,27.98 271.17,27.72 270.95,27.51 270.18,27.51 269.71,27.04 269.71,26.89 v1(269.85,26.75)
PCIE_PTX_C_DRX_P8: length 3.1
  TOP w0.097: CR11.2 286.76,24.88 287.14,24.88 287.46,24.56 v4(287.46,24.25) 287.46,23.97 287.56,23.87 288.02,23.87 288.12,23.98 UR1.3
PCIE_PTX_C_DRX_P9: length 3.1
  TOP w0.097: UL1.41 268.81,108.24 268.5,108.24 268.39,108.13 267.5,108.13 267.3,107.93 266.77,107.93 266.74,107.9 266.45,107.9 CL5.2
PCIE_PTX_C_DRX_P10: length 20.5
  BOTTOM w0.097: CZ12.2 266.19,33.13 266.1,33.04 265.58,33.04 265.48,32.95 265.48,32.78 265.66,32.6 266.7,32.6 267.14,32.16 267.14,31.37 267.44,31.07 267.6,31.07 267.63,31.1 268.22,31.1 268.25,31.07 270.15,31.07 270.35,30.87 273.26,30.87 274.2,31.81 281.17,31.81 281.34,31.99 281.34,32.61 281.2,32.75 JNGFF1.35
PCIE_PTX_C_DRX_P12: length 7.3
  BOTTOM w0.097: CZ11.2 267.41,70.69 267.41,70.93 267.64,71.16 268.42,71.16 268.46,71.2 269.76,71.2 v4(270.86,72.3) 271.41,72.85 271.41,73.52 271.58,73.69 JNGFF2.41
PCIE_PTX_C_DRX_P13: length 4.5
  TOP w0.097: CN66.1 280.21,27.92 280.21,27.52 280.66,27.06 280.66,26.93 v1(280.5,26.76)
  BOTTOM w0.097: JNGFF3.13 279.82,28.16 279.98,28 279.98,27.71 280.19,27.51 280.47,27.51 280.69,27.28 280.69,26.96 v1(280.5,26.76)
PCIE_PTX_C_DRX_P14: length 3.9
  TOP w0.097: CN68.1 276.78,27.92 276.78,27.52 276.85,27.45 276.85,26.93 v1(276.68,26.76)
  BOTTOM w0.097: JNGFF3.25 276.82,28.11 276.88,28.06 276.88,26.96 v1(276.68,26.76)
PCIE_PTX_C_DRX_P15: length 4.5
  TOP w0.097: v1(272.89,26.76) 273.09,26.96 273.09,27.23 273.36,27.51 273.36,27.91 CN70.1
  BOTTOM w0.097: v1(272.89,26.76) 273.1,26.97 273.1,27.23 273.57,27.69 273.79,27.69 273.98,27.88 273.98,28.03 273.82,28.19 JNGFF3.37
PCIE_PTX_C_DRX_P16: length 5.2
  TOP w0.097: CN72.1 269.94,27.9 269.94,27.56 269.47,27.09 269.47,26.95 v1(269.27,26.75)
  BOTTOM w0.097: v1(269.27,26.75) 269.52,27.01 269.52,27.11 270.1,27.69 270.87,27.69 270.98,27.8 270.98,27.98 270.82,28.14 JNGFF3.49
PCIE_PTX_DRX_N8: length 188.4
  TOP w0.097: CR12.1 285.13,24.71 284.78,24.71 284.13,25.37 283.76,25.37 v1(283.56,25.17)
  IN3 w0.089: v1(172.41,111.36) 172.61,111.56 173.25,111.56 173.38,111.43 173.39,111.43 174.55,110.27 175.6,110.27 176.08,110.75 176.08,111.17 176.08,111.17 176.08,111.55 176.09,111.62 176.08,111.63 176.08,111.63 176.08,111.63 176.08,112.02 177.79,113.73 187.8,113.73 190.52,116.45 196.27,116.45 199.85,112.87 214.98,112.87 219.45,108.4 219.45,95.28 222.1,92.63 222.1,90.8 223.99,88.92 224.53,88.92 225.95,87.49 225.95,83.09 228.59,80.44 230,80.44 234.68,75.76 235.74,75.76 236.15,75.35 236.74,75.35 242.28,69.82 247.54,69.82 248.21,70.48 248.99,70.48 250.2,69.27 250.2,68.6 251.68,67.11 252.35,67.11 253.29,66.18 253.29,63.01 253.73,62.56 253.73,57.06 256.65,54.15 256.65,54 259.47,51.18 260.6,51.18 264.24,47.54 264.24,43.29 264.52,43.01 264.52,37.16 263.08,35.72 263.08,30.61 267.58,26.11 280.28,26.11 281.02,25.37 283.36,25.37 v1(283.56,25.17)
  BOTTOM w0.076: UC1.BT4 171.77,109.23 171.77,109.49 171.65,109.62 171.65,111.49 171.73,111.57 172.2,111.57 v1(172.41,111.36)
PCIE_PTX_DRX_N9: length 115.3
  TOP w0.097: CL6.1 264.2,107.39 263.7,107.88 263.7,113.68 264.16,114.14 v1(264.16,114.48)
  IN1 w0.089: v1(171.24,116.89) 171.43,116.7 172.09,116.7 172.7,117.31 174.23,117.31 174.61,117.69 181.84,120.68 186.33,120.68 187.19,121.55 189.32,121.55 189.78,121.1 224.23,121.1 228.09,117.23 241.58,117.23 242.33,116.49 248.09,116.49 248.98,117.38 255.63,117.38 257.9,115.1 258.35,115.1 258.57,114.88 261.81,114.88 262.73,113.95 263.4,113.95 263.55,113.8 263.89,113.8 264.3,114.21 264.3,114.34 v1(264.16,114.48)
  BOTTOM w0.076: UC1.BR2 170.97,109.67 171.32,110.5 171.32,113.51 171.83,114.01 171.83,116.54 171.6,116.77 171.47,116.77 171.39,116.85 171.28,116.85 v1(171.24,116.89)
PCIE_PTX_DRX_N10: length 200.6
  IN1 w0.089: v1(170.3,112.02) 170.7,112.42 171.84,112.42 172.08,112.66 174.56,112.66 175.22,112 176.56,112 177.57,113 187.62,113 189.88,115.26 191.65,115.99 197.75,115.99 197.93,116.18 212.45,116.18 224.48,111.12 236.71,111.12 236.97,111.38 247.53,111.38 248,110.91 256.61,110.91 256.97,110.54 258.34,110.54 260.47,108.42 261.33,108.42 263.04,106.7 264.71,106.7 265.78,105.63 265.78,104.11 269.57,100.31 269.57,96.08 271,94.66 271,92.24 271.43,91.81 271.43,89.96 271.47,89.92 272.38,89 272.38,88.31 276.22,84.47 276.22,82.94 277.05,82.11 277.05,79.71 280.09,76.68 283.58,76.68 285.09,75.16 285.09,72.89 282.92,70.72 280.43,70.72 277.81,68.1 277.81,65.46 274.94,62.6 274.94,55.37 273.29,53.72 273.29,49.05 273.88,48.47 273.88,37.41 273.19,36.72 269.34,36.72 268.44,35.81 266.24,35.81 265.8,35.38 v1(265.49,35.06)
  BOTTOM w0.076: UC1.BR4 170.67,108.64 170.67,109.19 170.52,109.53 170.52,109.78 170.55,109.87 170.55,110.1 170.52,110.19 170.52,110.53 170.66,110.68 170.66,112.14 170.58,112.23 170.51,112.23 v1(170.3,112.02)
  BOTTOM w0.097: v1(265.49,35.06) 265.64,34.91 265.64,34.78 CZ13.1
PCIE_PTX_DRX_N12: length 146.4
  IN3 w0.089: v1(255.9,69.19) 255.71,69 255.6,69 250.49,74.11 249.22,74.11 248.6,74.73 242.59,74.73 237.94,79.38 236.41,79.38 235.13,80.67 235.13,81.43 231.9,84.67 231.9,89.2 231.34,89.75 231.34,91.83 228.76,94.41 228.76,98.27 227.88,99.16 227.88,104.05 225.46,106.46 225.46,108.35 216.1,117.71 202.06,117.71 198.57,121.2 190.16,121.2 189.77,121.59 185.66,121.59 184.92,120.85 178.59,120.85 178.18,120.44 173.18,120.44 172.13,119.39 170.31,119.39 169.02,118.11 169.02,116.8 169.5,116.32 170.19,116.32 170.54,115.98 170.54,115.66 170.45,115.57 170.34,115.57 v1(169.99,115.92)
  BOTTOM w0.076: UC1.BN2 169.63,109.91 169.38,110.16 169.38,115.51 169.55,115.68 169.75,115.68 v1(169.99,115.92)
  BOTTOM w0.097: v1(255.9,69.19) 256.91,69.19 258.98,67.12 265.88,67.12 266.2,67.44 266.8,67.44 267.59,68.22 267.59,68.75 267.42,68.92 267.06,68.92 266.89,69.1 CZ10.1
PCIE_PTX_DRX_N13: length 191.6
  TOP w0.097: CN65.2 280.28,29.65 280.28,30.04 v1(280.6,30.36)
  IN3 w0.089: v1(280.6,30.36) 280.6,31 280.17,31.43 274.49,31.43 273.88,30.82 273.88,29.6 273.35,29.06 269.12,29.06 268.04,30.14 268.04,35.47 268.87,36.29 268.87,42.33 268.09,43.11 268.09,44.02 267.19,44.92 267.19,46.08 266.72,46.56 266.72,48.76 260.47,55 260.47,55.7 257.93,58.25 257.93,61.66 256.83,62.75 256.83,66.96 250.25,73.53 248.98,73.53 248.36,74.16 242.35,74.16 237.7,78.81 236.18,78.81 234.5,80.49 234.5,81.25 231.32,84.43 231.32,88.96 230.77,89.51 230.77,91.6 227.46,94.9 227.46,97.58 227.3,97.74 227.3,100.62 224.89,103.03 224.89,108.11 215.87,117.13 201.82,117.13 198.33,120.62 189.81,120.62 189.45,120.98 185.86,120.98 185.16,120.27 179.06,120.27 178.66,119.87 173.42,119.87 172.37,118.82 170.54,118.82 169.69,117.97 169.69,117.23 169.92,117 170.3,117 v1(170.4,116.9)
  BOTTOM w0.076: v1(170.4,116.9) 169.29,116.9 169.15,116.76 169.15,109.68 169.33,109.49 169.33,109.19 169.07,108.92 UC1.BM4
PCIE_PTX_DRX_N14: length 189
  TOP w0.097: v1(271.96,32.5) 272.88,32.5 273.68,31.7 275.9,31.7 277.12,30.48 277.12,29.38 CN67.2
  IN3 w0.089: v1(271.96,32.5) 271.54,32.5 271.45,32.59 271.45,37.68 271.11,38.02 271.11,39.91 270.59,40.43 270.59,44.57 269.11,46.04 269.11,47.21 269.53,47.63 269.53,49.08 259.65,58.96 259.65,62.37 258.55,63.47 258.55,69.9 256.57,71.88 255.94,71.88 252.13,75.69 251.34,75.69 250.8,76.24 249.53,76.24 249.31,76.46 243.31,76.46 238.66,81.11 237.96,81.11 233.62,85.45 233.62,89.91 233.06,90.47 233.06,93.47 231.16,95.37 231.16,103.17 230.57,103.76 230.57,105.68 216.3,119.95 202.25,119.95 199.29,122.92 192.4,122.92 191.95,123.37 188.23,123.37 187.87,123.73 185.36,123.73 184.22,122.59 177.89,122.59 177.47,122.17 173.76,122.17 173.24,122.68 170.71,122.68 170.44,122.41 170.44,121.93 170.07,121.56 169.03,121.56 168.37,120.9 168.37,119.89 166.79,118.32 166.79,113.3 167.35,112.74 v1(168.62,112.74)
  BOTTOM w0.076: UC1.BL2 168.5,109.9 168.77,110.16 168.77,110.35 168.77,111.9 168.49,112.18 168.49,112.61 v1(168.62,112.74)
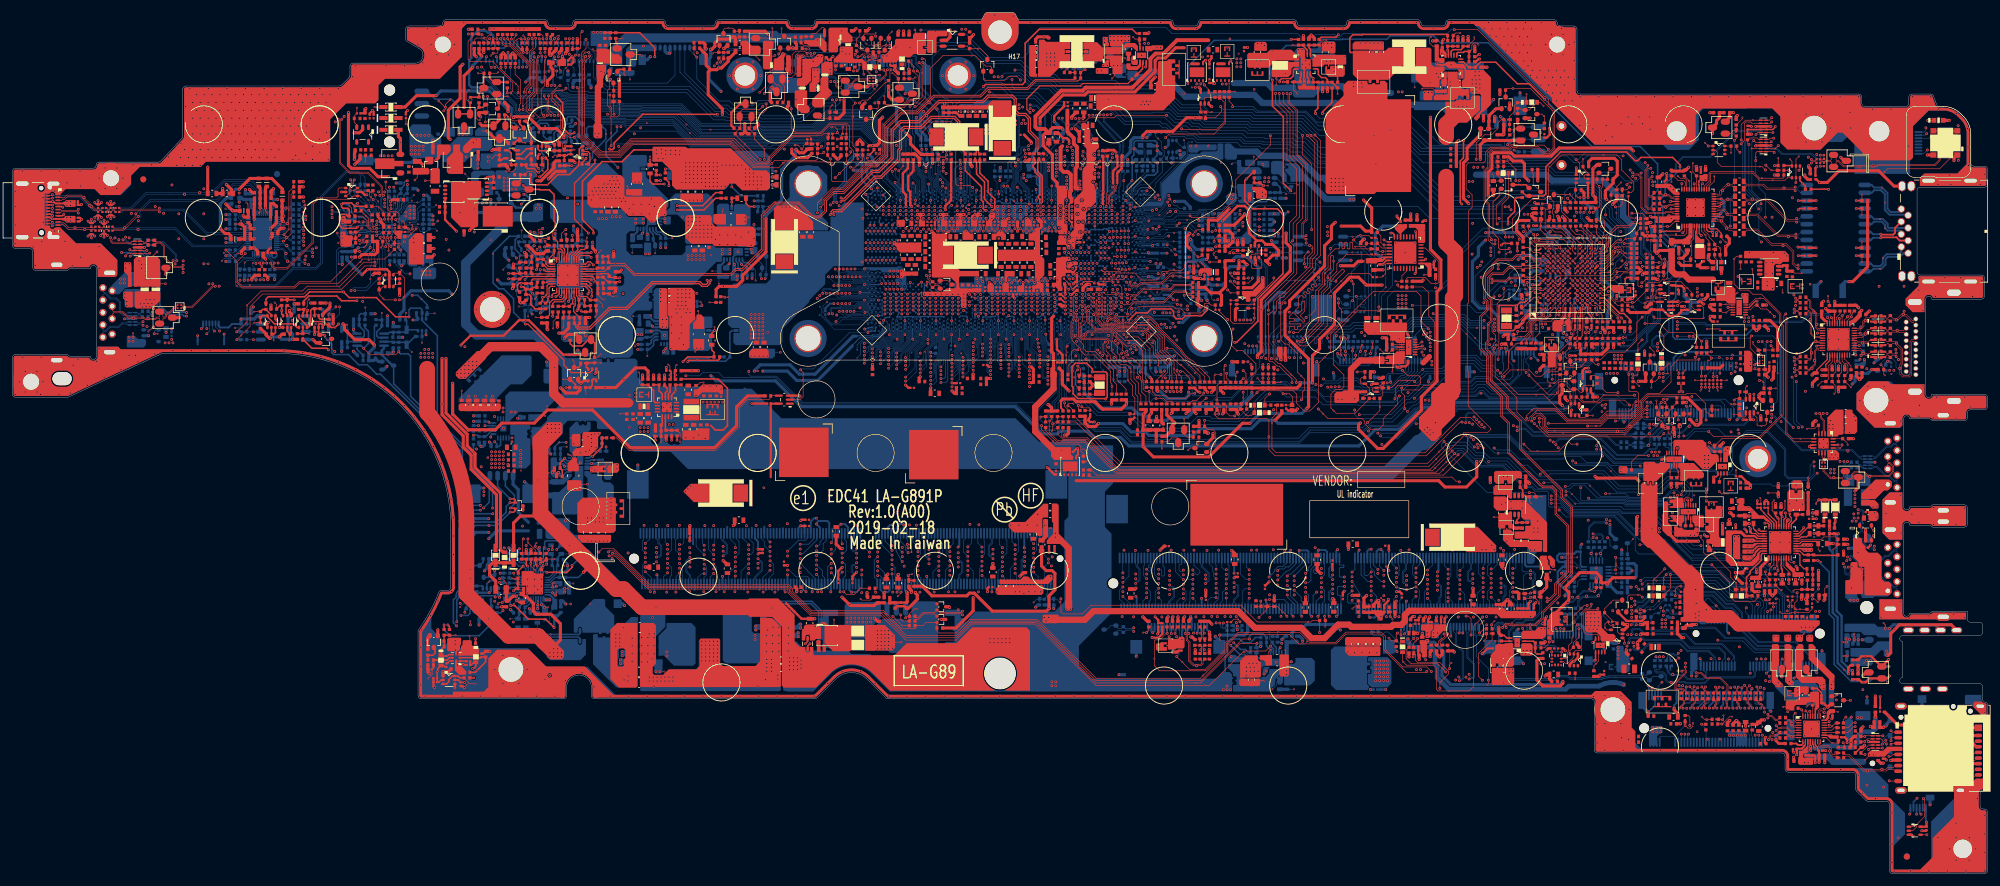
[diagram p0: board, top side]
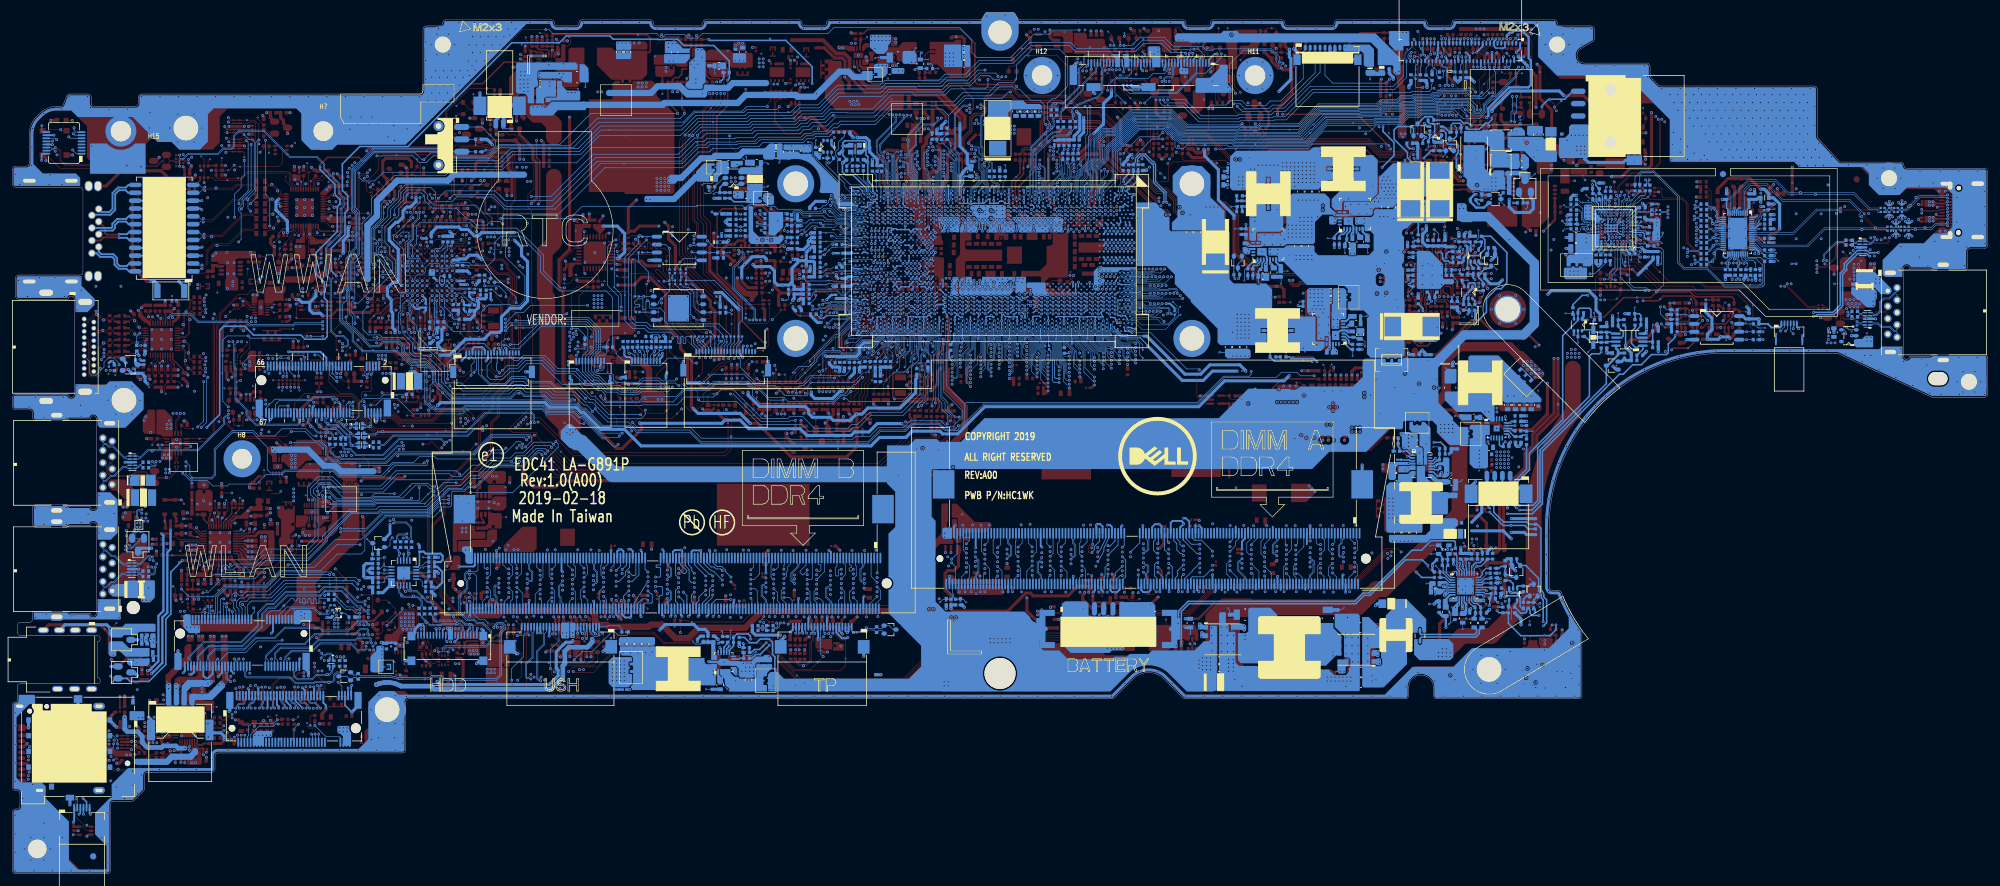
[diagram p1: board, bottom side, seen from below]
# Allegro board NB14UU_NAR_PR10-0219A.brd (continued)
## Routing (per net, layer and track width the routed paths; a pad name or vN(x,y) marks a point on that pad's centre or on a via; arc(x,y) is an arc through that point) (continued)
PCIE_PTX_DRX_N15: length 189.7
  TOP w0.097: CN69.2 273.54,29.54 273.54,29.62 273.3,29.85 273.3,29.99 v1(273.48,30.17)
  IN3 w0.089: v1(168.62,115.08) 168.22,114.67 168.15,114.67 168.09,114.73 168.09,115.09 167.56,115.62 167.56,118.02 169.17,119.63 169.17,120.53 169.42,120.78 171.64,120.78 172.34,121.48 172.46,121.48 172.52,121.41 177.78,121.41 178.2,121.83 184.53,121.83 185.67,122.97 187.12,122.97 187.48,122.61 191.64,122.61 192.08,122.16 198.97,122.16 202.46,118.67 216.51,118.67 229.82,105.36 229.82,103.45 230.41,102.86 230.41,95.06 232.31,93.16 232.31,90.15 232.86,89.6 232.86,85.14 237.65,80.35 238.34,80.35 242.99,75.7 249,75.7 249.62,75.08 250.89,75.08 254.95,71.01 256.37,71.01 257.8,69.59 257.8,63.16 258.9,62.06 258.9,58.65 268.78,48.77 268.78,47.94 268.36,47.52 268.36,45.73 269.83,44.25 269.83,40.11 270.35,39.6 270.35,37.57 270.69,37.22 270.69,33 268.62,30.93 268.62,30.12 269.29,29.46 272.94,29.46 273.14,29.65 273.14,29.82 v1(273.48,30.17)
  BOTTOM w0.076: v1(168.62,115.08) 168.43,114.88 168.09,114.88 167.92,114.71 167.92,111.82 168.28,111.46 168.28,110.74 168.08,110.54 168.08,110.19 168.11,110.1 168.11,109.88 168.08,109.79 168.08,109.53 168.23,109.19 168.23,108.75 168.5,108.47 UC1.BL4
PCIE_PTX_DRX_N16: length 183.8
  TOP w0.097: v1(270.23,33.39) 270.23,32.99 270.43,32.79 270.43,32.5 268.72,30.79 268.72,30.02 268.82,29.92 269.9,29.92 270.11,29.71 270.11,29.54 CN71.2
  IN3 w0.089: v1(168.62,116.25) 168.46,116.41 168.15,116.41 167.95,116.61 167.95,117.85 170.07,119.97 171.9,119.97 172.95,121.02 177.94,121.02 178.35,121.42 184.68,121.42 185.42,122.17 190.01,122.17 190.4,121.77 191.92,121.77 191.92,121.77 198.81,121.77 202.3,118.28 216.34,118.28 227.63,106.99 227.63,105.65 229.34,103.95 229.34,94.65 231.92,92.07 231.92,89.99 232.47,89.43 232.47,84.91 235.71,81.67 235.71,80.9 236.65,79.96 238.18,79.96 242.83,75.31 248.83,75.31 249.46,74.68 250.73,74.68 254.83,70.58 256.23,70.58 257.4,69.41 257.4,62.99 258.5,61.89 258.5,58.49 268.38,48.61 268.38,48.11 267.77,47.49 267.77,45.15 268.4,44.52 268.98,44.52 269.44,44.07 269.44,37.4 270.11,36.72 270.11,34.8 269.79,34.47 269.79,33.77 270.17,33.39 v1(270.23,33.39)
  BOTTOM w0.076: UC1.BJ4 167.19,108.6 167.46,108.87 167.52,109.2 167.54,109.22 167.62,109.69 167.61,109.83 167.58,109.9 167.57,109.92 167.57,109.95 167.57,110.02 167.57,110.04 167.62,110.19 167.62,110.54 167.13,111.02 167.13,113.36 167.03,113.46 167.03,115.17 168.1,116.25 v1(168.62,116.25)
PCIE_PTX_DRX_P8: length 188.3
  TOP w0.097: CR11.1 285.16,24.9 284.86,24.9 284.21,25.55 283.76,25.55 v1(283.56,25.75)
  IN3 w0.089: v1(172.41,111.94) 172.61,111.74 173.33,111.74 174.62,110.45 175.53,110.45 175.9,110.83 175.9,111.25 175.9,111.25 175.9,111.55 175.9,111.56 175.9,112.1 177.71,113.91 187.72,113.91 190.44,116.63 196.35,116.63 199.92,113.05 215.06,113.05 219.63,108.47 219.63,95.35 222.28,92.7 222.28,90.87 224.06,89.1 224.6,89.1 226.13,87.57 226.13,83.16 228.67,80.62 230.07,80.62 234.76,75.94 235.82,75.94 236.23,75.53 236.82,75.53 242.36,70 247.46,70 248.13,70.66 249.06,70.66 250.38,69.34 250.38,68.67 251.76,67.29 252.43,67.29 253.47,66.25 253.47,63.08 253.91,62.64 253.91,57.14 256.83,54.23 256.83,54.08 259.54,51.36 260.67,51.36 264.42,47.61 264.42,43.36 264.7,43.08 264.7,37.09 263.26,35.64 263.26,30.69 267.66,26.29 280.36,26.29 281.1,25.55 283.36,25.55 v1(283.56,25.75)
  BOTTOM w0.076: v1(172.41,111.94) 172.2,111.74 171.66,111.74 171.49,111.56 171.49,109.72 171.45,109.67 171.33,109.67 171.25,109.6 171.25,109.37 171.33,109.29 171.46,109.29 UC1.BT3
PCIE_PTX_DRX_P9: length 115.2
  TOP w0.097: CL5.1 264.7,107.82 264.7,107.67 264.61,107.57 264.27,107.57 263.89,107.96 263.89,113.6 264.28,114 v1(264.64,114)
  IN1 w0.089: v1(171.24,116.25) 171.51,116.52 172.17,116.52 172.78,117.13 174.3,117.13 174.71,117.53 178.29,119.02 181.88,120.5 186.4,120.5 187.27,121.37 189.25,121.37 189.7,120.92 224.15,120.92 228.02,117.05 241.51,117.05 242.26,116.31 248.16,116.31 249.05,117.2 255.55,117.2 257.83,114.92 258.27,114.92 258.5,114.7 261.73,114.7 262.66,113.77 263.33,113.77 263.48,113.62 263.96,113.62 264.34,114 v1(264.64,114)
  BOTTOM w0.076: UC1.BR1 171.08,110.37 171.15,110.53 171.15,110.64 170.99,110.8 170.99,111.09 171.15,111.25 171.15,111.48 170.99,111.64 170.99,111.82 171.15,111.99 171.15,112.21 170.95,112.42 170.95,112.61 171.15,112.82 171.15,113.01 171.03,113.13 171.03,113.45 171.23,113.65 171.23,113.87 171.31,113.94 171.52,113.94 171.66,114.08 171.66,116.48 171.53,116.61 171.47,116.61 171.24,116.38 v1(171.24,116.25)
PCIE_PTX_DRX_P10: length 200.6
  IN1 w0.089: v1(266.07,35.06) 266,35.14 266,35.32 266.31,35.63 268.51,35.63 269.42,36.54 273.27,36.54 274.06,37.33 274.06,48.54 273.47,49.13 273.47,53.65 275.12,55.3 275.12,62.52 277.99,65.39 277.99,68.02 280.5,70.54 282.99,70.54 285.27,72.82 285.27,75.24 283.65,76.86 280.16,76.86 277.23,79.79 277.23,82.18 276.4,83.02 276.4,84.55 272.56,88.39 272.56,89.08 271.65,89.99 271.65,89.99 271.61,90.03 271.61,91.88 271.18,92.31 271.18,94.73 269.75,96.16 269.75,100.39 265.96,104.18 265.96,105.71 264.78,106.88 263.12,106.88 261.4,108.6 260.54,108.6 258.42,110.72 257.04,110.72 256.68,111.09 248.08,111.09 247.6,111.56 236.89,111.56 236.63,111.3 224.51,111.3 212.48,116.36 197.86,116.36 197.68,116.17 191.61,116.17 189.77,115.41 187.54,113.18 177.49,113.18 176.49,112.18 175.29,112.18 174.63,112.84 172.01,112.84 171.77,112.6 v1(170.3,112.6)
  BOTTOM w0.076: v1(170.3,112.6) 170.51,112.39 170.64,112.39 170.83,112.21 170.83,110.61 170.68,110.46 170.68,110.22 170.72,110.13 170.72,109.85 170.68,109.76 170.68,109.57 170.79,109.32 171.04,109.32 171.05,109.31 171.05,109.31 171.15,109.22 171.15,109.09 171.07,109.01 UC1.BR3
  BOTTOM w0.097: CZ12.1 265.89,34.74 265.89,34.88 v1(266.07,35.06)
PCIE_PTX_DRX_P12: length 146.3
  IN3 w0.089: v1(255.9,68.6) 255.68,68.82 255.53,68.82 250.42,73.93 249.15,73.93 248.52,74.55 242.52,74.55 237.87,79.2 236.34,79.2 234.95,80.59 234.95,81.36 231.72,84.6 231.72,89.12 231.16,89.68 231.16,91.76 228.58,94.34 228.58,98.2 227.7,99.08 227.7,103.97 225.28,106.39 225.28,108.27 216.03,117.53 201.99,117.53 198.5,121.02 190.09,121.02 189.69,121.41 185.74,121.41 184.99,120.67 178.66,120.67 178.26,120.26 173.26,120.26 172.21,119.21 170.38,119.21 169.2,118.03 169.2,116.87 169.57,116.5 170.27,116.5 170.72,116.05 170.72,115.59 170.53,115.39 170.29,115.39 v1(169.99,115.1)
  BOTTOM w0.076: v1(169.99,115.1) 170.29,115.1 170.38,115.19 170.38,115.42 170.29,115.52 169.62,115.52 169.54,115.44 169.54,110.4 UC1.BN1
  BOTTOM w0.097: CZ11.1 267.77,68.15 266.88,67.25 266.28,67.25 265.96,66.94 258.9,66.94 256.83,69 256.3,69 v1(255.9,68.6)
PCIE_PTX_DRX_P13: length 191.6
  TOP w0.097: v1(279.79,30.44) 280.09,30.13 280.09,29.42 CN66.2
  IN3 w0.089: v1(170.4,117.49) 170.09,117.18 170,117.18 169.87,117.31 169.87,117.89 170.62,118.64 172.45,118.64 173.5,119.69 178.73,119.69 179.14,120.09 185.23,120.09 185.94,120.8 189.38,120.8 189.73,120.44 198.26,120.44 201.75,116.95 215.79,116.95 224.71,108.03 224.71,102.95 227.12,100.54 227.12,97.66 227.28,97.5 227.28,94.82 230.59,91.52 230.59,89.44 231.14,88.88 231.14,84.36 234.32,81.18 234.32,80.41 236.1,78.63 237.63,78.63 242.28,73.98 248.28,73.98 248.91,73.35 250.18,73.35 256.65,66.88 256.65,62.68 257.75,61.58 257.75,58.17 260.29,55.63 260.29,54.93 266.54,48.68 266.54,46.48 267.01,46.01 267.01,44.84 267.91,43.94 267.91,43.03 268.69,42.26 268.69,36.37 267.86,35.54 267.86,30.07 269.05,28.88 273.42,28.88 274.06,29.52 274.06,30.74 274.57,31.25 280.1,31.25 280.42,30.92 280.42,30.77 280.2,30.55 280.2,30.28 280.11,30.19 279.88,30.19 279.79,30.28 v1(279.79,30.44)
  BOTTOM w0.076: v1(170.4,117.49) 170.21,117.49 170.09,117.36 170.09,117.14 170.01,117.07 169.22,117.07 168.98,116.83 168.98,109.82 168.83,109.66 168.83,109.41 168.95,109.29 169.02,109.29 UC1.BM3
PCIE_PTX_DRX_P14: length 189
  TOP w0.097: CN68.2 276.94,29.7 276.94,30.4 275.83,31.51 273.6,31.51 272.8,32.31 272.36,32.31 v1(271.96,31.91)
  IN3 w0.089: v1(168.62,113.33) 168.51,113.43 168.34,113.43 168.23,113.33 168.23,113.01 168.14,112.92 167.42,112.92 166.98,113.37 166.98,118.24 168.55,119.82 168.55,120.83 169.11,121.38 170.15,121.38 170.62,121.85 170.62,122.34 170.79,122.5 173.16,122.5 173.68,121.99 177.54,121.99 177.97,122.41 184.3,122.41 185.43,123.55 187.79,123.55 188.16,123.18 191.88,123.18 192.32,122.74 199.21,122.74 202.18,119.77 216.22,119.77 230.39,105.6 230.39,103.69 230.98,103.1 230.98,95.3 232.88,93.4 232.88,90.39 233.44,89.84 233.44,85.38 237.89,80.93 238.58,80.93 243.23,76.28 249.24,76.28 249.45,76.06 250.72,76.06 251.27,75.51 252.05,75.51 255.87,71.7 256.5,71.7 258.37,69.83 258.37,63.39 259.47,62.3 259.47,58.89 269.35,49.01 269.35,47.7 268.93,47.29 268.93,45.97 270.41,44.49 270.41,40.35 270.93,39.84 270.93,37.94 271.27,37.6 271.27,32.51 271.46,32.32 271.56,32.32 v1(271.96,31.91)
  BOTTOM w0.076: v1(168.62,113.33) 168.25,112.95 168.25,112.61 168.32,112.53 168.32,112.11 168.6,111.83 168.6,110.94 168.6,110.41 UC1.BL1
PCIE_PTX_DRX_P15: length 189.7
  TOP w0.097: CN70.2 273.35,29.54 273.35,29.54 273.12,29.78 273.12,29.9 273.12,29.94 v1(272.9,30.17)
  IN3 w0.089: v1(168.62,114.49) 168.07,114.49 167.91,114.65 167.91,115.01 167.38,115.54 167.38,118.09 168.99,119.7 168.99,120.61 169.35,120.96 171.57,120.96 172.26,121.66 172.53,121.66 172.6,121.59 177.71,121.59 178.13,122.01 184.46,122.01 185.6,123.15 187.19,123.15 187.55,122.79 191.71,122.79 192.16,122.34 199.05,122.34 202.54,118.86 216.58,118.86 230,105.44 230,103.53 230.59,102.94 230.59,95.13 232.49,93.23 232.49,90.23 233.04,89.67 233.04,85.21 237.73,80.53 238.42,80.53 243.07,75.88 249.07,75.88 249.7,75.26 250.97,75.26 255.03,71.19 256.45,71.19 257.98,69.66 257.98,63.23 259.08,62.13 259.08,58.73 268.96,48.84 268.96,47.87 268.54,47.45 268.54,45.8 270.01,44.33 270.01,40.19 270.53,39.67 270.53,37.64 270.87,37.3 270.87,32.92 268.8,30.85 268.8,30.19 269.36,29.64 272.87,29.64 272.96,29.73 272.96,30.11 v1(272.9,30.17)
  BOTTOM w0.076: v1(168.62,114.49) 168.4,114.72 168.16,114.72 168.08,114.64 168.08,111.89 168.44,111.53 168.44,110.67 168.24,110.47 168.24,110.22 168.27,110.13 168.27,109.85 168.24,109.76 168.24,109.57 168.3,109.44 168.38,109.35 168.61,109.35 168.79,109.17 168.79,108.84 168.71,108.76 168.56,108.76 168.5,108.82 UC1.BL3
PCIE_PTX_DRX_P16: length 183.7
  TOP w0.097: v1(269.67,32.72) 269.84,32.9 270.06,32.9 270.24,32.71 270.24,32.58 268.54,30.87 268.54,29.94 268.74,29.73 269.82,29.73 269.92,29.64 269.92,29.54 CN72.2
  IN3 w0.089: v1(269.67,32.72) 269.84,32.72 269.98,32.87 269.98,33.05 269.83,33.2 269.83,33.47 269.6,33.7 269.6,34.54 269.93,34.87 269.93,36.65 269.26,37.32 269.26,43.99 268.91,44.34 268.32,44.34 267.59,45.08 267.59,47.57 268.2,48.18 268.2,48.53 258.32,58.41 258.32,61.82 257.22,62.92 257.22,69.34 256.16,70.4 254.75,70.4 250.65,74.5 249.38,74.5 248.76,75.13 242.76,75.13 238.1,79.78 236.58,79.78 235.53,80.83 235.53,81.6 232.29,84.83 232.29,89.36 231.73,89.91 231.73,92 229.16,94.58 229.16,103.87 227.45,105.58 227.45,106.92 216.27,118.1 202.22,118.1 198.73,121.59 191.85,121.59 191.85,121.59 190.33,121.59 189.93,121.99 185.5,121.99 184.76,121.24 178.42,121.24 178.02,120.84 173.02,120.84 171.97,119.79 170.14,119.79 168.13,117.78 168.13,116.68 168.22,116.59 168.42,116.59 168.62,116.79 v1(168.62,116.83)
  BOTTOM w0.076: UC1.BJ3 167.24,109.02 167.33,109.1 167.37,109.28 167.39,109.3 167.46,109.66 167.45,109.78 167.43,109.84 167.42,109.85 167.41,109.89 167.41,109.9 167.4,109.92 167.4,110.04 167.41,110.08 167.42,110.09 167.43,110.15 167.45,110.21 167.45,110.47 166.97,110.96 166.97,113.29 166.86,113.4 166.86,115.24 168.03,116.41 168.16,116.41 168.23,116.49 168.23,116.81 168.31,116.89 168.56,116.89 v1(168.62,116.83)
PCIE_RCOMPN: length 10.5
  TOP w0.102: v1(177.62,107.19) 177.2,107.6 177.2,108.1 177.03,108.28 177.03,109.48 177.99,110.44 177.99,110.68 178.1,110.8 178.1,111.11 177.79,111.43 177.79,111.6
  TOP w0.381: RC50.1 178.48,115.85 178.48,114.23 177.86,113.61 v2(177.79,113.54) 177.79,111.6
  BOTTOM w0.2: v1(177.62,107.19) UC1.CE6
PCIE_RCOMPP: length 9.7
  TOP w0.102: v1(177.62,107.84) 177.62,108.13 177.23,108.52 177.23,109.39 178.24,110.4 178.24,110.64 178.31,110.71 178.31,111.15 178.47,111.31 178.47,111.6
  TOP w0.381: RC50.2 179.17,115.88 v2(179.17,114.59) 179.17,113.95 178.47,113.25 178.47,111.6
  BOTTOM w0.2: v1(177.62,107.84) UC1.CE5
PCIE_WAKE#: length 160.8
  TOP w0.089: v1(255.67,87.58) 255.96,87.87 RE274.1
  TOP w0.107: v1(256.68,104.62) 256.68,105.09 256.22,105.55 RE275.1 ; UZ51.1 v1(281.29,77.48)
  IN1 w0.089: 260.83,91.83 260.83,89.58 259.27,88.02 256.11,88.02 v1(255.67,87.58)
  IN1 w0.099: v1(294.61,28.08) 289.43,28.08 286.63,25.28 284.25,25.28 283.4,24.44 282.55,24.44 281.51,23.4 270.42,23.4 v1(269.58,22.55) ; v1(256.68,104.62) 257.01,104.62 260.54,101.09 260.54,100.21 261.93,98.83 261.93,95.66 262.21,95.38 262.21,94.41 260.83,93.02 260.83,91.83
  IN3 w0.089: v1(255.67,87.58) 256.26,86.98 258.99,86.98 260.15,88.15 260.83,88.15
  IN3 w0.102: v1(294.61,28.08) 293.4,29.28 292.66,29.28 287.29,34.66 286.53,34.66 286.51,34.68 v1(285.88,34.68) 285.86,34.7 285.86,36.4 286.06,36.6 286.06,38.55 286.19,38.68 286.19,45.33 283.95,47.57 283.95,48.02 283.83,48.14 280.66,48.14 277.82,50.98 277.82,51.92 276.54,53.21 276.54,54.08 273.01,57.61 273.01,64.15 274.63,65.78 274.63,71.89 275.69,72.95 279.69,72.95 281.29,74.55 v1(281.29,77.48) 282.61,78.79 282.61,83.29 279.23,86.66 272.66,86.66 272.45,86.45 268.03,86.45 267.36,87.11 265.58,87.11 265.11,87.58 262.5,87.58 261.93,88.15 260.83,88.15
  BOTTOM w0.107: JNGFF3.54 v1(269.58,22.55) ; JNGFF1.55 286.2,34.34 285.88,34.67 v1(285.88,34.68)
PCIE_WAKE#_R: length 5
  TOP w0.107: UE1.N13 256.83,101.39 256.83,102.44 v2(256.22,103.05) 255.85,103.41 RE275.2 RE35.1
PD1_GPIO2: length 5.6
  TOP w0.107: v1(65.21,104.21) v2(64.4,103.4) 63.94,102.94 RT71.1
  BOTTOM w0.076: UT5.D10 62.58,103.56 63.1,103.56 63.15,103.61 63.99,103.61
  BOTTOM w0.107: 63.99,103.61 64.6,103.61 v1(65.21,104.21)
PD1_GPIO6: length 8.8
  BOTTOM w0.076: UT5.G10 62.58,105.06 63.38,105.06 63.83,105.51 64.5,105.51 64.55,105.46 64.57,105.46
  BOTTOM w0.107: 64.57,105.46 65.05,105.46 65.39,105.8 65.39,107.44 66.13,108.19 RT75.1 66.43,108.19 66.89,107.73 68.11,107.73 v2(68.44,108.05)
PD1_GPIO7: length 2.1
  TOP w0.107: RT339.1 60.57,103.33 v1(60.57,102.83) 60.78,102.62 v2(60.78,102.31)
  BOTTOM w0.076: UT5.D7 60.57,103.05 v1(60.57,102.83)
PD1_GPIO8: length 4.1
  TOP w0.107: v1(60.11,105.78) 60.09,105.8 60.09,106.4 RT377.1 59.96,106.92 v2(59.21,107.67) 59.02,107.86 RT76.1
  BOTTOM w0.076: UT5.H6 60.11,105.52 v1(60.11,105.78)
PD#: length 9.9
  TOP w0.203: UA1.40 282.66,51.74 282.49,51.57 282.49,51.38
  TOP w0.254: RA18.1 RA48.2 ; RA18.1 280.09,45.93 CA31.1 280.09,47.91 280.7,48.51 280.7,48.88 v2(281.39,49.56) 282.49,50.66 282.49,51.38 ; RA18.1 280.08,44.94 DA8.2 281.03,44.9
PECI_EC: length 150.5
  TOP w0.102: v1(155.09,110.91) 154.79,111.22 v2(154.31,111.22) 152.63,111.22 152.39,111.46 152.39,111.6
  TOP w0.107: v1(250.25,109.16) 250.25,106.99 251.65,105.59 RE60.2 ; 152.39,111.6 152.39,117.13 151.06,118.45 151.06,120.64 v1(151.51,121.08)
  BOTTOM w0.076: UC1.AR1 158.34,109.91 158.34,109.84 158.19,109.69 158.06,109.69 157.98,109.61 157.78,109.61 157.53,109.37 157.29,109.37 156.97,109.04 156.68,109.04 156.36,109.36 156.01,109.36 155.76,109.61 155.49,109.61 155.24,109.87 155.24,110.77 v1(155.09,110.91)
  BOTTOM w0.107: v1(151.51,121.08) 151.57,121.14 151.57,121.55 151.82,121.81 151.82,124.53 151.13,125.23 150.59,125.23 148.59,127.24 148.59,131.93 149.92,133.26 154.29,133.26 156.84,130.71 156.84,128.34 157.35,127.84 159.76,127.84 161.33,126.27 165.48,126.27 166.93,124.83 177.28,124.83 179.83,122.28 186.09,122.28 187.52,120.84 189.64,120.84 190.26,120.22 191.23,120.22 191.87,119.59 198.68,119.59 199.32,118.94 202.2,118.94 202.34,118.81 206.88,118.81 207.35,118.33 208.65,118.33 211.27,115.72 224.89,115.72 231.81,108.8 239.5,108.8 241.05,110.35 249.07,110.35 v1(250.25,109.16)
PECI_EC_R: length 5.1
  TOP w0.107: RE60.1 251.65,104.24 252.55,103.34 253.29,103.34 v2(253.54,103.08) 253.54,102.6 254.05,102.09 UE1.K13
PGOOD_3V: length 5
  BOTTOM w0.107: 200.92,35.63 200.57,35.28 199.64,35.28 199.09,35.82 v2(198.97,35.82)
  BOTTOM w0.254: PU100.9 201.64,34.65 201.48,34.81 PR107.2 PR119.1
PGOOD_5V: length 157.2
  TOP w0.107: v1(96.93,51.76) 97.25,51.76 102.8,46.22 125.21,46.22 125.51,45.92 125.51,45.48 128.98,42.01 140.45,42.01 144.32,38.13 152.51,38.13 154.96,40.58 165.27,40.58 175.02,30.82 v2(191.08,30.82) 191.93,30.82 198.34,37.23 v1(201.04,37.23)
  IN1 w0.099: v1(96.93,51.76) 96.93,51.94 97.17,52.17 97.17,55.05 96.74,55.48 82.04,55.48 79.76,57.76 79.76,60.25 76.38,63.63 76.38,64.65 76.76,65.02 76.76,68.65 v1(77.91,69.8)
  BOTTOM w0.254: PU102.9 78.86,69.29 78.6,69.04 PR113.2 78.24,69.47 v1(77.91,69.8) ; v1(201.04,37.23) 200.92,37.1 PR120.1
PLTRST_LAN#: length 84.4
  TOP w0.107: RC739.2 222.72,78.52 223.87,79.68 v2(225.23,79.68) 226.36,79.68 v1(226.51,79.52) ; UL1.36 v1(269.66,111.52)
  IN2 w0.102: v1(239.91,81.33) 239.91,82.04 239.23,82.72 239.23,83.83 238.22,84.85 238.22,86.31 238.79,86.88 238.79,89.36 239.05,89.61 v1(239.41,89.61)
  IN3 w0.102: v1(269.66,111.52) 267.51,111.52 265.82,109.82 264.13,109.82 263.68,110.28 260.82,110.28 258.56,112.54 248.38,112.54 243.56,107.72 243.56,107.2 242.79,106.44 239.64,106.44 238.42,105.22 238.42,102.19 239.23,101.39 239.23,99.77 238.26,98.8 238.26,96.09 238.57,95.78 238.57,93.22 239.41,92.38 v1(239.41,89.61)
  BOTTOM w0.107: v1(226.51,79.52) 226.72,79.73 226.72,79.74 228.19,81.2 231.11,81.2 233.26,83.36 236.3,83.36 237.56,82.09 239.16,82.09 v1(239.91,81.33)
PLTRST_TPM#: length 45.5
  TOP w0.107: RC60.2 RC738.2 219.16,76.7 216.87,74.4 213.83,74.4 v2(213.39,74.84) 212.97,75.26 212.97,77.48 213.74,78.24 214.63,78.24 215.07,78.69 215.07,80.59 213.36,82.3 213.36,87.05 217.28,90.97 v1(220.72,90.97) ; UZ12.17 221.87,102.11 v1(221.55,102.44)
  BOTTOM w0.107: v1(221.55,102.44) 221.8,102.44 222.94,101.29 222.94,95.08 221.14,93.28 221.14,91.21 220.9,90.97 v1(220.72,90.97)
PM_LANPHY_ENABLE: length 134.3
  TOP w0.107: v1(264.68,102.36) 264.73,102.31 RL7.1
  IN1 w0.089: v1(173.4,83.2) 173.4,83.11 173.94,82.58 176.25,82.58 178.04,80.79 178.04,80.68
  IN1 w0.099: v1(221.21,69.37) 221.1,69.48 199.47,69.48 195.88,73.08 195.88,74.47 195.58,74.77 188.31,74.77 187.43,75.66 183.15,75.66 181.63,77.18 180.92,77.18 178.04,80.06 178.04,80.68
  BOTTOM w0.076: v1(173.4,83.2) 173.34,83.2 172.84,83.69 172.84,84.77 172.57,85.05 172.57,86.55 172.53,86.58 172.53,87.35 172.71,87.54 172.71,87.8 172.68,87.89 172.68,88.13 172.72,88.24 172.72,89.37 UC1.BU34
  BOTTOM w0.107: v1(221.21,69.37) 221.61,68.97 221.93,68.97 223.22,70.27 223.72,70.27 227.13,73.67 227.58,73.67 228.4,74.49 232.68,74.49 233.42,75.23 245.74,75.23 246.22,74.75 250.74,74.75 251.07,75.09 251.41,75.09 252.45,76.12 v2(252.45,76.36) 252.45,81.74 252.57,81.86 253.58,81.86 253.84,82.12 254.74,82.12 256.95,84.33 262.48,84.33 264.17,86.02 264.17,87.3 266.23,89.36 266.23,93.8 265.21,94.82 265.21,99.35 264.71,99.85 264.71,100.51 264.6,100.63 264.6,102.28 v1(264.68,102.36)
PME#: length 2.9
  TOP w0.089: T12.1 175.13,92.15 175.2,92.08 175.2,90.95 175.58,90.57 v1(175.58,90.46)
  BOTTOM w0.089: UC1.CA32 175.57,90.46 v1(175.58,90.46)
POWER_SW#_MB: length 177.3
  TOP w0.107: SW3.4 311.04,120.05 v1(311.25,120.25) 313.13,120.25 313.33,120.05 SW3.2 ; v1(238.92,40.21) 238.92,40.36 v2(239.38,40.82)
  TOP w0.127: RZ1414.1 238.92,39.67 v1(238.92,40.21)
  IN1 w0.127: v1(238.92,40.21) 239.03,40.32 240.08,40.32 240.64,40.88 242.08,40.88 244.7,43.5 245.42,43.5 245.65,43.73 245.65,44.31 246.85,45.5 247.88,45.5 248.01,45.63 248.01,56.51 246.44,58.08 246.44,64.15 246.36,64.22 246.36,70.5 240.9,75.96 240.9,78.89 240.33,79.46 v1(240.33,80.92)
  IN2 w0.127: v1(240.2,93.4) 238.3,91.5 238.3,87.09 237.72,86.51 237.72,84.42 238.74,83.4 238.74,82.51 239.42,81.83 239.42,81.13 239.63,80.92 v1(240.33,80.92)
  IN3 w0.127: v1(240.2,93.4) 239.5,94.09 239.5,96.25 238.77,96.98 238.77,98.61 239.72,99.56 239.72,101.02 239.94,101.24 239.94,103.43 240.42,103.91 240.42,105.01 240.91,105.51 242.16,105.51 242.76,104.91 243.38,104.91 243.92,105.46 245.82,105.46 247.11,106.75 247.11,108.85 248.66,110.4 258.12,110.4 260.01,108.51 262.95,108.51 263.33,108.13 266.97,108.13 267.33,108.49 267.33,109.1 267.58,109.36 269.42,109.36 270.24,110.18 272.73,110.18 274,111.45 285.31,111.45 286.05,112.19 290.71,112.19 293.1,114.58 311.22,114.58 313.61,116.96 313.61,119.8 313.15,120.25 v1(311.25,120.25)
  BOTTOM w0.107: RE33.2 242.43,94.4 CE10.1 241.49,94.4 240.49,93.4 v1(240.2,93.4)
  BOTTOM w0.127: JAPS1.11 240.74,82.55 240.85,82.43 240.85,81.43 v1(240.33,80.92)
POWER_SW#_MB_USH: length 4.7
  TOP w0.107: RZ1414.2 237.67,39.57 v1(236.98,38.88) 236.98,40.18 v2(237.63,40.83)
  BOTTOM w0.107: v1(236.98,38.88) 236.77,39.08 JUSH1.26
POWER_SW_IN#: length 32.2
  TOP w0.102: UE1.D5 248.89,94.97 v1(248.89,95.02)
  TOP w0.127: QZ21.3 240.15,110.36 240.15,109.57 239.16,108.58 239.16,103.54 v2(239.19,103.52) 240.03,102.68 240.03,101.17 240.32,100.87 241.57,100.87 v1(241.77,101.06)
  IN3 w0.089: v1(248.89,95.02) 248.56,94.69 246.95,94.69 246.82,94.56 246.6,94.56
  IN3 w0.127: v1(241.77,101.06) 241.55,100.85 241.55,98.69 242.57,97.67 242.57,96.91 243.45,96.02 244.85,96.02 245.1,95.77 245.1,95.37 244.98,95.25 244.98,95.01 245.42,94.56 246.6,94.56
  BOTTOM w0.089: 243.49,94.35 RE33.1 RE31.2
  BOTTOM w0.107: 243.49,94.35 243.64,94.5 CE12.1 CE69.1
  BOTTOM w0.127: v1(248.89,95.02) 248.52,94.65 247.84,94.65 247.68,94.5 CE69.1
PRIM_CORE_OPT_DIS: length 27.1
  TOP w0.107: v1(196.29,94.34) v2(196.76,93.87) RC862.1 197.97,92.88 UC9.1 197.75,92.66 RC867.1
  IN1 w0.089: v1(176.59,94.37) 177.03,94.37 177.46,94.8 179.9,94.8 180.04,94.94 181.04,94.94 183.82,92.16 184.72,92.16 186.73,94.16 187.81,94.16
  IN1 w0.099: 187.81,94.16 194.93,94.16 195.23,93.86 195.81,93.86 v1(196.29,94.34)
  BOTTOM w0.076: UC1.CC27 176.02,93.93 176.46,94.37 v1(176.59,94.37)
PRIM_PWRGD: length 14.3
  TOP w0.107: v1(265.93,96.59) 265.79,96.73 RE361.1 265.49,97.23 265.36,97.1 CE68.1 ; v1(255.27,95.78) 255.2,95.85 255.2,95.86 UE1.L7
  IN3 w0.102: v1(255.27,95.78) 256.59,95.78 256.9,95.46 259.63,95.46 260.08,95.91 264.3,95.91 264.66,96.28 265.04,96.28 265.36,96.59 v1(265.93,96.59)
  BOTTOM w0.107: v2(266.34,97.22) 265.93,96.81 v1(265.93,96.59)
PRIVACY_ENABLE: length 206.3
  TOP w0.107: v1(128.22,133.27) 128.09,133.4 RV802.1 ; v1(238.9,102.46) 238.9,102.68 238.61,102.97 238.61,108.25 237.94,108.92 237.94,113.54 238.32,113.92 238.54,114.15 238.54,116.4 239.08,116.94 241.88,116.94 242.29,117.35 242.88,117.35 242.96,117.27 246.37,117.27 247.23,116.41 248.36,116.41 249.09,117.15 249.09,123.36 248.13,124.33 248.13,125.12 247.68,125.56 247.54,125.56 236.69,136.41 v1(232.91,136.41) ; UE1.F5 v1(250.45,94.21)
  IN3 w0.102: v1(146.75,136.34) 145.24,134.84 132.65,134.84 130.99,133.18 128.31,133.18 v1(128.22,133.27)
  BOTTOM w0.107: JEDP1.3 126.77,131.62 126.52,131.87 126.52,132.3 127.49,133.27 v1(128.22,133.27) ; v1(232.91,136.41) 232.37,136.41 231.74,135.78 214.95,135.78 214.35,135.17 214.01,135.17 213.58,135.61 210.46,135.61 209.89,135.03 208.36,135.03 207.62,135.78 187.31,135.78 186.31,136.78 166.08,136.78 164.07,134.77 164.07,132.69 163.27,131.89 157.84,131.89 154.04,135.69 151.52,135.69 150.87,136.34 v1(146.75,136.34) ; v1(250.45,94.21) 250.08,93.84 250.08,91.85 249.28,91.06 v2(249.28,90.22) 249.28,89.7 249.36,89.63 RE92.1 247.78,87.6 243.91,87.6 243.29,88.22 243.29,90.8 242.11,91.97 238.65,91.97 238.5,91.82 237.16,91.82 236.27,92.71 236.27,96.55 239.38,99.67 239.38,101.22 239.06,101.54 239.06,102.3 v1(238.9,102.46)
PROCHOT#: length 294.1
  TOP w0.107: v1(248.37,109.16) 248.98,108.56 248.98,107.45 248.75,107.22 248.75,106.68 248.98,106.45 RE288.2 ; v1(85.66,104.28) 85.53,104.15 85.03,104.15 84.92,104.04 84.92,102.61 PC605.2 85.61,102.69 PR678.1 ; PR745.1 82.37,51.88 82.37,53.93 v1(82.55,54.11) ; v1(146.91,117.06) 146.81,117.16 v2(146.81,118.88) 146.81,119.65 148.67,121.51 151.66,121.51 v1(152.11,121.07)
  IN1 w0.099: v1(146.91,117.06) 145.94,117.06 143.15,119.84 140.59,119.84 139.32,121.12 134.91,121.12 134.75,121.28 134.75,121.28 134.36,121.67 123.69,121.67 121.96,119.94 118.18,119.94 117.2,120.91 107.66,120.91 107.22,120.47 107.22,119.61 106.74,119.14 101.91,119.14 100.81,120.24 99.62,120.24 98.27,118.9 97.24,118.9 95.32,116.98 93.9,116.98 93.39,116.47 93.39,115.32 92.51,114.44 92.51,114.07 88.3,109.85 88.3,107.89 85.78,105.38 85.78,104.4 v1(85.66,104.28) 85.49,104.11 82.92,104.11 78.76,99.96 78.76,94.79 80.58,92.97 82.89,92.97 84.41,91.45 84.41,90.62 86.22,88.81 88.46,88.81 89.81,87.46 89.81,83.54 97.67,75.68 97.67,68.07 98.13,67.61 98.13,65.07 97.67,64.61 97.67,56.54 97.24,56.11 82.46,56.11 v1(82.41,56.17)
  IN3 w0.102: v1(78.8,48.56) 78.8,49.6 81.08,51.89 81.08,52.65 v1(82.55,54.11) 82.55,56.03 v1(82.41,56.17)
  BOTTOM w0.107: PR719.1 v1(78.8,48.56) ; v1(152.11,121.07) 152.13,121.07 152.4,121.33 152.4,124.28 153.05,124.93 154.51,124.93 156.37,126.79 157.01,126.79 157.49,127.27 159.53,127.27 161.09,125.71 165.25,125.71 166.75,124.21 177.1,124.21 179.7,121.62 185.34,121.62 185.77,121.19 186.38,121.19 187.58,119.99 189.63,119.99 189.96,119.66 191,119.66 191.63,119.02 198.44,119.02 199.09,118.38 201.97,118.38 202.11,118.24 206.64,118.24 207.12,117.77 208.42,117.77 211.03,115.15 224.57,115.15 231.9,107.82 239.33,107.82 241.29,109.78 247.75,109.78 v1(248.37,109.16) ; RC84.1 v1(146.91,117.06) 146.73,117.24 RC558.2
PROCHOT#_CHG: length 67.7
  TOP w0.107: v1(52.07,84.38) 51.55,84.89 PQ812.1
  IN1 w0.099: v1(80.97,48.57) 80.58,48.96 80.58,50.75 78.29,53.03 78.29,59.6 77.24,60.65 76.07,60.65 75.67,61.05 75.67,64.83 76.13,65.29 76.13,69.28 75.39,70.02 74.75,70.02 72.33,72.44 72.33,73.96 70.54,75.75 70.54,81.4 71.34,82.2 71.34,83.97 69.06,86.26 65.48,86.26 63.05,83.83 52.62,83.83 v1(52.07,84.38)
  BOTTOM w0.107: PU700.23 81.85,47.47 80.97,48.34 v1(80.97,48.57) PR719.2
PROCHOT#_R: length 8.1
  BOTTOM w0.076: RC84.2 147.29,115.14 147.58,115.14 148.35,114.37 v2(148.35,114.15) 148.35,112.77 148.91,112.21 148.91,110.94 149.23,110.62 149.23,109 UC1.Y4
PROCHOT#_R1: length 5.6
  TOP w0.107: RE288.1 249.41,104.21 249.51,104.21 249.51,104.21 250.29,104.21 v2(251,103.5) 252.45,102.06 UE1.H13
PROG1_CPU_CORE: length 3.9
  TOP w0.203: v1(93.49,100.4) 93.4,100.32 v2(92.29,100.32) 91.76,100.32 91.12,99.68 PU602.32
  BOTTOM w0.254: v1(93.49,100.4) 93.47,100.38 PR608.1
PROG2_CPU_CORE: length 3.3
  TOP w0.203: v1(93.49,99.59) 93.18,99.91 91.82,99.91 91.52,99.61 PU602.31
  BOTTOM w0.254: v1(93.49,99.59) 93.47,99.62 PR611.1
PROG_CHG: length 3.8
  TOP w0.107: v2(84.45,49.01) 83.74,49.72 v1(83.74,50.15)
  TOP w0.254: v1(83.74,50.15) 83.77,50.18 PR725.1
  BOTTOM w0.203: PU700.27 v1(83.74,50.15)
PROM_BIOS: length 3.2
  TOP w0.107: v2(264.67,93.28) 264.93,93.54 RZ400.2 RZ401.2 264.95,95.08 UZ41.1
PROM_BIOS_R: length 93.4
  TOP w0.107: RZ401.1 264.02,95.44 264.16,95.58 266.06,95.58 266.57,96.09 267.2,96.09 v2(267.33,96.21) 267.33,98.88 v1(266.89,99.32)
  IN1 w0.099: v1(222.05,79.31) 222.05,84.85 224.55,87.34 226.9,87.34 229.81,90.24 233.53,90.24 236.44,93.15 238.57,93.15 239.07,93.66 239.89,93.66 240.09,93.86 240.98,93.86 241.41,94.3 241.41,96.17 244.19,98.94 v1(244.58,98.94)
  IN2 w0.102: v1(222.05,79.31) 222.05,79.24 221.75,78.93 220.33,78.93 219.72,79.54 216.86,79.54 214.94,81.46 212.95,81.46 211.25,83.16 210.28,83.16 209.01,84.43 200.82,84.43 200.34,84.91 v1(200.34,85.29)
  IN3 w0.089: 256.76,96.81 256.24,96.81 255.86,96.43 246.94,96.43 246.6,96.77 246.6,96.92
  IN3 w0.102: v1(266.89,99.32) 266.75,99.18 262.59,99.18 261.81,98.4 261.81,97.21 261.47,96.88 256.83,96.88 256.76,96.81 ; 246.6,96.92 v1(244.58,98.94)
  BOTTOM w0.107: v1(200.34,85.29) 200.34,85.04 200.58,84.79 JSPI1.17
PS8802_ADDR: length 10.4
  TOP w0.107: v1(43.87,103.28) 44.66,104.06 v2(44.66,107.31) 44.66,110.22 RT136.1 RT135.1
  BOTTOM w0.107: v1(43.87,103.28) UT9.19
PS8802_CEQ: length 3.9
  BOTTOM w0.107: RT139.1 RT140.1 36.32,106.5 36.53,106.29 36.53,105.95 v2(36.95,105.52) 36.95,105.36 37.63,104.68 UT9.48
PS8802_CSCL: length 25.1
  TOP w0.107: QT10.1 52.78,110.82 52.61,110.65 52.61,109.46 52.38,109.22 49.29,109.22 48.39,108.33 48.39,102.02 44.31,97.95 42.44,97.95 42.1,98.3 42.1,98.48 v1(42.29,98.67)
  BOTTOM w0.107: RT305.1 42.09,97.89 42.09,98.47 v1(42.29,98.67) 42.08,98.88 42.08,99.04 41.57,99.55 41.57,99.62 41.61,99.66 UT9.28
PS8802_CSDA: length 26.2
  TOP w0.107: v1(41.7,98.67) 41.86,98.51 41.86,98.2 42.35,97.71 44.41,97.71 48.62,101.93 48.62,108.23 49.38,108.99 54.52,108.99 55.05,109.52 QT10.4
  BOTTOM w0.107: UT9.29 41.26,99.66 41.33,99.58 41.33,99.45 41.84,98.94 41.84,98.81 v1(41.7,98.67) 41.85,98.52 41.85,97.89 RT304.1
PS8802_DPEQ: length 10.6
  TOP w0.107: v1(43.79,102.23) 43.87,102.23 45.01,103.37 v2(45.01,105.93) 45.01,109.75 RT138.1 RT137.1
  BOTTOM w0.107: v1(43.79,102.23) UT9.22
PS8802_HPD: length 4.7
  BOTTOM w0.107: UT9.40 37.53,101.88 36.46,100.8 RT380.2 36.01,100.62 35.73,100.34 v2(34.16,100.34)
PS8802_REXT: length 5.4
  BOTTOM w0.107: v2(33.83,99.05) 34.2,99.42 35.55,99.42 RT300.1 36.57,100.44 36.57,100.58 37.52,101.53 UT9.39
PS8802_RST#: length 3.1
  BOTTOM w0.107: RT246.2 36.01,102.02 CT122.1 36.13,101.99 v2(36.97,102.83) 37.06,102.93 UT9.43
PS8802_SBU1_R: length 4
  BOTTOM w0.107: RT132.1 RT414.1 39.05,97.99 38.82,98.22 38.82,98.67 v2(38.84,98.68) 39.18,99.03 39.54,99.03 39.68,99.17 39.68,99.53 39.86,99.71 UT9.33
PS8802_SBU2_R: length 4.7
  BOTTOM w0.107: RT133.1 RT415.1 v2(37.52,98.77) 37.88,99.13 38.95,99.13 39.51,99.69 UT9.34
PS8802_SSEQ: length 2.9
  BOTTOM w0.107: UT9.46 37.32,103.98 37.08,104.21 v2(36.93,104.21) RT142.1 RT141.1
PS_ID: length 218.5
  TOP w0.107: UE1.J8 v1(253.65,97.41)
  TOP w0.254: PR5.2 79.94,126.2 v1(79.93,126.18) ; v1(87.75,125.72) 88.88,124.59 88.88,120.55 89.81,119.62 v2(90.06,119.62) 90.61,119.62 v1(90.75,119.76)
  IN2 w0.089: 253.08,99.69 253.08,98.53 253.3,98.31 253.3,97.8 253.65,97.45 v1(253.65,97.41)
  IN2 w0.102: 253.08,99.69 253.08,99.99 253.34,100.25 253.82,100.25 254.06,100.49 254.06,100.91 253.88,101.09 253.88,101.74 253.4,102.22 252.96,102.22 252.53,102.64 252.53,103.01 253.13,103.61 253.13,104.25 251.58,105.8 251.58,107.13 250.67,108.05 250.28,108.05 249.61,108.72 249.61,111.47 242.34,118.75 236.69,118.75 236.24,119.2 232.38,119.2 231.53,120.05 204.28,120.05 193.88,130.45 184.29,130.45 183.54,129.7 177.63,129.7 177.03,129.11 166.23,129.11 163.97,131.37 157.43,131.37 155.07,133.72 143.93,133.72 141.34,131.13 131.65,131.13 131.02,130.5 126.21,130.5 125.41,131.3 123.17,131.3 121.41,133.06 115.55,133.06 115.13,132.64 113.62,132.64 111.03,130.05 110.7,130.05 108.78,128.13 99.83,128.13 97.13,125.44 94.79,125.44 94.65,125.58 87.89,125.58 v1(87.75,125.72) 87.35,126.12 84.8,126.12 84.31,125.63 80.48,125.63 v1(79.93,126.18)
  IN3 w0.254: v1(90.75,119.76) 92.73,117.78 v1(92.73,117.18)
  BOTTOM w0.254: v1(92.73,117.18) 93.35,117.18 93.81,117.64 PR4.1
PSYS_CHG: length 4.4
  TOP w0.107: v2(87.6,50.84) PR731.1
  TOP w0.254: PR731.1 85.72,50.33 85.43,50.33 v1(85.25,50.15)
  BOTTOM w0.203: v1(85.25,50.15) 85.25,49.35 84.94,49.04 PU700.30
PSYS_CPU_CORE: length 3.8
  TOP w0.203: PU602.1 86.9,98.52 86.67,98.75 86.67,99.39 87.51,100.23 PR693.2 PR620.2
PWM1_B_IA: length 35.7
  TOP w0.203: PU602.12 88.32,93.68 87.9,93.27 v1(87.78,93.27)
  IN1 w0.254: v1(119.5,96.2) 119.5,96.54 118.98,97.05 97.1,97.05 94.74,94.69 91.56,94.69 91.06,94.18 88.69,94.18 v1(87.78,93.27)
  BOTTOM w0.254: PR687.1 v1(119.5,96.2)
PWM1_IA: length 4.8
  BOTTOM w0.107: PR687.2 119.83,97.74 120.05,97.52 v2(120.05,95.87)
  BOTTOM w0.254: PU610.1 117.92,99.01 118.18,98.76 118.81,98.76 119.5,98.07 PR687.2
PWM2_B_IA: length 27.8
  TOP w0.203: v1(88.55,93.26) 88.72,93.44 PU602.13
  IN3 w0.254: v1(105.52,101.15) 105.05,100.68 99.54,100.68 97.58,102.64 92.49,102.64 91.04,101.19 90.46,101.19 87.71,98.45 87.71,94.09 v1(88.55,93.26)
  BOTTOM w0.254: PR692.1 v1(105.52,101.15)
PWM2_IA: length 3.6
  BOTTOM w0.107: PR692.2 v2(106.6,102.69)
  BOTTOM w0.254: PU613.1 103.94,103.96 104.2,103.71 104.83,103.71 105.52,103.02 PR692.2
PWM_A_GT: length 15.3
  TOP w0.203: PU602.22 92.71,95.32 93.59,94.44 v2(93.59,93.93) v1(93.59,93.32)
  IN1 w0.254: v1(93.59,93.32) 93.59,91.89 100.75,84.72 v1(101.02,84.72)
  BOTTOM w0.254: PR664.1 v1(101.02,84.72)
PWM_C_SA: length 118.8
  TOP w0.203: v1(93.85,98.37) 93.34,98.88 92.96,98.88 92.6,98.52 PU602.30 ; v1(93.02,103.53) 90.79,105.76 v2(90.79,106.65) 90.79,111.57 94.11,114.88 v1(94.11,115.34) ; PR606.2 180.2,127.71 172.89,127.71 172.5,127.32 165.95,127.32 163.86,125.23 163.86,123.52 v1(164.38,123)
  TOP w0.254: v1(113.87,122.73) 101.81,122.73 97.19,118.11 97.19,117.28 96.94,117.02 96.55,117.02 v1(96.44,117.12)
  IN2 w0.203: v1(93.85,98.37) 94.8,99.32 94.8,101.75 v1(93.02,103.53) ; v1(164.38,123) 162.04,123 161.47,123.57 157.95,123.57 157.07,122.69 147.03,122.69 146.94,122.78 135.25,122.78 134.93,123.1 132.1,123.1 131.12,124.08 123.05,124.08 122.31,123.34 114.49,123.34 v1(113.87,122.73)
  IN2 w0.254: v1(94.11,115.34) 94.66,115.34 v1(96.44,117.12)
PWM_FAN1: length 320.7
  TOP w0.107: UE1.L10 v1(255.2,98.97)
  TOP w0.254: v1(80.39,60.56) 81.03,60.56 81.22,60.38 DE22.2 v1(80.39,59.97)
  IN2 w0.089: v1(255.2,98.97) 255.62,98.55 255.62,98.06 256.13,97.55 256.76,97.55
  IN2 w0.102: 256.76,97.55 256.79,97.55 258.6,95.74 259.55,95.74 260.6,94.69 260.6,90.45 262.67,88.38 262.67,83.45 263.89,82.24 263.89,78.05 263.13,77.29 263.13,71.64 264.26,70.52 264.26,68.55 263.6,67.89 263.6,64.58 265.49,62.68 265.49,59.23 265.12,58.86 265.12,50.39 266.04,49.47 266.04,44.48 264.96,43.4 264.96,36.9 260.16,32.1 257.66,32.1 255.95,30.4 240.22,30.4 238.44,32.17 236.83,32.17 234.95,30.28 232.16,30.28 231.85,30.6 225.14,30.6 222.98,32.75 222.98,32.94 222.98,32.94 222.98,34.72 222.32,35.38 222.32,35.75 221.74,36.33 216.16,36.33 215.38,37.12 207.65,37.12 205.39,34.86 202.59,34.86 202.47,34.73 199.57,34.73 199.1,34.27 199.1,34.08 197.63,32.61 196.6,32.61 193.69,29.7 171.77,29.7 161.92,39.55 146.39,39.55 142.45,35.61 135.03,35.61 129.12,29.7 96.94,29.7 92.99,33.64 87.42,33.64 82.44,38.62 73.17,38.62 v1(71.75,40.04)
  BOTTOM w0.254: v1(71.75,40.04) 71.23,40.56 71.23,44.26 71.68,44.71 71.68,44.96 arc(71.76,45.34) 71.97,45.66 72.14,45.83 72.14,55.8 72.8,56.46 RE48.2 74.01,56.46 74.38,56.83 78.18,56.83 79.76,58.42 79.76,59.34 v1(80.39,59.97) ; JFAN1.2 78.37,62.58 v1(80.39,60.56)
PWM_GT: length 3.6
  BOTTOM w0.107: PR664.2 v2(102.56,83.67)
  BOTTOM w0.254: PU612.1 103.82,86.3 103.57,86.04 103.57,85.41 102.88,84.72 PR664.2
PWM_SA: length 2.6
  TOP w0.254: PU614.3 182.64,130.9 182.56,130.82 182.56,130.07 v2(182.28,129.8) PR606.1
REFCLK_CNV: length 15.2
  BOTTOM w0.076: 183.69,111.33 182.17,111.33 181.57,110.73 181.57,110.7 181.4,110.53 181.4,110.19 181.11,109.9 181.11,109.53 UC1.CM3
  BOTTOM w0.107: LC5.1 CC1477.1 184.67,119.19 v2(185.03,118.82) 185.6,118.26 185.6,117.22 186.09,116.72 186.09,116.14 185.94,115.99 185.94,115.9 RC751.2 185.73,115.19 185.73,113.37 183.69,111.33
REFCLK_CNV_L: length 177.8
  TOP w0.107: v1(288.29,45.4) 288.29,44.16 287.9,43.77 287.9,42.83 v1(287.95,42.79) 288.01,42.73 v2(288.72,42.73) RZ752.1
  IN1 w0.099: v1(262.89,53.16) 262.03,54.01 262.03,59.66 261.18,60.51 261.18,64.56 261.41,64.79 261.41,67.88 261,68.29 261,72.56 261.72,73.28 261.72,76.35 264.23,78.86 264.23,81.6 266.72,84.08 266.72,93.12 264.88,94.97 264.66,95.18 264.66,99.33 264.35,99.64 264.35,100.34 264.13,100.56 263.04,100.56 262.04,101.56 262.04,102.11 259.47,104.67 259.14,104.67 v1(257.35,106.47)
  BOTTOM w0.107: v1(287.95,42.79) 288.45,42.29 JNGFF1.64 ; v1(288.29,45.4) 287.47,45.4 285.13,47.74 279.81,47.74 278.03,49.51 270.28,49.51 266.63,53.16 v1(262.89,53.16) ; v1(257.35,106.47) 257.35,107.4 255.86,108.88 255.86,109.9 255.26,110.5 252.77,110.5 252,109.73 252,109.05 251,108.05 244.24,108.05 242.83,106.64 230.8,106.64 223.34,114.09 210.78,114.09 208.24,116.63 206.51,116.63 205.91,117.23 201.74,117.23 201.42,117.56 198.41,117.56 197.77,118.2 191.29,118.2 190.66,118.84 189.62,118.84 189.29,119.17 187.08,119.17 LC5.2
REM_DIODE1_N: length 125.7
  TOP w0.102: QE3.3 149.86,94.88 149.65,95.08 148.99,95.08 CE35.1 148.2,95.18 148.2,95.78 147.86,96.12 147.86,96.46 v1(147.63,96.68)
  TOP w0.127: UE1.A8 246.68,96.85 246.15,96.85 245.71,96.4 244.29,96.4 CE24.1 243.76,96.4 241.74,96.4 241.26,95.92 239.14,95.92 v1(238.97,96.09)
  IN1 w0.089: 187.52,81.06 185.45,83.13 184.92,83.13 181.69,86.37 180.07,86.37 180,86.29 178.58,86.29 178.4,86.12 178.19,86.12 v1(178.17,86.14)
  IN1 w0.127: 187.52,81.06 188.12,80.46 194.62,80.46 194.9,80.19 197.73,80.19 198.9,79.01 200.07,79.01 200.36,78.73 203.99,78.73 206.64,81.38 208.07,81.38 209.48,82.79 209.48,84.76 213.05,88.33 213.58,88.33 213.74,88.48 219.01,88.48 220.41,89.88 225.78,89.88 228.81,92.91 233.1,92.91 235.54,95.34 237.66,95.34 238.21,95.9 238.78,95.9 v1(238.97,96.09)
  IN3 w0.089: v1(178.17,86.14) 178.39,86.14 178.53,86.28 178.53,86.4 177.15,87.78 176.45,87.78 174.73,89.5 174.73,89.51 174.52,89.72 174.51,89.72 174.48,89.75 170.04,89.75 169.3,90.49 169.3,96.01 167.64,97.67 152.4,97.67 150.69,95.97 148.05,95.97 147.84,96.18 147.84,96.48 v1(147.63,96.68)
REM_DIODE1_P: length 127.1
  TOP w0.102: QE3.1 151.11,95.85 QE3.2 149.86,95.52 149.65,95.31 148.99,95.31 CE35.2 148.09,96.22 148.09,96.55 v1(148.22,96.68)
  TOP w0.127: v1(238.97,95.5) 239.14,95.67 241.37,95.67 241.85,96.15 243.63,96.15 CE24.2 244.29,96.02 245.87,96.02 246.31,96.47 246.59,96.47 UE1.A7
  IN1 w0.089: v1(178.58,85.73) 178.53,85.78 178.53,85.99 178.65,86.12 180.07,86.12 180.14,86.19 181.61,86.19 184.85,82.95 185.38,82.95 187.33,81.01 187.33,80.98 187.34,80.97 187.34,80.89 187.55,80.68
  IN1 w0.127: v1(238.97,95.5) 238.83,95.65 238.32,95.65 237.76,95.09 235.64,95.09 233.21,92.66 228.91,92.66 225.88,89.63 220.52,89.63 219.12,88.22 213.84,88.22 213.69,88.07 213.15,88.07 209.74,84.66 209.74,82.68 208.18,81.13 206.75,81.13 204.1,78.48 200.25,78.48 199.97,78.76 198.79,78.76 197.62,79.93 194.8,79.93 194.52,80.21 188.01,80.21 187.94,80.29 187.55,80.68
  IN3 w0.089: v1(148.22,96.68) 148.01,96.48 148.01,96.26 148.12,96.15 150.62,96.15 152.32,97.85 167.71,97.85 169.48,96.09 169.48,90.56 170.11,89.93 174.56,89.93 174.59,89.9 174.59,89.9 174.91,89.58 174.91,89.58 176.53,87.96 177.22,87.96 178.7,86.48 178.7,86.2 178.51,86.01 178.51,85.8 v1(178.58,85.73)
REM_DIODE2_N: length 184.2
  TOP w0.127: v1(240.71,39.79) 240.94,40.02 240.94,40.21 241.19,40.46 241.84,40.46 241.98,40.32 245.98,40.32 247.02,41.36 247.02,42.23 249.74,44.95 249.74,46.57 251.73,48.56 251.73,59.14 250.12,60.75 250.12,61.92 243.48,68.56 243.48,73.05 241.36,75.17 241.36,77 238.75,79.6 238.75,83.92 237.95,84.72 237.95,85.78 238.25,86.08 238.25,88.88 238.74,89.36 238.74,92.71 238.3,93.14 238.3,96.37 239.02,97.09 240.68,97.09 241.71,98.12 243.7,98.12 CE26.1 244.23,98.24 245.39,98.24 245.47,98.32 246.55,98.32 UE1.A10
  IN3 w0.127: v1(240.71,39.79) 240.88,39.62 240.88,39.16 240.85,39.14 240.14,39.14 239.71,39.57 238.1,39.57 237.18,40.49 216.33,40.49 216.16,40.66 213.18,40.66 213.01,40.49 200.84,40.49 198.96,38.62 196.17,38.62 194.96,37.41 186.62,37.41 186.28,37.75 183.38,37.75 181.57,39.57 181.29,39.57 v1(181.12,39.74)
  BOTTOM w0.107: v1(181.12,39.74) 180.99,39.6 179.74,39.6 CE46.2 179.17,39.62 178.58,39.62 178.24,39.96 QE7.2 177.43,40.09 176.78,39.44 QE7.1
  BOTTOM w0.127: QE5.3 263.98,32.1 263.44,32.1 CE37.2 262.84,31.98 259,31.98 258.89,31.98 257.95,31.97 256.9,31.76 256.72,31.68 256.61,31.68 256.58,31.66 256.23,31.66 256.21,31.68 251.7,31.68 251.34,32.04 249.76,32.04 249.24,31.52 240.98,31.52 240.3,32.2 240.3,38.99 239.66,39.64 239.66,40.05 239.96,40.36 240.62,40.36 240.86,40.12 240.86,39.94 v1(240.71,39.79)
REM_DIODE2_P: length 185.5
  TOP w0.127: v1(241.3,39.79) 241.19,39.89 241.19,40.1 241.3,40.21 241.74,40.21 241.88,40.06 246.08,40.06 247.28,41.26 247.28,42.13 249.99,44.84 249.99,46.46 251.99,48.46 251.99,59.24 250.38,60.86 250.38,62.03 243.73,68.67 243.73,73.16 241.61,75.28 241.61,77.1 239.01,79.71 239.01,84.02 238.21,84.83 238.21,85.68 238.5,85.97 238.5,88.77 238.99,89.26 238.99,92.81 238.56,93.25 238.56,96.26 239.13,96.84 240.79,96.84 241.82,97.86 243.7,97.86 CE26.2 244.36,97.86 245.55,97.86 245.63,97.94 246.72,97.94 UE1.A9
  IN3 w0.127: v1(181.12,39.15) 181.29,39.32 181.46,39.32 183.28,37.5 186.17,37.5 186.52,37.16 195.07,37.16 196.27,38.36 199.07,38.36 200.94,40.24 213.12,40.24 213.29,40.41 216.05,40.41 216.22,40.24 237.07,40.24 237.99,39.32 239.6,39.32 240.03,38.89 240.96,38.89 241.13,39.06 241.13,39.62 v1(241.3,39.79)
  BOTTOM w0.107: QE7.3 178.24,38.92 178.58,39.26 179.17,39.26 CE46.1 179.5,38.99 179.88,39.37 180.91,39.37 v1(181.12,39.15)
  BOTTOM w0.127: v1(241.3,39.79) 241.12,39.97 241.12,40.22 240.73,40.61 239.86,40.61 239.4,40.16 239.4,39.54 240.05,38.89 240.05,32.09 240.88,31.27 249.35,31.27 249.87,31.79 251.24,31.79 251.59,31.43 256.1,31.43 256.13,31.4 256.69,31.4 256.71,31.43 256.77,31.43 256.97,31.51 257.98,31.72 258.89,31.72 259.01,31.73 262.91,31.73 CE37.1 263.49,31.72 263.93,31.72 QE5.2 265.06,31.89 QE5.1
REM_DIODE4_N: length 286.2
  TOP w0.127: UE1.A11 245.69,99.41 245.08,100.02 244.36,100.02 CE27.1 243.76,100.09 242.95,100.09 242.21,99.35 239.87,99.35 238.98,98.46 238.98,97.95 237.67,96.63 237.67,92.88 238.1,92.44 238.1,91.16 237,90.06 237,84.77 238.12,83.66 238.12,79.34 240.41,77.05 240.41,73.92 241.55,72.78 241.55,67.96 247.14,62.37 248.68,62.37 249.18,61.87 249.18,58.11 251.1,56.18 251.1,48.83 249.11,46.83 249.11,45.29 248.22,44.4 248.03,44.4 v1(247.89,44.54)
  IN3 w0.127: v1(247.89,44.54) 247.78,44.43 247.49,44.43 245.91,42.85 201.42,42.85 200.81,43.46 175.75,43.46 172.48,46.73 144.23,46.73 143.57,47.38 139.7,47.38 139.19,47.89 139.19,52.46 122.36,69.29 102.48,69.29 99.31,72.47 99.31,93.65 102.08,96.42 114.94,96.42 116.1,95.26 121.09,95.26 121.42,95.59 121.42,96 v1(121.59,96.16)
  BOTTOM w0.127: v1(121.59,96.16) 121.74,96.31 CE39.1 121.74,97.29 121.75,97.31 QE6.3
REM_DIODE4_P: length 288.1
  TOP w0.127: v1(247.89,43.96) 248.08,44.14 248.32,44.14 249.36,45.18 249.36,46.73 251.35,48.72 251.35,56.29 249.43,58.21 249.43,61.98 248.79,62.62 247.24,62.62 241.8,68.06 241.8,72.89 240.66,74.03 240.66,77.16 238.37,79.44 238.37,83.76 237.29,84.84 237.29,89.98 238.36,91.05 238.36,92.55 237.92,92.98 237.92,96.53 239.24,97.84 239.24,98.36 239.97,99.1 242.32,99.1 243.05,99.83 243.63,99.83 CE27.2 244.36,99.77 244.98,99.77 245.74,99.01 247.25,99.01 UE1.B10
  IN3 w0.127: v1(121,96.16) 121.17,96 121.17,95.7 120.98,95.51 116.2,95.51 115.04,96.67 101.97,96.67 99.05,93.75 99.05,72.36 102.38,69.03 122.25,69.03 138.93,52.36 138.93,47.78 139.59,47.13 143.46,47.13 144.12,46.47 172.38,46.47 175.65,43.2 200.71,43.2 201.31,42.6 246.01,42.6 247.54,44.12 247.72,44.12 v1(247.89,43.96)
  BOTTOM w0.127: QE6.2 120.45,99.14 121.1,98.49 QE6.1 121.1,97.37 120.82,97.09 CE39.2 120.82,96.34 v1(121,96.16)
RES_BIAS: length 4.4
  TOP w0.107: RL13.1 276.02,102.77 v2(276.74,102.04)
  TOP w0.203: RL13.1 276.02,103.5 275.31,104.21 274.25,104.21 274.06,104.41 UL1.12
RESET_IN#: length 8
  TOP w0.107: UE1.C1 248.4,91.41 247.96,90.97 247.96,90.18 247.58,89.8 246.63,89.8 246.45,89.62 246.14,89.62 245.4,88.88 245.4,87.11 v2(245.09,86.8) 244.53,86.24 RE362.1
RESET_OUT: length 5
  TOP w0.127: v1(251.23,93.42) 251.62,93.81 UE1.G4
  BOTTOM w0.107: RE548.2 251.65,89.18 v2(251.65,90.14) 251.65,93 v1(251.23,93.42)
RESET_OUT#_R: length 169
  TOP w0.107: v1(208.4,119.31) v2(208.4,118.15) 208.4,116.14 209.88,114.66 209.88,104.1 v1(209.86,104.09) ; RC128.2 CC334.1 89.97,134.63 v1(89.97,134.94)
  IN3 w0.102: v1(209.86,104.09) 209.35,104.09 208.97,104.47 203.64,104.47 201.16,101.98 196.32,101.98 194.75,103.55 194.01,103.55 v1(193.8,103.77) ; v1(89.97,132.41) 89.97,132.41 89.97,131.87 90.08,131.77 90.24,131.61 93.66,131.61 94.04,131.99 97.05,131.99 99.88,129.15 101.74,129.15 102.44,128.46 104.46,128.46 104.87,128.05 114.11,128.05 114.82,127.34 116.5,125.65 131.48,125.65 132.15,126.32 134.87,126.32 135.31,126.77 140,126.77 140.6,127.37 147.69,127.37 150.73,124.33 156.82,124.33 157.35,124.85 158.54,124.85 161.47,127.78 v1(161.47,128.34)
  BOTTOM w0.107: RC129.2 193.22,103.83 193.73,103.83 v1(193.8,103.77) ; v1(161.47,128.34) 161.47,127.28 161.92,126.84 167.43,126.84 168.43,125.83 177.08,125.83 179.97,122.94 184.19,122.94 184.31,123.06 186.79,123.06 187.96,121.89 190.08,121.89 190.7,121.28 191.67,121.28 192.3,120.64 199.24,120.64 199.73,120.15 207.56,120.15 v1(208.4,119.31) ; v1(89.97,132.41) 89.97,132.41 89.97,133.68 89.97,133.69 JXDP1.47 v1(89.97,134.94)
RING2: length 20
  IN1 w1.27: 299.91,35.57 299.91,38.62 294.13,44.4 294.13,49.73 292.03,51.83 291.59,51.83
  vias: v1(289.43,52.27) v1(290.01,52.27) v1(290.6,52.27) v1(299.5,34.45) v1(299.78,33.86) v1(300.16,34.43) v2(299.06,34.1)
RING2_R: length 30.2
  TOP w0.508: v1(302.76,35.32) 303.02,35.32 303.4,35.7 303.4,38.81 v2(304.1,39.51) 304.82,40.23 313.17,40.23 JHP1.4
  IN1 w0.508: JHP1.4 313.17,40.23 304.82,40.23 303.43,38.84 303.43,36.62 v1(302.76,35.95)
RJ45_MDIN0: length 8.3
  BOTTOM w0.305: TL1.23 300.17,98.61 300.59,98.19 301.71,98.19 302.13,98.61 v2(302.13,99.5) 302.74,100.12 304.7,100.12 305.1,100.52 JLOM1.2
RJ45_MDIN1: length 7.4
  TOP w0.305: JLOM1.6 304.1,104.37 304.1,103.58 303.79,103.27 301.88,103.27 v1(301.8,103.35)
  BOTTOM w0.305: TL1.19 300.19,103.69 300.53,103.35 v1(301.8,103.35)
RJ45_MDIN2: length 8.1
  BOTTOM w0.305: JLOM1.5 303.05,104.36 302.9,104.51 302.9,105.03 302.12,105.81 v2(301.65,105.81) 300.69,105.81 300.28,106.23 TL1.17
RJ45_MDIN3: length 9.4
  BOTTOM w0.305: JLOM1.8 304.62,106.93 303.39,106.93 302.88,107.44 302.88,110 v2(301.99,110.89) 300.72,110.89 300.3,111.31 TL1.13
RJ45_MDIP0: length 8.7
  BOTTOM w0.305: TL1.24 300.2,97.34 300.62,97.76 v2(301.71,97.76) 301.89,97.76 302.56,98.43 302.56,99.32 302.92,99.69 304.88,99.69 305.47,100.28 JLOM1.1
RJ45_MDIP1: length 7.4
  TOP w0.305: v1(301.8,102.76) 301.88,102.84 304.33,102.84 304.85,102.32 JLOM1.3
  BOTTOM w0.305: v1(301.8,102.76) 300.55,102.76 300.21,102.42 TL1.20
RJ45_MDIP2: length 7.4
  BOTTOM w0.305: JLOM1.4 305.1,103.62 304.8,103.93 302.87,103.93 v2(302.47,104.33) 302.47,104.85 301.94,105.38 300.7,105.38 300.28,104.96 TL1.18
RJ45_MDIP3: length 10.4
  BOTTOM w0.305: TL1.14 300.33,110.04 300.75,110.46 301.81,110.46 301.9,110.37 302.45,109.83 v2(302.45,108.47) 302.45,107.26 303.21,106.5 306.1,106.5 JLOM1.7
RTC_DET#: length 112
  TOP w0.102: v1(177.88,96.71) 178.25,97.08 181.28,97.08 182.42,95.93 183.93,95.93
  TOP w0.107: v1(239.47,101.77) 239,101.77 238.38,102.39 238.38,108.15 237.71,108.82 237.71,113.64 238.31,114.24 238.31,116.51 238.98,117.18 241.78,117.18 242.2,117.59 242.98,117.59 243.06,117.51 246.47,117.51 247.33,116.65 248.26,116.65 248.86,117.25 248.86,123.23 245.2,126.88 v3(242.39,126.88) 241.42,126.88 RC866.1 241.2,126.63 PQ13.1 ; v1(191.51,98.19) 191.51,98.44 191.08,98.87 189.82,98.87 189.31,98.36 189.31,97.91 188.93,97.53 186.9,97.53 186.66,97.29 185.75,97.29 185.54,97.09 185.54,96.67 184.81,95.93 183.93,95.93
  IN1 w0.099: v1(191.51,98.19) 191.75,97.95 192.61,97.95 192.85,97.71 198.22,97.71 198.84,97.09 209.11,97.09 209.92,97.91 213.08,97.91 214.98,99.8 218.53,99.8 219.34,98.99 222.24,98.99 222.67,99.42 225.14,99.42 225.95,100.23 227.15,100.23 228.17,101.25 235.42,101.25 235.94,101.77 v1(239.47,101.77)
  BOTTOM w0.076: UC1.CF22 177.64,96.95 v1(177.88,96.71)
RTCRST_ON: length 14.7
  TOP w0.102: 247.58,104.51 247.58,104.05 248.41,103.22 v2(249.16,103.22)
  TOP w0.107: 247.58,104.51 247.58,107.28 247.69,107.39 248.22,107.39 248.33,107.5 QE12.2 248.33,108.17 248.22,108.28 RE93.1 ; v2(249.16,103.22) 249.91,103.22 v1(250.12,103.01) ; UE1.F11 250.85,99.43 250.46,99.81 v1(250.46,99.85)
  IN1 w0.089: 251.61,100.82 251.61,100.39 251.4,100.19 250.81,100.19 v1(250.46,99.85)
  IN1 w0.099: v1(250.12,103.01) 250.25,102.88 251.2,102.88 251.61,102.48 251.61,100.82
RTCRST_ON_POWER: length 31
  TOP w0.102: UE1.B13 247.63,101.01 247.28,101.36 245.88,101.36 v1(245.3,101.94)
  TOP w0.107: v1(236.45,115.44) 236.45,118.09 237.78,119.42 238.92,119.42 239.89,120.38 v2(239.89,120.55) 239.89,121.26 240.5,121.87 RE565.2
  IN2 w0.102: v1(245.3,101.94) 245.68,102.32 245.68,102.77 245.17,103.28 245.17,104.68 243.56,106.3 243.56,109.31 243.1,109.77 243.1,110.79 237.93,115.96 236.97,115.96 v1(236.45,115.44)
RTCRST_ON_R: length 5.9
  TOP w0.107: v2(247.32,124.08) 246.74,124.66 DE2.2 245.02,123.41 QE17.2 243.88,123.41 243.59,123.7 RE543.1 CE65.1
RTCX2: length 2.6
  TOP w0.107: YC2.2 174.56,80.21 174.33,80.43 CC26.1 RC532.2
RUN_ON: length 508.3
  TOP w0.107: v1(259.33,77.73) 257.49,77.73 256.92,78.31 256.92,80.02 256.78,80.16 RE280.2 255.6,80.53 255.07,80.53 254.96,80.42 UE5.4 ; v1(188.84,120.4) 188.99,120.25 194.52,120.25 195.74,121.47 195.74,124.69 195,125.42 RZ1423.1 RZ320.1 192.77,125.47 192.59,125.3 UZ35.2 ; UZ3.5 227.15,85.5 227.58,85.93 v1(227.68,85.93) ; v1(261.2,75.73) 260.41,76.53 256.85,76.53 256.41,76.08 253.66,76.08 252.71,77.04 RE292.1 252.41,76.86 QE2.2 ; v1(260.4,37.24) 260.4,37.76 UZ54.1 ; v1(274.12,69.67) 274.68,69.11 RZ345.1 276.14,70.3 282.21,70.3 286.06,74.15 286.06,88.61 285.66,89.02 285.66,90.5 282.51,93.65 281.1,93.65 280.44,94.31 279.08,94.31 278.09,95.3 v2(278.09,99.37) 278.5,99.78 PR511.1 ; v1(268.92,68.76) 268.81,68.66 UZ47.3
  TOP w0.254: PR402.1 v1(103.87,70.05)
  IN1 w0.099: v1(103.87,70.05) 103.87,65.67 98.07,59.88 98.07,56.37 97.62,55.92 97.62,51.37 97.2,50.94 v1(96.87,50.94) ; v1(226.75,72.72) 227.26,72.72 228.63,74.08 230.72,74.08 231.01,74.37 231.01,76.46 229.99,77.48 225.93,77.48 225.12,76.67 223.99,76.67 223.45,77.21 223.45,79.92 222.5,80.87 222.5,82.56 224.06,84.12 225.14,84.12 226.76,85.74 227.45,85.74 227.64,85.93 v1(227.68,85.93)
  IN2 w0.102: v1(96.87,50.94) 97.39,51.46 97.39,52.53 100,55.14 131.52,55.14 133.37,53.29 133.37,48.37 133.86,47.88 134.06,47.88 136.2,45.73 136.2,45.16 136.96,44.4 136.96,43.8 137.57,43.2 147.02,43.2 147.84,42.38 151.39,42.38 152.06,43.05 153.86,43.05 156.03,40.87 162.47,40.87 162.5,40.84 167.06,36.28 177.46,36.28 182.72,31.02 193.14,31.02 196.32,34.2 197.3,34.2 197.78,34.68 197.78,35.36 198.48,36.05 201.92,36.05 202.95,37.09 202.95,37.28 202.95,37.66 203.49,38.2 204.83,38.2 205.09,38.47 208.85,38.47 209.51,37.81 215.66,37.81 215.74,37.73 221.33,37.73 223.23,35.83 223.23,35.59 223.97,34.85 223.97,33.31 225.97,31.31 231.86,31.31 233.63,33.08 238.5,33.08 240.5,31.08 249.56,31.08 250.18,31.7 255.45,31.7 257.29,33.53 259.04,33.53 260.17,34.66 260.17,37.01 v1(260.4,37.24) 260.97,37.82 263.16,37.82 264.27,38.93 264.27,41.44 263.99,41.72 263.99,42.85 263.76,43.08 263.76,44.61 264.66,45.51 264.66,48.9 264.21,49.36 264.21,59.24 264.57,59.61 264.57,62.28 261.64,65.22 261.64,72.88 260.8,73.72 260.8,75.33 v1(261.2,75.73) ; v1(226.75,72.72) 226.06,72.72 220.47,78.31 217.19,78.31 215.19,80.3 213.08,80.3 212.17,81.2 212.17,81.2 211.94,81.44 211.93,81.44 211.89,81.48 210.19,81.48 209.85,81.82 203.79,81.82 203.51,81.54 202.12,81.54 201.42,82.25 201.42,82.46 196.14,87.74 196.14,89.01 194.4,90.75 191.96,90.75 190.37,92.35 190.37,96.34 189.16,97.55 184.21,97.55 182.82,98.93 182.82,101.63 183.01,101.81 183.01,108.93 184.26,110.18 184.26,112.48 185.68,113.89 185.68,115.54 186.72,116.58 186.72,116.8 186.84,116.91 186.84,118.24 188.84,120.25 v1(188.84,120.4)
  IN3 w0.102: v1(259.33,77.73) 259.33,77.61 v1(261.2,75.73) 261.2,75.34 263.32,73.23 263.32,72.63 264.91,71.04 266.28,71.04 268.55,68.76 v1(268.92,68.76)
  BOTTOM w0.107: v1(226.75,72.72) 227.33,72.72 228.86,74.25 232.78,74.25 233.52,74.99 245.65,74.99 246.34,74.31 254.38,74.31 256.87,76.8 259.25,76.8 260.31,75.73 v1(261.2,75.73) ; v1(268.92,68.76) 269.82,69.67 v1(274.12,69.67)
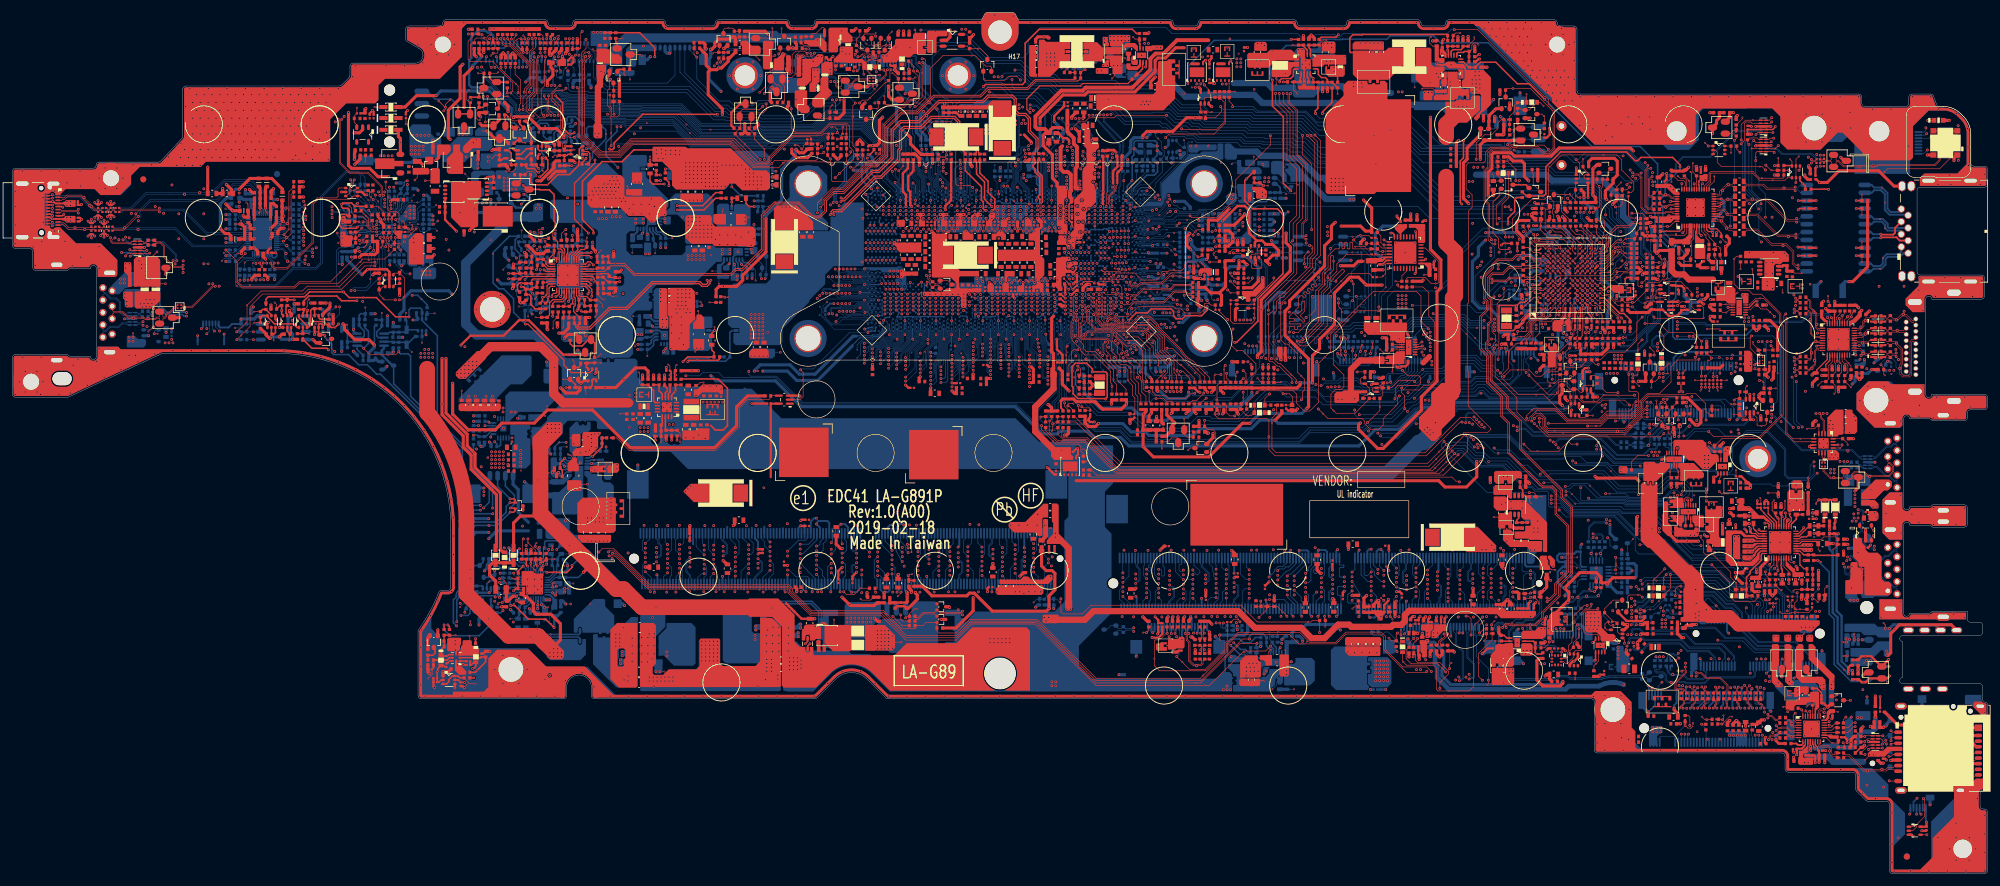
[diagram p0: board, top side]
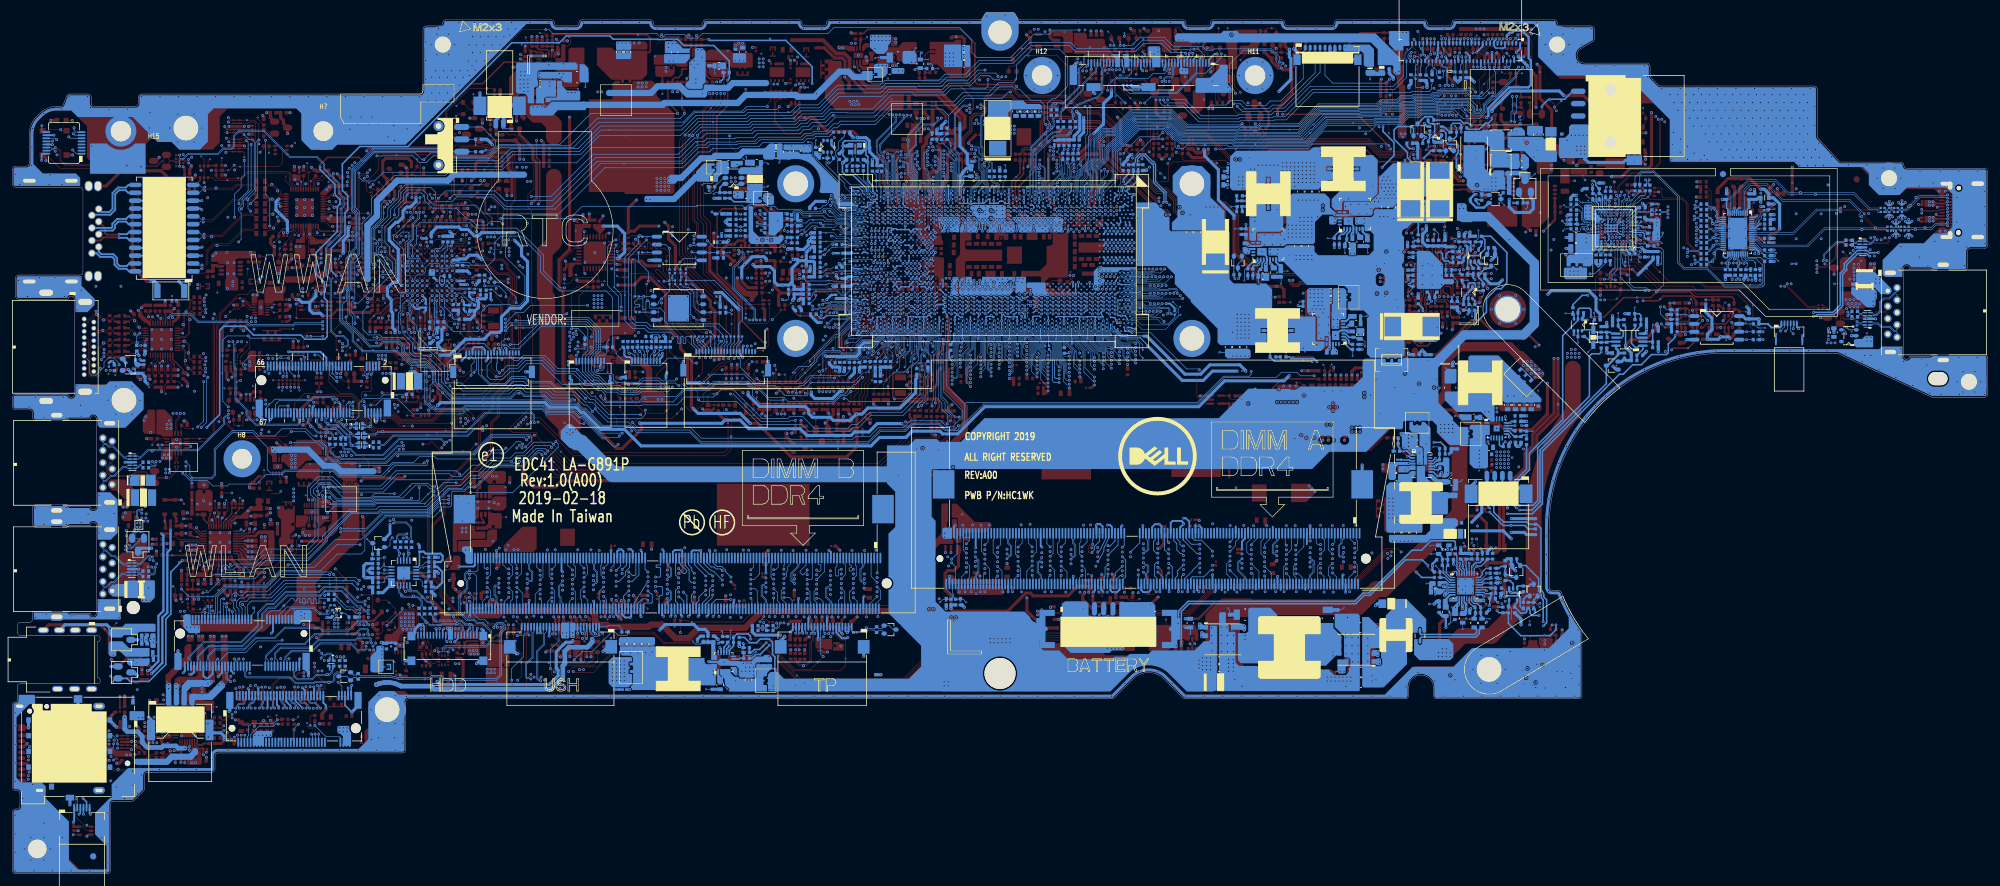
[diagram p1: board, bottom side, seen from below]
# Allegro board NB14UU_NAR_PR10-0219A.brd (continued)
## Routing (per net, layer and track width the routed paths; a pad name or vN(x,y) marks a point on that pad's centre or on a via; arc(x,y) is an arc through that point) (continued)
RUN_ON#: length 3.7
  TOP w0.107: v2(255.29,74.04) RE68.1 253.97,73.69 253.16,73.69 253.06,73.8 QE2.6 253.06,74.2 252.95,74.31 252.51,74.31 252.41,74.2 QE2.5
RUN_ON_1.8V: length 3.7
  TOP w0.107: UZ8.3 275.97,68.07 CZ197.1 RZ345.2 274.82,68.2 273.97,69.05 v2(273.97,69.15)
RUN_ON_EC: length 43.9
  TOP w0.107: UE5.2 254.31,77.67 254.36,77.62 RE718.2 RE292.2 253.5,76.61 253.8,76.32 256.01,76.32 v2(257.02,77.33) v1(262.02,77.33)
  TOP w0.127: UE1.E8 v1(249.65,97.41)
  IN1 w0.089: v1(257.81,94.12) 257.81,94.73 257.42,95.11 ; 256.76,98.29 256.47,98.58 256.47,98.6 256.38,98.69 255.84,98.69 255.74,98.6 255.05,98.6 255.02,98.62 251.11,98.62 250.83,98.34 250.83,98.05 250.61,97.82 250.06,97.82 v1(249.65,97.41)
  IN1 w0.099: 256.76,98.29 256.79,98.26 256.79,95.74 257.42,95.11
  IN2 w0.089: 260.83,89.57 257.81,92.59 v1(257.81,94.12)
  IN2 w0.102: v1(262.02,77.33) 262.14,77.45 262.14,80.84 261.42,81.56 261.42,82.86 262.03,83.47 262.03,88.36 260.83,89.57
RUNPWROK: length 23.5
  TOP w0.107: v1(251.13,78.05) 251.72,77.46 RE67.1 251.72,76.45 251.76,76.42 QE2.3 251.76,75.69 251.24,75.17 v2(250.66,75.17)
  TOP w0.127: v1(251.27,92.63) UE1.G3
  IN2 w0.089: v1(251.27,92.63) 251.27,90.04 248.87,87.64 248.5,87.64 248.34,87.49 248.34,87 248.37,86.98
  IN2 w0.102: v1(251.13,78.05) 251.13,81.86 251.93,82.66 251.93,85.48 251.63,85.77 249.57,85.77 248.37,86.98
S1_OVP: length 49.6
  IN1 w0.254: v1(85.02,119.82) 84.37,119.17 78.07,119.17 73.73,114.83 72.33,114.83 68.96,111.45 68.96,96.78 65.64,93.47 v1(64.57,93.47)
  BOTTOM w0.254: v1(64.57,93.47) 65.48,93.47 v2(66.07,92.88) 66.99,91.96 PR836.2 ; v1(85.02,119.82) 85.05,119.85 PR32.2 85.05,121.07 85.25,121.27 86.34,121.27 86.62,120.99 86.62,119.91 PR46.1 86.93,119.83 87.83,120.74 PQ10.3
SATA_PRX_C_DTX_N0: length 9.6
  BOTTOM w0.097: CN6.1 252.86,41.59 252.86,41.5 252.35,40.99 252.3,40.99 251.89,40.58 251.89,40.53 251.59,40.24 249.88,40.24 249.72,40.4 249.11,40.4 v4(247.2,40.4) 246.68,40.4 246.18,39.9 246.18,39.32 246.04,39.18 JSATA1.5
SATA_PRX_C_DTX_P0: length 9.5
  BOTTOM w0.097: JSATA1.6 246.54,39.08 246.37,39.26 246.37,39.82 246.72,40.18 247.49,40.18 247.53,40.21 247.85,40.21 247.85,40.21 249.03,40.21 249.65,40.21 249.8,40.05 251.67,40.05 v4(252.25,40.63) 253.04,41.43 253.04,41.65 CN7.1
SATA_PRX_C_RD_DTX_N11: length 2.5
  BOTTOM w0.097: UN7.4 256.34,51.06 256.49,51.21 v4(256.49,51.75) 256.49,52.07 256.7,52.28 256.7,52.38 CN14.2
SATA_PRX_C_RD_DTX_P11: length 2.5
  BOTTOM w0.097: CN15.2 256.88,52.38 256.88,52.2 256.71,52.03 256.71,51.46 256.68,51.42 256.68,51.24 256.84,51.08 UN7.5
SATA_PRX_DTX_N11: length 135.4
  IN3 w0.089: v1(255.33,54.32) 255.13,54.52 254.98,54.52 253.16,56.34 253.16,61.57 252.72,62.01 252.72,64.67 249.24,68.15 242.32,68.15 236.27,74.21 235.67,74.21 235.27,74.61 234.21,74.61 230.18,78.64 228.2,78.64 227.48,79.35 227.48,79.93 224.61,82.81 224.61,83.19 224.03,83.76 224.03,86.83 218.76,92.11 218.76,94.31 218.28,94.79 218.28,101.74 217.67,102.34 217.67,103.25 217.67,105.67 214.77,108.57 200.67,108.57 197.63,111.62 197.63,113.47 195.8,115.3 191.1,115.3 188.38,112.58 178.73,112.58 177.76,111.61 177.76,111.55 177.58,111.38 177.53,111.38 177.22,111.07 177.22,110.31 176.16,109.24 172.31,109.24 171.45,108.38 171.04,108.38 170.76,108.1 170.76,106.35 170.85,106.27 170.85,105.7 170.65,105.51 170.45,105.51 v1(170.22,105.28)
  BOTTOM w0.089: UC1.BN10 v1(170.22,105.28)
  BOTTOM w0.097: CN14.1 256.85,54.14 256.85,54.5 256.62,54.72 255.73,54.72 v1(255.33,54.32)
SATA_PRX_DTX_P11: length 135.4
  IN3 w0.089: v1(170.22,105.92) 170.45,105.69 170.58,105.69 170.67,105.78 170.67,106.2 170.59,106.28 170.59,108.18 170.97,108.56 171.37,108.56 172.24,109.42 176.08,109.42 177.05,110.38 177.05,111.15 177.45,111.55 177.51,111.55 177.58,111.62 177.58,111.68 178.66,112.76 188.31,112.76 191.03,115.48 195.87,115.48 197.81,113.54 197.81,111.69 200.75,108.75 214.85,108.75 217.85,105.75 217.85,103.18 217.85,103.18 217.85,102.42 218.46,101.81 218.46,94.87 218.94,94.39 218.94,92.18 224.22,86.91 224.22,83.83 224.79,83.26 224.79,82.88 227.67,80 227.67,79.43 228.27,78.82 230.25,78.82 234.28,74.79 235.34,74.79 235.75,74.39 236.34,74.39 242.4,68.33 249.32,68.33 252.9,64.75 252.9,62.09 253.34,61.64 253.34,56.42 255.05,54.7 255.13,54.7 v1(255.33,54.91)
  BOTTOM w0.089: UC1.BN8 170.01,105.59 170.15,105.66 v1(170.22,105.92)
  BOTTOM w0.097: CN15.1 257.03,53.85 257.03,54.58 256.7,54.91 v1(255.33,54.91)
SATA_PRX_RD_DTX_N0: length 6.7
  BOTTOM w0.097: CN6.2 252.86,43.27 252.86,44.08 253.62,44.84 v4(254.27,44.84) 255.78,44.84 256.21,45.27 256.26,45.27 256.47,45.49 256.47,45.98 256.34,46.12 UN7.12
SATA_PRX_RD_DTX_P0: length 6.8
  BOTTOM w0.097: CN7.2 253.04,43.2 253.04,44 253.7,44.66 253.95,44.66 253.98,44.62 254.57,44.62 254.6,44.66 255.91,44.66 v4(256.16,44.91) 256.66,45.41 256.66,45.98 256.84,46.16 UN7.11
SATA_PTX_C_DRX_N0: length 9.7
  BOTTOM w0.097: CN5.1 251.19,41.58 251.19,41.13 250.71,40.65 250.05,40.65 249.9,40.8 249.27,40.8 249.27,40.8 247.6,40.8 246.52,40.8 245.91,40.19 v4(245.19,40.19) 244.91,40.19 244.75,40.03 244.75,39.35 245.04,39.06 JSATA1.3
SATA_PTX_C_DRX_P0: length 9.5
  BOTTOM w0.097: JSATA1.2 244.54,39.07 244.56,39.09 244.56,40.11 244.86,40.41 245.86,40.41 246.44,40.98 247.56,40.98 249.98,40.98 250.12,40.84 250.59,40.84 v4(250.77,41.02) 251.01,41.26 251.01,41.66 CN4.1
SATA_PTX_C_RD_DRX_N11: length 2.4
  BOTTOM w0.097: UN7.2 255.34,51.06 255.18,51.21 255.18,51.42 255.21,51.46 255.21,52.04 255.18,52.08 255.18,52.45 CN13.2
SATA_PTX_C_RD_DRX_P11: length 2.4
  BOTTOM w0.097: UN7.1 254.84,51.02 254.99,51.17 v4(254.99,51.75) 254.99,52.3 CN12.2
SATA_PTX_DRX_N11: length 145.5
  IN3 w0.089: v1(257.49,56.66) 257.24,56.91 257.14,56.91 256.74,57.31 256.74,61.52 256.04,62.23 256.04,66.68 249.94,72.78 248.67,72.78 248.26,73.19 247.66,73.19 246.59,72.11 245.24,72.11 243.94,73.41 242.04,73.41 237.39,78.06 235.86,78.06 233.75,80.17 233.75,80.94 230.57,84.12 230.57,88.64 229.6,89.61 229.58,89.61 228.85,90.34 228.85,92.3 226.71,94.44 226.71,94.94 225.39,96.25 225.39,99.12 224.14,100.38 224.14,107.78 215.53,116.38 201,116.38 197.56,119.82 188.54,119.82 188.13,120.22 186.17,120.22 185.47,119.52 179.37,119.52 178.97,119.11 173.95,119.11 171.85,117.01 171.85,114.94 171.59,114.68 171.44,114.68 v1(171.25,114.48)
  BOTTOM w0.076: UC1.BN4 169.63,108.6 169.91,108.88 169.91,109.19 170.06,109.53 170.06,109.78 170.03,109.87 170.03,110.1 170.06,110.19 170.06,110.54 169.87,110.73 169.87,113.33 170.61,114.06 170.61,114.33 170.76,114.48 v1(171.25,114.48)
  BOTTOM w0.097: CN13.1 255.44,53.64 255.02,54.06 254.99,54.06 254.75,54.3 254.75,55.92 255.49,56.66 v1(257.49,56.66)
SATA_PTX_DRX_P11: length 145.6
  IN3 w0.089: v1(171.25,115.07) 171.46,114.86 171.52,114.86 171.67,115.01 171.67,117.09 173.88,119.3 178.89,119.3 179.3,119.7 185.4,119.7 186.1,120.4 188.21,120.4 188.61,120 197.63,120 201.07,116.56 215.61,116.56 224.32,107.85 224.32,100.45 225.57,99.2 225.57,96.33 226.89,95.01 226.89,94.52 229.03,92.37 229.03,90.41 229.65,89.79 229.68,89.79 230.75,88.72 230.75,84.19 233.93,81.02 233.93,80.25 235.94,78.24 237.46,78.24 242.12,73.59 244.02,73.59 245.31,72.29 246.51,72.29 247.59,73.37 248.33,73.37 248.74,72.96 250.01,72.96 256.22,66.75 256.22,62.3 256.92,61.6 256.92,57.38 257.21,57.09 257.34,57.09 v1(257.49,57.24)
  BOTTOM w0.076: v1(171.25,115.07) 170.83,114.65 170.69,114.65 170.44,114.4 170.44,114.13 169.71,113.4 169.71,110.66 169.9,110.47 169.9,110.22 169.86,110.13 169.86,109.85 169.9,109.76 169.9,109.57 169.81,109.38 169.76,109.32 169.58,109.32 169.5,109.24 169.5,109.09 169.58,109.01 UC1.BN3
  BOTTOM w0.097: v1(257.49,57.24) 257.09,56.84 255.41,56.84 254.57,56 CN12.1
SATA_PTX_RD_DRX_N0: length 6.6
  BOTTOM w0.097: CN5.2 251.23,43.24 251.23,43.49 251.59,43.84 252.05,43.84 v4(252.88,44.67) 253.75,45.54 254.95,45.54 255.18,45.77 255.18,45.96 255.34,46.12 UN7.14
SATA_PTX_RD_DRX_P0: length 6.6
  BOTTOM w0.097: CN4.2 251.05,43.24 251.05,43.61 v4(251.26,43.83) 251.46,44.03 251.98,44.03 252.51,44.57 252.51,44.61 252.93,45.03 252.98,45.03 253.68,45.73 254.88,45.73 254.99,45.85 254.99,45.94 254.84,46.1 UN7.15
SBIOS_TX: length 50.9
  TOP w0.107: v1(212.4,86.6) 212.4,87.01 214.73,89.33 v2(214.73,90.76) 214.73,91.12 214.19,91.65 v1(214.19,92.25)
  IN3 w0.102: v1(214.19,92.25) 213.47,92.97 213.47,93.35 212.89,93.93 212.89,100.07 212.07,100.89 206.9,100.89 205.93,101.86 204.66,101.86 202.53,99.74 201.59,99.74 200.31,101.02 195.79,101.02 195.17,101.64 195.17,101.65 194.52,102.29 194.52,102.35 194.28,102.59 193.95,102.59 193.54,102.18 190.57,102.18 190.57,102.18 190.51,102.18 190.46,102.13 189.22,102.13 187.89,103.46 187.18,103.46 v1(186.77,103.05)
  BOTTOM w0.076: UC1.CP14 182.24,102.17 182.73,102.44 182.99,102.44 183.19,102.24 183.64,102.24 184.01,102.61 185.92,102.61 185.99,102.68
  BOTTOM w0.102: 185.99,102.68 186.37,103.05 v1(186.77,103.05)
  BOTTOM w0.107: v1(212.4,86.6) 212.4,86.38 RE306.1
SCL_CHG: length 2.4
  BOTTOM w0.203: PU700.22 81.72,47.07 v2(81.17,47.61) 80.41,47.61 PR715.2
SD/MMCCD#: length 26
  TOP w0.107: v1(303.15,15) 303.19,14.96 JSD1.9 ; UR1.30 290.01,25.97 v1(289.68,26.3)
  IN1 w0.099: v1(289.68,26.3) 290.19,25.79 291.52,25.79 292.29,25.03 292.29,23.89 293.6,22.58 296.71,22.58 299.65,19.63 304.03,19.63 304.92,18.74 304.92,16.77 v1(303.15,15)
SD/MMCCLK: length 2.8
  TOP w0.107: UR1.17 292.99,21.98 293.86,21.11 v2(294,21.11) 294.7,21.11 RR5.1
SD/MMCCLK_R: length 13.6
  TOP w0.107: RR5.2 295,20.39 CR21.1 295.89,20.98 v1(295.71,21.16) ; JSD1.5 303.76,19.26 303.44,18.95 v1(303.11,18.95)
  IN1 w0.099: v1(295.71,21.16) 296.48,20.39 296.62,20.39 296.87,20.63 297.01,20.63 297.15,20.49 297.15,20.35 296.91,20.11 296.91,19.97 297.05,19.83 297.19,19.83 297.43,20.07 297.57,20.07 297.71,19.93 297.71,19.79 297.47,19.55 297.47,19.4 298.13,18.74 301.43,18.74 301.64,18.95 v1(303.11,18.95)
SD/MMCCMD: length 2.2
  TOP w0.107: UR1.19 294.8,22.78 RR6.1
SD/MMCCMD_R: length 13.8
  TOP w0.107: v1(297.66,23.76) 297.43,23.76 v2(296.74,23.07) 296.49,22.82 RR6.2 ; JSD1.3 303.6,21.06 v1(303.44,20.91)
  IN1 w0.099: v1(303.44,20.91) 303.02,21.33 303.02,22.11 302.41,22.72 301.24,22.72 301.14,22.62 301.14,22.27 301.05,22.17 300.85,22.17 300.75,22.27 300.75,22.62 300.65,22.72 300.45,22.72 300.35,22.62 300.35,22.27 300.25,22.17 300.06,22.17 299.96,22.27 299.96,22.62 299.86,22.72 299.45,22.72 299.35,22.82 299.35,23.09 299.25,23.19 299.05,23.19 298.95,23.09 298.95,22.82 298.85,22.72 298.65,22.72 298.55,22.82 298.55,23.09 298.46,23.19 297.76,23.19 297.66,23.29 v1(297.66,23.76)
SD/MMCDAT0/RCLK+: length 5.1
  TOP w0.089: UR1.16 292.01,21.01 291.94,20.94 291.94,20.86 292.08,20.73 293.35,20.73 293.81,20.27 293.81,19.5 294.06,19.26 294.29,19.26 294.38,19.35 294.38,19.68 294.47,19.77 294.61,19.77 RR10.1
SD/MMCDAT0/RCLK+_R: length 10.2
  TOP w0.089: RR10.2 296.04,19.26 296.72,19.26 299.13,16.85 v4(301.98,16.85) 302.59,16.85 302.88,17.15 303.84,17.15 304.15,17.46 JSD1.7
SD/MMCDAT1/RCLK-: length 5.1
  TOP w0.089: UR1.15 291.61,21.01 291.67,20.94 291.67,20.75 291.97,20.46 293.24,20.46 293.54,20.16 v4(293.54,19.84) 293.54,19.39 293.94,18.99 294.63,18.99 RR9.1
SD/MMCDAT1/RCLK-_R: length 10.2
  TOP w0.089: JSD1.8 304.18,16.56 303.86,16.88 303,16.88 302.7,16.58 v4(299.63,16.58) 299.02,16.58 296.61,18.99 296.04,18.99 RR9.2
SD/MMCDAT2: length 2.5
  TOP w0.107: UR1.21 293.69,23.58 v2(293.94,23.82) 294.46,24.34 RR8.1
SD/MMCDAT2_R: length 14.5
  TOP w0.107: v1(303.44,23.09) 303.67,22.86 JSD1.1 ; RR8.2 295.75,24.89 v1(296.16,25.3)
  IN1 w0.099: v1(296.16,25.3) 295.66,24.79 295.66,23.99 295.76,23.89 296.07,23.89 296.16,23.99 296.16,24.54 296.26,24.64 296.46,24.64 296.56,24.54 296.56,23.99 296.66,23.89 296.89,23.89 296.98,23.99 296.98,24.7 297.08,24.8 301.73,24.8 v1(303.44,23.09)
SD/MMCDAT3: length 2.3
  TOP w0.107: UR1.20 293.87,23.18 294.27,23.58 RR7.1
SD/MMCDAT3_R: length 13.9
  TOP w0.107: v1(303.44,21.49) 303.44,21.86 303.55,21.96 JSD1.2 ; RR7.2 296.49,23.58 297.3,24.39 v1(297.66,24.39)
  IN1 w0.099: v1(297.66,24.39) 298.83,24.39 300.1,23.12 300.51,23.12 300.61,23.22 300.61,23.82 300.71,23.92 301.58,23.92 301.68,23.82 301.68,23.62 301.58,23.52 301.11,23.52 301.01,23.42 301.01,23.22 301.11,23.12 302.76,23.12 303.44,22.45 v1(303.44,21.49)
SD_GPIO: length 2.9
  TOP w0.107: v2(289.81,27.01) 290.05,27.25 RR3.2 290.81,27.23 UR1.28
SD_RCOMP: length 17.5
  TOP w0.254: v1(180.32,89.43) 181.51,90.62 183.32,90.62 183.96,91.26 187.14,91.26 187.55,90.85 187.55,90.08 187.96,89.67 188.97,89.67 189.48,90.18 v2(191.78,90.18) 192.08,90.18 192.97,91.07 v1(192.97,91.63)
  BOTTOM w0.2: UC1.CM34 v1(180.32,89.43)
  BOTTOM w0.203: UC1.CK33 180.28,89.48 v1(180.32,89.43)
  BOTTOM w0.381: v1(192.97,91.63) 192.97,91.39 192.59,91.01 RC116.1
SD_UHS2_D0N: length 30.8
  TOP w0.089: v1(292.68,26.04) 292.62,25.98 292.44,25.98 292.35,26.07 292.35,26.26 292.26,26.35 292.09,26.35 291.94,26.21 291.94,25.88 292.01,25.81 UR1.25 ; v1(316.46,18.37) 316.58,18.24 316.93,18.24 317.37,18.68 JSD1.19
  IN1 w0.089: v1(292.68,26.04) 292.83,25.89 292.95,25.89 293.23,26.16 294.51,26.16 295.01,26.67 302.03,26.67 310.19,18.51 316.32,18.51 v1(316.46,18.37)
SD_UHS2_D0P: length 30.9
  TOP w0.089: v1(292.68,26.62) 291.97,26.62 291.68,26.32 291.68,25.88 291.61,25.81 UR1.26 ; v1(316.46,18.95) 317.1,19.59 JSD1.18
  IN1 w0.089: v1(292.68,26.62) 292.8,26.5 294.37,26.5 294.87,27 302.17,27 310.33,18.84 316.34,18.84 v1(316.46,18.95)
SD_UHS2_D1N: length 30.6
  TOP w0.089: v1(293.46,24.58) 293.26,24.38 UR1.23 ; JSD1.21 317.11,16.86 316.75,16.51 316.75,16.11 v1(316.48,15.83)
  IN1 w0.089: v1(293.46,24.58) 293.59,24.45 293.93,24.45 295.54,26.06 301.79,26.06 312.02,15.83 v1(316.48,15.83)
SD_UHS2_D1P: length 30.6
  TOP w0.089: v1(316.48,15.25) 317.18,15.95 JSD1.22 ; v1(293.46,23.99) 293.45,23.98 UR1.22
  IN1 w0.089: v1(293.46,23.99) 293.59,24.12 294.07,24.12 295.68,25.73 301.65,25.73 311.88,15.5 315.91,15.5 316,15.41 316,15.15 316.09,15.06 316.29,15.06 v1(316.48,15.25)
SDA_CHG: length 2.2
  BOTTOM w0.203: PU700.21 81.63,46.67 81.33,46.98 PR713.2
SDWP: length 9.5
  TOP w0.102: v1(290.32,26.23) 290.41,26.15 UR1.29
  TOP w0.107: QR1.1 v1(296.88,28.01)
  IN1 w0.099: v1(296.88,28.01) 296.5,27.63 291.23,27.63 290.32,26.72 v1(290.32,26.23)
SIM_DET: length 93.2
  TOP w0.107: v1(299.8,20.06) 300.02,20.28 DZ13.5 DZ13.6 v1(302.06,20.28)
  IN2 w0.102: v1(275.81,80.88) 275.81,80.48 276.58,79.71 276.58,77.58 275.81,76.82 275.81,72.49 275.39,72.07 275.39,66.3 275.81,65.89 275.81,63.36 275.27,62.81 275.27,56.53 277.36,54.43 277.36,53.6 279.4,51.57 279.4,50.59 280.6,49.38 280.6,45.16 281.11,44.65 281.55,44.65 282.34,43.86 283.75,43.86 284.03,44.14 284.54,44.14 284.86,43.83 284.86,41.67 287.84,38.68 287.84,37.87 293.47,32.24 294.66,32.24 299.27,27.63 301.81,27.63 303.4,26.05 303.4,23.82 302.63,23.06 302.33,23.06 299.8,20.53 v1(299.8,20.06)
  IN3 w0.102: v1(299.57,28.57) 301.49,26.65 301.49,20.77 301.99,20.28 v1(302.06,20.28)
  BOTTOM w0.107: JNGFF2.58 275.82,81.12 275.81,81.1 v1(275.81,80.88)
  BOTTOM w0.254: JSIM1.2 v1(299.57,28.57)
SIO_EXT_WAKE#: length 95.1
  TOP w0.107: v1(261.59,106.75) 263.21,106.75 263.91,106.04 RE703.1 ; v1(194.45,99.56) 194.03,99.99 v2(194.03,100.25) 194.39,100.61 RC748.1
  IN1 w0.099: v1(194.45,99.56) 194.77,99.24 196.88,99.24 197.15,99.51 199.13,99.51 199.59,99.06 207.12,99.06 208.14,100.07 212.64,100.07 214.25,101.68 219.64,101.68 219.99,102.03 222.92,102.03 223.23,102.34 224.74,102.34 225.05,102.66 227.13,102.66 227.8,103.33 235.21,103.33 235.65,103.76 236.46,103.76 236.88,104.18 238.81,104.18 239.21,103.77 v1(244.09,103.77)
  IN3 w0.089: 181.4,102.39 178.94,102.39 178.48,102.84 v1(178.48,102.85)
  IN3 w0.102: v1(261.59,106.75) 260.93,106.75 259.78,105.6 255.86,105.6 255.56,105.31 250.55,105.31 247.34,102.09 246.35,102.09 244.68,103.77 v1(244.09,103.77) ; 181.4,102.39 187.81,102.39 189.78,100.42 193.59,100.42 v1(194.45,99.56)
  BOTTOM w0.089: UC1.CG12 v1(178.48,102.85)
SIO_EXT_WAKE#_EC: length 10.7
  TOP w0.107: UE1.M12 255.91,100.21 256.27,100.57 256.69,100.57 257.44,101.31 257.44,103.1 v2(257.5,103.16) 259.06,104.72 261.05,104.72 261.69,105.36 262.35,105.36 262.86,105.86 RE703.2
SIO_PWRBTN#: length 269.7
  TOP w0.107: UE1.K11 254.45,99.82 254.45,99.83 v1(254.44,99.83) ; v1(202.88,91.07) 202.88,92.41 207.46,96.99 207.46,104.99 208.42,105.95 208.42,114.42 206.86,115.98 206.86,123.09 v2(206.26,123.69) 205.28,124.67 v1(205.28,126.1) ; v1(88.17,134.94) 88.17,134.87 87.82,134.52 CC269.1 RC241.1
  IN1 w0.089: 184.46,90.14 183.98,90.62 182.32,90.62 181,91.94 179.91,91.94 179.74,92.11 179.74,93.72 179.47,94 178.12,94 177.86,93.74 175.89,93.74 175.62,94 173.61,94 173.29,93.67 173.29,93.48 172.86,93.05 v1(172.86,93.05)
  IN1 w0.099: 184.46,90.14 184.77,89.84 190.06,89.84 190.59,90.36 201.51,90.36 202.22,91.07 v1(202.88,91.07) 203.68,90.27 206.48,90.27 207.26,91.04 217.33,91.04 219.36,93.08 222.69,93.08 223.53,93.92 224.31,93.92 225.08,94.69 v1(229.87,94.69)
  IN3 w0.102: v1(205.28,126.1) 205.28,126.75 204.25,127.78 204.25,128.55 203.5,129.3 197.32,129.3 196.3,130.32 183.63,130.32 183.12,129.81 181.27,129.81 179.98,128.52 164.49,128.52 161.35,125.39 159.76,125.39 158.74,124.37 157.55,124.37 157.02,123.84 150.53,123.84 149,125.38 141.56,125.38 140.95,125.99 135.46,125.99 135.32,125.84 132.48,125.84 131.73,125.09 116.38,125.09 113.91,127.56 104.67,127.56 104.26,127.98 102.24,127.98 101.54,128.67 99.68,128.67 96.85,131.51 94.24,131.51 93.86,131.13 90.04,131.13 89.88,131.29 89.48,131.68 88.66,131.68 88.33,132.02 v1(88.18,132.02)
  BOTTOM w0.089: v1(172.86,93.05) 172.82,93.05 172.82,93.01 UC1.BU28
  BOTTOM w0.107: v1(88.17,134.94) JXDP1.41 88.17,133.65 87.82,133.3 87.82,132.47 88.18,132.11 v1(88.18,132.02) ; v1(254.44,99.83) 254.44,101.1 253.75,101.79 253.75,104.71 253.27,105.19 245.13,105.19 244.27,104.33 237.59,104.33 233.29,100.03 233.29,97.47 230.51,94.69 v1(229.87,94.69)
SIO_SLP_A#: length 95
  TOP w0.107: v1(184.73,76.78) 185.95,76.78 186.37,76.36 187.25,76.36 187.36,76.25 RC233.1 CC1469.1
  IN1 w0.099: v1(184.73,76.78) 185.04,76.78 185.24,76.58 188.36,76.58 189.26,75.68 195.95,75.68 196.78,74.85 196.78,73.45 196.88,73.35 201.88,73.35 202.43,72.8 214.2,72.8 215.39,73.99 216.76,73.99 216.95,74.18 v1(217.56,74.18)
  BOTTOM w0.076: 172.66,83.95 172.66,84.72 172.4,84.98 172.4,86.48 172.37,86.52 172.37,87.59 UC1.BU37
  BOTTOM w0.107: JAPS1.6 243.24,80.58 241.87,79.22 239.49,79.22 238.38,80.33 236.23,80.33 235.43,79.53 232.08,79.53 231.12,78.57 227.61,78.57 225.71,76.67 225.16,76.67 222.67,74.18 v1(217.56,74.18) ; 172.66,83.95 172.66,82.99 173.81,81.85 v2(173.81,79.25) 173.81,77.79 175.29,76.3 183.86,76.3 184.34,76.78 184.73,76.78 v1(184.73,76.78)
SIO_SLP_LAN#: length 168.6
  TOP w0.102: v1(171.89,91.02) 171.89,91.02 171.89,91.01 171.9,91.11 172.15,91.32 172.3,91.47 172.3,91.74 172.62,92.06 173.04,92.06 173.26,91.85 173.41,91.64 173.46,91.34 173.46,90.87 173.73,90.59 173.73,89.08 174.89,87.92 177.59,87.92 178.3,87.21 178.3,86.89 179.78,85.42 ; 181.44,85.61 181.01,85.61 180.82,85.42
  TOP w0.107: 180.82,85.42 180.67,85.27 179.93,85.27 179.78,85.42 ; v1(274,71.45) 274.82,70.62 282.2,70.62 285.83,74.25 285.83,88.52 285.42,88.92 285.42,90.41 282.85,92.97 v2(282.29,92.97) 281.6,92.97 280.54,91.91 UZ43.5 ; 181.44,85.61 182.58,84.47 182.58,80.97 182.56,80.95 182.56,79.83 182.65,79.74 182.65,78.31 183.01,77.96 183.6,77.96 v1(183.61,77.94) 183.61,76.3 CC1471.1 RC761.1 RC344.1 RC68.1
  IN3 w0.102: v1(235.58,70.54) 235.22,70.18 233.97,70.18 229.61,74.54 226.8,74.54 224.14,77.2 v1(224.04,77.2)
  BOTTOM w0.089: UC1.BT31 171.59,91.35 171.87,91.15 171.89,91.01 171.89,91.02 v1(171.89,91.02)
  BOTTOM w0.107: v1(274,71.45) 271.74,71.45 270.21,69.92 269.49,69.92 268.46,68.88 268.46,67.63 267.44,66.61 266.54,66.61 266.23,66.3 258.63,66.3 256.99,67.94 244.47,67.94 241.69,70.72 235.76,70.72 v1(235.58,70.54) ; v1(183.61,77.94) 184.33,77.23 185.17,77.23 186.45,75.95 198.19,75.95 199.51,77.27 199.51,78.21 200.39,79.09 205.45,79.09 206.46,78.07 210.52,78.07 212.34,76.25 217.58,76.25 217.7,76.13 223.23,76.13 224.08,76.97 224.08,77.17 v1(224.04,77.2)
SIO_SLP_S0#: length 235.8
  TOP w0.107: UC9.2 200.57,92.02 RC660.1 RC763.1 200.59,92.76 203.75,95.92 v1(203.75,96.28) ; v1(224.9,75.15) 224.89,75.16 224.89,75.28 224.89,75.28 224.89,77.25 224.4,77.73 v1(224.4,78.5) 224.72,78.18 227.26,78.18 227.96,78.88 228.79,78.88 229.67,79.77 229.67,89.23 228.79,90.12 228.79,93.87 227.83,94.83 RZ362.2 RZ112.1 RZ1407.1 223.89,94.83 223.75,94.96 v1(223.75,95.16) ; v1(166.24,72.4) 166.24,71.74 v2(168.07,69.91) 168.55,69.43 172.21,69.43 172.6,69.03 172.6,68.31 172.99,67.92 RZ1419.1
  TOP w0.254: PR425.1 v1(107.37,70.05)
  IN1 w0.099: v1(222.24,97.75) 221.68,97.19 220.8,97.19 220.53,97.46 210.4,97.46 209.22,96.28 v1(203.75,96.28)
  IN1 w0.254: v1(118.95,81.16) 118.95,79.04 111.86,71.96 108.52,71.96 107.37,70.81 v1(107.37,70.05)
  IN3 w0.102: v1(223.75,95.16) 223.01,95.9 223.01,96.98 v1(222.24,97.75)
  BOTTOM w0.076: 167.19,77.87 168.14,78.83 168.14,85.73 167.55,86.33 167.55,87.56 UC1.BJ37
  BOTTOM w0.107: 165.21,75.89 164.96,76.14 127.7,76.14 123.43,80.4 119.25,80.4 118.95,80.7 v1(118.95,81.16) ; 165.21,75.89 167.19,77.87 ; 165.21,75.89 165.21,73.18 165.98,72.4 v1(166.24,72.4) 166.81,71.83 168.32,71.83 169.3,72.81 173.8,72.81 174.9,71.71 178.93,71.71 180.85,69.8 207.78,69.8 209.68,71.7 218.29,71.7 219.58,72.99 222.89,72.99 224.9,75.01 v1(224.9,75.15) ; v1(224.4,78.5) 224.4,78.56 224.9,79.06 225.36,79.06 227.92,81.62 230.94,81.62 233.09,83.77 236.47,83.77 237.29,82.94 238.05,82.94 238.74,83.63 JAPS1.15
SIO_SLP_S3#: length 327.5
  TOP w0.107: UE3.2 272.85,91.77 273.17,91.45 v2(273.17,89.84) 273.03,89.7 265.41,89.7 v1(265.15,89.96) ; RE280.1 255.66,78.94 253.87,78.94 253.66,78.74 UE5.1 253.66,77.9 253.56,77.8 253.23,77.8 252.74,78.29 QE11.2 251.59,78.29 251.14,78.75 251.14,79.37 250.99,79.53 249.94,79.53 249.69,79.27 249.69,77.85 v1(249.54,77.71) 249.32,77.48 248.02,77.48 v1(244.95,80.55) ; RZ1418.1 174.25,64.08 232.53,64.08 233.19,63.42 233.62,63.42 v1(233.72,63.32) ; v1(172.1,84.66) 171.39,84.66 171.06,84.34 171.06,82.62 170.51,82.07 CC1468.1 RC231.1 ; RZ1416.1 196.53,124.85 197.09,124.29 v1(197.09,123.97)
  IN1 w0.089: 178.27,80.68 178.27,80.95 176.47,82.74 174.62,82.74 173.15,84.21 172.55,84.21 v1(172.1,84.66)
  IN1 w0.099: v1(233.72,63.32) 233.62,63.42 233.19,63.42 231.9,64.72 230.82,64.72 226.84,68.69 222.47,68.69 221.38,69.78 220.81,69.78 v1(219.04,71.54) 197.73,71.54 196.1,73.17 196.1,74.57 195.67,75 188.41,75 187.52,75.88 183.25,75.88 181.73,77.4 181.41,77.4 178.27,80.55 178.27,80.68
  BOTTOM w0.076: v1(172.1,84.66) 172.24,84.81 172.24,86.41 172.21,86.45 172.21,87.82 172.46,88.28 UC1.BU36
  BOTTOM w0.107: v1(219.04,71.54) 219.04,71.79 219.49,72.24 223.8,72.24 226.58,75.01 227.03,75.01 227.84,75.82 232.13,75.82 232.87,76.56 248.4,76.56 v1(249.54,77.71) 250.96,79.12 250.96,81.25 252.28,82.56 253.28,82.56 253.55,82.82 254.45,82.82 255.95,84.32 255.95,85.26 256.7,86.02 259.27,86.02 259.92,85.37 261.23,85.37 265.15,89.28 v1(265.15,89.96) 264.86,90.25 264.86,94.18 264.45,94.59 264.45,98.96 263.22,100.19 263.22,106.78 263.85,107.41 263.85,113.55 260.67,116.73 249.3,116.73 248.11,115.53 242.09,115.53 240.21,117.41 228.38,117.41 224.33,121.46 210.71,121.46 208.93,123.24 201.15,123.24 200.41,123.97 v1(197.09,123.97) ; JAPS1.2 245.24,83.82 244.48,83.07 244.48,82.65 244.95,82.17 v1(244.95,80.55)
SIO_SLP_S4#: length 366.4
  TOP w0.107: RZ1417.1 195.97,125.27 195.97,121.37 194.13,119.53 186.86,119.53 v1(186.28,118.95) ; RC232.1 CC1467.1 190.11,75.92 190.65,76.46 191.26,76.46 192.43,77.63 192.43,77.67 v1(192.43,77.67) ; v1(245.02,61.58) 245.77,61.58 246.01,61.34 PR513.1 v2(247.04,60.91)
  IN1 w0.089: 176.48,86.74 174.01,89.21 174.01,89.72 173.28,90.44 173.28,91.83 173.02,92.09 172.56,92.09 172.44,92.2 172.44,93.24 v1(172.85,93.64) 172.85,94.19 173.46,94.8 176.1,94.8 176.21,94.69 176.21,94.03 176.33,93.9 177.23,93.9 v1(177.76,94.43)
  IN1 w0.099: 176.48,86.74 176.48,86.74 178.71,84.5 179.32,84.5 179.81,84.01 179.81,83.7 180.03,83.48 181.74,83.48 184.75,80.47 185.88,80.47 v1(186.24,80.11) ; v1(213.67,78.69) 214.12,79.13 215.33,79.13 215.96,78.5 220.84,78.5 223.09,76.26 225.88,76.26 v1(226.45,76.83)
  IN2 w0.102: v1(95.89,68.98) 96.93,67.94 96.93,62.95 97.04,62.84 101.8,62.84 105.82,58.82 132.49,58.82 134.37,56.94 134.37,56.14 136.89,53.62 136.89,50.48 137.93,49.45 137.93,47.8 139.23,46.49 148.06,46.49 148.56,46 152.89,46 153.56,45.33 155.66,45.33 157.38,43.61 163.54,43.61 166.27,40.88 172.24,40.88 173.68,42.31 214.57,42.31 214.63,42.26 224.96,42.26 225.11,42.11 237.79,42.11 237.86,42.17 243.63,42.17 244.15,42.7 246.25,42.7 247.07,43.52 247.07,44.46 247.98,45.37 247.98,46.79 247.51,47.27 247.51,58.7 245.02,61.18 v1(245.02,61.58) ; v1(226.45,76.83) 227.43,75.85 227.99,75.85 230.98,72.86 230.98,70.11 v1(231.26,69.82) ; v1(177.76,94.43) 178.19,94.86 178.19,95.49 178.19,95.49 178.19,95.83 178.19,95.83 178.19,96.3 178.28,96.4 178.28,96.76 178.66,97.14 181.83,97.14 182.14,97.44 182.14,101.91 182.32,102.1 182.32,113.14 184.96,115.77 184.96,116 185.57,116.61 185.57,118.24 v1(186.28,118.95)
  IN3 w0.102: v1(192.43,77.67) 192.71,77.4 193.85,77.4 194.51,78.05 197.12,78.05 198.05,77.12 206.33,77.12 206.69,77.48 212.47,77.48 v1(213.67,78.69)
  BOTTOM w0.089: v1(172.85,93.64) 172.85,93.62 UC1.BU27
  BOTTOM w0.107: v1(226.45,76.83) 227.96,78.34 231.22,78.34 232.18,79.29 235.52,79.29 236.25,80.02 238.36,80.02 239.4,78.98 241.97,78.98 243.74,80.75 JAPS1.5 ; v1(186.24,80.11) 190.05,80.11 191.31,78.85 191.85,78.85 192.43,78.28 192.43,77.68 v1(192.43,77.67) ; v1(245.02,61.58) 238.22,61.58 230.88,68.92 230.88,69.45 v1(231.26,69.82)
  BOTTOM w0.254: PR208.1 v1(95.89,68.98)
SIO_SLP_S4#_R: length 4.7
  BOTTOM w0.254: PC221.1 PR209.1 95.19,69.05 94.98,68.83 PR208.2 v2(93.99,68.27) 93.72,68.27 93.07,67.63 PU200.1
SIO_SLP_S5#: length 122.8
  TOP w0.107: v1(252.74,69.42) 251.77,69.42 251.43,69.76 251.25,69.76 249.77,68.27 v2(246.34,68.27) 245.29,68.27 v1(244.15,69.42) ; RC230.1 195.95,75.89 196.14,75.7 196.14,74.48 196.63,73.98 v1(197.45,73.98)
  IN1 w0.089: v1(171.85,92.37) 171.37,91.89 171.37,91.58 171.36,91.58 171.35,91.38 171.35,90.86 171.34,90.86 171.34,90.09 171.64,89.8 172.01,89.8 172.3,89.51 172.3,88.69 173.75,87.25 173.75,86.7 178.17,82.27 180.03,82.27 181.19,81.12 181.19,80.68
  IN1 w0.099: v1(244.15,69.42) 239.33,69.42 238.31,68.4 235.08,68.4 234.48,68.99 232.64,68.99 230.84,67.19 229.34,67.19 225.6,70.94 223.17,70.94 218.32,75.79 215.78,75.79 214.23,74.24 201.04,74.24 200.66,73.86 197.55,73.86 197.45,73.97 v1(197.45,73.98) 197.45,75.2 196.26,76.39 195.27,76.39 194.73,76.94 194.39,76.94 193.89,76.44 189.46,76.44 188.64,77.26 185.96,77.26 185.6,77.62 185.6,78.31 185.1,78.8 182.5,78.8 181.19,80.12 181.19,80.68
  IN2 w0.102: v1(244.5,81) 244.5,78.09 249.38,73.21 249.65,73.21 252.74,70.13 v1(252.74,69.42)
  BOTTOM w0.089: v1(171.85,92.37) 171.47,92.59 UC1.BT29
  BOTTOM w0.107: v1(244.5,81) 244.08,81.42 244.08,83.13 244.24,83.28 JAPS1.4
SIO_SLP_SUS#: length 116.6
  TOP w0.107: v1(198.81,77.82) v2(198.81,76.95) 198.81,76.27 RC441.1 198.44,75.92 RC229.1 CC1465.1 ; v1(261.68,91.62) 261.15,91.62 RE349.1
  IN1 w0.099: v1(172.83,92.47) 172.97,92.47 173.45,91.98 173.45,90.51 174.23,89.74 174.58,89.74 176.65,87.67 176.65,86.81 178.49,84.97 179.93,84.97 180.35,84.56 180.35,84.28 180.79,83.84 180.83,83.84 180.84,83.83 182.62,83.83 185.16,81.3 185.16,80.96 185.43,80.68 186.24,80.68 187.37,79.55 187.39,79.55 187.58,79.36 194.08,79.36 194.36,79.08 197.07,79.08 198.33,77.82 v1(198.81,77.82) 198.81,77.8 199.73,76.88 205.54,76.88 206.81,78.16 219.31,78.16 219.84,77.62 221.43,76.03 226.22,76.03 227.13,76.94 228.72,76.94 228.82,76.84 v1(228.82,76.47)
  BOTTOM w0.076: UC1.BU29 v1(172.83,92.47)
  BOTTOM w0.107: v1(261.68,91.62) 262.44,90.85 262.44,87.96 261.55,87.07 259.71,87.07 259.26,86.62 255.95,86.62 254.9,85.57 254.9,84.29 254.15,83.55 253.21,83.55 252.95,83.28 252.34,83.28 250.2,81.15 250.2,79.28 247.96,77.03 238.59,77.03 237.55,78.07 237.05,78.07 236.33,77.34 232.99,77.34 232.03,76.39 228.9,76.39 v1(228.82,76.47)
SIO_SLP_SUS#_R: length 5.1
  TOP w0.102: RE561.1 RE349.2 259.27,91.84 v2(258.87,92.24) 257.72,93.39 256.87,93.39 UE1.N4
SIO_SLP_WLAN#: length 125.6
  TOP w0.107: v1(192.83,76.85) 192.64,76.65 192.53,76.65 RC234.1 CC1470.1 ; QZ15.1 v2(269.3,71.23) 269.3,70.8 v1(269.17,70.67)
  IN1 w0.089: v1(171.84,91.7) 171.83,91.7 171.83,91.67 171.51,91.36 171.51,90.8 171.51,90.79 171.51,90.2 171.75,89.96 172.08,89.96 172.47,89.57 172.47,88.84 174.05,87.26 174.05,86.62 176.88,83.79 178.13,83.79 178.37,83.55
  IN1 w0.099: 178.37,83.55 178.37,83.4 178.72,83.05 ; v1(192.83,76.85) 193.98,76.85 194.3,77.16 194.88,77.16 195.42,76.62 196.82,76.62 198.97,74.47 214.14,74.47 215.68,76.01 218.42,76.01 223.23,71.19 225.66,71.19 228.14,68.72 229.53,68.72 231.11,70.3 232.16,70.3 233.22,69.23 235.88,69.23 v1(236.15,68.97)
  IN1 w0.102: v1(192.83,76.85) 192.77,76.78 189.43,76.78 188.73,77.49 186.06,77.49 185.83,77.71 185.83,78.4 185.2,79.03 183.49,79.03 181.78,80.74 181.78,82.13 181.22,82.69 179.07,82.69 178.72,83.05
  BOTTOM w0.089: v1(171.84,91.7) 171.83,91.7 171.49,91.88 UC1.BT30
  BOTTOM w0.107: v1(236.15,68.97) 235.17,69.94 235.17,70.71 235.41,70.95 241.78,70.95 244.57,68.17 257.09,68.17 258.73,66.53 266.13,66.53 266.45,66.84 267.34,66.84 268.22,67.73 268.22,68.98 269.17,69.93 v1(269.17,70.67)
SKP_DET#: length 10
  TOP w0.102: 183.17,85.42 181.85,86.74 v1(179.98,86.74)
  TOP w0.107: 183.17,85.42 183.74,84.85 T384.1
  BOTTOM w0.076: UC1.CK34 179.85,88.79 179.68,88.63 179.68,87.88 179.62,87.82 179.62,87.57 179.91,87.28 179.91,86.81 v1(179.98,86.74)
SKTOCC#: length 5.7
  BOTTOM w0.076: UC1.E1 140.43,111.07 140.01,111.49 140.01,112.72 139.63,113.1 RC565.1 139.63,113.68 140.1,114.15 v2(140.1,115.52)
SLEEVE: length 16.8
  TOP w0.127: v1(296.29,37.41) v2(295.68,37.41)
  IN3 w1.27: 291.65,53.35 294.38,50.62 294.38,41.86 296.41,39.82 296.41,39.13
  vias: v1(289.43,53.1) v1(290.01,53.1) v1(290.6,53.1) v1(296.16,37.99) v1(296.73,37.86)
SLEEVE_R: length 19.5
  TOP w0.127: v1(302.51,39.62) 302.51,40.22 v2(302.24,40.49)
  IN3 w0.508: JHP1.3 311.43,39.35 310.55,40.23 302.87,40.23 302.51,39.87 v1(302.51,39.62)
  BOTTOM w0.508: v1(303.21,39.62) 303.82,40.23 310.55,40.23 311.43,39.35 JHP1.3
SLOT2_SATA_LED#: length 4.1
  TOP w0.107: v1(261.73,80.15) 261.78,80.1 RN101.1 262.05,79.53 v2(262.78,78.79)
  BOTTOM w0.107: v1(261.73,80.15) 262.12,80.54 262.12,81.1 261.82,81.4 JNGFF2.10
SLP_WLAN#_GATE: length 45
  TOP w0.107: QZ15.2 270.93,74.3 RZ518.2 271.16,74.53 271.16,75.48 v1(271.03,75.6) ; v1(261.23,110.97) 260.77,110.51 RE552.1
  IN2 w0.102: v1(271.03,75.6) 271.03,76.11 270.3,76.84 270.3,82.38 269.8,82.89 269.8,89.6 270.95,90.76 270.95,96.53 269.58,97.9 269.58,101.27 268.09,102.75 268.09,105.16 263.22,110.03 261.82,110.03 261.23,110.62 v1(261.23,110.97)
SLP_WLAN#_GATE_R: length 21.4
  TOP w0.107: v1(258.92,107.77) 259.61,107.77 260.03,108.19 RE552.2
  TOP w0.127: UE1.K10 v1(254.43,99)
  IN3 w0.089: v1(254.43,99) 254.78,99.35 255.96,99.35 256.76,98.55
  IN3 w0.102: v1(260.72,97.85) 260.65,97.92 258.2,97.92 258.02,98.11 257.2,98.11 256.76,98.55
  BOTTOM w0.107: v1(258.92,107.77) 259.08,107.61 v2(259.08,106.79) 259.08,105.88 260.78,104.18 260.78,102.59 260.78,99.08 260.34,98.64 260.34,98.06 260.55,97.85 v1(260.72,97.85)
SLP_WLAN#_M: length 6
  TOP w0.107: QZ15.3 268.65,73.91 268.42,73.68 266.18,73.68 265.85,74 DZ9.3 265.85,75.07 RZ71.1 v2(265.55,76.45)
SM_RCOMP0: length 1.7
  TOP w0.254: RC5.1 169.41,93.63 170.04,93 v1(170.09,93)
  BOTTOM w0.203: UC1.BN28 v1(170.09,93)
SM_RCOMP1: length 2.2
  TOP w0.381: RC504.1 170.06,95.17 170.06,93.67 170.06,93.67 v1(170.06,93.64)
  BOTTOM w0.203: UC1.BN27 170.06,93.66 v1(170.06,93.64)
SM_RCOMP2: length 1.6
  TOP w0.254: RC7.1 169.36,92.9 169.89,92.37 v1(170.09,92.37)
  BOTTOM w0.203: UC1.BN29 v1(170.09,92.37)
SML0_SMBCLK: length 111.5
  TOP w0.107: v1(194.11,102.18) 194.11,102.5 194.7,103.09 RC506.1 RC347.1 CC318.1 ; v1(272.99,111.49) 272.86,111.36 UL1.28
  IN1 w0.089: 191.11,102.04 191.01,101.93 191.01,101.93 191.01,101.92 190.69,101.6 189.62,101.6 188.54,102.68 184.2,102.68 183.94,102.42 180.6,102.42 180.59,102.44 179.1,102.44 179.01,102.52 179.01,102.77 v1(179.07,102.82)
  IN1 w0.099: 191.11,102.04 191.22,102.15 192.82,102.15 193.19,101.77 194.02,101.77 194.11,101.87 v1(194.11,102.18) 194.4,101.96 195.1,101.96 196.09,100.96 197.81,100.96 198.46,100.31 199.74,100.31 200.29,99.77 205.16,99.77 206.51,101.11 210.32,101.11 210.88,101.67 213.24,101.67 214.74,103.17 219.16,103.17 219.27,103.07 224.46,103.07 224.76,103.36 226.84,103.36 227.51,104.04 234.92,104.04 235.35,104.47 236.11,104.47 236.59,104.95 239.19,104.95 239.66,104.48 243.4,104.48 244.43,105.51 244.43,106.33 v1(244.2,106.56)
  IN3 w0.102: v1(244.2,106.56) 244.41,106.77 244.41,107.88 248.58,112.06 258.36,112.06 260.62,109.79 263.48,109.79 263.93,109.34 266.02,109.34 266.84,110.16 269.19,110.16 271.43,112.39 272.15,112.39 272.39,112.16 272.39,111.59 272.49,111.49 v1(272.99,111.49)
  BOTTOM w0.076: v1(179.07,102.82) 178.94,102.69 UC1.CH14
SML0_SMBDATA: length 110.2
  TOP w0.107: v1(194.35,101.31) 194.84,101.31 RC348.1 RC20.1 ; UL1.31 v1(271.66,111.49)
  IN1 w0.089: v1(177.8,101.8) 178.25,102.26 180.52,102.26 180.53,102.24 184.02,102.24 184.27,102.5 188.46,102.5 189.54,101.42 190.76,101.42 191.11,101.77 191.11,101.77
  IN1 w0.099: v1(244.79,106.56) 244.66,106.44 244.66,105.42 243.49,104.25 239.57,104.25 239.09,104.72 236.69,104.72 236.21,104.24 235.45,104.24 235.01,103.81 227.6,103.81 226.93,103.14 224.86,103.14 224.56,102.84 219.17,102.84 219.07,102.95 214.83,102.95 213.33,101.45 210.97,101.45 210.41,100.89 206.6,100.89 205.25,99.54 200.2,99.54 199.65,100.09 198.37,100.09 197.72,100.74 196,100.74 195,101.74 194.6,101.74 v1(194.35,101.31) 194.12,101.55 193.1,101.55 192.72,101.92 191.31,101.92 191.17,101.77 191.12,101.77 191.11,101.77
  IN3 w0.102: v1(271.66,111.49) 272.05,111.49 272.16,111.59 272.16,112.06 272.05,112.16 271.52,112.16 269.29,109.93 266.93,109.93 266.11,109.11 263.84,109.11 263.38,109.56 260.53,109.56 258.26,111.83 248.68,111.83 244.64,107.79 244.64,106.72 244.66,106.7 244.66,106.69 v1(244.79,106.56)
  BOTTOM w0.089: UC1.CF15 177.8,101.45 v1(177.8,101.8)
SML0B_SMBCLK: length 11
  BOTTOM w0.076: UC1.CN23 182.33,96.24 182.37,96.22 182.66,96.22 182.69,96.24 183.01,96.24 184.49,95.71 186.43,95.71 186.57,95.85 186.72,95.85
  BOTTOM w0.107: 186.72,95.85 v2(187.09,95.85) 187.49,95.85 187.56,95.78 190.88,95.78 191.27,96.17 RC829.1 CC1476.1
SML0B_SMBDATA: length 9.9
  BOTTOM w0.076: UC1.CM24 180.9,95.93 181.13,96.17 181.85,96.17 181.94,96.08 182.29,96.08 182.38,96.04 182.42,96 182.61,96 182.64,96.03 182.73,96.08 182.96,96.08 184.7,95.36 186.72,95.36
  BOTTOM w0.107: 186.72,95.36 187.28,95.36 187.45,95.2 v2(188.53,95.2) RC830.1
SML1_SMBCLK: length 78.6
  TOP w0.089: UE1.D8 v1(248.85,97.41)
  IN1 w0.089: 191.11,100.11 191.11,100.11 191.02,100.02 188.91,100.02 188.52,100.41 188.04,100.41 187.93,100.39 187.85,100.29 v1(187.89,100.02)
  IN1 w0.099: v1(242.34,102.91) 242.18,102.75 242.18,102.22 241.88,101.92 240.83,101.92 239.81,102.94 235.9,102.94 234.94,101.99 227.58,101.99 226.9,101.31 225.72,101.31 225.56,101.47 224.51,101.47 224.01,100.98 214.54,100.98 212.93,99.37 208.64,99.37 207.07,97.8 199.13,97.8 198.48,98.44 194.38,98.44 193.13,99.7 192.66,99.7 192.25,100.11 191.11,100.11
  IN3 w0.089: v1(248.85,97.41) 248.3,96.87 247.66,96.87 246.6,97.92
  IN3 w0.102: 246.6,97.92 243.81,100.72 243.81,101.51 243.35,101.97 242.64,101.97 242.21,102.39 242.21,102.78 v1(242.34,102.91)
  BOTTOM w0.076: 186.03,101.25 184.42,101.25 184.32,101.14 184,101.14 183.85,101.3 182.72,101.3 182.61,101.26 182.42,101.26 181.96,101.42 UC1.CN15
  BOTTOM w0.107: 186.03,101.25 186.11,101.17 186.75,101.17 v2(187.2,100.72) v1(187.89,100.02) 188.2,100.02 CC319.1 RC15.1
SML1_SMBDATA: length 81.7
  TOP w0.107: v1(249.64,99.82) 250.05,99.42 UE1.E11
  IN1 w0.089: v1(187.76,100.91) 187.8,100.64 187.9,100.57 187.95,100.57 187.96,100.58 188.03,100.59 188.6,100.59 188.98,100.2 190.94,100.2 191.08,100.34 191.11,100.34
  IN1 w0.099: 191.11,100.34 192.34,100.34 192.76,99.92 193.23,99.92 194.48,98.67 198.58,98.67 199.22,98.03 206.98,98.03 208.55,99.59 212.84,99.59 214.45,101.2 223.92,101.2 224.42,101.7 225.65,101.7 225.82,101.53 226.8,101.53 227.48,102.21 234.85,102.21 235.8,103.17 239.9,103.17 240.93,102.14 241.79,102.14 241.96,102.31 241.96,102.7 v1(241.75,102.91)
  IN3 w0.089: 246.6,97.6 247.55,96.65 248.39,96.65 248.71,96.97 248.94,96.97 249.22,97.26 249.22,98.04 249.23,98.05 249.23,99.41 v1(249.64,99.82)
  IN3 w0.102: v1(241.75,102.91) 241.98,102.68 241.98,102.3 242.54,101.74 243.26,101.74 243.58,101.41 243.58,100.62 246.6,97.6
  BOTTOM w0.076: UC1.CM15 181.48,101.79 181.96,101.79 182.07,101.74 182.31,101.74 182.42,101.79 182.61,101.79 182.72,101.74 183.85,101.74 184.22,102.11 186.25,102.11 186.37,101.99 186.66,101.99 187.74,100.91 187.76,100.91
  BOTTOM w0.107: RC507.1 188.15,100.53 v1(187.76,100.91) 187.76,100.91
SNUB1_CHG: length 2.8
  BOTTOM w0.107: v2(103.96,42.99) 104.33,42.62 PC746.1
  BOTTOM w0.635: PC746.1 106.55,42.62 PR717.2
SNUB1_IA: length 1.6
  TOP w0.107: PR663.2 v2(114.74,107.35)
SNUB2_CHG: length 2.3
  BOTTOM w0.107: PC747.1 122.42,42.59 v2(122.75,42.92)
  BOTTOM w0.635: PC747.1 PR718.2
SNUB2_IA: length 1.1
  TOP w0.107: v2(99.31,111.12) 99.44,111 PC678.1
SNUB_1.05VALWP: length 1.6
  BOTTOM w0.107: PR303.2 v2(226.5,127.1)
SNUB_1.8VALW: length 1
  BOTTOM w0.107: PC506.1 200.45,115.82 v2(200.52,115.89)
SNUB_1V_PRIM_CORE: length 2.2
  BOTTOM w0.107: PR409.2 v2(205.61,129.33)
  BOTTOM w0.508: PR409.2 PC419.1
SNUB_1VS_VCCIO: length 1.4
  TOP w0.107: v2(111.63,79.36) 111.07,79.36 110.6,78.89 PC401.1
SNUB_3V: length 1.9
  TOP w0.107: PR106.2 202.94,35.88 v2(203.28,36.22)
SNUB_5V: length 0.9
  BOTTOM w0.107: 87.3,80.97 87.3,81.51 v2(87.59,81.8)
SNUB_DDR: length 1.5
  TOP w0.107: PC204.1 90.81,66.93 89.96,67.78 v2(89.73,67.78)
SNUB_GT: length 1.2
  TOP w0.107: PC670.1 110.87,90.82 v2(110.73,90.96)
SNUB_SA: length 2.4
  BOTTOM w0.107: v2(179.69,131.77) 179.56,131.9 PC622.1
  BOTTOM w0.508: PC622.1 PR627.2
SPKR: length 146.8
  TOP w0.107: RA12.2 v1(291.73,46)
  IN1 w0.089: 181.48,80.68 181.48,81.06 180.04,82.5 178.87,82.5 177.98,83.4 v1(177.98,83.43)
  IN1 w0.099: v1(181.73,80.21) 181.48,80.46 181.48,80.68
  IN2 w0.102: v1(210.56,79.07) 210.56,78.56 210.66,78.46 211.7,78.46 212.37,79.13 214.74,79.13 216.71,77.16 220.12,77.16 225.58,71.7 225.58,70.41 228.14,67.85 230.29,67.85 233.45,64.69 245.45,64.69 246.22,63.92 247.51,63.92 250.28,61.15 250.28,59.2 v1(249.85,58.78)
  BOTTOM w0.076: UC1.CF35 177.17,88.67 177.17,88.04 177.07,87.84 177.07,87.48 177.41,87.13 177.41,86.84 177.24,86.67 177.24,85.88 178.1,85.02 178.1,84 177.98,83.87 v1(177.98,83.43) 178.2,83.43 RC183.1
  BOTTOM w0.107: v1(291.73,46) 290.49,44.76 286.58,44.76 284.68,46.65 278.17,46.65 275.84,48.99 269.21,48.99 266.54,51.66 262.72,51.66 262.12,52.26 262.12,54.27 258.74,57.65 250.97,57.65 v1(249.85,58.78) ; v1(210.56,79.07) 210.5,79.07 209.99,78.56 206.81,78.56 205.8,79.58 200.22,79.58 199.13,78.49 198.43,78.49 196.88,76.94 194.39,76.94 193.72,76.27 186.45,76.27 185.27,77.46 184.74,77.46 183.19,79 182.94,79 v2(182.41,79.53) v1(181.73,80.21)
SPKR_R: length 2.6
  TOP w0.203: RA12.1 RA51.1 CA72.1 290.77,48.37 CA27.1
SRTCRST#: length 16.1
  TOP w0.107: RC56.1 CC24.1 174.09,75.17 173.98,75.28 172.93,75.28 v1(172.74,75.47)
  BOTTOM w0.076: UC1.BR37 171.05,87.49 171.05,87.42 171,87.37 171,85.94 171.19,85.76 171.19,85.6 171.25,85.54 171.25,84.15 170.75,83.64 170.75,81.01 171.51,80.25 v2(171.51,80.21) 171.51,77.04 172.4,76.15
  BOTTOM w0.107: 172.4,76.15 172.43,76.12 172.43,76.11 172.63,75.92 172.63,75.9 172.67,75.87 172.67,75.53 v1(172.74,75.47)
SS_1V_PRIM_CORE: length 1.4
  TOP w0.254: PR428.1 209.35,128.53 209.16,128.73 PU402.7
SS_1VS_VCCIO: length 2.4
  TOP w0.254: PU401.7 105.47,77.71 v2(105.8,78.04) 105.8,78.46 105.34,78.92 PR427.1
SSD_EN: length 16.2
  TOP w0.107: UZ54.4 257.54,39.4 257.23,39.7 v2(257.23,39.77) 257.23,40.33 257.61,40.71 RZ1471.2 257.83,40.37 258.08,40.12 v1(258.55,40.12) ; v1(256.09,42.85) 255.92,42.67 254.3,42.67 253.74,42.11 253.74,39.25 254.31,38.68 255.94,38.68 256.22,38.4 UZ53.3
  BOTTOM w0.107: v1(258.55,40.12) 256.09,42.58 v1(256.09,42.85)
SSD_SCP#: length 111.3
  TOP w0.107: RE821.1 272.39,93.55 v1(272.18,93.33) ; v2(272.88,25.37) 273.37,24.88 v1(273.69,24.88) 274.48,24.88 RN129.2 ; UE1.L6 v1(255.23,95.03)
  IN1 w0.099: v1(273.69,24.88) 270.7,24.88 270.13,25.45 269.13,25.45 265.71,28.87 265.71,31.63 266.4,32.32 271.06,32.32 271.65,32.9 276.47,32.9 278.95,35.38 v1(278.95,36.65)
  IN2 w0.102: v1(272.18,93.33) 272.66,92.84 272.66,86.94 272.45,86.73 272.45,84.96 272.82,84.59 272.82,82.75 271.61,81.53 271.61,78.35 272.3,77.66 272.3,74.04 271.56,73.3 271.56,62.78 272.22,62.12 272.22,56.72 275.34,53.6 275.34,52.84 276.47,51.7 276.47,48.65 278.95,46.17 v1(278.95,36.65)
  IN3 w0.089: v1(255.23,95.03) 256.08,94.18 256.27,94.18 257.07,93.39 259.25,93.39 259.38,93.52 260.32,93.52
  IN3 w0.102: v1(272.18,93.33) 271.95,93.1 267.46,93.1 267.01,92.66 262.58,92.66 261.72,93.52 260.32,93.52
SSD_SCP_PWR_EN: length 59
  TOP w0.107: QZ22.3 260.92,42.54 260.92,44.79 261.18,45.04 v2(262.62,45.04) 262.91,45.04 v1(263.27,44.69) ; v1(255.96,90.35) 255.65,90.67 UE1.M1
  IN2 w0.089: 260.76,87.93 260.29,88.39 257.06,88.39 255.96,89.49 v1(255.96,90.35)
  IN2 w0.102: 260.76,87.93 260.85,87.83 260.85,83.26 260.22,82.62 260.22,78.74 260.69,78.27 260.69,76.5 260.57,76.38 260.57,73.63 261.23,72.96 261.23,64.26 264.35,61.15 264.35,59.7 263.98,59.34 263.98,49.27 264.43,48.81 264.43,45.6 263.7,44.87 263.45,44.87 v1(263.27,44.69)
SSD_SCP_PWR_EN_D: length 9.3
  TOP w0.107: UZ54.2 259.58,38.75 259.27,39.06 259.27,40.38 RZ1472.2 258.94,40.71 RZ1471.1 258.42,40.92 257.18,42.15 RZ1474.1 257.18,42.82 v2(258.17,43.81) 258.56,44.2 QZ22.1
SUSCLK: length 211.6
  TOP w0.102: 172.23,86.85 172.23,89.64 171.89,89.99 v1(171.89,90.43)
  TOP w0.107: v1(283.14,44.27) 283.23,44.19 283.74,44.19 RZ56.1 ; RC48.1 180.56,74.28 CC93.2 181.3,74.36 181.3,76.89 180.96,77.24 180.96,78.86 180.19,79.63 v2(180.19,79.74) 180.19,81.37 179.79,81.77 178.84,81.77 177.33,83.28 177.33,83.8 176.67,84.46 176.67,85.35 177.08,85.77 177.08,85.98 176.72,86.34 172.74,86.34 172.73,86.34 172.27,86.8 172.27,86.82 172.23,86.85 ; RN99.2 270.75,25.55 270.95,25.35 v1(270.95,23.95)
  IN1 w0.099: v1(171.89,90.43) 172.64,89.68 172.64,89.24 174.24,87.64 174.68,87.64 175.35,86.97 175.35,85.57 176.95,83.96 178.36,83.96 178.57,83.75 178.57,83.45 179.14,82.87 181.63,82.87 182.68,81.81 182.68,80.52 183.69,79.51 185.48,79.51 185.93,79.07 186.5,79.07 186.97,78.59 186.99,78.59 187.18,78.4 193.68,78.4 193.96,78.12 196.67,78.12 198.87,75.92 206.84,75.92 206.9,75.98 208.64,75.98 208.74,76.08 210.39,76.08 210.56,76.25 214.92,76.25 215.39,76.72 218.71,76.72 221.38,74.05 223.8,74.05 228.43,69.42 229.24,69.42 230.82,71 232.79,71 233.42,70.37 234.82,70.37 235.4,70.94 235.41,70.94 235.41,70.95 235.75,70.95 235.76,70.94 236.3,70.94 236.61,70.62 v1(236.61,69.4) ; v1(272.75,53.01) 272.82,52.95 272.82,48.86 273.4,48.27 273.4,37.6 273,37.2 269.15,37.2 268.24,36.29 266.04,36.29 264.78,35.02 264.78,32.22 265.23,31.76 265.23,28.67 268.94,24.97 269.93,24.97 v1(270.95,23.95)
  IN3 w0.102: v1(283.14,44.27) 282.95,44.27 282.67,44.55 279.02,44.55 274.98,48.59 274.98,50.74 272.75,52.97 v1(272.75,53.01)
  BOTTOM w0.089: v1(171.89,90.43) 171.82,90.43 UC1.BT32
  BOTTOM w0.107: v1(272.75,53.01) 271.54,53.01 270.16,54.39 270.16,60.57 270.87,61.28 270.87,62.27 269.5,63.64 267.48,63.64 266,62.16 259.34,62.16 256.88,64.62 248.44,64.62 247.96,64.14 246.61,64.14 244.74,66.02 243.68,66.02 241.72,67.98 239.43,67.98 237.61,69.8 237.01,69.8 v1(236.61,69.4)
SUSCLK_R: length 8.5
  TOP w0.107: v2(271.45,24.36) 271.45,23.82 271.14,23.52 270.62,23.52 v1(270.19,23.95) RN99.1
  BOTTOM w0.107: JNGFF3.68 266.07,22 266.26,22.18 268.42,22.18 v1(270.19,23.95)
SVID_ALERT#_PWR_CPU: length 2.4
  TOP w0.203: PR625.2 89.7,101.31 89.7,100.3 89.52,100.13 PU602.36
SVID_CLK_PWR_CPU: length 2.5
  TOP w0.203: PR618.2 89.18,100.93 v2(89.18,100.48) 89.12,100.42 PU602.37
SVID_DAT_PWR_CPU: length 2.5
  TOP w0.203: PU602.35 89.92,99.95 v2(90.48,100.51) 90.5,100.54 90.5,101.39 PR626.2
SW_USB20_N2: length 1.7
  TOP w0.097: LI7.1 292.63,66.57 292.63,67.03 292.63,67.24 292.79,67.4 UI3.11
SW_USB20_P2: length 1.7
  TOP w0.097: UI3.10 292.29,67.4 292.45,67.24 292.45,67.11 292.45,66.57 LI7.4
SYS_PWROK: length 120.7
  TOP w0.107: v1(188.49,105.13) v3(188.08,104.72)
  IN1 w0.089: 190.27,104.36 190.22,104.4 189.82,104.4 189.5,104.72 188.9,104.72 v1(188.49,105.13)
  IN1 w0.099: v1(251.84,87.27) 252.31,87.27 252.76,86.82 259.58,86.82 259.9,87.13 261.87,87.13 262.36,87.62 262.36,90.52 262.76,90.92 262.76,93.6 263.7,94.53 263.7,98.66 261.5,100.85 261.5,101.96 261.49,101.98 260.14,103.33 259.66,103.33 256.45,106.54 256.45,106.72 255.76,107.4 246.69,107.4 246.34,107.05 244.11,107.05 242.45,105.38 239.99,105.38 239.64,105.73 234.96,105.73 234.36,105.13 224.95,105.13 224.07,104.25 223.19,104.25 222.78,104.65 215.52,104.65 215.11,105.06 214.4,105.06 213.99,104.66 213.35,104.66 213.04,104.97 206.62,104.97 205.57,103.92 205.57,103.92 205.33,103.68 205.33,103.68 203.59,101.94 198.74,101.94 198.38,102.3 198.38,102.5 197.94,102.94 195.83,102.94 195.45,103.32 195.45,103.58 194.47,104.56 193.95,104.56 193.12,103.73 190.9,103.73 190.27,104.36
  BOTTOM w0.076: 186.72,104.97 186.14,104.97 186.03,105.07 184.31,105.07 184.05,104.82 182.96,104.82 UC1.CR10
  BOTTOM w0.089: RE548.1 251.65,87.46 v1(251.84,87.27)
  BOTTOM w0.107: RC129.1 191.83,103.78 191.57,104.03 191.26,104.03 190.12,105.17 188.54,105.17 v1(188.49,105.13) 188.33,104.97 186.72,104.97 ; RE56.1 251.98,86.97 251.98,87.12 v1(251.84,87.27)
SYS_RESET#: length 84
  IN1 w0.099: v1(212.4,104.57) 212.8,104.17 222.58,104.17 222.99,103.77 224.27,103.77 225.15,104.65 234.86,104.65 235.3,105.1 v1(235.87,105.1)
  IN3 w0.102: v1(191.54,103.32) 191.69,103.17 192.38,103.17 193.67,104.47 194.52,104.47 196.04,102.94 200.02,102.94 200.63,103.55 202.04,103.55 203.44,104.95 209.17,104.95 209.56,104.57 v1(212.4,104.57) ; v1(238.92,86.41) 238.11,87.22 238.11,91.26 237.27,92.11 237.27,95.11 235.3,97.09 235.3,100.26 235.57,100.53 235.57,104.8 v1(235.87,105.1)
  BOTTOM w0.076: UC1.CN10 181.68,104.47 181.98,104.47 182.1,104.43 182.28,104.43 182.4,104.47 182.63,104.47 182.75,104.43 182.98,104.43 183.21,104.66 184.12,104.66 184.38,104.91 185.78,104.91 186.21,104.48 186.72,104.48
  BOTTOM w0.107: v1(238.92,86.41) 239.48,86.41 v2(239.53,86.37) 240.09,85.81 240.09,85.06 239.74,84.71 JAPS1.13 ; CC302.1 192.26,101.95 RC243.2 191.79,103.29 191.57,103.29 v1(191.54,103.32) 191.31,103.55 191.06,103.55 189.92,104.69 189.19,104.69 188.99,104.48 186.72,104.48
SYSPWR_PRES: length 9
  TOP w0.107: UE1.B1 247.6,91.41 246.96,90.77 246.85,90.77 246.11,90.03 245.97,90.03 244.98,89.05 244.98,87.54 244.22,86.78 v2(243.68,86.78) 243.16,86.78 242.76,86.37 RE58.1 242.13,85.99 RE57.1
SYSTEM_ID: length 25.1
  TOP w0.107: v1(257.98,108.58) 258.22,108.82 RE300.2 258.22,110.1 258.64,110.51 CE47.1 259.14,111 v2(259.86,111.72)
  TOP w0.127: v1(253.64,99.01) UE1.J10
  IN3 w0.089: 256.76,98.87 256.1,99.54 254.7,99.54 254.54,99.37 253.98,99.37 253.64,99.03 v1(253.64,99.01)
  IN3 w0.102: v1(260.75,98.43) 260.73,98.43 260.44,98.15 258.3,98.15 258.11,98.34 257.3,98.34 256.76,98.87
  BOTTOM w0.107: v1(257.98,108.58) 258.14,108.74 258.95,108.74 259.48,108.2 259.48,105.82 261.02,104.28 261.02,98.7 v1(260.75,98.43)
TACH_FAN1: length 314.8
  TOP w0.127: UE1.E3 v1(249.67,92.64)
  TOP w0.254: v1(80.41,59.08) 81.11,59.08 DE22.3 81.22,58.67 80.97,58.42 v1(80.41,58.42)
  IN2 w0.089: v1(249.67,92.64) 249.67,92.22 250.45,91.44 250.45,90.12 249.8,89.48 249.5,89.48 247.66,87.64 247.66,86.98
  IN2 w0.102: v1(76.98,56.28) 76.53,55.82 76.53,53.31 76.98,52.85 76.98,49.32 77.24,49.06 77.24,46.84 79.09,44.99 79.09,44.5 79.08,44.49 79.08,44.48 78.84,44.24 78.84,44.24 78.53,43.94 78.53,42.23 78.65,42.11 79.41,42.11 80.03,42.73 80.03,49.54 81.75,51.26 90.06,51.26 92.13,53.33 96.57,53.33 100.88,57.64 127.68,57.64 128.28,57.04 131.24,57.04 133.57,54.71 134.51,54.71 135.28,53.94 135.28,48.28 136.33,47.22 137.21,47.22 138.8,45.63 138.8,44.83 139.29,44.34 154.18,44.34 156.51,42.01 162.94,42.01 162.97,41.98 167.53,37.42 177.93,37.42 183.2,32.16 193.3,32.16 197.17,36.03 197.48,36.03 198.94,37.48 198.94,37.71 200.12,38.89 204.54,38.89 204.81,39.15 209.79,39.15 210.45,38.49 215.94,38.49 215.99,38.44 221.59,38.44 223.18,36.86 223.91,36.86 224.71,36.06 224.71,33.54 226.24,32.01 230.07,32.01 232.06,34 239.2,34 239.75,33.45 242.51,33.45 243.12,32.84 254.98,32.84 258.06,35.92 258.06,37.87 260.22,40.02 260.22,40.85 260.62,41.25 260.62,45.18 261.07,45.63 261.07,50.26 262.04,51.23 262.04,61.07 258.68,64.42 258.68,65.4 258.17,65.91 258.17,70.19 254.44,73.92 253.76,73.92 251.76,75.92 250.99,75.92 250.32,76.6 250.08,76.6 249.08,77.6 249.08,79.19 250,80.12 250,82.86 248.76,84.1 248.76,85.61 247.66,86.72 247.66,86.98
  BOTTOM w0.254: v1(80.41,58.42) 78.27,56.28 v1(76.98,56.28) 74.78,56.28 74.21,55.71 RE51.2 ; v1(80.41,59.08) 81.08,59.75 81.08,61.17 79.62,62.63 JFAN1.3
TBT_DET#: length 8.4
  BOTTOM w0.076: UC1.CM22 181.26,97.41 182.38,97.41 182.65,97.55 183,97.55 183.07,97.51 185.46,97.51 RC401.1 186.47,97.99 186.72,97.74
  BOTTOM w0.107: RC400.1 188.02,97.23 v2(187.63,97.62) 187.51,97.74 186.72,97.74
TBTA_BOT_N: length 55.1
  IN3 w0.089: v1(61.14,108.07) 60.92,108.06 60.57,107.71 60.57,107.33 60.45,107.2 58.63,107.2 57.07,105.64 57.07,104.4 56.5,103.83 55.88,103.83 55.3,103.24 55.3,101.3 47.94,93.93 29.86,93.93 27.15,96.64 27.15,99.54 26.76,99.93 26.18,99.93 25.96,99.71 v1(25.96,99.07)
  BOTTOM w0.076: v1(61.14,108.07) 60.98,108.07 60.76,107.84 60.76,107.22 60.83,107.15 UT5.L7
  BOTTOM w0.097: v1(25.96,99.07) 26.36,99.47 26.36,99.95 24.31,102 23.28,102 22.89,101.61 RT122.2
TBTA_BOT_N_R: length 18.8
  TOP w0.097: JUSBC1.A7 7.76,106.82 7.91,106.97 10.45,106.97 v1(10.66,106.76)
  IN2 w0.089: v1(10.66,106.76) 10.84,106.95 11.36,106.95 11.62,106.69 16.46,106.69 17.24,105.91 17.24,103.66 17.87,103.03 v1(17.87,102.46)
  BOTTOM w0.097: RT122.1 21.7,101.86 21.14,101.86 20.99,101.72 DT40.2 DT40.8 19.17,101.72 19.15,101.73 18.81,101.73 18.09,102.46 v1(17.87,102.46)
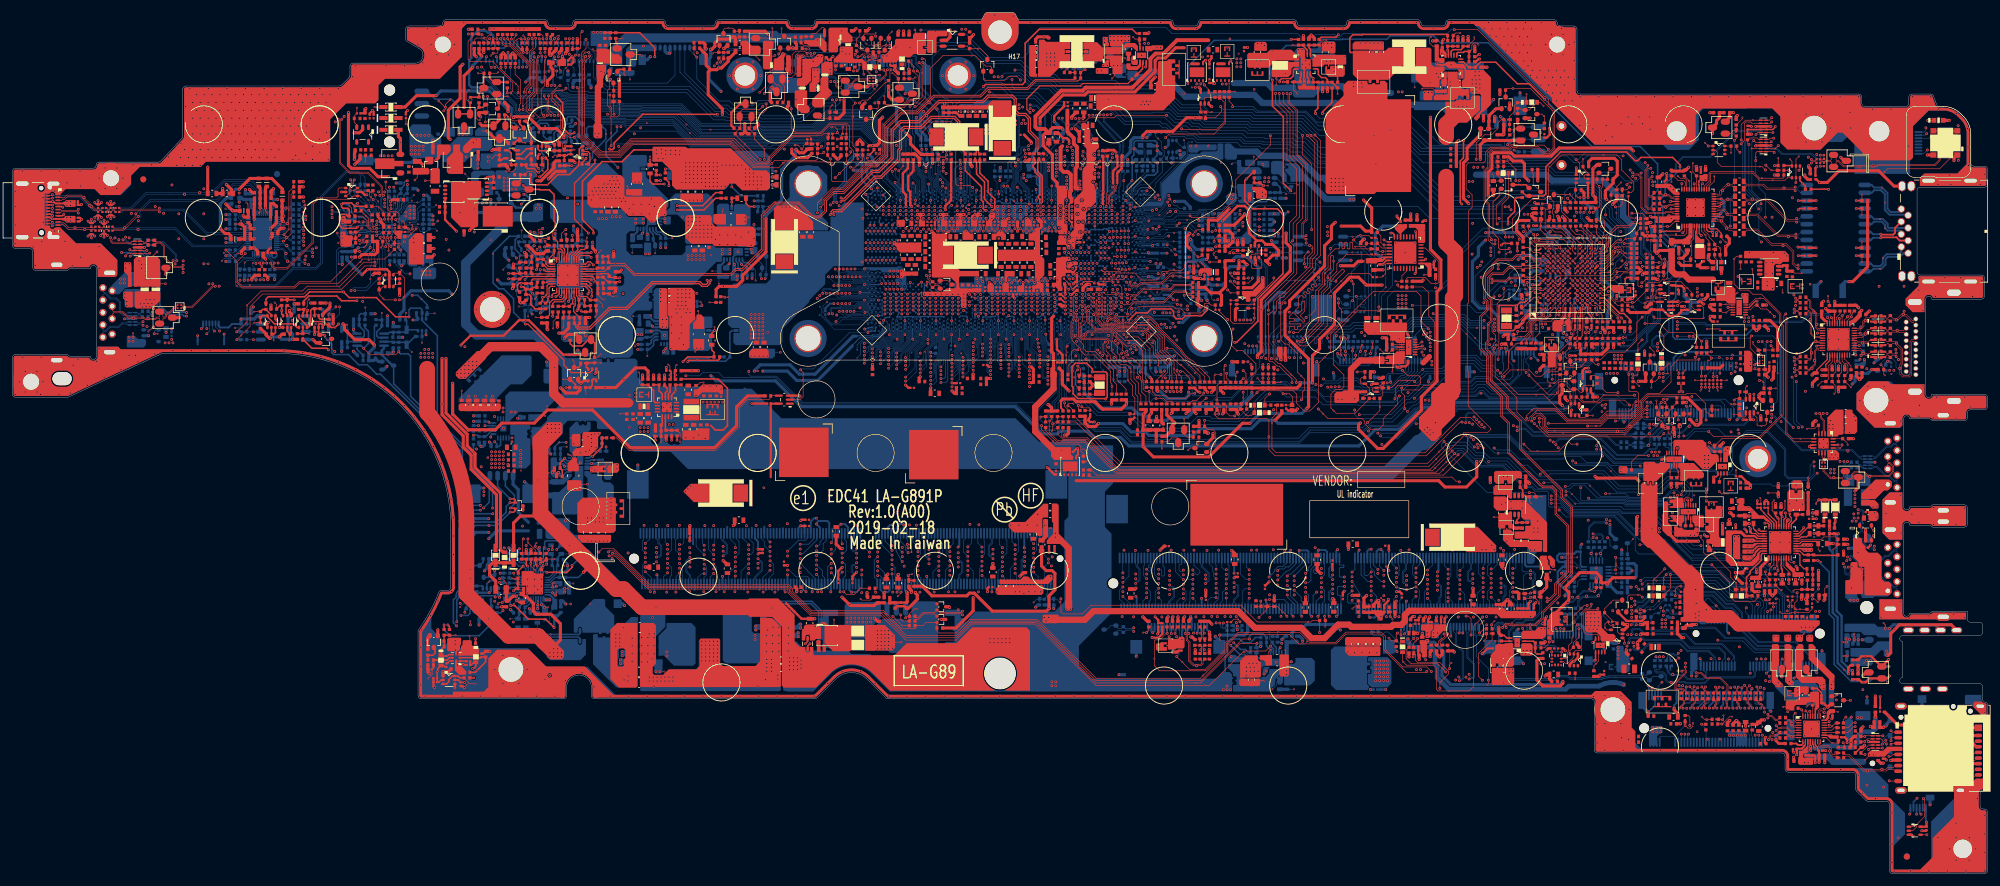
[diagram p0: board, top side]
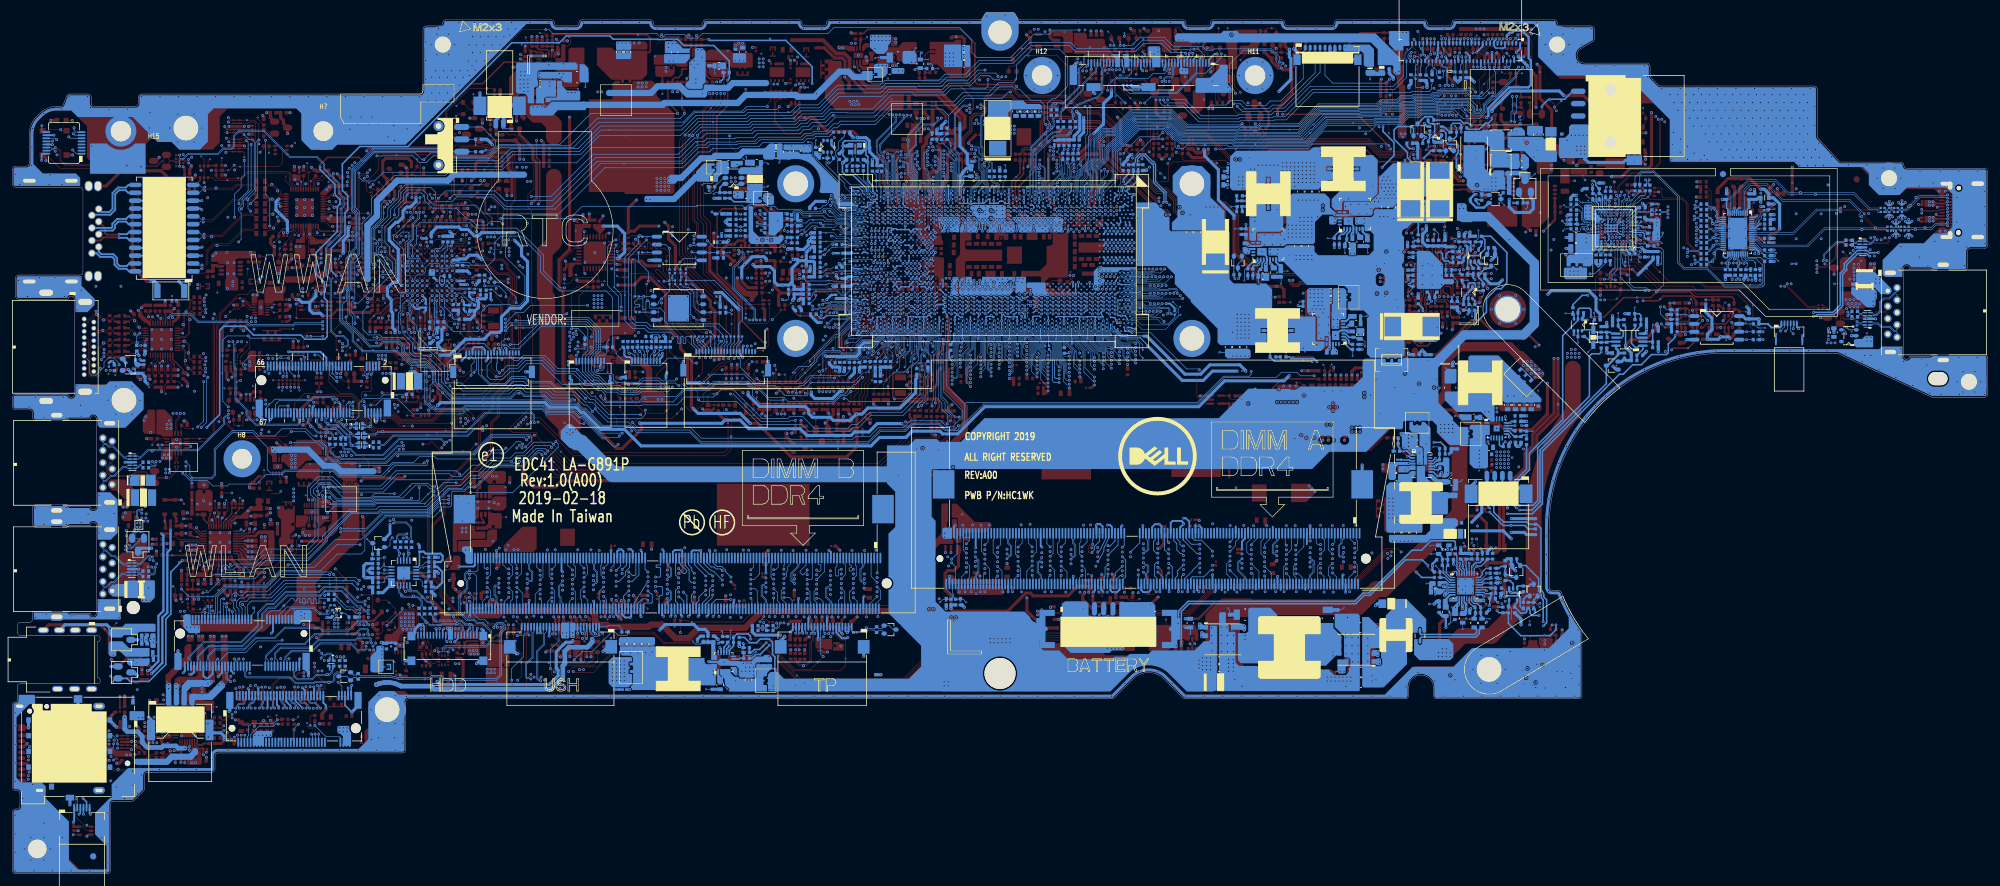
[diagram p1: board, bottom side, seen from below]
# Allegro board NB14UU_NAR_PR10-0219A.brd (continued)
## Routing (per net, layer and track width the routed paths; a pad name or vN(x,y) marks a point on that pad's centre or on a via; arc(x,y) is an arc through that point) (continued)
TBTA_BOT_P: length 55.1
  IN3 w0.089: v1(26.55,99.07) 26.14,99.47 26.14,99.63 26.26,99.75 26.68,99.75 26.97,99.46 26.97,96.57 29.78,93.75 48.01,93.75 55.48,101.22 55.48,103.17 55.96,103.65 56.57,103.65 57.25,104.32 57.25,105.56 58.71,107.02 60.52,107.02 60.75,107.25 60.75,107.63 60.83,107.71 60.94,107.71 61.16,107.52 v1(61.16,107.48)
  BOTTOM w0.076: v1(61.16,107.48) 61.09,107.41 61.09,106.3 61.02,106.23 60.9,106.23 UT5.K7
  BOTTOM w0.097: v1(26.55,99.07) 26.55,100.03 24.39,102.19 23.05,102.19 RT123.2
TBTA_BOT_P_R: length 18.8
  TOP w0.097: v1(10.66,107.35) 10.46,107.16 7.91,107.16 7.74,107.32 JUSBC1.A6
  IN2 w0.089: v1(10.66,107.35) 10.85,107.16 11.45,107.16 11.73,106.87 16.53,106.87 17.42,105.99 17.42,103.74 v1(18.28,102.87)
  BOTTOM w0.097: RT123.1 21.64,102.05 21.2,102.05 21.04,102.22 DT40.1 DT40.9 19.4,102.22 19.1,101.92 18.89,101.92 18.28,102.53 v1(18.28,102.87)
TBTA_CC1: length 98.8
  TOP w0.254: JUSBC1.B5 6.18,106.57 6.38,106.38 v1(6.47,106.38)
  IN1 w0.254: v1(63.79,111.98) 63.56,111.98 63.23,111.64 63.23,110.98 63.56,110.65 64.6,110.65 64.92,110.97 66.49,110.97 67.01,110.44 67.01,100.99 63.29,97.27 63.29,95.62 62.9,95.22 46.48,95.22 41.83,90.57 28.24,90.57 v1(28.13,90.69)
  IN2 w0.254: v1(17.65,100.39) 16.47,101.57 12.25,101.57 10.06,103.77 8.52,103.77 6.98,105.31 6.98,105.99 6.59,106.38 v1(6.47,106.38)
  BOTTOM w0.127: 62.04,107.42 61.87,107.26 61.87,106.85 UT5.L9
  BOTTOM w0.203: 62.04,107.42 62.23,107.62 62.23,109.64 62.49,109.91 RT104.2 ; 21.03,100.72 DT40.4 DT40.7 19.49,100.72 19.14,100.37
  BOTTOM w0.254: 19.14,100.37 17.67,100.37 v1(17.65,100.39) ; v1(63.79,111.98) 63.56,111.98 63.29,111.71 63.29,111.26 CT86.1 RT104.2 ; v1(28.13,90.69) 28.09,90.73 24.98,90.73 23.81,91.89 23.81,97.04 23.16,97.69 23.16,98.59 21.03,100.72
TBTA_CC2: length 101.1
  TOP w0.254: JUSBC1.A5 8.01,107.82 v1(8.12,107.71)
  IN1 w0.254: v1(63.81,111.37) 66.63,111.37 67.39,110.6 67.39,100.84 63.67,97.12 63.67,95.43 63.09,94.84 46.64,94.84 41.99,90.19 28.21,90.19 v1(28.13,90.1)
  IN2 w0.254: v1(19.03,99.81) 18.47,100.36 18.47,101.18 19.58,102.28 19.58,105.11 16.88,107.81 12.25,107.81 11.39,108.67 10.8,108.67 9.52,107.39 8.44,107.39 v1(8.12,107.71)
  BOTTOM w0.203: RT105.2 63.5,109.91 63.25,109.66 63.25,108.62 62.86,108.23 62.86,107.56 62.33,107.03 UT5.L10 ; 19.27,99.93 19.56,100.22 DT40.6 DT40.5 20.95,100.22
  BOTTOM w0.254: 20.95,100.22 22.78,98.38 22.78,97.53 23.43,96.88 23.43,91.74 24.82,90.35 27.47,90.35 27.71,90.1 v1(28.13,90.1) ; RT105.2 63.81,109.96 CT85.1 v1(63.81,111.37) ; v1(19.03,99.81) 19.15,99.81 19.27,99.93
TBTA_DBG_CTL1: length 7.7
  TOP w0.107: v2(54.44,107.92) 54.78,107.58 54.78,106.82 55.32,106.28 RT106.1 56.52,106.27 57.28,105.51 57.28,104.57 58.13,103.72 v1(58.84,103.72)
  BOTTOM w0.076: UT5.E4 58.93,103.81 v1(58.84,103.72)
TBTA_DBG_CTL2: length 2.6
  TOP w0.107: v1(59.4,102.83) 59.4,102.61 RT107.1 59.83,101.48 v2(59.55,101.2)
  BOTTOM w0.076: UT5.D5 59.4,102.88 v1(59.4,102.83)
TBTA_DEBUG1: length 5.1
  BOTTOM w0.076: 56.99,108.66 57.13,108.52 57.13,108.5 58.25,107.38 58.25,106.88 UT5.L2
  BOTTOM w0.107: 56.99,108.66 v2(56.25,109.4) 56.06,109.59 55.49,109.59 55.3,109.78 RT92.2
TBTA_DEBUG2: length 6.3
  BOTTOM w0.076: UT5.K2 58.08,106.56 58.08,107.28 57.68,107.68
  BOTTOM w0.107: 57.68,107.68 57.62,107.68 56.9,108.4 56.55,108.4 55.86,109.1 55.11,109.1 v2(54.85,109.36) 54.54,109.67 RT93.2
TBTA_DEBUG3: length 4.9
  BOTTOM w0.076: 58.35,107.97 58.35,107.79 58.61,107.53 58.61,107.13 58.76,106.98 58.76,106.88 UT5.L3
  BOTTOM w0.107: RT89.2 57.68,110.36 v2(57.93,110.11) 58.06,109.98 58.06,109.49 57.85,109.28 57.85,108.79 58.35,108.29 58.35,107.97
TBTA_DEBUG4: length 5.1
  BOTTOM w0.076: UT5.K3 58.58,106.56 58.58,106.91 58.43,107.05 58.43,107.46 57.62,108.27 57.62,108.66
  BOTTOM w0.107: 57.62,108.66 57.62,108.72 v2(57.51,108.83) 56.19,110.15 RT90.2
TBTA_LSRX_R: length 4.9
  TOP w0.107: RT88.2 57.69,110.16 57.69,109.53 v2(57.88,109.34) v1(58.27,108.95)
  BOTTOM w0.076: UT5.K4 59.08,106.56 59.08,106.91 58.93,107.05 58.93,107.06 58.79,107.2 58.79,108.44 58.57,108.66
  BOTTOM w0.107: 58.57,108.66 v1(58.27,108.95)
TBTA_LSTX_R: length 4.1
  TOP w0.107: RT87.2 58.22,110.06 v1(58.63,109.66)
  BOTTOM w0.076: v2(59.06,108.66) 59.16,108.56 59.16,107.78 59.11,107.72 59.11,107.2 59.33,106.98 UT5.L4
  BOTTOM w0.107: v1(58.63,109.66) 58.67,109.62 58.67,109.05 v2(59.06,108.66)
TBTA_MRESET: length 4
  TOP w0.107: RT86.1 64.08,103.71 v1(64.59,104.21) v2(64.59,104.86)
  BOTTOM w0.076: UT5.E11 63.07,103.81 63.12,103.86 64.22,103.86 64.57,104.21
  BOTTOM w0.107: 64.57,104.21 v1(64.59,104.21)
TBTA_RESET_N_EC_R: length 6.8
  BOTTOM w0.076: 64.57,104.71 63.69,104.71 63.28,104.31 UT5.F11
  BOTTOM w0.107: v2(68.59,103.91) 68.28,104.21 RT110.2 66.86,103.75 65.99,103.75 65.78,103.96 65.78,104.24 65.39,104.63 64.66,104.63 64.57,104.71
TBTA_ROM_CLK_PD: length 32.4
  TOP w0.107: v1(58.55,98.82) 56.77,98.82 52.89,94.94 47.62,94.94 46.84,94.16 40.21,94.16 v2(37.9,91.86) 37.9,89.23 v1(36.25,87.58)
  BOTTOM w0.076: 58.48,99.39 58.48,99.93 58.92,100.38 58.92,101.65 58.83,101.75 UT5.A3
  BOTTOM w0.107: 58.48,99.39 58.48,98.9 v1(58.55,98.82) ; RT54.1 v1(36.25,87.58)
TBTA_ROM_CLK_PD_R: length 9.5
  IN1 w0.099: v1(33.46,87.7) 33.74,87.98 38.52,87.98 v1(38.93,87.58)
  BOTTOM w0.107: UT6.6 v1(38.93,87.58) RT54.2 ; v1(33.46,87.7) 32.81,88.35 JDB1.2
TBTA_ROM_CS#_PD: length 16.1
  IN1 w0.099: v1(54.71,94.24) 52.24,91.78 v1(52.24,91.6)
  BOTTOM w0.076: 57.96,99.39 57.96,99.63 58.73,100.4 58.73,101.56 58.59,101.7 58.59,102.06 UT5.B3
  BOTTOM w0.107: RT57.1 51.77,91.13 v1(52.24,91.6) ; 57.96,99.39 57.96,98.32 57.82,98.18 v2(57.82,96.12) 57.82,95.39 57.11,94.69 55.15,94.69 v1(54.71,94.24)
TBTA_ROM_CS#_PD_R: length 21.8
  IN1 w0.099: v1(31.4,88.08) 32.19,88.87 37.93,88.87 38.31,89.25 39.34,89.25 39.9,88.7 44.48,88.7 v1(45.21,89.42)
  BOTTOM w0.107: v1(31.4,88.08) 31.31,88.18 JDB1.5 ; RT57.2 RT51.2 v2(49.04,90.37) 48.6,90.37 48.34,90.12 UT6.1 45.91,90.12 v1(45.21,89.42)
TBTA_ROM_DI_PD: length 34.2
  TOP w0.107: v1(58.54,98.23) 56.94,98.23 53.17,94.46 47.82,94.46 47.04,93.68 40.41,93.68 38.39,91.65 38.39,88.45 v2(36.93,86.99) v1(36.25,86.31)
  BOTTOM w0.076: UT5.B4 59.08,102.06 59.08,101.71 59.11,101.68 59.11,99.54 58.97,99.39
  BOTTOM w0.107: RT55.1 v1(36.25,86.31) ; 58.97,99.39 58.97,98.66 v1(58.54,98.23)
TBTA_ROM_DI_PD_R: length 10.5
  IN1 w0.099: v1(32.63,87.7) 33.59,86.75 38.48,86.75 v1(38.93,86.31)
  BOTTOM w0.107: RT55.2 v1(38.93,86.31) 40.12,86.31 ; v1(32.63,87.7) 32.31,88.03 JDB1.3
TBTA_ROM_DO_PD: length 17.3
  IN1 w0.099: v1(52.85,91.62) 52.85,91.78 v1(55.3,94.23)
  BOTTOM w0.076: UT5.A4 59.33,99.39
  BOTTOM w0.107: v1(52.85,91.62) 52.85,90.46 52,89.61 RT56.1 ; v1(55.3,94.23) 57.17,94.23 59.33,96.39 v2(59.33,97.86) 59.33,99.39
TBTA_ROM_DO_PD_R: length 23.1
  IN1 w0.099: v1(31.4,87.26) 32.61,88.47 38.72,88.47 39.42,87.77 44.38,87.77 v1(46.03,89.42)
  BOTTOM w0.107: JDB1.4 31.81,87.67 v1(31.4,87.26) ; RT56.2 RT52.2 v2(48.99,88.85) 46.6,88.85 v1(46.03,89.42)
TBTA_ROM_HOLD#_PD: length 4.4
  BOTTOM w0.107: 40.12,88.85 RT50.2 37.77,88.85 37.12,88.2 v2(35.96,88.2)
TBTA_ROM_WP#_PD: length 2.8
  BOTTOM w0.107: RT53.2 v2(49.14,87.58) UT6.3
TBTA_ROSC: length 5.4
  TOP w0.107: v1(55.98,105.35) 55.94,105.39 RT100.1 54.66,104.72 v2(53.48,104.72)
  BOTTOM w0.076: 56.69,104.98 57.08,104.98 57.15,105.06 58.08,105.06 UT5.G2
  BOTTOM w0.112: v1(55.98,105.35) 56.34,104.98 56.69,104.98
TBTA_SWD_CLK_R: length 2.4
  TOP w0.107: v1(58.84,104.89) 58.48,104.53 v2(58.21,104.53) 58.11,104.64 RT85.1
  BOTTOM w0.076: v1(58.84,104.89) 58.93,104.81 UT5.G4
TBTA_SWD_DATA_R: length 5.1
  TOP w0.107: v1(58.84,104.31) 58.7,104.16 58.02,104.16 57.53,104.65 57.53,105.88 v2(57.14,106.28) 56.34,107.08 RT84.1
  BOTTOM w0.076: v1(58.84,104.31) UT5.F4
TBTA_TOP_N: length 51.5
  TOP w0.097: v1(27.58,98.33) 27.38,98.13 26.12,98.13 24.57,99.69 24.57,101.48 23.97,102.08 23.16,102.08 RT121.1
  IN3 w0.089: v1(60.14,108.37) 59.95,108.18 57.23,108.18 54.4,105.35 54.4,101.49 47.62,94.71 36.55,94.71 34.99,96.28 30.07,96.28 28.22,98.13 27.78,98.13 v1(27.58,98.33)
  BOTTOM w0.076: v1(60.14,108.37) 59.8,108.03 59.8,107.44 60.33,106.9 UT5.L6
TBTA_TOP_N_R: length 20.4
  TOP w0.097: v1(16.58,102.74) 16.43,102.74 16.06,102.37 16.06,102.2 16.2,102.05 19.17,102.05 19.34,102.22 DT39.6 DT39.5 21.04,102.22 21.2,102.05 21.64,102.05 RT121.2
  TOP w0.102: v1(6.47,107.5) 6.39,107.57 JUSBC1.B7
  IN2 w0.089: v1(16.58,102.74) 16.58,103.37 16.49,103.43 16.27,103.58 9.5,104.94 9.46,104.94 8.6,104.94 7.87,105.67 7.87,106.69 7.17,107.39 6.73,107.39
  IN2 w0.102: 6.73,107.39 6.58,107.39 v1(6.47,107.5)
TBTA_TOP_P: length 51.5
  TOP w0.097: v1(27.58,97.75) 27.38,97.95 26.05,97.95 24.38,99.61 24.38,101.41 23.9,101.9 23.15,101.9 RT120.1
  IN3 w0.089: v1(27.58,97.75) 27.78,97.95 28.15,97.95 30,96.1 34.91,96.1 36.48,94.53 47.69,94.53 54.58,101.42 54.58,105.27 57.31,108 59.92,108 v1(60.14,107.79)
  BOTTOM w0.076: UT5.K6 60.51,106.31 60.57,106.37 60.57,107.44 60.22,107.79 v1(60.14,107.79)
TBTA_TOP_P_R: length 20.5
  TOP w0.097: RT120.2 21.7,101.86 21.2,101.86 21.06,101.72 DT39.4 DT39.7 19.32,101.72 19.17,101.86 16.12,101.86 15.86,102.13 v1(15.86,102.78)
  TOP w0.102: v1(6.47,106.94) 6.33,107.07 JUSBC1.B6
  IN2 w0.089: v1(15.86,102.78) 16.04,102.78 16.37,103.12 16.37,103.26 16.19,103.39 9.46,104.73 8.52,104.73 7.66,105.59 7.66,106.6 7.07,107.19 6.73,107.19
  IN2 w0.102: 6.73,107.19 6.72,107.19 v1(6.47,106.94)
TDI_XDP: length 64.9
  TOP w0.107: RC736.1 134.72,118.93 RC851.2 134.72,120.9 134.53,121.08 132.11,121.08 130.61,119.59 125.95,119.59 122.08,115.72 122.08,115.43 121.67,115.02 120.41,115.02 116.64,118.78 99.86,118.78 98.02,116.94 97.79,116.71 95.16,116.71 92.44,119.43 v2(92.44,125.09) 92.44,131.15 93.21,131.92 v1(93.21,132.15)
  BOTTOM w0.107: JXDP1.56 92.67,131.6 92.77,131.71 93.02,131.71 93.21,131.91 v1(93.21,132.15)
TDO_XDP: length 63
  TOP w0.107: v1(92.59,132.08) 92.41,131.9 92.41,131.45 92.1,131.14 92.1,119.37 94.99,116.48 97.89,116.48 99.96,118.55 116.36,118.55 v2(119.22,115.69) 120.13,114.78 121.76,114.78 122.32,115.33 122.32,115.63 126.04,119.35 130.82,119.35 131.05,119.58 RC850.2 131.85,119.29 131.76,119.2 RC737.1
  BOTTOM w0.107: v1(92.59,132.08) 91.96,132.08 91.47,131.59 JXDP1.52 91.47,130.47 91.64,130.3 CC306.1
THERMTRIP2#: length 17.4
  TOP w0.107: RE69.2 253.26,83.09 CE36.1 252.53,82.58 252.03,82.08 251.75,82.08 251.65,82.18 QE4.1 251.65,83.16 251.47,83.33 251.01,83.33 250.9,83.44 250.9,84.34 v1(251.52,84.96)
  TOP w0.127: v1(252.83,92.63) UE1.H3
  BOTTOM w0.089: v1(252.83,92.63) 253.24,92.22 254.73,92.22 254.81,92.13 254.81,91.08 254.65,90.91 254.65,90.3 254.69,90.26 254.69,89.5 253.8,88.61 253.8,87.89 253.42,87.51 253.42,86.98
  BOTTOM w0.107: v1(251.52,84.96) 251.52,84.96 251.67,84.96 v2(252.78,86.06) 253.42,86.71 253.42,86.98
TMDSE_CON_CLK: length 5.2
  TOP w0.089: v1(304.28,84.14) 304.12,83.99 303.7,83.99 RV685.2 303.09,84.1 302.74,84.1 302.5,84.35 LV12.3 301.91,84.35 RV692.2
  IN1 w0.089: v1(304.28,84.14) 304.39,84.04 304.72,84.04 304.84,84.16 304.84,84.41 305.25,84.82 305.57,84.82 JHDMI1.10
TMDSE_CON_CLK#: length 5.3
  TOP w0.089: RV693.2 301.91,83.5 LV12.2 302.44,83.5 302.77,83.83 302.94,83.83 RV685.1 303.62,83.72 304.12,83.72 v1(304.28,83.56)
  IN1 w0.089: JHDMI1.12 305.57,84.48 305.38,84.48 305.18,84.27 305.18,84.02 304.86,83.7 304.42,83.7 v1(304.28,83.56)
TMDSE_CON_N0: length 16.5
  TOP w0.089: RV690.2 301.91,85.41 LV9.2 302.56,85.41 302.86,85.71 302.97,85.71 RV654.2 303.7,85.71 304.02,85.71 305.07,84.66 305.07,82.5 304.87,82.31 v4(304.87,81.67) 304.87,80.71 305.31,80.27 306.45,80.27 306.78,80.61 306.78,85.88 306.92,86.02 307.08,86.02 JHDMI1.9
TMDSE_CON_N1: length 4.6
  TOP w0.089: RV689.2 301.91,87.31 LV6.2 302.47,87.31 302.72,87.56 303.02,87.56 RV684.1 303.62,87.53 304.72,87.53 304.77,87.47 305.58,87.47 JHDMI1.6
TMDSE_CON_N2: length 6.8
  TOP w0.089: JHDMI1.3 307.04,89.06 306.87,89.06 305.79,90.13 305.23,90.13 304.58,89.48 v4(304.31,89.48) 303.54,89.48 RV683.2 303.11,89.5 302.72,89.5 302.43,89.22 LV3.2 301.91,89.22 RV686.2
TMDSE_CON_P0: length 16.5
  TOP w0.089: RV691.2 301.91,86.26 LV9.3 302.5,86.26 302.78,85.98 303.06,85.98 RV654.1 303.62,85.98 304.13,85.98 v4(304.34,85.76) 305.33,84.77 305.33,82.39 305.14,82.19 305.14,80.83 305.42,80.54 306.33,80.54 306.51,80.72 306.51,85.99 306.81,86.28 307.08,86.28 JHDMI1.7
TMDSE_CON_P1: length 4.7
  TOP w0.089: JHDMI1.4 305.49,87.74 304.88,87.74 304.83,87.8 v4(304.45,87.8) 303.7,87.8 RV684.2 303,87.83 302.83,87.83 302.5,88.16 LV6.3 301.91,88.16 RV688.2
TMDSE_CON_P2: length 7
  TOP w0.089: RV687.2 301.91,90.07 LV3.3 302.37,90.07 302.66,89.77 302.91,89.77 RV683.1 303.78,89.75 304.47,89.75 305.12,90.4 v4(305.43,90.4) 305.9,90.4 306.98,89.33 307.13,89.33 JHDMI1.1
TMDSE_RP_CLK: length 4
  TOP w0.089: UV21.22 297.96,84.96 298.07,84.84 298.58,84.84 299.4,84.02 299.97,84.02 300.3,84.35 LV12.4 300.83,84.35 RV692.1
TMDSE_RP_CLK#: length 3.9
  TOP w0.089: RV693.1 300.83,83.5 LV12.1 300.3,83.5 300.05,83.75 299.29,83.75 v4(298.95,84.09) 298.47,84.57 298.04,84.57 298.03,84.56 UV21.21
TMDSE_RP_N0: length 3.6
  TOP w0.089: RV690.1 300.83,85.41 LV9.1 300.06,85.41 299.82,85.66 299.3,85.66 299.17,85.78 v4(298.88,85.78) 297.99,85.78 297.96,85.76 UV21.24
TMDSE_RP_N1: length 3.6
  TOP w0.089: LV6.1 300.3,87.31 299.97,87.64 299.71,87.64 v4(299.28,87.2) 298.76,86.69 298.75,86.69 298.2,86.69 298.2,86.69 297.97,86.69 297.84,86.56 UV21.26
TMDSE_RP_N2: length 4.7
  TOP w0.089: RV686.1 300.83,89.22 LV3.1 300.23,89.22 299.9,89.55 299.51,89.55 v4(299.32,89.36) 299.08,89.11 299.08,88.44 298.5,87.86 298.03,87.86 297.93,87.76 UV21.29
TMDSE_RP_P0: length 3.7
  TOP w0.089: RV691.1 300.83,86.26 LV9.4 300.06,86.26 299.73,85.92 299.41,85.92 299.28,86.05 298,86.05 297.9,86.16 UV21.25
TMDSE_RP_P1: length 3.5
  TOP w0.089: LV6.4 300.3,88.16 300.04,87.9 299.6,87.9 298.65,86.96 298.64,86.96 298.31,86.96 298.31,86.96 297.86,86.96 297.86,86.96 UV21.27
TMDSE_RP_P2: length 4.6
  TOP w0.089: UV21.30 297.93,88.16 297.95,88.13 298.39,88.13 v4(298.58,88.32) 298.81,88.55 298.81,89.22 299.4,89.82 299.99,89.82 300.24,90.07 LV3.4 300.83,90.07 RV687.1
TOUCH_SCREEN_DET#: length 125.9
  TOP w0.107: v1(136.84,124.56) 137.3,125.02 138.16,125.02 v2(138.47,125.33) 141.03,127.89 141.23,127.89 RV8.1 141.74,128.39 141.74,129.74 v1(141.92,129.92)
  IN2 w0.102: v1(136.84,124.56) 137.24,124.15 141.61,124.15 142.46,125.01 147.68,125.01 147.95,124.74 154.8,124.74 155.02,124.97 159.54,124.97 159.85,125.27 161.43,125.27 162.09,125.93 187.4,125.93 188.54,124.79 188.54,121.91 185.34,118.71 185.34,116.71 184.73,116.1 184.73,115.87 182.09,113.23 182.09,102.19 181.91,102.01 181.91,101.61 180.96,100.66 180.96,98.43 180.65,98.13 178.38,98.13 177.64,97.39 170.91,97.39 170.24,96.72 170.24,95.2 170.6,94.84 171.51,94.84 171.54,94.8 171.74,94.61 171.74,94.1 171.43,93.78 171.43,90.31 171.72,90.03 172.18,90.03 172.65,89.56 173.59,89.56 174.3,88.85 175.92,88.85 177.6,87.16 177.6,85.42 177.26,85.08 v1(177.08,85.08)
  BOTTOM w0.076: v1(177.08,85.08) 177.03,85.02 176.94,85.02 176.18,85.78 176.18,87.31 176.02,87.47 176.02,87.81 176.05,87.89 176.05,88.13 176.01,88.24 176.01,88.43 176.05,88.54 176.05,88.76 UC1.CC35
  BOTTOM w0.107: JEDP1.32 141.28,130.57 141.92,129.92 v1(141.92,129.92)
TOUCH_SCREEN_PD: length 3.7
  BOTTOM w0.107: QC4.5 187.38,118.5 188.03,118.5 QC4.6 188.03,118.3 188.96,117.37 RC104.2 189.29,118.49 v2(189.24,118.54)
TOUCH_SCREEN_PD#: length 12.1
  BOTTOM w0.076: 184.71,111.66 184.59,111.54 184.59,111.01 183.52,109.94 183.18,109.94 183.14,109.98 183.14,109.98 182.97,110.16 182.68,110.16 182.52,109.99 182.07,109.99 181.91,109.84 181.91,109.81 181.91,109.45 UC1.CN3
  BOTTOM w0.107: RC566.1 187.33,116.1 187.38,116.15 QC4.2 ; RC566.1 RC82.2 ; RC566.1 187.33,115.36 187.64,115.05 187.64,114.59 184.71,111.66
TOUCH_SCREEN_PD#_R: length 89.6
  TOP w0.107: v2(139.26,126.77) 139,127.03 v1(139,127.43)
  IN2 w0.102: v1(187.23,114.88) 187.23,115.13 188.1,116 188.1,116.23 188.21,116.35 188.21,117.09 190.64,119.52 190.64,122.35 193.06,124.78 193.06,127.5 191.93,128.62 186.19,128.62 184.84,127.27 161.77,127.27 161.22,126.73 157.27,126.73 157.1,126.57 154.8,126.57 154.17,125.93 149.06,125.93 147.51,127.48 140.5,127.48 139.94,126.92 139.21,126.92 139,127.13 v1(139,127.43)
  BOTTOM w0.107: v1(187.23,114.88) 186.99,114.88 186.42,115.45 RC566.2 186.42,115.77 186.73,116.09 QC4.3 ; JEDP1.5 127.77,129.55 131.02,126.3 137.98,126.3 139,127.32 v1(139,127.43)
TOUCHPAD_INTR#: length 219.8
  TOP w0.107: v1(194.56,76.53) 194.57,76.55 194.57,78.89 RC567.1 ; v1(240.91,80.34) 241.99,81.41 v2(243.18,81.41) 245,81.41 246.01,80.4 247,80.4 248,81.4 249.03,81.4 249.49,81.86 249.49,83.92 251.16,85.6 RE318.2
  IN1 w0.089: 180.91,80.68 180.91,81.16 179.96,82.1 178.04,82.1 176.39,83.76 v1(176.1,83.76)
  IN1 w0.099: 180.91,80.68 180.91,80.08 182.41,78.58 185.01,78.58 185.38,78.21 185.38,77.52 185.87,77.03 188.54,77.03 189.36,76.21 194.25,76.21 194.56,76.53 v1(194.56,76.53)
  IN2 w0.102: v1(190.78,38.89) 190.78,38.96 192.95,41.13 198.94,41.13 199.66,41.86 203.32,41.86 204,41.18 217.26,41.18 217.31,41.13 218.07,41.13 218.74,41.8 220.19,41.8 220.87,41.12 225.45,41.12 225.7,40.87 231.49,40.87 231.75,40.61 243.49,40.61 244.88,42.01 247.1,42.01 247.18,41.93 248.89,41.93 251.34,44.38 251.34,46.8 250.99,47.15 250.99,58.47 251.35,58.83 251.35,62.65 251.02,62.98 250.22,62.98 247.24,65.96 234.21,65.96 230.75,69.42 230.75,72.41 227.78,75.38 226.25,75.38 224.85,76.78 223.46,76.78 223.31,76.78 v1(223.31,76.78)
  BOTTOM w0.076: v1(176.1,83.76) 176.4,84.06 176.4,85.28 176.02,85.66 176.02,87.24 175.86,87.4 175.86,87.84 175.89,87.92 175.89,88.1 175.85,88.21 175.85,88.45 175.89,88.57 175.89,89.05 UC1.CB34
  BOTTOM w0.107: v1(240.91,80.34) 240.08,80.34 238.74,81.68 237.39,81.68 236.13,82.94 233.43,82.94 231.28,80.79 228.42,80.79 226.54,78.91 225.54,78.91 225.46,78.83 225.31,78.83 224.57,78.09 223.93,78.09 223.31,77.46 v1(223.31,76.78) 223.31,76.57 223.09,76.36 217.8,76.36 217.07,77.09 211.83,77.09 210.61,78.31 206.56,78.31 205.54,79.32 200.29,79.32 199.23,78.26 198.53,78.26 196.8,76.53 v1(194.56,76.53) ; JKBTP1.16 190.99,39.18 190.78,38.97 v1(190.78,38.89)
TOUCHPAD_INTR#_R: length 7.4
  TOP w0.102: RE318.1 251.65,86.53 251.95,86.84 252.24,87.13 252.24,87.58 251.9,87.93 251.9,89.1 252.05,89.25 252.05,91.81 UE1.G2
  TOP w0.107: RE318.1 251.34,86.51 251.24,86.61 v2(250.58,86.61)
TP_DISABLE#: length 138.9
  TOP w0.107: RZ1475.1 197.29,41.12 v2(197.96,41.12) 198.28,40.79 v1(198.28,40.71)
  TOP w0.127: RE605.1 261.78,105.1 261.15,104.48 259.3,104.48 257.79,102.97 257.79,101.32 257.55,101.08 v1(257.55,100.64) 257.19,100.28 256.51,100.28 UE1.N12
  IN1 w0.089: 245.74,87.73 245.74,88.82 246.7,89.77 248.04,89.77 248.14,89.67 249.99,89.67 251.52,91.2 254.38,91.2 255.14,91.96 255.46,91.96 256.88,93.39 258.21,93.39 259.32,94.49 259.32,95.11
  IN1 w0.099: 245.74,87.73 245.74,87.12 244.91,86.29 244.91,84.48 244.18,83.75 244.18,83.25 242.12,81.19 242.12,75.46 ; 259.32,95.11 259.59,95.37 259.59,97.7 258.87,98.42 258.87,98.72 257.55,100.05 v1(257.55,100.64)
  IN1 w0.127: 242.12,75.46 246.89,70.69 246.89,69.67 248.52,68.04 248.52,65.08 246.95,63.51 246.95,59.43 248.52,57.86 248.52,50.64 249.3,49.87 249.3,49.52 248.93,49.15 248.93,46.86 248.52,46.45 248.52,45.12 248.39,44.99 247.16,44.99 247.03,44.86 247.03,43.85 246.57,43.38 246.02,43.38 245.63,42.99 244.91,42.99 242.01,40.1 242.01,39.91 241.42,39.31 239.03,39.31 v1(238.14,40.21)
  IN2 w0.102: v1(238.14,40.21) 237.88,39.95 232.09,39.95 231.39,40.64 225.61,40.64 225.36,40.89 217.23,40.89 217.17,40.96 203.54,40.96 203.47,40.89 202.17,40.89 201.99,40.71 v1(198.28,40.71)
TP_DISABLE#_R: length 19.6
  TOP w0.107: v1(188.07,35.09) v2(188.99,34.17) 190.14,33.02 192.66,33.02 195.87,36.23 195.87,37.33 196.24,37.69 RZ1475.2
  BOTTOM w0.107: JKBTP1.11 188.49,38.84 188.5,38.82 188.5,35.52 v1(188.07,35.09)
TP_LAN_JTAG_TCK: length 4.9
  TOP w0.107: v2(267.98,111.81) 267.95,111.83 RL2.1 268.31,112.77 269.06,112.02 269.96,112.02 270.22,111.76 270.22,111.24 270.06,111.07 UL1.35
TP_LAN_JTAG_TDI: length 2.9
  TOP w0.107: T88.1 271.2,113.28 271.2,111.2 271.26,111.15 UL1.32
TP_LAN_JTAG_TDO: length 3.2
  TOP w0.107: T89.1 269.43,112.34 270.16,112.34 270.46,112.05 UL1.34
TP_LAN_JTAG_TMS: length 2.5
  TOP w0.107: RL1.1 270.86,111.98 v2(270.86,111.92) UL1.33
TPM_GPIO0: length 13.2
  TOP w0.107: UZ12.6 228.21,101.11 230.31,99.01 230.31,95.52 230.18,95.39 v2(229.89,95.39) 229.17,95.39 228.18,96.38 225.39,96.38 225.23,96.21 RZ112.2
TPM_GPIO0_NU: length 3.4
  TOP w0.107: v2(223.41,95.74) RZ1407.2 224.44,96.63 225.22,97.41 UZ12.29
TPM_PIRQ#: length 72.4
  TOP w0.107: RZ69.2 221.04,103.08 221.04,102 221.42,101.61 v1(221.55,101.61) UZ12.18
  IN1 w0.089: v1(176.47,92.37) 177.02,91.82 177.02,90.28 177.08,90.22
  IN1 w0.099: 177.08,90.22 177.51,89.79 177.51,89.05 178.08,88.48 181.77,88.48 182.23,88.02 182.96,88.02 183.28,87.7 184.08,87.7 185.55,86.24 186.44,86.24 187.38,85.29 187.38,85.29
  IN1 w0.102: 187.38,85.29 187.74,84.93 188.08,84.93 190.89,82.13 195.32,82.13 195.69,82.5 195.69,82.5 195.74,82.55 196.48,82.55 196.72,82.31 198.38,82.31 199.66,81.02 199.66,80.3 200.74,79.23 203.61,79.23 206.29,81.91 207.25,81.91 208.57,83.23 208.57,84.77 212.62,88.82 213.32,88.82 213.51,89.01 218.16,89.01 v1(220.72,91.58)
  BOTTOM w0.089: UC1.CC29 v1(176.47,92.37)
  BOTTOM w0.107: v1(221.55,101.61) 221.55,101.36 221.83,101.07 v2(221.83,94.77) 220.72,93.66 v1(220.72,91.58)
TRST#_XDP: length 2.4
  BOTTOM w0.107: RC853.2 v2(92.39,130.02) 92.39,130.57 92.07,130.89 JXDP1.54
TS_I2C_SCL: length 113.2
  TOP w0.107: v1(121.22,124.01) 120.69,123.49 117.89,123.49 117.46,123.06 DZ10.2 117.46,121.69 117.6,121.55 117.6,120.58 CV55.1 116.74,119.73 RV99.2 116.74,119.45 v2(118.29,117.9) v1(120.77,115.42)
  IN3 w0.089: 127.97,108.18 129.74,108.18 129.88,108.32 130.7,108.32 131.98,107.04 132.91,107.04 135.56,104.39 142.66,104.39 144.87,102.18 167.61,102.18 169.01,100.78 173.22,100.78 173.52,101.09 173.52,101.3 173.74,101.52 174.24,101.52 174.89,102.17 174.89,102.92 175.5,103.53 176.22,103.53 177.21,104.51 179.89,104.51 180.02,104.39 181.36,104.39 182.29,103.46 184.1,103.46 v1(184.79,104.15)
  IN3 w0.102: 127.97,108.18 127.11,108.18 126.55,108.74 124.59,108.74 123.74,109.59 123.74,113.89 122.88,114.75 121.06,114.75 120.77,115.04 v1(120.77,115.42)
  BOTTOM w0.076: v1(184.79,104.15) 184.57,104.15 184.2,103.77 183.18,103.77 183.11,103.84 182.75,103.84 182.58,103.78 182.42,103.78 181.96,103.95 UC1.CN11
  BOTTOM w0.107: v1(121.22,124.01) 120.35,123.15 115.91,123.15 115.33,123.72 113.64,123.72 107.82,129.53 JIRTS1.4
TS_I2C_SDA: length 107.5
  TOP w0.107: v1(121.47,115.44) v2(121.47,117.1) 119.9,118.68 RV98.2 119.82,119.58 118.98,120.42 CV54.1 118.98,120.52 119.21,120.75 119.21,121.45 119.39,121.63 DZ10.3 119.39,122.7 119.63,122.95 121.28,122.95 121.77,123.43 v1(121.77,124.43)
  IN3 w0.089: 168.49,101.55 173.53,101.55 173.67,101.68 174.17,101.68 174.72,102.23 174.72,102.98 175.43,103.69 176.15,103.69 177.14,104.68 179.96,104.68 180.09,104.55 181.43,104.55 182.29,103.69 183.83,103.69 184.23,104.09 v1(184.23,104.31)
  IN3 w0.102: 168.49,101.55 167.68,102.35 153.81,102.35 153.04,103.12 153.04,104.38 152.74,104.69 143.96,104.69 143.16,105.49 139.71,105.49 137.4,107.79 137.06,107.79 132.14,112.71 132.14,113.13 130.01,115.26 121.64,115.26 v1(121.47,115.44)
  BOTTOM w0.076: v1(184.23,104.31) 184.05,104.49 183.27,104.49 183.04,104.27 182.72,104.27 182.61,104.31 182.42,104.31 182.31,104.27 182.07,104.27 181.96,104.31 181.48,104.31 UC1.CM11
  BOTTOM w0.107: JIRTS1.3 108.62,129.42 113.84,124.21 115.54,124.21 116.11,123.64 119.95,123.64 120.74,124.43 v1(121.77,124.43)
TS_INT#: length 114.1
  TOP w0.107: v1(125.8,123.62) 125.8,120.5 126.45,119.85 130.54,119.85 132.01,121.32 134.71,121.32 135.19,120.84 135.19,117.49 135.89,116.79 135.89,115.45 v3(133.6,113.17) v1(132.9,112.47) ; RV319.2 RV311.2 110.09,132.42 v1(110.55,131.96)
  IN3 w0.089: v1(185.21,104.56) 185.05,104.72 180.15,104.72 180.03,104.84 177.07,104.84 176.08,103.86 175.36,103.86 174.56,103.05 174.56,102.3 174.1,101.85 172.8,101.85 172.27,102.37 167.91,102.37
  IN3 w0.102: 167.91,102.37 167.75,102.53 153.88,102.53 153.22,103.19 153.22,104.46 152.81,104.87 144.04,104.87 143.24,105.66 139.78,105.66 132.98,112.47 v1(132.9,112.47)
  BOTTOM w0.076: UC1.CM12 181.16,103.74 182.05,103.74 182.4,103.62 182.63,103.62 182.8,103.68 183.05,103.68 183.11,103.61 184.26,103.61 184.44,103.79 184.94,103.79 185.21,104.07 v1(185.21,104.56)
  BOTTOM w0.107: v1(125.8,123.62) 125.8,123.94 125.52,124.22 123.05,124.22 122.32,124.95 120.47,124.95 119.64,124.12 116.61,124.12 115.85,124.88 114.14,124.88 110.55,128.47 v1(110.55,131.96) 109.42,133.09 JIRTS1.2
TYPEC_CON_SEL1: length 8.1
  BOTTOM w0.076: UC1.CN14 181.68,101.95 181.98,101.95 182.1,101.91 182.28,101.91 182.4,101.95 182.63,101.95 182.75,101.91 183.78,101.91 184.15,102.28 186.4,102.28 186.49,102.18 v2(187.57,102.18) 187.76,102.18
  BOTTOM w0.107: 187.76,102.18 188.45,102.18 RC745.1 RC744.1
TYPEC_CON_SEL2: length 9.2
  BOTTOM w0.076: 186.72,103.58 186.37,103.58 185.75,102.96 184.57,102.96 184.38,102.77 183.94,102.77 183.57,102.4 183.26,102.4 183.06,102.6 182.69,102.6 182.49,102.49 181.3,102.49 UC1.CM14
  BOTTOM w0.107: 186.72,103.58 v2(187.65,103.58) RC743.1 RC63.1
TYPEC_ID: length 10.9
  TOP w0.107: UE1.F2 250.45,91.81 250.45,90.21 250.02,89.78 249.04,89.78 248.54,89.28 246.78,89.28 246.68,89.18 v2(246.68,87.34) 246.06,86.73 RE343.2 CE62.1
UART_MISO: length 4.3
  TOP w0.107: v1(56.45,104.34) 55.79,103.68 RT83.2 RT82.1
  BOTTOM w0.076: UT5.F2 58.08,104.56 57.74,104.56 57.33,104.15 57.13,104.15
  BOTTOM w0.107: v1(56.45,104.34) 56.62,104.17 57.11,104.17
  BOTTOM w0.112: 57.13,104.15 57.11,104.17
UART_MOSI: length 4.1
  TOP w0.107: RT81.1 55.45,102.76 RT83.1 55.65,102.77 v1(56.07,103.19)
  BOTTOM w0.076: 56.79,103.27 57.11,103.27 57.39,103.56 58.08,103.56 UT5.E2
  BOTTOM w0.112: v1(56.07,103.19) 56.15,103.27 56.79,103.27
UG1_CHG: length 15.5
  TOP w0.107: v1(84.86,43.43) v2(84.86,44.03)
  IN3 w1.016: 85.93,42.02 88.1,42.02 95.89,34.24 97.59,34.24
  vias: v1(84.86,42.85) v1(98.23,34.55) v1(98.23,33.92)
UG2_CHG: length 41.9
  TOP w0.107: v1(87.27,46.33) v2(87.27,46.95)
  IN3 w1.016: 127.06,41.29 126.12,42.23 95.98,42.23 90.63,47.57 88.81,47.57 88.5,47.26
  vias: v1(87.86,46.48) v1(127.31,40.33) v1(127.31,39.7)
UG_SA:
  vias: v1(176.26,130.59) v1(176.88,130.58) v1(181.01,131.4) v1(181.15,132)
UIM_CLK: length 103.1
  TOP w0.107: v1(302.7,20.97) 302.63,20.97 301.81,21.78 DZ13.8 DZ13.2 299.62,21.78 v1(299.2,21.36) 299.13,21.3 298.6,21.3 CZ38.1
  IN3 w0.102: v1(299.2,21.36) 299.72,21.88 299.72,22.3 299.19,22.83 296.53,22.83 294.56,24.8 294.56,26.28 293.9,26.94 293.9,27.53 293.14,28.29 292.26,28.29 286.87,33.69 285.49,33.69 284.97,34.2 284.97,37.82 284.87,37.92 284.41,37.92 284.13,38.2 284.13,38.75 284.32,38.94 285.17,38.94 285.3,39.06 285.3,39.29 285.2,39.39 284.23,39.39 284.13,39.49 284.13,39.7 284.23,39.8 285.2,39.8 285.3,39.9 285.3,40.1 285.2,40.21 284.23,40.21 284.13,40.31 284.13,40.51 284.23,40.61 285.2,40.61 285.3,40.71 285.3,40.92 285.2,41.02 284.23,41.02 284.13,41.12 284.13,41.32 284.23,41.43 285.2,41.43 285.3,41.53 285.3,41.76 285.2,41.86 284.89,41.86 284.79,41.96 284.79,42.16 284.89,42.26 285.2,42.26 285.3,42.36 285.3,44.78 284.22,45.86 283.98,45.86 283.11,46.73 280.81,46.73 280.24,47.3 280.1,47.3 279.57,46.77 279.42,46.77 279.28,46.91 279.28,47.06 279.81,47.59 279.81,47.73 279.67,47.88 279.52,47.88 278.99,47.34 278.85,47.34 278.7,47.49 278.7,47.63 279.24,48.16 279.24,48.31 278.39,49.15 278.24,49.15 277.71,48.62 277.57,48.62 277.42,48.77 277.42,48.91 277.96,49.44 277.96,49.59 277.81,49.73 277.67,49.73 277.18,49.24 277.03,49.24 276.89,49.38 276.89,49.52 277.38,50.02 277.38,50.16 276.93,50.61 276.93,51.56 275.65,52.84 275.65,53.71 272.09,57.26 272.09,68.41 272.5,68.82 272.5,77.67 270.58,79.59 267.3,79.59 266.68,80.21 v1(266.63,80.21)
  BOTTOM w0.107: v1(302.7,20.97) 302.7,20.33 JSIM1.C3 ; v1(266.63,80.21) 266.69,80.21 267.33,80.85 JNGFF2.24
UIM_DATA: length 102.8
  TOP w0.107: v1(302.13,22.28) DZ13.9 DZ13.1 299.38,22.28 299.27,22.17 v1(299.19,22.17) CZ39.1 298.56,22.17 RZ335.2
  IN3 w0.102: v1(266.63,79.58) 267.1,79.11 270.38,79.11 272.02,77.47 272.02,73.76 271.61,73.35 271.61,57.06 275.17,53.51 275.17,52.64 276.41,51.4 276.41,49.1 279.26,46.25 282.91,46.25 283.65,45.51 283.65,43.89 283.08,43.32 283.08,42.23 283.65,41.66 283.65,38 284.49,37.16 284.49,34 285.29,33.21 285.63,33.21 287.65,31.19 288.69,31.19 292.26,27.61 292.26,25.24 292.98,24.52 292.98,23.89 293.29,23.59 295.06,23.59 296.48,22.17 v1(299.19,22.17) ; v1(316.28,20.56) 314.55,22.28 v1(302.13,22.28)
  BOTTOM w0.107: v1(316.28,20.56) 316.43,20.4 JSIM1.C7 ; JNGFF2.26 267.82,80.66 266.74,79.58 v1(266.63,79.58)
UIM_RESET: length 92.3
  TOP w0.107: v1(299.24,19.26) 298.83,19.26 CZ40.1 298.59,19.54 299.83,20.78 300.01,20.78 DZ13.4 DZ13.7 301.9,20.78 v1(302.06,20.95) ; v1(266.63,80.85) v2(267.39,80.85)
  IN3 w0.102: v1(299.24,19.26) 299.08,19.42 299.08,20.07 300.2,21.19 300.2,22.5 299.39,23.31 296.73,23.31 295.04,25 295.04,26.48 294.38,27.14 294.38,27.73 293.34,28.78 292.46,28.78 287.07,34.17 285.69,34.17 285.45,34.41 285.45,38.07 285.66,38.27 285.66,38.72 285.78,38.85 285.78,45.06 283.55,47.29 283.55,47.64 283.45,47.74 280.49,47.74 277.41,50.81 277.41,51.76 276.13,53.04 276.13,53.91 272.58,57.47 272.58,68.21 272.98,68.62 272.98,77.87 270.78,80.07 267.5,80.07 266.73,80.85 v1(266.63,80.85)
  BOTTOM w0.107: v1(302.06,20.95) 302.06,21.6 302.75,22.29 JSIM1.C2 ; v1(266.63,80.85) 266.82,81.04 JNGFF2.22
UPD1_SMBCLK: length 296.9
  TOP w0.107: v1(61.87,92.73) 60.12,92.73 v2(59.92,92.93) 59.24,93.61 RT58.1 59.48,94.49 59.88,94.88 QT1.1
  TOP w0.127: v1(248.06,92.66) 248.16,92.66 248.45,92.95 UE1.C3
  IN1 w0.089: 246.46,86.98 246.46,87.1 246.76,87.4 246.76,88.25 246.54,88.47 246.32,88.47 v1(246.12,88.67)
  IN1 w0.099: v1(76.16,61.14) 76.34,61.31 77.38,61.31 78.83,59.86 78.83,57.37 81.65,54.55 91.15,54.55 92.6,53.1 95.24,53.1 95.62,52.73 95.62,49.77 101.24,44.15 132.64,44.15 132.78,44.01 135.95,44.01 136.1,44.15 149.89,44.15 150.42,43.62 156.76,43.62 157.38,44.23 167.92,44.23 173.76,38.39 181.64,38.39 182.94,39.7 188.1,39.7 188.67,39.13 188.67,38.69 189.77,37.59 195.13,37.59 196.34,38.8 201.95,38.8 203.87,40.71 203.87,42.02 203.97,42.12 214.42,42.12 215.87,40.67 222.98,40.67 223.57,40.09 237.03,40.09 238.53,38.59 241.72,38.59 242.73,39.61 242.73,39.8 245.2,42.27 245.93,42.27 246.32,42.66 247.49,42.66 249.68,44.85 249.68,48.65 250.02,48.99 250.02,50.41 249.84,50.58 249.84,52.31 250.55,53.02 250.55,57.3 248.05,59.81 248.05,61.94 249.24,63.13 249.24,68.34 247.61,69.96 247.61,73.7 243.24,78.08 243.24,81.31 244.89,82.96 244.89,83.46 245.62,84.19 245.62,85.99 246.46,86.83 246.46,86.98
  IN3 w0.089: v1(248.06,92.66) 247.8,92.92 247.67,92.92 246.65,91.9 246.65,90.64 245.55,89.54 245.55,88.57 245.64,88.48 245.93,88.48 v1(246.12,88.67)
  IN3 w0.102: v1(76.16,61.14) 75.96,61.33 75.76,61.33 74.73,62.36 74.73,66.07 63.97,76.84 63.97,86.79 62.16,88.59 62.16,92.44 v1(61.87,92.73)
  BOTTOM w0.089: RE303.1 247.52,92.29 247.52,92.78 247.67,92.93 247.79,92.93 v1(248.06,92.66)
UPD1_SMBCLK_Q: length 36.5
  TOP w0.107: QT10.6 55.1,110.38 54.74,110.45 54.64,110.59 54.64,111.2 55.08,111.64 55.08,111.98 v1(55.23,112.13) ; QT1.6 59.89,96.78 RT67.1 RT58.2 59.57,95.4 v1(60.13,95.96)
  IN1 w0.099: v1(55.23,112.13) 55.04,112.33 55.04,112.62 54.81,112.85 54.41,112.85 54.01,112.45 54.01,109.19 58,105.2 58,102.15 58.96,101.19 58.96,98.65 60.9,96.71 60.9,96.09 60.76,95.96 v1(60.13,95.96)
  BOTTOM w0.076: 59.81,99.39 59.81,100.85 59.71,100.96 59.71,101.49 59.58,101.61 59.58,102.06 UT5.B5
  BOTTOM w0.107: 59.81,99.39 59.81,97.62 60.66,96.77 60.66,96.11 60.51,95.96 v1(60.13,95.96) ; v1(55.23,112.13) 55.06,111.97 55.06,111.52 RT92.1
UPD1_SMBDAT: length 297.6
  TOP w0.107: v1(62.5,92.73) 62.82,92.73 v2(63.25,93.16) 63.37,93.28 63.37,96.26 62.58,97.05 RT59.1 61.65,97.05 61.54,96.94 QT1.4
  TOP w0.127: v1(247.26,93.46) 247.29,93.46 UE1.B4
  IN1 w0.089: v1(246.12,88.08) 246.29,88.25 246.45,88.25 246.54,88.16 246.54,87.49 246.24,87.19 246.24,87.08 246.24,87.07 246.24,87 246.23,87 246.23,86.98
  IN1 w0.099: v1(76.16,61.72) 76.34,61.54 77.47,61.54 79.05,59.96 79.05,57.47 81.75,54.78 91.24,54.78 92.69,53.33 95.34,53.33 95.84,52.82 95.84,49.87 101.33,44.38 132.73,44.38 132.88,44.23 135.86,44.23 136,44.38 149.99,44.38 150.52,43.85 156.67,43.85 157.28,44.46 168.01,44.46 173.86,38.62 181.54,38.62 182.85,39.92 188.19,39.92 188.89,39.22 188.89,38.79 189.87,37.82 195.04,37.82 196.25,39.03 201.86,39.03 203.64,40.81 203.64,42.12 203.87,42.35 214.52,42.35 215.96,40.9 223.08,40.9 223.67,40.31 237.13,40.31 238.62,38.82 241.62,38.82 242.5,39.7 242.5,39.89 245.11,42.5 245.84,42.5 246.23,42.89 247.4,42.89 249.45,44.94 249.45,48.75 249.79,49.08 249.79,50.32 249.62,50.49 249.62,52.4 250.33,53.11 250.33,57.21 247.82,59.71 247.82,62.04 249.01,63.23 249.01,68.24 247.39,69.87 247.39,73.61 243.01,77.99 243.01,81.4 244.66,83.05 244.66,83.55 245.39,84.28 245.39,86.09 246.23,86.93 246.23,86.98
  IN3 w0.089: v1(247.26,93.46) 247.52,93.2 247.52,93.07 246.44,91.99 246.44,90.73 245.33,89.63 245.33,88.48 245.55,88.27 245.93,88.27 v1(246.12,88.08)
  IN3 w0.102: v1(62.5,92.73) 62.39,92.62 62.39,88.69 64.19,86.88 64.19,76.94 74.96,66.17 74.96,62.46 75.86,61.56 76,61.56 v1(76.16,61.72)
  BOTTOM w0.089: v1(247.26,93.46) 247.45,93.26 247.45,93.03 247.3,92.87 247.3,92.26 RE302.1
UPD1_SMBDAT_Q: length 35
  TOP w0.107: QT1.3 61.54,95.09 61.65,95.2 62.34,95.2 RT66.1 RT59.2 61.96,96.14 v1(61.91,96.09) ; v1(54.65,112.13) 54.84,111.94 54.84,111.73 54.41,111.3 54.41,110.52 54.55,110.31 54.48,109.96 QT10.3
  IN1 w0.099: v1(54.65,112.13) 54.81,112.3 54.81,112.52 54.71,112.62 54.5,112.62 54.24,112.35 54.24,109.28 58.22,105.29 58.22,102.25 59.19,101.29 59.19,98.75 61.12,96.81 61.12,96.18 61.22,96.09 v1(61.91,96.09)
  BOTTOM w0.076: UT5.A5 59.83,101.67 59.91,101.58 59.91,101.11 60.19,100.83 60.19,99.39
  BOTTOM w0.107: v1(61.91,96.09) 61.25,96.09 61.15,96.19 61.15,96.97 60.19,97.93 60.19,99.39 ; v1(54.65,112.13) 54.83,111.95 54.83,111.56 RT93.1
UPD1_SMBINT#: length 244
  TOP w0.107: v1(250.45,99.01) UE1.F10
  IN1 w0.099: v1(96.13,122.74) 95.66,122.74 93.17,120.25 84.87,120.25 84.1,119.47 77.94,119.47 75.18,116.7 70.95,116.7 67.95,113.7 67.95,107.48 68.65,106.78 68.65,99.78 67.5,98.63 65.97,98.63 64.29,96.94 v1(64.23,96.94)
  IN2 w0.089: v1(250.45,99.01) 250.45,99.13 250.01,99.56 250.01,100.19 249.72,100.49 249.72,100.82
  IN2 w0.102: 249.72,100.82 249.72,103.71 248.61,104.82 248.16,104.82 246.53,106.46 246.53,108.89 243.92,111.5 243.92,112.48 239.93,116.47 201.67,116.47 194.75,123.38 194.75,124.96 193.75,125.96 193.75,128.02 192.31,129.46 184.59,129.46 183.31,128.18 164.24,128.18 163.51,128.92 161.54,128.92 161.13,129.33 157.53,129.33 154.14,132.71 146.75,132.71 142.85,128.81 138.56,128.81 136.93,130.44 131.93,130.44 130.7,129.21 126.53,129.21 125.21,130.53 122.88,130.53 121.07,132.34 116.05,132.34 115.47,131.76 114.03,131.76 109.45,127.19 100.58,127.19 v1(96.13,122.74)
  BOTTOM w0.089: v1(250.45,99.01) 250.45,99.3 250.84,99.69 250.84,100.82
  BOTTOM w0.107: RT60.1 61.72,98.67 v2(62.83,97.57) 63.46,96.94 v1(64.23,96.94) ; RE91.1 249.49,101.55 249.99,101.04 250.62,101.04 250.84,100.82
UPD1_SMBUS_ALERT#: length 3.3
  BOTTOM w0.076: 60.96,100.71 60.96,100.79 60.7,101.05 60.7,101.54 60.58,101.66 60.58,102.05 UT5.B6
  BOTTOM w0.107: RT60.2 RT68.1 60.96,100.71
UPD2_SMBCLK: length 13.5
  TOP w0.107: UE1.D7 249.66,96.63 258.13,96.63 258.69,97.19 258.69,97.51 259.05,97.86 259.6,97.86 v2(259.78,98.04) 260.58,98.84 261.39,98.84 RE721.1
UPD2_SMBDAT: length 19.9
  TOP w0.107: RE722.1 264.95,98.78 v1(265.98,98.78)
  TOP w0.127: v1(249.65,95.81) UE1.E7
  IN3 w0.089: v1(249.65,95.81) 250.07,96.24 256.73,96.24 256.76,96.2
  IN3 w0.102: 256.76,96.2 257.06,96.2 257.31,95.95 259.43,95.95 259.88,96.4 264.1,96.4 264.49,96.78 264.85,96.78 265.98,97.91 v1(265.98,98.78)
USB2_ID: length 179.1
  TOP w0.107: RT74.2 62.47,106.6 62.06,107.01 60.96,107.01 60.64,107.33 v2(60.64,109.32) 60.64,110.37 60.32,110.69 v1(60.32,111.8)
  IN1 w0.089: v1(177.62,105.92) 177.62,105.79 177.98,105.43 177.98,105.18 178.19,104.97 179.19,104.97 179.24,104.92 179.54,104.92 179.76,105.13 179.76,106.81 180,107.05 180,108.35 180.27,108.62
  IN1 w0.099: 180.27,108.62 182.96,108.62 184.64,110.31 187.36,110.31 190.62,107.04 195.43,107.04 196,106.47 196.94,106.47 196.97,106.5 196.98,106.5 198.35,107.87 205.13,107.87 v1(206.05,106.94)
  IN3 w0.089: v1(177.62,105.92) 177.62,105.81 177.16,105.36 177.16,105.17 176.01,104.02 175.29,104.02 174.47,103.2 169.67,103.2 169.08,102.61 167.91,102.61 167.83,102.7 153.95,102.7 153.39,103.26 153.39,104.53 152.88,105.04 144.11,105.04 143.31,105.84 140.24,105.84 132.43,113.64
  IN3 w0.102: 132.43,113.64 130.33,115.75 122.88,115.75 122.61,116.01 111.12,116.01 108.53,118.6 99.91,118.6 99.34,119.18 97.39,119.18 96.04,120.53 95.17,120.53 94.03,121.68 88.85,121.68 87.86,120.68 85.34,120.68 84.8,121.23 79.69,121.23 78.86,122.06 76.13,122.06 75.94,121.87 72.4,121.87 63.6,113.07 60.59,113.07 60.32,112.8 v1(60.32,111.8)
  BOTTOM w0.089: v1(177.62,105.92) UC1.CE8
  BOTTOM w0.107: RC337.1 205.74,106.63 v1(206.05,106.94)
USB3_DP2_MRX_C_DTX_N0: length 6.7
  TOP w0.089: 7.81,105.32 7.92,105.32 8.03,105.22 8.29,105.22 9.12,104.38 v4(10.1,104.38) 12.58,104.38 RT220.1 12.96,104.36 13.22,104.36 CT327.2
  TOP w0.102: JUSBC1.A10 7.81,105.32
USB3_DP2_MRX_C_DTX_N1: length 10
  TOP w0.102: JUSBC1.B10 6.37,109.07 v1(6.47,109.17)
  BOTTOM w0.089: CT329.2 14.32,107.13 14.01,107.13 RT222.1 13.68,107.12 13.04,107.12 10.83,109.33 6.73,109.33
  BOTTOM w0.102: v1(6.47,109.17) 6.63,109.33 6.73,109.33
USB3_DP2_MRX_C_DTX_P0: length 6.7
  TOP w0.089: 7.81,104.82 7.92,104.82 8.04,104.95 8.17,104.95 9.01,104.11 v4(11.68,104.11) 12.58,104.11 RT219.1 12.91,104.09 13.26,104.09 CT326.2
  TOP w0.102: JUSBC1.A11 7.81,104.82
USB3_DP2_MRX_C_DTX_P1: length 10
  TOP w0.102: JUSBC1.B11 6.31,109.57 v1(6.47,109.73)
  BOTTOM w0.089: 6.73,109.6 10.94,109.6 v4(12.75,107.8) 13.15,107.39 13.65,107.39 RT221.1 14.01,107.4 14.33,107.4 CT328.2
  BOTTOM w0.102: v1(6.47,109.73) 6.6,109.6 6.73,109.6
USB3_DP2_MRX_DTX_N0: length 30.8
  TOP w0.089: v1(19.94,106.64) 19.95,106.63 19.95,106.33 17.82,104.19 16.54,104.19 RT191.1
  BOTTOM w0.089: v1(19.94,106.64) 22.21,108.91 33.03,108.91 35.61,111.49 38.43,111.49 39.51,110.42 UT9.3
USB3_DP2_MRX_DTX_N1: length 30
  BOTTOM w0.089: RT195.1 17.38,106.82 17.64,106.82 17.73,106.91 17.73,107.22 17.82,107.31 19.16,107.31 21.65,109.8 25.39,109.8 v4(27.78,109.8) 32.25,109.8 34.35,111.9 38.6,111.9 41.3,109.2 41.3,107.46 41.26,107.42 UT9.8
USB3_DP2_MRX_DTX_P0: length 30.9
  TOP w0.089: RT190.1 17.93,103.92 20.24,106.23 v1(20.35,106.23)
  BOTTOM w0.089: v1(20.35,106.23) 20.48,106.1 20.61,106.1 20.76,106.25 20.76,106.5 20.53,106.73 20.53,106.86 22.32,108.64 33.14,108.64 35.72,111.23 38.32,111.23 39.24,110.31 39.24,107.32 39.16,107.24 UT9.2
USB3_DP2_MRX_DTX_P1: length 30
  BOTTOM w0.089: UT9.9 41.61,107.42 41.57,107.46 41.57,109.32 38.72,112.17 34.24,112.17 32.14,110.07 v4(30.25,110.07) 25.28,110.07 21.54,110.07 19.05,107.58 RT194.1
USB3_DP2_MRX_R_DTX_N0: length 1.9
  TOP w0.089: RT191.2 15.4,104.38 15.02,104.38 DT14.1 14.58,104.38 14.19,104.38 CT327.1
USB3_DP2_MRX_R_DTX_N1: length 1.9
  BOTTOM w0.089: RT195.2 16.48,107.13 16.1,107.13 DT10.1 15.66,107.13 15.27,107.13 CT329.1
USB3_DP2_MRX_R_DTX_P0: length 1.9
  TOP w0.089: CT326.1 14.19,104.11 14.58,104.11 DT13.1 15.02,104.11 15.4,104.11 RT190.2
USB3_DP2_MRX_R_DTX_P1: length 1.9
  BOTTOM w0.089: RT194.2 16.48,107.4 16.1,107.4 DT9.1 15.66,107.4 15.27,107.4 CT328.1
USB3_DP2_MTX_C_DRX_N0: length 8.4
  TOP w0.102: v1(6.47,105.26) 6.15,105.57 JUSBC1.B3
  BOTTOM w0.089: 6.73,105.11 6.74,105.11 6.75,105.1 6.84,105.1 6.84,105.1 8.44,105.1 9.16,104.38 12.58,104.38 RT489.1 12.91,104.4 13.29,104.4 CT635.2
  BOTTOM w0.102: v1(6.47,105.26) 6.62,105.11 6.73,105.11
USB3_DP2_MTX_C_DRX_N1: length 8.6
  TOP w0.089: CT637.2 14.36,107.15 14.03,107.15 RT490.1 13.66,107.13 13.33,107.13 v4(12.5,107.96) 11.06,109.41 8.87,109.41 8.4,108.94 8.06,108.94 7.94,108.82 JUSBC1.A3
USB3_DP2_MTX_C_DRX_P0: length 8.4
  TOP w0.102: v1(6.47,104.7) 6.1,105.07 JUSBC1.B2
  BOTTOM w0.089: CT634.2 13.24,104.14 12.96,104.14 RT488.1 12.58,104.11 9.05,104.11 8.33,104.83 6.73,104.83 6.73,104.83
  BOTTOM w0.102: v1(6.47,104.7) 6.6,104.83 6.73,104.83
USB3_DP2_MTX_C_DRX_P1: length 8.6
  TOP w0.089: CT636.2 14.4,107.42 14,107.42 RT491.1 13.66,107.4 13.44,107.4 v4(11.56,109.29) 11.17,109.67 8.76,109.67 8.29,109.21 8.06,109.21 7.94,109.32 JUSBC1.A2
USB3_DP2_MTX_DRX_N0: length 23.6
  BOTTOM w0.089: RT193.1 16.35,104.38 v4(18.13,104.38) 26.38,104.38 29.17,101.58 36.29,101.58 37.24,102.53 37.61,102.53 37.66,102.58 UT9.42
USB3_DP2_MTX_DRX_N1: length 22.6
  TOP w0.089: RT197.1 17.43,107.13 23.59,107.13 v1(23.74,106.97)
  BOTTOM w0.089: v1(23.74,106.97) 23.9,107.13 27.57,107.13 31.38,103.32 37.38,103.32 37.42,103.28 UT9.44
USB3_DP2_MTX_DRX_P0: length 23.6
  BOTTOM w0.089: RT192.1 16.35,104.11 v4(20.3,104.11) 26.26,104.11 29.06,101.31 36.4,101.31 37.35,102.26 37.57,102.26 37.61,102.23 UT9.41
USB3_DP2_MTX_DRX_P1: length 22.6
  TOP w0.089: RT196.1 17.43,107.4 23.59,107.4 v1(23.74,107.56)
  BOTTOM w0.089: UT9.45 37.42,103.63 37.38,103.59 31.5,103.59 27.68,107.4 23.9,107.4 v1(23.74,107.56)
USB3_DP2_MTX_R_DRX_N0: length 1.9
  BOTTOM w0.089: RT193.2 15.4,104.38 15.02,104.38 DT6.1 14.58,104.38 14.15,104.38 CT635.1
USB3_DP2_MTX_R_DRX_N1: length 1.9
  TOP w0.089: RT197.2 16.48,107.13 16.1,107.13 DT18.1 15.66,107.13 15.33,107.13 CT637.1
USB3_DP2_MTX_R_DRX_P0: length 1.9
  BOTTOM w0.089: CT634.1 14.15,104.11 14.57,104.11 DT5.1 15.02,104.11 15.4,104.11 RT192.2
USB3_DP2_MTX_R_DRX_P1: length 1.9
  TOP w0.089: RT196.2 16.48,107.4 16.1,107.4 DT17.1 15.65,107.4 15.33,107.4 CT636.1
USB3_PRX_C_MTX_N1: length 4.2
  BOTTOM w0.112: UT9.11 43.15,106.08 43.23,106 43.5,106 43.59,106.08 43.59,106.57 43.63,106.61 43.63,107.03 v4(44.17,107.57) 44.37,107.77 44.94,107.77 CT111.2
USB3_PRX_C_MTX_P1: length 4.1
  BOTTOM w0.112: UT9.12 43.16,105.73 43.23,105.8 43.58,105.8 43.83,106.04 v4(43.83,106.28) 43.83,106.94 44.08,107.19 44.13,107.19 44.51,107.57 45.14,107.57 CT112.2
USB3_PRX_DTX_N2: length 168.5
  IN1 w0.089: v1(174.84,105.92) 175.02,105.74 175.14,105.74 175.23,105.83 175.23,108.37 176.44,109.59 176.44,111.31 177.74,112.61 187.78,112.61 190.1,114.93 191.73,115.6 197.92,115.6 198.1,115.78 212.34,115.78 224.45,110.69 236.86,110.69 237.16,110.99 247.36,110.99 247.84,110.51 256.44,110.51 256.8,110.15 258.18,110.15 260.94,107.39 261.8,107.39 263.38,105.81 264.97,105.81 265.38,105.39 265.38,103.61 268.76,100.24 268.76,96.33 270.6,94.48 270.6,92.07 271.03,91.64 271.03,89.79 271.07,89.75 271.07,89.75 271.99,88.84 271.99,87.86 272.41,87.44 272.41,85.74 273.05,85.1 275.01,85.1 275.52,84.59 275.52,82.75 276.47,81.8 276.47,79.73 279.93,76.28 281.22,76.28 283.25,74.25 283.25,73.94 283.36,73.84 283.75,73.84 v1(284.16,74.24)
  BOTTOM w0.089: UC1.BY8 v1(174.84,105.92)
  BOTTOM w0.097: v1(284.16,74.24) 284.41,73.98 284.65,73.98 284.71,73.93 284.71,73.93 284.98,73.65 284.98,72.65 289.12,68.52 296.15,68.52 296.18,68.55 296.77,68.55 296.8,68.52 297.21,68.52 298.39,67.34 298.57,67.34 298.72,67.49 DI4.9 DI4.1 300.58,67.49 300.74,67.34 300.94,67.34 302.73,69.13 303.43,69.13 303.84,69.54 304.26,69.54 304.43,69.71 JUSB1.5
USB3_PRX_DTX_N3: length 195.4
  IN1 w0.089: v1(174.87,106.56) 174.87,106.67 174.75,106.78 174.62,106.78 174.48,106.64 174.48,104.91 174.29,104.71 171.85,104.71 171.51,105.05 170.88,105.05 170.57,104.74 168.73,104.74 167.82,105.66 167.82,108.1 167.63,108.29 167.62,108.29 166.94,108.97 166.94,108.99 166.94,109 166.89,109.05 166.89,109.05 166.39,109.55 164.9,109.55 164.09,110.36 159.86,110.36 153.47,116.76 152.74,116.76 151.5,117.99 150.49,117.99 149.73,118.76 146.6,118.76 144.25,121.12 140.7,121.12 139.72,122.09 135.31,122.09 135.15,122.25 135.15,122.25 134.68,122.72 123.37,122.72 122.53,121.88 101.79,121.88 99.78,123.88 74.14,123.88 64.31,114.05 54.03,114.05 50.19,110.21 50.19,99.87 42.78,92.47 26.79,92.47 23.16,88.83 21.31,88.83 v1(21.1,88.63)
  BOTTOM w0.089: v1(174.87,106.56) 174.38,106.32 UC1.BY7
  BOTTOM w0.097: JUSB2.5 14.62,87.5 14.75,87.63 15.16,87.63 15.82,88.29 17.22,88.29 17.76,88.83 18.48,88.83 18.64,88.67 DI1.1 DI1.9 20.19,88.67 20.35,88.83 20.9,88.83 v1(21.1,88.63)
USB3_PRX_DTX_N4: length 194.3
  IN1 w0.089: v1(173.89,107.44) 173.84,107.39 173.54,107.39 173.21,107.72 173.21,108.07 173.73,108.6 173.73,109.36 173.57,109.52 173.57,109.52 172.72,110.37 170.15,110.37 169.86,110.67 169.86,112.88 170.24,113.25 172.72,113.25 174.13,114.26 174.53,115.43 174.69,115.59 176.35,115.59 177.52,116.75 178.18,117.01 180.38,117.01 181.74,118.37 187.52,118.37 187.78,118.63 189.15,118.63 189.71,119.19 194.3,119.19 195.03,118.47 213.89,118.47 215.99,117.61 228.21,114.58 246.41,114.58 249.74,113.2 257.56,113.2 257.92,112.84 259.3,112.84 260.38,111.75 261,111.75 261.61,111.15 262.27,111.15 262.98,110.43 263.55,109.96 264.79,109 266.96,109 267.26,108.7 267.26,108.4 267.69,107.97 267.95,107.97 268.88,107.04 269.97,104.29 270.53,103.05 271.87,101.71 271.87,97.04 273.66,95.24 274.51,93.65 275.45,90.33 277.26,87.26 287.48,77.04 289.39,75.89 293.32,74.72 293.42,74.62 296.83,69.3 296.83,66.58 296.32,62.77 296.32,58.42 297.06,52.5 297.06,51.23 296.99,51.16 296.44,51.16 v1(296.43,51.18)
  BOTTOM w0.076: UC1.BW6 173.46,107 v1(173.89,107.44)
  BOTTOM w0.097: JUSB3.5 304.43,52.48 304.28,52.33 303.89,52.33 303,51.44 302.5,51.44 301.12,50.07 300.71,50.07 300.56,50.22 DI6.1 DI6.9 298.94,50.22 298.83,50.11 298.45,50.11 297.13,51.43 296.84,51.43 296.59,51.18 v1(296.43,51.18)
USB3_PRX_DTX_N5: length 123.9
  IN3 w0.089: v1(173.92,105.28) 173.87,105.33 173.87,105.46 173.96,105.55 174.07,105.55 174.09,105.58 174.2,105.58 174.3,105.48 174.3,104.28 174.5,104.08 175.06,104.08 175.64,104.66 176.02,104.66 176.33,104.97 176.33,108.27 177.41,109.36 178.43,109.36 179.19,110.12 180.74,110.12 180.74,110.12 181.42,110.12 181.8,109.74 183.47,109.74 184.55,110.82 187.17,110.82 190.57,107.42 194.85,107.42 195.33,107.91 198.75,107.91 199.23,107.43 212.42,107.43 215.61,104.24 215.61,100.62 217.13,99.1 217.13,94.2 217.61,93.72 217.61,91.63 221.87,87.37 221.87,86.04 222.4,85.51 222.4,83.76 223.46,82.71 223.46,81.52 225.85,79.13 226.08,79.13 227.72,77.49 229.7,77.49 233.78,73.42 234.84,73.42 234.99,73.27 234.99,73.14 v1(234.74,72.89)
  BOTTOM w0.089: UC1.BW9 v1(173.92,105.28)
  BOTTOM w0.097: RI28.1 262.11,71.06 LI16.4 260.48,71.06 260.06,71.48 v4(259.25,71.48) 245.78,71.48 242.67,74.59 235.14,74.59 234.74,74.19 v1(234.74,72.89)
USB3_PRX_DTX_P2: length 168.6
  IN1 w0.089: v1(284.16,73.66) 283.28,73.66 283.07,73.86 283.07,74.17 281.15,76.1 279.85,76.1 276.29,79.66 276.29,81.72 275.34,82.68 275.34,84.52 274.94,84.92 272.97,84.92 272.23,85.66 272.23,87.37 271.81,87.79 271.81,88.76 270.89,89.68 270.89,89.68 270.85,89.72 270.85,91.57 270.42,92 270.42,94.41 268.58,96.26 268.58,100.16 265.2,103.53 265.2,105.32 264.89,105.63 263.3,105.63 261.72,107.21 260.87,107.21 258.1,109.97 256.73,109.97 256.37,110.33 247.76,110.33 247.29,110.81 237.23,110.81 236.94,110.51 224.41,110.51 212.31,115.6 198.17,115.6 197.99,115.42 191.77,115.42 190.2,114.77 187.86,112.43 177.82,112.43 176.62,111.23 176.62,109.51 176.37,109.26 176.37,109.26 175.41,108.3 175.41,105.75 175.21,105.56 174.93,105.56 174.84,105.47 v1(174.84,105.28)
  BOTTOM w0.089: UC1.BY9 v1(174.84,105.28)
  BOTTOM w0.097: JUSB1.6 304.43,69.19 304.26,69.36 303.92,69.36 303.5,68.94 302.81,68.94 301.02,67.15 300.74,67.15 300.58,66.99 DI4.2 DI4.8 298.72,66.99 298.57,67.15 298.31,67.15 297.13,68.33 v4(296.48,68.33) 289.04,68.33 284.8,72.58 284.8,73.57 284.57,73.8 284.3,73.8 v1(284.16,73.66)
USB3_PRX_DTX_P3: length 195.3
  IN1 w0.089: v1(174.87,107.2) 174.87,107.06 174.76,106.96 174.55,106.96 174.3,106.71 174.3,104.98 174.21,104.89 171.92,104.89 171.58,105.23 170.81,105.23 170.5,104.92 168.81,104.92 167.99,105.73 167.99,108.17 167.75,108.42 167.75,108.42 167.11,109.05 167.11,109.07 167.07,109.12 167.07,109.13 166.46,109.73 164.98,109.73 164.17,110.54 159.94,110.54 153.55,116.94 152.81,116.94 151.58,118.17 150.57,118.17 149.8,118.94 146.68,118.94 144.32,121.3 140.77,121.3 139.8,122.27 135.38,122.27 135.23,122.43 135.23,122.43 134.75,122.9 123.29,122.9 122.45,122.06 101.86,122.06 99.86,124.06 74.07,124.06 64.23,114.23 53.95,114.23 50,110.28 50,99.94 42.71,92.65 26.72,92.65 23.08,89.01 21.31,89.01 v1(21.1,89.21)
  BOTTOM w0.089: UC1.BY6 v1(174.87,107.2)
  BOTTOM w0.097: JUSB2.6 14.62,87.95 14.62,87.95 14.75,87.82 15.08,87.82 15.74,88.48 17.14,88.48 17.68,89.02 18.49,89.02 18.65,89.17 DI1.2 DI1.8 20.18,89.17 20.34,89.02 20.9,89.02 v1(21.1,89.21)
USB3_PRX_DTX_P4: length 194.3
  IN1 w0.089: v1(296.84,50.76) 297.24,51.16 297.24,52.42 297.24,52.52 296.5,58.44 296.5,58.6 296.5,62.76 297.01,66.57 297.01,69.35 293.57,74.74 293.42,74.88 289.47,76.06 287.59,77.18 277.4,87.37 275.62,90.4 274.68,93.72 273.81,95.35 272.05,97.11 272.05,101.79 270.68,103.15 270.13,104.36 269.03,107.15 268.02,108.15 267.76,108.15 267.44,108.48 267.44,108.77 267.03,109.18 264.85,109.18 263.66,110.1 263.1,110.57 262.4,111.27 262.34,111.33 261.69,111.33 261.08,111.94 260.46,111.94 259.37,113.02 258,113.02 257.63,113.38 249.78,113.38 246.44,114.76 228.23,114.76 216.04,117.78 213.93,118.65 195.1,118.65 194.38,119.37 189.63,119.37 189.07,118.81 187.71,118.81 187.45,118.55 181.66,118.55 180.3,117.19 178.15,117.19 177.42,116.91 176.28,115.77 174.62,115.77 174.38,115.53 173.98,114.37 172.66,113.43 170.16,113.43 169.68,112.95 169.68,110.59 170.07,110.19 172.64,110.19 173.39,109.45 173.39,109.44 173.55,109.28 173.55,108.67 173.03,108.15 v1(173.03,107.39)
  BOTTOM w0.076: v1(173.03,107.39) 173.22,107.39 173.45,107.62 UC1.BW5
  BOTTOM w0.097: v1(296.84,50.76) 296.84,51.17 296.92,51.24 297.05,51.24 298.37,49.93 298.76,49.93 298.96,49.72 DI6.8 DI6.2 300.53,49.72 300.69,49.88 301.2,49.88 302.57,51.25 303.08,51.25 303.97,52.14 304.25,52.14 304.43,51.97 JUSB3.6
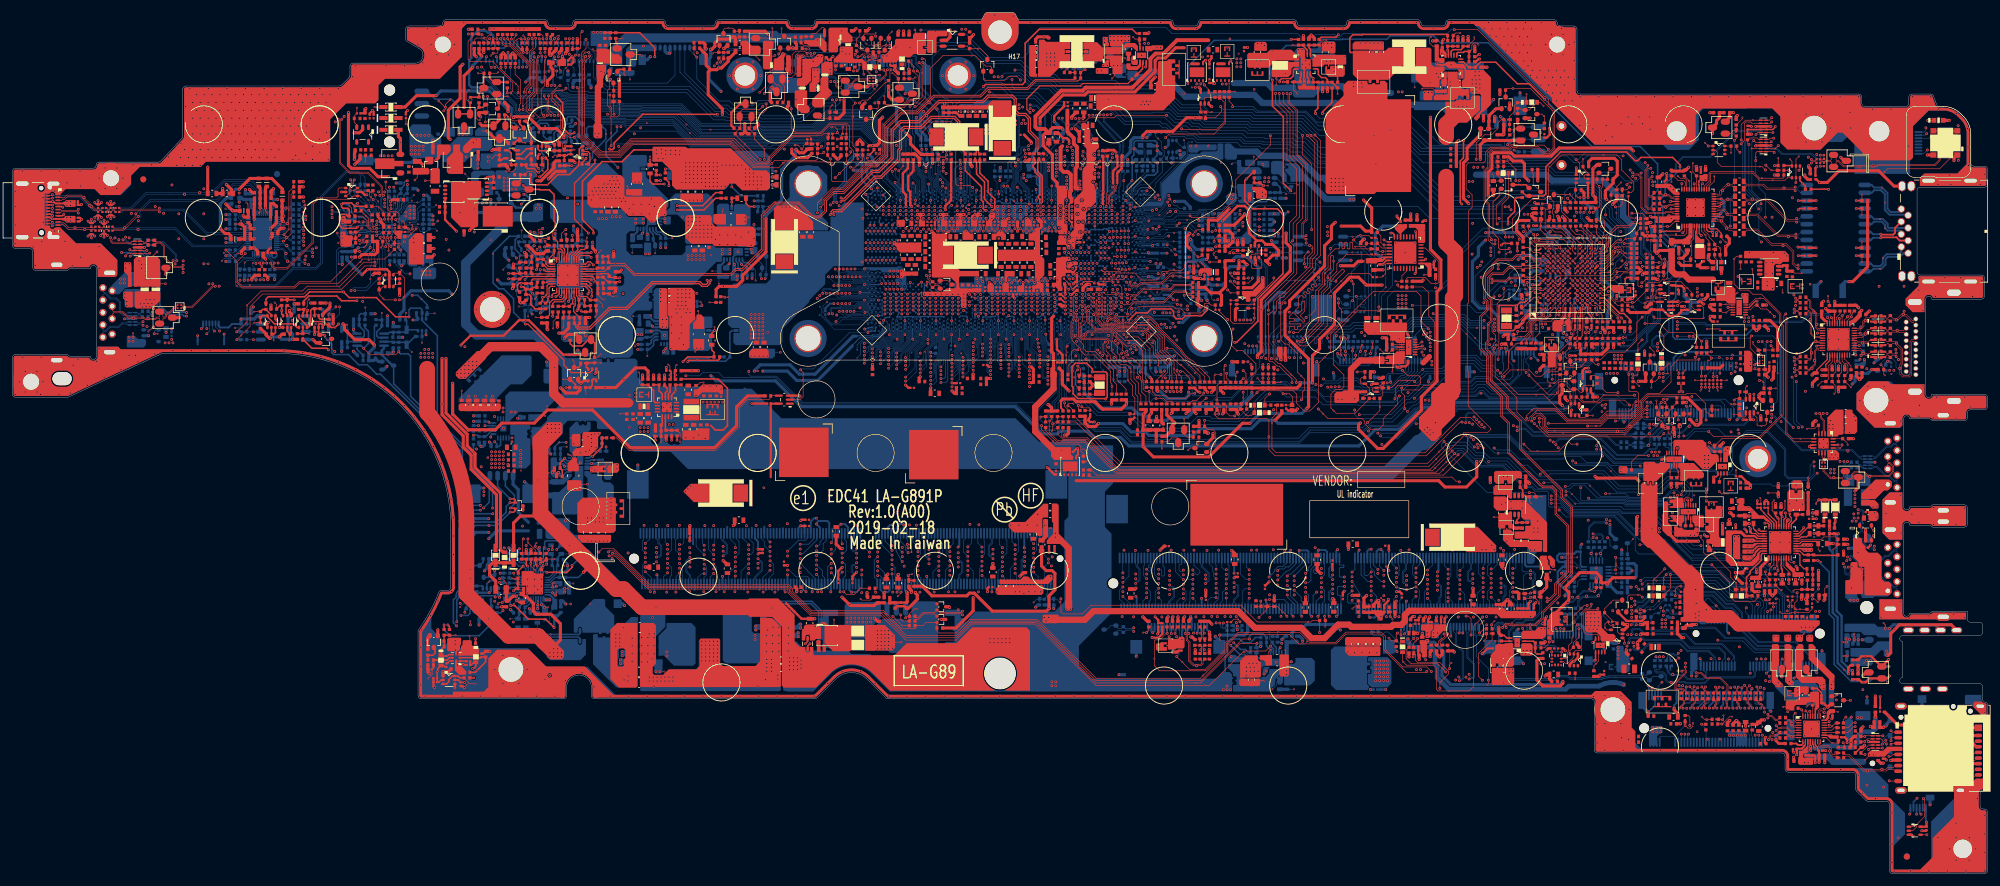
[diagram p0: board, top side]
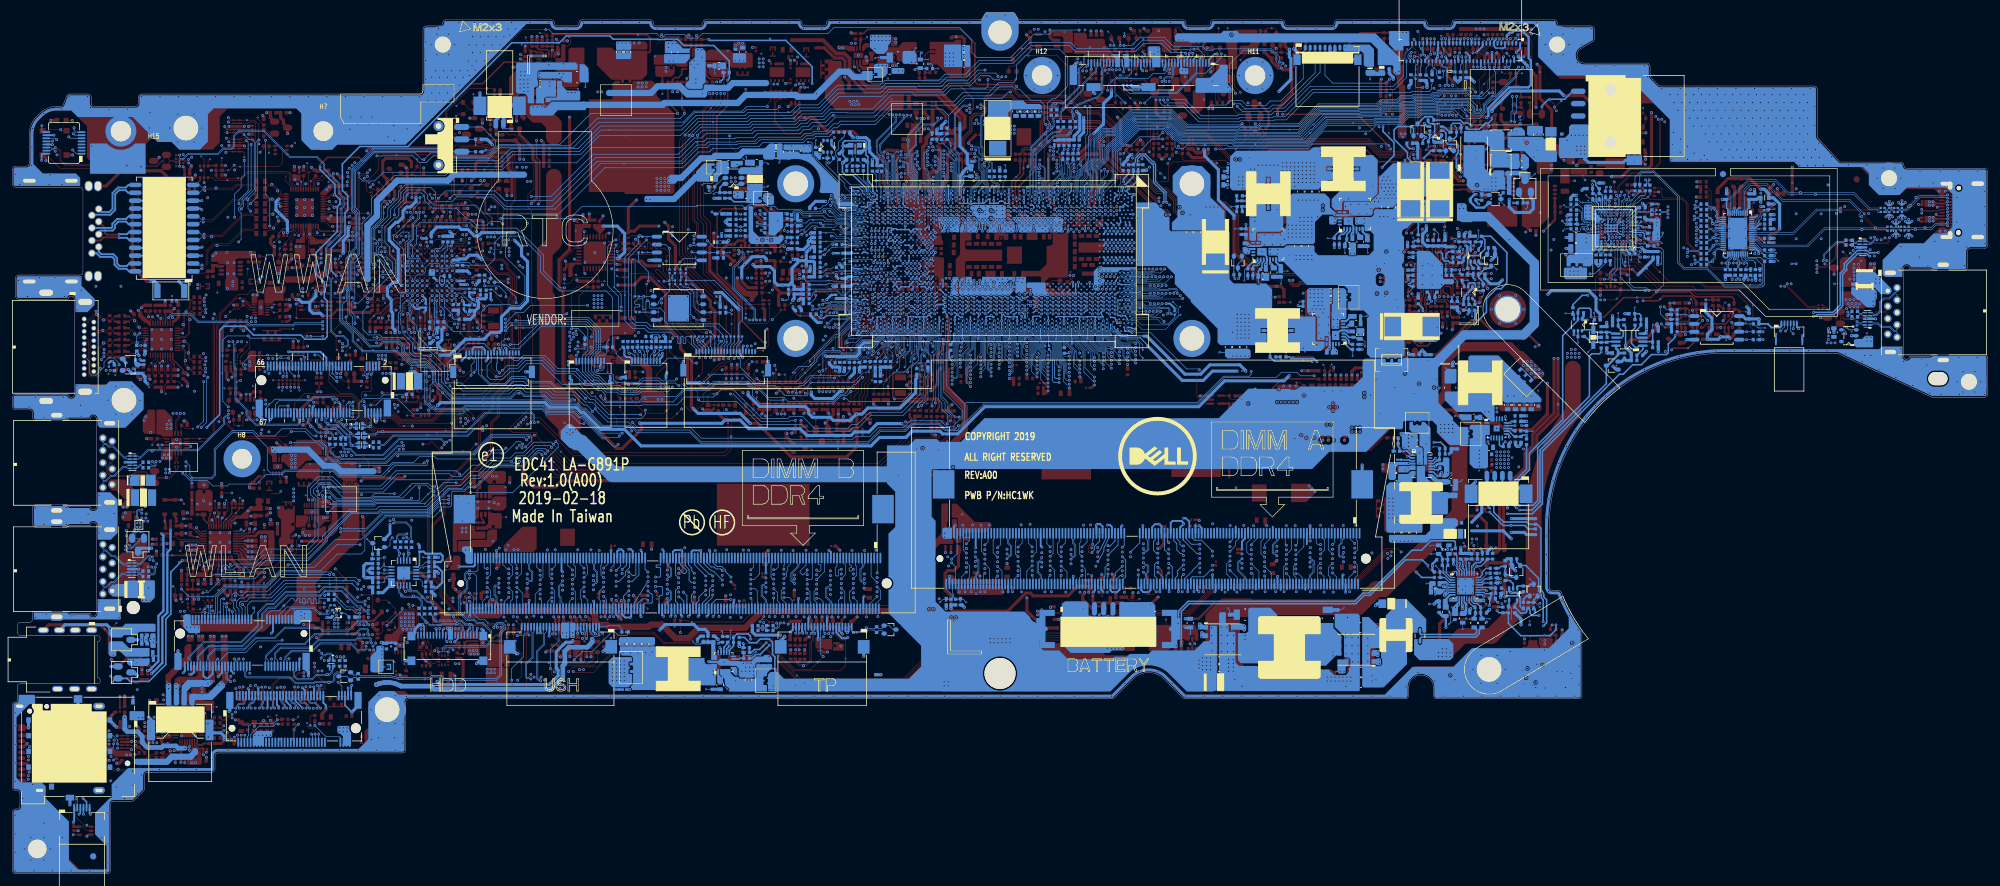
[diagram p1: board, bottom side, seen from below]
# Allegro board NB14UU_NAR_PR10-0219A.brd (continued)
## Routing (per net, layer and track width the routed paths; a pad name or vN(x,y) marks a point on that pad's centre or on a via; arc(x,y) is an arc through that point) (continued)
USB3_PRX_DTX_P5: length 123.9
  IN3 w0.089: v1(235.32,72.89) 235.17,73.04 235.17,73.34 234.91,73.6 233.85,73.6 229.78,77.67 227.8,77.67 226.15,79.31 225.92,79.31 223.64,81.6 223.64,82.78 222.58,83.84 222.58,85.59 222.05,86.12 222.05,87.44 217.79,91.7 217.79,93.79 217.31,94.28 217.31,99.17 215.79,100.7 215.79,104.32 212.5,107.61 199.31,107.61 198.83,108.09 195.26,108.09 194.78,107.6 190.65,107.6 187.25,111 184.48,111 183.39,109.92 181.87,109.92 181.49,110.3 180.74,110.3 179.12,110.3 178.36,109.54 177.34,109.54 176.15,108.34 176.15,105.04 175.94,104.84 175.56,104.84 174.99,104.26 174.57,104.26 174.48,104.35 174.48,105.55 174.28,105.76 174.08,105.76 v1(173.92,105.92)
  BOTTOM w0.089: UC1.BW8 v1(173.92,105.92)
  BOTTOM w0.097: v1(235.32,72.89) 234.92,73.28 234.92,74.11 235.21,74.4 242.6,74.4 245.7,71.29 258.93,71.29 258.96,71.26 259.55,71.26 259.58,71.29 259.98,71.29 260.4,70.88 261.49,70.88 261.8,70.56 LI16.1 262.11,70.56 RI27.1
USB3_PRX_L_DTX_N2: length 6.4
  BOTTOM w0.097: JNGFF2.21 266.58,73.71 266.5,73.64 266.5,73.54 266.56,73.49 266.82,73.49 266.89,73.41 266.89,73.25 266.79,73.16 266.2,73.16 265.95,72.91 265.84,72.8 265.71,72.67 v4(265.55,72.51) 265.37,72.33 264.5,71.46 264.46,71.46 263.87,70.87 263.78,70.87 263.59,71.06 LI16.3 263.28,71.06 RI28.2
USB3_PRX_L_DTX_P2: length 6.4
  BOTTOM w0.097: JNGFF2.23 267.08,73.18 266.87,72.97 266.28,72.97 265.97,72.67 265.97,72.62 265.49,72.14 265.44,72.14 v4(264.4,71.1) 263.99,70.69 263.71,70.69 263.59,70.56 LI16.2 263.28,70.56 RI27.2
USB3_PRX_MTX_N1: length 170.6
  IN3 w0.089: 148.78,111.56 148.78,111.46 148.39,111.07 142.68,111.07 142.2,111.56 ; 153.86,111.56 153.86,111.53 153.86,111.53 153.86,110.73 151.37,108.24 151.37,105.79 151.6,105.55 153.6,105.55 154.6,104.55 154.6,103.66 155.01,103.25 168.77,103.25 169.66,104.15 172.19,104.15 173.38,105.34 173.38,106.72 173.7,107.04 174.02,107.04 174.33,107.35 174.33,108.15 174.56,108.38 175.09,108.38 175.41,108.07 175.41,107.84 175.53,107.71 175.66,107.71 v1(175.77,107.82)
  IN3 w0.102: v1(47.27,108.06) 47.46,107.87 47.95,107.87 48.32,108.23 48.32,113.69 57.51,122.88 61.07,122.88 64.94,126.75 77.48,126.75 78.91,125.31 94.1,125.31 95.84,123.57 110.11,123.57 114.62,119.06 131.42,119.06 132.23,118.25 133.66,118.25 134.49,117.42 134.49,116.66 137.66,113.48 139,113.48 140.83,111.65 142.1,111.65 142.2,111.56 ; 148.78,111.56 148.78,111.98 149.56,112.77 150.99,112.77 151.24,113.02 151.24,114.76 152.57,116.09 153.35,116.09 153.86,115.57 153.86,111.56
  BOTTOM w0.076: UC1.CB5 v1(175.77,107.82)
  BOTTOM w0.112: CT111.1 46.63,107.88 47.09,107.88 v1(47.27,108.06)
USB3_PRX_MTX_P1: length 170.7
  IN3 w0.089: 142.06,111.42 142.08,111.41 142.08,111.41 142.12,111.37 142.13,111.37 142.61,110.89 148.46,110.89 148.96,111.4 148.96,111.53 148.97,111.53 148.97,111.56 ; 153.67,111.56 153.67,111.53 153.68,111.53 153.68,110.8 151.19,108.32 151.19,105.71 151.52,105.38 153.52,105.38 154.42,104.48 154.42,103.59 154.94,103.07 168.84,103.07 169.74,103.97 172.26,103.97 173.56,105.27 173.56,106.65 173.77,106.86 174.09,106.86 174.5,107.27 174.5,108.08 174.63,108.21 175.02,108.21 175.23,107.99 175.23,107.77 175.54,107.46 175.54,107.41 v1(175.77,107.19)
  IN3 w0.102: 148.97,111.56 148.97,111.9 149.64,112.58 151.07,112.58 151.43,112.94 151.43,114.68 152.65,115.9 153.27,115.9 153.67,115.5 153.67,111.56 ; 142.06,111.42 142.03,111.46 140.76,111.46 138.92,113.29 137.58,113.29 134.3,116.58 134.3,117.34 133.58,118.06 132.15,118.06 131.34,118.87 114.54,118.87 110.04,123.38 95.76,123.38 94.02,125.12 78.83,125.12 77.4,126.56 65.02,126.56 61.15,122.69 57.59,122.69 48.51,113.61 48.51,108.15 48.03,107.67 47.46,107.67 v1(47.27,107.48)
  BOTTOM w0.089: v1(175.77,107.19) UC1.CB6
  BOTTOM w0.112: CT112.1 46.66,107.68 47.06,107.68 v1(47.27,107.48)
USB3_PTX_C_DRX_N2: length 8.7
  BOTTOM w0.097: CI13.1 297.95,66.42 298.25,66.11 298.45,66.11 298.73,65.84 298.87,65.84 299.03,65.99 DI4.7 DI4.4 300.41,65.99 300.56,65.84 301.21,65.84 302.65,64.39 303.16,64.39 304.04,63.51 304.33,63.51 304.43,63.61 JUSB1.8
USB3_PTX_C_DRX_N3: length 9.8
  BOTTOM w0.097: CI5.1 20.66,90.33 20.33,90.33 20.17,90.17 DI1.7 DI1.4 17.9,90.17 17.29,90.79 17.29,92.32 16.74,92.86 15.86,92.86 15.02,93.7 14.8,93.7 14.62,93.51 JUSB2.8
USB3_PTX_C_DRX_N4: length 8.4
  BOTTOM w0.097: CI27.1 298.27,48.58 298.68,48.58 298.82,48.72 DI6.7 DI6.4 300.71,48.72 300.86,48.57 301.33,48.57 302.65,47.25 303.09,47.25 303.98,46.36 304.33,46.36 304.43,46.46 JUSB3.8
USB3_PTX_C_DRX_N5: length 1.7
  BOTTOM w0.097: CI29.1 261.1,69.38 261.51,69.38 261.66,69.54 LI17.4 262.03,69.54 RI30.1
USB3_PTX_C_DRX_P2: length 8.7
  BOTTOM w0.097: CI16.1 298.27,65.93 298.38,65.93 298.65,65.65 298.91,65.65 299.06,65.49 DI4.6 DI4.5 300.43,65.49 300.59,65.65 301.13,65.65 302.57,64.21 303.08,64.21 303.96,63.32 304.32,63.32 304.43,63.21 JUSB1.9
USB3_PTX_C_DRX_P3: length 9.7
  BOTTOM w0.097: JUSB2.9 14.62,94.14 14.88,93.88 15.1,93.88 15.93,93.05 16.82,93.05 17.47,92.4 17.47,90.87 17.98,90.36 18.31,90.36 18.62,90.67 DI1.5 DI1.6 20.18,90.67 20.34,90.52 20.64,90.52 CI4.1
USB3_PTX_C_DRX_P4: length 8.5
  BOTTOM w0.097: JUSB3.9 304.43,45.97 304.22,46.17 303.91,46.17 303.02,47.06 302.57,47.06 301.26,48.38 300.86,48.38 300.71,48.22 DI6.5 DI6.6 298.85,48.22 298.68,48.4 298.33,48.4 CI28.1
USB3_PTX_C_DRX_P5: length 1.7
  BOTTOM w0.097: RI29.1 262.03,69.04 LI17.1 261.66,69.04 261.51,69.2 261.1,69.2 CI30.1
USB3_PTX_C_MRX_N1: length 3.5
  BOTTOM w0.112: UT9.14 43.3,105.03 43.38,104.95 43.94,104.95 44.42,105.44 44.42,105.75 44.76,106.08 45.03,106.08 CT113.2
USB3_PTX_C_MRX_P1: length 3.6
  BOTTOM w0.112: CT114.2 45.05,105.88 44.84,105.88 44.62,105.66 44.62,105.3 v4(44.39,105.06) 44.08,104.75 43.38,104.75 43.3,104.68 UT9.15
USB3_PTX_DRX_N2: length 161.1
  IN1 w0.089: v1(296.43,66.61) 296.35,66.69 296.35,69.28 294.54,71.1 291.04,71.1 283.9,78.23 282.96,78.23 279.6,81.6 279.6,82.98 273.74,88.83 273.74,89.52 272.76,90.51 272.76,94.78 270.9,96.64 270.9,100.87 267.95,103.81 267.95,105.31 267.18,106.08 267.18,106.77 265.93,108.03 263.59,108.03 261.88,109.74 261.02,109.74 258.89,111.87 257.52,111.87 257.16,112.23 248.69,112.23 248.22,112.71 247.53,112.71 247.06,113.18 223.04,113.18 212.75,117.5 194.62,117.5 193.94,118.19 190.31,118.19 190.02,118.13 189.29,117.41 188.38,117.41 186.43,115.46 184.73,115.46 183.7,114.44 177.29,114.44 176.95,114.78 175.31,114.78 v1(175.1,114.99)
  BOTTOM w0.076: v1(175.1,114.99) 174.44,114.99 174.26,114.82 174.26,113.05 173.76,112.55 173.76,111.29 174.26,110.79 174.26,110.17 174.31,110.12 UC1.CA2
  BOTTOM w0.097: v1(296.43,66.61) 296.03,66.21 296.03,66.03 296.12,65.93 296.47,65.93 CI13.2
USB3_PTX_DRX_N3: length 193
  IN1 w0.089: v1(169.6,122.11) 169.59,122.11 169.17,122.52 165.04,122.52 164.9,122.39 164.08,122.39 163.74,122.73 161.76,122.73 159.71,124.77 147.08,124.77 146.63,125.22 135.45,125.22 134.69,125.98 132.46,125.98 131.76,125.29 101.48,125.29 100.34,126.43 84.82,126.43 84.12,125.73 78.37,125.73 77.83,126.27 71.52,126.27 67.1,121.86 55.55,121.86 45.05,111.36 45.05,97.84 40.88,93.66 26.78,93.66 22.78,89.66 21.98,89.66 21.83,89.81 21.83,90.25 22,90.42 22.36,90.42 v1(22.6,90.18)
  BOTTOM w0.076: UC1.BY4 173.95,108.92 174.21,109.19 174.21,109.93 174.09,110.06 174.09,110.74 173.6,111.22 173.6,112.75 174.09,113.24 174.09,116.88 173.46,117.5
  BOTTOM w0.097: CI5.2 22.3,90.38 22.4,90.38 v1(22.6,90.18) ; v1(169.6,122.11) 169.6,121.79 170.22,121.17 171.88,121.17 173.19,119.86 173.19,117.77 173.46,117.5
USB3_PTX_DRX_N4: length 191.7
  IN1 w0.089: v1(172.94,116.73) 173.14,116.53 174.27,116.53 174.93,117.2 181.96,120.11 186.59,120.11 187.46,120.98 189.09,120.98 189.54,120.52 212.92,120.52 227.69,116.66 241.35,116.66 242.09,115.91 248.32,115.91 249.22,116.8 255.39,116.8 257.66,114.53 258.11,114.53 258.33,114.31 261.57,114.31 262.63,113.24 262.63,112.99 265.3,110.33 267.95,110.33 268.6,109.68 273.23,109.68 273.74,109.17 273.74,103.58 274.56,102.76 274.56,100.65 273.42,99.5 273.42,97.43 276.71,94.14 276.71,91.35 278.03,90.03 279.21,87.19 287.77,78.63 288.27,78.63 289.42,77.48 292.44,77.48 299.55,70.37 299.55,56.93 298.06,55.44 298.06,51.06 296.99,50 296.54,50 296.45,49.91 296.45,49.64 v1(296.55,49.54)
  BOTTOM w0.076: UC1.BW2 173.76,110.31 173.76,110.6 173.27,111.09 173.27,113.01 173.76,113.5 173.76,116.14 173.37,116.54 173.13,116.54 v1(172.94,116.73)
  BOTTOM w0.097: CI27.2 296.59,48.46 296.29,48.46 296.15,48.6 296.15,49.15 v1(296.55,49.54)
USB3_PTX_DRX_N5: length 136.6
  IN1 w0.089: v1(243.06,72.19) 242.61,71.74 234.08,71.74 232.72,73.1 232.72,80.21 230.13,82.8 v1(229.27,82.8)
  IN3 w0.089: v1(229.27,82.8) 229.37,82.9 229.47,82.9 229.62,82.75 229.62,82.48 229.71,82.4 229.96,82.4 230.06,82.5 230.06,82.81 229.42,83.45 229.42,88.14 227.4,90.16 227.4,92.04 225.56,93.88 225.56,94.3 223.91,95.95 223.91,96.96 222.19,98.68 222.19,102.93 221.87,103.25 221.87,108.41 215.06,115.23 199.92,115.23 196.49,118.67 188.34,118.67 185.54,115.87 181.57,115.87 179.48,117.97 174.43,117.97 173.78,117.32 173.78,115.07 173.54,114.83 173.27,114.83 v1(172.87,114.43)
  BOTTOM w0.076: UC1.BW4 173.11,108.64 173.11,109.19 172.96,109.53 172.96,109.56 172.96,109.57 172.96,109.79 172.99,109.88 172.99,110.1 172.99,110.12 172.96,110.2 172.96,110.69 172.78,110.87 172.78,113.36 173.27,113.85 173.27,114.56 173.18,114.64 173.08,114.64 v1(172.87,114.43)
  BOTTOM w0.097: v1(243.06,72.19) 243.26,71.99 244.44,71.99 245.54,70.89 257.54,70.89 259.05,69.38 259.49,69.38 CI29.2
USB3_PTX_DRX_P2: length 161
  IN1 w0.089: v1(175.06,114.25) 175.06,114.48 175.18,114.6 176.87,114.6 177.21,114.26 183.78,114.26 184.8,115.28 186.51,115.28 188.45,117.23 189.36,117.23 190.11,117.97 190.33,118.01 193.86,118.01 194.55,117.32 212.71,117.32 223.01,113 246.99,113 247.46,112.53 248.14,112.53 248.62,112.05 257.08,112.05 257.44,111.69 258.82,111.69 260.95,109.56 261.81,109.56 263.52,107.85 265.85,107.85 267,106.7 267,106.01 267.77,105.24 267.77,103.74 270.72,100.79 270.72,96.56 272.58,94.71 272.58,90.43 273.56,89.44 273.56,88.75 279.42,82.9 279.42,81.52 282.89,78.05 283.82,78.05 290.96,70.92 294.46,70.92 296.17,69.21 296.17,66.94 v1(295.84,66.61)
  BOTTOM w0.076: UC1.CA1 174.45,110.31 174.42,110.35 174.42,111.01 174.35,111.09 174.19,111.09 173.92,111.36 173.92,112.48 174.43,112.98 174.43,114.75 174.51,114.82 174.73,114.82 174.93,114.62 175.21,114.62 175.28,114.55 175.28,114.38 175.15,114.25 v1(175.06,114.25)
  BOTTOM w0.097: v1(295.84,66.61) 295.84,65.95 296.05,65.75 296.9,65.75 CI16.2
USB3_PTX_DRX_P3: length 193
  IN1 w0.089: v1(22.6,90.76) 22.44,90.6 21.93,90.6 21.65,90.32 21.65,89.74 21.9,89.48 22.86,89.48 26.86,93.48 40.95,93.48 45.23,97.76 45.23,111.28 55.63,121.68 67.18,121.68 71.59,126.09 77.75,126.09 78.29,125.55 84.2,125.55 84.89,126.25 100.26,126.25 101.4,125.11 131.84,125.11 132.53,125.8 134.62,125.8 135.38,125.04 146.55,125.04 147,124.59 159.64,124.59 161.68,122.55 163.66,122.55 164.01,122.21 164.98,122.21 165.12,122.34 168.92,122.34 169.01,122.26 v1(169.01,122.11)
  BOTTOM w0.076: 173,117.83 173,117.7 173.06,117.64 173.34,117.36 173.35,117.36 173.39,117.33 173.4,117.33 173.92,116.81 173.92,113.31 173.43,112.82 173.43,111.16 173.92,110.67 173.92,109.99 174.05,109.86 174.05,109.75 173.97,109.67 173.77,109.67 173.69,109.6 173.69,109.37 173.76,109.3 173.91,109.3 UC1.BY3
  BOTTOM w0.097: 173,117.83 173,119.78 171.8,120.98 170.14,120.98 v1(169.01,122.11) ; v1(22.6,90.76) 22.4,90.56 22.23,90.56 CI4.2
USB3_PTX_DRX_P4: length 191.6
  IN1 w0.089: v1(295.97,49.54) 296.27,49.85 296.27,49.98 296.46,50.18 296.92,50.18 297.88,51.14 297.88,55.52 299.37,57.01 299.37,70.3 292.37,77.3 289.35,77.3 288.2,78.45 287.69,78.45 279.05,87.09 277.88,89.92 276.53,91.27 276.53,94.06 273.24,97.36 273.24,99.58 274.38,100.72 274.38,102.69 273.56,103.51 273.56,109.09 273.15,109.5 268.52,109.5 267.88,110.15 265.22,110.15 262.45,112.92 262.45,113.17 261.49,114.13 258.26,114.13 258.04,114.35 257.59,114.35 255.31,116.62 249.29,116.62 248.4,115.73 242.02,115.73 241.27,116.48 227.67,116.48 212.89,120.34 189.46,120.34 189.01,120.8 187.53,120.8 186.67,119.93 181.99,119.93 175.03,117.05 174.34,116.35 173.17,116.35 172.89,116.07 v1(172.89,116)
  BOTTOM w0.076: UC1.BW1 173.52,110.31 173.59,110.39 173.59,110.53 173.11,111.02 173.11,113.08 173.59,113.57 173.59,116.08 173.3,116.37 172.68,116.37 172.64,116.33 172.64,116.08 172.72,116 v1(172.89,116)
  BOTTOM w0.097: v1(295.97,49.54) 295.97,48.52 296.21,48.27 296.78,48.27 CI28.2
USB3_PTX_DRX_P5: length 136.6
  IN1 w0.089: v1(243.06,71.61) 243.01,71.56 234,71.56 232.54,73.02 232.54,80.14 230.06,82.62 229.67,82.62 v1(229.27,82.22)
  IN3 w0.089: v1(229.27,82.22) 229.39,82.22 230.03,82.22 230.24,82.42 230.24,82.89 229.6,83.52 229.6,88.22 227.58,90.24 227.58,92.11 225.74,93.95 225.74,94.37 224.09,96.02 224.09,97.04 222.37,98.75 222.37,103.01 222.05,103.32 222.05,108.49 215.13,115.41 200,115.41 196.56,118.85 188.26,118.85 185.46,116.05 181.65,116.05 179.55,118.15 174.35,118.15 173.6,117.39 173.6,115.14 173.47,115.01 v1(172.87,115.01)
  BOTTOM w0.076: v1(172.87,115.01) 173.08,114.8 173.25,114.8 173.43,114.62 173.43,113.78 172.94,113.29 172.94,110.94 173.12,110.76 173.12,110.23 173.14,110.17 173.16,110.13 173.16,109.85 173.12,109.76 173.12,109.57 173.17,109.45 173.29,109.33 173.47,109.33 173.62,109.18 173.62,109.06 173.54,108.97 173.43,108.97 UC1.BW3
  BOTTOM w0.097: CI30.2 259.49,69.2 258.97,69.2 257.46,70.71 245.46,70.71 244.36,71.81 243.26,71.81 v1(243.06,71.61)
USB3_PTX_L_DRX_N2: length 9.3
  BOTTOM w0.097: RI30.2 263.21,69.54 LI17.3 263.59,69.54 263.9,69.23 263.98,69.23 264.47,69.72 264.47,70.6 264.57,70.7 265.06,71.19 265.12,71.19 266.48,72.56 267.9,72.56 v4(268.09,72.75) 268.39,73.05 268.39,73.5 268.33,73.56 268.13,73.56 268.08,73.62 JNGFF2.27
USB3_PTX_L_DRX_P2: length 9.3
  BOTTOM w0.097: JNGFF2.29 268.58,72.93 268.02,72.37 266.56,72.37 265.19,71 265.14,71 264.66,70.52 264.66,69.59 v4(264.3,69.23) 264.1,69.04 LI17.2 263.21,69.04 RI29.2
USB3_PTX_MRX_N1: length 157.8
  IN1 w0.089: 174.51,109.39 174.51,109.37 174.5,109.37 174.5,107.29 174.12,106.9 173.81,106.9 173.68,106.77 172.77,106.77 172.41,107.12 172.41,108.08 171.89,108.6 171.19,108.6 170.42,109.37 169.86,109.37 169.85,109.36 169.83,109.36
  IN1 w0.102: v1(47.38,106.28) 47.05,106.28 46.99,106.22 46.99,105.99 46.89,105.89 46.26,105.89 46.16,105.99 46.16,109.04 57.9,120.78 68.3,120.78 72.18,124.67 100.11,124.67 101.45,123.33 122.61,123.33 123.44,124.15 134.49,124.15 135.76,122.88 143.59,122.88 146.93,119.54 150.05,119.54 150.82,118.78 151.83,118.78 153.06,117.54 153.8,117.54 158.62,112.71 160.94,112.71 162.26,111.39 165.84,111.39 167.87,109.36 169.83,109.36 ; 174.51,109.39 174.51,110.37 174.37,110.52 174.37,111.26 174.5,111.39 v1(175.06,111.39)
  BOTTOM w0.076: UC1.CA4 174.78,108.63 174.78,109.09 174.79,109.19 174.94,109.53 174.94,109.78 174.91,109.88 174.91,110.1 174.91,110.11 174.91,110.12 174.94,110.2 174.94,110.53 174.85,110.62 174.75,110.71 174.75,111.08 v1(175.06,111.39)
  BOTTOM w0.112: CT113.1 46.65,106.09 47.19,106.09 v1(47.38,106.28)
USB3_PTX_MRX_P1: length 157.8
  IN1 w0.089: 174.32,109.39 174.32,109.38 174.33,109.37 174.33,107.36 174.04,107.08 173.73,107.08 173.6,106.94 172.84,106.94 172.59,107.2 172.59,108.15 171.97,108.77 171.27,108.77 170.49,109.55 169.86,109.55 169.85,109.55 169.83,109.55
  IN1 w0.102: v1(174.65,111.81) 174.18,111.34 174.18,110.44 174.32,110.29 174.32,109.39 ; v1(47.38,105.7) 47.23,105.7 46.18,105.7 45.97,105.91 45.97,109.12 57.82,120.97 68.22,120.97 72.11,124.86 100.19,124.86 101.53,123.52 122.53,123.52 123.36,124.34 134.57,124.34 135.84,123.07 143.67,123.07 147.01,119.73 150.13,119.73 150.89,118.97 151.91,118.97 153.14,117.73 153.87,117.73 158.7,112.9 161.02,112.9 162.34,111.58 165.92,111.58 167.95,109.55 169.83,109.55
  BOTTOM w0.076: UC1.CA3 174.47,109.01 174.38,109.11 174.38,109.23 174.47,109.32 174.6,109.32 174.7,109.38 174.7,109.39 174.77,109.57 174.77,109.76 174.74,109.85 174.74,110.13 174.77,110.22 174.77,110.46 174.58,110.65 174.58,111.15 174.7,111.27 174.7,111.43 174.54,111.59 174.54,111.7 v1(174.65,111.81)
  BOTTOM w0.112: CT114.1 46.64,105.89 47.19,105.89 v1(47.38,105.7)
USB20_N1: length 174.5
  TOP w0.097: v1(59.95,109.62) 59.74,109.83 59.74,111.1 57.46,113.39 54.52,113.39 53.01,114.9 53.01,121.72 v1(53.2,121.92)
  IN1 w0.089: v1(53.2,121.92) 53.2,122.08 53.16,122.12 53.01,122.12 52.92,122.21 52.92,122.34 55.49,124.91 69.02,124.91 72.92,128.82 99.25,128.82 104.21,133.77 118.62,133.77 121.69,130.7 139.26,130.7 140.13,131.57 140.13,132.33 140.64,132.85 146.56,132.85 148.01,131.39 148.01,127.33 149.6,125.74 165.36,125.74 166.75,124.35 173.94,124.35 174.93,123.36 174.93,122.99 174.88,122.94 174.55,122.94 174.52,122.91 v1(174.52,122.58)
  BOTTOM w0.076: UT5.K5 60.08,106.72 60.05,106.96 59.64,107.38 59.64,108.57 59.65,108.58 59.65,108.66 ; 178.77,117.5 178.77,117.49 178.78,117.48 178.78,117.43 178.79,117.42 178.79,116.85 178.05,115.29 177.49,114.73 177.49,112.14 177.42,112.07 177.39,112.07 177.31,111.99 177.31,111.84 177.39,111.76 177.42,111.76 177.49,111.69 177.49,111.47 177.07,111.05 177.07,110.62 177.22,110.47 177.22,110.22 177.18,110.13 177.18,109.85 177.22,109.76 177.22,109.57 177.17,109.47 177.13,109.39 177.08,109.33 176.88,109.33 176.81,109.26 176.81,109.19 176.79,109.16 176.79,109.1 176.88,109.01 UC1.CE3
  BOTTOM w0.097: v1(174.52,122.58) 174.82,122.29 174.83,122.29 174.92,122.2 174.92,122.06 178.77,117.82 178.77,117.5 ; v1(59.95,109.62) 59.75,109.42 59.75,109.11 59.65,109.01 59.65,108.66
USB20_N2: length 151.7
  TOP w0.097: v1(292.5,74.38) 292.23,74.11 292.23,73.73 292.67,73.29 292.67,71.57 292.79,71.45 UI3.2
  IN1 w0.089: v1(292.5,74.38) 292.41,74.3 292.41,73.92 292.16,73.67 291.25,73.67 290.61,73.94 289.23,74.86 283.76,79.35 280.24,81.7 279.99,82.16 279.99,83.14 278.85,84.28 276.45,87.37 274.73,90.24 274.26,90.82 273.78,91.4 273.67,91.56 273.61,91.72 273.61,93.53 273.15,94.94 271.29,96.8 271.29,101.03 268.37,103.96 268.37,106.17 266.11,108.43 263.76,108.43 262.04,110.14 261.18,110.14 259.06,112.27 257.68,112.27 257.32,112.63 248.86,112.63 248.38,113.1 247.7,113.1 247.23,113.57 227.93,113.57 216.61,116.37 212.97,117.9 194.79,117.9 194.07,118.62 189.95,118.62 189.38,118.06 188.02,118.06 185.82,115.86 184.57,115.86 183.91,115.2 181.8,115.2 181.21,115.79 179.66,115.79 179.58,115.71 v1(177.68,115.71)
  BOTTOM w0.076: UC1.CE1 176.85,110.41 176.85,111.16 177.07,111.37 177.07,112.32 177.15,112.4 177.26,112.4 177.33,112.47 177.33,112.62 177.26,112.7 177.15,112.7 177.07,112.78 177.07,112.93 177.15,113.01 177.26,113.01 177.33,113.08 177.33,113.23 177.26,113.31 177.15,113.31 177.07,113.39 177.07,116.1 177.15,116.18 177.34,116.18 177.45,116.07 177.45,115.94 v1(177.68,115.71)
USB20_N2_R: length 17.9
  TOP w0.097: LI7.2 292.79,65.51 292.63,65.36 292.63,65.13 293.73,64.03 v4(294.19,64.03) 295.64,64.03 295.77,64.16 295.77,64.74 DI5.2 296.36,64.76 296.36,63.96 296.45,63.86 296.93,63.86 297.03,63.96 297.03,64.51 297.49,64.97 299.15,64.97 299.71,64.4 300.3,64.4 300.34,64.37 303.04,64.37 303.7,65.03 303.7,65.77 303.17,66.31 303.03,66.31 302.93,66.21 JUSB1.2
USB20_N3: length 202.9
  TOP w0.097: v1(32.37,95.34) 32.37,95.06 29.03,91.72 27.46,91.72 LI3.4
  IN1 w0.089: v1(32.37,95.34) 34.7,97.67 42.67,97.67 44.01,99.02 44.01,100.1 44.48,100.56 44.48,114.97 57.54,128.03 69.16,128.03 74.44,133.32 102.68,133.32 103.89,134.53 118.93,134.53 121.89,131.57 138.33,131.57 138.74,131.98 138.74,133.92 139.47,134.64 151.54,134.64 156.41,129.77 156.41,128.52 157.11,127.82 164.35,127.82 167.06,125.11 175.19,125.11 176.86,123.44 v1(176.86,122.65)
  BOTTOM w0.076: UC1.CG3 178.33,109.01 178.4,109.09 178.4,109.24 178.31,109.34 178.13,109.34 178.08,109.39 178,109.57 178,109.76 178.05,109.89 178.04,109.92 178.04,110.13 178.01,110.21 178,110.22 178,110.5 178.24,110.74 178.24,112.08 177.98,112.34 177.98,112.56 178.06,112.64 178.11,112.64 178.19,112.71 178.19,112.86 178.11,112.94 178.06,112.94 177.98,113.02 177.98,114.53 178.94,115.48 178.94,115.99 179.52,116.57 179.52,117.42 179.53,117.43 179.53,117.48 179.54,117.49 179.54,117.5
  BOTTOM w0.097: 179.54,117.5 179.54,118.46 176.46,121.53 176.46,122.25 v1(176.86,122.65)
USB20_N3_R: length 14.4
  TOP w0.097: JUSB2.2 16.12,91.08 16.37,90.82 17.9,90.82 18.76,89.96 19.2,89.96 19.23,89.99 19.82,89.99 19.86,89.96 21.26,89.96 21.48,89.73 v4(21.9,89.73) 23.06,89.73 23.29,89.96 23.69,89.96 23.78,90.05 DI2.2 24.11,90.83 24.32,90.62 24.32,90.04 24.41,89.95 24.58,89.95 24.7,90.07 24.7,90.38 25.06,90.75 25.31,90.75 26.3,91.73 26.53,91.73 LI3.3
USB20_N4: length 178
  IN1 w0.089: v1(175.48,116.18) 175.68,116.38 176.34,116.38 177.2,117.24 177.2,117.24 181.26,118.92 182.23,119.35 189.06,119.35 189.47,119.77 212.82,119.77 227.59,115.91 239.52,115.91 240.27,115.16 248.64,115.16 249.53,116.05 255.08,116.05 257.35,113.78 257.8,113.78 258.16,113.41 259.53,113.41 260.62,112.33 261.24,112.33 261.81,111.76 262.8,111.76 264.98,109.57 267.64,109.57 270.01,107.21 270.01,106.13 272.21,103.93 272.21,102.63 272.65,102.19 273.1,102.19 273.64,101.65 273.64,101.06 272.6,100.02 272.6,97.12 275.95,93.76 275.95,91.03 276.81,90.18 277.98,87.35 287.45,77.88 287.96,77.88 289.11,76.73 292.13,76.73 298.8,70.06 298.8,63.94 296.89,62.04 296.89,58.99 297.28,58.61 297.57,58.61 297.73,58.45 297.94,58.45 v1(298.14,58.24)
  BOTTOM w0.076: UC1.CD3 176.32,109.27 176.21,109.27 176.07,109.4 176.07,109.54 176.15,109.62 176.24,109.62 176.32,109.69 176.32,111.39 176.53,111.6 176.53,116.23 176.16,116.6 175.93,116.6 175.85,116.53 175.85,116.13 175.78,116.05 175.61,116.05 v1(175.48,116.18)
  BOTTOM w0.097: LI4.1 298.56,56.81 298.56,56.86 298.7,57 298.7,57.52 298.83,57.65 298.83,58.55 298.73,58.64 298.54,58.64 v1(298.14,58.24)
USB20_N4_R: length 12.2
  IN3 w0.089: JUSB3.2 302.93,49.02 302.84,49.11 302.43,49.11 301.43,50.11 301.43,52.27 301.15,52.55 300.95,52.55 v1(300.76,52.35)
  BOTTOM w0.097: v1(300.76,52.35) 300.65,52.46 299.83,52.46 298.55,53.74 298.55,54.05 298.41,54.2 DI3.2 297.8,54.89 298,55.1 298.41,55.1 298.6,55.29 298.6,55.77 298.56,55.81 298.56,55.86 LI4.2
USB20_N6: length 65
  TOP w0.097: v1(141.34,129.93) 141.22,129.8 141.22,129.06 140.25,128.09 LZ1.1
  IN1 w0.089: v1(141.34,129.93) 141.34,130.27 141.27,130.34 140.86,130.34 140.79,130.41 140.79,131.48 140.88,131.57 141.24,131.57 141.33,131.48 141.33,130.76 141.52,130.57 141.94,130.57 142.14,130.76 142.14,131.48 142.22,131.57 142.56,131.57 142.65,131.48 142.65,130.32 142.84,130.12 143.26,130.12 143.46,130.32 143.46,131.48 143.54,131.57 143.81,131.57 143.9,131.48 143.9,130.52 144.09,130.32 144.51,130.32 144.7,130.52 144.7,131.48 144.79,131.57 145.13,131.57 145.22,131.48 145.22,130.34 145.41,130.14 146.49,130.14 146.81,129.82 146.81,126.95 148.59,125.17 165.12,125.17 166.51,123.78 170.97,123.78 172.13,122.62 172.13,122.46 v1(171.73,122.06)
  BOTTOM w0.076: 174.24,117.5 174.24,117.48 174.25,117.47 174.25,115.98 174.58,115.64 175.78,115.64 176.21,115.22 176.21,114.24 176.13,114.16 176.09,114.16 176.02,114.09 176.02,113.94 176.09,113.86 176.13,113.86 176.21,113.78 176.21,113.63 176.13,113.55 176.09,113.55 176.02,113.48 176.02,113.33 176.09,113.25 176.13,113.25 176.21,113.17 176.21,111.8 175.99,111.59 175.99,110.39 175.91,110.31 UC1.CC1
  BOTTOM w0.097: v1(171.73,122.06) 172.12,121.66 172.12,121.5 174.24,119.38 174.24,118.85 174.2,118.82 174.2,118.23 174.24,118.2 174.24,117.5
USB20_N6_R: length 12.5
  TOP w0.097: LZ1.2 138.29,128.25 136.29,128.25 135.67,127.64 135.67,127.31 135.47,127.11 135.16,127.11 134.98,126.94 134.98,126.69 DV14.3 134.12,126.24 133.92,126.44 133.92,126.82 133.77,126.96 133.31,126.96 132.99,127.28 132.99,127.82 v1(132.77,128.03)
  BOTTOM w0.097: v1(132.77,128.03) 132.97,128.23 132.97,128.41 132.79,128.6 131.81,128.6 131.43,128.98 131.43,130.24 131.28,130.4 JEDP1.12
USB20_N7: length 136.5
  IN1 w0.089: v1(264.48,72.62) 264.28,72.42 263.55,72.42 262.85,73.12 262.85,76.41 265.17,78.73 265.17,80.96 268.66,84.45 268.66,85.67 269.62,86.62 269.62,90.43 268.58,91.47 268.58,93.96 267.61,94.94 267.61,99.62 265.27,101.96 264,101.96 263.68,102.28 263.68,102.41 258.33,107.75 257.38,107.75 256.37,108.76 247.64,108.76 246.61,109.79 243.85,109.79 242.97,108.92 240.47,108.92 239.38,107.83 208.92,107.83 206.88,109.87 204.59,109.87 203.81,109.08 200.99,109.08 200.59,109.48 198.32,109.48 197.02,108.19 191.1,108.19 187.84,111.46 183.46,111.46 183.39,111.39 183.38,111.39 181.99,109.99 179.4,109.99 178.92,109.52 178.92,109.52 178.16,108.76 178.16,107.47 178.85,106.78 178.85,105.8 178.8,105.74 178.67,105.74 v1(178.45,105.96)
  BOTTOM w0.089: v1(178.45,105.96) 178.41,105.85 UC1.CG8
  BOTTOM w0.097: RI47.1 263.59,72.61 LI8.1 263.95,72.61 264.13,72.42 264.28,72.42 v1(264.48,72.62)
USB20_N7_L: length 3.6
  BOTTOM w0.097: JNGFF2.9 261.58,73.76 261.26,73.44 261.26,72.56 261.52,72.3 261.77,72.3 262.08,72.61 LI8.2 262.41,72.61 RI47.2
USB20_N8: length 214.9
  IN1 w0.089: v1(233.74,31.18) 233.82,31.27 234.42,31.27 235.3,30.39 252.37,30.39 257.78,35.8 257.78,37.51 258.35,38.08 258.35,39.1 261.04,41.78 261.04,49.09 263.63,51.69 263.63,61.5 262.11,63.03 262.11,63.71 262.45,64.05 262.45,67.2 265.64,70.4 265.64,72.85 265.07,73.42 263.9,73.42 263.46,73.86 263.46,76.2 266.21,78.95 266.83,78.95 267.69,79.82 270.44,86.45 270.44,90.75 269.69,91.51 269.69,92.41 269.93,92.66 269.93,93.77 268.18,95.52 268.18,100 264.74,103.44 264.74,103.92 263.87,104.78 262.46,105.37 262.15,105.37 257.94,109.58 256.57,109.58 256.2,109.94 247.6,109.94 247.13,110.41 237.45,110.41 237.15,110.11 224.21,110.11 212.08,115.21 198.34,115.21 198.15,115.03 191.85,115.03 190.42,114.43 188.02,112.03 182.06,112.03 181.98,111.96 181.02,111.56 177.5,111.56 177.01,111.07 177.01,109.21 176.15,108.34 176.15,107.6 176.15,107.59 176.15,106.25 175.81,105.92 v1(175.77,105.92)
  BOTTOM w0.089: UC1.CB8 v1(175.77,105.92)
  BOTTOM w0.097: v1(233.74,31.18) 233.81,31.25 234.16,31.25 234.36,31.46 234.36,36 233.27,37.09 JUSH1.19
USB20_N9: length 126.1
  TOP w0.097: RZ1388.2 291.23,115.26 290.75,115.26 v1(290.58,115.43)
  IN1 w0.089: v1(179.39,107.88) 179.17,107.66 179,107.66 178.91,107.75 178.91,108.14 179.32,108.55 179.32,109.11 179.63,109.42 182.93,109.42 184.4,110.88 187.6,110.88 190.86,107.62 195.67,107.62 196.24,107.05 196.7,107.05 198.1,108.45 207.48,108.45 208.73,107.21 241.27,107.21 241.36,107.3 241.36,107.55 v1(241.13,107.78)
  IN3 w0.089: v1(241.13,107.78) 241.13,108.54 241.59,109 242.58,109 247.1,113.53 259.19,113.53 260.38,112.33 260.63,112.33 261.4,111.57 263.2,111.57 264.37,110.4 265.58,110.4 268.91,113.74 269.68,113.74 269.98,114.04 269.98,114.49 271.46,115.97 288.95,115.97 289.56,115.36 290.51,115.36 v1(290.58,115.43)
  BOTTOM w0.089: UC1.CH5 179.04,107.73 179.39,107.88 v1(179.39,107.88)
USB20_N9_FP: length 25.5
  TOP w0.097: v1(312.13,117.35) 311.93,117.15 311.51,117.15 311.2,116.84 311.2,115.34 310.48,114.62 301.3,114.62 301.1,114.42 v4(300.55,114.42) 298.61,114.42 298.57,114.46 297.99,114.46 297.95,114.42 295.8,114.42 294.95,115.28 294.67,115.28 294.57,115.38 294.57,115.76 DZ11.2 293.81,115.81 293.81,115.42 293.69,115.3 292.85,115.3 RZ350.1 292.41,115.34 292.12,115.34 RZ1388.1
  BOTTOM w0.097: JFPBTN1.6 312.84,117.35 312.72,117.23 312.24,117.23 v1(312.13,117.35)
USB20_N9_USH: length 153.6
  TOP w0.097: RZ350.2 v1(292.03,116.13)
  IN1 w0.089: v1(235.3,31.46) 235.59,31.75 239.52,31.75 240.05,31.21 248.95,31.21 249.32,31.58 252.1,31.58 257.21,36.68 257.21,37.75 257.78,38.32 257.78,39.91 260.46,42.59 260.46,50.67 261.55,51.77 261.55,58.4 260.18,59.77 260.18,63.58 260.6,63.99 260.6,67.02 259.74,67.88 259.74,73.52 260.17,73.95 260.17,76.49 262.38,78.7 262.87,78.7 263.42,79.25 263.42,82.77 264.43,83.79 264.43,84.49 265.23,85.29 265.55,85.29 v1(265.74,85.1)
  BOTTOM w0.097: JUSH1.23 235.27,39.11 235.12,38.95 235.12,34.98 236.16,33.93 236.16,31.7 235.96,31.49 235.34,31.49 v1(235.3,31.46) ; v1(265.74,85.1) 265.04,85.1 264.77,85.36 264.77,86.21 265.56,87 266.75,87 267.53,87.79 267.53,96.03 268.32,96.82 268.32,101.05 265.8,103.58 265.8,107.45 265.46,107.79 265.46,109.27 266.26,110.07 266.26,111.65 268.61,114 268.61,114.7 269.83,115.93 274.18,115.93 278.41,120.16 282.46,120.16 283.37,119.25 283.37,117.56 283.66,117.27 285.03,117.27 285.88,116.43 290.67,116.43 291.56,115.54 291.89,115.54 292.03,115.68 v1(292.03,116.13)
USB20_N10: length 196.6
  IN1 w0.089: v1(175.47,112.58) 175.7,112.81 175.7,112.88 175.85,113.03 176.14,113.03 176.72,113.62 187.42,113.62 190.37,116.57 196.88,116.57 197.06,116.75 212.58,116.75 222.87,112.42 246.71,112.42 247.18,111.95 247.91,111.95 248.38,111.48 256.84,111.48 257.21,111.12 258.58,111.12 260.71,108.99 261.57,108.99 263.28,107.28 265.61,107.28 266.38,106.51 266.38,104.32 270.15,100.55 270.15,96.32 271.57,94.9 271.57,92.47 272,92.05 272,90.19 272.04,90.16 272.96,89.24 272.96,88.55 278.84,82.66 278.84,81.29 282.65,77.48 283.59,77.48 286.16,74.9 286.16,72.8 283.51,70.14 280.67,70.14 278.38,67.86 278.38,65.22 275.74,62.59 275.74,62.36 275.74,62.36 275.74,60.88 275.51,60.65 275.51,54.05 273.93,52.46 273.93,49.23 274.45,48.7 274.45,37.17 273.16,35.88 270.58,35.88 269.84,35.13 269.45,35.13 269.09,35.49 v1(269.09,35.62)
  BOTTOM w0.076: UC1.CC3 175.86,108.98 175.86,108.74 175.76,108.64 175.62,108.64 175.55,108.71 175.55,109.19 175.4,109.53 175.4,109.78 175.43,109.88 175.43,110.1 175.4,110.2 175.4,110.34 175.4,110.35 175.4,110.54 175.56,110.7 175.56,111.74 175.88,112.06 175.88,112.93 175.8,113.01 175.77,113.01 175.62,112.86 175.56,112.86 175.47,112.77 v1(175.47,112.58)
  BOTTOM w0.097: LI12.1 267.29,34.61 LI9.1 267.3,34.99 267.37,35.06 267.37,35.43 267.57,35.63 268.32,35.63 268.57,35.38 268.94,35.38 269.09,35.53 v1(269.09,35.62)
USB20_N10_R: length 9.9
  BOTTOM w0.097: JNGFF1.5 273.7,31.93 273.09,31.32 270.62,31.32 269.92,32.02 268.52,32.02 268.48,31.99 267.88,31.99 267.3,32.57 267.3,32.85 267.3,32.86 LI9.2 267.3,33.38 LI12.2
USB20_P1: length 174.6
  TOP w0.097: v1(59.37,109.62) 59.56,109.81 59.56,111.02 57.38,113.2 54.44,113.2 52.82,114.82 52.82,121.72 v1(52.62,121.92)
  IN1 w0.089: v1(52.62,121.92) 52.74,122.04 52.74,122.14 52.74,122.14 52.74,122.41 55.42,125.1 68.95,125.1 70.84,126.99 70.84,126.99 72.85,129 99.17,129 104.13,133.95 118.7,133.95 121.77,130.88 139.19,130.88 139.95,131.65 139.95,132.41 140.57,133.03 146.63,133.03 148.19,131.47 148.19,127.4 149.68,125.92 165.44,125.92 166.83,124.53 174.01,124.53 175.11,123.44 v1(175.11,122.58)
  BOTTOM w0.076: UT5.L5 59.83,106.66 59.75,106.58 59.64,106.58 59.57,106.64 59.57,106.92 59.64,106.98 59.64,107.15 59.48,107.31 59.48,108.57 59.47,108.58 59.47,108.66 ; 178.95,117.5 178.95,117.5 178.95,116.81 178.19,115.19 177.66,114.66 177.66,111.41 177.23,110.98 177.23,110.69 177.38,110.54 177.38,110.2 177.35,110.1 177.35,109.88 177.38,109.78 177.38,109.53 177.23,109.19 177.23,108.97 UC1.CE4
  BOTTOM w0.097: 178.95,117.5 178.95,117.89 175.11,122.13 v1(175.11,122.58) ; 59.47,108.66 59.47,109.08 59.57,109.18 59.57,109.42 v1(59.37,109.62)
USB20_P2: length 151.7
  TOP w0.097: UI3.3 292.29,71.45 292.49,71.65 292.49,73.21 292.04,73.65 292.04,74.26 291.93,74.38 v1(291.91,74.38)
  IN1 w0.089: v1(177.68,116.35) 178.13,115.89 179.5,115.89 179.58,115.97 181.28,115.97 181.87,115.38 183.83,115.38 184.49,116.04 185.74,116.04 187.94,118.24 189.31,118.24 189.87,118.8 194.14,118.8 194.86,118.08 213.01,118.08 216.67,116.54 227.95,113.75 247.3,113.75 247.77,113.28 248.46,113.28 248.93,112.81 257.4,112.81 257.76,112.45 259.13,112.45 261.26,110.32 262.12,110.32 263.83,108.61 266.18,108.61 268.55,106.24 268.55,104.03 271.47,101.1 271.47,96.87 273.31,95.03 273.79,93.57 273.79,91.75 273.83,91.64 273.92,91.51 274.88,90.34 276.6,87.47 278.99,84.4 280.17,83.21 280.17,82.21 280.38,81.82 283.87,79.49 289.33,75.01 290.7,74.1 291.29,73.85 292.08,73.85 292.23,74 292.23,74.07 291.93,74.38 v1(291.91,74.38)
  BOTTOM w0.076: v1(177.68,116.35) 177.08,116.35 176.9,116.17 176.9,111.44 176.69,111.22 176.69,110.78 176.69,110.24 UC1.CE2
USB20_P2_R: length 17.9
  TOP w0.097: JUSB1.3 302.93,66.59 303.03,66.49 303.25,66.49 303.89,65.85 303.89,64.95 303.12,64.18 v4(300.01,64.18) 299.67,64.18 299.07,64.78 297.56,64.78 297.22,64.43 297.22,63.88 297.01,63.68 296.42,63.68 296.32,63.58 296.32,63.37 DI5.3 295.68,63.5 295.68,63.75 295.59,63.85 294.52,63.85 294.48,63.81 293.69,63.81 292.45,65.06 292.45,65.36 292.29,65.51 LI7.3
USB20_P3: length 203
  TOP w0.097: v1(32.78,94.92) 32.5,94.92 29.11,91.53 27.42,91.53 LI3.1
  IN1 w0.089: v1(32.78,94.92) 32.78,95.5 34.78,97.49 42.74,97.49 44.19,98.94 44.19,100.02 44.66,100.49 44.66,114.89 57.62,127.85 69.23,127.85 74.52,133.14 102.76,133.14 103.97,134.35 118.86,134.35 121.81,131.39 138.41,131.39 138.92,131.91 138.92,133.84 139.54,134.46 151.46,134.46 156.23,129.7 156.23,128.45 157.03,127.64 164.27,127.64 166.99,124.93 175.12,124.93 176.68,123.36 176.68,123.03 176.54,122.89 176.53,122.89 176.44,122.8 176.43,122.8 v1(176.28,122.65)
  BOTTOM w0.076: 179.35,117.5 179.35,116.64 178.77,116.06 178.77,115.55 177.82,114.6 177.82,112.27 178.08,112.01 178.08,110.81 177.84,110.57 177.84,110.19 177.87,110.1 177.87,109.88 177.84,109.79 177.84,109.53 177.94,109.3 177.94,109.29 177.99,109.19 177.99,108.88 UC1.CG4
  BOTTOM w0.097: 179.35,117.5 179.35,118.38 176.28,121.46 v1(176.28,122.65)
USB20_P3_R: length 14.4
  TOP w0.097: JUSB2.3 16.12,90.38 16.37,90.64 17.82,90.64 18.69,89.77 v4(19.53,89.77) 21.18,89.77 21.41,89.55 21.58,89.55 21.61,89.51 22.2,89.51 22.23,89.55 23.14,89.55 23.36,89.77 23.69,89.77 23.78,89.67 DI2.3 24.11,88.9 24.32,89.1 24.32,89.66 24.41,89.76 24.66,89.76 24.89,89.99 24.89,90.31 25.14,90.56 25.39,90.56 26.38,91.55 26.53,91.55 LI3.2
USB20_P4: length 178
  IN1 w0.089: v1(298.14,58.83) 297.94,58.63 297.8,58.63 297.65,58.79 297.35,58.79 297.07,59.07 297.07,61.96 298.98,63.87 298.98,70.13 292.2,76.91 289.18,76.91 288.04,78.06 287.53,78.06 278.13,87.45 276.99,90.22 276.99,90.26 276.14,91.11 276.14,93.84 272.78,97.19 272.78,99.95 273.82,100.98 273.82,101.73 273.17,102.37 272.73,102.37 272.39,102.71 272.39,104 270.19,106.21 270.19,107.28 267.71,109.75 265.06,109.75 262.87,111.94 261.89,111.94 261.32,112.51 260.69,112.51 259.61,113.59 258.23,113.59 257.87,113.96 257.43,113.96 255.15,116.23 249.45,116.23 248.56,115.34 240.34,115.34 239.6,116.09 227.62,116.09 212.84,119.95 189.4,119.95 188.98,119.54 182.19,119.54 181.18,119.09 177.1,117.4 176.26,116.56 175.68,116.56 v1(175.48,116.77)
  BOTTOM w0.076: UC1.CD4 176.64,109.22 176.64,109.46 176.48,109.71 176.48,111.32 176.7,111.53 176.7,116.3 176.23,116.77 v1(175.48,116.77)
  BOTTOM w0.097: v1(298.14,58.83) 298.81,58.83 299.02,58.62 299.02,57.58 298.89,57.44 LI4.4
USB20_P4_R: length 12.2
  IN3 w0.089: v1(300.76,52.94) 300.97,52.73 301.23,52.73 301.61,52.34 301.61,50.19 302.51,49.29 302.84,49.29 302.93,49.38 JUSB3.3
  BOTTOM w0.097: LI4.3 298.79,55.94 298.79,55.32 298.98,55.13 299.44,55.13 299.73,54.84 DI3.3 298.89,54.2 298.74,54.05 298.74,53.82 299.91,52.65 300.47,52.65 v1(300.76,52.94)
USB20_P6: length 65.1
  TOP w0.097: LZ1.4 139.26,128.59 139.39,128.46 139.39,128.38 139.49,128.28 140.18,128.28 141.03,129.14 141.03,129.6 140.95,129.68 140.81,129.68 140.72,129.77 140.72,129.89 v1(140.76,129.93)
  IN1 w0.089: v1(172.31,122.06) 172.31,122.69 171.04,123.96 166.59,123.96 165.2,125.35 148.66,125.35 146.99,127.02 146.99,129.9 146.56,130.32 145.49,130.32 145.4,130.41 145.4,131.56 145.2,131.75 144.72,131.75 144.52,131.56 144.52,130.59 144.44,130.5 144.17,130.5 144.08,130.59 144.08,131.56 143.89,131.75 143.47,131.75 143.27,131.56 143.27,130.39 143.19,130.31 142.92,130.31 142.83,130.39 142.83,131.56 142.64,131.75 142.15,131.75 141.96,131.56 141.96,130.84 141.87,130.75 141.6,130.75 141.51,130.84 141.51,131.56 141.32,131.75 140.81,131.75 140.61,131.56 140.61,130.31 140.76,130.17 v1(140.76,129.93)
  BOTTOM w0.076: UC1.CC2 176.15,110.35 176.15,111.52 176.37,111.73 176.37,115.29 175.85,115.81 174.65,115.81 174.41,116.05 174.41,117.47 174.42,117.48 174.42,117.5
  BOTTOM w0.097: v1(172.31,122.06) 172.31,121.57 174.42,119.46 v4(174.42,118.53) 174.42,117.5
USB20_P6_R: length 12.5
  TOP w0.097: LZ1.3 138.29,128.44 136.21,128.44 135.49,127.71 135.49,127.39 135.39,127.29 135.15,127.29 134.96,127.48 134.96,127.73 DV14.2 134.12,128.17 133.93,127.97 133.93,127.31 133.76,127.15 133.38,127.15 133.17,127.36 133.17,127.84 v1(133.36,128.03)
  BOTTOM w0.097: JEDP1.13 131.77,130.39 131.62,130.24 131.62,129.06 131.88,128.79 132.86,128.79 133.16,128.49 133.16,128.23 v1(133.36,128.03)
USB20_P7: length 136.5
  IN1 w0.089: v1(178.45,105.33) 178.68,105.56 178.87,105.56 179.03,105.72 179.03,106.85 178.34,107.54 178.34,108.68 178.92,109.27 178.93,109.27 179.11,109.44 179.11,109.45 179.47,109.81 182.06,109.81 183.46,111.21 183.47,111.21 183.53,111.28 187.76,111.28 191.03,108.01 197.1,108.01 198.39,109.3 200.52,109.3 200.92,108.9 203.89,108.9 204.67,109.69 206.8,109.69 208.84,107.65 239.46,107.65 240.55,108.74 243.05,108.74 243.93,109.61 246.54,109.61 247.57,108.58 256.29,108.58 257.3,107.57 258.26,107.57 263.5,102.33 263.5,102.2 263.92,101.78 265.19,101.78 267.43,99.54 267.43,94.86 268.4,93.89 268.4,91.39 269.44,90.36 269.44,86.7 268.48,85.75 268.48,84.53 264.99,81.03 264.99,78.8 262.67,76.48 262.67,73.04 263.47,72.24 264.28,72.24 v1(264.48,72.04)
  BOTTOM w0.089: v1(178.45,105.33) 178.42,105.21 UC1.CG9
  BOTTOM w0.097: RI48.1 263.59,72.11 LI8.4 263.99,72.11 264.12,72.24 264.28,72.24 v1(264.48,72.04)
USB20_P7_L: length 3.7
  BOTTOM w0.097: JNGFF2.7 261.08,72.43 v4(261.25,72.26) 261.39,72.11 262.37,72.11 LI8.3 262.51,71.98 RI48.2
USB20_P8: length 215
  IN1 w0.089: v1(175.77,105.28) 175.77,105.4 176.13,105.77 176.13,105.98 176.33,106.18 176.33,107.67 176.33,107.67 176.33,108.27 177.19,109.14 177.19,109.39 177.19,109.39 177.19,110.99 177.58,111.38 181.05,111.38 182.08,111.8 182.13,111.85 188.1,111.85 190.52,114.28 191.89,114.85 198.23,114.85 198.41,115.03 212.04,115.03 224.17,109.93 237.22,109.93 237.52,110.23 247.05,110.23 247.53,109.76 256.13,109.76 256.49,109.4 257.87,109.4 262.08,105.19 262.42,105.19 263.77,104.63 264.56,103.84 264.56,103.37 268,99.92 268,95.44 269.75,93.69 269.75,92.73 269.51,92.48 269.51,91.43 270.26,90.68 270.26,86.49 267.54,79.92 266.75,79.13 266.13,79.13 263.28,76.28 263.28,73.79 263.83,73.24 265,73.24 265.46,72.77 265.46,70.47 262.27,67.28 262.27,64.13 261.93,63.79 261.93,62.95 263.45,61.43 263.45,51.76 260.86,49.16 260.86,41.86 258.17,39.17 258.17,38.16 257.6,37.58 257.6,35.88 252.29,30.57 235.37,30.57 234.5,31.45 234.04,31.45 233.9,31.58 233.83,31.58 v1(233.64,31.77)
  BOTTOM w0.089: UC1.CB9 v1(175.77,105.28)
  BOTTOM w0.097: v1(233.64,31.77) 233.83,31.58 233.91,31.58 234.05,31.44 234.08,31.44 234.18,31.53 234.18,35.93 233.09,37.01 233.09,38.79 232.77,39.11 JUSH1.18
USB20_P9: length 126.1
  TOP w0.097: v1(290.58,114.85) 290.81,115.07 291.23,115.07 RZ1389.2
  IN1 w0.089: v1(241.71,107.78) 241.54,107.6 241.54,107.22 241.34,107.03 208.65,107.03 207.41,108.27 198.17,108.27 196.77,106.87 196.16,106.87 195.6,107.44 190.79,107.44 187.52,110.7 184.48,110.7 183.01,109.24 179.7,109.24 179.5,109.04 179.5,108.35 179.76,108.09 179.76,107.57 v1(179.4,107.22)
  IN3 w0.089: v1(241.71,107.78) 241.51,107.98 241.49,107.98 241.31,108.16 241.31,108.47 241.66,108.82 242.65,108.82 247.18,113.35 259.11,113.35 260.31,112.15 260.56,112.15 261.32,111.39 263.13,111.39 264.3,110.22 265.65,110.22 268.99,113.56 269.75,113.56 270.16,113.96 270.16,114.41 271.54,115.79 288.88,115.79 289.48,115.18 290.24,115.18 v1(290.58,114.85)
  BOTTOM w0.089: v1(179.4,107.22) 179.37,107.14 UC1.CH6
USB20_P9_FP: length 25.6
  TOP w0.097: RZ1389.1 292.2,115.07 292.45,115.07 RZ351.1 292.79,115.11 293.71,115.11 293.81,115.01 293.81,114.59 DZ11.3 294.57,114.64 294.57,115 294.67,115.09 294.87,115.09 295.73,114.24 v4(298.28,114.24) 300.23,114.24 300.26,114.21 300.85,114.21 300.88,114.24 301.18,114.24 301.37,114.44 310.56,114.44 311.39,115.27 311.39,116.77 311.58,116.96 311.93,116.96 v1(312.13,116.76)
  BOTTOM w0.097: v1(312.13,116.76) 312.41,117.05 312.7,117.05 312.9,116.85 JFPBTN1.4
USB20_P9_USH: length 153.6
  TOP w0.097: RZ351.2 v1(292.03,114.34)
  IN1 w0.089: v1(265.74,85.68) 265.53,85.47 265.16,85.47 264.25,84.57 264.25,83.87 263.23,82.85 263.23,79.33 262.79,78.88 262.31,78.88 259.99,76.56 259.99,74.02 259.56,73.59 259.56,67.8 260.42,66.94 260.42,64.07 260,63.65 260,59.7 261.37,58.33 261.37,51.84 260.28,50.75 260.28,42.67 257.6,39.98 257.6,38.39 257.02,37.82 257.02,36.76 252.03,31.76 249.25,31.76 248.88,31.39 240.13,31.39 239.59,31.93 235.59,31.93 v1(235.3,32.22)
  BOTTOM w0.097: JUSH1.22 234.77,39.11 234.93,38.95 234.93,34.9 235.98,33.85 235.98,31.78 235.88,31.68 235.67,31.68 235.3,32.04 v1(235.3,32.22) ; v1(265.74,85.68) 265.53,85.47 265.53,85.45 265.36,85.28 265.11,85.28 264.96,85.44 264.96,86.14 265.64,86.81 266.82,86.81 267.72,87.71 267.72,95.96 268.51,96.75 268.51,101.13 265.98,103.66 265.98,107.53 265.65,107.87 265.65,109.2 266.44,109.99 266.44,111.57 268.79,113.92 268.79,114.63 269.9,115.74 274.26,115.74 278.49,119.97 282.38,119.97 283.19,119.17 283.19,117.48 283.59,117.08 284.96,117.08 285.8,116.24 290.6,116.24 291.48,115.35 291.89,115.35 292.03,115.21 v1(292.03,114.34)
USB20_P10: length 196.6
  IN1 w0.089: v1(269.18,34.84) 269.29,34.95 269.91,34.95 270.66,35.7 273.24,35.7 274.63,37.09 274.63,48.78 274.11,49.31 274.11,52.38 275.69,53.97 275.69,60.57 275.92,60.8 275.92,62.44 275.92,62.51 278.56,65.15 278.56,67.78 280.74,69.96 283.58,69.96 286.34,72.73 286.34,74.98 283.66,77.66 282.72,77.66 279.02,81.36 279.02,82.74 273.14,88.63 273.14,89.31 272.22,90.23 272.22,90.23 272.18,90.27 272.18,92.12 271.75,92.55 271.75,94.97 270.33,96.4 270.33,100.63 266.56,104.4 266.56,106.59 265.69,107.46 263.36,107.46 261.64,109.17 260.78,109.17 258.66,111.3 257.28,111.3 256.92,111.66 248.46,111.66 247.98,112.13 247.26,112.13 246.79,112.6 222.91,112.6 212.61,116.93 196.99,116.93 196.81,116.75 190.3,116.75 187.35,113.8 176.65,113.8 176.06,113.21 v1(175.47,113.21)
  BOTTOM w0.076: v1(175.47,113.21) 175.5,113.18 175.87,113.18 176.05,113 176.05,111.99 175.73,111.67 175.73,110.63 175.56,110.47 175.56,110.22 175.6,110.13 175.6,109.85 175.56,109.76 175.56,109.57 175.63,109.42 175.7,109.35 175.9,109.35 176.08,109.16 176.08,108.62 UC1.CC4
  BOTTOM w0.097: LI13.1 267.8,34.61 LI9.4 267.8,34.96 267.55,35.21 267.55,35.35 267.65,35.45 268.24,35.45 268.49,35.19 268.95,35.19 269.18,34.97 v1(269.18,34.84)
USB20_P10_R: length 9.8
  BOTTOM w0.097: JNGFF1.3 273.2,32.78 273.3,32.69 273.41,32.69 273.51,32.59 273.51,32.01 273.01,31.51 270.69,31.51 270,32.2 v4(268.18,32.2) 267.93,32.2 267.49,32.65 267.49,32.74 267.55,32.8 267.79,32.8 267.88,32.9 267.88,32.97 267.8,33.06 LI9.3 267.8,33.38 LI13.2
USB_OC0#: length 164.8
  TOP w0.107: v1(295.52,69.29) 295.52,69.07 v2(295.25,68.79) UI3.13
  IN1 w0.089: v1(180.55,107.45) 181.14,107.45 181.22,107.37 182.86,107.37 183.7,108.21 185.09,108.21 ; 191.03,106.22 190.51,105.71
  IN1 w0.099: 191.03,106.22 195.28,106.22 196.02,105.48 198.38,105.48 198.57,105.67 199.39,105.67 201.1,103.96 v1(201.42,103.96) ; v1(291.02,65.86) 293.68,68.53 295.4,68.53 295.52,68.65 v1(295.52,69.29) ; 190.51,105.71 189.64,105.71 188.91,106.44 186.87,106.44 185.09,108.21
  IN2 w0.102: v1(252.51,66.39) 252.51,66.39 252.51,66.8 250.6,68.71 250.6,69.49 249.14,70.95 247.84,70.95 247.73,71.05 242.02,71.05 232.86,80.21 232.86,80.65 232.2,81.31 232.2,88.68 231.4,89.48 225.17,89.48 221.88,86.19 213.38,86.19 212.4,87.17 210.9,87.17 207.68,90.4 207.68,91.69 203.3,96.07 203.3,97.49 202.42,98.37 202.42,100.97 201.82,101.56 201.82,103.55 v1(201.42,103.96)
  BOTTOM w0.089: UC1.CK6 180.45,107.21 180.53,107.44 v1(180.55,107.45)
  BOTTOM w0.107: v1(252.51,66.39) 252.51,66.39 252.69,66.21 257.58,66.21 258.38,65.42 259.46,64.34 266.29,64.34 267.19,65.23 275.08,65.23 275.56,64.76 277.34,64.76 277.88,65.3 277.88,68.92 280.28,71.32 283.43,71.32 286.22,68.54 286.22,64.42 286.85,63.79 290.22,63.79 291.02,64.59 v1(291.02,65.86) ; RC758.1 v1(201.42,103.96) RC837.2
USB_OC1#: length 246.6
  TOP w0.107: v2(21.97,87.62) 22.69,88.34 v1(22.79,88.34)
  IN1 w0.102: v1(180.52,108.08) 180.63,108.19 183.29,108.19 183.64,108.53 185.02,108.53 186.89,106.67 188.93,106.67 189.71,105.88 190.36,105.88 191.06,106.58 195.24,106.58 196.12,105.71 198.29,105.71 198.48,105.9 199.48,105.9 199.58,105.8 199.96,105.8 201.21,104.54 v1(201.42,104.54)
  IN2 w0.102: v1(180.52,108.08) 181.64,109.19 181.64,113.42 184.27,116.06 184.27,118.45 188.08,122.26 188.08,124.6 187.33,125.35 162.19,125.35 161.61,124.78 160,124.78 159.71,124.48 155.23,124.48 155.02,124.28 147.76,124.28 147.49,124.55 142.65,124.55 141.8,123.7 135.81,123.7 135.19,124.32 132.39,124.32 131.2,125.51 120.15,125.51 120,125.35 116.75,125.35 114.86,127.24 112.72,127.24 110.62,125.14 103.67,125.14 98.19,119.66 97.83,119.66 93.29,124.2 75.7,124.2 73.73,126.17 64.07,126.17 53.5,115.61 53.5,111.3 54.05,110.76 54.05,107.66 52.72,106.33 52.72,101.25 42.02,90.55 37.27,90.55 35.48,88.76 23.21,88.76 v1(22.79,88.34)
  BOTTOM w0.076: UC1.CK5 180.06,107.62 v1(180.52,108.08)
  BOTTOM w0.107: 201.42,104.53 200.99,104.53 RC839.2 ; 201.42,104.53 201.85,104.53 RC759.1 ; 201.42,104.53 v1(201.42,104.54) ; v1(22.79,88.34) 22.79,88.28 22.41,87.89 UI1.3
USB_OC2#: length 167.1
  TOP w0.107: v1(300.6,54.62) 300.28,54.3 UI2.3
  IN1 w0.089: v1(180.29,105.96) 180.89,105.96 181.12,106.18 182.43,106.18 184.08,107.83 185.23,107.83 187.01,106.06 188.88,106.06 189.4,105.54 190.65,105.54 191.11,106
  IN1 w0.099: v1(201.42,103.07) 199.64,103.07 198.31,104.4 195.95,104.4 194.36,106 191.11,106
  IN2 w0.102: v1(300.6,54.62) 300.6,54.93 299.55,55.99 299.55,63.03 297.21,65.38 295.49,65.38 294.54,66.33 292.25,66.33 291.52,65.61 v1(291.52,64.72) ; v1(201.42,103.07) 201.42,101.65 202.19,100.87 202.19,98.28 203.08,97.39 203.08,95.97 207.45,91.6 207.45,90.3 210.81,86.94 211.48,86.94 212.46,85.96 221.97,85.96 225.26,89.25 231.31,89.25 231.97,88.59 231.97,81.21 232.64,80.55 232.64,80.11 242.02,70.72 248.89,70.72 250.33,69.29 250.33,68.42 v1(252.03,66.71)
  BOTTOM w0.089: UC1.CK8 179.96,105.78 v1(180.29,105.96)
  BOTTOM w0.107: v1(252.03,66.71) 252.03,66.71 252.03,66.09 252.14,65.98 257.25,65.98 v2(258.19,65.05) 259.13,64.1 266.39,64.1 267.28,65 274.98,65 275.46,64.53 278.07,64.53 279.63,62.97 284,62.97 284.31,62.66 286.67,62.66 287.55,63.54 290.35,63.54 v1(291.52,64.72) ; RC760.1 v1(201.42,103.07) RC838.2
USB_OC3#: length 29.4
  IN1 w0.089: 191.11,104.21 190.88,104.21 190.13,104.96 189.17,104.96 188.56,105.57 187.04,105.57 186.88,105.74 184.1,105.74 183.98,105.86 182.93,105.86 182.19,105.12 181.01,105.12 180.81,105.32 v1(180.31,105.32)
  IN1 w0.099: 191.11,104.21 192.78,104.21 193.61,105.04 194.68,105.04 196.3,103.42 198.13,103.42 198.62,102.94 198.95,102.94 199.27,102.63 201.89,102.63 201.99,102.73 201.99,105.19 v1(201.42,105.76)
  BOTTOM w0.089: UC1.CK9 179.96,105.13 v1(180.31,105.32)
  BOTTOM w0.107: RC836.2 200.69,105.76 v1(201.42,105.76) 202.14,105.76 RC757.1
USB_POWERSHARE_EN#: length 71.5
  TOP w0.107: UI3.6 287.77,69.79 286.4,71.16 286.4,89.05 286.14,89.31 286.14,90.16 v1(286.44,90.45) ; RE728.1 256.52,83.06 257.74,84.27 260.47,84.27 v2(260.8,84.6) 262.38,86.18 262.38,89.06 v1(263.27,89.95)
  TOP w0.127: v1(253.64,92.63) 253.63,92.63 UE1.J3
  IN3 w0.089: v1(253.64,92.63) 254.05,92.22 255.64,92.22 256.22,91.64 260.12,91.64 260.83,90.93
  IN3 w0.102: v1(286.44,90.45) 286.12,90.78 265.07,90.78 264.24,89.95 v1(263.27,89.95) 261.81,89.95 260.83,90.93
USB_POWERSHARE_VBUS_EN: length 64
  TOP w0.107: v1(286.63,89.73) 286.63,71.26 287.6,70.29 v2(288.83,70.29) UI3.5 ; UE1.J2 253.26,92.21 v1(253.64,91.83) 253.65,91.82 253.65,86.99 RE730.1
  IN3 w0.089: 260.83,90.61 259.98,91.45 254.02,91.45 v1(253.64,91.83)
  IN3 w0.102: v1(286.63,89.73) 286.21,89.73 285.39,90.55 267.38,90.55 266.38,89.55 261.89,89.55 260.83,90.61
USB_PWR_EN1#: length 387
  TOP w0.107: v1(22.92,87.26) v2(23.45,87.26) ; RE729.1 255.07,82.93 255.7,82.31 v1(256.15,82.31)
  TOP w0.127: v1(254.43,92.63) UE1.K3
  IN2 w0.089: 260.12,87.29 259.21,88.2 256.98,88.2 254.81,90.37 254.81,92.24 v1(254.43,92.63)
  IN2 w0.102: v1(22.92,87.26) 24.19,88.53 38.55,88.53 39.71,87.37 45.86,87.37 48.17,85.06 55.13,85.06 59.96,80.23 60.9,80.23 68.34,72.79 72.7,62.67 72.7,45.63 71,43.93 71,42.15 73.86,39.29 78.6,39.29 81.96,42.65 81.96,44.52 81.84,44.65 81.84,48.8 82.17,49.13 84.97,49.13 85.2,49.36 86.44,49.36 87.43,50.35 90.44,50.35 92.51,52.41 96.95,52.41 99.91,55.37 131.61,55.37 133.6,53.39 133.6,48.46 133.96,48.11 134.15,48.11 136.43,45.83 136.43,45.25 137.19,44.49 137.19,43.9 137.66,43.43 153.8,43.43 156.13,41.1 162.57,41.1 162.59,41.07 162.59,41.07 167.15,36.51 177.55,36.51 182.82,31.25 193.05,31.25 196.23,34.43 197.19,34.43 197.55,34.79 197.55,35.45 198.38,36.28 201.82,36.28 202.73,37.18 202.73,37.76 203.4,38.43 204.73,38.43 205,38.69 208.94,38.69 209.6,38.03 215.76,38.03 215.83,37.96 221.43,37.96 222.99,36.4 223.72,36.4 224.25,35.87 224.25,33.35 226.06,31.54 231.77,31.54 233.54,33.31 238.59,33.31 240.59,31.31 249.47,31.31 250.08,31.93 255.36,31.93 257.32,33.88 259.07,33.88 259.94,34.75 259.94,37.43 260.29,37.78 260.62,37.78 260.88,38.05 263.06,38.05 264.04,39.02 264.04,41.35 263.76,41.62 263.76,42.76 262.86,43.66 262.86,45 262.96,45.1 263.61,45.1 264.21,45.69 264.21,48.71 263.75,49.17 263.75,59.43 264.12,59.8 264.12,61.06 260.87,64.31 260.87,71.24 259.81,72.3 259.81,75.73 256.6,78.94 256.6,80.46 256.15,80.91 v1(256.15,82.31) 256.15,83.39 257.35,84.58 259.78,84.58 260.62,85.43 260.62,86.79 260.12,87.29
  BOTTOM w0.107: v1(22.92,87.26) 22.92,87.63 23.18,87.89 UI1.4
USB_PWR_EN2#: length 100
  TOP w0.107: v1(250.49,84.18) 250.49,82.38 251.03,81.84 253.21,81.84 v2(253.46,82.08) 254.06,82.69 RE727.1 ; UI2.4 300.28,55.83 v1(300.67,55.45)
  TOP w0.127: v1(251.25,94.22) 251.28,94.25 251.28,94.25 UE1.G5
  IN2 w0.089: 248.11,86.98 248.11,87.55 248.71,88.15 249.11,88.15 250.89,89.93 250.89,92.75 250.85,92.78 250.85,93.83 v1(251.25,94.22)
  IN2 w0.102: v1(300.67,55.45) 299.78,56.33 299.78,63.13 297.3,65.61 295.59,65.61 294.64,66.56 v1(291.02,66.56) ; 248.11,86.98 248.11,86.91 249.48,85.54 250.22,85.54 250.49,85.27 v1(250.49,84.18)
  IN3 w0.102: v1(269.99,70.74) 270.82,71.58 270.82,73.72 271.44,74.34 271.44,75.77 270.6,76.61 268.14,76.61 267.56,77.19 265.44,77.19 264.26,78.37 261.24,78.37 259.9,79.7 259.9,80.76 259.41,81.25 256.5,81.25 254.68,83.08 250.88,83.08 250.49,83.46 v1(250.49,84.18)
  BOTTOM w0.107: v1(291.02,66.56) 290.38,65.92 290.38,64.46 289.94,64.02 286.95,64.02 286.45,64.52 286.45,68.64 283.45,71.64 280.17,71.64 279.28,70.75 276.66,70.75 275.52,71.89 271.61,71.89 270.46,70.74 v1(269.99,70.74)
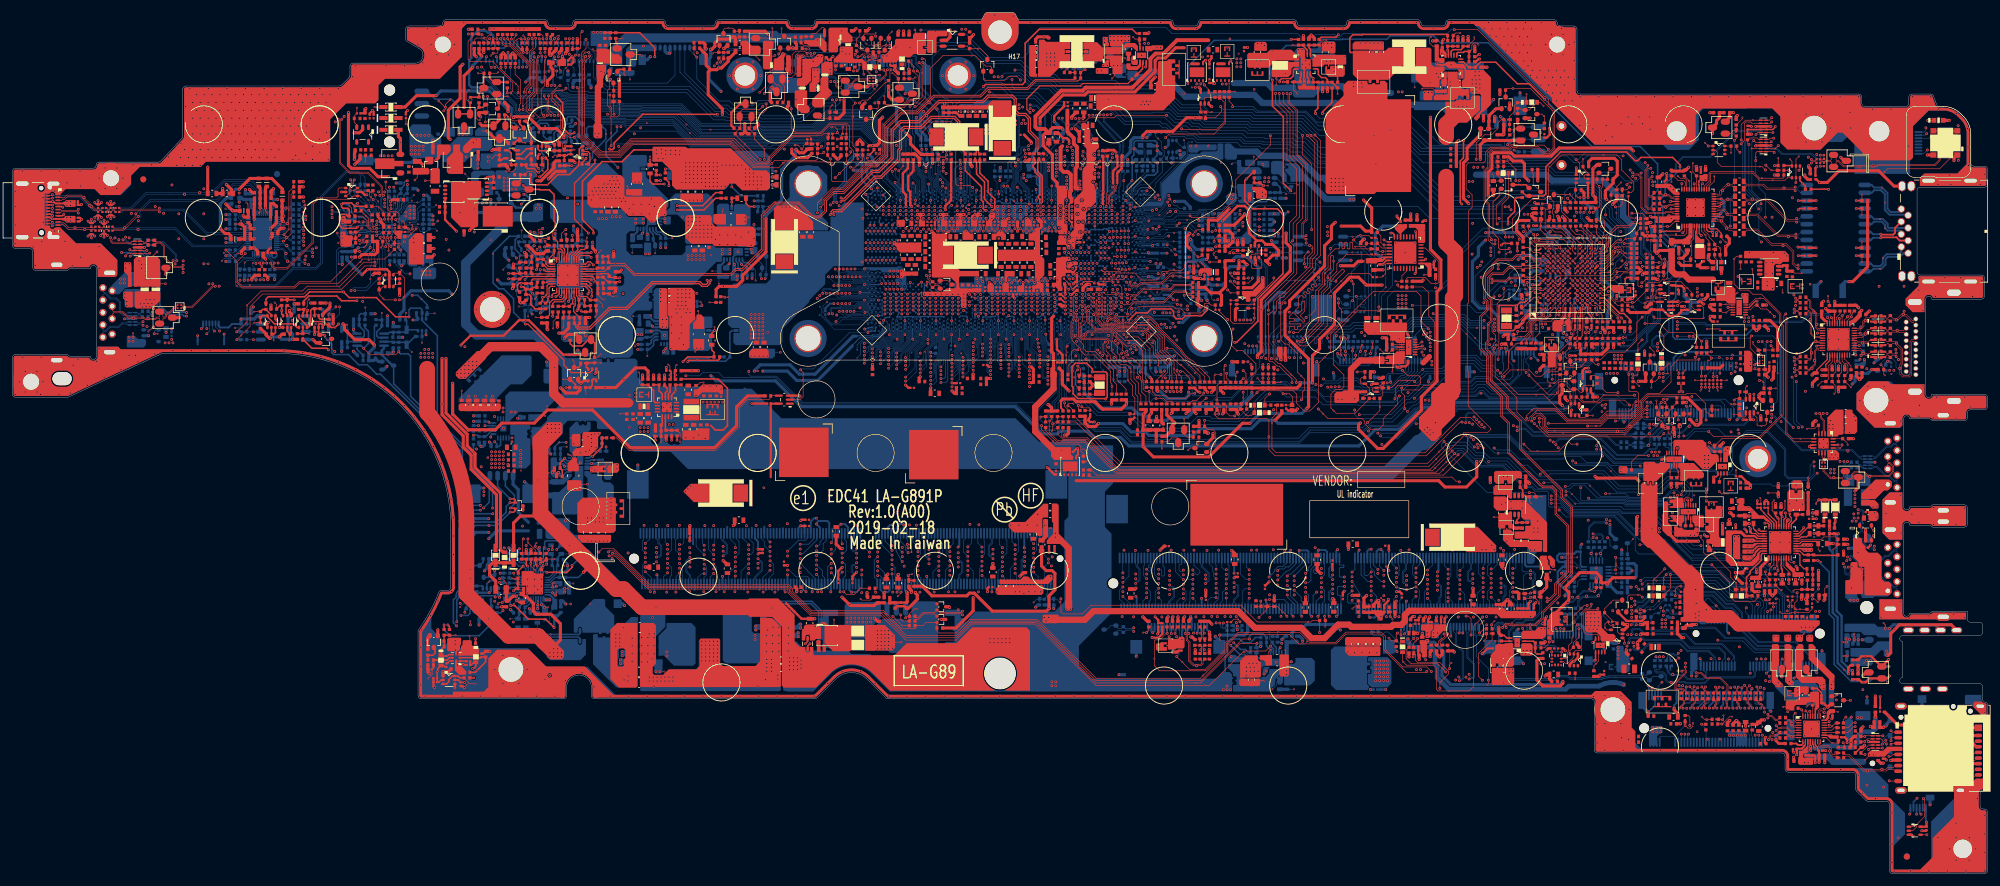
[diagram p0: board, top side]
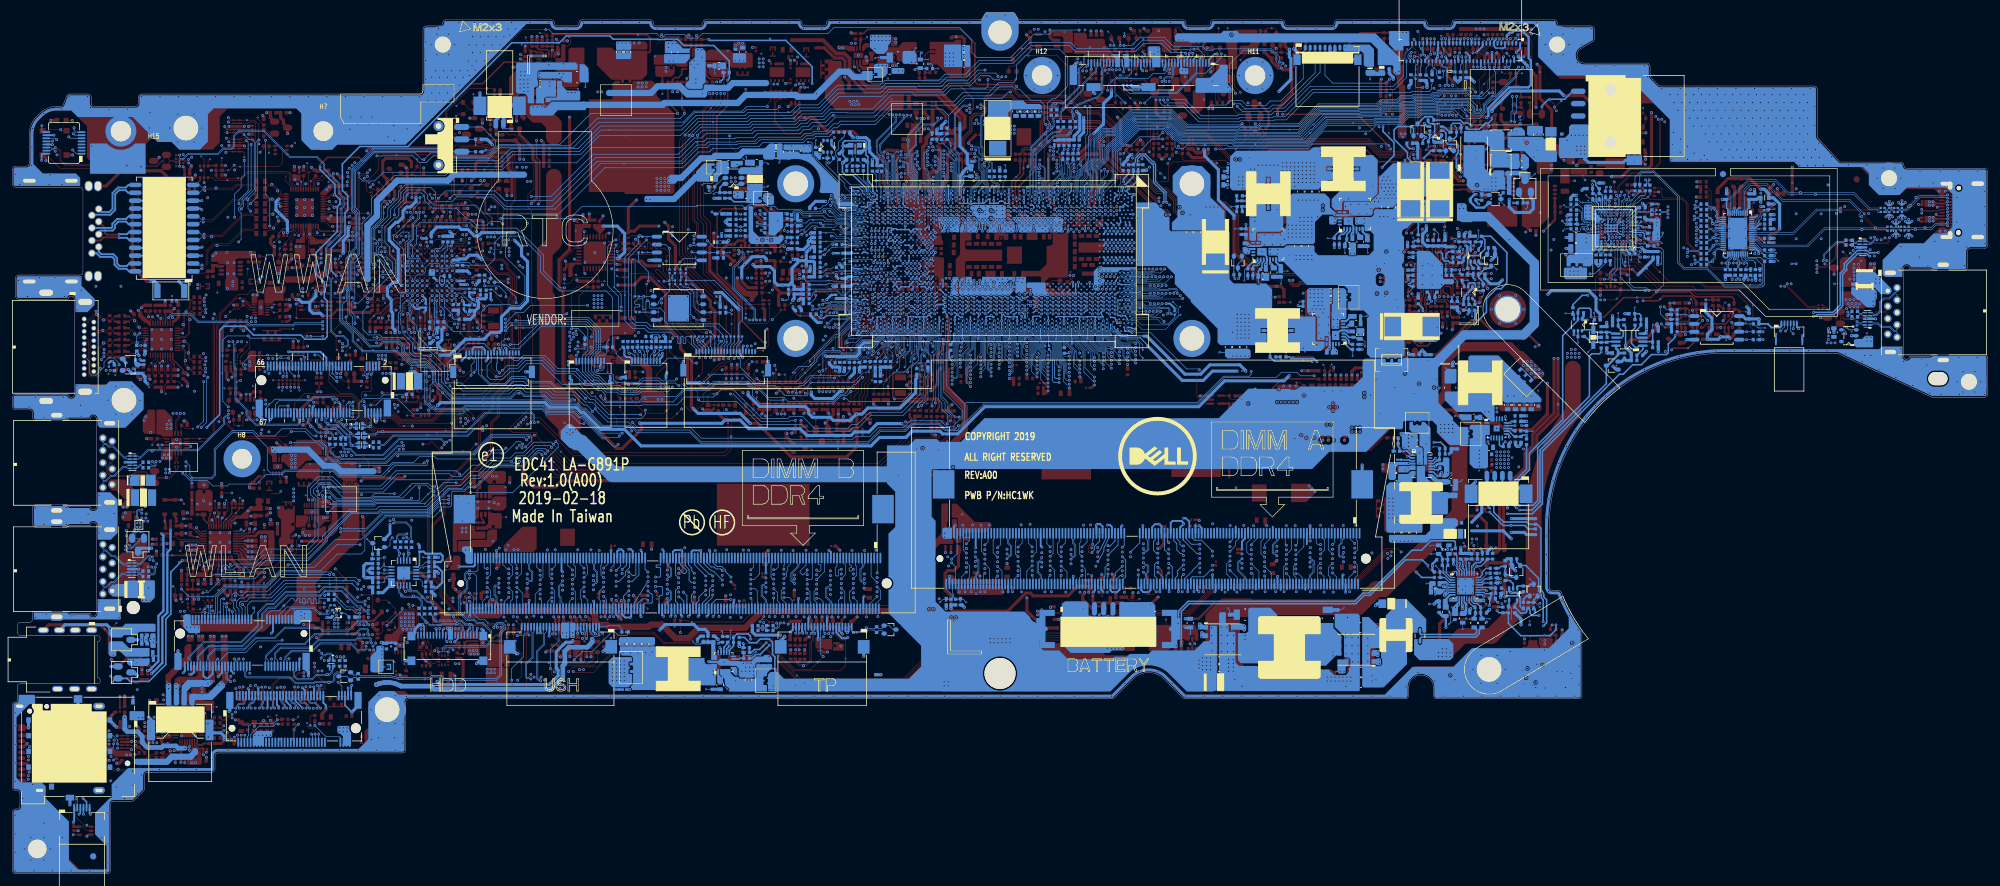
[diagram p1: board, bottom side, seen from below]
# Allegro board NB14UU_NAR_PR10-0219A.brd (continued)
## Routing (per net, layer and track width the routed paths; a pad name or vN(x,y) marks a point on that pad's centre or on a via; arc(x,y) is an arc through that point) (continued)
USBCOMP: length 8.7
  TOP w0.107: v1(176.69,107.82) 176.69,109.9 176.88,110.09 v2(176.88,114.64) RC47.1
  BOTTOM w0.2: v1(176.69,107.82) UC1.CC5
USH_DET#: length 126.1
  TOP w0.102: UE1.C13 248.42,101.04 248.08,101.04 247.55,101.56 246.29,101.56 v1(245.23,102.63) 245.09,102.63 v2(244.43,103.29) 244.43,103.52 244.5,103.59 244.5,104 244.03,104.47 RE526.1
  IN2 w0.102: v1(228.29,34.57) 228.29,35.39 228.85,35.95 232.4,35.95 232.93,36.48 238.98,36.48 239.69,35.77 243.21,35.77 243.9,36.46 245.4,36.46 246.81,35.05 247.96,35.05 248.41,34.6 251.3,34.6 251.9,35.2 253.13,35.2 254.47,36.54 254.47,37.77 255.16,38.47 256.4,38.47 257.26,39.33 257.26,43.37 259.02,45.13 259.02,45.85 259.47,46.29 259.47,52.66 260.44,53.63 260.44,59.79 256.94,63.3 256.94,64.82 255.91,65.85 255.91,66.11 253.14,68.88 253.14,70.21 249.91,73.44 249.47,73.44 245.49,77.43 245.49,81.3 246.93,82.74 246.93,83.14 246.32,83.75 246.32,84.58 245.44,85.47 245.44,87.21 245.03,87.61 245.03,92.85 244.93,92.95 244.93,93.55 243.81,94.67 243.81,96.7 245.35,98.23 245.35,99.51 244.72,100.14 244.72,101.07 244.89,101.23 244.89,102.28 v1(245.23,102.63)
  BOTTOM w0.107: v1(228.29,34.57) 226.96,35.9 225.39,35.9 222.23,39.06 221.74,39.06 221.17,38.49 219.83,38.49 219.69,38.63 RZ87.1
USH_DET#_R: length 4.5
  BOTTOM w0.107: JUSH1.1 223,39.9 222.82,40.08 v2(221.09,40.08) 220.61,39.6 RZ87.2
USH_EXPANDER_SMBCLK: length 87.2
  TOP w0.107: RZ8.2 CZ62.1 230.6,37.24 230.6,37.48 230.9,37.78 231.12,37.78 231.62,38.28 231.62,38.53 v1(231.83,38.75)
  TOP w0.127: v1(248.03,93.39) 248.03,93.39 UE1.B3
  IN1 w0.089: 247.38,86.98 247.38,87 247.37,87.01 247.37,87.27 248.24,88.14 248.24,89.15 247.81,89.58 247.45,89.58 247.24,89.37 247.24,89.15 247.24,89.03 v1(247.06,88.84)
  IN1 w0.099: 247.38,86.98 247.38,86.75 246.33,85.7 246.33,83.72 245.93,83.32 245.93,83 244.1,81.17 244.1,78.35 250.91,71.54 250.91,65.66 250.42,65.18 250.42,59.07 251.26,58.24 251.26,49.8 251.52,49.54 251.52,46.11 250.96,45.54 250.7,45.54 250.38,45.23 250.38,44.71 250.78,44.31 250.78,43.4 249.33,41.96 246.62,41.96 244.56,39.91 244.56,39.35 243.9,38.68 242.83,38.68 241.88,37.73 233.86,37.73 232.38,39.22 231.78,39.22 231.68,39.12 231.68,38.9 v1(231.83,38.75)
  IN3 w0.089: v1(247.06,88.84) 247.05,88.84 247.05,88.85 247.26,89.06 247.26,89.74 247.58,90.05 247.58,90.62 248.51,91.55 248.51,92.42 248.47,92.46 248.47,92.95 v1(248.03,93.39)
  BOTTOM w0.107: JUSH1.16 231.77,39.32 231.64,39.19 231.64,38.94 v1(231.83,38.75)
USH_EXPANDER_SMBDAT: length 87.4
  TOP w0.107: v1(249.66,94.21) 249.66,94.22 250.05,94.6 UE1.E5 ; v1(231.25,38.75) 231.39,38.61 231.39,38.38 231.02,38.01 230.81,38.01 230.37,37.57 230.37,37.24 CZ63.1 230.02,36.94 RZ9.2
  IN1 w0.089: v1(247.64,88.85) 247.46,89.03 247.45,89.15 247.45,89.28 247.54,89.37 247.72,89.37 248.03,89.06 248.03,88.23 247.16,87.36 247.16,87.01 247.15,87 247.15,86.98
  IN1 w0.099: 247.15,86.98 247.15,86.85 246.1,85.79 246.1,83.81 245.7,83.42 245.7,83.1 243.87,81.26 243.87,78.26 250.68,71.45 250.68,65.75 250.2,65.27 250.2,58.98 251.03,58.15 251.03,49.71 251.29,49.45 251.29,46.2 250.86,45.77 250.6,45.77 250.16,45.32 250.16,44.61 250.55,44.22 250.55,43.49 249.24,42.18 246.52,42.18 244.34,40 244.34,39.44 243.81,38.91 242.73,38.91 241.78,37.96 233.96,37.96 232.47,39.44 231.68,39.44 231.45,39.21 231.45,38.95 v1(231.25,38.75)
  IN3 w0.089: v1(249.66,94.21) 249.66,94.03 249.23,93.6 249.23,92.34 248.72,91.83 248.72,91.46 247.8,90.54 247.8,89.96 247.48,89.65 247.48,89.01 v1(247.64,88.85)
  BOTTOM w0.107: v1(231.25,38.75) 231.41,38.9 231.41,39.17 231.27,39.3 JUSH1.15
USH_PWR_STATE#: length 105.8
  TOP w0.107: v1(252.56,84.97) 252.56,85.44 RE608.1 ; v1(231.51,32.6) v2(230.87,33.24) 230.19,33.92 225.94,33.92 225.12,34.74 225.12,36.11 RZ10.2 225.6,36.59 225.6,37.26 v1(226.36,38.02)
  IN2 w0.102: v1(231.51,32.6) 232.19,32.6 233.35,33.77 238.78,33.77 240.78,31.77 246.41,31.77 247.02,32.38 255.17,32.38 258.52,35.73 258.52,37.68 260.1,39.26 263.34,39.26 263.44,39.37 263.44,40.7 263.34,40.8 261.59,40.8 261.08,41.31 261.08,44.99 261.64,45.55 263.42,45.55 263.75,45.88 263.75,48.52 263.29,48.98 263.29,59.73 263.44,59.88 263.44,61.08 260.22,64.31 260.22,70.62 259.35,71.49 259.35,74.96 252.56,81.75 v1(252.56,84.97)
  BOTTOM w0.107: v1(226.36,38.02) 226.2,38.19 226.2,39.16 226.27,39.24 JUSH1.5
USH_PWR_STATE#_R: length 6.2
  TOP w0.089: 252.79,86.98 v2(252.79,87.48) 252.79,90.24 252.98,90.43 252.98,90.97 252.85,91.1 252.85,91.81 UE1.H2
  TOP w0.107: 252.79,86.98 252.79,86.92 252.41,86.54 RE608.2
VCI_IN1#: length 4.6
  TOP w0.089: 244.58,94.35 244.67,94.26 RE507.1
  TOP w0.107: 244.58,94.35 v2(244.41,94.52)
  TOP w0.127: UE1.B5 247.28,94.25 246.7,94.25 246.54,94.41 245.83,94.41 245,93.58 RE507.1
VCI_IN2#: length 6
  TOP w0.127: UE1.D4 249.23,93.81 v1(248.83,93.41)
  BOTTOM w0.089: v1(248.83,93.41) 248.41,93.83 v2(247.61,93.83) 246.64,93.83 245.21,92.4 244.9,92.4 RE508.1
VCI_IN3#: length 6
  TOP w0.127: v1(249.66,93.41) 249.66,93.42 UE1.E4
  BOTTOM w0.107: RE822.1 247.77,89.61 v2(247.95,89.79) 247.95,90.36 249.27,91.68 249.27,92.84 249.65,93.22 249.65,93.4 v1(249.66,93.41)
VCT_LAN_R1: length 6.8
  TOP w0.107: v2(270.09,98.96) 270.82,98.96 RL3.1 271.08,99.77 271.26,99.95 271.26,102.3 271.58,102.63 271.58,104.02 271.66,104.1 UL1.6
VGA_IDENTIFY: length 19.4
  TOP w0.107: RE85.1 RE84.1 251.65,108.71 v1(251.2,109.16)
  TOP w0.127: v1(255.25,98.21) UE1.L9
  IN2 w0.089: 255.25,99.68 255.25,99.54 254.83,99.13 254.83,98.63 v1(255.25,98.21)
  IN2 w0.102: 255.25,99.68 255.25,101.85 254.56,102.53 254.56,104.73 256.24,106.41 256.24,107.31 255.75,107.81 252.55,107.81 v1(251.2,109.16)
  BOTTOM w0.107: v2(251.58,109.87) 251.58,109.55 v1(251.2,109.16)
VID0_1V_PRIM_CORE: length 6.6
  TOP w0.107: v2(214.05,126.02) PR418.2
  TOP w0.254: PR418.2 214.05,127 213.16,127.89 PR408.2 PR420.1 212.4,128.34 212.09,128.66 211.45,128.66 210.94,129.17 210.94,129.93 210.8,130.07 PU402.9
VID0_1VS_VCCIO: length 7
  TOP w0.107: PR416.1 101.48,78.99 101.3,79.17 101.3,80.87 v2(101.16,81.01)
  TOP w0.254: PU401.9 103.83,76.13 103.56,76.4 103.56,78.1 102.67,78.99 PR414.2 PR416.1
VID1_1V_PRIM_CORE: length 3.1
  TOP w0.254: PR417.2 PR411.2 PR419.1 v1(210.12,128.52) 209.66,128.98 PU402.8
VID1_1VS_VCCIO: length 3.2
  TOP w0.254: PR413.2 PR415.1 v2(104.45,78.04) 104.97,77.52 PU401.8
VIDALERT_N: length 76.2
  TOP w0.107: PR625.1 89.56,102.73 89.4,102.88 v1(89.4,103.35)
  IN1 w0.099: v1(89.4,103.35) 89,103.76 89,105.19 90.86,107.05 90.86,108.41 91.27,108.81 91.27,110.31 94.29,113.34 95.26,113.34 100.11,118.18 107.14,118.18 108.42,119.46 110.86,119.46 111.36,119.95 116.81,119.95 117.78,118.98 122.36,118.98 124.09,120.71 133.96,120.71 134.35,120.32 134.35,120.32 134.51,120.16 138.92,120.16 140.2,118.88 142.76,118.88 145.54,116.1 147.6,116.1 v1(148.56,117.06)
  BOTTOM w0.107: v1(89.4,103.35) 89.4,102.88 89.56,102.73 PR625.1 ; RC154.2 148.38,117.24 v1(148.56,117.06) RC155.2
VIDSCLK: length 78.2
  TOP w0.107: PR618.1 88.67,103.41 89.37,104.11 v1(89.4,104.11)
  IN1 w0.099: v1(89.4,104.11) 89.51,104.01 89.75,104.01 89.85,104.11 89.85,104.47 89.48,104.84 89.48,104.99 91.75,107.26 91.75,110.11 94.49,112.86 95.46,112.86 100.31,117.7 107.34,117.7 108.62,118.98 111.06,118.98 111.56,119.47 116.61,119.47 117.58,118.5 122.56,118.5 124.29,120.23 133.76,120.23 134.15,119.84 134.15,119.84 134.31,119.68 138.72,119.68 141.1,117.3 143.65,117.3 145.34,115.62 146.71,115.62 147.94,115.62 149.14,116.82 v1(149.14,117.06)
  BOTTOM w0.107: v1(89.4,104.11) 89.37,104.11 88.67,103.41 PR618.1 ; RC158.2 149.21,117.12 v1(149.14,117.06) 149.38,116.81 RC159.2
VIDSCLK_R: length 5.7
  BOTTOM w0.076: RC159.1 149.59,115.32 v2(149.59,114.48) 149.59,114.25 149.39,114.05 149.39,111.14 150.1,110.43 UC1.AA1
VIDSOUT: length 77.6
  TOP w0.107: PR626.1 v1(90.44,103.17)
  IN1 w0.099: v1(90.44,103.17) 90.44,103.13 90.04,102.73 89.13,102.73 88.52,103.34 88.52,105.38 90.36,107.22 90.36,108.58 90.79,109.01 90.79,110.51 94.09,113.82 95.06,113.82 99.91,118.66 106.94,118.66 108.22,119.94 110.67,119.94 111.16,120.43 117,120.43 117.98,119.46 122.16,119.46 123.89,121.19 134.16,121.19 134.55,120.8 134.55,120.8 134.71,120.64 139.12,120.64 140.4,119.36 142.95,119.36 145.74,116.58 147.14,116.58 v1(147.63,117.07)
  BOTTOM w0.107: RC157.2 147.63,116.54 v1(147.63,117.07) 147.56,117.15 RC156.2 ; PR626.1 v1(90.44,103.17)
VIDSOUT_R: length 6.8
  BOTTOM w0.076: UC1.AA2 149.47,110.29 149.47,110.6 149.07,111 149.07,112.47 148.67,112.86 148.67,114.28 147.73,115.22 RC157.1
VOUT_1.2V_RUN: length 0.6
  TOP w0.107: 285.89,94.5 285.89,93.95 v2(285.94,93.9)
VOUT_2.5V_MEM: length 1.3
  TOP w0.107: PC516.1 v2(239.28,57.62)
VR_ENABLE_CPU_CORE: length 2.5
  TOP w0.203: v1(87.46,99.5) 87.72,99.5 87.92,99.3 PU602.40
  BOTTOM w0.254: PR616.2 87.02,100.53 v2(87.46,100.08) v1(87.46,99.5)
VR_HOT#_CPU_CORE: length 6.1
  TOP w0.107: PR678.2 87.21,102.99 87.21,103.59 87.58,103.96 v2(87.78,103.96)
  TOP w0.203: PR678.2 88.07,102.13 88.07,101.05 88.16,100.96 88.59,100.96 88.79,100.76 88.79,99.86 88.72,99.79 PU602.38
VR_LPM_R#: length 89.9
  TOP w0.107: RC867.2 196.78,89.33 197.2,88.91 200.16,88.91 200.59,89.34 v1(200.59,89.79) v2(200.59,90.49) RC660.2 200.11,91.41 200.07,91.37 UC9.4
  TOP w0.254: v1(206.56,134.83) PR430.1
  IN2 w0.102: v1(200.59,89.79) 199.31,91.07 191.97,91.07 190.6,92.44 190.6,96.25 190.6,96.43 189.26,97.78 184.3,97.78 183.05,99.03 183.05,100.99 185.73,103.67 185.73,105.61 184.94,106.4 183.86,106.4 183.73,106.54 183.73,109.33 184.49,110.09 184.49,112.38 185.91,113.8 185.91,115.43 186.95,116.47 186.95,116.7 187.07,116.82 187.07,117.85 189.49,120.27 189.49,122.82 189.87,123.21 v1(189.87,127.72)
  BOTTOM w0.254: v1(189.87,127.72) 189.87,130.43 194.11,134.67 206.4,134.67 v1(206.56,134.83)
VR_READY_CPU_CORE: length 6
  TOP w0.203: v1(88.33,100.48) 88.32,100.47 PU602.39
  BOTTOM w0.107: v2(88.87,100.28) 88.67,100.48 v1(88.33,100.48)
  BOTTOM w0.254: PR614.2 PR612.2 86.37,98.75 86.86,98.75 87.13,99.02 87.7,99.02 88.04,99.36 88.04,100.19 v1(88.33,100.48)
VRALERT#: length 6.3
  BOTTOM w0.076: UC1.CC36 176.28,88.28 176.54,87.8 176.54,87.53 176.54,87.53 176.54,86.77 176.92,86.39 176.92,85.74 177.46,85.2 177.46,84.71 176.92,84.17 v2(176.92,83.7) 176.92,83.06 RC73.1
VSET_5105: length 3.4
  TOP w0.127: v1(247.97,98.19) 248.35,97.81 UE1.C9
  BOTTOM w0.107: v2(245.35,98.14) 245.52,98.32 RE77.1 CE38.1 247.86,98.32 247.96,98.21 247.96,98.19 v1(247.97,98.19)
VSYS_CHG: length 4.6
  BOTTOM w0.107: v2(89.15,49.76) 88.45,49.06 PC745.1
  BOTTOM w0.203: PU700.3 86.89,47.07 87.69,47.86 PR721.1 PC745.1
VTTREF_DDR: length 2.7
  BOTTOM w0.254: PU200.3 93.25,66.73 93.4,66.88 v2(93.9,66.88) 94.76,66.88 PC218.1 PC227.1
WIGIG_32KHZ: length 4
  TOP w0.107: v2(284.91,43.7) v1(284.37,43.7) RZ56.2
  BOTTOM w0.107: v1(284.37,43.7) 284.56,43.7 284.96,43.29 284.96,41.09 JNGFF1.50
WLAN_COEX1: length 45.8
  TOP w0.107: v2(275.48,78.08) 275.37,78.19 v1(275.37,78.61) RZ130.2
  IN2 w0.102: v1(275.37,78.61) 275.37,77.77 274.1,76.5 274.1,75.44 275.17,74.37 275.17,66.21 275.59,65.79 275.59,63.45 275.04,62.91 275.04,56.43 277.13,54.33 277.13,53.51 278.65,51.99 278.65,51.01 280.37,49.29 280.37,43.95 281.22,43.1 284.43,43.1 v1(284.45,43.12)
  BOTTOM w0.107: JNGFF1.48 v1(284.45,43.12)
WLAN_COEX2: length 45.3
  TOP w0.107: v2(274.1,78) v1(274.1,78.61) RZ129.2
  IN2 w0.102: v1(274.1,78.61) 274.1,78.27 273.39,77.56 273.39,75.82 274.76,74.45 274.76,64.61 274.4,64.25 274.4,56.74 276.91,54.24 276.91,53.35 278.42,51.84 278.42,50.85 280.14,49.13 280.14,43.83 281.2,42.77 283.9,42.77 v1(284.04,42.64)
  BOTTOM w0.107: JNGFF1.46 283.95,42.54 v1(284.04,42.64)
WLAN_COEX3: length 44.8
  TOP w0.107: v2(272.68,78.09) 272.83,78.24 v1(272.83,78.6) RZ128.2
  IN2 w0.102: v1(283.52,42.36) 281.26,42.36 279.92,43.71 279.92,49.03 278.06,50.89 278.06,51.87 276.68,53.25 276.68,54.15 274.13,56.7 274.13,64.34 274.53,64.74 274.53,74.36 273.16,75.73 273.16,78.27 v1(272.83,78.6)
  BOTTOM w0.107: JNGFF1.44 283.45,42.29 v1(283.52,42.36)
WLAN_PWR_EN: length 11.6
  TOP w0.107: v1(265.86,73.39) 265.87,73.41 266.07,73.41 266.5,72.97 DZ9.1 267.12,72.4 RZ38.2 267.44,71.27 268.01,70.7 v2(268.01,69.67) UZ47.5 ; RZ71.2 RZ70.2 267.2,75.87 v1(266.93,76.15)
  IN2 w0.102: v1(265.86,73.39) 265.86,73.94 266.94,75.02 266.94,76.13 v1(266.93,76.15)
WLAN_WIGIG60GHZ_DIS#: length 74.7
  TOP w0.107: UE1.L13 254.85,101.24 255.03,101.43 255.03,101.85 254.35,102.54 254.35,103.08 253.53,103.91 252.77,103.91 v1(252.72,103.96) 252.53,104.15 RE8.1 ; v1(266.9,49.27) v2(265.2,47.57) 265.03,47.4 DZ1.1
  IN2 w0.102: v1(259.79,103.77) 259.79,103.58 264.99,98.38 264.99,95.76 265.95,94.81 265.95,94.18 267.57,92.56 267.57,78.26 267.67,78.15 267.67,75.47 267.17,74.97 267.17,64.81 266.72,64.36 266.72,50.15 266.9,49.97 v1(266.9,49.27)
  IN3 w0.102: v1(259.79,103.77) 259.49,103.46 253.22,103.46 v1(252.72,103.96)
WLAN_WIGIG60GHZ_DIS#_R: length 27
  TOP w0.107: DZ1.2 v2(266.73,47.55) 266.73,47.92 v1(267.13,48.33)
  BOTTOM w0.107: v1(267.13,48.33) 267.56,48.76 275.74,48.76 278.07,46.42 284.56,46.42 286.25,44.73 286.25,42.24 286.45,42.04 JNGFF1.56
WWAN_ANT_CONFIG: length 5
  TOP w0.107: RZ1450.1 274.44,83.37 v1(274.44,83.32) 274.44,83.22 274.15,82.93 v2(273.85,82.93)
  BOTTOM w0.107: JNGFF2.60 276.33,83.09 276.09,83.32 v1(274.44,83.32)
WWAN_BB_RST#: length 136.2
  TOP w0.107: RZ1393.2 274.24,74.04 273.45,74.83 v2(273.45,75.09) 273.45,76.03 271.85,77.63 270.49,77.63 270.25,77.39 264.2,77.39 263.15,76.33 263.15,75.32 261.63,73.81 257.64,73.81 256.59,72.76 248.13,72.76 v1(248.09,72.79)
  IN1 w0.099: v1(248.09,72.79) 248.09,72.4 250.2,70.29 250.2,65.95 249.72,65.47 249.72,62.93 248.58,61.79 v1(248.58,61.04)
  IN3 w0.089: v1(178.59,95.66) 179.45,95.66 179.76,95.97 185.87,95.97
  IN3 w0.102: v1(248.58,61.04) 246.61,63 246.61,63.7 245.69,64.62 237.15,64.62 234.47,67.29 232.65,67.29 230.22,69.72 228.6,69.72 219.92,78.4 219.92,79.17 219.43,79.66 219.43,81.86 218.14,83.15 218.14,84.57 216.1,86.61 216.1,87.17 215.11,88.16 213.91,88.16 213.34,88.73 213.34,90.98 208.99,95.34 196.45,95.34 195.39,96.4 193.74,96.4 192.68,95.34 191.35,95.34 190.21,96.48 189.41,96.48 188.72,97.17 187.07,97.17 185.87,95.97
  BOTTOM w0.076: UC1.CG23 178.29,95.96 v1(178.59,95.66)
WWAN_BB_RST#_R: length 4.3
  TOP w0.107: v2(275.51,74.95) RZ1393.1 v1(274.51,75.61)
  BOTTOM w0.107: JNGFF2.59 276.08,75.43 275.9,75.61 v1(274.51,75.61)
WWAN_COEX1: length 4
  TOP w0.107: v2(276.91,79.74) RZ373.1 RZ130.1 275.37,80.3 v1(275.33,80.35)
  BOTTOM w0.107: JNGFF2.56 275.33,81.19 275.17,81.04 275.17,80.5 v1(275.33,80.35)
WWAN_COEX2: length 3.5
  TOP w0.107: v2(274.74,80.88) v1(274.74,80.35) RZ372.1 RZ129.1
  BOTTOM w0.107: JNGFF2.54 274.82,81.16 274.74,81.08 v1(274.74,80.35)
WWAN_COEX3: length 4.3
  TOP w0.107: v2(271.76,79.74) RZ128.1 RZ374.1 v1(273.47,80.4)
  BOTTOM w0.107: JNGFF2.52 274.33,81.26 v1(273.47,80.4)
WWAN_FULL_PWR_EN: length 122.8
  TOP w0.107: RZ43.1 CZ198.1 261.54,81.57 261.1,81.12 v1(261.1,80.69) 261.1,78.03 261.2,77.92 262.38,77.92 262.68,77.62 262.68,75.51 261.44,74.27 257.44,74.27 256.39,73.23 251.2,73.23 249.28,75.14 245.7,75.14 v2(245.43,74.87) 244.59,74.03 v1(244.59,73.58)
  IN1 w0.089: v1(180.75,96.45) 180.75,96.46 180.75,96.77 181.16,97.18 183.59,97.18 183.96,97.54 188.39,97.54 190.18,95.75 191.11,95.75
  IN1 w0.099: 191.11,95.75 193.49,95.75 193.92,96.17 197.69,96.17 199.38,94.48 214.68,94.48 215.3,95.1 220.21,95.1 220.64,95.53 222.5,95.53 223.77,96.8 225.66,96.8 226.32,97.46 227.05,97.46 227.7,98.11 234.32,98.11 235.09,98.88 v1(237.35,98.88)
  IN2 w0.102: v1(244.59,73.58) 244.43,73.58 234.5,83.51 234.5,94.59 237.52,97.61 237.52,98.7 v1(237.35,98.88)
  BOTTOM w0.076: UC1.CM23 180.77,96.48 v1(180.75,96.45)
  BOTTOM w0.107: v1(261.1,80.69) 260.82,80.96 JNGFF2.6
WWAN_GPIO_CTRL: length 39.8
  TOP w0.089: UE1.K1 254.05,90.55 253.85,90.35 253.85,88.47 254.05,88.26 RE340.2 254.31,87.77 v1(254.63,87.45)
  TOP w0.107: RZ1398.2 282.91,79.36 v2(282.77,79.51) 282.57,79.7 v1(282.2,79.7)
  IN3 w0.089: v1(254.63,87.45) 254.63,86.99 254.64,86.98 ; 259.9,87.07 259.77,87.07 259.69,86.98
  IN3 w0.102: 254.64,86.98 255.13,86.48 259.19,86.48 259.69,86.98 ; v1(282.2,79.7) 282.2,83.12 279.67,85.65 268.25,85.65 267.21,86.69 264.61,86.69 264.22,87.07 259.9,87.07
WWAN_GPIO_CTRL#: length 5.8
  TOP w0.107: QZ19.1 283.32,74.44 RZ1397.2 283.32,72.64 283.05,72.38 v2(282.52,72.38) 281.94,72.38 281.81,72.51 281.81,73.67 281.29,74.19 UZ51.6
WWAN_GPIO_CTRL_R: length 3.1
  TOP w0.107: v2(284.82,78.43) RZ1398.1 RZ1399.1 283.9,77.61 283.9,76.66 QZ19.2
WWAN_GPIO_PERST#: length 170.9
  TOP w0.102: 183.93,95.29 182.24,95.29 181.77,94.82 180.74,94.82 v1(179.95,95.6)
  TOP w0.107: 183.93,95.29 185.72,95.29 187.03,96.59 v1(187.44,96.59) 188.84,96.59 189.1,96.34 RC756.1 ; v1(266.76,71.13) 266.23,70.59 247.98,70.59 v2(246.26,72.31) v1(245.83,72.74) ; v1(271.46,86.85) 272.03,86.28 RZ1480.2 ; v1(284.06,85.33) 284.37,85.01 RZ1405.2 RZ1402.2
  IN1 w0.089: 188.66,95.37 v1(187.44,96.59)
  IN1 w0.099: 188.66,95.37 189.42,94.61 195.18,94.61 195.61,95.04 196.61,95.04 196.92,94.73 196.92,94.14 197.03,94.03 214.87,94.03 215.49,94.65 216.66,94.65 216.82,94.49 222.11,94.49 223.96,96.34 227.39,96.34 227.9,96.85 233.7,96.85 234.83,97.99 v1(236.61,97.99) ; v1(266.76,71.13) 268.45,72.81 268.45,75.42 270.66,77.63 272.12,77.63 272.72,77.04 275.68,77.04 277.24,75.48 278.72,75.48 278.95,75.7 280.66,75.7 v1(281.93,74.44)
  IN2 w0.102: v1(245.83,72.74) 245.68,72.59 244.28,72.59 237.87,79 237.16,79 233.68,82.49 233.68,84.85 233.29,85.23 233.29,94.14 236.61,97.46 v1(236.61,97.99)
  IN3 w0.102: v1(281.93,74.44) 283.01,75.52 283.01,82.05 284.28,83.32 284.28,85.1 v1(284.06,85.33) 281.23,85.33 279.48,87.07 271.67,87.07 v1(271.46,86.85)
  BOTTOM w0.089: v1(179.95,95.6) 179.85,95.7 179.58,95.7 179.19,96.1 UC1.CH23
WWAN_GPIO_PERST#_R: length 3.1
  TOP w0.107: UZ52.A2 282.71,83.75 282.11,84.34 RZ1402.1 281.15,85.58 v2(281.15,85.89)
WWAN_GPIO_WAKE#: length 148
  TOP w0.107: v1(278.13,76.53) 278.39,76.79 RZ1396.2 278.99,77.81 RZ1394.2 ; v1(245.42,73.15) 245.42,73.73 246.04,74.36 v2(246.79,74.36) 246.99,74.36 247.68,73.67 247.68,72.36 248.11,71.94 260.43,71.94 v1(264.06,75.57) ; RC840.1 187.16,97.1 185.58,95.52 182.19,95.52 181.69,95.02 180.82,95.02 180.54,95.31 v1(180.54,95.61)
  IN1 w0.089: v1(180.54,95.61) 180.97,95.61 182.2,96.84 183.95,96.84 184.26,96.53 185.35,96.53 185.54,96.72 185.54,97.04 185.71,97.21 187.97,97.21 189.59,95.6
  IN1 w0.099: v1(237.1,98.3) 236.83,98.57 235.1,98.57 233.61,97.08 227.8,97.08 227.29,96.57 223.87,96.57 222.97,95.68 222.01,94.72 216.91,94.72 216.75,94.88 215.4,94.88 214.78,94.26 197.25,94.26 197.15,94.35 197.15,94.83 196.71,95.27 196.46,95.27 196.15,95.58 193.96,95.58 193.68,95.3 189.89,95.3 189.59,95.6 ; v1(278.13,76.53) 278.13,77.26 275.9,79.48 267.93,79.48 265.26,76.81 265.26,75.67 265.16,75.57 v1(264.06,75.57)
  IN2 w0.102: v1(245.42,73.15) 244.04,73.15 237.55,79.64 236.85,79.64 235.03,81.46 235.03,81.77 233.93,82.88 233.93,94.34 237.1,97.52 v1(237.1,98.3)
  BOTTOM w0.076: v1(180.54,95.61) 180.49,95.66 180.49,95.86 UC1.CK23
WWAN_GPIO_WAKE#_R: length 2.3
  TOP w0.107: v2(280.21,78.85) 279.96,78.6 RZ1394.1 279.99,77.83 UZ51.3
WWAN_PERST#: length 16.4
  TOP w0.107: RZ1481.1 RZ1480.1 272.03,83.65 v1(271.82,83.45) ; v1(281.44,81.61) 281.57,81.48 RZ1401.2 RZ1406.1
  BOTTOM w0.107: JNGFF2.42 v1(271.82,83.45) 272.14,83.77 280.6,83.77 v2(280.89,83.48) 281.91,82.46 281.91,82.08 v1(281.44,81.61)
WWAN_PERST#_R: length 1.1
  TOP w0.107: RZ1401.1 283.03,82.12 UZ52.C2
WWAN_PEWAKE#: length 13.9
  TOP w0.107: v2(277.59,75.88) v1(278.13,75.88) RZ1396.1 RZ1395.2 ; v1(272.82,80.4) 272.82,81.65 RZ1400.1
  IN3 w0.102: v1(278.13,75.88) 277.36,76.64 277.36,78.75 276.6,79.51 273.17,79.51 272.82,79.86 v1(272.82,80.4)
  BOTTOM w0.107: JNGFF2.46 v1(272.82,80.4)
WWAN_PEWAKE#_R: length 2.7
  TOP w0.107: v2(278.02,74.23) RZ1395.1 279.42,73.8 279.84,73.8 279.99,73.95 UZ51.4
WWAN_RADIO_DIS#: length 32.3
  TOP w0.107: v1(250.41,100.63) 250.43,100.63 250.85,100.22 UE1.F12 ; DZ5.1 v2(262.57,84.67) 262.57,85.61 v1(263.23,86.27)
  IN2 w0.102: v1(259.98,99.05) 260.88,99.05 261.39,98.54 261.39,96.63 262.24,95.78 262.24,89.13 263.23,88.14 v1(263.23,86.27)
  IN3 w0.089: 252.24,100.52 251.91,100.18 250.91,100.18 250.46,100.63 v1(250.41,100.63)
  IN3 w0.102: v1(259.98,99.05) 259.98,99.3 259.84,99.44 257.81,99.44 256.24,101.01 253.95,101.01 253.82,101.15 252.87,101.15 252.24,100.52
  BOTTOM w0.089: 249.52,100.82 249.71,100.63 v1(250.41,100.63)
  BOTTOM w0.107: RE10.1 248.72,101.62 249.52,100.82
WWAN_RADIO_DIS#_R: length 3.3
  TOP w0.107: DZ5.2 262.57,80.72 v2(262.38,80.53) 261.88,80.53 v1(261.68,80.73)
  BOTTOM w0.107: v1(261.68,80.73) 261.33,81.08 JNGFF2.8
WWAN_WAKE#: length 30.6
  TOP w0.107: v2(264.49,85.04) 265.19,84.34 v1(265.19,83.81) 264.57,83.81 RZ133.2 264.47,83.75 QC8.1 ; v1(255.92,102.39) 255.65,102.12 UE1.M13
  IN2 w0.102: v1(255.92,102.39) 255.93,102.39 255.93,101.37 257.45,99.85 261.24,99.85 262.35,98.74 262.35,96.56 262.75,96.16 263.36,96.16 263.62,95.9 263.62,94.81 262.69,93.89 262.69,89.32 265.19,86.83 v1(265.19,83.81)
WWAN_WAKE#_D: length 10.6
  TOP w0.107: v2(264.74,78.55) RZ132.2 ; RZ132.2 264.74,79.91 265.12,80.29 QC8.3 ; RZ132.2 265.39,79.58 v1(266.05,80.24)
  IN2 w0.102: v1(266.05,80.24) 265.57,79.76 265.57,78.43 264.63,77.49 v1(264.63,76.18)
  BOTTOM w0.107: JNGFF2.15 265.08,75.86 264.75,76.18 v1(264.63,76.18)
XCLK_BIASREF: length 3.5
  BOTTOM w0.114: UC1.CJ1 179.52,110.44 v1(179.52,112) 179.52,112.91 RC402.1
XDP_DBRESET#: length 171.9
  TOP w0.107: v1(204.63,126.1) 204.63,124.63 v2(204.7,124.56) 206.37,122.89 206.37,115.77 207.93,114.21 207.93,106.15 206.88,105.1 206.88,102.37 v1(206.78,102.28)
  IN3 w0.102: v1(204.63,126.1) 204.63,126.4 202.22,128.82 197.12,128.82 196.1,129.83 183.83,129.83 183.31,129.31 181.46,129.31 180.18,128.04 164.69,128.04 161.55,124.9 159.96,124.9 158.82,123.77 157.91,123.77 156.88,122.74 150.95,122.74 148.8,124.89 141.36,124.89 140.75,125.5 135.66,125.5 135.23,125.07 134.82,124.66 134.1,124.66 v1(133.69,125.07)
  BOTTOM w0.107: RC248.1 RC243.1 193.17,101.95 CC78.1 193.59,101.94 193.76,101.77 194.47,101.77 194.57,101.67 195.01,101.23 205.74,101.23 v1(206.78,102.28) ; JXDP1.48 90.27,130.66 90.71,130.21 CC326.1 90.64,129.06 89.79,128.2 RC137.1 89.73,127.6 89.84,127.49 89.84,126.76 90.21,126.39 93.03,126.39 93.15,126.28 108.85,126.28 113.3,121.83 115.15,121.83 115.3,121.68 120.64,121.68 120.82,121.51 127.41,121.51 129.98,124.08 133.13,124.08 133.69,124.64 v1(133.69,125.07)
XDP_JTAGX: length 19.6
  TOP w0.107: RC87.1 CC305.1 137.36,116.95 RC328.2 137.36,115.4 v2(137.1,115.15) 136.14,114.18 v1(135.38,114.18)
  IN1 w0.089: 140.46,111.58 140.76,111.28 140.76,110.99 143.4,108.36 145.26,108.36 145.64,107.97 145.64,107.44 145.93,107.15 v1(146.18,107.15)
  IN1 w0.099: v1(135.38,114.18) 136.01,114.18 136.32,113.88 138.16,113.88 140.46,111.58
  BOTTOM w0.089: v1(146.18,107.15) 145.77,106.96 UC1.P6
XDP_OBS0: length 2.4
  TOP w0.107: v2(81.39,134.66) 81.67,134.94 v1(82.17,134.94) 82.35,134.75 RC239.2
  BOTTOM w0.107: v1(82.17,134.94) JXDP1.21
XDP_OBS0_R: length 98.3
  TOP w0.107: v1(81.36,135.6) 81.36,135.41 81.02,135.07 81.02,134.39 82.06,133.35 RC239.1 ; v1(146.96,131.7) 147.3,131.7 147.48,131.51 v2(147.48,130.74) 147.48,125.45 146.04,124.01 v1(145.79,124.01)
  IN3 w0.102: v1(146.96,131.7) 143.6,131.7 142.71,130.8 134.92,130.8 134.62,130.5 131.84,130.5 131.72,130.39 124.1,130.39 120.39,134.09 114.79,134.09 111.85,131.15 110.07,131.15 109.53,130.61 105.93,130.61 105.7,130.85 105.52,131.02 103.5,131.02 103.08,131.45 101.8,132.73 100.41,132.73 97.73,135.41 93.33,135.41 93.01,135.73 92.4,135.73 92.05,135.37 84.91,135.37 84.87,135.41 81.54,135.41 v1(81.36,135.6)
  BOTTOM w0.076: 147.19,113.04 147.19,112.89 147.56,112.52 147.56,110.42 UC1.U1
  BOTTOM w0.107: v1(145.79,124.01) 145.39,123.61 145.39,119.56 145.66,119.29 145.66,115.85 147.07,114.44 147.07,113.16 147.19,113.04
XDP_OBS1: length 2.2
  TOP w0.107: RC240.2 83.12,134.61 82.79,134.94 v1(82.77,134.94) 82.77,135.21 v2(82.52,135.47)
  BOTTOM w0.107: JXDP1.23 82.77,134.93 v1(82.77,134.94)
XDP_OBS1_R: length 95.5
  TOP w0.107: v1(144.98,124.01) 145.52,124.55 146,124.55 146.96,125.5 v2(146.96,129.45) 146.96,130.58 v1(146.47,131.07) ; RC240.1 v1(83.12,132.66)
  IN3 w0.102: v1(83.12,132.66) 83.69,133.23 85.28,133.23 85.75,133.7 86.35,133.7 86.62,133.98 90.28,133.98 90.72,134.43 91.3,134.43 91.68,134.81 92.06,134.81 92.57,135.32 92.84,135.32 93.16,135 97.56,135 100.41,132.14 101.81,132.14 103.34,130.62 105.35,130.62 105.77,130.21 109.7,130.21 110.24,130.75 112.02,130.75 114.21,132.94 115.06,132.94 115.8,133.68 120.22,133.68 124.94,128.97 132.59,128.97 133.19,129.57 134.4,129.57 135.19,130.35 142.83,130.35 143.77,131.29 146.25,131.29 v1(146.47,131.07)
  BOTTOM w0.076: UC1.U2 147.66,109.9 147.37,110.19 147.37,112.48 146.76,113.09 146.76,113.25
  BOTTOM w0.107: v1(144.98,124.01) 144.98,119.39 145.25,119.12 145.25,115.22 146.76,113.71 146.76,113.25
XDP_PRSNT_PIN1: length 4.2
  TOP w0.107: v2(76.2,136.47) RC122.1 RC121.1 75.75,135.71 v1(75.88,135.58)
  BOTTOM w0.107: v1(75.88,135.58) 75.71,135.42 75.71,134.92 76.17,134.47 JXDP1.1
XDP_TMS: length 60.2
  TOP w0.107: RC735.1 129,118.07 RC852.2 129,118.95 128.85,119.1 126.12,119.1 122.55,115.53 122.55,115.24 121.86,114.55 119.86,114.55 116.1,118.32 100.06,118.32 97.99,116.25 94.9,116.25 91.87,119.28 91.87,131.24 92.18,131.55 92.18,132.37 v2(92.53,132.73) v1(93.09,132.73)
  BOTTOM w0.107: JXDP1.58 93.27,131.57 93.44,131.74 93.52,131.74 93.62,131.85 93.62,132.32 93.22,132.73 v1(93.09,132.73)
XTAL24_IN: length 3.5
  BOTTOM w0.076: CC21.1 183.37,116.35 183.55,116.53
  BOTTOM w0.107: CC21.1 183.37,115.29 RC59.2 RC728.2 ; YC1.3 183.55,116.53
XTAL24_IN_CPU: length 6.1
  BOTTOM w0.107: UC1.CK3 180.58,109.12 180.58,109.44 180.88,109.75 180.88,110.06 180.75,110.18 180.75,111 RC728.1
XTAL24_OUT: length 1.6
  BOTTOM w0.076: RC59.1 RC531.1 RC729.2
XTAL24_OUT_CPU: length 5.4
  BOTTOM w0.107: RC729.1 181.59,112.14 180.52,111.07 180.52,110.34 180.16,109.97 180.04,109.97 179.8,109.73 179.8,109.45 179.88,109.37 180.03,109.37 180.08,109.42 UC1.CK2
XTAL24_OUT_R: length 4.2
  BOTTOM w0.076: RC531.2 181.59,114.4 182.51,115.32 CC22.1 182.94,115.82 182.94,117.02 182.45,117.5
  BOTTOM w0.107: YC1.1 182.45,117.5
XTALI: length 7.2
  TOP w0.107: UL1.10 273.26,103.94 274.06,103.13 274.06,102.88 274.96,101.98 RL11.2 275.27,101.36 275.55,101.36 v2(275.89,101.03) 275.89,100.09 CL14.1 275.83,99.59 276.04,99.38 YL1.1
XTALO: length 4.3
  TOP w0.107: UL1.9 272.86,103.83 v2(273.45,103.24) 273.55,103.13 273.55,102.75 274.05,102.26 RL11.1 RL34.2
XTALO_R: length 3.5
  TOP w0.107: RL34.1 CL13.1 274.96,99.57 275.33,99.2 275.33,98.48 YL1.3
Z2805: length 3.3
  TOP w0.107: v2(298.75,98.87) RL18.1
  TOP w0.254: RL18.1 v1(297.82,99.88)
  BOTTOM w0.254: TL1.22 v1(297.82,99.88)
Z2806: length 3.3
  TOP w0.107: v2(298.75,106.5) RL16.1
  TOP w0.254: RL16.1 v1(297.82,107.5)
  BOTTOM w0.254: TL1.16 v1(297.82,107.5)
Z2807: length 3.3
  TOP w0.107: v2(298.75,102.17) RL17.1
  TOP w0.254: RL17.1 v1(297.82,101.15)
  BOTTOM w0.254: TL1.21 v1(297.82,101.15)
Z2808: length 3.3
  TOP w0.107: v2(298.75,109.76) RL15.1
  TOP w0.254: RL15.1 v1(297.82,108.77)
  BOTTOM w0.254: TL1.15 v1(297.82,108.77)
N43975: length 1
  TOP w0.107: RN2.2 v2(252.42,31.4)
N14112977: length 2.2
  TOP w0.107: v2(285.77,45.84) 285.58,45.84 CA33.1 RA17.2
N14113161: length 1.3
  TOP w0.203: UZ5.10 270.3,56.27 CZ127.1
N14113197: length 1.3
  TOP w0.203: CZ126.1 271.1,56.27 UZ5.12
N14123010: length 3.3
  TOP w0.203: UA1.21 287.33,56.47 287.5,56.63
  TOP w0.254: RA44.1 288.17,58.04 CA51.1 288.16,57.29 287.5,56.63
N14123018: length 2.8
  TOP w0.203: UA1.6 285.73,50.35
  TOP w0.254: 285.73,50.35 v2(285.73,49.81) 285.73,49.3 285.87,49.16 CA53.1
N14123022: length 2.9
  TOP w0.203: UA1.32 282.07,54.94 v2(281.64,55.37) 281.47,55.54 281.46,55.54 281.24,55.77 CA52.1
N14124153: length 5.2
  TOP w0.107: v2(291.93,52.14) 291.68,52.39 CA25.1
  TOP w0.203: UA1.15 288.7,53.34 289.07,53.71 291.33,53.71 CA25.1
N14124758: length 9.2
  TOP w0.107: v2(294.12,52.38) 294.88,53.13 RA53.1 RA54.1 294.5,54.43 292.6,54.43 292.19,54.01 288.95,54.01 288.68,53.74 UA1.16
N14124937: length 2.3
  TOP w0.203: UA1.22 286.93,56.57 287.33,56.97 287.33,57.54 287.08,57.8 CA35.1
N14176097: length 9.1
  TOP w0.107: RE90.2 RE70.1 249.55,81.11 248.19,81.11 247.95,80.87 247.95,79.63 248.29,79.28 v2(249.01,79.28) 249.21,79.28 249.8,79.88 251.47,79.88 251.76,79.59 QE11.3
N14176137: length 2.4
  TOP w0.107: v2(248.7,80.64) RE70.2 250.73,80.64 QE4.2
N15644626: length 1.6
  TOP w0.107: CZ114.1 224.09,85.54 224.13,85.5 UZ3.10
N15647018: length 1.5
  TOP w0.107: CZ121.1 275.73,63.9 275.97,64.15 UZ8.6
N15674340: length 15.1
  BOTTOM w0.107: JNGFF2.17 265.58,73.76 265.17,73.35 263.65,73.35 263.08,73.92 263.08,76.03 262.32,76.78 259.7,76.78 259.01,77.48 RZ326.1 v2(255.41,76.34)
N15699868: length 9.6
  TOP w0.107: v2(244.57,125.98) DE2.1 243.9,124.66 243.85,124.61 RE543.2 242.63,124.1 242.63,123.19 241.82,122.37 RE565.1 RE541.2 CE64.1 242.5,120.22 242.71,120.42 QE15.2
N15699880: length 2.4
  TOP w0.107: QE17.1 247.07,122.76 v2(247.35,122.48) 247.45,122.37 RE546.2
N15701008: length 2.1
  BOTTOM w0.107: RE350.2 CE57.1 244.33,96.73 v2(244.74,96.33)
N16624469: length 3.5
  TOP w0.107: v2(55.65,123.78) CT90.1 55.23,122.46 RT111.2 55.23,121.44 55.62,121.04 UT7.3
N16783095: length 1.8
  BOTTOM w0.107: PR108.1 204.34,39.08 v2(204.52,39.25)
  BOTTOM w0.254: PR108.1 PC113.2
N16783134: length 1.9
  BOTTOM w0.107: PR117.1 v2(73.52,71.5)
  BOTTOM w0.254: PR117.1 74.56,71.57 PC127.2
N16783222:
  vias: v1(77.88,73.87)
N17370862: length 2
  BOTTOM w0.107: PQ5.1 74,112.24 v2(73.11,113.13)
N17370885: length 3.9
  BOTTOM w0.107: v2(74.58,107.41) 74.3,107.69 PR10.2
  BOTTOM w0.254: PQ5.2 75.7,109.62 75.04,108.96 PR15.1 PR10.2
N17370921: length 14.7
  TOP w0.254: PQ1.6 86.48,115.34 v2(86.48,114.65) 86.48,113.81 85.29,112.62 v1(85.15,112.62)
  IN1 w0.254: v1(85.15,112.62) 84.66,112.62 80.45,108.4 v1(76.58,108.4)
  BOTTOM w0.254: PR15.2 v1(76.58,108.4)
N17370927: length 2.4
  BOTTOM w0.107: PQ7.1 78.61,108.59 v2(78.06,108.04)
  BOTTOM w0.254: PR16.2 78.61,109.69 PQ7.1
N17370961: length 6.6
  TOP w0.107: PR3.1 v2(75.19,129.36)
  TOP w0.254: PR3.1 76.14,129.32 PQ2.1 75.37,126.2 PR6.1 74.01,125.5 PL3.1
N17370983: length 5.4
  TOP w0.107: PR3.2 78.32,129.36 v2(78.48,129.53)
  TOP w0.254: PR5.1 79.92,127.94 PQ2.3 77.74,127.94 77.1,128.59 PR3.2
N17370995: length 4.7
  TOP w0.107: v2(75.47,121.79) 75.22,121.79 74.87,122.13 74.87,123.35 PR8.1
  TOP w0.254: PR6.2 PR8.1 76,123.85 PQ3.2
N17370999: length 4.6
  TOP w0.107: v2(80.07,125.6) 79.28,125.6 78.88,126.01 PQ2.2
  TOP w0.254: PQ2.2 78.23,124.97 PR7.2 78.6,123.89 PQ3.1
N17371029: length 5.7
  TOP w0.107: v1(76.7,120.03) v2(76.07,120.03)
  TOP w0.508: PR18.1 79.36,118.79 PQ11.1 77.94,118.79 v1(76.7,120.03)
  BOTTOM w0.107: PC6.2 76.36,119.68 v1(76.7,120.03)
N17371043: length 2.3
  TOP w0.107: PQ6.1 82.43,118.12 v2(82.88,118.12)
  TOP w0.254: PQ6.1 81.61,118.61 PR18.2
N17371125: length 2.9
  BOTTOM w0.107: v2(83.14,110.18) 83.09,110.23 82.2,110.23 PR20.1
  BOTTOM w0.254: PR20.1 81.66,109.69 PQ7.2
N17371182: length 3.8
  TOP w0.107: PR22.2 81.87,121.66 80.78,121.66 80.49,121.96 v2(80.49,122.74)
  TOP w0.254: PR22.2 81.92,121.18 PQ6.2
N17372063: length 4
  TOP w0.254: PQ1.3 84.88,117.12 85.16,116.84 PR19.2 PR17.2
N17372074: length 2.1
  TOP w0.107: v2(85.67,113.56) 85.54,113.69 PR25.1
  TOP w0.254: PQ1.5 85.54,115.63 PR25.1
N17372283: length 2.9
  TOP w0.254: PQ1.2 85.53,118.06 85.78,118.31 87,118.31 PR19.1
N17538214: length 7.8
  TOP w0.254: PQ11.2 79.64,121.85 79.51,121.98 PR31.2 79.79,122.63 80.07,122.35 v1(80.07,122.15)
  BOTTOM w0.254: v1(80.07,122.15) 80.07,121.85 80.6,121.32 81.1,121.32 v2(81.71,120.71) 82.12,120.3 83.9,120.3 PR32.1
N17539406: length 3.4
  BOTTOM w0.107: v2(90.76,116.98) 90.33,117.41 PR33.2
  BOTTOM w0.254: PR33.2 90.33,118.62 90.11,118.83 PQ10.6 PQ10.5
N18291828: length 5.9
  BOTTOM w0.076: UT5.F10 62.58,104.56 63.31,104.56 63.68,104.93 64.52,104.93 64.57,104.98
  BOTTOM w0.107: RT97.2 RT98.1 RT99.1 v2(65.49,104.98) 64.57,104.98
N18292318: length 3.1
  BOTTOM w0.076: UT5.K9 62.08,106.56 62.08,107.12 62.56,107.6 62.56,107.9
  BOTTOM w0.107: 62.56,107.9 62.56,108.81 RT104.1
N18292320: length 4.6
  BOTTOM w0.076: 63.25,107.9 63.25,107.86 63.12,107.73 63.12,107.47 62.58,106.92 62.58,106.56 UT5.K10
  BOTTOM w0.107: v2(64.84,109.66) 64.37,109.19 63.96,109.19 RT105.1 63.76,108.69 63.25,108.18 63.25,107.9
N18292328: length 4.7
  BOTTOM w0.076: 63.5,107.9 63.5,107.8 63.31,107.61 63.31,107.42 62.83,106.93 UT5.L11
  BOTTOM w0.107: RT103.1 66.2,108.95 65.73,108.48 v2(65.41,108.48) 64.06,108.48 63.5,107.93 63.5,107.9
N18292515: length 1.3
  TOP w0.107: CT87.1 60.7,106.4 v1(60.7,105.78)
  BOTTOM w0.076: UT5.H7 60.7,105.44 v1(60.7,105.78)
N18292570: length 3.9
  TOP w0.107: RT101.1 59.98,103.56 v1(59.98,102.83) 60.38,102.43 60.38,102.04 60.73,101.7 v2(60.73,100.67)
  BOTTOM w0.076: UT5.D6 59.98,102.96 v1(59.98,102.83)
N18601091: length 3.4
  BOTTOM w0.076: UT5.F1 57.51,103.99 57.19,103.99 57.13,103.93
  BOTTOM w0.112: RT63.1 55.27,103.93 57.13,103.93
N19529559: length 4.8
  TOP w0.107: v1(56.04,102.36) 56.44,101.96 56.8,101.96 57.02,102.18 RT378.1 57.26,101.69 v2(56.82,101.24)
  BOTTOM w0.076: 56.79,103.04 57.09,103.04 57.36,103.31 UT5.D1
  BOTTOM w0.112: v1(56.04,102.36) 56.71,103.04 56.79,103.04
N19529561: length 3.2
  TOP w0.107: v1(56.62,102.37) 56.62,102.37 RT379.1
  BOTTOM w0.076: 56.62,102.68 56.75,102.81 57.24,102.81 57.49,103.06 58.08,103.06 UT5.D2
  BOTTOM w0.112: 56.62,102.68 v1(56.62,102.37)
N21875993: length 3.8
  TOP w0.107: v1(228.13,84.81) 227.13,84.81 227.02,84.7 UZ3.3
  BOTTOM w0.107: v1(228.13,84.81) 228.12,84.82 226.67,84.82 226.56,84.93 RZ64.2
N21880967: length 2.8
  TOP w0.107: LV1.1 136.33,132.62 v1(136.12,132.41)
  BOTTOM w0.107: v2(136.54,132.82) v1(136.12,132.41) 136.12,132.01 135.77,131.66 JEDP1.21
N22005589: length 4.1
  TOP w0.107: UZ3.12 224.13,84.7 224.09,84.66 CZ113.1 222.86,84.66 222.33,84.14 221.51,84.14 v2(220.9,84.74)
N24654285: length 1.9
  TOP w0.107: v2(285.14,80.87) 285.14,82.73
N24906879: length 8.3
  TOP w0.508: PR708.1 78.08,47.28 v2(77.08,48.27) 77.08,49.74 77.59,50.25 PD700.1 PD704.1 PD702.1
N24908379: length 1.7
  BOTTOM w0.254: PR737.2 74.99,44.35 74.47,44.87 PD705.2
N24908381: length 3.5
  BOTTOM w0.107: PR736.2 73.07,43.84 v2(72.31,43.08)
  BOTTOM w0.254: PR735.1 PR736.2 73.31,44.23 PD705.3
N24908396: length 2.2
  BOTTOM w0.254: PU701.2 76.64,46.86 v2(76.95,47.17) 77.15,47.37 PR741.2
N24908406: length 4.3
  BOTTOM w0.107: v2(74,47.67) 73.33,47 PD705.1
  BOTTOM w0.254: PU701.1 75.99,46.41 75.9,46.49 PR739.1 74.19,46.49 73.91,46.77 PD705.1
N24908424: length 3.4
  BOTTOM w0.107: PR740.1 77.14,43.08 76.92,42.86 v2(76.92,41.18)
  BOTTOM w0.254: PU701.4 77.29,43.57 77.4,43.46 PR740.1
N24908981: length 0.8
  BOTTOM w0.254: PR728.2 PC751.1
N25591846: length 3.4
  TOP w0.107: PR47.2 78.01,116.14 v2(77.5,115.63)
  TOP w0.254: PR47.2 PC13.2 79.03,115.34 79.3,115.61 PU3.5
N25591872: length 6.1
  TOP w0.107: v2(79.74,113.54) 79.84,113.43 80.81,113.43 81.31,113.94 PR43.2
  TOP w0.254: PR43.2 PR45.1 80.58,116.44 80.11,116.91 PU3.4
N25591876: length 2.5
  TOP w0.254: PR44.2 83.05,117.16 v2(82.71,116.82) 82.15,116.26 PU3.2
N25591912: length 12.9
  TOP w0.254: v1(85,113.36) 84.97,113.39 84.84,113.39 84.27,113.95 83.21,113.95 82.98,114.18 PR41.2 PR43.1
  BOTTOM w0.254: PQ10.2 87.88,120.09 87.49,119.7 87.49,118.18 87.18,117.88 85.73,117.88 85.53,117.68 85.53,116.56 85.61,116.48 85.61,116.36 85.82,116.14 v2(85.82,115.73) 85.82,114.08 85.1,113.36 v1(85,113.36)
N25591942: length 13.9
  TOP w0.254: PR44.1 83.82,120.41 v1(83.4,120.82) 83.4,121.05 PR22.1
  BOTTOM w0.254: PQ8.1 90.92,122.32 89.76,122.32 89.47,122.03 PR27.1 v2(87.46,121.79) 85.17,121.79 84.69,121.31 83.89,121.31 v1(83.4,120.82)
N25591952: length 2.6
  TOP w0.254: PR42.2 83.64,116.42 v2(82.75,115.53) 82.23,115.53 82.15,115.61 PU3.1
N25840198: length 1.7
  TOP w0.102: T353.1 146.83,93.42 147.25,93 v1(147.31,93)
  BOTTOM w0.089: UC1.V28 v1(147.31,93)
N25840204: length 1.1
  TOP w0.102: v1(147.31,92.37) 147.7,91.98 T354.1
  BOTTOM w0.089: UC1.V29 v1(147.31,92.37)
N25845141: length 2
  BOTTOM w0.107: CC1453.1 RC299.2 203.06,90.65 v2(202.83,90.42)
N25845143: length 1.9
  BOTTOM w0.107: v2(203.16,100.4) RC289.2 CC1452.1
N25890123: length 3
  TOP w0.107: PC647.1 88.01,89.91 87.35,89.25 v2(87.35,88.11)
  TOP w0.254: PC647.1 88.16,90.04 PR650.2
N25907811: length 8
  BOTTOM w0.107: v2(57.01,91.5) PR800.2
  BOTTOM w0.254: PR805.1 56.95,90.45 PR800.2 56.27,90.5 56.02,90.24 PR817.1 PC804.1 56.02,88.52 56.83,87.7 56.83,86.89 56.57,86.63 PU800.3
N25907823: length 5.3
  BOTTOM w0.107: v2(54.02,88.75) 54.11,88.66 PR809.2
  BOTTOM w0.254: PC800.1 54.17,85.98 PU800.2 ; PC800.1 PR809.2 ; PC800.1 PR815.1
N25907922: length 8.8
  TOP w0.107: PR807.1 94.55,83.46 v2(95.03,83.94)
  TOP w0.254: PR801.2 90.1,85.67 90.48,85.29 92.01,85.29 93.05,86.33 PQ803.2 94.04,85.77 PR807.1
N25907924: length 3.4
  TOP w0.107: v2(95.07,82.55) PR807.2
  TOP w0.254: PR807.2 92.77,82.55 PR858.1 92.72,81.83 PQ802.6
N25907948: length 1.3
  BOTTOM w0.254: PU801.1 83.51,98.39 83.12,97.99 PR853.2
N25907954: length 4.4
  BOTTOM w0.107: v2(86.44,102.65) 85.9,102.65 85.4,102.16 PR860.2
  BOTTOM w0.254: PR860.2 PR859.2 PC814.2 83.51,101.99 PU801.5
N25907966: length 4.8
  BOTTOM w0.107: v2(81.64,93.23) 81.47,93.41 PR818.2
  BOTTOM w0.254: PQ804.2 83.88,95.21 83.62,95.47 82.96,95.47 82.74,95.24 82.74,94.55 82.42,94.23 PR818.2
N25907978: length 5.9
  BOTTOM w0.107: v2(79.28,97.64) 79.83,98.18 PQ807.1
  BOTTOM w0.254: PQ807.1 80.57,97.81 PR822.2 81.21,97.79 81.75,97.26 81.75,97.08 81.92,96.9 PR854.1 82.23,96.34 81.47,95.58 PR818.1
N25907980: length 41.6
  TOP w0.203: PQ802.5 93.66,81.35 93.28,80.97 90.29,80.97 89.09,82.18 89.09,83 83.27,88.82 v1(82.86,88.82)
  BOTTOM w0.254: v1(82.86,88.82) 80.96,90.73 80.96,92.91 79.35,94.52 78.58,94.52 77.66,95.45 v2(77.66,100.2) 77.66,100.4 80.27,103.02 PR856.1 81.21,102.46 81.21,100.91 82.23,99.9 83.5,99.9 84.01,99.39 PR857.2
N25907988: length 4.5
  BOTTOM w0.107: PR855.1 82.74,102.21 82.25,102.69 v2(82.25,103.97)
  BOTTOM w0.254: PR855.1 PR856.2 81.77,101.48 82.21,101.04 PU801.4
N25908000: length 1.4
  BOTTOM w0.254: PU801.2 82.86,98.75 82.23,98.12 PR854.2
N25908024: length 9.5
  BOTTOM w0.107: PR870.2 63.51,90.54 v2(63.61,90.64)
  BOTTOM w0.254: PR831.2 61.53,86.76 PC811.1 ; PC811.1 60.94,87.5 60.72,87.28 PU800.5 ; PC811.1 PR842.1 63.3,87.5 PD802.1 ; PD802.1 63.69,89.34 PR870.2 ; PD802.1 65.37,87.89 PQ813.6
N25908041: length 7.5
  BOTTOM w0.107: PD802.2 63.69,85.14 v2(64.52,84.3)
  BOTTOM w0.254: PR840.1 65.01,86.81 PD802.2 63.3,85.88 PR835.2 PC813.1 61.42,85.98 PU800.7
N25908049: length 6.3
  BOTTOM w0.107: v2(59.67,90.61) PR843.1
  BOTTOM w0.254: PU800.6 59.11,86.63 58.86,86.89 58.86,87.58 59.67,88.39 PC812.1 PR843.1 58.81,89.48 PR832.2
N25908061: length 1.9
  BOTTOM w0.107: PR840.2 v2(66.18,85.81)
  BOTTOM w0.254: PR840.2 66.18,87.74 PQ813.5
N25908120: length 2.3
  BOTTOM w0.107: PR811.2 82.53,91.67 v2(81.79,91.67)
  BOTTOM w0.254: PR811.2 82.83,92.58 PQ804.6
N25908122: length 59.7
  TOP w0.381: PQ800.4 69.91,108.91 69.9,108.9 PR803.2 PC803.2 69.9,105.67 v2(70.71,104.86) v1(71.74,103.83) ; v1(72.45,85.42) 73.97,86.94 79.33,86.94 81.83,89.44 v1(82.93,89.44) 83.41,89.44 88.97,83.88 92.15,83.88 PQ803.1
  IN2 w0.381: v1(71.74,103.83) 71.74,96.39 68.77,93.42 68.77,83 69.27,82.5 70.47,82.5 72.45,84.48 v1(72.45,85.42)
  BOTTOM w0.381: PR811.1 82.77,91 82.77,89.59 v1(82.93,89.44)
N25908132: length 2.2
  BOTTOM w0.107: PR836.1 v2(68.19,90.55)
  BOTTOM w0.254: PQ813.3 66.82,90.38 PR836.1
N25908138: length 5.1
  TOP w0.107: PR808.1 82.79,113.03 83.23,113.47 84.18,113.47 84.63,113.03 v2(84.63,112.79)
  TOP w0.254: PR808.1 PR802.2 82.05,112.04 81.57,111.55 PQ805.2
N25908140: length 13.9
  TOP w0.254: PQ806.3 92.03,117.56 91.56,117.09 91.56,115.15 91.49,115.08 91.49,114.49 89.98,112.98 88.07,112.98 v2(86.42,111.33) 84.13,111.33 83.7,111.76 PR808.2
N25908152: length 31.7
  TOP w0.254: v1(82.48,111.26) 83.16,110.59 PQ805.1 85.14,110.59 85.21,110.51 86.72,110.51 v2(87.5,109.74) 87.5,105.47 87.69,105.28 v1(87.69,104.53) ; PQ801.4 77.67,111.67 PC802.2 77.72,112.58 PR804.2 76.64,112.6 v1(76.39,112.34)
  IN2 w0.254: v1(87.69,104.53) 88.18,104.04 88.18,101.38 85.28,98.47 v1(85.28,97.61)
  IN3 w0.254: v1(82.48,111.26) 82.48,110.56 81.85,109.93 78.8,109.93 v1(76.39,112.34)
  BOTTOM w0.254: v1(85.28,97.61) 85.28,97.17 84.91,96.8 PR812.1
N25908168: length 4
  TOP w0.107: PR852.2 87.56,116.1 v2(87.28,115.82)
  TOP w0.254: PQ806.6 89.77,116.26 89.58,116.08 PR814.2 ; PR814.2 89.15,115.28 PR813.2 ; PR814.2 89.12,116.1 PR852.2
N25908188: length 2.1
  BOTTOM w0.107: PR812.2 v2(83.93,95.88)
  BOTTOM w0.254: PR812.2 84.89,95.53 84.53,95.16 PQ804.3
N25908210: length 2.8
  TOP w0.107: v2(89.37,118.23) 89.14,118.23 88.87,117.97 88.87,117.27 PR814.1
  TOP w0.254: PR814.1 89.23,116.91 PQ806.5
N25908220: length 3.2
  TOP w0.203: PR820.1 93.28,115.06 v2(93.28,115.78) 93.28,116.39 92.97,116.7 92.35,116.7 PQ806.2
N25908319: length 3.3
  BOTTOM w0.107: v2(83.29,90.06) 83.29,91.78 83.49,91.97 PR816.2
  BOTTOM w0.254: PR816.2 83.88,92.1 PQ804.5
N25908329: length 3.9
  TOP w0.107: PR826.2 47.18,91.18 47.62,91.63 47.62,92.5 v2(47.93,92.81)
  TOP w0.254: 46.92,90.18 46.92,90.62 47.05,90.75 PR826.2 PR825.2
N25908331: length 3.4
  TOP w0.107: v2(39.04,90.83) PR841.1
  TOP w0.254: PQ808.5 41.84,90.28 40.95,91.17 PR834.2 40.42,91.18 PR841.1
N25908337: length 9.1
  TOP w0.107: v2(39.06,89.05) PR830.2
  TOP w0.254: PR830.2 PR841.2 40.33,90.18 PQ808.6 41.19,90 42.35,88.85 45.4,88.85 45.97,88.28 PQ810.1
N25908347: length 3.7
  TOP w0.107: PR833.2 41.92,86.99 42.21,86.7 v2(42.21,86.21)
  TOP w0.254: PQ808.2 41.84,87.27 PR833.2 42.24,87.2 42.49,87.45 PQ808.3
N25908367: length 3.2
  TOP w0.107: v2(51.23,90.6) 51.11,90.49 PR829.2
  TOP w0.254: PR829.2 50.73,89.56 50.68,89.61 49.73,89.61 49.46,89.87 PQ811.5
N25908379: length 2.9
  TOP w0.107: PR827.2 v2(47.93,87.27)
  TOP w0.254: PR824.2 PR827.2 46.92,88.28
N25908405: length 9.5
  TOP w0.107: v2(42.36,92.3) 42.68,91.98 PR838.2
  TOP w0.254: PQ809.6 43.49,90.42 v1(43.49,91.01) PR845.2 43.24,91.82 PR838.2 ; v1(47.68,91.07) 47.68,90.88 47.57,90.77 PQ810.4
  IN2 w0.254: v1(47.68,91.07) 47.26,91.49 43.98,91.49 v1(43.49,91.01)
N25908421: length 2.9
  TOP w0.107: PR844.2 44.62,91.82 v2(45.27,91.17)
  TOP w0.254: PQ809.5 44.38,90.4 44.2,90.57 44.2,91.64 PR844.2
N25908431: length 3.5
  TOP w0.107: v2(44.71,86.15) 44.71,86.79 44.84,86.92 PR839.2
  TOP w0.254: PQ809.2 44.38,87.65 PR839.2 45.03,87.39 PQ809.3
N25943980: length 6.4
  BOTTOM w0.076: UC1.F37 140.04,86.58 139.15,86.58 138.88,86.31 137.45,86.31
  BOTTOM w0.107: 137.45,86.31 137.32,86.31 136.46,85.45 T16.1
N25943983: length 9.5
  BOTTOM w0.076: 137.45,86.07 138.87,86.07 139.22,86.41 140.11,86.41 141.09,87.39 141.27,87.39 141.44,87.56 141.44,87.81 141.44,87.89 141.36,87.98 141.36,89.07 UC1.F34
  BOTTOM w0.107: 137.45,86.07 136.96,85.59 136.96,83.87 T17.1
N25943986: length 6
  BOTTOM w0.076: UC1.CP36 182.38,88.48 183.56,88.48 185.1,86.94 185.1,84.91 T18.1
N25943989: length 11.8
  BOTTOM w0.076: 186.62,86.62 186.08,87.17 185.54,87.17 183.65,89.07 183.15,89.07 183.12,89.1 182.71,89.1 182.54,88.92 182.54,88.87 182.28,88.62 182.09,88.62 181.84,88.62 181.56,88.34 UC1.CN36
  BOTTOM w0.107: 186.62,86.62 190.24,83 T19.1
N25943992: length 4
  BOTTOM w0.076: UC1.BK34 168.3,89.09 168.3,88.86 168.34,88.75 168.34,88.57 168.3,88.45 168.3,88.21 168.33,88.12 168.33,86.24 168.75,85.83 T20.1
N25943995: length 1.2
  TOP w0.102: T21.1 171.04,99.93 v1(170.6,100.37)
  BOTTOM w0.089: v1(170.6,100.37) 170.6,100.36 UC1.BR18
N25944085: length 14.1
  BOTTOM w0.076: 185.4,110.48 185.4,109.53 184.79,108.92 183.3,108.92 182.94,108.56 UC1.CR4
  BOTTOM w0.107: 185.4,110.48 185.4,111.64 189.12,115.37 189.12,115.48 189.76,116.11 189.76,117.97 190.03,118.23 T360.1
N25944133: length 3.8
  BOTTOM w0.076: T361.1 170.68,85.76 170.68,87.46 170.86,87.95 170.86,88.1 170.82,88.21 170.82,88.45 170.86,88.57 170.86,89.05 UC1.BP34
N25944139: length 4.9
  BOTTOM w0.076: T363.1 170.01,84.71 170.01,86.02 170.36,86.36 170.36,87.83 170.33,87.92 170.33,88.1 170.37,88.22 170.37,88.44 170.37,88.44 170.37,88.6 170.44,88.66 UC1.BP35
N25944172: length 9.9
  BOTTOM w0.076: T364.1 130.72,91.32 130.72,90.27 132.3,88.69 136.68,88.69 137.43,89.44 UC1.A34
N25944175: length 10
  BOTTOM w0.076: UC1.B35 138.69,89.11 137.74,89.11 136.58,87.96 132.8,87.96 130.45,90.31 T365.1
N25944227: length 48.9
  TOP w0.107: RC564.1 114.99,93.24 v1(115.07,93.16) v2(115.64,93.16)
  IN3 w0.102: v1(155.51,93.64) 155.49,93.64 154.63,94.5 144.97,94.5 144.08,95.39 144.08,97.61 143.74,97.94 138.89,97.94 138.11,97.17 137.22,97.17 135.32,99.06
  IN3 w0.107: 135.32,99.06 135.32,99.07 130.09,99.07 125.58,94.56 124.19,93.16 v1(115.07,93.16)
  BOTTOM w0.2: UC1.AJ27 v1(155.51,93.64)
N25944233: length 1.8
  TOP w0.107: RC564.2 RC436.2 v2(112.61,92.33)
N26168283: length 3
  BOTTOM w0.107: v2(86.06,120.85) 85.78,120.57 PR46.2
  BOTTOM w0.254: PQ12.1 86.23,118.75 85.78,119.2 PR46.2
N26168409: length 2.2
  BOTTOM w0.107: v2(87.99,115.86) 87.53,116.33 PQ12.2
  BOTTOM w0.254: PR49.1 PQ12.2
N26168635: length 2.8
  TOP w0.107: v2(90.52,82.98) 90.74,82.76 PQ814.1
  TOP w0.254: PR858.2 91.8,82.15 91.45,81.8 PQ814.1
N26172409: length 2.8
  TOP w0.107: v2(88.96,79.9) PQ814.2
  TOP w0.254: PR861.1 90.94,79.04 PQ814.2
N26619306:
  vias: v2(100.02,103.27)
N26619381:
  vias: v2(103.13,90.22)
N26643986: length 2.3
  TOP w0.107: T50.1 143.53,45.37 v1(143.53,45.49)
  BOTTOM w0.107: JDIMM1.162 143.7,45.66 v1(143.53,45.49)
N26644006: length 3.5
  TOP w0.107: T51.1 145.22,51.98 145.22,52.83 144.83,53.22 v1(144.55,53.22)
  BOTTOM w0.107: v1(144.55,53.22) 144.55,54 144.45,54.1 JDIMM1.165
N26671961: length 3.2
  TOP w0.107: RD18.1 138.6,44.21 137.19,44.21 v2(136.99,44.41)
  TOP w0.508: RD18.1 CD31.2
N26693933: length 2
  TOP w0.107: v2(216.45,42.83) 216.75,43.13 CD62.2 217.4,43.14 RD31.1
N26732492: length 2.1
  TOP w0.107: v1(221.52,44.17) 221.44,44.17 T54.1
  BOTTOM w0.102: v1(221.52,44.17) 221.52,44.16 221.1,43.74 JDIMM2.162
N26732518: length 3.1
  TOP w0.107: v1(222.34,49) 221.86,49.47 T55.1
  BOTTOM w0.107: v1(222.34,49) 222.34,49.44 221.85,49.93 JDIMM2.165
N26975168: length 2.1
  TOP w0.107: v2(233.87,135.86) 233.14,135.86 PC307.2
  TOP w0.254: PR308.1 232.66,135.38 PC307.2
N26998332: length 15.9
  TOP w0.254: PR865.1 89.21,114.41 PC865.1 v1(90.36,114.43)
  BOTTOM w0.254: PQ8.2 92.73,120.43 93.05,120.75 95.31,120.75 95.86,120.2 v2(95.86,119.5) 95.86,118.7 93.71,116.55 93.71,115.71 93.07,115.07 91.63,115.07 91.42,114.87 91.42,114.77 91.09,114.43 v1(90.36,114.43)
N27109289: length 4.5
  BOTTOM w0.107: v2(207.12,109.95) 206.27,109.95 205.6,110.63 PR314.2 204.18,112.44 PU501.5
N27110628: length 5.9
  TOP w0.254: PU402.4 207.09,130.07 206.9,129.88 206.9,128.94 206.46,128.5 205,128.5 204.71,128.2 v1(204.71,127.98)
  BOTTOM w0.254: PR315.1 v2(204.16,128.52) v1(204.71,127.98)
N27174658: length 1.2
  TOP w0.107: PR3004.2 73.9,38.31 v2(73.82,38.39)
N27174719: length 6.6
  TOP w0.107: v2(67.14,31.53) 67.8,32.19 67.8,32.92 PC3004.2
  TOP w0.254: PU3000.6 70.6,34.9 70.23,34.53 PR3007.2 PR3008.2 68.02,33.28 PC3004.2
N27174755: length 7.3
  TOP w0.107: PR3009.1 v2(71.6,38.54)
  TOP w0.254: PU3000.5 70.49,35.4 70.26,35.18 69.32,35.18 69.22,35.27 PD3002.1 69.22,36.18 PC3005.1 69.74,37.58 PR3011.1 PR3010.1 PR3009.1
N27174767: length 3.1
  TOP w0.254: PR3007.1 PR3006.2 67.93,35.3 v2(68.09,35.46) 68.25,35.62 68.25,36.37 PD3000.1
N27174913: length 6.6
  TOP w0.107: v2(74.82,30.69) 73.8,30.69 72.96,31.53 PR3001.1
  TOP w0.254: PR3001.1 72.27,31.65 71.96,31.95 PQ3000.6 71.09,31.95 70.49,31.35 70.49,31.02 70.12,30.65 PQ3000.3
N27175044: length 8.2
  TOP w0.254: PU3000.2 75.66,34.9 PC3001.2 75.78,35.01 PR3003.2 76.44,34.21 v2(75.07,32.85) 74.76,32.54 PR3002.2
N27175412: length 1.5
  TOP w0.107: v3(65.02,112.11) 65.4,112.49 PR892.1
N27540667: length 1.6
  TOP w0.107: v3(66.7,111.99) PR893.1
N27649604: length 3.3
  TOP w0.107: v2(124.24,136.62) 124.24,135.77 QV2.1 124.7,135.34 124.83,135.2 RV5.2
N27697806: length 4.5
  TOP w0.107: v2(132.44,124.22) 132.06,123.84 RZ388.2 CZ220.1 130.49,122.08 QZ1.2
N27698658: length 3.8
  TOP w0.107: v2(113.09,132.53) 113.29,132.74 RV324.2 ; QV7.2 114.22,133.35 114.1,133.23 RV324.2 ; RV324.2 RV323.2 RV326.2
N27698700: length 6.9
  TOP w0.107: v2(122.75,136.65) 122.75,135.28 122.51,135.04 QV8.2 119.02,135.04 118.82,135.23 CV635.1 RV400.2
N27698720: length 3.7
  TOP w0.107: RV400.1 RV6.1 116.61,136.44 116.41,136.64 v2(115.67,136.64) 115.1,136.64 114.87,136.41 QV7.1
N27698752: length 1.9
  TOP w0.107: QV8.3 120.07,132.12 v2(120.68,131.51)
N27724339: length 1.1
  TOP w0.254: PR3012.1 73.32,34.35 PU3000.1
N27724613: length 1.1
  TOP w0.254: PU3000.7 70.69,34.4 70.28,33.99 PR3013.1
N27950180: length 2.6
  TOP w0.107: UV21.23 v1(298.32,85.36)
  BOTTOM w0.107: v2(297.35,86.35) 297.62,86.08 RV302.2 297.63,85.36 v1(298.32,85.36)
N27950212: length 6.3
  TOP w0.107: UV21.13 293.95,82.7 293.39,82.14 293.39,80 RV300.2 292.26,79.53 v2(291.63,78.9)
N27950231: length 2.8
  TOP w0.107: UV21.18 295.95,83.15 v2(296.58,82.52) 296.58,82.45 296.98,82.05 RV303.1
N29168451: length 12.3
  BOTTOM w0.076: UC1.C34 139.35,89.6 139.06,89.31 138.82,89.31 138.75,89.31 138.58,89.48 138.5,89.56 138.5,89.56 138.33,89.73 138.09,89.73 137.98,89.62 134.12,89.62 133.35,88.85 132.37,88.85 131.31,89.9 RC420.2 130.93,90.71 130.93,91.76 v2(131.59,92.42)
N29258735: length 3.1
  TOP w0.107: v2(216.9,101.34) 218.46,101.34 218.7,101.58 CZ56.1 RZ63.1
N30493978: length 3.2
  TOP w0.107: v2(193.75,123.09) RZ1420.2 192.71,123.07 192.43,123.07 192.42,123.09 RZ1422.1 191.96,123.52 191.94,123.54 UZ35.1
N30494637: length 11.4
  TOP w0.102: 165.96,108.55 165.97,108.54 165.97,107.41 165.97,107.41 165.97,106.83 166.16,106.64 166.16,106.37 166.1,106.31 165.69,106.31 165.61,106.4 v1(165.61,106.55)
  TOP w0.254: 165.96,108.55 165.96,108.97 165.69,109.23 165.69,109.46 165.96,109.72 165.96,112.58 v2(165.18,113.36) 165.18,113.89 164.85,114.22 164.85,114.48 165.25,114.87 165.25,115.22 RC425.1
  BOTTOM w0.2: UC1.BE7 v1(165.61,106.55)
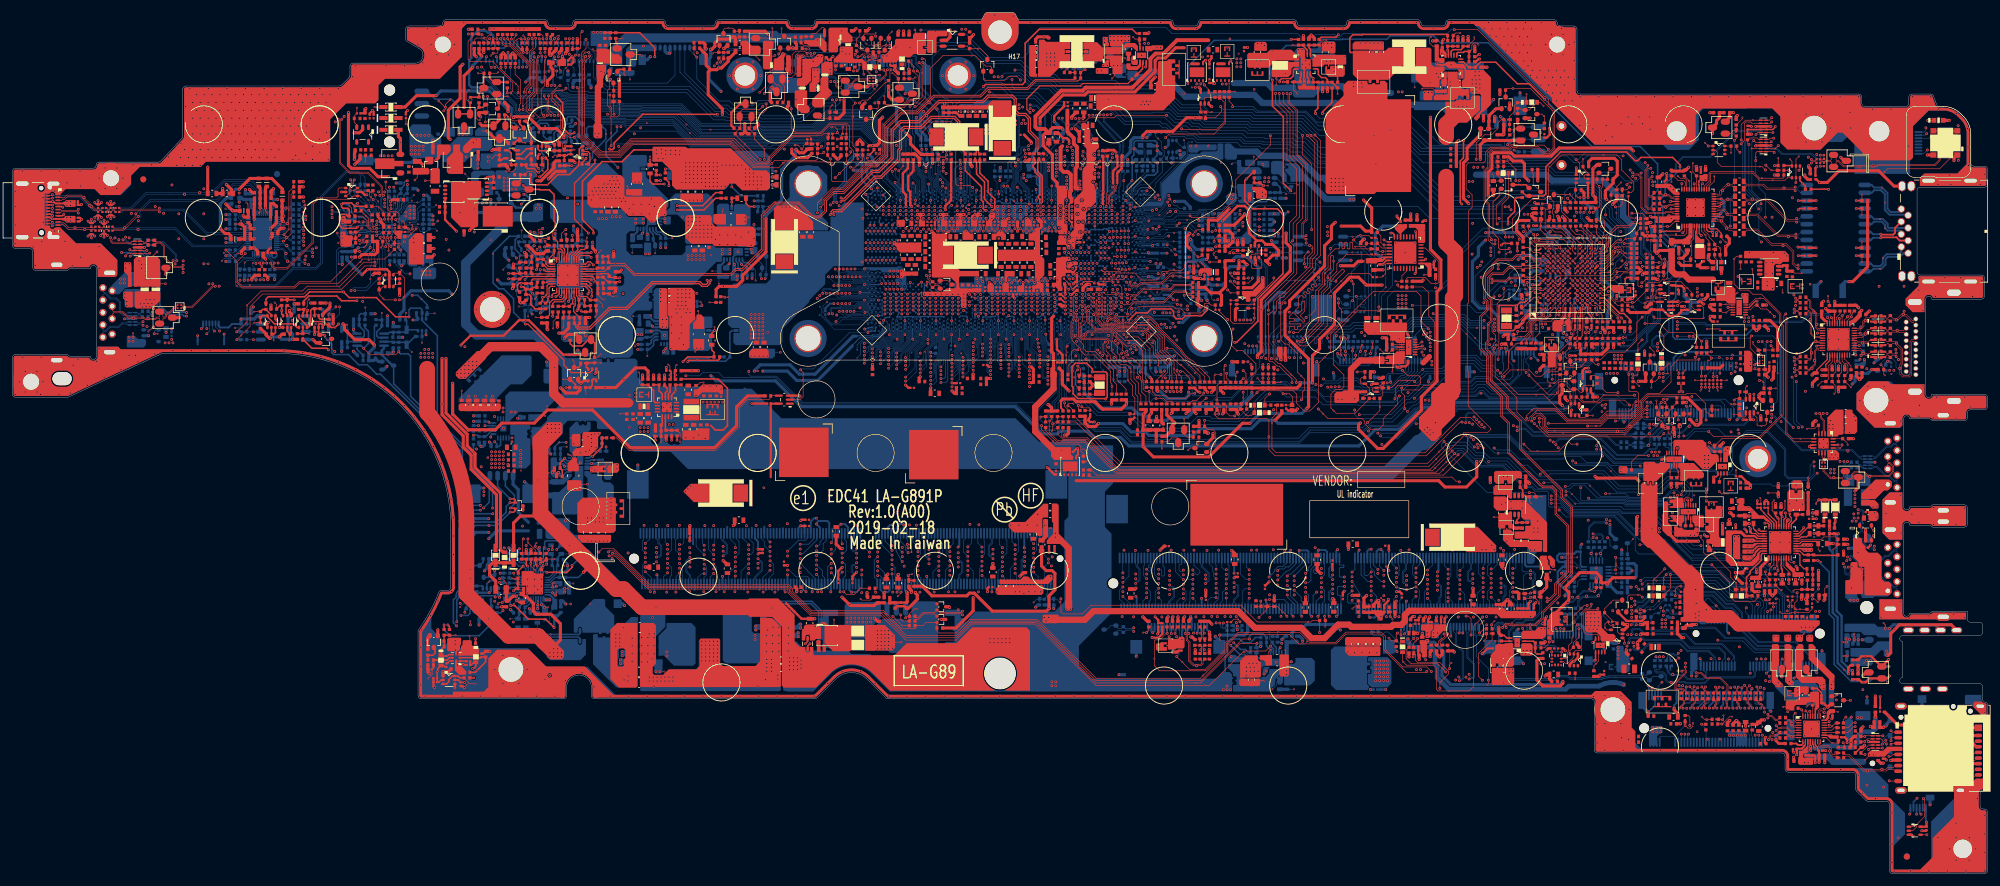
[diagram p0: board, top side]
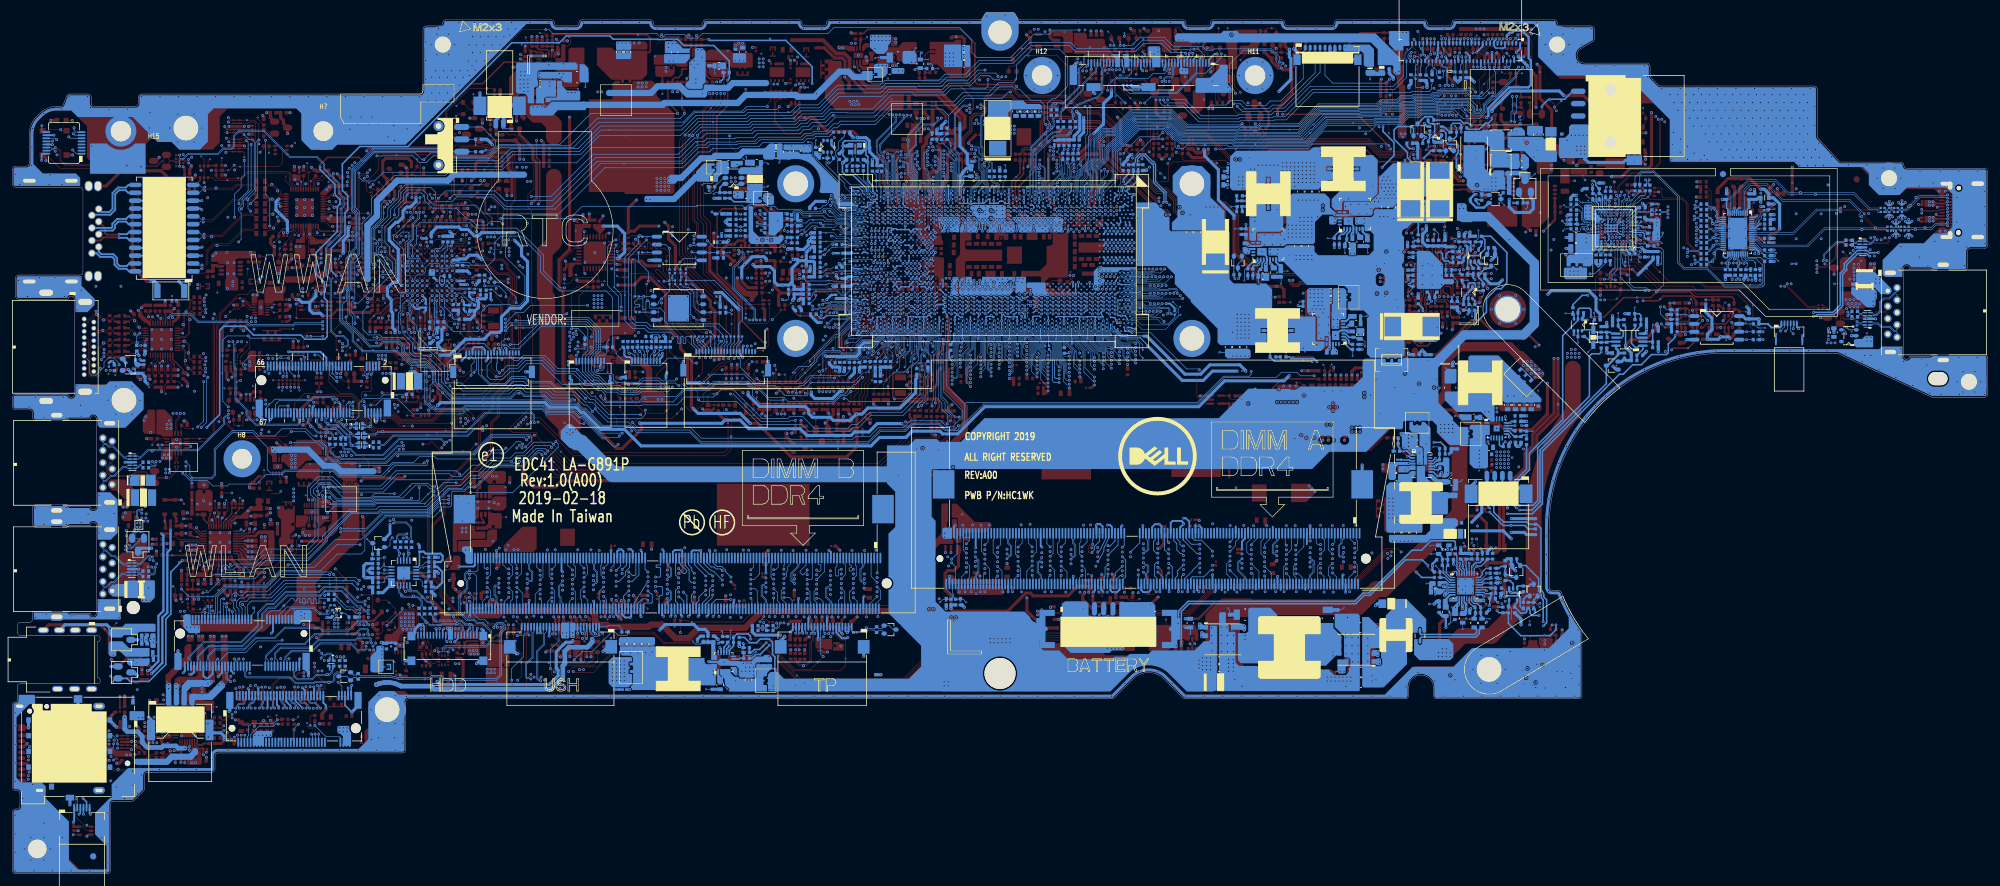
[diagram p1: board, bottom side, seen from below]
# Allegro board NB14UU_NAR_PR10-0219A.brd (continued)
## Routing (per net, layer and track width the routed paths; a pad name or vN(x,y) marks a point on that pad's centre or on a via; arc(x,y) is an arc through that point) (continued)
N30494639: length 10
  TOP w0.102: 166.34,108.49 166.16,108.31 166.16,106.92 v1(166.53,106.55)
  TOP w0.254: RC426.1 165.63,115.28 165.63,113.45 v2(166.34,112.74) 166.34,108.49
  BOTTOM w0.25: UC1.BG7 v1(166.53,106.55)
N30497274: length 1.6
  TOP w0.107: v2(193.14,95.16) CC77.1 RC845.2
N30498214: length 5.9
  TOP w0.107: CC340.1 190.8,71.4 RC432.2 190.74,71.34 RC433.1 190.72,70.54 189.73,70.54 189.27,71 QC7.2 v2(189.27,73.53)
N30498298: length 3.2
  TOP w0.107: v2(189.92,68.49) 190.22,68.78 QC6.1 191.65,69.43 RC433.2
N30686239: length 5.6
  TOP w0.107: RC848.2 v2(170.21,83.79) 170.21,85.11 v1(170.37,85.26)
  BOTTOM w0.076: UC1.BP36 170.59,87.71 170.52,87.63 170.52,86.21 170.31,86 170.31,85.32 v1(170.37,85.26)
N31121279: length 1.4
  TOP w0.102: T419.1 154.91,93.33 v1(154.6,93.64)
  BOTTOM w0.2: v1(154.6,93.64) UC1.AH26
N31601664: length 2.9
  TOP w0.107: v2(296.45,69.31) 296.45,69.52 295.66,70.3 RI14.2 295.63,70.29 UI3.16
N31759761: length 0.9
  TOP w0.107: CZ38.2 RZ334.1
N33426560: length 3.3
  TOP w0.107: CZ306.1 255.46,33.6 v2(255.74,33.89) 256.22,34.37 UZ53.6
N33565250: length 2.5
  TOP w0.254: CL16.1 v1(288.46,99.88)
  BOTTOM w0.254: TL1.3 v1(288.46,99.88)
N33565254: length 2.7
  TOP w0.254: CL17.1 289.42,101.28 v1(288.4,101.28)
  BOTTOM w0.254: v1(288.4,101.28) 288.53,101.15 TL1.4
N33565258: length 2.6
  TOP w0.254: v1(288.46,107.3) 288.66,107.5 CL20.1
  BOTTOM w0.254: v1(288.46,107.3) 288.66,107.5 TL1.9
N33565262: length 2.5
  TOP w0.254: CL21.1 v1(288.46,108.77)
  BOTTOM w0.254: TL1.10 v1(288.46,108.77)
N33905695: length 9.3
  TOP w0.107: v2(276.39,25.58) 276.39,25 v1(276.25,24.86) 276.17,24.94 RN129.1
  BOTTOM w0.107: JNGFF3.8 281.07,22.12 280.92,22.27 280.92,23.76 280.41,24.27 276.84,24.27 v1(276.25,24.86)
N34195811: length 4.3
  TOP w0.107: RE94.1 252.53,108.79 251.58,109.74 v2(250.9,109.74) QE12.1
N35066834: length 2.4
  TOP w0.107: UZ43.12 277.32,91.11 276.89,90.69 v2(276.83,90.69) 276.23,90.69 CZ109.1
N35066846: length 2.1
  TOP w0.107: CZ110.1 275.89,92 v2(276.82,92) 276.87,91.95 277.31,91.95 277.34,91.91 UZ43.10
N35067480: length 2.2
  TOP w0.107: CZ117.1 269.07,64.21 v2(269.07,64.92) 269.07,65.15 268.81,65.41 UZ47.12
N35067619: length 2.1
  TOP w0.107: CZ118.1 267.76,64.17 v2(267.76,64.92) 267.76,65.23 268.01,65.47 UZ47.10
N35854159: length 48.8
  TOP w0.254: v1(138.68,129.92) 138.68,130.14 138.92,130.38 DV11.1 ; v1(103.76,132.04) v2(103.76,133.48) 101.33,135.91 RV627.2 CV633.1 RV626.1
  IN1 w0.254: v1(103.76,132.04) 104.32,131.48 112.93,131.48 113.64,132.19 119.53,132.19 122.93,128.79 132.57,128.79 132.98,129.19 137.96,129.19 v1(138.68,129.92)
N35854165: length 4.4
  TOP w0.107: v2(145.87,128.7) 145.63,128.46 RV629.1 144.83,128.47 RV631.2 CV651.1 144.03,129.91 143.7,130.24 DV12.1
N35854175: length 6.5
  TOP w0.107: QV20.1 144.58,125.27 144.58,125.05 143.87,124.33 141.13,124.33 RV630.1 v2(140.85,125.68)
N35854186: length 2.9
  TOP w0.107: v2(142.13,129.37) 142.25,129.37 143.11,128.51 RV631.1 143.11,127.79 143.29,127.61 QV20.2
N35854224: length 4.4
  TOP w0.127: v2(101.66,132.19) 101.44,132.41 QV18.1
  TOP w0.254: QV18.1 99.78,131.17 99.7,131.1 RV625.1
N35854247: length 2.8
  TOP w0.127: RV627.1 v2(98.55,135)
  TOP w0.254: QV18.2 97.7,134.21 97.47,134.44 RV627.1
N35855171: length 3.2
  BOTTOM w0.107: v2(244.23,117.73) RC222.1 245.04,118.69 245.06,118.68 SW1.2
N36050903: length 2.1
  TOP w0.107: v2(277.6,116.51) RZ32.1 276.61,117.59 QZ7.6
N37069772: length 2.5
  TOP w0.107: CZ130.1 v2(239.5,37.6)
  TOP w0.254: CZ130.1 240.51,37.57 UZ23.6
N37090339: length 1.9
  TOP w0.508: v1(226.96,38.8) 226.88,38.87 LZ3.2
  BOTTOM w0.254: JUSH1.7 227.27,39.11 v1(226.96,38.8)
N37090359: length 1.7
  TOP w0.508: LZ4.2 v1(227.73,38.83)
  BOTTOM w0.254: v1(227.73,38.83) 227.78,38.88 JUSH1.8
N38439774: length 13.7
  BOTTOM w0.076: UC1.CR35 183.59,88.79 185.66,86.73 186.1,86.73 186.62,86.21
  BOTTOM w0.107: T423.1 192.02,81.98 190.37,81.98 189.45,82.89 189.45,83.37 186.62,86.21
N39469818: length 2
  BOTTOM w0.107: PC631.1 92.54,97.85 v2(92.54,98.6)
  BOTTOM w0.254: PR630.2 92.86,97.53 PC631.1
N39470129: length 1
  TOP w0.254: PR646.2 95.4,94.61 PC640.1
N39470145: length 2.2
  TOP w0.107: PC601.1 96.81,93.3 v2(97.43,93.3)
  TOP w0.254: PC601.1 96.34,93.77 PR652.2
N39470173: length 2.2
  TOP w0.107: v2(95.07,100.73) 94.43,100.09 PR641.1
  TOP w0.254: PC632.2 94.51,99.17 94.43,99.25 PR641.1
N39470189: length 4.2
  TOP w0.152: v1(171.13,130.88) 169.91,129.66 PH604.1
  BOTTOM w0.107: v2(169.48,130.12) PR642.2
  BOTTOM w0.152: PR642.2 170.42,130.63 170.67,130.88 v1(171.13,130.88)
N39685742: length 2.3
  TOP w0.107: RV737.1 295.22,90.51 294.64,89.93 294.64,89.56 294.75,89.44 UV21.36
N40311323: length 4.2
  TOP w0.107: RZ25.1 245.47,113.29 245.65,113.12 v2(245.65,112.57) 245.65,111.4 QZ3.1
N46814682: length 47.7
  TOP w0.254: PR610.1 84.78,97.75 v1(84.64,97.61)
  IN1 w0.254: v1(84.64,97.61) 84.64,98.18 86.48,100.02 88.11,100.02 88.13,100 91.72,100 92.71,99.01 107.8,99.01 108.18,98.63 113.09,98.63 113.5,99.03 120.16,99.03 120.65,99.51 120.65,104.66 120.39,104.91 v1(119.79,104.91)
  BOTTOM w0.107: PR631.2 v2(121.6,104.22)
  BOTTOM w0.254: PR631.2 PH601.2 v1(119.79,104.91)
N46814700: length 2
  TOP w0.107: PR632.2 84.73,93.24 v2(84.37,92.89)
  TOP w0.254: PR632.2 PC627.1
N46814728: length 1.9
  BOTTOM w0.107: PH602.1 v2(122.26,107.82)
  BOTTOM w0.254: PH602.1 121.22,107.52 121.29,107.44 PR628.2
N46814769: length 2
  TOP w0.107: v2(81.94,99.83) PC617.2
  TOP w0.254: PC617.2 PR621.1
N46815164: length 2.5
  TOP w0.107: PC621.2 83.92,100.07 v2(83.1,100.89)
  TOP w0.254: PR623.1 83.84,99.67 PC621.2
N46815188: length 2
  BOTTOM w0.107: PR617.1 v2(87.51,98.61)
  BOTTOM w0.254: PR617.1 87.51,96.75 PC614.2
N46816463: length 2
  BOTTOM w0.107: PR639.1 v2(89.26,92.14)
  BOTTOM w0.254: PC629.2 89.26,93.67 PR639.1
N46816511: length 32.7
  TOP w0.107: v1(111.37,91.81) 111.37,92.19 v2(111.12,92.44)
  TOP w0.254: PR635.1 v1(87.27,90.09)
  IN1 w0.254: v1(87.27,90.09) 87.94,90.76 87.94,91.89 89.78,93.74 91.24,93.74 91.73,94.22 95.47,94.22 96.2,94.94 100.16,94.94 100.55,95.33 110.09,95.33 111.37,94.05 v1(111.37,91.81)
  BOTTOM w0.254: PR647.2 PH603.2 111.27,91.7 v1(111.37,91.81)
N46816817: length 1.9
  TOP w0.107: v2(94.08,90.02) 94.33,90.27 PR644.1
  TOP w0.254: PR644.1 94.25,91.06 PC630.2
N46816821: length 0.7
  BOTTOM w0.254: PH605.1 PR657.2
N46816907: length 2.6
  TOP w0.107: v2(88.93,88.25) 88.97,88.29 PC639.2
  TOP w0.254: PR645.1 89.05,89.91 PC639.2
N48704005: length 3.7
  TOP w0.152: v1(172.21,132.66) 172.4,132.85 PL614.3
  BOTTOM w0.107: v2(171.15,131.58) PR624.1
  BOTTOM w0.152: PR624.1 172.4,132.47 v1(172.21,132.66)
N49204882: length 2.6
  TOP w0.107: v1(113.4,87.77) v2(113.4,88.35)
  TOP w0.254: PR661.1 112.96,87.33 v1(113.4,87.77)
  BOTTOM w0.254: PL612.3 v1(113.4,87.77)
N49223737: length 1.1
  BOTTOM w0.107: PC655.2 113.07,97.38 v2(113.06,97.39)

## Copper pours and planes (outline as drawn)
+0.6V_DDR_VTT on TOP (solid shape): 168.99,41.76 168.99,40.65 168.81,40.47 166.55,40.47 166.39,40.63 166.39,41.7 166.55,41.87 168.89,41.87
+0.6V_DDR_VTT on TOP (solid shape): 168.02,48.21 168.02,47.51 167.32,46.81 159.51,46.81 159.44,46.87 159.44,47.51 162.8,47.51 163.31,48.02 164.06,48.02 164.58,47.51 166.43,47.51 167.25,48.33 167.89,48.33
+0.6V_DDR_VTT on TOP (solid shape): 241.34,42.46 246.01,42.46 246.11,42.35 246.11,41.79 245.6,41.27 240.43,41.27 239.78,41.92 238.41,41.92 238.26,42.07 238.26,42.84 238.44,43.02 240.79,43.02
+0.6V_DDR_VTT on TOP (solid shape): 97.98,66.21 97.98,65.09 97.67,64.78 96.16,64.78 96.1,64.83 96.1,65.91 96.16,65.97 96.43,65.97 96.52,65.96 96.6,65.97 96.75,65.97 97.12,66.33 97.86,66.33
+0.6V_DDR_VTT on IN2 (solid shape): 99.12,66.24 99.12,65.23 99.02,65.13 97.46,65.13 97.32,65.27 97.32,66.25 97.41,66.33 99.03,66.33
+0.6V_DDR_VTT on IN2: 165.99,45.08 166.02,45.15 166.09,45.18 166.45,45.54 166.09,45.9 166.02,45.93 165.99,46 165.99,46.82 166.37,47.19 166.87,47.19 167.25,47.57 167.25,48.27 167.44,48.46 168.08,48.46 168.27,48.27 168.27,47.57 168.97,46.87 168.97,46.56 168.97,46.55 168.97,41.28 168.75,41.06 166.2,41.06 165.99,41.27
+0.6VSP on TOP (solid shape): 95.96,65.92 95.96,65.63 95.42,65.63 95.42,65.2 95.96,65.2 95.96,64.93 95.87,64.84 93.41,64.84 93.3,64.95 93.3,65.68 93.48,65.86 93.78,65.86 93.88,65.95 95.93,65.95
+0.6VSP on BOTTOM (solid shape): 93.38,65.9 95.08,65.9 95.12,65.86 95.12,64.91 95.05,64.84 93.7,64.84 93.3,65.24 92.44,65.24 92.39,65.29 92.39,65.9 92.44,65.95 93.33,65.95
+0.9V_LAN on TOP (solid shape): 273.46,101.56 273.46,99.39 273.42,99.35 271.89,99.35 271.72,99.52 271.72,101.53 271.86,101.68 273.35,101.68
+0.9V_LAN on TOP (solid shape): 269.31,110.05 269.31,109.79 269.22,109.7 268.35,109.7 267.24,110.81 265.41,110.81 265.38,110.84 265.38,111.46 265.4,111.47 266.64,111.47 266.69,111.52 267.83,111.52
+0.9V_LAN on TOP (solid shape): 267.87,106.37 269.24,106.37 269.29,106.32 269.29,105.77 269.23,105.71 268.4,105.71 267.85,105.16 265.99,105.16 265.94,105.21 265.94,106.17 265.98,106.21 267.14,106.21 267.36,106.43 267.37,106.43 267.47,106.54 267.71,106.54
+0.9V_LAN on BOTTOM: 270.39,100.97 270.38,100.98 269.87,100.98 266.95,103.9 266.95,109.2 267.33,109.58 267.33,111.24 267.4,111.31 268.71,111.31 268.82,111.2 268.82,105.76 268.9,105.68 268.9,104.76 269.56,104.09 272.24,104.09 273.53,102.8 273.53,101.11 273.39,100.97
+1.0V_AMPHYPLL on TOP (solid shape): 172.13,111.18 172.28,111.06 172.46,111.03 172.54,111.03 172.65,110.92 172.65,110.6 172.48,110.42 171.64,110.42 171.4,110.66 171.4,111.12 171.53,111.25 172.06,111.25
+1.0V_AMPHYPLL on TOP: 170.2,123.66 170.1,123.56 170.1,123.25 170.23,123.12 170.68,123.12 171.34,123.79 173.5,123.79 173.91,123.38 174.67,123.38 174.81,123.52 174.81,125.89 174.76,125.94 173.86,125.94 173.39,125.47 170.54,125.47 170.2,125.13
+1.0V_APLL on TOP (solid shape): outline of 619 points within 170.43,100.91 175.51,121.4
+1.0V_APLL on BOTTOM: 172.78,103.06 172.84,103 172.84,102.61 172.49,102.26 172.13,102.26 171.76,102.62 171.5,102.62 171.44,102.56 171.44,102.23 171.56,102.12 171.56,101.81 171.44,101.69 171.44,101.45 171.53,101.35 171.53,101 171.44,100.9 171.17,100.9 170.96,101.11 170.96,101.3 170.35,101.91 170.35,102.11 170.13,102.33 170.13,102.53 170.35,102.75 170.35,102.94 170.86,103.45 171.06,103.45 171.15,103.36 171.45,103.36 171.5,103.42 172.03,103.42 172.38,103.06
+1.0V_CLK on BOTTOM (solid shape): 195.6,117.93 195.6,115.56 195.45,115.41 193.82,115.41 193.74,115.33 193.71,115.34 193.19,115.46 192.65,115.51 192.52,115.52 189.28,113.87 188.7,110.28 188.71,110.24 188.47,110 186.63,110 186.41,109.78 186.41,109.27 185.98,108.84 185.98,108.25 185.55,107.83 182.79,107.83 182.63,107.77 182.52,107.77 182.41,107.88 182.41,108.07 182.47,108.12 183,108.12 183.48,108.61 185.16,108.61 185.17,108.62 185.31,108.62 185.33,108.62 185.59,108.78 185.59,109.09 185.58,109.11 185.58,111.42 185.58,111.43 185.58,111.58 189.3,115.3 189.3,115.4 189.94,116.04 189.94,116.29 189.99,116.34 191.77,116.34 192.15,116.72 193.99,116.72 194.03,116.76 194.47,116.76 194.65,116.94 194.65,117.92 194.71,117.98 195.55,117.98
+1.0V_MPHYGT on TOP (solid shape): 187.85,131.54 187.85,130.98 187.83,130.96 187.33,130.96 187.29,130.92 187.29,130.22 187.29,130.22 187.84,130.22 187.84,130.22 187.84,129.77 187.83,129.76 187.3,129.76 187.29,129.76 187.29,129.03 187.3,129.02 187.83,129.02 187.84,129.02 187.84,128.42 187.83,128.41 187.83,126.87 187.81,126.85 187.81,125.25 185.93,123.37 175.31,123.37 175.08,123.59 175.08,125.89 175.15,125.97 184.28,125.97 184.7,126.38 184.7,127.84 185.05,128.19 185.05,131.17 185.23,131.35 186.46,131.35 186.73,131.62 187.78,131.62
+1.0V_MPHYGT on BOTTOM: 172.76,103.32 172.76,103.17 172.86,103.07 172.86,102.61 172.77,102.53 172.77,102.28 172.82,102.23 174.28,102.23 174.37,102.33 174.37,103.31 174.27,103.41 174.04,103.41 173.98,103.35 173.7,103.35 173.54,103.51 173.54,103.77 173.36,103.95 173.07,103.95 172.85,103.73 172.85,103.41
+1.0V_MPHYGT on IN2: 177.09,121.67 171.54,121.67 171.32,121.46 171.32,105.74 171.35,105.71 171.35,105.01 171.7,104.66 171.7,101.74 172.65,100.78 180.34,100.78 181.1,101.55 181.1,113.8 183.75,116.45 183.75,117.87 187.77,121.89 187.77,124.61 187.18,125.2 180.62,125.2
+1.0V_PRIM on TOP (solid shape): 225.94,110.16 215.94,110.16 215.94,125.16 225.94,125.16
+1.0V_PRIM on TOP (solid shape): 172.1,98.81 172.1,98.43 172,98.33 171.41,98.33 171.35,98.33 171.12,98.1 171.05,98.05 170.99,97.97 170.82,97.8 170.45,97.8 170.4,97.85 170.4,98.82 170.44,98.87 171.15,98.87 171.23,98.94 171.96,98.94
+1.0V_PRIM on TOP (solid shape): 218.88,127.58 220.91,127.58 220.91,128.15 221.67,128.15 222.12,127.71 222.12,111.96 219.99,109.83 216.24,109.83 216.24,109.83 212.41,109.83 212.11,110.12 212.11,122.85 215.01,125.74 215.01,127.45 215.7,128.15 218.88,128.15
+1.0V_PRIM on BOTTOM (solid shape): 197.79,116.96 197.79,115.67 197.52,115.4 196.13,115.4 195.82,115.7 195.82,117.87 195.93,117.98 196.77,117.98
+1.0V_PRIM on BOTTOM (solid shape): 213.27,112.49 213.27,111.6 213.16,111.49 212.02,111.49 211.63,111.89 211.63,112.81 211.77,112.95 212.8,112.95
+1.0V_PRIM on TOP: 196.65,130.44 197.29,131.07 197.29,131.71 197.61,132.03 198.69,132.03 198.88,131.84 198.88,129.01 198.59,128.72 195.64,128.72 195.38,128.47 195.38,128.02 195.26,127.89 194.26,127.89 193.98,128.18 192.93,128.18 192.49,128.62 191.48,128.62 191.25,128.4 191.25,128.1 190.83,127.68 190.83,124.19 187.1,120.46 177.59,120.46 175.42,118.29 174.38,118.29 174.26,118.41 174.26,120.35 174.07,120.53 174.07,121.5 174.19,121.61 186.18,121.61 187.98,123.42 187.98,129.16 187.97,129.17 187.44,129.17 187.44,129.17 187.44,129.62 187.44,129.62 187.98,129.62 187.99,129.63 187.99,130.36 187.98,130.37 187.44,130.37 187.44,130.37 187.44,130.82 187.44,130.82 187.98,130.82 187.99,130.83 187.99,131.54 188.14,131.69 189.02,131.69 190.27,130.44
+1.0V_PRIM on BOTTOM: 171.23,100.55 172.12,100.55 172.5,100.17 172.5,97.94 171.74,97.18 170.21,97.18 170.09,97.31 170.09,98.77 170.21,98.9 170.97,98.9 171.1,99.02 171.1,100.42
+1.0V_PRIM on BOTTOM: 173.71,100.91 173.69,100.93 173.46,100.93 173.39,100.86 173.39,100.64 173.53,100.5 173.53,100.13 173.38,99.98 173.38,99.02 173.62,98.78 173.62,98.48 174.04,98.05 174.31,98.05 174.41,98.16 174.41,98.32 174.2,98.53 174.2,98.74 173.98,98.96 173.98,100 174.11,100.13 174.44,100.13 174.47,100.16 174.47,100.78 174.34,100.91
+1.0V_PRIM on VCC: 178.47,96.85 177.71,97.61 176.04,97.61 175.66,97.23 170.49,97.23 170.49,103.35 171.33,104.18 171.33,122.66 171.89,123.22 171.89,123.52 211.15,123.52 215.2,119.48 215.2,106.88 187.28,106.88 182.43,102.03 182.43,97.97 181.31,96.85
+1.0V_PRIM on IN2: 217.75,129.41 218.26,128.9 218.26,125.5 217.29,124.53 202.36,124.53 200.21,126.69 199.95,126.69 197.48,129.16 197.48,132.34 197.8,132.66 199.89,132.66 200.18,132.38 200.18,131.04 201.81,129.41 213.25,129.41 213.48,129.32 213.72,129.41
+1.0V_PRIM_CORE on TOP: 173.1,102.94 173.1,102.56 171.76,101.23 171.76,97.69 172.24,97.21 172.24,96.67 172.5,96.42 175.1,96.42 175.36,96.67 175.36,97.46 175.95,98.05 180.48,98.05 183.58,101.16 183.99,101.56 183.99,103.66 186.15,105.82 186.15,108.91 186.41,109.17 186.41,109.84 191.45,114.88 196.4,114.88 202.37,120.85 202.37,129.87 202.18,130.06 201.8,130.06 201.8,129.49 200.4,129.49 200.4,130.06 199.64,130.06 199.13,129.55 199.13,123.45 194.88,119.2 187.74,119.2 181.77,113.23 181.77,112.23 177.96,108.42 177.96,107.3 177.67,107.01 173.79,107.01 173.54,106.75 173.54,103.39
+1.0V_PRIM_CORE on BOTTOM: 172.87,101.84 172.29,101.84 172.07,101.62 172.07,101.2 172.28,101 172.37,101 172.94,100.43 172.94,100.17 172.75,99.98 172.75,98.98 172.91,98.82 172.91,98.48 172.76,98.33 172.76,98.08 172.92,97.93 172.92,97.65 172.75,97.48 172.42,97.48 172.34,97.56 172.2,97.56 172.07,97.44 172.07,97.27 172.26,97.08 172.26,96.87 172.44,96.69 174.01,96.69 174.14,96.82 174.14,97.07 173.99,97.22 173.99,97.55 174.09,97.65 174.32,97.65 174.44,97.53 174.71,97.53 175.27,98.09 175.27,98.35 175.45,98.52 175.45,98.73 175.24,98.93 175.24,99.97 175.46,100.19 175.46,100.45 175.34,100.57 175.34,100.81 175.45,100.92 175.64,100.92 175.69,100.87 175.98,100.87 176.1,100.99 176.1,101.32 175.92,101.49 175.92,101.56 175.87,101.61 175.7,101.61 175.58,101.73 175.4,101.73 174.6,100.94 174.6,99.07 174.81,98.86 174.81,98.43 174.69,98.31 174.58,98.31 174.28,98 173.96,98 173.51,98.46 173.51,98.8 173.33,98.99 173.33,100.01 173.47,100.15 173.47,100.47 173.33,100.61 173.33,101.37
+1.0V_PRIM_CORE on BOTTOM: 176.09,102.94 175.9,103.13 175.87,103.15 175.58,103.44 174.64,103.44 174.57,103.37 174.57,102.82 174.72,102.68 174.81,102.68 174.87,102.68 174.93,102.67 175.03,102.67 175.43,102.26 175.63,102.26 175.9,102.53 175.9,102.54 176.09,102.73
+1.0V_PRIM_COREP on TOP (solid shape): 207.82,131.94 207.82,131.51 207.75,131.43 204.06,131.43 202.88,130.25 199.64,130.25 199.45,130.44 199.45,132.41 199.7,132.66 202.62,132.66 203.15,133.18 206.58,133.18
+1.0V_PRIM_COREP on BOTTOM (solid shape): 202.69,132.47 202.69,131.26 202.5,131.07 200.66,131.07 200.53,131.2 200.53,132.41 200.72,132.6 202.56,132.6
+1.0V_PRIM_XDP on TOP (solid shape): 89.06,132.26 89.06,132.06 89.08,131.98 89.09,131.97 89.09,131.84 89.23,131.7 89.36,131.7 89.43,131.63 89.43,130.58 89.36,130.52 88.09,130.52 88.06,130.55 88.06,131.54 88.09,131.57 88.42,131.57 88.59,131.74 88.59,132.26 88.69,132.35 88.97,132.35
+1.0V_PRIM_XDP on BOTTOM: 89.27,131.7 89.32,131.65 89.32,130.98 89.4,130.9 89.4,130.29 88.88,129.77 88.88,129.3 88.81,129.23 88.31,129.23 88.24,129.29 88.24,129.82 88.79,130.36 88.79,130.83 88.79,130.9 88.88,130.99 88.88,131.66 88.91,131.7
+1.0V_VCCST on TOP (solid shape): outline of 285 points within 168.71,103.32 170.53,111.2
+1.0V_VCCST on TOP: 193.09,134.14 192.84,134.39 192.84,135.18 192.97,135.32 198.22,135.32 198.54,135 198.54,133.56 198.43,133.45 197.5,133.45 196.72,132.66 194.14,132.66 193.95,132.85 193.95,133.88 193.7,134.14
+1.0V_VCCST on IN1: 169.66,103.75 170.07,104.16 170.07,104.16 170.26,104.35 175.11,104.35 175.4,104.65 177.09,104.65 177.12,104.68 182.36,104.68 182.48,104.56 182.48,104.15 182.31,103.99 177.47,103.99 177.47,103.96 175.77,103.96 175.41,103.61 175.41,102.94 175.04,102.56 170.42,102.56 169.66,103.32
+1.0V_VCCST_C on TOP: 194.51,130.62 195.91,130.62 196.04,130.75 196.04,131.21 196.6,131.77 197.16,131.77 197.54,132.15 198.46,132.15 198.48,132.17 199.05,132.17 199.25,132.37 199.25,133.14 199.17,133.23 197.48,133.23 196.78,132.52 195.08,132.52 195.08,132.52 194.45,132.52 194.22,132.29 194.22,130.91
+1.0V_VCCST_R on TOP: 167.01,118.67 169.23,118.67 169.36,118.55 169.92,118.55 170,118.47 170,117.43 169.86,117.28 169.5,117.28 169.24,117.54 169.24,117.71 169,117.95 167,117.95 166.94,118.01 166.94,118.61
+1.0V_VCCSTG on TOP: 132.24,118.31 134.17,118.31 134.23,118.25 134.23,116.91 134.11,116.79 132.33,116.79 132.18,116.94 132.18,118.25
+1.0V_VCCSTG on TOP: 191.08,132.5 191.06,132.52 191.06,133.03 191.04,133.05 190.63,133.05 190.6,133.02 190.6,132.51 190.59,132.5 188.9,132.5 188.58,132.82 188.58,133.61 188.78,133.82 193.47,133.82 193.63,133.65 193.63,132.76 193.37,132.5
+1.0V_VCCSTG_C on TOP: 190.17,132.36 190.74,132.36 190.75,132.36 190.75,132.91 190.75,132.91 190.93,132.91 190.93,132.91 190.93,132.38 190.95,132.36 193.29,132.36 193.35,132.29 193.35,131.96 193.19,131.8 192.53,131.8 191.83,131.1 191.83,130.77 191.67,130.61 190.23,130.61 190.07,130.77 190.07,132.25
+1.0VS_VCCIO on BOTTOM (solid shape): 156.92,96.41 156.92,95.82 157.12,95.62 157.12,95.43 157.04,95.35 157.04,93.88 156.93,93.76 156.76,93.76 156.76,93.76 156.54,93.98 156.29,93.98 156.08,93.78 155.85,93.78 155.7,94 155.69,94.02 155.48,94.02 155.32,94.18 155.32,96.43 155.35,96.46 156.87,96.46
+1.0VS_VCCIO on BOTTOM (solid shape): outline of 185 points within 166.2,93.39 167.61,96.46
+1.0VS_VCCIO on TOP: 153.28,96.42 156.5,96.42 157.11,95.81 157.11,95.43 156.6,94.93 156.6,94.83 156.54,94.77 155.11,94.77 155.11,94.77 153.2,94.77 153.03,94.94 153.03,96.17
+1.0VS_VCCIO on TOP: 166.17,95.7 166.3,95.58 166.62,95.58 166.66,95.54 166.66,93.96 166.57,93.88 166.34,93.88 166.21,93.75 166.21,93.5 166.34,93.37 167.48,93.37 167.61,93.5 167.61,93.76 167.48,93.89 167.48,95.92 166.87,96.53 166.62,96.53 166.17,96.09
+1.0VS_VCCIO on TOP: 111.36,77.47 114.05,77.47 114.21,77.32 114.71,77.32 114.99,77.04 114.99,75.77 114.58,75.35 111.6,75.35 111.31,75.64 111.31,77.42
+1.0VS_VCCIO on TOP: 170.09,100.18 169.63,100.18 169.39,99.93 168.74,99.93 168.74,101.28 170.21,101.28 170.21,100.31
+1.0VS_VCCIO on IN1: 149.16,98.63 146.05,101.74 128.14,101.74 120.58,94.18 116.39,94.18 115.5,93.29 115.5,86.69 109.41,80.59 109.41,76.27 110.14,75.54 114.71,75.54 116.58,77.42 116.58,81.54 119.18,84.15 120.65,84.15 122.11,85.61 122.11,89.23 128.2,95.32 137.09,95.32 138.36,94.05 156.65,94.05 156.94,94.34 156.94,96.82 155.13,98.63
+1.0VS_VCCIO on IN2: 167.43,95.9 167.43,95.66 167.57,95.52 167.57,93.67 167.44,93.55 166.24,93.55 166.17,93.61 166.17,96.28 166.37,96.47 167.06,96.47 167.21,96.32 167.21,96.12
+1.0VS_VCCIO on IN3: 166.3,97.1 167.64,95.77 167.64,93.49 167.5,93.35 156.01,93.35 155.45,93.91 155.45,96.85 155.7,97.1
+1.2V_DDRP on TOP (solid shape): 97.47,60.65 97.47,55.45 97.09,55.06 91.68,55.06 91.24,55.5 91.24,59.89 92.13,60.78 97.34,60.78
+1.2V_DDRP on BOTTOM (solid shape): 93.59,64.59 95.18,64.59 95.25,64.53 95.25,63.64 95.63,63.26 96.58,63.26 97.15,62.68 97.15,55.45 96.83,55.13 91.37,55.13 91.31,55.19 91.31,56.65 92.9,58.24 92.9,63.89 92.39,64.4 92.39,64.97 92.48,65.06 93.12,65.06
+1.2V_MEM on TOP (solid shape): 131.85,64.1 123.85,64.1 123.85,72.1 131.85,72.1
+1.2V_MEM on TOP (solid shape): 152.83,63.71 144.83,63.71 144.83,71.71 152.83,71.71
+1.2V_MEM on TOP (solid shape): 205.27,53.01 190.27,53.01 190.27,63.01 205.27,63.01
+1.2V_MEM on TOP: outline of 124 points within 97.66,40.6 241.79,91.44 ; 1 cut-out
+1.2V_RUN on TOP (solid shape): 298.98,91.13 298.98,90.97 298.72,90.71 298.72,90.04 297.7,89.01 297.43,89.01 296.87,88.45 296.71,88.45 296.65,88.5 296.65,89.3 296.69,89.33 296.85,89.33 297.07,89.55 297.22,89.55 297.97,90.3 298.06,90.4 298.06,90.74 298.61,91.29 298.83,91.29
+1.2V_RUN on IN1 (solid shape): 37.14,111.95 37.14,109.88 36.94,109.67 35.95,109.67 35.75,109.88 35.75,111.95 35.95,112.15 36.94,112.15
+1.2V_RUN on IN2 (solid shape): 299.44,90.7 299.44,90.43 299.02,90.02 298.89,90.02 298.23,90.68 298.23,90.9 298.62,91.3 298.84,91.3
+1.2V_RUN on TOP: 36.46,109.7 36.91,109.7 37.12,109.9 37.12,110.79 36.91,111 36.46,111 36.25,110.79 36.25,109.9
+1.2V_RUN on TOP: 289.97,94.31 288.43,94.31 288.32,94.42 288.32,95.92 288.8,96.4 290.61,96.4 291.98,95.03 291.98,92.53 291.8,92.35 291.8,91.49 291.96,91.34 292.37,91.34 292.57,91.15 292.57,90.66 292.53,90.62 292.06,90.62 290.97,91.72 290.97,93.32
+1.2V_RUN on TOP: 296.27,84.27 296.79,84.27 298.38,82.69 299.65,82.69 299.88,82.46 299.88,81.58 299.65,81.35 297.56,81.35 297.43,81.48 297.43,81.86 296.2,83.09 296.2,84.21
+1.2V_RUN on BOTTOM: 36.46,109.7 36.91,109.7 37.12,109.9 37.12,110.79 37.04,110.87 36.33,110.87 36.25,110.79 36.25,109.9
+1.2V_RUN on IN1: 287.85,94.37 289.16,94.37 289.36,94.57 289.36,95.57 289.16,95.77 287.85,95.77 287.65,95.57 287.65,94.57
+1.2V_RUN on IN2: 288.36,93.42 289.16,93.42 289.36,93.62 289.36,95.29 289.2,95.45 288.36,95.45 288.16,95.25 288.16,93.62
+1.05VALWP on TOP (solid shape): 224.64,133.39 224.64,130.67 222.27,128.3 220.75,128.3 220.73,128.28 220.73,127.77 220.72,127.76 220.27,127.76 220.26,127.77 220.26,128.3 220.26,128.31 219.53,128.31 219.53,128.3 219.53,127.77 219.52,127.76 219.07,127.76 219.06,127.77 219.06,128.3 219.05,128.31 217.37,128.31 216.52,129.16 216.52,132.97 216.57,133.02 221.79,133.02 222.28,133.51 224.52,133.51
+1.05VALWP on BOTTOM (solid shape): 221.55,132.92 221.55,131.71 221.48,131.65 219.26,131.65 219.07,131.84 219.07,132.85 219.26,133.04 221.42,133.04
+1.8V_ALW_VTR3 on TOP (solid shape): 260.33,94.88 260.33,94.44 260.35,94.41 260.86,94.41 260.87,94.4 260.87,94.22 260.86,94.21 260.31,94.21 260.31,94.21 260.31,93.8 260.27,93.76 259.48,93.76 259.36,93.89 258.9,93.89 258.9,93.89 258.75,93.89 258.1,94.54 258.1,94.98 258.24,95.12 260.08,95.12
+1.8V_ALW_VTR3 on IN2 (solid shape): 259.56,94.88 259.56,92.31 259.37,92.12 258.86,92.12 258.03,92.95 258.03,93 258.81,93 258.81,92.95 258.82,92.9 258.83,92.85 258.86,92.8 258.89,92.76 258.92,92.72 258.97,92.69 259.01,92.67 259.06,92.65 259.11,92.64 259.16,92.64 259.22,92.65 259.27,92.67 259.31,92.69 259.35,92.72 259.39,92.76 259.42,92.8 259.45,92.85 259.46,92.9 259.47,92.95 259.47,93 259.46,93.05 259.45,93.1 259.42,93.15 259.39,93.19 259.35,93.23 259.31,93.26 259.27,93.28 259.22,93.3 259.16,93.3 259.11,93.3 259.06,93.3 259.01,93.28 258.97,93.26 258.92,93.23 258.89,93.19 258.86,93.15 258.83,93.1 258.82,93.05 258.81,93 258.03,93 258.03,93.88 258.05,93.9 258.09,93.94 258.11,93.99 258.13,94.04 258.14,94.09 258.14,94.14 258.13,94.2 258.11,94.25 258.09,94.3 258.05,94.34 258.03,94.36 258.03,95.04 258.14,95.15 259.29,95.15
+1.8V_PRIM on TOP (solid shape): 260.92,65.66 260.92,64.88 260.71,64.68 259.6,64.68 259.44,64.83 259.44,65.68 259.62,65.86 260.71,65.86
+1.8V_PRIM on TOP (solid shape): 277.74,68.97 277.74,68.08 277.11,67.45 277.11,66.56 277.05,66.49 276.41,66.49 276.35,66.56 276.35,68.68 276.76,69.09 277.62,69.09
+1.8V_PRIM on BOTTOM (solid shape): 277.3,68.91 277.3,68.27 277.05,68.02 275.52,68.02 275.27,68.27 275.27,68.91 275.39,69.03 277.17,69.03
+1.8V_PRIM on BOTTOM (solid shape): 197.8,109.71 197.8,108.66 197.67,108.66 197.1,108.09 196.21,108.09 196.02,108.28 196.02,109.48 196.57,110.03 196.57,110.03 197.47,110.03
+1.8V_PRIM on TOP: 183,96.18 183.6,96.18 184.91,97.48 188.25,97.48 188.78,98.02 188.85,98.09 188.85,100.45 188.82,100.49 188.82,104.14 190.86,106.18 194.5,106.18 197.44,109.13 197.44,109.81 197.16,110.09 195.61,110.09 193.8,108.28 188,108.28 186.77,107.05 186.77,105.49 185.01,103.72 185.01,101.69 184.31,100.99 183.78,100.99 182.43,99.64 182.43,96.75
+1.8V_PRIM on TOP: 260.47,94.86 261,94.86 261.2,95.06 261.2,95.24 261.47,95.51 262.3,95.51 262.39,95.42 262.39,93.9 262.38,93.89 261.6,93.89 261.48,93.76 260.49,93.76 260.45,93.8 260.45,94.06 260.47,94.08 261,94.08 261.01,94.09 261.01,94.53 261,94.55 260.46,94.55 260.45,94.55 260.45,94.84
+1.8V_PRIM on TOP: 258.21,41.86 259.65,41.86 259.77,41.98 259.77,43.13 259.65,43.25 258.28,43.25 258.07,43.04 258.07,42
+1.8V_PRIM on BOTTOM: 176,101.46 176.2,101.25 176.2,101.04 176.74,100.49 176.76,100.49 176.79,100.46 176.79,100.12 176.66,99.98 176.36,99.98 176.25,100.09 176.06,100.09 175.98,100.01 175.98,99.85 176.22,99.6 176.22,99.34 176.01,99.13 176.01,98.98 176.13,98.85 176.91,98.85 177.43,99.38 177.43,101.27 176.96,101.74 176.54,101.74 176.52,101.72 176.08,101.72 176,101.64
+1.8V_PRIM on BOTTOM: 261.17,96.19 261.17,94.49 261.38,94.29 262.17,94.29 262.33,94.46 262.33,96.35 262.29,96.4 261.38,96.4
+1.8V_PRIM on BOTTOM: 259.71,65.8 260.92,65.8 261.35,65.36 261.35,64.65 261.23,64.53 259.77,64.53 259.59,64.71 259.59,65.68
+1.8V_PRIM on BOTTOM: 236.15,113.49 236.91,113.49 237.03,113.38 237.03,112.53 236.93,112.43 236.64,112.43 236.16,111.96 236.16,111.71 236,111.55 234.9,111.55 234.86,111.59 234.86,112.2
+1.8V_PRIM on IN1: 177.39,101.15 177.31,101.33 177.13,101.41 176.48,101.41 176.31,101.33 176.23,101.15 176.23,100.74 176.28,100.66 176.37,100.65 176.84,100.31 176.37,99.98 176.28,99.97 176.23,99.88 176.23,99.48 176.31,99.3 176.49,99.22 177.13,99.22 177.31,99.3 177.39,99.48
+1.8V_PRIM on IN1: 259.86,66.78 260.03,66.62 260.03,64.21 259.87,64.05 259.17,64.05 259.01,64.21 259.01,66.62 259.17,66.78
+1.8V_PRIM on IN2: 233.96,112.28 236.05,112.28 236.23,112.1 236.23,111.5 235.99,111.26 233.83,111.26 233.77,111.33 233.77,112.09
+1.8V_PRIM on IN2: 196.44,110.27 198.81,110.27 198.91,110.17 198.91,108.66 198.9,108.65 196.42,108.65 196.24,108.83 196.24,110.07
+1.8V_PRIM on IN2: 272.01,95.15 274.5,95.15 274.72,94.93 274.72,93.76 274.56,93.6 272.01,93.6 271.86,93.75 271.86,94.99
+1.8V_PRIM on IN2: 276.56,70.46 277.82,70.46 278.1,70.18 278.1,68.15 277.61,67.66 276.33,67.66 275.91,68.08 275.91,69.81
+1.8V_PRIM on IN3: outline of 111 points within 176.02,96.02 184.02,101.48
+1.8V_PRIM on IN3: 270.85,95.81 272.12,95.81 272.38,95.56 272.38,93.87 272.24,93.73 270.88,93.73 270.68,93.94 270.68,95.64
+1.8V_PRIM on IN3: 261.62,95.46 264.03,95.46 264.22,95.26 264.22,93.63 264.06,93.47 262.02,93.47 261.47,94.03 261.47,95.3
+1.8V_RUN on TOP: 278.06,59.75 278.06,60.7 279.46,62.1 279.46,63.47 279.41,63.52 278.76,63.52 278.72,63.48 278.72,62.74 278.32,62.33 277.65,62.33 277.65,62.34 277.65,62.89 277.64,62.89 277.46,62.89 277.46,62.89 277.46,62.33 277.46,62.33 276.97,62.33 276.88,62.24 276.88,59.74 276.94,59.68 277.99,59.68
+1.8V_RUN_AUDIO on TOP (solid shape): 279.64,60.6 279.64,59.59 279.84,59.38 280.67,59.38 282.13,57.92 282.91,57.92 283.96,56.88 283.96,56.79 283.93,56.76 283.78,56.76 283.65,56.89 283.33,56.89 282.87,57.35 280.92,57.35 280.92,58.18 280.47,58.62 278.7,58.62 278.6,58.72 278.6,59.44 278.82,59.66 278.82,60.67 278.89,60.73 279.51,60.73
+1.8V_RUN_CARD on TOP: 302.57,26.36 300.6,26.36 300.54,26.3 300.54,25.16 300.67,25.03 301.05,25.03 301.24,25.22 301.24,25.6 301.43,25.79 302.51,25.79 302.76,26.05 302.76,26.17
+1.8V_RUN_UZ46 on TOP: 277,62.48 276.35,63.13 276.35,65.02 276.43,65.1 277.69,65.1 277.78,65.01 278.07,65.01 278.6,64.47 278.6,63.92 278.36,63.68 278.36,62.73 278.11,62.48 277.8,62.48 277.79,62.48 277.79,63.02 277.78,63.03 277.35,63.03 277.32,63.01 277.32,62.49 277.31,62.48
+1.8VALWP on BOTTOM (solid shape): 200.34,110.18 200.53,109.99 200.53,108.53 200.38,108.38 198.19,108.38 197.97,108.6 197.97,108.92 197.98,108.93 198.53,108.93 198.53,108.93 198.53,109.4 198.52,109.41 197.98,109.41 197.97,109.41 197.97,109.77 197.91,109.82 197.91,110.39 197.86,110.44 197.86,111.45 200.34,111.45
+1VS_VCCIOP on TOP: 106.9,74.76 107.74,74.76 108.26,74.24 111.06,74.24 111.47,74.65 114.07,74.65 114.36,74.37 114.36,72.21 108.14,72.21 106.83,73.52 106.83,74.69
+2.5V_MEM on TOP (solid shape): 171.19,44.02 171.19,42.62 171.06,42.49 170.18,42.49 170.05,42.62 170.05,44.02 170.24,44.21 171,44.21
+2.5V_MEM on TOP (solid shape): 169.02,59.56 169.02,54.95 169.86,54.11 169.86,53.73 169.41,53.29 167.13,53.29 167.06,53.35 167.06,53.86 168.11,54.9 168.11,56.69 167.89,56.91 167.89,59.71 168.03,59.84 168.74,59.84
+2.5V_MEM on TOP (solid shape): 242.4,55.21 242.4,54.06 242.53,53.94 244.82,53.94 244.99,53.77 247.06,53.77 247.11,53.72 247.11,52.14 247,52.03 245.14,52.03 244.94,52.22 244.94,52.48 244.84,52.58 244.79,52.65 244.72,52.7 244.63,52.79 241.88,52.79 240.76,53.92 240.76,55.52 240.84,55.61 242,55.61
+2.5V_MEM on BOTTOM (solid shape): 168.84,55.7 168.84,54.38 168.59,54.13 167.41,54.13 167.28,54.25 167.28,55.84 167.35,55.91 168.64,55.91
+2.5V_MEM on BOTTOM (solid shape): 246.43,52.64 246.43,52.11 245.9,51.58 245.9,50.39 245.58,50.07 244.82,50.07 244.67,50.22 244.67,52.48 245.08,52.89 246.18,52.89
+2.5V_MEM on IN2 (solid shape): 171.92,43.17 171.92,42.59 171.8,42.48 170.16,42.48 170.07,42.57 170.07,43.05 170.29,43.27 171.81,43.27
+2.5V_MEM on IN2 (solid shape): 246.12,52.4 246.12,51.7 245.36,50.94 244.79,50.94 244.41,51.32 244.41,51.51 244.98,52.08 244.98,52.4 245.17,52.59 245.93,52.59
+3.3V_ALW on TOP (solid shape): 243.84,64.78 243.84,63.89 243.01,63.89 242.12,63 241.49,63 241.49,63.57 240.91,63.57 240.91,63 239.71,63 239.33,63.38 239.33,64.84 239.58,65.1 243.52,65.1
+3.3V_ALW on TOP (solid shape): 280.42,93.72 280.42,92.21 280.37,92.16 279.6,92.16 279.52,92.24 279.52,93.03 279.24,93.31 279.24,93.7 279.39,93.85 280.3,93.85
+3.3V_ALW on TOP (solid shape): 212.34,129.99 212.85,129.99 212.85,130.57 215.11,130.57 215.22,130.45 215.22,129.08 214.94,128.79 212.59,128.79 212.09,129.3 212.09,130.57 212.34,130.57
+3.3V_ALW on TOP (solid shape): 231.22,133.72 231.22,133.13 231.65,132.7 231.65,131.9 231.58,131.84 231.45,131.84 231.22,132.07 230.86,132.07 230.56,132.37 230.56,133.23 230.69,133.36 230.69,133.74 230.75,133.8 231.14,133.8
+3.3V_ALW on TOP (solid shape): 231.71,40.14 231.71,39.43 231.46,39.18 231.07,39.18 229.97,38.08 229.4,38.08 229.26,38.22 229.26,39.12 229.66,39.52 229.66,40.19 229.78,40.31 231.54,40.31
+3.3V_ALW on TOP (solid shape): 256.6,42.43 256.6,41.79 256.73,41.67 256.73,39.76 257.74,38.75 258.63,38.75 258.95,38.43 258.95,37.69 258.74,37.49 256.77,37.49 256.5,37.76 256.5,38.37 255.89,38.98 254.39,38.98 254,39.38 254,42.11 254.38,42.49 256.54,42.49
+3.3V_ALW on TOP (solid shape): 248.37,85.74 248.37,85.22 248.4,85.19 248.83,85.19 248.84,85.2 248.84,85.75 248.84,85.75 249.21,85.75 249.34,85.61 249.34,85.61 249.56,85.39 249.56,84.25 249.31,84 249.31,81.98 249.14,81.81 248.03,81.81 247.99,81.86 247.99,84.25 248.25,84.53 248.11,84.88 248.08,84.91 248.08,85.74 248.1,85.76 248.35,85.76
+3.3V_ALW on BOTTOM (solid shape): 216.97,109.29 216.97,108.72 216.78,108.53 214.5,108.53 214.31,108.72 214.31,109.29 214.56,109.55 216.72,109.55
+3.3V_ALW on BOTTOM (solid shape): 230.43,40.5 230.43,38.16 230.27,38 229.23,38 229.1,38.13 229.1,40.49 229.19,40.58 230.35,40.58
+3.3V_ALW on BOTTOM (solid shape): 222.75,34.36 222.75,30.74 222.12,30.11 219.51,30.11 218.94,30.68 218.94,32.27 219.51,32.27 219.51,34.3 218.94,34.3 218.94,34.81 219.13,35 222.12,35
+3.3V_ALW on BOTTOM (solid shape): 208.62,113.49 208.62,112.1 208.36,111.83 206.45,111.83 206.44,111.85 206.44,112.65 206.12,112.97 206.12,112.98 205.54,113.55 205.54,113.93 206.12,113.93 206.12,114.44 205.54,114.44 205.54,114.69 205.67,114.82 207.29,114.82
+3.3V_ALW on TOP: 262.13,102.12 262.32,102.12 262.53,102.33 262.53,102.7 262.72,102.88 264.09,102.88 264.31,102.66 264.31,98.48 264.27,98.45 262.14,98.45 262.1,98.48 262.1,102.09
+3.3V_ALW on TOP: 251.37,107.89 251.93,107.89 252.01,107.81 252.01,107.14 252.9,106.26 252.9,105.27 252.81,105.18 252.26,105.18 252.22,105.21 252.22,105.79 252.1,105.91 252.09,105.91 251.99,106.01 251.64,106.01 251.32,106.33 251.32,107.85
+3.3V_ALW on TOP: 267.77,67.76 267.77,68.72 267.01,69.48 265.04,69.48 264.52,68.95 264.52,67.87 265.06,67.32 266.63,67.32 266.95,67.64 267.65,67.64
+3.3V_ALW on TOP: 279.63,88.87 279.52,88.98 279.52,90.79 279.58,90.86 281.83,90.86 281.84,90.85 283.33,90.85 283.76,90.41 283.76,89.2 283.66,89.09 280.92,89.09 280.69,88.87
+3.3V_ALW on TOP: 152.78,135.36 152.67,135.46 152.67,136.79 152.71,136.83 154.98,136.83 154.99,136.81 154.99,135.85 154.93,135.79 154.5,135.79 154.07,135.36
+3.3V_ALW on TOP: 226.18,84.4 227.52,84.4 227.71,84.59 227.71,85.67 227.58,85.8 226.63,85.8 226.56,85.74 226.31,85.74 226.18,85.86 226.18,87.2 228.02,89.04 229.2,89.04 229.61,88.63 229.61,81.77 228.95,81.11 226.68,81.11 226.18,81.6
+3.3V_ALW on BOTTOM: 220.8,87.06 220.8,85.76 220.75,85.71 216.29,85.71 216.24,85.76 216.24,86.94 217.09,87.79 220.06,87.79
+3.3V_ALW on IN1: 153.04,136.63 153.22,136.81 154.6,136.81 154.98,136.43 154.98,135.25 157.82,132.42 161.1,132.42 165.51,136.83 186.33,136.83 187.33,135.83 191.78,135.83 192.74,136.79 204.34,136.79 205.29,135.84 205.29,135.83 205.32,135.8 214.17,135.8 214.47,135.49 214.47,129.69 214.15,129.37 212.33,129.37 212.08,129.63 212.08,130.98 209.96,133.1 205.43,133.1 203.43,135.1 194.12,135.1 193.46,134.45 186.27,134.45 185.69,135.03 182.32,135.03 181.77,135.58 167.17,135.58 162.73,131.14 156.71,131.14 153.04,134.81
+3.3V_ALW on VCC: outline of 86 points within 32.82,38.17 281.87,130.76
+3.3V_ALW on IN3: 255.31,29.39 255.17,29.41 255.03,29.42 219.63,29.42 219.51,29.54 219.51,34.11 220.91,35.51 225.99,35.51 228.37,37.88 228.84,37.88 229.23,38.27 229.23,39.06 229.35,39.19 232.37,39.19 232.69,38.87 247.71,38.87 251.52,42.68 255.46,42.68 256.79,41.35 256.79,30.87
+3.3V_ALW_PCH on TOP (solid shape): 218.86,78.03 218.86,77.8 218.67,77.61 218.26,77.61 217.61,77.61 217.52,77.53 217.52,76.47 217.1,76.05 213.68,76.05 213.51,76.23 213.51,77.51 213.88,77.88 214.77,77.88 215.02,78.13 218.76,78.13
+3.3V_ALW_PCH on TOP (solid shape): 221.64,83.5 221.64,83.05 221.65,83.04 222.19,83.04 222.2,83.03 222.2,82.85 222.19,82.84 221.65,82.84 221.64,82.83 221.64,82.44 221.55,82.35 219.98,82.35 219.91,82.43 219.91,83.53 220,83.61 221.53,83.61
+3.3V_ALW_PCH on TOP (solid shape): 205.18,85.02 205.18,82.85 205.14,82.82 204.74,82.82 204.58,82.98 204.58,83.12 204.53,83.43 204.25,83.58 204.25,85.12 204.3,85.17 205.03,85.17
+3.3V_ALW_PCH on TOP (solid shape): 202.29,96.39 202.29,94.73 200.83,93.27 200.32,93.27 200.3,93.25 200.06,93.25 199.93,93.13 199.93,93.03 200,92.95 200,92.59 199.85,92.43 199.84,92.43 199.82,92.42 199.36,92.42 199.22,92.56 199.22,92.94 198.59,93.57 198.59,94.16 198.61,94.18 200.34,94.18 201.65,95.49 201.65,96.44 201.76,96.56 202.13,96.56
+3.3V_ALW_PCH on BOTTOM (solid shape): outline of 103 points within 194.48,101.76 200.15,107.9
+3.3V_ALW_PCH on TOP: 194.29,97.81 194.91,97.81 195.1,97.63 195.1,94.84 194.94,94.69 194.43,94.69 194.3,94.82 194.3,95.65 194.4,95.75 194.4,96.44 194.21,96.63 194.21,97.73
+3.3V_ALW_PCH on BOTTOM: 176.21,97.55 175.41,97.55 175.35,97.49 175.35,96.2 175.68,95.87 177.24,95.87 177.4,96.03 177.4,97.07 176.95,97.52 176.24,97.52
+3.3V_ALW_PCH on VCC: 185.33,73.99 184.7,74.62 182.79,74.62 181.77,75.64 178.98,75.64 174.05,80.57 174.05,93.02 171.87,95.2 170.49,95.2 170.49,96.72 175.87,96.72 176.25,97.1 177.5,97.1 178.26,96.34 181.52,96.34 182.94,97.76 182.94,101.82 187.49,106.37 215.2,106.37 215.2,76.13 213.06,73.99
+3.3V_ALW_PCH_U44 on TOP (solid shape): 224.93,84.38 224.93,83.22 224.82,83.12 224.82,82.47 224.7,82.34 221.88,82.34 221.78,82.44 221.78,82.7 221.79,82.7 222.33,82.7 222.34,82.71 222.34,83.16 222.32,83.18 221.78,83.18 221.77,83.19 221.77,83.48 222.06,83.77 222.94,83.77 223.59,84.41 224.1,84.41 224.13,84.44 224.87,84.44
+3.3V_ALW_UE1 on BOTTOM (solid shape): 251.81,97.52 251.81,96.68 251.77,96.63 250.88,96.63 250.79,96.72 250.79,97.58 250.94,97.73 251.6,97.73
+3.3V_ALW_UE1 on TOP: 248.4,88.4 248.46,88.34 248.46,87.84 249.15,87.15 249.15,85.93 249.11,85.89 248.69,85.89 248.69,85.89 248.69,85.34 248.69,85.34 248.51,85.34 248.51,85.34 248.51,85.89 248.5,85.9 248,85.9 247.22,86.68 247.22,87.86 247.76,88.4
+3.3V_ALW_UZ12 on TOP (solid shape): 229.23,98.59 229.23,96.47 229.18,96.42 229.14,96.42 229.03,96.44 228.91,96.42 228.74,96.42 228.63,96.54 228.6,96.62 228.56,96.68 228.56,97.96 228.07,98.45 227.15,98.45 227.07,98.53 227.07,98.69 227.14,98.76 229.05,98.76
+3.3V_ALWP on TOP (solid shape): 220.98,36.59 220.98,35.32 220.85,35.19 215.9,35.19 215.26,35.82 215.26,36.65 215.32,36.71 220.85,36.71
+3.3V_ALWP on BOTTOM (solid shape): 220.91,36.65 220.91,35.7 220.47,35.25 219.15,35.25 218.81,34.91 218.81,34.13 218.83,34.11 219.34,34.11 219.36,34.1 219.36,33.67 219.34,33.65 218.82,33.65 218.79,33.62 218.79,32.93 218.81,32.92 219.33,32.92 219.34,32.91 219.34,32.46 219.32,32.44 218.83,32.44 218.81,32.41 218.81,31.66 218.82,31.66 218.82,30.63 219.13,30.31 219.13,30.04 219.01,29.87 219,29.66 213.8,29.66 212.97,30.49 212.97,36.14 213.55,36.71 220.85,36.71
+3.3V_CAM on TOP (solid shape): 130.99,132.3 130.99,131.37 129.92,130.3 129.18,130.3 129.01,130.13 129.01,128.13 128.21,127.33 126.87,127.33 126.72,127.48 126.72,128.36 126.96,128.6 127.41,128.6 127.6,128.79 127.6,131.64 127.66,131.69 129.33,131.69 130.09,132.45 130.84,132.45
+3.3V_CAM on BOTTOM (solid shape): 130.98,132.21 130.98,131.76 130.9,131.68 130.9,130.42 130.84,130.36 130.71,130.36 130.63,130.43 130.63,131.67 130.46,131.84 130,131.84 129.88,131.97 129.88,132.17 129.98,132.28 130.92,132.28
+3.3V_CAM_F on TOP (solid shape): 128.38,126.49 128.38,124.27 128.79,123.86 128.79,123.24 128.44,122.9 127.45,122.9 126.36,123.99 126.36,126.44 126.53,126.61 128.26,126.61
+3.3V_EC_PLL on TOP (solid shape): 251.03,91.52 251.03,89.92 250.57,89.47 250.57,88.83 250.35,88.62 250.35,87.65 250.31,87.61 249,87.61 248.74,87.87 248.74,89.11 249.12,89.48 249.94,89.48 250.68,90.22 250.68,91.49 250.78,91.59 250.96,91.59
+3.3V_HDD on TOP (solid shape): 250.5,42.17 250.5,41.79 249.93,41.79 249.93,40.4 250.5,40.4 250.5,40.08 250.44,40.02 249.23,40.02 248.98,39.76 248.98,38.68 248.85,38.55 248.15,38.55 247.9,38.81 247.9,40.7 247.94,40.74 247.94,40.95 248.2,41.22 248.2,41.72 248.85,42.36 250.31,42.36
+3.3V_HDD on BOTTOM (solid shape): 258.35,47.66 258.35,46.22 258.29,46.17 257.41,46.17 257.29,46.28 257.29,47.67 257.36,47.74 258.27,47.74
+3.3V_HDD on BOTTOM (solid shape): 248.98,39.76 248.98,39.57 248.69,39.29 248.69,37.81 248.67,37.78 248.44,37.78 248.26,37.83 248.07,37.78 247.97,37.78 247.88,37.86 247.88,39.18 247.89,39.19 247.89,39.6 247.89,39.75 247.99,39.86 248.88,39.86
+3.3V_HDD_M2 on BOTTOM (solid shape): 280.22,22.43 280.22,20.67 278.44,20.67 278.4,20.71 278.4,21.99 278.27,22.13 277.2,22.13 277.07,22.26 277.07,22.95 277.2,23.08 279.57,23.08
+3.3V_HDD_M2 on BOTTOM (solid shape): 266.57,23.69 266.57,22.87 266.29,22.59 266.06,22.59 265.64,22.18 265.64,21.04 265.74,20.94 265.74,20.67 264.35,20.67 264.35,22.78 264.59,23.22 264.6,23.73 264.6,23.76 264.73,23.89 266.38,23.89
+3.3V_HDD_M2 on TOP: 264.14,24.58 264.53,24.2 264.53,22.85 264.22,22.54 262.44,22.54 262.33,22.43 262.33,20.9 262.52,20.71 282.67,20.71 282.77,20.81 282.77,22.08 282.91,22.21 282.91,22.98 282.82,23.06 282.82,23.31 282.63,23.51 269.23,23.51 269.09,23.37 268.44,23.37 268.35,23.47 268.35,25.79 267.99,26.15 267.99,27.44 264.82,27.44 264.73,27.53 264.73,35.57 265.25,36.09 265.25,37.37 264.96,37.67 263.69,37.67 263.18,37.16 263.18,36.47 262.19,35.48 261.78,35.48 261.21,34.91 261.21,34.06 261.24,34.03 261.24,29.47 261.87,28.84 261.87,25.21 262.49,24.58
+3.3V_HDD_M2 on BOTTOM: 282.93,22.3 282.76,22.13 282.76,20.67 281.94,20.67 281.9,20.71 281.9,21.94 281.71,22.13 281.4,22.13 281.25,22.28 281.25,22.72 281.41,22.88 281.42,22.88 281.51,22.97 282.73,22.97 282.93,22.77
+3.3V_LAN on TOP (solid shape): 268.51,101.03 268.51,99.55 268.51,99.55 267.53,99.55 267.49,99.58 267.49,100.98 267.56,101.05 268.49,101.05
+3.3V_LAN on TOP: 275.43,94.48 275.43,94.49 275.43,95.02 275.42,95.03 274.87,95.03 274.83,95.07 274.82,95.07 274.12,95.77 274.12,96.21 274.49,96.58 277.75,96.58 277.9,96.42 277.9,95.13 277.82,95.04 275.63,95.04 275.62,95.03 275.62,94.49 275.61,94.48
+3.3V_LAN_OUT on TOP (solid shape): 273.82,113.01 273.82,112.08 273.64,111.9 272.78,111.9 272.52,112.16 272.52,112.88 272.53,112.89 273.02,112.89 273.19,113.07 273.76,113.07
+3.3V_LAN_OUT on TOP (solid shape): 271.39,105.01 271.39,104.13 271.39,104.13 271.39,102.81 271.08,102.5 271.08,101.8 270.95,101.67 269.73,101.67 269.58,101.81 268.57,101.81 268.49,101.74 267.61,101.74 267.53,101.82 267.53,102.46 267.6,102.53 269.78,102.53 269.92,102.67 270.12,102.67 270.72,103.26 270.72,105.01 270.79,105.08 271.32,105.08
+3.3V_LAN_UZ43 on TOP (solid shape): 275.29,94.89 275.29,94.37 275.32,94.34 275.76,94.34 275.76,94.35 275.76,94.89 275.77,94.9 277.89,94.9 278.33,94.46 278.33,92.19 278.28,92.15 277.13,92.15 276.71,92.57 275.24,92.57 275.22,92.59 275.22,93.77 274.9,94.09 274.9,94.86 274.95,94.91 275.28,94.91
+3.3V_MMI_AUX on TOP (solid shape): 291.85,29.22 291.85,26.85 291.34,26.34 291.34,25.06 291.25,24.97 291.14,24.97 291.07,25.05 291.07,26.79 291.21,26.92 291.21,27.55 291.07,27.69 290.04,27.69 289.61,27.26 288.11,27.26 287.83,26.98 287.83,26.39 287.79,26.35 287.07,26.35 286.83,26.52 286.54,26.45 286.44,26.55 286.44,27.79 286.62,27.97 288.06,27.97 288.57,28.48 290.19,28.48 290.22,28.51 290.3,28.6 290.3,29.21 290.5,29.41 291.67,29.41
+3.3V_MMI_IN on TOP (solid shape): 290.16,30.16 290.16,29.25 290.12,29.21 289.02,29.21 288.33,28.52 287.88,28.52 287.79,28.61 287.79,29.01 287.76,29.04 287.26,29.04 287.23,29.07 287.23,29.25 287.25,29.27 287.77,29.27 287.79,29.3 287.79,29.91 288.15,30.27 290.06,30.27
+3.3V_MMI_IN on TOP (solid shape): 290.12,21.73 290.12,19.75 290.12,19.75 289.81,19.44 289.36,19.44 289.24,19.31 289.24,18.87 289.36,18.74 290.88,18.74 290.9,18.72 290.9,18.1 290.85,17.93 290.89,17.75 290.73,17.59 288.65,17.59 288.44,17.8 288.44,18.77 288.56,18.89 288.56,19.82 288.63,19.9 289.16,19.9 289.4,20.14 289.41,20.14 289.89,20.62 289.89,21.73 289.93,21.77 290.08,21.77
+3.3V_MMI_IN on IN2 (solid shape): 290.12,19.6 290.12,18.73 290.27,18.58 290.4,18.58 290.51,18.47 290.51,17.8 290.35,17.64 289.18,17.64 288.82,17.99 288.82,19.59 288.88,19.64 290.08,19.64
+3.3V_MMI_IN on IN2 (solid shape): 289.11,29.92 289.11,29.16 288.86,28.9 287.71,28.9 287.21,28.39 286.57,28.39 286.19,28.78 286.19,29.28 287.07,30.17 288.86,30.17
+3.3V_RUN on TOP (solid shape): 131.9,131.17 132.42,131.17 132.51,131.09 132.51,129.14 132.41,129.04 130.83,129.04 130.66,129.21 130.66,130.74 131.14,131.22 131.85,131.22
+3.3V_RUN on TOP (solid shape): 186.49,37.34 186.49,37.06 185.97,37.06 185.97,36.62 186.49,36.62 186.49,36.08 186.43,36.01 184.91,36.01 184.72,36.21 184.72,37.12 184.79,37.2 185.35,37.2 185.56,37.4 186.43,37.4
+3.3V_RUN on TOP (solid shape): 228.86,37.8 228.86,37.48 228.48,37.1 228.48,35.05 228.36,34.94 227.79,34.94 227.7,35.02 227.7,35.55 227.44,35.81 227.44,36.99 227.31,37.12 227.31,37.69 227.34,37.72 228.11,37.72 228.32,37.92 228.74,37.92
+3.3V_RUN on TOP (solid shape): 269.93,60.59 269.93,59.95 270,59.89 270,59.19 269.93,59.13 267.65,59.13 267.65,59.38 268.22,59.38 268.22,59.89 267.65,59.89 267.65,60.4 267.72,60.47 268.49,60.47 268.79,60.78 269.74,60.78
+3.3V_RUN on BOTTOM (solid shape): 196.91,106.88 196.91,103.23 196.81,103.14 195.85,103.14 194.55,104.44 194.55,106.91 194.6,106.96 196.83,106.96
+3.3V_RUN on BOTTOM (solid shape): 189.58,116.2 188.93,115.55 188.93,115.43 188.9,115.4 188.51,115.4 188.46,115.46 188.46,115.93 188.35,116.04 188.35,116.37 188.45,116.47 188.76,116.47 189.03,116.74 189.58,116.74
+3.3V_RUN on TOP: 264.98,35.6 265.49,36.1 265.49,37.53 264.69,38.33 264.69,41.08 264.87,41.27 267.58,41.27 267.86,40.98 268.28,40.98 268.37,40.9 268.37,38.39 269.13,37.63 271.37,37.63 272.75,36.25 275.69,36.25 279.16,32.78 282.95,32.78 283.74,31.99 283.74,30.89 284.69,29.95 287.51,29.95 287.68,29.78 287.68,29.4 287.1,29.4 287.1,28.91 287.68,28.91 287.68,28.64 287.53,28.48 284.06,28.48 281.56,30.98 277.27,30.98 276.32,31.93 274.45,31.93 273.61,32.77 269.99,32.77 268.32,31.1 268.32,27.96 267.98,27.62 265.03,27.62 264.98,27.67
+3.3V_RUN on TOP: 278.43,96.84 278.51,96.91 279.65,96.91 279.74,96.82 279.74,95.8 280.28,95.8 280.28,95.64 279.74,95.64 279.74,95.18 279.63,95.07 278.65,95.07 278.43,95.28
+3.3V_RUN on TOP: 249.36,30.68 249.23,30.81 249.23,32.65 249.4,32.81 249.4,34.07 249.11,34.36 249.11,34.78 248.99,34.9 248.99,35.92 248.8,36.11 248.8,37.41 250.69,39.3 250.69,43.89 252.09,45.29 256.98,45.29 259.08,47.38 261.93,47.38 263.08,46.24 263.08,45.79 262.82,45.54 262.31,45.54 261.93,45.16 258.95,45.16 257.04,43.25 254.03,43.25 252.09,41.31 252.09,38.62 250.49,37.02 250.26,37.02 249.93,36.69 249.93,35.61 249.85,35.52 249.85,34.14 250.07,33.92 250.61,33.92 250.88,33.65 250.88,32.87 250.98,32.78 251.79,32.78 251.85,32.71 251.85,30.76 251.77,30.68
+3.3V_RUN on TOP: 224.62,89.22 224.62,89.22 224.62,89.76 224.61,89.77 223.88,89.77 223.87,89.76 223.87,89.22 223.87,89.22 223.42,89.22 223.42,89.22 223.42,89.76 223.41,89.77 222.67,89.77 222.67,89.76 222.67,89.22 222.67,89.22 222.12,89.22 222.12,89.23 218.44,89.23 218.21,89.46 218.21,90.32 218.4,90.51 221.26,90.51 221.95,91.2 221.95,93.56 222.26,93.86 225.3,93.86 225.52,93.65 225.52,89.45 225.29,89.22
+3.3V_RUN on BOTTOM: 228.59,82.56 228.33,82.3 227.43,82.3 227.32,82.42 227.32,83.67 227.3,83.69 227.3,83.77 227.1,83.97 227.1,84.39 227.31,84.6 227.71,84.6 228.59,83.72
+3.3V_RUN on VCC: outline of 158 points within 24.47,38.17 294.83,138.03
+3.3V_RUN_AUDIO on TOP (solid shape): 267.46,56.72 268.03,56.14 268.03,54.62 267.97,54.56 267.39,54.56 266.5,55.45 266.5,58.05 266.63,58.18 266.63,59.95 266.82,60.14 267.46,60.14
+3.3V_RUN_AUDIO_DVDD on TOP (solid shape): 283.83,51.43 283.83,50.61 282.63,49.41 282.63,48.19 282.48,48.03 282.48,47.48 282.44,47.44 282.18,47.44 282,47.5 281.81,47.44 280.73,47.44 280.67,47.51 280.67,48.02 280.79,48.14 281.94,48.14 282.06,48.27 282.06,49.54 283.4,50.87 283.4,51.25 283.59,51.44 283.82,51.44
+3.3V_RUN_AUDIO_IO on TOP (solid shape): 286.63,51.38 286.63,50.43 287.74,49.32 287.9,49.32 287.97,49.26 287.97,48.84 288.09,48.71 289.24,48.71 289.36,48.59 289.36,48.08 289.24,47.95 287.59,47.95 287.52,48.02 287.52,48.65 286.41,49.77 286.41,51.37 286.48,51.45 286.57,51.45
+3.3V_RUN_AUDIO_UZ5 on TOP (solid shape): 270.04,57.81 270.04,56.92 269.68,56.56 269.68,56.11 269.32,56.11 268.51,56.92 267.65,56.92 267.65,57.15 268.21,57.15 268.21,57.68 267.65,57.68 267.65,57.91 269.93,57.91
+3.3V_RUN_CARD on TOP (solid shape): 305.3,20.37 305.3,19.93 305.17,19.8 303.36,19.8 302.46,18.9 299.88,18.9 299.69,19.1 299.69,19.45 300.02,19.78 300.07,19.83 300.11,19.89 302.19,19.89 302.83,20.52 302.83,20.52 305.14,20.52
+3.3V_RUN_CARD on BOTTOM: 299.06,19.85 300.71,19.85 301.19,19.37 301.19,18.05 300.52,17.37 298.73,17.37 298.45,17.65 298.45,19.24
+3.3V_RUN_CARD on BOTTOM: 289.18,21.03 290.48,21.03 290.75,20.75 290.75,19.5 290.6,19.35 289.16,19.35 289,19.51 289,20.85
+3.3V_RUN_DIMM1 on TOP (solid shape): 167.29,57.2 167.29,54.42 166.75,53.87 166.75,53.53 165.73,53.53 165.73,54.18 165.79,54.24 166.17,54.24 166.49,54.56 166.49,57.21 166.61,57.32 167.16,57.32
+3.3V_RUN_DIMM2 on TOP (solid shape): 247.88,51.3 247.88,50.85 248.08,50.65 248.08,49.96 248.33,49.7 248.33,49.14 248.28,49.08 247.37,49.08 246.81,49.08 246.67,49.22 246.67,51.18 246.9,51.41 247.77,51.41
+3.3V_RUN_F on TOP (solid shape): 131.82,128.62 131.82,126.96 132.37,126.41 132.37,125.99 131.25,124.87 131.25,124.31 130.77,123.82 129.55,123.82 129.19,124.18 129.19,125.14 130.53,126.48 130.53,128.55 130.73,128.76 131.69,128.76
+3.3V_RUN_QZ1 on TOP (solid shape): 130.4,130.03 130.4,128.01 129.77,127.38 129.77,126.39 129.73,126.35 128.97,126.35 128.97,126.35 128.77,126.35 128.72,126.39 128.72,127.62 129.14,128.04 129.14,130.06 129.24,130.16 130.27,130.16
+3.3V_RUN_QZ1 on BOTTOM (solid shape): 130.44,131.6 130.44,130.29 130.59,130.13 130.59,129.38 130.41,129.21 129.19,129.21 129.08,129.32 129.08,130.08 129.19,130.19 129.93,130.19 130.13,130.4 130.13,131.6 130.23,131.7 130.33,131.7
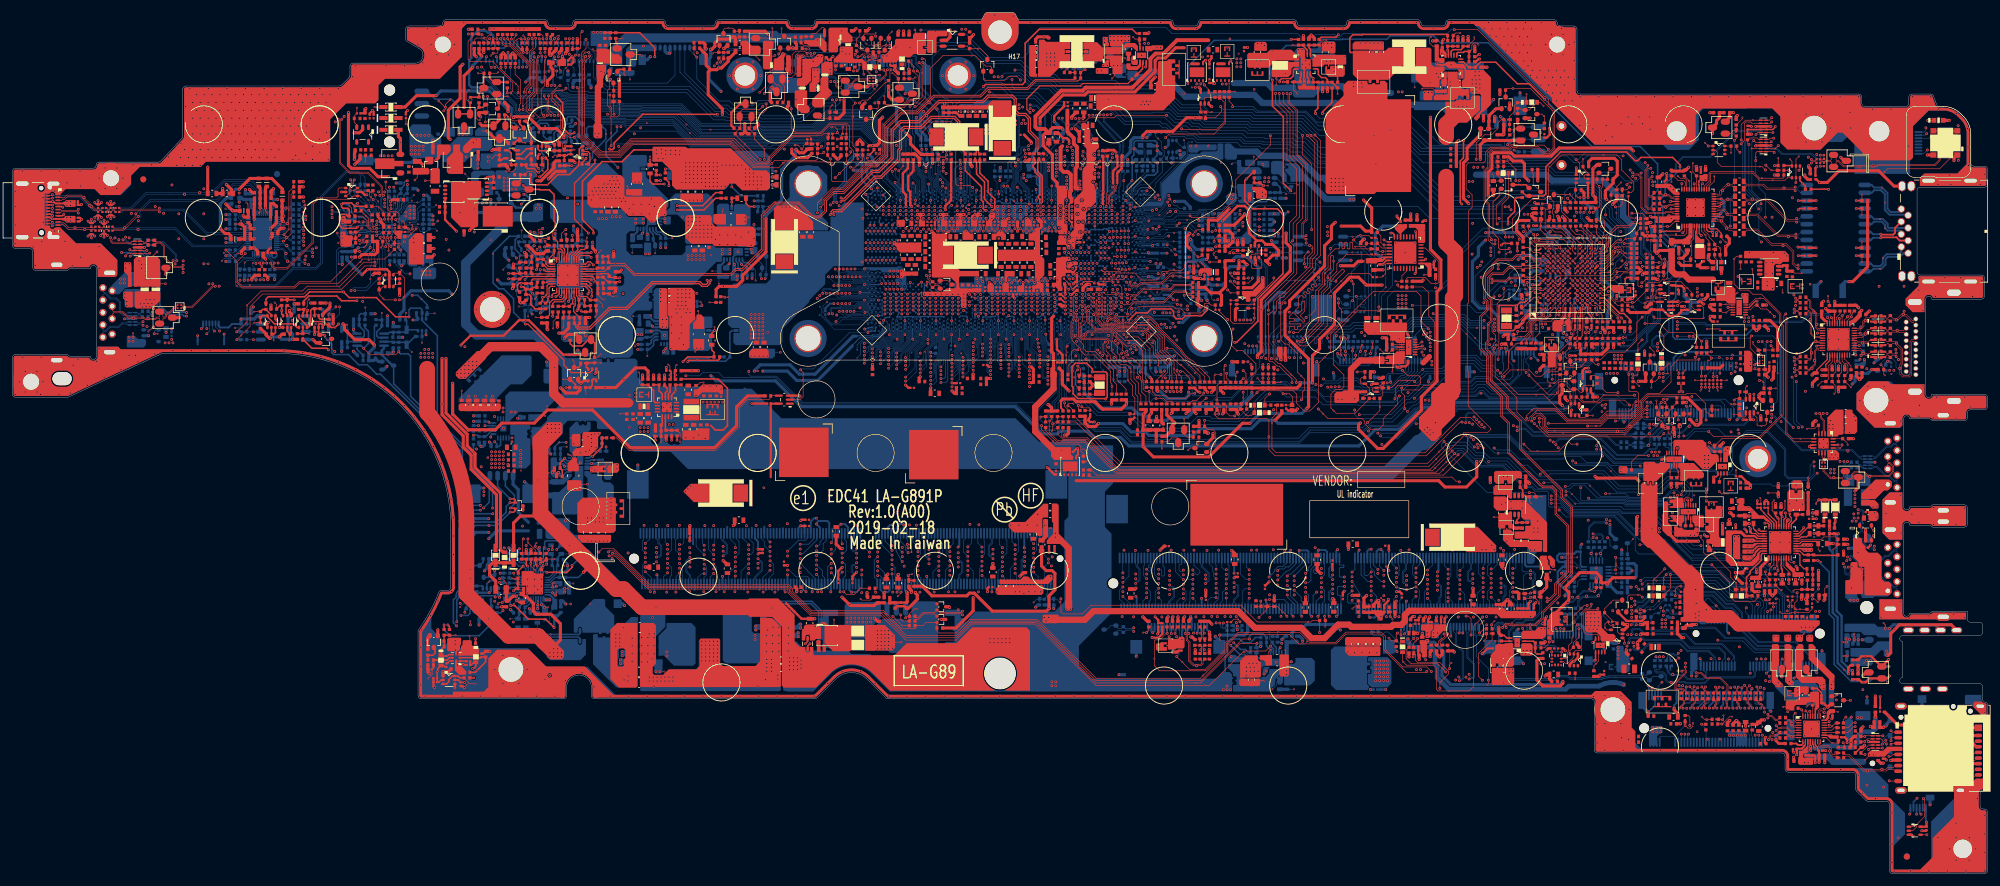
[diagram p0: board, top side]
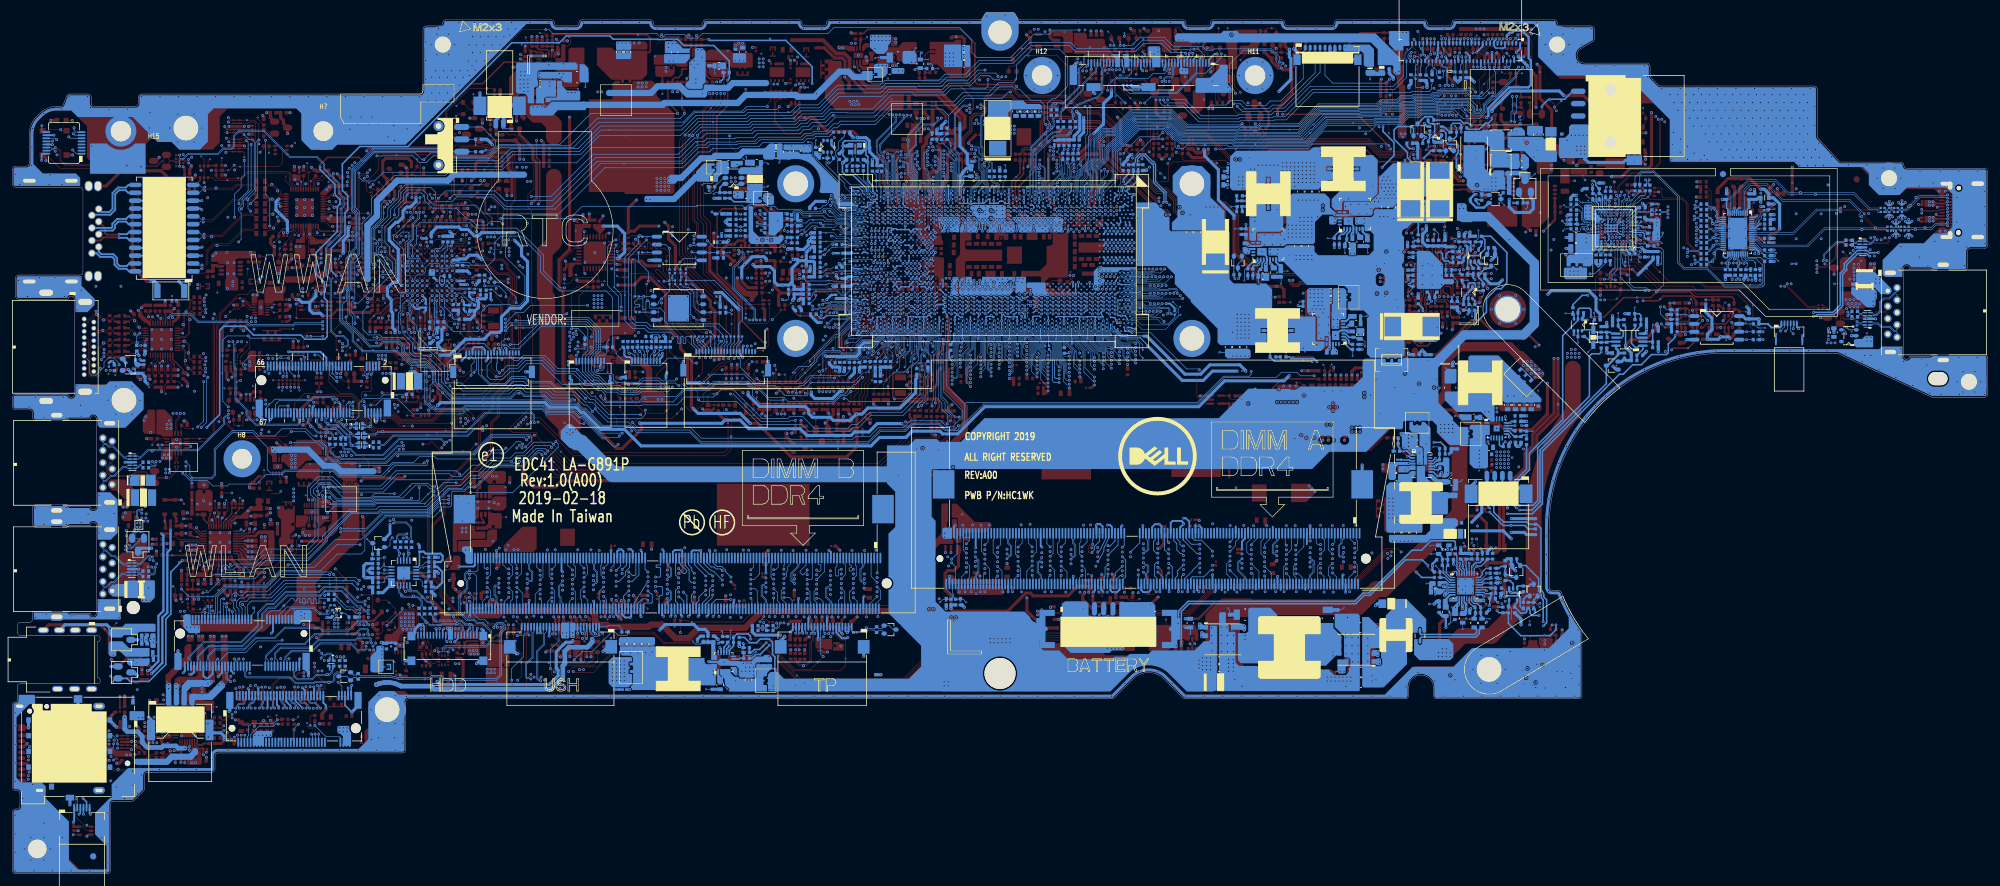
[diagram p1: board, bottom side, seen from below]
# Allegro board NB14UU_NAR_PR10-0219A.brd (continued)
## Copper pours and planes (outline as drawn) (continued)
+3.3V_RUN_UT9 on IN2: 37.71,96.59 32.81,96.59 32.19,97.21 32.19,109.36 34.92,112.09 47.24,112.09 47.43,111.9 47.43,109.29 47.24,109.1 35.56,109.1 35.11,108.66 35.11,99.07 35.87,98.31 38.67,98.31 39.3,97.67 41.97,97.67 42.6,97.04 42.6,95.96 42.35,95.7 38.6,95.7
+3.3V_RUN_UZ44 on TOP (solid shape): 224.48,89.61 224.48,89.07 224.48,89.07 225.21,89.07 225.26,89.02 225.26,87.78 224.96,87.48 224.96,85.83 224.87,85.74 223.63,85.74 223.24,86.14 222.6,86.14 222.56,86.18 222.56,86.81 222.29,87.08 218.97,87.08 218.27,87.78 218.27,88.96 218.39,89.08 222.79,89.08 222.81,89.1 222.81,89.61 222.82,89.62 223.27,89.62 223.27,89.61 223.27,89.08 223.28,89.07 223.99,89.07 224.01,89.09 224.01,89.61 224.02,89.62 224.47,89.62
+3.3V_SPI on TOP (solid shape): 205.85,85.12 205.85,83.75 205.94,83.66 205.94,82.82 205.86,82.73 205.46,82.73 205.33,82.86 205.33,85.13 205.35,85.15 205.82,85.15
+3.3V_SPI on BOTTOM: 207,93.71 207.95,93.71 208.13,93.53 208.13,93.07 207.99,92.93 205.61,92.93 205.47,93.08 205.16,93.08 205.12,93.12 205.12,94.17 205.13,94.18 206.53,94.18
+3.3V_SPI on BOTTOM: 208.58,102.77 208.4,102.6 207.04,102.6 206.9,102.74 205.74,102.74 205.51,102.51 205.51,101.71 205.46,101.65 204.94,101.65 204.87,101.72 204.87,103.55 205.15,103.83 208.18,103.83 208.58,103.44
+3.3V_SPI on IN3: 172.92,96.52 172.92,94.17 173.18,93.92 182.47,93.92 182.6,94.04 182.6,94.98 182.44,95.14 180.81,95.14 180.65,95.31 177.57,95.31 177.25,95.63 175.3,95.63 174.29,96.64 173.04,96.64
+3.3V_SSD on TOP: 257.94,30.93 257.78,31.09 257.78,32.18 257.44,32.52 256.9,32.52 256.85,32.57 256.85,35.09 256.58,35.36 256.58,36.21 256.62,36.25 257.76,36.25 259.13,34.87 260.4,34.87 260.73,34.54 260.73,31.1 260.56,30.93
+3.3V_TP on TOP (solid shape): 189.34,38.12 189.34,36.59 189.14,36.4 188.04,36.4 187.86,36.22 186.7,36.22 186.65,36.26 186.65,37.79 186.78,37.93 186.88,37.92 186.97,37.94 187.97,37.94 188.24,37.98 188.4,38.2 188.49,38.29 189.18,38.29
+3.3V_TP on IN2: 192.68,40.67 196.24,40.67 196.49,40.42 196.49,38.78 192.73,35.02 188.79,35.02 188.67,35.14 188.67,38.23 188.87,38.43 190.26,38.43 190.27,38.43 190.63,38.44 190.79,38.76 190.79,38.79
+3.3V_VDD_DCIN on TOP (solid shape): 70.8,117.61 70.8,116.79 70.16,116.15 68.64,116.15 68.58,116.22 68.58,117.68 68.77,117.87 70.54,117.87
+3.3V_VDD_DCIN on TOP (solid shape): 71.86,34.56 71.86,34.19 73.3,32.75 73.3,32.23 73.19,32.12 72.18,32.12 71.49,32.8 71.49,34.48 71.63,34.62 71.8,34.62
+3.3V_VDD_PIC_R on TOP: 56.75,118.79 57.76,118.79 57.86,118.7 57.86,117.86 57.36,117.36 57.36,115.8 57.25,115.7 56.83,115.7 56.73,115.8 56.73,116.48 56.53,116.67 55.89,116.67 55.84,116.72 55.84,117.27 56.55,117.98 56.55,118.59
+3.3V_VPS_UZ12 on TOP (solid shape): 225.29,104.93 225.29,104.43 224.37,103.5 224.37,102.51 224.31,102.46 224.15,102.46 224.09,102.53 224.09,103.35 223.31,104.13 223.31,104.86 223.4,104.95 224.61,104.95 224.65,104.99 225.24,104.99
+3.3V_VPS_UZ12 on TOP (solid shape): 222.88,99.7 222.88,99.53 222.81,99.46 221.92,99.46 221.32,98.86 220.98,98.86 220.98,98.86 220.61,98.86 220.37,98.63 218.7,98.63 218.66,98.67 218.66,99.39 218.77,99.5 220.93,99.5 221.14,99.72 221.36,99.72 221.4,99.76 222.82,99.76
+3.3V_WLAN on TOP (solid shape): 290.22,40.93 291.85,40.93 291.96,40.83 291.96,40.29 291.61,39.95 291.52,39.95 290.7,39.13 289.89,39.13 289.64,39.38 289.17,39.38 288.91,39.13 284.98,39.13 284.98,41.03 290.12,41.03
+3.3V_WLAN on TOP (solid shape): 273.17,47.96 273.17,44.14 274.7,42.62 275.84,42.62 276.09,42.36 276.09,40.9 275.71,40.52 273.62,40.52 273.43,40.71 269.49,40.71 269.43,40.78 269.43,41.35 269.55,41.48 269.81,41.48 269.91,41.58 269.91,46.02 270.1,46.21 270.1,46.92 269.29,47.73 269.29,48.58 270.57,49.86 271.28,49.86
+3.3V_WLAN on TOP (solid shape): 263.94,62.82 263.95,62.81 263.95,62.74 264.02,62.74 264.02,62.74 264.38,62.74 264.38,62.74 264.45,62.74 264.45,62.81 264.45,63.28 264.74,63.28 264.74,62.82 264.75,62.81 264.75,62.74 264.82,62.74 265.18,62.74 265.25,62.74 265.25,62.81 265.25,62.81 265.25,63.28 265.58,63.28 265.74,63.12 265.74,56.01 265.67,55.8 265.73,55.59 265.74,55.57 265.74,55.43 265.73,55.41 265.67,55.14 265.83,54.9 265.84,54.9 267.02,53.72 267.02,53.46 266.23,52.66 264.14,52.66 263.02,53.78 263.02,62.91 263.39,63.28 263.94,63.28
+3.3V_WLAN on BOTTOM (solid shape): 273.62,42.24 273.62,40.38 273.53,40.29 272.65,40.29 272.3,40.65 270.84,40.65 270.7,40.79 270.7,42.36 270.95,42.62 273.24,42.62
+3.3V_WLAN on BOTTOM (solid shape): 291.46,41.67 291.46,39.82 290.51,38.87 288.86,38.87 288.73,39 288.73,40.02 288.86,40.14 290.06,40.14 290.25,40.33 290.25,41.73 290.44,41.92 291.21,41.92
+3.3V_WLAN_UZ47 on TOP (solid shape): 265.49,66.29 265.96,66.29 266.19,66.53 266.72,66.53 266.86,66.4 266.91,66.34 267.67,66.34 267.72,66.29 267.72,65.68 267.72,65.67 267.72,65.61 265.64,63.53 265.64,63.45 265.6,63.41 265.14,63.41 265.13,63.4 265.13,62.87 265.13,62.86 264.88,62.86 264.87,62.87 264.87,63.41 264.86,63.42 264.33,63.42 264.33,63.41 264.33,62.87 264.32,62.86 264.08,62.86 264.07,62.87 264.07,63.41 264.06,63.42 263.57,63.42 263.43,63.56 263.43,66.36 263.63,66.56 265.22,66.56
+3.3V_WWAN on TOP: 260.85,84.03 257.78,84.03 256.73,82.98 256.73,82.37 256.92,82.18 261.12,82.18 261.16,82.22 261.16,83.72
+3.3V_WWAN on TOP: 275.53,87.15 276.2,87.15 276.21,87.14 276.21,86.6 276.21,86.59 276.95,86.59 276.95,86.6 276.95,87.14 277.4,87.14 277.4,87.14 277.4,86.59 277.4,86.59 278.15,86.59 278.15,86.59 278.15,87.14 278.15,87.14 278.99,87.14 279.05,87.08 279.05,87.07 279.46,86.66 279.46,81.1 279.33,80.97 278.46,80.97 278.08,80.59 276.67,80.59 275.28,81.97 275.28,86.9
+3.3V_WWAN on BOTTOM: 255.2,78.43 255.2,82.25 256.99,84.04 260.26,84.04 260.51,83.79 260.51,79.01 259.61,78.12 255.52,78.12
+3.3V_WWAN on BOTTOM: 271.31,80.21 276.03,80.21 276.66,80.85 276.66,83.39 276.79,83.51 279.52,83.51 280.34,82.69 280.34,78.41 279.45,77.51 271.42,77.51 271.02,77.91 271.02,79.92
+3.3V_WWAN on IN3: 277.31,85.3 264.75,85.3 264.26,85.78 258.37,85.78 257.87,85.28 257.87,83.59 258.3,83.15 258.75,82.7 260.83,82.7 263.03,80.5 278.12,80.5 279.04,81.42 279.04,83.57
+3.3V_WWAN_UZ43 on TOP: 275.58,90.33 276.85,90.33 277.38,90.86 278.27,90.86 278.34,90.79 278.34,89.07 279.03,88.38 279.03,87.38 278.92,87.28 278.02,87.28 278,87.26 278,86.75 278,86.74 277.55,86.74 277.55,86.75 277.55,87.28 277.54,87.29 276.8,87.29 276.8,87.28 276.8,86.74 276.35,86.74 276.35,87.29 276.35,87.29 275.45,87.29 275.19,87.54 275.19,89.37 275.46,89.64 275.46,90.21
+5V_ALW on TOP (solid shape): 76.51,83.89 76.51,83.26 73.21,79.96 72.13,79.96 71.62,80.46 71.62,81.04 75.05,84.47 75.94,84.47
+5V_ALW on TOP (solid shape): 295.78,74.94 295.78,71.13 295.59,70.94 295.08,70.94 294.79,70.65 293.21,70.65 293.15,70.71 293.15,73.71 294.44,75 295.71,75
+5V_ALW on TOP (solid shape): 245.56,36.93 245.56,35.41 245.38,35.23 243.7,35.23 243.57,35.35 243.57,36.29 243.73,36.46 243.73,37.07 243.9,37.23 245.26,37.23
+5V_ALW on TOP (solid shape): 247.77,39.8 247.77,38.5 247.2,37.93 243.84,37.93 243.71,38.06 243.71,38.95 244.03,39.27 245.92,39.27 246.39,39.74 246.54,39.89 247.68,39.89
+5V_ALW on TOP (solid shape): 229.47,40.23 229.47,39.53 229.1,39.15 229.1,38.34 228.86,38.1 228.43,38.1 228.32,38.22 228.32,38.45 228.31,38.45 228.31,39.04 228.07,39.28 227.66,39.28 227.54,39.41 227.54,40.19 227.66,40.31 229.4,40.31
+5V_ALW on TOP (solid shape): 273.63,69.53 273.63,69.03 274.25,68.4 274.25,68.08 274.53,67.8 275.34,67.8 275.61,67.54 275.61,66.55 275.55,66.48 275.2,66.48 274.65,65.92 274.63,65.92 274.06,65.35 272.99,65.35 271.58,66.76 270.78,66.76 269.9,67.64 269.16,67.64 269.1,67.7 269.1,68.32 269.08,68.4 269.12,68.47 269.04,69.1 268.57,68.67 268.56,68.58 268.45,68.53 268.42,68.53 268.28,68.53 268.28,69.42 268.29,69.42 268.29,69.9 268.5,70.11 273.05,70.11
+5V_ALW on BOTTOM (solid shape): 68.46,97.77 68.46,96.37 68.14,96.05 64.85,96.05 64.69,96.21 64.69,97.84 64.8,97.96 68.27,97.96
+5V_ALW on BOTTOM (solid shape): 101.96,88.1 101.96,86.98 101.87,86.89 100.81,86.89 100.65,87.05 100.65,88.03 100.78,88.16 101.9,88.16
+5V_ALW on BOTTOM (solid shape): 103.18,101.94 103.18,100.02 103.09,99.92 102.12,99.92 102.02,100.01 102.02,101.92 102.1,101.99 103.13,101.99
+5V_ALW on BOTTOM (solid shape): 117.33,96.99 117.33,95.89 117.26,95.81 116.08,95.81 116.03,95.86 116.03,97.03 116.05,97.06 117.26,97.06
+5V_ALW on BOTTOM (solid shape): 228.94,40.49 228.94,38.24 228.78,38.07 228.29,38.07 228.2,38.17 228.2,39.26 228.07,39.38 228.07,40.46 228.18,40.57 228.87,40.57
+5V_ALW on BOTTOM (solid shape): 105.92,85.92 105.92,84.71 106.11,84.52 106.11,83.92 106.07,83.88 104.98,83.88 104.93,83.93 104.93,84.55 105.6,85.22 105.6,85.92 105.66,85.98 105.85,85.98
+5V_ALW on BOTTOM (solid shape): 120.33,101.23 120.33,100.5 119.92,100.09 119.25,100.09 119.11,100.23 119.11,100.67 119,100.79 118.3,100.79 118.24,100.85 118.24,101.04 118.3,101.1 119.51,101.1 119.7,101.3 120.27,101.3
+5V_ALW on BOTTOM (solid shape): 106.36,106.18 106.36,105.05 106.22,104.91 105.41,104.91 105.15,105.18 105.15,105.62 105.02,105.74 104.33,105.74 104.26,105.8 104.26,105.99 104.33,106.06 105.53,106.06 105.72,106.25 106.29,106.25
+5V_ALW on BOTTOM (solid shape): 212.5,127.68 212.5,126.93 212.31,126.74 211.54,126.74 211.51,126.71 211.49,126.71 211.47,126.69 211.39,126.63 211.33,126.54 210.21,125.42 207.13,125.42 206.79,125.77 206.79,125.94 206.79,125.95 206.82,126.1 206.79,126.24 206.79,126.26 206.78,126.27 206.72,126.35 206.64,126.41 206.59,126.46 205.61,126.46 205.43,126.64 205.43,127.34 205.64,127.55 207.21,127.55 207.4,127.37 207.4,126.86 207.59,126.67 209.91,126.67 211.05,127.8 212.38,127.8
+5V_ALW on IN1 (solid shape): 106.15,105.78 106.15,102.79 104.85,101.49 104.46,101.42 104.38,101.02 103.89,100.53 103.89,99.99 103.66,99.76 102.08,99.76 102.08,100.88 104.72,103.52 104.72,105.76 105.04,106.09 105.84,106.09
+5V_ALW on IN2 (solid shape): 101.44,79.33 101.44,76.93 101.23,76.72 100.28,76.72 100.06,76.93 100.06,79.3 100.22,79.46 101.32,79.46
+5V_ALW on IN2 (solid shape): 101.9,88.36 101.9,86.88 102.57,86.21 102.57,86.08 101.9,85.41 101.74,85.41 100.73,86.42 100.73,88.31 100.83,88.41 101.84,88.41
+5V_ALW on IN2 (solid shape): 105.21,100.38 105.21,98.5 105.06,98.36 101.9,98.36 101.75,98.52 101.75,100.34 101.88,100.47 105.12,100.47
+5V_ALW on IN2 (solid shape): 120.12,100.97 120.12,98.32 117.42,95.62 115.99,95.62 115.69,95.92 115.69,97.23 115.72,97.26 117.22,97.26 118.9,98.94 118.9,100.89 119.15,101.15 119.94,101.15
+5V_ALW on IN2 (solid shape): 105.91,84.98 105.91,83.17 105.25,82.51 105.09,82.51 104.47,83.12 104.46,83.12 104.43,83.15 104.43,83.27 104.97,83.81 104.97,84.09 104.52,84.55 103.84,84.55 103.65,84.74 103.65,85.57 103.9,85.82 105.07,85.82
+5V_ALW on TOP: 191.53,128.46 191.82,128.46 191.87,128.41 191.87,128.15 192.19,127.83 192.19,127.56 192.02,127.39 191.19,127.39 191.07,127.52 191.07,127.71 191.49,128.13 191.49,128.41
+5V_ALW on TOP: 195.69,128.44 196.15,128.44 196.19,128.4 196.19,127.9 196.34,127.76 196.34,127.14 196.26,127.06 195.2,127.06 195.14,127.13 195.14,127.64 195.32,127.82 195.41,127.82 195.64,128.06 195.64,128.4
+5V_ALW on TOP: 182.54,132.95 182.72,132.95 182.8,133.03 182.8,133.85 182.87,133.92 183.82,133.92 183.92,134.02 183.92,135.14 183.86,135.19 182.61,135.19 182.5,135.08 182.5,132.99
+5V_ALW on TOP: 298.62,55.84 297.3,55.84 297.1,55.84 296.86,56.08 296.86,57.61 297.11,57.86 298.26,57.86 299.14,58.75 299.44,58.75 299.57,58.62 299.57,56.78
+5V_ALW on TOP: 171.93,63.8 172.02,63.71 172.02,63.32 171.95,63.26 171.52,63.26 171.51,63.26 171.24,63.26 171,63.5 171,64.66 171.1,64.75 171.26,64.75 171.36,64.65 171.36,64.02 171.58,63.8
+5V_ALW on TOP: 101.68,77.67 101.68,77.16 102.23,77.16 102.23,76.76 101.68,76.21 101.68,74.99 99.39,74.99 98.77,75.61 98.77,77.87 99.14,78.24 102.1,78.24 102.23,78.12 102.23,77.67
+5V_ALW on TOP: 236.9,114.52 237.01,114.41 237.01,113.95 237.36,113.59 237.36,108.52 237.84,108.04 237.84,104.31 237.48,103.96 237.48,102.16 238.51,101.13 238.51,98.04 237.25,96.78 237.25,90.76 236.65,90.16 236.65,84.61 237.77,83.49 237.77,79.04 238.85,77.96 238.85,74.38 240.83,72.4 240.83,66.57 240.37,66.12 236.6,66.12 236.31,66.41 236.31,67.26 236.86,67.81 238.78,67.81 239.27,68.3 239.27,72.43 237.54,74.16 237.54,76.72 236.55,77.71 236.55,77.73 236.28,78 236.28,82.79 235.1,83.96 235.1,91.59 235.62,92.1 235.62,106.86 236.13,107.37 236.13,111.61 236.27,111.76 236.27,112.19 235.67,112.8 235.67,114.41 235.78,114.52
+5V_ALW on BOTTOM: 221.92,126.77 224.68,126.77 224.8,126.65 224.8,125.56 224.75,125.51 221.94,125.51 221.82,125.63 221.82,126.67
+5V_ALW on BOTTOM: 195.21,128.12 195.21,127.16 195.27,127.1 198.01,127.1 198.09,127.19 198.09,128.18 197.98,128.3 195.39,128.3
+5V_ALW on BOTTOM: 73.97,83.77 75.24,83.77 76.39,82.62 76.39,81.35 75.88,80.85 75.75,80.85 75.43,81.16 74.04,79.77 74.35,79.45 74.35,79.32 73.59,78.56 72.58,78.56 71.31,79.83 71.31,81.1
+5V_ALW on BOTTOM: 23.3,85.29 23,85.59 23,86.51 23.55,87.07 25.14,87.07 25.18,87.11 26.06,87.11 26.2,86.97 26.2,85.55 25.93,85.29
+5V_ALW on IN1: 182.43,134.51 184.01,134.51 184.26,134.27 184.26,133.15 186.22,131.19 190.24,131.19 191.68,129.75 196.37,129.75 196.59,129.53 196.59,127.08 196.43,126.93 191.02,126.93 189.01,128.94 185.33,128.94 182.25,132.02 182.25,134.34
+5V_ALW on VCC: outline of 131 points within 24.06,1.17 317.88,98.24
+5V_ALW on IN2: 236.28,66.34 236.51,66.11 247.37,66.11 250.29,63.19 251.06,63.19 251.65,62.61 251.65,58.59 251.36,58.31 251.36,47.54 251.85,47.05 251.85,44.78 248.56,41.49 246.89,41.49 246.18,40.78 246.18,39.37 246.23,39.32 247.64,39.32 247.76,39.44 247.76,39.89 247.9,40.03 249.54,40.03 253.44,43.93 253.44,47.64 253.12,47.96 253.12,63.45 249.2,67.37 236.38,67.37 236.28,67.27
+5V_ALW on IN3: 223.56,126.64 224.79,126.64 224.88,126.55 224.88,124.59 224.78,124.49 223.51,124.49 223.45,124.56 223.45,126.52
+5V_ALW on IN3: 299.4,62.08 299.4,56.21 298.99,55.8 295.86,55.8 295.65,56.01 295.65,60.84 293.43,63.07 293.43,65.61 293.56,65.73 294.32,65.73 295.17,64.88 296.6,64.88
+5V_ALW on IN3: 234.69,114.93 236.92,114.93 236.98,114.87 236.98,114.01 236.8,113.84 234.71,113.84 234.65,113.9 234.65,114.88
+5V_ALW_PDA on TOP (solid shape): 66.49,103.1 66.49,98.53 66.4,98.44 64.13,98.44 64.03,98.55 64.03,102.38 65.19,103.54 66.04,103.54
+5V_ALW_PDA on BOTTOM (solid shape): 66.61,100.21 66.77,100.05 67.59,100.05 68.02,99.62 68.02,98.21 67.95,98.14 67.34,98.14 67.34,98.14 67.34,98.68 67.33,98.69 66.59,98.69 66.59,98.68 66.59,98.14 66.58,98.14 66.14,98.14 66.13,98.14 66.13,98.68 66.13,98.69 65.39,98.69 65.38,98.68 65.38,98.14 65.38,98.14 64.16,98.14 63.76,98.54 63.76,100.31 62.7,101.36 62.7,103.32 62.78,103.39 64.64,103.39 64.77,103.52 66.61,103.52
+5V_ALWP on BOTTOM (solid shape): 83.88,83.51 83.88,80.59 82.35,79.07 80.45,79.07 78.29,76.91 78.29,76.4 78.04,76.15 72.19,76.15 72.07,76.27 72.07,76.79 79.04,83.77 83.62,83.77
+5V_ALWP on TOP: 72.19,76.15 78.04,76.15 78.04,76.15 78.88,76.15 78.91,76.17 78.91,76.94 78.3,77.54 72.58,77.54 72.07,77.04 72.07,76.27
+5V_HDD on TOP (solid shape): 242.59,33.19 242.59,30.71 242.38,30.49 239.06,30.49 238.94,30.62 238.94,33.11 239.09,33.26 242.52,33.26
+5V_HDD on BOTTOM: 250.86,39.13 250.99,39.26 252.1,39.26 252.2,39.15 252.2,37.81 252.41,37.6 252.79,37.6 253.04,37.35 256.15,37.35 256.54,36.97 258.63,36.97 258.94,36.66 258.94,34.06 258.88,34.01 258.88,33.67 258.31,33.67 258.31,33.16 258.88,33.16 258.88,32.65 258.76,32.52 250.27,32.52 250.26,32.53 249.53,32.53 248.96,31.97 241.15,31.97 240.95,32.17 240.95,33.23 241.21,33.49 244.61,33.49 246.33,35.22 250.02,35.22 250.86,36.06
+5V_HDD_UZ23 on TOP (solid shape): 242.4,37.12 242.4,36.57 242.57,36.41 242.57,33.71 242.27,33.42 240.08,33.42 240.08,33.98 239.59,33.98 239.59,33.42 238.91,33.42 238.75,33.57 238.75,35.34 239.5,36.09 239.5,36.8 239.83,37.13 240.98,37.13 241.09,37.25 242.27,37.25
+5V_PD_VDD on TOP: 55.87,122.36 59.01,122.36 59.21,122.56 59.21,124.22 59.28,124.29 60.64,124.29 60.79,124.15 60.79,121.66 60.03,120.9 59.11,120.9 58.2,119.99 57.38,119.99 57.18,120.18 57.18,121.18 56.78,121.59 55.9,121.59 55.78,121.71 55.78,122.27
+5V_RUN on BOTTOM (solid shape): 260.28,36.65 260.28,36.01 261.23,35.06 261.23,32.78 260.98,32.52 259.33,32.52 259.08,32.78 259.08,36.71 259.2,36.84 260.09,36.84
+5V_RUN on IN1 (solid shape): 260.28,36.78 260.28,35.97 260.49,35.77 261.7,35.77 261.76,35.71 261.76,33.74 261.61,33.59 258.91,33.59 258.76,33.74 258.76,36.78 258.95,36.97 260.09,36.97
+5V_RUN on TOP: 273.92,59.05 273.91,59.06 273.91,59.6 273.91,59.6 273.22,59.6 272.7,59.09 271.44,59.09 271.34,59.19 271.34,59.87 271.47,60 271.47,60.95 270.76,61.67 270.76,63.64 270.82,63.7 271.27,63.7 271.27,63.19 272.66,63.19 272.66,63.7 273.36,63.7 275.48,61.58 275.48,59.62 275.46,59.6 274.99,59.6 274.97,59.58 274.97,59.06 274.97,59.05 274.72,59.05 274.72,59.06 274.72,59.59 274.71,59.6 274.17,59.6 274.17,59.6 274.17,59.06 274.17,59.05
+5V_RUN on TOP: 225.66,37.56 225.26,37.56 225.09,37.73 225.09,39.99 225.71,40.61 227.38,40.61 227.4,40.59 227.4,39.74 227.2,39.53 226.14,39.53 225.88,39.27 225.88,37.78
+5V_RUN on BOTTOM: 85.15,57.16 83.25,57.16 83.06,56.97 83.06,55.09 84.32,53.83 85.5,53.83 85.71,54.04 85.71,55.86 85.25,56.31 85.25,57.06
+5V_RUN on IN1: 274.19,62.05 274.19,57.66 273.81,57.29 272.03,57.29 271.62,57.7 271.62,62.21 271.9,62.49 273.75,62.49
+5V_RUN_AUDIO on TOP (solid shape): 273.74,58.87 275.14,58.87 275.14,59.45 275.97,59.45 276.22,59.19 276.22,57.8 275.65,57.22 275.65,54.49 275.97,54.18 275.97,52.84 275.9,52.78 274.95,52.78 274.38,53.35 273.68,53.35 273.62,53.41 273.62,53.99 273.68,54.05 274.06,54.05 274.19,54.18 274.19,54.81 273.43,55.57 273.43,56.21 274,56.21 274,56.72 273.43,56.72 273.43,59.45 273.74,59.45
+5V_RUN_AUDIO_UZ5 on TOP (solid shape): 273.24,57.76 273.24,55.98 272.42,55.98 272.27,56.13 271.74,56.13 271.74,56.44 271.36,56.82 271.36,57.78 271.46,57.88 273.11,57.88
+5V_RUN_PVDD_L on TOP (solid shape): 279.84,54.93 280.01,54.76 281.47,54.76 281.95,54.27 283.38,54.27 283.43,54.22 283.43,54.1 283.37,54.04 281.72,54.04 281.39,54.37 279.69,54.37 279.18,54.87 278.07,54.87 278.07,54.87 277.99,54.87 277.74,54.62 277.74,51 278.32,50.43 280.8,50.43 281.76,51.39 281.76,51.68 282.32,52.24 283.38,52.24 283.44,52.18 283.44,52.11 283.38,52.05 282.61,52.05 282.54,52.05 282.23,51.75 282.23,50.76 281.29,49.83 281.22,49.78 281.16,49.72 277.57,49.72 276.73,50.56 276.73,55.32 276.88,55.47 279.3,55.47
+5V_RUN_UZ47 on TOP (solid shape): 273.24,64.71 273.24,64.15 272.96,63.87 270.67,63.87 270.27,63.46 269.47,63.46 269.39,63.54 269.39,65.32 269.1,65.62 269.1,66.29 269.18,66.37 271.58,66.37
+5V_TBT_VBUS on TOP: 59.25,120.57 60.15,120.57 61.62,122.04 61.62,122.47 61.69,122.55 63.13,122.55 63.3,122.38 63.75,122.38 63.81,122.32 63.81,121.94 63.53,121.66 62.51,121.66 60.7,119.84 59.27,119.84 59.24,119.88 59.24,120.56
+5V_USB_CHG_PWR on TOP (solid shape): 295.08,67.96 295.08,67.07 294.83,66.81 293.37,66.81 293.16,67.02 293.16,68.39 293.24,68.46 294.57,68.46
+5V_USB_CHG_PWR on TOP (solid shape): 303.59,63.32 303.59,62.56 302.95,61.92 302.32,61.92 300.92,60.53 298.76,60.53 298.64,60.65 298.64,61.41 300.92,63.7 303.21,63.7
+5V_USB_CHG_PWR on BOTTOM: 298.4,64.59 300.46,64.59 301.48,63.58 303.25,63.58 303.63,63.19 303.63,62.49 302.52,61.37 302.5,61.37 300.53,59.4 298.43,59.4 298.33,59.5 298.33,64.52
+5V_USB_CHG_PWR on IN3: 293.17,68.4 293.17,67.13 293.68,66.62 294.06,66.62 295.59,65.1 296.98,65.1 300.16,61.92 302.83,61.92 303.59,62.68 303.59,63.19 301.81,64.97 301.81,67.64 300.54,68.91 293.68,68.91
+13.2VB_BATT on TOP (solid shape): 135.5,40.08 135.5,36.08 135.38,35.95 132.52,35.95 131.19,37.28 131.19,40.08 131.31,40.21 135.38,40.21
+13.2VB_PBATT_C on TOP (solid shape): 142.58,38.52 142.58,36.5 142.13,36.05 137.74,36.05 137.74,40.16 137.79,40.21 140.9,40.21
+13.2VB_PBATT_C on BOTTOM (solid shape): 149.54,43.51 149.54,37.1 148.11,35.67 141.83,35.67 141.41,36.09 139.66,36.09 139.42,36.33 139.42,40.06 140.55,41.19 143.84,41.19 143.84,41.16 144.1,40.9 144.46,40.9 144.71,41.15 144.71,41.27 145.22,41.78 145.22,43.63 145.6,44.02 149.03,44.02
+13.5VB on TOP (solid shape): 88.83,72.72 88.83,71.07 86.55,68.78 86.55,68.53 86.04,68.02 84.51,68.02 84.01,68.53 84.01,70.56 86.42,72.97 88.58,72.97
+13.5VB on TOP (solid shape): 95.88,130.64 95.88,129.26 95.53,128.91 95.53,128.56 95.43,128.46 94.37,128.46 94.37,130.75 95.77,130.75
+13.5VB on TOP (solid shape): 95.28,121.09 95.28,119.05 95.08,118.85 94.12,118.85 93.86,119.1 93.86,121.06 93.98,121.18 95.19,121.18
+13.5VB on TOP (solid shape): 237.05,125.65 237.05,123.43 234.98,121.36 232.79,121.36 231.45,122.69 231.45,124.62 231.61,124.78 232.95,124.78 233.19,125.02 235.43,125.02 235.63,125.22 235.63,125.51 235.9,125.78 236.93,125.78
+13.5VB on TOP (solid shape): 131.52,134.35 131.52,132.94 131.34,132.77 131.06,132.77 130.13,133.69 128.73,133.69 128.35,134.07 127.96,134.07 127.9,134.13 127.9,134.65 127.96,134.7 129.46,134.7 129.78,135.02 130.85,135.02
+13.5VB on TOP (solid shape): 233.68,78.12 233.68,77.04 233.04,76.4 233.04,73.99 230.87,71.81 230.87,70.95 230.56,70.64 230.54,70.64 229.85,69.94 229.2,69.94 227.2,71.94 227.2,73.73 229.17,75.7 229.17,76.37 229.18,76.47 229.17,76.56 229.17,77.67 230.82,79.32 232.47,79.32
+13.5VB on TOP (solid shape): 126.36,41.83 126.36,37.48 127.19,36.65 128.1,36.65 128.1,36.12 128.46,35.76 128.81,36.12 128.81,36.65 129.33,36.65 129.38,36.6 129.38,35.44 129.52,35.3 142.49,35.3 144.44,37.25 152.47,37.25 155.03,39.8 163.79,39.8 164.37,39.23 164.37,29.57 160.52,29.57 160.42,29.65 160.49,29.77 159.52,35.11 158.56,29.77 158.63,29.65 158.53,29.57 141.77,29.57 138.93,32.41 135.52,33.82 132.12,32.41 131.87,32.17 129.75,30.05 124.6,30.05 124.27,30.38 124.27,39.94 122.71,41.5 119.07,41.5 118.69,41.88 118.69,44.16 119,44.47 123.72,44.47
+13.5VB on BOTTOM (solid shape): 181.86,129.55 181.86,128.34 181.73,128.22 180.34,128.22 180.08,128.47 180.08,129.68 180.14,129.74 181.67,129.74
+13.5VB on BOTTOM (solid shape): 230.48,71.59 230.48,70.24 229.05,68.81 228.06,68.81 226.62,70.25 226.62,70.52 228.75,72.65 229.43,72.65
+13.5VB on BOTTOM (solid shape): 85.72,108.28 85.72,105.52 85.31,105.47 84.93,105.29 83.39,105.29 83.28,105.4 83.28,106.9 83.36,106.98 83.92,106.98 84.13,107.18 84.13,108.04 84.45,108.36 85.64,108.36
+13.5VB on BOTTOM (solid shape): 232.69,124.01 233,123.8 233.24,124.08 233.24,124.1 233.33,124.19 235.26,124.19 235.48,123.98 235.48,122.79 235.19,122.5 231.81,122.5 230.92,123.39 227.01,123.39 226.52,123.39 226.39,123.53 226.39,124.6 226.57,124.79 231.92,124.79
+13.5VB on BOTTOM (solid shape): 123.84,135.82 128.22,135.82 128.22,135.82 130.91,135.82 131.31,135.42 131.31,134.73 131.05,134.47 129.08,134.47 128.94,134.33 99.62,134.33 98.52,133.24 98.52,130.77 98.41,130.66 96.18,130.66 96.01,130.49 96.01,129.44 95.7,129.13 95.03,129.13 94.84,129.32 94.84,131.79 98.63,135.59 121.78,135.59 121.78,135.54 121.79,135.48 121.81,135.43 121.84,135.39 121.87,135.35 121.91,135.31 121.96,135.28 122.01,135.26 122.06,135.24 122.11,135.23 122.16,135.23 122.22,135.24 122.27,135.26 122.31,135.28 122.36,135.31 122.4,135.35 122.43,135.39 122.46,135.43 122.48,135.48 122.49,135.54 122.49,135.59 122.49,135.64 122.48,135.69 122.46,135.74 122.43,135.79 122.4,135.83 122.36,135.87 122.31,135.9 122.27,135.92 122.22,135.94 122.16,135.95 122.11,135.95 122.06,135.94 122.01,135.92 121.96,135.9 121.91,135.87 121.87,135.83 121.84,135.79 121.81,135.74 121.79,135.69 121.78,135.64 121.78,135.59 98.63,135.59 98.86,135.81 110.29,135.81 110.29,135.81 120.87,135.81 121.28,136.22 123.44,136.22
+13.5VB on BOTTOM (solid shape): outline of 1787 points within 83.85,29.42 197.01,84
+13.5VB on IN3 (solid shape): 197,31.42 197,29.6 196.82,29.42 167.55,29.42 167.51,29.45 167.51,31.24 167.79,31.51 196.91,31.51
+13.5VB on IN3 (solid shape): 88.83,72.72 88.83,71.07 88.42,70.65 87.85,70.65 85.21,68.02 83.82,68.02 83.43,68.4 83.43,69.99 86.42,72.97 88.58,72.97
+13.5VB on TOP: 230.22,111.71 230.78,111.15 232.82,111.15 232.84,111.16 232.84,119.06 232.49,119.4 230.4,119.4 230.22,119.23
+13.5VB on IN1: 138.83,32.3 135.52,33.67 132.22,32.3 129.34,29.42 125.53,29.42 124.96,29.98 124.96,35.25 125.22,35.51 129.6,35.51 132.77,38.68 161.09,38.68 163.06,36.71 163.06,29.99 162.49,29.42 141.71,29.42
+13.5VB on IN2: 85.53,113.23 92.28,119.99 95.04,119.99 95.31,119.72 95.31,119.01 94.67,118.37 93.21,118.37 87.56,112.72 87.56,109.05 85.65,107.13 84.64,107.13 84.22,107.55 84.22,108.43 85.53,109.73
+13.5VB on IN3: 125.03,36.4 126.87,36.4 128.9,38.43 128.9,41.92 127.74,43.08 100.54,43.08 100.07,43.55 100.07,46.43 100.32,46.68 131.09,46.68 134.11,43.66 134.11,37.6 128.65,32.14 125.41,32.14 124.9,32.65 124.9,36.27 ; 1 cut-out
+13.5VB_1.05VALWP on TOP (solid shape): 233.42,129.53 233.42,128.63 234.03,128.02 234.03,126.95 234.17,126.8 235.21,126.8 235.27,126.75 235.27,125.17 235.26,125.17 234.88,125.17 234.88,125.74 233.48,125.74 233.48,125.17 233.1,125.17 232.95,125.02 231.43,125.02 231.42,125.01 230.54,125.01 230.54,125.01 229.64,125.01 229.61,125.04 229.61,125.66 229.89,125.94 231.73,125.94 231.84,126.05 231.84,129.53 231.9,129.59 233.36,129.59
+13.5VB_1.05VALWP on BOTTOM (solid shape): 234.03,128.03 234.03,127.21 234.2,127.04 234.38,127.04 234.44,126.98 234.44,124.54 234.4,124.5 233.28,124.5 233.17,124.61 233.17,125.28 232.89,125.56 231.33,125.56 231.24,125.65 231.24,128.13 231.33,128.22 233.84,128.22
+13.5VB_3V on TOP (solid shape): 201.54,31.44 201.54,30.49 201.35,30.3 198.44,30.3 198.18,30.56 198.18,31.35 198.34,31.51 201.48,31.51
+13.5VB_3V on BOTTOM (solid shape): 198.88,33.79 198.88,31.76 199.13,31.51 201.54,31.51 201.86,31.82 202.43,31.82 202.49,31.88 202.49,31.89 203,32.4 203,32.4 203,32.97 203.1,33.06 204.66,33.06 204.73,32.99 204.73,32.15 204.02,31.44 204.02,31 203.93,30.91 203.93,30.45 203.55,30.07 203.53,30.07 203.27,29.9 203.33,29.6 203.34,29.49 203.25,29.43 197.25,29.43 197.16,29.51 197.16,30.49 197.73,30.49 197.73,31.89 197.16,31.89 197.16,32.4 196.34,33.22 196.34,33.79 196.4,33.86 198.81,33.86
+13.5VB_5V on BOTTOM (solid shape): 82.67,72.53 83.5,72.53 83.69,72.34 83.69,71.77 83.15,71.77 83.15,70.37 83.69,70.37 83.69,66.24 82.93,65.48 80.94,65.48 80.7,65.71 80.7,69.16 81.08,69.54 81.08,70.81 80.97,70.93 80.49,70.93 80.41,71 80.41,72.46 80.49,72.53 82.67,72.53
+13.5VB_5V on TOP: 81.08,69.54 80.78,69.24 80.78,64.77 80.89,64.65 82.1,64.65 82.61,65.16 82.61,69.03 82.1,69.54
+13.5VB_CPU on BOTTOM (solid shape): outline of 460 points within 86.86,83.37 116.14,108.91
+13.5VB_CPU on TOP: 98.23,107.33 99.5,106.06 101.98,106.06 103.5,104.53 106.61,104.53 109.66,101.48 113.09,101.48 113.41,101.17 115.95,101.17 116.2,100.91 116.2,98.82 115.81,98.43 101.22,98.43 93.76,105.89 93.76,107.23 93.85,107.33
+13.5VB_DDR on TOP (solid shape): 91.75,70.94 91.75,69.16 91.63,69.03 90.55,69.03 90.36,69.23 90.36,70.88 90.55,71.07 91.63,71.07
+13.5VB_DDR on BOTTOM (solid shape): 91.44,72.46 92.83,72.46 92.83,73.04 93.28,73.04 93.4,72.91 93.4,71.77 92.96,71.32 92.13,71.32 91.75,70.94 91.75,69.16 91.69,69.1 91.44,69.1 91.05,68.72 91.05,66.18 90.99,66.11 90.61,66.11 90.55,66.18 90.55,67.7 89.97,68.27 89.97,72.02 90.99,73.04 91.44,73.04
+13.5VB_FU on BOTTOM (solid shape): 100.49,129.8 100.49,129.18 100.24,128.93 97.46,128.93 97.26,129.12 97.26,129.64 98.83,129.64 99.08,129.89 100.4,129.89
+13.5VB_IR on BOTTOM (solid shape): 104.07,133.88 104.07,133.04 103.96,132.93 101.2,132.93 100.78,132.51 100.78,130.68 100.53,130.43 99.2,130.43 99.11,130.51 99.11,133.28 99.84,134 103.95,134
+13.5VB_L on TOP (solid shape): 97.1,132.44 97.89,132.44 98.46,131.87 98.46,131.01 98.36,130.92 94.71,130.92 94.36,131.26 94.36,133.3 94.4,133.33 96.21,133.33
+13.5VB_VCCGT on TOP (solid shape): 105.72,94.5 105.72,90.15 105.98,89.9 105.98,88.31 105.77,88.11 104.63,88.11 104.45,88.29 104.45,94.5 104.58,94.63 105.6,94.63
+13.5VB_VCCGT on BOTTOM (solid shape): 105.72,94.5 105.72,92.21 105.91,92.02 105.91,88.08 104.77,88.08 104.77,89.35 104.52,89.61 103.82,89.61 103.56,89.86 103.56,94.24 103.94,94.63 105.6,94.63
+13.5VB_VCCSA on TOP (solid shape): 179.32,132.02 179.32,129.36 179.19,129.23 177.8,129.23 177.73,129.3 177.73,130.16 177.29,130.61 177.29,131.52 177.16,131.65 176.59,131.65 176.55,131.69 176.55,132.18 176.59,132.22 179.13,132.22
+13.5VB_VCCSA on BOTTOM (solid shape): 179.89,130.66 179.89,129.42 179.32,129.42 179.32,128.92 179.89,128.92 179.89,128.66 179.83,128.6 178.39,128.6 177.73,129.25 177.73,130.15 177.59,130.3 177.59,130.76 177.73,130.9 179.65,130.9
+13.5VB_VCHGR on TOP (solid shape): 130.61,39.76 130.61,38.05 130.49,37.92 129.79,37.92 129.54,37.67 128.84,37.67 128.84,38.36 128.58,38.62 128.33,38.62 128.07,38.36 128.07,37.67 127.57,37.67 127.5,37.73 127.5,39.13 127.82,39.44 127.82,39.95 128.14,40.27 130.11,40.27
+19.5V_AC on BOTTOM (solid shape): 95.75,44.21 95.75,43.19 97.21,41.73 97.21,39.06 97.09,38.94 92.07,38.94 92.07,39.63 91.82,39.89 91.56,39.89 91.31,39.63 91.31,38.94 90.8,38.94 90.67,39.06 90.67,41.16 93.91,44.4 95.56,44.4
+19.5V_CHARGER on TOP (solid shape): 100.96,40.46 100.96,30.3 100.71,30.05 97.98,30.05 96.58,31.44 96.58,36.14 97.72,36.14 97.72,33.6 97.85,33.47 98.61,33.47 98.74,33.6 98.74,34.62 98.99,34.87 98.99,36.14 98.74,36.4 97.98,36.4 97.72,36.14 96.58,36.14 96.58,39.44 97.66,40.52 100.9,40.52
+19.5V_CHARGER on BOTTOM (solid shape): 101.02,41.41 101.02,30.3 100.83,30.11 97.53,30.11 93.78,33.86 93.78,34.68 97.79,34.68 97.79,33.86 98.1,33.54 99.5,33.54 99.75,33.79 99.75,36.21 99.5,36.46 98.23,36.46 97.98,36.21 97.98,34.87 97.79,34.68 93.78,34.68 93.78,38.55 93.98,38.75 94.55,38.75 94.55,38.17 96.58,38.17 96.58,38.75 97.21,38.75 99.94,41.48 100.96,41.48
+19.5V_DC_IN on BOTTOM (solid shape): 77.53,119 77.53,117.42 76.89,116.79 74.86,116.79 73.08,115.01 69.72,115.01 69.6,115.12 69.6,116.79 70.95,118.13 74.1,118.13 74.1,118.08 74.11,118.03 74.13,117.98 74.16,117.93 74.19,117.89 74.23,117.85 74.28,117.82 74.33,117.8 74.38,117.79 74.43,117.78 74.48,117.78 74.53,117.79 74.59,117.8 74.63,117.82 74.68,117.85 74.72,117.89 74.75,117.93 74.78,117.98 74.8,118.03 74.81,118.08 74.81,118.13 74.81,118.19 74.8,118.24 74.78,118.29 74.75,118.33 74.72,118.38 74.68,118.41 74.63,118.44 74.59,118.47 74.53,118.48 74.48,118.49 74.43,118.49 74.38,118.48 74.33,118.47 74.28,118.44 74.23,118.41 74.19,118.38 74.16,118.33 74.13,118.29 74.11,118.24 74.1,118.19 74.1,118.13 70.95,118.13 71.92,119.1 77.43,119.1
+19.5V_DC_IN_SS on BOTTOM (solid shape): 81.78,120.05 84.45,120.05 84.59,119.91 84.59,118.28 84.5,118.18 81.21,118.18 80.45,117.42 80.45,114.63 79.94,114.12 77.4,114.12 77.15,113.87 75.85,113.87 75.57,114.15 75.57,115.12 75.62,115.17 75.62,116.27 75.75,116.41 77.53,116.41 78.04,116.91 78.04,119.71 78.54,120.22 81.61,120.22
+19.5V_DC_IN_SS on IN2 (solid shape): 77.86,115.96 77.86,114.14 77.68,113.96 76.14,113.96 75.86,114.23 75.86,115.89 76.09,116.11 77.72,116.11
+19.5V_DCIN_JACK on BOTTOM: 65.17,124.94 70.64,124.94 71.69,123.9 71.69,119.33 71.43,119.07 68.64,119.07 68,119.71 68,121.18 67.24,121.94 65.21,121.94 64.9,122.26 64.9,124.67
+19.5V_SDC_IN on TOP (solid shape): 89.09,36.01 89.09,35 88.7,34.62 86.93,34.62 84.89,36.65 84.89,37.54 85.66,38.3 86.8,38.3
+19.5V_SDC_IN on BOTTOM (solid shape): 91.31,37.22 91.56,36.97 91.82,36.97 92.07,37.22 92.07,37.92 92.58,37.92 92.64,37.86 92.64,35.38 91.75,34.49 86.8,34.49 86.29,35 86.29,37.16 87.05,37.92 91.31,37.92
+19.5V_SDC_IN on BOTTOM (solid shape): 84.64,117.65 84.64,112.75 84.13,112.25 84.13,111.17 83.34,110.38 83.29,110.42 83.24,110.45 83.2,110.46 83.15,110.46 83.1,110.46 83.05,110.45 83,110.43 82.98,110.41 82.08,110.41 81.91,110.25 79.24,110.25 78.93,110.56 77.91,110.56 77.91,111.29 82.13,111.29 82.13,111.24 82.13,111.18 82.15,111.13 82.17,111.08 82.2,111.04 82.24,111 82.28,110.97 82.33,110.94 82.38,110.92 82.43,110.91 82.48,110.91 82.54,110.91 82.59,110.92 82.64,110.94 82.68,110.97 82.72,111 82.76,111.04 82.79,111.08 82.81,111.13 82.83,111.18 82.84,111.24 82.84,111.29 82.83,111.34 82.81,111.39 82.79,111.44 82.76,111.48 82.72,111.52 82.68,111.56 82.64,111.58 82.59,111.6 82.54,111.62 82.48,111.62 82.43,111.62 82.38,111.6 82.33,111.58 82.28,111.56 82.24,111.52 82.2,111.48 82.17,111.44 82.15,111.39 82.13,111.34 82.13,111.29 77.91,111.29 77.91,112.47 78.04,112.6 78.04,113.48 78.23,113.68 79.56,113.68 79.94,113.29 80.51,113.29 81.28,114.06 81.28,117.68 81.34,117.74 84.55,117.74
+19.5V_SDC_IN on IN1 (solid shape): 68.26,84.53 68.26,80.97 68,80.72 66.1,80.72 65.59,81.23 65.59,84.53 66.1,85.04 67.75,85.04
+19.5V_SDC_IN on IN1 (solid shape): 89.09,36.01 89.09,35 88.7,34.62 86.93,34.62 84.89,36.65 84.89,37.54 85.66,38.3 86.8,38.3
+19.5V_SDC_IN on TOP: 76.26,111.14 76.26,109.29 75.88,108.91 75.88,103.2 65.34,92.66 65.34,88.72 64.19,87.58 64.19,82.24 65.97,80.46 67.88,80.46 68.26,80.85 68.26,83.64 72.45,87.83 72.45,91.89 82.48,101.93 82.48,106.25 81.85,106.88 81.85,108.85 82.16,109.17 82.16,110.18 81.47,110.88 80.58,110.88 80.39,111.07 80.39,112.34 80.58,112.53 81.21,112.53 81.4,112.72 81.4,113.23 81.34,113.29 78.48,113.29 78.24,113.05 78.24,113.05 78.24,111.37 78.14,111.26 76.39,111.26
+20V_LDO_INPUT on TOP (solid shape): 68,115.7 68,114.83 67.8,114.63 66.79,114.63 66.66,114.76 66.66,115.74 66.8,115.87 67.83,115.87
+20V_LDO_INPUT on TOP (solid shape): 75.69,118.76 75.69,117.29 75.62,117.23 74.35,117.23 73.59,116.47 73.08,116.47 72.83,116.72 72.83,117.55 74.16,118.88 75.56,118.88
+20V_TBTA_VBUS on TOP (solid shape): 23.89,99.2 23.89,94.9 23.87,94.88 19.62,94.88 19.62,99.28 20.03,99.69 23.4,99.69
+20V_TBTA_VBUS on TOP (solid shape): 10.22,107.83 10.16,107.77 8.63,107.77 8.25,108.15 6.89,108.15 6.64,108.4 5.44,108.4 5.36,108.49 5.36,108.68 5.43,108.76 6.72,108.76 7.01,108.47 8.12,108.47 8.25,108.6 8.44,108.6 8.69,108.85 10.22,108.85
+20V_TBTA_VBUS on TOP (solid shape): 10.19,106.25 10.19,105.26 10.17,105.23 8.69,105.23 8.38,105.55 8.06,105.55 7.93,105.67 6.72,105.67 6.49,105.74 6.26,105.7 6.03,105.93 5.42,105.93 5.36,106 5.36,106.19 5.41,106.25 6.13,106.25 6.38,105.99 8.25,105.99 8.57,106.31 10.13,106.31
+20V_TBTA_VBUS on VCC: 19.21,95.7 18.73,96.19 18.73,98.73 15.53,101.93 14.01,101.93 12.1,103.83 8.04,103.83 7.53,104.34 6.64,104.34 6.41,104.57 6.41,109.7 6.64,109.93 22.43,109.93 23.43,108.93 23.43,95.94 23.19,95.7
+20V_TBTA_VBUS_1 on TOP (solid shape): 23.89,94.03 23.89,92.62 22.93,91.65 22.59,91.62 22.44,91.32 20,91.32 19.74,91.58 19.74,93.99 19.87,94.12 23.81,94.12
+20V_TBTA_VBUS_1 on BOTTOM (solid shape): 62.58,102.34 62.58,101.3 63.01,100.86 63.01,100.73 62.82,100.54 62.65,100.54 62.6,100.59 62.59,100.59 62.11,101.08 62.11,101.49 62.21,101.59 62.21,102.36 62.27,102.43 62.49,102.43
+20V_TBTA_VBUS_1 on BOTTOM (solid shape): 65.21,107.96 65.21,105.87 64.98,105.64 63.73,105.64 63.31,105.22 62.71,105.22 62.68,105.26 62.68,105.45 62.55,105.58 62.28,105.58 62.21,105.64 62.21,105.67 62.21,105.76 62.18,105.85 62.17,105.86 62.17,105.96 62.23,106.02 62.55,106.02 62.68,106.15 62.68,106.4 62.74,106.46 62.93,106.46 63.12,106.66 63.12,106.85 63.5,107.23 63.5,107.54 63.69,107.73 63.69,107.84 64,108.15 65.02,108.15
+20V_TBTA_VBUS_1 on TOP: 70.29,109.73 70.15,109.59 69.57,109.59 69.31,109.33 69.31,106.98 69.19,106.86 67.9,106.86 67.56,106.51 67.56,105.99 67.18,105.61 63.3,105.61 62.92,105.99 62.92,109.36 62.44,109.85 62.44,112.32 61.97,112.79 61.97,113.52 62.19,113.74 64.38,113.74 64.46,113.67 64.46,113.66 64.5,113.62 64.5,112.14 64.91,111.73 66.29,111.73 66.65,111.38 70.11,111.38 70.29,111.2
+20V_TBTA_VBUS_1 on IN3: 20.45,93.19 48.41,93.19 57.64,102.42 62.03,102.42 62.37,102.76 62.37,107.91 62.61,108.15 67.22,108.15 67.53,107.84 67.53,99.04 53.78,85.29 20.56,85.29 20.12,85.73 20.12,92.87
+20V_VBUS_DC_SS on TOP (solid shape): 75.71,111.87 75.71,109.38 75.24,108.91 75.24,104.72 74.99,104.47 72.45,104.47 70.85,106.07 70.85,111.77 71.04,111.96 75.62,111.96
+DV33_18 on TOP (solid shape): 294,22.37 294.96,22.37 295,22.33 295,21.83 294.97,21.8 293.62,21.8 293.16,22.26 292.27,22.26 292.2,22.33 292.2,22.45 292.23,22.48 293.88,22.48
+VCC_CORE on TOP (solid shape): 108.97,117.23 116.07,117.23 119.63,113.68 121.79,113.68 122.36,113.1 122.36,110.82 121.98,110.44 117.85,110.44 116.77,111.52 115.88,111.52 114.93,110.56 107.18,110.56 106.55,111.2 106.55,113.48 104.97,115.06 103.48,115.06 103.39,115.14 103.39,117.37 103.52,117.5 108.71,117.5
+VCC_CORE on BOTTOM (solid shape): outline of 109 points within 103.39,110.44 122.36,117.39
+VCC_CORE on BOTTOM (solid shape): outline of 1012 points within 149.26,103.62 157.51,106.12
+VCC_CORE on BOTTOM (solid shape): outline of 1102 points within 157.02,93.43 166.15,96.46
+VCC_CORE on BOTTOM (solid shape): outline of 1196 points within 157.06,103.62 165.96,108.07
+VCC_CORE on TOP: outline of 147 points within 149.16,93.36 165.85,123.39
+VCC_CORE on BOTTOM: 158.34,110.65 158.34,109.95 158.21,109.82 155.48,109.82 155.35,109.95 155.35,117.27 152.82,119.81 152.82,123.3 152.9,123.39 157.57,123.39 157.87,123.09 157.87,121.66 159.95,119.58 160.52,119.58 161.29,118.81 161.29,116.1 160.71,115.52 158.43,115.52 157.58,114.67 157.58,111.41
+VCC_CORE on IN1: outline of 101 points within 103.62,93.44 165.58,117.29
+VCC_CORE on VCC: 154.34,93.29 153.71,93.93 138.34,93.93 135.99,96.28 132.17,96.28 131.86,95.96 107.35,95.96 103.69,99.62 103.69,118.06 107.35,118.06 115.63,126.33 115.63,129.64 117.39,131.39 127.33,131.39 133.05,125.68 160.97,125.68 160.97,120.49 165.29,116.17 165.29,93.29
+VCC_CORE on IN2: outline of 122 points within 103.39,93.55 165.83,122.76
+VCC_GT on BOTTOM (solid shape): 137.54,108.38 137.54,98.4 137.34,98.2 132.68,98.2 131.29,96.8 131.29,95.28 129.45,93.44 129.45,93.42 128.71,92.68 128.71,92.4 124.39,88.08 124.39,85.86 123.95,85.42 116.84,85.42 116.45,85.8 116.45,87.26 116.52,87.32 117.47,87.32 117.47,88.21 116.14,88.21 115.57,88.78 115.57,94.43 116.52,95.39 117.51,95.39 117.52,95.34 117.79,95.09 118.07,95.34 118.08,95.39 121.76,95.39 122.44,96.07 122.44,103.66 122.61,103.83 131.88,103.83 132.14,104.09 132.14,106.14 132.18,106.15 132.26,106.18 132.33,106.23 132.39,106.25 132.46,106.23 132.97,106.29 132.87,106.8 132.83,106.88 132.85,106.96 133.5,107.61 133.52,107.6 133.79,107.71 133.89,107.98 133.89,108 134.38,108.49 137.44,108.49
+VCC_GT on TOP: outline of 251 points within 116.45,82.5 149.28,112.05
+VCC_GT on BOTTOM: outline of 134 points within 136.92,98.15 149.26,109.6
+VCC_SA on TOP (solid shape): 167.01,134.44 170.75,134.44 170.87,134.31 170.87,133.3 169.92,133.3 169.92,132.41 170.87,132.41 170.87,131.2 170.43,130.76 169.6,130.76 167.62,128.78 165.74,128.78 165.67,128.85 165.67,131.39 165.79,131.52 165.79,134.68 165.91,134.8 166.66,134.8
+VCC_SA on BOTTOM (solid shape): 168.59,133.89 168.59,130.51 168.44,130.36 165.69,130.36 165.55,130.5 165.55,131.31 165.78,131.53 165.78,131.58 165.79,131.58 165.79,133.9 165.9,134.02 168.46,134.02
+VCC_SA on BOTTOM (solid shape): outline of 463 points within 165.91,103.64 169.55,106.16
+VCC_SA on TOP: 167.13,96.43 167.13,99.42 166.11,100.43 166.11,104.02 166.56,104.47 166.56,105.55 166.24,105.86 166.24,106.06 166.43,106.25 166.62,106.25 166.8,106.42 166.8,110.12 166.6,110.32 166.6,112.86 166.26,113.19 166.26,115.69 166.29,115.72 167.35,115.72 167.79,115.27 167.79,112.59 168.14,112.24 168.14,106.5 168.59,106.06 168.59,104.21 168.82,103.99 168.82,102.63 168.46,102.28 168.46,96.08 168.32,95.94 167.62,95.94
+VCC_SA on BOTTOM: 167.72,93.77 167.66,93.83 167.66,95.81 167.41,96.05 167.41,96.34 167.53,96.45 169.8,96.45 169.93,96.32 169.93,94.67 169.73,94.46 169.46,94.46 169.44,94.49 169.39,94.58 169.31,94.64 169.04,94.64 168.43,94.03 168.2,94.03 168.15,93.97 168.14,93.97 167.93,93.77
+VCC_SA on VCC: 165.79,93.29 165.79,116.38 161.48,120.7 161.48,129.89 164.5,132.92 169.37,132.92 171.38,130.91 171.38,123.41 170.82,122.85 170.82,104.85 170.64,104.67 169.84,104.67 169.17,104 169.17,103.11 169.98,102.29 169.98,95.05 168.23,93.29
+VCC_SA on IN2: 167.64,95.9 167.38,96.15 167.38,96.47 167.19,96.66 166.11,96.66 165.98,96.78 165.98,110.75 164.52,112.21 164.52,115.77 164.71,115.96 167.95,115.96 168.21,115.71 168.21,112.72 168.52,112.41 169.16,112.41 169.62,111.94 170.61,111.94 170.83,111.73 170.83,104.4 170.21,103.78 169.65,103.82 169.74,103.27 169.79,103.19 169.76,103.11 169.65,102.72 169.96,102.48 169.96,101.33 169.48,100.85 169.48,97.48 169.03,97.04 169.03,96.34 168.98,96.29 168.95,96.3 168.64,96.26 168.49,95.99 168.45,95.92 168.39,95.9
+VCCLDOSRAM_1P24 on BOTTOM: 174.04,96.64 174.04,96.42 174.14,96.32 174.14,95.87 174.05,95.79 174.05,95.63 174.25,95.43 174.25,95.21 174.45,95.01 175.28,95.01 175.41,95.15 175.41,95.42 175.25,95.59 175.25,96.36 174.89,96.71 174.8,96.71 174.72,96.63 174.38,96.63 174.32,96.69 174.1,96.69
+VCCPLL_OC on TOP (solid shape): 168.46,81.93 168.46,81.29 168.71,81.04 168.71,80.34 168.52,80.15 167.76,80.15 167.64,80.27 167.64,81.67 168.02,82.05 168.33,82.05
+VCCPLL_OC on TOP (solid shape): 170.99,68.86 170.99,67.79 171.38,67.4 171.38,67.05 171.2,66.88 168.29,66.88 167.77,67.39 167.77,68.63 168.06,68.92 170.92,68.92
+VCCPLL_OC on TOP: 167.78,93.35 167.67,93.25 167.67,90.27 168.08,89.86 168.46,89.86 168.84,90.24 168.84,93.8 168.65,93.99 168.65,94.38 168.5,94.54 167.85,94.54 167.78,94.47
+VDDA_AVDD1 on TOP: 288.09,55.51 287.69,55.51 287.63,55.44 287.63,55.32 287.69,55.25 288.46,55.25 288.69,55.49 288.69,56.02 289.77,57.1 290.32,57.1 290.38,57.16 290.38,58.75 290.32,58.81 289.81,58.81 289.75,58.75 289.75,57.73 288.29,56.27 288.29,55.7
+VSS_PLL on TOP (solid shape): 251.82,91.49 251.82,90.52 251.6,90.3 251.6,89.44 251.71,89.33 251.71,87.68 251.69,87.65 251.06,87.65 251.04,87.67 251.04,88.61 250.81,88.84 250.74,88.84 250.7,88.88 250.7,89.23 251.21,89.74 251.21,90.47 251.47,90.73 251.47,91.49 251.57,91.59 251.72,91.59
GND on TOP (solid shape): 96.71,54.68 96.71,53.73 96.45,53.48 92.07,53.48 91.37,54.18 91.37,54.75 96.64,54.75
GND on TOP (solid shape): 129.34,105.36 129.34,103.96 123.25,103.96 122.99,104.21 122.99,107.52 123.5,108.02 126.68,108.02
GND on TOP (solid shape): 279.08,54.56 279.08,50.81 278.32,50.81 277.93,51.19 277.93,54.56 278.06,54.68 278.95,54.68
GND on TOP (solid shape): 301.43,58.24 301.43,57.35 301.05,56.97 300.03,56.97 299.78,57.22 299.78,58.62 301.05,58.62
GND on TOP (solid shape): 111.56,109.74 111.56,108.72 111.37,108.53 108.07,108.53 107.88,108.72 107.88,109.8 108.01,109.93 111.37,109.93
GND on TOP (solid shape): 122.17,84.47 122.17,83.51 122.04,83.39 119.12,83.39 118.99,83.51 118.99,84.34 119.5,84.85 121.79,84.85
GND on TOP (solid shape): 144.14,105.55 144.14,104.66 144.01,104.53 143,104.53 142.81,104.72 142.81,105.61 142.87,105.67 144.01,105.67
GND on TOP (solid shape): 158.52,95.13 158.52,94 157.51,94 157.51,94.98 157.56,95.03 157.56,95.66 157.67,95.77 157.88,95.77
GND on TOP (solid shape): 202.63,134.19 202.63,133.11 202.5,132.98 200.72,132.98 200.59,133.11 200.59,134.19 200.85,134.44 202.38,134.44
GND on TOP (solid shape): 221.1,37.98 221.1,36.97 220.98,36.84 215.45,36.84 215.26,37.03 215.26,37.99 215.5,38.24 220.85,38.24
GND on TOP (solid shape): 239.69,53.05 239.69,52.14 239.5,51.95 234.93,51.95 234.36,52.52 234.36,55.89 234.55,56.08 236.66,56.08
GND on TOP (solid shape): 281.05,84.1 281.05,81.29 280.86,81.1 279.84,81.1 279.71,81.23 279.71,84.47 279.78,84.53 280.61,84.53
GND on TOP (solid shape): 289.17,63.26 289.17,62.43 288.98,62.24 287.52,62.24 287.33,62.43 287.33,63.19 287.71,63.57 288.86,63.57
GND on TOP (solid shape): 19.24,98.63 19.24,94.88 19.17,94.82 18.73,94.82 18.66,94.88 18.66,96.66 18.03,97.29 18.03,98.75 18.09,98.82 19.05,98.82
GND on TOP (solid shape): 72.48,38.08 72.48,37.03 72.32,36.87 72.32,36.29 71.97,35.94 70.37,35.94 70.23,36.09 70.23,37.92 70.44,38.14 72.42,38.14
GND on TOP (solid shape): 112.51,62.95 112.51,60.1 112.46,60.05 110.06,60.05 108.44,61.66 108.44,61.91 109.55,63.01 112.45,63.01
GND on TOP (solid shape): 112.6,71.92 112.6,70.25 112.43,70.08 108.38,70.08 108.24,70.23 108.24,71.6 108.3,71.66 110.42,71.66 110.73,71.97 112.54,71.97
GND on TOP (solid shape): 144.14,97.29 146.3,97.29 146.3,96.66 144.2,96.66 143.76,96.21 143.51,96.21 143.38,96.34 143.38,97.55 143.51,97.67 143.76,97.67
GND on TOP (solid shape): 166.55,46.48 166.55,45.33 166.26,45.05 159.15,45.05 158.82,45.38 158.82,46.06 159.39,46.63 166.39,46.63
GND on TOP (solid shape): 177.03,130.17 177.03,129.35 176.96,129.27 175.14,129.27 174.99,129.42 174.99,130.06 175.14,130.21 177,130.21
GND on TOP (solid shape): 221.55,134.38 221.55,133.23 221.48,133.17 216.59,133.17 216.47,133.3 216.47,134.12 216.85,134.5 221.42,134.5
GND on TOP (solid shape): 249.16,50.71 249.16,49.55 249.08,49.47 248.76,49.47 248.3,49.93 248.3,50.66 248.04,50.91 248.04,51.34 248.12,51.41 248.47,51.41
GND on TOP (solid shape): 297.24,74.88 297.24,74.5 298,73.73 298,71.45 297.62,71.07 296.03,71.07 295.97,71.13 295.97,74.75 296.22,75 297.11,75
GND on TOP (solid shape): 301.43,59.76 301.43,59.13 301.3,59 300.41,59 299.91,59.51 298.76,59.51 298.64,59.64 298.64,60.27 298.76,60.4 300.79,60.4
GND on TOP (solid shape): 19.43,93.99 19.43,91.64 19.3,91.51 18.41,91.51 18.22,91.7 18.22,92.64 17.91,92.95 17.91,93.84 18.12,94.05 19.36,94.05
GND on TOP (solid shape): 77.98,76.02 78.74,76.02 78.88,75.87 78.88,75.01 78.62,74.75 72.32,74.75 72.07,75 72.07,75.77 72.32,76.02 77.97,76.02
GND on TOP (solid shape): 161.86,96.53 160.9,96.53 160.65,96.28 160.65,95.75 160.93,95.47 160.93,94 159.93,94 159.93,95.28 160.27,95.62 160.27,97.42 161.86,97.42
GND on TOP (solid shape): 213.73,134.25 213.73,132.77 213.49,132.53 212.84,132.53 212.49,132.89 211.71,132.89 211.53,133.06 211.53,134.21 211.77,134.44 213.53,134.44
GND on TOP (solid shape): 229.54,126.44 229.54,125.84 229.34,125.65 229.34,125.13 229.22,125 228.07,125 227.92,125.16 227.92,126.41 228.06,126.55 229.42,126.55
GND on TOP (solid shape): 72.32,117.8 72.32,116.79 72.83,116.28 72.83,113.17 72.77,113.1 70.48,113.1 70.16,113.42 70.16,115.58 71.18,116.6 71.18,117.68 71.37,117.87 72.26,117.87
GND on TOP (solid shape): 142.87,101.99 146.81,101.99 146.81,100.4 143.31,100.4 142.81,100.91 142.81,101.29 142.55,101.55 142.3,101.55 142.17,101.67 142.17,102.12 142.3,102.25 142.62,102.25
GND on TOP (solid shape): 154.74,103.45 155.13,103.45 155.25,103.32 155.25,102.56 155.13,102.44 153.54,102.44 153.47,102.5 153.47,103.71 153.86,104.09 154.11,104.09
GND on TOP (solid shape): 53.84,106.19 53.84,105.78 53.92,105.71 54.67,105.71 54.73,105.64 54.73,105.12 54.67,105.06 53.23,105.06 53.16,105.14 53.16,106.23 53.21,106.28 53.76,106.28
GND on TOP (solid shape): 114.77,78.75 114.77,77.58 114.68,77.49 114.32,77.49 114.02,77.78 111.41,77.78 110.71,77.08 110.13,77.08 110.06,77.15 110.06,78.2 110.11,78.24 110.62,78.24 111.44,79.06 114.46,79.06
GND on TOP (solid shape): 125.74,132.13 125.74,129.46 125.61,129.33 125.3,129.33 124.82,129.8 124.82,130.27 124.98,130.43 124.98,131.1 124.98,131.1 124.98,132.15 125.1,132.28 125.59,132.28
GND on TOP (solid shape): 127.81,132.13 127.81,131.94 127.69,131.82 127.6,131.82 127.59,131.81 127.55,131.81 127.43,131.69 127.43,128.92 127.3,128.79 126.72,128.79 126.67,128.84 126.67,132.13 126.81,132.27 127.67,132.27
GND on TOP (solid shape): 164.46,133.93 165.54,133.93 165.67,133.8 165.67,131.65 165.34,131.32 165.34,129.38 165.51,129.21 165.51,128.83 165.47,128.78 164.43,128.78 164.23,128.98 164.23,133.82 164.36,133.94 164.45,133.94
GND on TOP (solid shape): 180.58,135.46 180.58,134.52 180.49,134.44 179.57,134.44 179.38,134.25 179.38,134 179.1,133.72 177.44,133.72 177.29,133.87 177.29,134.37 177.1,134.56 177.1,135.45 177.18,135.53 180.51,135.53
GND on TOP (solid shape): 201.18,35.25 201.18,34.6 201.67,34.11 201.67,31.89 201.48,31.7 198.34,31.7 198.31,31.74 198.31,34.43 199.17,35.29 201.14,35.29
GND on TOP (solid shape): 53.81,103.7 53.81,103.32 53.95,103.18 54.85,103.18 54.99,103.04 54.99,102.47 54.85,102.33 54.85,101.62 54.54,101.31 53.13,101.31 52.99,101.44 52.99,103.65 53.13,103.78 53.72,103.78
GND on TOP (solid shape): 85.38,136.73 85.38,136.22 85.34,136.18 81.87,136.18 81.78,136.19 81.69,136.18 76.97,136.18 76.88,136.28 76.88,136.77 76.91,136.8 85.3,136.8
GND on TOP (solid shape): 164.38,105.76 164.38,105.75 164.44,105.67 164.53,105.61 164.53,105.6 164.65,105.48 164.65,104.66 164.59,104.59 163.57,104.59 163.53,104.63 163.53,106.02 163.66,106.15 163.99,106.15
GND on TOP (solid shape): 269.15,55.9 269.68,55.9 270.04,55.55 271.56,55.55 271.74,55.73 271.74,55.93 272.28,55.93 272.39,55.82 272.39,54.63 272.21,54.46 268.61,54.46 268.44,54.63 268.44,56.11 268.94,56.11
GND on TOP (solid shape): 112.97,106.16 112.97,105.16 113.53,104.59 119.57,104.59 120.07,104.09 120.07,101.67 119.69,101.29 118.68,101.29 118.55,101.42 113.41,101.42 113.03,101.8 109.66,101.8 108.71,102.75 108.71,106.12 109.02,106.44 112.7,106.44
GND on TOP (solid shape): 84.47,48.5 85.67,48.5 85.74,48.44 85.74,45.26 85.61,45.13 83.13,45.13 83,45.26 83,46.48 82.93,46.56 82.35,46.56 82.24,46.67 82.24,48.79 82.35,48.91 84.06,48.91
GND on TOP (solid shape): 170.26,102.99 170.26,101.86 170.47,101.65 170.77,101.65 170.9,101.53 170.9,101.04 170.77,100.92 170.49,100.92 170.36,101.04 170.36,101.35 170.1,101.61 168.78,101.61 168.72,101.67 168.72,102.24 168.94,102.46 168.94,103.03 169.06,103.15 170.1,103.15
GND on TOP (solid shape): 95.04,71.32 95.04,71.04 94.61,70.61 94.61,68.84 93.28,67.51 90.55,67.51 90.48,67.57 90.48,68.21 91.05,68.78 91.68,68.78 92.07,69.17 92.07,71.19 92.26,71.38 94.98,71.38
GND on TOP (solid shape): 151.18,106.69 151.18,106.37 151.07,106.25 150.62,106.25 150.49,106.12 150.49,105.74 150.69,105.53 151.02,105.53 151.02,104.61 150.02,104.61 150.02,105.57 150.24,105.78 150.24,106.12 150.11,106.25 149.73,106.25 149.6,106.37 149.6,106.69 149.7,106.78 151.09,106.78
GND on TOP (solid shape): 161.31,124.9 161.31,122.67 161.55,122.43 161.55,121.59 161.39,121.42 160.88,121.42 160.71,121.25 158.67,121.25 157.88,122.03 157.88,123.34 157.68,123.53 150.04,123.53 149.99,123.59 149.99,124.13 150.01,124.15 157.01,124.15 157.41,124.15 158.23,124.98 161.23,124.98
GND on TOP (solid shape): 201.81,111.01 201.96,110.88 202.15,110.84 202.66,110.33 202.66,109.32 202.45,109.1 201.04,109.1 200.91,109.23 200.91,109.93 200.27,110.56 200.27,111.01
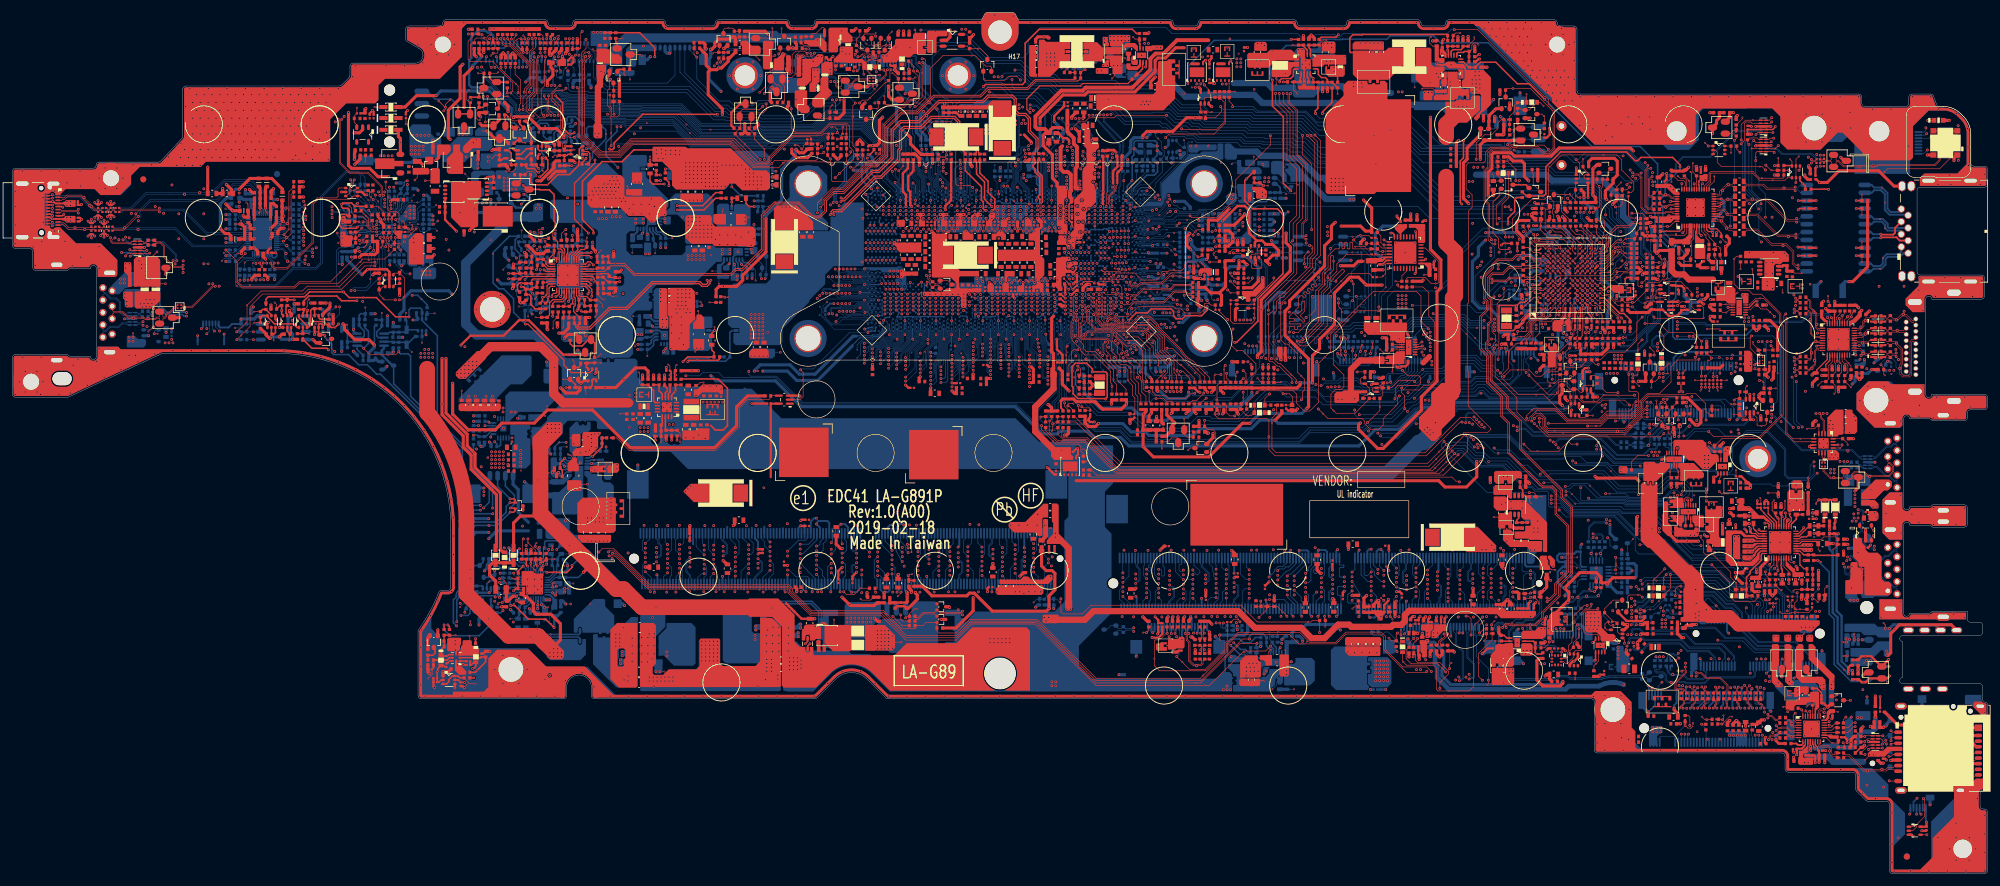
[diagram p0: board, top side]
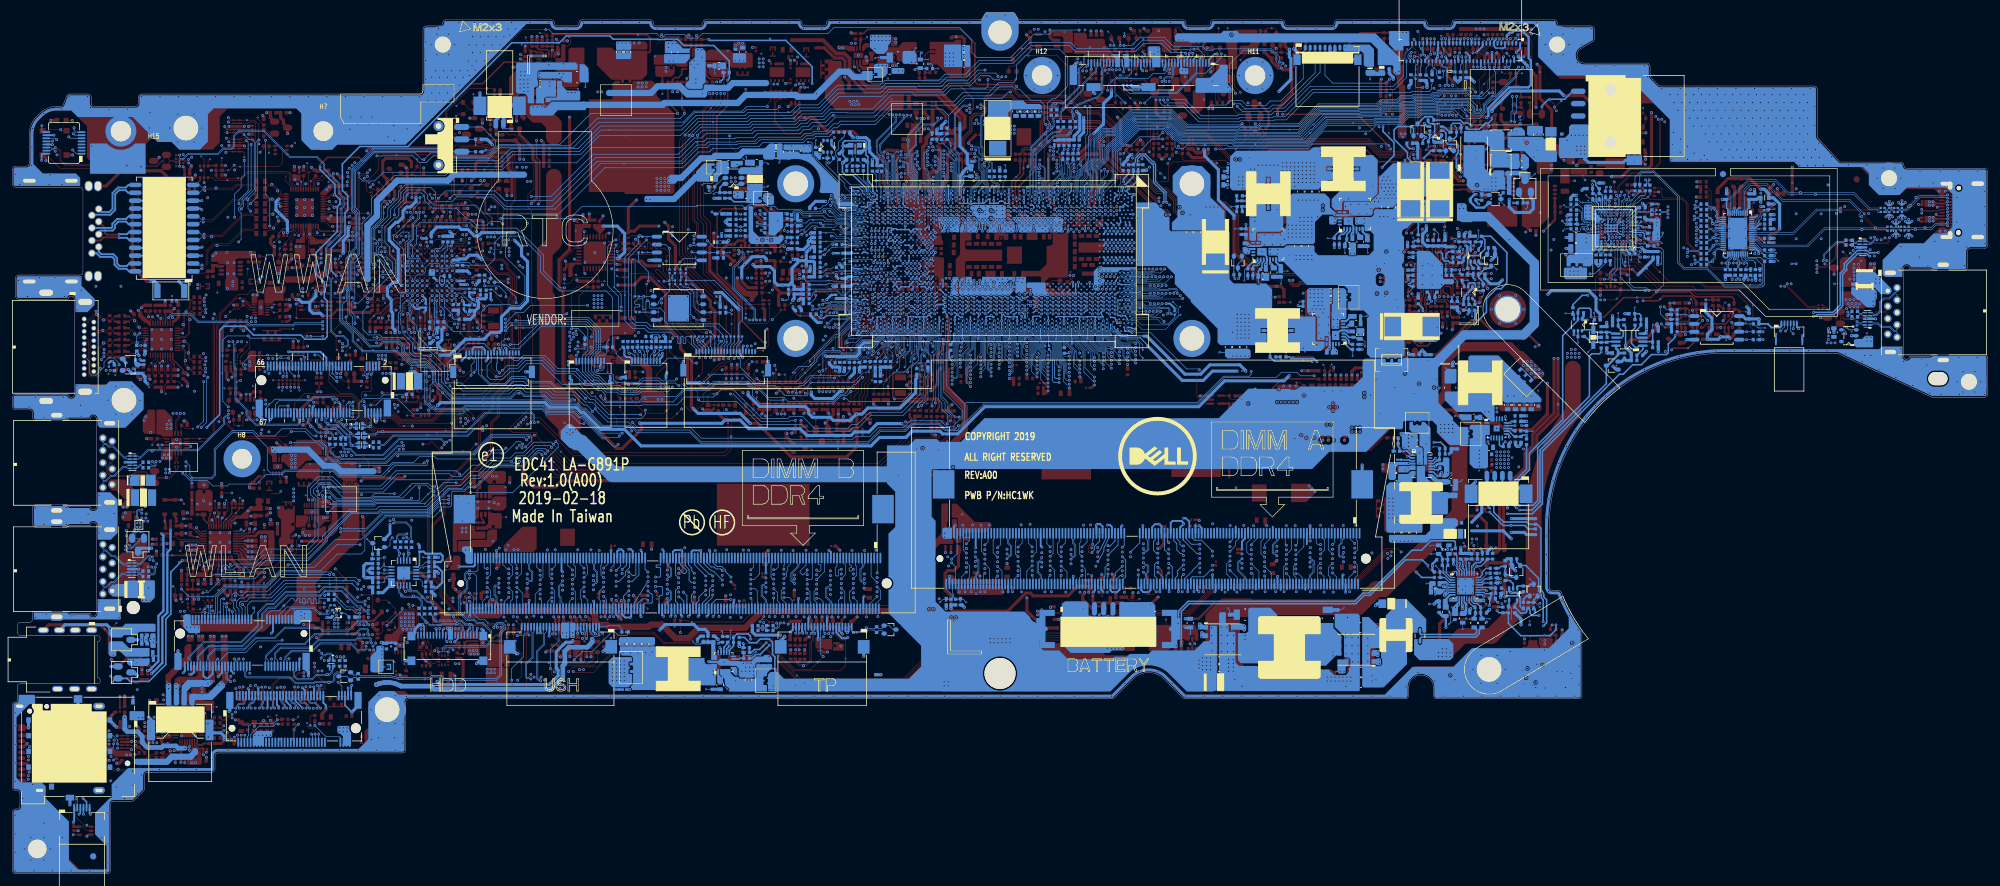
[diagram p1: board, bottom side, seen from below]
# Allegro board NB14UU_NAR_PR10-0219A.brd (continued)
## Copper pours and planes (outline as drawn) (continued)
GND on TOP (solid shape): 286.94,100.03 286.94,98.96 286.86,98.88 286,98.88 285.68,98.56 284.86,98.56 284.54,98.24 284.54,96.15 284.67,96.02 284.67,94.37 284.54,94.24 282.7,94.24 282.57,94.37 282.57,96.21 283.01,96.66 283.01,99.13 282.7,99.45 279.78,99.45 279.71,99.51 279.71,100.53 279.84,100.66 286.32,100.66
GND on TOP (solid shape): 63.03,103.86 63.03,103.53 62.88,103.37 62.88,102.67 62.79,102.58 62.23,102.58 62.17,102.64 62.18,102.94 61.97,103.14 61.53,103.58 61.53,103.9 61.59,103.95 62.94,103.95
GND on TOP (solid shape): 98.85,112.32 98.85,109.69 99.12,109.42 99.2,109.42 104.77,109.42 105.66,108.53 105.66,106.44 105.47,106.25 104.64,106.25 103.63,105.23 103.12,105.23 102.04,106.31 99.5,106.31 98.17,107.64 93.47,107.64 92.86,108.25 92.86,111.57 94.2,112.91 98.26,112.91
GND on TOP (solid shape): 167.32,59.71 167.32,57.63 167.23,57.55 166.55,57.55 166.37,57.37 166.37,54.68 166.26,54.58 165.67,54.58 165.12,55.13 161.79,55.13 160.9,56.02 160.9,56.53 161.22,56.84 163.59,56.84 166.55,59.8 167.23,59.8
GND on TOP (solid shape): 110.26,94.09 110.26,94 110.19,93.8 110.26,93.6 110.26,90.34 110.26,90.34 110.26,89.59 109.41,88.74 109.41,85.1 108.9,84.59 106.29,84.59 106.1,84.78 106.1,90.01 105.85,90.27 105.85,94.5 106.04,94.69 109.66,94.69
GND on TOP (solid shape): 158.09,106.88 158.22,106.85 158.34,106.88 158.34,106.88 158.53,106.88 158.73,106.68 158.73,105.98 158.26,105.51 158.26,104.61 157.26,104.61 157.26,105.53 157.53,105.53 157.73,105.74 157.73,106.56 157.88,106.7 157.99,106.88 158.09,106.88
GND on TOP (solid shape): 298.05,50.26 298.05,49.59 298.17,49.48 298.2,49.48 298.76,49.48 298.89,49.35 298.89,45.29 298.76,45.16 296.22,45.16 296.1,45.29 296.1,47.32 296.22,47.44 296.63,47.44 296.89,47.7 296.89,49.43 296.91,49.54 296.89,49.66 296.89,50.14 297.11,50.37 297.95,50.37
GND on TOP (solid shape): 160.46,103.32 160.46,102.5 160.4,102.44 159.76,102.44 159.7,102.5 159.7,102.88 159.57,103.01 159.06,103.01 158.94,102.88 158.94,102.5 158.87,102.44 158.24,102.44 158.17,102.5 158.17,103.39 158.24,103.45 158.87,103.45 159.51,104.09 159.7,104.09
GND on TOP (solid shape): 124.14,39.88 124.14,30.35 123.92,30.14 101.5,30.14 101.34,30.3 101.34,40.27 101.6,40.52 103.56,40.52 103.94,40.14 103.94,33.92 103.44,33.41 103.44,32.33 103.63,32.14 105.12,32.14 106,33.03 110.47,33.03 111,33.56 111,37.84 111.18,38.01 114.12,38.01 114.33,37.8 114.33,33.95 114.72,33.56 120.01,33.56 120.77,34.32 120.77,41.32 120.81,41.36 122.66,41.36
GND on TOP (solid shape): 162.62,105.42 162.62,104.48 162.5,104.23 162.62,103.98 162.62,103.77 162.47,103.62 162.2,103.62 162.12,103.7 162.12,103.97 162.24,104.25 162.09,104.51 162.09,105.53 162.5,105.53
GND on TOP (solid shape): 163.48,95.63 163.48,95.39 163.47,95.38 163.45,95.32 163.44,95.25 163.44,95.03 163.44,95.03 163.44,94.05 163.38,93.99 162.3,93.99 162.3,94.94 162.38,95.02 162.71,95.02 162.72,95.02 162.99,95.08 163.05,95.34 163.05,95.35 163.05,95.66 163.15,95.76 163.35,95.76
GND on TOP (solid shape): 208.78,133.11 208.78,131.71 208.91,131.58 209.67,131.58 209.67,130.06 208.97,130.06 208.78,129.87 208.78,128.6 208.91,128.47 208.91,127.45 209.04,127.33 210.37,127.33 210.43,127.26 210.43,126.76 210.37,126.69 207.81,126.69 207.72,126.78 207.72,127.32 207.73,127.33 208.05,127.33 208.16,127.33 208.43,127.59 208.43,128.36 208.41,128.36 208.41,128.54 208.53,128.66 208.53,129.87 208.34,130.06 208.15,130.06 208.15,131.84 207.48,132.51 207.48,133.34 207.56,133.42 208.47,133.42
GND on TOP (solid shape): 147.38,106.69 147.38,106.37 147.26,106.25 146.96,106.25 146.81,106.1 146.81,105.99 146.8,105.92 146.81,105.79 146.9,105.68 146.98,105.62 147.06,105.53 147.4,105.53 147.4,104.61 146.4,104.61 146.4,105.57 146.55,105.72 146.55,106.12 146.43,106.25 146.11,106.25 145.98,106.37 145.98,106.69 146.11,106.82 147.25,106.82
GND on TOP (solid shape): 241.8,60.34 244.34,60.34 247.91,56.77 247.91,52.09 247.79,51.96 247.35,51.96 247.24,52.06 247.24,53.8 247.1,53.94 245.09,53.94 244.9,54.14 242.69,54.14 242.64,54.19 242.64,55.22 242.72,55.31 244.2,55.31 244.36,55.46 244.36,56.15 244.44,56.23 245.13,56.23 245.23,56.33 245.23,57.1 245.11,57.22 244.09,57.22 243.71,57.6 243.71,58.62 243.52,58.81 241.36,58.81 241.23,58.68 239.77,58.68 239.26,59.19 239.26,60.84 239.39,60.97 241.17,60.97
GND on TOP (solid shape): 233.3,130.86 234.36,130.86 234.79,130.42 234.79,130.05 234.93,129.91 237.61,129.91 238.82,128.7 238.82,124.29 237.66,123.14 237.49,123.14 237.04,122.69 237.04,122.24 236.49,121.69 236.39,121.69 236.08,122.01 236.08,122.22 237.21,123.35 237.21,125.83 236.98,126.06 235.75,126.06 235.46,126.35 235.46,126.98 235.39,127.05 234.25,127.05 234.18,127.11 234.18,128.12 234.54,128.48 234.54,129.98 234.36,130.16 231.96,130.16 231.54,130.58 230.02,130.58 229.83,130.77 229.83,130.99 229.94,131.11 230.16,131.11 230.38,130.88 231.35,130.88 231.71,131.24 232.92,131.24
GND on TOP (solid shape): 161.22,106.06 161.22,105.8 161.09,105.67 160.84,105.67 160.8,105.64 160.78,105.64 160.78,105.61 160.71,105.55 160.71,104.59 160.65,104.53 160.17,104.53 160.16,104.53 160.06,104.55 159.96,104.53 159.95,104.53 159.7,104.53 159.63,104.59 159.63,105.55 159.7,105.61 159.93,105.61 159.94,105.61 160.06,105.58 160.18,105.61 160.21,105.61 160.3,105.68 160.35,105.76 160.78,106.18 161.09,106.18
GND on TOP (solid shape): 170.93,99.54 170.93,99.13 170.81,99.01 170.33,99.01 170.24,98.92 170.24,97.77 170.36,97.64 170.95,97.64 171.2,97.39 171.48,97.39 171.58,97.28 171.58,96.78 171.51,96.7 171.23,96.7 171.13,96.8 171.13,97.01 171.04,97.1 170.28,97.1 170.14,96.95 170.14,96.65 170.03,96.55 169.68,96.55 169.48,96.34 169.48,94.8 169.65,94.63 169.65,94.29 169.54,94.18 168.9,94.18 168.84,94.24 168.84,94.5 168.46,94.88 167.95,94.88 167.89,94.94 167.89,95.45 167.95,95.51 168.52,95.51 168.59,95.58 168.59,99.45 168.71,99.58 169.29,99.58 169.43,99.72 170.74,99.72
GND on TOP (solid shape): 305.28,42.1 305.88,41.4 306.65,41.9 309.68,41.9 309.95,41.96 310.18,42.18 310.23,42.2 315.58,42.2 315.58,41.12 315.58,41.09 301.57,41.09 301.57,44.36 305.28,44.36
GND on TOP (solid shape): 307.9,96.59 308.02,96.56 308.15,96.55 310.13,96.55 315.8,96.55 317.27,96.55 318.05,96.55 318.26,96.46 318.35,96.25 318.35,93.35 318.26,93.14 318.05,93.05 317.27,93.05 310.22,93.05 309.45,93.55 308.85,92.85 308.85,90.76 306.93,90.76 305.79,91.89 305.79,92.9 307.9,95.01
GND on TOP (solid shape): 166.43,105.55 166.43,104.47 166.14,104.18 166.1,104.15 165.98,104.02 165.98,100.02 166.68,99.32 166.68,96.72 166.05,96.09 166.05,95.84 166.05,95.84 166.05,95.61 166.2,95.45 166.53,95.45 166.53,93.98 166.02,93.98 166.02,94.33 165.9,94.46 165.9,94.5 165.86,94.5 165.79,94.56 165.29,94.56 165.22,94.5 165.18,94.5 165.18,94.46 165.13,94.41 165.13,94 164.75,94 164.75,94.98 164.86,95.09 165.27,95.09 165.44,95.25 165.44,95.68 165.16,95.96 165.16,98.75 164.9,99.01 159.25,99.01 159.19,99.07 159.19,100.78 159.25,100.85 164.9,100.85 165.16,101.1 165.16,102.18 165.02,102.32 164.24,102.32 164.14,102.42 164.14,103.43 164.19,103.48 164.6,103.48 164.85,103.73 164.85,103.91 165.35,104.4 165.85,104.4 165.97,104.52 165.97,105.04 165.82,105.18 165.78,105.18 165.46,105.5 165.46,105.62 165.36,105.72 165.36,106.05 165.46,106.15 165.83,106.15
GND on TOP (solid shape): 153.99,106.7 153.99,106.47 153.92,106.41 153.87,106.33 153.87,106.32 153.79,106.25 153.67,106.25 153.66,106.24 153.64,106.24 153.28,106.02 153.44,105.63 153.44,104.61 152.43,104.61 152.43,105.51 152.48,105.59 152.57,105.6 153,105.92 152.57,106.23 152.48,106.24 152.43,106.33 152.43,106.63 152.58,106.78 153.9,106.78
GND on TOP (solid shape): 161.54,139.2 161.79,139.13 161.98,138.95 162.38,138.25 162.52,138 162.52,136 159.52,133 156.52,136 156.52,138 157.07,138.95 157.26,139.13 157.51,139.2
GND on TOP (solid shape): 156.16,106.88 156.17,106.87 156.22,106.84 156.26,106.82 156.31,106.81 156.36,106.8 156.4,106.8 156.65,106.56 156.65,106.44 156.46,106.25 156.19,106.25 155.95,106.01 155.95,105.67 155.85,105.57 155.85,104.61 154.85,104.61 154.85,104.62 154.85,105.86 154.85,105.89 154.85,105.94 155.11,105.94 155.11,105.89 155.12,105.84 155.14,105.79 155.16,105.74 155.19,105.7 155.23,105.66 155.27,105.63 155.32,105.61 155.37,105.59 155.42,105.59 155.47,105.59 155.52,105.59 155.57,105.61 155.62,105.63 155.66,105.66 155.7,105.7 155.73,105.74 155.75,105.79 155.77,105.84 155.77,105.89 155.77,105.94 155.77,105.99 155.75,106.04 155.73,106.09 155.7,106.13 155.66,106.17 155.62,106.2 155.57,106.22 155.52,106.24 155.47,106.25 155.42,106.25 155.37,106.24 155.32,106.22 155.27,106.2 155.23,106.17 155.19,106.13 155.16,106.09 155.14,106.04 155.12,105.99 155.11,105.94 154.85,105.94 154.85,106.35 155,106.5 155.07,106.5 155.11,106.5 155.15,106.52 155.19,106.54 155.23,106.56 155.26,106.59 155.29,106.63 155.3,106.67 155.32,106.73 155.73,106.73 155.88,106.88
GND on TOP (solid shape): 149.22,103.45 150.55,103.45 151.13,104.02 151.44,104.02 151.52,103.95 151.52,103.71 151.32,103.52 151.13,103.52 151.1,103.49 151.09,103.49 151.09,103.48 151,103.39 151,101.8 151.32,101.48 151.89,101.48 151.98,101.39 151.98,98.54 153.09,97.42 156.14,97.42 156.14,96.53 153.09,96.53 152.9,96.34 152.9,94.82 153.11,94.61 156.52,94.61 156.52,94.05 156.41,93.94 156.39,93.94 156.33,93.94 156.26,93.93 155.68,93.93 155.66,93.93 155.51,93.97 155.36,93.93 155.35,93.93 154.76,93.93 154.75,93.93 154.6,93.97 154.45,93.93 154.44,93.93 154.37,93.93 154.11,93.67 154.11,91.58 153.98,91.45 153.35,91.45 153.21,91.58 153.21,93.11 152.97,93.36 147.24,93.36 147.1,93.49 147.06,93.55 147,93.6 147,93.69 147.08,93.83 147.06,93.99 147.12,94.05 150.3,94.05 150.85,94.61 152.25,94.61 152.46,94.82 152.46,95.45 151.57,96.34 148.65,96.34 148.52,96.47 148.52,96.55 148.53,96.56 148.55,96.68 148.53,96.8 148.52,96.81 148.52,103.39 148.27,103.64 148.27,103.94 148.3,103.97 148.32,104.02 148.39,104.09 148.59,104.09
GND on TOP (solid shape): 305.28,59.3 305.88,58.6 306.65,59.1 309.68,59.1 309.95,59.16 310.18,59.38 310.23,59.4 312.34,59.4 315.28,59.4 315.49,59.31 315.58,59.1 315.58,56.5 315.49,56.29 315.28,56.2 312.34,56.2 310.23,56.2 310.18,56.21 309.95,56.44 309.68,56.5 306.65,56.5 305.88,57 305.28,56.3 305.28,53.98 303.15,53.98 302.05,55.08 302.05,60.46 303.22,61.63 305.28,61.63
GND on TOP (solid shape): 303.43,79.1 308.79,79.1 308.85,79.05 308.85,77.45 309.45,76.75 310.22,77.25 318.55,77.25 318.76,77.16 318.85,76.95 318.85,75.48 318.76,75.27 318.55,75.18 316.28,75.18 315.78,74.97 315.58,74.48 315.58,73.7 315.49,73.49 315.28,73.4 310.23,73.4 310.18,73.42 309.95,73.64 309.68,73.7 306.65,73.7 305.88,74.2 305.28,73.5 305.28,72.44 304.92,72.08 300.78,72.08 297.86,75 297.86,77.67 299.77,79.58 302.96,79.58
GND on TOP (solid shape): 88.52,30.08 91.52,33.1 94.52,30.08 94.52,28.45 94.02,28.45 93.82,28.54 93.73,28.75 93.73,30.1 91.52,32.3 89.32,30.1 89.32,28.75 89.23,28.54 89.02,28.45 88.52,28.45
GND on TOP (solid shape): outline of 992 points within 0.2,0.2 318.85,85.18
GND on TOP (solid shape): outline of 1398 points within 0.2,96.45 318.85,139
GND on BOTTOM (solid shape): 123.19,84.72 123.19,83.64 122.8,83.26 119.31,83.26 119.06,83.51 119.06,84.53 119.38,84.85 123.06,84.85
GND on BOTTOM (solid shape): 177.03,130.17 177.03,129.35 176.96,129.27 175.14,129.27 174.99,129.42 174.99,130.07 175.13,130.21 177,130.21
GND on BOTTOM (solid shape): 221.55,134.38 221.55,133.23 221.48,133.17 219.2,133.17 219.07,133.3 219.07,134.38 219.2,134.5 221.42,134.5
GND on BOTTOM (solid shape): 75.37,115.69 75.44,115.62 75.44,113.98 75.2,113.74 74.53,113.74 74.08,114.19 74.08,115.62 74.73,116.28 75.37,116.28
GND on BOTTOM (solid shape): 300.12,26.17 300.12,24.86 300.05,24.79 297.77,24.79 297.71,24.85 297.71,26.13 297.85,26.26 300.02,26.26
GND on BOTTOM (solid shape): 221.1,37.98 221.1,36.97 220.98,36.84 215.45,36.84 215.26,37.03 215.26,38.11 215.39,38.24 220.85,38.24
GND on BOTTOM (solid shape): 74.39,120.69 74.39,119.47 74.18,119.26 72,119.26 71.84,119.42 71.84,120.75 71.94,120.85 74.23,120.85
GND on BOTTOM (solid shape): 202.66,110.23 202.66,109.39 202.37,109.1 201.04,109.1 200.91,109.23 200.91,110.23 201.04,110.36 202.53,110.36
GND on BOTTOM (solid shape): 194.52,117.74 194.52,117.1 194.32,116.9 191.77,116.9 191.41,116.55 190.14,116.55 189.94,116.75 189.94,117.79 190.01,117.87 194.39,117.87
GND on BOTTOM (solid shape): 67.62,120.72 67.62,119.58 68.26,118.95 69.12,118.95 69.25,118.82 69.25,115.87 69.02,115.64 64.64,115.64 64.13,116.15 64.13,120.6 64.64,121.1 67.24,121.1
GND on BOTTOM (solid shape): 139.71,132.39 139.71,131.88 139.45,131.63 139.45,130.45 139.34,130.33 138.71,130.33 138.61,130.43 138.61,131.65 138.7,131.74 138.7,132.37 138.79,132.47 139.63,132.47
GND on BOTTOM (solid shape): 140.27,43.76 140.27,41.39 139.22,40.34 139.22,38.61 138.6,37.99 135.26,37.99 134.43,38.82 134.43,40.58 134.42,40.59 134.42,43.38 134.93,43.89 140.14,43.89
GND on BOTTOM (solid shape): 180.53,135.48 180.53,133.55 179.47,132.49 178.29,132.49 177.58,133.19 177.58,133.93 177.09,134.43 177.09,135.44 177.24,135.59 180.42,135.59
GND on BOTTOM (solid shape): 201.39,115.21 202.93,115.21 203.03,115.11 203.03,114.2 202.95,114.12 202.03,114.12 201.7,114.46 201.17,114.46 201.07,114.56 201.07,115.14 201.13,115.21 201.39,115.21
GND on BOTTOM (solid shape): 213.63,134.42 213.63,132.72 213.55,132.64 209.77,132.64 209.63,132.78 209.63,133.3 209.71,133.37 210.71,133.37 211.89,134.55 213.51,134.55
GND on BOTTOM (solid shape): 298,47.24 298,44.75 298.32,44.43 298.32,44.05 298.1,43.84 296.82,43.84 296.04,44.62 296.04,47.29 296.16,47.42 297.83,47.42
GND on BOTTOM (solid shape): 92.2,100.59 92.2,94.63 92.07,94.5 88.45,94.5 87.69,95.26 86.36,95.26 86.23,95.39 86.23,96.02 86.29,96.09 87.75,96.09 87.94,96.28 87.94,98.5 90.1,100.66 92.13,100.66
GND on BOTTOM (solid shape): 96.68,136.08 96.68,134.03 95.7,133.05 94.49,133.05 94.36,133.17 94.36,133.67 94.27,133.77 93.47,133.77 93.4,133.83 93.4,136.09 93.5,136.19 96.57,136.19
GND on BOTTOM (solid shape): 166.03,95.98 166.03,95.72 166.14,95.62 166.14,94.85 166.07,94.78 165.91,94.78 165.86,94.83 165.86,95.42 165.39,95.89 165.27,95.89 165.16,96 165.16,96.23 165.26,96.33 165.68,96.33
GND on BOTTOM (solid shape): 165.66,133.81 165.66,131.64 165.26,131.24 165.26,130.54 165.07,130.35 164.43,130.35 164.27,130.51 164.27,131.81 164.4,131.93 164.4,133.87 164.46,133.93 165.54,133.93
GND on BOTTOM (solid shape): 22.03,94.68 22.03,93.73 21.03,92.72 20.76,92.72 19.55,91.51 18.41,91.51 18.09,91.83 18.09,92.72 17.89,92.92 17.89,94.11 18.28,94.5 21.24,94.5 21.51,94.77 21.95,94.77
GND on BOTTOM (solid shape): 96.8,66.43 96.8,63.89 96.54,63.62 95.83,63.62 95.56,63.89 95.56,65.91 95.43,66.04 93.44,66.04 93.37,66.11 92.45,66.11 92.42,66.15 92.42,66.36 92.5,66.44 93.37,66.44 93.46,66.53 96.7,66.53
GND on BOTTOM (solid shape): 104.01,105.99 104.01,104.91 103.94,104.85 102.87,104.85 102.61,104.59 102.61,103.83 102.93,103.52 102.93,102.31 102.87,102.25 102.36,102.25 102.29,102.31 102.29,104.72 102.48,104.91 102.48,105.99 102.55,106.06 103.94,106.06
GND on BOTTOM (solid shape): 104.77,87.76 105.85,87.76 105.92,87.69 105.92,86.3 105.85,86.23 104.77,86.23 104.71,86.3 104.71,87.38 104.46,87.63 103.7,87.63 103.38,87.31 102.22,87.31 102.17,87.36 102.17,87.89 102.24,87.95 104.58,87.95
GND on BOTTOM (solid shape): 117.98,101.04 117.98,99.96 117.92,99.9 116.84,99.9 116.59,99.64 116.59,98.88 116.91,98.56 116.91,97.36 116.84,97.29 116.33,97.29 116.27,97.36 116.27,99.77 116.46,99.96 116.46,101.04 116.52,101.1 117.92,101.1
GND on BOTTOM (solid shape): 124.1,130.67 124.1,130.14 125.62,128.62 127.71,128.62 127.95,128.37 127.95,126.32 127.82,126.18 122.24,126.18 122.12,126.3 122.12,126.5 122.12,126.51 122.12,126.9 122.22,127.09 122.74,127.61 122.74,130.65 122.83,130.74 124.02,130.74
GND on BOTTOM (solid shape): 55.65,106.25 55.65,105.77 55.27,105.39 54.18,105.39 54,105.21 54,103.91 54.16,103.76 54.16,102.31 53.55,102.31 53.54,102.32 53,102.32 52.89,102.44 52.89,105.77 53.15,106.04 53.61,106.04 53.74,105.9 54.85,105.9 55.2,106.26 55.64,106.26
GND on BOTTOM (solid shape): 90.04,57.33 90.04,55.48 90.78,54.75 96.64,54.75 96.71,54.68 96.71,53.73 96.45,53.48 90.59,53.48 89.99,54.08 86.39,54.08 86.11,54.36 86.11,55.76 85.56,56.31 85.56,57.08 85.93,57.44 89.93,57.44
GND on BOTTOM (solid shape): 208.85,133.23 208.85,131.94 209.75,131.04 209.75,128.24 210.35,127.65 210.35,127.35 209.84,126.85 207.62,126.85 207.53,126.93 207.53,127.47 207.07,127.94 207.07,132.92 207.58,133.42 208.66,133.42
GND on BOTTOM (solid shape): 94.94,71.29 94.94,70.9 94.61,70.57 94.61,68.84 94.42,68.65 93.72,68.65 93.02,67.96 92.39,67.96 92.2,67.76 92.2,66.13 92.18,66.11 91.31,66.11 91.24,66.18 91.24,68.72 91.44,68.91 91.75,68.91 92.07,69.23 92.07,70.94 92.26,71.13 93.21,71.13 93.44,71.35 94.88,71.35
GND on BOTTOM (solid shape): 231.08,128.05 231.08,125.6 231.26,125.42 232.8,125.42 232.95,125.27 232.95,124.76 232.88,124.69 232.22,124.69 231.96,124.95 227.48,124.95 227.33,125.11 227.33,126.39 227.49,126.55 229.46,126.55 230.27,127.36 230.27,128.04 230.32,128.09 230.41,128.17 230.96,128.17
GND on BOTTOM (solid shape): 161.48,124.79 161.48,123.45 161.48,123.45 161.48,122.63 161.55,122.56 161.55,121.56 161.43,121.44 160.89,121.44 160.69,121.23 158.68,121.23 158.19,121.73 158.19,123.02 157.67,123.53 152.82,123.53 152.78,123.57 152.78,124.1 153.07,124.4 155.22,124.4 155.8,124.98 161.29,124.98
GND on BOTTOM (solid shape): 109.91,94.31 109.91,90.75 109.47,90.31 108.64,90.31 108.26,89.93 108.26,86.31 107.12,86.31 107.12,86.75 106.99,86.88 106.55,86.88 106.42,86.75 106.42,85.16 107.06,84.53 107.06,83.96 106.99,83.89 106.48,83.89 106.42,83.96 106.42,84.47 106.1,84.78 106.1,86.88 106.23,87.01 106.23,92.02 105.85,92.4 105.85,94.43 106.04,94.63 109.6,94.63
GND on BOTTOM (solid shape): 87.94,67.19 87.94,66.69 88.13,66.49 88.64,66.49 88.77,66.37 89.02,66.37 89.4,65.99 90.29,65.99 90.36,65.92 90.36,65.73 90.29,65.67 89.34,65.67 89.28,65.61 89.09,65.61 88.96,65.73 88.96,65.8 88.77,65.99 88.07,65.99 87.82,65.73 87.82,64.65 88.07,64.4 88.07,64.08 88.01,64.02 87.37,64.02 86.93,64.46 86.93,67.07 87.12,67.26 87.88,67.26
GND on BOTTOM (solid shape): 237.69,130.93 237.69,126.34 237.41,126.07 236.29,126.07 235.81,125.59 235.81,124.59 235.72,124.5 234.83,124.5 234.78,124.55 234.78,126.99 234.56,127.2 234.26,127.2 234.19,127.28 234.19,128.3 234.27,128.39 234.27,129.57 233.93,129.91 227.85,129.91 227.77,129.99 227.77,130.82 228.06,131.11 237.51,131.11
GND on BOTTOM (solid shape): 299.29,118 301.52,117 303.76,118 306.52,118 306.52,113.1 297.52,113.1 297.52,118
GND on BOTTOM (solid shape): 124.14,42.11 124.14,29.71 123.92,29.49 101.55,29.49 101.4,29.64 101.4,41.7 101.71,42.01 105.41,42.01 105.47,41.96 105.47,41.6 105.47,41.6 105.47,39.89 103.94,38.36 103.94,35.13 103.82,35 103.25,35 102.93,34.68 102.93,33.41 103.18,33.16 103.18,32.59 103.69,32.08 105.51,32.08 106.43,32.99 110.36,32.99 110.86,33.49 110.86,37.65 111.18,37.97 114.08,37.97 114.31,37.73 114.31,33.94 114.74,33.52 117.97,33.52 118.02,33.57 120.89,33.57 121.47,34.15 121.47,38.94 121.6,39.06 122.49,39.06 122.61,39.19 122.61,40.08 123.04,40.5 123.04,42.16 123.13,42.25 124,42.25
GND on BOTTOM (solid shape): 305.28,42.1 305.88,41.4 306.65,41.9 309.68,41.9 309.95,41.96 310.18,42.18 310.23,42.2 315.58,42.2 315.58,41.12 315.58,41.09 301.57,41.09 301.57,44.36 305.28,44.36
GND on BOTTOM (solid shape): 197.82,35.1 198.95,35.1 199.53,34.52 199.53,34.45 199.68,34.3 201.54,34.3 201.61,34.36 203.17,34.36 203.55,34.74 204.72,34.74 205.1,34.36 206.18,34.36 206.31,34.49 206.69,34.49 206.81,34.36 206.81,34.14 206.69,34.01 206.21,34.01 206.17,34.05 205.23,34.05 204.78,33.6 202.18,33.6 201.73,33.16 201.73,31.95 201.48,31.7 199.32,31.7 199.07,31.95 199.07,33.92 198.81,34.17 196.4,34.17 196.34,34.24 196.34,34.87 196.85,35.38 197.54,35.38
GND on BOTTOM (solid shape): 93.07,89.25 93.07,86.36 92.64,85.93 89.05,85.93 88.63,86.35 88.63,86.52 88.82,86.52 88.82,86.47 88.83,86.42 88.85,86.37 88.88,86.32 88.91,86.28 88.95,86.24 89,86.21 89.04,86.19 89.1,86.17 89.15,86.17 89.2,86.17 89.25,86.17 89.31,86.19 89.35,86.21 89.4,86.24 89.44,86.28 89.47,86.32 89.5,86.37 89.52,86.42 89.53,86.47 89.53,86.52 89.53,86.58 89.52,86.63 89.5,86.68 89.47,86.72 89.44,86.77 89.4,86.8 89.35,86.83 89.31,86.86 89.25,86.87 89.2,86.88 89.15,86.88 89.1,86.87 89.04,86.86 89,86.83 88.95,86.8 88.91,86.77 88.88,86.72 88.85,86.68 88.83,86.63 88.82,86.58 88.82,86.52 88.63,86.52 88.63,89.96 88.91,90.24 92.09,90.24
GND on BOTTOM (solid shape): 155.23,95.46 155.23,94.72 155.15,94.65 154.49,94.65 154.34,94.5 154.34,93.98 154.21,93.66 154.07,93.52 154.02,93.5 153.97,93.46 153.94,93.42 153.91,93.38 153.45,93.38 153.24,93.52 153.02,93.39 153.01,93.38 152.54,93.38 152.54,93.39 152.32,93.52 152.11,93.39 152.1,93.38 151.72,93.38 151.63,93.48 151.63,93.8 151.63,93.81 152.13,94.31 152.13,95.46 152.24,95.56 155.13,95.56
GND on BOTTOM (solid shape): 307.9,96.59 308.02,96.56 308.15,96.55 310.8,96.55 315,96.55 317.27,96.55 318.05,96.55 318.26,96.46 318.35,96.25 318.35,93.35 318.26,93.14 318.05,93.05 317.27,93.05 310.22,93.05 309.45,93.55 308.85,92.85 308.85,90.76 306.93,90.76 305.79,91.89 305.79,92.92 307.9,95.04
GND on BOTTOM (solid shape): 161.54,139.2 161.79,139.13 161.98,138.95 162.38,138.25 162.52,138 162.52,136 159.52,133 156.52,136 156.52,138 157.07,138.95 157.26,139.13 157.51,139.2
GND on BOTTOM (solid shape): outline of 97 points within 123.25,103.96 131.76,114.37
GND on BOTTOM (solid shape): 305.28,59.3 305.88,58.6 306.65,59.1 309.68,59.1 309.95,59.16 310.18,59.38 310.23,59.4 311.76,59.4 315.28,59.4 315.49,59.31 315.58,59.1 315.58,56.5 315.49,56.29 315.28,56.2 311.76,56.2 310.23,56.2 310.18,56.21 309.95,56.44 309.68,56.5 306.65,56.5 305.88,57 305.28,56.3 305.28,53.98 303.15,53.98 302.08,55.05 302.08,60.45 303.25,61.63 305.28,61.63
GND on BOTTOM (solid shape): 303.93,79.02 306.51,79.02 306.59,79.1 308.85,79.1 308.85,77.45 309.45,76.75 310.22,77.25 318.55,77.25 318.76,77.16 318.85,76.95 318.85,75.48 318.76,75.27 318.55,75.18 316.28,75.18 315.78,74.97 315.58,74.48 315.58,73.7 315.49,73.49 315.28,73.4 310.23,73.4 310.18,73.42 309.95,73.64 309.68,73.7 306.65,73.7 305.88,74.2 305.28,73.5 305.28,72.44 304.92,72.08 300.78,72.08 297.86,75 297.86,77.67 299.77,79.58 303.38,79.58
GND on BOTTOM (solid shape): 88.52,30.08 91.52,33.1 94.52,30.08 94.52,28.45 94.02,28.45 93.82,28.54 93.73,28.75 93.73,30.1 91.52,32.3 89.32,30.1 89.32,28.75 89.23,28.54 89.02,28.45 88.52,28.45
GND on BOTTOM (solid shape): outline of 186 points within 86.93,101.29 120.33,114.95
GND on BOTTOM (solid shape): outline of 205 points within 137.42,94.23 144.53,98.19
GND on BOTTOM (solid shape): outline of 1178 points within 0.2,0.2 318.85,85.19
GND on BOTTOM (solid shape): outline of 1339 points within 0.2,96.45 318.85,139
GND on IN1 (solid shape): 107.09,76.37 107.09,71.32 106.86,71.09 101.17,71.09 101.05,71.22 101.05,76.21 101.36,76.53 106.93,76.53
GND on IN1 (solid shape): 124.11,40.08 124.11,30.34 123.84,30.07 102.81,30.07 102.54,30.34 102.54,31.88 102.73,32.07 105.48,32.07 106.38,32.97 110.34,32.97 110.9,33.53 110.9,37.69 111.19,37.97 114.13,37.97 114.34,37.76 114.34,33.9 114.72,33.53 120.9,33.53 121.5,34.12 121.5,40.06 121.63,40.19 124,40.19
GND on IN1 (solid shape): 180.6,135.46 180.6,134.5 180.5,134.4 179.53,134.4 179.38,134.26 179.38,133.98 179.12,133.71 178.16,133.71 175.61,131.16 175.61,130.35 175.79,130.17 176.12,130.17 176.26,130.03 176.26,129.38 176.12,129.25 174.52,129.25 174.37,129.4 174.37,129.66 174.37,129.66 174.37,131.61 177.06,134.3 177.06,135.39 177.19,135.52 180.54,135.52
GND on IN1 (solid shape): 307.9,96.59 308.02,96.56 308.15,96.55 310.8,96.55 315,96.55 317.27,96.55 318.05,96.55 318.26,96.46 318.35,96.25 318.35,93.35 318.26,93.14 318.05,93.05 317.27,93.05 310.22,93.05 309.45,93.55 308.85,92.85 308.85,90.76 306.95,90.76 305.77,91.93 305.77,92.89 307.9,95.01
GND on IN1 (solid shape): 305.28,59.3 305.88,58.6 306.65,59.1 309.68,59.1 309.95,59.16 310.18,59.38 310.23,59.4 312.96,59.4 315.28,59.4 315.49,59.31 315.58,59.1 315.58,56.5 315.49,56.29 315.28,56.2 312.96,56.2 310.23,56.2 310.18,56.21 309.95,56.44 309.68,56.5 306.65,56.5 305.88,57 305.28,56.3 305.28,53.98 303.17,53.98 302.06,55.08 302.06,60.46 303.23,61.63 305.28,61.63
GND on IN1 (solid shape): 308.85,77.45 309.45,76.75 310.22,77.25 318.55,77.25 318.76,77.16 318.85,76.95 318.85,75.48 318.76,75.27 318.55,75.18 316.28,75.18 315.78,74.97 315.58,74.48 315.58,73.7 315.49,73.49 315.28,73.4 310.23,73.4 310.18,73.42 309.95,73.64 309.68,73.7 306.65,73.7 305.88,74.2 305.28,73.5 305.28,72.46 304.9,72.08 300.81,72.08 297.82,75.07 297.82,77.63 299.3,79.1 308.85,79.1
GND on IN1 (solid shape): outline of 999 points within 0.2,0.2 318.85,85.19
GND on IN1 (solid shape): outline of 268 points within 0.2,96.47 318.85,139
GND on IN2 (solid shape): 213.56,134.41 213.56,132.38 213.45,132.27 210.32,132.27 209.93,131.88 209.93,130.21 209.71,130 207.49,130 207.38,130.11 207.38,134.06 207.78,134.46 213.51,134.46
GND on IN2 (solid shape): 307.9,96.59 308.02,96.56 308.15,96.55 310.8,96.55 315,96.55 317.27,96.55 318.05,96.55 318.26,96.46 318.35,96.25 318.35,93.35 318.26,93.14 318.05,93.05 317.27,93.05 310.22,93.05 309.45,93.55 308.85,92.85 308.85,90.76 306.93,90.76 305.79,91.89 305.79,92.92 307.9,95.04
GND on IN2 (solid shape): 305.28,59.3 305.88,58.6 306.65,59.1 309.68,59.1 309.95,59.16 310.18,59.38 310.23,59.4 312.97,59.4 315.28,59.4 315.49,59.31 315.58,59.1 315.58,56.5 315.49,56.29 315.28,56.2 312.97,56.2 310.23,56.2 310.18,56.21 309.95,56.44 309.68,56.5 306.65,56.5 305.88,57 305.28,56.3 305.28,53.98 303.17,53.98 302.08,55.06 302.08,60.46 303.24,61.63 305.28,61.63
GND on IN2 (solid shape): 303.76,79.1 308.85,79.1 308.85,77.45 309.45,76.75 310.22,77.25 318.55,77.25 318.76,77.16 318.85,76.95 318.85,75.48 318.76,75.27 318.55,75.18 316.28,75.18 315.78,74.97 315.58,74.48 315.58,73.7 315.49,73.49 315.28,73.4 310.23,73.4 310.18,73.42 309.95,73.64 309.68,73.7 306.65,73.7 305.88,74.2 305.28,73.5 305.28,72.44 304.92,72.08 300.79,72.08 297.81,75.07 297.81,77.65 299.77,79.6 303.26,79.6
GND on IN2 (solid shape): outline of 998 points within 0.2,0.2 318.85,85.19
GND on IN2 (solid shape): outline of 1311 points within 0.2,96.46 318.85,139
GND on IN2 (solid shape): outline of 2056 points within 85.72,29.93 130.13,48.46
GND on IN3 (solid shape): 213.56,134.41 213.56,132.38 213.45,132.27 210.32,132.27 209.93,131.88 209.93,130.21 209.71,130 207.49,130 207.38,130.11 207.38,134.06 207.78,134.46 213.51,134.46
GND on IN3 (solid shape): 124.11,40.08 124.11,31.16 123.72,30.77 102.76,30.77 102.54,30.99 102.54,31.88 102.73,32.07 105.48,32.07 106.38,32.97 110.34,32.97 110.9,33.53 110.9,37.69 111.19,37.97 114.13,37.97 114.34,37.76 114.34,33.9 114.72,33.53 120.9,33.53 121.5,34.12 121.5,38.78 121.6,38.88 121.6,38.93 122.86,40.19 124,40.19
GND on IN3 (solid shape): 307.9,96.59 308.02,96.56 308.15,96.55 310.8,96.55 315,96.55 317.27,96.55 318.05,96.55 318.26,96.46 318.35,96.25 318.35,93.35 318.26,93.14 318.05,93.05 317.27,93.05 310.22,93.05 309.45,93.55 308.85,92.85 308.85,90.76 306.93,90.76 305.79,91.89 305.79,92.94 307.9,95.05
GND on IN3 (solid shape): 305.28,59.3 305.88,58.6 306.65,59.1 309.68,59.1 309.95,59.16 310.18,59.38 310.23,59.4 314.16,59.4 315.28,59.4 315.49,59.31 315.58,59.1 315.58,56.5 315.49,56.29 315.28,56.2 314.16,56.2 310.23,56.2 310.18,56.21 309.95,56.44 309.68,56.5 306.65,56.5 305.88,57 305.28,56.3 305.28,53.98 303.15,53.98 302.08,55.05 302.08,60.45 303.25,61.63 305.28,61.63
GND on IN3 (solid shape): 303.75,79.1 308.85,79.1 308.85,77.45 309.45,76.75 310.22,77.25 318.55,77.25 318.76,77.16 318.85,76.95 318.85,75.48 318.76,75.27 318.55,75.18 316.28,75.18 315.78,74.97 315.58,74.48 315.58,73.7 315.49,73.49 315.28,73.4 310.23,73.4 310.18,73.42 309.95,73.64 309.68,73.7 306.65,73.7 305.88,74.2 305.28,73.5 305.28,72.44 304.92,72.08 300.74,72.08 297.82,75 297.82,77.63 299.77,79.58 303.28,79.58
GND on IN3 (solid shape): outline of 997 points within 0.2,0.2 318.85,85.19
GND on IN3 (solid shape): outline of 280 points within 0.2,96.46 318.85,139
GND on TOP: 291.05,42.67 290.24,41.86 286.19,41.86 286.06,41.73 286.06,41.35 286.25,41.16 291.72,41.16 292.17,41.61 292.17,42.57 292.07,42.67
GND on TOP: 80.07,69.54 80.37,69.24 80.37,64.77 80.2,64.59 77.27,64.59 77.02,64.84 77.02,68.39 77.18,68.55 78.59,68.55 78.8,68.76 78.8,69.16 79.18,69.54
GND on TOP: 269.71,41.81 269.03,41.14 268.1,41.14 267.92,41.31 267.92,44.16 268.24,44.48 268.8,44.48 268.98,44.65 268.98,45.6 269.21,45.83 269.64,45.83 269.71,45.77
GND on TOP: 57.72,117.29 57.72,114.75 58.67,113.8 61.78,113.8 62,114.02 64.34,114.02 64.46,114.13 64.46,115.11 64.16,115.41 62.39,115.41 61.46,116.34 59.3,116.34 58.29,117.36 57.78,117.36
GND on TOP: 95.29,135.42 95.41,135.31 96.84,135.31 96.89,135.26 96.89,134.64 96.18,133.93 96.18,133.68 96.09,133.59 94.15,133.59 93.43,134.32 93.43,136.17 93.51,136.25 95.25,136.25 95.29,136.21
GND on TOP: 260.21,80.58 257.06,80.58 256.73,80.92 256.73,81.8 256.97,82.05 260.8,82.05 260.92,81.93 260.92,81.29
GND on TOP: 148.17,120.56 150.53,120.56 150.82,120.27 150.82,118.72 151.93,117.62 151.93,116.05 151.89,116.01 151.38,116.01 151.29,116.1 151.29,116.29 151.05,116.53 150.66,116.53 149.63,117.56 147.4,117.56 147.26,117.7 147.26,119.66
GND on TOP: 104.92,76.19 105.63,76.19 105.85,76.4 105.85,77.16 106.1,77.16 106.1,76.4 106.32,76.19 106.52,76.19 106.6,76.11 106.6,73.37 106.99,72.97 106.99,72.34 106.87,72.21 105.97,72.21 105.85,72.34 105.85,74.25 105.51,74.58 104.92,74.58
GND on TOP: 98.86,73.73 100.52,73.73 101.02,73.23 103.69,73.23 104.2,72.72 104.2,71.32 104.07,71.19 98.99,71.19 98.61,71.57 98.61,73.48
GND on TOP: 132.64,130.17 132.64,130.82 132.71,130.89 134.32,130.89 134.44,130.76 136.34,130.76 136.49,130.91 137.02,130.91 137.08,130.85 137.08,129.44 137,129.36 133.11,129.36 132.64,129.83 132.64,130.17
GND on TOP: 247.04,34.91 248.85,34.91 249.01,34.75 249.01,34.32 249.36,33.97 249.36,33.43 248.85,32.92 246.74,32.92 246.56,33.1 246.56,34.43
GND on BOTTOM: 297.68,64.54 295.92,64.54 295.64,64.25 295.64,59.4 295.97,59.07 297.75,59.07 297.89,59.21 297.89,64.33
GND on BOTTOM: 282.3,29.55 282.57,29.55 282.7,29.68 282.7,30.05 282.82,30.17 284.41,30.17 284.54,30.05 284.54,26.11 284.41,25.98 283.27,25.98 283.14,26.11 283.14,27.88 283.01,28.01 282.3,28.01 282.17,28.13 282.17,29.42
GND on BOTTOM: 284.45,51.76 284.37,51.68 284.37,51.46 284.26,51.35 283.12,51.35 282.64,51.84 282.64,54.15 282.79,54.3 283.45,54.3 283.63,54.48 283.63,55.34 287.34,55.34 287.34,51.84 287.37,51.8 287.33,51.76
GND on BOTTOM: 200.25,84.04 200.17,83.96 198.88,83.96 198.78,84.06 198.78,86.06 198.91,86.2 199.93,86.2 200.25,85.88
GND on BOTTOM: 78.8,68.27 78.8,69.16 79.18,69.54 79.18,71.09 78.81,71.46 78.81,72.45 79.18,72.82 79.18,74.24 78.86,74.56 78.86,75.38 78.99,75.51 79.39,75.51 79.5,75.4 79.5,74.44 79.43,74.38 79.43,72.82 79.88,72.37 79.88,69.73 80.2,69.42 80.2,68.27 80.45,68.02 80.45,65.67 80.11,65.32 77.94,65.32 77.63,65.01 77.63,63.81 77.28,63.46 76.92,63.46 76.57,63.81 76.57,67.47 76.91,67.8 78.33,67.8
GND on BOTTOM: 72.32,74.62 72.07,74.88 72.07,75.77 72.32,76.02 77.97,76.02 78.23,75.77 78.23,74.88 77.97,74.62
GND on BOTTOM: 163.43,62.13 166.51,65.21 170.38,65.21 170.39,65.2 170.39,57.93 169.7,57.24 169.7,46.44 167.66,44.41 135.09,44.41 134.45,43.78 130.35,43.78 129.71,44.41 100.75,44.41 99.88,45.28 99.88,48.44 98.7,49.62 98.7,65.62 99.34,66.26 106.7,66.26 110.83,62.13 ; 2 cut-outs
GND on BOTTOM: 259.07,76.64 259.1,76.6 259.1,73.86 259.01,73.77 257.33,73.77 256.54,74.56 256.54,76.12 257.06,76.64
GND on BOTTOM: 200.71,112.76 200.71,112.13 200.82,112.02 201.65,112.02 202.13,111.54 203.09,111.54 203.22,111.66 203.22,112.76 203.11,112.87 200.82,112.87
GND on BOTTOM: 246.67,81.99 246.87,82.19 248.35,82.19 248.38,82.16 248.38,80.08 248.3,80 245.89,80 245.55,80.34 245.55,81.54 245.99,81.99
GND on BOTTOM: outline of 103 points within 273.89,27.7 291.9,35.07
GND on BOTTOM: 202.5,132.98 200.72,132.98 200.59,133.11 200.59,134.19 200.85,134.44 202.47,134.44 202.67,134.24 202.67,133.14 202.57,133.04 202.56,133.04
GND on BOTTOM: 243.93,52.73 243.93,41.48 243.42,40.97 227.74,40.97 227.62,40.86 208.56,40.86 207.69,39.99 200.71,39.99 199.45,41.24 178.9,41.24 178.27,41.87 178.27,54.98 176.67,56.57 176.67,61.16 176.67,61.2 176.69,61.22 181.4,61.22 185.89,56.73 237.39,56.73 241.83,61.18 247.74,61.18 247.74,59.03 249.04,59.03 249.51,58.55 249.51,52.43 249.16,52.07 249.16,46.85 250.04,45.96 250.04,42.24 249.84,42.04 247.63,42.04 247.29,42.38 247.29,44.86 246.07,46.08 246.07,47.19 246.41,47.53 246.41,48.69 246.29,48.81 246.29,49.15 246.38,49.24 247.08,49.24 247.23,49.4 247.23,49.83 247.05,50.01 246.33,50.01 246.17,50.17 246.17,51.59 246.56,51.98 246.56,53.05 246.43,53.18 244.37,53.18 ; 5 cut-outs
GND on GND1: outline of 411 points within 0.2,0.26 318.8,138.94
GND on GND1: 306.53,124.77 306.53,125.5 306.62,125.71 306.82,125.8 307.62,125.8 307.62,124.77
GND on IN1: 113.47,99.51 112.2,100.78 109.79,100.78 108.52,102.05 108.52,106.11 108.9,106.49 116.02,106.49 118.04,104.47 119.44,104.47 120.07,103.83 120.07,99.9 119.69,99.51
GND on IN1: 109.53,94.56 103.31,94.56 102.29,93.55 102.29,85.54 103.44,84.4 110.42,84.4 111.06,85.04 111.06,93.04
GND on IN1: 5.82,112.12 10.74,112.12 13.79,109.07 33.06,109.07 34.77,107.36 34.77,99.83 33.73,98.79 23.25,98.79 20.03,102.01 6.06,102.01 4.74,103.33 4.74,111.04
GND on IN1: 92.77,104.85 92.77,109.92 94.12,111.26 95.04,111.26 96.76,112.98 101.15,112.98 104.21,109.92 104.21,105.42 102.94,104.14 93.47,104.14
GND on IN1, IN2, IN3: 301.57,41.09 301.57,44.36 305.28,44.36 305.28,42.1 305.88,41.4 306.65,41.9 309.68,41.9 309.95,41.96 310.18,42.18 310.23,42.2 315.58,42.2 315.58,41.12 315.58,41.09
GND on VCC: outline of 83 points within 293.05,41.09 318.8,97.99
GND on VCC: 304.46,109.8 301.03,113.23 295.82,113.23 295.19,113.87 282.1,113.87 280.6,115.37 280.6,125.75 298.22,125.75 298.4,125.67 298.47,125.5 298.47,124.5 298.69,123.97 299.22,123.75 305.83,123.75 306.36,123.97 306.58,124.5 306.58,125.5 306.65,125.67 306.82,125.75 309.85,125.75 309.96,125.72 310.04,125.65 310.11,125.65 310.13,125.6 310.61,124.26 310.87,123.92 311.27,123.8 311.87,123.8 313.32,123.51 314.55,122.68 315.01,122.23 315.83,121 316.12,119.54 316.12,114.85 316.24,114.46 316.56,114.2 316.45,114.2 316.63,114.12 316.82,114.1 318.55,114.1 318.72,114.02 318.8,113.85 318.8,111.45 318.72,111.28 318.55,111.2 308.15,111.2 308.04,111.2 307.93,111.17 307.54,110.9 307.4,110.45 307.4,109.8
GND on VCC: 0.5,77.2 0.29,77.29 0.2,77.5 0.2,83.4 0.29,83.61 0.5,83.7 8.82,83.7 8.87,83.68 9.1,83.46 9.37,83.4 12.4,83.4 13.17,82.9 13.77,83.6 13.77,97.8 13.17,98.5 12.4,98 9.37,98 9.1,97.94 8.87,97.72 8.82,97.7 3.77,97.7 3.56,97.79 3.47,98 3.47,100.55 3.27,101.05 2.77,101.25 0.5,101.25 0.29,101.34 0.2,101.55 0.2,104.6 0.25,104.6 0.25,113.5 0.33,113.67 0.5,113.75 13.03,113.75 13.56,113.97 13.85,114.67 14.02,114.75 23.08,114.75 23.93,113.89 24.46,113.36 32.32,113.36 32.32,112.49 34.12,110.69 39.45,110.69 40.95,109.19 40.95,90.5 24.59,90.5 23.55,89.46 23.55,84.01 16.98,80.94 9.01,77.23 8.95,77.21 8.89,77.2 ; 1 cut-out
GND on VCC: 230.92,43.51 230.42,44.02 178.85,44.02 175.42,47.44 102.4,47.44 100.9,48.95 100.9,59.91 107.5,66.52 107.5,95.45 132.07,95.45 132.38,95.77 135.78,95.77 138.13,93.42 153.5,93.42 154.13,92.78 168.44,92.78 170.34,94.69 171.66,94.69 173.54,92.81 173.54,80.36 178.77,75.13 181.56,75.13 182.58,74.11 184.48,74.11 185.12,73.48 186.01,73.48 202.9,56.59 243.67,56.59 246.44,53.82 246.44,44.88 245.57,44.02 232.68,44.02 232.17,43.51
GND on IN2: 108.77,106.37 115.5,106.37 118.55,103.32 119.69,103.32 120.2,102.82 120.2,101.55 119.95,101.29 119.18,101.29 118.55,100.66 118.55,100.53 117.79,99.77 113.22,99.77 112.2,100.78 109.15,100.78 108.52,101.42 108.52,106.12
GND on IN2: 103.18,95.45 110.42,95.45 111.82,94.05 111.82,84.91 111.31,84.4 106.36,84.4 106.1,84.66 106.1,85.16 104.58,86.69 103.18,86.69 102.29,87.58 102.29,94.56
GND on IN2: 92.64,111.2 92.64,105.36 93.66,104.34 102.93,104.34 104.07,105.48 104.07,110.31 101.4,112.98 94.42,112.98
GND on IN2: 125.89,92.25 125.89,94.12 130.16,98.39 143.17,98.39 147.51,94.05 157.16,94.05 157.79,93.42 169.29,93.42 171.57,91.13 171.57,90.24 172.21,89.61 175.06,89.61 186.02,78.65 186.02,77.58 186.24,77.35 187.32,77.35 188.19,76.48 191.17,76.48 191.23,76.55 206.16,76.55 207.01,75.7 207.51,75.7 207.7,75.51 207.96,75.51 207.97,75.52 214.87,75.52 218.2,72.19 218.77,72.19 226.18,64.78 228.21,64.78 230.35,62.64 231.61,62.64 237.38,56.87 238.78,56.87 243.39,52.26 243.39,45.03 241.74,43.38 179.07,43.38 175.19,47.25 142.62,47.25 140.84,49.03 140.84,52.46 123.06,70.24 123.06,83.83 122.86,84.04 122.86,89.22
GND on IN3: 100.64,104.98 97.85,107.77 93.53,107.77 92.51,108.79 92.51,112.09 93.53,113.1 97.98,113.1 98.74,112.34 98.74,111.07 100.52,109.29 104.05,109.29 104.06,109.28 104.06,105.51 103.53,104.98
GND on IN3: 109.41,95.07 103.44,95.07 102.55,94.18 102.55,84.91 103.31,84.15 109.66,84.15 110.29,84.78 110.29,94.18
GND on IN3: 5.82,112.12 10.74,112.12 13.79,109.07 33.06,109.07 34.77,107.36 34.77,99.9 33.66,98.79 28.93,98.79 27.64,100.08 25.01,100.08 23.98,99.06 22.98,99.06 20.03,102.01 6.06,102.01 4.74,103.33 4.74,111.04
GND on IN3: 113.85,100.15 112.45,101.55 109.66,101.55 107.84,103.36 107.84,109.03 108.11,109.29 111.44,109.29 111.95,108.79 111.95,106.25 113.98,104.21 120.07,104.21 120.84,103.45 120.84,100.66 120.33,100.15
GND on GND2: outline of 417 points within 0.2,0.26 318.8,138.94
GNDA on TOP (solid shape): 287.84,61.48 288.35,61.48 288.35,62.05 289.11,62.05 289.49,61.67 289.49,58.68 289.43,58.62 288.86,58.62 288.83,58.65 287.52,58.65 287.37,58.5 286.85,58.5 286.7,58.64 286.7,58.87 286.7,58.87 286.7,61.67 287.08,62.05 287.84,62.05
GNDA on GND1, GND2: 304.27,28.71 302.42,30.55 297.34,30.55 294.13,33.77 294.13,39.93 292.54,41.52 292.54,49.46 291.76,50.24 289.15,50.24 287.84,51.55 287.84,55.23 287.44,55.64 285.41,55.64 285.28,55.76 285.24,55.76 285.24,57.02 284.16,58.1 284.16,60.83 283.83,61.16 281.57,61.16 281.24,60.83 281.24,58.7 281.62,58.31 281.62,57.3 283.46,55.46 283.46,54.61 283.28,54.43 281.99,54.43 281.42,55 280.15,55 279.33,55.82 279.33,56.76 278.7,57.39 278.7,60.8 279.75,61.86 294.02,61.86 295.08,60.8 295.08,44.86 299.36,40.59 315.75,40.59 315.99,40.43 316.28,40.37 317.75,40.37 317.92,40.3 317.99,40.12 317.99,39 317.92,38.83 317.75,38.75 305.35,38.75 304.61,38.13 305.09,37.29 305.09,31.91 304.61,31.07 305.35,30.44 317.75,30.44 317.92,30.37 317.99,30.2 317.99,28.71
GNDA on VCC: 304.27,28.71 302.42,30.55 297.34,30.55 294.13,33.77 294.13,39.93 292.54,41.52 292.54,49.46 291.76,50.24 289.15,50.24 287.84,51.55 287.84,55.23 287.44,55.64 285.41,55.64 285.28,55.76 285.24,55.76 285.24,57.02 284.16,58.1 284.16,60.83 283.83,61.16 281.57,61.16 281.24,60.83 281.24,58.7 281.62,58.31 281.62,57.3 283.46,55.46 283.46,54.61 283.28,54.43 281.99,54.43 281.42,55 280.15,55 279.33,55.82 279.33,56.76 278.7,57.39 278.7,60.8 279.75,61.86 294.02,61.86 295.08,60.8 295.08,44.86 299.36,40.59 305.27,40.59 305.98,40.43 306.69,40.59 314.7,40.59 315,40.06 315.46,39.67 305.35,39.67 303.8,38.63 304.18,36.81 304.18,32.39 303.8,30.57 305.35,29.53 317.08,29.53 317.08,28.71
VCC_1.05VALWP on TOP (solid shape): 230.41,133.95 230.41,131.96 230.56,131.81 231.24,131.81 231.33,131.72 231.33,131.18 231.2,131.05 230.44,131.05 230.25,131.24 229.83,131.24 229.72,131.35 229.72,133.99 229.75,134.02 230.34,134.02
VCCHDA on TOP (solid shape): 193.74,97.78 193.74,96.69 193.71,96.67 193.05,96.67 192.97,96.75 192.97,96.95 192.77,97.16 192.33,97.16 192.25,97.07 192.25,97.07 192.2,97.02 192.2,96.75 192.07,96.61 191.69,96.61 191.57,96.73 191.57,97.47 191.95,97.86 193.66,97.86
VCCHDA on IN1: 171.54,97.2 171.61,97.17 171.94,97.31 172.26,97.17 172.59,97.31 172.91,97.17 173.24,97.31 173.56,97.17 173.89,97.31 174.21,97.17 174.28,97.2 174.4,97.28 174.54,97.31 174.79,97.2 174.89,96.95 177.39,96.95 177.39,98.23 177.37,98.27 177.34,98.28 176.68,98.28 175.51,99.45 171.7,99.45 171.02,98.78 171.02,97.31 171.13,97.2
VCCPLL_EN on TOP: 171.82,63.95 171.67,64.1 171.67,64.66 171.77,64.76 172.43,64.76 172.61,64.94 172.61,66.75 172.71,66.85 173.38,66.85 173.51,66.72 173.51,64.14 173.32,63.95
VDDP_CHG on BOTTOM (solid shape): 87.71,44.42 87.92,44.42 88.01,44.33 88.01,42.75 87.94,42.68 87.05,42.68 87.05,43.44 87.19,43.59 87.19,43.94 87.2,43.94 87.2,44.42 86.66,44.96 86,44.96 85.95,45.01 85.95,45.13 86,45.18 86.94,45.18
VIN_1.2V_RUN on TOP: 280.26,97.12 282.6,97.12 282.75,96.97 282.75,96.71 282.21,96.18 282.21,94.37 282.13,94.29 281.65,94.29 280.77,95.17 279.91,95.17 279.87,95.21 279.87,95.45 279.9,95.48 280.43,95.48 280.44,95.49 280.44,95.93 280.43,95.94 279.89,95.94 279.88,95.95 279.88,96.74
VIN_1.8VALW on BOTTOM (solid shape): 205.35,114.82 205.35,113.51 205.85,113.01 205.85,111.89 205.79,111.83 205.13,111.83 205.05,111.91 205.05,112.52 204.53,113.04 203.51,113.04 203.32,113.23 203.32,114.95 203.58,115.2 204.97,115.2
VIN_1V_PRIM_CORE on TOP (solid shape): 215.45,132.23 215.45,130.84 215.37,130.76 211.96,130.76 211.64,130.44 210.05,130.44 209.99,130.5 209.99,131.71 210.62,132.34 215.34,132.34
VIN_1V_PRIM_CORE on BOTTOM (solid shape): 213.79,132.34 213.79,131.08 213.67,130.96 210.39,130.96 209.63,131.72 209.63,132.36 209.74,132.46 213.67,132.46
VIN_1VS_VCCIO on TOP: 98.99,74.75 102.04,74.75 102.4,75.11 102.4,78.03 102.55,78.18 102.93,78.18 103.31,77.8 103.31,76.15 103.69,75.77 104.53,75.77 104.62,75.68 104.62,74.28 104.33,73.99 98.99,73.99 98.86,74.11 98.86,74.62
VIN_2.5V_MEM on TOP (solid shape): 242.24,62.7 242.24,60.67 242.2,60.63 241.74,60.63 241.53,60.84 241.53,61.11 241.43,61.21 239.31,61.21 239.2,61.32 239.2,62.5 239.52,62.81 242.13,62.81
+BL_PWR_SRC on TOP (solid shape): 135.78,133.56 135.78,132.51 135.76,132.41 135.78,132.31 135.78,131.89 135.99,131.68 137.32,131.68 138.01,131 138.01,129.96 137.97,129.92 137.31,129.92 137.28,129.94 137.28,130.91 137.13,131.06 136.46,131.06 136.41,131.01 134.92,131.01 134.83,131.1 132.77,131.1 132.69,131.18 132.69,131.67 133.66,132.65 133.66,133.55 133.79,133.68 135.66,133.68
+BL_PWR_SRC on BOTTOM (solid shape): 135.58,133.54 135.58,132.23 134.94,131.59 134.94,130.41 134.86,130.33 133.69,130.33 133.61,130.41 133.61,133.5 133.82,133.7 135.42,133.7
+BL_PWR_SRC_P on TOP (solid shape): 134.94,136.68 134.94,136.04 135.72,135.26 135.72,134.53 135.5,134.31 134,134.31 133.38,133.69 133.38,132.91 133.19,132.72 132,132.72 131.82,132.9 131.82,136.52 132.05,136.75 134.88,136.75
+DDR_VREF_B_CA on TOP (solid shape): 221.13,42.52 221.76,42.52 221.83,42.45 221.83,42.17 221.34,41.69 221.34,40.98 221.27,40.9 220.54,40.9 220.48,40.97 220.48,41.41 219.91,41.98 218.11,41.98 218.02,42.07 218.02,42.36 218.62,42.36 218.7,42.44 219.43,42.44 219.57,42.58 221.06,42.58
+EDP_VDD on TOP (solid shape): 151.05,136.09 151.05,135.46 150.92,135.33 149.54,135.33 149.28,135.07 149.28,132.8 149.13,132.65 147.88,132.65 147.74,132.79 147.74,136.07 147.91,136.24 150.9,136.24
+LCDVDD on TOP (solid shape): 147.61,135.79 147.61,133.77 147.05,133.77 147.05,133.28 147.61,133.28 147.61,132.62 147.46,132.47 145.58,132.47 145.03,131.93 143.59,131.93 142.76,131.09 140.68,131.09 140.59,131.17 140.59,131.65 140.36,131.89 140.36,132.21 140.51,132.36 141.01,132.36 141.61,132.95 141.61,133.1 142.58,134.07 142.58,134.76 142.76,134.93 145.47,134.93 145.47,135.6 145.79,135.91 147.48,135.91
+LCDVDD on BOTTOM (solid shape): 141.54,132.34 141.54,132.03 141.41,131.9 141.11,131.9 140.92,131.71 140.92,130.36 140.88,130.32 140.15,130.32 140.12,130.36 140.12,132.39 140.18,132.45 141.44,132.45
+MIC2-VREFO on TOP (solid shape): 287.07,57.39 287.07,57.07 286.69,56.69 286.69,55.73 286.6,55.64 286.5,55.64 286.44,55.71 286.44,55.89 286.44,55.9 286.44,57.18 286.7,57.44 287.01,57.44
+PECI_VREF on BOTTOM: 252.83,102.29 253.07,102.05 253.09,101.96 253.04,101.89 252.95,101.31 253.52,101.44 253.54,101.47 253.62,101.47 253.62,101.31 253.74,101.19 253.76,101.07 253.66,101.01 253.3,100.59 253.79,100.33 253.88,100.32 253.93,100.24 253.93,99.63 253.86,99.57 253.18,99.57 251.07,101.67 251.07,102.36 251.09,102.38 251.71,102.38 251.8,102.29
+REGCTL_PNP10 on TOP (solid shape): 272.19,105 272.19,103.08 272.67,102.59 273.25,102.59 273.27,102.56 273.27,101.97 273.25,101.95 271.81,101.95 271.8,101.95 271.8,103.86 271.93,103.99 271.93,104.98 272.01,105.06 272.12,105.06
+RTC_CELL_PCH on TOP: 241.62,119.71 244.92,119.71 245.89,120.68 247.76,120.68 247.82,120.62 247.82,119.48 247.66,119.33 246.59,119.33 246.18,118.91 245.05,118.91 244.83,119.13 242.2,119.13 242.17,119.1 241.61,119.1 241.57,119.14 241.57,119.66
+RTC_CELL_PCH on TOP: 171.55,96.47 171.55,96.04 171.11,95.61 170.49,95.61 170.26,95.84 170.26,96.92 170.29,96.95 171,96.95 171,96.7 171.13,96.57 171.44,96.57
+RTC_CELL_PCH on IN2: 170.94,96.66 181.41,96.66 182.18,95.9 182.18,88.72 181.54,88.08 178.94,88.08 174.62,92.4 174.62,93.36 172.52,95.45 170.94,95.45 170.75,95.64 170.75,96.47
+SDREG2 on TOP (solid shape): 294.41,26.5 294.41,26.06 294.25,25.9 293.75,25.9 293.49,25.64 293.49,25.12 293.05,24.67 292.27,24.67 292.21,24.74 292.21,24.83 292.27,24.89 292.72,24.89 293.05,25.22 293.05,26.15 293.51,26.62 294.29,26.62
+TS_PWR_QV8 on TOP (solid shape): 122.97,134.4 122.97,133.51 122.72,133.26 122.72,130.19 122.51,129.98 121.44,129.98 121.22,130.2 121.22,134.4 121.42,134.61 122.77,134.61
+TS_PWR_SRC on TOP (solid shape): 124.82,132.57 124.82,132.1 124.67,131.96 124.67,129.9 124.6,129.83 123.12,129.83 122.97,129.99 122.97,131.6 123.14,131.78 123.53,131.78 123.9,132.15 123.91,132.16 124.03,132.24 124.11,132.36 124.12,132.37 124.14,132.39 124.14,132.53 124.35,132.74 124.64,132.74
+USB_EX2_PWR on BOTTOM (solid shape): 20.25,86.43 21.33,86.43 21.58,86.18 21.58,85.42 21.19,85.04 18.6,85.04 18.47,85.16 18.47,86.81 18.6,86.94 19.74,86.94
+USB_EX2_PWR on BOTTOM (solid shape): 20.76,97.23 21.04,97.23 21.22,97.04 21.22,95.73 21.39,95.56 21.94,95.56 22.04,95.46 22.04,95.06 21.93,94.96 19,94.96 18.73,94.69 18.27,94.69 17.24,93.65 15.83,93.65 15.55,93.93 15.55,94.57 18.21,97.23 20.76,97.23
+USB_EX2_PWR on IN1: 17.84,85.8 17.22,86.42 17.22,96.33 17.36,96.47 19.24,96.47 20.12,95.58 20.12,86.05 19.87,85.8
+USB_EX3_PWR on TOP (solid shape): 298.76,54.11 298.76,53.48 299.33,52.91 299.33,52.4 299.84,51.89 301.3,51.89 301.94,51.25 301.94,47.64 302.38,47.19 303.08,47.19 303.53,46.75 303.53,45.35 303.14,44.97 299.33,44.97 299.14,45.16 299.14,49.48 299.02,49.6 298.25,49.6 298.18,49.68 298.18,50.31 297.3,51.19 297.3,54.11 297.49,54.3 298.57,54.3
+USB_EX3_PWR on BOTTOM (solid shape): 301.01,46.8 302.34,46.8 302.43,46.71 302.87,46.71 303.56,46.02 303.56,45.48 302.88,44.79 300.82,44.79 300.57,44.54 298.86,44.54 298.64,44.77 298.64,47.06 298.96,47.39 300.42,47.39
+UZ12_TPM on TOP (solid shape): 228.21,104.89 228.21,102.05 228.1,101.94 227.16,101.94 227.03,102.08 227.03,103.97 226.63,104.37 225.6,104.37 225.54,104.44 225.54,104.96 225.58,105 228.1,105
+VHDMI_VCC on BOTTOM: 303.27,82.17 303.98,82.17 304.06,82.09 304.06,81.81 304.21,81.66 304.21,80.6 304.14,80.53 300.91,80.53 300.72,80.72 300.72,81.5 301,81.78 302.97,81.78 303.19,82 303.19,82.1
+VHDMI_VCC on IN1: 306.23,80.45 303,80.45 302.82,80.63 302.82,81.59 302.86,81.63 306.34,81.63 306.41,81.56 306.41,80.64
ADP_CHG on BOTTOM (solid shape): 83.06,44.8 83.06,44.04 82.9,43.89 81.28,43.89 81.15,44.02 81.15,44.33 81.28,44.46 82.46,44.46 82.85,44.85 83,44.85
BGATE_CHG on TOP (solid shape): 130.55,37.6 130.55,35.89 130.49,35.82 129.98,35.82 129.95,35.85 129.95,37.04 129.85,37.14 129.85,37.6 129.98,37.73 130.42,37.73
BOOT1_CHG on BOTTOM (solid shape): 84.66,44.8 84.66,43.76 84.47,43.57 84.47,42.66 84.66,42.47 85.1,42.47 85.23,42.34 85.23,41.64 84.34,41.64 84.08,41.9 84.08,43.65 84.43,43.99 84.43,44.8 84.48,44.85 84.6,44.85
BOOT2_CHG on BOTTOM (solid shape): 88.85,46.4 88.21,46.4 88.21,46.71 88.08,46.84 87.65,46.84 87.5,46.68 87.12,46.68 86.99,46.56 86,46.56 85.95,46.61 85.95,46.73 85.98,46.76 86.92,46.76 87.45,47.29 88.85,47.29
BS_DDR on BOTTOM (solid shape): 90.36,64.53 90.36,64.21 89.02,62.88 87.05,62.88 87.05,63.76 88.83,63.76 89.66,64.59 90.29,64.59
BS_DDR_R on BOTTOM (solid shape): 86.3,62.85 86.42,62.73 86.42,61.93 86.35,61.86 85.62,61.86 85.53,61.95 85.53,63.7 85.59,63.76 86.3,63.76
BST1_CHG_R on BOTTOM: 84.39,41.33 86.32,41.33 86.36,41.3 86.36,40.48 86.05,40.18 84.34,40.18 84.28,40.23 84.28,41.22
BST1_IA on BOTTOM (solid shape): 116.08,99.58 116.08,98.56 115.83,98.31 115.83,97.55 115.76,97.49 114.87,97.49 114.81,97.55 114.81,98.18 114.94,98.31 115.19,98.31 115.76,98.88 115.76,99.58 115.83,99.64 116.02,99.64
BST2_CHG_R on BOTTOM (solid shape): 90.24,47.11 90.24,45.13 90.24,45.13 89.61,45.13 89.61,45.13 89.61,46.37 89.46,46.53 89.21,46.53 89.15,46.58 89.15,47.15 89.29,47.29 90.06,47.29
BST2_IA on BOTTOM (solid shape): 102.1,104.53 102.1,103.52 101.85,103.26 101.85,102.5 101.79,102.44 100.9,102.44 100.83,102.5 100.83,103.13 100.96,103.26 101.21,103.26 101.79,103.83 101.79,104.53 101.85,104.59 102.04,104.59
BST_1.05VALWP on TOP (solid shape): 231.65,129.53 231.65,128.28 231.71,128.22 231.71,127.52 230.82,127.52 230.82,128.15 231.2,128.53 231.2,129.46 231.35,129.61 231.56,129.61
BST_3V on BOTTOM (solid shape): 205.23,32.97 205.23,30.87 205.16,30.81 204.27,30.81 204.27,31.51 204.91,32.14 204.91,32.97 204.97,33.03 205.16,33.03
BST_5V on BOTTOM: 81.75,74.24 82.58,74.24 82.58,72.73 80.49,72.73 80.41,72.8 80.41,72.91
BST_5V_R on BOTTOM (solid shape): 85.34,73.67 84.89,73.23 83.36,73.23 83.36,74.24 85.34,74.24
BST_GT on BOTTOM (solid shape): 103.12,89.28 103.12,89.03 103.7,88.46 104.39,88.46 104.46,88.39 104.46,88.2 104.39,88.14 103.38,88.14 103.12,88.39 102.36,88.39 102.3,88.46 102.3,89.35 102.36,89.41 103,89.41
BST_SA on TOP (solid shape): 182.3,131.52 182.3,130.44 181.73,129.87 180.2,129.87 179.92,130.15 179.92,130.92 179.95,130.95 180.55,130.95 180.61,130.9 180.61,130.57 180.67,130.5 181.67,130.5 181.99,130.82 181.99,131.52 182.05,131.58 182.24,131.58
EN_1.2V_RUN on TOP: 278.82,99.2 282.58,99.2 282.74,99.04 282.74,98.71 282.61,98.59 278.84,98.59 278.74,98.68 278.74,99.13
INT_SPK_L+ on TOP (solid shape): 290.89,38.43 290.89,37.6 290.76,37.48 289.94,37.48 289.75,37.67 289.75,38.34 289.97,38.57 289.97,38.62 290.7,38.62
